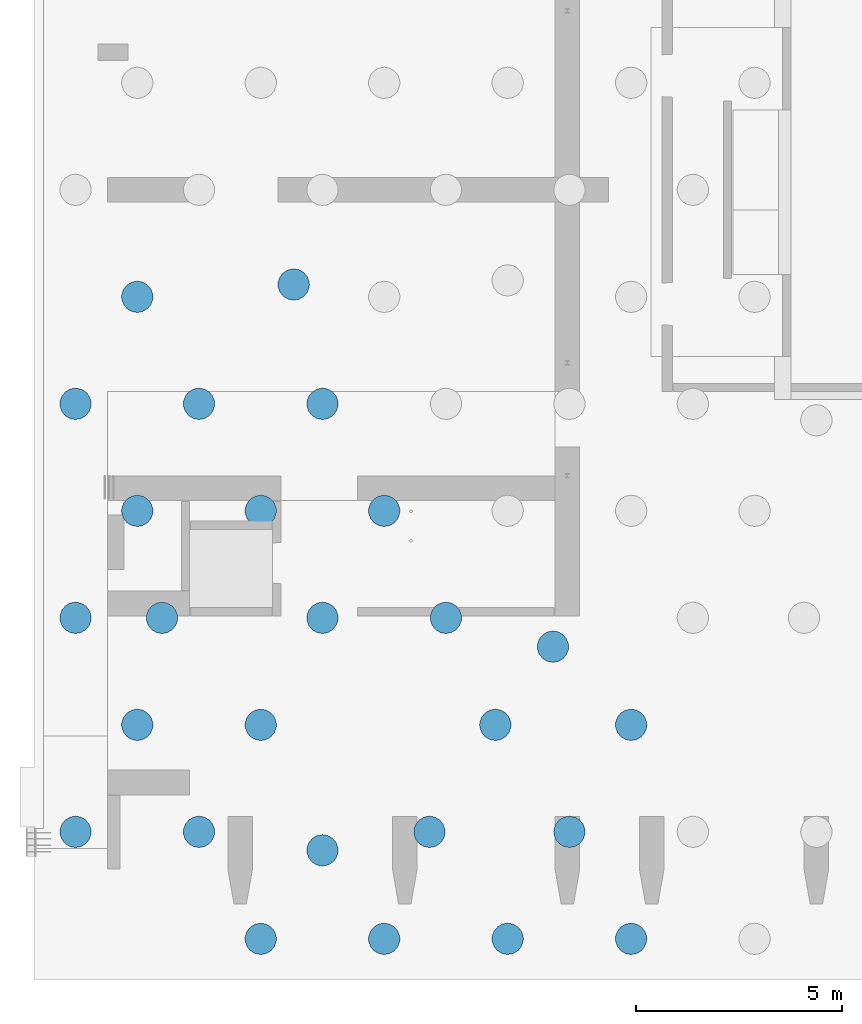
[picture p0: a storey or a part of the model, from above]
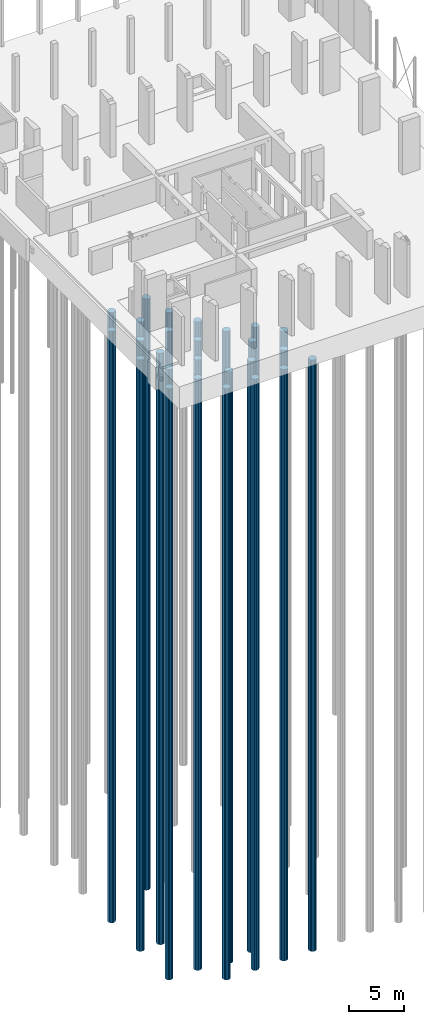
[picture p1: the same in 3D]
Properties of the parts of a building model (IFC2X3), part 1 of 21

# File
Description: ViewDefinition [CoordinationView_V2.0]
Time: 2021-03-30T19:09:52
Written by: The EXPRESS Data Manager Version 5.02.0100.07 : 28 Aug 2013
Made in: 20190510_1515(x64) - Exporter 18.3.3.18 - Alternate UI 18.3.3.18
Comment: STEP Physical File produced by: The EXPRESS Data Manager Version 5.02.0100.07 : 28 Aug 2013 * Module: EDMstepFileFactory/EDMstandAlone * Creation date: Tue Mar 30 19:09:52 2021 * Host: NL5CD93789YK * Database: C:\Users\Kees-D\AppData\Local\Temp\{8EC94533-717D-41E1-8668-EB877A94D281}\ifc * Database version: 5507 * Database creation date: Tue Mar 30 19:07:52 2021 * Schema: IFC2X3 * Model: DataRepository.ifc * Model creation date: Tue Mar 30 19:07:52 2021 * Header model: DataRepository.ifc_HeaderModel * Header model creation date: Tue Mar 30 19:07:52 2021 * EDMuser: sdai-user * EDMgroup: sdai-group * License ID and type: 5605 : Permanent license. Expiry date: * EDMstepFileFactory options: 020000

# IfcProject
LongName: De Zalmhaven Rotterdam; Phase: voorlopig

# IfcSite, Default
RefLatitude: 52, 3, 52, 759094; RefLongitude: 5, 11, 35, 688629; RefElevation: 0 mm

# IfcBuilding, niet gebruiken
LongName: niet gebruiken
Pset_BuildingCommon - NumberOfStoreys: 64

# IfcBuildingStorey (64)
In: niet gebruiken
Name | LongName | Elevation (mm)
00 begane grond | 00 begane grond | 0
00a eerste tussenverdieping | 00a eerste tussenverdieping | 3000
01 eerste verdieping | 01 eerste verdieping | 6000
02 tweede verdieping | 02 tweede verdieping | 9000
03 derde verdieping | 03 derde verdieping | 12000
04 vierde verdieping | 04 vierde verdieping | 15000
05 vijfde verdieping | 05 vijfde verdieping | 18000
06 zesde verdieping | 06 zesde verdieping | 21060
07 zevende verdieping | 07 zevende verdieping | 24120
08 achtste verdieping | 08 achtste verdieping | 27180
09 negende verdieping | 09 negende verdieping | 30240
10 tiende verdieping | 10 tiende verdieping | 33300
11 elfde verdieping | 11 elfde verdieping | 36360
12 twaalfde verdieping | 12 twaalfde verdieping | 39420
13 dertiende verdieping | 13 dertiende verdieping | 42480
14 veertiende verdieping | 14 veertiende verdieping | 45540
15 vijftiende verdieping | 15 vijftiende verdieping | 48600
16 zestiende verdieping | 16 zestiende verdieping | 51660
17 zeventiende verdieping | 17 zeventiende verdieping | 54720
18 achttiende verdieping | 18 achttiende verdieping | 57780
19 negentiende verdieping | 19 negentiende verdieping | 60840
20 twintigste verdieping | 20 twintigste verdieping | 63900
21 eenentwintigste verdieping | 21 eenentwintigste verdieping | 66960
22 tweeëntwintigste verdieping | 22 tweeëntwintigste verdieping | 70020
23 drieëntwintigste verdieping | 23 drieëntwintigste verdieping | 73080
24 vierentwintigste verdieping | 24 vierentwintigste verdieping | 76140
25 vijfentwintigste verdieping | 25 vijfentwintigste verdieping | 79200
26 zesentwintigste verdieping | 26 zesentwintigste verdieping | 82260
27 zevenentwintigste verdieping | 27 zevenentwintigste verdieping | 85320
28 achtentwintigste verdieping | 28 achtentwintigste verdieping | 88380
29 negenentwintigste verdieping | 29 negenentwintigste verdieping | 91440
30 dertigste verdieping | 30 dertigste verdieping | 94500
31 eenendertigste verdieping | 31 eenendertigste verdieping | 97560
32 tweeëndertigste verdieping | 32 tweeëndertigste verdieping | 100620
33 drieëndertigste verdieping | 33 drieëndertigste verdieping | 103680
34 vierendertigste verdieping | 34 vierendertigste verdieping | 106740
35 vijfendertigste verdieping | 35 vijfendertigste verdieping | 109800
36 zesendertigste verdieping | 36 zesendertigste verdieping | 112860
37 zevenendertigste verdieping | 37 zevenendertigste verdieping | 115920
38 achtendertigste verdieping | 38 achtendertigste verdieping | 118980
39 negenendertigste verdieping | 39 negenendertigste verdieping | 122040
40 veertigste verdieping | 40 veertigste verdieping | 125100
41 eenenveertigste verdieping | 41 eenenveertigste verdieping | 128160
42 tweeënveertigste verdieping | 42 tweeënveertigste verdieping | 131220
43 drieënveertigste verdieping | 43 drieënveertigste verdieping | 134280
44 vierenveertigste verdieping | 44 vierenveertigste verdieping | 137340
45 vijfenveertigste verdieping | 45 vijfenveertigste verdieping | 140400
46 zesenveertigste verdieping | 46 zesenveertigste verdieping | 143460
47 zevenenveertigste verdieping | 47 zevenenveertigste verdieping | 146520
48 achtenveertigste verdieping | 48 achtenveertigste verdieping | 149580
49 negenenveertigste verdieping | 49 negenenveertigste verdieping | 152640
50 vijftigste verdieping | 50 vijftigste verdieping | 155700
51 eenenvijftigste verdieping | 51 eenenvijftigste verdieping | 158760
52 tweeënvijftigste verdieping | 52 tweeënvijftigste verdieping | 161820
53 drieënvijftigste verdieping | 53 drieënvijftigste verdieping | 165060
54 vierenvijftigste verdieping | 54 vierenvijftigste verdieping | 168300
55 vijfenvijftigste verdieping | 55 vijfenvijftigste verdieping | 171740
56 zesenvijftigste verdieping | 56 zesenvijftigste verdieping | 175180
57 zevenenvijftigste verdieping | 57 zevenenvijftigste verdieping | 178840
58 achtenvijftigste verdieping | 58 achtenvijftigste verdieping | 183150
59 negenenvijftigste verdieping | 59 negenenvijftigste verdieping | 187640
60 zestigste verdieping | 60 zestigste verdieping | 191440
61 eenenzestigste verdieping | 61 eenenzestigste verdieping | 197055
62 tweeënzestigste verdieping | 62 tweeënzestigste verdieping | 202670

# IfcBeam: 300x370, NLRS_28.11_SF_WPB_prefabbeton balk recht_gen:300x370:4941858
In: 05 vijfde verdieping
Type - ElementType: 300x370; PredefinedType: BEAM; Classification: 28.11 hoofddraagconstructies - kolommen en liggers, kolom-/liggerconstructies (Uniformat); Material: NLRS_f2_beton prefab
Pset_BeamCommon - IsExternal: yes; LoadBearing: yes; Slope: 0 deg; Reference: 300x370; Span: 950 mm

# IfcBeam: 500x500 (2)
In: 00a eerste tussenverdieping
Type - ElementType: 500x500; PredefinedType: BEAM; Classification: 28.11 hoofddraagconstructies - kolommen en liggers, kolom-/liggerconstructies (Uniformat); Material: NLRS_f2_beton ihwg
Pset_BeamCommon - IsExternal: yes; LoadBearing: yes; Reference: 500x500; Slope: 0 deg
Name (NLRS_28.11_SF_WPB_betonbalk ihwg recht_gen:500x500:...) | Span (mm)
4226276 | 6950
4226539 | 7550

# IfcBeam: 500x600 (9)
Type - ElementType: 500x600; PredefinedType: BEAM; Classification: 28.11 hoofddraagconstructies - kolommen en liggers, kolom-/liggerconstructies (Uniformat); Material: NLRS_f2_beton ihwg
Pset_BeamCommon - IsExternal: yes; LoadBearing: yes; Slope: 0 deg; Reference: 500x600
Name (NLRS_28.11_SF_WPB_betonbalk ihwg recht_gen:500x600:...) | In | Span (mm)
4386469 | 01 eerste verdieping | 27400
4386866 | 01 eerste verdieping | 29950
4389192 | 01 eerste verdieping | 24000
4392467 | 01 eerste verdieping | 14500
4417707 | 02 tweede verdieping | 30236
4417842 | 02 tweede verdieping | 30500
4418229 | 02 tweede verdieping | 14500
4448747 | 03 derde verdieping | 30486
4448751 | 03 derde verdieping | 14500

# IfcBeam: NLRS_28.11_SF_WPB_betonbalk ihwg recht_gen:600x420, NLRS_28.11_SF_WPB_betonbalk ihwg recht_gen:600x420:9468926
In: 01 eerste verdieping
Type - PredefinedType: BEAM
Classification: 28.11 hoofddraagconstructies - kolommen en liggers, kolom-/liggerconstructies (Uniformat); Material: NLRS_f2_beton ihwg
Pset_BeamCommon - IsExternal: yes; LoadBearing: yes; Slope: 0 deg; Reference: 600x420; Span: 3750 mm

# IfcBeam: NLRS_28.11_SF_WPB_betonbalk ihwg recht_gen:600x750 (2)
In: 01 eerste verdieping
Type - PredefinedType: BEAM
Classification: 28.11 hoofddraagconstructies - kolommen en liggers, kolom-/liggerconstructies (Uniformat); Material: NLRS_f2_beton ihwg
Pset_BeamCommon - IsExternal: yes; LoadBearing: yes; Slope: 0 deg; Reference: 600x750
Name (NLRS_28.11_SF_WPB_betonbalk ihwg recht_gen:600x750:...) | Span (mm)
4388665 | 8166
6301186 | 4880

# IfcBeam: NLRS_28.11_SF_WPB_oplegnok ihwg beton_gen:200x347.5, NLRS_28.11_SF_WPB_oplegnok ihwg beton_gen:200x347.5:6400414
In: 01 eerste verdieping
Type - PredefinedType: BEAM
Classification: 28.11 hoofddraagconstructies - kolommen en liggers, kolom-/liggerconstructies (Uniformat); Material: NLRS_f2_beton ihwg
Pset_BeamCommon - IsExternal: yes; LoadBearing: yes; Slope: 0 deg; Reference: 200x347.5; Span: 400 mm

# IfcBeam: NLRS_28.11_SF_WPB_oplegnok ihwg beton_gen:250x310 (2)
Type - PredefinedType: BEAM
Classification: 28.11 hoofddraagconstructies - kolommen en liggers, kolom-/liggerconstructies (Uniformat); Material: NLRS_f2_beton ihwg
Pset_BeamCommon - IsExternal: yes; LoadBearing: yes; Slope: 0 deg; Reference: 250x310; Span: 400 mm
Name (NLRS_28.11_SF_WPB_oplegnok ihwg beton_gen:250x310:...) | In
6006708 | 01 eerste verdieping
7215375 | 02 tweede verdieping

# IfcBeam: NLRS_28.11_SF_WPB_oplegnok ihwg beton_gen:350x600, NLRS_28.11_SF_WPB_oplegnok ihwg beton_gen:350x600:7215432
In: 02 tweede verdieping
Type - PredefinedType: BEAM
Classification: 28.11 hoofddraagconstructies - kolommen en liggers, kolom-/liggerconstructies (Uniformat); Material: NLRS_f2_beton ihwg
Pset_BeamCommon - IsExternal: yes; LoadBearing: yes; Slope: 0 deg; Reference: 350x600; Span: 400 mm

# IfcBeam: NLRS_28.11_SF_WPB_oplegnok prefabbeton_gen:200x250 slope (5)
Type - PredefinedType: BEAM
Classification: 28.11 hoofddraagconstructies - kolommen en liggers, kolom-/liggerconstructies (Uniformat); Material: NLRS_f2_beton prefab
Pset_BeamCommon - IsExternal: yes; LoadBearing: yes; Slope: 0 deg; Reference: 200x250 slope
Name (NLRS_28.11_SF_WPB_oplegnok prefabbeton_gen:200x250 slope:...) | In | Span (mm)
6399559 | 01 eerste verdieping | 1860
6400008 | 02 tweede verdieping | 1860
6400059 | 01 eerste verdieping | 2010
6400132 | 02 tweede verdieping | 2010
10888795 | 03 derde verdieping | 1860

# IfcBeam: NLRS_28.11_SF_WPB_oplegnok prefabbeton_gen:300x310 met afschuining 7,6gr (3)
Type - PredefinedType: BEAM
Classification: 28.11 hoofddraagconstructies - kolommen en liggers, kolom-/liggerconstructies (Uniformat); Material: NLRS_f2_beton prefab
Pset_BeamCommon - LoadBearing: yes; IsExternal: no; Slope: 0 deg; Reference: 300x310 met afschuining 7,6gr
Name (NLRS_28.11_SF_WPB_oplegnok prefabbeton_gen:300x310 met afschuining 7,6gr:...) | In | Span (mm)
7300567 | 01 eerste verdieping | 700
7301827 | 02 tweede verdieping | 590
7302072 | 03 derde verdieping | 300

# IfcBeam: NLRS_28.11_SF_WPB_oplegnok prefabbeton_gen:300x480 met afschuining 9gr, NLRS_28.11_SF_WPB_oplegnok prefabbeton_gen:300x480 met afschuining 9gr:7300622
In: 01 eerste verdieping
Type - PredefinedType: BEAM
Classification: 28.11 hoofddraagconstructies - kolommen en liggers, kolom-/liggerconstructies (Uniformat); Material: NLRS_f2_beton prefab
Pset_BeamCommon - LoadBearing: yes; IsExternal: no; Slope: 0 deg; Reference: 300x480 met afschuining 9gr; Span: 575 mm

# IfcBeam: NLRS_28.11_SF_WPB_stalen handje 7 lang 375_gen:NLRS_28.11_SF_WPB_stalen handje 7_gen (760)
Type - PredefinedType: BEAM
Material: NLRS_h2_staal
Pset_BeamCommon - LoadBearing: yes; IsExternal: no; Slope: 0 deg; Reference: NLRS_28.11_SF_WPB_stalen handje 7_gen
Name (NLRS_28.11_SF_WPB_stalen handje 7 lang 375_gen:NLRS_28.11_SF_WPB_stalen handje 7_gen:...) | In | Span (mm) | Group
13999907 | 52 tweeënvijftigste verdieping | 375 | Model Group:NLRS_28.11_SF_handjes balkon 1-2_52e verd_gen:13768620
13999953 | 52 tweeënvijftigste verdieping | 375 | Model Group:NLRS_28.11_SF_handjes balkon 1-2_52e verd_gen:13768620
14005422 | 52 tweeënvijftigste verdieping | 500 | Model Group:NLRS_28.11_SF_handjes balkon 1-2_52e verd_gen:13768620
14005482 | 52 tweeënvijftigste verdieping | 500 | Model Group:NLRS_28.11_SF_handjes balkon 1-2_52e verd_gen:13768620
14005974 | 52 tweeënvijftigste verdieping | 375 | Model Group:NLRS_28.11_SF_handjes balkon 3-4_52e verd_gen:13769752
14005976 | 52 tweeënvijftigste verdieping | 375 | Model Group:NLRS_28.11_SF_handjes balkon 3-4_52e verd_gen:13769752
14005978 | 52 tweeënvijftigste verdieping | 500 | Model Group:NLRS_28.11_SF_handjes balkon 3-4_52e verd_gen:13769752
14005980 | 52 tweeënvijftigste verdieping | 500 | Model Group:NLRS_28.11_SF_handjes balkon 3-4_52e verd_gen:13769752
14006319 | 52 tweeënvijftigste verdieping | 375 | Model Group:NLRS_28.11_SF_handjes balkon 3-4_52e verd_gen:13770119
14006321 | 52 tweeënvijftigste verdieping | 375 | Model Group:NLRS_28.11_SF_handjes balkon 3-4_52e verd_gen:13770119
14006323 | 52 tweeënvijftigste verdieping | 500 | Model Group:NLRS_28.11_SF_handjes balkon 3-4_52e verd_gen:13770119
14006325 | 52 tweeënvijftigste verdieping | 500 | Model Group:NLRS_28.11_SF_handjes balkon 3-4_52e verd_gen:13770119
14006685 | 53 drieënvijftigste verdieping | 500 | Model Group:NLRS_28.11_SF_handjes balkon 1-2_53e verd_gen:13907235
14006687 | 53 drieënvijftigste verdieping | 500 | Model Group:NLRS_28.11_SF_handjes balkon 1-2_53e verd_gen:13907235
14006797 | 53 drieënvijftigste verdieping | 500 | Model Group:NLRS_28.11_SF_handjes balkon 1-2_53e verd_gen:13907244
14006799 | 53 drieënvijftigste verdieping | 500 | Model Group:NLRS_28.11_SF_handjes balkon 1-2_53e verd_gen:13907244
14006859 | 53 drieënvijftigste verdieping | 500 | Model Group:NLRS_28.11_SF_handjes balkon 3-4_53e verd_gen:13907254
14006861 | 53 drieënvijftigste verdieping | 500 | Model Group:NLRS_28.11_SF_handjes balkon 3-4_53e verd_gen:13907254
14007250 | 52 tweeënvijftigste verdieping | 375 | Model Group:NLRS_28.11_SF_handjes balkon 1-2_52e verd_gen:13769974
14007252 | 52 tweeënvijftigste verdieping | 375 | Model Group:NLRS_28.11_SF_handjes balkon 1-2_52e verd_gen:13769974
14007254 | 52 tweeënvijftigste verdieping | 500 | Model Group:NLRS_28.11_SF_handjes balkon 1-2_52e verd_gen:13769974
14007256 | 52 tweeënvijftigste verdieping | 500 | Model Group:NLRS_28.11_SF_handjes balkon 1-2_52e verd_gen:13769974
14008008 | 53 drieënvijftigste verdieping | 500 | Model Group:NLRS_28.11_SF_handjes balkon 3-4_53e verd_gen:13907245
14008010 | 53 drieënvijftigste verdieping | 500 | Model Group:NLRS_28.11_SF_handjes balkon 3-4_53e verd_gen:13907245
14026828 | 20 twintigste verdieping | 500 | Model Group:NLRS_28.11_SF_handjes balkon 3-4_gen:10620918
14026830 | 20 twintigste verdieping | 500 | Model Group:NLRS_28.11_SF_handjes balkon 3-4_gen:10620918
14026832 | 20 twintigste verdieping | 375 | Model Group:NLRS_28.11_SF_handjes balkon 1-2_gen:10620925
14026834 | 20 twintigste verdieping | 375 | Model Group:NLRS_28.11_SF_handjes balkon 1-2_gen:10620925
14026836 | 20 twintigste verdieping | 500 | Model Group:NLRS_28.11_SF_handjes balkon 1-2_gen:10620925
14026838 | 20 twintigste verdieping | 500 | Model Group:NLRS_28.11_SF_handjes balkon 1-2_gen:10620925
14035047 | 16 zestiende verdieping | 500 | Model Group:NLRS_28.11_SF_handjes balkon 3-4_gen:9036916
14035049 | 16 zestiende verdieping | 500 | Model Group:NLRS_28.11_SF_handjes balkon 3-4_gen:9036916
14035052 | 16 zestiende verdieping | 500 | Model Group:NLRS_28.11_SF_handjes balkon 3-4_gen:9036917
14035054 | 16 zestiende verdieping | 500 | Model Group:NLRS_28.11_SF_handjes balkon 3-4_gen:9036917
14035057 | 15 vijftiende verdieping | 500 | Model Group:NLRS_28.11_SF_handjes balkon 3-4_gen:9050834
14035059 | 15 vijftiende verdieping | 500 | Model Group:NLRS_28.11_SF_handjes balkon 3-4_gen:9050834
14035062 | 15 vijftiende verdieping | 500 | Model Group:NLRS_28.11_SF_handjes balkon 3-4_gen:9050835
14035064 | 15 vijftiende verdieping | 500 | Model Group:NLRS_28.11_SF_handjes balkon 3-4_gen:9050835
14035067 | 17 zeventiende verdieping | 500 | Model Group:NLRS_28.11_SF_handjes balkon 3-4_gen:9051130
14035069 | 17 zeventiende verdieping | 500 | Model Group:NLRS_28.11_SF_handjes balkon 3-4_gen:9051130
14035072 | 17 zeventiende verdieping | 500 | Model Group:NLRS_28.11_SF_handjes balkon 3-4_gen:9051131
14035074 | 17 zeventiende verdieping | 500 | Model Group:NLRS_28.11_SF_handjes balkon 3-4_gen:9051131
14035077 | 18 achttiende verdieping | 500 | Model Group:NLRS_28.11_SF_handjes balkon 3-4_gen:9131781
14035079 | 18 achttiende verdieping | 500 | Model Group:NLRS_28.11_SF_handjes balkon 3-4_gen:9131781
14035082 | 18 achttiende verdieping | 500 | Model Group:NLRS_28.11_SF_handjes balkon 3-4_gen:9131782
14035084 | 18 achttiende verdieping | 500 | Model Group:NLRS_28.11_SF_handjes balkon 3-4_gen:9131782
14035087 | 10 tiende verdieping | 500 | Model Group:NLRS_28.11_SF_handjes balkon 3-4_gen:10618299
14035089 | 10 tiende verdieping | 500 | Model Group:NLRS_28.11_SF_handjes balkon 3-4_gen:10618299
14035092 | 10 tiende verdieping | 500 | Model Group:NLRS_28.11_SF_handjes balkon 3-4_gen:10618300
14035094 | 10 tiende verdieping | 500 | Model Group:NLRS_28.11_SF_handjes balkon 3-4_gen:10618300
14035097 | 12 twaalfde verdieping | 500 | Model Group:NLRS_28.11_SF_handjes balkon 3-4_gen:10620653
14035099 | 12 twaalfde verdieping | 500 | Model Group:NLRS_28.11_SF_handjes balkon 3-4_gen:10620653
14035102 | 12 twaalfde verdieping | 500 | Model Group:NLRS_28.11_SF_handjes balkon 3-4_gen:10620654
14035104 | 12 twaalfde verdieping | 500 | Model Group:NLRS_28.11_SF_handjes balkon 3-4_gen:10620654
14035107 | 14 veertiende verdieping | 500 | Model Group:NLRS_28.11_SF_handjes balkon 3-4_gen:10620785
14035109 | 14 veertiende verdieping | 500 | Model Group:NLRS_28.11_SF_handjes balkon 3-4_gen:10620785
14035112 | 14 veertiende verdieping | 500 | Model Group:NLRS_28.11_SF_handjes balkon 3-4_gen:10620786
14035114 | 14 veertiende verdieping | 500 | Model Group:NLRS_28.11_SF_handjes balkon 3-4_gen:10620786
14035117 | 20 twintigste verdieping | 500 | Model Group:NLRS_28.11_SF_handjes balkon 3-4_gen:10620917
14035119 | 20 twintigste verdieping | 500 | Model Group:NLRS_28.11_SF_handjes balkon 3-4_gen:10620917
14035122 | 11 elfde verdieping | 500 | Model Group:NLRS_28.11_SF_handjes balkon 3-4_gen:10622917
14035124 | 11 elfde verdieping | 500 | Model Group:NLRS_28.11_SF_handjes balkon 3-4_gen:10622917
14035127 | 11 elfde verdieping | 500 | Model Group:NLRS_28.11_SF_handjes balkon 3-4_gen:10622918
14035129 | 11 elfde verdieping | 500 | Model Group:NLRS_28.11_SF_handjes balkon 3-4_gen:10622918
14035132 | 13 dertiende verdieping | 500 | Model Group:NLRS_28.11_SF_handjes balkon 3-4_gen:10625084
14035134 | 13 dertiende verdieping | 500 | Model Group:NLRS_28.11_SF_handjes balkon 3-4_gen:10625084
14035137 | 13 dertiende verdieping | 500 | Model Group:NLRS_28.11_SF_handjes balkon 3-4_gen:10625085
14035139 | 13 dertiende verdieping | 500 | Model Group:NLRS_28.11_SF_handjes balkon 3-4_gen:10625085
14035142 | 19 negentiende verdieping | 500 | Model Group:NLRS_28.11_SF_handjes balkon 3-4_gen:10625216
14035144 | 19 negentiende verdieping | 500 | Model Group:NLRS_28.11_SF_handjes balkon 3-4_gen:10625216
14035147 | 19 negentiende verdieping | 500 | Model Group:NLRS_28.11_SF_handjes balkon 3-4_gen:10625217
14035149 | 19 negentiende verdieping | 500 | Model Group:NLRS_28.11_SF_handjes balkon 3-4_gen:10625217
14035839 | 16 zestiende verdieping | 375 | Model Group:NLRS_28.11_SF_handjes balkon 1-2_gen:9036911
14035841 | 16 zestiende verdieping | 375 | Model Group:NLRS_28.11_SF_handjes balkon 1-2_gen:9036911
14035843 | 16 zestiende verdieping | 500 | Model Group:NLRS_28.11_SF_handjes balkon 1-2_gen:9036911
14035845 | 16 zestiende verdieping | 500 | Model Group:NLRS_28.11_SF_handjes balkon 1-2_gen:9036911
14035848 | 16 zestiende verdieping | 375 | Model Group:NLRS_28.11_SF_handjes balkon 1-2_gen:9036924
14035850 | 16 zestiende verdieping | 375 | Model Group:NLRS_28.11_SF_handjes balkon 1-2_gen:9036924
14035852 | 16 zestiende verdieping | 500 | Model Group:NLRS_28.11_SF_handjes balkon 1-2_gen:9036924
14035854 | 16 zestiende verdieping | 500 | Model Group:NLRS_28.11_SF_handjes balkon 1-2_gen:9036924
14035857 | 15 vijftiende verdieping | 375 | Model Group:NLRS_28.11_SF_handjes balkon 1-2_gen:9050829
14035859 | 15 vijftiende verdieping | 375 | Model Group:NLRS_28.11_SF_handjes balkon 1-2_gen:9050829
14035861 | 15 vijftiende verdieping | 500 | Model Group:NLRS_28.11_SF_handjes balkon 1-2_gen:9050829
14035863 | 15 vijftiende verdieping | 500 | Model Group:NLRS_28.11_SF_handjes balkon 1-2_gen:9050829
14035866 | 15 vijftiende verdieping | 375 | Model Group:NLRS_28.11_SF_handjes balkon 1-2_gen:9050842
14035868 | 15 vijftiende verdieping | 375 | Model Group:NLRS_28.11_SF_handjes balkon 1-2_gen:9050842
14035870 | 15 vijftiende verdieping | 500 | Model Group:NLRS_28.11_SF_handjes balkon 1-2_gen:9050842
14035872 | 15 vijftiende verdieping | 500 | Model Group:NLRS_28.11_SF_handjes balkon 1-2_gen:9050842
14035875 | 17 zeventiende verdieping | 375 | Model Group:NLRS_28.11_SF_handjes balkon 1-2_gen:9051125
14035877 | 17 zeventiende verdieping | 375 | Model Group:NLRS_28.11_SF_handjes balkon 1-2_gen:9051125
14035879 | 17 zeventiende verdieping | 500 | Model Group:NLRS_28.11_SF_handjes balkon 1-2_gen:9051125
14035881 | 17 zeventiende verdieping | 500 | Model Group:NLRS_28.11_SF_handjes balkon 1-2_gen:9051125
14035884 | 17 zeventiende verdieping | 375 | Model Group:NLRS_28.11_SF_handjes balkon 1-2_gen:9051138
14035886 | 17 zeventiende verdieping | 375 | Model Group:NLRS_28.11_SF_handjes balkon 1-2_gen:9051138
14035888 | 17 zeventiende verdieping | 500 | Model Group:NLRS_28.11_SF_handjes balkon 1-2_gen:9051138
14035890 | 17 zeventiende verdieping | 500 | Model Group:NLRS_28.11_SF_handjes balkon 1-2_gen:9051138
14035893 | 18 achttiende verdieping | 375 | Model Group:NLRS_28.11_SF_handjes balkon 1-2_gen:9131776
14035895 | 18 achttiende verdieping | 375 | Model Group:NLRS_28.11_SF_handjes balkon 1-2_gen:9131776
14035897 | 18 achttiende verdieping | 500 | Model Group:NLRS_28.11_SF_handjes balkon 1-2_gen:9131776
14035899 | 18 achttiende verdieping | 500 | Model Group:NLRS_28.11_SF_handjes balkon 1-2_gen:9131776
14035902 | 18 achttiende verdieping | 375 | Model Group:NLRS_28.11_SF_handjes balkon 1-2_gen:9131789
14035904 | 18 achttiende verdieping | 375 | Model Group:NLRS_28.11_SF_handjes balkon 1-2_gen:9131789
14035906 | 18 achttiende verdieping | 500 | Model Group:NLRS_28.11_SF_handjes balkon 1-2_gen:9131789
14035908 | 18 achttiende verdieping | 500 | Model Group:NLRS_28.11_SF_handjes balkon 1-2_gen:9131789
14035911 | 10 tiende verdieping | 375 | Model Group:NLRS_28.11_SF_handjes balkon 1-2_gen:10618294
14035913 | 10 tiende verdieping | 375 | Model Group:NLRS_28.11_SF_handjes balkon 1-2_gen:10618294
14035915 | 10 tiende verdieping | 500 | Model Group:NLRS_28.11_SF_handjes balkon 1-2_gen:10618294
14035917 | 10 tiende verdieping | 500 | Model Group:NLRS_28.11_SF_handjes balkon 1-2_gen:10618294
14035920 | 10 tiende verdieping | 375 | Model Group:NLRS_28.11_SF_handjes balkon 1-2_gen:10618307
14035922 | 10 tiende verdieping | 375 | Model Group:NLRS_28.11_SF_handjes balkon 1-2_gen:10618307
14035924 | 10 tiende verdieping | 500 | Model Group:NLRS_28.11_SF_handjes balkon 1-2_gen:10618307
14035926 | 10 tiende verdieping | 500 | Model Group:NLRS_28.11_SF_handjes balkon 1-2_gen:10618307
14035929 | 12 twaalfde verdieping | 375 | Model Group:NLRS_28.11_SF_handjes balkon 1-2_gen:10620648
14035931 | 12 twaalfde verdieping | 375 | Model Group:NLRS_28.11_SF_handjes balkon 1-2_gen:10620648
14035933 | 12 twaalfde verdieping | 500 | Model Group:NLRS_28.11_SF_handjes balkon 1-2_gen:10620648
14035935 | 12 twaalfde verdieping | 500 | Model Group:NLRS_28.11_SF_handjes balkon 1-2_gen:10620648
14035938 | 12 twaalfde verdieping | 375 | Model Group:NLRS_28.11_SF_handjes balkon 1-2_gen:10620661
14035940 | 12 twaalfde verdieping | 375 | Model Group:NLRS_28.11_SF_handjes balkon 1-2_gen:10620661
14035942 | 12 twaalfde verdieping | 500 | Model Group:NLRS_28.11_SF_handjes balkon 1-2_gen:10620661
14035944 | 12 twaalfde verdieping | 500 | Model Group:NLRS_28.11_SF_handjes balkon 1-2_gen:10620661
14035947 | 14 veertiende verdieping | 375 | Model Group:NLRS_28.11_SF_handjes balkon 1-2_gen:10620780
14035949 | 14 veertiende verdieping | 375 | Model Group:NLRS_28.11_SF_handjes balkon 1-2_gen:10620780
14035951 | 14 veertiende verdieping | 500 | Model Group:NLRS_28.11_SF_handjes balkon 1-2_gen:10620780
14035953 | 14 veertiende verdieping | 500 | Model Group:NLRS_28.11_SF_handjes balkon 1-2_gen:10620780
14035956 | 14 veertiende verdieping | 375 | Model Group:NLRS_28.11_SF_handjes balkon 1-2_gen:10620793
14035958 | 14 veertiende verdieping | 375 | Model Group:NLRS_28.11_SF_handjes balkon 1-2_gen:10620793
14035960 | 14 veertiende verdieping | 500 | Model Group:NLRS_28.11_SF_handjes balkon 1-2_gen:10620793
14035962 | 14 veertiende verdieping | 500 | Model Group:NLRS_28.11_SF_handjes balkon 1-2_gen:10620793
14035965 | 20 twintigste verdieping | 375 | Model Group:NLRS_28.11_SF_handjes balkon 1-2_gen:10620912
14035967 | 20 twintigste verdieping | 375 | Model Group:NLRS_28.11_SF_handjes balkon 1-2_gen:10620912
14035969 | 20 twintigste verdieping | 500 | Model Group:NLRS_28.11_SF_handjes balkon 1-2_gen:10620912
14035971 | 20 twintigste verdieping | 500 | Model Group:NLRS_28.11_SF_handjes balkon 1-2_gen:10620912
14035974 | 11 elfde verdieping | 375 | Model Group:NLRS_28.11_SF_handjes balkon 1-2_gen:10622912
14035976 | 11 elfde verdieping | 375 | Model Group:NLRS_28.11_SF_handjes balkon 1-2_gen:10622912
14035978 | 11 elfde verdieping | 500 | Model Group:NLRS_28.11_SF_handjes balkon 1-2_gen:10622912
14035980 | 11 elfde verdieping | 500 | Model Group:NLRS_28.11_SF_handjes balkon 1-2_gen:10622912
14035983 | 11 elfde verdieping | 375 | Model Group:NLRS_28.11_SF_handjes balkon 1-2_gen:10622925
14035985 | 11 elfde verdieping | 375 | Model Group:NLRS_28.11_SF_handjes balkon 1-2_gen:10622925
14035987 | 11 elfde verdieping | 500 | Model Group:NLRS_28.11_SF_handjes balkon 1-2_gen:10622925
14035989 | 11 elfde verdieping | 500 | Model Group:NLRS_28.11_SF_handjes balkon 1-2_gen:10622925
14035992 | 13 dertiende verdieping | 375 | Model Group:NLRS_28.11_SF_handjes balkon 1-2_gen:10625079
14035994 | 13 dertiende verdieping | 375 | Model Group:NLRS_28.11_SF_handjes balkon 1-2_gen:10625079
14035996 | 13 dertiende verdieping | 500 | Model Group:NLRS_28.11_SF_handjes balkon 1-2_gen:10625079
14035998 | 13 dertiende verdieping | 500 | Model Group:NLRS_28.11_SF_handjes balkon 1-2_gen:10625079
14036001 | 13 dertiende verdieping | 375 | Model Group:NLRS_28.11_SF_handjes balkon 1-2_gen:10625092
14036003 | 13 dertiende verdieping | 375 | Model Group:NLRS_28.11_SF_handjes balkon 1-2_gen:10625092
14036005 | 13 dertiende verdieping | 500 | Model Group:NLRS_28.11_SF_handjes balkon 1-2_gen:10625092
14036007 | 13 dertiende verdieping | 500 | Model Group:NLRS_28.11_SF_handjes balkon 1-2_gen:10625092
14036010 | 19 negentiende verdieping | 375 | Model Group:NLRS_28.11_SF_handjes balkon 1-2_gen:10625211
14036012 | 19 negentiende verdieping | 375 | Model Group:NLRS_28.11_SF_handjes balkon 1-2_gen:10625211
14036014 | 19 negentiende verdieping | 500 | Model Group:NLRS_28.11_SF_handjes balkon 1-2_gen:10625211
14036016 | 19 negentiende verdieping | 500 | Model Group:NLRS_28.11_SF_handjes balkon 1-2_gen:10625211
14036019 | 19 negentiende verdieping | 375 | Model Group:NLRS_28.11_SF_handjes balkon 1-2_gen:10625224
14036021 | 19 negentiende verdieping | 375 | Model Group:NLRS_28.11_SF_handjes balkon 1-2_gen:10625224
14036023 | 19 negentiende verdieping | 500 | Model Group:NLRS_28.11_SF_handjes balkon 1-2_gen:10625224
14036025 | 19 negentiende verdieping | 500 | Model Group:NLRS_28.11_SF_handjes balkon 1-2_gen:10625224
14036861 | 21 eenentwintigste verdieping | 375 | Model Group:NLRS_28.11_SF_handjes balkon 1-2_gen:14026841
14036863 | 21 eenentwintigste verdieping | 375 | Model Group:NLRS_28.11_SF_handjes balkon 1-2_gen:14026841
14036865 | 21 eenentwintigste verdieping | 500 | Model Group:NLRS_28.11_SF_handjes balkon 1-2_gen:14026841
14036867 | 21 eenentwintigste verdieping | 500 | Model Group:NLRS_28.11_SF_handjes balkon 1-2_gen:14026841
14036974 | 21 eenentwintigste verdieping | 500 | Model Group:NLRS_28.11_SF_handjes balkon 3-4_gen:14026850
14036976 | 21 eenentwintigste verdieping | 500 | Model Group:NLRS_28.11_SF_handjes balkon 3-4_gen:14026850
14037035 | 21 eenentwintigste verdieping | 375 | Model Group:NLRS_28.11_SF_handjes balkon 1-2_gen:14026859
14037037 | 21 eenentwintigste verdieping | 375 | Model Group:NLRS_28.11_SF_handjes balkon 1-2_gen:14026859
14037039 | 21 eenentwintigste verdieping | 500 | Model Group:NLRS_28.11_SF_handjes balkon 1-2_gen:14026859
14037041 | 21 eenentwintigste verdieping | 500 | Model Group:NLRS_28.11_SF_handjes balkon 1-2_gen:14026859
14037100 | 21 eenentwintigste verdieping | 500 | Model Group:NLRS_28.11_SF_handjes balkon 3-4_gen:14026868
14037102 | 21 eenentwintigste verdieping | 500 | Model Group:NLRS_28.11_SF_handjes balkon 3-4_gen:14026868
14037300 | 40 veertigste verdieping | 500 | Model Group:NLRS_28.11_SF_handjes balkon 3-4_gen:14018324
14037302 | 40 veertigste verdieping | 500 | Model Group:NLRS_28.11_SF_handjes balkon 3-4_gen:14018324
14037317 | 40 veertigste verdieping | 500 | Model Group:NLRS_28.11_SF_handjes balkon 3-4_gen:14018342
14037319 | 40 veertigste verdieping | 500 | Model Group:NLRS_28.11_SF_handjes balkon 3-4_gen:14018342
14037415 | 40 veertigste verdieping | 375 | Model Group:NLRS_28.11_SF_handjes balkon 1-2_gen:14018315
14037417 | 40 veertigste verdieping | 375 | Model Group:NLRS_28.11_SF_handjes balkon 1-2_gen:14018315
14037419 | 40 veertigste verdieping | 500 | Model Group:NLRS_28.11_SF_handjes balkon 1-2_gen:14018315
14037421 | 40 veertigste verdieping | 500 | Model Group:NLRS_28.11_SF_handjes balkon 1-2_gen:14018315
14037432 | 40 veertigste verdieping | 375 | Model Group:NLRS_28.11_SF_handjes balkon 1-2_gen:14018333
14037434 | 40 veertigste verdieping | 375 | Model Group:NLRS_28.11_SF_handjes balkon 1-2_gen:14018333
14037436 | 40 veertigste verdieping | 500 | Model Group:NLRS_28.11_SF_handjes balkon 1-2_gen:14018333
14037438 | 40 veertigste verdieping | 500 | Model Group:NLRS_28.11_SF_handjes balkon 1-2_gen:14018333
14038905 | 22 tweeëntwintigste verdieping | 500 | Model Group:NLRS_28.11_SF_handjes balkon 3-4_gen:14020834
14038907 | 22 tweeëntwintigste verdieping | 500 | Model Group:NLRS_28.11_SF_handjes balkon 3-4_gen:14020834
14038921 | 22 tweeëntwintigste verdieping | 500 | Model Group:NLRS_28.11_SF_handjes balkon 3-4_gen:14020852
14038923 | 22 tweeëntwintigste verdieping | 500 | Model Group:NLRS_28.11_SF_handjes balkon 3-4_gen:14020852
14038933 | 22 tweeëntwintigste verdieping | 375 | Model Group:NLRS_28.11_SF_handjes balkon 1-2_gen:14020825
14038935 | 22 tweeëntwintigste verdieping | 375 | Model Group:NLRS_28.11_SF_handjes balkon 1-2_gen:14020825
14038937 | 22 tweeëntwintigste verdieping | 500 | Model Group:NLRS_28.11_SF_handjes balkon 1-2_gen:14020825
14038939 | 22 tweeëntwintigste verdieping | 500 | Model Group:NLRS_28.11_SF_handjes balkon 1-2_gen:14020825
14038949 | 22 tweeëntwintigste verdieping | 375 | Model Group:NLRS_28.11_SF_handjes balkon 1-2_gen:14020843
14038951 | 22 tweeëntwintigste verdieping | 375 | Model Group:NLRS_28.11_SF_handjes balkon 1-2_gen:14020843
14038953 | 22 tweeëntwintigste verdieping | 500 | Model Group:NLRS_28.11_SF_handjes balkon 1-2_gen:14020843
14038955 | 22 tweeëntwintigste verdieping | 500 | Model Group:NLRS_28.11_SF_handjes balkon 1-2_gen:14020843
14038970 | 24 vierentwintigste verdieping | 500 | Model Group:NLRS_28.11_SF_handjes balkon 3-4_gen:14020903
14038972 | 24 vierentwintigste verdieping | 500 | Model Group:NLRS_28.11_SF_handjes balkon 3-4_gen:14020903
14038986 | 24 vierentwintigste verdieping | 500 | Model Group:NLRS_28.11_SF_handjes balkon 3-4_gen:14020921
14038988 | 24 vierentwintigste verdieping | 500 | Model Group:NLRS_28.11_SF_handjes balkon 3-4_gen:14020921
14038998 | 24 vierentwintigste verdieping | 375 | Model Group:NLRS_28.11_SF_handjes balkon 1-2_gen:14020894
14039000 | 24 vierentwintigste verdieping | 375 | Model Group:NLRS_28.11_SF_handjes balkon 1-2_gen:14020894
14039002 | 24 vierentwintigste verdieping | 500 | Model Group:NLRS_28.11_SF_handjes balkon 1-2_gen:14020894
14039004 | 24 vierentwintigste verdieping | 500 | Model Group:NLRS_28.11_SF_handjes balkon 1-2_gen:14020894
14039014 | 24 vierentwintigste verdieping | 375 | Model Group:NLRS_28.11_SF_handjes balkon 1-2_gen:14020912
14039016 | 24 vierentwintigste verdieping | 375 | Model Group:NLRS_28.11_SF_handjes balkon 1-2_gen:14020912
14039018 | 24 vierentwintigste verdieping | 500 | Model Group:NLRS_28.11_SF_handjes balkon 1-2_gen:14020912
14039020 | 24 vierentwintigste verdieping | 500 | Model Group:NLRS_28.11_SF_handjes balkon 1-2_gen:14020912
14039035 | 25 vijfentwintigste verdieping | 500 | Model Group:NLRS_28.11_SF_handjes balkon 3-4_gen:14020972
14039037 | 25 vijfentwintigste verdieping | 500 | Model Group:NLRS_28.11_SF_handjes balkon 3-4_gen:14020972
14039051 | 25 vijfentwintigste verdieping | 500 | Model Group:NLRS_28.11_SF_handjes balkon 3-4_gen:14020990
14039053 | 25 vijfentwintigste verdieping | 500 | Model Group:NLRS_28.11_SF_handjes balkon 3-4_gen:14020990
14039063 | 25 vijfentwintigste verdieping | 375 | Model Group:NLRS_28.11_SF_handjes balkon 1-2_gen:14020963
14039065 | 25 vijfentwintigste verdieping | 375 | Model Group:NLRS_28.11_SF_handjes balkon 1-2_gen:14020963
14039067 | 25 vijfentwintigste verdieping | 500 | Model Group:NLRS_28.11_SF_handjes balkon 1-2_gen:14020963
14039069 | 25 vijfentwintigste verdieping | 500 | Model Group:NLRS_28.11_SF_handjes balkon 1-2_gen:14020963
14039079 | 25 vijfentwintigste verdieping | 375 | Model Group:NLRS_28.11_SF_handjes balkon 1-2_gen:14020981
14039081 | 25 vijfentwintigste verdieping | 375 | Model Group:NLRS_28.11_SF_handjes balkon 1-2_gen:14020981
14039083 | 25 vijfentwintigste verdieping | 500 | Model Group:NLRS_28.11_SF_handjes balkon 1-2_gen:14020981
14039085 | 25 vijfentwintigste verdieping | 500 | Model Group:NLRS_28.11_SF_handjes balkon 1-2_gen:14020981
14039100 | 26 zesentwintigste verdieping | 500 | Model Group:NLRS_28.11_SF_handjes balkon 3-4_gen:14021041
14039102 | 26 zesentwintigste verdieping | 500 | Model Group:NLRS_28.11_SF_handjes balkon 3-4_gen:14021041
14039116 | 26 zesentwintigste verdieping | 500 | Model Group:NLRS_28.11_SF_handjes balkon 3-4_gen:14021059
14039118 | 26 zesentwintigste verdieping | 500 | Model Group:NLRS_28.11_SF_handjes balkon 3-4_gen:14021059
14039128 | 26 zesentwintigste verdieping | 375 | Model Group:NLRS_28.11_SF_handjes balkon 1-2_gen:14021032
14039130 | 26 zesentwintigste verdieping | 375 | Model Group:NLRS_28.11_SF_handjes balkon 1-2_gen:14021032
14039132 | 26 zesentwintigste verdieping | 500 | Model Group:NLRS_28.11_SF_handjes balkon 1-2_gen:14021032
14039134 | 26 zesentwintigste verdieping | 500 | Model Group:NLRS_28.11_SF_handjes balkon 1-2_gen:14021032
14039144 | 26 zesentwintigste verdieping | 375 | Model Group:NLRS_28.11_SF_handjes balkon 1-2_gen:14021050
14039146 | 26 zesentwintigste verdieping | 375 | Model Group:NLRS_28.11_SF_handjes balkon 1-2_gen:14021050
14039148 | 26 zesentwintigste verdieping | 500 | Model Group:NLRS_28.11_SF_handjes balkon 1-2_gen:14021050
14039150 | 26 zesentwintigste verdieping | 500 | Model Group:NLRS_28.11_SF_handjes balkon 1-2_gen:14021050
14039165 | 30 dertigste verdieping | 500 | Model Group:NLRS_28.11_SF_handjes balkon 3-4_gen:14021110
14039167 | 30 dertigste verdieping | 500 | Model Group:NLRS_28.11_SF_handjes balkon 3-4_gen:14021110
14039181 | 30 dertigste verdieping | 500 | Model Group:NLRS_28.11_SF_handjes balkon 3-4_gen:14021128
14039183 | 30 dertigste verdieping | 500 | Model Group:NLRS_28.11_SF_handjes balkon 3-4_gen:14021128
14039193 | 30 dertigste verdieping | 375 | Model Group:NLRS_28.11_SF_handjes balkon 1-2_gen:14021101
14039195 | 30 dertigste verdieping | 375 | Model Group:NLRS_28.11_SF_handjes balkon 1-2_gen:14021101
14039197 | 30 dertigste verdieping | 500 | Model Group:NLRS_28.11_SF_handjes balkon 1-2_gen:14021101
14039199 | 30 dertigste verdieping | 500 | Model Group:NLRS_28.11_SF_handjes balkon 1-2_gen:14021101
14039209 | 30 dertigste verdieping | 375 | Model Group:NLRS_28.11_SF_handjes balkon 1-2_gen:14021119
14039211 | 30 dertigste verdieping | 375 | Model Group:NLRS_28.11_SF_handjes balkon 1-2_gen:14021119
14039213 | 30 dertigste verdieping | 500 | Model Group:NLRS_28.11_SF_handjes balkon 1-2_gen:14021119
14039215 | 30 dertigste verdieping | 500 | Model Group:NLRS_28.11_SF_handjes balkon 1-2_gen:14021119
14039230 | 23 drieëntwintigste verdieping | 500 | Model Group:NLRS_28.11_SF_handjes balkon 3-4_gen:14021179
14039232 | 23 drieëntwintigste verdieping | 500 | Model Group:NLRS_28.11_SF_handjes balkon 3-4_gen:14021179
14039246 | 23 drieëntwintigste verdieping | 500 | Model Group:NLRS_28.11_SF_handjes balkon 3-4_gen:14021197
14039248 | 23 drieëntwintigste verdieping | 500 | Model Group:NLRS_28.11_SF_handjes balkon 3-4_gen:14021197
14039258 | 23 drieëntwintigste verdieping | 375 | Model Group:NLRS_28.11_SF_handjes balkon 1-2_gen:14021170
14039260 | 23 drieëntwintigste verdieping | 375 | Model Group:NLRS_28.11_SF_handjes balkon 1-2_gen:14021170
14039262 | 23 drieëntwintigste verdieping | 500 | Model Group:NLRS_28.11_SF_handjes balkon 1-2_gen:14021170
14039264 | 23 drieëntwintigste verdieping | 500 | Model Group:NLRS_28.11_SF_handjes balkon 1-2_gen:14021170
14039274 | 23 drieëntwintigste verdieping | 375 | Model Group:NLRS_28.11_SF_handjes balkon 1-2_gen:14021188
14039276 | 23 drieëntwintigste verdieping | 375 | Model Group:NLRS_28.11_SF_handjes balkon 1-2_gen:14021188
14039278 | 23 drieëntwintigste verdieping | 500 | Model Group:NLRS_28.11_SF_handjes balkon 1-2_gen:14021188
14039280 | 23 drieëntwintigste verdieping | 500 | Model Group:NLRS_28.11_SF_handjes balkon 1-2_gen:14021188
14039295 | 28 achtentwintigste verdieping | 500 | Model Group:NLRS_28.11_SF_handjes balkon 3-4_gen:14021248
14039297 | 28 achtentwintigste verdieping | 500 | Model Group:NLRS_28.11_SF_handjes balkon 3-4_gen:14021248
14039311 | 28 achtentwintigste verdieping | 500 | Model Group:NLRS_28.11_SF_handjes balkon 3-4_gen:14021266
14039313 | 28 achtentwintigste verdieping | 500 | Model Group:NLRS_28.11_SF_handjes balkon 3-4_gen:14021266
14039323 | 28 achtentwintigste verdieping | 375 | Model Group:NLRS_28.11_SF_handjes balkon 1-2_gen:14021239
14039325 | 28 achtentwintigste verdieping | 375 | Model Group:NLRS_28.11_SF_handjes balkon 1-2_gen:14021239
14039327 | 28 achtentwintigste verdieping | 500 | Model Group:NLRS_28.11_SF_handjes balkon 1-2_gen:14021239
14039329 | 28 achtentwintigste verdieping | 500 | Model Group:NLRS_28.11_SF_handjes balkon 1-2_gen:14021239
14039339 | 28 achtentwintigste verdieping | 375 | Model Group:NLRS_28.11_SF_handjes balkon 1-2_gen:14021257
14039341 | 28 achtentwintigste verdieping | 375 | Model Group:NLRS_28.11_SF_handjes balkon 1-2_gen:14021257
14039343 | 28 achtentwintigste verdieping | 500 | Model Group:NLRS_28.11_SF_handjes balkon 1-2_gen:14021257
14039345 | 28 achtentwintigste verdieping | 500 | Model Group:NLRS_28.11_SF_handjes balkon 1-2_gen:14021257
14039360 | 29 negenentwintigste verdieping | 500 | Model Group:NLRS_28.11_SF_handjes balkon 3-4_gen:14021317
14039362 | 29 negenentwintigste verdieping | 500 | Model Group:NLRS_28.11_SF_handjes balkon 3-4_gen:14021317
14039376 | 29 negenentwintigste verdieping | 500 | Model Group:NLRS_28.11_SF_handjes balkon 3-4_gen:14021335
14039378 | 29 negenentwintigste verdieping | 500 | Model Group:NLRS_28.11_SF_handjes balkon 3-4_gen:14021335
14039388 | 29 negenentwintigste verdieping | 375 | Model Group:NLRS_28.11_SF_handjes balkon 1-2_gen:14021308
14039390 | 29 negenentwintigste verdieping | 375 | Model Group:NLRS_28.11_SF_handjes balkon 1-2_gen:14021308
14039392 | 29 negenentwintigste verdieping | 500 | Model Group:NLRS_28.11_SF_handjes balkon 1-2_gen:14021308
14039394 | 29 negenentwintigste verdieping | 500 | Model Group:NLRS_28.11_SF_handjes balkon 1-2_gen:14021308
14039404 | 29 negenentwintigste verdieping | 375 | Model Group:NLRS_28.11_SF_handjes balkon 1-2_gen:14021326
14039406 | 29 negenentwintigste verdieping | 375 | Model Group:NLRS_28.11_SF_handjes balkon 1-2_gen:14021326
14039408 | 29 negenentwintigste verdieping | 500 | Model Group:NLRS_28.11_SF_handjes balkon 1-2_gen:14021326
14039410 | 29 negenentwintigste verdieping | 500 | Model Group:NLRS_28.11_SF_handjes balkon 1-2_gen:14021326
14039425 | 33 drieëndertigste verdieping | 500 | Model Group:NLRS_28.11_SF_handjes balkon 3-4_gen:14021386
14039427 | 33 drieëndertigste verdieping | 500 | Model Group:NLRS_28.11_SF_handjes balkon 3-4_gen:14021386
14039441 | 33 drieëndertigste verdieping | 500 | Model Group:NLRS_28.11_SF_handjes balkon 3-4_gen:14021404
14039443 | 33 drieëndertigste verdieping | 500 | Model Group:NLRS_28.11_SF_handjes balkon 3-4_gen:14021404
14039453 | 33 drieëndertigste verdieping | 375 | Model Group:NLRS_28.11_SF_handjes balkon 1-2_gen:14021377
14039455 | 33 drieëndertigste verdieping | 375 | Model Group:NLRS_28.11_SF_handjes balkon 1-2_gen:14021377
14039457 | 33 drieëndertigste verdieping | 500 | Model Group:NLRS_28.11_SF_handjes balkon 1-2_gen:14021377
14039459 | 33 drieëndertigste verdieping | 500 | Model Group:NLRS_28.11_SF_handjes balkon 1-2_gen:14021377
14039469 | 33 drieëndertigste verdieping | 375 | Model Group:NLRS_28.11_SF_handjes balkon 1-2_gen:14021395
14039471 | 33 drieëndertigste verdieping | 375 | Model Group:NLRS_28.11_SF_handjes balkon 1-2_gen:14021395
14039473 | 33 drieëndertigste verdieping | 500 | Model Group:NLRS_28.11_SF_handjes balkon 1-2_gen:14021395
14039475 | 33 drieëndertigste verdieping | 500 | Model Group:NLRS_28.11_SF_handjes balkon 1-2_gen:14021395
14039490 | 31 eenendertigste verdieping | 500 | Model Group:NLRS_28.11_SF_handjes balkon 3-4_gen:14021455
14039492 | 31 eenendertigste verdieping | 500 | Model Group:NLRS_28.11_SF_handjes balkon 3-4_gen:14021455
14039506 | 31 eenendertigste verdieping | 500 | Model Group:NLRS_28.11_SF_handjes balkon 3-4_gen:14021473
14039508 | 31 eenendertigste verdieping | 500 | Model Group:NLRS_28.11_SF_handjes balkon 3-4_gen:14021473
14039518 | 31 eenendertigste verdieping | 375 | Model Group:NLRS_28.11_SF_handjes balkon 1-2_gen:14021446
14039520 | 31 eenendertigste verdieping | 375 | Model Group:NLRS_28.11_SF_handjes balkon 1-2_gen:14021446
14039522 | 31 eenendertigste verdieping | 500 | Model Group:NLRS_28.11_SF_handjes balkon 1-2_gen:14021446
14039524 | 31 eenendertigste verdieping | 500 | Model Group:NLRS_28.11_SF_handjes balkon 1-2_gen:14021446
14039534 | 31 eenendertigste verdieping | 375 | Model Group:NLRS_28.11_SF_handjes balkon 1-2_gen:14021464
14039536 | 31 eenendertigste verdieping | 375 | Model Group:NLRS_28.11_SF_handjes balkon 1-2_gen:14021464
14039538 | 31 eenendertigste verdieping | 500 | Model Group:NLRS_28.11_SF_handjes balkon 1-2_gen:14021464
14039540 | 31 eenendertigste verdieping | 500 | Model Group:NLRS_28.11_SF_handjes balkon 1-2_gen:14021464
14039555 | 32 tweeëndertigste verdieping | 500 | Model Group:NLRS_28.11_SF_handjes balkon 3-4_gen:14021524
14039557 | 32 tweeëndertigste verdieping | 500 | Model Group:NLRS_28.11_SF_handjes balkon 3-4_gen:14021524
14039571 | 32 tweeëndertigste verdieping | 500 | Model Group:NLRS_28.11_SF_handjes balkon 3-4_gen:14021542
14039573 | 32 tweeëndertigste verdieping | 500 | Model Group:NLRS_28.11_SF_handjes balkon 3-4_gen:14021542
14039583 | 32 tweeëndertigste verdieping | 375 | Model Group:NLRS_28.11_SF_handjes balkon 1-2_gen:14021515
14039585 | 32 tweeëndertigste verdieping | 375 | Model Group:NLRS_28.11_SF_handjes balkon 1-2_gen:14021515
14039587 | 32 tweeëndertigste verdieping | 500 | Model Group:NLRS_28.11_SF_handjes balkon 1-2_gen:14021515
14039589 | 32 tweeëndertigste verdieping | 500 | Model Group:NLRS_28.11_SF_handjes balkon 1-2_gen:14021515
14039599 | 32 tweeëndertigste verdieping | 375 | Model Group:NLRS_28.11_SF_handjes balkon 1-2_gen:14021533
14039601 | 32 tweeëndertigste verdieping | 375 | Model Group:NLRS_28.11_SF_handjes balkon 1-2_gen:14021533
14039603 | 32 tweeëndertigste verdieping | 500 | Model Group:NLRS_28.11_SF_handjes balkon 1-2_gen:14021533
14039605 | 32 tweeëndertigste verdieping | 500 | Model Group:NLRS_28.11_SF_handjes balkon 1-2_gen:14021533
14039620 | 34 vierendertigste verdieping | 500 | Model Group:NLRS_28.11_SF_handjes balkon 3-4_gen:14021593
14039622 | 34 vierendertigste verdieping | 500 | Model Group:NLRS_28.11_SF_handjes balkon 3-4_gen:14021593
14039636 | 34 vierendertigste verdieping | 500 | Model Group:NLRS_28.11_SF_handjes balkon 3-4_gen:14021611
14039638 | 34 vierendertigste verdieping | 500 | Model Group:NLRS_28.11_SF_handjes balkon 3-4_gen:14021611
14039648 | 34 vierendertigste verdieping | 375 | Model Group:NLRS_28.11_SF_handjes balkon 1-2_gen:14021584
14039650 | 34 vierendertigste verdieping | 375 | Model Group:NLRS_28.11_SF_handjes balkon 1-2_gen:14021584
14039652 | 34 vierendertigste verdieping | 500 | Model Group:NLRS_28.11_SF_handjes balkon 1-2_gen:14021584
14039654 | 34 vierendertigste verdieping | 500 | Model Group:NLRS_28.11_SF_handjes balkon 1-2_gen:14021584
14039664 | 34 vierendertigste verdieping | 375 | Model Group:NLRS_28.11_SF_handjes balkon 1-2_gen:14021602
14039666 | 34 vierendertigste verdieping | 375 | Model Group:NLRS_28.11_SF_handjes balkon 1-2_gen:14021602
14039668 | 34 vierendertigste verdieping | 500 | Model Group:NLRS_28.11_SF_handjes balkon 1-2_gen:14021602
14039670 | 34 vierendertigste verdieping | 500 | Model Group:NLRS_28.11_SF_handjes balkon 1-2_gen:14021602
14039685 | 35 vijfendertigste verdieping | 500 | Model Group:NLRS_28.11_SF_handjes balkon 3-4_gen:14021662
14039687 | 35 vijfendertigste verdieping | 500 | Model Group:NLRS_28.11_SF_handjes balkon 3-4_gen:14021662
14039701 | 35 vijfendertigste verdieping | 500 | Model Group:NLRS_28.11_SF_handjes balkon 3-4_gen:14021680
14039703 | 35 vijfendertigste verdieping | 500 | Model Group:NLRS_28.11_SF_handjes balkon 3-4_gen:14021680
14039713 | 35 vijfendertigste verdieping | 375 | Model Group:NLRS_28.11_SF_handjes balkon 1-2_gen:14021653
14039715 | 35 vijfendertigste verdieping | 375 | Model Group:NLRS_28.11_SF_handjes balkon 1-2_gen:14021653
14039717 | 35 vijfendertigste verdieping | 500 | Model Group:NLRS_28.11_SF_handjes balkon 1-2_gen:14021653
14039719 | 35 vijfendertigste verdieping | 500 | Model Group:NLRS_28.11_SF_handjes balkon 1-2_gen:14021653
14039729 | 35 vijfendertigste verdieping | 375 | Model Group:NLRS_28.11_SF_handjes balkon 1-2_gen:14021671
14039731 | 35 vijfendertigste verdieping | 375 | Model Group:NLRS_28.11_SF_handjes balkon 1-2_gen:14021671
14039733 | 35 vijfendertigste verdieping | 500 | Model Group:NLRS_28.11_SF_handjes balkon 1-2_gen:14021671
14039735 | 35 vijfendertigste verdieping | 500 | Model Group:NLRS_28.11_SF_handjes balkon 1-2_gen:14021671
14039750 | 27 zevenentwintigste verdieping | 500 | Model Group:NLRS_28.11_SF_handjes balkon 3-4_gen:14021731
14039752 | 27 zevenentwintigste verdieping | 500 | Model Group:NLRS_28.11_SF_handjes balkon 3-4_gen:14021731
14039766 | 27 zevenentwintigste verdieping | 500 | Model Group:NLRS_28.11_SF_handjes balkon 3-4_gen:14021749
14039768 | 27 zevenentwintigste verdieping | 500 | Model Group:NLRS_28.11_SF_handjes balkon 3-4_gen:14021749
14039778 | 27 zevenentwintigste verdieping | 375 | Model Group:NLRS_28.11_SF_handjes balkon 1-2_gen:14021722
14039780 | 27 zevenentwintigste verdieping | 375 | Model Group:NLRS_28.11_SF_handjes balkon 1-2_gen:14021722
14039782 | 27 zevenentwintigste verdieping | 500 | Model Group:NLRS_28.11_SF_handjes balkon 1-2_gen:14021722
14039784 | 27 zevenentwintigste verdieping | 500 | Model Group:NLRS_28.11_SF_handjes balkon 1-2_gen:14021722
14039794 | 27 zevenentwintigste verdieping | 375 | Model Group:NLRS_28.11_SF_handjes balkon 1-2_gen:14021740
14039796 | 27 zevenentwintigste verdieping | 375 | Model Group:NLRS_28.11_SF_handjes balkon 1-2_gen:14021740
14039798 | 27 zevenentwintigste verdieping | 500 | Model Group:NLRS_28.11_SF_handjes balkon 1-2_gen:14021740
14039800 | 27 zevenentwintigste verdieping | 500 | Model Group:NLRS_28.11_SF_handjes balkon 1-2_gen:14021740
14039815 | 38 achtendertigste verdieping | 500 | Model Group:NLRS_28.11_SF_handjes balkon 3-4_gen:14021800
14039817 | 38 achtendertigste verdieping | 500 | Model Group:NLRS_28.11_SF_handjes balkon 3-4_gen:14021800
14039831 | 38 achtendertigste verdieping | 500 | Model Group:NLRS_28.11_SF_handjes balkon 3-4_gen:14021818
14039833 | 38 achtendertigste verdieping | 500 | Model Group:NLRS_28.11_SF_handjes balkon 3-4_gen:14021818
14039843 | 38 achtendertigste verdieping | 375 | Model Group:NLRS_28.11_SF_handjes balkon 1-2_gen:14021791
14039845 | 38 achtendertigste verdieping | 375 | Model Group:NLRS_28.11_SF_handjes balkon 1-2_gen:14021791
14039847 | 38 achtendertigste verdieping | 500 | Model Group:NLRS_28.11_SF_handjes balkon 1-2_gen:14021791
14039849 | 38 achtendertigste verdieping | 500 | Model Group:NLRS_28.11_SF_handjes balkon 1-2_gen:14021791
14039859 | 38 achtendertigste verdieping | 375 | Model Group:NLRS_28.11_SF_handjes balkon 1-2_gen:14021809
14039861 | 38 achtendertigste verdieping | 375 | Model Group:NLRS_28.11_SF_handjes balkon 1-2_gen:14021809
14039863 | 38 achtendertigste verdieping | 500 | Model Group:NLRS_28.11_SF_handjes balkon 1-2_gen:14021809
14039865 | 38 achtendertigste verdieping | 500 | Model Group:NLRS_28.11_SF_handjes balkon 1-2_gen:14021809
14039880 | 39 negenendertigste verdieping | 500 | Model Group:NLRS_28.11_SF_handjes balkon 3-4_gen:14021869
14039882 | 39 negenendertigste verdieping | 500 | Model Group:NLRS_28.11_SF_handjes balkon 3-4_gen:14021869
14039896 | 39 negenendertigste verdieping | 500 | Model Group:NLRS_28.11_SF_handjes balkon 3-4_gen:14021887
14039898 | 39 negenendertigste verdieping | 500 | Model Group:NLRS_28.11_SF_handjes balkon 3-4_gen:14021887
14039908 | 39 negenendertigste verdieping | 375 | Model Group:NLRS_28.11_SF_handjes balkon 1-2_gen:14021860
14039910 | 39 negenendertigste verdieping | 375 | Model Group:NLRS_28.11_SF_handjes balkon 1-2_gen:14021860
14039912 | 39 negenendertigste verdieping | 500 | Model Group:NLRS_28.11_SF_handjes balkon 1-2_gen:14021860
14039914 | 39 negenendertigste verdieping | 500 | Model Group:NLRS_28.11_SF_handjes balkon 1-2_gen:14021860
14039924 | 39 negenendertigste verdieping | 375 | Model Group:NLRS_28.11_SF_handjes balkon 1-2_gen:14021878
14039926 | 39 negenendertigste verdieping | 375 | Model Group:NLRS_28.11_SF_handjes balkon 1-2_gen:14021878
14039928 | 39 negenendertigste verdieping | 500 | Model Group:NLRS_28.11_SF_handjes balkon 1-2_gen:14021878
14039930 | 39 negenendertigste verdieping | 500 | Model Group:NLRS_28.11_SF_handjes balkon 1-2_gen:14021878
14039945 | 36 zesendertigste verdieping | 500 | Model Group:NLRS_28.11_SF_handjes balkon 3-4_gen:14021938
14039947 | 36 zesendertigste verdieping | 500 | Model Group:NLRS_28.11_SF_handjes balkon 3-4_gen:14021938
14039961 | 36 zesendertigste verdieping | 500 | Model Group:NLRS_28.11_SF_handjes balkon 3-4_gen:14021956
14039963 | 36 zesendertigste verdieping | 500 | Model Group:NLRS_28.11_SF_handjes balkon 3-4_gen:14021956
14039973 | 36 zesendertigste verdieping | 375 | Model Group:NLRS_28.11_SF_handjes balkon 1-2_gen:14021929
14039975 | 36 zesendertigste verdieping | 375 | Model Group:NLRS_28.11_SF_handjes balkon 1-2_gen:14021929
14039977 | 36 zesendertigste verdieping | 500 | Model Group:NLRS_28.11_SF_handjes balkon 1-2_gen:14021929
14039979 | 36 zesendertigste verdieping | 500 | Model Group:NLRS_28.11_SF_handjes balkon 1-2_gen:14021929
14039989 | 36 zesendertigste verdieping | 375 | Model Group:NLRS_28.11_SF_handjes balkon 1-2_gen:14021947
14039991 | 36 zesendertigste verdieping | 375 | Model Group:NLRS_28.11_SF_handjes balkon 1-2_gen:14021947
14039993 | 36 zesendertigste verdieping | 500 | Model Group:NLRS_28.11_SF_handjes balkon 1-2_gen:14021947
14039995 | 36 zesendertigste verdieping | 500 | Model Group:NLRS_28.11_SF_handjes balkon 1-2_gen:14021947
14040010 | 37 zevenendertigste verdieping | 500 | Model Group:NLRS_28.11_SF_handjes balkon 3-4_gen:14022007
14040012 | 37 zevenendertigste verdieping | 500 | Model Group:NLRS_28.11_SF_handjes balkon 3-4_gen:14022007
14040026 | 37 zevenendertigste verdieping | 500 | Model Group:NLRS_28.11_SF_handjes balkon 3-4_gen:14022025
14040028 | 37 zevenendertigste verdieping | 500 | Model Group:NLRS_28.11_SF_handjes balkon 3-4_gen:14022025
14040038 | 37 zevenendertigste verdieping | 375 | Model Group:NLRS_28.11_SF_handjes balkon 1-2_gen:14021998
14040040 | 37 zevenendertigste verdieping | 375 | Model Group:NLRS_28.11_SF_handjes balkon 1-2_gen:14021998
14040042 | 37 zevenendertigste verdieping | 500 | Model Group:NLRS_28.11_SF_handjes balkon 1-2_gen:14021998
14040044 | 37 zevenendertigste verdieping | 500 | Model Group:NLRS_28.11_SF_handjes balkon 1-2_gen:14021998
14040054 | 37 zevenendertigste verdieping | 375 | Model Group:NLRS_28.11_SF_handjes balkon 1-2_gen:14022016
14040056 | 37 zevenendertigste verdieping | 375 | Model Group:NLRS_28.11_SF_handjes balkon 1-2_gen:14022016
14040058 | 37 zevenendertigste verdieping | 500 | Model Group:NLRS_28.11_SF_handjes balkon 1-2_gen:14022016
14040060 | 37 zevenendertigste verdieping | 500 | Model Group:NLRS_28.11_SF_handjes balkon 1-2_gen:14022016
14042932 | 41 eenenveertigste verdieping | 500 | Model Group:NLRS_28.11_SF_handjes balkon 3-4_gen:14018046
14042934 | 41 eenenveertigste verdieping | 500 | Model Group:NLRS_28.11_SF_handjes balkon 3-4_gen:14018046
14043005 | 41 eenenveertigste verdieping | 375 | Model Group:NLRS_28.11_SF_handjes balkon 1-2_gen:14018019
14043007 | 41 eenenveertigste verdieping | 375 | Model Group:NLRS_28.11_SF_handjes balkon 1-2_gen:14018019
14043009 | 41 eenenveertigste verdieping | 500 | Model Group:NLRS_28.11_SF_handjes balkon 1-2_gen:14018019
14043011 | 41 eenenveertigste verdieping | 500 | Model Group:NLRS_28.11_SF_handjes balkon 1-2_gen:14018019
14043072 | 41 eenenveertigste verdieping | 500 | Model Group:NLRS_28.11_SF_handjes balkon 3-4_gen:14018028
14043074 | 41 eenenveertigste verdieping | 500 | Model Group:NLRS_28.11_SF_handjes balkon 3-4_gen:14018028
14043131 | 41 eenenveertigste verdieping | 375 | Model Group:NLRS_28.11_SF_handjes balkon 1-2_gen:14018037
14043133 | 41 eenenveertigste verdieping | 375 | Model Group:NLRS_28.11_SF_handjes balkon 1-2_gen:14018037
14043135 | 41 eenenveertigste verdieping | 500 | Model Group:NLRS_28.11_SF_handjes balkon 1-2_gen:14018037
14043137 | 41 eenenveertigste verdieping | 500 | Model Group:NLRS_28.11_SF_handjes balkon 1-2_gen:14018037
14043249 | 51 eenenvijftigste verdieping | 500 | Model Group:NLRS_28.11_SF_handjes balkon 3-4_gen:14013044
14043251 | 51 eenenvijftigste verdieping | 500 | Model Group:NLRS_28.11_SF_handjes balkon 3-4_gen:14013044
14043266 | 51 eenenvijftigste verdieping | 500 | Model Group:NLRS_28.11_SF_handjes balkon 3-4_gen:14013062
14043268 | 51 eenenvijftigste verdieping | 500 | Model Group:NLRS_28.11_SF_handjes balkon 3-4_gen:14013062
14043412 | 51 eenenvijftigste verdieping | 375 | Model Group:NLRS_28.11_SF_handjes balkon 1-2_gen:14013035
14043414 | 51 eenenvijftigste verdieping | 375 | Model Group:NLRS_28.11_SF_handjes balkon 1-2_gen:14013035
14043416 | 51 eenenvijftigste verdieping | 500 | Model Group:NLRS_28.11_SF_handjes balkon 1-2_gen:14013035
14043418 | 51 eenenvijftigste verdieping | 500 | Model Group:NLRS_28.11_SF_handjes balkon 1-2_gen:14013035
14043429 | 51 eenenvijftigste verdieping | 375 | Model Group:NLRS_28.11_SF_handjes balkon 1-2_gen:14013053
14043431 | 51 eenenvijftigste verdieping | 375 | Model Group:NLRS_28.11_SF_handjes balkon 1-2_gen:14013053
14043433 | 51 eenenvijftigste verdieping | 500 | Model Group:NLRS_28.11_SF_handjes balkon 1-2_gen:14013053
14043435 | 51 eenenvijftigste verdieping | 500 | Model Group:NLRS_28.11_SF_handjes balkon 1-2_gen:14013053
14044712 | 42 tweeënveertigste verdieping | 500 | Model Group:NLRS_28.11_SF_handjes balkon 3-4_gen:14014629
14044714 | 42 tweeënveertigste verdieping | 500 | Model Group:NLRS_28.11_SF_handjes balkon 3-4_gen:14014629
14044728 | 42 tweeënveertigste verdieping | 500 | Model Group:NLRS_28.11_SF_handjes balkon 3-4_gen:14014647
14044730 | 42 tweeënveertigste verdieping | 500 | Model Group:NLRS_28.11_SF_handjes balkon 3-4_gen:14014647
14044740 | 42 tweeënveertigste verdieping | 375 | Model Group:NLRS_28.11_SF_handjes balkon 1-2_gen:14014620
14044742 | 42 tweeënveertigste verdieping | 375 | Model Group:NLRS_28.11_SF_handjes balkon 1-2_gen:14014620
14044744 | 42 tweeënveertigste verdieping | 500 | Model Group:NLRS_28.11_SF_handjes balkon 1-2_gen:14014620
14044746 | 42 tweeënveertigste verdieping | 500 | Model Group:NLRS_28.11_SF_handjes balkon 1-2_gen:14014620
14044756 | 42 tweeënveertigste verdieping | 375 | Model Group:NLRS_28.11_SF_handjes balkon 1-2_gen:14014638
14044758 | 42 tweeënveertigste verdieping | 375 | Model Group:NLRS_28.11_SF_handjes balkon 1-2_gen:14014638
14044760 | 42 tweeënveertigste verdieping | 500 | Model Group:NLRS_28.11_SF_handjes balkon 1-2_gen:14014638
14044762 | 42 tweeënveertigste verdieping | 500 | Model Group:NLRS_28.11_SF_handjes balkon 1-2_gen:14014638
14044842 | 47 zevenenveertigste verdieping | 500 | Model Group:NLRS_28.11_SF_handjes balkon 3-4_gen:14014801
14044844 | 47 zevenenveertigste verdieping | 500 | Model Group:NLRS_28.11_SF_handjes balkon 3-4_gen:14014801
14044858 | 47 zevenenveertigste verdieping | 500 | Model Group:NLRS_28.11_SF_handjes balkon 3-4_gen:14014819
14044860 | 47 zevenenveertigste verdieping | 500 | Model Group:NLRS_28.11_SF_handjes balkon 3-4_gen:14014819
14044870 | 47 zevenenveertigste verdieping | 375 | Model Group:NLRS_28.11_SF_handjes balkon 1-2_gen:14014792
14044872 | 47 zevenenveertigste verdieping | 375 | Model Group:NLRS_28.11_SF_handjes balkon 1-2_gen:14014792
14044874 | 47 zevenenveertigste verdieping | 500 | Model Group:NLRS_28.11_SF_handjes balkon 1-2_gen:14014792
14044876 | 47 zevenenveertigste verdieping | 500 | Model Group:NLRS_28.11_SF_handjes balkon 1-2_gen:14014792
14044886 | 47 zevenenveertigste verdieping | 375 | Model Group:NLRS_28.11_SF_handjes balkon 1-2_gen:14014810
14044888 | 47 zevenenveertigste verdieping | 375 | Model Group:NLRS_28.11_SF_handjes balkon 1-2_gen:14014810
14044890 | 47 zevenenveertigste verdieping | 500 | Model Group:NLRS_28.11_SF_handjes balkon 1-2_gen:14014810
14044892 | 47 zevenenveertigste verdieping | 500 | Model Group:NLRS_28.11_SF_handjes balkon 1-2_gen:14014810
14044907 | 50 vijftigste verdieping | 500 | Model Group:NLRS_28.11_SF_handjes balkon 3-4_gen:14014887
14044909 | 50 vijftigste verdieping | 500 | Model Group:NLRS_28.11_SF_handjes balkon 3-4_gen:14014887
14044923 | 50 vijftigste verdieping | 500 | Model Group:NLRS_28.11_SF_handjes balkon 3-4_gen:14014905
14044925 | 50 vijftigste verdieping | 500 | Model Group:NLRS_28.11_SF_handjes balkon 3-4_gen:14014905
14044935 | 50 vijftigste verdieping | 375 | Model Group:NLRS_28.11_SF_handjes balkon 1-2_gen:14014878
14044937 | 50 vijftigste verdieping | 375 | Model Group:NLRS_28.11_SF_handjes balkon 1-2_gen:14014878
14044939 | 50 vijftigste verdieping | 500 | Model Group:NLRS_28.11_SF_handjes balkon 1-2_gen:14014878
14044941 | 50 vijftigste verdieping | 500 | Model Group:NLRS_28.11_SF_handjes balkon 1-2_gen:14014878
14044951 | 50 vijftigste verdieping | 375 | Model Group:NLRS_28.11_SF_handjes balkon 1-2_gen:14014896
14044953 | 50 vijftigste verdieping | 375 | Model Group:NLRS_28.11_SF_handjes balkon 1-2_gen:14014896
14044955 | 50 vijftigste verdieping | 500 | Model Group:NLRS_28.11_SF_handjes balkon 1-2_gen:14014896
14044957 | 50 vijftigste verdieping | 500 | Model Group:NLRS_28.11_SF_handjes balkon 1-2_gen:14014896
14044972 | 43 drieënveertigste verdieping | 500 | Model Group:NLRS_28.11_SF_handjes balkon 3-4_gen:14014973
14044974 | 43 drieënveertigste verdieping | 500 | Model Group:NLRS_28.11_SF_handjes balkon 3-4_gen:14014973
14044988 | 43 drieënveertigste verdieping | 500 | Model Group:NLRS_28.11_SF_handjes balkon 3-4_gen:14014991
14044990 | 43 drieënveertigste verdieping | 500 | Model Group:NLRS_28.11_SF_handjes balkon 3-4_gen:14014991
14045000 | 43 drieënveertigste verdieping | 375 | Model Group:NLRS_28.11_SF_handjes balkon 1-2_gen:14014964
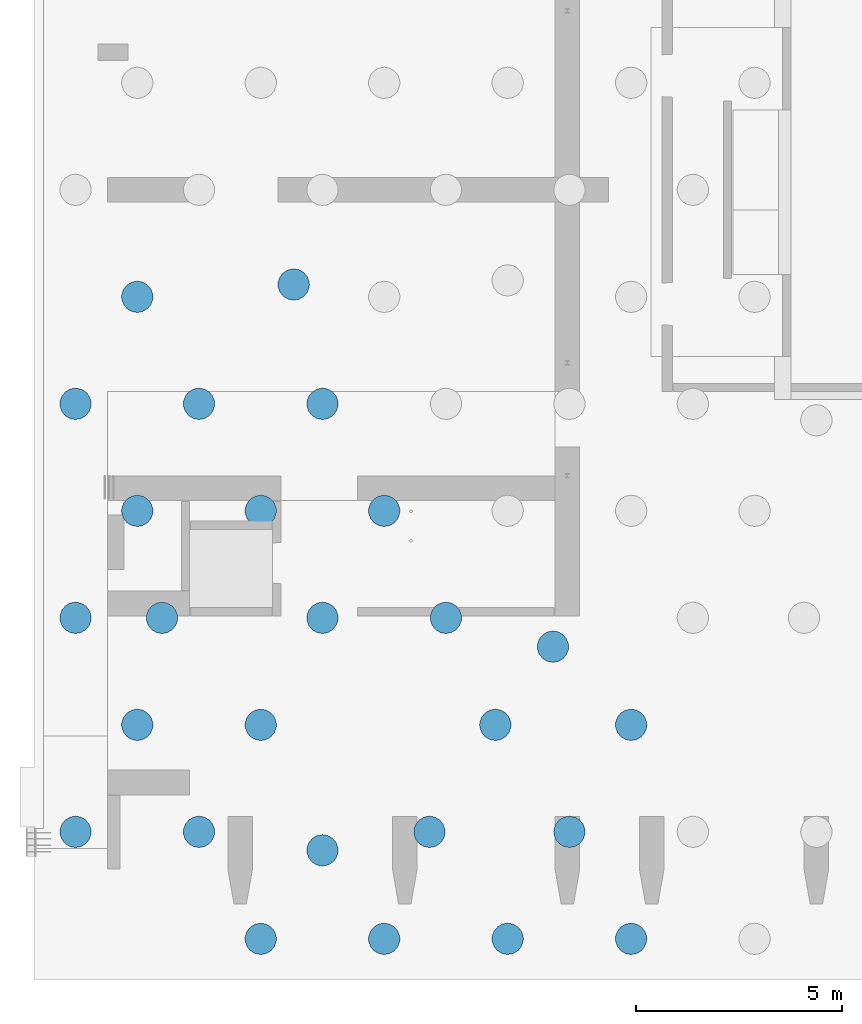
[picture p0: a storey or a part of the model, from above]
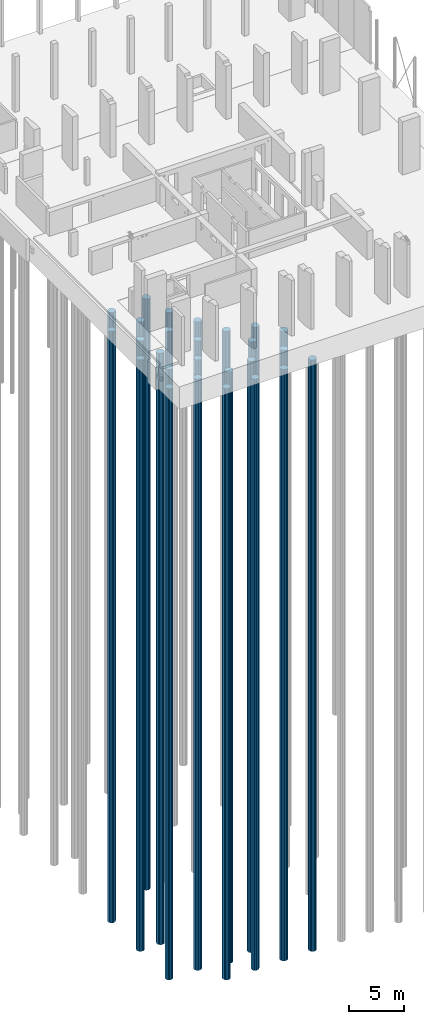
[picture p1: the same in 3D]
Properties of the parts of a building model (IFC2X3), part 2 of 21

# IfcBeam: NLRS_28.11_SF_WPB_stalen handje 7 lang 375_gen:NLRS_28.11_SF_WPB_stalen handje 7_gen (760)
Name (NLRS_28.11_SF_WPB_stalen handje 7 lang 375_gen:NLRS_28.11_SF_WPB_stalen handje 7_gen:...) | In | Span (mm) | Group
14045002 | 43 drieënveertigste verdieping | 375 | Model Group:NLRS_28.11_SF_handjes balkon 1-2_gen:14014964
14045004 | 43 drieënveertigste verdieping | 500 | Model Group:NLRS_28.11_SF_handjes balkon 1-2_gen:14014964
14045006 | 43 drieënveertigste verdieping | 500 | Model Group:NLRS_28.11_SF_handjes balkon 1-2_gen:14014964
14045016 | 43 drieënveertigste verdieping | 375 | Model Group:NLRS_28.11_SF_handjes balkon 1-2_gen:14014982
14045018 | 43 drieënveertigste verdieping | 375 | Model Group:NLRS_28.11_SF_handjes balkon 1-2_gen:14014982
14045020 | 43 drieënveertigste verdieping | 500 | Model Group:NLRS_28.11_SF_handjes balkon 1-2_gen:14014982
14045022 | 43 drieënveertigste verdieping | 500 | Model Group:NLRS_28.11_SF_handjes balkon 1-2_gen:14014982
14045037 | 44 vierenveertigste verdieping | 500 | Model Group:NLRS_28.11_SF_handjes balkon 3-4_gen:14015059
14045039 | 44 vierenveertigste verdieping | 500 | Model Group:NLRS_28.11_SF_handjes balkon 3-4_gen:14015059
14045053 | 44 vierenveertigste verdieping | 500 | Model Group:NLRS_28.11_SF_handjes balkon 3-4_gen:14015077
14045055 | 44 vierenveertigste verdieping | 500 | Model Group:NLRS_28.11_SF_handjes balkon 3-4_gen:14015077
14045065 | 44 vierenveertigste verdieping | 375 | Model Group:NLRS_28.11_SF_handjes balkon 1-2_gen:14015050
14045067 | 44 vierenveertigste verdieping | 375 | Model Group:NLRS_28.11_SF_handjes balkon 1-2_gen:14015050
14045069 | 44 vierenveertigste verdieping | 500 | Model Group:NLRS_28.11_SF_handjes balkon 1-2_gen:14015050
14045071 | 44 vierenveertigste verdieping | 500 | Model Group:NLRS_28.11_SF_handjes balkon 1-2_gen:14015050
14045081 | 44 vierenveertigste verdieping | 375 | Model Group:NLRS_28.11_SF_handjes balkon 1-2_gen:14015068
14045083 | 44 vierenveertigste verdieping | 375 | Model Group:NLRS_28.11_SF_handjes balkon 1-2_gen:14015068
14045085 | 44 vierenveertigste verdieping | 500 | Model Group:NLRS_28.11_SF_handjes balkon 1-2_gen:14015068
14045087 | 44 vierenveertigste verdieping | 500 | Model Group:NLRS_28.11_SF_handjes balkon 1-2_gen:14015068
14045102 | 45 vijfenveertigste verdieping | 500 | Model Group:NLRS_28.11_SF_handjes balkon 3-4_gen:14015145
14045104 | 45 vijfenveertigste verdieping | 500 | Model Group:NLRS_28.11_SF_handjes balkon 3-4_gen:14015145
14045118 | 45 vijfenveertigste verdieping | 500 | Model Group:NLRS_28.11_SF_handjes balkon 3-4_gen:14015163
14045120 | 45 vijfenveertigste verdieping | 500 | Model Group:NLRS_28.11_SF_handjes balkon 3-4_gen:14015163
14045130 | 45 vijfenveertigste verdieping | 375 | Model Group:NLRS_28.11_SF_handjes balkon 1-2_gen:14015136
14045132 | 45 vijfenveertigste verdieping | 375 | Model Group:NLRS_28.11_SF_handjes balkon 1-2_gen:14015136
14045134 | 45 vijfenveertigste verdieping | 500 | Model Group:NLRS_28.11_SF_handjes balkon 1-2_gen:14015136
14045136 | 45 vijfenveertigste verdieping | 500 | Model Group:NLRS_28.11_SF_handjes balkon 1-2_gen:14015136
14045146 | 45 vijfenveertigste verdieping | 375 | Model Group:NLRS_28.11_SF_handjes balkon 1-2_gen:14015154
14045148 | 45 vijfenveertigste verdieping | 375 | Model Group:NLRS_28.11_SF_handjes balkon 1-2_gen:14015154
14045150 | 45 vijfenveertigste verdieping | 500 | Model Group:NLRS_28.11_SF_handjes balkon 1-2_gen:14015154
14045152 | 45 vijfenveertigste verdieping | 500 | Model Group:NLRS_28.11_SF_handjes balkon 1-2_gen:14015154
14045167 | 46 zesenveertigste verdieping | 500 | Model Group:NLRS_28.11_SF_handjes balkon 3-4_gen:14015231
14045169 | 46 zesenveertigste verdieping | 500 | Model Group:NLRS_28.11_SF_handjes balkon 3-4_gen:14015231
14045183 | 46 zesenveertigste verdieping | 500 | Model Group:NLRS_28.11_SF_handjes balkon 3-4_gen:14015249
14045185 | 46 zesenveertigste verdieping | 500 | Model Group:NLRS_28.11_SF_handjes balkon 3-4_gen:14015249
14045195 | 46 zesenveertigste verdieping | 375 | Model Group:NLRS_28.11_SF_handjes balkon 1-2_gen:14015222
14045197 | 46 zesenveertigste verdieping | 375 | Model Group:NLRS_28.11_SF_handjes balkon 1-2_gen:14015222
14045199 | 46 zesenveertigste verdieping | 500 | Model Group:NLRS_28.11_SF_handjes balkon 1-2_gen:14015222
14045201 | 46 zesenveertigste verdieping | 500 | Model Group:NLRS_28.11_SF_handjes balkon 1-2_gen:14015222
14045211 | 46 zesenveertigste verdieping | 375 | Model Group:NLRS_28.11_SF_handjes balkon 1-2_gen:14015240
14045213 | 46 zesenveertigste verdieping | 375 | Model Group:NLRS_28.11_SF_handjes balkon 1-2_gen:14015240
14045215 | 46 zesenveertigste verdieping | 500 | Model Group:NLRS_28.11_SF_handjes balkon 1-2_gen:14015240
14045217 | 46 zesenveertigste verdieping | 500 | Model Group:NLRS_28.11_SF_handjes balkon 1-2_gen:14015240
14045232 | 49 negenenveertigste verdieping | 500 | Model Group:NLRS_28.11_SF_handjes balkon 3-4_gen:14015317
14045234 | 49 negenenveertigste verdieping | 500 | Model Group:NLRS_28.11_SF_handjes balkon 3-4_gen:14015317
14045248 | 49 negenenveertigste verdieping | 500 | Model Group:NLRS_28.11_SF_handjes balkon 3-4_gen:14015335
14045250 | 49 negenenveertigste verdieping | 500 | Model Group:NLRS_28.11_SF_handjes balkon 3-4_gen:14015335
14045260 | 49 negenenveertigste verdieping | 375 | Model Group:NLRS_28.11_SF_handjes balkon 1-2_gen:14015308
14045262 | 49 negenenveertigste verdieping | 375 | Model Group:NLRS_28.11_SF_handjes balkon 1-2_gen:14015308
14045264 | 49 negenenveertigste verdieping | 500 | Model Group:NLRS_28.11_SF_handjes balkon 1-2_gen:14015308
14045266 | 49 negenenveertigste verdieping | 500 | Model Group:NLRS_28.11_SF_handjes balkon 1-2_gen:14015308
14045276 | 49 negenenveertigste verdieping | 375 | Model Group:NLRS_28.11_SF_handjes balkon 1-2_gen:14015326
14045278 | 49 negenenveertigste verdieping | 375 | Model Group:NLRS_28.11_SF_handjes balkon 1-2_gen:14015326
14045280 | 49 negenenveertigste verdieping | 500 | Model Group:NLRS_28.11_SF_handjes balkon 1-2_gen:14015326
14045282 | 49 negenenveertigste verdieping | 500 | Model Group:NLRS_28.11_SF_handjes balkon 1-2_gen:14015326
14045297 | 48 achtenveertigste verdieping | 500 | Model Group:NLRS_28.11_SF_handjes balkon 3-4_gen:14015403
14045299 | 48 achtenveertigste verdieping | 500 | Model Group:NLRS_28.11_SF_handjes balkon 3-4_gen:14015403
14045313 | 48 achtenveertigste verdieping | 500 | Model Group:NLRS_28.11_SF_handjes balkon 3-4_gen:14015421
14045315 | 48 achtenveertigste verdieping | 500 | Model Group:NLRS_28.11_SF_handjes balkon 3-4_gen:14015421
14045325 | 48 achtenveertigste verdieping | 375 | Model Group:NLRS_28.11_SF_handjes balkon 1-2_gen:14015394
14045327 | 48 achtenveertigste verdieping | 375 | Model Group:NLRS_28.11_SF_handjes balkon 1-2_gen:14015394
14045329 | 48 achtenveertigste verdieping | 500 | Model Group:NLRS_28.11_SF_handjes balkon 1-2_gen:14015394
14045331 | 48 achtenveertigste verdieping | 500 | Model Group:NLRS_28.11_SF_handjes balkon 1-2_gen:14015394
14045341 | 48 achtenveertigste verdieping | 375 | Model Group:NLRS_28.11_SF_handjes balkon 1-2_gen:14015412
14045343 | 48 achtenveertigste verdieping | 375 | Model Group:NLRS_28.11_SF_handjes balkon 1-2_gen:14015412
14045345 | 48 achtenveertigste verdieping | 500 | Model Group:NLRS_28.11_SF_handjes balkon 1-2_gen:14015412
14045347 | 48 achtenveertigste verdieping | 500 | Model Group:NLRS_28.11_SF_handjes balkon 1-2_gen:14015412
14048338 | 09 negende verdieping | 500 | Model Group:NLRS_28.11_SF_handjes balkon 3-4_verd 5 tm 9_gen:10637383
14048340 | 09 negende verdieping | 500 | Model Group:NLRS_28.11_SF_handjes balkon 3-4_verd 5 tm 9_gen:10637383
14048643 | 06 zesde verdieping | 500 | Model Group:NLRS_28.11_SF_handjes balkon 3-4_verd 5 tm 9_gen:10634983
14048645 | 06 zesde verdieping | 500 | Model Group:NLRS_28.11_SF_handjes balkon 3-4_verd 5 tm 9_gen:10634983
14048652 | 06 zesde verdieping | 500 | Model Group:NLRS_28.11_SF_handjes balkon 3-4_verd 5 tm 9_gen:10634984
14048654 | 06 zesde verdieping | 500 | Model Group:NLRS_28.11_SF_handjes balkon 3-4_verd 5 tm 9_gen:10634984
14048661 | 07 zevende verdieping | 500 | Model Group:NLRS_28.11_SF_handjes balkon 3-4_verd 5 tm 9_gen:10635968
14048663 | 07 zevende verdieping | 500 | Model Group:NLRS_28.11_SF_handjes balkon 3-4_verd 5 tm 9_gen:10635968
14048670 | 07 zevende verdieping | 500 | Model Group:NLRS_28.11_SF_handjes balkon 3-4_verd 5 tm 9_gen:10635969
14048672 | 07 zevende verdieping | 500 | Model Group:NLRS_28.11_SF_handjes balkon 3-4_verd 5 tm 9_gen:10635969
14048679 | 08 achtste verdieping | 500 | Model Group:NLRS_28.11_SF_handjes balkon 3-4_verd 5 tm 9_gen:10636845
14048681 | 08 achtste verdieping | 500 | Model Group:NLRS_28.11_SF_handjes balkon 3-4_verd 5 tm 9_gen:10636845
14048688 | 08 achtste verdieping | 500 | Model Group:NLRS_28.11_SF_handjes balkon 3-4_verd 5 tm 9_gen:10636846
14048690 | 08 achtste verdieping | 500 | Model Group:NLRS_28.11_SF_handjes balkon 3-4_verd 5 tm 9_gen:10636846
14048697 | 09 negende verdieping | 500 | Model Group:NLRS_28.11_SF_handjes balkon 3-4_verd 5 tm 9_gen:10637382
14048699 | 09 negende verdieping | 500 | Model Group:NLRS_28.11_SF_handjes balkon 3-4_verd 5 tm 9_gen:10637382
14048854 | 09 negende verdieping | 375 | Model Group:NLRS_28.11_SF_handjes balkon 1-2_verd 6 tm 9_gen:10637377
14048856 | 09 negende verdieping | 375 | Model Group:NLRS_28.11_SF_handjes balkon 1-2_verd 6 tm 9_gen:10637377
14048858 | 09 negende verdieping | 500 | Model Group:NLRS_28.11_SF_handjes balkon 1-2_verd 6 tm 9_gen:10637377
14048860 | 09 negende verdieping | 500 | Model Group:NLRS_28.11_SF_handjes balkon 1-2_verd 6 tm 9_gen:10637377
14060521 | 06 zesde verdieping | 375 | Model Group:NLRS_28.11_SF_handjes balkon 1-2_verd 6 tm 9_gen:10634978
14060523 | 06 zesde verdieping | 375 | Model Group:NLRS_28.11_SF_handjes balkon 1-2_verd 6 tm 9_gen:10634978
14060525 | 06 zesde verdieping | 500 | Model Group:NLRS_28.11_SF_handjes balkon 1-2_verd 6 tm 9_gen:10634978
14060527 | 06 zesde verdieping | 500 | Model Group:NLRS_28.11_SF_handjes balkon 1-2_verd 6 tm 9_gen:10634978
14060530 | 06 zesde verdieping | 375 | Model Group:NLRS_28.11_SF_handjes balkon 1-2_verd 6 tm 9_gen:10634991
14060532 | 06 zesde verdieping | 375 | Model Group:NLRS_28.11_SF_handjes balkon 1-2_verd 6 tm 9_gen:10634991
14060534 | 06 zesde verdieping | 500 | Model Group:NLRS_28.11_SF_handjes balkon 1-2_verd 6 tm 9_gen:10634991
14060536 | 06 zesde verdieping | 500 | Model Group:NLRS_28.11_SF_handjes balkon 1-2_verd 6 tm 9_gen:10634991
14060539 | 07 zevende verdieping | 375 | Model Group:NLRS_28.11_SF_handjes balkon 1-2_verd 6 tm 9_gen:10635963
14060541 | 07 zevende verdieping | 375 | Model Group:NLRS_28.11_SF_handjes balkon 1-2_verd 6 tm 9_gen:10635963
14060543 | 07 zevende verdieping | 500 | Model Group:NLRS_28.11_SF_handjes balkon 1-2_verd 6 tm 9_gen:10635963
14060545 | 07 zevende verdieping | 500 | Model Group:NLRS_28.11_SF_handjes balkon 1-2_verd 6 tm 9_gen:10635963
14060548 | 07 zevende verdieping | 375 | Model Group:NLRS_28.11_SF_handjes balkon 1-2_verd 6 tm 9_gen:10635976
14060550 | 07 zevende verdieping | 375 | Model Group:NLRS_28.11_SF_handjes balkon 1-2_verd 6 tm 9_gen:10635976
14060552 | 07 zevende verdieping | 500 | Model Group:NLRS_28.11_SF_handjes balkon 1-2_verd 6 tm 9_gen:10635976
14060554 | 07 zevende verdieping | 500 | Model Group:NLRS_28.11_SF_handjes balkon 1-2_verd 6 tm 9_gen:10635976
14060557 | 08 achtste verdieping | 375 | Model Group:NLRS_28.11_SF_handjes balkon 1-2_verd 6 tm 9_gen:10636840
14060559 | 08 achtste verdieping | 375 | Model Group:NLRS_28.11_SF_handjes balkon 1-2_verd 6 tm 9_gen:10636840
14060561 | 08 achtste verdieping | 500 | Model Group:NLRS_28.11_SF_handjes balkon 1-2_verd 6 tm 9_gen:10636840
14060563 | 08 achtste verdieping | 500 | Model Group:NLRS_28.11_SF_handjes balkon 1-2_verd 6 tm 9_gen:10636840
14060566 | 08 achtste verdieping | 375 | Model Group:NLRS_28.11_SF_handjes balkon 1-2_verd 6 tm 9_gen:10636853
14060568 | 08 achtste verdieping | 375 | Model Group:NLRS_28.11_SF_handjes balkon 1-2_verd 6 tm 9_gen:10636853
14060570 | 08 achtste verdieping | 500 | Model Group:NLRS_28.11_SF_handjes balkon 1-2_verd 6 tm 9_gen:10636853
14060572 | 08 achtste verdieping | 500 | Model Group:NLRS_28.11_SF_handjes balkon 1-2_verd 6 tm 9_gen:10636853
14060575 | 09 negende verdieping | 375 | Model Group:NLRS_28.11_SF_handjes balkon 1-2_verd 6 tm 9_gen:10637390
14060577 | 09 negende verdieping | 375 | Model Group:NLRS_28.11_SF_handjes balkon 1-2_verd 6 tm 9_gen:10637390
14060579 | 09 negende verdieping | 500 | Model Group:NLRS_28.11_SF_handjes balkon 1-2_verd 6 tm 9_gen:10637390
14060581 | 09 negende verdieping | 500 | Model Group:NLRS_28.11_SF_handjes balkon 1-2_verd 6 tm 9_gen:10637390
14060981 | 51 eenenvijftigste verdieping | 375 | Model Group:NLRS_28.11_SF_handjes balkon 3-4_gen:14013062
14060983 | 51 eenenvijftigste verdieping | 375 | Model Group:NLRS_28.11_SF_handjes balkon 3-4_gen:14013062
14061475 | 16 zestiende verdieping | 375 | Model Group:NLRS_28.11_SF_handjes balkon 3-4_gen:9036916
14061477 | 16 zestiende verdieping | 375 | Model Group:NLRS_28.11_SF_handjes balkon 3-4_gen:9036916
14061480 | 16 zestiende verdieping | 375 | Model Group:NLRS_28.11_SF_handjes balkon 3-4_gen:9036917
14061482 | 16 zestiende verdieping | 375 | Model Group:NLRS_28.11_SF_handjes balkon 3-4_gen:9036917
14061485 | 15 vijftiende verdieping | 375 | Model Group:NLRS_28.11_SF_handjes balkon 3-4_gen:9050834
14061487 | 15 vijftiende verdieping | 375 | Model Group:NLRS_28.11_SF_handjes balkon 3-4_gen:9050834
14061490 | 15 vijftiende verdieping | 375 | Model Group:NLRS_28.11_SF_handjes balkon 3-4_gen:9050835
14061492 | 15 vijftiende verdieping | 375 | Model Group:NLRS_28.11_SF_handjes balkon 3-4_gen:9050835
14061495 | 17 zeventiende verdieping | 375 | Model Group:NLRS_28.11_SF_handjes balkon 3-4_gen:9051130
14061497 | 17 zeventiende verdieping | 375 | Model Group:NLRS_28.11_SF_handjes balkon 3-4_gen:9051130
14061500 | 17 zeventiende verdieping | 375 | Model Group:NLRS_28.11_SF_handjes balkon 3-4_gen:9051131
14061502 | 17 zeventiende verdieping | 375 | Model Group:NLRS_28.11_SF_handjes balkon 3-4_gen:9051131
14061505 | 18 achttiende verdieping | 375 | Model Group:NLRS_28.11_SF_handjes balkon 3-4_gen:9131781
14061507 | 18 achttiende verdieping | 375 | Model Group:NLRS_28.11_SF_handjes balkon 3-4_gen:9131781
14061510 | 18 achttiende verdieping | 375 | Model Group:NLRS_28.11_SF_handjes balkon 3-4_gen:9131782
14061512 | 18 achttiende verdieping | 375 | Model Group:NLRS_28.11_SF_handjes balkon 3-4_gen:9131782
14061515 | 10 tiende verdieping | 375 | Model Group:NLRS_28.11_SF_handjes balkon 3-4_gen:10618299
14061517 | 10 tiende verdieping | 375 | Model Group:NLRS_28.11_SF_handjes balkon 3-4_gen:10618299
14061520 | 10 tiende verdieping | 375 | Model Group:NLRS_28.11_SF_handjes balkon 3-4_gen:10618300
14061522 | 10 tiende verdieping | 375 | Model Group:NLRS_28.11_SF_handjes balkon 3-4_gen:10618300
14061525 | 12 twaalfde verdieping | 375 | Model Group:NLRS_28.11_SF_handjes balkon 3-4_gen:10620653
14061527 | 12 twaalfde verdieping | 375 | Model Group:NLRS_28.11_SF_handjes balkon 3-4_gen:10620653
14061530 | 12 twaalfde verdieping | 375 | Model Group:NLRS_28.11_SF_handjes balkon 3-4_gen:10620654
14061532 | 12 twaalfde verdieping | 375 | Model Group:NLRS_28.11_SF_handjes balkon 3-4_gen:10620654
14061535 | 14 veertiende verdieping | 375 | Model Group:NLRS_28.11_SF_handjes balkon 3-4_gen:10620785
14061537 | 14 veertiende verdieping | 375 | Model Group:NLRS_28.11_SF_handjes balkon 3-4_gen:10620785
14061540 | 14 veertiende verdieping | 375 | Model Group:NLRS_28.11_SF_handjes balkon 3-4_gen:10620786
14061542 | 14 veertiende verdieping | 375 | Model Group:NLRS_28.11_SF_handjes balkon 3-4_gen:10620786
14061545 | 20 twintigste verdieping | 375 | Model Group:NLRS_28.11_SF_handjes balkon 3-4_gen:10620917
14061547 | 20 twintigste verdieping | 375 | Model Group:NLRS_28.11_SF_handjes balkon 3-4_gen:10620917
14061550 | 20 twintigste verdieping | 375 | Model Group:NLRS_28.11_SF_handjes balkon 3-4_gen:10620918
14061552 | 20 twintigste verdieping | 375 | Model Group:NLRS_28.11_SF_handjes balkon 3-4_gen:10620918
14061555 | 11 elfde verdieping | 375 | Model Group:NLRS_28.11_SF_handjes balkon 3-4_gen:10622917
14061557 | 11 elfde verdieping | 375 | Model Group:NLRS_28.11_SF_handjes balkon 3-4_gen:10622917
14061560 | 11 elfde verdieping | 375 | Model Group:NLRS_28.11_SF_handjes balkon 3-4_gen:10622918
14061562 | 11 elfde verdieping | 375 | Model Group:NLRS_28.11_SF_handjes balkon 3-4_gen:10622918
14061565 | 13 dertiende verdieping | 375 | Model Group:NLRS_28.11_SF_handjes balkon 3-4_gen:10625084
14061567 | 13 dertiende verdieping | 375 | Model Group:NLRS_28.11_SF_handjes balkon 3-4_gen:10625084
14061570 | 13 dertiende verdieping | 375 | Model Group:NLRS_28.11_SF_handjes balkon 3-4_gen:10625085
14061572 | 13 dertiende verdieping | 375 | Model Group:NLRS_28.11_SF_handjes balkon 3-4_gen:10625085
14061575 | 19 negentiende verdieping | 375 | Model Group:NLRS_28.11_SF_handjes balkon 3-4_gen:10625216
14061577 | 19 negentiende verdieping | 375 | Model Group:NLRS_28.11_SF_handjes balkon 3-4_gen:10625216
14061580 | 19 negentiende verdieping | 375 | Model Group:NLRS_28.11_SF_handjes balkon 3-4_gen:10625217
14061582 | 19 negentiende verdieping | 375 | Model Group:NLRS_28.11_SF_handjes balkon 3-4_gen:10625217
14061585 | 51 eenenvijftigste verdieping | 375 | Model Group:NLRS_28.11_SF_handjes balkon 3-4_gen:14013044
14061587 | 51 eenenvijftigste verdieping | 375 | Model Group:NLRS_28.11_SF_handjes balkon 3-4_gen:14013044
14061590 | 42 tweeënveertigste verdieping | 375 | Model Group:NLRS_28.11_SF_handjes balkon 3-4_gen:14014629
14061592 | 42 tweeënveertigste verdieping | 375 | Model Group:NLRS_28.11_SF_handjes balkon 3-4_gen:14014629
14061595 | 42 tweeënveertigste verdieping | 375 | Model Group:NLRS_28.11_SF_handjes balkon 3-4_gen:14014647
14061597 | 42 tweeënveertigste verdieping | 375 | Model Group:NLRS_28.11_SF_handjes balkon 3-4_gen:14014647
14061610 | 47 zevenenveertigste verdieping | 375 | Model Group:NLRS_28.11_SF_handjes balkon 3-4_gen:14014801
14061612 | 47 zevenenveertigste verdieping | 375 | Model Group:NLRS_28.11_SF_handjes balkon 3-4_gen:14014801
14061615 | 47 zevenenveertigste verdieping | 375 | Model Group:NLRS_28.11_SF_handjes balkon 3-4_gen:14014819
14061617 | 47 zevenenveertigste verdieping | 375 | Model Group:NLRS_28.11_SF_handjes balkon 3-4_gen:14014819
14061620 | 50 vijftigste verdieping | 375 | Model Group:NLRS_28.11_SF_handjes balkon 3-4_gen:14014887
14061622 | 50 vijftigste verdieping | 375 | Model Group:NLRS_28.11_SF_handjes balkon 3-4_gen:14014887
14061625 | 50 vijftigste verdieping | 375 | Model Group:NLRS_28.11_SF_handjes balkon 3-4_gen:14014905
14061627 | 50 vijftigste verdieping | 375 | Model Group:NLRS_28.11_SF_handjes balkon 3-4_gen:14014905
14061630 | 43 drieënveertigste verdieping | 375 | Model Group:NLRS_28.11_SF_handjes balkon 3-4_gen:14014973
14061632 | 43 drieënveertigste verdieping | 375 | Model Group:NLRS_28.11_SF_handjes balkon 3-4_gen:14014973
14061635 | 43 drieënveertigste verdieping | 375 | Model Group:NLRS_28.11_SF_handjes balkon 3-4_gen:14014991
14061637 | 43 drieënveertigste verdieping | 375 | Model Group:NLRS_28.11_SF_handjes balkon 3-4_gen:14014991
14061640 | 44 vierenveertigste verdieping | 375 | Model Group:NLRS_28.11_SF_handjes balkon 3-4_gen:14015059
14061642 | 44 vierenveertigste verdieping | 375 | Model Group:NLRS_28.11_SF_handjes balkon 3-4_gen:14015059
14061645 | 44 vierenveertigste verdieping | 375 | Model Group:NLRS_28.11_SF_handjes balkon 3-4_gen:14015077
14061647 | 44 vierenveertigste verdieping | 375 | Model Group:NLRS_28.11_SF_handjes balkon 3-4_gen:14015077
14061650 | 45 vijfenveertigste verdieping | 375 | Model Group:NLRS_28.11_SF_handjes balkon 3-4_gen:14015145
14061652 | 45 vijfenveertigste verdieping | 375 | Model Group:NLRS_28.11_SF_handjes balkon 3-4_gen:14015145
14061655 | 45 vijfenveertigste verdieping | 375 | Model Group:NLRS_28.11_SF_handjes balkon 3-4_gen:14015163
14061657 | 45 vijfenveertigste verdieping | 375 | Model Group:NLRS_28.11_SF_handjes balkon 3-4_gen:14015163
14061660 | 46 zesenveertigste verdieping | 375 | Model Group:NLRS_28.11_SF_handjes balkon 3-4_gen:14015231
14061662 | 46 zesenveertigste verdieping | 375 | Model Group:NLRS_28.11_SF_handjes balkon 3-4_gen:14015231
14061665 | 46 zesenveertigste verdieping | 375 | Model Group:NLRS_28.11_SF_handjes balkon 3-4_gen:14015249
14061667 | 46 zesenveertigste verdieping | 375 | Model Group:NLRS_28.11_SF_handjes balkon 3-4_gen:14015249
14061670 | 49 negenenveertigste verdieping | 375 | Model Group:NLRS_28.11_SF_handjes balkon 3-4_gen:14015317
14061672 | 49 negenenveertigste verdieping | 375 | Model Group:NLRS_28.11_SF_handjes balkon 3-4_gen:14015317
14061675 | 49 negenenveertigste verdieping | 375 | Model Group:NLRS_28.11_SF_handjes balkon 3-4_gen:14015335
14061677 | 49 negenenveertigste verdieping | 375 | Model Group:NLRS_28.11_SF_handjes balkon 3-4_gen:14015335
14061680 | 48 achtenveertigste verdieping | 375 | Model Group:NLRS_28.11_SF_handjes balkon 3-4_gen:14015403
14061682 | 48 achtenveertigste verdieping | 375 | Model Group:NLRS_28.11_SF_handjes balkon 3-4_gen:14015403
14061685 | 48 achtenveertigste verdieping | 375 | Model Group:NLRS_28.11_SF_handjes balkon 3-4_gen:14015421
14061687 | 48 achtenveertigste verdieping | 375 | Model Group:NLRS_28.11_SF_handjes balkon 3-4_gen:14015421
14061690 | 41 eenenveertigste verdieping | 375 | Model Group:NLRS_28.11_SF_handjes balkon 3-4_gen:14018028
14061692 | 41 eenenveertigste verdieping | 375 | Model Group:NLRS_28.11_SF_handjes balkon 3-4_gen:14018028
14061695 | 41 eenenveertigste verdieping | 375 | Model Group:NLRS_28.11_SF_handjes balkon 3-4_gen:14018046
14061697 | 41 eenenveertigste verdieping | 375 | Model Group:NLRS_28.11_SF_handjes balkon 3-4_gen:14018046
14061700 | 40 veertigste verdieping | 375 | Model Group:NLRS_28.11_SF_handjes balkon 3-4_gen:14018324
14061702 | 40 veertigste verdieping | 375 | Model Group:NLRS_28.11_SF_handjes balkon 3-4_gen:14018324
14061705 | 40 veertigste verdieping | 375 | Model Group:NLRS_28.11_SF_handjes balkon 3-4_gen:14018342
14061707 | 40 veertigste verdieping | 375 | Model Group:NLRS_28.11_SF_handjes balkon 3-4_gen:14018342
14061720 | 22 tweeëntwintigste verdieping | 375 | Model Group:NLRS_28.11_SF_handjes balkon 3-4_gen:14020834
14061722 | 22 tweeëntwintigste verdieping | 375 | Model Group:NLRS_28.11_SF_handjes balkon 3-4_gen:14020834
14061725 | 22 tweeëntwintigste verdieping | 375 | Model Group:NLRS_28.11_SF_handjes balkon 3-4_gen:14020852
14061727 | 22 tweeëntwintigste verdieping | 375 | Model Group:NLRS_28.11_SF_handjes balkon 3-4_gen:14020852
14061730 | 24 vierentwintigste verdieping | 375 | Model Group:NLRS_28.11_SF_handjes balkon 3-4_gen:14020903
14061732 | 24 vierentwintigste verdieping | 375 | Model Group:NLRS_28.11_SF_handjes balkon 3-4_gen:14020903
14061735 | 24 vierentwintigste verdieping | 375 | Model Group:NLRS_28.11_SF_handjes balkon 3-4_gen:14020921
14061737 | 24 vierentwintigste verdieping | 375 | Model Group:NLRS_28.11_SF_handjes balkon 3-4_gen:14020921
14061740 | 25 vijfentwintigste verdieping | 375 | Model Group:NLRS_28.11_SF_handjes balkon 3-4_gen:14020972
14061742 | 25 vijfentwintigste verdieping | 375 | Model Group:NLRS_28.11_SF_handjes balkon 3-4_gen:14020972
14061745 | 25 vijfentwintigste verdieping | 375 | Model Group:NLRS_28.11_SF_handjes balkon 3-4_gen:14020990
14061747 | 25 vijfentwintigste verdieping | 375 | Model Group:NLRS_28.11_SF_handjes balkon 3-4_gen:14020990
14061750 | 26 zesentwintigste verdieping | 375 | Model Group:NLRS_28.11_SF_handjes balkon 3-4_gen:14021041
14061752 | 26 zesentwintigste verdieping | 375 | Model Group:NLRS_28.11_SF_handjes balkon 3-4_gen:14021041
14061755 | 26 zesentwintigste verdieping | 375 | Model Group:NLRS_28.11_SF_handjes balkon 3-4_gen:14021059
14061757 | 26 zesentwintigste verdieping | 375 | Model Group:NLRS_28.11_SF_handjes balkon 3-4_gen:14021059
14061760 | 30 dertigste verdieping | 375 | Model Group:NLRS_28.11_SF_handjes balkon 3-4_gen:14021110
14061762 | 30 dertigste verdieping | 375 | Model Group:NLRS_28.11_SF_handjes balkon 3-4_gen:14021110
14061765 | 30 dertigste verdieping | 375 | Model Group:NLRS_28.11_SF_handjes balkon 3-4_gen:14021128
14061767 | 30 dertigste verdieping | 375 | Model Group:NLRS_28.11_SF_handjes balkon 3-4_gen:14021128
14061770 | 23 drieëntwintigste verdieping | 375 | Model Group:NLRS_28.11_SF_handjes balkon 3-4_gen:14021179
14061772 | 23 drieëntwintigste verdieping | 375 | Model Group:NLRS_28.11_SF_handjes balkon 3-4_gen:14021179
14061775 | 23 drieëntwintigste verdieping | 375 | Model Group:NLRS_28.11_SF_handjes balkon 3-4_gen:14021197
14061777 | 23 drieëntwintigste verdieping | 375 | Model Group:NLRS_28.11_SF_handjes balkon 3-4_gen:14021197
14061780 | 28 achtentwintigste verdieping | 375 | Model Group:NLRS_28.11_SF_handjes balkon 3-4_gen:14021248
14061782 | 28 achtentwintigste verdieping | 375 | Model Group:NLRS_28.11_SF_handjes balkon 3-4_gen:14021248
14061785 | 28 achtentwintigste verdieping | 375 | Model Group:NLRS_28.11_SF_handjes balkon 3-4_gen:14021266
14061787 | 28 achtentwintigste verdieping | 375 | Model Group:NLRS_28.11_SF_handjes balkon 3-4_gen:14021266
14061790 | 29 negenentwintigste verdieping | 375 | Model Group:NLRS_28.11_SF_handjes balkon 3-4_gen:14021317
14061792 | 29 negenentwintigste verdieping | 375 | Model Group:NLRS_28.11_SF_handjes balkon 3-4_gen:14021317
14061795 | 29 negenentwintigste verdieping | 375 | Model Group:NLRS_28.11_SF_handjes balkon 3-4_gen:14021335
14061797 | 29 negenentwintigste verdieping | 375 | Model Group:NLRS_28.11_SF_handjes balkon 3-4_gen:14021335
14061800 | 33 drieëndertigste verdieping | 375 | Model Group:NLRS_28.11_SF_handjes balkon 3-4_gen:14021386
14061802 | 33 drieëndertigste verdieping | 375 | Model Group:NLRS_28.11_SF_handjes balkon 3-4_gen:14021386
14061805 | 33 drieëndertigste verdieping | 375 | Model Group:NLRS_28.11_SF_handjes balkon 3-4_gen:14021404
14061807 | 33 drieëndertigste verdieping | 375 | Model Group:NLRS_28.11_SF_handjes balkon 3-4_gen:14021404
14061810 | 31 eenendertigste verdieping | 375 | Model Group:NLRS_28.11_SF_handjes balkon 3-4_gen:14021455
14061812 | 31 eenendertigste verdieping | 375 | Model Group:NLRS_28.11_SF_handjes balkon 3-4_gen:14021455
14061815 | 31 eenendertigste verdieping | 375 | Model Group:NLRS_28.11_SF_handjes balkon 3-4_gen:14021473
14061817 | 31 eenendertigste verdieping | 375 | Model Group:NLRS_28.11_SF_handjes balkon 3-4_gen:14021473
14061820 | 32 tweeëndertigste verdieping | 375 | Model Group:NLRS_28.11_SF_handjes balkon 3-4_gen:14021524
14061822 | 32 tweeëndertigste verdieping | 375 | Model Group:NLRS_28.11_SF_handjes balkon 3-4_gen:14021524
14061825 | 32 tweeëndertigste verdieping | 375 | Model Group:NLRS_28.11_SF_handjes balkon 3-4_gen:14021542
14061827 | 32 tweeëndertigste verdieping | 375 | Model Group:NLRS_28.11_SF_handjes balkon 3-4_gen:14021542
14061830 | 34 vierendertigste verdieping | 375 | Model Group:NLRS_28.11_SF_handjes balkon 3-4_gen:14021593
14061832 | 34 vierendertigste verdieping | 375 | Model Group:NLRS_28.11_SF_handjes balkon 3-4_gen:14021593
14061835 | 34 vierendertigste verdieping | 375 | Model Group:NLRS_28.11_SF_handjes balkon 3-4_gen:14021611
14061837 | 34 vierendertigste verdieping | 375 | Model Group:NLRS_28.11_SF_handjes balkon 3-4_gen:14021611
14061840 | 35 vijfendertigste verdieping | 375 | Model Group:NLRS_28.11_SF_handjes balkon 3-4_gen:14021662
14061842 | 35 vijfendertigste verdieping | 375 | Model Group:NLRS_28.11_SF_handjes balkon 3-4_gen:14021662
14061845 | 35 vijfendertigste verdieping | 375 | Model Group:NLRS_28.11_SF_handjes balkon 3-4_gen:14021680
14061847 | 35 vijfendertigste verdieping | 375 | Model Group:NLRS_28.11_SF_handjes balkon 3-4_gen:14021680
14061850 | 27 zevenentwintigste verdieping | 375 | Model Group:NLRS_28.11_SF_handjes balkon 3-4_gen:14021731
14061852 | 27 zevenentwintigste verdieping | 375 | Model Group:NLRS_28.11_SF_handjes balkon 3-4_gen:14021731
14061855 | 27 zevenentwintigste verdieping | 375 | Model Group:NLRS_28.11_SF_handjes balkon 3-4_gen:14021749
14061857 | 27 zevenentwintigste verdieping | 375 | Model Group:NLRS_28.11_SF_handjes balkon 3-4_gen:14021749
14061860 | 38 achtendertigste verdieping | 375 | Model Group:NLRS_28.11_SF_handjes balkon 3-4_gen:14021800
14061862 | 38 achtendertigste verdieping | 375 | Model Group:NLRS_28.11_SF_handjes balkon 3-4_gen:14021800
14061865 | 38 achtendertigste verdieping | 375 | Model Group:NLRS_28.11_SF_handjes balkon 3-4_gen:14021818
14061867 | 38 achtendertigste verdieping | 375 | Model Group:NLRS_28.11_SF_handjes balkon 3-4_gen:14021818
14061870 | 39 negenendertigste verdieping | 375 | Model Group:NLRS_28.11_SF_handjes balkon 3-4_gen:14021869
14061872 | 39 negenendertigste verdieping | 375 | Model Group:NLRS_28.11_SF_handjes balkon 3-4_gen:14021869
14061875 | 39 negenendertigste verdieping | 375 | Model Group:NLRS_28.11_SF_handjes balkon 3-4_gen:14021887
14061877 | 39 negenendertigste verdieping | 375 | Model Group:NLRS_28.11_SF_handjes balkon 3-4_gen:14021887
14061880 | 36 zesendertigste verdieping | 375 | Model Group:NLRS_28.11_SF_handjes balkon 3-4_gen:14021938
14061882 | 36 zesendertigste verdieping | 375 | Model Group:NLRS_28.11_SF_handjes balkon 3-4_gen:14021938
14061885 | 36 zesendertigste verdieping | 375 | Model Group:NLRS_28.11_SF_handjes balkon 3-4_gen:14021956
14061887 | 36 zesendertigste verdieping | 375 | Model Group:NLRS_28.11_SF_handjes balkon 3-4_gen:14021956
14061890 | 37 zevenendertigste verdieping | 375 | Model Group:NLRS_28.11_SF_handjes balkon 3-4_gen:14022007
14061892 | 37 zevenendertigste verdieping | 375 | Model Group:NLRS_28.11_SF_handjes balkon 3-4_gen:14022007
14061895 | 37 zevenendertigste verdieping | 375 | Model Group:NLRS_28.11_SF_handjes balkon 3-4_gen:14022025
14061897 | 37 zevenendertigste verdieping | 375 | Model Group:NLRS_28.11_SF_handjes balkon 3-4_gen:14022025
14061900 | 21 eenentwintigste verdieping | 375 | Model Group:NLRS_28.11_SF_handjes balkon 3-4_gen:14026850
14061902 | 21 eenentwintigste verdieping | 375 | Model Group:NLRS_28.11_SF_handjes balkon 3-4_gen:14026850
14061905 | 21 eenentwintigste verdieping | 375 | Model Group:NLRS_28.11_SF_handjes balkon 3-4_gen:14026868
14061907 | 21 eenentwintigste verdieping | 375 | Model Group:NLRS_28.11_SF_handjes balkon 3-4_gen:14026868
14062743 | 09 negende verdieping | 375 | Model Group:NLRS_28.11_SF_handjes balkon 3-4_verd 5 tm 9_gen:10637383
14062745 | 09 negende verdieping | 375 | Model Group:NLRS_28.11_SF_handjes balkon 3-4_verd 5 tm 9_gen:10637383
14062820 | 06 zesde verdieping | 375 | Model Group:NLRS_28.11_SF_handjes balkon 3-4_verd 5 tm 9_gen:10634983
14062822 | 06 zesde verdieping | 375 | Model Group:NLRS_28.11_SF_handjes balkon 3-4_verd 5 tm 9_gen:10634983
14062825 | 06 zesde verdieping | 375 | Model Group:NLRS_28.11_SF_handjes balkon 3-4_verd 5 tm 9_gen:10634984
14062827 | 06 zesde verdieping | 375 | Model Group:NLRS_28.11_SF_handjes balkon 3-4_verd 5 tm 9_gen:10634984
14062830 | 07 zevende verdieping | 375 | Model Group:NLRS_28.11_SF_handjes balkon 3-4_verd 5 tm 9_gen:10635968
14062832 | 07 zevende verdieping | 375 | Model Group:NLRS_28.11_SF_handjes balkon 3-4_verd 5 tm 9_gen:10635968
14062835 | 07 zevende verdieping | 375 | Model Group:NLRS_28.11_SF_handjes balkon 3-4_verd 5 tm 9_gen:10635969
14062837 | 07 zevende verdieping | 375 | Model Group:NLRS_28.11_SF_handjes balkon 3-4_verd 5 tm 9_gen:10635969
14062840 | 08 achtste verdieping | 375 | Model Group:NLRS_28.11_SF_handjes balkon 3-4_verd 5 tm 9_gen:10636845
14062842 | 08 achtste verdieping | 375 | Model Group:NLRS_28.11_SF_handjes balkon 3-4_verd 5 tm 9_gen:10636845
14062845 | 08 achtste verdieping | 375 | Model Group:NLRS_28.11_SF_handjes balkon 3-4_verd 5 tm 9_gen:10636846
14062847 | 08 achtste verdieping | 375 | Model Group:NLRS_28.11_SF_handjes balkon 3-4_verd 5 tm 9_gen:10636846
14062850 | 09 negende verdieping | 375 | Model Group:NLRS_28.11_SF_handjes balkon 3-4_verd 5 tm 9_gen:10637382
14062852 | 09 negende verdieping | 375 | Model Group:NLRS_28.11_SF_handjes balkon 3-4_verd 5 tm 9_gen:10637382

# IfcBeam: NLRS_28.11_SF_WPB_stalen ligger HEA_gen:ligger HEA 120 (68)
Type - PredefinedType: BEAM
Classification: 28.11 hoofddraagconstructies - kolommen en liggers, kolom-/liggerconstructies (Uniformat); Material: NLRS_h2_staal
Pset_BeamCommon - LoadBearing: yes; Slope: 0 deg; Reference: ligger HEA 120
Name (NLRS_28.11_SF_WPB_stalen ligger HEA_gen:ligger HEA 120:...) | In | IsExternal | Span (mm)
4255729 | 00a eerste tussenverdieping | no | 2450
4255738 | 00a eerste tussenverdieping | no | 3150
4255744 | 00a eerste tussenverdieping | no | 3150
10671207 | 01 eerste verdieping | no | 1850
12204515 | 59 negenenvijftigste verdieping | yes | 3305
12204523 | 59 negenenvijftigste verdieping | yes | 3305
12204529 | 59 negenenvijftigste verdieping | yes | 2655
12204531 | 59 negenenvijftigste verdieping | yes | 2655
13509854 | 59 negenenvijftigste verdieping | no | 3305
13510062 | 59 negenenvijftigste verdieping | no | 3330
13510140 | 59 negenenvijftigste verdieping | no | 3330
13510841 | 59 negenenvijftigste verdieping | no | 3305
13510927 | 59 negenenvijftigste verdieping | no | 3330
13511072 | 59 negenenvijftigste verdieping | no | 3330
13511669 | 59 negenenvijftigste verdieping | no | 2780
13511714 | 59 negenenvijftigste verdieping | no | 2780
13511756 | 59 negenenvijftigste verdieping | no | 2655
13512229 | 59 negenenvijftigste verdieping | no | 2655
13512393 | 59 negenenvijftigste verdieping | no | 2780
13512637 | 59 negenenvijftigste verdieping | no | 2780
13513905 | 61 eenenzestigste verdieping | yes | 3305
13513907 | 61 eenenzestigste verdieping | yes | 3305
13513909 | 61 eenenzestigste verdieping | yes | 2655
13513911 | 61 eenenzestigste verdieping | yes | 2655
13513913 | 61 eenenzestigste verdieping | no | 3305
13513915 | 61 eenenzestigste verdieping | no | 3330
13513917 | 61 eenenzestigste verdieping | no | 3330
13513919 | 61 eenenzestigste verdieping | no | 3305
13513921 | 61 eenenzestigste verdieping | no | 3330
13513923 | 61 eenenzestigste verdieping | no | 3330
13513925 | 61 eenenzestigste verdieping | no | 2780
13513927 | 61 eenenzestigste verdieping | no | 2780
13513929 | 61 eenenzestigste verdieping | no | 2655
13513931 | 61 eenenzestigste verdieping | no | 2655
13513933 | 61 eenenzestigste verdieping | no | 2780
13513935 | 61 eenenzestigste verdieping | no | 2780
13724489 | 60 zestigste verdieping | yes | 2655
13724491 | 60 zestigste verdieping | no | 2780
13724493 | 60 zestigste verdieping | no | 2780
13724495 | 60 zestigste verdieping | no | 2655
13724950 | 61 eenenzestigste verdieping | yes | 2655
13724952 | 61 eenenzestigste verdieping | no | 2780
13724954 | 61 eenenzestigste verdieping | no | 2780
13724956 | 61 eenenzestigste verdieping | no | 2655
13725619 | 60 zestigste verdieping | yes | 2655
13725621 | 60 zestigste verdieping | no | 2655
13725623 | 60 zestigste verdieping | no | 2780
13725625 | 60 zestigste verdieping | no | 2780
13725662 | 61 eenenzestigste verdieping | yes | 2655
13725664 | 61 eenenzestigste verdieping | no | 2655
13725666 | 61 eenenzestigste verdieping | no | 2780
13725668 | 61 eenenzestigste verdieping | no | 2780
13726772 | 60 zestigste verdieping | yes | 3305
13726774 | 60 zestigste verdieping | no | 3305
13726776 | 60 zestigste verdieping | no | 3330
13726778 | 60 zestigste verdieping | no | 3330
13726806 | 61 eenenzestigste verdieping | yes | 3305
13726808 | 61 eenenzestigste verdieping | no | 3305
13726810 | 61 eenenzestigste verdieping | no | 3330
13726812 | 61 eenenzestigste verdieping | no | 3330
13727463 | 60 zestigste verdieping | yes | 3305
13727465 | 60 zestigste verdieping | no | 3305
13727467 | 60 zestigste verdieping | no | 3330
13727469 | 60 zestigste verdieping | no | 3330
13727500 | 61 eenenzestigste verdieping | yes | 3305
13727502 | 61 eenenzestigste verdieping | no | 3305
13727504 | 61 eenenzestigste verdieping | no | 3330
13727506 | 61 eenenzestigste verdieping | no | 3330

# IfcBeam: NLRS_28.11_SF_WPB_stalen ligger HEA_gen:ligger HEA 140 (142)
Type - PredefinedType: BEAM
Classification: 28.11 hoofddraagconstructies - kolommen en liggers, kolom-/liggerconstructies (Uniformat); Material: NLRS_h2_staal
Pset_BeamCommon - LoadBearing: yes; Slope: 0 deg; Reference: ligger HEA 140
Name (NLRS_28.11_SF_WPB_stalen ligger HEA_gen:ligger HEA 140:...) | In | IsExternal | Span (mm)
5305859 | 60 zestigste verdieping | yes | 3265
10299076 | 60 zestigste verdieping | no | 3250
10299123 | 60 zestigste verdieping | no | 3250
10299310 | 61 eenenzestigste verdieping | yes | 3295
10299320 | 61 eenenzestigste verdieping | no | 3295
10299322 | 61 eenenzestigste verdieping | no | 3250
10299324 | 61 eenenzestigste verdieping | no | 3250
10384449 | 60 zestigste verdieping | yes | 3295
10667970 | 60 zestigste verdieping | yes | 4250
10667972 | 60 zestigste verdieping | yes | 4250
10668045 | 60 zestigste verdieping | no | 3780
10668262 | 60 zestigste verdieping | no | 3850
11834179 | 05 vijfde verdieping | yes | 1590
11834747 | 05 vijfde verdieping | yes | 1590
11834804 | 05 vijfde verdieping | yes | 1090
11837994 | 05 vijfde verdieping | yes | 1610
11840496 | 05 vijfde verdieping | yes | 1610
11840549 | 05 vijfde verdieping | yes | 1610 | Group: Model Group:BS_Gevel H.7:12243648
11840602 | 05 vijfde verdieping | yes | 1610
12209405 | 05 vijfde verdieping | yes | 1590
12209409 | 05 vijfde verdieping | yes | 1590
12209915 | 05 vijfde verdieping | yes | 1590
12209919 | 05 vijfde verdieping | yes | 1590
12210036 | 05 vijfde verdieping | yes | 1590
12210040 | 05 vijfde verdieping | yes | 1590
12210137 | 05 vijfde verdieping | yes | 1590
12210141 | 05 vijfde verdieping | yes | 1590
12213675 | 05 vijfde verdieping | yes | 1590
12216146 | 05 vijfde verdieping | yes | 1090
12216422 | 05 vijfde verdieping | yes | 1620
12228999 | 05 vijfde verdieping | yes | 1610
12229370 | 05 vijfde verdieping | yes | 1610
12239088 | 05 vijfde verdieping | yes | 1610
12239619 | 05 vijfde verdieping | yes | 1610
12240141 | 05 vijfde verdieping | yes | 1610
12240698 | 05 vijfde verdieping | yes | 1620
12243706 | 05 vijfde verdieping | yes | 1610 | Group: Model Group:BS_Gevel H.1 3400:12244471
12244541 | 05 vijfde verdieping | yes | 1610 | Group: Model Group:BS_Gevel H.1 3400:12244545
12244634 | 05 vijfde verdieping | yes | 1610 | Group: Model Group:BS_Gevel H.1 3400:12244638
12244729 | 05 vijfde verdieping | yes | 1610 | Group: Model Group:BS_Gevel H.1 3400:12244733
12244847 | 05 vijfde verdieping | yes | 1610 | Group: Model Group:BS_Gevel H.1 3350:12245213
12245290 | 05 vijfde verdieping | yes | 1610 | Group: Model Group:BS_Gevel H.1 3350-a:13572764
12245393 | 05 vijfde verdieping | yes | 1610
12249211 | 05 vijfde verdieping | yes | 1280
12249525 | 05 vijfde verdieping | yes | 1620
12249794 | 05 vijfde verdieping | yes | 1610
12392741 | 05 vijfde verdieping | yes | 300
12392937 | 05 vijfde verdieping | yes | 300
12393096 | 05 vijfde verdieping | yes | 300
12393226 | 05 vijfde verdieping | yes | 300
12393239 | 05 vijfde verdieping | yes | 300
12393385 | 05 vijfde verdieping | yes | 300
12393516 | 05 vijfde verdieping | yes | 300
12393639 | 05 vijfde verdieping | yes | 300
12393768 | 05 vijfde verdieping | yes | 300
12393781 | 05 vijfde verdieping | yes | 300
12463266 | 60 zestigste verdieping | yes | 3295
12463271 | 60 zestigste verdieping | yes | 1370
12463281 | 60 zestigste verdieping | yes | 3250
12463283 | 60 zestigste verdieping | yes | 1370
12463348 | 60 zestigste verdieping | yes | 3295
12463352 | 60 zestigste verdieping | yes | 1740
12463364 | 60 zestigste verdieping | yes | 2780
12463394 | 60 zestigste verdieping | yes | 3250
12463398 | 60 zestigste verdieping | yes | 1370
12463426 | 60 zestigste verdieping | yes | 3295
12463428 | 60 zestigste verdieping | yes | 1590
12463444 | 60 zestigste verdieping | yes | 2780
12463446 | 60 zestigste verdieping | yes | 3265
12463487 | 60 zestigste verdieping | yes | 3295
12463489 | 60 zestigste verdieping | yes | 1675
12463491 | 60 zestigste verdieping | yes | 1350
12463501 | 60 zestigste verdieping | yes | 3300
12463503 | 60 zestigste verdieping | yes | 1370
12463505 | 60 zestigste verdieping | yes | 3250
12463507 | 60 zestigste verdieping | yes | 695
12463509 | 60 zestigste verdieping | yes | 3250
12464493 | 61 eenenzestigste verdieping | yes | 3295
12464495 | 61 eenenzestigste verdieping | yes | 1675
12464497 | 61 eenenzestigste verdieping | yes | 3295
12464499 | 61 eenenzestigste verdieping | yes | 1675
12464759 | 61 eenenzestigste verdieping | yes | 3250
12464816 | 61 eenenzestigste verdieping | yes | 1500
12464855 | 61 eenenzestigste verdieping | yes | 1550
12464897 | 61 eenenzestigste verdieping | yes | 1550
12465389 | 61 eenenzestigste verdieping | yes | 3250
12466203 | 61 eenenzestigste verdieping | yes | 3295
12466347 | 61 eenenzestigste verdieping | yes | 3295
12466608 | 61 eenenzestigste verdieping | yes | 1550
12466610 | 61 eenenzestigste verdieping | yes | 1550
12466612 | 61 eenenzestigste verdieping | yes | 3295.03
12466614 | 61 eenenzestigste verdieping | yes | 3295.03
12466702 | 61 eenenzestigste verdieping | yes | 3250
12466704 | 61 eenenzestigste verdieping | yes | 1500
12466706 | 61 eenenzestigste verdieping | yes | 3250
13388074 | 60 zestigste verdieping | yes | 1420
13389001 | 60 zestigste verdieping | yes | 1420
13438186 | 61 eenenzestigste verdieping | yes | 3250
13438195 | 61 eenenzestigste verdieping | yes | 640
13438202 | 61 eenenzestigste verdieping | yes | 640
13438209 | 61 eenenzestigste verdieping | yes | 640
13438267 | 60 zestigste verdieping | yes | 1740
13438418 | 60 zestigste verdieping | yes | 980
13438921 | 60 zestigste verdieping | yes | 830
13439003 | 60 zestigste verdieping | yes | 745
13439327 | 60 zestigste verdieping | yes | 855
13439727 | 60 zestigste verdieping | yes | 830
13439894 | 60 zestigste verdieping | yes | 1735
13440170 | 60 zestigste verdieping | yes | 850
13440434 | 60 zestigste verdieping | yes | 850
13440506 | 60 zestigste verdieping | yes | 560
13440714 | 60 zestigste verdieping | yes | 580
13441214 | 62 tweeënzestigste verdieping | yes | 1300
13441417 | 62 tweeënzestigste verdieping | yes | 760
13441815 | 62 tweeënzestigste verdieping | yes | 760
13515879 | 62 tweeënzestigste verdieping | yes | 1300
13516322 | 61 eenenzestigste verdieping | yes | 3250
13516398 | 61 eenenzestigste verdieping | yes | 1000
13516770 | 61 eenenzestigste verdieping | yes | 3250
13517085 | 61 eenenzestigste verdieping | yes | 1220
13517447 | 60 zestigste verdieping | no | 3250
13517523 | 60 zestigste verdieping | yes | 900
13517799 | 60 zestigste verdieping | yes | 3250
13517877 | 60 zestigste verdieping | yes | 1000
13673240 | 05 vijfde verdieping | yes | 700
13673593 | 05 vijfde verdieping | yes | 700
13677672 | 05 vijfde verdieping | yes | 1090
13713388 | 05 vijfde verdieping | yes | 300
13785763 | 62 tweeënzestigste verdieping | yes | 1540
13785887 | 62 tweeënzestigste verdieping | yes | 1540
13788296 | 62 tweeënzestigste verdieping | yes | 1300
13789461 | 62 tweeënzestigste verdieping | yes | 800
13789525 | 62 tweeënzestigste verdieping | yes | 800
13789967 | 62 tweeënzestigste verdieping | yes | 1300
13790220 | 61 eenenzestigste verdieping | yes | 650
13790222 | 61 eenenzestigste verdieping | yes | 650
13794379 | 61 eenenzestigste verdieping | yes | 3250
13794548 | 61 eenenzestigste verdieping | yes | 1000
13794623 | 61 eenenzestigste verdieping | yes | 1000
14218685 | 60 zestigste verdieping | yes | 1135
14218717 | 60 zestigste verdieping | yes | 1135
14218867 | 60 zestigste verdieping | yes | 750

# IfcBeam: NLRS_28.11_SF_WPB_stalen ligger HEA_gen:ligger HEA 160 (9)
Type - PredefinedType: BEAM
Classification: 28.11 hoofddraagconstructies - kolommen en liggers, kolom-/liggerconstructies (Uniformat); Material: NLRS_h2_staal
Pset_BeamCommon - LoadBearing: yes; Slope: 0 deg; Reference: ligger HEA 160
Name (NLRS_28.11_SF_WPB_stalen ligger HEA_gen:ligger HEA 160:...) | In | IsExternal | Span (mm)
9108268 | 01 eerste verdieping | no | 700.3
10665999 | 55 vijfenvijftigste verdieping | yes | 4150
10666006 | 55 vijfenvijftigste verdieping | yes | 4150
12468768 | 62 tweeënzestigste verdieping | yes | 2675
13245334 | 62 tweeënzestigste verdieping | yes | 2675
13440937 | 62 tweeënzestigste verdieping | yes | 2450
13441076 | 62 tweeënzestigste verdieping | yes | 2450
13789218 | 62 tweeënzestigste verdieping | yes | 2140
13789351 | 62 tweeënzestigste verdieping | yes | 2140

# IfcBeam: NLRS_28.11_SF_WPB_stalen ligger HEA_gen:ligger HEA 180 (9)
In: 58 achtenvijftigste verdieping
Type - PredefinedType: BEAM
Classification: 28.11 hoofddraagconstructies - kolommen en liggers, kolom-/liggerconstructies (Uniformat); Material: NLRS_h2_staal
Pset_BeamCommon - LoadBearing: yes; Slope: 0 deg; Reference: ligger HEA 180
Name (NLRS_28.11_SF_WPB_stalen ligger HEA_gen:ligger HEA 180:...) | IsExternal | Span (mm)
10274365 | yes | 5300
10274372 | yes | 5040
10274378 | yes | 5160
10274466 | yes | 3250
10294173 | yes | 3250
10330738 | yes | 4920
14189998 | no | 3250
14190252 | no | 490
14190464 | no | 490

# IfcBeam: NLRS_28.11_SF_WPB_stalen ligger HEA_gen:ligger HEA 200 (16)
Type - PredefinedType: BEAM
Classification: 28.11 hoofddraagconstructies - kolommen en liggers, kolom-/liggerconstructies (Uniformat); Material: NLRS_h2_staal
Pset_BeamCommon - LoadBearing: yes; Slope: 0 deg; Reference: ligger HEA 200
Name (NLRS_28.11_SF_WPB_stalen ligger HEA_gen:ligger HEA 200:...) | In | IsExternal | Span (mm)
4891460 | 03 derde verdieping | yes | 3650
4913730 | 05 vijfde verdieping | yes | 7025
11926700 | 59 negenenvijftigste verdieping | yes | 27390
11926994 | 59 negenenvijftigste verdieping | yes | 26260
11927514 | 59 negenenvijftigste verdieping | yes | 26260
11927593 | 59 negenenvijftigste verdieping | yes | 27390
12468766 | 62 tweeënzestigste verdieping | yes | 2450
13245189 | 62 tweeënzestigste verdieping | yes | 2450
14411291 | 58 achtenvijftigste verdieping | no | 3991.63
14412692 | 58 achtenvijftigste verdieping | no | 3904.24
14413237 | 58 achtenvijftigste verdieping | no | 3991.63
14413476 | 58 achtenvijftigste verdieping | no | 3904.24
14414310 | 58 achtenvijftigste verdieping | no | 3904.24
14414586 | 58 achtenvijftigste verdieping | no | 3991.63
14415109 | 58 achtenvijftigste verdieping | no | 3991.63
14415244 | 58 achtenvijftigste verdieping | no | 3904.24

# IfcBeam: NLRS_28.11_SF_WPB_stalen ligger HEA_gen:ligger HEA 220 (24)
Type - PredefinedType: BEAM
Classification: 28.11 hoofddraagconstructies - kolommen en liggers, kolom-/liggerconstructies (Uniformat); Material: NLRS_h2_staal
Pset_BeamCommon - LoadBearing: yes; Slope: 0 deg; Reference: ligger HEA 220
Name (NLRS_28.11_SF_WPB_stalen ligger HEA_gen:ligger HEA 220:...) | In | IsExternal | Span (mm)
5305561 | 62 tweeënzestigste verdieping | yes | 11520
5305567 | 62 tweeënzestigste verdieping | yes | 11520
5305833 | 62 tweeënzestigste verdieping | yes | 14370
5305839 | 62 tweeënzestigste verdieping | yes | 14370
10294134 | 58 achtenvijftigste verdieping | no | 3250
10294146 | 58 achtenvijftigste verdieping | yes | 3250
10294183 | 58 achtenvijftigste verdieping | yes | 3250
10294214 | 58 achtenvijftigste verdieping | no | 3250
11993374 | 58 achtenvijftigste verdieping | no | 1625
11993481 | 58 achtenvijftigste verdieping | no | 1405
11993787 | 58 achtenvijftigste verdieping | no | 1735
11994826 | 58 achtenvijftigste verdieping | no | 1625
11994828 | 58 achtenvijftigste verdieping | no | 1405
11994830 | 58 achtenvijftigste verdieping | no | 1735
13638486 | 58 achtenvijftigste verdieping | no | 3700
13638622 | 58 achtenvijftigste verdieping | no | 3250
13638823 | 58 achtenvijftigste verdieping | no | 3566.66
13638825 | 58 achtenvijftigste verdieping | no | 3250
13638828 | 58 achtenvijftigste verdieping | no | 3566.66
13638830 | 58 achtenvijftigste verdieping | no | 3250
13638833 | 58 achtenvijftigste verdieping | no | 3700
13809153 | 58 achtenvijftigste verdieping | no | 3633.33
13818791 | 58 achtenvijftigste verdieping | yes | 3250
13821426 | 58 achtenvijftigste verdieping | no | 3633.33

# IfcBeam: NLRS_28.11_SF_WPB_stalen ligger HEA_gen:ligger HEA 240 (2)
In: 01 eerste verdieping
Type - PredefinedType: BEAM
Classification: 28.11 hoofddraagconstructies - kolommen en liggers, kolom-/liggerconstructies (Uniformat); Material: NLRS_h2_staal
Pset_BeamCommon - LoadBearing: yes; IsExternal: no; Slope: 0 deg; Reference: ligger HEA 240
Name (NLRS_28.11_SF_WPB_stalen ligger HEA_gen:ligger HEA 240:...) | Span (mm)
5162249 | 33240
5163250 | 5880

# IfcBeam: NLRS_28.11_SF_WPB_stalen ligger HEA_gen:ligger HEA 300 (50)
Type - PredefinedType: BEAM
Classification: 28.11 hoofddraagconstructies - kolommen en liggers, kolom-/liggerconstructies (Uniformat); Material: NLRS_h2_staal
Pset_BeamCommon - IsExternal: yes; LoadBearing: yes; Slope: 0 deg; Reference: ligger HEA 300
Name (NLRS_28.11_SF_WPB_stalen ligger HEA_gen:ligger HEA 300:...) | In | Span (mm)
5306155 | 58 achtenvijftigste verdieping | 5964
5306159 | 58 achtenvijftigste verdieping | 5964
5306165 | 58 achtenvijftigste verdieping | 5964
5306167 | 58 achtenvijftigste verdieping | 6764
5306171 | 58 achtenvijftigste verdieping | 6789
5306179 | 58 achtenvijftigste verdieping | 14500
5310114 | 58 achtenvijftigste verdieping | 12100
10269890 | 58 achtenvijftigste verdieping | 6830
10269892 | 58 achtenvijftigste verdieping | 6789
10274303 | 58 achtenvijftigste verdieping | 5939
10274306 | 58 achtenvijftigste verdieping | 12100
10274311 | 58 achtenvijftigste verdieping | 5964
10274317 | 58 achtenvijftigste verdieping | 5964
10274323 | 58 achtenvijftigste verdieping | 5964
10274329 | 58 achtenvijftigste verdieping | 5964
10274343 | 58 achtenvijftigste verdieping | 6789
10274353 | 58 achtenvijftigste verdieping | 6789
12031143 | 59 negenenvijftigste verdieping | 18870
12031703 | 59 negenenvijftigste verdieping | 5026.55
12031719 | 59 negenenvijftigste verdieping | 1884.96
12031735 | 59 negenenvijftigste verdieping | 17266.7
12031752 | 59 negenenvijftigste verdieping | 17266.7
12031770 | 59 negenenvijftigste verdieping | 18870
12031786 | 59 negenenvijftigste verdieping | 5026.55
12031803 | 59 negenenvijftigste verdieping | 1884.96
12031818 | 59 negenenvijftigste verdieping | 18870
12031833 | 59 negenenvijftigste verdieping | 18870
12031849 | 59 negenenvijftigste verdieping | 1884.96
12031865 | 59 negenenvijftigste verdieping | 5026.55
12031881 | 59 negenenvijftigste verdieping | 17266.7
12031898 | 59 negenenvijftigste verdieping | 17266.7
12031914 | 59 negenenvijftigste verdieping | 5026.55
12031930 | 59 negenenvijftigste verdieping | 1884.96
13802151 | 59 negenenvijftigste verdieping | 2900
13841542 | 59 negenenvijftigste verdieping | 3633
13841602 | 59 negenenvijftigste verdieping | 3235
13843740 | 59 negenenvijftigste verdieping | 2900
13843744 | 59 negenenvijftigste verdieping | 3633
13843998 | 59 negenenvijftigste verdieping | 3235
13844589 | 59 negenenvijftigste verdieping | 3235
13844687 | 59 negenenvijftigste verdieping | 2900
13844692 | 59 negenenvijftigste verdieping | 3633
13844913 | 59 negenenvijftigste verdieping | 2900
13844917 | 59 negenenvijftigste verdieping | 3633
13844949 | 59 negenenvijftigste verdieping | 3235
13852145 | 59 negenenvijftigste verdieping | 420
13852272 | 59 negenenvijftigste verdieping | 420
13852410 | 59 negenenvijftigste verdieping | 420
13852534 | 59 negenenvijftigste verdieping | 420
14271043 | 58 achtenvijftigste verdieping | 14500

# IfcBeam: NLRS_28.11_SF_WPB_stalen ligger HEA_gen:ligger HEA 320 (12)
Type - PredefinedType: BEAM
Classification: 28.11 hoofddraagconstructies - kolommen en liggers, kolom-/liggerconstructies (Uniformat); Material: NLRS_h2_staal
Pset_BeamCommon - LoadBearing: yes; IsExternal: no; Slope: 0 deg; Reference: ligger HEA 320; Span: 3265 mm
Name (NLRS_28.11_SF_WPB_stalen ligger HEA_gen:ligger HEA 320:...) | In
13250020 | 62 tweeënzestigste verdieping
13250132 | 62 tweeënzestigste verdieping
13250225 | 62 tweeënzestigste verdieping
13250227 | 62 tweeënzestigste verdieping
13250343 | 60 zestigste verdieping
13250345 | 60 zestigste verdieping
13250347 | 60 zestigste verdieping
13250349 | 60 zestigste verdieping
13250356 | 61 eenenzestigste verdieping
13250358 | 61 eenenzestigste verdieping
13250360 | 61 eenenzestigste verdieping
13250362 | 61 eenenzestigste verdieping

# IfcBeam: NLRS_28.11_SF_WPB_stalen ligger HEA_gen:ligger HEA 400 (40)
Type - PredefinedType: BEAM
Classification: 28.11 hoofddraagconstructies - kolommen en liggers, kolom-/liggerconstructies (Uniformat); Material: NLRS_h2_staal
Pset_BeamCommon - LoadBearing: yes; Slope: 0 deg; Reference: ligger HEA 400
Name (NLRS_28.11_SF_WPB_stalen ligger HEA_gen:ligger HEA 400:...) | In | IsExternal | Span (mm)
5309221 | 59 negenenvijftigste verdieping | yes | 6555
5309225 | 59 negenenvijftigste verdieping | yes | 6555
5309233 | 59 negenenvijftigste verdieping | yes | 7380
5309235 | 59 negenenvijftigste verdieping | yes | 7380
5309237 | 59 negenenvijftigste verdieping | yes | 7380
5309241 | 59 negenenvijftigste verdieping | yes | 6530
5309245 | 59 negenenvijftigste verdieping | yes | 6555
5309247 | 59 negenenvijftigste verdieping | yes | 7355
5309249 | 59 negenenvijftigste verdieping | yes | 7380
5309251 | 59 negenenvijftigste verdieping | yes | 7355
5309831 | 59 negenenvijftigste verdieping | yes | 6555
5309837 | 59 negenenvijftigste verdieping | yes | 6555
5309841 | 59 negenenvijftigste verdieping | yes | 7380
5309849 | 59 negenenvijftigste verdieping | yes | 7380
5309855 | 59 negenenvijftigste verdieping | yes | 6555
5309861 | 59 negenenvijftigste verdieping | yes | 6555
5309865 | 59 negenenvijftigste verdieping | yes | 7380
5309875 | 59 negenenvijftigste verdieping | yes | 7355
10294312 | 59 negenenvijftigste verdieping | yes | 3385
10294334 | 59 negenenvijftigste verdieping | yes | 7330
10294343 | 59 negenenvijftigste verdieping | no | 3120
10299410 | 62 tweeënzestigste verdieping | yes | 3295
10299418 | 62 tweeënzestigste verdieping | yes | 3295
10299420 | 62 tweeënzestigste verdieping | no | 3295
10299422 | 62 tweeënzestigste verdieping | no | 2450
10299424 | 62 tweeënzestigste verdieping | no | 2450
10299426 | 62 tweeënzestigste verdieping | no | 2450
10299428 | 62 tweeënzestigste verdieping | no | 2450
10299430 | 62 tweeënzestigste verdieping | no | 3295
12467968 | 62 tweeënzestigste verdieping | no | 1300
12467970 | 62 tweeënzestigste verdieping | no | 1300
13843913 | 59 negenenvijftigste verdieping | yes | 3385
13843915 | 59 negenenvijftigste verdieping | yes | 7330
13843917 | 59 negenenvijftigste verdieping | no | 3120
13844587 | 59 negenenvijftigste verdieping | yes | 3385
13844680 | 59 negenenvijftigste verdieping | yes | 7330
13844682 | 59 negenenvijftigste verdieping | no | 3120
13844943 | 59 negenenvijftigste verdieping | yes | 3385
13844945 | 59 negenenvijftigste verdieping | yes | 7330
13844947 | 59 negenenvijftigste verdieping | no | 3120

# IfcBeam: NLRS_28.11_SF_WPB_stalen ligger HEA_gen:ligger HEA 500 (10)
Type - PredefinedType: BEAM
Classification: 28.11 hoofddraagconstructies - kolommen en liggers, kolom-/liggerconstructies (Uniformat); Material: NLRS_h2_staal
Pset_BeamCommon - IsExternal: yes; LoadBearing: yes; Slope: 0 deg; Reference: ligger HEA 500
Name (NLRS_28.11_SF_WPB_stalen ligger HEA_gen:ligger HEA 500:...) | In | Span (mm)
5305897 | 60 zestigste verdieping | 11530
10298564 | 60 zestigste verdieping | 11530
10298581 | 60 zestigste verdieping | 11530
10299312 | 61 eenenzestigste verdieping | 11530
10299314 | 61 eenenzestigste verdieping | 11530
10299316 | 61 eenenzestigste verdieping | 11530
10299412 | 62 tweeënzestigste verdieping | 11590
10299414 | 62 tweeënzestigste verdieping | 11530
10299416 | 62 tweeënzestigste verdieping | 11530
12467205 | 62 tweeënzestigste verdieping | 11590

# IfcBeam: NLRS_28.11_SF_WPB_stalen ligger HEB_gen:ligger HEB 160 (50)
Type - PredefinedType: BEAM
Classification: 28.11 hoofddraagconstructies - kolommen en liggers, kolom-/liggerconstructies (Uniformat); Material: NLRS_h2_staal
Pset_BeamCommon - IsExternal: yes; LoadBearing: yes; Slope: 0 deg; Reference: ligger HEB 160
Name (NLRS_28.11_SF_WPB_stalen ligger HEB_gen:ligger HEB 160:...) | In | Span (mm)
5305547 | 60 zestigste verdieping | 2865.5
5305549 | 60 zestigste verdieping | 2865.5
5305819 | 60 zestigste verdieping | 3540.5
12894853 | 60 zestigste verdieping | 2990.5
12894866 | 60 zestigste verdieping | 2990.5
12894881 | 60 zestigste verdieping | 2865.5
12895179 | 61 eenenzestigste verdieping | 2865.5
12895181 | 61 eenenzestigste verdieping | 2990.5
12895183 | 61 eenenzestigste verdieping | 2990.5
12895185 | 61 eenenzestigste verdieping | 2865.5
12895188 | 62 tweeënzestigste verdieping | 2865.5
12895194 | 62 tweeënzestigste verdieping | 2865.5
12897640 | 60 zestigste verdieping | 2990.5
12897659 | 60 zestigste verdieping | 2990.5
12897676 | 60 zestigste verdieping | 2865.5
12898044 | 61 eenenzestigste verdieping | 2865.5
12898046 | 61 eenenzestigste verdieping | 2990.5
12898048 | 61 eenenzestigste verdieping | 2990.5
12898050 | 61 eenenzestigste verdieping | 2865.5
12898053 | 62 tweeënzestigste verdieping | 2865.5
12898059 | 62 tweeënzestigste verdieping | 2865.5
12898819 | 60 zestigste verdieping | 3410.25
12898836 | 60 zestigste verdieping | 3540.5
12898853 | 60 zestigste verdieping | 3410.25
12899232 | 60 zestigste verdieping | 3540.5
12899234 | 60 zestigste verdieping | 3410.25
12899236 | 60 zestigste verdieping | 3540.5
12899238 | 60 zestigste verdieping | 3410.25
12899278 | 61 eenenzestigste verdieping | 3540.5
12899280 | 61 eenenzestigste verdieping | 3410.25
12899282 | 61 eenenzestigste verdieping | 3540.5
12899284 | 61 eenenzestigste verdieping | 3410.25
12899289 | 62 tweeënzestigste verdieping | 3410.25
12899293 | 62 tweeënzestigste verdieping | 3410.25
12899345 | 00 begane grond | 3540.5
12899347 | 00 begane grond | 3410.25
12899349 | 00 begane grond | 3540.5
12899351 | 00 begane grond | 3410.25
12899354 | 61 eenenzestigste verdieping | 3540.5
12899356 | 61 eenenzestigste verdieping | 3410.25
12899358 | 61 eenenzestigste verdieping | 3540.5
12899360 | 61 eenenzestigste verdieping | 3410.25
12899365 | 62 tweeënzestigste verdieping | 3410.25
12899369 | 62 tweeënzestigste verdieping | 3410.25
13167428 | 03 derde verdieping | 465 | Group: Model Group:oplegschoen atriumkap:13180237
13180305 | 03 derde verdieping | 465 | Group: Model Group:oplegschoen atriumkap:13180346
13180741 | 03 derde verdieping | 465 | Group: Model Group:oplegschoen atriumkap:13180777
13180841 | 03 derde verdieping | 465 | Group: Model Group:oplegschoen atriumkap:13180877
13180943 | 03 derde verdieping | 465 | Group: Model Group:oplegschoen atriumkap:13180979
13181045 | 03 derde verdieping | 465 | Group: Model Group:oplegschoen atriumkap:13181081

# IfcBeam: NLRS_28.11_SF_WPB_stalen ligger HEB_gen:ligger HEB 300 (20)
Type - PredefinedType: BEAM
Classification: 28.11 hoofddraagconstructies - kolommen en liggers, kolom-/liggerconstructies (Uniformat); Material: NLRS_h2_staal
Pset_BeamCommon - IsExternal: yes; LoadBearing: yes; Slope: 0 deg; Reference: ligger HEB 300
Name (NLRS_28.11_SF_WPB_stalen ligger HEB_gen:ligger HEB 300:...) | In | Span (mm)
5306169 | 58 achtenvijftigste verdieping | 6764
10274298 | 58 achtenvijftigste verdieping | 6789
10274341 | 58 achtenvijftigste verdieping | 6789
10274355 | 58 achtenvijftigste verdieping | 6789
12026989 | 54 vierenvijftigste verdieping | 6025
12027882 | 54 vierenvijftigste verdieping | 3504
12028149 | 54 vierenvijftigste verdieping | 831
12028383 | 54 vierenvijftigste verdieping | 5896
12028824 | 54 vierenvijftigste verdieping | 6990
12028826 | 54 vierenvijftigste verdieping | 2804
12028828 | 54 vierenvijftigste verdieping | 831
12028830 | 54 vierenvijftigste verdieping | 5396
12501050 | 54 vierenvijftigste verdieping | 6025
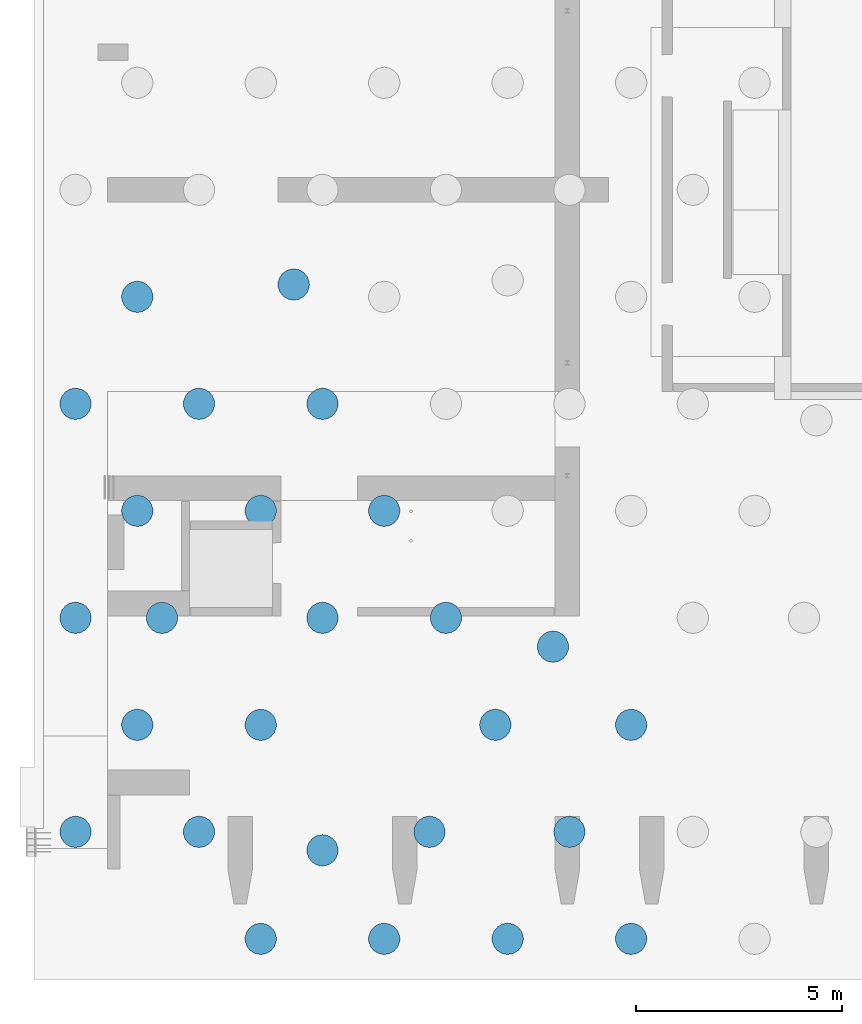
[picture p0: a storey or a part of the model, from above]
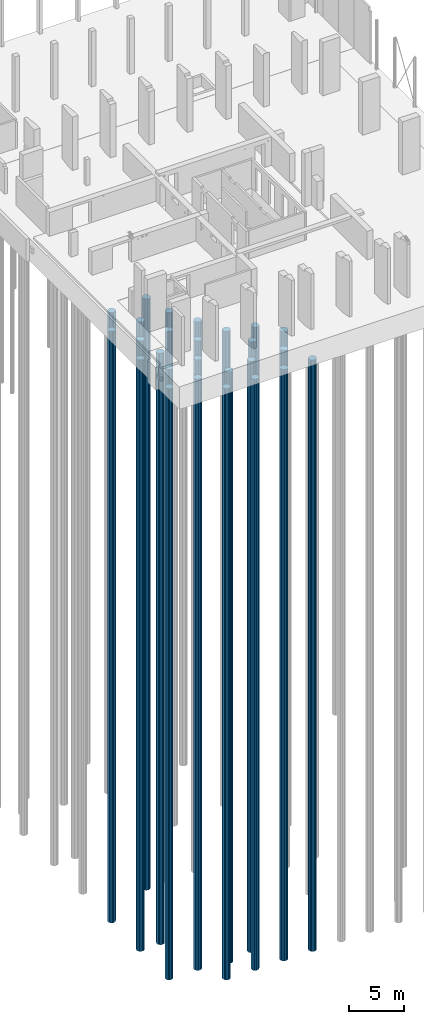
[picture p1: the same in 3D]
Properties of the parts of a building model (IFC2X3), part 3 of 21

# IfcBeam: NLRS_28.11_SF_WPB_stalen ligger HEB_gen:ligger HEB 300 (20)
Name (NLRS_28.11_SF_WPB_stalen ligger HEB_gen:ligger HEB 300:...) | In | Span (mm)
12501052 | 54 vierenvijftigste verdieping | 3504
12501054 | 54 vierenvijftigste verdieping | 831
12501056 | 54 vierenvijftigste verdieping | 5885
12501110 | 54 vierenvijftigste verdieping | 7025
12501112 | 54 vierenvijftigste verdieping | 2804
12501114 | 54 vierenvijftigste verdieping | 831
12501116 | 54 vierenvijftigste verdieping | 5396

# IfcBeam: NLRS_28.11_SF_WPB_stalen ligger HEB_gen:ligger HEB 500 (4)
In: 56 zesenvijftigste verdieping
Type - PredefinedType: BEAM
Classification: 28.11 hoofddraagconstructies - kolommen en liggers, kolom-/liggerconstructies (Uniformat); Material: NLRS_h2_staal
Pset_BeamCommon - LoadBearing: yes; IsExternal: no; Slope: 0 deg; Reference: ligger HEB 500; Span: 3300 mm
Name (NLRS_28.11_SF_WPB_stalen ligger HEB_gen:ligger HEB 500:...)
13336720
13341558
13341660
13341721

# IfcBeam: NLRS_28.11_SF_WPB_stalen ligger IPE_gen:ligger IPE 240 (5)
Type - PredefinedType: BEAM
Classification: 28.11 hoofddraagconstructies - kolommen en liggers, kolom-/liggerconstructies (Uniformat); Material: NLRS_h2_staal
Pset_BeamCommon - LoadBearing: yes; IsExternal: no; Slope: 0 deg; Reference: ligger IPE 240
Name (NLRS_28.11_SF_WPB_stalen ligger IPE_gen:ligger IPE 240:...) | In | Span (mm)
13341855 | 56 zesenvijftigste verdieping | 1380
13342312 | 56 zesenvijftigste verdieping | 1380
13342420 | 56 zesenvijftigste verdieping | 1380
13342422 | 56 zesenvijftigste verdieping | 1380
13544499 | 01 eerste verdieping | 831

# IfcBeam: NLRS_28.11_SF_WPB_stalen ligger IPE_gen:ligger IPE 330 (8)
In: 62 tweeënzestigste verdieping
Type - PredefinedType: BEAM
Classification: 28.11 hoofddraagconstructies - kolommen en liggers, kolom-/liggerconstructies (Uniformat); Material: NLRS_h2_staal
Pset_BeamCommon - IsExternal: yes; LoadBearing: yes; Slope: 0 deg; Reference: ligger IPE 330
Name (NLRS_28.11_SF_WPB_stalen ligger IPE_gen:ligger IPE 330:...) | Span (mm)
12895190 | 2990.5
12895192 | 2990.5
12898055 | 2990.5
12898057 | 2990.5
12899287 | 3540.5
12899291 | 3540.5
12899363 | 3540.5
12899367 | 3540.5

# IfcBeam: NLRS_28.11_SF_WPB_stalen ligger IPE_gen:ligger IPE 400 (10)
Type - PredefinedType: BEAM
Classification: 28.11 hoofddraagconstructies - kolommen en liggers, kolom-/liggerconstructies (Uniformat); Material: NLRS_h2_staal
Pset_BeamCommon - IsExternal: yes; LoadBearing: yes; Reference: ligger IPE 400
Name (NLRS_28.11_SF_WPB_stalen ligger IPE_gen:ligger IPE 400:...) | In | Span (mm) | Slope (deg) | Group
13126475 | 57 zevenenvijftigste verdieping | 7893 | 1.99878
13126745 | 57 zevenenvijftigste verdieping | 7893 | 1.99878
13501445 | 01 eerste verdieping | 909 | 0 | Model Group:Luifel_IPE400:12780779
13501688 | 01 eerste verdieping | 909 | 0 | Model Group:Luifel_IPE400:12780584
13502493 | 01 eerste verdieping | 634 | 0 | Model Group:Luifel_HEB300:12767605
13502781 | 01 eerste verdieping | 634 | 0 | Model Group:Luifel_HEB300:12766569
13502837 | 01 eerste verdieping | 634 | 0 | Model Group:Luifel_HEB300:12767154
13502865 | 01 eerste verdieping | 634 | 0 | Model Group:Luifel_HEB300:12767335
13502893 | 01 eerste verdieping | 634 | 0 | Model Group:Luifel_HEB300:12767433
13502921 | 01 eerste verdieping | 634 | 0 | Model Group:Luifel_HEB300:12767518

# IfcBeam: NLRS_28.11_SF_WPB_stalen ligger UNP_gen:ligger UNP 140 (9)
Type - PredefinedType: BEAM
Classification: 28.11 hoofddraagconstructies - kolommen en liggers, kolom-/liggerconstructies (Uniformat); Material: NLRS_h2_staal
Pset_BeamCommon - IsExternal: yes; LoadBearing: yes; Slope: 0 deg; Reference: ligger UNP 140
Name (NLRS_28.11_SF_WPB_stalen ligger UNP_gen:ligger UNP 140:...) | In | Span (mm)
13441216 | 62 tweeënzestigste verdieping | 1300
13441962 | 62 tweeënzestigste verdieping | 760
13788577 | 62 tweeënzestigste verdieping | 1300
13788800 | 62 tweeënzestigste verdieping | 760
13792634 | 61 eenenzestigste verdieping | 750
13850484 | 62 tweeënzestigste verdieping | 1000
13889206 | 60 zestigste verdieping | 900
13946678 | 61 eenenzestigste verdieping | 1250
14415471 | 59 negenenvijftigste verdieping | 2099.85

# IfcBeam: NLRS_28.11_SF_WPB_stalen ligger UNP_gen:ligger UNP 160, NLRS_28.11_SF_WPB_stalen ligger UNP_gen:ligger UNP 160:12958709
In: 60 zestigste verdieping
Type - PredefinedType: BEAM
Classification: 28.11 hoofddraagconstructies - kolommen en liggers, kolom-/liggerconstructies (Uniformat); Material: NLRS_h2_staal
Pset_BeamCommon - IsExternal: yes; LoadBearing: yes; Slope: 0 deg; Reference: ligger UNP 160; Span: 1070 mm

# IfcBeam: NLRS_28.11_SF_WPB_stalen ligger UNP_gen:ligger UNP 180 (11)
Type - PredefinedType: BEAM
Classification: 28.11 hoofddraagconstructies - kolommen en liggers, kolom-/liggerconstructies (Uniformat); Material: NLRS_h2_staal
Pset_BeamCommon - LoadBearing: yes; IsExternal: no; Slope: 0 deg; Reference: ligger UNP 180
Name (NLRS_28.11_SF_WPB_stalen ligger UNP_gen:ligger UNP 180:...) | In | Span (mm)
13587880 | 03 derde verdieping | 1100
13588574 | 05 vijfde verdieping | 1100
13610214 | 03 derde verdieping | 1100
13610218 | 05 vijfde verdieping | 1100
13610348 | 03 derde verdieping | 1150
13610352 | 05 vijfde verdieping | 1150
13610695 | 03 derde verdieping | 1100
13610699 | 05 vijfde verdieping | 1100
13610994 | 03 derde verdieping | 531
13610998 | 05 vijfde verdieping | 531
13622421 | 05 vijfde verdieping | 2690

# IfcBeam: NLRS_28.11_SF_WPB_stalen ligger UNP_gen:ligger UNP 200 (6)
In: 58 achtenvijftigste verdieping
Type - PredefinedType: BEAM
Classification: 28.11 hoofddraagconstructies - kolommen en liggers, kolom-/liggerconstructies (Uniformat); Material: NLRS_h2_staal
Pset_BeamCommon - LoadBearing: yes; IsExternal: no; Slope: 0 deg; Reference: ligger UNP 200
Name (NLRS_28.11_SF_WPB_stalen ligger UNP_gen:ligger UNP 200:...) | Span (mm)
11993954 | 1713.89
11994739 | 1685.61
11994778 | 1685.61
11994832 | 1713.89
11994834 | 1685.61
11994836 | 1685.61

# IfcBeam: NLRS_28.11_SF_WPB_stalen ligger UNP_gen:ligger UNP 300 (29)
In: 05 vijfde verdieping
Type - PredefinedType: BEAM
Classification: 28.11 hoofddraagconstructies - kolommen en liggers, kolom-/liggerconstructies (Uniformat); Material: NLRS_h2_staal
Pset_BeamCommon - IsExternal: yes; LoadBearing: yes; Slope: 0 deg; Reference: ligger UNP 300
Name (NLRS_28.11_SF_WPB_stalen ligger UNP_gen:ligger UNP 300:...) | Span (mm)
11836327 | 3620
11840484 | 3720
11840537 | 3673.03 | Group: Model Group:BS_Gevel H.7:12243648
11840590 | 3720
12206464 | 7200
12208308 | 5400
12208615 | 7200
12209411 | 7200
12209921 | 7200
12210042 | 7200
12210143 | 10173
12216148 | 10150
12216426 | 4723
12228987 | 3675
12229127 | 3175
12239076 | 3673.03
12239607 | 3620
12240123 | 3185
12240375 | 2900
12243694 | 3673.03 | Group: Model Group:BS_Gevel H.1 3400:12244471
12244529 | 3673.03 | Group: Model Group:BS_Gevel H.1 3400:12244545
12244622 | 3673.03 | Group: Model Group:BS_Gevel H.1 3400:12244638
12244717 | 3673.03 | Group: Model Group:BS_Gevel H.1 3400:12244733
12244835 | 3620 | Group: Model Group:BS_Gevel H.1 3350:12245213
12245278 | 3620 | Group: Model Group:BS_Gevel H.1 3350-a:13572764
12245381 | 1715 | Group: Model Group:BS_Gevel H.1 1450:12245699
12245744 | 1715 | Group: Model Group:BS_Gevel H.1 1450:12245756
12245991 | 3187.89
12247315 | 3180

# IfcBeam: NLRS_28.11_SF_WPB_stalen ligger UNP_gen:ligger UNP 350 (4)
In: 59 negenenvijftigste verdieping
Type - PredefinedType: BEAM
Classification: 28.11 hoofddraagconstructies - kolommen en liggers, kolom-/liggerconstructies (Uniformat); Material: NLRS_h2_staal
Pset_BeamCommon - IsExternal: yes; LoadBearing: yes; Slope: 0 deg; Reference: ligger UNP 350
Name (NLRS_28.11_SF_WPB_stalen ligger UNP_gen:ligger UNP 350:...) | Span (mm)
11925269 | 26780
11925847 | 26780
11926025 | 26230
11926207 | 26230

# IfcBeam: NLRS_28.11_SF_WPB_stalen ligger Z-profiel_gen_BSc:ligger Z-profiel 200/15x355/15x150/15 (14)
Type - PredefinedType: BEAM
Classification: 28.11 hoofddraagconstructies - kolommen en liggers, kolom-/liggerconstructies (Uniformat); Material: NLRS_h2_staal
Pset_BeamCommon - LoadBearing: yes; Slope: 0 deg; Reference: ligger Z-profiel 200/15x355/15x150/15
Name (NLRS_28.11_SF_WPB_stalen ligger Z-profiel_gen_BSc:ligger Z-profiel 200/15x355/15x150/15:...) | In | IsExternal | Span (mm)
4926740 | 00a eerste tussenverdieping | yes | 970
4926885 | 01 eerste verdieping | yes | 3010
4929678 | 01 eerste verdieping | yes | 3580
4929680 | 01 eerste verdieping | yes | 3280
4929836 | 02 tweede verdieping | yes | 3010
4929838 | 02 tweede verdieping | yes | 3580
4929840 | 02 tweede verdieping | yes | 3580
4929842 | 02 tweede verdieping | yes | 2880
4929889 | 03 derde verdieping | yes | 3660
4929891 | 03 derde verdieping | yes | 2880
4930633 | 03 derde verdieping | yes | 3010
4930635 | 03 derde verdieping | yes | 3660
10446785 | 00a eerste tussenverdieping | no | 3000
12280791 | 01 eerste verdieping | yes | 3580

# IfcBeam: NLRS_28.11_SF_WPB_stalen ligger hoekprofiel gelijkzijdig_gen:ligger gelijzijdig hoekprofiel LEQU_100x100x10 (195)
Type - PredefinedType: BEAM
Classification: 28.11 hoofddraagconstructies - kolommen en liggers, kolom-/liggerconstructies (Uniformat); Material: NLRS_h2_staal
Pset_BeamCommon - LoadBearing: yes; Slope: 0 deg; Reference: ligger gelijzijdig hoekprofiel LEQU_100x100x10
Name (NLRS_28.11_SF_WPB_stalen ligger hoekprofiel gelijkzijdig_gen:ligger gelijzijdig hoekprofiel LEQU_100x100x10:...) | In | IsExternal | Span (mm)
11836412 | 05 vijfde verdieping | yes | 1555
11837312 | 05 vijfde verdieping | yes | 240
11837529 | 05 vijfde verdieping | yes | 1230
11837951 | 05 vijfde verdieping | yes | 240
11837953 | 05 vijfde verdieping | yes | 1235
11840486 | 05 vijfde verdieping | yes | 1605
11840488 | 05 vijfde verdieping | yes | 240
11840490 | 05 vijfde verdieping | yes | 1235
11840492 | 05 vijfde verdieping | yes | 240
11840494 | 05 vijfde verdieping | yes | 1235
11840539 | 05 vijfde verdieping | yes | 1580 | Group: Model Group:BS_Gevel H.7:12243648
11840541 | 05 vijfde verdieping | yes | 240 | Group: Model Group:BS_Gevel H.7:12243648
11840543 | 05 vijfde verdieping | yes | 1230 | Group: Model Group:BS_Gevel H.7:12243648
11840545 | 05 vijfde verdieping | yes | 240 | Group: Model Group:BS_Gevel H.7:12243648
11840547 | 05 vijfde verdieping | yes | 1235 | Group: Model Group:BS_Gevel H.7:12243648
11840592 | 05 vijfde verdieping | yes | 1605
11840594 | 05 vijfde verdieping | yes | 240
11840596 | 05 vijfde verdieping | yes | 1235
11840598 | 05 vijfde verdieping | yes | 240
11840600 | 05 vijfde verdieping | yes | 1230
12217246 | 05 vijfde verdieping | yes | 3265
12217726 | 05 vijfde verdieping | yes | 3254.75
12218389 | 05 vijfde verdieping | yes | 1660
12219375 | 05 vijfde verdieping | yes | 1618
12219507 | 05 vijfde verdieping | yes | 1431
12219697 | 05 vijfde verdieping | yes | 3305
12219820 | 05 vijfde verdieping | yes | 3305
12219919 | 05 vijfde verdieping | yes | 2200
12220063 | 05 vijfde verdieping | yes | 1875
12220065 | 05 vijfde verdieping | yes | 2250
12220324 | 05 vijfde verdieping | yes | 2160
12220326 | 05 vijfde verdieping | yes | 2070
12220328 | 05 vijfde verdieping | yes | 2149.75
12220331 | 05 vijfde verdieping | yes | 2150
12220333 | 05 vijfde verdieping | yes | 2070
12220335 | 05 vijfde verdieping | yes | 2150
12220338 | 05 vijfde verdieping | yes | 2160
12220340 | 05 vijfde verdieping | yes | 2070
12220342 | 05 vijfde verdieping | yes | 2099.75
12220345 | 05 vijfde verdieping | yes | 2110
12220347 | 05 vijfde verdieping | yes | 2070
12220349 | 05 vijfde verdieping | yes | 2100
12220450 | 05 vijfde verdieping | yes | 2689.54
12221516 | 05 vijfde verdieping | yes | 1209.04
12221952 | 05 vijfde verdieping | yes | 1044.04
12222031 | 05 vijfde verdieping | yes | 1089.04
12222033 | 05 vijfde verdieping | yes | 1209.04
12222400 | 05 vijfde verdieping | yes | 1099.85
12222795 | 05 vijfde verdieping | yes | 1099.85
12222873 | 05 vijfde verdieping | yes | 1220
12222933 | 05 vijfde verdieping | yes | 1099.85
12223002 | 05 vijfde verdieping | yes | 1220
12223004 | 05 vijfde verdieping | yes | 1220
12223021 | 05 vijfde verdieping | yes | 1220
12223023 | 05 vijfde verdieping | yes | 1220
12223106 | 05 vijfde verdieping | yes | 800
12223562 | 05 vijfde verdieping | yes | 1089.04
12223564 | 05 vijfde verdieping | yes | 1099.85
12223566 | 05 vijfde verdieping | yes | 1089.04
12223574 | 05 vijfde verdieping | yes | 1089.04
12227239 | 05 vijfde verdieping | yes | 1099.85
12227284 | 05 vijfde verdieping | yes | 1089.04
12227347 | 05 vijfde verdieping | yes | 1089.04
12227387 | 05 vijfde verdieping | yes | 1089.04
12227474 | 05 vijfde verdieping | yes | 1099.85
12227476 | 05 vijfde verdieping | yes | 1099.85
12228989 | 05 vijfde verdieping | yes | 1580
12228991 | 05 vijfde verdieping | yes | 240
12228993 | 05 vijfde verdieping | yes | 1230
12228995 | 05 vijfde verdieping | yes | 240
12228997 | 05 vijfde verdieping | yes | 1230
12229069 | 05 vijfde verdieping | yes | 240
12229071 | 05 vijfde verdieping | yes | 1230
12232666 | 05 vijfde verdieping | yes | 1580
12232817 | 05 vijfde verdieping | yes | 1210
12234417 | 05 vijfde verdieping | yes | 1555
12235859 | 05 vijfde verdieping | yes | 1605
12237337 | 05 vijfde verdieping | yes | 1580 | Group: Model Group:BS_Gevel H.7:12243648
12238180 | 05 vijfde verdieping | yes | 1605
12239078 | 05 vijfde verdieping | yes | 1580
12239080 | 05 vijfde verdieping | yes | 240
12239082 | 05 vijfde verdieping | yes | 1230
12239084 | 05 vijfde verdieping | yes | 240
12239086 | 05 vijfde verdieping | yes | 1235
12239090 | 05 vijfde verdieping | yes | 1580
12239609 | 05 vijfde verdieping | yes | 1555
12239611 | 05 vijfde verdieping | yes | 240
12239613 | 05 vijfde verdieping | yes | 1230
12239615 | 05 vijfde verdieping | yes | 240
12239617 | 05 vijfde verdieping | yes | 1235
12239621 | 05 vijfde verdieping | yes | 1555
12240125 | 05 vijfde verdieping | yes | 240
12240127 | 05 vijfde verdieping | yes | 1230
12240885 | 05 vijfde verdieping | yes | 1245
12241169 | 05 vijfde verdieping | yes | 799.754
12243696 | 05 vijfde verdieping | yes | 1580 | Group: Model Group:BS_Gevel H.1 3400:12244471
12243698 | 05 vijfde verdieping | yes | 516 | Group: Model Group:BS_Gevel H.1 3400:12244471
12243700 | 05 vijfde verdieping | yes | 740 | Group: Model Group:BS_Gevel H.1 3400:12244471
12243702 | 05 vijfde verdieping | yes | 516 | Group: Model Group:BS_Gevel H.1 3400:12244471
12243704 | 05 vijfde verdieping | yes | 732.812 | Group: Model Group:BS_Gevel H.1 3400:12244471
12243708 | 05 vijfde verdieping | yes | 1580 | Group: Model Group:BS_Gevel H.1 3400:12244471
12244531 | 05 vijfde verdieping | yes | 1580 | Group: Model Group:BS_Gevel H.1 3400:12244545
12244533 | 05 vijfde verdieping | yes | 516 | Group: Model Group:BS_Gevel H.1 3400:12244545
12244535 | 05 vijfde verdieping | yes | 740 | Group: Model Group:BS_Gevel H.1 3400:12244545
12244537 | 05 vijfde verdieping | yes | 516 | Group: Model Group:BS_Gevel H.1 3400:12244545
12244539 | 05 vijfde verdieping | yes | 732.812 | Group: Model Group:BS_Gevel H.1 3400:12244545
12244543 | 05 vijfde verdieping | yes | 1580 | Group: Model Group:BS_Gevel H.1 3400:12244545
12244624 | 05 vijfde verdieping | yes | 1580 | Group: Model Group:BS_Gevel H.1 3400:12244638
12244626 | 05 vijfde verdieping | yes | 516 | Group: Model Group:BS_Gevel H.1 3400:12244638
12244628 | 05 vijfde verdieping | yes | 740 | Group: Model Group:BS_Gevel H.1 3400:12244638
12244630 | 05 vijfde verdieping | yes | 516 | Group: Model Group:BS_Gevel H.1 3400:12244638
12244632 | 05 vijfde verdieping | yes | 732.812 | Group: Model Group:BS_Gevel H.1 3400:12244638
12244636 | 05 vijfde verdieping | yes | 1580 | Group: Model Group:BS_Gevel H.1 3400:12244638
12244719 | 05 vijfde verdieping | yes | 1580 | Group: Model Group:BS_Gevel H.1 3400:12244733
12244721 | 05 vijfde verdieping | yes | 516 | Group: Model Group:BS_Gevel H.1 3400:12244733
12244723 | 05 vijfde verdieping | yes | 740 | Group: Model Group:BS_Gevel H.1 3400:12244733
12244725 | 05 vijfde verdieping | yes | 516 | Group: Model Group:BS_Gevel H.1 3400:12244733
12244727 | 05 vijfde verdieping | yes | 732.812 | Group: Model Group:BS_Gevel H.1 3400:12244733
12244731 | 05 vijfde verdieping | yes | 1580 | Group: Model Group:BS_Gevel H.1 3400:12244733
12244837 | 05 vijfde verdieping | yes | 1549.96 | Group: Model Group:BS_Gevel H.1 3350:12245213
12244839 | 05 vijfde verdieping | yes | 516 | Group: Model Group:BS_Gevel H.1 3350:12245213
12244841 | 05 vijfde verdieping | yes | 720 | Group: Model Group:BS_Gevel H.1 3350:12245213
12244843 | 05 vijfde verdieping | yes | 516 | Group: Model Group:BS_Gevel H.1 3350:12245213
12244845 | 05 vijfde verdieping | yes | 732.812 | Group: Model Group:BS_Gevel H.1 3350:12245213
12244849 | 05 vijfde verdieping | yes | 1600.05 | Group: Model Group:BS_Gevel H.1 3350:12245213
12245280 | 05 vijfde verdieping | yes | 1592.33 | Group: Model Group:BS_Gevel H.1 3350-a:13572764
12245282 | 05 vijfde verdieping | yes | 516 | Group: Model Group:BS_Gevel H.1 3350-a:13572764
12245284 | 05 vijfde verdieping | yes | 720 | Group: Model Group:BS_Gevel H.1 3350-a:13572764
12245286 | 05 vijfde verdieping | yes | 516 | Group: Model Group:BS_Gevel H.1 3350-a:13572764
12245288 | 05 vijfde verdieping | yes | 732.812 | Group: Model Group:BS_Gevel H.1 3350-a:13572764
12245292 | 05 vijfde verdieping | yes | 1557.67 | Group: Model Group:BS_Gevel H.1 3350-a:13572764
12245385 | 05 vijfde verdieping | yes | 516 | Group: Model Group:BS_Gevel H.1 1450:12245699
12245387 | 05 vijfde verdieping | yes | 740 | Group: Model Group:BS_Gevel H.1 1450:12245699
12245389 | 05 vijfde verdieping | yes | 516 | Group: Model Group:BS_Gevel H.1 1450:12245699
12245391 | 05 vijfde verdieping | yes | 732.812 | Group: Model Group:BS_Gevel H.1 1450:12245699
12245395 | 05 vijfde verdieping | yes | 1230 | Group: Model Group:BS_Gevel H.1 1450:12245699
12245746 | 05 vijfde verdieping | yes | 516 | Group: Model Group:BS_Gevel H.1 1450:12245756
12245748 | 05 vijfde verdieping | yes | 740 | Group: Model Group:BS_Gevel H.1 1450:12245756
12245750 | 05 vijfde verdieping | yes | 516 | Group: Model Group:BS_Gevel H.1 1450:12245756
12245752 | 05 vijfde verdieping | yes | 732.812 | Group: Model Group:BS_Gevel H.1 1450:12245756
12245754 | 05 vijfde verdieping | yes | 1230 | Group: Model Group:BS_Gevel H.1 1450:12245756
12245993 | 05 vijfde verdieping | yes | 516
12245995 | 05 vijfde verdieping | yes | 740
12245997 | 05 vijfde verdieping | yes | 516
12245999 | 05 vijfde verdieping | yes | 732.812
12246546 | 05 vijfde verdieping | yes | 1030
12247065 | 05 vijfde verdieping | yes | 1260
12247243 | 05 vijfde verdieping | yes | 1600
12271193 | 03 derde verdieping | yes | 1235
12271195 | 03 derde verdieping | yes | 1235
12271207 | 03 derde verdieping | yes | 1235
12271213 | 03 derde verdieping | yes | 1235
12271219 | 03 derde verdieping | yes | 1235
12271225 | 03 derde verdieping | yes | 1235
12271231 | 03 derde verdieping | yes | 1235
12271237 | 03 derde verdieping | yes | 1235
12271243 | 03 derde verdieping | yes | 1235
12271249 | 03 derde verdieping | yes | 1235
12930328 | 59 negenenvijftigste verdieping | yes | 3250
12931235 | 59 negenenvijftigste verdieping | yes | 3250
12931261 | 59 negenenvijftigste verdieping | yes | 3250
12931279 | 59 negenenvijftigste verdieping | yes | 3250
12931338 | 59 negenenvijftigste verdieping | yes | 3566.67
12931341 | 59 negenenvijftigste verdieping | yes | 3633.33
12931344 | 59 negenenvijftigste verdieping | yes | 3700
12931400 | 59 negenenvijftigste verdieping | yes | 3250
12931403 | 59 negenenvijftigste verdieping | yes | 3250
12931406 | 59 negenenvijftigste verdieping | yes | 3250
12931409 | 59 negenenvijftigste verdieping | yes | 3250
12931958 | 59 negenenvijftigste verdieping | yes | 3566.67
12931961 | 59 negenenvijftigste verdieping | yes | 3633.33
12931964 | 59 negenenvijftigste verdieping | yes | 3700
12932322 | 58 achtenvijftigste verdieping | yes | 3250
12932325 | 58 achtenvijftigste verdieping | yes | 3250
12932328 | 58 achtenvijftigste verdieping | yes | 1625
12932331 | 58 achtenvijftigste verdieping | yes | 3250
12932334 | 58 achtenvijftigste verdieping | yes | 3566.67
12932337 | 58 achtenvijftigste verdieping | yes | 3633.33
12932340 | 58 achtenvijftigste verdieping | yes | 3700
12932343 | 58 achtenvijftigste verdieping | yes | 3250
12932346 | 58 achtenvijftigste verdieping | yes | 3250
12932349 | 58 achtenvijftigste verdieping | yes | 1445
12932352 | 58 achtenvijftigste verdieping | yes | 3250
12932355 | 58 achtenvijftigste verdieping | yes | 3566.67
12932358 | 58 achtenvijftigste verdieping | yes | 3633.33
12932361 | 58 achtenvijftigste verdieping | yes | 3700
12932666 | 58 achtenvijftigste verdieping | yes | 1425
12932828 | 58 achtenvijftigste verdieping | yes | 1625
13514420 | 59 negenenvijftigste verdieping | yes | 7295
13514428 | 59 negenenvijftigste verdieping | no | 6005.8
13514434 | 59 negenenvijftigste verdieping | no | 14370
13514444 | 59 negenenvijftigste verdieping | no | 11970
13514446 | 59 negenenvijftigste verdieping | no | 11970
13613970 | 01 eerste verdieping | no | 150
13614918 | 01 eerste verdieping | no | 150

# IfcBeam: NLRS_28.11_SF_WPB_stalen ligger hoekprofiel gelijkzijdig_gen:ligger gelijzijdig hoekprofiel LEQU_120x120x12_! (68)
Type - PredefinedType: BEAM
Classification: 28.11 hoofddraagconstructies - kolommen en liggers, kolom-/liggerconstructies (Uniformat); Material: NLRS_h2_staal
Pset_BeamCommon - LoadBearing: yes; Slope: 0 deg; Reference: ligger gelijzijdig hoekprofiel LEQU_120x120x12_!
Name (NLRS_28.11_SF_WPB_stalen ligger hoekprofiel gelijkzijdig_gen:ligger gelijzijdig hoekprofiel LEQU_120x120x12_!:...) | In | IsExternal | Span (mm) | Group
13544880 | 03 derde verdieping | no | 300 | Model Group:Koppeling-1:13567508
13567649 | 03 derde verdieping | no | 300 | Model Group:Koppeling-1:13567654
13571106 | 03 derde verdieping | no | 300 | Model Group:Koppeling-1:13571111
13571197 | 03 derde verdieping | no | 300 | Model Group:Koppeling-1:13571202
13571765 | 03 derde verdieping | no | 300 | Model Group:Koppeling-1:13571770
13571771 | 03 derde verdieping | no | 300 | Model Group:Koppeling-1:13571776
13571831 | 03 derde verdieping | no | 300 | Model Group:Koppeling-1:13571836
13571837 | 03 derde verdieping | no | 300 | Model Group:Koppeling-1:13571842
13571897 | 03 derde verdieping | no | 300 | Model Group:Koppeling-1:13571902
13571903 | 03 derde verdieping | no | 300 | Model Group:Koppeling-1:13571908
13572113 | 03 derde verdieping | no | 300 | Model Group:Koppeling-1:13572118
13572260 | 03 derde verdieping | no | 300 | Model Group:Koppeling-1:13572265
13572855 | 03 derde verdieping | no | 300 | Model Group:Koppeling-1:13572860
13572925 | 03 derde verdieping | no | 300 | Model Group:Koppeling-1:13572930
13573357 | 03 derde verdieping | no | 300 | Model Group:Koppeling-1:13573362
13573363 | 03 derde verdieping | no | 300 | Model Group:Koppeling-1:13573368
13573482 | 04 vierde verdieping | no | 300 | Model Group:Koppeling-1:13573487
13573564 | 04 vierde verdieping | no | 300 | Model Group:Koppeling-1:13573569
13574242 | 03 derde verdieping | no | 300 | Model Group:Koppeling-1:13574247
13574424 | 03 derde verdieping | no | 300 | Model Group:Koppeling-1:13574429
13577467 | 03 derde verdieping | no | 300 | Model Group:Koppeling-1:13577472
13577732 | 03 derde verdieping | no | 300 | Model Group:Koppeling-1:13577737
13578663 | 03 derde verdieping | no | 300 | Model Group:Koppeling-1:13578668
13578669 | 03 derde verdieping | no | 300 | Model Group:Koppeling-1:13578674
13578878 | 03 derde verdieping | no | 300 | Model Group:Koppeling-1:13578883
13578966 | 03 derde verdieping | no | 300 | Model Group:Koppeling-1:13578971
13580909 | 03 derde verdieping | no | 300 | Model Group:Koppeling-1:13580914
13581047 | 03 derde verdieping | no | 300 | Model Group:Koppeling-1:13581052
13581117 | 03 derde verdieping | no | 300 | Model Group:Koppeling-1:13581122
13581185 | 03 derde verdieping | no | 300 | Model Group:Koppeling-1:13581190
13581272 | 03 derde verdieping | no | 300 | Model Group:Koppeling-1:13581277
13581278 | 03 derde verdieping | no | 300 | Model Group:Koppeling-1:13581283
13581381 | 03 derde verdieping | no | 300 | Model Group:Koppeling-1:13581386
13581447 | 03 derde verdieping | no | 300 | Model Group:Koppeling-1:13581452
13581517 | 03 derde verdieping | no | 300 | Model Group:Koppeling-1:13581522
13581585 | 03 derde verdieping | no | 300 | Model Group:Koppeling-1:13581590
13581657 | 03 derde verdieping | no | 300 | Model Group:Koppeling-1:13581662
13581723 | 03 derde verdieping | no | 300 | Model Group:Koppeling-1:13581728
13581793 | 03 derde verdieping | no | 300 | Model Group:Koppeling-1:13581798
13581863 | 03 derde verdieping | no | 300 | Model Group:Koppeling-1:13581868
13581933 | 03 derde verdieping | no | 300 | Model Group:Koppeling-1:13581938
13581999 | 03 derde verdieping | no | 300 | Model Group:Koppeling-1:13582004
13582067 | 03 derde verdieping | no | 300 | Model Group:Koppeling-1:13582072
13582135 | 03 derde verdieping | no | 300 | Model Group:Koppeling-1:13582140
13582203 | 03 derde verdieping | no | 300 | Model Group:Koppeling-1:13582208
13582271 | 03 derde verdieping | no | 300 | Model Group:Koppeling-1:13582276
13582339 | 03 derde verdieping | no | 300 | Model Group:Koppeling-1:13582344
13582409 | 03 derde verdieping | no | 300 | Model Group:Koppeling-1:13582414
13582479 | 03 derde verdieping | no | 300 | Model Group:Koppeling-1:13582484
13582547 | 03 derde verdieping | no | 300 | Model Group:Koppeling-1:13582552
13582617 | 03 derde verdieping | no | 300 | Model Group:Koppeling-1:13582622
13582685 | 03 derde verdieping | no | 300 | Model Group:Koppeling-1:13582690
13582753 | 03 derde verdieping | no | 300 | Model Group:Koppeling-1:13582758
13589920 | 05 vijfde verdieping | no | 460 | Model Group:Koppeling-3:13592218
13593876 | 05 vijfde verdieping | no | 460 | Model Group:Koppeling-3:13593881
13593930 | 05 vijfde verdieping | no | 460 | Model Group:Koppeling-3:13593935
13593976 | 05 vijfde verdieping | no | 460 | Model Group:Koppeling-3:13593981
13594046 | 05 vijfde verdieping | no | 460 | Model Group:Koppeling-3:13594051
13594092 | 05 vijfde verdieping | no | 460 | Model Group:Koppeling-3:13594097
13594182 | 05 vijfde verdieping | no | 460 | Model Group:Koppeling-3:13594187
13594228 | 05 vijfde verdieping | no | 460 | Model Group:Koppeling-3:13594233
13594541 | 04 vierde verdieping | no | 460 | Model Group:Koppeling-3a:13594638
13611775 | 03 derde verdieping | no | 300 | Model Group:Koppeling-1:13611780
13611781 | 03 derde verdieping | no | 300 | Model Group:Koppeling-1:13611786
13611787 | 03 derde verdieping | no | 300 | Model Group:Koppeling-1:13611792
13611793 | 03 derde verdieping | no | 300 | Model Group:Koppeling-1:13611798
13611898 | 05 vijfde verdieping | no | 460 | Model Group:Koppeling-3a:13611903
13714607 | 05 vijfde verdieping | yes | 350

# IfcBeam: NLRS_28.11_SF_WPB_stalen ligger hoekprofiel gelijkzijdig_gen:ligger gelijzijdig hoekprofiel LEQU_150x150x12 (5)
In: 56 zesenvijftigste verdieping
Type - PredefinedType: BEAM
Classification: 28.11 hoofddraagconstructies - kolommen en liggers, kolom-/liggerconstructies (Uniformat); Material: NLRS_h2_staal
Pset_BeamCommon - LoadBearing: yes; IsExternal: no; Slope: 0 deg; Reference: ligger gelijzijdig hoekprofiel LEQU_150x150x12
Name (NLRS_28.11_SF_WPB_stalen ligger hoekprofiel gelijkzijdig_gen:ligger gelijzijdig hoekprofiel LEQU_150x150x12:...) | Span (mm)
14199888 | 2700
14202764 | 1665
14202953 | 1665
14203243 | 2700
14209224 | 4170

# IfcBeam: NLRS_28.11_SF_WPB_stalen ligger hoekprofiel gelijkzijdig_gen:ligger gelijzijdig hoekprofiel LEQU_150x150x15 (18)
Type - PredefinedType: BEAM
Classification: 28.11 hoofddraagconstructies - kolommen en liggers, kolom-/liggerconstructies (Uniformat); Material: NLRS_h2_staal
Pset_BeamCommon - IsExternal: yes; LoadBearing: yes; Slope: 0 deg; Reference: ligger gelijzijdig hoekprofiel LEQU_150x150x15
Name (NLRS_28.11_SF_WPB_stalen ligger hoekprofiel gelijkzijdig_gen:ligger gelijzijdig hoekprofiel LEQU_150x150x15:...) | In | Span (mm)
4918418 | 01 eerste verdieping | 2989.9
4918669 | 02 tweede verdieping | 2980
4919934 | 03 derde verdieping | 2989.9
4920713 | 02 tweede verdieping | 2010
4921638 | 01 eerste verdieping | 4330
5998775 | 05 vijfde verdieping | 2770
6002591 | 03 derde verdieping | 1680
6003170 | 03 derde verdieping | 1155
6400254 | 01 eerste verdieping | 2010
6401116 | 01 eerste verdieping | 1310
6402233 | 01 eerste verdieping | 1310
6402429 | 02 tweede verdieping | 4310
6402431 | 02 tweede verdieping | 1310
6402433 | 02 tweede verdieping | 1310
9290674 | 00a eerste tussenverdieping | 4330
9290676 | 00a eerste tussenverdieping | 1310
9290678 | 00a eerste tussenverdieping | 1310
14102448 | 05 vijfde verdieping | 2770

# IfcBeam: NLRS_28.11_SF_WPB_stalen ligger hoekprofiel gelijkzijdig_gen:ligger gelijzijdig hoekprofiel LEQU_180x180x18, NLRS_28.11_SF_WPB_stalen ligger hoekprofiel gelijkzijdig_gen:ligger gelijzijdig hoekprofiel LEQU_180x180x18:9773730
In: 01 eerste verdieping
Type - PredefinedType: BEAM
Classification: 28.11 hoofddraagconstructies - kolommen en liggers, kolom-/liggerconstructies (Uniformat); Material: NLRS_h2_staal
Pset_BeamCommon - IsExternal: yes; LoadBearing: yes; Slope: 0 deg; Reference: ligger gelijzijdig hoekprofiel LEQU_180x180x18; Span: 2980 mm

# IfcBeam: NLRS_28.11_SF_WPB_stalen ligger hoekprofiel gelijkzijdig_gen:ligger gelijzijdig hoekprofiel LEQU_200x200x20, NLRS_28.11_SF_WPB_stalen ligger hoekprofiel gelijkzijdig_gen:ligger gelijzijdig hoekprofiel LEQU_200x200x20:12351640
In: 01 eerste verdieping
Type - PredefinedType: BEAM
Classification: 28.11 hoofddraagconstructies - kolommen en liggers, kolom-/liggerconstructies (Uniformat); Material: NLRS_h2_staal
Pset_BeamCommon - IsExternal: yes; LoadBearing: yes; Slope: 0 deg; Reference: ligger gelijzijdig hoekprofiel LEQU_200x200x20; Span: 2260 mm

# IfcBeam: NLRS_28.11_SF_WPB_stalen ligger hoekprofiel gelijkzijdig_gen:ligger gelijzijdig hoekprofiel LEQU_50x50x5 (3)
In: 03 derde verdieping
Type - PredefinedType: BEAM
Classification: 28.11 hoofddraagconstructies - kolommen en liggers, kolom-/liggerconstructies (Uniformat); Material: NLRS_h2_staal
Pset_BeamCommon - LoadBearing: yes; Slope: 0 deg; Reference: ligger gelijzijdig hoekprofiel LEQU_50x50x5
Name (NLRS_28.11_SF_WPB_stalen ligger hoekprofiel gelijkzijdig_gen:ligger gelijzijdig hoekprofiel LEQU_50x50x5:...) | IsExternal | Span (mm)
11828636 | yes | 3660
11828789 | yes | 4270
11829192 | no | 3680

# IfcBeam: NLRS_28.11_SF_WPB_stalen ligger hoekprofiel ongelijkzijdig_gen:ligger ongelijzijdig hoekprofiel LUEQ_150x100x10 (6)
Type - PredefinedType: BEAM
Classification: 28.11 hoofddraagconstructies - kolommen en liggers, kolom-/liggerconstructies (Uniformat); Material: NLRS_h2_staal
Pset_BeamCommon - LoadBearing: yes; IsExternal: no; Slope: 0 deg; Reference: ligger ongelijzijdig hoekprofiel LUEQ_150x100x10; Span: 300 mm
Name (NLRS_28.11_SF_WPB_stalen ligger hoekprofiel ongelijkzijdig_gen:ligger ongelijzijdig hoekprofiel LUEQ_150x100x10:...) | In | Group
13620371 | 02 tweede verdieping | Model Group:Koppeling-4 onder:13620370
13620760 | 02 tweede verdieping | Model Group:Koppeling-4 onder:13620759
13620829 | 02 tweede verdieping | Model Group:Koppeling-4 onder:13620828
13620983 | 03 derde verdieping | Model Group:Koppeling-4 onder:13620982
13620989 | 03 derde verdieping | Model Group:Koppeling-4 onder:13620988
13620995 | 03 derde verdieping | Model Group:Koppeling-4 onder:13620994

# IfcBeam: NLRS_28.11_SF_WPB_stalen ligger hoekprofiel ongelijkzijdig_gen:ligger ongelijzijdig hoekprofiel LUEQ_200x100x10 (6)
Type - PredefinedType: BEAM
Classification: 28.11 hoofddraagconstructies - kolommen en liggers, kolom-/liggerconstructies (Uniformat); Material: NLRS_h2_staal
Pset_BeamCommon - LoadBearing: yes; IsExternal: no; Slope: 0 deg; Reference: ligger ongelijzijdig hoekprofiel LUEQ_200x100x10; Span: 300 mm
Name (NLRS_28.11_SF_WPB_stalen ligger hoekprofiel ongelijkzijdig_gen:ligger ongelijzijdig hoekprofiel LUEQ_200x100x10:...) | In | Group
13616678 | 02 tweede verdieping | Model Group:Koppeling-4:13616571
13620219 | 02 tweede verdieping | Model Group:Koppeling-4:13620218
13620286 | 02 tweede verdieping | Model Group:Koppeling-4:13620285
13621120 | 01 eerste verdieping | Model Group:Koppeling-4:13621119
13621126 | 01 eerste verdieping | Model Group:Koppeling-4:13621125
13621132 | 01 eerste verdieping | Model Group:Koppeling-4:13621131

# IfcBeam: NLRS_28.11_SF_WPB_stalen ligger rond massief_gen:Willemsanker ø24 (2)
In: 04 vierde verdieping
Type - PredefinedType: BEAM
Classification: 28.11 hoofddraagconstructies - kolommen en liggers, kolom-/liggerconstructies (Uniformat); Material: NLRS_h2_staal
Pset_BeamCommon - IsExternal: yes; LoadBearing: yes; Reference: Willemsanker ø24; Span: 7361.91 mm; Slope: 24.0147 deg
Name (NLRS_28.11_SF_WPB_stalen ligger rond massief_gen:Willemsanker ø24:...)
4922679
4923786

# IfcBeam: NLRS_28.11_SF_WPB_stalen schoen 1_gen (32)
Type - ElementType: NLRS_28.11_SF_WPB_stalen schoen 1_gen; PredefinedType: BEAM; Material: NLRS_h2_staal
Pset_BeamCommon - LoadBearing: yes; IsExternal: no; Slope: 0 deg; Reference: NLRS_28.11_SF_WPB_stalen schoen 1_gen; Span: 235 mm
Name (NLRS_28.11_SF_WPB_stalen schoen 1_gen:NLRS_28.11_SF_WPB_stalen schoen 1_gen:...) | In | Group
13546857 | 07 zevende verdieping | Model Group:NLRS_28.11_SF_handjes balkon 3-4_verd 5 tm 9_gen:10635968
13548004 | 06 zesde verdieping | Model Group:NLRS_28.11_SF_handjes balkon 3-4_verd 5 tm 9_gen:10634983
13548008 | 06 zesde verdieping | Model Group:NLRS_28.11_SF_handjes balkon 3-4_verd 5 tm 9_gen:10634984
13548012 | 07 zevende verdieping | Model Group:NLRS_28.11_SF_handjes balkon 3-4_verd 5 tm 9_gen:10635969
13548016 | 08 achtste verdieping | Model Group:NLRS_28.11_SF_handjes balkon 3-4_verd 5 tm 9_gen:10636845
13548020 | 08 achtste verdieping | Model Group:NLRS_28.11_SF_handjes balkon 3-4_verd 5 tm 9_gen:10636846
13548024 | 09 negende verdieping | Model Group:NLRS_28.11_SF_handjes balkon 3-4_verd 5 tm 9_gen:10637382
13548028 | 09 negende verdieping | Model Group:NLRS_28.11_SF_handjes balkon 3-4_verd 5 tm 9_gen:10637383
13551891 | 07 zevende verdieping | Model Group:NLRS_28.11_SF_handjes balkon 3-4_verd 5 tm 9_gen:10635968
13553434 | 06 zesde verdieping | Model Group:NLRS_28.11_SF_handjes balkon 3-4_verd 5 tm 9_gen:10634983
13553441 | 06 zesde verdieping | Model Group:NLRS_28.11_SF_handjes balkon 3-4_verd 5 tm 9_gen:10634984
13553448 | 07 zevende verdieping | Model Group:NLRS_28.11_SF_handjes balkon 3-4_verd 5 tm 9_gen:10635969
13553455 | 08 achtste verdieping | Model Group:NLRS_28.11_SF_handjes balkon 3-4_verd 5 tm 9_gen:10636845
13553462 | 08 achtste verdieping | Model Group:NLRS_28.11_SF_handjes balkon 3-4_verd 5 tm 9_gen:10636846
13553469 | 09 negende verdieping | Model Group:NLRS_28.11_SF_handjes balkon 3-4_verd 5 tm 9_gen:10637382
13553476 | 09 negende verdieping | Model Group:NLRS_28.11_SF_handjes balkon 3-4_verd 5 tm 9_gen:10637383
13559176 | 07 zevende verdieping | Model Group:NLRS_28.11_SF_handjes balkon 1-2_verd 6 tm 9_gen:10635963
13559178 | 07 zevende verdieping | Model Group:NLRS_28.11_SF_handjes balkon 1-2_verd 6 tm 9_gen:10635963
13561168 | 06 zesde verdieping | Model Group:NLRS_28.11_SF_handjes balkon 1-2_verd 6 tm 9_gen:10634978
13561170 | 06 zesde verdieping | Model Group:NLRS_28.11_SF_handjes balkon 1-2_verd 6 tm 9_gen:10634978
13561177 | 06 zesde verdieping | Model Group:NLRS_28.11_SF_handjes balkon 1-2_verd 6 tm 9_gen:10634991
13561179 | 06 zesde verdieping | Model Group:NLRS_28.11_SF_handjes balkon 1-2_verd 6 tm 9_gen:10634991
13561186 | 07 zevende verdieping | Model Group:NLRS_28.11_SF_handjes balkon 1-2_verd 6 tm 9_gen:10635976
13561188 | 07 zevende verdieping | Model Group:NLRS_28.11_SF_handjes balkon 1-2_verd 6 tm 9_gen:10635976
13561195 | 08 achtste verdieping | Model Group:NLRS_28.11_SF_handjes balkon 1-2_verd 6 tm 9_gen:10636840
13561197 | 08 achtste verdieping | Model Group:NLRS_28.11_SF_handjes balkon 1-2_verd 6 tm 9_gen:10636840
13561204 | 08 achtste verdieping | Model Group:NLRS_28.11_SF_handjes balkon 1-2_verd 6 tm 9_gen:10636853
13561206 | 08 achtste verdieping | Model Group:NLRS_28.11_SF_handjes balkon 1-2_verd 6 tm 9_gen:10636853
13561213 | 09 negende verdieping | Model Group:NLRS_28.11_SF_handjes balkon 1-2_verd 6 tm 9_gen:10637377
13561215 | 09 negende verdieping | Model Group:NLRS_28.11_SF_handjes balkon 1-2_verd 6 tm 9_gen:10637377
13561222 | 09 negende verdieping | Model Group:NLRS_28.11_SF_handjes balkon 1-2_verd 6 tm 9_gen:10637390
13561224 | 09 negende verdieping | Model Group:NLRS_28.11_SF_handjes balkon 1-2_verd 6 tm 9_gen:10637390

# IfcBeam: NLRS_28.11_SF_WPB_stalen schoen 2_gen (32)
Type - ElementType: NLRS_28.11_SF_WPB_stalen schoen 2_gen; PredefinedType: BEAM; Material: NLRS_h2_staal
Pset_BeamCommon - LoadBearing: yes; IsExternal: no; Slope: 0 deg; Reference: NLRS_28.11_SF_WPB_stalen schoen 2_gen; Span: 235 mm
Name (NLRS_28.11_SF_WPB_stalen schoen 2_gen:NLRS_28.11_SF_WPB_stalen schoen 2_gen:...) | In | Group
13552025 | 07 zevende verdieping | Model Group:NLRS_28.11_SF_handjes balkon 3-4_verd 5 tm 9_gen:10635968
13552086 | 07 zevende verdieping | Model Group:NLRS_28.11_SF_handjes balkon 3-4_verd 5 tm 9_gen:10635968
13553436 | 06 zesde verdieping | Model Group:NLRS_28.11_SF_handjes balkon 3-4_verd 5 tm 9_gen:10634983
13553438 | 06 zesde verdieping | Model Group:NLRS_28.11_SF_handjes balkon 3-4_verd 5 tm 9_gen:10634983
13553443 | 06 zesde verdieping | Model Group:NLRS_28.11_SF_handjes balkon 3-4_verd 5 tm 9_gen:10634984
13553445 | 06 zesde verdieping | Model Group:NLRS_28.11_SF_handjes balkon 3-4_verd 5 tm 9_gen:10634984
13553450 | 07 zevende verdieping | Model Group:NLRS_28.11_SF_handjes balkon 3-4_verd 5 tm 9_gen:10635969
13553452 | 07 zevende verdieping | Model Group:NLRS_28.11_SF_handjes balkon 3-4_verd 5 tm 9_gen:10635969
13553457 | 08 achtste verdieping | Model Group:NLRS_28.11_SF_handjes balkon 3-4_verd 5 tm 9_gen:10636845
13553459 | 08 achtste verdieping | Model Group:NLRS_28.11_SF_handjes balkon 3-4_verd 5 tm 9_gen:10636845
13553464 | 08 achtste verdieping | Model Group:NLRS_28.11_SF_handjes balkon 3-4_verd 5 tm 9_gen:10636846
13553466 | 08 achtste verdieping | Model Group:NLRS_28.11_SF_handjes balkon 3-4_verd 5 tm 9_gen:10636846
13553471 | 09 negende verdieping | Model Group:NLRS_28.11_SF_handjes balkon 3-4_verd 5 tm 9_gen:10637382
13553473 | 09 negende verdieping | Model Group:NLRS_28.11_SF_handjes balkon 3-4_verd 5 tm 9_gen:10637382
13553478 | 09 negende verdieping | Model Group:NLRS_28.11_SF_handjes balkon 3-4_verd 5 tm 9_gen:10637383
13553480 | 09 negende verdieping | Model Group:NLRS_28.11_SF_handjes balkon 3-4_verd 5 tm 9_gen:10637383
13559180 | 07 zevende verdieping | Model Group:NLRS_28.11_SF_handjes balkon 1-2_verd 6 tm 9_gen:10635963
13559182 | 07 zevende verdieping | Model Group:NLRS_28.11_SF_handjes balkon 1-2_verd 6 tm 9_gen:10635963
13561172 | 06 zesde verdieping | Model Group:NLRS_28.11_SF_handjes balkon 1-2_verd 6 tm 9_gen:10634978
13561174 | 06 zesde verdieping | Model Group:NLRS_28.11_SF_handjes balkon 1-2_verd 6 tm 9_gen:10634978
13561181 | 06 zesde verdieping | Model Group:NLRS_28.11_SF_handjes balkon 1-2_verd 6 tm 9_gen:10634991
13561183 | 06 zesde verdieping | Model Group:NLRS_28.11_SF_handjes balkon 1-2_verd 6 tm 9_gen:10634991
13561190 | 07 zevende verdieping | Model Group:NLRS_28.11_SF_handjes balkon 1-2_verd 6 tm 9_gen:10635976
13561192 | 07 zevende verdieping | Model Group:NLRS_28.11_SF_handjes balkon 1-2_verd 6 tm 9_gen:10635976
13561199 | 08 achtste verdieping | Model Group:NLRS_28.11_SF_handjes balkon 1-2_verd 6 tm 9_gen:10636840
13561201 | 08 achtste verdieping | Model Group:NLRS_28.11_SF_handjes balkon 1-2_verd 6 tm 9_gen:10636840
13561208 | 08 achtste verdieping | Model Group:NLRS_28.11_SF_handjes balkon 1-2_verd 6 tm 9_gen:10636853
13561210 | 08 achtste verdieping | Model Group:NLRS_28.11_SF_handjes balkon 1-2_verd 6 tm 9_gen:10636853
13561217 | 09 negende verdieping | Model Group:NLRS_28.11_SF_handjes balkon 1-2_verd 6 tm 9_gen:10637377
13561219 | 09 negende verdieping | Model Group:NLRS_28.11_SF_handjes balkon 1-2_verd 6 tm 9_gen:10637377
13561226 | 09 negende verdieping | Model Group:NLRS_28.11_SF_handjes balkon 1-2_verd 6 tm 9_gen:10637390
13561228 | 09 negende verdieping | Model Group:NLRS_28.11_SF_handjes balkon 1-2_verd 6 tm 9_gen:10637390

# IfcBeam: NLRS_28.11_SF_WPB_stalen schoen 3_gen (346)
Type - ElementType: NLRS_28.11_SF_WPB_stalen schoen 3_gen; PredefinedType: BEAM; Material: NLRS_h2_staal
Pset_BeamCommon - LoadBearing: yes; IsExternal: no; Slope: 0 deg; Reference: NLRS_28.11_SF_WPB_stalen schoen 3_gen; Span: 210 mm
Name (NLRS_28.11_SF_WPB_stalen schoen 3_gen:NLRS_28.11_SF_WPB_stalen schoen 3_gen:...) | In | Group
13553044 | 16 zestiende verdieping | Model Group:NLRS_28.11_SF_handjes balkon 3-4_gen:9036916
13553046 | 16 zestiende verdieping | Model Group:NLRS_28.11_SF_handjes balkon 3-4_gen:9036916
13553051 | 16 zestiende verdieping | Model Group:NLRS_28.11_SF_handjes balkon 3-4_gen:9036917
13553053 | 16 zestiende verdieping | Model Group:NLRS_28.11_SF_handjes balkon 3-4_gen:9036917
13553058 | 15 vijftiende verdieping | Model Group:NLRS_28.11_SF_handjes balkon 3-4_gen:9050834
13553060 | 15 vijftiende verdieping | Model Group:NLRS_28.11_SF_handjes balkon 3-4_gen:9050834
13553065 | 15 vijftiende verdieping | Model Group:NLRS_28.11_SF_handjes balkon 3-4_gen:9050835
13553067 | 15 vijftiende verdieping | Model Group:NLRS_28.11_SF_handjes balkon 3-4_gen:9050835
13553072 | 17 zeventiende verdieping | Model Group:NLRS_28.11_SF_handjes balkon 3-4_gen:9051130
13553074 | 17 zeventiende verdieping | Model Group:NLRS_28.11_SF_handjes balkon 3-4_gen:9051130
13553079 | 17 zeventiende verdieping | Model Group:NLRS_28.11_SF_handjes balkon 3-4_gen:9051131
13553081 | 17 zeventiende verdieping | Model Group:NLRS_28.11_SF_handjes balkon 3-4_gen:9051131
13553086 | 18 achttiende verdieping | Model Group:NLRS_28.11_SF_handjes balkon 3-4_gen:9131781
13553088 | 18 achttiende verdieping | Model Group:NLRS_28.11_SF_handjes balkon 3-4_gen:9131781
13553093 | 18 achttiende verdieping | Model Group:NLRS_28.11_SF_handjes balkon 3-4_gen:9131782
13553095 | 18 achttiende verdieping | Model Group:NLRS_28.11_SF_handjes balkon 3-4_gen:9131782
13553338 | 10 tiende verdieping | Model Group:NLRS_28.11_SF_handjes balkon 3-4_gen:10618299
13553340 | 10 tiende verdieping | Model Group:NLRS_28.11_SF_handjes balkon 3-4_gen:10618299
13553345 | 10 tiende verdieping | Model Group:NLRS_28.11_SF_handjes balkon 3-4_gen:10618300
13553347 | 10 tiende verdieping | Model Group:NLRS_28.11_SF_handjes balkon 3-4_gen:10618300
13553352 | 12 twaalfde verdieping | Model Group:NLRS_28.11_SF_handjes balkon 3-4_gen:10620653
13553354 | 12 twaalfde verdieping | Model Group:NLRS_28.11_SF_handjes balkon 3-4_gen:10620653
13553359 | 12 twaalfde verdieping | Model Group:NLRS_28.11_SF_handjes balkon 3-4_gen:10620654
13553361 | 12 twaalfde verdieping | Model Group:NLRS_28.11_SF_handjes balkon 3-4_gen:10620654
13553366 | 14 veertiende verdieping | Model Group:NLRS_28.11_SF_handjes balkon 3-4_gen:10620785
13553368 | 14 veertiende verdieping | Model Group:NLRS_28.11_SF_handjes balkon 3-4_gen:10620785
13553373 | 14 veertiende verdieping | Model Group:NLRS_28.11_SF_handjes balkon 3-4_gen:10620786
13553375 | 14 veertiende verdieping | Model Group:NLRS_28.11_SF_handjes balkon 3-4_gen:10620786
13553380 | 20 twintigste verdieping | Model Group:NLRS_28.11_SF_handjes balkon 3-4_gen:10620917
13553382 | 20 twintigste verdieping | Model Group:NLRS_28.11_SF_handjes balkon 3-4_gen:10620917
13553387 | 20 twintigste verdieping | Model Group:NLRS_28.11_SF_handjes balkon 3-4_gen:10620918
13553389 | 20 twintigste verdieping | Model Group:NLRS_28.11_SF_handjes balkon 3-4_gen:10620918
13553394 | 11 elfde verdieping | Model Group:NLRS_28.11_SF_handjes balkon 3-4_gen:10622917
13553396 | 11 elfde verdieping | Model Group:NLRS_28.11_SF_handjes balkon 3-4_gen:10622917
13553401 | 11 elfde verdieping | Model Group:NLRS_28.11_SF_handjes balkon 3-4_gen:10622918
13553403 | 11 elfde verdieping | Model Group:NLRS_28.11_SF_handjes balkon 3-4_gen:10622918
13553408 | 13 dertiende verdieping | Model Group:NLRS_28.11_SF_handjes balkon 3-4_gen:10625084
13553410 | 13 dertiende verdieping | Model Group:NLRS_28.11_SF_handjes balkon 3-4_gen:10625084
13553415 | 13 dertiende verdieping | Model Group:NLRS_28.11_SF_handjes balkon 3-4_gen:10625085
13553417 | 13 dertiende verdieping | Model Group:NLRS_28.11_SF_handjes balkon 3-4_gen:10625085
13553422 | 19 negentiende verdieping | Model Group:NLRS_28.11_SF_handjes balkon 3-4_gen:10625216
13553424 | 19 negentiende verdieping | Model Group:NLRS_28.11_SF_handjes balkon 3-4_gen:10625216
13553429 | 19 negentiende verdieping | Model Group:NLRS_28.11_SF_handjes balkon 3-4_gen:10625217
13553431 | 19 negentiende verdieping | Model Group:NLRS_28.11_SF_handjes balkon 3-4_gen:10625217
13560668 | 16 zestiende verdieping | Model Group:NLRS_28.11_SF_handjes balkon 1-2_gen:9036911
13560670 | 16 zestiende verdieping | Model Group:NLRS_28.11_SF_handjes balkon 1-2_gen:9036911
13560677 | 16 zestiende verdieping | Model Group:NLRS_28.11_SF_handjes balkon 1-2_gen:9036924
13560679 | 16 zestiende verdieping | Model Group:NLRS_28.11_SF_handjes balkon 1-2_gen:9036924
13560686 | 15 vijftiende verdieping | Model Group:NLRS_28.11_SF_handjes balkon 1-2_gen:9050829
13560688 | 15 vijftiende verdieping | Model Group:NLRS_28.11_SF_handjes balkon 1-2_gen:9050829
13560695 | 15 vijftiende verdieping | Model Group:NLRS_28.11_SF_handjes balkon 1-2_gen:9050842
13560697 | 15 vijftiende verdieping | Model Group:NLRS_28.11_SF_handjes balkon 1-2_gen:9050842
13560704 | 17 zeventiende verdieping | Model Group:NLRS_28.11_SF_handjes balkon 1-2_gen:9051125
13560706 | 17 zeventiende verdieping | Model Group:NLRS_28.11_SF_handjes balkon 1-2_gen:9051125
13560713 | 17 zeventiende verdieping | Model Group:NLRS_28.11_SF_handjes balkon 1-2_gen:9051138
13560715 | 17 zeventiende verdieping | Model Group:NLRS_28.11_SF_handjes balkon 1-2_gen:9051138
13560722 | 18 achttiende verdieping | Model Group:NLRS_28.11_SF_handjes balkon 1-2_gen:9131776
13560724 | 18 achttiende verdieping | Model Group:NLRS_28.11_SF_handjes balkon 1-2_gen:9131776
13560731 | 18 achttiende verdieping | Model Group:NLRS_28.11_SF_handjes balkon 1-2_gen:9131789
13560733 | 18 achttiende verdieping | Model Group:NLRS_28.11_SF_handjes balkon 1-2_gen:9131789
13561046 | 10 tiende verdieping | Model Group:NLRS_28.11_SF_handjes balkon 1-2_gen:10618294
13561048 | 10 tiende verdieping | Model Group:NLRS_28.11_SF_handjes balkon 1-2_gen:10618294
13561055 | 10 tiende verdieping | Model Group:NLRS_28.11_SF_handjes balkon 1-2_gen:10618307
13561057 | 10 tiende verdieping | Model Group:NLRS_28.11_SF_handjes balkon 1-2_gen:10618307
13561064 | 12 twaalfde verdieping | Model Group:NLRS_28.11_SF_handjes balkon 1-2_gen:10620648
13561066 | 12 twaalfde verdieping | Model Group:NLRS_28.11_SF_handjes balkon 1-2_gen:10620648
13561073 | 12 twaalfde verdieping | Model Group:NLRS_28.11_SF_handjes balkon 1-2_gen:10620661
13561075 | 12 twaalfde verdieping | Model Group:NLRS_28.11_SF_handjes balkon 1-2_gen:10620661
13561082 | 14 veertiende verdieping | Model Group:NLRS_28.11_SF_handjes balkon 1-2_gen:10620780
13561084 | 14 veertiende verdieping | Model Group:NLRS_28.11_SF_handjes balkon 1-2_gen:10620780
13561091 | 14 veertiende verdieping | Model Group:NLRS_28.11_SF_handjes balkon 1-2_gen:10620793
13561093 | 14 veertiende verdieping | Model Group:NLRS_28.11_SF_handjes balkon 1-2_gen:10620793
13561100 | 20 twintigste verdieping | Model Group:NLRS_28.11_SF_handjes balkon 1-2_gen:10620912
13561102 | 20 twintigste verdieping | Model Group:NLRS_28.11_SF_handjes balkon 1-2_gen:10620912
13561109 | 20 twintigste verdieping | Model Group:NLRS_28.11_SF_handjes balkon 1-2_gen:10620925
13561111 | 20 twintigste verdieping | Model Group:NLRS_28.11_SF_handjes balkon 1-2_gen:10620925
13561118 | 11 elfde verdieping | Model Group:NLRS_28.11_SF_handjes balkon 1-2_gen:10622912
13561120 | 11 elfde verdieping | Model Group:NLRS_28.11_SF_handjes balkon 1-2_gen:10622912
13561127 | 11 elfde verdieping | Model Group:NLRS_28.11_SF_handjes balkon 1-2_gen:10622925
13561129 | 11 elfde verdieping | Model Group:NLRS_28.11_SF_handjes balkon 1-2_gen:10622925
13561136 | 13 dertiende verdieping | Model Group:NLRS_28.11_SF_handjes balkon 1-2_gen:10625079
13561138 | 13 dertiende verdieping | Model Group:NLRS_28.11_SF_handjes balkon 1-2_gen:10625079
13561145 | 13 dertiende verdieping | Model Group:NLRS_28.11_SF_handjes balkon 1-2_gen:10625092
13561147 | 13 dertiende verdieping | Model Group:NLRS_28.11_SF_handjes balkon 1-2_gen:10625092
13561154 | 19 negentiende verdieping | Model Group:NLRS_28.11_SF_handjes balkon 1-2_gen:10625211
13561156 | 19 negentiende verdieping | Model Group:NLRS_28.11_SF_handjes balkon 1-2_gen:10625211
13561163 | 19 negentiende verdieping | Model Group:NLRS_28.11_SF_handjes balkon 1-2_gen:10625224
13561165 | 19 negentiende verdieping | Model Group:NLRS_28.11_SF_handjes balkon 1-2_gen:10625224
13768629 | 52 tweeënvijftigste verdieping | Model Group:NLRS_28.11_SF_handjes balkon 1-2_52e verd_gen:13768620
13769761 | 52 tweeënvijftigste verdieping | Model Group:NLRS_28.11_SF_handjes balkon 3-4_52e verd_gen:13769752
13769763 | 52 tweeënvijftigste verdieping | Model Group:NLRS_28.11_SF_handjes balkon 3-4_52e verd_gen:13769752
13769983 | 52 tweeënvijftigste verdieping | Model Group:NLRS_28.11_SF_handjes balkon 1-2_52e verd_gen:13769974
13770128 | 52 tweeënvijftigste verdieping | Model Group:NLRS_28.11_SF_handjes balkon 3-4_52e verd_gen:13770119
13770130 | 52 tweeënvijftigste verdieping | Model Group:NLRS_28.11_SF_handjes balkon 3-4_52e verd_gen:13770119
13963815 | 53 drieënvijftigste verdieping | Model Group:NLRS_28.11_SF_handjes balkon 1-2_53e verd_gen:13907235
13963971 | 53 drieënvijftigste verdieping | Model Group:NLRS_28.11_SF_handjes balkon 1-2_53e verd_gen:13907244
13964402 | 53 drieënvijftigste verdieping | Model Group:NLRS_28.11_SF_handjes balkon 3-4_53e verd_gen:13907254
13964482 | 53 drieënvijftigste verdieping | Model Group:NLRS_28.11_SF_handjes balkon 3-4_53e verd_gen:13907245
14036857 | 21 eenentwintigste verdieping | Model Group:NLRS_28.11_SF_handjes balkon 1-2_gen:14026841
14036859 | 21 eenentwintigste verdieping | Model Group:NLRS_28.11_SF_handjes balkon 1-2_gen:14026841
14036970 | 21 eenentwintigste verdieping | Model Group:NLRS_28.11_SF_handjes balkon 3-4_gen:14026850
14036972 | 21 eenentwintigste verdieping | Model Group:NLRS_28.11_SF_handjes balkon 3-4_gen:14026850
14037031 | 21 eenentwintigste verdieping | Model Group:NLRS_28.11_SF_handjes balkon 1-2_gen:14026859
14037033 | 21 eenentwintigste verdieping | Model Group:NLRS_28.11_SF_handjes balkon 1-2_gen:14026859
14037096 | 21 eenentwintigste verdieping | Model Group:NLRS_28.11_SF_handjes balkon 3-4_gen:14026868
14037098 | 21 eenentwintigste verdieping | Model Group:NLRS_28.11_SF_handjes balkon 3-4_gen:14026868
14037296 | 40 veertigste verdieping | Model Group:NLRS_28.11_SF_handjes balkon 3-4_gen:14018324
14037298 | 40 veertigste verdieping | Model Group:NLRS_28.11_SF_handjes balkon 3-4_gen:14018324
14037313 | 40 veertigste verdieping | Model Group:NLRS_28.11_SF_handjes balkon 3-4_gen:14018342
14037315 | 40 veertigste verdieping | Model Group:NLRS_28.11_SF_handjes balkon 3-4_gen:14018342
14037411 | 40 veertigste verdieping | Model Group:NLRS_28.11_SF_handjes balkon 1-2_gen:14018315
14037413 | 40 veertigste verdieping | Model Group:NLRS_28.11_SF_handjes balkon 1-2_gen:14018315
14037428 | 40 veertigste verdieping | Model Group:NLRS_28.11_SF_handjes balkon 1-2_gen:14018333
14037430 | 40 veertigste verdieping | Model Group:NLRS_28.11_SF_handjes balkon 1-2_gen:14018333
14038901 | 22 tweeëntwintigste verdieping | Model Group:NLRS_28.11_SF_handjes balkon 3-4_gen:14020834
14038903 | 22 tweeëntwintigste verdieping | Model Group:NLRS_28.11_SF_handjes balkon 3-4_gen:14020834
14038917 | 22 tweeëntwintigste verdieping | Model Group:NLRS_28.11_SF_handjes balkon 3-4_gen:14020852
14038919 | 22 tweeëntwintigste verdieping | Model Group:NLRS_28.11_SF_handjes balkon 3-4_gen:14020852
14038929 | 22 tweeëntwintigste verdieping | Model Group:NLRS_28.11_SF_handjes balkon 1-2_gen:14020825
14038931 | 22 tweeëntwintigste verdieping | Model Group:NLRS_28.11_SF_handjes balkon 1-2_gen:14020825
14038945 | 22 tweeëntwintigste verdieping | Model Group:NLRS_28.11_SF_handjes balkon 1-2_gen:14020843
14038947 | 22 tweeëntwintigste verdieping | Model Group:NLRS_28.11_SF_handjes balkon 1-2_gen:14020843
14038966 | 24 vierentwintigste verdieping | Model Group:NLRS_28.11_SF_handjes balkon 3-4_gen:14020903
14038968 | 24 vierentwintigste verdieping | Model Group:NLRS_28.11_SF_handjes balkon 3-4_gen:14020903
14038982 | 24 vierentwintigste verdieping | Model Group:NLRS_28.11_SF_handjes balkon 3-4_gen:14020921
14038984 | 24 vierentwintigste verdieping | Model Group:NLRS_28.11_SF_handjes balkon 3-4_gen:14020921
14038994 | 24 vierentwintigste verdieping | Model Group:NLRS_28.11_SF_handjes balkon 1-2_gen:14020894
14038996 | 24 vierentwintigste verdieping | Model Group:NLRS_28.11_SF_handjes balkon 1-2_gen:14020894
14039010 | 24 vierentwintigste verdieping | Model Group:NLRS_28.11_SF_handjes balkon 1-2_gen:14020912
14039012 | 24 vierentwintigste verdieping | Model Group:NLRS_28.11_SF_handjes balkon 1-2_gen:14020912
14039031 | 25 vijfentwintigste verdieping | Model Group:NLRS_28.11_SF_handjes balkon 3-4_gen:14020972
14039033 | 25 vijfentwintigste verdieping | Model Group:NLRS_28.11_SF_handjes balkon 3-4_gen:14020972
14039047 | 25 vijfentwintigste verdieping | Model Group:NLRS_28.11_SF_handjes balkon 3-4_gen:14020990
14039049 | 25 vijfentwintigste verdieping | Model Group:NLRS_28.11_SF_handjes balkon 3-4_gen:14020990
14039059 | 25 vijfentwintigste verdieping | Model Group:NLRS_28.11_SF_handjes balkon 1-2_gen:14020963
14039061 | 25 vijfentwintigste verdieping | Model Group:NLRS_28.11_SF_handjes balkon 1-2_gen:14020963
14039075 | 25 vijfentwintigste verdieping | Model Group:NLRS_28.11_SF_handjes balkon 1-2_gen:14020981
14039077 | 25 vijfentwintigste verdieping | Model Group:NLRS_28.11_SF_handjes balkon 1-2_gen:14020981
14039096 | 26 zesentwintigste verdieping | Model Group:NLRS_28.11_SF_handjes balkon 3-4_gen:14021041
14039098 | 26 zesentwintigste verdieping | Model Group:NLRS_28.11_SF_handjes balkon 3-4_gen:14021041
14039112 | 26 zesentwintigste verdieping | Model Group:NLRS_28.11_SF_handjes balkon 3-4_gen:14021059
14039114 | 26 zesentwintigste verdieping | Model Group:NLRS_28.11_SF_handjes balkon 3-4_gen:14021059
14039124 | 26 zesentwintigste verdieping | Model Group:NLRS_28.11_SF_handjes balkon 1-2_gen:14021032
14039126 | 26 zesentwintigste verdieping | Model Group:NLRS_28.11_SF_handjes balkon 1-2_gen:14021032
14039140 | 26 zesentwintigste verdieping | Model Group:NLRS_28.11_SF_handjes balkon 1-2_gen:14021050
14039142 | 26 zesentwintigste verdieping | Model Group:NLRS_28.11_SF_handjes balkon 1-2_gen:14021050
14039161 | 30 dertigste verdieping | Model Group:NLRS_28.11_SF_handjes balkon 3-4_gen:14021110
14039163 | 30 dertigste verdieping | Model Group:NLRS_28.11_SF_handjes balkon 3-4_gen:14021110
14039177 | 30 dertigste verdieping | Model Group:NLRS_28.11_SF_handjes balkon 3-4_gen:14021128
14039179 | 30 dertigste verdieping | Model Group:NLRS_28.11_SF_handjes balkon 3-4_gen:14021128
14039189 | 30 dertigste verdieping | Model Group:NLRS_28.11_SF_handjes balkon 1-2_gen:14021101
14039191 | 30 dertigste verdieping | Model Group:NLRS_28.11_SF_handjes balkon 1-2_gen:14021101
14039205 | 30 dertigste verdieping | Model Group:NLRS_28.11_SF_handjes balkon 1-2_gen:14021119
14039207 | 30 dertigste verdieping | Model Group:NLRS_28.11_SF_handjes balkon 1-2_gen:14021119
14039226 | 23 drieëntwintigste verdieping | Model Group:NLRS_28.11_SF_handjes balkon 3-4_gen:14021179
14039228 | 23 drieëntwintigste verdieping | Model Group:NLRS_28.11_SF_handjes balkon 3-4_gen:14021179
14039242 | 23 drieëntwintigste verdieping | Model Group:NLRS_28.11_SF_handjes balkon 3-4_gen:14021197
14039244 | 23 drieëntwintigste verdieping | Model Group:NLRS_28.11_SF_handjes balkon 3-4_gen:14021197
14039254 | 23 drieëntwintigste verdieping | Model Group:NLRS_28.11_SF_handjes balkon 1-2_gen:14021170
14039256 | 23 drieëntwintigste verdieping | Model Group:NLRS_28.11_SF_handjes balkon 1-2_gen:14021170
14039270 | 23 drieëntwintigste verdieping | Model Group:NLRS_28.11_SF_handjes balkon 1-2_gen:14021188
14039272 | 23 drieëntwintigste verdieping | Model Group:NLRS_28.11_SF_handjes balkon 1-2_gen:14021188
14039291 | 28 achtentwintigste verdieping | Model Group:NLRS_28.11_SF_handjes balkon 3-4_gen:14021248
14039293 | 28 achtentwintigste verdieping | Model Group:NLRS_28.11_SF_handjes balkon 3-4_gen:14021248
14039307 | 28 achtentwintigste verdieping | Model Group:NLRS_28.11_SF_handjes balkon 3-4_gen:14021266
14039309 | 28 achtentwintigste verdieping | Model Group:NLRS_28.11_SF_handjes balkon 3-4_gen:14021266
14039319 | 28 achtentwintigste verdieping | Model Group:NLRS_28.11_SF_handjes balkon 1-2_gen:14021239
14039321 | 28 achtentwintigste verdieping | Model Group:NLRS_28.11_SF_handjes balkon 1-2_gen:14021239
14039335 | 28 achtentwintigste verdieping | Model Group:NLRS_28.11_SF_handjes balkon 1-2_gen:14021257
14039337 | 28 achtentwintigste verdieping | Model Group:NLRS_28.11_SF_handjes balkon 1-2_gen:14021257
14039356 | 29 negenentwintigste verdieping | Model Group:NLRS_28.11_SF_handjes balkon 3-4_gen:14021317
14039358 | 29 negenentwintigste verdieping | Model Group:NLRS_28.11_SF_handjes balkon 3-4_gen:14021317
14039372 | 29 negenentwintigste verdieping | Model Group:NLRS_28.11_SF_handjes balkon 3-4_gen:14021335
14039374 | 29 negenentwintigste verdieping | Model Group:NLRS_28.11_SF_handjes balkon 3-4_gen:14021335
14039384 | 29 negenentwintigste verdieping | Model Group:NLRS_28.11_SF_handjes balkon 1-2_gen:14021308
14039386 | 29 negenentwintigste verdieping | Model Group:NLRS_28.11_SF_handjes balkon 1-2_gen:14021308
14039400 | 29 negenentwintigste verdieping | Model Group:NLRS_28.11_SF_handjes balkon 1-2_gen:14021326
14039402 | 29 negenentwintigste verdieping | Model Group:NLRS_28.11_SF_handjes balkon 1-2_gen:14021326
14039421 | 33 drieëndertigste verdieping | Model Group:NLRS_28.11_SF_handjes balkon 3-4_gen:14021386
14039423 | 33 drieëndertigste verdieping | Model Group:NLRS_28.11_SF_handjes balkon 3-4_gen:14021386
14039437 | 33 drieëndertigste verdieping | Model Group:NLRS_28.11_SF_handjes balkon 3-4_gen:14021404
14039439 | 33 drieëndertigste verdieping | Model Group:NLRS_28.11_SF_handjes balkon 3-4_gen:14021404
14039449 | 33 drieëndertigste verdieping | Model Group:NLRS_28.11_SF_handjes balkon 1-2_gen:14021377
14039451 | 33 drieëndertigste verdieping | Model Group:NLRS_28.11_SF_handjes balkon 1-2_gen:14021377
14039465 | 33 drieëndertigste verdieping | Model Group:NLRS_28.11_SF_handjes balkon 1-2_gen:14021395
14039467 | 33 drieëndertigste verdieping | Model Group:NLRS_28.11_SF_handjes balkon 1-2_gen:14021395
14039486 | 31 eenendertigste verdieping | Model Group:NLRS_28.11_SF_handjes balkon 3-4_gen:14021455
14039488 | 31 eenendertigste verdieping | Model Group:NLRS_28.11_SF_handjes balkon 3-4_gen:14021455
14039502 | 31 eenendertigste verdieping | Model Group:NLRS_28.11_SF_handjes balkon 3-4_gen:14021473
14039504 | 31 eenendertigste verdieping | Model Group:NLRS_28.11_SF_handjes balkon 3-4_gen:14021473
14039514 | 31 eenendertigste verdieping | Model Group:NLRS_28.11_SF_handjes balkon 1-2_gen:14021446
14039516 | 31 eenendertigste verdieping | Model Group:NLRS_28.11_SF_handjes balkon 1-2_gen:14021446
14039530 | 31 eenendertigste verdieping | Model Group:NLRS_28.11_SF_handjes balkon 1-2_gen:14021464
14039532 | 31 eenendertigste verdieping | Model Group:NLRS_28.11_SF_handjes balkon 1-2_gen:14021464
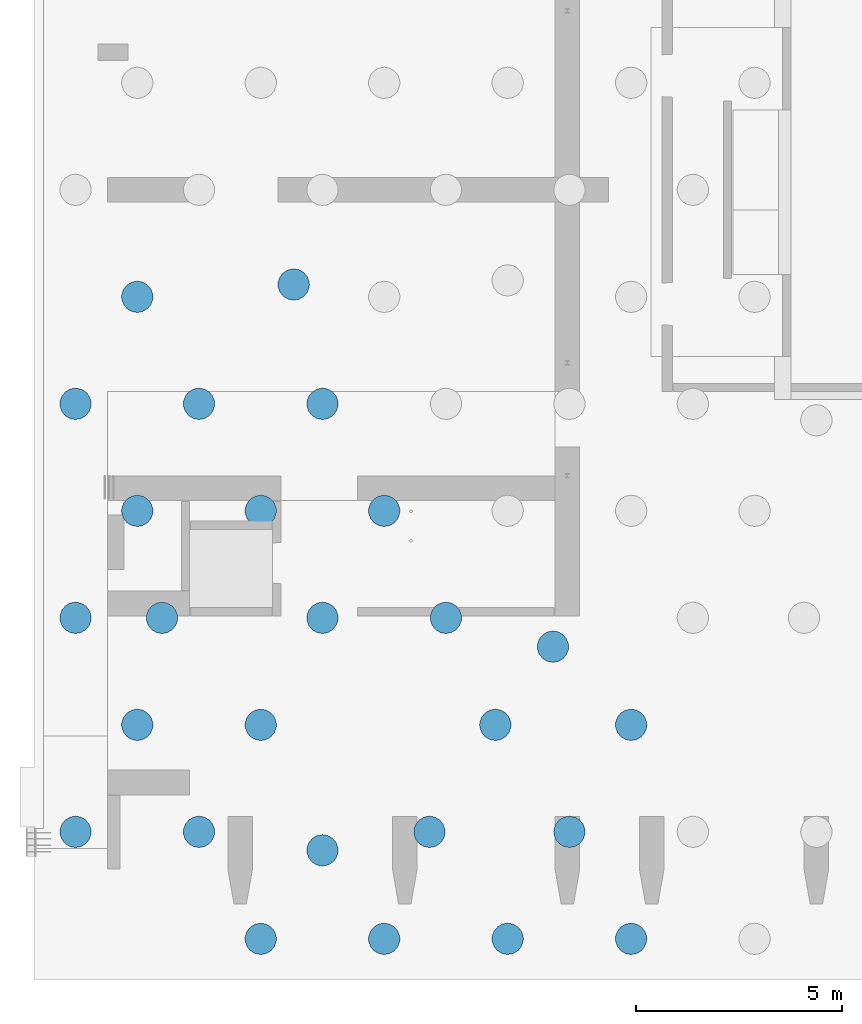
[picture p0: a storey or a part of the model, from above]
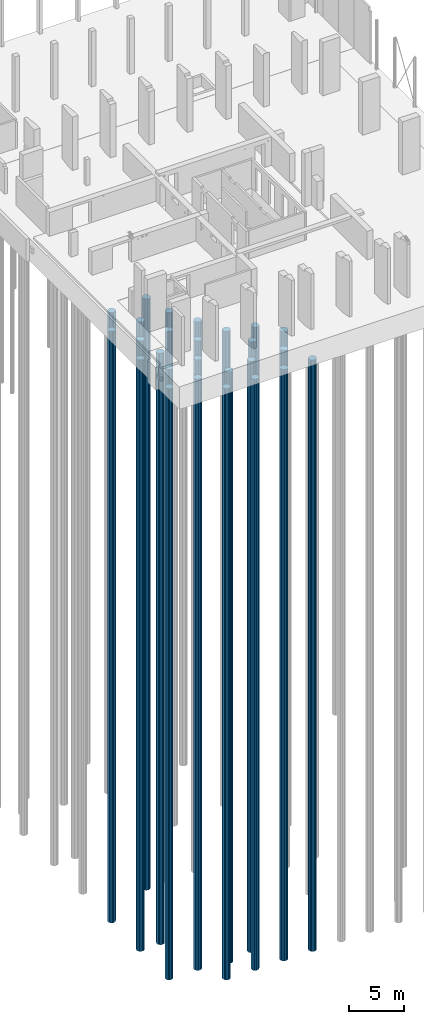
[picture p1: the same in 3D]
Properties of the parts of a building model (IFC2X3), part 4 of 21

# IfcBeam: NLRS_28.11_SF_WPB_stalen schoen 3_gen (346)
Name (NLRS_28.11_SF_WPB_stalen schoen 3_gen:NLRS_28.11_SF_WPB_stalen schoen 3_gen:...) | In | Group
14039551 | 32 tweeëndertigste verdieping | Model Group:NLRS_28.11_SF_handjes balkon 3-4_gen:14021524
14039553 | 32 tweeëndertigste verdieping | Model Group:NLRS_28.11_SF_handjes balkon 3-4_gen:14021524
14039567 | 32 tweeëndertigste verdieping | Model Group:NLRS_28.11_SF_handjes balkon 3-4_gen:14021542
14039569 | 32 tweeëndertigste verdieping | Model Group:NLRS_28.11_SF_handjes balkon 3-4_gen:14021542
14039579 | 32 tweeëndertigste verdieping | Model Group:NLRS_28.11_SF_handjes balkon 1-2_gen:14021515
14039581 | 32 tweeëndertigste verdieping | Model Group:NLRS_28.11_SF_handjes balkon 1-2_gen:14021515
14039595 | 32 tweeëndertigste verdieping | Model Group:NLRS_28.11_SF_handjes balkon 1-2_gen:14021533
14039597 | 32 tweeëndertigste verdieping | Model Group:NLRS_28.11_SF_handjes balkon 1-2_gen:14021533
14039616 | 34 vierendertigste verdieping | Model Group:NLRS_28.11_SF_handjes balkon 3-4_gen:14021593
14039618 | 34 vierendertigste verdieping | Model Group:NLRS_28.11_SF_handjes balkon 3-4_gen:14021593
14039632 | 34 vierendertigste verdieping | Model Group:NLRS_28.11_SF_handjes balkon 3-4_gen:14021611
14039634 | 34 vierendertigste verdieping | Model Group:NLRS_28.11_SF_handjes balkon 3-4_gen:14021611
14039644 | 34 vierendertigste verdieping | Model Group:NLRS_28.11_SF_handjes balkon 1-2_gen:14021584
14039646 | 34 vierendertigste verdieping | Model Group:NLRS_28.11_SF_handjes balkon 1-2_gen:14021584
14039660 | 34 vierendertigste verdieping | Model Group:NLRS_28.11_SF_handjes balkon 1-2_gen:14021602
14039662 | 34 vierendertigste verdieping | Model Group:NLRS_28.11_SF_handjes balkon 1-2_gen:14021602
14039681 | 35 vijfendertigste verdieping | Model Group:NLRS_28.11_SF_handjes balkon 3-4_gen:14021662
14039683 | 35 vijfendertigste verdieping | Model Group:NLRS_28.11_SF_handjes balkon 3-4_gen:14021662
14039697 | 35 vijfendertigste verdieping | Model Group:NLRS_28.11_SF_handjes balkon 3-4_gen:14021680
14039699 | 35 vijfendertigste verdieping | Model Group:NLRS_28.11_SF_handjes balkon 3-4_gen:14021680
14039709 | 35 vijfendertigste verdieping | Model Group:NLRS_28.11_SF_handjes balkon 1-2_gen:14021653
14039711 | 35 vijfendertigste verdieping | Model Group:NLRS_28.11_SF_handjes balkon 1-2_gen:14021653
14039725 | 35 vijfendertigste verdieping | Model Group:NLRS_28.11_SF_handjes balkon 1-2_gen:14021671
14039727 | 35 vijfendertigste verdieping | Model Group:NLRS_28.11_SF_handjes balkon 1-2_gen:14021671
14039746 | 27 zevenentwintigste verdieping | Model Group:NLRS_28.11_SF_handjes balkon 3-4_gen:14021731
14039748 | 27 zevenentwintigste verdieping | Model Group:NLRS_28.11_SF_handjes balkon 3-4_gen:14021731
14039762 | 27 zevenentwintigste verdieping | Model Group:NLRS_28.11_SF_handjes balkon 3-4_gen:14021749
14039764 | 27 zevenentwintigste verdieping | Model Group:NLRS_28.11_SF_handjes balkon 3-4_gen:14021749
14039774 | 27 zevenentwintigste verdieping | Model Group:NLRS_28.11_SF_handjes balkon 1-2_gen:14021722
14039776 | 27 zevenentwintigste verdieping | Model Group:NLRS_28.11_SF_handjes balkon 1-2_gen:14021722
14039790 | 27 zevenentwintigste verdieping | Model Group:NLRS_28.11_SF_handjes balkon 1-2_gen:14021740
14039792 | 27 zevenentwintigste verdieping | Model Group:NLRS_28.11_SF_handjes balkon 1-2_gen:14021740
14039811 | 38 achtendertigste verdieping | Model Group:NLRS_28.11_SF_handjes balkon 3-4_gen:14021800
14039813 | 38 achtendertigste verdieping | Model Group:NLRS_28.11_SF_handjes balkon 3-4_gen:14021800
14039827 | 38 achtendertigste verdieping | Model Group:NLRS_28.11_SF_handjes balkon 3-4_gen:14021818
14039829 | 38 achtendertigste verdieping | Model Group:NLRS_28.11_SF_handjes balkon 3-4_gen:14021818
14039839 | 38 achtendertigste verdieping | Model Group:NLRS_28.11_SF_handjes balkon 1-2_gen:14021791
14039841 | 38 achtendertigste verdieping | Model Group:NLRS_28.11_SF_handjes balkon 1-2_gen:14021791
14039855 | 38 achtendertigste verdieping | Model Group:NLRS_28.11_SF_handjes balkon 1-2_gen:14021809
14039857 | 38 achtendertigste verdieping | Model Group:NLRS_28.11_SF_handjes balkon 1-2_gen:14021809
14039876 | 39 negenendertigste verdieping | Model Group:NLRS_28.11_SF_handjes balkon 3-4_gen:14021869
14039878 | 39 negenendertigste verdieping | Model Group:NLRS_28.11_SF_handjes balkon 3-4_gen:14021869
14039892 | 39 negenendertigste verdieping | Model Group:NLRS_28.11_SF_handjes balkon 3-4_gen:14021887
14039894 | 39 negenendertigste verdieping | Model Group:NLRS_28.11_SF_handjes balkon 3-4_gen:14021887
14039904 | 39 negenendertigste verdieping | Model Group:NLRS_28.11_SF_handjes balkon 1-2_gen:14021860
14039906 | 39 negenendertigste verdieping | Model Group:NLRS_28.11_SF_handjes balkon 1-2_gen:14021860
14039920 | 39 negenendertigste verdieping | Model Group:NLRS_28.11_SF_handjes balkon 1-2_gen:14021878
14039922 | 39 negenendertigste verdieping | Model Group:NLRS_28.11_SF_handjes balkon 1-2_gen:14021878
14039941 | 36 zesendertigste verdieping | Model Group:NLRS_28.11_SF_handjes balkon 3-4_gen:14021938
14039943 | 36 zesendertigste verdieping | Model Group:NLRS_28.11_SF_handjes balkon 3-4_gen:14021938
14039957 | 36 zesendertigste verdieping | Model Group:NLRS_28.11_SF_handjes balkon 3-4_gen:14021956
14039959 | 36 zesendertigste verdieping | Model Group:NLRS_28.11_SF_handjes balkon 3-4_gen:14021956
14039969 | 36 zesendertigste verdieping | Model Group:NLRS_28.11_SF_handjes balkon 1-2_gen:14021929
14039971 | 36 zesendertigste verdieping | Model Group:NLRS_28.11_SF_handjes balkon 1-2_gen:14021929
14039985 | 36 zesendertigste verdieping | Model Group:NLRS_28.11_SF_handjes balkon 1-2_gen:14021947
14039987 | 36 zesendertigste verdieping | Model Group:NLRS_28.11_SF_handjes balkon 1-2_gen:14021947
14040006 | 37 zevenendertigste verdieping | Model Group:NLRS_28.11_SF_handjes balkon 3-4_gen:14022007
14040008 | 37 zevenendertigste verdieping | Model Group:NLRS_28.11_SF_handjes balkon 3-4_gen:14022007
14040022 | 37 zevenendertigste verdieping | Model Group:NLRS_28.11_SF_handjes balkon 3-4_gen:14022025
14040024 | 37 zevenendertigste verdieping | Model Group:NLRS_28.11_SF_handjes balkon 3-4_gen:14022025
14040034 | 37 zevenendertigste verdieping | Model Group:NLRS_28.11_SF_handjes balkon 1-2_gen:14021998
14040036 | 37 zevenendertigste verdieping | Model Group:NLRS_28.11_SF_handjes balkon 1-2_gen:14021998
14040050 | 37 zevenendertigste verdieping | Model Group:NLRS_28.11_SF_handjes balkon 1-2_gen:14022016
14040052 | 37 zevenendertigste verdieping | Model Group:NLRS_28.11_SF_handjes balkon 1-2_gen:14022016
14042928 | 41 eenenveertigste verdieping | Model Group:NLRS_28.11_SF_handjes balkon 3-4_gen:14018046
14042930 | 41 eenenveertigste verdieping | Model Group:NLRS_28.11_SF_handjes balkon 3-4_gen:14018046
14043001 | 41 eenenveertigste verdieping | Model Group:NLRS_28.11_SF_handjes balkon 1-2_gen:14018019
14043003 | 41 eenenveertigste verdieping | Model Group:NLRS_28.11_SF_handjes balkon 1-2_gen:14018019
14043068 | 41 eenenveertigste verdieping | Model Group:NLRS_28.11_SF_handjes balkon 3-4_gen:14018028
14043070 | 41 eenenveertigste verdieping | Model Group:NLRS_28.11_SF_handjes balkon 3-4_gen:14018028
14043127 | 41 eenenveertigste verdieping | Model Group:NLRS_28.11_SF_handjes balkon 1-2_gen:14018037
14043129 | 41 eenenveertigste verdieping | Model Group:NLRS_28.11_SF_handjes balkon 1-2_gen:14018037
14043245 | 51 eenenvijftigste verdieping | Model Group:NLRS_28.11_SF_handjes balkon 3-4_gen:14013044
14043247 | 51 eenenvijftigste verdieping | Model Group:NLRS_28.11_SF_handjes balkon 3-4_gen:14013044
14043262 | 51 eenenvijftigste verdieping | Model Group:NLRS_28.11_SF_handjes balkon 3-4_gen:14013062
14043264 | 51 eenenvijftigste verdieping | Model Group:NLRS_28.11_SF_handjes balkon 3-4_gen:14013062
14043408 | 51 eenenvijftigste verdieping | Model Group:NLRS_28.11_SF_handjes balkon 1-2_gen:14013035
14043410 | 51 eenenvijftigste verdieping | Model Group:NLRS_28.11_SF_handjes balkon 1-2_gen:14013035
14043425 | 51 eenenvijftigste verdieping | Model Group:NLRS_28.11_SF_handjes balkon 1-2_gen:14013053
14043427 | 51 eenenvijftigste verdieping | Model Group:NLRS_28.11_SF_handjes balkon 1-2_gen:14013053
14044708 | 42 tweeënveertigste verdieping | Model Group:NLRS_28.11_SF_handjes balkon 3-4_gen:14014629
14044710 | 42 tweeënveertigste verdieping | Model Group:NLRS_28.11_SF_handjes balkon 3-4_gen:14014629
14044724 | 42 tweeënveertigste verdieping | Model Group:NLRS_28.11_SF_handjes balkon 3-4_gen:14014647
14044726 | 42 tweeënveertigste verdieping | Model Group:NLRS_28.11_SF_handjes balkon 3-4_gen:14014647
14044736 | 42 tweeënveertigste verdieping | Model Group:NLRS_28.11_SF_handjes balkon 1-2_gen:14014620
14044738 | 42 tweeënveertigste verdieping | Model Group:NLRS_28.11_SF_handjes balkon 1-2_gen:14014620
14044752 | 42 tweeënveertigste verdieping | Model Group:NLRS_28.11_SF_handjes balkon 1-2_gen:14014638
14044754 | 42 tweeënveertigste verdieping | Model Group:NLRS_28.11_SF_handjes balkon 1-2_gen:14014638
14044838 | 47 zevenenveertigste verdieping | Model Group:NLRS_28.11_SF_handjes balkon 3-4_gen:14014801
14044840 | 47 zevenenveertigste verdieping | Model Group:NLRS_28.11_SF_handjes balkon 3-4_gen:14014801
14044854 | 47 zevenenveertigste verdieping | Model Group:NLRS_28.11_SF_handjes balkon 3-4_gen:14014819
14044856 | 47 zevenenveertigste verdieping | Model Group:NLRS_28.11_SF_handjes balkon 3-4_gen:14014819
14044866 | 47 zevenenveertigste verdieping | Model Group:NLRS_28.11_SF_handjes balkon 1-2_gen:14014792
14044868 | 47 zevenenveertigste verdieping | Model Group:NLRS_28.11_SF_handjes balkon 1-2_gen:14014792
14044882 | 47 zevenenveertigste verdieping | Model Group:NLRS_28.11_SF_handjes balkon 1-2_gen:14014810
14044884 | 47 zevenenveertigste verdieping | Model Group:NLRS_28.11_SF_handjes balkon 1-2_gen:14014810
14044903 | 50 vijftigste verdieping | Model Group:NLRS_28.11_SF_handjes balkon 3-4_gen:14014887
14044905 | 50 vijftigste verdieping | Model Group:NLRS_28.11_SF_handjes balkon 3-4_gen:14014887
14044919 | 50 vijftigste verdieping | Model Group:NLRS_28.11_SF_handjes balkon 3-4_gen:14014905
14044921 | 50 vijftigste verdieping | Model Group:NLRS_28.11_SF_handjes balkon 3-4_gen:14014905
14044931 | 50 vijftigste verdieping | Model Group:NLRS_28.11_SF_handjes balkon 1-2_gen:14014878
14044933 | 50 vijftigste verdieping | Model Group:NLRS_28.11_SF_handjes balkon 1-2_gen:14014878
14044947 | 50 vijftigste verdieping | Model Group:NLRS_28.11_SF_handjes balkon 1-2_gen:14014896
14044949 | 50 vijftigste verdieping | Model Group:NLRS_28.11_SF_handjes balkon 1-2_gen:14014896
14044968 | 43 drieënveertigste verdieping | Model Group:NLRS_28.11_SF_handjes balkon 3-4_gen:14014973
14044970 | 43 drieënveertigste verdieping | Model Group:NLRS_28.11_SF_handjes balkon 3-4_gen:14014973
14044984 | 43 drieënveertigste verdieping | Model Group:NLRS_28.11_SF_handjes balkon 3-4_gen:14014991
14044986 | 43 drieënveertigste verdieping | Model Group:NLRS_28.11_SF_handjes balkon 3-4_gen:14014991
14044996 | 43 drieënveertigste verdieping | Model Group:NLRS_28.11_SF_handjes balkon 1-2_gen:14014964
14044998 | 43 drieënveertigste verdieping | Model Group:NLRS_28.11_SF_handjes balkon 1-2_gen:14014964
14045012 | 43 drieënveertigste verdieping | Model Group:NLRS_28.11_SF_handjes balkon 1-2_gen:14014982
14045014 | 43 drieënveertigste verdieping | Model Group:NLRS_28.11_SF_handjes balkon 1-2_gen:14014982
14045033 | 44 vierenveertigste verdieping | Model Group:NLRS_28.11_SF_handjes balkon 3-4_gen:14015059
14045035 | 44 vierenveertigste verdieping | Model Group:NLRS_28.11_SF_handjes balkon 3-4_gen:14015059
14045049 | 44 vierenveertigste verdieping | Model Group:NLRS_28.11_SF_handjes balkon 3-4_gen:14015077
14045051 | 44 vierenveertigste verdieping | Model Group:NLRS_28.11_SF_handjes balkon 3-4_gen:14015077
14045061 | 44 vierenveertigste verdieping | Model Group:NLRS_28.11_SF_handjes balkon 1-2_gen:14015050
14045063 | 44 vierenveertigste verdieping | Model Group:NLRS_28.11_SF_handjes balkon 1-2_gen:14015050
14045077 | 44 vierenveertigste verdieping | Model Group:NLRS_28.11_SF_handjes balkon 1-2_gen:14015068
14045079 | 44 vierenveertigste verdieping | Model Group:NLRS_28.11_SF_handjes balkon 1-2_gen:14015068
14045098 | 45 vijfenveertigste verdieping | Model Group:NLRS_28.11_SF_handjes balkon 3-4_gen:14015145
14045100 | 45 vijfenveertigste verdieping | Model Group:NLRS_28.11_SF_handjes balkon 3-4_gen:14015145
14045114 | 45 vijfenveertigste verdieping | Model Group:NLRS_28.11_SF_handjes balkon 3-4_gen:14015163
14045116 | 45 vijfenveertigste verdieping | Model Group:NLRS_28.11_SF_handjes balkon 3-4_gen:14015163
14045126 | 45 vijfenveertigste verdieping | Model Group:NLRS_28.11_SF_handjes balkon 1-2_gen:14015136
14045128 | 45 vijfenveertigste verdieping | Model Group:NLRS_28.11_SF_handjes balkon 1-2_gen:14015136
14045142 | 45 vijfenveertigste verdieping | Model Group:NLRS_28.11_SF_handjes balkon 1-2_gen:14015154
14045144 | 45 vijfenveertigste verdieping | Model Group:NLRS_28.11_SF_handjes balkon 1-2_gen:14015154
14045163 | 46 zesenveertigste verdieping | Model Group:NLRS_28.11_SF_handjes balkon 3-4_gen:14015231
14045165 | 46 zesenveertigste verdieping | Model Group:NLRS_28.11_SF_handjes balkon 3-4_gen:14015231
14045179 | 46 zesenveertigste verdieping | Model Group:NLRS_28.11_SF_handjes balkon 3-4_gen:14015249
14045181 | 46 zesenveertigste verdieping | Model Group:NLRS_28.11_SF_handjes balkon 3-4_gen:14015249
14045191 | 46 zesenveertigste verdieping | Model Group:NLRS_28.11_SF_handjes balkon 1-2_gen:14015222
14045193 | 46 zesenveertigste verdieping | Model Group:NLRS_28.11_SF_handjes balkon 1-2_gen:14015222
14045207 | 46 zesenveertigste verdieping | Model Group:NLRS_28.11_SF_handjes balkon 1-2_gen:14015240
14045209 | 46 zesenveertigste verdieping | Model Group:NLRS_28.11_SF_handjes balkon 1-2_gen:14015240
14045228 | 49 negenenveertigste verdieping | Model Group:NLRS_28.11_SF_handjes balkon 3-4_gen:14015317
14045230 | 49 negenenveertigste verdieping | Model Group:NLRS_28.11_SF_handjes balkon 3-4_gen:14015317
14045244 | 49 negenenveertigste verdieping | Model Group:NLRS_28.11_SF_handjes balkon 3-4_gen:14015335
14045246 | 49 negenenveertigste verdieping | Model Group:NLRS_28.11_SF_handjes balkon 3-4_gen:14015335
14045256 | 49 negenenveertigste verdieping | Model Group:NLRS_28.11_SF_handjes balkon 1-2_gen:14015308
14045258 | 49 negenenveertigste verdieping | Model Group:NLRS_28.11_SF_handjes balkon 1-2_gen:14015308
14045272 | 49 negenenveertigste verdieping | Model Group:NLRS_28.11_SF_handjes balkon 1-2_gen:14015326
14045274 | 49 negenenveertigste verdieping | Model Group:NLRS_28.11_SF_handjes balkon 1-2_gen:14015326
14045293 | 48 achtenveertigste verdieping | Model Group:NLRS_28.11_SF_handjes balkon 3-4_gen:14015403
14045295 | 48 achtenveertigste verdieping | Model Group:NLRS_28.11_SF_handjes balkon 3-4_gen:14015403
14045309 | 48 achtenveertigste verdieping | Model Group:NLRS_28.11_SF_handjes balkon 3-4_gen:14015421
14045311 | 48 achtenveertigste verdieping | Model Group:NLRS_28.11_SF_handjes balkon 3-4_gen:14015421
14045321 | 48 achtenveertigste verdieping | Model Group:NLRS_28.11_SF_handjes balkon 1-2_gen:14015394
14045323 | 48 achtenveertigste verdieping | Model Group:NLRS_28.11_SF_handjes balkon 1-2_gen:14015394
14045337 | 48 achtenveertigste verdieping | Model Group:NLRS_28.11_SF_handjes balkon 1-2_gen:14015412
14045339 | 48 achtenveertigste verdieping | Model Group:NLRS_28.11_SF_handjes balkon 1-2_gen:14015412

# IfcBeam: NLRS_28.11_SF_WPB_stalen schoen 4_gen (346)
Type - ElementType: NLRS_28.11_SF_WPB_stalen schoen 4_gen; PredefinedType: BEAM; Material: NLRS_h2_staal
Pset_BeamCommon - LoadBearing: yes; IsExternal: no; Slope: 0 deg; Reference: NLRS_28.11_SF_WPB_stalen schoen 4_gen; Span: 210 mm
Name (NLRS_28.11_SF_WPB_stalen schoen 4_gen:NLRS_28.11_SF_WPB_stalen schoen 4_gen:...) | In | Group
13547780 | 16 zestiende verdieping | Model Group:NLRS_28.11_SF_handjes balkon 3-4_gen:9036916
13547784 | 16 zestiende verdieping | Model Group:NLRS_28.11_SF_handjes balkon 3-4_gen:9036917
13547788 | 15 vijftiende verdieping | Model Group:NLRS_28.11_SF_handjes balkon 3-4_gen:9050834
13547792 | 15 vijftiende verdieping | Model Group:NLRS_28.11_SF_handjes balkon 3-4_gen:9050835
13547796 | 17 zeventiende verdieping | Model Group:NLRS_28.11_SF_handjes balkon 3-4_gen:9051130
13547800 | 17 zeventiende verdieping | Model Group:NLRS_28.11_SF_handjes balkon 3-4_gen:9051131
13547804 | 18 achttiende verdieping | Model Group:NLRS_28.11_SF_handjes balkon 3-4_gen:9131781
13547808 | 18 achttiende verdieping | Model Group:NLRS_28.11_SF_handjes balkon 3-4_gen:9131782
13547948 | 10 tiende verdieping | Model Group:NLRS_28.11_SF_handjes balkon 3-4_gen:10618299
13547952 | 10 tiende verdieping | Model Group:NLRS_28.11_SF_handjes balkon 3-4_gen:10618300
13547956 | 12 twaalfde verdieping | Model Group:NLRS_28.11_SF_handjes balkon 3-4_gen:10620653
13547960 | 12 twaalfde verdieping | Model Group:NLRS_28.11_SF_handjes balkon 3-4_gen:10620654
13547964 | 14 veertiende verdieping | Model Group:NLRS_28.11_SF_handjes balkon 3-4_gen:10620785
13547968 | 14 veertiende verdieping | Model Group:NLRS_28.11_SF_handjes balkon 3-4_gen:10620786
13547972 | 20 twintigste verdieping | Model Group:NLRS_28.11_SF_handjes balkon 3-4_gen:10620917
13547976 | 20 twintigste verdieping | Model Group:NLRS_28.11_SF_handjes balkon 3-4_gen:10620918
13547980 | 11 elfde verdieping | Model Group:NLRS_28.11_SF_handjes balkon 3-4_gen:10622917
13547984 | 11 elfde verdieping | Model Group:NLRS_28.11_SF_handjes balkon 3-4_gen:10622918
13547988 | 13 dertiende verdieping | Model Group:NLRS_28.11_SF_handjes balkon 3-4_gen:10625084
13547992 | 13 dertiende verdieping | Model Group:NLRS_28.11_SF_handjes balkon 3-4_gen:10625085
13547996 | 19 negentiende verdieping | Model Group:NLRS_28.11_SF_handjes balkon 3-4_gen:10625216
13548000 | 19 negentiende verdieping | Model Group:NLRS_28.11_SF_handjes balkon 3-4_gen:10625217
13553042 | 16 zestiende verdieping | Model Group:NLRS_28.11_SF_handjes balkon 3-4_gen:9036916
13553049 | 16 zestiende verdieping | Model Group:NLRS_28.11_SF_handjes balkon 3-4_gen:9036917
13553056 | 15 vijftiende verdieping | Model Group:NLRS_28.11_SF_handjes balkon 3-4_gen:9050834
13553063 | 15 vijftiende verdieping | Model Group:NLRS_28.11_SF_handjes balkon 3-4_gen:9050835
13553070 | 17 zeventiende verdieping | Model Group:NLRS_28.11_SF_handjes balkon 3-4_gen:9051130
13553077 | 17 zeventiende verdieping | Model Group:NLRS_28.11_SF_handjes balkon 3-4_gen:9051131
13553084 | 18 achttiende verdieping | Model Group:NLRS_28.11_SF_handjes balkon 3-4_gen:9131781
13553091 | 18 achttiende verdieping | Model Group:NLRS_28.11_SF_handjes balkon 3-4_gen:9131782
13553336 | 10 tiende verdieping | Model Group:NLRS_28.11_SF_handjes balkon 3-4_gen:10618299
13553343 | 10 tiende verdieping | Model Group:NLRS_28.11_SF_handjes balkon 3-4_gen:10618300
13553350 | 12 twaalfde verdieping | Model Group:NLRS_28.11_SF_handjes balkon 3-4_gen:10620653
13553357 | 12 twaalfde verdieping | Model Group:NLRS_28.11_SF_handjes balkon 3-4_gen:10620654
13553364 | 14 veertiende verdieping | Model Group:NLRS_28.11_SF_handjes balkon 3-4_gen:10620785
13553371 | 14 veertiende verdieping | Model Group:NLRS_28.11_SF_handjes balkon 3-4_gen:10620786
13553378 | 20 twintigste verdieping | Model Group:NLRS_28.11_SF_handjes balkon 3-4_gen:10620917
13553385 | 20 twintigste verdieping | Model Group:NLRS_28.11_SF_handjes balkon 3-4_gen:10620918
13553392 | 11 elfde verdieping | Model Group:NLRS_28.11_SF_handjes balkon 3-4_gen:10622917
13553399 | 11 elfde verdieping | Model Group:NLRS_28.11_SF_handjes balkon 3-4_gen:10622918
13553406 | 13 dertiende verdieping | Model Group:NLRS_28.11_SF_handjes balkon 3-4_gen:10625084
13553413 | 13 dertiende verdieping | Model Group:NLRS_28.11_SF_handjes balkon 3-4_gen:10625085
13553420 | 19 negentiende verdieping | Model Group:NLRS_28.11_SF_handjes balkon 3-4_gen:10625216
13553427 | 19 negentiende verdieping | Model Group:NLRS_28.11_SF_handjes balkon 3-4_gen:10625217
13560664 | 16 zestiende verdieping | Model Group:NLRS_28.11_SF_handjes balkon 1-2_gen:9036911
13560666 | 16 zestiende verdieping | Model Group:NLRS_28.11_SF_handjes balkon 1-2_gen:9036911
13560673 | 16 zestiende verdieping | Model Group:NLRS_28.11_SF_handjes balkon 1-2_gen:9036924
13560675 | 16 zestiende verdieping | Model Group:NLRS_28.11_SF_handjes balkon 1-2_gen:9036924
13560682 | 15 vijftiende verdieping | Model Group:NLRS_28.11_SF_handjes balkon 1-2_gen:9050829
13560684 | 15 vijftiende verdieping | Model Group:NLRS_28.11_SF_handjes balkon 1-2_gen:9050829
13560691 | 15 vijftiende verdieping | Model Group:NLRS_28.11_SF_handjes balkon 1-2_gen:9050842
13560693 | 15 vijftiende verdieping | Model Group:NLRS_28.11_SF_handjes balkon 1-2_gen:9050842
13560700 | 17 zeventiende verdieping | Model Group:NLRS_28.11_SF_handjes balkon 1-2_gen:9051125
13560702 | 17 zeventiende verdieping | Model Group:NLRS_28.11_SF_handjes balkon 1-2_gen:9051125
13560709 | 17 zeventiende verdieping | Model Group:NLRS_28.11_SF_handjes balkon 1-2_gen:9051138
13560711 | 17 zeventiende verdieping | Model Group:NLRS_28.11_SF_handjes balkon 1-2_gen:9051138
13560718 | 18 achttiende verdieping | Model Group:NLRS_28.11_SF_handjes balkon 1-2_gen:9131776
13560720 | 18 achttiende verdieping | Model Group:NLRS_28.11_SF_handjes balkon 1-2_gen:9131776
13560727 | 18 achttiende verdieping | Model Group:NLRS_28.11_SF_handjes balkon 1-2_gen:9131789
13560729 | 18 achttiende verdieping | Model Group:NLRS_28.11_SF_handjes balkon 1-2_gen:9131789
13561042 | 10 tiende verdieping | Model Group:NLRS_28.11_SF_handjes balkon 1-2_gen:10618294
13561044 | 10 tiende verdieping | Model Group:NLRS_28.11_SF_handjes balkon 1-2_gen:10618294
13561051 | 10 tiende verdieping | Model Group:NLRS_28.11_SF_handjes balkon 1-2_gen:10618307
13561053 | 10 tiende verdieping | Model Group:NLRS_28.11_SF_handjes balkon 1-2_gen:10618307
13561060 | 12 twaalfde verdieping | Model Group:NLRS_28.11_SF_handjes balkon 1-2_gen:10620648
13561062 | 12 twaalfde verdieping | Model Group:NLRS_28.11_SF_handjes balkon 1-2_gen:10620648
13561069 | 12 twaalfde verdieping | Model Group:NLRS_28.11_SF_handjes balkon 1-2_gen:10620661
13561071 | 12 twaalfde verdieping | Model Group:NLRS_28.11_SF_handjes balkon 1-2_gen:10620661
13561078 | 14 veertiende verdieping | Model Group:NLRS_28.11_SF_handjes balkon 1-2_gen:10620780
13561080 | 14 veertiende verdieping | Model Group:NLRS_28.11_SF_handjes balkon 1-2_gen:10620780
13561087 | 14 veertiende verdieping | Model Group:NLRS_28.11_SF_handjes balkon 1-2_gen:10620793
13561089 | 14 veertiende verdieping | Model Group:NLRS_28.11_SF_handjes balkon 1-2_gen:10620793
13561096 | 20 twintigste verdieping | Model Group:NLRS_28.11_SF_handjes balkon 1-2_gen:10620912
13561098 | 20 twintigste verdieping | Model Group:NLRS_28.11_SF_handjes balkon 1-2_gen:10620912
13561105 | 20 twintigste verdieping | Model Group:NLRS_28.11_SF_handjes balkon 1-2_gen:10620925
13561107 | 20 twintigste verdieping | Model Group:NLRS_28.11_SF_handjes balkon 1-2_gen:10620925
13561114 | 11 elfde verdieping | Model Group:NLRS_28.11_SF_handjes balkon 1-2_gen:10622912
13561116 | 11 elfde verdieping | Model Group:NLRS_28.11_SF_handjes balkon 1-2_gen:10622912
13561123 | 11 elfde verdieping | Model Group:NLRS_28.11_SF_handjes balkon 1-2_gen:10622925
13561125 | 11 elfde verdieping | Model Group:NLRS_28.11_SF_handjes balkon 1-2_gen:10622925
13561132 | 13 dertiende verdieping | Model Group:NLRS_28.11_SF_handjes balkon 1-2_gen:10625079
13561134 | 13 dertiende verdieping | Model Group:NLRS_28.11_SF_handjes balkon 1-2_gen:10625079
13561141 | 13 dertiende verdieping | Model Group:NLRS_28.11_SF_handjes balkon 1-2_gen:10625092
13561143 | 13 dertiende verdieping | Model Group:NLRS_28.11_SF_handjes balkon 1-2_gen:10625092
13561150 | 19 negentiende verdieping | Model Group:NLRS_28.11_SF_handjes balkon 1-2_gen:10625211
13561152 | 19 negentiende verdieping | Model Group:NLRS_28.11_SF_handjes balkon 1-2_gen:10625211
13561159 | 19 negentiende verdieping | Model Group:NLRS_28.11_SF_handjes balkon 1-2_gen:10625224
13561161 | 19 negentiende verdieping | Model Group:NLRS_28.11_SF_handjes balkon 1-2_gen:10625224
13768625 | 52 tweeënvijftigste verdieping | Model Group:NLRS_28.11_SF_handjes balkon 1-2_52e verd_gen:13768620
13769757 | 52 tweeënvijftigste verdieping | Model Group:NLRS_28.11_SF_handjes balkon 3-4_52e verd_gen:13769752
13769759 | 52 tweeënvijftigste verdieping | Model Group:NLRS_28.11_SF_handjes balkon 3-4_52e verd_gen:13769752
13769979 | 52 tweeënvijftigste verdieping | Model Group:NLRS_28.11_SF_handjes balkon 1-2_52e verd_gen:13769974
13770124 | 52 tweeënvijftigste verdieping | Model Group:NLRS_28.11_SF_handjes balkon 3-4_52e verd_gen:13770119
13770126 | 52 tweeënvijftigste verdieping | Model Group:NLRS_28.11_SF_handjes balkon 3-4_52e verd_gen:13770119
13963813 | 53 drieënvijftigste verdieping | Model Group:NLRS_28.11_SF_handjes balkon 1-2_53e verd_gen:13907235
13963969 | 53 drieënvijftigste verdieping | Model Group:NLRS_28.11_SF_handjes balkon 1-2_53e verd_gen:13907244
13964400 | 53 drieënvijftigste verdieping | Model Group:NLRS_28.11_SF_handjes balkon 3-4_53e verd_gen:13907254
13964480 | 53 drieënvijftigste verdieping | Model Group:NLRS_28.11_SF_handjes balkon 3-4_53e verd_gen:13907245
14036853 | 21 eenentwintigste verdieping | Model Group:NLRS_28.11_SF_handjes balkon 1-2_gen:14026841
14036855 | 21 eenentwintigste verdieping | Model Group:NLRS_28.11_SF_handjes balkon 1-2_gen:14026841
14036966 | 21 eenentwintigste verdieping | Model Group:NLRS_28.11_SF_handjes balkon 3-4_gen:14026850
14036968 | 21 eenentwintigste verdieping | Model Group:NLRS_28.11_SF_handjes balkon 3-4_gen:14026850
14037027 | 21 eenentwintigste verdieping | Model Group:NLRS_28.11_SF_handjes balkon 1-2_gen:14026859
14037029 | 21 eenentwintigste verdieping | Model Group:NLRS_28.11_SF_handjes balkon 1-2_gen:14026859
14037092 | 21 eenentwintigste verdieping | Model Group:NLRS_28.11_SF_handjes balkon 3-4_gen:14026868
14037094 | 21 eenentwintigste verdieping | Model Group:NLRS_28.11_SF_handjes balkon 3-4_gen:14026868
14037292 | 40 veertigste verdieping | Model Group:NLRS_28.11_SF_handjes balkon 3-4_gen:14018324
14037294 | 40 veertigste verdieping | Model Group:NLRS_28.11_SF_handjes balkon 3-4_gen:14018324
14037309 | 40 veertigste verdieping | Model Group:NLRS_28.11_SF_handjes balkon 3-4_gen:14018342
14037311 | 40 veertigste verdieping | Model Group:NLRS_28.11_SF_handjes balkon 3-4_gen:14018342
14037407 | 40 veertigste verdieping | Model Group:NLRS_28.11_SF_handjes balkon 1-2_gen:14018315
14037409 | 40 veertigste verdieping | Model Group:NLRS_28.11_SF_handjes balkon 1-2_gen:14018315
14037424 | 40 veertigste verdieping | Model Group:NLRS_28.11_SF_handjes balkon 1-2_gen:14018333
14037426 | 40 veertigste verdieping | Model Group:NLRS_28.11_SF_handjes balkon 1-2_gen:14018333
14038897 | 22 tweeëntwintigste verdieping | Model Group:NLRS_28.11_SF_handjes balkon 3-4_gen:14020834
14038899 | 22 tweeëntwintigste verdieping | Model Group:NLRS_28.11_SF_handjes balkon 3-4_gen:14020834
14038913 | 22 tweeëntwintigste verdieping | Model Group:NLRS_28.11_SF_handjes balkon 3-4_gen:14020852
14038915 | 22 tweeëntwintigste verdieping | Model Group:NLRS_28.11_SF_handjes balkon 3-4_gen:14020852
14038925 | 22 tweeëntwintigste verdieping | Model Group:NLRS_28.11_SF_handjes balkon 1-2_gen:14020825
14038927 | 22 tweeëntwintigste verdieping | Model Group:NLRS_28.11_SF_handjes balkon 1-2_gen:14020825
14038941 | 22 tweeëntwintigste verdieping | Model Group:NLRS_28.11_SF_handjes balkon 1-2_gen:14020843
14038943 | 22 tweeëntwintigste verdieping | Model Group:NLRS_28.11_SF_handjes balkon 1-2_gen:14020843
14038962 | 24 vierentwintigste verdieping | Model Group:NLRS_28.11_SF_handjes balkon 3-4_gen:14020903
14038964 | 24 vierentwintigste verdieping | Model Group:NLRS_28.11_SF_handjes balkon 3-4_gen:14020903
14038978 | 24 vierentwintigste verdieping | Model Group:NLRS_28.11_SF_handjes balkon 3-4_gen:14020921
14038980 | 24 vierentwintigste verdieping | Model Group:NLRS_28.11_SF_handjes balkon 3-4_gen:14020921
14038990 | 24 vierentwintigste verdieping | Model Group:NLRS_28.11_SF_handjes balkon 1-2_gen:14020894
14038992 | 24 vierentwintigste verdieping | Model Group:NLRS_28.11_SF_handjes balkon 1-2_gen:14020894
14039006 | 24 vierentwintigste verdieping | Model Group:NLRS_28.11_SF_handjes balkon 1-2_gen:14020912
14039008 | 24 vierentwintigste verdieping | Model Group:NLRS_28.11_SF_handjes balkon 1-2_gen:14020912
14039027 | 25 vijfentwintigste verdieping | Model Group:NLRS_28.11_SF_handjes balkon 3-4_gen:14020972
14039029 | 25 vijfentwintigste verdieping | Model Group:NLRS_28.11_SF_handjes balkon 3-4_gen:14020972
14039043 | 25 vijfentwintigste verdieping | Model Group:NLRS_28.11_SF_handjes balkon 3-4_gen:14020990
14039045 | 25 vijfentwintigste verdieping | Model Group:NLRS_28.11_SF_handjes balkon 3-4_gen:14020990
14039055 | 25 vijfentwintigste verdieping | Model Group:NLRS_28.11_SF_handjes balkon 1-2_gen:14020963
14039057 | 25 vijfentwintigste verdieping | Model Group:NLRS_28.11_SF_handjes balkon 1-2_gen:14020963
14039071 | 25 vijfentwintigste verdieping | Model Group:NLRS_28.11_SF_handjes balkon 1-2_gen:14020981
14039073 | 25 vijfentwintigste verdieping | Model Group:NLRS_28.11_SF_handjes balkon 1-2_gen:14020981
14039092 | 26 zesentwintigste verdieping | Model Group:NLRS_28.11_SF_handjes balkon 3-4_gen:14021041
14039094 | 26 zesentwintigste verdieping | Model Group:NLRS_28.11_SF_handjes balkon 3-4_gen:14021041
14039108 | 26 zesentwintigste verdieping | Model Group:NLRS_28.11_SF_handjes balkon 3-4_gen:14021059
14039110 | 26 zesentwintigste verdieping | Model Group:NLRS_28.11_SF_handjes balkon 3-4_gen:14021059
14039120 | 26 zesentwintigste verdieping | Model Group:NLRS_28.11_SF_handjes balkon 1-2_gen:14021032
14039122 | 26 zesentwintigste verdieping | Model Group:NLRS_28.11_SF_handjes balkon 1-2_gen:14021032
14039136 | 26 zesentwintigste verdieping | Model Group:NLRS_28.11_SF_handjes balkon 1-2_gen:14021050
14039138 | 26 zesentwintigste verdieping | Model Group:NLRS_28.11_SF_handjes balkon 1-2_gen:14021050
14039157 | 30 dertigste verdieping | Model Group:NLRS_28.11_SF_handjes balkon 3-4_gen:14021110
14039159 | 30 dertigste verdieping | Model Group:NLRS_28.11_SF_handjes balkon 3-4_gen:14021110
14039173 | 30 dertigste verdieping | Model Group:NLRS_28.11_SF_handjes balkon 3-4_gen:14021128
14039175 | 30 dertigste verdieping | Model Group:NLRS_28.11_SF_handjes balkon 3-4_gen:14021128
14039185 | 30 dertigste verdieping | Model Group:NLRS_28.11_SF_handjes balkon 1-2_gen:14021101
14039187 | 30 dertigste verdieping | Model Group:NLRS_28.11_SF_handjes balkon 1-2_gen:14021101
14039201 | 30 dertigste verdieping | Model Group:NLRS_28.11_SF_handjes balkon 1-2_gen:14021119
14039203 | 30 dertigste verdieping | Model Group:NLRS_28.11_SF_handjes balkon 1-2_gen:14021119
14039222 | 23 drieëntwintigste verdieping | Model Group:NLRS_28.11_SF_handjes balkon 3-4_gen:14021179
14039224 | 23 drieëntwintigste verdieping | Model Group:NLRS_28.11_SF_handjes balkon 3-4_gen:14021179
14039238 | 23 drieëntwintigste verdieping | Model Group:NLRS_28.11_SF_handjes balkon 3-4_gen:14021197
14039240 | 23 drieëntwintigste verdieping | Model Group:NLRS_28.11_SF_handjes balkon 3-4_gen:14021197
14039250 | 23 drieëntwintigste verdieping | Model Group:NLRS_28.11_SF_handjes balkon 1-2_gen:14021170
14039252 | 23 drieëntwintigste verdieping | Model Group:NLRS_28.11_SF_handjes balkon 1-2_gen:14021170
14039266 | 23 drieëntwintigste verdieping | Model Group:NLRS_28.11_SF_handjes balkon 1-2_gen:14021188
14039268 | 23 drieëntwintigste verdieping | Model Group:NLRS_28.11_SF_handjes balkon 1-2_gen:14021188
14039287 | 28 achtentwintigste verdieping | Model Group:NLRS_28.11_SF_handjes balkon 3-4_gen:14021248
14039289 | 28 achtentwintigste verdieping | Model Group:NLRS_28.11_SF_handjes balkon 3-4_gen:14021248
14039303 | 28 achtentwintigste verdieping | Model Group:NLRS_28.11_SF_handjes balkon 3-4_gen:14021266
14039305 | 28 achtentwintigste verdieping | Model Group:NLRS_28.11_SF_handjes balkon 3-4_gen:14021266
14039315 | 28 achtentwintigste verdieping | Model Group:NLRS_28.11_SF_handjes balkon 1-2_gen:14021239
14039317 | 28 achtentwintigste verdieping | Model Group:NLRS_28.11_SF_handjes balkon 1-2_gen:14021239
14039331 | 28 achtentwintigste verdieping | Model Group:NLRS_28.11_SF_handjes balkon 1-2_gen:14021257
14039333 | 28 achtentwintigste verdieping | Model Group:NLRS_28.11_SF_handjes balkon 1-2_gen:14021257
14039352 | 29 negenentwintigste verdieping | Model Group:NLRS_28.11_SF_handjes balkon 3-4_gen:14021317
14039354 | 29 negenentwintigste verdieping | Model Group:NLRS_28.11_SF_handjes balkon 3-4_gen:14021317
14039368 | 29 negenentwintigste verdieping | Model Group:NLRS_28.11_SF_handjes balkon 3-4_gen:14021335
14039370 | 29 negenentwintigste verdieping | Model Group:NLRS_28.11_SF_handjes balkon 3-4_gen:14021335
14039380 | 29 negenentwintigste verdieping | Model Group:NLRS_28.11_SF_handjes balkon 1-2_gen:14021308
14039382 | 29 negenentwintigste verdieping | Model Group:NLRS_28.11_SF_handjes balkon 1-2_gen:14021308
14039396 | 29 negenentwintigste verdieping | Model Group:NLRS_28.11_SF_handjes balkon 1-2_gen:14021326
14039398 | 29 negenentwintigste verdieping | Model Group:NLRS_28.11_SF_handjes balkon 1-2_gen:14021326
14039417 | 33 drieëndertigste verdieping | Model Group:NLRS_28.11_SF_handjes balkon 3-4_gen:14021386
14039419 | 33 drieëndertigste verdieping | Model Group:NLRS_28.11_SF_handjes balkon 3-4_gen:14021386
14039433 | 33 drieëndertigste verdieping | Model Group:NLRS_28.11_SF_handjes balkon 3-4_gen:14021404
14039435 | 33 drieëndertigste verdieping | Model Group:NLRS_28.11_SF_handjes balkon 3-4_gen:14021404
14039445 | 33 drieëndertigste verdieping | Model Group:NLRS_28.11_SF_handjes balkon 1-2_gen:14021377
14039447 | 33 drieëndertigste verdieping | Model Group:NLRS_28.11_SF_handjes balkon 1-2_gen:14021377
14039461 | 33 drieëndertigste verdieping | Model Group:NLRS_28.11_SF_handjes balkon 1-2_gen:14021395
14039463 | 33 drieëndertigste verdieping | Model Group:NLRS_28.11_SF_handjes balkon 1-2_gen:14021395
14039482 | 31 eenendertigste verdieping | Model Group:NLRS_28.11_SF_handjes balkon 3-4_gen:14021455
14039484 | 31 eenendertigste verdieping | Model Group:NLRS_28.11_SF_handjes balkon 3-4_gen:14021455
14039498 | 31 eenendertigste verdieping | Model Group:NLRS_28.11_SF_handjes balkon 3-4_gen:14021473
14039500 | 31 eenendertigste verdieping | Model Group:NLRS_28.11_SF_handjes balkon 3-4_gen:14021473
14039510 | 31 eenendertigste verdieping | Model Group:NLRS_28.11_SF_handjes balkon 1-2_gen:14021446
14039512 | 31 eenendertigste verdieping | Model Group:NLRS_28.11_SF_handjes balkon 1-2_gen:14021446
14039526 | 31 eenendertigste verdieping | Model Group:NLRS_28.11_SF_handjes balkon 1-2_gen:14021464
14039528 | 31 eenendertigste verdieping | Model Group:NLRS_28.11_SF_handjes balkon 1-2_gen:14021464
14039547 | 32 tweeëndertigste verdieping | Model Group:NLRS_28.11_SF_handjes balkon 3-4_gen:14021524
14039549 | 32 tweeëndertigste verdieping | Model Group:NLRS_28.11_SF_handjes balkon 3-4_gen:14021524
14039563 | 32 tweeëndertigste verdieping | Model Group:NLRS_28.11_SF_handjes balkon 3-4_gen:14021542
14039565 | 32 tweeëndertigste verdieping | Model Group:NLRS_28.11_SF_handjes balkon 3-4_gen:14021542
14039575 | 32 tweeëndertigste verdieping | Model Group:NLRS_28.11_SF_handjes balkon 1-2_gen:14021515
14039577 | 32 tweeëndertigste verdieping | Model Group:NLRS_28.11_SF_handjes balkon 1-2_gen:14021515
14039591 | 32 tweeëndertigste verdieping | Model Group:NLRS_28.11_SF_handjes balkon 1-2_gen:14021533
14039593 | 32 tweeëndertigste verdieping | Model Group:NLRS_28.11_SF_handjes balkon 1-2_gen:14021533
14039612 | 34 vierendertigste verdieping | Model Group:NLRS_28.11_SF_handjes balkon 3-4_gen:14021593
14039614 | 34 vierendertigste verdieping | Model Group:NLRS_28.11_SF_handjes balkon 3-4_gen:14021593
14039628 | 34 vierendertigste verdieping | Model Group:NLRS_28.11_SF_handjes balkon 3-4_gen:14021611
14039630 | 34 vierendertigste verdieping | Model Group:NLRS_28.11_SF_handjes balkon 3-4_gen:14021611
14039640 | 34 vierendertigste verdieping | Model Group:NLRS_28.11_SF_handjes balkon 1-2_gen:14021584
14039642 | 34 vierendertigste verdieping | Model Group:NLRS_28.11_SF_handjes balkon 1-2_gen:14021584
14039656 | 34 vierendertigste verdieping | Model Group:NLRS_28.11_SF_handjes balkon 1-2_gen:14021602
14039658 | 34 vierendertigste verdieping | Model Group:NLRS_28.11_SF_handjes balkon 1-2_gen:14021602
14039677 | 35 vijfendertigste verdieping | Model Group:NLRS_28.11_SF_handjes balkon 3-4_gen:14021662
14039679 | 35 vijfendertigste verdieping | Model Group:NLRS_28.11_SF_handjes balkon 3-4_gen:14021662
14039693 | 35 vijfendertigste verdieping | Model Group:NLRS_28.11_SF_handjes balkon 3-4_gen:14021680
14039695 | 35 vijfendertigste verdieping | Model Group:NLRS_28.11_SF_handjes balkon 3-4_gen:14021680
14039705 | 35 vijfendertigste verdieping | Model Group:NLRS_28.11_SF_handjes balkon 1-2_gen:14021653
14039707 | 35 vijfendertigste verdieping | Model Group:NLRS_28.11_SF_handjes balkon 1-2_gen:14021653
14039721 | 35 vijfendertigste verdieping | Model Group:NLRS_28.11_SF_handjes balkon 1-2_gen:14021671
14039723 | 35 vijfendertigste verdieping | Model Group:NLRS_28.11_SF_handjes balkon 1-2_gen:14021671
14039742 | 27 zevenentwintigste verdieping | Model Group:NLRS_28.11_SF_handjes balkon 3-4_gen:14021731
14039744 | 27 zevenentwintigste verdieping | Model Group:NLRS_28.11_SF_handjes balkon 3-4_gen:14021731
14039758 | 27 zevenentwintigste verdieping | Model Group:NLRS_28.11_SF_handjes balkon 3-4_gen:14021749
14039760 | 27 zevenentwintigste verdieping | Model Group:NLRS_28.11_SF_handjes balkon 3-4_gen:14021749
14039770 | 27 zevenentwintigste verdieping | Model Group:NLRS_28.11_SF_handjes balkon 1-2_gen:14021722
14039772 | 27 zevenentwintigste verdieping | Model Group:NLRS_28.11_SF_handjes balkon 1-2_gen:14021722
14039786 | 27 zevenentwintigste verdieping | Model Group:NLRS_28.11_SF_handjes balkon 1-2_gen:14021740
14039788 | 27 zevenentwintigste verdieping | Model Group:NLRS_28.11_SF_handjes balkon 1-2_gen:14021740
14039807 | 38 achtendertigste verdieping | Model Group:NLRS_28.11_SF_handjes balkon 3-4_gen:14021800
14039809 | 38 achtendertigste verdieping | Model Group:NLRS_28.11_SF_handjes balkon 3-4_gen:14021800
14039823 | 38 achtendertigste verdieping | Model Group:NLRS_28.11_SF_handjes balkon 3-4_gen:14021818
14039825 | 38 achtendertigste verdieping | Model Group:NLRS_28.11_SF_handjes balkon 3-4_gen:14021818
14039835 | 38 achtendertigste verdieping | Model Group:NLRS_28.11_SF_handjes balkon 1-2_gen:14021791
14039837 | 38 achtendertigste verdieping | Model Group:NLRS_28.11_SF_handjes balkon 1-2_gen:14021791
14039851 | 38 achtendertigste verdieping | Model Group:NLRS_28.11_SF_handjes balkon 1-2_gen:14021809
14039853 | 38 achtendertigste verdieping | Model Group:NLRS_28.11_SF_handjes balkon 1-2_gen:14021809
14039872 | 39 negenendertigste verdieping | Model Group:NLRS_28.11_SF_handjes balkon 3-4_gen:14021869
14039874 | 39 negenendertigste verdieping | Model Group:NLRS_28.11_SF_handjes balkon 3-4_gen:14021869
14039888 | 39 negenendertigste verdieping | Model Group:NLRS_28.11_SF_handjes balkon 3-4_gen:14021887
14039890 | 39 negenendertigste verdieping | Model Group:NLRS_28.11_SF_handjes balkon 3-4_gen:14021887
14039900 | 39 negenendertigste verdieping | Model Group:NLRS_28.11_SF_handjes balkon 1-2_gen:14021860
14039902 | 39 negenendertigste verdieping | Model Group:NLRS_28.11_SF_handjes balkon 1-2_gen:14021860
14039916 | 39 negenendertigste verdieping | Model Group:NLRS_28.11_SF_handjes balkon 1-2_gen:14021878
14039918 | 39 negenendertigste verdieping | Model Group:NLRS_28.11_SF_handjes balkon 1-2_gen:14021878
14039937 | 36 zesendertigste verdieping | Model Group:NLRS_28.11_SF_handjes balkon 3-4_gen:14021938
14039939 | 36 zesendertigste verdieping | Model Group:NLRS_28.11_SF_handjes balkon 3-4_gen:14021938
14039953 | 36 zesendertigste verdieping | Model Group:NLRS_28.11_SF_handjes balkon 3-4_gen:14021956
14039955 | 36 zesendertigste verdieping | Model Group:NLRS_28.11_SF_handjes balkon 3-4_gen:14021956
14039965 | 36 zesendertigste verdieping | Model Group:NLRS_28.11_SF_handjes balkon 1-2_gen:14021929
14039967 | 36 zesendertigste verdieping | Model Group:NLRS_28.11_SF_handjes balkon 1-2_gen:14021929
14039981 | 36 zesendertigste verdieping | Model Group:NLRS_28.11_SF_handjes balkon 1-2_gen:14021947
14039983 | 36 zesendertigste verdieping | Model Group:NLRS_28.11_SF_handjes balkon 1-2_gen:14021947
14040002 | 37 zevenendertigste verdieping | Model Group:NLRS_28.11_SF_handjes balkon 3-4_gen:14022007
14040004 | 37 zevenendertigste verdieping | Model Group:NLRS_28.11_SF_handjes balkon 3-4_gen:14022007
14040018 | 37 zevenendertigste verdieping | Model Group:NLRS_28.11_SF_handjes balkon 3-4_gen:14022025
14040020 | 37 zevenendertigste verdieping | Model Group:NLRS_28.11_SF_handjes balkon 3-4_gen:14022025
14040030 | 37 zevenendertigste verdieping | Model Group:NLRS_28.11_SF_handjes balkon 1-2_gen:14021998
14040032 | 37 zevenendertigste verdieping | Model Group:NLRS_28.11_SF_handjes balkon 1-2_gen:14021998
14040046 | 37 zevenendertigste verdieping | Model Group:NLRS_28.11_SF_handjes balkon 1-2_gen:14022016
14040048 | 37 zevenendertigste verdieping | Model Group:NLRS_28.11_SF_handjes balkon 1-2_gen:14022016
14042924 | 41 eenenveertigste verdieping | Model Group:NLRS_28.11_SF_handjes balkon 3-4_gen:14018046
14042926 | 41 eenenveertigste verdieping | Model Group:NLRS_28.11_SF_handjes balkon 3-4_gen:14018046
14042997 | 41 eenenveertigste verdieping | Model Group:NLRS_28.11_SF_handjes balkon 1-2_gen:14018019
14042999 | 41 eenenveertigste verdieping | Model Group:NLRS_28.11_SF_handjes balkon 1-2_gen:14018019
14043064 | 41 eenenveertigste verdieping | Model Group:NLRS_28.11_SF_handjes balkon 3-4_gen:14018028
14043066 | 41 eenenveertigste verdieping | Model Group:NLRS_28.11_SF_handjes balkon 3-4_gen:14018028
14043123 | 41 eenenveertigste verdieping | Model Group:NLRS_28.11_SF_handjes balkon 1-2_gen:14018037
14043125 | 41 eenenveertigste verdieping | Model Group:NLRS_28.11_SF_handjes balkon 1-2_gen:14018037
14043241 | 51 eenenvijftigste verdieping | Model Group:NLRS_28.11_SF_handjes balkon 3-4_gen:14013044
14043243 | 51 eenenvijftigste verdieping | Model Group:NLRS_28.11_SF_handjes balkon 3-4_gen:14013044
14043258 | 51 eenenvijftigste verdieping | Model Group:NLRS_28.11_SF_handjes balkon 3-4_gen:14013062
14043260 | 51 eenenvijftigste verdieping | Model Group:NLRS_28.11_SF_handjes balkon 3-4_gen:14013062
14043404 | 51 eenenvijftigste verdieping | Model Group:NLRS_28.11_SF_handjes balkon 1-2_gen:14013035
14043406 | 51 eenenvijftigste verdieping | Model Group:NLRS_28.11_SF_handjes balkon 1-2_gen:14013035
14043421 | 51 eenenvijftigste verdieping | Model Group:NLRS_28.11_SF_handjes balkon 1-2_gen:14013053
14043423 | 51 eenenvijftigste verdieping | Model Group:NLRS_28.11_SF_handjes balkon 1-2_gen:14013053
14044704 | 42 tweeënveertigste verdieping | Model Group:NLRS_28.11_SF_handjes balkon 3-4_gen:14014629
14044706 | 42 tweeënveertigste verdieping | Model Group:NLRS_28.11_SF_handjes balkon 3-4_gen:14014629
14044720 | 42 tweeënveertigste verdieping | Model Group:NLRS_28.11_SF_handjes balkon 3-4_gen:14014647
14044722 | 42 tweeënveertigste verdieping | Model Group:NLRS_28.11_SF_handjes balkon 3-4_gen:14014647
14044732 | 42 tweeënveertigste verdieping | Model Group:NLRS_28.11_SF_handjes balkon 1-2_gen:14014620
14044734 | 42 tweeënveertigste verdieping | Model Group:NLRS_28.11_SF_handjes balkon 1-2_gen:14014620
14044748 | 42 tweeënveertigste verdieping | Model Group:NLRS_28.11_SF_handjes balkon 1-2_gen:14014638
14044750 | 42 tweeënveertigste verdieping | Model Group:NLRS_28.11_SF_handjes balkon 1-2_gen:14014638
14044834 | 47 zevenenveertigste verdieping | Model Group:NLRS_28.11_SF_handjes balkon 3-4_gen:14014801
14044836 | 47 zevenenveertigste verdieping | Model Group:NLRS_28.11_SF_handjes balkon 3-4_gen:14014801
14044850 | 47 zevenenveertigste verdieping | Model Group:NLRS_28.11_SF_handjes balkon 3-4_gen:14014819
14044852 | 47 zevenenveertigste verdieping | Model Group:NLRS_28.11_SF_handjes balkon 3-4_gen:14014819
14044862 | 47 zevenenveertigste verdieping | Model Group:NLRS_28.11_SF_handjes balkon 1-2_gen:14014792
14044864 | 47 zevenenveertigste verdieping | Model Group:NLRS_28.11_SF_handjes balkon 1-2_gen:14014792
14044878 | 47 zevenenveertigste verdieping | Model Group:NLRS_28.11_SF_handjes balkon 1-2_gen:14014810
14044880 | 47 zevenenveertigste verdieping | Model Group:NLRS_28.11_SF_handjes balkon 1-2_gen:14014810
14044899 | 50 vijftigste verdieping | Model Group:NLRS_28.11_SF_handjes balkon 3-4_gen:14014887
14044901 | 50 vijftigste verdieping | Model Group:NLRS_28.11_SF_handjes balkon 3-4_gen:14014887
14044915 | 50 vijftigste verdieping | Model Group:NLRS_28.11_SF_handjes balkon 3-4_gen:14014905
14044917 | 50 vijftigste verdieping | Model Group:NLRS_28.11_SF_handjes balkon 3-4_gen:14014905
14044927 | 50 vijftigste verdieping | Model Group:NLRS_28.11_SF_handjes balkon 1-2_gen:14014878
14044929 | 50 vijftigste verdieping | Model Group:NLRS_28.11_SF_handjes balkon 1-2_gen:14014878
14044943 | 50 vijftigste verdieping | Model Group:NLRS_28.11_SF_handjes balkon 1-2_gen:14014896
14044945 | 50 vijftigste verdieping | Model Group:NLRS_28.11_SF_handjes balkon 1-2_gen:14014896
14044964 | 43 drieënveertigste verdieping | Model Group:NLRS_28.11_SF_handjes balkon 3-4_gen:14014973
14044966 | 43 drieënveertigste verdieping | Model Group:NLRS_28.11_SF_handjes balkon 3-4_gen:14014973
14044980 | 43 drieënveertigste verdieping | Model Group:NLRS_28.11_SF_handjes balkon 3-4_gen:14014991
14044982 | 43 drieënveertigste verdieping | Model Group:NLRS_28.11_SF_handjes balkon 3-4_gen:14014991
14044992 | 43 drieënveertigste verdieping | Model Group:NLRS_28.11_SF_handjes balkon 1-2_gen:14014964
14044994 | 43 drieënveertigste verdieping | Model Group:NLRS_28.11_SF_handjes balkon 1-2_gen:14014964
14045008 | 43 drieënveertigste verdieping | Model Group:NLRS_28.11_SF_handjes balkon 1-2_gen:14014982
14045010 | 43 drieënveertigste verdieping | Model Group:NLRS_28.11_SF_handjes balkon 1-2_gen:14014982
14045029 | 44 vierenveertigste verdieping | Model Group:NLRS_28.11_SF_handjes balkon 3-4_gen:14015059
14045031 | 44 vierenveertigste verdieping | Model Group:NLRS_28.11_SF_handjes balkon 3-4_gen:14015059
14045045 | 44 vierenveertigste verdieping | Model Group:NLRS_28.11_SF_handjes balkon 3-4_gen:14015077
14045047 | 44 vierenveertigste verdieping | Model Group:NLRS_28.11_SF_handjes balkon 3-4_gen:14015077
14045057 | 44 vierenveertigste verdieping | Model Group:NLRS_28.11_SF_handjes balkon 1-2_gen:14015050
14045059 | 44 vierenveertigste verdieping | Model Group:NLRS_28.11_SF_handjes balkon 1-2_gen:14015050
14045073 | 44 vierenveertigste verdieping | Model Group:NLRS_28.11_SF_handjes balkon 1-2_gen:14015068
14045075 | 44 vierenveertigste verdieping | Model Group:NLRS_28.11_SF_handjes balkon 1-2_gen:14015068
14045094 | 45 vijfenveertigste verdieping | Model Group:NLRS_28.11_SF_handjes balkon 3-4_gen:14015145
14045096 | 45 vijfenveertigste verdieping | Model Group:NLRS_28.11_SF_handjes balkon 3-4_gen:14015145
14045110 | 45 vijfenveertigste verdieping | Model Group:NLRS_28.11_SF_handjes balkon 3-4_gen:14015163
14045112 | 45 vijfenveertigste verdieping | Model Group:NLRS_28.11_SF_handjes balkon 3-4_gen:14015163
14045122 | 45 vijfenveertigste verdieping | Model Group:NLRS_28.11_SF_handjes balkon 1-2_gen:14015136
14045124 | 45 vijfenveertigste verdieping | Model Group:NLRS_28.11_SF_handjes balkon 1-2_gen:14015136
14045138 | 45 vijfenveertigste verdieping | Model Group:NLRS_28.11_SF_handjes balkon 1-2_gen:14015154
14045140 | 45 vijfenveertigste verdieping | Model Group:NLRS_28.11_SF_handjes balkon 1-2_gen:14015154
14045159 | 46 zesenveertigste verdieping | Model Group:NLRS_28.11_SF_handjes balkon 3-4_gen:14015231
14045161 | 46 zesenveertigste verdieping | Model Group:NLRS_28.11_SF_handjes balkon 3-4_gen:14015231
14045175 | 46 zesenveertigste verdieping | Model Group:NLRS_28.11_SF_handjes balkon 3-4_gen:14015249
14045177 | 46 zesenveertigste verdieping | Model Group:NLRS_28.11_SF_handjes balkon 3-4_gen:14015249
14045187 | 46 zesenveertigste verdieping | Model Group:NLRS_28.11_SF_handjes balkon 1-2_gen:14015222
14045189 | 46 zesenveertigste verdieping | Model Group:NLRS_28.11_SF_handjes balkon 1-2_gen:14015222
14045203 | 46 zesenveertigste verdieping | Model Group:NLRS_28.11_SF_handjes balkon 1-2_gen:14015240
14045205 | 46 zesenveertigste verdieping | Model Group:NLRS_28.11_SF_handjes balkon 1-2_gen:14015240
14045224 | 49 negenenveertigste verdieping | Model Group:NLRS_28.11_SF_handjes balkon 3-4_gen:14015317
14045226 | 49 negenenveertigste verdieping | Model Group:NLRS_28.11_SF_handjes balkon 3-4_gen:14015317
14045240 | 49 negenenveertigste verdieping | Model Group:NLRS_28.11_SF_handjes balkon 3-4_gen:14015335
14045242 | 49 negenenveertigste verdieping | Model Group:NLRS_28.11_SF_handjes balkon 3-4_gen:14015335
14045252 | 49 negenenveertigste verdieping | Model Group:NLRS_28.11_SF_handjes balkon 1-2_gen:14015308
14045254 | 49 negenenveertigste verdieping | Model Group:NLRS_28.11_SF_handjes balkon 1-2_gen:14015308
14045268 | 49 negenenveertigste verdieping | Model Group:NLRS_28.11_SF_handjes balkon 1-2_gen:14015326
14045270 | 49 negenenveertigste verdieping | Model Group:NLRS_28.11_SF_handjes balkon 1-2_gen:14015326
14045289 | 48 achtenveertigste verdieping | Model Group:NLRS_28.11_SF_handjes balkon 3-4_gen:14015403
14045291 | 48 achtenveertigste verdieping | Model Group:NLRS_28.11_SF_handjes balkon 3-4_gen:14015403
14045305 | 48 achtenveertigste verdieping | Model Group:NLRS_28.11_SF_handjes balkon 3-4_gen:14015421
14045307 | 48 achtenveertigste verdieping | Model Group:NLRS_28.11_SF_handjes balkon 3-4_gen:14015421
14045317 | 48 achtenveertigste verdieping | Model Group:NLRS_28.11_SF_handjes balkon 1-2_gen:14015394
14045319 | 48 achtenveertigste verdieping | Model Group:NLRS_28.11_SF_handjes balkon 1-2_gen:14015394
14045333 | 48 achtenveertigste verdieping | Model Group:NLRS_28.11_SF_handjes balkon 1-2_gen:14015412
14045335 | 48 achtenveertigste verdieping | Model Group:NLRS_28.11_SF_handjes balkon 1-2_gen:14015412

# IfcBeam: NLRS_28.11_SF_WPB_stalen schoen 7_gen (4)
In: 52 tweeënvijftigste verdieping
Type - ElementType: NLRS_28.11_SF_WPB_stalen schoen 7_gen; PredefinedType: BEAM; Material: NLRS_h2_staal
Pset_BeamCommon - LoadBearing: yes; IsExternal: no; Slope: 0 deg; Reference: NLRS_28.11_SF_WPB_stalen schoen 7_gen; Span: 210 mm
Name (NLRS_28.11_SF_WPB_stalen schoen 7_gen:NLRS_28.11_SF_WPB_stalen schoen 7_gen:...) | Group
14129306 | Model Group:NLRS_28.11_SF_handjes balkon 1-2_52e verd_gen:13769974
14134391 | Model Group:NLRS_28.11_SF_handjes balkon 1-2_52e verd_gen:13768620
14134451 | Model Group:NLRS_28.11_SF_handjes balkon 1-2_52e verd_gen:13769974
14134571 | Model Group:NLRS_28.11_SF_handjes balkon 1-2_52e verd_gen:13768620

# IfcBeam: ligger HEB 400 (8)
In: 03 derde verdieping
Type - ElementType: ligger HEB 400; PredefinedType: BEAM; Classification: 28.11 hoofddraagconstructies - kolommen en liggers, kolom-/liggerconstructies (Uniformat); Material: NLRS_h2_staal
Pset_BeamCommon - IsExternal: yes; LoadBearing: yes; Slope: 0 deg; Reference: ligger HEB 400; Span: 10100 mm
Name (NLRS_28.11_SF_WPB_stalen ligger HEB met stripstaal_gen:ligger HEB 400:...)
4890990
4891275
4891304
4891333
4891364
4891400
4891433
4891527

# IfcBeam: ligger SFB190 HE200A+300x10 (2)
In: 05 vijfde verdieping
Type - ElementType: ligger SFB190 HE200A+300x10; PredefinedType: BEAM; Classification: 28.11 hoofddraagconstructies - kolommen en liggers, kolom-/liggerconstructies (Uniformat); Material: NLRS_h2_staal
Pset_BeamCommon - IsExternal: yes; LoadBearing: yes; Slope: 0 deg; Reference: ligger SFB190 HE200A+300x10; Span: 28300 mm
Name (NLRS_28.11_SF_WPB_stalen ligger SFB_gen_BSc:ligger SFB190 HE200A+300x10:...)
4892080
4897607

# IfcBeam: ligger SFB250 HE260A+355x12 (2)
Type - ElementType: ligger SFB250 HE260A+355x12; PredefinedType: BEAM; Classification: 28.11 hoofddraagconstructies - kolommen en liggers, kolom-/liggerconstructies (Uniformat); Material: NLRS_h2_staal
Pset_BeamCommon - IsExternal: yes; LoadBearing: yes; Slope: 0 deg; Reference: ligger SFB250 HE260A+355x12
Name (NLRS_28.11_SF_WPB_stalen ligger SFB_gen_BSc:ligger SFB250 HE260A+355x12:...) | In | Span (mm)
4914293 | 02 tweede verdieping | 33500
4914914 | 01 eerste verdieping | 33330

# IfcBeam: ligger SFB250 HE260A+450x12 (3)
In: 03 derde verdieping
Type - ElementType: ligger SFB250 HE260A+450x12; PredefinedType: BEAM; Classification: 28.11 hoofddraagconstructies - kolommen en liggers, kolom-/liggerconstructies (Uniformat); Material: NLRS_h2_staal
Pset_BeamCommon - IsExternal: yes; LoadBearing: yes; Slope: 0 deg; Reference: ligger SFB250 HE260A+450x12
Name (NLRS_28.11_SF_WPB_stalen ligger SFB_gen:ligger SFB250 HE260A+450x12:...) | Span (mm)
4917490 | 3660
11828710 | 4270
12705829 | 3680

# IfcBeam: ligger SFB260 HE260B+355x12 (3)
Type - ElementType: ligger SFB260 HE260B+355x12; PredefinedType: BEAM; Classification: 28.11 hoofddraagconstructies - kolommen en liggers, kolom-/liggerconstructies (Uniformat); Material: NLRS_h2_staal
Pset_BeamCommon - IsExternal: yes; LoadBearing: yes; Slope: 0 deg; Reference: ligger SFB260 HE260B+355x12
Name (NLRS_28.11_SF_WPB_stalen ligger SFB_gen_BSc:ligger SFB260 HE260B+355x12:...) | In | Span (mm)
7304951 | 01 eerste verdieping | 4155
7305023 | 02 tweede verdieping | 4555
7305029 | 03 derde verdieping | 4555

# IfcBeam: ligger SFB260 HE260B+375x12 (2)
Type - ElementType: ligger SFB260 HE260B+375x12; PredefinedType: BEAM; Classification: 28.11 hoofddraagconstructies - kolommen en liggers, kolom-/liggerconstructies (Uniformat); Material: NLRS_h2_staal
Pset_BeamCommon - IsExternal: yes; LoadBearing: yes; Slope: 0 deg; Reference: ligger SFB260 HE260B+375x12; Span: 19980 mm
Name (NLRS_28.11_SF_WPB_stalen ligger SFB_gen_BSc:ligger SFB260 HE260B+375x12:...) | In
4914994 | 02 tweede verdieping
4914996 | 01 eerste verdieping

# IfcBeam: ligger SFB260 HE260B+450x12 (4)
Type - ElementType: ligger SFB260 HE260B+450x12; PredefinedType: BEAM; Classification: 28.11 hoofddraagconstructies - kolommen en liggers, kolom-/liggerconstructies (Uniformat); Material: NLRS_h2_staal
Pset_BeamCommon - IsExternal: yes; LoadBearing: yes; Slope: 0 deg; Reference: ligger SFB260 HE260B+450x12
Name (NLRS_28.11_SF_WPB_stalen ligger SFB_gen_BSc:ligger SFB260 HE260B+450x12:...) | In | Span (mm)
6254938 | 02 tweede verdieping | 7470
6255364 | 01 eerste verdieping | 7490
6259232 | 02 tweede verdieping | 8410
6259882 | 01 eerste verdieping | 8410

# IfcBeam: ligger stripstaal RECT_100x10 gedraaid (68)
Type - ElementType: ligger stripstaal RECT_100x10 gedraaid; PredefinedType: BEAM; Classification: 28.11 hoofddraagconstructies - kolommen en liggers, kolom-/liggerconstructies (Uniformat); Material: NLRS_h2_staal
Pset_BeamCommon - LoadBearing: yes; Slope: 0 deg; Reference: ligger stripstaal RECT_100x10 gedraaid
Name (NLRS_28.11_SF_WPB_stalen ligger stripstaal_gen:ligger stripstaal RECT_100x10 gedraaid:...) | In | IsExternal | Span (mm)
10516941 | 61 eenenzestigste verdieping | yes | 6480
10516947 | 61 eenenzestigste verdieping | yes | 6420
10516951 | 61 eenenzestigste verdieping | yes | 6500
10516957 | 62 tweeënzestigste verdieping | yes | 3620
10516963 | 62 tweeënzestigste verdieping | yes | 3640
10516969 | 62 tweeënzestigste verdieping | yes | 4100
10516973 | 62 tweeënzestigste verdieping | yes | 3980
10517013 | 61 eenenzestigste verdieping | yes | 6060
10517017 | 61 eenenzestigste verdieping | yes | 6100
10517023 | 61 eenenzestigste verdieping | yes | 5940
10517027 | 61 eenenzestigste verdieping | yes | 6215
10517033 | 62 tweeënzestigste verdieping | yes | 3040
10517039 | 62 tweeënzestigste verdieping | yes | 3260
10517045 | 62 tweeënzestigste verdieping | yes | 2800
10517081 | 61 eenenzestigste verdieping | yes | 6470
10517087 | 61 eenenzestigste verdieping | yes | 6320
10517093 | 61 eenenzestigste verdieping | yes | 6400
10517097 | 61 eenenzestigste verdieping | yes | 6600
10517109 | 62 tweeënzestigste verdieping | yes | 4000
10517113 | 62 tweeënzestigste verdieping | yes | 3705
10517119 | 62 tweeënzestigste verdieping | yes | 4120
10517123 | 62 tweeënzestigste verdieping | yes | 3875.13
10517196 | 61 eenenzestigste verdieping | yes | 6131.37
10517210 | 61 eenenzestigste verdieping | yes | 6220
10517226 | 61 eenenzestigste verdieping | yes | 6180
10517240 | 61 eenenzestigste verdieping | yes | 6155
10517254 | 62 tweeënzestigste verdieping | yes | 3136.23
10517268 | 62 tweeënzestigste verdieping | yes | 2800
10517284 | 62 tweeënzestigste verdieping | yes | 3580
10517298 | 62 tweeënzestigste verdieping | yes | 3060
10517823 | 62 tweeënzestigste verdieping | yes | 3445.18
12907349 | 61 eenenzestigste verdieping | yes | 6680
13589238 | 04 vierde verdieping | no | 100 | Group: Model Group:Koppeling-3:13592218
13591827 | 04 vierde verdieping | no | 100 | Group: Model Group:Koppeling-3:13592218
13593873 | 05 vijfde verdieping | no | 100 | Group: Model Group:Koppeling-3:13593881
13593878 | 05 vijfde verdieping | no | 100 | Group: Model Group:Koppeling-3:13593881
13593927 | 05 vijfde verdieping | no | 100 | Group: Model Group:Koppeling-3:13593935
13593932 | 05 vijfde verdieping | no | 100 | Group: Model Group:Koppeling-3:13593935
13593973 | 05 vijfde verdieping | no | 100 | Group: Model Group:Koppeling-3:13593981
13593978 | 05 vijfde verdieping | no | 100 | Group: Model Group:Koppeling-3:13593981
13594043 | 05 vijfde verdieping | no | 100 | Group: Model Group:Koppeling-3:13594051
13594048 | 05 vijfde verdieping | no | 100 | Group: Model Group:Koppeling-3:13594051
13594089 | 05 vijfde verdieping | no | 100 | Group: Model Group:Koppeling-3:13594097
13594094 | 05 vijfde verdieping | no | 100 | Group: Model Group:Koppeling-3:13594097
13594179 | 05 vijfde verdieping | no | 100 | Group: Model Group:Koppeling-3:13594187
13594184 | 05 vijfde verdieping | no | 100 | Group: Model Group:Koppeling-3:13594187
13594225 | 05 vijfde verdieping | no | 100 | Group: Model Group:Koppeling-3:13594233
13594230 | 05 vijfde verdieping | no | 100 | Group: Model Group:Koppeling-3:13594233
13594538 | 04 vierde verdieping | no | 100 | Group: Model Group:Koppeling-3a:13594638
13594543 | 04 vierde verdieping | no | 100 | Group: Model Group:Koppeling-3a:13594638
13611895 | 05 vijfde verdieping | no | 100 | Group: Model Group:Koppeling-3a:13611903
13611900 | 05 vijfde verdieping | no | 100 | Group: Model Group:Koppeling-3a:13611903
13616680 | 02 tweede verdieping | no | 100 | Group: Model Group:Koppeling-4:13616571
13620221 | 02 tweede verdieping | no | 100 | Group: Model Group:Koppeling-4:13620218
13620288 | 02 tweede verdieping | no | 100 | Group: Model Group:Koppeling-4:13620285
13620373 | 02 tweede verdieping | no | 100 | Group: Model Group:Koppeling-4 onder:13620370
13620762 | 02 tweede verdieping | no | 100 | Group: Model Group:Koppeling-4 onder:13620759
13620831 | 02 tweede verdieping | no | 100 | Group: Model Group:Koppeling-4 onder:13620828
13620985 | 03 derde verdieping | no | 100 | Group: Model Group:Koppeling-4 onder:13620982
13620991 | 03 derde verdieping | no | 100 | Group: Model Group:Koppeling-4 onder:13620988
13620997 | 03 derde verdieping | no | 100 | Group: Model Group:Koppeling-4 onder:13620994
13621122 | 01 eerste verdieping | no | 100 | Group: Model Group:Koppeling-4:13621119
13621128 | 01 eerste verdieping | no | 100 | Group: Model Group:Koppeling-4:13621125
13621134 | 01 eerste verdieping | no | 100 | Group: Model Group:Koppeling-4:13621131
13732469 | 00 begane grond | no | 6912.44
13732471 | 00 begane grond | no | 6912.44
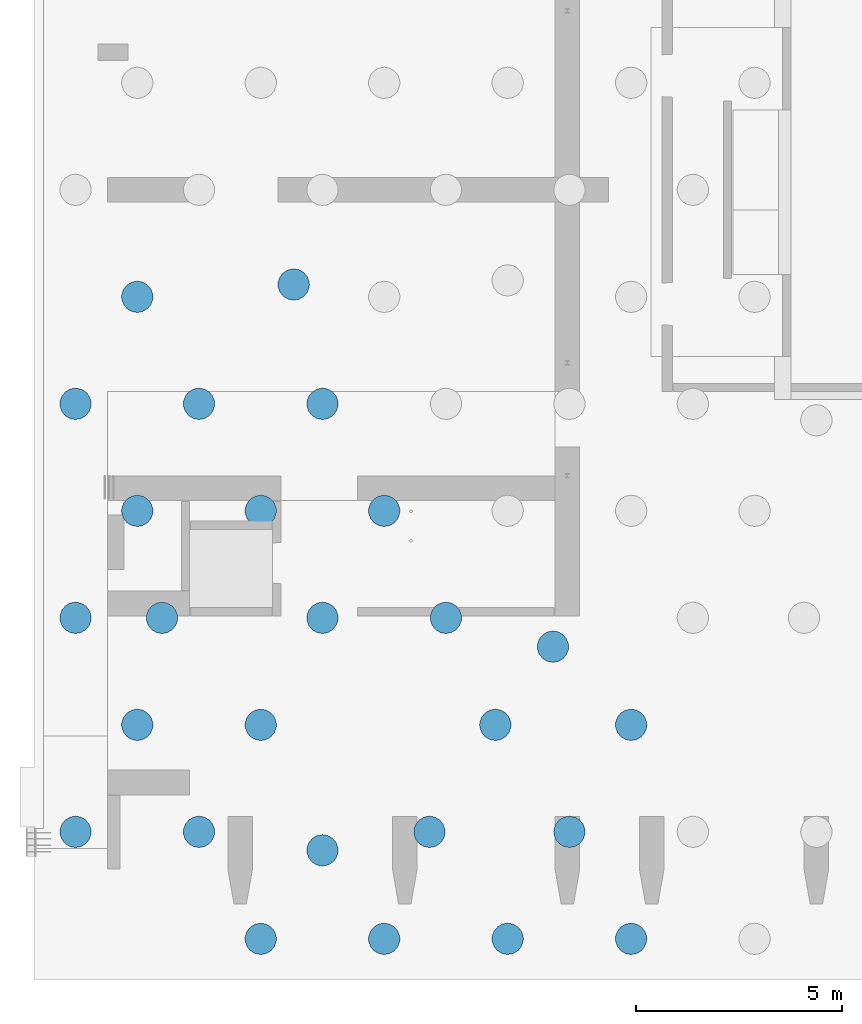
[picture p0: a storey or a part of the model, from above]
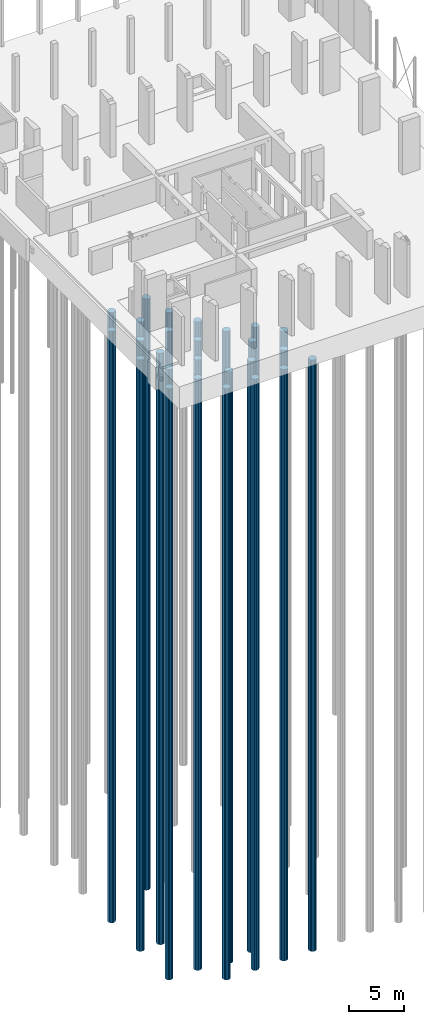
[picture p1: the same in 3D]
Properties of the parts of a building model (IFC2X3), part 5 of 21

# IfcBeam: ligger stripstaal RECT_100x10 gedraaid (68)
Name (NLRS_28.11_SF_WPB_stalen ligger stripstaal_gen:ligger stripstaal RECT_100x10 gedraaid:...) | In | IsExternal | Span (mm)
13732517 | 00 begane grond | no | 6912.44
13732519 | 00 begane grond | no | 6912.44

# IfcBeam: ligger stripstaal RECT_100x15 (6)
In: 03 derde verdieping
Type - ElementType: ligger stripstaal RECT_100x15; PredefinedType: BEAM; Classification: 28.11 hoofddraagconstructies - kolommen en liggers, kolom-/liggerconstructies (Uniformat); Material: NLRS_h2_staal
Pset_BeamCommon - IsExternal: yes; LoadBearing: yes; Slope: 0 deg; Reference: ligger stripstaal RECT_100x15; Span: 200 mm
Name (NLRS_28.11_SF_WPB_stalen ligger stripstaal_gen:ligger stripstaal RECT_100x15:...) | Group
13172974 | Model Group:oplegschoen atriumkap:13180237
13180311 | Model Group:oplegschoen atriumkap:13180346
13180747 | Model Group:oplegschoen atriumkap:13180777
13180847 | Model Group:oplegschoen atriumkap:13180877
13180949 | Model Group:oplegschoen atriumkap:13180979
13181051 | Model Group:oplegschoen atriumkap:13181081

# IfcBeam: ligger stripstaal RECT_148x10, NLRS_28.11_SF_WPB_stalen ligger stripstaal_gen:ligger stripstaal RECT_148x10:14151280
In: 59 negenenvijftigste verdieping
Type - ElementType: ligger stripstaal RECT_148x10; PredefinedType: BEAM; Classification: 28.11 hoofddraagconstructies - kolommen en liggers, kolom-/liggerconstructies (Uniformat); Material: NLRS_h2_staal
Pset_BeamCommon - IsExternal: yes; LoadBearing: yes; Slope: 0 deg; Reference: ligger stripstaal RECT_148x10; Span: 140 mm

# IfcBeam: ligger stripstaal RECT_150x15 gedraaid (48)
Type - ElementType: ligger stripstaal RECT_150x15 gedraaid; PredefinedType: BEAM; Classification: 28.11 hoofddraagconstructies - kolommen en liggers, kolom-/liggerconstructies (Uniformat); Material: NLRS_h2_staal
Pset_BeamCommon - IsExternal: yes; LoadBearing: yes; Slope: 0 deg; Reference: ligger stripstaal RECT_150x15 gedraaid
Name (NLRS_28.11_SF_WPB_stalen ligger stripstaal_gen:ligger stripstaal RECT_150x15 gedraaid:...) | In | Span (mm)
10516899 | 59 negenenvijftigste verdieping | 4940
10516905 | 59 negenenvijftigste verdieping | 4960
10516915 | 60 zestigste verdieping | 6535
10516921 | 60 zestigste verdieping | 6480
10516927 | 60 zestigste verdieping | 6480
10516931 | 60 zestigste verdieping | 6415
10516981 | 59 negenenvijftigste verdieping | 4577.95
10516987 | 59 negenenvijftigste verdieping | 6135
10516997 | 60 zestigste verdieping | 6120
10517003 | 60 zestigste verdieping | 6240
10517009 | 60 zestigste verdieping | 6225
10517053 | 59 negenenvijftigste verdieping | 4840
10517061 | 59 negenenvijftigste verdieping | 4900
10517069 | 60 zestigste verdieping | 6420
10517075 | 60 zestigste verdieping | 6360
10517101 | 60 zestigste verdieping | 6455
10517105 | 60 zestigste verdieping | 6440
10517133 | 59 negenenvijftigste verdieping | 4599.83
10517139 | 59 negenenvijftigste verdieping | 4660
10517143 | 59 negenenvijftigste verdieping | 4433.83
10517147 | 60 zestigste verdieping | 6060
10517151 | 60 zestigste verdieping | 6219.95
10517168 | 60 zestigste verdieping | 6260
10517182 | 60 zestigste verdieping | 6260
10517719 | 60 zestigste verdieping | 6060
12907311 | 61 eenenzestigste verdieping | 6060
12907313 | 61 eenenzestigste verdieping | 5980
12907315 | 61 eenenzestigste verdieping | 5940
12907317 | 61 eenenzestigste verdieping | 6215
12907351 | 61 eenenzestigste verdieping | 6480
12907353 | 61 eenenzestigste verdieping | 6420
12907355 | 61 eenenzestigste verdieping | 6500
12907389 | 61 eenenzestigste verdieping | 6131.37
12907391 | 61 eenenzestigste verdieping | 6120
12907393 | 61 eenenzestigste verdieping | 6180
12907395 | 61 eenenzestigste verdieping | 6155
12907425 | 61 eenenzestigste verdieping | 6320
12907427 | 61 eenenzestigste verdieping | 6400
12907429 | 61 eenenzestigste verdieping | 6600
12908422 | 61 eenenzestigste verdieping | 6600
12908650 | 61 eenenzestigste verdieping | 6480
12955384 | 59 negenenvijftigste verdieping | 4555
12955883 | 59 negenenvijftigste verdieping | 4427.57
12955945 | 59 negenenvijftigste verdieping | 4440
12956221 | 59 negenenvijftigste verdieping | 4835
12956283 | 59 negenenvijftigste verdieping | 4950
12956357 | 59 negenenvijftigste verdieping | 4900
12956420 | 59 negenenvijftigste verdieping | 4955

# IfcBeam: ligger stripstaal RECT_160x10 (6)
In: 03 derde verdieping
Type - ElementType: ligger stripstaal RECT_160x10; PredefinedType: BEAM; Classification: 28.11 hoofddraagconstructies - kolommen en liggers, kolom-/liggerconstructies (Uniformat); Material: NLRS_h2_staal
Pset_BeamCommon - IsExternal: yes; LoadBearing: yes; Slope: 0 deg; Reference: ligger stripstaal RECT_160x10; Span: 345 mm
Name (NLRS_28.11_SF_WPB_stalen ligger stripstaal_gen:ligger stripstaal RECT_160x10:...) | Group
13167925 | Model Group:oplegschoen atriumkap:13180237
13180307 | Model Group:oplegschoen atriumkap:13180346
13180743 | Model Group:oplegschoen atriumkap:13180777
13180843 | Model Group:oplegschoen atriumkap:13180877
13180945 | Model Group:oplegschoen atriumkap:13180979
13181047 | Model Group:oplegschoen atriumkap:13181081

# IfcBeam: ligger stripstaal RECT_1900x50, NLRS_28.11_SF_WPB_stalen ligger stripstaal_gen:ligger stripstaal RECT_1900x50:14222274
In: 62 tweeënzestigste verdieping
Type - ElementType: ligger stripstaal RECT_1900x50; PredefinedType: BEAM; Classification: 28.11 hoofddraagconstructies - kolommen en liggers, kolom-/liggerconstructies (Uniformat); Material: NLRS_h2_staal
Pset_BeamCommon - LoadBearing: yes; IsExternal: no; Slope: 0 deg; Reference: ligger stripstaal RECT_1900x50; Span: 1900 mm

# IfcBeam: ligger stripstaal RECT_200x20 (2)
In: 03 derde verdieping
Type - ElementType: ligger stripstaal RECT_200x20; PredefinedType: BEAM; Classification: 28.11 hoofddraagconstructies - kolommen en liggers, kolom-/liggerconstructies (Uniformat); Material: NLRS_h2_staal
Pset_BeamCommon - IsExternal: yes; LoadBearing: yes; Slope: 0 deg; Reference: ligger stripstaal RECT_200x20; Span: 200 mm
Name (NLRS_28.11_SF_WPB_stalen ligger stripstaal_gen:ligger stripstaal RECT_200x20:...)
12478710
12708475

# IfcBeam: ligger stripstaal RECT_200x25 (8)
In: 01 eerste verdieping
Type - ElementType: ligger stripstaal RECT_200x25; PredefinedType: BEAM; Classification: 28.11 hoofddraagconstructies - kolommen en liggers, kolom-/liggerconstructies (Uniformat); Material: NLRS_h2_staal
Pset_BeamCommon - IsExternal: yes; LoadBearing: yes; Slope: 0 deg; Reference: ligger stripstaal RECT_200x25; Span: 300 mm
Name (NLRS_28.11_SF_WPB_stalen ligger stripstaal_gen:ligger stripstaal RECT_200x25:...) | Group
12766185 | Model Group:Luifel_HEB300:12766569
12767152 | Model Group:Luifel_HEB300:12767154
12767333 | Model Group:Luifel_HEB300:12767335
12767431 | Model Group:Luifel_HEB300:12767433
12767516 | Model Group:Luifel_HEB300:12767518
12767603 | Model Group:Luifel_HEB300:12767605
12767896 | Model Group:Luifel_IPE400:12780584
12780725 | Model Group:Luifel_IPE400:12780779

# IfcBeam: ligger stripstaal RECT_208x15 (12)
In: 59 negenenvijftigste verdieping
Type - ElementType: ligger stripstaal RECT_208x15; PredefinedType: BEAM; Classification: 28.11 hoofddraagconstructies - kolommen en liggers, kolom-/liggerconstructies (Uniformat); Material: NLRS_h2_staal
Pset_BeamCommon - IsExternal: yes; LoadBearing: yes; Slope: 0 deg; Reference: ligger stripstaal RECT_208x15; Span: 550 mm
Name (NLRS_28.11_SF_WPB_stalen ligger stripstaal_gen:ligger stripstaal RECT_208x15:...) | Group
12971808 | Model Group:ankers kolom 59e:12934709
12976503 | Model Group:ankers kolom 59e:12934476
12976509 | Model Group:ankers kolom 59e:12934537
12976512 | Model Group:ankers kolom 59e:12934558
12976515 | Model Group:ankers kolom 59e:12934587
12976518 | Model Group:ankers kolom 59e:12934610
12976521 | Model Group:ankers kolom 59e:12934635
12976524 | Model Group:ankers kolom 59e:12934656
12976527 | Model Group:ankers kolom 59e:12934728
12976530 | Model Group:ankers kolom 59e:12934747
12976533 | Model Group:ankers kolom 59e:12934762
12976536 | Model Group:ankers kolom 59e:12934781

# IfcBeam: ligger stripstaal RECT_250x15 (4)
Type - ElementType: ligger stripstaal RECT_250x15; PredefinedType: BEAM; Classification: 28.11 hoofddraagconstructies - kolommen en liggers, kolom-/liggerconstructies (Uniformat); Material: NLRS_h2_staal
Pset_BeamCommon - IsExternal: yes; LoadBearing: yes; Slope: 0 deg; Reference: ligger stripstaal RECT_250x15; Span: 100 mm
Name (NLRS_28.11_SF_WPB_stalen ligger stripstaal_gen:ligger stripstaal RECT_250x15:...) | In
13865776 | 58 achtenvijftigste verdieping
13867795 | 58 achtenvijftigste verdieping
13878616 | 59 negenenvijftigste verdieping
13878618 | 59 negenenvijftigste verdieping

# IfcBeam: ligger stripstaal RECT_262x15 (6)
In: 01 eerste verdieping
Type - ElementType: ligger stripstaal RECT_262x15; PredefinedType: BEAM; Classification: 28.11 hoofddraagconstructies - kolommen en liggers, kolom-/liggerconstructies (Uniformat); Material: NLRS_h2_staal
Pset_BeamCommon - IsExternal: yes; LoadBearing: yes; Slope: 0 deg; Reference: ligger stripstaal RECT_262x15; Span: 300 mm
Name (NLRS_28.11_SF_WPB_stalen ligger stripstaal_gen:ligger stripstaal RECT_262x15:...) | Group
13502501 | Model Group:Luifel_HEB300:12767605
13502789 | Model Group:Luifel_HEB300:12766569
13502845 | Model Group:Luifel_HEB300:12767154
13502873 | Model Group:Luifel_HEB300:12767335
13502901 | Model Group:Luifel_HEB300:12767433
13502929 | Model Group:Luifel_HEB300:12767518

# IfcBeam: ligger stripstaal RECT_290x10, NLRS_28.11_SF_WPB_stalen ligger stripstaal_gen:ligger stripstaal RECT_290x10:6002107
In: 03 derde verdieping
Type - ElementType: ligger stripstaal RECT_290x10; PredefinedType: BEAM; Classification: 28.11 hoofddraagconstructies - kolommen en liggers, kolom-/liggerconstructies (Uniformat); Material: NLRS_h2_staal
Pset_BeamCommon - IsExternal: yes; LoadBearing: yes; Slope: 0 deg; Reference: ligger stripstaal RECT_290x10; Span: 3650 mm

# IfcBeam: ligger stripstaal RECT_300x15 (8)
Type - ElementType: ligger stripstaal RECT_300x15; PredefinedType: BEAM; Classification: 28.11 hoofddraagconstructies - kolommen en liggers, kolom-/liggerconstructies (Uniformat); Material: NLRS_h2_staal
Pset_BeamCommon - IsExternal: yes; LoadBearing: yes; Slope: 0 deg; Reference: ligger stripstaal RECT_300x15
Name (NLRS_28.11_SF_WPB_stalen ligger stripstaal_gen:ligger stripstaal RECT_300x15:...) | In | Span (mm) | Group
13502499 | 01 eerste verdieping | 300 | Model Group:Luifel_HEB300:12767605
13502787 | 01 eerste verdieping | 300 | Model Group:Luifel_HEB300:12766569
13502843 | 01 eerste verdieping | 300 | Model Group:Luifel_HEB300:12767154
13502871 | 01 eerste verdieping | 300 | Model Group:Luifel_HEB300:12767335
13502899 | 01 eerste verdieping | 300 | Model Group:Luifel_HEB300:12767433
13502927 | 01 eerste verdieping | 300 | Model Group:Luifel_HEB300:12767518
13871962 | 58 achtenvijftigste verdieping | 100
13883229 | 59 negenenvijftigste verdieping | 100

# IfcBeam: ligger stripstaal RECT_320x15 (4)
In: 59 negenenvijftigste verdieping
Type - ElementType: ligger stripstaal RECT_320x15; PredefinedType: BEAM; Classification: 28.11 hoofddraagconstructies - kolommen en liggers, kolom-/liggerconstructies (Uniformat); Material: NLRS_h2_staal
Pset_BeamCommon - IsExternal: yes; LoadBearing: yes; Slope: 0 deg; Reference: ligger stripstaal RECT_320x15; Span: 220 mm
Name (NLRS_28.11_SF_WPB_stalen ligger stripstaal_gen:ligger stripstaal RECT_320x15:...) | Group
12969399 | Model Group:ankers kolom hoek 59e:12934297
12976701 | Model Group:ankers kolom hoek 59e:12934352
12976704 | Model Group:ankers kolom hoek 59e:12934364
12976707 | Model Group:ankers kolom hoek 59e:12934387

# IfcBeam: ligger stripstaal RECT_70x5 (5)
Type - ElementType: ligger stripstaal RECT_70x5; PredefinedType: BEAM; Classification: 28.11 hoofddraagconstructies - kolommen en liggers, kolom-/liggerconstructies (Uniformat); Material: NLRS_h2_staal
Pset_BeamCommon - IsExternal: yes; LoadBearing: yes; Slope: 0 deg; Reference: ligger stripstaal RECT_70x5
Name (NLRS_28.11_SF_WPB_stalen ligger stripstaal_gen:ligger stripstaal RECT_70x5:...) | In | Span (mm)
9337937 | 02 tweede verdieping | 20500
9338177 | 01 eerste verdieping | 20500
10003858 | 01 eerste verdieping | 3955
10004100 | 02 tweede verdieping | 4355
10004166 | 03 derde verdieping | 4355

# IfcBeam: ligger stripstaal RECT_80x12 gedraaid_! (57)
Type - ElementType: ligger stripstaal RECT_80x12 gedraaid_!; PredefinedType: BEAM; Classification: 28.11 hoofddraagconstructies - kolommen en liggers, kolom-/liggerconstructies (Uniformat); Material: NLRS_h2_staal
Pset_BeamCommon - LoadBearing: yes; IsExternal: no; Slope: 0 deg; Reference: ligger stripstaal RECT_80x12 gedraaid_!; Span: 180 mm
Name (NLRS_28.11_SF_WPB_stalen ligger stripstaal_gen:ligger stripstaal RECT_80x12 gedraaid_!:...) | In | Group
13545453 | 03 derde verdieping | Model Group:Koppeling-1:13567508
13567651 | 03 derde verdieping | Model Group:Koppeling-1:13567654
13571108 | 03 derde verdieping | Model Group:Koppeling-1:13571111
13571199 | 03 derde verdieping | Model Group:Koppeling-1:13571202
13571767 | 03 derde verdieping | Model Group:Koppeling-1:13571770
13571773 | 03 derde verdieping | Model Group:Koppeling-1:13571776
13571833 | 03 derde verdieping | Model Group:Koppeling-1:13571836
13571839 | 03 derde verdieping | Model Group:Koppeling-1:13571842
13571899 | 03 derde verdieping | Model Group:Koppeling-1:13571902
13571905 | 03 derde verdieping | Model Group:Koppeling-1:13571908
13572115 | 03 derde verdieping | Model Group:Koppeling-1:13572118
13572262 | 03 derde verdieping | Model Group:Koppeling-1:13572265
13572857 | 03 derde verdieping | Model Group:Koppeling-1:13572860
13572927 | 03 derde verdieping | Model Group:Koppeling-1:13572930
13573359 | 03 derde verdieping | Model Group:Koppeling-1:13573362
13573365 | 03 derde verdieping | Model Group:Koppeling-1:13573368
13573484 | 04 vierde verdieping | Model Group:Koppeling-1:13573487
13573566 | 04 vierde verdieping | Model Group:Koppeling-1:13573569
13574244 | 03 derde verdieping | Model Group:Koppeling-1:13574247
13574426 | 03 derde verdieping | Model Group:Koppeling-1:13574429
13577469 | 03 derde verdieping | Model Group:Koppeling-1:13577472
13577734 | 03 derde verdieping | Model Group:Koppeling-1:13577737
13578665 | 03 derde verdieping | Model Group:Koppeling-1:13578668
13578671 | 03 derde verdieping | Model Group:Koppeling-1:13578674
13578880 | 03 derde verdieping | Model Group:Koppeling-1:13578883
13578968 | 03 derde verdieping | Model Group:Koppeling-1:13578971
13580911 | 03 derde verdieping | Model Group:Koppeling-1:13580914
13581049 | 03 derde verdieping | Model Group:Koppeling-1:13581052
13581119 | 03 derde verdieping | Model Group:Koppeling-1:13581122
13581187 | 03 derde verdieping | Model Group:Koppeling-1:13581190
13581274 | 03 derde verdieping | Model Group:Koppeling-1:13581277
13581280 | 03 derde verdieping | Model Group:Koppeling-1:13581283
13581383 | 03 derde verdieping | Model Group:Koppeling-1:13581386
13581449 | 03 derde verdieping | Model Group:Koppeling-1:13581452
13581519 | 03 derde verdieping | Model Group:Koppeling-1:13581522
13581587 | 03 derde verdieping | Model Group:Koppeling-1:13581590
13581659 | 03 derde verdieping | Model Group:Koppeling-1:13581662
13581725 | 03 derde verdieping | Model Group:Koppeling-1:13581728
13581795 | 03 derde verdieping | Model Group:Koppeling-1:13581798
13581865 | 03 derde verdieping | Model Group:Koppeling-1:13581868
13581935 | 03 derde verdieping | Model Group:Koppeling-1:13581938
13582001 | 03 derde verdieping | Model Group:Koppeling-1:13582004
13582069 | 03 derde verdieping | Model Group:Koppeling-1:13582072
13582137 | 03 derde verdieping | Model Group:Koppeling-1:13582140
13582205 | 03 derde verdieping | Model Group:Koppeling-1:13582208
13582273 | 03 derde verdieping | Model Group:Koppeling-1:13582276
13582341 | 03 derde verdieping | Model Group:Koppeling-1:13582344
13582411 | 03 derde verdieping | Model Group:Koppeling-1:13582414
13582481 | 03 derde verdieping | Model Group:Koppeling-1:13582484
13582549 | 03 derde verdieping | Model Group:Koppeling-1:13582552
13582619 | 03 derde verdieping | Model Group:Koppeling-1:13582622
13582687 | 03 derde verdieping | Model Group:Koppeling-1:13582690
13582755 | 03 derde verdieping | Model Group:Koppeling-1:13582758
13611777 | 03 derde verdieping | Model Group:Koppeling-1:13611780
13611783 | 03 derde verdieping | Model Group:Koppeling-1:13611786
13611789 | 03 derde verdieping | Model Group:Koppeling-1:13611792
13611795 | 03 derde verdieping | Model Group:Koppeling-1:13611798

# IfcBeam: ligger stripstaal RECT_80x20 gedraaid (2)
In: 57 zevenenvijftigste verdieping
Type - ElementType: ligger stripstaal RECT_80x20 gedraaid; PredefinedType: BEAM; Classification: 28.11 hoofddraagconstructies - kolommen en liggers, kolom-/liggerconstructies (Uniformat); Material: NLRS_h2_staal
Pset_BeamCommon - LoadBearing: yes; IsExternal: no; Slope: 0 deg; Reference: ligger stripstaal RECT_80x20 gedraaid; Span: 1000 mm
Name (NLRS_28.11_SF_WPB_stalen ligger stripstaal_gen:ligger stripstaal RECT_80x20 gedraaid:...)
14241375
14242835

# IfcBeam: ligger stripstaal RECT_80x5 (2)
Type - ElementType: ligger stripstaal RECT_80x5; PredefinedType: BEAM; Classification: 28.11 hoofddraagconstructies - kolommen en liggers, kolom-/liggerconstructies (Uniformat); Material: NLRS_h2_staal
Pset_BeamCommon - IsExternal: yes; LoadBearing: yes; Slope: 0 deg; Reference: ligger stripstaal RECT_80x5; Span: 33330 mm
Name (NLRS_28.11_SF_WPB_stalen ligger stripstaal_gen:ligger stripstaal RECT_80x5:...) | In
9338118 | 02 tweede verdieping
9338179 | 01 eerste verdieping

# IfcBeam: ligger stripstaal RECT_85x5 (3)
In: 05 vijfde verdieping
Type - ElementType: ligger stripstaal RECT_85x5; PredefinedType: BEAM; Classification: 28.11 hoofddraagconstructies - kolommen en liggers, kolom-/liggerconstructies (Uniformat); Material: NLRS_h2_staal
Pset_BeamCommon - IsExternal: yes; LoadBearing: yes; Slope: 0 deg; Reference: ligger stripstaal RECT_85x5
Name (NLRS_28.11_SF_WPB_stalen ligger stripstaal_gen:ligger stripstaal RECT_85x5:...) | Span (mm)
9338265 | 28520
9338320 | 20350
9353442 | 7020

# IfcBuildingElementProxy (80)
Name | In | Group
2 x  | 06 zesde verdieping | Model Group:NLRS_21.21_WA_wand 004a d=400_gen:4690709
2 x  | 07 zevende verdieping | Model Group:NLRS_21.21_WA_wand 004b d=400_gen:4689125
2 x  | 08 achtste verdieping | Model Group:NLRS_21.21_WA_wand 004aa d=400_gen:4714827
20 x  | 05 vijfde verdieping
 | 07 zevende verdieping | Model Group:NLRS_21.21_WA_wand 003 d=400_gen:4689135
 | 07 zevende verdieping | Model Group:NLRS_21.21_WA_wand 003 d=400_gen:4689139
 | 06 zesde verdieping | Model Group:NLRS_21.21_WA_wand 003 d=400_gen:4690713
 | 06 zesde verdieping | Model Group:NLRS_21.21_WA_wand 003 d=400_gen:4690714
 | 08 achtste verdieping | Model Group:NLRS_21.21_WA_wand 003 d=400_gen:4714831
 | 08 achtste verdieping | Model Group:NLRS_21.21_WA_wand 003 d=400_gen:4714832
 | 07 zevende verdieping | Model Group:NLRS_21.21_WA_wand 001 d=400_gen:4689134
 | 07 zevende verdieping | Model Group:NLRS_21.21_WA_wand 001 d=400_gen:4689143
 | 06 zesde verdieping | Model Group:NLRS_21.21_WA_wand 001 d=400_gen:4690712
 | 06 zesde verdieping | Model Group:NLRS_21.21_WA_wand 001 d=400_gen:4690718
 | 08 achtste verdieping | Model Group:NLRS_21.21_WA_wand 001 d=400_gen:4714830
 | 08 achtste verdieping | Model Group:NLRS_21.21_WA_wand 001 d=400_gen:4714836
2 x  | 07 zevende verdieping | Model Group:NLRS_21.21_WA_wand 002b d=400_gen:4689133
2 x  | 06 zesde verdieping | Model Group:NLRS_21.21_WA_wand 002a d=400_gen:4690711
2 x  | 08 achtste verdieping | Model Group:NLRS_21.21_WA_wand 002a d=400_gen:4714829
2 x  | 08 achtste verdieping | Model Group:NLRS_28.21_WA_3D element 002 d=400_gen:4714990
2 x  | 07 zevende verdieping | Model Group:NLRS_28.21_WA_3D element 002 d=400_gen:4689313
2 x  | 07 zevende verdieping | Model Group:NLRS_28.21_WA_3D element 002 d=400_gen:4689329
2 x  | 06 zesde verdieping | Model Group:NLRS_28.21_WA_3D element 002 d=400_gen:4690876
2 x  | 06 zesde verdieping | Model Group:NLRS_28.21_WA_3D element 002 d=400_gen:4690892
2 x  | 08 achtste verdieping | Model Group:NLRS_28.21_WA_3D element 002 d=400_gen:4715006
2 x  | 08 achtste verdieping | Model Group:NLRS_28.21_WA_3D element 001 d=400_gen:4715022
2 x  | 07 zevende verdieping | Model Group:NLRS_28.21_WA_3D element 001 d=400_gen:4689303
2 x  | 07 zevende verdieping | Model Group:NLRS_28.21_WA_3D element 001 d=400_gen:4689345
2 x  | 06 zesde verdieping | Model Group:NLRS_28.21_WA_3D element 001 d=400_gen:4690866
2 x  | 06 zesde verdieping | Model Group:NLRS_28.21_WA_3D element 001 d=400_gen:4690908
2 x  | 08 achtste verdieping | Model Group:NLRS_28.21_WA_3D element 001 d=400_gen:4714980
2 x  | 06 zesde verdieping | Model Group:NLRS_21.21_WA_wand 002a d=400_gen:4690710
2 x  | 08 achtste verdieping | Model Group:NLRS_21.21_WA_wand 002a d=400_gen:4714828
2 x  | 07 zevende verdieping | Model Group:NLRS_21.21_WA_wand 002b d=400_gen:4689126
2 x  | 06 zesde verdieping | Model Group:NLRS_21.21_WA_wand 004a d=400_gen:4690705
2 x  | 07 zevende verdieping | Model Group:NLRS_21.21_WA_wand 004b d=400_gen:4689113
2 x  | 08 achtste verdieping | Model Group:NLRS_21.21_WA_wand 004a d=400_gen:4714823

# IfcBuildingElementProxy: 240 12/150 (5)
In: 00 begane grond
Type - Classification: 28 Hoofddraagconstructies (Uniformat); Material: ISR_Staal_ S355, ISR_Algemeen
Pset_BuildingElementProxyCommon - Reference: 240 12/150
Pset_ManufacturerTypeInformation - Manufacturer: Hakron
Name (NLRS_28.00_SF_FB_Stekkenbak_Comax_QD_gen_BSc:240 12/150:...)
7162562
7162564
7162578
7790094
9331751

# IfcBuildingElementProxy: 3350x360x350 (2)
In: 00a eerste tussenverdieping
Type - Classification: 28.11 hoofddraagconstructies - kolommen en liggers, kolom-/liggerconstructies (Uniformat); Material: NLRS_h2_staal
Pset_BuildingElementProxyCommon - Reference: 3350x360x350
Name (NLRS_28.11_SF_UN_stalen latei mezzanine_gen_BSc:3350x360x350:...)
9429945
9437855

# IfcBuildingElementProxy: 3350x360x360 (2)
In: 01 eerste verdieping
Type - Classification: 28.11 hoofddraagconstructies - kolommen en liggers, kolom-/liggerconstructies (Uniformat)
Pset_BuildingElementProxyCommon - Reference: 3350x360x360
Name (NLRS_28.11_SF_UN_stalen latei 1e_gen_BSc:3350x360x360:...)
9886826
9889174

# IfcBuildingElementProxy: Comax QD KO 190 12 150 (8)
In: 00 begane grond
Type - Classification: 28 Hoofddraagconstructies (Uniformat); Material: ISR_Algemeen, ISR_Staal_ S355
Pset_BuildingElementProxyCommon - Reference: Comax QD KO 190 12 150
Pset_ManufacturerTypeInformation - Manufacturer: Hakron Nunspeet B.V.
Name (NLRS_28.00_SF_FB_Stekkenbak_Comax_QD KO_gen:Comax QD KO 190 12 150:...)
7568911
7859261
7859264
7958318
7958320
7984222
8024344
8044815

# IfcBuildingElementProxy: Comax QD KO 240 12 150 (27)
In: 00 begane grond
Type - Classification: 28 Hoofddraagconstructies (Uniformat); Material: ISR_Algemeen, ISR_Staal_ S355
Pset_BuildingElementProxyCommon - Reference: Comax QD KO 240 12 150
Pset_ManufacturerTypeInformation - Manufacturer: Hakron Nunspeet B.V.
Name (NLRS_28.00_SF_FB_Stekkenbak_Comax_QD KO_gen:Comax QD KO 240 12 150:...)
7979004
7982169
7982178
7982320
7982322
7982324
7984332
7984437
7984439
7984474
7984481
8046168
8046209
8046211
8046248
8046255
8046261
8046267
8046609
8046780
8046900
8046948
8046950
8046959
8047018
8047020
8047059

# IfcBuildingElementProxy: M24x200 (18)
Type - Material: NLRS_h2_staal
Classification: 28.11 hoofddraagconstructies - kolommen en liggers, kolom-/liggerconstructies (Uniformat)
Pset_BuildingElementProxyCommon - Reference: M24x200
Name (NLRS_28.10_SF_WPB_DEMU 1985 boutanker_gen:M24x200:...) | In
13238675 | 58 achtenvijftigste verdieping
13238677 | 57 zevenenvijftigste verdieping
13238682 | 58 achtenvijftigste verdieping
13238685 | 57 zevenenvijftigste verdieping
13873248 | 57 zevenenvijftigste verdieping
13873376 | 57 zevenenvijftigste verdieping
13873477 | 57 zevenenvijftigste verdieping
13873478 | 57 zevenenvijftigste verdieping
13878602 | 59 negenenvijftigste verdieping
13878604 | 58 achtenvijftigste verdieping
13878605 | 59 negenenvijftigste verdieping
13878607 | 58 achtenvijftigste verdieping
13879262 | 58 achtenvijftigste verdieping
13879371 | 58 achtenvijftigste verdieping
13883241 | 58 achtenvijftigste verdieping
13883242 | 58 achtenvijftigste verdieping
13883244 | 58 achtenvijftigste verdieping
13883245 | 58 achtenvijftigste verdieping

# IfcBuildingElementProxy: NLRS_28.11_SF_helix spriraal kroon_gen, NLRS_28.11_SF_helix spriraal kroon_gen:NLRS_28.11_SF_helix spriraal kroon_gen:13012298
In: 62 tweeënzestigste verdieping
Type - Classification: 28.11 hoofddraagconstructies - kolommen en liggers, kolom-/liggerconstructies (Uniformat); Material: NLRS_h2_staal
Pset_BuildingElementProxyCommon - Reference: NLRS_28.11_SF_helix spriraal kroon_gen

# IfcBuildingElementProxy: links, NLRS_28.11_SF_stalen ligger samengesteld 1e f_gen:links:12733634
In: 01 eerste verdieping
Type - Classification: 28.11 hoofddraagconstructies - kolommen en liggers, kolom-/liggerconstructies (Uniformat); Material: Default
Pset_BuildingElementProxyCommon - Reference: links

# IfcBuildingElementProxy: met oplegging (27)
In: 01 eerste verdieping
Type - Classification: 28.11 hoofddraagconstructies - kolommen en liggers, kolom-/liggerconstructies (Uniformat); Material: Default
Pset_BuildingElementProxyCommon - Reference: met oplegging
Name (NLRS_28.11_SF_stalen ligger samengesteld 1e r_gen:met oplegging:...)
13030938
13052526
13052616
13052673
13052676
13052679
13052682
13052719
13052755
13052758
13052761
13052764
13053002
13053049
13053052
13053055
13053058
13053061
13053064
13053067
13053070
13053073
13053076
13053079
13053082
13053108
13053482

# IfcBuildingElementProxy: met void (9)
In: 01 eerste verdieping
Type - Classification: 28.11 hoofddraagconstructies - kolommen en liggers, kolom-/liggerconstructies (Uniformat); Material: Default
Pset_BuildingElementProxyCommon - Reference: met void
Name (NLRS_28.11_SF_stalen ligger samengesteld 1e f_gen:met void:...)
12709842
12720892
12720900
12720908
12720916
12720922
12720928
12720934
12720940

# IfcBuildingElementProxy: rechts, NLRS_28.11_SF_stalen ligger samengesteld 1e f_gen:rechts:12733764
In: 01 eerste verdieping
Type - Classification: 28.11 hoofddraagconstructies - kolommen en liggers, kolom-/liggerconstructies (Uniformat); Material: Default
Pset_BuildingElementProxyCommon - Reference: rechts

# IfcBuildingElementProxy: type1 (5)
Type - Classification: 28.11 hoofddraagconstructies - kolommen en liggers, kolom-/liggerconstructies (Uniformat); Material: NLRS_h2_staal, Default
Pset_BuildingElementProxyCommon - Reference: type1
Name | In
NLRS_28.11_SF_stalen ligger samengesteld ligger_gen:type1:12785030 | 01 eerste verdieping
NLRS_28.11_SF_stalen ligger samengesteld 3e hoofd_gen:type1:13072436 | 03 derde verdieping
NLRS_28.11_SF_stalen ligger samengesteld 3e hoofd_gen:type1:13079939 | 03 derde verdieping
NLRS_28.11_SF_stalen ligger samengesteld 3e hoofd_gen:type1:13079950 | 03 derde verdieping
NLRS_28.11_SF_stalen ligger samengesteld 3e hoofd_gen:type1:13079963 | 03 derde verdieping

# IfcBuildingElementProxy: type1 (30)
In: 03 derde verdieping
Type - Material: NLRS_h2_staal
Classification: 28.11 hoofddraagconstructies - kolommen en liggers, kolom-/liggerconstructies (Uniformat)
Pset_BuildingElementProxyCommon - Reference: type1
Name (NLRS_28.11_SF_stalen ligger samengesteld 3e tussen_gen:type1:...)
13102006
13118715
13118815
13118892
13118929
13119037
13119038
13119039
13119040
13119041
13119049
13119050
13119051
13119052
13119053
13119065
13119066
13119067
13119068
13119069
13119077
13119078
13119079
13119080
13119081
13119093
13119094
13119095
13119096
13119097

# IfcBuildingElementProxy: zonder void (6)
In: 01 eerste verdieping
Type - Classification: 28.11 hoofddraagconstructies - kolommen en liggers, kolom-/liggerconstructies (Uniformat); Material: Default
Pset_BuildingElementProxyCommon - Reference: zonder void
Name (NLRS_28.11_SF_stalen ligger samengesteld 1e f_gen:zonder void:...)
12727661
12733443
12733610
12733620
12733628
12733689

# IfcBuildingElementProxy: Ø12/M16x415 (4)
In: 04 vierde verdieping
Type - Classification: 28 Hoofddraagconstructies (Uniformat)
Pset_BuildingElementProxyCommon - Reference: Ø12/M16x415
Pset_ManufacturerTypeInformation - Manufacturer: HALFEN b.v.
Name (GM_Stekanker_DEMU_4010 GV:Ø12/M16x415:...)
13918267
13920441
13938575
13938609

# IfcBuildingElementProxy: Ø16/M20x560 (103)
Type - Classification: 28 Hoofddraagconstructies (Uniformat)
Pset_BuildingElementProxyCommon - Reference: Ø16/M20x560
Pset_ManufacturerTypeInformation - Manufacturer: HALFEN b.v.
Name (GM_Stekanker_DEMU_4010 GV:Ø16/M20x560:...) | In | Group
10214379 | 00 begane grond
10214380 | 00 begane grond
10214381 | 00 begane grond
10214382 | 00 begane grond
10214383 | 00 begane grond
10214384 | 00 begane grond
10214385 | 00 begane grond
12934406 | 58 achtenvijftigste verdieping | Model Group:ankers kolom 59e:12934476
12934407 | 58 achtenvijftigste verdieping | Model Group:ankers kolom 59e:12934476
12934408 | 58 achtenvijftigste verdieping | Model Group:ankers kolom 59e:12934476
12934409 | 58 achtenvijftigste verdieping | Model Group:ankers kolom 59e:12934476
12934529 | 58 achtenvijftigste verdieping | Model Group:ankers kolom 59e:12934537
12934530 | 58 achtenvijftigste verdieping | Model Group:ankers kolom 59e:12934537
12934531 | 58 achtenvijftigste verdieping | Model Group:ankers kolom 59e:12934537
12934532 | 58 achtenvijftigste verdieping | Model Group:ankers kolom 59e:12934537
12934554 | 58 achtenvijftigste verdieping | Model Group:ankers kolom 59e:12934558
12934555 | 58 achtenvijftigste verdieping | Model Group:ankers kolom 59e:12934558
12934556 | 58 achtenvijftigste verdieping | Model Group:ankers kolom 59e:12934558
12934557 | 58 achtenvijftigste verdieping | Model Group:ankers kolom 59e:12934558
12934583 | 58 achtenvijftigste verdieping | Model Group:ankers kolom 59e:12934587
12934584 | 58 achtenvijftigste verdieping | Model Group:ankers kolom 59e:12934587
12934585 | 58 achtenvijftigste verdieping | Model Group:ankers kolom 59e:12934587
12934586 | 58 achtenvijftigste verdieping | Model Group:ankers kolom 59e:12934587
12934606 | 58 achtenvijftigste verdieping | Model Group:ankers kolom 59e:12934610
12934607 | 58 achtenvijftigste verdieping | Model Group:ankers kolom 59e:12934610
12934608 | 58 achtenvijftigste verdieping | Model Group:ankers kolom 59e:12934610
12934609 | 58 achtenvijftigste verdieping | Model Group:ankers kolom 59e:12934610
12934631 | 58 achtenvijftigste verdieping | Model Group:ankers kolom 59e:12934635
12934632 | 58 achtenvijftigste verdieping | Model Group:ankers kolom 59e:12934635
12934633 | 58 achtenvijftigste verdieping | Model Group:ankers kolom 59e:12934635
12934634 | 58 achtenvijftigste verdieping | Model Group:ankers kolom 59e:12934635
12934652 | 58 achtenvijftigste verdieping | Model Group:ankers kolom 59e:12934656
12934653 | 58 achtenvijftigste verdieping | Model Group:ankers kolom 59e:12934656
12934654 | 58 achtenvijftigste verdieping | Model Group:ankers kolom 59e:12934656
12934655 | 58 achtenvijftigste verdieping | Model Group:ankers kolom 59e:12934656
12934705 | 58 achtenvijftigste verdieping | Model Group:ankers kolom 59e:12934709
12934706 | 58 achtenvijftigste verdieping | Model Group:ankers kolom 59e:12934709
12934707 | 58 achtenvijftigste verdieping | Model Group:ankers kolom 59e:12934709
12934708 | 58 achtenvijftigste verdieping | Model Group:ankers kolom 59e:12934709
12934724 | 58 achtenvijftigste verdieping | Model Group:ankers kolom 59e:12934728
12934725 | 58 achtenvijftigste verdieping | Model Group:ankers kolom 59e:12934728
12934726 | 58 achtenvijftigste verdieping | Model Group:ankers kolom 59e:12934728
12934727 | 58 achtenvijftigste verdieping | Model Group:ankers kolom 59e:12934728
12934743 | 58 achtenvijftigste verdieping | Model Group:ankers kolom 59e:12934747
12934744 | 58 achtenvijftigste verdieping | Model Group:ankers kolom 59e:12934747
12934745 | 58 achtenvijftigste verdieping | Model Group:ankers kolom 59e:12934747
12934746 | 58 achtenvijftigste verdieping | Model Group:ankers kolom 59e:12934747
12934758 | 58 achtenvijftigste verdieping | Model Group:ankers kolom 59e:12934762
12934759 | 58 achtenvijftigste verdieping | Model Group:ankers kolom 59e:12934762
12934760 | 58 achtenvijftigste verdieping | Model Group:ankers kolom 59e:12934762
12934761 | 58 achtenvijftigste verdieping | Model Group:ankers kolom 59e:12934762
12934777 | 58 achtenvijftigste verdieping | Model Group:ankers kolom 59e:12934781
12934778 | 58 achtenvijftigste verdieping | Model Group:ankers kolom 59e:12934781
12934779 | 58 achtenvijftigste verdieping | Model Group:ankers kolom 59e:12934781
12934780 | 58 achtenvijftigste verdieping | Model Group:ankers kolom 59e:12934781
12971922 | 58 achtenvijftigste verdieping | Model Group:ankers kolom 59e:12934728
12971923 | 58 achtenvijftigste verdieping | Model Group:ankers kolom 59e:12934728
12971957 | 58 achtenvijftigste verdieping | Model Group:ankers kolom 59e:12934728
12971958 | 58 achtenvijftigste verdieping | Model Group:ankers kolom 59e:12934728
12972107 | 58 achtenvijftigste verdieping | Model Group:ankers kolom 59e:12934476
12972108 | 58 achtenvijftigste verdieping | Model Group:ankers kolom 59e:12934476
12972109 | 58 achtenvijftigste verdieping | Model Group:ankers kolom 59e:12934476
12972110 | 58 achtenvijftigste verdieping | Model Group:ankers kolom 59e:12934476
12972123 | 58 achtenvijftigste verdieping | Model Group:ankers kolom 59e:12934537
12972124 | 58 achtenvijftigste verdieping | Model Group:ankers kolom 59e:12934537
12972125 | 58 achtenvijftigste verdieping | Model Group:ankers kolom 59e:12934537
12972126 | 58 achtenvijftigste verdieping | Model Group:ankers kolom 59e:12934537
12972131 | 58 achtenvijftigste verdieping | Model Group:ankers kolom 59e:12934558
12972132 | 58 achtenvijftigste verdieping | Model Group:ankers kolom 59e:12934558
12972133 | 58 achtenvijftigste verdieping | Model Group:ankers kolom 59e:12934558
12972134 | 58 achtenvijftigste verdieping | Model Group:ankers kolom 59e:12934558
12972139 | 58 achtenvijftigste verdieping | Model Group:ankers kolom 59e:12934587
12972140 | 58 achtenvijftigste verdieping | Model Group:ankers kolom 59e:12934587
12972141 | 58 achtenvijftigste verdieping | Model Group:ankers kolom 59e:12934587
12972142 | 58 achtenvijftigste verdieping | Model Group:ankers kolom 59e:12934587
12972147 | 58 achtenvijftigste verdieping | Model Group:ankers kolom 59e:12934610
12972148 | 58 achtenvijftigste verdieping | Model Group:ankers kolom 59e:12934610
12972149 | 58 achtenvijftigste verdieping | Model Group:ankers kolom 59e:12934610
12972150 | 58 achtenvijftigste verdieping | Model Group:ankers kolom 59e:12934610
12972155 | 58 achtenvijftigste verdieping | Model Group:ankers kolom 59e:12934635
12972156 | 58 achtenvijftigste verdieping | Model Group:ankers kolom 59e:12934635
12972157 | 58 achtenvijftigste verdieping | Model Group:ankers kolom 59e:12934635
12972158 | 58 achtenvijftigste verdieping | Model Group:ankers kolom 59e:12934635
12972163 | 58 achtenvijftigste verdieping | Model Group:ankers kolom 59e:12934656
12972164 | 58 achtenvijftigste verdieping | Model Group:ankers kolom 59e:12934656
12972165 | 58 achtenvijftigste verdieping | Model Group:ankers kolom 59e:12934656
12972166 | 58 achtenvijftigste verdieping | Model Group:ankers kolom 59e:12934656
12972171 | 58 achtenvijftigste verdieping | Model Group:ankers kolom 59e:12934709
12972172 | 58 achtenvijftigste verdieping | Model Group:ankers kolom 59e:12934709
12972173 | 58 achtenvijftigste verdieping | Model Group:ankers kolom 59e:12934709
12972174 | 58 achtenvijftigste verdieping | Model Group:ankers kolom 59e:12934709
12972179 | 58 achtenvijftigste verdieping | Model Group:ankers kolom 59e:12934747
12972180 | 58 achtenvijftigste verdieping | Model Group:ankers kolom 59e:12934747
12972181 | 58 achtenvijftigste verdieping | Model Group:ankers kolom 59e:12934747
12972182 | 58 achtenvijftigste verdieping | Model Group:ankers kolom 59e:12934747
12972187 | 58 achtenvijftigste verdieping | Model Group:ankers kolom 59e:12934762
12972188 | 58 achtenvijftigste verdieping | Model Group:ankers kolom 59e:12934762
12972189 | 58 achtenvijftigste verdieping | Model Group:ankers kolom 59e:12934762
12972190 | 58 achtenvijftigste verdieping | Model Group:ankers kolom 59e:12934762
12972195 | 58 achtenvijftigste verdieping | Model Group:ankers kolom 59e:12934781
12972196 | 58 achtenvijftigste verdieping | Model Group:ankers kolom 59e:12934781
12972197 | 58 achtenvijftigste verdieping | Model Group:ankers kolom 59e:12934781
12972198 | 58 achtenvijftigste verdieping | Model Group:ankers kolom 59e:12934781

# IfcBuildingElementProxy: Ø20/M24x1005 (4)
In: 04 vierde verdieping
Pset_BuildingElementProxyCommon - Reference: Ø20/M24x1005
Pset_ManufacturerTypeInformation - Manufacturer: HALFEN b.v.
Name (GM_Stekanker_DEMU_4010 GV:Ø20/M24x1005:...)
13923417
13924230
13924381
13924506

# IfcBuildingElementProxy: Ø20/M24x705 (31)
Classification: 28 Hoofddraagconstructies (Uniformat)
Pset_BuildingElementProxyCommon - Reference: Ø20/M24x705
Pset_ManufacturerTypeInformation - Manufacturer: HALFEN b.v.
Name (GM_Stekanker_DEMU_4010 GV:Ø20/M24x705:...) | In | Group
10333265 | 00 begane grond | Model Group:luifel ankers kolom as H1:10333272
10333267 | 00 begane grond | Model Group:luifel ankers kolom as H1:10333272
10333269 | 00 begane grond | Model Group:luifel ankers kolom as H1:10333272
10333295 | 01 eerste verdieping | Model Group:luifel ankers kolom as H1:10333300
10333297 | 01 eerste verdieping | Model Group:luifel ankers kolom as H1:10333300
10333299 | 00a eerste tussenverdieping | Model Group:luifel ankers kolom as H1:10333300
10333308 | 01 eerste verdieping | Model Group:luifel ankers kolom as H1:10333313
10333310 | 01 eerste verdieping | Model Group:luifel ankers kolom as H1:10333313
10333312 | 00a eerste tussenverdieping | Model Group:luifel ankers kolom as H1:10333313
10333321 | 01 eerste verdieping | Model Group:luifel ankers kolom as H1:10333326
10333323 | 01 eerste verdieping | Model Group:luifel ankers kolom as H1:10333326
10333325 | 00a eerste tussenverdieping | Model Group:luifel ankers kolom as H1:10333326
10333334 | 01 eerste verdieping | Model Group:luifel ankers kolom as H1:10333339
10333336 | 01 eerste verdieping | Model Group:luifel ankers kolom as H1:10333339
10333338 | 00a eerste tussenverdieping | Model Group:luifel ankers kolom as H1:10333339
10333347 | 01 eerste verdieping | Model Group:luifel ankers kolom as H1:10333352
10333349 | 01 eerste verdieping | Model Group:luifel ankers kolom as H1:10333352
10333351 | 00a eerste tussenverdieping | Model Group:luifel ankers kolom as H1:10333352
10333360 | 01 eerste verdieping | Model Group:luifel ankers kolom as H1:10333365
10333362 | 01 eerste verdieping | Model Group:luifel ankers kolom as H1:10333365
10333364 | 00a eerste tussenverdieping | Model Group:luifel ankers kolom as H1:10333365
10340613 | 01 eerste verdieping | Model Group:luifel ankers kolom as H1:10340618
10340615 | 01 eerste verdieping | Model Group:luifel ankers kolom as H1:10340618
10340617 | 00a eerste tussenverdieping | Model Group:luifel ankers kolom as H1:10340618
10340626 | 01 eerste verdieping | Model Group:luifel ankers kolom as H1:10340631
10340628 | 01 eerste verdieping | Model Group:luifel ankers kolom as H1:10340631
10340630 | 00a eerste tussenverdieping | Model Group:luifel ankers kolom as H1:10340631
10340642 | 00 begane grond | Model Group:luifel ankers 1.22:10340645
10340644 | 00 begane grond | Model Group:luifel ankers 1.22:10340645
10340662 | 00a eerste tussenverdieping | Model Group:luifel ankers 1.22:10340665
10340664 | 00a eerste tussenverdieping | Model Group:luifel ankers 1.22:10340665

# IfcBuildingElementProxy: Ø20/M24x705 (47)
Type - Classification: 28 Hoofddraagconstructies (Uniformat)
Pset_BuildingElementProxyCommon - Reference: Ø20/M24x705
Pset_ManufacturerTypeInformation - Manufacturer: HALFEN b.v.
Name (GM_Stekanker_DEMU_4010 GV:Ø20/M24x705:...) | In | Group
10333263 | 00 begane grond | Model Group:luifel ankers kolom as H1:10333272
10333266 | 00 begane grond | Model Group:luifel ankers kolom as H1:10333272
10333268 | 00 begane grond | Model Group:luifel ankers kolom as H1:10333272
10333294 | 01 eerste verdieping | Model Group:luifel ankers kolom as H1:10333300
10333296 | 01 eerste verdieping | Model Group:luifel ankers kolom as H1:10333300
10333298 | 00a eerste tussenverdieping | Model Group:luifel ankers kolom as H1:10333300
10333307 | 01 eerste verdieping | Model Group:luifel ankers kolom as H1:10333313
10333309 | 01 eerste verdieping | Model Group:luifel ankers kolom as H1:10333313
10333311 | 00a eerste tussenverdieping | Model Group:luifel ankers kolom as H1:10333313
10333320 | 01 eerste verdieping | Model Group:luifel ankers kolom as H1:10333326
10333322 | 01 eerste verdieping | Model Group:luifel ankers kolom as H1:10333326
10333324 | 00a eerste tussenverdieping | Model Group:luifel ankers kolom as H1:10333326
10333333 | 01 eerste verdieping | Model Group:luifel ankers kolom as H1:10333339
10333335 | 01 eerste verdieping | Model Group:luifel ankers kolom as H1:10333339
10333337 | 00a eerste tussenverdieping | Model Group:luifel ankers kolom as H1:10333339
10333346 | 01 eerste verdieping | Model Group:luifel ankers kolom as H1:10333352
10333348 | 01 eerste verdieping | Model Group:luifel ankers kolom as H1:10333352
10333350 | 00a eerste tussenverdieping | Model Group:luifel ankers kolom as H1:10333352
10333359 | 01 eerste verdieping | Model Group:luifel ankers kolom as H1:10333365
10333361 | 01 eerste verdieping | Model Group:luifel ankers kolom as H1:10333365
10333363 | 00a eerste tussenverdieping | Model Group:luifel ankers kolom as H1:10333365
10340612 | 01 eerste verdieping | Model Group:luifel ankers kolom as H1:10340618
10340614 | 01 eerste verdieping | Model Group:luifel ankers kolom as H1:10340618
10340616 | 00a eerste tussenverdieping | Model Group:luifel ankers kolom as H1:10340618
10340625 | 01 eerste verdieping | Model Group:luifel ankers kolom as H1:10340631
10340627 | 01 eerste verdieping | Model Group:luifel ankers kolom as H1:10340631
10340629 | 00a eerste tussenverdieping | Model Group:luifel ankers kolom as H1:10340631
10340638 | 00 begane grond | Model Group:luifel ankers 1.22:10340645
10340643 | 00 begane grond | Model Group:luifel ankers 1.22:10340645
10340661 | 00a eerste tussenverdieping | Model Group:luifel ankers 1.22:10340665
10340663 | 00a eerste tussenverdieping | Model Group:luifel ankers 1.22:10340665
12933711 | 58 achtenvijftigste verdieping | Model Group:ankers kolom hoek 59e:12934297
12933915 | 58 achtenvijftigste verdieping | Model Group:ankers kolom hoek 59e:12934297
12933942 | 58 achtenvijftigste verdieping | Model Group:ankers kolom hoek 59e:12934297
12933944 | 58 achtenvijftigste verdieping | Model Group:ankers kolom hoek 59e:12934297
12934347 | 58 achtenvijftigste verdieping | Model Group:ankers kolom hoek 59e:12934352
12934349 | 58 achtenvijftigste verdieping | Model Group:ankers kolom hoek 59e:12934352
12934350 | 58 achtenvijftigste verdieping | Model Group:ankers kolom hoek 59e:12934352
12934351 | 58 achtenvijftigste verdieping | Model Group:ankers kolom hoek 59e:12934352
12934360 | 58 achtenvijftigste verdieping | Model Group:ankers kolom hoek 59e:12934364
12934361 | 58 achtenvijftigste verdieping | Model Group:ankers kolom hoek 59e:12934364
12934362 | 58 achtenvijftigste verdieping | Model Group:ankers kolom hoek 59e:12934364
12934363 | 58 achtenvijftigste verdieping | Model Group:ankers kolom hoek 59e:12934364
12934383 | 58 achtenvijftigste verdieping | Model Group:ankers kolom hoek 59e:12934387
12934384 | 58 achtenvijftigste verdieping | Model Group:ankers kolom hoek 59e:12934387
12934385 | 58 achtenvijftigste verdieping | Model Group:ankers kolom hoek 59e:12934387
12934386 | 58 achtenvijftigste verdieping | Model Group:ankers kolom hoek 59e:12934387

# IfcBuildingElementProxy: Ø25/M30x1055 (gebogen), GM_Stekanker_DEMU_4010 GV:Ø25/M30x1055 (gebogen):10412649
In: 00 begane grond
Type - Classification: 28 Hoofddraagconstructies (Uniformat)
Pset_BuildingElementProxyCommon - Reference: Ø25/M30x1055 (gebogen)
Pset_ManufacturerTypeInformation - Manufacturer: HALFEN b.v.

# IfcColumn: 300x1780, NLRS_28.11_SCO_TLB_prefabbeton kolom vierkant_gen:300x1780:4123558
In: 00 begane grond
Type - ElementType: 300x1780; PredefinedType: COLUMN; Classification: 28.11 hoofddraagconstructies - kolommen en liggers, kolom-/liggerconstructies (Uniformat); Material: NLRS_f2_beton prefab
Pset_ColumnCommon - LoadBearing: yes; IsExternal: no; Reference: 300x1780

# IfcColumn: 300x550 (11)
Type - ElementType: 300x550; PredefinedType: COLUMN; Classification: 28.11 hoofddraagconstructies - kolommen en liggers, kolom-/liggerconstructies (Uniformat); Material: NLRS_f2_beton prefab
Pset_ColumnCommon - LoadBearing: yes; IsExternal: no; Reference: 300x550
Name (NLRS_28.11_SCO_TLB_prefabbeton kolom vierkant_gen:300x550:...) | In
4162817 | 00 begane grond
4163083 | 00 begane grond
4163104 | 00 begane grond
4163117 | 00 begane grond
4163132 | 00 begane grond
4163147 | 00 begane grond
4163162 | 00 begane grond
4163177 | 00 begane grond
4163190 | 00 begane grond
4163205 | 00 begane grond
4384357 | 01 eerste verdieping

# IfcColumn: 300x880 (48)
Type - ElementType: 300x880; PredefinedType: COLUMN; Classification: 28.11 hoofddraagconstructies - kolommen en liggers, kolom-/liggerconstructies (Uniformat); Material: NLRS_f2_beton ihwg
Pset_ColumnCommon - LoadBearing: yes; IsExternal: no; Reference: 300x880
Name (NLRS_28.11_SCO_TLB_beton kolom ihwg_gen:300x880:...) | In | Group
4783681 | 41 eenenveertigste verdieping | Model Group:NLRS_01.00_verdieping type M_gen:4783248
4783683 | 41 eenenveertigste verdieping | Model Group:NLRS_01.00_verdieping type M_gen:4783248
4783685 | 41 eenenveertigste verdieping | Model Group:NLRS_01.00_verdieping type M_gen:4783248
4783687 | 41 eenenveertigste verdieping | Model Group:NLRS_01.00_verdieping type M_gen:4783248
4803200 | 42 tweeënveertigste verdieping | Model Group:NLRS_01.00_verdieping type N_gen:9026295
4803202 | 42 tweeënveertigste verdieping | Model Group:NLRS_01.00_verdieping type N_gen:9026295
4803204 | 42 tweeënveertigste verdieping | Model Group:NLRS_01.00_verdieping type N_gen:9026295
4803206 | 42 tweeënveertigste verdieping | Model Group:NLRS_01.00_verdieping type N_gen:9026295
4979934 | 51 eenenvijftigste verdieping | Model Group:NLRS_01.00_verdieping type R_gen:4806332
4979936 | 51 eenenvijftigste verdieping | Model Group:NLRS_01.00_verdieping type R_gen:4806332
4979938 | 51 eenenvijftigste verdieping | Model Group:NLRS_01.00_verdieping type R_gen:4806332
4979940 | 51 eenenvijftigste verdieping | Model Group:NLRS_01.00_verdieping type R_gen:4806332
4981706 | 52 tweeënvijftigste verdieping
4981708 | 52 tweeënvijftigste verdieping
4981710 | 52 tweeënvijftigste verdieping
4981712 | 52 tweeënvijftigste verdieping
9028056 | 47 zevenenveertigste verdieping | Model Group:NLRS_01.00_verdieping type O_gen:4790454
9028058 | 47 zevenenveertigste verdieping | Model Group:NLRS_01.00_verdieping type O_gen:4790454
9028060 | 47 zevenenveertigste verdieping | Model Group:NLRS_01.00_verdieping type O_gen:4790454
9028062 | 47 zevenenveertigste verdieping | Model Group:NLRS_01.00_verdieping type O_gen:4790454
9028932 | 50 vijftigste verdieping | Model Group:NLRS_01.00_verdieping type P_gen:4791750
9028934 | 50 vijftigste verdieping | Model Group:NLRS_01.00_verdieping type P_gen:4791750
9028936 | 50 vijftigste verdieping | Model Group:NLRS_01.00_verdieping type P_gen:4791750
9028938 | 50 vijftigste verdieping | Model Group:NLRS_01.00_verdieping type P_gen:4791750
9148111 | 43 drieënveertigste verdieping | Model Group:NLRS_01.00_verdieping type N_gen:4788726
9148113 | 43 drieënveertigste verdieping | Model Group:NLRS_01.00_verdieping type N_gen:4788726
9148115 | 43 drieënveertigste verdieping | Model Group:NLRS_01.00_verdieping type N_gen:4788726
9148117 | 43 drieënveertigste verdieping | Model Group:NLRS_01.00_verdieping type N_gen:4788726
9148403 | 44 vierenveertigste verdieping | Model Group:NLRS_01.00_verdieping type N_44e verdieping_gen:4789158
9148405 | 44 vierenveertigste verdieping | Model Group:NLRS_01.00_verdieping type N_44e verdieping_gen:4789158
9148407 | 44 vierenveertigste verdieping | Model Group:NLRS_01.00_verdieping type N_44e verdieping_gen:4789158
9148409 | 44 vierenveertigste verdieping | Model Group:NLRS_01.00_verdieping type N_44e verdieping_gen:4789158
9148695 | 45 vijfenveertigste verdieping | Model Group:NLRS_01.00_verdieping type N_gen:4789590
9148697 | 45 vijfenveertigste verdieping | Model Group:NLRS_01.00_verdieping type N_gen:4789590
9148699 | 45 vijfenveertigste verdieping | Model Group:NLRS_01.00_verdieping type N_gen:4789590
9148701 | 45 vijfenveertigste verdieping | Model Group:NLRS_01.00_verdieping type N_gen:4789590
9148987 | 46 zesenveertigste verdieping | Model Group:NLRS_01.00_verdieping type N_gen:4790022
9148989 | 46 zesenveertigste verdieping | Model Group:NLRS_01.00_verdieping type N_gen:4790022
9148991 | 46 zesenveertigste verdieping | Model Group:NLRS_01.00_verdieping type N_gen:4790022
9148993 | 46 zesenveertigste verdieping | Model Group:NLRS_01.00_verdieping type N_gen:4790022
9149279 | 49 negenenveertigste verdieping | Model Group:NLRS_01.00_verdieping type N_gen:4791318
9149281 | 49 negenenveertigste verdieping | Model Group:NLRS_01.00_verdieping type N_gen:4791318
9149283 | 49 negenenveertigste verdieping | Model Group:NLRS_01.00_verdieping type N_gen:4791318
9149285 | 49 negenenveertigste verdieping | Model Group:NLRS_01.00_verdieping type N_gen:4791318
9152801 | 48 achtenveertigste verdieping | Model Group:NLRS_01.00_verdieping type O_gen:4790886
9152803 | 48 achtenveertigste verdieping | Model Group:NLRS_01.00_verdieping type O_gen:4790886
9152805 | 48 achtenveertigste verdieping | Model Group:NLRS_01.00_verdieping type O_gen:4790886
9152807 | 48 achtenveertigste verdieping | Model Group:NLRS_01.00_verdieping type O_gen:4790886

# IfcColumn: 400x400 (4)
Type - ElementType: 400x400; PredefinedType: COLUMN; Classification: 28.11 hoofddraagconstructies - kolommen en liggers, kolom-/liggerconstructies (Uniformat); Material: NLRS_f2_beton ihwg
Pset_ColumnCommon - LoadBearing: yes; IsExternal: no; Reference: 400x400
Name (NLRS_28.11_SCO_TLB_beton kolom ihwg_gen:400x400:...) | In
4385307 | 01 eerste verdieping
6484586 | 00a eerste tussenverdieping
6484884 | 02 tweede verdieping
6485384 | 00 begane grond

# IfcColumn: 400x730, NLRS_28.11_SCO_TLB_beton kolom ihwg_gen:400x730:4129817
In: 00 begane grond
Type - ElementType: 400x730; PredefinedType: COLUMN; Classification: 28.11 hoofddraagconstructies - kolommen en liggers, kolom-/liggerconstructies (Uniformat); Material: NLRS_f2_beton ihwg
Pset_ColumnCommon - LoadBearing: yes; IsExternal: no; Reference: 400x730

# IfcColumn: 400x880 (80)
Type - ElementType: 400x880; PredefinedType: COLUMN; Classification: 28.11 hoofddraagconstructies - kolommen en liggers, kolom-/liggerconstructies (Uniformat); Material: NLRS_f2_beton ihwg
Pset_ColumnCommon - LoadBearing: yes; IsExternal: no; Reference: 400x880
Name (NLRS_28.11_SCO_TLB_beton kolom ihwg_gen:400x880:...) | In | Group
4694956 | 21 eenentwintigste verdieping | Model Group:NLRS_01.00_verdieping type F1_gen:4694955
4694958 | 21 eenentwintigste verdieping | Model Group:NLRS_01.00_verdieping type F1_gen:4694955
4694960 | 21 eenentwintigste verdieping | Model Group:NLRS_01.00_verdieping type F1_gen:4694955
4694962 | 21 eenentwintigste verdieping | Model Group:NLRS_01.00_verdieping type F1_gen:4694955
8986115 | 22 tweeëntwintigste verdieping | Model Group:NLRS_01.00_verdieping type G_gen:8994214
8986117 | 22 tweeëntwintigste verdieping | Model Group:NLRS_01.00_verdieping type G_gen:8994214
8986119 | 22 tweeëntwintigste verdieping | Model Group:NLRS_01.00_verdieping type G_gen:8994214
8986121 | 22 tweeëntwintigste verdieping | Model Group:NLRS_01.00_verdieping type G_gen:8994214
8995879 | 24 vierentwintigste verdieping | Model Group:NLRS_01.00_verdieping type H_gen:4746600
8995881 | 24 vierentwintigste verdieping | Model Group:NLRS_01.00_verdieping type H_gen:4746600
8995883 | 24 vierentwintigste verdieping | Model Group:NLRS_01.00_verdieping type H_gen:4746600
8995885 | 24 vierentwintigste verdieping | Model Group:NLRS_01.00_verdieping type H_gen:4746600
8996171 | 25 vijfentwintigste verdieping | Model Group:NLRS_01.00_verdieping type J_gen:4747032
8996173 | 25 vijfentwintigste verdieping | Model Group:NLRS_01.00_verdieping type J_gen:4747032
8996175 | 25 vijfentwintigste verdieping | Model Group:NLRS_01.00_verdieping type J_gen:4747032
8996177 | 25 vijfentwintigste verdieping | Model Group:NLRS_01.00_verdieping type J_gen:4747032
8996463 | 26 zesentwintigste verdieping | Model Group:NLRS_01.00_verdieping type K_gen:4747464
8996465 | 26 zesentwintigste verdieping | Model Group:NLRS_01.00_verdieping type K_gen:4747464
8996467 | 26 zesentwintigste verdieping | Model Group:NLRS_01.00_verdieping type K_gen:4747464
8996469 | 26 zesentwintigste verdieping | Model Group:NLRS_01.00_verdieping type K_gen:4747464
8997631 | 30 dertigste verdieping | Model Group:NLRS_01.00_verdieping (type L)_gen:4749192
8997633 | 30 dertigste verdieping | Model Group:NLRS_01.00_verdieping (type L)_gen:4749192
8997635 | 30 dertigste verdieping | Model Group:NLRS_01.00_verdieping (type L)_gen:4749192
8997637 | 30 dertigste verdieping | Model Group:NLRS_01.00_verdieping (type L)_gen:4749192
9134774 | 23 drieëntwintigste verdieping | Model Group:NLRS_01.00_verdieping type F2_gen:4779563
9134776 | 23 drieëntwintigste verdieping | Model Group:NLRS_01.00_verdieping type F2_gen:4779563
9134778 | 23 drieëntwintigste verdieping | Model Group:NLRS_01.00_verdieping type F2_gen:4779563
9134780 | 23 drieëntwintigste verdieping | Model Group:NLRS_01.00_verdieping type F2_gen:4779563
9135067 | 28 achtentwintigste verdieping | Model Group:NLRS_01.00_verdieping type F1_gen:4748328
9135069 | 28 achtentwintigste verdieping | Model Group:NLRS_01.00_verdieping type F1_gen:4748328
9135071 | 28 achtentwintigste verdieping | Model Group:NLRS_01.00_verdieping type F1_gen:4748328
9135073 | 28 achtentwintigste verdieping | Model Group:NLRS_01.00_verdieping type F1_gen:4748328
9135360 | 29 negenentwintigste verdieping | Model Group:NLRS_01.00_verdieping type F1_gen:4748760
9135362 | 29 negenentwintigste verdieping | Model Group:NLRS_01.00_verdieping type F1_gen:4748760
9135364 | 29 negenentwintigste verdieping | Model Group:NLRS_01.00_verdieping type F1_gen:4748760
9135366 | 29 negenentwintigste verdieping | Model Group:NLRS_01.00_verdieping type F1_gen:4748760
9135653 | 33 drieëndertigste verdieping | Model Group:NLRS_01.00_verdieping type F1_gen:4750488
9135655 | 33 drieëndertigste verdieping | Model Group:NLRS_01.00_verdieping type F1_gen:4750488
9135657 | 33 drieëndertigste verdieping | Model Group:NLRS_01.00_verdieping type F1_gen:4750488
9135659 | 33 drieëndertigste verdieping | Model Group:NLRS_01.00_verdieping type F1_gen:4750488
9138640 | 31 eenendertigste verdieping | Model Group:NLRS_01.00_verdieping type G_gen:4749624
9138642 | 31 eenendertigste verdieping | Model Group:NLRS_01.00_verdieping type G_gen:4749624
9138644 | 31 eenendertigste verdieping | Model Group:NLRS_01.00_verdieping type G_gen:4749624
9138646 | 31 eenendertigste verdieping | Model Group:NLRS_01.00_verdieping type G_gen:4749624
9138930 | 32 tweeëndertigste verdieping | Model Group:NLRS_01.00_verdieping type G_gen:4750056
9138932 | 32 tweeëndertigste verdieping | Model Group:NLRS_01.00_verdieping type G_gen:4750056
9138934 | 32 tweeëndertigste verdieping | Model Group:NLRS_01.00_verdieping type G_gen:4750056
9138936 | 32 tweeëndertigste verdieping | Model Group:NLRS_01.00_verdieping type G_gen:4750056
9140519 | 34 vierendertigste verdieping | Model Group:NLRS_01.00_verdieping type H_gen:4750920
9140521 | 34 vierendertigste verdieping | Model Group:NLRS_01.00_verdieping type H_gen:4750920
9140523 | 34 vierendertigste verdieping | Model Group:NLRS_01.00_verdieping type H_gen:4750920
9140525 | 34 vierendertigste verdieping | Model Group:NLRS_01.00_verdieping type H_gen:4750920
9141459 | 35 vijfendertigste verdieping | Model Group:NLRS_01.00_verdieping type J_gen:4751352
9141461 | 35 vijfendertigste verdieping | Model Group:NLRS_01.00_verdieping type J_gen:4751352
9141463 | 35 vijfendertigste verdieping | Model Group:NLRS_01.00_verdieping type J_gen:4751352
9141465 | 35 vijfendertigste verdieping | Model Group:NLRS_01.00_verdieping type J_gen:4751352
9142406 | 27 zevenentwintigste verdieping | Model Group:NLRS_01.00_verdieping type K_gen:4747896
9142408 | 27 zevenentwintigste verdieping | Model Group:NLRS_01.00_verdieping type K_gen:4747896
9142410 | 27 zevenentwintigste verdieping | Model Group:NLRS_01.00_verdieping type K_gen:4747896
9142412 | 27 zevenentwintigste verdieping | Model Group:NLRS_01.00_verdieping type K_gen:4747896
9142696 | 38 achtendertigste verdieping | Model Group:NLRS_01.00_verdieping type K_gen:4752648
9142698 | 38 achtendertigste verdieping | Model Group:NLRS_01.00_verdieping type K_gen:4752648
9142700 | 38 achtendertigste verdieping | Model Group:NLRS_01.00_verdieping type K_gen:4752648
9142702 | 38 achtendertigste verdieping | Model Group:NLRS_01.00_verdieping type K_gen:4752648
9142986 | 39 negenendertigste verdieping | Model Group:NLRS_01.00_verdieping type K_gen:4753080
9142988 | 39 negenendertigste verdieping | Model Group:NLRS_01.00_verdieping type K_gen:4753080
9142990 | 39 negenendertigste verdieping | Model Group:NLRS_01.00_verdieping type K_gen:4753080
9142992 | 39 negenendertigste verdieping | Model Group:NLRS_01.00_verdieping type K_gen:4753080
9145228 | 36 zesendertigste verdieping | Model Group:NLRS_01.00_verdieping type K_gen:4751784
9145230 | 36 zesendertigste verdieping | Model Group:NLRS_01.00_verdieping type K_gen:4751784
9145232 | 36 zesendertigste verdieping | Model Group:NLRS_01.00_verdieping type K_gen:4751784
9145234 | 36 zesendertigste verdieping | Model Group:NLRS_01.00_verdieping type K_gen:4751784
9145518 | 37 zevenendertigste verdieping | Model Group:NLRS_01.00_verdieping type K_gen:4752216
9145520 | 37 zevenendertigste verdieping | Model Group:NLRS_01.00_verdieping type K_gen:4752216
9145522 | 37 zevenendertigste verdieping | Model Group:NLRS_01.00_verdieping type K_gen:4752216
9145524 | 37 zevenendertigste verdieping | Model Group:NLRS_01.00_verdieping type K_gen:4752216
9147107 | 40 veertigste verdieping | Model Group:NLRS_01.00_verdieping (type L)_gen:4753512
9147109 | 40 veertigste verdieping | Model Group:NLRS_01.00_verdieping (type L)_gen:4753512
9147111 | 40 veertigste verdieping | Model Group:NLRS_01.00_verdieping (type L)_gen:4753512
9147113 | 40 veertigste verdieping | Model Group:NLRS_01.00_verdieping (type L)_gen:4753512

# IfcColumn: 500x500 (24)
Type - ElementType: 500x500; PredefinedType: COLUMN; Classification: 28.11 hoofddraagconstructies - kolommen en liggers, kolom-/liggerconstructies (Uniformat); Material: NLRS_f2_beton prefab
Pset_ColumnCommon - LoadBearing: yes; IsExternal: no; Reference: 500x500
Name (NLRS_28.11_SCO_TLB_prefabbeton kolom vierkant_gen:500x500:...) | In
4161029 | 00 begane grond
4161039 | 00 begane grond
4161045 | 00 begane grond
4161051 | 00 begane grond
4161057 | 00 begane grond
4161063 | 00 begane grond
4161069 | 00 begane grond
4161075 | 00 begane grond
4888869 | 01 eerste verdieping
4888871 | 01 eerste verdieping
4888873 | 01 eerste verdieping
4888875 | 01 eerste verdieping
4888877 | 01 eerste verdieping
4888879 | 01 eerste verdieping
4888881 | 01 eerste verdieping
4888883 | 01 eerste verdieping
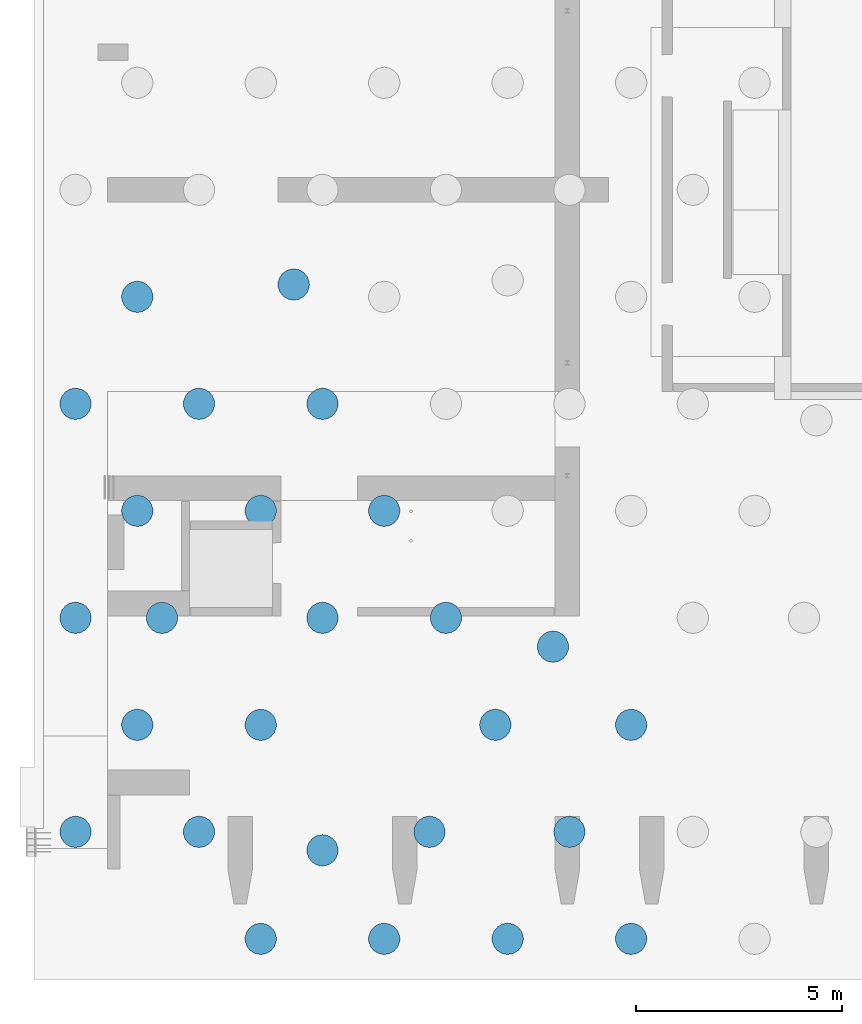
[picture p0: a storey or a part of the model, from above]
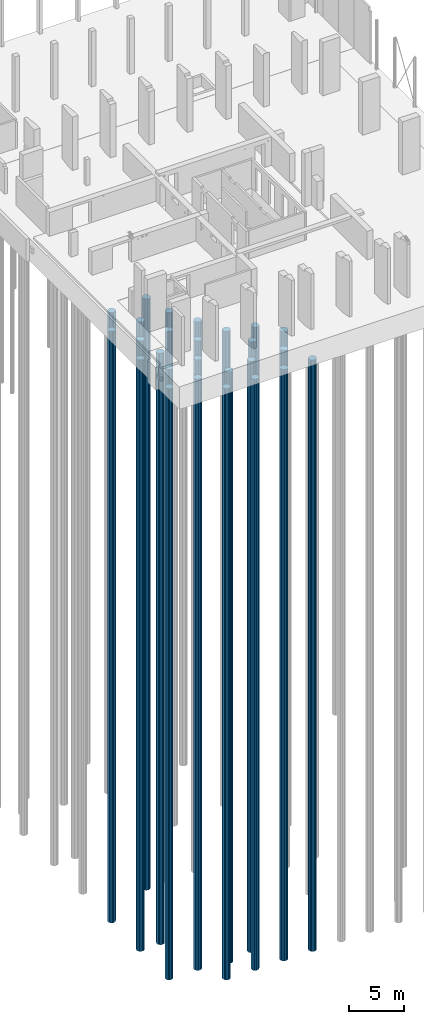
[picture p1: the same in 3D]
Properties of the parts of a building model (IFC2X3), part 6 of 21

# IfcColumn: 500x500 (24)
Name (NLRS_28.11_SCO_TLB_prefabbeton kolom vierkant_gen:500x500:...) | In
4888957 | 02 tweede verdieping
4888959 | 02 tweede verdieping
4888961 | 02 tweede verdieping
4888963 | 02 tweede verdieping
4888965 | 02 tweede verdieping
4888967 | 02 tweede verdieping
4888969 | 02 tweede verdieping
4921677 | 02 tweede verdieping

# IfcColumn: 500x880 (64)
Type - ElementType: 500x880; PredefinedType: COLUMN; Classification: 28.11 hoofddraagconstructies - kolommen en liggers, kolom-/liggerconstructies (Uniformat); Material: NLRS_f2_beton ihwg
Pset_ColumnCommon - LoadBearing: yes; IsExternal: no; Reference: 500x880
Name (NLRS_28.11_SCO_TLB_beton kolom ihwg_gen:500x880:...) | In | Group
4690646 | 06 zesde verdieping | Model Group:NLRS_01.00_verdieping type B1_gen:4644030
4690648 | 06 zesde verdieping | Model Group:NLRS_01.00_verdieping type B1_gen:4644030
4690650 | 06 zesde verdieping | Model Group:NLRS_01.00_verdieping type B1_gen:4644030
4690652 | 06 zesde verdieping | Model Group:NLRS_01.00_verdieping type B1_gen:4644030
4822169 | 05 vijfde verdieping
4822171 | 05 vijfde verdieping
4822173 | 05 vijfde verdieping
4822175 | 05 vijfde verdieping
5667254 | 09 negende verdieping | Model Group:NLRS_01.00_verdieping type C2_gen:4703193
5667256 | 09 negende verdieping | Model Group:NLRS_01.00_verdieping type C2_gen:4703193
5667258 | 09 negende verdieping | Model Group:NLRS_01.00_verdieping type C2_gen:4703193
5667260 | 09 negende verdieping | Model Group:NLRS_01.00_verdieping type C2_gen:4703193
9036727 | 16 zestiende verdieping | Model Group:NLRS_01.00_verdieping type E_gen:4739081
9036729 | 16 zestiende verdieping | Model Group:NLRS_01.00_verdieping type E_gen:4739081
9036731 | 16 zestiende verdieping | Model Group:NLRS_01.00_verdieping type E_gen:4739081
9036733 | 16 zestiende verdieping | Model Group:NLRS_01.00_verdieping type E_gen:4739081
9050647 | 15 vijftiende verdieping | Model Group:NLRS_01.00_verdieping type D_gen:4731036
9050649 | 15 vijftiende verdieping | Model Group:NLRS_01.00_verdieping type D_gen:4731036
9050651 | 15 vijftiende verdieping | Model Group:NLRS_01.00_verdieping type D_gen:4731036
9050653 | 15 vijftiende verdieping | Model Group:NLRS_01.00_verdieping type D_gen:4731036
9050943 | 17 zeventiende verdieping | Model Group:NLRS_01.00_verdieping type D_gen:4731494
9050945 | 17 zeventiende verdieping | Model Group:NLRS_01.00_verdieping type D_gen:4731494
9050947 | 17 zeventiende verdieping | Model Group:NLRS_01.00_verdieping type D_gen:4731494
9050949 | 17 zeventiende verdieping | Model Group:NLRS_01.00_verdieping type D_gen:4731494
9090915 | 07 zevende verdieping | Model Group:NLRS_01.00_verdieping type C1_gen:4689025
9090917 | 07 zevende verdieping | Model Group:NLRS_01.00_verdieping type C1_gen:4689025
9090919 | 07 zevende verdieping | Model Group:NLRS_01.00_verdieping type C1_gen:4689025
9090921 | 07 zevende verdieping | Model Group:NLRS_01.00_verdieping type C1_gen:4689025
9125796 | 10 tiende verdieping | Model Group:NLRS_01.00_verdieping type B2_gen:9035827
9125798 | 10 tiende verdieping | Model Group:NLRS_01.00_verdieping type B2_gen:9035827
9125800 | 10 tiende verdieping | Model Group:NLRS_01.00_verdieping type B2_gen:9035827
9125802 | 10 tiende verdieping | Model Group:NLRS_01.00_verdieping type B2_gen:9035827
9126103 | 12 twaalfde verdieping | Model Group:NLRS_01.00_verdieping type B2_gen:4738165
9126105 | 12 twaalfde verdieping | Model Group:NLRS_01.00_verdieping type B2_gen:4738165
9126107 | 12 twaalfde verdieping | Model Group:NLRS_01.00_verdieping type B2_gen:4738165
9126109 | 12 twaalfde verdieping | Model Group:NLRS_01.00_verdieping type B2_gen:4738165
9126410 | 14 veertiende verdieping | Model Group:NLRS_01.00_verdieping type B2_gen:4738623
9126412 | 14 veertiende verdieping | Model Group:NLRS_01.00_verdieping type B2_gen:4738623
9126414 | 14 veertiende verdieping | Model Group:NLRS_01.00_verdieping type B2_gen:4738623
9126416 | 14 veertiende verdieping | Model Group:NLRS_01.00_verdieping type B2_gen:4738623
9128882 | 11 elfde verdieping | Model Group:NLRS_01.00_verdieping type C2_gen:9049706
9128884 | 11 elfde verdieping | Model Group:NLRS_01.00_verdieping type C2_gen:9049706
9128886 | 11 elfde verdieping | Model Group:NLRS_01.00_verdieping type C2_gen:9049706
9128888 | 11 elfde verdieping | Model Group:NLRS_01.00_verdieping type C2_gen:9049706
9129185 | 13 dertiende verdieping | Model Group:NLRS_01.00_verdieping type C2_gen:4730578
9129187 | 13 dertiende verdieping | Model Group:NLRS_01.00_verdieping type C2_gen:4730578
9129189 | 13 dertiende verdieping | Model Group:NLRS_01.00_verdieping type C2_gen:4730578
9129191 | 13 dertiende verdieping | Model Group:NLRS_01.00_verdieping type C2_gen:4730578
9131598 | 18 achttiende verdieping | Model Group:NLRS_01.00_verdieping type E_gen:4739539
9131600 | 18 achttiende verdieping | Model Group:NLRS_01.00_verdieping type E_gen:4739539
9131602 | 18 achttiende verdieping | Model Group:NLRS_01.00_verdieping type E_gen:4739539
9131604 | 18 achttiende verdieping | Model Group:NLRS_01.00_verdieping type E_gen:4739539
9132663 | 19 negentiende verdieping | Model Group:NLRS_01.00_verdieping type C2_gen:4731952
9132665 | 19 negentiende verdieping | Model Group:NLRS_01.00_verdieping type C2_gen:4731952
9132667 | 19 negentiende verdieping | Model Group:NLRS_01.00_verdieping type C2_gen:4731952
9132669 | 19 negentiende verdieping | Model Group:NLRS_01.00_verdieping type C2_gen:4731952
9133780 | 20 twintigste verdieping | Model Group:NLRS_01.00_verdieping type B2_gen:4739997
9133782 | 20 twintigste verdieping | Model Group:NLRS_01.00_verdieping type B2_gen:4739997
9133784 | 20 twintigste verdieping | Model Group:NLRS_01.00_verdieping type B2_gen:4739997
9133786 | 20 twintigste verdieping | Model Group:NLRS_01.00_verdieping type B2_gen:4739997
10782733 | 08 achtste verdieping | Model Group:NLRS_01.00_verdieping type B1_gen:4714770
10782735 | 08 achtste verdieping | Model Group:NLRS_01.00_verdieping type B1_gen:4714770
10782737 | 08 achtste verdieping | Model Group:NLRS_01.00_verdieping type B1_gen:4714770
10782739 | 08 achtste verdieping | Model Group:NLRS_01.00_verdieping type B1_gen:4714770

# IfcColumn: 600/300x2120/1270 (45)
Type - ElementType: 600/300x2120/1270; PredefinedType: COLUMN; Classification: 28.11 hoofddraagconstructies - kolommen en liggers, kolom-/liggerconstructies (Uniformat); Material: NLRS_f2_beton ihwg
Pset_ColumnCommon - LoadBearing: yes; IsExternal: no; Reference: 600/300x2120/1270
Name (NLRS_28.11_SCO_TLB_beton kolom ihwg V vorm_gen:600/300x2120/1270:...) | In
4122588 | 00 begane grond
4123113 | 00 begane grond
4123130 | 00 begane grond
4123147 | 00 begane grond
4123164 | 00 begane grond
4123181 | 00 begane grond
4123198 | 00 begane grond
4123215 | 00 begane grond
4123232 | 00 begane grond
4385271 | 01 eerste verdieping
4385273 | 01 eerste verdieping
4385275 | 01 eerste verdieping
4385277 | 01 eerste verdieping
4385279 | 01 eerste verdieping
4385281 | 01 eerste verdieping
4385283 | 01 eerste verdieping
4385285 | 01 eerste verdieping
4385287 | 01 eerste verdieping
4830460 | 04 vierde verdieping
4830462 | 04 vierde verdieping
4830464 | 04 vierde verdieping
4830466 | 04 vierde verdieping
4830468 | 04 vierde verdieping
4830470 | 04 vierde verdieping
4830472 | 04 vierde verdieping
4830474 | 04 vierde verdieping
4830476 | 04 vierde verdieping
4831152 | 02 tweede verdieping
4831154 | 02 tweede verdieping
4831156 | 02 tweede verdieping
4831158 | 02 tweede verdieping
4831160 | 02 tweede verdieping
4831162 | 02 tweede verdieping
4831164 | 02 tweede verdieping
4831166 | 02 tweede verdieping
4831168 | 02 tweede verdieping
4831334 | 03 derde verdieping
4831336 | 03 derde verdieping
4831338 | 03 derde verdieping
4831340 | 03 derde verdieping
4831342 | 03 derde verdieping
4831344 | 03 derde verdieping
4831346 | 03 derde verdieping
4831348 | 03 derde verdieping
4831350 | 03 derde verdieping

# IfcColumn: 600/300x2120/770 (40)
Type - ElementType: 600/300x2120/770; PredefinedType: COLUMN; Classification: 28.11 hoofddraagconstructies - kolommen en liggers, kolom-/liggerconstructies (Uniformat); Material: NLRS_f2_beton ihwg
Pset_ColumnCommon - LoadBearing: yes; IsExternal: no; Reference: 600/300x2120/770
Name (NLRS_28.11_SCO_TLB_beton kolom ihwg V vorm_gen:600/300x2120/770:...) | In
4123249 | 00 begane grond
4123406 | 00 begane grond
4123423 | 00 begane grond
4123442 | 00 begane grond
4123459 | 00 begane grond
4123474 | 00 begane grond
4123491 | 00 begane grond
4123508 | 00 begane grond
4385289 | 01 eerste verdieping | Pset_ColumnCommon - Slope: 0 deg
4385291 | 01 eerste verdieping
4385293 | 01 eerste verdieping
4385295 | 01 eerste verdieping
4385297 | 01 eerste verdieping
4385299 | 01 eerste verdieping
4385301 | 01 eerste verdieping
4385303 | 01 eerste verdieping
4420769 | 02 tweede verdieping
4420771 | 02 tweede verdieping
4420773 | 02 tweede verdieping
4420775 | 02 tweede verdieping
4420777 | 02 tweede verdieping
4420779 | 02 tweede verdieping
4420781 | 02 tweede verdieping
4420783 | 02 tweede verdieping | Pset_ColumnCommon - Slope: 0 deg
4830356 | 04 vierde verdieping
4830358 | 04 vierde verdieping
4830360 | 04 vierde verdieping
4830362 | 04 vierde verdieping
4830364 | 04 vierde verdieping
4830366 | 04 vierde verdieping
4830368 | 04 vierde verdieping
4830370 | 04 vierde verdieping
4830478 | 03 derde verdieping
4830480 | 03 derde verdieping
4830482 | 03 derde verdieping
4830484 | 03 derde verdieping
4830486 | 03 derde verdieping
4830488 | 03 derde verdieping
4830490 | 03 derde verdieping
4830492 | 03 derde verdieping

# IfcColumn: 600x1320 (14)
Type - ElementType: 600x1320; PredefinedType: COLUMN; Classification: 28.11 hoofddraagconstructies - kolommen en liggers, kolom-/liggerconstructies (Uniformat); Material: NLRS_f2_beton ihwg
Pset_ColumnCommon - LoadBearing: yes; IsExternal: no; Reference: 600x1320
Name (NLRS_28.11_SCO_TLB_beton kolom ihwg_gen:600x1320:...) | In
4943608 | 03 derde verdieping
4943610 | 03 derde verdieping
4943612 | 03 derde verdieping
4943614 | 03 derde verdieping
4943616 | 03 derde verdieping
4943810 | 03 derde verdieping
4943837 | 03 derde verdieping
4943960 | 04 vierde verdieping
4943962 | 04 vierde verdieping
4943964 | 04 vierde verdieping
4943966 | 04 vierde verdieping
4943968 | 04 vierde verdieping
4943976 | 04 vierde verdieping
4943978 | 04 vierde verdieping

# IfcColumn: 600x1820 (9)
Type - ElementType: 600x1820; PredefinedType: COLUMN; Classification: 28.11 hoofddraagconstructies - kolommen en liggers, kolom-/liggerconstructies (Uniformat); Material: NLRS_f2_beton ihwg
Pset_ColumnCommon - LoadBearing: yes; IsExternal: no; Reference: 600x1820
Name (NLRS_28.11_SCO_TLB_beton kolom ihwg_gen:600x1820:...) | In
4121268 | 00 begane grond
4121555 | 00 begane grond
4385259 | 01 eerste verdieping
4385267 | 01 eerste verdieping
4420743 | 02 tweede verdieping
4420745 | 02 tweede verdieping
4420747 | 02 tweede verdieping
4420749 | 02 tweede verdieping
4420751 | 02 tweede verdieping

# IfcColumn: 600x1950 (2)
Type - ElementType: 600x1950; PredefinedType: COLUMN; Classification: 28.11 hoofddraagconstructies - kolommen en liggers, kolom-/liggerconstructies (Uniformat); Material: NLRS_f2_beton ihwg
Pset_ColumnCommon - LoadBearing: yes; IsExternal: no; Reference: 600x1950
Name (NLRS_28.11_SCO_TLB_beton kolom ihwg_gen:600x1950:...) | In
4385269 | 01 eerste verdieping
4447228 | 02 tweede verdieping

# IfcColumn: 600x1990 (5)
Type - ElementType: 600x1990; PredefinedType: COLUMN; Classification: 28.11 hoofddraagconstructies - kolommen en liggers, kolom-/liggerconstructies (Uniformat); Material: NLRS_f2_beton ihwg
Pset_ColumnCommon - LoadBearing: yes; IsExternal: no; Reference: 600x1990
Name (NLRS_28.11_SCO_TLB_beton kolom ihwg_gen:600x1990:...) | In
4120662 | 00 begane grond
4124904 | 00 begane grond
4385257 | 01 eerste verdieping
4385305 | 01 eerste verdieping
4420785 | 02 tweede verdieping

# IfcColumn: 600x2120, NLRS_28.11_SCO_TLB_beton kolom ihwg_gen:600x2120:4121611
In: 00 begane grond
Type - ElementType: 600x2120; PredefinedType: COLUMN; Classification: 28.11 hoofddraagconstructies - kolommen en liggers, kolom-/liggerconstructies (Uniformat); Material: NLRS_f2_beton ihwg
Pset_ColumnCommon - LoadBearing: yes; IsExternal: no; Reference: 600x2120

# IfcColumn: 600x820 (8)
Type - ElementType: 600x820; PredefinedType: COLUMN; Classification: 28.11 hoofddraagconstructies - kolommen en liggers, kolom-/liggerconstructies (Uniformat); Material: NLRS_f2_beton ihwg
Pset_ColumnCommon - LoadBearing: yes; IsExternal: no; Reference: 600x820
Name (NLRS_28.11_SCO_TLB_beton kolom ihwg_gen:600x820:...) | In
4943606 | 03 derde verdieping
4943618 | 03 derde verdieping
4943620 | 03 derde verdieping
4943622 | 03 derde verdieping
4943958 | 04 vierde verdieping
4943970 | 04 vierde verdieping
4943972 | 04 vierde verdieping
4943974 | 04 vierde verdieping

# IfcColumn: 700x1820 (6)
Type - ElementType: 700x1820; PredefinedType: COLUMN; Classification: 28.11 hoofddraagconstructies - kolommen en liggers, kolom-/liggerconstructies (Uniformat); Material: NLRS_f2_beton ihwg
Pset_ColumnCommon - LoadBearing: yes; IsExternal: no; Reference: 700x1820
Name (NLRS_28.11_SCO_TLB_beton kolom ihwg_gen:700x1820:...) | In
4121361 | 00 begane grond
4121439 | 00 begane grond
4121484 | 00 begane grond
4385261 | 01 eerste verdieping
4385263 | 01 eerste verdieping
4385265 | 01 eerste verdieping

# IfcColumn: kolom HEA 100 (8)
Type - ElementType: kolom HEA 100; PredefinedType: COLUMN; Classification: 28.11 hoofddraagconstructies - kolommen en liggers, kolom-/liggerconstructies (Uniformat); Material: NLRS_h2_staal
Pset_ColumnCommon - LoadBearing: yes; IsExternal: no; Reference: kolom HEA 100
Name (NLRS_28.11_SCO_TLB_stalen kolom HEA_gen:kolom HEA 100:...) | In
9647257 | 00 begane grond
9648023 | 00 begane grond
9648052 | 00 begane grond
9648055 | 00 begane grond
9886783 | 00a eerste tussenverdieping
9886786 | 00a eerste tussenverdieping
9889140 | 00a eerste tussenverdieping
9889143 | 00a eerste tussenverdieping

# IfcColumn: kolom HEA 140 (4)
Type - ElementType: kolom HEA 140; PredefinedType: COLUMN; Classification: 28.11 hoofddraagconstructies - kolommen en liggers, kolom-/liggerconstructies (Uniformat); Material: NLRS_h2_staal
Pset_ColumnCommon - LoadBearing: yes; IsExternal: no; Reference: kolom HEA 140
Name (NLRS_28.11_SCO_TLB_stalen kolom HEA_gen:kolom HEA 140:...) | In
12216424 | 03 derde verdieping
12229978 | 03 derde verdieping
12241337 | 03 derde verdieping
12281369 | 04 vierde verdieping

# IfcColumn: kolom HEA 160, NLRS_28.11_SCO_TLB_stalen kolom HEA_gen:kolom HEA 160:12085855
In: 00 begane grond
Type - ElementType: kolom HEA 160; PredefinedType: COLUMN; Classification: 28.11 hoofddraagconstructies - kolommen en liggers, kolom-/liggerconstructies (Uniformat); Material: NLRS_h2_staal
Pset_ColumnCommon - LoadBearing: yes; IsExternal: no; Reference: kolom HEA 160

# IfcColumn: kolom HEA 240 (12)
In: 00 begane grond
Type - ElementType: kolom HEA 240; PredefinedType: COLUMN; Classification: 28.11 hoofddraagconstructies - kolommen en liggers, kolom-/liggerconstructies (Uniformat); Material: NLRS_h2_staal
Pset_ColumnCommon - LoadBearing: yes; IsExternal: no; Reference: kolom HEA 240
Name (NLRS_28.11_SCO_TLB_stalen kolom HEA_gen:kolom HEA 240:...)
5162046
5162607
5162636
5162651
5162666
5162681
5162750
5162765
6415139
8687585
12313521
13016192

# IfcColumn: kolom HEB 140 (6)
In: 03 derde verdieping
Type - ElementType: kolom HEB 140; PredefinedType: COLUMN; Classification: 28.11 hoofddraagconstructies - kolommen en liggers, kolom-/liggerconstructies (Uniformat); Material: NLRS_h2_staal
Pset_ColumnCommon - LoadBearing: yes; IsExternal: no; Reference: kolom HEB 140
Name (NLRS_28.11_SCO_TLB_stalen kolom HEB_gen:kolom HEB 140:...)
9182608
13119459
13119477
13119499
13126859
13129555

# IfcColumn: kolom HEB 220 (64)
Type - ElementType: kolom HEB 220; PredefinedType: COLUMN; Classification: 28.11 hoofddraagconstructies - kolommen en liggers, kolom-/liggerconstructies (Uniformat); Material: NLRS_h2_staal
Pset_ColumnCommon - LoadBearing: yes; IsExternal: no; Reference: kolom HEB 220
Name (NLRS_28.11_SCO_TLB_stalen kolom HEB_gen:kolom HEB 220:...) | In
5306045 | 59 negenenvijftigste verdieping
5306047 | 59 negenenvijftigste verdieping
5306049 | 59 negenenvijftigste verdieping
5306051 | 59 negenenvijftigste verdieping
5306055 | 59 negenenvijftigste verdieping
5306057 | 59 negenenvijftigste verdieping
5306059 | 59 negenenvijftigste verdieping
5313462 | 59 negenenvijftigste verdieping
5313513 | 59 negenenvijftigste verdieping
5313629 | 59 negenenvijftigste verdieping
5313631 | 59 negenenvijftigste verdieping
5313633 | 59 negenenvijftigste verdieping
10268383 | 59 negenenvijftigste verdieping
10268389 | 59 negenenvijftigste verdieping
10268395 | 59 negenenvijftigste verdieping
10268397 | 59 negenenvijftigste verdieping
12803819 | 60 zestigste verdieping
12803821 | 60 zestigste verdieping
12803823 | 60 zestigste verdieping
12803825 | 60 zestigste verdieping
12803827 | 60 zestigste verdieping
12803829 | 60 zestigste verdieping
12803831 | 60 zestigste verdieping
12803833 | 60 zestigste verdieping
12803835 | 60 zestigste verdieping
12803837 | 60 zestigste verdieping
12803839 | 60 zestigste verdieping
12803841 | 60 zestigste verdieping
12803843 | 60 zestigste verdieping
12803845 | 60 zestigste verdieping
12803847 | 60 zestigste verdieping
12803849 | 60 zestigste verdieping
12806043 | 61 eenenzestigste verdieping
12806045 | 61 eenenzestigste verdieping
12806047 | 61 eenenzestigste verdieping
12806049 | 61 eenenzestigste verdieping
12806051 | 61 eenenzestigste verdieping
12806053 | 61 eenenzestigste verdieping
12806055 | 61 eenenzestigste verdieping
12806057 | 61 eenenzestigste verdieping
12806059 | 61 eenenzestigste verdieping
12806061 | 61 eenenzestigste verdieping
12806063 | 61 eenenzestigste verdieping
12806065 | 61 eenenzestigste verdieping
12806067 | 61 eenenzestigste verdieping
12806069 | 61 eenenzestigste verdieping
12806071 | 61 eenenzestigste verdieping
12806073 | 61 eenenzestigste verdieping
12965355 | 62 tweeënzestigste verdieping
12965357 | 62 tweeënzestigste verdieping
12965359 | 62 tweeënzestigste verdieping
12965361 | 62 tweeënzestigste verdieping
12965363 | 62 tweeënzestigste verdieping
12965365 | 62 tweeënzestigste verdieping
12965367 | 62 tweeënzestigste verdieping
12965369 | 62 tweeënzestigste verdieping
12965371 | 62 tweeënzestigste verdieping
12965373 | 62 tweeënzestigste verdieping
12965375 | 62 tweeënzestigste verdieping
12965377 | 62 tweeënzestigste verdieping
12965379 | 62 tweeënzestigste verdieping
12965381 | 62 tweeënzestigste verdieping
12965383 | 62 tweeënzestigste verdieping
12965385 | 62 tweeënzestigste verdieping

# IfcColumn: kolom HEB 300 (6)
In: 01 eerste verdieping
Type - ElementType: kolom HEB 300; PredefinedType: COLUMN; Classification: 28.11 hoofddraagconstructies - kolommen en liggers, kolom-/liggerconstructies (Uniformat); Material: NLRS_h2_staal
Pset_ColumnCommon - LoadBearing: yes; IsExternal: no; Reference: kolom HEB 300
Name (NLRS_28.11_SCO_TLB_stalen kolom HEB_gen:kolom HEB 300:...) | Group
13502491 | Model Group:Luifel_HEB300:12767605
13502779 | Model Group:Luifel_HEB300:12766569
13502835 | Model Group:Luifel_HEB300:12767154
13502863 | Model Group:Luifel_HEB300:12767335
13502891 | Model Group:Luifel_HEB300:12767433
13502919 | Model Group:Luifel_HEB300:12767518

# IfcColumn: kolom IPE 240 (4)
Type - ElementType: kolom IPE 240; PredefinedType: COLUMN; Classification: 28.11 hoofddraagconstructies - kolommen en liggers, kolom-/liggerconstructies (Uniformat); Material: NLRS_h2_staal
Pset_ColumnCommon - LoadBearing: yes; IsExternal: no; Reference: kolom IPE 240
Name (NLRS_28.11_SCO_TLB_stalen kolom IPE_gen:kolom IPE 240:...) | In
12216144 | 04 vierde verdieping
13482223 | 04 vierde verdieping
13543857 | 00 begane grond
13544126 | 00 begane grond

# IfcColumn: kolom UNP 160, NLRS_28.11_SCO_TLB_stalen kolom UNP_gen:kolom UNP 160:12959364
In: 59 negenenvijftigste verdieping
Type - ElementType: kolom UNP 160; PredefinedType: COLUMN; Classification: 28.11 hoofddraagconstructies - kolommen en liggers, kolom-/liggerconstructies (Uniformat); Material: NLRS_h2_staal
Pset_ColumnCommon - LoadBearing: yes; IsExternal: no; Reference: kolom UNP 160

# IfcColumn: kolom UNP 180 (7)
In: 03 derde verdieping
Type - ElementType: kolom UNP 180; PredefinedType: COLUMN; Classification: 28.11 hoofddraagconstructies - kolommen en liggers, kolom-/liggerconstructies (Uniformat); Material: NLRS_h2_staal
Pset_ColumnCommon - LoadBearing: yes; IsExternal: no; Reference: kolom UNP 180
Name (NLRS_28.11_SCO_TLB_stalen kolom UNP_gen:kolom UNP 180:...)
13585919
13585921
13610155
13610157
13610693
13610992
13611185

# IfcColumn: kolom buisprofiel rechthoekig RHSH_200x100x10 (44)
Type - ElementType: kolom buisprofiel rechthoekig RHSH_200x100x10; PredefinedType: COLUMN; Classification: 28.11 hoofddraagconstructies - kolommen en liggers, kolom-/liggerconstructies (Uniformat); Material: NLRS_h2_staal
Pset_ColumnCommon - LoadBearing: yes; IsExternal: no; Slope: 0 deg; Reference: kolom buisprofiel rechthoekig RHSH_200x100x10
Name (NLRS_28.11_SCO_TLB_stalen kolom buisprofiel rechthoekig_gen:kolom buisprofiel rechthoekig RHSH_200x100x10:...) | In
12026105 | 53 drieënvijftigste verdieping
12026333 | 53 drieënvijftigste verdieping
12026522 | 53 drieënvijftigste verdieping
12026633 | 53 drieënvijftigste verdieping
12028806 | 53 drieënvijftigste verdieping
12028812 | 53 drieënvijftigste verdieping
12028816 | 53 drieënvijftigste verdieping
12028818 | 53 drieënvijftigste verdieping
12501040 | 53 drieënvijftigste verdieping
12501042 | 53 drieënvijftigste verdieping
12501044 | 53 drieënvijftigste verdieping
12501046 | 53 drieënvijftigste verdieping
12501102 | 53 drieënvijftigste verdieping
12501104 | 53 drieënvijftigste verdieping
12501106 | 53 drieënvijftigste verdieping
12501108 | 53 drieënvijftigste verdieping
12862813 | 53 drieënvijftigste verdieping
12862873 | 53 drieënvijftigste verdieping
12862993 | 53 drieënvijftigste verdieping
12863063 | 53 drieënvijftigste verdieping
12960303 | 54 vierenvijftigste verdieping
12960305 | 54 vierenvijftigste verdieping
12960307 | 54 vierenvijftigste verdieping
12960309 | 54 vierenvijftigste verdieping
12960313 | 54 vierenvijftigste verdieping
12960315 | 54 vierenvijftigste verdieping
12960317 | 54 vierenvijftigste verdieping
12960319 | 54 vierenvijftigste verdieping
12960321 | 54 vierenvijftigste verdieping
12960323 | 54 vierenvijftigste verdieping
12960325 | 54 vierenvijftigste verdieping
12960327 | 54 vierenvijftigste verdieping
12960331 | 54 vierenvijftigste verdieping
12960333 | 54 vierenvijftigste verdieping
12960335 | 54 vierenvijftigste verdieping
12960337 | 54 vierenvijftigste verdieping
12960339 | 54 vierenvijftigste verdieping
12960341 | 54 vierenvijftigste verdieping
12960343 | 54 vierenvijftigste verdieping
12960345 | 54 vierenvijftigste verdieping
13852949 | 53 drieënvijftigste verdieping
13852951 | 54 vierenvijftigste verdieping
13853045 | 53 drieënvijftigste verdieping
13853047 | 54 vierenvijftigste verdieping

# IfcColumn: kolom buisprofiel rechthoekig RHSH_250x150x16 (138)
Type - ElementType: kolom buisprofiel rechthoekig RHSH_250x150x16; PredefinedType: COLUMN; Classification: 28.11 hoofddraagconstructies - kolommen en liggers, kolom-/liggerconstructies (Uniformat); Material: NLRS_h2_staal
Pset_ColumnCommon - LoadBearing: yes; IsExternal: no; Slope: 0 deg; Reference: kolom buisprofiel rechthoekig RHSH_250x150x16
Name (NLRS_28.11_SCO_TLB_stalen kolom buisprofiel rechthoekig_gen:kolom buisprofiel rechthoekig RHSH_250x150x16:...) | In
5305908 | 57 zevenenvijftigste verdieping
5305910 | 57 zevenenvijftigste verdieping
5305912 | 57 zevenenvijftigste verdieping
5305914 | 57 zevenenvijftigste verdieping
5305916 | 57 zevenenvijftigste verdieping
5305918 | 57 zevenenvijftigste verdieping
5305920 | 57 zevenenvijftigste verdieping
5305922 | 57 zevenenvijftigste verdieping
5305924 | 57 zevenenvijftigste verdieping
5305926 | 57 zevenenvijftigste verdieping
10268417 | 57 zevenenvijftigste verdieping
10268426 | 57 zevenenvijftigste verdieping
10268432 | 57 zevenenvijftigste verdieping
10268438 | 57 zevenenvijftigste verdieping
10268456 | 57 zevenenvijftigste verdieping
10268676 | 57 zevenenvijftigste verdieping
11892037 | 57 zevenenvijftigste verdieping
11892056 | 57 zevenenvijftigste verdieping
11892071 | 57 zevenenvijftigste verdieping
11892614 | 57 zevenenvijftigste verdieping
11892629 | 57 zevenenvijftigste verdieping
11892654 | 57 zevenenvijftigste verdieping
11892669 | 57 zevenenvijftigste verdieping
11892684 | 57 zevenenvijftigste verdieping
11892699 | 57 zevenenvijftigste verdieping
11892996 | 57 zevenenvijftigste verdieping
11893015 | 57 zevenenvijftigste verdieping
11893034 | 57 zevenenvijftigste verdieping
11893051 | 57 zevenenvijftigste verdieping
11893066 | 57 zevenenvijftigste verdieping
11893085 | 57 zevenenvijftigste verdieping
11893102 | 57 zevenenvijftigste verdieping
11893119 | 57 zevenenvijftigste verdieping
11893136 | 57 zevenenvijftigste verdieping
11893153 | 57 zevenenvijftigste verdieping
11893170 | 57 zevenenvijftigste verdieping
11893681 | 57 zevenenvijftigste verdieping
11893698 | 57 zevenenvijftigste verdieping
11893715 | 57 zevenenvijftigste verdieping
11893732 | 57 zevenenvijftigste verdieping
11893747 | 57 zevenenvijftigste verdieping
11893764 | 57 zevenenvijftigste verdieping
11893781 | 57 zevenenvijftigste verdieping
11893798 | 57 zevenenvijftigste verdieping
11893813 | 57 zevenenvijftigste verdieping
11893828 | 57 zevenenvijftigste verdieping
11893845 | 57 zevenenvijftigste verdieping
11894025 | 57 zevenenvijftigste verdieping
11894042 | 57 zevenenvijftigste verdieping
11894061 | 57 zevenenvijftigste verdieping
11894082 | 57 zevenenvijftigste verdieping
11894099 | 57 zevenenvijftigste verdieping
11894118 | 57 zevenenvijftigste verdieping
11894137 | 57 zevenenvijftigste verdieping
11894158 | 57 zevenenvijftigste verdieping
11894179 | 57 zevenenvijftigste verdieping
11925079 | 59 negenenvijftigste verdieping
12032012 | 59 negenenvijftigste verdieping
12032030 | 59 negenenvijftigste verdieping
12032046 | 59 negenenvijftigste verdieping
12032064 | 59 negenenvijftigste verdieping
12032080 | 59 negenenvijftigste verdieping
12032110 | 59 negenenvijftigste verdieping
12032130 | 59 negenenvijftigste verdieping
12032217 | 59 negenenvijftigste verdieping
12032235 | 59 negenenvijftigste verdieping
12032249 | 59 negenenvijftigste verdieping
12032263 | 59 negenenvijftigste verdieping
12032277 | 59 negenenvijftigste verdieping
12032295 | 59 negenenvijftigste verdieping
12032309 | 59 negenenvijftigste verdieping
12032403 | 59 negenenvijftigste verdieping
12032421 | 59 negenenvijftigste verdieping
12032441 | 59 negenenvijftigste verdieping
12032461 | 59 negenenvijftigste verdieping
12032495 | 59 negenenvijftigste verdieping
12032515 | 59 negenenvijftigste verdieping
12032609 | 59 negenenvijftigste verdieping
12032629 | 59 negenenvijftigste verdieping
12032643 | 59 negenenvijftigste verdieping
12032659 | 59 negenenvijftigste verdieping
12032677 | 59 negenenvijftigste verdieping
13737712 | 58 achtenvijftigste verdieping
13738962 | 58 achtenvijftigste verdieping
13739163 | 58 achtenvijftigste verdieping
13739321 | 58 achtenvijftigste verdieping
13739433 | 58 achtenvijftigste verdieping
13739977 | 58 achtenvijftigste verdieping
13740830 | 58 achtenvijftigste verdieping
13741670 | 58 achtenvijftigste verdieping
13741683 | 58 achtenvijftigste verdieping
13741979 | 58 achtenvijftigste verdieping
13742029 | 58 achtenvijftigste verdieping
13742250 | 58 achtenvijftigste verdieping
13742261 | 58 achtenvijftigste verdieping
13742943 | 58 achtenvijftigste verdieping
13743024 | 58 achtenvijftigste verdieping
13743223 | 58 achtenvijftigste verdieping
13743317 | 58 achtenvijftigste verdieping
13743631 | 58 achtenvijftigste verdieping
13743921 | 58 achtenvijftigste verdieping
13744082 | 58 achtenvijftigste verdieping
13744318 | 58 achtenvijftigste verdieping
13744377 | 58 achtenvijftigste verdieping
13744481 | 58 achtenvijftigste verdieping
13744657 | 58 achtenvijftigste verdieping
13744782 | 58 achtenvijftigste verdieping
13744865 | 58 achtenvijftigste verdieping
13744966 | 58 achtenvijftigste verdieping
13745046 | 58 achtenvijftigste verdieping
13745482 | 58 achtenvijftigste verdieping
13745499 | 58 achtenvijftigste verdieping
13745547 | 58 achtenvijftigste verdieping
13745596 | 58 achtenvijftigste verdieping
13745823 | 58 achtenvijftigste verdieping
13745838 | 58 achtenvijftigste verdieping
13745849 | 58 achtenvijftigste verdieping
13745867 | 58 achtenvijftigste verdieping
13745878 | 58 achtenvijftigste verdieping
13745905 | 58 achtenvijftigste verdieping
13745916 | 58 achtenvijftigste verdieping
13746000 | 58 achtenvijftigste verdieping
13746023 | 58 achtenvijftigste verdieping
13746034 | 58 achtenvijftigste verdieping
13746060 | 58 achtenvijftigste verdieping
13746534 | 58 achtenvijftigste verdieping
13746551 | 58 achtenvijftigste verdieping
13746566 | 58 achtenvijftigste verdieping
13746587 | 58 achtenvijftigste verdieping
13746718 | 58 achtenvijftigste verdieping
13746729 | 58 achtenvijftigste verdieping
13746740 | 58 achtenvijftigste verdieping
13746755 | 58 achtenvijftigste verdieping
13746769 | 58 achtenvijftigste verdieping
13746900 | 58 achtenvijftigste verdieping
13746911 | 58 achtenvijftigste verdieping
13746922 | 58 achtenvijftigste verdieping
13746936 | 58 achtenvijftigste verdieping

# IfcColumn: kolom buisprofiel rond CHS_1016x8, NLRS_28.11_SCO_TLB_stalen kolom buisprofiel rond kroon_gen:kolom buisprofiel rond CHS_1016x8:5312566
In: 62 tweeënzestigste verdieping
Type - ElementType: kolom buisprofiel rond CHS_1016x8; PredefinedType: COLUMN; Classification: 28.11 hoofddraagconstructies - kolommen en liggers, kolom-/liggerconstructies (Uniformat); Material: NLRS_h2_staal
Pset_ColumnCommon - LoadBearing: yes; IsExternal: no; Slope: 0 deg; Reference: kolom buisprofiel rond CHS_1016x8

# IfcColumn: kolom buisprofiel rond CHS_168.3x8 (14)
In: 03 derde verdieping
Type - ElementType: kolom buisprofiel rond CHS_168.3x8; PredefinedType: COLUMN; Classification: 28.11 hoofddraagconstructies - kolommen en liggers, kolom-/liggerconstructies (Uniformat); Material: NLRS_h2_staal
Pset_ColumnCommon - LoadBearing: yes; IsExternal: no; Reference: kolom buisprofiel rond CHS_168.3x8
Name (NLRS_28.11_SCO_TLB_stalen kolom buisprofiel rond_gen:kolom buisprofiel rond CHS_168.3x8:...) | Group
4921750 | Model Group:Array Group 2:4922479 | Pset_ColumnCommon - Slope: 0 deg
4922424 | Model Group:Array Group 2:4922479 | Pset_ColumnCommon - Slope: 0 deg
4922483 | Model Group:Array Group 2:4922487
4922485 | Model Group:Array Group 2:4922487
4922499 | Model Group:Array Group 2:4922503
4922501 | Model Group:Array Group 2:4922503
4922506 | Model Group:Array Group 2:4922510
4922508 | Model Group:Array Group 2:4922510
4922513 | Model Group:Array Group 2:4922517
4922515 | Model Group:Array Group 2:4922517
4922520 | Model Group:Array Group 2:4922524
4922522 | Model Group:Array Group 2:4922524
4922527
4922529

# IfcColumn: kolom buisprofiel warmgevormd vierkant SHSH_200x200x10 (64)
In: 59 negenenvijftigste verdieping
Type - ElementType: kolom buisprofiel warmgevormd vierkant SHSH_200x200x10; PredefinedType: COLUMN; Classification: 28.11 hoofddraagconstructies - kolommen en liggers, kolom-/liggerconstructies (Uniformat); Material: NLRS_h2_staal
Pset_ColumnCommon - LoadBearing: yes; IsExternal: no; Slope: 0 deg; Reference: kolom buisprofiel warmgevormd vierkant SHSH_200x200x10
Name (NLRS_28.11_SCO_TLB_stalen kolom buisprofiel warmgevormd vierkant_gen:kolom buisprofiel warmgevormd vierkant SHSH_200x200x10:...)
12032915
12033063
12033110
12033112
12033136
12033138
12033164
12033166
12033192
12033194
12033249
12033251
12033253
12033255
12033257
12033259
12033261
12033263
12033265
12033267
12035043
12035077
12035125
12035127
12035174
12035176
12035208
12035210
12035244
12035270
12035272
12035413
12035435
12035453
12035471
12035489
12035507
12035529
12035547
12035569
12035587
12035644
12035646
12035672
12035674
12035702
12035704
12035761
12035779
12035797
12212741
12212747
13848426
13848955
13848957
13849035
13849037
13849286
13849352
13849354
13849396
13849607
13849609
13849649

# IfcColumn: kolom buisprofiel warmgevormd vierkant SHSH_250x250x16 (8)
Type - ElementType: kolom buisprofiel warmgevormd vierkant SHSH_250x250x16; PredefinedType: COLUMN; Classification: 28.11 hoofddraagconstructies - kolommen en liggers, kolom-/liggerconstructies (Uniformat); Material: NLRS_h2_staal
Pset_ColumnCommon - LoadBearing: yes; IsExternal: no; Slope: 0 deg; Reference: kolom buisprofiel warmgevormd vierkant SHSH_250x250x16
Name (NLRS_28.11_SCO_TLB_stalen kolom buisprofiel warmgevormd vierkant_gen:kolom buisprofiel warmgevormd vierkant SHSH_250x250x16:...) | In
11915042 | 57 zevenenvijftigste verdieping
11915201 | 57 zevenenvijftigste verdieping
11915502 | 57 zevenenvijftigste verdieping
11915504 | 57 zevenenvijftigste verdieping
13738296 | 58 achtenvijftigste verdieping
13740086 | 58 achtenvijftigste verdieping
13745070 | 58 achtenvijftigste verdieping
13745469 | 58 achtenvijftigste verdieping

# IfcColumn: kolom stripstaal RECT_100x10 (16)
Type - ElementType: kolom stripstaal RECT_100x10; PredefinedType: COLUMN; Classification: 28.11 hoofddraagconstructies - kolommen en liggers, kolom-/liggerconstructies (Uniformat); Material: NLRS_h2_staal
Pset_ColumnCommon - LoadBearing: yes; IsExternal: no; Reference: kolom stripstaal RECT_100x10
Name (NLRS_28.11_SCO_TLB_stalen kolom stripstaal_gen:kolom stripstaal RECT_100x10:...) | In
13178286 | 03 derde verdieping | Group: Model Group:oplegschoen atriumkap:13180237
13180327 | 03 derde verdieping | Group: Model Group:oplegschoen atriumkap:13180346
13180758 | 03 derde verdieping | Group: Model Group:oplegschoen atriumkap:13180777
13180858 | 03 derde verdieping | Group: Model Group:oplegschoen atriumkap:13180877
13180960 | 03 derde verdieping | Group: Model Group:oplegschoen atriumkap:13180979
13181062 | 03 derde verdieping | Group: Model Group:oplegschoen atriumkap:13181081
13868467 | 58 achtenvijftigste verdieping
13868585 | 58 achtenvijftigste verdieping
13869110 | 58 achtenvijftigste verdieping
13869650 | 58 achtenvijftigste verdieping
13871980 | 58 achtenvijftigste verdieping
13878620 | 59 negenenvijftigste verdieping
13878622 | 59 negenenvijftigste verdieping
13878638 | 59 negenenvijftigste verdieping
13878654 | 59 negenenvijftigste verdieping
13883231 | 59 negenenvijftigste verdieping

# IfcColumn: kolom stripstaal RECT_160x10 (6)
In: 03 derde verdieping
Type - ElementType: kolom stripstaal RECT_160x10; PredefinedType: COLUMN; Classification: 28.11 hoofddraagconstructies - kolommen en liggers, kolom-/liggerconstructies (Uniformat); Material: NLRS_h2_staal
Pset_ColumnCommon - LoadBearing: yes; IsExternal: no; Reference: kolom stripstaal RECT_160x10
Name (NLRS_28.11_SCO_TLB_stalen kolom stripstaal_gen:kolom stripstaal RECT_160x10:...) | Group
13168071 | Model Group:oplegschoen atriumkap:13180237
13180309 | Model Group:oplegschoen atriumkap:13180346
13180745 | Model Group:oplegschoen atriumkap:13180777
13180845 | Model Group:oplegschoen atriumkap:13180877
13180947 | Model Group:oplegschoen atriumkap:13180979
13181049 | Model Group:oplegschoen atriumkap:13181081

# IfcColumn: kolom stripstaal RECT_170x10 (2)
In: 01 eerste verdieping
Type - ElementType: kolom stripstaal RECT_170x10; PredefinedType: COLUMN; Classification: 28.11 hoofddraagconstructies - kolommen en liggers, kolom-/liggerconstructies (Uniformat); Material: NLRS_h2_staal
Pset_ColumnCommon - LoadBearing: yes; IsExternal: no; Reference: kolom stripstaal RECT_170x10
Name (NLRS_28.11_SCO_TLB_stalen kolom stripstaal_gen:kolom stripstaal RECT_170x10:...) | Group
13501471 | Model Group:Luifel_IPE400:12780779
13501714 | Model Group:Luifel_IPE400:12780584

# IfcColumn: kolom stripstaal RECT_200x10 (2)
In: 03 derde verdieping
Type - ElementType: kolom stripstaal RECT_200x10; PredefinedType: COLUMN; Classification: 28.11 hoofddraagconstructies - kolommen en liggers, kolom-/liggerconstructies (Uniformat); Material: NLRS_h2_staal
Pset_ColumnCommon - LoadBearing: yes; IsExternal: no; Reference: kolom stripstaal RECT_200x10
Name (NLRS_28.11_SCO_TLB_stalen kolom stripstaal_gen:kolom stripstaal RECT_200x10:...)
12479492
12708479

# IfcColumn: kolom stripstaal RECT_200x20 (8)
In: 03 derde verdieping
Type - ElementType: kolom stripstaal RECT_200x20; PredefinedType: COLUMN; Classification: 28.11 hoofddraagconstructies - kolommen en liggers, kolom-/liggerconstructies (Uniformat); Material: NLRS_h2_staal
Pset_ColumnCommon - LoadBearing: yes; IsExternal: no; Reference: kolom stripstaal RECT_200x20
Name (NLRS_28.11_SCO_TLB_stalen kolom stripstaal_gen:kolom stripstaal RECT_200x20:...) | Group
12479172
12708477
13175609 | Model Group:oplegschoen atriumkap:13180237
13180313 | Model Group:oplegschoen atriumkap:13180346
13180749 | Model Group:oplegschoen atriumkap:13180777
13180849 | Model Group:oplegschoen atriumkap:13180877
13180951 | Model Group:oplegschoen atriumkap:13180979
13181053 | Model Group:oplegschoen atriumkap:13181081

# IfcColumn: kolom stripstaal RECT_200x25 (9)
In: 01 eerste verdieping
Type - ElementType: kolom stripstaal RECT_200x25; PredefinedType: COLUMN; Classification: 28.11 hoofddraagconstructies - kolommen en liggers, kolom-/liggerconstructies (Uniformat); Material: NLRS_h2_staal
Pset_ColumnCommon - LoadBearing: yes; IsExternal: no; Reference: kolom stripstaal RECT_200x25
Name (NLRS_28.11_SCO_TLB_stalen kolom stripstaal_gen:kolom stripstaal RECT_200x25:...) | Group
12723014 | Model Group:luifel kopplaat+schot:13003949
13004038 | Model Group:luifel kopplaat+schot:13004068
13004171 | Model Group:luifel kopplaat+schot:13004201
13004221 | Model Group:luifel kopplaat+schot:13004251
13004271 | Model Group:luifel kopplaat+schot:13004301
13004321 | Model Group:luifel kopplaat+schot:13004351
13004371 | Model Group:luifel kopplaat+schot:13004401
13004423 | Model Group:luifel kopplaat+schot:13004453
13004473 | Model Group:luifel kopplaat+schot:13004503

# IfcColumn: kolom stripstaal RECT_240x10, NLRS_28.11_SCO_TLB_stalen kolom stripstaal_gen:kolom stripstaal RECT_240x10:12352148
In: 01 eerste verdieping
Type - ElementType: kolom stripstaal RECT_240x10; PredefinedType: COLUMN; Classification: 28.11 hoofddraagconstructies - kolommen en liggers, kolom-/liggerconstructies (Uniformat); Material: NLRS_h2_staal
Pset_ColumnCommon - LoadBearing: yes; IsExternal: no; Reference: kolom stripstaal RECT_240x10

# IfcColumn: kolom stripstaal RECT_250x15 (6)
Type - ElementType: kolom stripstaal RECT_250x15; PredefinedType: COLUMN; Classification: 28.11 hoofddraagconstructies - kolommen en liggers, kolom-/liggerconstructies (Uniformat); Material: NLRS_h2_staal
Pset_ColumnCommon - LoadBearing: yes; IsExternal: no; Reference: kolom stripstaal RECT_250x15
Name (NLRS_28.11_SCO_TLB_stalen kolom stripstaal_gen:kolom stripstaal RECT_250x15:...) | In
13223285 | 58 achtenvijftigste verdieping
13223487 | 58 achtenvijftigste verdieping
13867556 | 58 achtenvijftigste verdieping
13878597 | 59 negenenvijftigste verdieping
13878599 | 59 negenenvijftigste verdieping
13878794 | 59 negenenvijftigste verdieping

# IfcColumn: kolom stripstaal RECT_250x5 (8)
Type - ElementType: kolom stripstaal RECT_250x5; PredefinedType: COLUMN; Classification: 28.11 hoofddraagconstructies - kolommen en liggers, kolom-/liggerconstructies (Uniformat); Material: NLRS_h2_staal
Pset_ColumnCommon - LoadBearing: yes; IsExternal: no; Reference: kolom stripstaal RECT_250x5
Name (NLRS_28.11_SCO_TLB_stalen kolom stripstaal_gen:kolom stripstaal RECT_250x5:...) | In
13240113 | 58 achtenvijftigste verdieping
13240206 | 58 achtenvijftigste verdieping
13240273 | 58 achtenvijftigste verdieping
13240338 | 58 achtenvijftigste verdieping
13878608 | 59 negenenvijftigste verdieping
13878610 | 59 negenenvijftigste verdieping
13878612 | 59 negenenvijftigste verdieping
13878614 | 59 negenenvijftigste verdieping

# IfcColumn: kolom stripstaal RECT_300x15 (6)
Type - ElementType: kolom stripstaal RECT_300x15; PredefinedType: COLUMN; Classification: 28.11 hoofddraagconstructies - kolommen en liggers, kolom-/liggerconstructies (Uniformat); Material: NLRS_h2_staal
Pset_ColumnCommon - LoadBearing: yes; IsExternal: no; Reference: kolom stripstaal RECT_300x15
Name (NLRS_28.11_SCO_TLB_stalen kolom stripstaal_gen:kolom stripstaal RECT_300x15:...) | In
13867438 | 58 achtenvijftigste verdieping
13871943 | 58 achtenvijftigste verdieping
13871960 | 58 achtenvijftigste verdieping
13878792 | 59 negenenvijftigste verdieping
13883221 | 59 negenenvijftigste verdieping
13883227 | 59 negenenvijftigste verdieping

# IfcColumn: kolom stripstaal RECT_300x25 (3)
Type - ElementType: kolom stripstaal RECT_300x25; PredefinedType: COLUMN; Classification: 28.11 hoofddraagconstructies - kolommen en liggers, kolom-/liggerconstructies (Uniformat); Material: NLRS_h2_staal
Pset_ColumnCommon - LoadBearing: yes; IsExternal: no; Reference: kolom stripstaal RECT_300x25
Name (NLRS_28.11_SCO_TLB_stalen kolom stripstaal_gen:kolom stripstaal RECT_300x25:...) | In | Group
13501453 | 01 eerste verdieping | Model Group:Luifel_IPE400:12780779
13501696 | 01 eerste verdieping | Model Group:Luifel_IPE400:12780584
13923518 | 54 vierenvijftigste verdieping

# IfcColumn: kolom stripstaal RECT_300x30 (16)
In: 01 eerste verdieping
Type - ElementType: kolom stripstaal RECT_300x30; PredefinedType: COLUMN; Classification: 28.11 hoofddraagconstructies - kolommen en liggers, kolom-/liggerconstructies (Uniformat); Material: NLRS_h2_staal
Pset_ColumnCommon - LoadBearing: yes; IsExternal: no; Reference: kolom stripstaal RECT_300x30
Name (NLRS_28.11_SCO_TLB_stalen kolom stripstaal_gen:kolom stripstaal RECT_300x30:...) | Group
13501447 | Model Group:Luifel_IPE400:12780779
13501449 | Model Group:Luifel_IPE400:12780779
13501690 | Model Group:Luifel_IPE400:12780584
13501692 | Model Group:Luifel_IPE400:12780584
13502495 | Model Group:Luifel_HEB300:12767605
13502497 | Model Group:Luifel_HEB300:12767605
13502783 | Model Group:Luifel_HEB300:12766569
13502785 | Model Group:Luifel_HEB300:12766569
13502839 | Model Group:Luifel_HEB300:12767154
13502841 | Model Group:Luifel_HEB300:12767154
13502867 | Model Group:Luifel_HEB300:12767335
13502869 | Model Group:Luifel_HEB300:12767335
13502895 | Model Group:Luifel_HEB300:12767433
13502897 | Model Group:Luifel_HEB300:12767433
13502923 | Model Group:Luifel_HEB300:12767518
13502925 | Model Group:Luifel_HEB300:12767518

# IfcColumn: kolom stripstaal RECT_300x5 (4)
Type - ElementType: kolom stripstaal RECT_300x5; PredefinedType: COLUMN; Classification: 28.11 hoofddraagconstructies - kolommen en liggers, kolom-/liggerconstructies (Uniformat); Material: NLRS_h2_staal
Pset_ColumnCommon - LoadBearing: yes; IsExternal: no; Reference: kolom stripstaal RECT_300x5
Name (NLRS_28.11_SCO_TLB_stalen kolom stripstaal_gen:kolom stripstaal RECT_300x5:...) | In
13871945 | 58 achtenvijftigste verdieping
13871947 | 58 achtenvijftigste verdieping
13883223 | 59 negenenvijftigste verdieping
13883225 | 59 negenenvijftigste verdieping

# IfcColumn: kolom stripstaal RECT_80x10 (8)
In: 01 eerste verdieping
Type - ElementType: kolom stripstaal RECT_80x10; PredefinedType: COLUMN; Classification: 28.11 hoofddraagconstructies - kolommen en liggers, kolom-/liggerconstructies (Uniformat); Material: NLRS_h2_staal
Pset_ColumnCommon - LoadBearing: yes; IsExternal: no; Reference: kolom stripstaal RECT_80x10
Name (NLRS_28.11_SCO_TLB_stalen kolom stripstaal_gen:kolom stripstaal RECT_80x10:...) | Group
13501451 | Model Group:Luifel_IPE400:12780779
13501694 | Model Group:Luifel_IPE400:12780584
13502503 | Model Group:Luifel_HEB300:12767605
13502791 | Model Group:Luifel_HEB300:12766569
13502847 | Model Group:Luifel_HEB300:12767154
13502875 | Model Group:Luifel_HEB300:12767335
13502903 | Model Group:Luifel_HEB300:12767433
13502931 | Model Group:Luifel_HEB300:12767518

# IfcColumn: kolom stripstaal RECT_80x12 (38)
In: 04 vierde verdieping
Type - ElementType: kolom stripstaal RECT_80x12; PredefinedType: COLUMN; Classification: 28.11 hoofddraagconstructies - kolommen en liggers, kolom-/liggerconstructies (Uniformat); Material: NLRS_h2_staal
Pset_ColumnCommon - LoadBearing: yes; IsExternal: no; Reference: kolom stripstaal RECT_80x12
Name (NLRS_28.11_SCO_TLB_stalen kolom stripstaal_gen:kolom stripstaal RECT_80x12:...) | Group
13569513 | Model Group:Koppeling-2:13570695
13570914 | Model Group:Koppeling-2:13570917
13571235 | Model Group:Koppeling-2:13571238
13571290 | Model Group:Koppeling-2:13571293
13571779 | Model Group:Koppeling-2:13571782
13571785 | Model Group:Koppeling-2:13571788
13571845 | Model Group:Koppeling-2:13571848
13571851 | Model Group:Koppeling-2:13571854
13571911 | Model Group:Koppeling-2:13571914
13571917 | Model Group:Koppeling-2:13571920
13572300 | Model Group:Koppeling-2:13572303
13572334 | Model Group:Koppeling-2:13572337
13572641 | Model Group:Koppeling-2:13572644
13572647 | Model Group:Koppeling-2:13572650
13572964 | Model Group:Koppeling-2:13572967
13573371 | Model Group:Koppeling-2:13573374
13573377 | Model Group:Koppeling-2:13573380
13573916 | Model Group:Wand-W06:13525900
13574044 | Model Group:Koppeling-2:13574047
13575089 | Model Group:Koppeling-2a:13575092
13575189 | Model Group:Koppeling-2a:13575192
13583094 | Model Group:Koppeling-2:13583097
13583299 | Model Group:Koppeling-2:13583302
13583390 | Model Group:Koppeling-2:13583393
13583424 | Model Group:Koppeling-2:13583427
13583449 | Model Group:Koppeling-2:13583452
13583474 | Model Group:Koppeling-2:13583477
13583499 | Model Group:Koppeling-2:13583502
13583534 | Model Group:Koppeling-2:13583537
13583559 | Model Group:Koppeling-2:13583562
13583584 | Model Group:Koppeling-2:13583587
13583657 | Model Group:Koppeling-2b:13584197
13584221 | Model Group:Koppeling-2b:13584224
13611801 | Model Group:Koppeling-2b:13611804
13611807 | Model Group:Koppeling-2b:13611810
13715537
13715781
13716400

# IfcColumn: kolom stripstaal RECT_90x10 (2)
In: 01 eerste verdieping
Type - ElementType: kolom stripstaal RECT_90x10; PredefinedType: COLUMN; Classification: 28.11 hoofddraagconstructies - kolommen en liggers, kolom-/liggerconstructies (Uniformat); Material: NLRS_h2_staal
Pset_ColumnCommon - LoadBearing: yes; IsExternal: no; Reference: kolom stripstaal RECT_90x10
Name (NLRS_28.11_SCO_TLB_stalen kolom stripstaal_gen:kolom stripstaal RECT_90x10:...) | Group
13501455 | Model Group:Luifel_IPE400:12780779
13501698 | Model Group:Luifel_IPE400:12780584

# IfcColumn: kolomgelijzijdig hoekprofiel LEQU_120x120x12_! (35)
In: 04 vierde verdieping
Type - ElementType: kolomgelijzijdig hoekprofiel LEQU_120x120x12_!; PredefinedType: COLUMN; Classification: 28.11 hoofddraagconstructies - kolommen en liggers, kolom-/liggerconstructies (Uniformat); Material: NLRS_h2_staal
Pset_ColumnCommon - LoadBearing: yes; IsExternal: no; Reference: kolomgelijzijdig hoekprofiel LEQU_120x120x12_!
Name (NLRS_28.11_SCO_TLB_stalen kolom hoekprofiel gelijkzijdig_gen:kolomgelijzijdig hoekprofiel LEQU_120x120x12_!:...) | Group
13568341 | Model Group:Koppeling-2:13570695
13570912 | Model Group:Koppeling-2:13570917
13571233 | Model Group:Koppeling-2:13571238
13571288 | Model Group:Koppeling-2:13571293
13571777 | Model Group:Koppeling-2:13571782
13571783 | Model Group:Koppeling-2:13571788
13571843 | Model Group:Koppeling-2:13571848
13571849 | Model Group:Koppeling-2:13571854
13571909 | Model Group:Koppeling-2:13571914
13571915 | Model Group:Koppeling-2:13571920
13572298 | Model Group:Koppeling-2:13572303
13572332 | Model Group:Koppeling-2:13572337
13572639 | Model Group:Koppeling-2:13572644
13572645 | Model Group:Koppeling-2:13572650
13572962 | Model Group:Koppeling-2:13572967
13573369 | Model Group:Koppeling-2:13573374
13573375 | Model Group:Koppeling-2:13573380
13573914 | Model Group:Wand-W06:13525900
13574042 | Model Group:Koppeling-2:13574047
13575087 | Model Group:Koppeling-2a:13575092
13575187 | Model Group:Koppeling-2a:13575192
13583092 | Model Group:Koppeling-2:13583097
13583297 | Model Group:Koppeling-2:13583302
13583388 | Model Group:Koppeling-2:13583393
13583422 | Model Group:Koppeling-2:13583427
13583447 | Model Group:Koppeling-2:13583452
13583472 | Model Group:Koppeling-2:13583477
13583497 | Model Group:Koppeling-2:13583502
13583532 | Model Group:Koppeling-2:13583537
13583557 | Model Group:Koppeling-2:13583562
13583582 | Model Group:Koppeling-2:13583587
13583655 | Model Group:Koppeling-2b:13584197
13584219 | Model Group:Koppeling-2b:13584224
13611799 | Model Group:Koppeling-2b:13611804
13611805 | Model Group:Koppeling-2b:13611810

# IfcColumn: kolomgelijzijdig hoekprofiel LEQU_150x150x15 (8)
Type - ElementType: kolomgelijzijdig hoekprofiel LEQU_150x150x15; PredefinedType: COLUMN; Classification: 28.11 hoofddraagconstructies - kolommen en liggers, kolom-/liggerconstructies (Uniformat); Material: NLRS_h2_staal
Pset_ColumnCommon - LoadBearing: yes; IsExternal: no; Reference: kolomgelijzijdig hoekprofiel LEQU_150x150x15
Name (NLRS_28.11_SCO_TLB_stalen kolom hoekprofiel gelijkzijdig_gen:kolomgelijzijdig hoekprofiel LEQU_150x150x15:...) | In
10990182 | 01 eerste verdieping
10990184 | 01 eerste verdieping
10990194 | 01 eerste verdieping
10990196 | 01 eerste verdieping
10990206 | 01 eerste verdieping
10990208 | 01 eerste verdieping
10990218 | 00a eerste tussenverdieping
10990236 | 00a eerste tussenverdieping

# IfcColumn: ø360 (84)
Type - ElementType: ø360; PredefinedType: COLUMN; Classification: 28.11 hoofddraagconstructies - kolommen en liggers, kolom-/liggerconstructies (Uniformat); Material: NLRS_f2_beton prefab
Pset_ColumnCommon - LoadBearing: yes; IsExternal: no; Reference: ø360
Name (NLRS_28.11_SCO_TLB_prefabbeton kolom rond_gen:ø360:...) | In
11879016 | 53 drieënvijftigste verdieping
11879036 | 53 drieënvijftigste verdieping
11879042 | 53 drieënvijftigste verdieping
11879046 | 53 drieënvijftigste verdieping
11879050 | 53 drieënvijftigste verdieping
11879054 | 53 drieënvijftigste verdieping
11879058 | 53 drieënvijftigste verdieping
11879066 | 53 drieënvijftigste verdieping
11879070 | 53 drieënvijftigste verdieping
11879078 | 53 drieënvijftigste verdieping
11879088 | 53 drieënvijftigste verdieping
11879092 | 53 drieënvijftigste verdieping
11879096 | 53 drieënvijftigste verdieping
11879117 | 53 drieënvijftigste verdieping
11879133 | 53 drieënvijftigste verdieping
11879135 | 53 drieënvijftigste verdieping
11879180 | 54 vierenvijftigste verdieping
11879182 | 54 vierenvijftigste verdieping
11879184 | 54 vierenvijftigste verdieping
11879186 | 54 vierenvijftigste verdieping
11879188 | 54 vierenvijftigste verdieping
11879192 | 54 vierenvijftigste verdieping
11879194 | 54 vierenvijftigste verdieping
11879198 | 54 vierenvijftigste verdieping
11879202 | 54 vierenvijftigste verdieping
11879212 | 54 vierenvijftigste verdieping
11879216 | 54 vierenvijftigste verdieping
11879224 | 54 vierenvijftigste verdieping
11879367 | 55 vijfenvijftigste verdieping
11879369 | 55 vijfenvijftigste verdieping
11879371 | 55 vijfenvijftigste verdieping
11879373 | 55 vijfenvijftigste verdieping
11879376 | 56 zesenvijftigste verdieping
11879378 | 56 zesenvijftigste verdieping
11879380 | 56 zesenvijftigste verdieping
11879382 | 56 zesenvijftigste verdieping
11880112 | 56 zesenvijftigste verdieping
11880141 | 55 vijfenvijftigste verdieping
11880202 | 56 zesenvijftigste verdieping
11880204 | 55 vijfenvijftigste verdieping
11880247 | 56 zesenvijftigste verdieping
11880249 | 55 vijfenvijftigste verdieping
11880251 | 56 zesenvijftigste verdieping
11880253 | 55 vijfenvijftigste verdieping
11880326 | 55 vijfenvijftigste verdieping
11880328 | 55 vijfenvijftigste verdieping
11880333 | 56 zesenvijftigste verdieping
11880335 | 56 zesenvijftigste verdieping
11880528 | 56 zesenvijftigste verdieping
11880548 | 55 vijfenvijftigste verdieping
11880638 | 55 vijfenvijftigste verdieping
11880640 | 55 vijfenvijftigste verdieping
11880642 | 55 vijfenvijftigste verdieping
11880644 | 55 vijfenvijftigste verdieping
11880649 | 56 zesenvijftigste verdieping
11880651 | 56 zesenvijftigste verdieping
11880653 | 56 zesenvijftigste verdieping
11880655 | 56 zesenvijftigste verdieping
11880740 | 55 vijfenvijftigste verdieping
11880745 | 56 zesenvijftigste verdieping
11880843 | 55 vijfenvijftigste verdieping
11880845 | 55 vijfenvijftigste verdieping
11880847 | 55 vijfenvijftigste verdieping
11880849 | 55 vijfenvijftigste verdieping
11880854 | 56 zesenvijftigste verdieping
11880856 | 56 zesenvijftigste verdieping
11880858 | 56 zesenvijftigste verdieping
11880860 | 56 zesenvijftigste verdieping
11880984 | 55 vijfenvijftigste verdieping
11880986 | 55 vijfenvijftigste verdieping
11880991 | 56 zesenvijftigste verdieping
11880993 | 56 zesenvijftigste verdieping
11881158 | 55 vijfenvijftigste verdieping
11881160 | 55 vijfenvijftigste verdieping
11881162 | 55 vijfenvijftigste verdieping
11881164 | 55 vijfenvijftigste verdieping
11881169 | 56 zesenvijftigste verdieping
11881171 | 56 zesenvijftigste verdieping
11881173 | 56 zesenvijftigste verdieping
11881175 | 56 zesenvijftigste verdieping
11881290 | 55 vijfenvijftigste verdieping
11881295 | 56 zesenvijftigste verdieping
11881414 | 55 vijfenvijftigste verdieping
11881420 | 56 zesenvijftigste verdieping

# IfcColumn: ø400 (28)
Type - ElementType: ø400; PredefinedType: COLUMN; Classification: 28.11 hoofddraagconstructies - kolommen en liggers, kolom-/liggerconstructies (Uniformat); Material: NLRS_f2_beton prefab
Pset_ColumnCommon - LoadBearing: yes; IsExternal: no; Reference: ø400
Name (NLRS_28.11_SCO_TLB_prefabbeton kolom rond_gen:ø400:...) | In
11878997 | 53 drieënvijftigste verdieping
11879018 | 53 drieënvijftigste verdieping
11879022 | 53 drieënvijftigste verdieping
11879026 | 53 drieënvijftigste verdieping
11879038 | 53 drieënvijftigste verdieping
11879062 | 53 drieënvijftigste verdieping
11879074 | 53 drieënvijftigste verdieping
11879082 | 53 drieënvijftigste verdieping
11879106 | 53 drieënvijftigste verdieping
11879113 | 53 drieënvijftigste verdieping
11879121 | 53 drieënvijftigste verdieping
11879139 | 53 drieënvijftigste verdieping
11879143 | 52 tweeënvijftigste verdieping
11879147 | 52 tweeënvijftigste verdieping
11879151 | 52 tweeënvijftigste verdieping
11879168 | 54 vierenvijftigste verdieping
11879170 | 54 vierenvijftigste verdieping
11879172 | 54 vierenvijftigste verdieping
11879178 | 54 vierenvijftigste verdieping
11879190 | 54 vierenvijftigste verdieping
11879196 | 54 vierenvijftigste verdieping
11879200 | 54 vierenvijftigste verdieping
11879210 | 54 vierenvijftigste verdieping
11879214 | 54 vierenvijftigste verdieping
11879218 | 54 vierenvijftigste verdieping
11879226 | 54 vierenvijftigste verdieping
12841330 | 54 vierenvijftigste verdieping
13279785 | 52 tweeënvijftigste verdieping

# IfcColumn: ø450 (4)
In: 53 drieënvijftigste verdieping
Type - ElementType: ø450; PredefinedType: COLUMN; Classification: 28.11 hoofddraagconstructies - kolommen en liggers, kolom-/liggerconstructies (Uniformat); Material: NLRS_f2_beton prefab
Pset_ColumnCommon - LoadBearing: yes; IsExternal: no; Reference: ø450
Name (NLRS_28.11_SCO_TLB_prefabbeton kolom rond_gen:ø450:...)
11879012
11879032
11879098
11879127

# IfcFooting: NLRS_16.12_SF_WPB_funderingsbalk ihwg recht_gen:350x600, NLRS_16.12_SF_WPB_funderingsbalk ihwg recht_gen:350x600:4210434
In: 00 begane grond
PredefinedType: FOOTING_BEAM; Classification: 16.12 funderingsconstructies - voeten en balken, fundatie balken (Uniformat); Material: NLRS_f2_beton ihwg

# IfcFooting: NLRS_16.12_SF_WPB_funderingsbalk ihwg recht_gen:500x600 (4)
In: 00 begane grond
PredefinedType: FOOTING_BEAM; Classification: 16.12 funderingsconstructies - voeten en balken, fundatie balken (Uniformat); Material: NLRS_f2_beton ihwg
Name (NLRS_16.12_SF_WPB_funderingsbalk ihwg recht_gen:500x600:...)
4210294
4210724
4211573
4211586

# IfcFooting: NLRS_16.12_SF_WPB_funderingsbalk ihwg recht_gen:500x750, NLRS_16.12_SF_WPB_funderingsbalk ihwg recht_gen:500x750:6025850
In: 00 begane grond
PredefinedType: FOOTING_BEAM; Classification: 16.12 funderingsconstructies - voeten en balken, fundatie balken (Uniformat); Material: NLRS_f2_beton ihwg

# IfcFooting: NLRS_16.12_SF_WPB_funderingsbalk ihwg recht_gen:550x600, NLRS_16.12_SF_WPB_funderingsbalk ihwg recht_gen:550x600:4210296
In: 00 begane grond
PredefinedType: FOOTING_BEAM; Classification: 16.12 funderingsconstructies - voeten en balken, fundatie balken (Uniformat); Material: NLRS_f2_beton ihwg

# IfcFooting: NLRS_16.12_SF_WPB_funderingsbalk ihwg recht_gen:550x750, NLRS_16.12_SF_WPB_funderingsbalk ihwg recht_gen:550x750:4211305
In: 00 begane grond
PredefinedType: FOOTING_BEAM; Classification: 16.12 funderingsconstructies - voeten en balken, fundatie balken (Uniformat); Material: NLRS_f2_beton ihwg

# IfcFooting: NLRS_16.12_SF_WPB_funderingsbalk ihwg recht_gen:600x600 (7)
In: 00 begane grond
PredefinedType: FOOTING_BEAM; Classification: 16.12 funderingsconstructies - voeten en balken, fundatie balken (Uniformat); Material: NLRS_f2_beton ihwg
Name (NLRS_16.12_SF_WPB_funderingsbalk ihwg recht_gen:600x600:...)
4208688
4209029
4209103
4209717
4209876
5979018
5979825

# IfcFooting: NLRS_16.12_SF_WPB_funderingsbalk ihwg recht_gen:850x600, NLRS_16.12_SF_WPB_funderingsbalk ihwg recht_gen:850x600:4209333
In: 00 begane grond
PredefinedType: FOOTING_BEAM; Classification: 16.12 funderingsconstructies - voeten en balken, fundatie balken (Uniformat); Material: NLRS_f2_beton ihwg

# IfcFooting: NLRS_16.12_SF_WPB_funderingsbalk ihwg recht_gen:900x600, NLRS_16.12_SF_WPB_funderingsbalk ihwg recht_gen:900x600:4210029
In: 00 begane grond
PredefinedType: FOOTING_BEAM; Classification: 16.12 funderingsconstructies - voeten en balken, fundatie balken (Uniformat); Material: NLRS_f2_beton ihwg

# IfcFooting: NLRS_16.12_SF_WPB_funderingsbalk ihwg recht_gen:950x600, NLRS_16.12_SF_WPB_funderingsbalk ihwg recht_gen:950x600:6268322
In: 00 begane grond
PredefinedType: FOOTING_BEAM; Classification: 16.12 funderingsconstructies - voeten en balken, fundatie balken (Uniformat); Material: NLRS_f2_beton ihwg

# IfcFooting: NLRS_16.12_SF_WPB_funderingsbalk ihwg recht_gen:975x600, NLRS_16.12_SF_WPB_funderingsbalk ihwg recht_gen:975x600:4210947
In: 00 begane grond
PredefinedType: FOOTING_BEAM; Classification: 16.12 funderingsconstructies - voeten en balken, fundatie balken (Uniformat); Material: NLRS_f2_beton ihwg

# IfcGroup: Model Group:Koppeling-1 (57)
Name (Model Group:Koppeling-1:...)
13567508 | Group: Model Group:Wand-W07:13522560
13567654 | Group: Model Group:Wand-W07:13522560
13571111
13571202
13571770 | Group: Model Group:Wand-W07:13522837
13571776 | Group: Model Group:Wand-W07:13522837
13571836 | Group: Model Group:Wand-W07:13522989
13571842 | Group: Model Group:Wand-W07:13522989
13571902 | Group: Model Group:Wand-W07:13523121
13571908 | Group: Model Group:Wand-W07:13523121
13572118 | Group: Model Group:Wand-W09:13524131
13572265 | Group: Model Group:Wand-W09:13524131
13572860
13572930
13573362 | Group: Model Group:Wand-W09:13524646
13573368 | Group: Model Group:Wand-W09:13524646
13573487 | Group: Model Group:Wand-W06:13525900
13573569 | Group: Model Group:Wand-W06:13525900
13574247 | Group: Model Group:Wand-W05A:13538256
13574429 | Group: Model Group:Wand-W05:13537097
13577472
13577737
13578668
13578674
13578883
13578971
13580914
13581052
13581122
13581190
13581277
13581283
13581386
13581452
13581522
13581590
13581662
13581728
13581798
13581868
13581938
13582004
13582072
13582140
13582208
13582276
13582344
13582414
13582484
13582552
13582622
13582690
13582758
13611780
13611786
13611792
13611798

# IfcGroup: Model Group:Koppeling-2 (28)
Name (Model Group:Koppeling-2:...) | Group
13570695 | Model Group:Wand-W07:13522560
13570917 | Model Group:Wand-W07:13522560
13571238 | Model Group:Wand-W08:13523638
13571293 | Model Group:Wand-W08:13523638
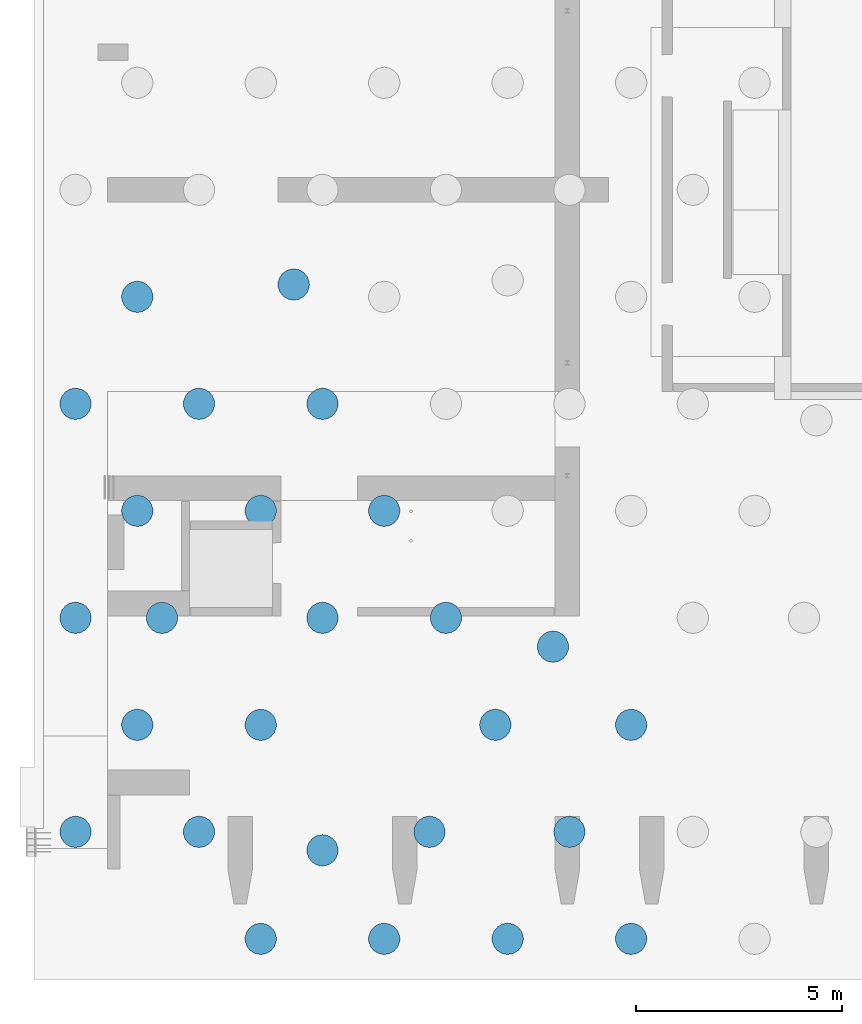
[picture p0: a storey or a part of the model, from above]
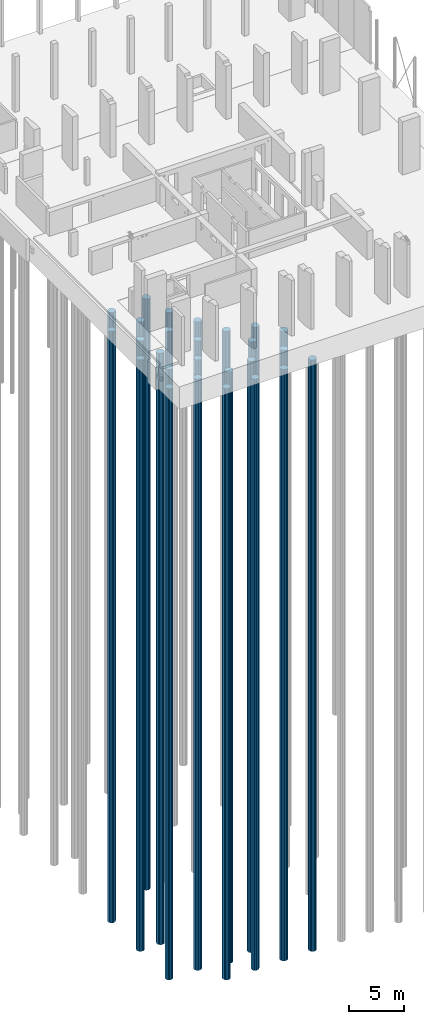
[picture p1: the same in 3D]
Properties of the parts of a building model (IFC2X3), part 7 of 21

# IfcGroup: Model Group:Koppeling-2 (28)
Name (Model Group:Koppeling-2:...) | Group
13571782 | Model Group:Wand-W07:13522837
13571788 | Model Group:Wand-W07:13522837
13571848 | Model Group:Wand-W07:13522989
13571854 | Model Group:Wand-W07:13522989
13571914 | Model Group:Wand-W07:13523121
13571920 | Model Group:Wand-W07:13523121
13572303 | Model Group:Wand-W09:13524131
13572337 | Model Group:Wand-W09:13524131
13572644 | Model Group:Wand-W08:13525078
13572650 | Model Group:Wand-W08:13525078
13572967
13573374 | Model Group:Wand-W09:13524646
13573380 | Model Group:Wand-W09:13524646
13574047 | Model Group:Wand-W06:13525900
13583097
13583302
13583393
13583427
13583452
13583477
13583502
13583537
13583562
13583587

# IfcGroup: Model Group:Koppeling-2a (2)
Name (Model Group:Koppeling-2a:...) | Group
13575092 | Model Group:Wand-W05A:13538256
13575192 | Model Group:Wand-W05:13537097

# IfcGroup: Model Group:NLRS_28.11_SF_handjes balkon 1-2_gen (84)
Name (Model Group:NLRS_28.11_SF_handjes balkon 1-2_gen:...) | Group
9036911 | Model Group:NLRS_23.21_vloer voor wanden d=300/500_gen:9036938
9036924 | Model Group:NLRS_23.21_vloer voor wanden d=300/500_gen:9036938
9050829 | Model Group:NLRS_23.21_vloer voor wanden d=300/500_gen:9050856
9050842 | Model Group:NLRS_23.21_vloer voor wanden d=300/500_gen:9050856
9051125 | Model Group:NLRS_23.21_vloer voor wanden d=300/500_gen:9051152
9051138 | Model Group:NLRS_23.21_vloer voor wanden d=300/500_gen:9051152
9131776 | Model Group:NLRS_23.21_vloer voor wanden d=300/500_gen:9131803
9131789 | Model Group:NLRS_23.21_vloer voor wanden d=300/500_gen:9131803
10618294 | Model Group:NLRS_23.21_vloer voor wanden d=300/500_gen:9125907
10618307 | Model Group:NLRS_23.21_vloer voor wanden d=300/500_gen:9125907
10620648 | Model Group:NLRS_23.21_vloer voor wanden d=300/500_gen:9126214
10620661 | Model Group:NLRS_23.21_vloer voor wanden d=300/500_gen:9126214
10620780 | Model Group:NLRS_23.21_vloer voor wanden d=300/500_gen:9126521
10620793 | Model Group:NLRS_23.21_vloer voor wanden d=300/500_gen:9126521
10620912 | Model Group:NLRS_23.21_vloer voor wanden d=300/500_gen:9133891
10620925 | Model Group:NLRS_23.21_vloer voor wanden d=300/500_gen:9133891
10622912 | Model Group:NLRS_23.21_vloer voor wanden d=300/500_gen:9128989
10622925 | Model Group:NLRS_23.21_vloer voor wanden d=300/500_gen:9128989
10625079 | Model Group:NLRS_23.21_vloer voor wanden d=300/500_gen:9129292
10625092 | Model Group:NLRS_23.21_vloer voor wanden d=300/500_gen:9129292
10625211 | Model Group:NLRS_23.21_vloer voor wanden d=300/500_gen:9132770
10625224 | Model Group:NLRS_23.21_vloer voor wanden d=300/500_gen:9132770
14013035 | Model Group:NLRS_23.21_vloer voor wanden d=300/300_gen:5792671
14013053 | Model Group:NLRS_23.21_vloer voor wanden d=300/300_gen:5792671
14014620 | Model Group:NLRS_23.21_vloer voor wanden d=300/300_gen:5889137
14014638 | Model Group:NLRS_23.21_vloer voor wanden d=300/300_gen:5889137
14014792 | Model Group:NLRS_23.21_vloer voor wanden d=300/300_gen:9028234
14014810 | Model Group:NLRS_23.21_vloer voor wanden d=300/300_gen:9028234
14014878 | Model Group:NLRS_23.21_vloer voor wanden d=300/300_gen:9029110
14014896 | Model Group:NLRS_23.21_vloer voor wanden d=300/300_gen:9029110
14014964 | Model Group:NLRS_23.21_vloer voor wanden d=300/300_gen:9148289
14014982 | Model Group:NLRS_23.21_vloer voor wanden d=300/300_gen:9148289
14015050 | Model Group:NLRS_23.21_vloer voor wanden d=300/300_gen:9148581
14015068 | Model Group:NLRS_23.21_vloer voor wanden d=300/300_gen:9148581
14015136 | Model Group:NLRS_23.21_vloer voor wanden d=300/300_gen:9148873
14015154 | Model Group:NLRS_23.21_vloer voor wanden d=300/300_gen:9148873
14015222 | Model Group:NLRS_23.21_vloer voor wanden d=300/300_gen:9149165
14015240 | Model Group:NLRS_23.21_vloer voor wanden d=300/300_gen:9149165
14015308 | Model Group:NLRS_23.21_vloer voor wanden d=300/300_gen:9149457
14015326 | Model Group:NLRS_23.21_vloer voor wanden d=300/300_gen:9149457
14015394 | Model Group:NLRS_23.21_vloer voor wanden d=300/300_gen:9152979
14015412 | Model Group:NLRS_23.21_vloer voor wanden d=300/300_gen:9152979
14018019
14018037
14018315 | Model Group:NLRS_23.21_vloer voor wanden d=300/400_gen:9147164
14018333 | Model Group:NLRS_23.21_vloer voor wanden d=300/400_gen:9147164
14020825 | Model Group:NLRS_23.21_vloer voor wanden d=300/400_gen:8986172
14020843 | Model Group:NLRS_23.21_vloer voor wanden d=300/400_gen:8986172
14020894 | Model Group:NLRS_23.21_vloer voor wanden d=300/400_gen:8995936
14020912 | Model Group:NLRS_23.21_vloer voor wanden d=300/400_gen:8995936
14020963 | Model Group:NLRS_23.21_vloer voor wanden d=300/400_gen:8996228
14020981 | Model Group:NLRS_23.21_vloer voor wanden d=300/400_gen:8996228
14021032 | Model Group:NLRS_23.21_vloer voor wanden d=300/400_gen:8996520
14021050 | Model Group:NLRS_23.21_vloer voor wanden d=300/400_gen:8996520
14021101 | Model Group:NLRS_23.21_vloer voor wanden d=300/400_gen:8997688
14021119 | Model Group:NLRS_23.21_vloer voor wanden d=300/400_gen:8997688
14021170 | Model Group:NLRS_23.21_vloer voor wanden d=300/400_gen:9134981
14021188 | Model Group:NLRS_23.21_vloer voor wanden d=300/400_gen:9134981
14021239 | Model Group:NLRS_23.21_vloer voor wanden d=300/400_gen:9135274
14021257 | Model Group:NLRS_23.21_vloer voor wanden d=300/400_gen:9135274
14021308 | Model Group:NLRS_23.21_vloer voor wanden d=300/400_gen:9135567
14021326 | Model Group:NLRS_23.21_vloer voor wanden d=300/400_gen:9135567
14021377 | Model Group:NLRS_23.21_vloer voor wanden d=300/400_gen:9135860
14021395 | Model Group:NLRS_23.21_vloer voor wanden d=300/400_gen:9135860
14021446 | Model Group:NLRS_23.21_vloer voor wanden d=300/400_gen:9138697
14021464 | Model Group:NLRS_23.21_vloer voor wanden d=300/400_gen:9138697
14021515 | Model Group:NLRS_23.21_vloer voor wanden d=300/400_gen:9138987
14021533 | Model Group:NLRS_23.21_vloer voor wanden d=300/400_gen:9138987
14021584 | Model Group:NLRS_23.21_vloer voor wanden d=300/400_gen:9140576
14021602 | Model Group:NLRS_23.21_vloer voor wanden d=300/400_gen:9140576
14021653 | Model Group:NLRS_23.21_vloer voor wanden d=300/400_gen:9141516
14021671 | Model Group:NLRS_23.21_vloer voor wanden d=300/400_gen:9141516
14021722 | Model Group:NLRS_23.21_vloer voor wanden d=300/400_gen:9142463
14021740 | Model Group:NLRS_23.21_vloer voor wanden d=300/400_gen:9142463
14021791 | Model Group:NLRS_23.21_vloer voor wanden d=300/400_gen:9142753
14021809 | Model Group:NLRS_23.21_vloer voor wanden d=300/400_gen:9142753
14021860 | Model Group:NLRS_23.21_vloer voor wanden d=300/400_gen:9143043
14021878 | Model Group:NLRS_23.21_vloer voor wanden d=300/400_gen:9143043
14021929 | Model Group:NLRS_23.21_vloer voor wanden d=300/400_gen:9145285
14021947 | Model Group:NLRS_23.21_vloer voor wanden d=300/400_gen:9145285
14021998 | Model Group:NLRS_23.21_vloer voor wanden d=300/400_gen:9145575
14022016 | Model Group:NLRS_23.21_vloer voor wanden d=300/400_gen:9145575
14026841
14026859

# IfcGroup: Model Group:NLRS_28.11_SF_handjes balkon 1-2_verd 6 tm 9_gen (8)
Name (Model Group:NLRS_28.11_SF_handjes balkon 1-2_verd 6 tm 9_gen:...) | Group
10634978 | Model Group:NLRS_23.21_vloer voor wanden d=400/500_gen:5786112
10634991 | Model Group:NLRS_23.21_vloer voor wanden d=400/500_gen:5786112
10635963 | Model Group:NLRS_23.21_vloer voor wanden d=400/500_gen:9091022
10635976 | Model Group:NLRS_23.21_vloer voor wanden d=400/500_gen:9091022
10636840 | Model Group:NLRS_23.21_vloer voor wanden d=400/500_gen:9124885
10636853 | Model Group:NLRS_23.21_vloer voor wanden d=400/500_gen:9124885
10637377 | Model Group:NLRS_23.21_vloer voor wanden d=400/500_gen:5771384
10637390 | Model Group:NLRS_23.21_vloer voor wanden d=400/500_gen:5771384

# IfcGroup: Model Group:NLRS_28.11_SF_handjes balkon 3-4_gen (84)
Name (Model Group:NLRS_28.11_SF_handjes balkon 3-4_gen:...) | Group
9036916 | Model Group:NLRS_23.21_vloer voor wanden d=300/500_gen:9036938
9036917 | Model Group:NLRS_23.21_vloer voor wanden d=300/500_gen:9036938
9050834 | Model Group:NLRS_23.21_vloer voor wanden d=300/500_gen:9050856
9050835 | Model Group:NLRS_23.21_vloer voor wanden d=300/500_gen:9050856
9051130 | Model Group:NLRS_23.21_vloer voor wanden d=300/500_gen:9051152
9051131 | Model Group:NLRS_23.21_vloer voor wanden d=300/500_gen:9051152
9131781 | Model Group:NLRS_23.21_vloer voor wanden d=300/500_gen:9131803
9131782 | Model Group:NLRS_23.21_vloer voor wanden d=300/500_gen:9131803
10618299 | Model Group:NLRS_23.21_vloer voor wanden d=300/500_gen:9125907
10618300 | Model Group:NLRS_23.21_vloer voor wanden d=300/500_gen:9125907
10620653 | Model Group:NLRS_23.21_vloer voor wanden d=300/500_gen:9126214
10620654 | Model Group:NLRS_23.21_vloer voor wanden d=300/500_gen:9126214
10620785 | Model Group:NLRS_23.21_vloer voor wanden d=300/500_gen:9126521
10620786 | Model Group:NLRS_23.21_vloer voor wanden d=300/500_gen:9126521
10620917 | Model Group:NLRS_23.21_vloer voor wanden d=300/500_gen:9133891
10620918 | Model Group:NLRS_23.21_vloer voor wanden d=300/500_gen:9133891
10622917 | Model Group:NLRS_23.21_vloer voor wanden d=300/500_gen:9128989
10622918 | Model Group:NLRS_23.21_vloer voor wanden d=300/500_gen:9128989
10625084 | Model Group:NLRS_23.21_vloer voor wanden d=300/500_gen:9129292
10625085 | Model Group:NLRS_23.21_vloer voor wanden d=300/500_gen:9129292
10625216 | Model Group:NLRS_23.21_vloer voor wanden d=300/500_gen:9132770
10625217 | Model Group:NLRS_23.21_vloer voor wanden d=300/500_gen:9132770
14013044 | Model Group:NLRS_23.21_vloer voor wanden d=300/300_gen:5792671
14013062 | Model Group:NLRS_23.21_vloer voor wanden d=300/300_gen:5792671
14014629 | Model Group:NLRS_23.21_vloer voor wanden d=300/300_gen:5889137
14014647 | Model Group:NLRS_23.21_vloer voor wanden d=300/300_gen:5889137
14014801 | Model Group:NLRS_23.21_vloer voor wanden d=300/300_gen:9028234
14014819 | Model Group:NLRS_23.21_vloer voor wanden d=300/300_gen:9028234
14014887 | Model Group:NLRS_23.21_vloer voor wanden d=300/300_gen:9029110
14014905 | Model Group:NLRS_23.21_vloer voor wanden d=300/300_gen:9029110
14014973 | Model Group:NLRS_23.21_vloer voor wanden d=300/300_gen:9148289
14014991 | Model Group:NLRS_23.21_vloer voor wanden d=300/300_gen:9148289
14015059 | Model Group:NLRS_23.21_vloer voor wanden d=300/300_gen:9148581
14015077 | Model Group:NLRS_23.21_vloer voor wanden d=300/300_gen:9148581
14015145 | Model Group:NLRS_23.21_vloer voor wanden d=300/300_gen:9148873
14015163 | Model Group:NLRS_23.21_vloer voor wanden d=300/300_gen:9148873
14015231 | Model Group:NLRS_23.21_vloer voor wanden d=300/300_gen:9149165
14015249 | Model Group:NLRS_23.21_vloer voor wanden d=300/300_gen:9149165
14015317 | Model Group:NLRS_23.21_vloer voor wanden d=300/300_gen:9149457
14015335 | Model Group:NLRS_23.21_vloer voor wanden d=300/300_gen:9149457
14015403 | Model Group:NLRS_23.21_vloer voor wanden d=300/300_gen:9152979
14015421 | Model Group:NLRS_23.21_vloer voor wanden d=300/300_gen:9152979
14018028
14018046
14018324 | Model Group:NLRS_23.21_vloer voor wanden d=300/400_gen:9147164
14018342 | Model Group:NLRS_23.21_vloer voor wanden d=300/400_gen:9147164
14020834 | Model Group:NLRS_23.21_vloer voor wanden d=300/400_gen:8986172
14020852 | Model Group:NLRS_23.21_vloer voor wanden d=300/400_gen:8986172
14020903 | Model Group:NLRS_23.21_vloer voor wanden d=300/400_gen:8995936
14020921 | Model Group:NLRS_23.21_vloer voor wanden d=300/400_gen:8995936
14020972 | Model Group:NLRS_23.21_vloer voor wanden d=300/400_gen:8996228
14020990 | Model Group:NLRS_23.21_vloer voor wanden d=300/400_gen:8996228
14021041 | Model Group:NLRS_23.21_vloer voor wanden d=300/400_gen:8996520
14021059 | Model Group:NLRS_23.21_vloer voor wanden d=300/400_gen:8996520
14021110 | Model Group:NLRS_23.21_vloer voor wanden d=300/400_gen:8997688
14021128 | Model Group:NLRS_23.21_vloer voor wanden d=300/400_gen:8997688
14021179 | Model Group:NLRS_23.21_vloer voor wanden d=300/400_gen:9134981
14021197 | Model Group:NLRS_23.21_vloer voor wanden d=300/400_gen:9134981
14021248 | Model Group:NLRS_23.21_vloer voor wanden d=300/400_gen:9135274
14021266 | Model Group:NLRS_23.21_vloer voor wanden d=300/400_gen:9135274
14021317 | Model Group:NLRS_23.21_vloer voor wanden d=300/400_gen:9135567
14021335 | Model Group:NLRS_23.21_vloer voor wanden d=300/400_gen:9135567
14021386 | Model Group:NLRS_23.21_vloer voor wanden d=300/400_gen:9135860
14021404 | Model Group:NLRS_23.21_vloer voor wanden d=300/400_gen:9135860
14021455 | Model Group:NLRS_23.21_vloer voor wanden d=300/400_gen:9138697
14021473 | Model Group:NLRS_23.21_vloer voor wanden d=300/400_gen:9138697
14021524 | Model Group:NLRS_23.21_vloer voor wanden d=300/400_gen:9138987
14021542 | Model Group:NLRS_23.21_vloer voor wanden d=300/400_gen:9138987
14021593 | Model Group:NLRS_23.21_vloer voor wanden d=300/400_gen:9140576
14021611 | Model Group:NLRS_23.21_vloer voor wanden d=300/400_gen:9140576
14021662 | Model Group:NLRS_23.21_vloer voor wanden d=300/400_gen:9141516
14021680 | Model Group:NLRS_23.21_vloer voor wanden d=300/400_gen:9141516
14021731 | Model Group:NLRS_23.21_vloer voor wanden d=300/400_gen:9142463
14021749 | Model Group:NLRS_23.21_vloer voor wanden d=300/400_gen:9142463
14021800 | Model Group:NLRS_23.21_vloer voor wanden d=300/400_gen:9142753
14021818 | Model Group:NLRS_23.21_vloer voor wanden d=300/400_gen:9142753
14021869 | Model Group:NLRS_23.21_vloer voor wanden d=300/400_gen:9143043
14021887 | Model Group:NLRS_23.21_vloer voor wanden d=300/400_gen:9143043
14021938 | Model Group:NLRS_23.21_vloer voor wanden d=300/400_gen:9145285
14021956 | Model Group:NLRS_23.21_vloer voor wanden d=300/400_gen:9145285
14022007 | Model Group:NLRS_23.21_vloer voor wanden d=300/400_gen:9145575
14022025 | Model Group:NLRS_23.21_vloer voor wanden d=300/400_gen:9145575
14026850
14026868

# IfcGroup: Model Group:NLRS_28.11_SF_handjes balkon 3-4_verd 5 tm 9_gen (8)
Name (Model Group:NLRS_28.11_SF_handjes balkon 3-4_verd 5 tm 9_gen:...) | Group
10634983 | Model Group:NLRS_23.21_vloer voor wanden d=400/500_gen:5786112
10634984 | Model Group:NLRS_23.21_vloer voor wanden d=400/500_gen:5786112
10635968 | Model Group:NLRS_23.21_vloer voor wanden d=400/500_gen:9091022
10635969 | Model Group:NLRS_23.21_vloer voor wanden d=400/500_gen:9091022
10636845 | Model Group:NLRS_23.21_vloer voor wanden d=400/500_gen:9124885
10636846 | Model Group:NLRS_23.21_vloer voor wanden d=400/500_gen:9124885
10637382 | Model Group:NLRS_23.21_vloer voor wanden d=400/500_gen:5771384
10637383 | Model Group:NLRS_23.21_vloer voor wanden d=400/500_gen:5771384

# IfcOpeningElement: Opening (5659)
Name | In | Classification | Group
42 x  | 00 begane grond
Floor:NLRS_13.22_FL_beton ihwg d=2500_gen:4112696:2 | 00 begane grond | 13.22 vloeren op grondslag - constructief, vloeren als gebouwonderdeel (Uniformat)
Floor:NLRS_13.22_FL_beton ihwg d=2500_gen:4112696:3 | 00 begane grond | 13.22 vloeren op grondslag - constructief, vloeren als gebouwonderdeel (Uniformat)
Basic Wall:NLRS_21.21_WA_beton prefab d=200_gen:1307922 | 00 begane grond | 21.21 buitenwanden - constructief, massieve wanden (Uniformat)
Basic Wall:NLRS_22.21_WA_beton ihwg d=600_gen:4125508:1 | 00 begane grond | 22.21 binnenwanden - constructief, massieve wanden (Uniformat)
Basic Wall:NLRS_22.21_WA_beton ihwg d=600_gen:4125508 | 00 begane grond | 22.21 binnenwanden - constructief, massieve wanden (Uniformat)
3 x Basic Wall:NLRS_22.21_WA_beton ihwg d=600_gen:4125598 | 00 begane grond | 22.21 binnenwanden - constructief, massieve wanden (Uniformat)
4 x Basic Wall:NLRS_22.21_WA_beton ihwg d=600_gen:4126048 | 00 begane grond | 22.21 binnenwanden - constructief, massieve wanden (Uniformat)
Basic Wall:NLRS_22.21_WA_beton ihwg d=600_gen:4126336:1 | 00 begane grond | 22.21 binnenwanden - constructief, massieve wanden (Uniformat)
Basic Wall:NLRS_22.21_WA_beton ihwg d=600_gen:4126336:2 | 00 begane grond | 22.21 binnenwanden - constructief, massieve wanden (Uniformat)
7 x Basic Wall:NLRS_22.21_WA_beton ihwg d=600_gen:4126336 | 00 begane grond | 22.21 binnenwanden - constructief, massieve wanden (Uniformat)
Basic Wall:NLRS_22.21_WA_beton ihwg d=600_gen:4126969:1 | 00 begane grond | 22.21 binnenwanden - constructief, massieve wanden (Uniformat)
14 x Basic Wall:NLRS_22.21_WA_beton ihwg d=600_gen:4126969 | 00 begane grond | 22.21 binnenwanden - constructief, massieve wanden (Uniformat)
Basic Wall:NLRS_22.21_WA_beton ihwg d=600_gen:4127256:1 | 00 begane grond | 22.21 binnenwanden - constructief, massieve wanden (Uniformat)
3 x Basic Wall:NLRS_22.21_WA_beton ihwg d=600_gen:4127256 | 00 begane grond | 22.21 binnenwanden - constructief, massieve wanden (Uniformat)
Basic Wall:NLRS_22.21_WA_beton prefab d=200_gen:4160900 | 00 begane grond | 22.21 binnenwanden - constructief, massieve wanden (Uniformat)
2 x Basic Wall:NLRS_22.21_WA_beton prefab d=200_gen:4161081 | 00 begane grond | 22.21 binnenwanden - constructief, massieve wanden (Uniformat)
2 x Basic Wall:NLRS_22.21_WA_beton prefab d=200_gen:4161091 | 00 begane grond | 22.21 binnenwanden - constructief, massieve wanden (Uniformat)
2 x Basic Wall:NLRS_22.21_WA_beton prefab d=200_gen:4161119 | 00 begane grond | 22.21 binnenwanden - constructief, massieve wanden (Uniformat)
Basic Wall:NLRS_22.21_WA_beton prefab d=200_gen:1312531 | 00 begane grond | 22.21 binnenwanden - constructief, massieve wanden (Uniformat)
2 x Basic Wall:NLRS_22.21_WA_beton prefab d=200_gen:4161187 | 00 begane grond | 22.21 binnenwanden - constructief, massieve wanden (Uniformat)
4 x Basic Wall:NLRS_22.21_WA_beton prefab d=200_gen:4161354 | 00 begane grond | 22.21 binnenwanden - constructief, massieve wanden (Uniformat)
3 x Basic Wall:NLRS_22.21_WA_beton prefab d=200_gen:4161469 | 00 begane grond | 22.21 binnenwanden - constructief, massieve wanden (Uniformat)
2 x Basic Wall:NLRS_22.21_WA_beton prefab d=200_gen:4161552 | 00 begane grond | 22.21 binnenwanden - constructief, massieve wanden (Uniformat)
3 x Basic Wall:NLRS_22.21_WA_beton prefab d=200_gen:4161724 | 00 begane grond | 22.21 binnenwanden - constructief, massieve wanden (Uniformat)
Floor:NLRS_13.22_FL_beton ihwg d=350_gen:4223542:2 | 00 begane grond | 13.22 vloeren op grondslag - constructief, vloeren als gebouwonderdeel (Uniformat)
Floor:NLRS_13.22_FL_beton ihwg d=350_gen:4223542:3 | 00 begane grond | 13.22 vloeren op grondslag - constructief, vloeren als gebouwonderdeel (Uniformat)
42 x  | 00a eerste tussenverdieping
Basic Wall:NLRS_22.21_WA_beton prefab d=300_gen:4313127 | 00a eerste tussenverdieping | 22.21 binnenwanden - constructief, massieve wanden (Uniformat)
Basic Wall:NLRS_22.21_WA_beton prefab d=200_gen:4313131 | 00a eerste tussenverdieping | 22.21 binnenwanden - constructief, massieve wanden (Uniformat)
2 x Basic Wall:NLRS_22.21_WA_beton prefab d=200_gen:4313133 | 00a eerste tussenverdieping | 22.21 binnenwanden - constructief, massieve wanden (Uniformat)
3 x Basic Wall:NLRS_22.21_WA_beton prefab d=200_gen:4313135 | 00a eerste tussenverdieping | 22.21 binnenwanden - constructief, massieve wanden (Uniformat)
Basic Wall:NLRS_22.21_WA_beton ihwg d=600_gen:4319481:1 | 00a eerste tussenverdieping | 22.21 binnenwanden - constructief, massieve wanden (Uniformat)
Basic Wall:NLRS_22.21_WA_beton ihwg d=600_gen:4319481:2 | 00a eerste tussenverdieping | 22.21 binnenwanden - constructief, massieve wanden (Uniformat)
Basic Wall:NLRS_22.21_WA_beton ihwg d=600_gen:4319481 | 00a eerste tussenverdieping | 22.21 binnenwanden - constructief, massieve wanden (Uniformat)
4 x Basic Wall:NLRS_22.21_WA_beton ihwg d=600_gen:4319483 | 00a eerste tussenverdieping | 22.21 binnenwanden - constructief, massieve wanden (Uniformat)
3 x Basic Wall:NLRS_22.21_WA_beton ihwg d=600_gen:4125598 | 00a eerste tussenverdieping | 22.21 binnenwanden - constructief, massieve wanden (Uniformat)
Basic Wall:NLRS_22.21_WA_beton ihwg d=600_gen:4319485:1 | 00a eerste tussenverdieping | 22.21 binnenwanden - constructief, massieve wanden (Uniformat)
Basic Wall:NLRS_22.21_WA_beton ihwg d=600_gen:4319485:2 | 00a eerste tussenverdieping | 22.21 binnenwanden - constructief, massieve wanden (Uniformat)
12 x Basic Wall:NLRS_22.21_WA_beton ihwg d=600_gen:4319485 | 00a eerste tussenverdieping | 22.21 binnenwanden - constructief, massieve wanden (Uniformat)
Basic Wall:NLRS_22.21_WA_beton ihwg d=600_gen:4319489:1 | 00a eerste tussenverdieping | 22.21 binnenwanden - constructief, massieve wanden (Uniformat)
32 x Basic Wall:NLRS_22.21_WA_beton ihwg d=600_gen:4319489 | 00a eerste tussenverdieping | 22.21 binnenwanden - constructief, massieve wanden (Uniformat)
Basic Wall:NLRS_22.21_WA_beton ihwg d=600_gen:4319491:1 | 00a eerste tussenverdieping | 22.21 binnenwanden - constructief, massieve wanden (Uniformat)
7 x Basic Wall:NLRS_22.21_WA_beton ihwg d=600_gen:4319491 | 00a eerste tussenverdieping | 22.21 binnenwanden - constructief, massieve wanden (Uniformat)
Floor:NLRS_23.21_FL_druklaag d=70_gen:4333976:2 | 01 eerste verdieping | 23.21 vloeren - constructief, vrijdragende vloeren (Uniformat)
Basic Wall:NLRS_22.21_WA_beton ihwg d=600_gen:4391827:1 | 01 eerste verdieping | 22.21 binnenwanden - constructief, massieve wanden (Uniformat)
Basic Wall:NLRS_22.21_WA_beton ihwg d=600_gen:4391827:2 | 01 eerste verdieping | 22.21 binnenwanden - constructief, massieve wanden (Uniformat)
3 x Basic Wall:NLRS_22.21_WA_beton ihwg d=600_gen:4391827 | 01 eerste verdieping | 22.21 binnenwanden - constructief, massieve wanden (Uniformat)
2 x Basic Wall:NLRS_22.21_WA_beton ihwg d=600_gen:4391829 | 01 eerste verdieping | 22.21 binnenwanden - constructief, massieve wanden (Uniformat)
3 x Basic Wall:NLRS_22.21_WA_beton ihwg d=600_gen:4125598 | 01 eerste verdieping | 22.21 binnenwanden - constructief, massieve wanden (Uniformat)
Basic Wall:NLRS_22.21_WA_beton ihwg d=600_gen:4391831:1 | 01 eerste verdieping | 22.21 binnenwanden - constructief, massieve wanden (Uniformat)
Basic Wall:NLRS_22.21_WA_beton ihwg d=600_gen:4391831:2 | 01 eerste verdieping | 22.21 binnenwanden - constructief, massieve wanden (Uniformat)
4 x Basic Wall:NLRS_22.21_WA_beton ihwg d=600_gen:4391831 | 01 eerste verdieping | 22.21 binnenwanden - constructief, massieve wanden (Uniformat)
Basic Wall:NLRS_22.21_WA_beton ihwg d=600_gen:4391835:1 | 01 eerste verdieping | 22.21 binnenwanden - constructief, massieve wanden (Uniformat)
15 x Basic Wall:NLRS_22.21_WA_beton ihwg d=600_gen:4391835 | 01 eerste verdieping | 22.21 binnenwanden - constructief, massieve wanden (Uniformat)
Basic Wall:NLRS_22.21_WA_beton ihwg d=600_gen:4391837:1 | 01 eerste verdieping | 22.21 binnenwanden - constructief, massieve wanden (Uniformat)
8 x Basic Wall:NLRS_22.21_WA_beton ihwg d=600_gen:4391837 | 01 eerste verdieping | 22.21 binnenwanden - constructief, massieve wanden (Uniformat)
Basic Wall:NLRS_22.21_WA_beton prefab d=200_gen:4391841 | 01 eerste verdieping | 22.21 binnenwanden - constructief, massieve wanden (Uniformat)
Basic Wall:NLRS_22.21_WA_beton ihwg d=600_gen:4420791:1 | 02 tweede verdieping | 22.21 binnenwanden - constructief, massieve wanden (Uniformat)
Basic Wall:NLRS_22.21_WA_beton ihwg d=600_gen:4420791:2 | 02 tweede verdieping | 22.21 binnenwanden - constructief, massieve wanden (Uniformat)
3 x Basic Wall:NLRS_22.21_WA_beton ihwg d=600_gen:4420791 | 02 tweede verdieping | 22.21 binnenwanden - constructief, massieve wanden (Uniformat)
2 x Basic Wall:NLRS_22.21_WA_beton ihwg d=600_gen:4420793 | 02 tweede verdieping | 22.21 binnenwanden - constructief, massieve wanden (Uniformat)
Basic Wall:NLRS_22.21_WA_beton ihwg d=600_gen:4420795:1 | 02 tweede verdieping | 22.21 binnenwanden - constructief, massieve wanden (Uniformat)
Basic Wall:NLRS_22.21_WA_beton ihwg d=600_gen:4420795:2 | 02 tweede verdieping | 22.21 binnenwanden - constructief, massieve wanden (Uniformat)
7 x Basic Wall:NLRS_22.21_WA_beton ihwg d=600_gen:4420795 | 02 tweede verdieping | 22.21 binnenwanden - constructief, massieve wanden (Uniformat)
Basic Wall:NLRS_22.21_WA_beton ihwg d=600_gen:4420799:1 | 02 tweede verdieping | 22.21 binnenwanden - constructief, massieve wanden (Uniformat)
14 x Basic Wall:NLRS_22.21_WA_beton ihwg d=600_gen:4420799 | 02 tweede verdieping | 22.21 binnenwanden - constructief, massieve wanden (Uniformat)
Basic Wall:NLRS_22.21_WA_beton ihwg d=600_gen:4420801:1 | 02 tweede verdieping | 22.21 binnenwanden - constructief, massieve wanden (Uniformat)
8 x Basic Wall:NLRS_22.21_WA_beton ihwg d=600_gen:4420801 | 02 tweede verdieping | 22.21 binnenwanden - constructief, massieve wanden (Uniformat)
Basic Wall:NLRS_22.21_WA_beton prefab d=200_gen:4420805 | 02 tweede verdieping | 22.21 binnenwanden - constructief, massieve wanden (Uniformat)
Basic Wall:NLRS_21.21_WA_beton prefab d=200_gen:1307922 | 01 eerste verdieping | 21.21 buitenwanden - constructief, massieve wanden (Uniformat)
Basic Wall:NLRS_21.21_WA_beton prefab d=400/420_gen:4689026 | 07 zevende verdieping | 21.21 buitenwanden - constructief, massieve wanden (Uniformat) | Model Group:NLRS_28.21_WA_3D element 002 d=400_gen:4689313
Basic Wall:NLRS_21.21_WA_beton prefab d=400/420_gen:4689064 | 07 zevende verdieping | 21.21 buitenwanden - constructief, massieve wanden (Uniformat) | Model Group:NLRS_28.21_WA_3D element 002 d=400_gen:4689313
Basic Wall:NLRS_21.21_WA_beton prefab d=400/420_gen:4689066 | 07 zevende verdieping | 21.21 buitenwanden - constructief, massieve wanden (Uniformat) | Model Group:NLRS_21.21_WA_wand 003 d=400_gen:4689135
Basic Wall:NLRS_21.21_WA_beton prefab d=400/420_gen:4689070 | 07 zevende verdieping | 21.21 buitenwanden - constructief, massieve wanden (Uniformat) | Model Group:NLRS_28.21_WA_3D element 001 d=400_gen:4689303
Basic Wall:NLRS_21.21_WA_beton prefab d=400/420_gen:4689114 | 07 zevende verdieping | 21.21 buitenwanden - constructief, massieve wanden (Uniformat) | Model Group:NLRS_28.21_WA_3D element 001 d=400_gen:4689303
Basic Wall:NLRS_21.21_WA_beton prefab d=400/420_gen:4689136 | 07 zevende verdieping | 21.21 buitenwanden - constructief, massieve wanden (Uniformat) | Model Group:NLRS_21.21_WA_wand 003 d=400_gen:4689139
2 x Basic Wall:NLRS_21.21_WA_beton prefab d=400/420_gen:4689155 | 07 zevende verdieping | 21.21 buitenwanden - constructief, massieve wanden (Uniformat) | Model Group:NLRS_21.21_WA_wand 002b d=400_gen:4689133
2 x Basic Wall:NLRS_21.21_WA_beton prefab d=400/420_gen:5362948 | 07 zevende verdieping | 21.21 buitenwanden - constructief, massieve wanden (Uniformat) | Model Group:NLRS_21.21_WA_wand 002b d=400_gen:4689133
2 x Basic Wall:NLRS_21.21_WA_beton prefab d=400/420_gen:4689181 | 07 zevende verdieping | 21.21 buitenwanden - constructief, massieve wanden (Uniformat) | Model Group:NLRS_21.21_WA_wand 004b d=400_gen:4689125
2 x Basic Wall:NLRS_21.21_WA_beton prefab d=400/420_gen:5362948 | 07 zevende verdieping | 21.21 buitenwanden - constructief, massieve wanden (Uniformat) | Model Group:NLRS_21.21_WA_wand 004b d=400_gen:4689125
Basic Wall:NLRS_21.21_WA_beton prefab d=400/420_gen:4689314 | 07 zevende verdieping | 21.21 buitenwanden - constructief, massieve wanden (Uniformat) | Model Group:NLRS_28.21_WA_3D element 002 d=400_gen:4689329
Basic Wall:NLRS_21.21_WA_beton prefab d=400/420_gen:4689316 | 07 zevende verdieping | 21.21 buitenwanden - constructief, massieve wanden (Uniformat) | Model Group:NLRS_28.21_WA_3D element 002 d=400_gen:4689329
Basic Wall:NLRS_21.21_WA_beton prefab d=400/420_gen:4689330 | 07 zevende verdieping | 21.21 buitenwanden - constructief, massieve wanden (Uniformat) | Model Group:NLRS_28.21_WA_3D element 001 d=400_gen:4689345
Basic Wall:NLRS_21.21_WA_beton prefab d=400/420_gen:4689333 | 07 zevende verdieping | 21.21 buitenwanden - constructief, massieve wanden (Uniformat) | Model Group:NLRS_28.21_WA_3D element 001 d=400_gen:4689345
Basic Wall:NLRS_21.21_WA_beton prefab d=400/420_gen:4690644 | 06 zesde verdieping | 21.21 buitenwanden - constructief, massieve wanden (Uniformat) | Model Group:NLRS_28.21_WA_3D element 002 d=400_gen:4690876
2 x Basic Wall:NLRS_22.21_WA_beton prefab d=500_gen:4690654 | 06 zesde verdieping | 22.21 binnenwanden - constructief, massieve wanden (Uniformat) | Model Group:NLRS_01.00_verdieping type B1_gen:4644030
2 x Basic Wall:NLRS_22.21_WA_beton prefab d=500_gen:4690660 | 06 zesde verdieping | 22.21 binnenwanden - constructief, massieve wanden (Uniformat) | Model Group:NLRS_01.00_verdieping type B1_gen:4644030
Basic Wall:NLRS_22.21_WA_beton prefab d=300_gen:4690662 | 06 zesde verdieping | 22.21 binnenwanden - constructief, massieve wanden (Uniformat) | Model Group:NLRS_01.00_verdieping type B1_gen:4644030
2 x Basic Wall:NLRS_22.21_WA_beton prefab d=300_gen:4472952 | 06 zesde verdieping | 22.21 binnenwanden - constructief, massieve wanden (Uniformat) | Model Group:NLRS_01.00_verdieping type B1_gen:4644030
4 x Basic Wall:NLRS_22.21_WA_beton prefab d=200_gen:4690664 | 06 zesde verdieping | 22.21 binnenwanden - constructief, massieve wanden (Uniformat) | Model Group:NLRS_22.21_WA_kern 06--51_gen:4690937
4 x Basic Wall:NLRS_22.21_WA_beton prefab d=200_gen:4690666 | 06 zesde verdieping | 22.21 binnenwanden - constructief, massieve wanden (Uniformat) | Model Group:NLRS_22.21_WA_kern 06--51_gen:4690937
4 x Basic Wall:NLRS_22.21_WA_beton prefab d=200_gen:4690668 | 06 zesde verdieping | 22.21 binnenwanden - constructief, massieve wanden (Uniformat) | Model Group:NLRS_22.21_WA_kern 06--51_gen:4690937
Basic Wall:NLRS_21.21_WA_beton prefab d=400/420_gen:4690676 | 06 zesde verdieping | 21.21 buitenwanden - constructief, massieve wanden (Uniformat) | Model Group:NLRS_28.21_WA_3D element 002 d=400_gen:4690876
Basic Wall:NLRS_21.21_WA_beton prefab d=400/420_gen:4690680 | 06 zesde verdieping | 21.21 buitenwanden - constructief, massieve wanden (Uniformat) | Model Group:NLRS_28.21_WA_3D element 001 d=400_gen:4690866
Basic Wall:NLRS_21.21_WA_beton prefab d=400/420_gen:4690706 | 06 zesde verdieping | 21.21 buitenwanden - constructief, massieve wanden (Uniformat) | Model Group:NLRS_28.21_WA_3D element 001 d=400_gen:4690866
Basic Wall:NLRS_21.21_WA_beton prefab d=400/420_gen:4690715 | 06 zesde verdieping | 21.21 buitenwanden - constructief, massieve wanden (Uniformat) | Model Group:NLRS_21.21_WA_wand 001 d=400_gen:4690718
Basic Wall:NLRS_21.21_WA_beton prefab d=400/420_gen:4690877 | 06 zesde verdieping | 21.21 buitenwanden - constructief, massieve wanden (Uniformat) | Model Group:NLRS_28.21_WA_3D element 002 d=400_gen:4690892
Basic Wall:NLRS_21.21_WA_beton prefab d=400/420_gen:4690879 | 06 zesde verdieping | 21.21 buitenwanden - constructief, massieve wanden (Uniformat) | Model Group:NLRS_28.21_WA_3D element 002 d=400_gen:4690892
Basic Wall:NLRS_21.21_WA_beton prefab d=400/420_gen:4690893 | 06 zesde verdieping | 21.21 buitenwanden - constructief, massieve wanden (Uniformat) | Model Group:NLRS_28.21_WA_3D element 001 d=400_gen:4690908
Basic Wall:NLRS_21.21_WA_beton prefab d=400/420_gen:4690896 | 06 zesde verdieping | 21.21 buitenwanden - constructief, massieve wanden (Uniformat) | Model Group:NLRS_28.21_WA_3D element 001 d=400_gen:4690908
Basic Wall:NLRS_22.21_WA_beton prefab d=500_gen:4690990 | 06 zesde verdieping | 22.21 binnenwanden - constructief, massieve wanden (Uniformat) | Model Group:NLRS_01.00_verdieping type B1_gen:4644030
Basic Wall:NLRS_22.21_WA_beton prefab d=300_gen:4691004 | 06 zesde verdieping | 22.21 binnenwanden - constructief, massieve wanden (Uniformat) | Model Group:NLRS_01.00_verdieping type B1_gen:4644030
Basic Wall:NLRS_22.21_WA_beton prefab d=500_gen:4691008 | 06 zesde verdieping | 22.21 binnenwanden - constructief, massieve wanden (Uniformat) | Model Group:NLRS_01.00_verdieping type B1_gen:4644030
Basic Wall:NLRS_22.21_WA_beton prefab d=500_gen:4692339 | 06 zesde verdieping | 22.21 binnenwanden - constructief, massieve wanden (Uniformat) | Model Group:NLRS_01.00_verdieping type B1_gen:4644030
2 x Basic Wall:NLRS_22.21_WA_beton prefab d=500_gen:4472769 | 06 zesde verdieping | 22.21 binnenwanden - constructief, massieve wanden (Uniformat) | Model Group:NLRS_01.00_verdieping type B1_gen:4644030
Basic Wall:NLRS_22.21_WA_beton prefab d=500_gen:4692374 | 06 zesde verdieping | 22.21 binnenwanden - constructief, massieve wanden (Uniformat) | Model Group:NLRS_01.00_verdieping type B1_gen:4644030
4 x Basic Wall:NLRS_21.21_WA_beton prefab d=400/420_gen:4692547 | 06 zesde verdieping | 21.21 buitenwanden - constructief, massieve wanden (Uniformat) | Model Group:NLRS_21.21_WA_wand 004a d=400_gen:4690709
2 x Basic Wall:NLRS_21.21_WA_beton prefab d=400/420_gen:5362948 | 06 zesde verdieping | 21.21 buitenwanden - constructief, massieve wanden (Uniformat) | Model Group:NLRS_21.21_WA_wand 004a d=400_gen:4690709
Basic Wall:NLRS_21.21_WA_beton prefab d=400/420_gen:4693018 | 06 zesde verdieping | 21.21 buitenwanden - constructief, massieve wanden (Uniformat) | Model Group:NLRS_21.21_WA_wand 003 d=400_gen:4690714
4 x Basic Wall:NLRS_21.21_WA_beton prefab d=400/420_gen:4693057 | 06 zesde verdieping | 21.21 buitenwanden - constructief, massieve wanden (Uniformat) | Model Group:NLRS_21.21_WA_wand 002a d=400_gen:4690711
2 x Basic Wall:NLRS_21.21_WA_beton prefab d=400/420_gen:5362948 | 06 zesde verdieping | 21.21 buitenwanden - constructief, massieve wanden (Uniformat) | Model Group:NLRS_21.21_WA_wand 002a d=400_gen:4690711
Basic Wall:NLRS_21.21_WA_beton prefab d=400/420_gen:4693192 | 06 zesde verdieping | 21.21 buitenwanden - constructief, massieve wanden (Uniformat) | Model Group:NLRS_21.21_WA_wand 003 d=400_gen:4690713
Basic Wall:NLRS_21.21_WA_beton prefab d=400/420_gen:4693297 | 06 zesde verdieping | 21.21 buitenwanden - constructief, massieve wanden (Uniformat) | Model Group:NLRS_21.21_WA_wand 001 d=400_gen:4690712
Basic Wall:NLRS_22.21_WA_beton prefab d=500_gen:4693337 | 06 zesde verdieping | 22.21 binnenwanden - constructief, massieve wanden (Uniformat) | Model Group:NLRS_01.00_verdieping type B1_gen:4644030
Basic Wall:NLRS_22.21_WA_beton prefab d=500_gen:4693342 | 06 zesde verdieping | 22.21 binnenwanden - constructief, massieve wanden (Uniformat) | Model Group:NLRS_01.00_verdieping type B1_gen:4644030
Basic Wall:NLRS_22.21_WA_beton prefab d=500_gen:4693394 | 06 zesde verdieping | 22.21 binnenwanden - constructief, massieve wanden (Uniformat) | Model Group:NLRS_01.00_verdieping type B1_gen:4644030
Basic Wall:NLRS_22.21_WA_beton prefab d=500_gen:4693399 | 06 zesde verdieping | 22.21 binnenwanden - constructief, massieve wanden (Uniformat) | Model Group:NLRS_01.00_verdieping type B1_gen:4644030
Basic Wall:NLRS_22.21_WA_beton prefab d=500_gen:4693451 | 06 zesde verdieping | 22.21 binnenwanden - constructief, massieve wanden (Uniformat) | Model Group:NLRS_01.00_verdieping type B1_gen:4644030
Basic Wall:NLRS_22.21_WA_beton prefab d=500_gen:4693456 | 06 zesde verdieping | 22.21 binnenwanden - constructief, massieve wanden (Uniformat) | Model Group:NLRS_01.00_verdieping type B1_gen:4644030
Basic Wall:NLRS_21.21_WA_beton prefab d=400/420_gen:4693504 | 07 zevende verdieping | 21.21 buitenwanden - constructief, massieve wanden (Uniformat) | Model Group:NLRS_21.21_WA_wand 001 d=400_gen:4689143
Basic Wall:NLRS_21.21_WA_beton prefab d=400/420_gen:4693534 | 07 zevende verdieping | 21.21 buitenwanden - constructief, massieve wanden (Uniformat) | Model Group:NLRS_21.21_WA_wand 001 d=400_gen:4689134
Basic Wall:NLRS_22.21_WA_beton prefab d=400_gen:4694966 | 21 eenentwintigste verdieping | 22.21 binnenwanden - constructief, massieve wanden (Uniformat) | Model Group:NLRS_01.00_verdieping type F1_gen:4694955
Basic Wall:NLRS_22.21_WA_beton prefab d=400_gen:4694968 | 21 eenentwintigste verdieping | 22.21 binnenwanden - constructief, massieve wanden (Uniformat) | Model Group:NLRS_01.00_verdieping type F1_gen:4694955
2 x Basic Wall:NLRS_22.21_WA_beton prefab d=400_gen:4694970 | 21 eenentwintigste verdieping | 22.21 binnenwanden - constructief, massieve wanden (Uniformat) | Model Group:NLRS_01.00_verdieping type F1_gen:4694955
Basic Wall:NLRS_21.21_WA_beton prefab d=300/320_gen:4694984 | 21 eenentwintigste verdieping | 21.21 buitenwanden - constructief, massieve wanden (Uniformat) | Model Group:NLRS_21.21_WA_wand 003 d=300_gen:4695035
Basic Wall:NLRS_21.21_WA_beton prefab d=300/320_gen:4694986 | 21 eenentwintigste verdieping | 21.21 buitenwanden - constructief, massieve wanden (Uniformat) | Model Group:NLRS_21.21_WA_wand 001 d=300_gen:4695034
Basic Wall:NLRS_21.21_WA_beton prefab d=300/320_gen:4695036 | 21 eenentwintigste verdieping | 21.21 buitenwanden - constructief, massieve wanden (Uniformat) | Model Group:NLRS_21.21_WA_wand 003 d=300_gen:4695039
Basic Wall:NLRS_21.21_WA_beton prefab d=300/320_gen:4695040 | 21 eenentwintigste verdieping | 21.21 buitenwanden - constructief, massieve wanden (Uniformat) | Model Group:NLRS_21.21_WA_wand 001 d=300_gen:4695043
3 x Basic Wall:NLRS_21.21_WA_beton prefab d=300/320_gen:4695055 | 21 eenentwintigste verdieping | 21.21 buitenwanden - constructief, massieve wanden (Uniformat) | Model Group:NLRS_21.21_WA_wand 002 d=300_gen:4695033
2 x Basic Wall:NLRS_21.21_WA_beton prefab d=300/320_gen:5365657 | 21 eenentwintigste verdieping | 21.21 buitenwanden - constructief, massieve wanden (Uniformat) | Model Group:NLRS_21.21_WA_wand 002 d=300_gen:4695033
3 x Basic Wall:NLRS_21.21_WA_beton prefab d=300/320_gen:4695057 | 21 eenentwintigste verdieping | 21.21 buitenwanden - constructief, massieve wanden (Uniformat) | Model Group:NLRS_21.21_WA_wand 002 d=300_gen:4695026
2 x Basic Wall:NLRS_21.21_WA_beton prefab d=300/320_gen:5365657 | 21 eenentwintigste verdieping | 21.21 buitenwanden - constructief, massieve wanden (Uniformat) | Model Group:NLRS_21.21_WA_wand 002 d=300_gen:4695026
3 x Basic Wall:NLRS_21.21_WA_beton prefab d=300/320_gen:4695081 | 21 eenentwintigste verdieping | 21.21 buitenwanden - constructief, massieve wanden (Uniformat) | Model Group:NLRS_21.21_WA_wand 004 d=300_gen:4695025
2 x Basic Wall:NLRS_21.21_WA_beton prefab d=300/320_gen:5365657 | 21 eenentwintigste verdieping | 21.21 buitenwanden - constructief, massieve wanden (Uniformat) | Model Group:NLRS_21.21_WA_wand 004 d=300_gen:4695025
3 x Basic Wall:NLRS_21.21_WA_beton prefab d=300/320_gen:4695083 | 21 eenentwintigste verdieping | 21.21 buitenwanden - constructief, massieve wanden (Uniformat) | Model Group:NLRS_21.21_WA_wand 004 d=300_gen:4695016
2 x Basic Wall:NLRS_21.21_WA_beton prefab d=300/320_gen:5365657 | 21 eenentwintigste verdieping | 21.21 buitenwanden - constructief, massieve wanden (Uniformat) | Model Group:NLRS_21.21_WA_wand 004 d=300_gen:4695016
Basic Wall:NLRS_21.21_WA_beton prefab d=300/320_gen:4695192 | 21 eenentwintigste verdieping | 21.21 buitenwanden - constructief, massieve wanden (Uniformat) | Model Group:NLRS_28.21_WA_3D element 002 d=300_gen:4695207
Basic Wall:NLRS_21.21_WA_beton prefab d=300/320_gen:4695194 | 21 eenentwintigste verdieping | 21.21 buitenwanden - constructief, massieve wanden (Uniformat) | Model Group:NLRS_28.21_WA_3D element 002 d=300_gen:4695207
Basic Wall:NLRS_22.21_WA_beton prefab d=300_gen:4695261 | 21 eenentwintigste verdieping | 22.21 binnenwanden - constructief, massieve wanden (Uniformat) | Model Group:NLRS_01.00_verdieping type F1_gen:4694955
2 x Basic Wall:NLRS_22.21_WA_beton prefab d=300_gen:4472952 | 21 eenentwintigste verdieping | 22.21 binnenwanden - constructief, massieve wanden (Uniformat) | Model Group:NLRS_01.00_verdieping type F1_gen:4694955
Basic Wall:NLRS_22.21_WA_beton prefab d=400_gen:4695265 | 21 eenentwintigste verdieping | 22.21 binnenwanden - constructief, massieve wanden (Uniformat) | Model Group:NLRS_01.00_verdieping type F1_gen:4694955
Basic Wall:NLRS_22.21_WA_beton prefab d=400_gen:4695270 | 21 eenentwintigste verdieping | 22.21 binnenwanden - constructief, massieve wanden (Uniformat) | Model Group:NLRS_01.00_verdieping type F1_gen:4694955
Basic Wall:NLRS_21.21_WA_beton prefab d=300/320_gen:4695291 | 21 eenentwintigste verdieping | 21.21 buitenwanden - constructief, massieve wanden (Uniformat) | Model Group:NLRS_28.21_WA_3D element 002 d=300_gen:4695191
Basic Wall:NLRS_21.21_WA_beton prefab d=300/320_gen:4695293 | 21 eenentwintigste verdieping | 21.21 buitenwanden - constructief, massieve wanden (Uniformat) | Model Group:NLRS_28.21_WA_3D element 002 d=300_gen:4695191
Basic Wall:NLRS_22.21_WA_beton prefab d=300_gen:4695320 | 21 eenentwintigste verdieping | 22.21 binnenwanden - constructief, massieve wanden (Uniformat) | Model Group:NLRS_01.00_verdieping type F1_gen:4694955
Basic Wall:NLRS_22.21_WA_beton prefab d=400_gen:4695323 | 21 eenentwintigste verdieping | 22.21 binnenwanden - constructief, massieve wanden (Uniformat) | Model Group:NLRS_01.00_verdieping type F1_gen:4694955
Basic Wall:NLRS_22.21_WA_beton prefab d=400_gen:4695326 | 21 eenentwintigste verdieping | 22.21 binnenwanden - constructief, massieve wanden (Uniformat) | Model Group:NLRS_01.00_verdieping type F1_gen:4694955
Basic Wall:NLRS_22.21_WA_beton prefab d=400_gen:4695329 | 21 eenentwintigste verdieping | 22.21 binnenwanden - constructief, massieve wanden (Uniformat) | Model Group:NLRS_01.00_verdieping type F1_gen:4694955
Basic Wall:NLRS_22.21_WA_beton prefab d=400_gen:4695332 | 21 eenentwintigste verdieping | 22.21 binnenwanden - constructief, massieve wanden (Uniformat) | Model Group:NLRS_01.00_verdieping type F1_gen:4694955
Basic Wall:NLRS_21.21_WA_beton prefab d=300/320_gen:4695335 | 21 eenentwintigste verdieping | 21.21 buitenwanden - constructief, massieve wanden (Uniformat) | Model Group:NLRS_28.21_WA_3D element 001 d=300_gen:4695190
Basic Wall:NLRS_21.21_WA_beton prefab d=300/320_gen:4695338 | 21 eenentwintigste verdieping | 21.21 buitenwanden - constructief, massieve wanden (Uniformat) | Model Group:NLRS_28.21_WA_3D element 001 d=300_gen:4695190
Basic Wall:NLRS_21.21_WA_beton prefab d=300/320_gen:4695364 | 21 eenentwintigste verdieping | 21.21 buitenwanden - constructief, massieve wanden (Uniformat) | Model Group:NLRS_28.21_WA_3D element 001 d=300_gen:4695208
Basic Wall:NLRS_21.21_WA_beton prefab d=300/320_gen:4695367 | 21 eenentwintigste verdieping | 21.21 buitenwanden - constructief, massieve wanden (Uniformat) | Model Group:NLRS_28.21_WA_3D element 001 d=300_gen:4695208
2 x Basic Wall:NLRS_22.21_WA_beton prefab d=400_gen:4695394 | 21 eenentwintigste verdieping | 22.21 binnenwanden - constructief, massieve wanden (Uniformat) | Model Group:NLRS_01.00_verdieping type F1_gen:4694955
2 x Basic Wall:NLRS_22.21_WA_beton prefab d=400_gen:4699555 | 21 eenentwintigste verdieping | 22.21 binnenwanden - constructief, massieve wanden (Uniformat) | Model Group:NLRS_01.00_verdieping type F1_gen:4694955
2 x Basic Wall:NLRS_22.21_WA_beton prefab d=400_gen:4698002 | 21 eenentwintigste verdieping | 22.21 binnenwanden - constructief, massieve wanden (Uniformat) | Model Group:NLRS_01.00_verdieping type F1_gen:4694955
2 x Basic Wall:NLRS_22.21_WA_beton prefab d=400_gen:4698093 | 21 eenentwintigste verdieping | 22.21 binnenwanden - constructief, massieve wanden (Uniformat) | Model Group:NLRS_01.00_verdieping type F1_gen:4694955
Basic Wall:NLRS_21.21_WA_beton prefab d=400/420_gen:4714771 | 08 achtste verdieping | 21.21 buitenwanden - constructief, massieve wanden (Uniformat) | Model Group:NLRS_28.21_WA_3D element 002 d=400_gen:4714990
Basic Wall:NLRS_21.21_WA_beton prefab d=400/420_gen:4714801 | 08 achtste verdieping | 21.21 buitenwanden - constructief, massieve wanden (Uniformat) | Model Group:NLRS_28.21_WA_3D element 002 d=400_gen:4714990
Basic Wall:NLRS_21.21_WA_beton prefab d=400/420_gen:4714803 | 08 achtste verdieping | 21.21 buitenwanden - constructief, massieve wanden (Uniformat) | Model Group:NLRS_28.21_WA_3D element 001 d=400_gen:4714980
Basic Wall:NLRS_21.21_WA_beton prefab d=400/420_gen:4714824 | 08 achtste verdieping | 21.21 buitenwanden - constructief, massieve wanden (Uniformat) | Model Group:NLRS_28.21_WA_3D element 001 d=400_gen:4714980
Basic Wall:NLRS_21.21_WA_beton prefab d=400/420_gen:4714833 | 08 achtste verdieping | 21.21 buitenwanden - constructief, massieve wanden (Uniformat) | Model Group:NLRS_21.21_WA_wand 001 d=400_gen:4714836
Basic Wall:NLRS_21.21_WA_beton prefab d=400/420_gen:4714991 | 08 achtste verdieping | 21.21 buitenwanden - constructief, massieve wanden (Uniformat) | Model Group:NLRS_28.21_WA_3D element 002 d=400_gen:4715006
Basic Wall:NLRS_21.21_WA_beton prefab d=400/420_gen:4714993 | 08 achtste verdieping | 21.21 buitenwanden - constructief, massieve wanden (Uniformat) | Model Group:NLRS_28.21_WA_3D element 002 d=400_gen:4715006
Basic Wall:NLRS_21.21_WA_beton prefab d=400/420_gen:4715007 | 08 achtste verdieping | 21.21 buitenwanden - constructief, massieve wanden (Uniformat) | Model Group:NLRS_28.21_WA_3D element 001 d=400_gen:4715022
Basic Wall:NLRS_21.21_WA_beton prefab d=400/420_gen:4715010 | 08 achtste verdieping | 21.21 buitenwanden - constructief, massieve wanden (Uniformat) | Model Group:NLRS_28.21_WA_3D element 001 d=400_gen:4715022
4 x Basic Wall:NLRS_21.21_WA_beton prefab d=400/420_gen:4715168 | 08 achtste verdieping | 21.21 buitenwanden - constructief, massieve wanden (Uniformat) | Model Group:NLRS_21.21_WA_wand 004aa d=400_gen:4714827
2 x Basic Wall:NLRS_21.21_WA_beton prefab d=400/420_gen:5362948 | 08 achtste verdieping | 21.21 buitenwanden - constructief, massieve wanden (Uniformat) | Model Group:NLRS_21.21_WA_wand 004aa d=400_gen:4714827
Basic Wall:NLRS_21.21_WA_beton prefab d=400/420_gen:4715170 | 08 achtste verdieping | 21.21 buitenwanden - constructief, massieve wanden (Uniformat) | Model Group:NLRS_21.21_WA_wand 003 d=400_gen:4714832
4 x Basic Wall:NLRS_21.21_WA_beton prefab d=400/420_gen:4715179 | 08 achtste verdieping | 21.21 buitenwanden - constructief, massieve wanden (Uniformat) | Model Group:NLRS_21.21_WA_wand 002a d=400_gen:4714829
2 x Basic Wall:NLRS_21.21_WA_beton prefab d=400/420_gen:5362948 | 08 achtste verdieping | 21.21 buitenwanden - constructief, massieve wanden (Uniformat) | Model Group:NLRS_21.21_WA_wand 002a d=400_gen:4714829
Basic Wall:NLRS_21.21_WA_beton prefab d=400/420_gen:4715181 | 08 achtste verdieping | 21.21 buitenwanden - constructief, massieve wanden (Uniformat) | Model Group:NLRS_21.21_WA_wand 003 d=400_gen:4714831
Basic Wall:NLRS_21.21_WA_beton prefab d=400/420_gen:4715192 | 08 achtste verdieping | 21.21 buitenwanden - constructief, massieve wanden (Uniformat) | Model Group:NLRS_21.21_WA_wand 001 d=400_gen:4714830
Basic Wall:NLRS_22.21_WA_beton prefab d=500_gen:4720988 | 06 zesde verdieping | 22.21 binnenwanden - constructief, massieve wanden (Uniformat) | Model Group:NLRS_01.00_verdieping type B1_gen:4644030
Basic Wall:NLRS_22.21_WA_beton prefab d=500_gen:4720992 | 06 zesde verdieping | 22.21 binnenwanden - constructief, massieve wanden (Uniformat) | Model Group:NLRS_01.00_verdieping type B1_gen:4644030
Basic Wall:NLRS_21.21_WA_beton prefab d=300/320_gen:4730607 | 13 dertiende verdieping | 21.21 buitenwanden - constructief, massieve wanden (Uniformat) | Model Group:NLRS_21.21_WA_wand 003 d=300_gen:4730658
Basic Wall:NLRS_21.21_WA_beton prefab d=300/320_gen:4730609 | 13 dertiende verdieping | 21.21 buitenwanden - constructief, massieve wanden (Uniformat) | Model Group:NLRS_21.21_WA_wand 001 d=300_gen:4730657
Basic Wall:NLRS_21.21_WA_beton prefab d=300/320_gen:4730659 | 13 dertiende verdieping | 21.21 buitenwanden - constructief, massieve wanden (Uniformat) | Model Group:NLRS_21.21_WA_wand 003 d=300_gen:4730662
Basic Wall:NLRS_21.21_WA_beton prefab d=300/320_gen:4730663 | 13 dertiende verdieping | 21.21 buitenwanden - constructief, massieve wanden (Uniformat) | Model Group:NLRS_21.21_WA_wand 001 d=300_gen:4730666
Basic Wall:NLRS_21.21_WA_beton prefab d=300/320_gen:4730815 | 13 dertiende verdieping | 21.21 buitenwanden - constructief, massieve wanden (Uniformat) | Model Group:NLRS_28.21_WA_3D element 002 d=300_gen:4730830
Basic Wall:NLRS_21.21_WA_beton prefab d=300/320_gen:4730817 | 13 dertiende verdieping | 21.21 buitenwanden - constructief, massieve wanden (Uniformat) | Model Group:NLRS_28.21_WA_3D element 002 d=300_gen:4730830
Basic Wall:NLRS_21.21_WA_beton prefab d=300/320_gen:4730914 | 13 dertiende verdieping | 21.21 buitenwanden - constructief, massieve wanden (Uniformat) | Model Group:NLRS_28.21_WA_3D element 002 d=300_gen:4730814
Basic Wall:NLRS_21.21_WA_beton prefab d=300/320_gen:4730916 | 13 dertiende verdieping | 21.21 buitenwanden - constructief, massieve wanden (Uniformat) | Model Group:NLRS_28.21_WA_3D element 002 d=300_gen:4730814
Basic Wall:NLRS_21.21_WA_beton prefab d=300/320_gen:4730958 | 13 dertiende verdieping | 21.21 buitenwanden - constructief, massieve wanden (Uniformat) | Model Group:NLRS_28.21_WA_3D element 001 d=300_gen:4730813
Basic Wall:NLRS_21.21_WA_beton prefab d=300/320_gen:4730961 | 13 dertiende verdieping | 21.21 buitenwanden - constructief, massieve wanden (Uniformat) | Model Group:NLRS_28.21_WA_3D element 001 d=300_gen:4730813
Basic Wall:NLRS_21.21_WA_beton prefab d=300/320_gen:4730987 | 13 dertiende verdieping | 21.21 buitenwanden - constructief, massieve wanden (Uniformat) | Model Group:NLRS_28.21_WA_3D element 001 d=300_gen:4730831
Basic Wall:NLRS_21.21_WA_beton prefab d=300/320_gen:4730990 | 13 dertiende verdieping | 21.21 buitenwanden - constructief, massieve wanden (Uniformat) | Model Group:NLRS_28.21_WA_3D element 001 d=300_gen:4730831
Basic Wall:NLRS_21.21_WA_beton prefab d=300/320_gen:4731065 | 15 vijftiende verdieping | 21.21 buitenwanden - constructief, massieve wanden (Uniformat) | Model Group:NLRS_21.21_WA_wand 003 d=300_gen:4731116
Basic Wall:NLRS_21.21_WA_beton prefab d=300/320_gen:4731067 | 15 vijftiende verdieping | 21.21 buitenwanden - constructief, massieve wanden (Uniformat) | Model Group:NLRS_21.21_WA_wand 001 d=300_gen:4731115
Basic Wall:NLRS_21.21_WA_beton prefab d=300/320_gen:4731117 | 15 vijftiende verdieping | 21.21 buitenwanden - constructief, massieve wanden (Uniformat) | Model Group:NLRS_21.21_WA_wand 003 d=300_gen:4731120
Basic Wall:NLRS_21.21_WA_beton prefab d=300/320_gen:4731121 | 15 vijftiende verdieping | 21.21 buitenwanden - constructief, massieve wanden (Uniformat) | Model Group:NLRS_21.21_WA_wand 001 d=300_gen:4731124
3 x Basic Wall:NLRS_21.21_WA_beton prefab d=300/320_gen:4731136 | 15 vijftiende verdieping | 21.21 buitenwanden - constructief, massieve wanden (Uniformat) | Model Group:NLRS_21.21_WA_wand 002 d=300_gen:4731114
2 x Basic Wall:NLRS_21.21_WA_beton prefab d=300/320_gen:5365657 | 15 vijftiende verdieping | 21.21 buitenwanden - constructief, massieve wanden (Uniformat) | Model Group:NLRS_21.21_WA_wand 002 d=300_gen:4731114
3 x Basic Wall:NLRS_21.21_WA_beton prefab d=300/320_gen:4731162 | 15 vijftiende verdieping | 21.21 buitenwanden - constructief, massieve wanden (Uniformat) | Model Group:NLRS_21.21_WA_wand 004 d=300_gen:4731106
2 x Basic Wall:NLRS_21.21_WA_beton prefab d=300/320_gen:5365657 | 15 vijftiende verdieping | 21.21 buitenwanden - constructief, massieve wanden (Uniformat) | Model Group:NLRS_21.21_WA_wand 004 d=300_gen:4731106
3 x Basic Wall:NLRS_21.21_WA_beton prefab d=300/320_gen:4731164 | 15 vijftiende verdieping | 21.21 buitenwanden - constructief, massieve wanden (Uniformat) | Model Group:NLRS_21.21_WA_wand 004 d=300_gen:4731097
2 x Basic Wall:NLRS_21.21_WA_beton prefab d=300/320_gen:5365657 | 15 vijftiende verdieping | 21.21 buitenwanden - constructief, massieve wanden (Uniformat) | Model Group:NLRS_21.21_WA_wand 004 d=300_gen:4731097
Basic Wall:NLRS_21.21_WA_beton prefab d=300/320_gen:4731273 | 15 vijftiende verdieping | 21.21 buitenwanden - constructief, massieve wanden (Uniformat) | Model Group:NLRS_28.21_WA_3D element 002 d=300_gen:4731288
Basic Wall:NLRS_21.21_WA_beton prefab d=300/320_gen:4731275 | 15 vijftiende verdieping | 21.21 buitenwanden - constructief, massieve wanden (Uniformat) | Model Group:NLRS_28.21_WA_3D element 002 d=300_gen:4731288
Basic Wall:NLRS_21.21_WA_beton prefab d=300/320_gen:4731372 | 15 vijftiende verdieping | 21.21 buitenwanden - constructief, massieve wanden (Uniformat) | Model Group:NLRS_28.21_WA_3D element 002 d=300_gen:4731272
Basic Wall:NLRS_21.21_WA_beton prefab d=300/320_gen:4731374 | 15 vijftiende verdieping | 21.21 buitenwanden - constructief, massieve wanden (Uniformat) | Model Group:NLRS_28.21_WA_3D element 002 d=300_gen:4731272
Basic Wall:NLRS_21.21_WA_beton prefab d=300/320_gen:4731416 | 15 vijftiende verdieping | 21.21 buitenwanden - constructief, massieve wanden (Uniformat) | Model Group:NLRS_28.21_WA_3D element 001 d=300_gen:4731271
Basic Wall:NLRS_21.21_WA_beton prefab d=300/320_gen:4731419 | 15 vijftiende verdieping | 21.21 buitenwanden - constructief, massieve wanden (Uniformat) | Model Group:NLRS_28.21_WA_3D element 001 d=300_gen:4731271
Basic Wall:NLRS_21.21_WA_beton prefab d=300/320_gen:4731445 | 15 vijftiende verdieping | 21.21 buitenwanden - constructief, massieve wanden (Uniformat) | Model Group:NLRS_28.21_WA_3D element 001 d=300_gen:4731289
Basic Wall:NLRS_21.21_WA_beton prefab d=300/320_gen:4731448 | 15 vijftiende verdieping | 21.21 buitenwanden - constructief, massieve wanden (Uniformat) | Model Group:NLRS_28.21_WA_3D element 001 d=300_gen:4731289
Basic Wall:NLRS_21.21_WA_beton prefab d=300/320_gen:4731523 | 17 zeventiende verdieping | 21.21 buitenwanden - constructief, massieve wanden (Uniformat) | Model Group:NLRS_21.21_WA_wand 003 d=300_gen:4731574
Basic Wall:NLRS_21.21_WA_beton prefab d=300/320_gen:4731525 | 17 zeventiende verdieping | 21.21 buitenwanden - constructief, massieve wanden (Uniformat) | Model Group:NLRS_21.21_WA_wand 001 d=300_gen:4731573
Basic Wall:NLRS_21.21_WA_beton prefab d=300/320_gen:4731575 | 17 zeventiende verdieping | 21.21 buitenwanden - constructief, massieve wanden (Uniformat) | Model Group:NLRS_21.21_WA_wand 003 d=300_gen:4731578
Basic Wall:NLRS_21.21_WA_beton prefab d=300/320_gen:4731579 | 17 zeventiende verdieping | 21.21 buitenwanden - constructief, massieve wanden (Uniformat) | Model Group:NLRS_21.21_WA_wand 001 d=300_gen:4731582
3 x Basic Wall:NLRS_21.21_WA_beton prefab d=300/320_gen:4731594 | 17 zeventiende verdieping | 21.21 buitenwanden - constructief, massieve wanden (Uniformat) | Model Group:NLRS_21.21_WA_wand 002 d=300_gen:4731572
2 x Basic Wall:NLRS_21.21_WA_beton prefab d=300/320_gen:5365657 | 17 zeventiende verdieping | 21.21 buitenwanden - constructief, massieve wanden (Uniformat) | Model Group:NLRS_21.21_WA_wand 002 d=300_gen:4731572
3 x Basic Wall:NLRS_21.21_WA_beton prefab d=300/320_gen:4731620 | 17 zeventiende verdieping | 21.21 buitenwanden - constructief, massieve wanden (Uniformat) | Model Group:NLRS_21.21_WA_wand 004 d=300_gen:4731564
2 x Basic Wall:NLRS_21.21_WA_beton prefab d=300/320_gen:5365657 | 17 zeventiende verdieping | 21.21 buitenwanden - constructief, massieve wanden (Uniformat) | Model Group:NLRS_21.21_WA_wand 004 d=300_gen:4731564
3 x Basic Wall:NLRS_21.21_WA_beton prefab d=300/320_gen:4731622 | 17 zeventiende verdieping | 21.21 buitenwanden - constructief, massieve wanden (Uniformat) | Model Group:NLRS_21.21_WA_wand 004 d=300_gen:4731555
2 x Basic Wall:NLRS_21.21_WA_beton prefab d=300/320_gen:5365657 | 17 zeventiende verdieping | 21.21 buitenwanden - constructief, massieve wanden (Uniformat) | Model Group:NLRS_21.21_WA_wand 004 d=300_gen:4731555
Basic Wall:NLRS_21.21_WA_beton prefab d=300/320_gen:4731731 | 17 zeventiende verdieping | 21.21 buitenwanden - constructief, massieve wanden (Uniformat) | Model Group:NLRS_28.21_WA_3D element 002 d=300_gen:4731746
Basic Wall:NLRS_21.21_WA_beton prefab d=300/320_gen:4731733 | 17 zeventiende verdieping | 21.21 buitenwanden - constructief, massieve wanden (Uniformat) | Model Group:NLRS_28.21_WA_3D element 002 d=300_gen:4731746
Basic Wall:NLRS_21.21_WA_beton prefab d=300/320_gen:4731830 | 17 zeventiende verdieping | 21.21 buitenwanden - constructief, massieve wanden (Uniformat) | Model Group:NLRS_28.21_WA_3D element 002 d=300_gen:4731730
Basic Wall:NLRS_21.21_WA_beton prefab d=300/320_gen:4731832 | 17 zeventiende verdieping | 21.21 buitenwanden - constructief, massieve wanden (Uniformat) | Model Group:NLRS_28.21_WA_3D element 002 d=300_gen:4731730
Basic Wall:NLRS_21.21_WA_beton prefab d=300/320_gen:4731874 | 17 zeventiende verdieping | 21.21 buitenwanden - constructief, massieve wanden (Uniformat) | Model Group:NLRS_28.21_WA_3D element 001 d=300_gen:4731729
Basic Wall:NLRS_21.21_WA_beton prefab d=300/320_gen:4731877 | 17 zeventiende verdieping | 21.21 buitenwanden - constructief, massieve wanden (Uniformat) | Model Group:NLRS_28.21_WA_3D element 001 d=300_gen:4731729
Basic Wall:NLRS_21.21_WA_beton prefab d=300/320_gen:4731903 | 17 zeventiende verdieping | 21.21 buitenwanden - constructief, massieve wanden (Uniformat) | Model Group:NLRS_28.21_WA_3D element 001 d=300_gen:4731747
Basic Wall:NLRS_21.21_WA_beton prefab d=300/320_gen:4731906 | 17 zeventiende verdieping | 21.21 buitenwanden - constructief, massieve wanden (Uniformat) | Model Group:NLRS_28.21_WA_3D element 001 d=300_gen:4731747
Basic Wall:NLRS_21.21_WA_beton prefab d=300/320_gen:4731981 | 19 negentiende verdieping | 21.21 buitenwanden - constructief, massieve wanden (Uniformat) | Model Group:NLRS_21.21_WA_wand 003 d=300_gen:4732032
Basic Wall:NLRS_21.21_WA_beton prefab d=300/320_gen:4731983 | 19 negentiende verdieping | 21.21 buitenwanden - constructief, massieve wanden (Uniformat) | Model Group:NLRS_21.21_WA_wand 001 d=300_gen:4732031
Basic Wall:NLRS_21.21_WA_beton prefab d=300/320_gen:4732033 | 19 negentiende verdieping | 21.21 buitenwanden - constructief, massieve wanden (Uniformat) | Model Group:NLRS_21.21_WA_wand 003 d=300_gen:4732036
Basic Wall:NLRS_21.21_WA_beton prefab d=300/320_gen:4732037 | 19 negentiende verdieping | 21.21 buitenwanden - constructief, massieve wanden (Uniformat) | Model Group:NLRS_21.21_WA_wand 001 d=300_gen:4732040
3 x Basic Wall:NLRS_21.21_WA_beton prefab d=300/320_gen:4732052 | 19 negentiende verdieping | 21.21 buitenwanden - constructief, massieve wanden (Uniformat) | Model Group:NLRS_21.21_WA_wand 002 d=300_gen:4732030
2 x Basic Wall:NLRS_21.21_WA_beton prefab d=300/320_gen:5365657 | 19 negentiende verdieping | 21.21 buitenwanden - constructief, massieve wanden (Uniformat) | Model Group:NLRS_21.21_WA_wand 002 d=300_gen:4732030
3 x Basic Wall:NLRS_21.21_WA_beton prefab d=300/320_gen:4732078 | 19 negentiende verdieping | 21.21 buitenwanden - constructief, massieve wanden (Uniformat) | Model Group:NLRS_21.21_WA_wand 004 d=300_gen:4732022
2 x Basic Wall:NLRS_21.21_WA_beton prefab d=300/320_gen:5365657 | 19 negentiende verdieping | 21.21 buitenwanden - constructief, massieve wanden (Uniformat) | Model Group:NLRS_21.21_WA_wand 004 d=300_gen:4732022
3 x Basic Wall:NLRS_21.21_WA_beton prefab d=300/320_gen:4732080 | 19 negentiende verdieping | 21.21 buitenwanden - constructief, massieve wanden (Uniformat) | Model Group:NLRS_21.21_WA_wand 004 d=300_gen:4732013
2 x Basic Wall:NLRS_21.21_WA_beton prefab d=300/320_gen:5365657 | 19 negentiende verdieping | 21.21 buitenwanden - constructief, massieve wanden (Uniformat) | Model Group:NLRS_21.21_WA_wand 004 d=300_gen:4732013
Basic Wall:NLRS_21.21_WA_beton prefab d=300/320_gen:4732189 | 19 negentiende verdieping | 21.21 buitenwanden - constructief, massieve wanden (Uniformat) | Model Group:NLRS_28.21_WA_3D element 002 d=300_gen:4732204
Basic Wall:NLRS_21.21_WA_beton prefab d=300/320_gen:4732191 | 19 negentiende verdieping | 21.21 buitenwanden - constructief, massieve wanden (Uniformat) | Model Group:NLRS_28.21_WA_3D element 002 d=300_gen:4732204
Basic Wall:NLRS_21.21_WA_beton prefab d=300/320_gen:4732288 | 19 negentiende verdieping | 21.21 buitenwanden - constructief, massieve wanden (Uniformat) | Model Group:NLRS_28.21_WA_3D element 002 d=300_gen:4732188
Basic Wall:NLRS_21.21_WA_beton prefab d=300/320_gen:4732290 | 19 negentiende verdieping | 21.21 buitenwanden - constructief, massieve wanden (Uniformat) | Model Group:NLRS_28.21_WA_3D element 002 d=300_gen:4732188
Basic Wall:NLRS_21.21_WA_beton prefab d=300/320_gen:4732332 | 19 negentiende verdieping | 21.21 buitenwanden - constructief, massieve wanden (Uniformat) | Model Group:NLRS_28.21_WA_3D element 001 d=300_gen:4732187
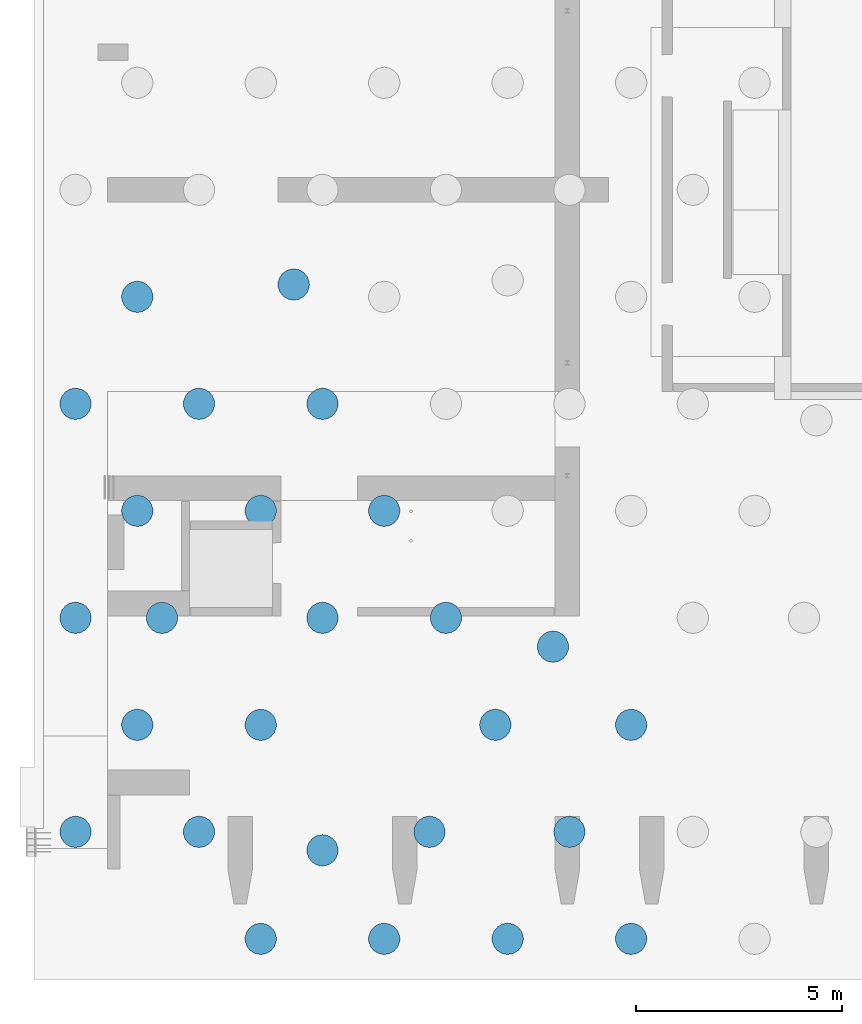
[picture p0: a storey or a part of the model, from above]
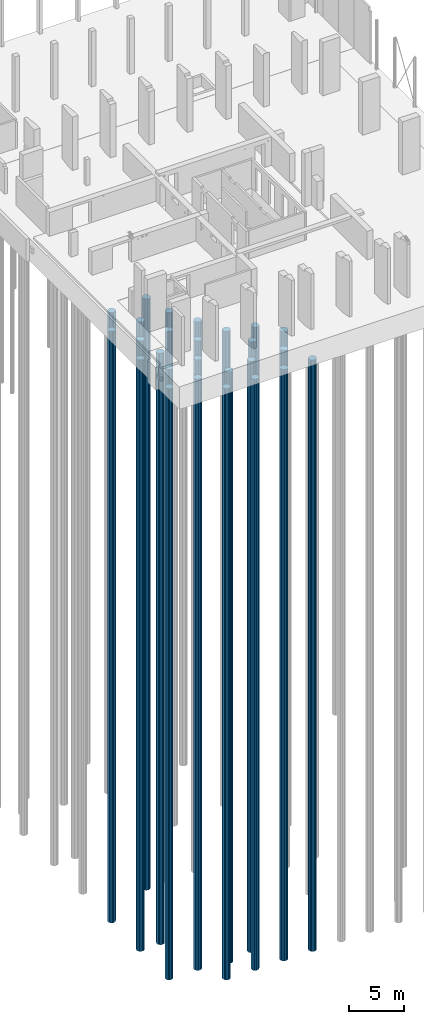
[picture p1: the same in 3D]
Properties of the parts of a building model (IFC2X3), part 8 of 21

# IfcOpeningElement: Opening (5659)
Name | In | Classification | Group
Basic Wall:NLRS_21.21_WA_beton prefab d=300/320_gen:4732335 | 19 negentiende verdieping | 21.21 buitenwanden - constructief, massieve wanden (Uniformat) | Model Group:NLRS_28.21_WA_3D element 001 d=300_gen:4732187
Basic Wall:NLRS_21.21_WA_beton prefab d=300/320_gen:4732361 | 19 negentiende verdieping | 21.21 buitenwanden - constructief, massieve wanden (Uniformat) | Model Group:NLRS_28.21_WA_3D element 001 d=300_gen:4732205
Basic Wall:NLRS_21.21_WA_beton prefab d=300/320_gen:4732364 | 19 negentiende verdieping | 21.21 buitenwanden - constructief, massieve wanden (Uniformat) | Model Group:NLRS_28.21_WA_3D element 001 d=300_gen:4732205
Basic Wall:NLRS_21.21_WA_beton prefab d=300/320_gen:4738194 | 12 twaalfde verdieping | 21.21 buitenwanden - constructief, massieve wanden (Uniformat) | Model Group:NLRS_21.21_WA_wand 003 d=300_gen:4738245
Basic Wall:NLRS_21.21_WA_beton prefab d=300/320_gen:4738196 | 12 twaalfde verdieping | 21.21 buitenwanden - constructief, massieve wanden (Uniformat) | Model Group:NLRS_21.21_WA_wand 001 d=300_gen:4738244
Basic Wall:NLRS_21.21_WA_beton prefab d=300/320_gen:4738246 | 12 twaalfde verdieping | 21.21 buitenwanden - constructief, massieve wanden (Uniformat) | Model Group:NLRS_21.21_WA_wand 003 d=300_gen:4738249
Basic Wall:NLRS_21.21_WA_beton prefab d=300/320_gen:4738250 | 12 twaalfde verdieping | 21.21 buitenwanden - constructief, massieve wanden (Uniformat) | Model Group:NLRS_21.21_WA_wand 001 d=300_gen:4738253
Basic Wall:NLRS_21.21_WA_beton prefab d=300/320_gen:4738402 | 12 twaalfde verdieping | 21.21 buitenwanden - constructief, massieve wanden (Uniformat) | Model Group:NLRS_28.21_WA_3D element 002 d=300_gen:4738417
Basic Wall:NLRS_21.21_WA_beton prefab d=300/320_gen:4738404 | 12 twaalfde verdieping | 21.21 buitenwanden - constructief, massieve wanden (Uniformat) | Model Group:NLRS_28.21_WA_3D element 002 d=300_gen:4738417
Basic Wall:NLRS_21.21_WA_beton prefab d=300/320_gen:4738501 | 12 twaalfde verdieping | 21.21 buitenwanden - constructief, massieve wanden (Uniformat) | Model Group:NLRS_28.21_WA_3D element 002 d=300_gen:4738401
Basic Wall:NLRS_21.21_WA_beton prefab d=300/320_gen:4738503 | 12 twaalfde verdieping | 21.21 buitenwanden - constructief, massieve wanden (Uniformat) | Model Group:NLRS_28.21_WA_3D element 002 d=300_gen:4738401
Basic Wall:NLRS_21.21_WA_beton prefab d=300/320_gen:4738545 | 12 twaalfde verdieping | 21.21 buitenwanden - constructief, massieve wanden (Uniformat) | Model Group:NLRS_28.21_WA_3D element 001 d=300_gen:4738400
Basic Wall:NLRS_21.21_WA_beton prefab d=300/320_gen:4738548 | 12 twaalfde verdieping | 21.21 buitenwanden - constructief, massieve wanden (Uniformat) | Model Group:NLRS_28.21_WA_3D element 001 d=300_gen:4738400
Basic Wall:NLRS_21.21_WA_beton prefab d=300/320_gen:4738574 | 12 twaalfde verdieping | 21.21 buitenwanden - constructief, massieve wanden (Uniformat) | Model Group:NLRS_28.21_WA_3D element 001 d=300_gen:4738418
Basic Wall:NLRS_21.21_WA_beton prefab d=300/320_gen:4738577 | 12 twaalfde verdieping | 21.21 buitenwanden - constructief, massieve wanden (Uniformat) | Model Group:NLRS_28.21_WA_3D element 001 d=300_gen:4738418
Basic Wall:NLRS_21.21_WA_beton prefab d=300/320_gen:4738652 | 14 veertiende verdieping | 21.21 buitenwanden - constructief, massieve wanden (Uniformat) | Model Group:NLRS_21.21_WA_wand 003 d=300_gen:4738703
Basic Wall:NLRS_21.21_WA_beton prefab d=300/320_gen:4738654 | 14 veertiende verdieping | 21.21 buitenwanden - constructief, massieve wanden (Uniformat) | Model Group:NLRS_21.21_WA_wand 001 d=300_gen:4738702
Basic Wall:NLRS_21.21_WA_beton prefab d=300/320_gen:4738704 | 14 veertiende verdieping | 21.21 buitenwanden - constructief, massieve wanden (Uniformat) | Model Group:NLRS_21.21_WA_wand 003 d=300_gen:4738707
Basic Wall:NLRS_21.21_WA_beton prefab d=300/320_gen:4738708 | 14 veertiende verdieping | 21.21 buitenwanden - constructief, massieve wanden (Uniformat) | Model Group:NLRS_21.21_WA_wand 001 d=300_gen:4738711
Basic Wall:NLRS_21.21_WA_beton prefab d=300/320_gen:4738860 | 14 veertiende verdieping | 21.21 buitenwanden - constructief, massieve wanden (Uniformat) | Model Group:NLRS_28.21_WA_3D element 002 d=300_gen:4738875
Basic Wall:NLRS_21.21_WA_beton prefab d=300/320_gen:4738862 | 14 veertiende verdieping | 21.21 buitenwanden - constructief, massieve wanden (Uniformat) | Model Group:NLRS_28.21_WA_3D element 002 d=300_gen:4738875
Basic Wall:NLRS_21.21_WA_beton prefab d=300/320_gen:4738959 | 14 veertiende verdieping | 21.21 buitenwanden - constructief, massieve wanden (Uniformat) | Model Group:NLRS_28.21_WA_3D element 002 d=300_gen:4738859
Basic Wall:NLRS_21.21_WA_beton prefab d=300/320_gen:4738961 | 14 veertiende verdieping | 21.21 buitenwanden - constructief, massieve wanden (Uniformat) | Model Group:NLRS_28.21_WA_3D element 002 d=300_gen:4738859
Basic Wall:NLRS_21.21_WA_beton prefab d=300/320_gen:4739003 | 14 veertiende verdieping | 21.21 buitenwanden - constructief, massieve wanden (Uniformat) | Model Group:NLRS_28.21_WA_3D element 001 d=300_gen:4738858
Basic Wall:NLRS_21.21_WA_beton prefab d=300/320_gen:4739006 | 14 veertiende verdieping | 21.21 buitenwanden - constructief, massieve wanden (Uniformat) | Model Group:NLRS_28.21_WA_3D element 001 d=300_gen:4738858
Basic Wall:NLRS_21.21_WA_beton prefab d=300/320_gen:4739032 | 14 veertiende verdieping | 21.21 buitenwanden - constructief, massieve wanden (Uniformat) | Model Group:NLRS_28.21_WA_3D element 001 d=300_gen:4738876
Basic Wall:NLRS_21.21_WA_beton prefab d=300/320_gen:4739035 | 14 veertiende verdieping | 21.21 buitenwanden - constructief, massieve wanden (Uniformat) | Model Group:NLRS_28.21_WA_3D element 001 d=300_gen:4738876
Basic Wall:NLRS_21.21_WA_beton prefab d=300/320_gen:4739110 | 16 zestiende verdieping | 21.21 buitenwanden - constructief, massieve wanden (Uniformat) | Model Group:NLRS_21.21_WA_wand 003 d=300_gen:4739161
Basic Wall:NLRS_21.21_WA_beton prefab d=300/320_gen:4739112 | 16 zestiende verdieping | 21.21 buitenwanden - constructief, massieve wanden (Uniformat) | Model Group:NLRS_21.21_WA_wand 001 d=300_gen:4739160
Basic Wall:NLRS_21.21_WA_beton prefab d=300/320_gen:4739162 | 16 zestiende verdieping | 21.21 buitenwanden - constructief, massieve wanden (Uniformat) | Model Group:NLRS_21.21_WA_wand 003 d=300_gen:4739165
Basic Wall:NLRS_21.21_WA_beton prefab d=300/320_gen:4739166 | 16 zestiende verdieping | 21.21 buitenwanden - constructief, massieve wanden (Uniformat) | Model Group:NLRS_21.21_WA_wand 001 d=300_gen:4739169
3 x Basic Wall:NLRS_21.21_WA_beton prefab d=300/320_gen:4739181 | 16 zestiende verdieping | 21.21 buitenwanden - constructief, massieve wanden (Uniformat) | Model Group:NLRS_21.21_WA_wand 002 d=300_gen:4739159
2 x Basic Wall:NLRS_21.21_WA_beton prefab d=300/320_gen:5365657 | 16 zestiende verdieping | 21.21 buitenwanden - constructief, massieve wanden (Uniformat) | Model Group:NLRS_21.21_WA_wand 002 d=300_gen:4739159
3 x Basic Wall:NLRS_21.21_WA_beton prefab d=300/320_gen:4739183 | 16 zestiende verdieping | 21.21 buitenwanden - constructief, massieve wanden (Uniformat) | Model Group:NLRS_21.21_WA_wand 002 d=300_gen:4739152
2 x Basic Wall:NLRS_21.21_WA_beton prefab d=300/320_gen:5365657 | 16 zestiende verdieping | 21.21 buitenwanden - constructief, massieve wanden (Uniformat) | Model Group:NLRS_21.21_WA_wand 002 d=300_gen:4739152
3 x Basic Wall:NLRS_21.21_WA_beton prefab d=300/320_gen:4739207 | 16 zestiende verdieping | 21.21 buitenwanden - constructief, massieve wanden (Uniformat) | Model Group:NLRS_21.21_WA_wand 004 d=300_gen:4739151
2 x Basic Wall:NLRS_21.21_WA_beton prefab d=300/320_gen:5365657 | 16 zestiende verdieping | 21.21 buitenwanden - constructief, massieve wanden (Uniformat) | Model Group:NLRS_21.21_WA_wand 004 d=300_gen:4739151
3 x Basic Wall:NLRS_21.21_WA_beton prefab d=300/320_gen:4739209 | 16 zestiende verdieping | 21.21 buitenwanden - constructief, massieve wanden (Uniformat) | Model Group:NLRS_21.21_WA_wand 004 d=300_gen:4739142
2 x Basic Wall:NLRS_21.21_WA_beton prefab d=300/320_gen:5365657 | 16 zestiende verdieping | 21.21 buitenwanden - constructief, massieve wanden (Uniformat) | Model Group:NLRS_21.21_WA_wand 004 d=300_gen:4739142
Basic Wall:NLRS_21.21_WA_beton prefab d=300/320_gen:4739318 | 16 zestiende verdieping | 21.21 buitenwanden - constructief, massieve wanden (Uniformat) | Model Group:NLRS_28.21_WA_3D element 002 d=300_gen:4739333
Basic Wall:NLRS_21.21_WA_beton prefab d=300/320_gen:4739320 | 16 zestiende verdieping | 21.21 buitenwanden - constructief, massieve wanden (Uniformat) | Model Group:NLRS_28.21_WA_3D element 002 d=300_gen:4739333
Basic Wall:NLRS_21.21_WA_beton prefab d=300/320_gen:4739417 | 16 zestiende verdieping | 21.21 buitenwanden - constructief, massieve wanden (Uniformat) | Model Group:NLRS_28.21_WA_3D element 002 d=300_gen:4739317
Basic Wall:NLRS_21.21_WA_beton prefab d=300/320_gen:4739419 | 16 zestiende verdieping | 21.21 buitenwanden - constructief, massieve wanden (Uniformat) | Model Group:NLRS_28.21_WA_3D element 002 d=300_gen:4739317
Basic Wall:NLRS_21.21_WA_beton prefab d=300/320_gen:4739461 | 16 zestiende verdieping | 21.21 buitenwanden - constructief, massieve wanden (Uniformat) | Model Group:NLRS_28.21_WA_3D element 001 d=300_gen:4739316
Basic Wall:NLRS_21.21_WA_beton prefab d=300/320_gen:4739464 | 16 zestiende verdieping | 21.21 buitenwanden - constructief, massieve wanden (Uniformat) | Model Group:NLRS_28.21_WA_3D element 001 d=300_gen:4739316
Basic Wall:NLRS_21.21_WA_beton prefab d=300/320_gen:4739490 | 16 zestiende verdieping | 21.21 buitenwanden - constructief, massieve wanden (Uniformat) | Model Group:NLRS_28.21_WA_3D element 001 d=300_gen:4739334
Basic Wall:NLRS_21.21_WA_beton prefab d=300/320_gen:4739493 | 16 zestiende verdieping | 21.21 buitenwanden - constructief, massieve wanden (Uniformat) | Model Group:NLRS_28.21_WA_3D element 001 d=300_gen:4739334
Basic Wall:NLRS_21.21_WA_beton prefab d=300/320_gen:4739568 | 18 achttiende verdieping | 21.21 buitenwanden - constructief, massieve wanden (Uniformat) | Model Group:NLRS_21.21_WA_wand 003 d=300_gen:4739619
Basic Wall:NLRS_21.21_WA_beton prefab d=300/320_gen:4739570 | 18 achttiende verdieping | 21.21 buitenwanden - constructief, massieve wanden (Uniformat) | Model Group:NLRS_21.21_WA_wand 001 d=300_gen:4739618
Basic Wall:NLRS_21.21_WA_beton prefab d=300/320_gen:4739620 | 18 achttiende verdieping | 21.21 buitenwanden - constructief, massieve wanden (Uniformat) | Model Group:NLRS_21.21_WA_wand 003 d=300_gen:4739623
Basic Wall:NLRS_21.21_WA_beton prefab d=300/320_gen:4739624 | 18 achttiende verdieping | 21.21 buitenwanden - constructief, massieve wanden (Uniformat) | Model Group:NLRS_21.21_WA_wand 001 d=300_gen:4739627
3 x Basic Wall:NLRS_21.21_WA_beton prefab d=300/320_gen:4739639 | 18 achttiende verdieping | 21.21 buitenwanden - constructief, massieve wanden (Uniformat) | Model Group:NLRS_21.21_WA_wand 002 d=300_gen:4739617
2 x Basic Wall:NLRS_21.21_WA_beton prefab d=300/320_gen:5365657 | 18 achttiende verdieping | 21.21 buitenwanden - constructief, massieve wanden (Uniformat) | Model Group:NLRS_21.21_WA_wand 002 d=300_gen:4739617
3 x Basic Wall:NLRS_21.21_WA_beton prefab d=300/320_gen:4739641 | 18 achttiende verdieping | 21.21 buitenwanden - constructief, massieve wanden (Uniformat) | Model Group:NLRS_21.21_WA_wand 002 d=300_gen:4739610
2 x Basic Wall:NLRS_21.21_WA_beton prefab d=300/320_gen:5365657 | 18 achttiende verdieping | 21.21 buitenwanden - constructief, massieve wanden (Uniformat) | Model Group:NLRS_21.21_WA_wand 002 d=300_gen:4739610
3 x Basic Wall:NLRS_21.21_WA_beton prefab d=300/320_gen:4739665 | 18 achttiende verdieping | 21.21 buitenwanden - constructief, massieve wanden (Uniformat) | Model Group:NLRS_21.21_WA_wand 004 d=300_gen:4739609
2 x Basic Wall:NLRS_21.21_WA_beton prefab d=300/320_gen:5365657 | 18 achttiende verdieping | 21.21 buitenwanden - constructief, massieve wanden (Uniformat) | Model Group:NLRS_21.21_WA_wand 004 d=300_gen:4739609
3 x Basic Wall:NLRS_21.21_WA_beton prefab d=300/320_gen:4739667 | 18 achttiende verdieping | 21.21 buitenwanden - constructief, massieve wanden (Uniformat) | Model Group:NLRS_21.21_WA_wand 004 d=300_gen:4739600
2 x Basic Wall:NLRS_21.21_WA_beton prefab d=300/320_gen:5365657 | 18 achttiende verdieping | 21.21 buitenwanden - constructief, massieve wanden (Uniformat) | Model Group:NLRS_21.21_WA_wand 004 d=300_gen:4739600
Basic Wall:NLRS_21.21_WA_beton prefab d=300/320_gen:4739776 | 18 achttiende verdieping | 21.21 buitenwanden - constructief, massieve wanden (Uniformat) | Model Group:NLRS_28.21_WA_3D element 002 d=300_gen:4739791
Basic Wall:NLRS_21.21_WA_beton prefab d=300/320_gen:4739778 | 18 achttiende verdieping | 21.21 buitenwanden - constructief, massieve wanden (Uniformat) | Model Group:NLRS_28.21_WA_3D element 002 d=300_gen:4739791
Basic Wall:NLRS_21.21_WA_beton prefab d=300/320_gen:4739875 | 18 achttiende verdieping | 21.21 buitenwanden - constructief, massieve wanden (Uniformat) | Model Group:NLRS_28.21_WA_3D element 002 d=300_gen:4739775
Basic Wall:NLRS_21.21_WA_beton prefab d=300/320_gen:4739877 | 18 achttiende verdieping | 21.21 buitenwanden - constructief, massieve wanden (Uniformat) | Model Group:NLRS_28.21_WA_3D element 002 d=300_gen:4739775
Basic Wall:NLRS_21.21_WA_beton prefab d=300/320_gen:4739919 | 18 achttiende verdieping | 21.21 buitenwanden - constructief, massieve wanden (Uniformat) | Model Group:NLRS_28.21_WA_3D element 001 d=300_gen:4739774
Basic Wall:NLRS_21.21_WA_beton prefab d=300/320_gen:4739922 | 18 achttiende verdieping | 21.21 buitenwanden - constructief, massieve wanden (Uniformat) | Model Group:NLRS_28.21_WA_3D element 001 d=300_gen:4739774
Basic Wall:NLRS_21.21_WA_beton prefab d=300/320_gen:4739948 | 18 achttiende verdieping | 21.21 buitenwanden - constructief, massieve wanden (Uniformat) | Model Group:NLRS_28.21_WA_3D element 001 d=300_gen:4739792
Basic Wall:NLRS_21.21_WA_beton prefab d=300/320_gen:4739951 | 18 achttiende verdieping | 21.21 buitenwanden - constructief, massieve wanden (Uniformat) | Model Group:NLRS_28.21_WA_3D element 001 d=300_gen:4739792
Basic Wall:NLRS_21.21_WA_beton prefab d=300/320_gen:4740026 | 20 twintigste verdieping | 21.21 buitenwanden - constructief, massieve wanden (Uniformat) | Model Group:NLRS_21.21_WA_wand 003 d=300_gen:4740077
Basic Wall:NLRS_21.21_WA_beton prefab d=300/320_gen:4740028 | 20 twintigste verdieping | 21.21 buitenwanden - constructief, massieve wanden (Uniformat) | Model Group:NLRS_21.21_WA_wand 001 d=300_gen:4740076
Basic Wall:NLRS_21.21_WA_beton prefab d=300/320_gen:4740078 | 20 twintigste verdieping | 21.21 buitenwanden - constructief, massieve wanden (Uniformat) | Model Group:NLRS_21.21_WA_wand 003 d=300_gen:4740081
Basic Wall:NLRS_21.21_WA_beton prefab d=300/320_gen:4740082 | 20 twintigste verdieping | 21.21 buitenwanden - constructief, massieve wanden (Uniformat) | Model Group:NLRS_21.21_WA_wand 001 d=300_gen:4740085
3 x Basic Wall:NLRS_21.21_WA_beton prefab d=300/320_gen:4740097 | 20 twintigste verdieping | 21.21 buitenwanden - constructief, massieve wanden (Uniformat) | Model Group:NLRS_21.21_WA_wand 002 d=300_gen:4740075
2 x Basic Wall:NLRS_21.21_WA_beton prefab d=300/320_gen:5365657 | 20 twintigste verdieping | 21.21 buitenwanden - constructief, massieve wanden (Uniformat) | Model Group:NLRS_21.21_WA_wand 002 d=300_gen:4740075
3 x Basic Wall:NLRS_21.21_WA_beton prefab d=300/320_gen:4740099 | 20 twintigste verdieping | 21.21 buitenwanden - constructief, massieve wanden (Uniformat) | Model Group:NLRS_21.21_WA_wand 002 d=300_gen:4740068
2 x Basic Wall:NLRS_21.21_WA_beton prefab d=300/320_gen:5365657 | 20 twintigste verdieping | 21.21 buitenwanden - constructief, massieve wanden (Uniformat) | Model Group:NLRS_21.21_WA_wand 002 d=300_gen:4740068
3 x Basic Wall:NLRS_21.21_WA_beton prefab d=300/320_gen:4740123 | 20 twintigste verdieping | 21.21 buitenwanden - constructief, massieve wanden (Uniformat) | Model Group:NLRS_21.21_WA_wand 004 d=300_gen:4740067
2 x Basic Wall:NLRS_21.21_WA_beton prefab d=300/320_gen:5365657 | 20 twintigste verdieping | 21.21 buitenwanden - constructief, massieve wanden (Uniformat) | Model Group:NLRS_21.21_WA_wand 004 d=300_gen:4740067
3 x Basic Wall:NLRS_21.21_WA_beton prefab d=300/320_gen:4740125 | 20 twintigste verdieping | 21.21 buitenwanden - constructief, massieve wanden (Uniformat) | Model Group:NLRS_21.21_WA_wand 004 d=300_gen:4740058
2 x Basic Wall:NLRS_21.21_WA_beton prefab d=300/320_gen:5365657 | 20 twintigste verdieping | 21.21 buitenwanden - constructief, massieve wanden (Uniformat) | Model Group:NLRS_21.21_WA_wand 004 d=300_gen:4740058
Basic Wall:NLRS_21.21_WA_beton prefab d=300/320_gen:4740234 | 20 twintigste verdieping | 21.21 buitenwanden - constructief, massieve wanden (Uniformat) | Model Group:NLRS_28.21_WA_3D element 002 d=300_gen:4740249
Basic Wall:NLRS_21.21_WA_beton prefab d=300/320_gen:4740236 | 20 twintigste verdieping | 21.21 buitenwanden - constructief, massieve wanden (Uniformat) | Model Group:NLRS_28.21_WA_3D element 002 d=300_gen:4740249
Basic Wall:NLRS_21.21_WA_beton prefab d=300/320_gen:4740333 | 20 twintigste verdieping | 21.21 buitenwanden - constructief, massieve wanden (Uniformat) | Model Group:NLRS_28.21_WA_3D element 002 d=300_gen:4740233
Basic Wall:NLRS_21.21_WA_beton prefab d=300/320_gen:4740335 | 20 twintigste verdieping | 21.21 buitenwanden - constructief, massieve wanden (Uniformat) | Model Group:NLRS_28.21_WA_3D element 002 d=300_gen:4740233
Basic Wall:NLRS_21.21_WA_beton prefab d=300/320_gen:4740377 | 20 twintigste verdieping | 21.21 buitenwanden - constructief, massieve wanden (Uniformat) | Model Group:NLRS_28.21_WA_3D element 001 d=300_gen:4740232
Basic Wall:NLRS_21.21_WA_beton prefab d=300/320_gen:4740380 | 20 twintigste verdieping | 21.21 buitenwanden - constructief, massieve wanden (Uniformat) | Model Group:NLRS_28.21_WA_3D element 001 d=300_gen:4740232
Basic Wall:NLRS_21.21_WA_beton prefab d=300/320_gen:4740406 | 20 twintigste verdieping | 21.21 buitenwanden - constructief, massieve wanden (Uniformat) | Model Group:NLRS_28.21_WA_3D element 001 d=300_gen:4740250
Basic Wall:NLRS_21.21_WA_beton prefab d=300/320_gen:4740409 | 20 twintigste verdieping | 21.21 buitenwanden - constructief, massieve wanden (Uniformat) | Model Group:NLRS_28.21_WA_3D element 001 d=300_gen:4740250
Basic Wall:NLRS_21.21_WA_beton prefab d=300/320_gen:4746627 | 24 vierentwintigste verdieping | 21.21 buitenwanden - constructief, massieve wanden (Uniformat) | Model Group:NLRS_21.21_WA_wand 003 d=300_gen:4746676
Basic Wall:NLRS_21.21_WA_beton prefab d=300/320_gen:4746629 | 24 vierentwintigste verdieping | 21.21 buitenwanden - constructief, massieve wanden (Uniformat) | Model Group:NLRS_21.21_WA_wand 001 d=300_gen:4746675
Basic Wall:NLRS_21.21_WA_beton prefab d=300/320_gen:4746677 | 24 vierentwintigste verdieping | 21.21 buitenwanden - constructief, massieve wanden (Uniformat) | Model Group:NLRS_21.21_WA_wand 003 d=300_gen:4746680
Basic Wall:NLRS_21.21_WA_beton prefab d=300/320_gen:4746681 | 24 vierentwintigste verdieping | 21.21 buitenwanden - constructief, massieve wanden (Uniformat) | Model Group:NLRS_21.21_WA_wand 001 d=300_gen:4746684
3 x Basic Wall:NLRS_21.21_WA_beton prefab d=300/320_gen:4746696 | 24 vierentwintigste verdieping | 21.21 buitenwanden - constructief, massieve wanden (Uniformat) | Model Group:NLRS_21.21_WA_wand 002 d=300_gen:4746674
2 x Basic Wall:NLRS_21.21_WA_beton prefab d=300/320_gen:5365657 | 24 vierentwintigste verdieping | 21.21 buitenwanden - constructief, massieve wanden (Uniformat) | Model Group:NLRS_21.21_WA_wand 002 d=300_gen:4746674
3 x Basic Wall:NLRS_21.21_WA_beton prefab d=300/320_gen:4746698 | 24 vierentwintigste verdieping | 21.21 buitenwanden - constructief, massieve wanden (Uniformat) | Model Group:NLRS_21.21_WA_wand 002 d=300_gen:4746667
2 x Basic Wall:NLRS_21.21_WA_beton prefab d=300/320_gen:5365657 | 24 vierentwintigste verdieping | 21.21 buitenwanden - constructief, massieve wanden (Uniformat) | Model Group:NLRS_21.21_WA_wand 002 d=300_gen:4746667
3 x Basic Wall:NLRS_21.21_WA_beton prefab d=300/320_gen:4746722 | 24 vierentwintigste verdieping | 21.21 buitenwanden - constructief, massieve wanden (Uniformat) | Model Group:NLRS_21.21_WA_wand 004 d=300_gen:4746666
2 x Basic Wall:NLRS_21.21_WA_beton prefab d=300/320_gen:5365657 | 24 vierentwintigste verdieping | 21.21 buitenwanden - constructief, massieve wanden (Uniformat) | Model Group:NLRS_21.21_WA_wand 004 d=300_gen:4746666
3 x Basic Wall:NLRS_21.21_WA_beton prefab d=300/320_gen:4746724 | 24 vierentwintigste verdieping | 21.21 buitenwanden - constructief, massieve wanden (Uniformat) | Model Group:NLRS_21.21_WA_wand 004 d=300_gen:4746657
2 x Basic Wall:NLRS_21.21_WA_beton prefab d=300/320_gen:5365657 | 24 vierentwintigste verdieping | 21.21 buitenwanden - constructief, massieve wanden (Uniformat) | Model Group:NLRS_21.21_WA_wand 004 d=300_gen:4746657
Basic Wall:NLRS_21.21_WA_beton prefab d=300/320_gen:4746831 | 24 vierentwintigste verdieping | 21.21 buitenwanden - constructief, massieve wanden (Uniformat) | Model Group:NLRS_28.21_WA_3D element 002 d=300_gen:4746846
Basic Wall:NLRS_21.21_WA_beton prefab d=300/320_gen:4746833 | 24 vierentwintigste verdieping | 21.21 buitenwanden - constructief, massieve wanden (Uniformat) | Model Group:NLRS_28.21_WA_3D element 002 d=300_gen:4746846
Basic Wall:NLRS_21.21_WA_beton prefab d=300/320_gen:4746912 | 24 vierentwintigste verdieping | 21.21 buitenwanden - constructief, massieve wanden (Uniformat) | Model Group:NLRS_28.21_WA_3D element 002 d=300_gen:4746830
Basic Wall:NLRS_21.21_WA_beton prefab d=300/320_gen:4746914 | 24 vierentwintigste verdieping | 21.21 buitenwanden - constructief, massieve wanden (Uniformat) | Model Group:NLRS_28.21_WA_3D element 002 d=300_gen:4746830
Basic Wall:NLRS_21.21_WA_beton prefab d=300/320_gen:4746956 | 24 vierentwintigste verdieping | 21.21 buitenwanden - constructief, massieve wanden (Uniformat) | Model Group:NLRS_28.21_WA_3D element 001 d=300_gen:4746829
Basic Wall:NLRS_21.21_WA_beton prefab d=300/320_gen:4746959 | 24 vierentwintigste verdieping | 21.21 buitenwanden - constructief, massieve wanden (Uniformat) | Model Group:NLRS_28.21_WA_3D element 001 d=300_gen:4746829
Basic Wall:NLRS_21.21_WA_beton prefab d=300/320_gen:4746985 | 24 vierentwintigste verdieping | 21.21 buitenwanden - constructief, massieve wanden (Uniformat) | Model Group:NLRS_28.21_WA_3D element 001 d=300_gen:4746847
Basic Wall:NLRS_21.21_WA_beton prefab d=300/320_gen:4746988 | 24 vierentwintigste verdieping | 21.21 buitenwanden - constructief, massieve wanden (Uniformat) | Model Group:NLRS_28.21_WA_3D element 001 d=300_gen:4746847
Basic Wall:NLRS_21.21_WA_beton prefab d=300/320_gen:4747059 | 25 vijfentwintigste verdieping | 21.21 buitenwanden - constructief, massieve wanden (Uniformat) | Model Group:NLRS_21.21_WA_wand 003 d=300_gen:4747108
Basic Wall:NLRS_21.21_WA_beton prefab d=300/320_gen:4747061 | 25 vijfentwintigste verdieping | 21.21 buitenwanden - constructief, massieve wanden (Uniformat) | Model Group:NLRS_21.21_WA_wand 001 d=300_gen:4747107
Basic Wall:NLRS_21.21_WA_beton prefab d=300/320_gen:4747109 | 25 vijfentwintigste verdieping | 21.21 buitenwanden - constructief, massieve wanden (Uniformat) | Model Group:NLRS_21.21_WA_wand 003 d=300_gen:4747112
Basic Wall:NLRS_21.21_WA_beton prefab d=300/320_gen:4747113 | 25 vijfentwintigste verdieping | 21.21 buitenwanden - constructief, massieve wanden (Uniformat) | Model Group:NLRS_21.21_WA_wand 001 d=300_gen:4747116
3 x Basic Wall:NLRS_21.21_WA_beton prefab d=300/320_gen:4747128 | 25 vijfentwintigste verdieping | 21.21 buitenwanden - constructief, massieve wanden (Uniformat) | Model Group:NLRS_21.21_WA_wand 002 d=300_gen:4747106
2 x Basic Wall:NLRS_21.21_WA_beton prefab d=300/320_gen:5365657 | 25 vijfentwintigste verdieping | 21.21 buitenwanden - constructief, massieve wanden (Uniformat) | Model Group:NLRS_21.21_WA_wand 002 d=300_gen:4747106
3 x Basic Wall:NLRS_21.21_WA_beton prefab d=300/320_gen:4747130 | 25 vijfentwintigste verdieping | 21.21 buitenwanden - constructief, massieve wanden (Uniformat) | Model Group:NLRS_21.21_WA_wand 002 d=300_gen:4747099
2 x Basic Wall:NLRS_21.21_WA_beton prefab d=300/320_gen:5365657 | 25 vijfentwintigste verdieping | 21.21 buitenwanden - constructief, massieve wanden (Uniformat) | Model Group:NLRS_21.21_WA_wand 002 d=300_gen:4747099
3 x Basic Wall:NLRS_21.21_WA_beton prefab d=300/320_gen:4747154 | 25 vijfentwintigste verdieping | 21.21 buitenwanden - constructief, massieve wanden (Uniformat) | Model Group:NLRS_21.21_WA_wand 004 d=300_gen:4747098
2 x Basic Wall:NLRS_21.21_WA_beton prefab d=300/320_gen:5365657 | 25 vijfentwintigste verdieping | 21.21 buitenwanden - constructief, massieve wanden (Uniformat) | Model Group:NLRS_21.21_WA_wand 004 d=300_gen:4747098
3 x Basic Wall:NLRS_21.21_WA_beton prefab d=300/320_gen:4747156 | 25 vijfentwintigste verdieping | 21.21 buitenwanden - constructief, massieve wanden (Uniformat) | Model Group:NLRS_21.21_WA_wand 004 d=300_gen:4747089
2 x Basic Wall:NLRS_21.21_WA_beton prefab d=300/320_gen:5365657 | 25 vijfentwintigste verdieping | 21.21 buitenwanden - constructief, massieve wanden (Uniformat) | Model Group:NLRS_21.21_WA_wand 004 d=300_gen:4747089
Basic Wall:NLRS_21.21_WA_beton prefab d=300/320_gen:4747263 | 25 vijfentwintigste verdieping | 21.21 buitenwanden - constructief, massieve wanden (Uniformat) | Model Group:NLRS_28.21_WA_3D element 002 d=300_gen:4747278
Basic Wall:NLRS_21.21_WA_beton prefab d=300/320_gen:4747265 | 25 vijfentwintigste verdieping | 21.21 buitenwanden - constructief, massieve wanden (Uniformat) | Model Group:NLRS_28.21_WA_3D element 002 d=300_gen:4747278
Basic Wall:NLRS_21.21_WA_beton prefab d=300/320_gen:4747344 | 25 vijfentwintigste verdieping | 21.21 buitenwanden - constructief, massieve wanden (Uniformat) | Model Group:NLRS_28.21_WA_3D element 002 d=300_gen:4747262
Basic Wall:NLRS_21.21_WA_beton prefab d=300/320_gen:4747346 | 25 vijfentwintigste verdieping | 21.21 buitenwanden - constructief, massieve wanden (Uniformat) | Model Group:NLRS_28.21_WA_3D element 002 d=300_gen:4747262
Basic Wall:NLRS_21.21_WA_beton prefab d=300/320_gen:4747388 | 25 vijfentwintigste verdieping | 21.21 buitenwanden - constructief, massieve wanden (Uniformat) | Model Group:NLRS_28.21_WA_3D element 001 d=300_gen:4747261
Basic Wall:NLRS_21.21_WA_beton prefab d=300/320_gen:4747391 | 25 vijfentwintigste verdieping | 21.21 buitenwanden - constructief, massieve wanden (Uniformat) | Model Group:NLRS_28.21_WA_3D element 001 d=300_gen:4747261
Basic Wall:NLRS_21.21_WA_beton prefab d=300/320_gen:4747417 | 25 vijfentwintigste verdieping | 21.21 buitenwanden - constructief, massieve wanden (Uniformat) | Model Group:NLRS_28.21_WA_3D element 001 d=300_gen:4747279
Basic Wall:NLRS_21.21_WA_beton prefab d=300/320_gen:4747420 | 25 vijfentwintigste verdieping | 21.21 buitenwanden - constructief, massieve wanden (Uniformat) | Model Group:NLRS_28.21_WA_3D element 001 d=300_gen:4747279
Basic Wall:NLRS_21.21_WA_beton prefab d=300/320_gen:4747491 | 26 zesentwintigste verdieping | 21.21 buitenwanden - constructief, massieve wanden (Uniformat) | Model Group:NLRS_21.21_WA_wand 003 d=300_gen:4747540
Basic Wall:NLRS_21.21_WA_beton prefab d=300/320_gen:4747493 | 26 zesentwintigste verdieping | 21.21 buitenwanden - constructief, massieve wanden (Uniformat) | Model Group:NLRS_21.21_WA_wand 001 d=300_gen:4747539
Basic Wall:NLRS_21.21_WA_beton prefab d=300/320_gen:4747541 | 26 zesentwintigste verdieping | 21.21 buitenwanden - constructief, massieve wanden (Uniformat) | Model Group:NLRS_21.21_WA_wand 003 d=300_gen:4747544
Basic Wall:NLRS_21.21_WA_beton prefab d=300/320_gen:4747545 | 26 zesentwintigste verdieping | 21.21 buitenwanden - constructief, massieve wanden (Uniformat) | Model Group:NLRS_21.21_WA_wand 001 d=300_gen:4747548
3 x Basic Wall:NLRS_21.21_WA_beton prefab d=300/320_gen:4747560 | 26 zesentwintigste verdieping | 21.21 buitenwanden - constructief, massieve wanden (Uniformat) | Model Group:NLRS_21.21_WA_wand 002 d=300_gen:4747538
2 x Basic Wall:NLRS_21.21_WA_beton prefab d=300/320_gen:5365657 | 26 zesentwintigste verdieping | 21.21 buitenwanden - constructief, massieve wanden (Uniformat) | Model Group:NLRS_21.21_WA_wand 002 d=300_gen:4747538
3 x Basic Wall:NLRS_21.21_WA_beton prefab d=300/320_gen:4747562 | 26 zesentwintigste verdieping | 21.21 buitenwanden - constructief, massieve wanden (Uniformat) | Model Group:NLRS_21.21_WA_wand 002 d=300_gen:4747531
2 x Basic Wall:NLRS_21.21_WA_beton prefab d=300/320_gen:5365657 | 26 zesentwintigste verdieping | 21.21 buitenwanden - constructief, massieve wanden (Uniformat) | Model Group:NLRS_21.21_WA_wand 002 d=300_gen:4747531
3 x Basic Wall:NLRS_21.21_WA_beton prefab d=300/320_gen:4747586 | 26 zesentwintigste verdieping | 21.21 buitenwanden - constructief, massieve wanden (Uniformat) | Model Group:NLRS_21.21_WA_wand 004 d=300_gen:4747530
2 x Basic Wall:NLRS_21.21_WA_beton prefab d=300/320_gen:5365657 | 26 zesentwintigste verdieping | 21.21 buitenwanden - constructief, massieve wanden (Uniformat) | Model Group:NLRS_21.21_WA_wand 004 d=300_gen:4747530
3 x Basic Wall:NLRS_21.21_WA_beton prefab d=300/320_gen:4747588 | 26 zesentwintigste verdieping | 21.21 buitenwanden - constructief, massieve wanden (Uniformat) | Model Group:NLRS_21.21_WA_wand 004 d=300_gen:4747521
2 x Basic Wall:NLRS_21.21_WA_beton prefab d=300/320_gen:5365657 | 26 zesentwintigste verdieping | 21.21 buitenwanden - constructief, massieve wanden (Uniformat) | Model Group:NLRS_21.21_WA_wand 004 d=300_gen:4747521
Basic Wall:NLRS_21.21_WA_beton prefab d=300/320_gen:4747695 | 26 zesentwintigste verdieping | 21.21 buitenwanden - constructief, massieve wanden (Uniformat) | Model Group:NLRS_28.21_WA_3D element 002 d=300_gen:4747710
Basic Wall:NLRS_21.21_WA_beton prefab d=300/320_gen:4747697 | 26 zesentwintigste verdieping | 21.21 buitenwanden - constructief, massieve wanden (Uniformat) | Model Group:NLRS_28.21_WA_3D element 002 d=300_gen:4747710
Basic Wall:NLRS_21.21_WA_beton prefab d=300/320_gen:4747776 | 26 zesentwintigste verdieping | 21.21 buitenwanden - constructief, massieve wanden (Uniformat) | Model Group:NLRS_28.21_WA_3D element 002 d=300_gen:4747694
Basic Wall:NLRS_21.21_WA_beton prefab d=300/320_gen:4747778 | 26 zesentwintigste verdieping | 21.21 buitenwanden - constructief, massieve wanden (Uniformat) | Model Group:NLRS_28.21_WA_3D element 002 d=300_gen:4747694
Basic Wall:NLRS_21.21_WA_beton prefab d=300/320_gen:4747820 | 26 zesentwintigste verdieping | 21.21 buitenwanden - constructief, massieve wanden (Uniformat) | Model Group:NLRS_28.21_WA_3D element 001 d=300_gen:4747693
Basic Wall:NLRS_21.21_WA_beton prefab d=300/320_gen:4747823 | 26 zesentwintigste verdieping | 21.21 buitenwanden - constructief, massieve wanden (Uniformat) | Model Group:NLRS_28.21_WA_3D element 001 d=300_gen:4747693
Basic Wall:NLRS_21.21_WA_beton prefab d=300/320_gen:4747849 | 26 zesentwintigste verdieping | 21.21 buitenwanden - constructief, massieve wanden (Uniformat) | Model Group:NLRS_28.21_WA_3D element 001 d=300_gen:4747711
Basic Wall:NLRS_21.21_WA_beton prefab d=300/320_gen:4747852 | 26 zesentwintigste verdieping | 21.21 buitenwanden - constructief, massieve wanden (Uniformat) | Model Group:NLRS_28.21_WA_3D element 001 d=300_gen:4747711
Basic Wall:NLRS_21.21_WA_beton prefab d=300/320_gen:4747923 | 27 zevenentwintigste verdieping | 21.21 buitenwanden - constructief, massieve wanden (Uniformat) | Model Group:NLRS_21.21_WA_wand 003 d=300_gen:4747972
Basic Wall:NLRS_21.21_WA_beton prefab d=300/320_gen:4747925 | 27 zevenentwintigste verdieping | 21.21 buitenwanden - constructief, massieve wanden (Uniformat) | Model Group:NLRS_21.21_WA_wand 001 d=300_gen:4747971
Basic Wall:NLRS_21.21_WA_beton prefab d=300/320_gen:4747973 | 27 zevenentwintigste verdieping | 21.21 buitenwanden - constructief, massieve wanden (Uniformat) | Model Group:NLRS_21.21_WA_wand 003 d=300_gen:4747976
Basic Wall:NLRS_21.21_WA_beton prefab d=300/320_gen:4747977 | 27 zevenentwintigste verdieping | 21.21 buitenwanden - constructief, massieve wanden (Uniformat) | Model Group:NLRS_21.21_WA_wand 001 d=300_gen:4747980
3 x Basic Wall:NLRS_21.21_WA_beton prefab d=300/320_gen:4747992 | 27 zevenentwintigste verdieping | 21.21 buitenwanden - constructief, massieve wanden (Uniformat) | Model Group:NLRS_21.21_WA_wand 002 d=300_gen:4747970
2 x Basic Wall:NLRS_21.21_WA_beton prefab d=300/320_gen:5365657 | 27 zevenentwintigste verdieping | 21.21 buitenwanden - constructief, massieve wanden (Uniformat) | Model Group:NLRS_21.21_WA_wand 002 d=300_gen:4747970
3 x Basic Wall:NLRS_21.21_WA_beton prefab d=300/320_gen:4747994 | 27 zevenentwintigste verdieping | 21.21 buitenwanden - constructief, massieve wanden (Uniformat) | Model Group:NLRS_21.21_WA_wand 002 d=300_gen:4747963
2 x Basic Wall:NLRS_21.21_WA_beton prefab d=300/320_gen:5365657 | 27 zevenentwintigste verdieping | 21.21 buitenwanden - constructief, massieve wanden (Uniformat) | Model Group:NLRS_21.21_WA_wand 002 d=300_gen:4747963
3 x Basic Wall:NLRS_21.21_WA_beton prefab d=300/320_gen:4748018 | 27 zevenentwintigste verdieping | 21.21 buitenwanden - constructief, massieve wanden (Uniformat) | Model Group:NLRS_21.21_WA_wand 004 d=300_gen:4747962
2 x Basic Wall:NLRS_21.21_WA_beton prefab d=300/320_gen:5365657 | 27 zevenentwintigste verdieping | 21.21 buitenwanden - constructief, massieve wanden (Uniformat) | Model Group:NLRS_21.21_WA_wand 004 d=300_gen:4747962
3 x Basic Wall:NLRS_21.21_WA_beton prefab d=300/320_gen:4748020 | 27 zevenentwintigste verdieping | 21.21 buitenwanden - constructief, massieve wanden (Uniformat) | Model Group:NLRS_21.21_WA_wand 004 d=300_gen:4747953
2 x Basic Wall:NLRS_21.21_WA_beton prefab d=300/320_gen:5365657 | 27 zevenentwintigste verdieping | 21.21 buitenwanden - constructief, massieve wanden (Uniformat) | Model Group:NLRS_21.21_WA_wand 004 d=300_gen:4747953
Basic Wall:NLRS_21.21_WA_beton prefab d=300/320_gen:4748127 | 27 zevenentwintigste verdieping | 21.21 buitenwanden - constructief, massieve wanden (Uniformat) | Model Group:NLRS_28.21_WA_3D element 002 d=300_gen:4748142
Basic Wall:NLRS_21.21_WA_beton prefab d=300/320_gen:4748129 | 27 zevenentwintigste verdieping | 21.21 buitenwanden - constructief, massieve wanden (Uniformat) | Model Group:NLRS_28.21_WA_3D element 002 d=300_gen:4748142
Basic Wall:NLRS_21.21_WA_beton prefab d=300/320_gen:4748208 | 27 zevenentwintigste verdieping | 21.21 buitenwanden - constructief, massieve wanden (Uniformat) | Model Group:NLRS_28.21_WA_3D element 002 d=300_gen:4748126
Basic Wall:NLRS_21.21_WA_beton prefab d=300/320_gen:4748210 | 27 zevenentwintigste verdieping | 21.21 buitenwanden - constructief, massieve wanden (Uniformat) | Model Group:NLRS_28.21_WA_3D element 002 d=300_gen:4748126
Basic Wall:NLRS_21.21_WA_beton prefab d=300/320_gen:4748252 | 27 zevenentwintigste verdieping | 21.21 buitenwanden - constructief, massieve wanden (Uniformat) | Model Group:NLRS_28.21_WA_3D element 001 d=300_gen:4748125
Basic Wall:NLRS_21.21_WA_beton prefab d=300/320_gen:4748255 | 27 zevenentwintigste verdieping | 21.21 buitenwanden - constructief, massieve wanden (Uniformat) | Model Group:NLRS_28.21_WA_3D element 001 d=300_gen:4748125
Basic Wall:NLRS_21.21_WA_beton prefab d=300/320_gen:4748281 | 27 zevenentwintigste verdieping | 21.21 buitenwanden - constructief, massieve wanden (Uniformat) | Model Group:NLRS_28.21_WA_3D element 001 d=300_gen:4748143
Basic Wall:NLRS_21.21_WA_beton prefab d=300/320_gen:4748284 | 27 zevenentwintigste verdieping | 21.21 buitenwanden - constructief, massieve wanden (Uniformat) | Model Group:NLRS_28.21_WA_3D element 001 d=300_gen:4748143
Basic Wall:NLRS_21.21_WA_beton prefab d=300/320_gen:4748355 | 28 achtentwintigste verdieping | 21.21 buitenwanden - constructief, massieve wanden (Uniformat) | Model Group:NLRS_21.21_WA_wand 003 d=300_gen:4748404
Basic Wall:NLRS_21.21_WA_beton prefab d=300/320_gen:4748357 | 28 achtentwintigste verdieping | 21.21 buitenwanden - constructief, massieve wanden (Uniformat) | Model Group:NLRS_21.21_WA_wand 001 d=300_gen:4748403
Basic Wall:NLRS_21.21_WA_beton prefab d=300/320_gen:4748405 | 28 achtentwintigste verdieping | 21.21 buitenwanden - constructief, massieve wanden (Uniformat) | Model Group:NLRS_21.21_WA_wand 003 d=300_gen:4748408
Basic Wall:NLRS_21.21_WA_beton prefab d=300/320_gen:4748409 | 28 achtentwintigste verdieping | 21.21 buitenwanden - constructief, massieve wanden (Uniformat) | Model Group:NLRS_21.21_WA_wand 001 d=300_gen:4748412
3 x Basic Wall:NLRS_21.21_WA_beton prefab d=300/320_gen:4748424 | 28 achtentwintigste verdieping | 21.21 buitenwanden - constructief, massieve wanden (Uniformat) | Model Group:NLRS_21.21_WA_wand 002 d=300_gen:4748402
2 x Basic Wall:NLRS_21.21_WA_beton prefab d=300/320_gen:5365657 | 28 achtentwintigste verdieping | 21.21 buitenwanden - constructief, massieve wanden (Uniformat) | Model Group:NLRS_21.21_WA_wand 002 d=300_gen:4748402
3 x Basic Wall:NLRS_21.21_WA_beton prefab d=300/320_gen:4748426 | 28 achtentwintigste verdieping | 21.21 buitenwanden - constructief, massieve wanden (Uniformat) | Model Group:NLRS_21.21_WA_wand 002 d=300_gen:4748395
2 x Basic Wall:NLRS_21.21_WA_beton prefab d=300/320_gen:5365657 | 28 achtentwintigste verdieping | 21.21 buitenwanden - constructief, massieve wanden (Uniformat) | Model Group:NLRS_21.21_WA_wand 002 d=300_gen:4748395
3 x Basic Wall:NLRS_21.21_WA_beton prefab d=300/320_gen:4748450 | 28 achtentwintigste verdieping | 21.21 buitenwanden - constructief, massieve wanden (Uniformat) | Model Group:NLRS_21.21_WA_wand 004 d=300_gen:4748394
2 x Basic Wall:NLRS_21.21_WA_beton prefab d=300/320_gen:5365657 | 28 achtentwintigste verdieping | 21.21 buitenwanden - constructief, massieve wanden (Uniformat) | Model Group:NLRS_21.21_WA_wand 004 d=300_gen:4748394
3 x Basic Wall:NLRS_21.21_WA_beton prefab d=300/320_gen:4748452 | 28 achtentwintigste verdieping | 21.21 buitenwanden - constructief, massieve wanden (Uniformat) | Model Group:NLRS_21.21_WA_wand 004 d=300_gen:4748385
2 x Basic Wall:NLRS_21.21_WA_beton prefab d=300/320_gen:5365657 | 28 achtentwintigste verdieping | 21.21 buitenwanden - constructief, massieve wanden (Uniformat) | Model Group:NLRS_21.21_WA_wand 004 d=300_gen:4748385
Basic Wall:NLRS_21.21_WA_beton prefab d=300/320_gen:4748559 | 28 achtentwintigste verdieping | 21.21 buitenwanden - constructief, massieve wanden (Uniformat) | Model Group:NLRS_28.21_WA_3D element 002 d=300_gen:4748574
Basic Wall:NLRS_21.21_WA_beton prefab d=300/320_gen:4748561 | 28 achtentwintigste verdieping | 21.21 buitenwanden - constructief, massieve wanden (Uniformat) | Model Group:NLRS_28.21_WA_3D element 002 d=300_gen:4748574
Basic Wall:NLRS_21.21_WA_beton prefab d=300/320_gen:4748640 | 28 achtentwintigste verdieping | 21.21 buitenwanden - constructief, massieve wanden (Uniformat) | Model Group:NLRS_28.21_WA_3D element 002 d=300_gen:4748558
Basic Wall:NLRS_21.21_WA_beton prefab d=300/320_gen:4748642 | 28 achtentwintigste verdieping | 21.21 buitenwanden - constructief, massieve wanden (Uniformat) | Model Group:NLRS_28.21_WA_3D element 002 d=300_gen:4748558
Basic Wall:NLRS_21.21_WA_beton prefab d=300/320_gen:4748684 | 28 achtentwintigste verdieping | 21.21 buitenwanden - constructief, massieve wanden (Uniformat) | Model Group:NLRS_28.21_WA_3D element 001 d=300_gen:4748557
Basic Wall:NLRS_21.21_WA_beton prefab d=300/320_gen:4748687 | 28 achtentwintigste verdieping | 21.21 buitenwanden - constructief, massieve wanden (Uniformat) | Model Group:NLRS_28.21_WA_3D element 001 d=300_gen:4748557
Basic Wall:NLRS_21.21_WA_beton prefab d=300/320_gen:4748713 | 28 achtentwintigste verdieping | 21.21 buitenwanden - constructief, massieve wanden (Uniformat) | Model Group:NLRS_28.21_WA_3D element 001 d=300_gen:4748575
Basic Wall:NLRS_21.21_WA_beton prefab d=300/320_gen:4748716 | 28 achtentwintigste verdieping | 21.21 buitenwanden - constructief, massieve wanden (Uniformat) | Model Group:NLRS_28.21_WA_3D element 001 d=300_gen:4748575
Basic Wall:NLRS_21.21_WA_beton prefab d=300/320_gen:4748787 | 29 negenentwintigste verdieping | 21.21 buitenwanden - constructief, massieve wanden (Uniformat) | Model Group:NLRS_21.21_WA_wand 003 d=300_gen:4748836
Basic Wall:NLRS_21.21_WA_beton prefab d=300/320_gen:4748789 | 29 negenentwintigste verdieping | 21.21 buitenwanden - constructief, massieve wanden (Uniformat) | Model Group:NLRS_21.21_WA_wand 001 d=300_gen:4748835
Basic Wall:NLRS_21.21_WA_beton prefab d=300/320_gen:4748837 | 29 negenentwintigste verdieping | 21.21 buitenwanden - constructief, massieve wanden (Uniformat) | Model Group:NLRS_21.21_WA_wand 003 d=300_gen:4748840
Basic Wall:NLRS_21.21_WA_beton prefab d=300/320_gen:4748841 | 29 negenentwintigste verdieping | 21.21 buitenwanden - constructief, massieve wanden (Uniformat) | Model Group:NLRS_21.21_WA_wand 001 d=300_gen:4748844
3 x Basic Wall:NLRS_21.21_WA_beton prefab d=300/320_gen:4748856 | 29 negenentwintigste verdieping | 21.21 buitenwanden - constructief, massieve wanden (Uniformat) | Model Group:NLRS_21.21_WA_wand 002 d=300_gen:4748834
2 x Basic Wall:NLRS_21.21_WA_beton prefab d=300/320_gen:5365657 | 29 negenentwintigste verdieping | 21.21 buitenwanden - constructief, massieve wanden (Uniformat) | Model Group:NLRS_21.21_WA_wand 002 d=300_gen:4748834
3 x Basic Wall:NLRS_21.21_WA_beton prefab d=300/320_gen:4748858 | 29 negenentwintigste verdieping | 21.21 buitenwanden - constructief, massieve wanden (Uniformat) | Model Group:NLRS_21.21_WA_wand 002 d=300_gen:4748827
2 x Basic Wall:NLRS_21.21_WA_beton prefab d=300/320_gen:5365657 | 29 negenentwintigste verdieping | 21.21 buitenwanden - constructief, massieve wanden (Uniformat) | Model Group:NLRS_21.21_WA_wand 002 d=300_gen:4748827
3 x Basic Wall:NLRS_21.21_WA_beton prefab d=300/320_gen:4748882 | 29 negenentwintigste verdieping | 21.21 buitenwanden - constructief, massieve wanden (Uniformat) | Model Group:NLRS_21.21_WA_wand 004 d=300_gen:4748826
2 x Basic Wall:NLRS_21.21_WA_beton prefab d=300/320_gen:5365657 | 29 negenentwintigste verdieping | 21.21 buitenwanden - constructief, massieve wanden (Uniformat) | Model Group:NLRS_21.21_WA_wand 004 d=300_gen:4748826
3 x Basic Wall:NLRS_21.21_WA_beton prefab d=300/320_gen:4748884 | 29 negenentwintigste verdieping | 21.21 buitenwanden - constructief, massieve wanden (Uniformat) | Model Group:NLRS_21.21_WA_wand 004 d=300_gen:4748817
2 x Basic Wall:NLRS_21.21_WA_beton prefab d=300/320_gen:5365657 | 29 negenentwintigste verdieping | 21.21 buitenwanden - constructief, massieve wanden (Uniformat) | Model Group:NLRS_21.21_WA_wand 004 d=300_gen:4748817
Basic Wall:NLRS_21.21_WA_beton prefab d=300/320_gen:4748991 | 29 negenentwintigste verdieping | 21.21 buitenwanden - constructief, massieve wanden (Uniformat) | Model Group:NLRS_28.21_WA_3D element 002 d=300_gen:4749006
Basic Wall:NLRS_21.21_WA_beton prefab d=300/320_gen:4748993 | 29 negenentwintigste verdieping | 21.21 buitenwanden - constructief, massieve wanden (Uniformat) | Model Group:NLRS_28.21_WA_3D element 002 d=300_gen:4749006
Basic Wall:NLRS_21.21_WA_beton prefab d=300/320_gen:4749072 | 29 negenentwintigste verdieping | 21.21 buitenwanden - constructief, massieve wanden (Uniformat) | Model Group:NLRS_28.21_WA_3D element 002 d=300_gen:4748990
Basic Wall:NLRS_21.21_WA_beton prefab d=300/320_gen:4749074 | 29 negenentwintigste verdieping | 21.21 buitenwanden - constructief, massieve wanden (Uniformat) | Model Group:NLRS_28.21_WA_3D element 002 d=300_gen:4748990
Basic Wall:NLRS_21.21_WA_beton prefab d=300/320_gen:4749116 | 29 negenentwintigste verdieping | 21.21 buitenwanden - constructief, massieve wanden (Uniformat) | Model Group:NLRS_28.21_WA_3D element 001 d=300_gen:4748989
Basic Wall:NLRS_21.21_WA_beton prefab d=300/320_gen:4749119 | 29 negenentwintigste verdieping | 21.21 buitenwanden - constructief, massieve wanden (Uniformat) | Model Group:NLRS_28.21_WA_3D element 001 d=300_gen:4748989
Basic Wall:NLRS_21.21_WA_beton prefab d=300/320_gen:4749145 | 29 negenentwintigste verdieping | 21.21 buitenwanden - constructief, massieve wanden (Uniformat) | Model Group:NLRS_28.21_WA_3D element 001 d=300_gen:4749007
Basic Wall:NLRS_21.21_WA_beton prefab d=300/320_gen:4749148 | 29 negenentwintigste verdieping | 21.21 buitenwanden - constructief, massieve wanden (Uniformat) | Model Group:NLRS_28.21_WA_3D element 001 d=300_gen:4749007
Basic Wall:NLRS_21.21_WA_beton prefab d=300/320_gen:4749219 | 30 dertigste verdieping | 21.21 buitenwanden - constructief, massieve wanden (Uniformat) | Model Group:NLRS_21.21_WA_wand 003 d=300_gen:4749268
Basic Wall:NLRS_21.21_WA_beton prefab d=300/320_gen:4749221 | 30 dertigste verdieping | 21.21 buitenwanden - constructief, massieve wanden (Uniformat) | Model Group:NLRS_21.21_WA_wand 001 d=300_gen:4749267
Basic Wall:NLRS_21.21_WA_beton prefab d=300/320_gen:4749269 | 30 dertigste verdieping | 21.21 buitenwanden - constructief, massieve wanden (Uniformat) | Model Group:NLRS_21.21_WA_wand 003 d=300_gen:4749272
Basic Wall:NLRS_21.21_WA_beton prefab d=300/320_gen:4749273 | 30 dertigste verdieping | 21.21 buitenwanden - constructief, massieve wanden (Uniformat) | Model Group:NLRS_21.21_WA_wand 001 d=300_gen:4749276
3 x Basic Wall:NLRS_21.21_WA_beton prefab d=300/320_gen:4749288 | 30 dertigste verdieping | 21.21 buitenwanden - constructief, massieve wanden (Uniformat) | Model Group:NLRS_21.21_WA_wand 002 d=300_gen:4749266
2 x Basic Wall:NLRS_21.21_WA_beton prefab d=300/320_gen:5365657 | 30 dertigste verdieping | 21.21 buitenwanden - constructief, massieve wanden (Uniformat) | Model Group:NLRS_21.21_WA_wand 002 d=300_gen:4749266
3 x Basic Wall:NLRS_21.21_WA_beton prefab d=300/320_gen:4749290 | 30 dertigste verdieping | 21.21 buitenwanden - constructief, massieve wanden (Uniformat) | Model Group:NLRS_21.21_WA_wand 002 d=300_gen:4749259
2 x Basic Wall:NLRS_21.21_WA_beton prefab d=300/320_gen:5365657 | 30 dertigste verdieping | 21.21 buitenwanden - constructief, massieve wanden (Uniformat) | Model Group:NLRS_21.21_WA_wand 002 d=300_gen:4749259
3 x Basic Wall:NLRS_21.21_WA_beton prefab d=300/320_gen:4749314 | 30 dertigste verdieping | 21.21 buitenwanden - constructief, massieve wanden (Uniformat) | Model Group:NLRS_21.21_WA_wand 004 d=300_gen:4749258
2 x Basic Wall:NLRS_21.21_WA_beton prefab d=300/320_gen:5365657 | 30 dertigste verdieping | 21.21 buitenwanden - constructief, massieve wanden (Uniformat) | Model Group:NLRS_21.21_WA_wand 004 d=300_gen:4749258
3 x Basic Wall:NLRS_21.21_WA_beton prefab d=300/320_gen:4749316 | 30 dertigste verdieping | 21.21 buitenwanden - constructief, massieve wanden (Uniformat) | Model Group:NLRS_21.21_WA_wand 004 d=300_gen:4749249
2 x Basic Wall:NLRS_21.21_WA_beton prefab d=300/320_gen:5365657 | 30 dertigste verdieping | 21.21 buitenwanden - constructief, massieve wanden (Uniformat) | Model Group:NLRS_21.21_WA_wand 004 d=300_gen:4749249
Basic Wall:NLRS_21.21_WA_beton prefab d=300/320_gen:4749423 | 30 dertigste verdieping | 21.21 buitenwanden - constructief, massieve wanden (Uniformat) | Model Group:NLRS_28.21_WA_3D element 002 d=300_gen:4749438
Basic Wall:NLRS_21.21_WA_beton prefab d=300/320_gen:4749425 | 30 dertigste verdieping | 21.21 buitenwanden - constructief, massieve wanden (Uniformat) | Model Group:NLRS_28.21_WA_3D element 002 d=300_gen:4749438
Basic Wall:NLRS_21.21_WA_beton prefab d=300/320_gen:4749504 | 30 dertigste verdieping | 21.21 buitenwanden - constructief, massieve wanden (Uniformat) | Model Group:NLRS_28.21_WA_3D element 002 d=300_gen:4749422
Basic Wall:NLRS_21.21_WA_beton prefab d=300/320_gen:4749506 | 30 dertigste verdieping | 21.21 buitenwanden - constructief, massieve wanden (Uniformat) | Model Group:NLRS_28.21_WA_3D element 002 d=300_gen:4749422
Basic Wall:NLRS_21.21_WA_beton prefab d=300/320_gen:4749548 | 30 dertigste verdieping | 21.21 buitenwanden - constructief, massieve wanden (Uniformat) | Model Group:NLRS_28.21_WA_3D element 001 d=300_gen:4749421
Basic Wall:NLRS_21.21_WA_beton prefab d=300/320_gen:4749551 | 30 dertigste verdieping | 21.21 buitenwanden - constructief, massieve wanden (Uniformat) | Model Group:NLRS_28.21_WA_3D element 001 d=300_gen:4749421
Basic Wall:NLRS_21.21_WA_beton prefab d=300/320_gen:4749577 | 30 dertigste verdieping | 21.21 buitenwanden - constructief, massieve wanden (Uniformat) | Model Group:NLRS_28.21_WA_3D element 001 d=300_gen:4749439
Basic Wall:NLRS_21.21_WA_beton prefab d=300/320_gen:4749580 | 30 dertigste verdieping | 21.21 buitenwanden - constructief, massieve wanden (Uniformat) | Model Group:NLRS_28.21_WA_3D element 001 d=300_gen:4749439
Basic Wall:NLRS_21.21_WA_beton prefab d=300/320_gen:4749651 | 31 eenendertigste verdieping | 21.21 buitenwanden - constructief, massieve wanden (Uniformat) | Model Group:NLRS_21.21_WA_wand 003 d=300_gen:4749700
Basic Wall:NLRS_21.21_WA_beton prefab d=300/320_gen:4749653 | 31 eenendertigste verdieping | 21.21 buitenwanden - constructief, massieve wanden (Uniformat) | Model Group:NLRS_21.21_WA_wand 001 d=300_gen:4749699
Basic Wall:NLRS_21.21_WA_beton prefab d=300/320_gen:4749701 | 31 eenendertigste verdieping | 21.21 buitenwanden - constructief, massieve wanden (Uniformat) | Model Group:NLRS_21.21_WA_wand 003 d=300_gen:4749704
Basic Wall:NLRS_21.21_WA_beton prefab d=300/320_gen:4749705 | 31 eenendertigste verdieping | 21.21 buitenwanden - constructief, massieve wanden (Uniformat) | Model Group:NLRS_21.21_WA_wand 001 d=300_gen:4749708
3 x Basic Wall:NLRS_21.21_WA_beton prefab d=300/320_gen:4749720 | 31 eenendertigste verdieping | 21.21 buitenwanden - constructief, massieve wanden (Uniformat) | Model Group:NLRS_21.21_WA_wand 002 d=300_gen:4749698
2 x Basic Wall:NLRS_21.21_WA_beton prefab d=300/320_gen:5365657 | 31 eenendertigste verdieping | 21.21 buitenwanden - constructief, massieve wanden (Uniformat) | Model Group:NLRS_21.21_WA_wand 002 d=300_gen:4749698
3 x Basic Wall:NLRS_21.21_WA_beton prefab d=300/320_gen:4749722 | 31 eenendertigste verdieping | 21.21 buitenwanden - constructief, massieve wanden (Uniformat) | Model Group:NLRS_21.21_WA_wand 002 d=300_gen:4749691
2 x Basic Wall:NLRS_21.21_WA_beton prefab d=300/320_gen:5365657 | 31 eenendertigste verdieping | 21.21 buitenwanden - constructief, massieve wanden (Uniformat) | Model Group:NLRS_21.21_WA_wand 002 d=300_gen:4749691
3 x Basic Wall:NLRS_21.21_WA_beton prefab d=300/320_gen:4749746 | 31 eenendertigste verdieping | 21.21 buitenwanden - constructief, massieve wanden (Uniformat) | Model Group:NLRS_21.21_WA_wand 004 d=300_gen:4749690
2 x Basic Wall:NLRS_21.21_WA_beton prefab d=300/320_gen:5365657 | 31 eenendertigste verdieping | 21.21 buitenwanden - constructief, massieve wanden (Uniformat) | Model Group:NLRS_21.21_WA_wand 004 d=300_gen:4749690
3 x Basic Wall:NLRS_21.21_WA_beton prefab d=300/320_gen:4749748 | 31 eenendertigste verdieping | 21.21 buitenwanden - constructief, massieve wanden (Uniformat) | Model Group:NLRS_21.21_WA_wand 004 d=300_gen:4749681
2 x Basic Wall:NLRS_21.21_WA_beton prefab d=300/320_gen:5365657 | 31 eenendertigste verdieping | 21.21 buitenwanden - constructief, massieve wanden (Uniformat) | Model Group:NLRS_21.21_WA_wand 004 d=300_gen:4749681
Basic Wall:NLRS_21.21_WA_beton prefab d=300/320_gen:4749855 | 31 eenendertigste verdieping | 21.21 buitenwanden - constructief, massieve wanden (Uniformat) | Model Group:NLRS_28.21_WA_3D element 002 d=300_gen:4749870
Basic Wall:NLRS_21.21_WA_beton prefab d=300/320_gen:4749857 | 31 eenendertigste verdieping | 21.21 buitenwanden - constructief, massieve wanden (Uniformat) | Model Group:NLRS_28.21_WA_3D element 002 d=300_gen:4749870
Basic Wall:NLRS_21.21_WA_beton prefab d=300/320_gen:4749936 | 31 eenendertigste verdieping | 21.21 buitenwanden - constructief, massieve wanden (Uniformat) | Model Group:NLRS_28.21_WA_3D element 002 d=300_gen:4749854
Basic Wall:NLRS_21.21_WA_beton prefab d=300/320_gen:4749938 | 31 eenendertigste verdieping | 21.21 buitenwanden - constructief, massieve wanden (Uniformat) | Model Group:NLRS_28.21_WA_3D element 002 d=300_gen:4749854
Basic Wall:NLRS_21.21_WA_beton prefab d=300/320_gen:4749980 | 31 eenendertigste verdieping | 21.21 buitenwanden - constructief, massieve wanden (Uniformat) | Model Group:NLRS_28.21_WA_3D element 001 d=300_gen:4749853
Basic Wall:NLRS_21.21_WA_beton prefab d=300/320_gen:4749983 | 31 eenendertigste verdieping | 21.21 buitenwanden - constructief, massieve wanden (Uniformat) | Model Group:NLRS_28.21_WA_3D element 001 d=300_gen:4749853
Basic Wall:NLRS_21.21_WA_beton prefab d=300/320_gen:4750009 | 31 eenendertigste verdieping | 21.21 buitenwanden - constructief, massieve wanden (Uniformat) | Model Group:NLRS_28.21_WA_3D element 001 d=300_gen:4749871
Basic Wall:NLRS_21.21_WA_beton prefab d=300/320_gen:4750012 | 31 eenendertigste verdieping | 21.21 buitenwanden - constructief, massieve wanden (Uniformat) | Model Group:NLRS_28.21_WA_3D element 001 d=300_gen:4749871
Basic Wall:NLRS_21.21_WA_beton prefab d=300/320_gen:4750083 | 32 tweeëndertigste verdieping | 21.21 buitenwanden - constructief, massieve wanden (Uniformat) | Model Group:NLRS_21.21_WA_wand 003 d=300_gen:4750132
Basic Wall:NLRS_21.21_WA_beton prefab d=300/320_gen:4750085 | 32 tweeëndertigste verdieping | 21.21 buitenwanden - constructief, massieve wanden (Uniformat) | Model Group:NLRS_21.21_WA_wand 001 d=300_gen:4750131
Basic Wall:NLRS_21.21_WA_beton prefab d=300/320_gen:4750133 | 32 tweeëndertigste verdieping | 21.21 buitenwanden - constructief, massieve wanden (Uniformat) | Model Group:NLRS_21.21_WA_wand 003 d=300_gen:4750136
Basic Wall:NLRS_21.21_WA_beton prefab d=300/320_gen:4750137 | 32 tweeëndertigste verdieping | 21.21 buitenwanden - constructief, massieve wanden (Uniformat) | Model Group:NLRS_21.21_WA_wand 001 d=300_gen:4750140
3 x Basic Wall:NLRS_21.21_WA_beton prefab d=300/320_gen:4750152 | 32 tweeëndertigste verdieping | 21.21 buitenwanden - constructief, massieve wanden (Uniformat) | Model Group:NLRS_21.21_WA_wand 002 d=300_gen:4750130
2 x Basic Wall:NLRS_21.21_WA_beton prefab d=300/320_gen:5365657 | 32 tweeëndertigste verdieping | 21.21 buitenwanden - constructief, massieve wanden (Uniformat) | Model Group:NLRS_21.21_WA_wand 002 d=300_gen:4750130
3 x Basic Wall:NLRS_21.21_WA_beton prefab d=300/320_gen:4750154 | 32 tweeëndertigste verdieping | 21.21 buitenwanden - constructief, massieve wanden (Uniformat) | Model Group:NLRS_21.21_WA_wand 002 d=300_gen:4750123
2 x Basic Wall:NLRS_21.21_WA_beton prefab d=300/320_gen:5365657 | 32 tweeëndertigste verdieping | 21.21 buitenwanden - constructief, massieve wanden (Uniformat) | Model Group:NLRS_21.21_WA_wand 002 d=300_gen:4750123
3 x Basic Wall:NLRS_21.21_WA_beton prefab d=300/320_gen:4750178 | 32 tweeëndertigste verdieping | 21.21 buitenwanden - constructief, massieve wanden (Uniformat) | Model Group:NLRS_21.21_WA_wand 004 d=300_gen:4750122
2 x Basic Wall:NLRS_21.21_WA_beton prefab d=300/320_gen:5365657 | 32 tweeëndertigste verdieping | 21.21 buitenwanden - constructief, massieve wanden (Uniformat) | Model Group:NLRS_21.21_WA_wand 004 d=300_gen:4750122
3 x Basic Wall:NLRS_21.21_WA_beton prefab d=300/320_gen:4750180 | 32 tweeëndertigste verdieping | 21.21 buitenwanden - constructief, massieve wanden (Uniformat) | Model Group:NLRS_21.21_WA_wand 004 d=300_gen:4750113
2 x Basic Wall:NLRS_21.21_WA_beton prefab d=300/320_gen:5365657 | 32 tweeëndertigste verdieping | 21.21 buitenwanden - constructief, massieve wanden (Uniformat) | Model Group:NLRS_21.21_WA_wand 004 d=300_gen:4750113
Basic Wall:NLRS_21.21_WA_beton prefab d=300/320_gen:4750287 | 32 tweeëndertigste verdieping | 21.21 buitenwanden - constructief, massieve wanden (Uniformat) | Model Group:NLRS_28.21_WA_3D element 002 d=300_gen:4750302
Basic Wall:NLRS_21.21_WA_beton prefab d=300/320_gen:4750289 | 32 tweeëndertigste verdieping | 21.21 buitenwanden - constructief, massieve wanden (Uniformat) | Model Group:NLRS_28.21_WA_3D element 002 d=300_gen:4750302
Basic Wall:NLRS_21.21_WA_beton prefab d=300/320_gen:4750368 | 32 tweeëndertigste verdieping | 21.21 buitenwanden - constructief, massieve wanden (Uniformat) | Model Group:NLRS_28.21_WA_3D element 002 d=300_gen:4750286
Basic Wall:NLRS_21.21_WA_beton prefab d=300/320_gen:4750370 | 32 tweeëndertigste verdieping | 21.21 buitenwanden - constructief, massieve wanden (Uniformat) | Model Group:NLRS_28.21_WA_3D element 002 d=300_gen:4750286
Basic Wall:NLRS_21.21_WA_beton prefab d=300/320_gen:4750412 | 32 tweeëndertigste verdieping | 21.21 buitenwanden - constructief, massieve wanden (Uniformat) | Model Group:NLRS_28.21_WA_3D element 001 d=300_gen:4750285
Basic Wall:NLRS_21.21_WA_beton prefab d=300/320_gen:4750415 | 32 tweeëndertigste verdieping | 21.21 buitenwanden - constructief, massieve wanden (Uniformat) | Model Group:NLRS_28.21_WA_3D element 001 d=300_gen:4750285
Basic Wall:NLRS_21.21_WA_beton prefab d=300/320_gen:4750441 | 32 tweeëndertigste verdieping | 21.21 buitenwanden - constructief, massieve wanden (Uniformat) | Model Group:NLRS_28.21_WA_3D element 001 d=300_gen:4750303
Basic Wall:NLRS_21.21_WA_beton prefab d=300/320_gen:4750444 | 32 tweeëndertigste verdieping | 21.21 buitenwanden - constructief, massieve wanden (Uniformat) | Model Group:NLRS_28.21_WA_3D element 001 d=300_gen:4750303
Basic Wall:NLRS_21.21_WA_beton prefab d=300/320_gen:4750515 | 33 drieëndertigste verdieping | 21.21 buitenwanden - constructief, massieve wanden (Uniformat) | Model Group:NLRS_21.21_WA_wand 003 d=300_gen:4750564
Basic Wall:NLRS_21.21_WA_beton prefab d=300/320_gen:4750517 | 33 drieëndertigste verdieping | 21.21 buitenwanden - constructief, massieve wanden (Uniformat) | Model Group:NLRS_21.21_WA_wand 001 d=300_gen:4750563
Basic Wall:NLRS_21.21_WA_beton prefab d=300/320_gen:4750565 | 33 drieëndertigste verdieping | 21.21 buitenwanden - constructief, massieve wanden (Uniformat) | Model Group:NLRS_21.21_WA_wand 003 d=300_gen:4750568
Basic Wall:NLRS_21.21_WA_beton prefab d=300/320_gen:4750569 | 33 drieëndertigste verdieping | 21.21 buitenwanden - constructief, massieve wanden (Uniformat) | Model Group:NLRS_21.21_WA_wand 001 d=300_gen:4750572
3 x Basic Wall:NLRS_21.21_WA_beton prefab d=300/320_gen:4750584 | 33 drieëndertigste verdieping | 21.21 buitenwanden - constructief, massieve wanden (Uniformat) | Model Group:NLRS_21.21_WA_wand 002 d=300_gen:4750562
2 x Basic Wall:NLRS_21.21_WA_beton prefab d=300/320_gen:5365657 | 33 drieëndertigste verdieping | 21.21 buitenwanden - constructief, massieve wanden (Uniformat) | Model Group:NLRS_21.21_WA_wand 002 d=300_gen:4750562
3 x Basic Wall:NLRS_21.21_WA_beton prefab d=300/320_gen:4750586 | 33 drieëndertigste verdieping | 21.21 buitenwanden - constructief, massieve wanden (Uniformat) | Model Group:NLRS_21.21_WA_wand 002 d=300_gen:4750555
2 x Basic Wall:NLRS_21.21_WA_beton prefab d=300/320_gen:5365657 | 33 drieëndertigste verdieping | 21.21 buitenwanden - constructief, massieve wanden (Uniformat) | Model Group:NLRS_21.21_WA_wand 002 d=300_gen:4750555
3 x Basic Wall:NLRS_21.21_WA_beton prefab d=300/320_gen:4750610 | 33 drieëndertigste verdieping | 21.21 buitenwanden - constructief, massieve wanden (Uniformat) | Model Group:NLRS_21.21_WA_wand 004 d=300_gen:4750554
2 x Basic Wall:NLRS_21.21_WA_beton prefab d=300/320_gen:5365657 | 33 drieëndertigste verdieping | 21.21 buitenwanden - constructief, massieve wanden (Uniformat) | Model Group:NLRS_21.21_WA_wand 004 d=300_gen:4750554
3 x Basic Wall:NLRS_21.21_WA_beton prefab d=300/320_gen:4750612 | 33 drieëndertigste verdieping | 21.21 buitenwanden - constructief, massieve wanden (Uniformat) | Model Group:NLRS_21.21_WA_wand 004 d=300_gen:4750545
2 x Basic Wall:NLRS_21.21_WA_beton prefab d=300/320_gen:5365657 | 33 drieëndertigste verdieping | 21.21 buitenwanden - constructief, massieve wanden (Uniformat) | Model Group:NLRS_21.21_WA_wand 004 d=300_gen:4750545
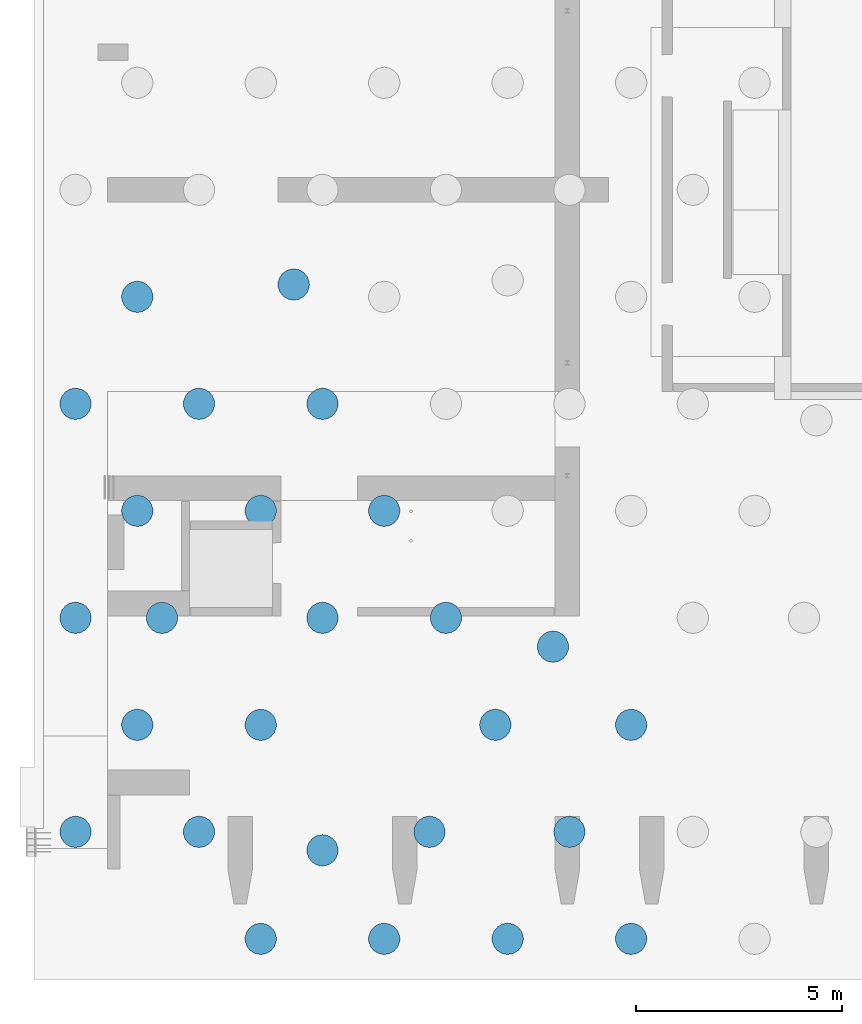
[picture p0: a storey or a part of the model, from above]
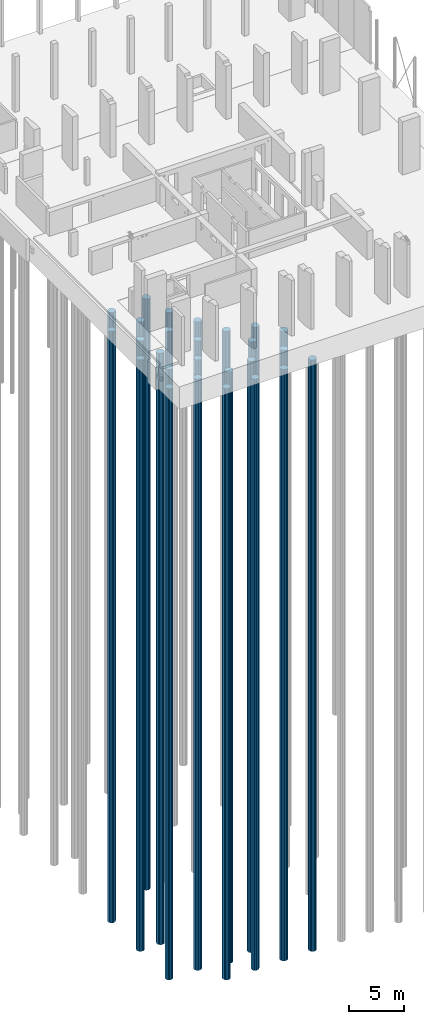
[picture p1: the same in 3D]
Properties of the parts of a building model (IFC2X3), part 9 of 21

# IfcOpeningElement: Opening (5659)
Name | In | Classification | Group
Basic Wall:NLRS_21.21_WA_beton prefab d=300/320_gen:4750719 | 33 drieëndertigste verdieping | 21.21 buitenwanden - constructief, massieve wanden (Uniformat) | Model Group:NLRS_28.21_WA_3D element 002 d=300_gen:4750734
Basic Wall:NLRS_21.21_WA_beton prefab d=300/320_gen:4750721 | 33 drieëndertigste verdieping | 21.21 buitenwanden - constructief, massieve wanden (Uniformat) | Model Group:NLRS_28.21_WA_3D element 002 d=300_gen:4750734
Basic Wall:NLRS_21.21_WA_beton prefab d=300/320_gen:4750800 | 33 drieëndertigste verdieping | 21.21 buitenwanden - constructief, massieve wanden (Uniformat) | Model Group:NLRS_28.21_WA_3D element 002 d=300_gen:4750718
Basic Wall:NLRS_21.21_WA_beton prefab d=300/320_gen:4750802 | 33 drieëndertigste verdieping | 21.21 buitenwanden - constructief, massieve wanden (Uniformat) | Model Group:NLRS_28.21_WA_3D element 002 d=300_gen:4750718
Basic Wall:NLRS_21.21_WA_beton prefab d=300/320_gen:4750844 | 33 drieëndertigste verdieping | 21.21 buitenwanden - constructief, massieve wanden (Uniformat) | Model Group:NLRS_28.21_WA_3D element 001 d=300_gen:4750717
Basic Wall:NLRS_21.21_WA_beton prefab d=300/320_gen:4750847 | 33 drieëndertigste verdieping | 21.21 buitenwanden - constructief, massieve wanden (Uniformat) | Model Group:NLRS_28.21_WA_3D element 001 d=300_gen:4750717
Basic Wall:NLRS_21.21_WA_beton prefab d=300/320_gen:4750873 | 33 drieëndertigste verdieping | 21.21 buitenwanden - constructief, massieve wanden (Uniformat) | Model Group:NLRS_28.21_WA_3D element 001 d=300_gen:4750735
Basic Wall:NLRS_21.21_WA_beton prefab d=300/320_gen:4750876 | 33 drieëndertigste verdieping | 21.21 buitenwanden - constructief, massieve wanden (Uniformat) | Model Group:NLRS_28.21_WA_3D element 001 d=300_gen:4750735
Basic Wall:NLRS_21.21_WA_beton prefab d=300/320_gen:4750947 | 34 vierendertigste verdieping | 21.21 buitenwanden - constructief, massieve wanden (Uniformat) | Model Group:NLRS_21.21_WA_wand 003 d=300_gen:4750996
Basic Wall:NLRS_21.21_WA_beton prefab d=300/320_gen:4750949 | 34 vierendertigste verdieping | 21.21 buitenwanden - constructief, massieve wanden (Uniformat) | Model Group:NLRS_21.21_WA_wand 001 d=300_gen:4750995
Basic Wall:NLRS_21.21_WA_beton prefab d=300/320_gen:4750997 | 34 vierendertigste verdieping | 21.21 buitenwanden - constructief, massieve wanden (Uniformat) | Model Group:NLRS_21.21_WA_wand 003 d=300_gen:4751000
Basic Wall:NLRS_21.21_WA_beton prefab d=300/320_gen:4751001 | 34 vierendertigste verdieping | 21.21 buitenwanden - constructief, massieve wanden (Uniformat) | Model Group:NLRS_21.21_WA_wand 001 d=300_gen:4751004
3 x Basic Wall:NLRS_21.21_WA_beton prefab d=300/320_gen:4751016 | 34 vierendertigste verdieping | 21.21 buitenwanden - constructief, massieve wanden (Uniformat) | Model Group:NLRS_21.21_WA_wand 002 d=300_gen:4750994
2 x Basic Wall:NLRS_21.21_WA_beton prefab d=300/320_gen:5365657 | 34 vierendertigste verdieping | 21.21 buitenwanden - constructief, massieve wanden (Uniformat) | Model Group:NLRS_21.21_WA_wand 002 d=300_gen:4750994
3 x Basic Wall:NLRS_21.21_WA_beton prefab d=300/320_gen:4751018 | 34 vierendertigste verdieping | 21.21 buitenwanden - constructief, massieve wanden (Uniformat) | Model Group:NLRS_21.21_WA_wand 002 d=300_gen:4750987
2 x Basic Wall:NLRS_21.21_WA_beton prefab d=300/320_gen:5365657 | 34 vierendertigste verdieping | 21.21 buitenwanden - constructief, massieve wanden (Uniformat) | Model Group:NLRS_21.21_WA_wand 002 d=300_gen:4750987
3 x Basic Wall:NLRS_21.21_WA_beton prefab d=300/320_gen:4751042 | 34 vierendertigste verdieping | 21.21 buitenwanden - constructief, massieve wanden (Uniformat) | Model Group:NLRS_21.21_WA_wand 004 d=300_gen:4750986
2 x Basic Wall:NLRS_21.21_WA_beton prefab d=300/320_gen:5365657 | 34 vierendertigste verdieping | 21.21 buitenwanden - constructief, massieve wanden (Uniformat) | Model Group:NLRS_21.21_WA_wand 004 d=300_gen:4750986
3 x Basic Wall:NLRS_21.21_WA_beton prefab d=300/320_gen:4751044 | 34 vierendertigste verdieping | 21.21 buitenwanden - constructief, massieve wanden (Uniformat) | Model Group:NLRS_21.21_WA_wand 004 d=300_gen:4750977
2 x Basic Wall:NLRS_21.21_WA_beton prefab d=300/320_gen:5365657 | 34 vierendertigste verdieping | 21.21 buitenwanden - constructief, massieve wanden (Uniformat) | Model Group:NLRS_21.21_WA_wand 004 d=300_gen:4750977
Basic Wall:NLRS_21.21_WA_beton prefab d=300/320_gen:4751151 | 34 vierendertigste verdieping | 21.21 buitenwanden - constructief, massieve wanden (Uniformat) | Model Group:NLRS_28.21_WA_3D element 002 d=300_gen:4751166
Basic Wall:NLRS_21.21_WA_beton prefab d=300/320_gen:4751153 | 34 vierendertigste verdieping | 21.21 buitenwanden - constructief, massieve wanden (Uniformat) | Model Group:NLRS_28.21_WA_3D element 002 d=300_gen:4751166
Basic Wall:NLRS_21.21_WA_beton prefab d=300/320_gen:4751232 | 34 vierendertigste verdieping | 21.21 buitenwanden - constructief, massieve wanden (Uniformat) | Model Group:NLRS_28.21_WA_3D element 002 d=300_gen:4751150
Basic Wall:NLRS_21.21_WA_beton prefab d=300/320_gen:4751234 | 34 vierendertigste verdieping | 21.21 buitenwanden - constructief, massieve wanden (Uniformat) | Model Group:NLRS_28.21_WA_3D element 002 d=300_gen:4751150
Basic Wall:NLRS_21.21_WA_beton prefab d=300/320_gen:4751276 | 34 vierendertigste verdieping | 21.21 buitenwanden - constructief, massieve wanden (Uniformat) | Model Group:NLRS_28.21_WA_3D element 001 d=300_gen:4751149
Basic Wall:NLRS_21.21_WA_beton prefab d=300/320_gen:4751279 | 34 vierendertigste verdieping | 21.21 buitenwanden - constructief, massieve wanden (Uniformat) | Model Group:NLRS_28.21_WA_3D element 001 d=300_gen:4751149
Basic Wall:NLRS_21.21_WA_beton prefab d=300/320_gen:4751305 | 34 vierendertigste verdieping | 21.21 buitenwanden - constructief, massieve wanden (Uniformat) | Model Group:NLRS_28.21_WA_3D element 001 d=300_gen:4751167
Basic Wall:NLRS_21.21_WA_beton prefab d=300/320_gen:4751308 | 34 vierendertigste verdieping | 21.21 buitenwanden - constructief, massieve wanden (Uniformat) | Model Group:NLRS_28.21_WA_3D element 001 d=300_gen:4751167
Basic Wall:NLRS_21.21_WA_beton prefab d=300/320_gen:4751379 | 35 vijfendertigste verdieping | 21.21 buitenwanden - constructief, massieve wanden (Uniformat) | Model Group:NLRS_21.21_WA_wand 003 d=300_gen:4751428
Basic Wall:NLRS_21.21_WA_beton prefab d=300/320_gen:4751381 | 35 vijfendertigste verdieping | 21.21 buitenwanden - constructief, massieve wanden (Uniformat) | Model Group:NLRS_21.21_WA_wand 001 d=300_gen:4751427
Basic Wall:NLRS_21.21_WA_beton prefab d=300/320_gen:4751429 | 35 vijfendertigste verdieping | 21.21 buitenwanden - constructief, massieve wanden (Uniformat) | Model Group:NLRS_21.21_WA_wand 003 d=300_gen:4751432
Basic Wall:NLRS_21.21_WA_beton prefab d=300/320_gen:4751433 | 35 vijfendertigste verdieping | 21.21 buitenwanden - constructief, massieve wanden (Uniformat) | Model Group:NLRS_21.21_WA_wand 001 d=300_gen:4751436
3 x Basic Wall:NLRS_21.21_WA_beton prefab d=300/320_gen:4751448 | 35 vijfendertigste verdieping | 21.21 buitenwanden - constructief, massieve wanden (Uniformat) | Model Group:NLRS_21.21_WA_wand 002 d=300_gen:4751426
2 x Basic Wall:NLRS_21.21_WA_beton prefab d=300/320_gen:5365657 | 35 vijfendertigste verdieping | 21.21 buitenwanden - constructief, massieve wanden (Uniformat) | Model Group:NLRS_21.21_WA_wand 002 d=300_gen:4751426
3 x Basic Wall:NLRS_21.21_WA_beton prefab d=300/320_gen:4751450 | 35 vijfendertigste verdieping | 21.21 buitenwanden - constructief, massieve wanden (Uniformat) | Model Group:NLRS_21.21_WA_wand 002 d=300_gen:4751419
2 x Basic Wall:NLRS_21.21_WA_beton prefab d=300/320_gen:5365657 | 35 vijfendertigste verdieping | 21.21 buitenwanden - constructief, massieve wanden (Uniformat) | Model Group:NLRS_21.21_WA_wand 002 d=300_gen:4751419
3 x Basic Wall:NLRS_21.21_WA_beton prefab d=300/320_gen:4751474 | 35 vijfendertigste verdieping | 21.21 buitenwanden - constructief, massieve wanden (Uniformat) | Model Group:NLRS_21.21_WA_wand 004 d=300_gen:4751418
2 x Basic Wall:NLRS_21.21_WA_beton prefab d=300/320_gen:5365657 | 35 vijfendertigste verdieping | 21.21 buitenwanden - constructief, massieve wanden (Uniformat) | Model Group:NLRS_21.21_WA_wand 004 d=300_gen:4751418
3 x Basic Wall:NLRS_21.21_WA_beton prefab d=300/320_gen:4751476 | 35 vijfendertigste verdieping | 21.21 buitenwanden - constructief, massieve wanden (Uniformat) | Model Group:NLRS_21.21_WA_wand 004 d=300_gen:4751409
2 x Basic Wall:NLRS_21.21_WA_beton prefab d=300/320_gen:5365657 | 35 vijfendertigste verdieping | 21.21 buitenwanden - constructief, massieve wanden (Uniformat) | Model Group:NLRS_21.21_WA_wand 004 d=300_gen:4751409
Basic Wall:NLRS_21.21_WA_beton prefab d=300/320_gen:4751583 | 35 vijfendertigste verdieping | 21.21 buitenwanden - constructief, massieve wanden (Uniformat) | Model Group:NLRS_28.21_WA_3D element 002 d=300_gen:4751598
Basic Wall:NLRS_21.21_WA_beton prefab d=300/320_gen:4751585 | 35 vijfendertigste verdieping | 21.21 buitenwanden - constructief, massieve wanden (Uniformat) | Model Group:NLRS_28.21_WA_3D element 002 d=300_gen:4751598
Basic Wall:NLRS_21.21_WA_beton prefab d=300/320_gen:4751664 | 35 vijfendertigste verdieping | 21.21 buitenwanden - constructief, massieve wanden (Uniformat) | Model Group:NLRS_28.21_WA_3D element 002 d=300_gen:4751582
Basic Wall:NLRS_21.21_WA_beton prefab d=300/320_gen:4751666 | 35 vijfendertigste verdieping | 21.21 buitenwanden - constructief, massieve wanden (Uniformat) | Model Group:NLRS_28.21_WA_3D element 002 d=300_gen:4751582
Basic Wall:NLRS_21.21_WA_beton prefab d=300/320_gen:4751708 | 35 vijfendertigste verdieping | 21.21 buitenwanden - constructief, massieve wanden (Uniformat) | Model Group:NLRS_28.21_WA_3D element 001 d=300_gen:4751581
Basic Wall:NLRS_21.21_WA_beton prefab d=300/320_gen:4751711 | 35 vijfendertigste verdieping | 21.21 buitenwanden - constructief, massieve wanden (Uniformat) | Model Group:NLRS_28.21_WA_3D element 001 d=300_gen:4751581
Basic Wall:NLRS_21.21_WA_beton prefab d=300/320_gen:4751737 | 35 vijfendertigste verdieping | 21.21 buitenwanden - constructief, massieve wanden (Uniformat) | Model Group:NLRS_28.21_WA_3D element 001 d=300_gen:4751599
Basic Wall:NLRS_21.21_WA_beton prefab d=300/320_gen:4751740 | 35 vijfendertigste verdieping | 21.21 buitenwanden - constructief, massieve wanden (Uniformat) | Model Group:NLRS_28.21_WA_3D element 001 d=300_gen:4751599
Basic Wall:NLRS_21.21_WA_beton prefab d=300/320_gen:4751811 | 36 zesendertigste verdieping | 21.21 buitenwanden - constructief, massieve wanden (Uniformat) | Model Group:NLRS_21.21_WA_wand 003 d=300_gen:4751860
Basic Wall:NLRS_21.21_WA_beton prefab d=300/320_gen:4751813 | 36 zesendertigste verdieping | 21.21 buitenwanden - constructief, massieve wanden (Uniformat) | Model Group:NLRS_21.21_WA_wand 001 d=300_gen:4751859
Basic Wall:NLRS_21.21_WA_beton prefab d=300/320_gen:4751861 | 36 zesendertigste verdieping | 21.21 buitenwanden - constructief, massieve wanden (Uniformat) | Model Group:NLRS_21.21_WA_wand 003 d=300_gen:4751864
Basic Wall:NLRS_21.21_WA_beton prefab d=300/320_gen:4751865 | 36 zesendertigste verdieping | 21.21 buitenwanden - constructief, massieve wanden (Uniformat) | Model Group:NLRS_21.21_WA_wand 001 d=300_gen:4751868
3 x Basic Wall:NLRS_21.21_WA_beton prefab d=300/320_gen:4751880 | 36 zesendertigste verdieping | 21.21 buitenwanden - constructief, massieve wanden (Uniformat) | Model Group:NLRS_21.21_WA_wand 002 d=300_gen:4751858
2 x Basic Wall:NLRS_21.21_WA_beton prefab d=300/320_gen:5365657 | 36 zesendertigste verdieping | 21.21 buitenwanden - constructief, massieve wanden (Uniformat) | Model Group:NLRS_21.21_WA_wand 002 d=300_gen:4751858
3 x Basic Wall:NLRS_21.21_WA_beton prefab d=300/320_gen:4751882 | 36 zesendertigste verdieping | 21.21 buitenwanden - constructief, massieve wanden (Uniformat) | Model Group:NLRS_21.21_WA_wand 002 d=300_gen:4751851
2 x Basic Wall:NLRS_21.21_WA_beton prefab d=300/320_gen:5365657 | 36 zesendertigste verdieping | 21.21 buitenwanden - constructief, massieve wanden (Uniformat) | Model Group:NLRS_21.21_WA_wand 002 d=300_gen:4751851
3 x Basic Wall:NLRS_21.21_WA_beton prefab d=300/320_gen:4751906 | 36 zesendertigste verdieping | 21.21 buitenwanden - constructief, massieve wanden (Uniformat) | Model Group:NLRS_21.21_WA_wand 004 d=300_gen:4751850
2 x Basic Wall:NLRS_21.21_WA_beton prefab d=300/320_gen:5365657 | 36 zesendertigste verdieping | 21.21 buitenwanden - constructief, massieve wanden (Uniformat) | Model Group:NLRS_21.21_WA_wand 004 d=300_gen:4751850
3 x Basic Wall:NLRS_21.21_WA_beton prefab d=300/320_gen:4751908 | 36 zesendertigste verdieping | 21.21 buitenwanden - constructief, massieve wanden (Uniformat) | Model Group:NLRS_21.21_WA_wand 004 d=300_gen:4751841
2 x Basic Wall:NLRS_21.21_WA_beton prefab d=300/320_gen:5365657 | 36 zesendertigste verdieping | 21.21 buitenwanden - constructief, massieve wanden (Uniformat) | Model Group:NLRS_21.21_WA_wand 004 d=300_gen:4751841
Basic Wall:NLRS_21.21_WA_beton prefab d=300/320_gen:4752015 | 36 zesendertigste verdieping | 21.21 buitenwanden - constructief, massieve wanden (Uniformat) | Model Group:NLRS_28.21_WA_3D element 002 d=300_gen:4752030
Basic Wall:NLRS_21.21_WA_beton prefab d=300/320_gen:4752017 | 36 zesendertigste verdieping | 21.21 buitenwanden - constructief, massieve wanden (Uniformat) | Model Group:NLRS_28.21_WA_3D element 002 d=300_gen:4752030
Basic Wall:NLRS_21.21_WA_beton prefab d=300/320_gen:4752096 | 36 zesendertigste verdieping | 21.21 buitenwanden - constructief, massieve wanden (Uniformat) | Model Group:NLRS_28.21_WA_3D element 002 d=300_gen:4752014
Basic Wall:NLRS_21.21_WA_beton prefab d=300/320_gen:4752098 | 36 zesendertigste verdieping | 21.21 buitenwanden - constructief, massieve wanden (Uniformat) | Model Group:NLRS_28.21_WA_3D element 002 d=300_gen:4752014
Basic Wall:NLRS_21.21_WA_beton prefab d=300/320_gen:4752140 | 36 zesendertigste verdieping | 21.21 buitenwanden - constructief, massieve wanden (Uniformat) | Model Group:NLRS_28.21_WA_3D element 001 d=300_gen:4752013
Basic Wall:NLRS_21.21_WA_beton prefab d=300/320_gen:4752143 | 36 zesendertigste verdieping | 21.21 buitenwanden - constructief, massieve wanden (Uniformat) | Model Group:NLRS_28.21_WA_3D element 001 d=300_gen:4752013
Basic Wall:NLRS_21.21_WA_beton prefab d=300/320_gen:4752169 | 36 zesendertigste verdieping | 21.21 buitenwanden - constructief, massieve wanden (Uniformat) | Model Group:NLRS_28.21_WA_3D element 001 d=300_gen:4752031
Basic Wall:NLRS_21.21_WA_beton prefab d=300/320_gen:4752172 | 36 zesendertigste verdieping | 21.21 buitenwanden - constructief, massieve wanden (Uniformat) | Model Group:NLRS_28.21_WA_3D element 001 d=300_gen:4752031
Basic Wall:NLRS_21.21_WA_beton prefab d=300/320_gen:4752243 | 37 zevenendertigste verdieping | 21.21 buitenwanden - constructief, massieve wanden (Uniformat) | Model Group:NLRS_21.21_WA_wand 003 d=300_gen:4752292
Basic Wall:NLRS_21.21_WA_beton prefab d=300/320_gen:4752245 | 37 zevenendertigste verdieping | 21.21 buitenwanden - constructief, massieve wanden (Uniformat) | Model Group:NLRS_21.21_WA_wand 001 d=300_gen:4752291
Basic Wall:NLRS_21.21_WA_beton prefab d=300/320_gen:4752293 | 37 zevenendertigste verdieping | 21.21 buitenwanden - constructief, massieve wanden (Uniformat) | Model Group:NLRS_21.21_WA_wand 003 d=300_gen:4752296
Basic Wall:NLRS_21.21_WA_beton prefab d=300/320_gen:4752297 | 37 zevenendertigste verdieping | 21.21 buitenwanden - constructief, massieve wanden (Uniformat) | Model Group:NLRS_21.21_WA_wand 001 d=300_gen:4752300
3 x Basic Wall:NLRS_21.21_WA_beton prefab d=300/320_gen:4752312 | 37 zevenendertigste verdieping | 21.21 buitenwanden - constructief, massieve wanden (Uniformat) | Model Group:NLRS_21.21_WA_wand 002 d=300_gen:4752290
2 x Basic Wall:NLRS_21.21_WA_beton prefab d=300/320_gen:5365657 | 37 zevenendertigste verdieping | 21.21 buitenwanden - constructief, massieve wanden (Uniformat) | Model Group:NLRS_21.21_WA_wand 002 d=300_gen:4752290
3 x Basic Wall:NLRS_21.21_WA_beton prefab d=300/320_gen:4752314 | 37 zevenendertigste verdieping | 21.21 buitenwanden - constructief, massieve wanden (Uniformat) | Model Group:NLRS_21.21_WA_wand 002 d=300_gen:4752283
2 x Basic Wall:NLRS_21.21_WA_beton prefab d=300/320_gen:5365657 | 37 zevenendertigste verdieping | 21.21 buitenwanden - constructief, massieve wanden (Uniformat) | Model Group:NLRS_21.21_WA_wand 002 d=300_gen:4752283
3 x Basic Wall:NLRS_21.21_WA_beton prefab d=300/320_gen:4752338 | 37 zevenendertigste verdieping | 21.21 buitenwanden - constructief, massieve wanden (Uniformat) | Model Group:NLRS_21.21_WA_wand 004 d=300_gen:4752282
2 x Basic Wall:NLRS_21.21_WA_beton prefab d=300/320_gen:5365657 | 37 zevenendertigste verdieping | 21.21 buitenwanden - constructief, massieve wanden (Uniformat) | Model Group:NLRS_21.21_WA_wand 004 d=300_gen:4752282
3 x Basic Wall:NLRS_21.21_WA_beton prefab d=300/320_gen:4752340 | 37 zevenendertigste verdieping | 21.21 buitenwanden - constructief, massieve wanden (Uniformat) | Model Group:NLRS_21.21_WA_wand 004 d=300_gen:4752273
2 x Basic Wall:NLRS_21.21_WA_beton prefab d=300/320_gen:5365657 | 37 zevenendertigste verdieping | 21.21 buitenwanden - constructief, massieve wanden (Uniformat) | Model Group:NLRS_21.21_WA_wand 004 d=300_gen:4752273
Basic Wall:NLRS_21.21_WA_beton prefab d=300/320_gen:4752447 | 37 zevenendertigste verdieping | 21.21 buitenwanden - constructief, massieve wanden (Uniformat) | Model Group:NLRS_28.21_WA_3D element 002 d=300_gen:4752462
Basic Wall:NLRS_21.21_WA_beton prefab d=300/320_gen:4752449 | 37 zevenendertigste verdieping | 21.21 buitenwanden - constructief, massieve wanden (Uniformat) | Model Group:NLRS_28.21_WA_3D element 002 d=300_gen:4752462
Basic Wall:NLRS_21.21_WA_beton prefab d=300/320_gen:4752528 | 37 zevenendertigste verdieping | 21.21 buitenwanden - constructief, massieve wanden (Uniformat) | Model Group:NLRS_28.21_WA_3D element 002 d=300_gen:4752446
Basic Wall:NLRS_21.21_WA_beton prefab d=300/320_gen:4752530 | 37 zevenendertigste verdieping | 21.21 buitenwanden - constructief, massieve wanden (Uniformat) | Model Group:NLRS_28.21_WA_3D element 002 d=300_gen:4752446
Basic Wall:NLRS_21.21_WA_beton prefab d=300/320_gen:4752572 | 37 zevenendertigste verdieping | 21.21 buitenwanden - constructief, massieve wanden (Uniformat) | Model Group:NLRS_28.21_WA_3D element 001 d=300_gen:4752445
Basic Wall:NLRS_21.21_WA_beton prefab d=300/320_gen:4752575 | 37 zevenendertigste verdieping | 21.21 buitenwanden - constructief, massieve wanden (Uniformat) | Model Group:NLRS_28.21_WA_3D element 001 d=300_gen:4752445
Basic Wall:NLRS_21.21_WA_beton prefab d=300/320_gen:4752601 | 37 zevenendertigste verdieping | 21.21 buitenwanden - constructief, massieve wanden (Uniformat) | Model Group:NLRS_28.21_WA_3D element 001 d=300_gen:4752463
Basic Wall:NLRS_21.21_WA_beton prefab d=300/320_gen:4752604 | 37 zevenendertigste verdieping | 21.21 buitenwanden - constructief, massieve wanden (Uniformat) | Model Group:NLRS_28.21_WA_3D element 001 d=300_gen:4752463
Basic Wall:NLRS_21.21_WA_beton prefab d=300/320_gen:4752675 | 38 achtendertigste verdieping | 21.21 buitenwanden - constructief, massieve wanden (Uniformat) | Model Group:NLRS_21.21_WA_wand 003 d=300_gen:4752724
Basic Wall:NLRS_21.21_WA_beton prefab d=300/320_gen:4752677 | 38 achtendertigste verdieping | 21.21 buitenwanden - constructief, massieve wanden (Uniformat) | Model Group:NLRS_21.21_WA_wand 001 d=300_gen:4752723
Basic Wall:NLRS_21.21_WA_beton prefab d=300/320_gen:4752725 | 38 achtendertigste verdieping | 21.21 buitenwanden - constructief, massieve wanden (Uniformat) | Model Group:NLRS_21.21_WA_wand 003 d=300_gen:4752728
Basic Wall:NLRS_21.21_WA_beton prefab d=300/320_gen:4752729 | 38 achtendertigste verdieping | 21.21 buitenwanden - constructief, massieve wanden (Uniformat) | Model Group:NLRS_21.21_WA_wand 001 d=300_gen:4752732
3 x Basic Wall:NLRS_21.21_WA_beton prefab d=300/320_gen:4752744 | 38 achtendertigste verdieping | 21.21 buitenwanden - constructief, massieve wanden (Uniformat) | Model Group:NLRS_21.21_WA_wand 002 d=300_gen:4752722
2 x Basic Wall:NLRS_21.21_WA_beton prefab d=300/320_gen:5365657 | 38 achtendertigste verdieping | 21.21 buitenwanden - constructief, massieve wanden (Uniformat) | Model Group:NLRS_21.21_WA_wand 002 d=300_gen:4752722
3 x Basic Wall:NLRS_21.21_WA_beton prefab d=300/320_gen:4752746 | 38 achtendertigste verdieping | 21.21 buitenwanden - constructief, massieve wanden (Uniformat) | Model Group:NLRS_21.21_WA_wand 002 d=300_gen:4752715
2 x Basic Wall:NLRS_21.21_WA_beton prefab d=300/320_gen:5365657 | 38 achtendertigste verdieping | 21.21 buitenwanden - constructief, massieve wanden (Uniformat) | Model Group:NLRS_21.21_WA_wand 002 d=300_gen:4752715
3 x Basic Wall:NLRS_21.21_WA_beton prefab d=300/320_gen:4752770 | 38 achtendertigste verdieping | 21.21 buitenwanden - constructief, massieve wanden (Uniformat) | Model Group:NLRS_21.21_WA_wand 004 d=300_gen:4752714
2 x Basic Wall:NLRS_21.21_WA_beton prefab d=300/320_gen:5365657 | 38 achtendertigste verdieping | 21.21 buitenwanden - constructief, massieve wanden (Uniformat) | Model Group:NLRS_21.21_WA_wand 004 d=300_gen:4752714
3 x Basic Wall:NLRS_21.21_WA_beton prefab d=300/320_gen:4752772 | 38 achtendertigste verdieping | 21.21 buitenwanden - constructief, massieve wanden (Uniformat) | Model Group:NLRS_21.21_WA_wand 004 d=300_gen:4752705
2 x Basic Wall:NLRS_21.21_WA_beton prefab d=300/320_gen:5365657 | 38 achtendertigste verdieping | 21.21 buitenwanden - constructief, massieve wanden (Uniformat) | Model Group:NLRS_21.21_WA_wand 004 d=300_gen:4752705
Basic Wall:NLRS_21.21_WA_beton prefab d=300/320_gen:4752879 | 38 achtendertigste verdieping | 21.21 buitenwanden - constructief, massieve wanden (Uniformat) | Model Group:NLRS_28.21_WA_3D element 002 d=300_gen:4752894
Basic Wall:NLRS_21.21_WA_beton prefab d=300/320_gen:4752881 | 38 achtendertigste verdieping | 21.21 buitenwanden - constructief, massieve wanden (Uniformat) | Model Group:NLRS_28.21_WA_3D element 002 d=300_gen:4752894
Basic Wall:NLRS_21.21_WA_beton prefab d=300/320_gen:4752960 | 38 achtendertigste verdieping | 21.21 buitenwanden - constructief, massieve wanden (Uniformat) | Model Group:NLRS_28.21_WA_3D element 002 d=300_gen:4752878
Basic Wall:NLRS_21.21_WA_beton prefab d=300/320_gen:4752962 | 38 achtendertigste verdieping | 21.21 buitenwanden - constructief, massieve wanden (Uniformat) | Model Group:NLRS_28.21_WA_3D element 002 d=300_gen:4752878
Basic Wall:NLRS_21.21_WA_beton prefab d=300/320_gen:4753004 | 38 achtendertigste verdieping | 21.21 buitenwanden - constructief, massieve wanden (Uniformat) | Model Group:NLRS_28.21_WA_3D element 001 d=300_gen:4752877
Basic Wall:NLRS_21.21_WA_beton prefab d=300/320_gen:4753007 | 38 achtendertigste verdieping | 21.21 buitenwanden - constructief, massieve wanden (Uniformat) | Model Group:NLRS_28.21_WA_3D element 001 d=300_gen:4752877
Basic Wall:NLRS_21.21_WA_beton prefab d=300/320_gen:4753033 | 38 achtendertigste verdieping | 21.21 buitenwanden - constructief, massieve wanden (Uniformat) | Model Group:NLRS_28.21_WA_3D element 001 d=300_gen:4752895
Basic Wall:NLRS_21.21_WA_beton prefab d=300/320_gen:4753036 | 38 achtendertigste verdieping | 21.21 buitenwanden - constructief, massieve wanden (Uniformat) | Model Group:NLRS_28.21_WA_3D element 001 d=300_gen:4752895
Basic Wall:NLRS_21.21_WA_beton prefab d=300/320_gen:4753107 | 39 negenendertigste verdieping | 21.21 buitenwanden - constructief, massieve wanden (Uniformat) | Model Group:NLRS_21.21_WA_wand 003 d=300_gen:4753156
Basic Wall:NLRS_21.21_WA_beton prefab d=300/320_gen:4753109 | 39 negenendertigste verdieping | 21.21 buitenwanden - constructief, massieve wanden (Uniformat) | Model Group:NLRS_21.21_WA_wand 001 d=300_gen:4753155
Basic Wall:NLRS_21.21_WA_beton prefab d=300/320_gen:4753157 | 39 negenendertigste verdieping | 21.21 buitenwanden - constructief, massieve wanden (Uniformat) | Model Group:NLRS_21.21_WA_wand 003 d=300_gen:4753160
Basic Wall:NLRS_21.21_WA_beton prefab d=300/320_gen:4753161 | 39 negenendertigste verdieping | 21.21 buitenwanden - constructief, massieve wanden (Uniformat) | Model Group:NLRS_21.21_WA_wand 001 d=300_gen:4753164
3 x Basic Wall:NLRS_21.21_WA_beton prefab d=300/320_gen:4753176 | 39 negenendertigste verdieping | 21.21 buitenwanden - constructief, massieve wanden (Uniformat) | Model Group:NLRS_21.21_WA_wand 002 d=300_gen:4753154
2 x Basic Wall:NLRS_21.21_WA_beton prefab d=300/320_gen:5365657 | 39 negenendertigste verdieping | 21.21 buitenwanden - constructief, massieve wanden (Uniformat) | Model Group:NLRS_21.21_WA_wand 002 d=300_gen:4753154
3 x Basic Wall:NLRS_21.21_WA_beton prefab d=300/320_gen:4753178 | 39 negenendertigste verdieping | 21.21 buitenwanden - constructief, massieve wanden (Uniformat) | Model Group:NLRS_21.21_WA_wand 002 d=300_gen:4753147
2 x Basic Wall:NLRS_21.21_WA_beton prefab d=300/320_gen:5365657 | 39 negenendertigste verdieping | 21.21 buitenwanden - constructief, massieve wanden (Uniformat) | Model Group:NLRS_21.21_WA_wand 002 d=300_gen:4753147
3 x Basic Wall:NLRS_21.21_WA_beton prefab d=300/320_gen:4753202 | 39 negenendertigste verdieping | 21.21 buitenwanden - constructief, massieve wanden (Uniformat) | Model Group:NLRS_21.21_WA_wand 004 d=300_gen:4753146
2 x Basic Wall:NLRS_21.21_WA_beton prefab d=300/320_gen:5365657 | 39 negenendertigste verdieping | 21.21 buitenwanden - constructief, massieve wanden (Uniformat) | Model Group:NLRS_21.21_WA_wand 004 d=300_gen:4753146
3 x Basic Wall:NLRS_21.21_WA_beton prefab d=300/320_gen:4753204 | 39 negenendertigste verdieping | 21.21 buitenwanden - constructief, massieve wanden (Uniformat) | Model Group:NLRS_21.21_WA_wand 004 d=300_gen:4753137
2 x Basic Wall:NLRS_21.21_WA_beton prefab d=300/320_gen:5365657 | 39 negenendertigste verdieping | 21.21 buitenwanden - constructief, massieve wanden (Uniformat) | Model Group:NLRS_21.21_WA_wand 004 d=300_gen:4753137
Basic Wall:NLRS_21.21_WA_beton prefab d=300/320_gen:4753311 | 39 negenendertigste verdieping | 21.21 buitenwanden - constructief, massieve wanden (Uniformat) | Model Group:NLRS_28.21_WA_3D element 002 d=300_gen:4753326
Basic Wall:NLRS_21.21_WA_beton prefab d=300/320_gen:4753313 | 39 negenendertigste verdieping | 21.21 buitenwanden - constructief, massieve wanden (Uniformat) | Model Group:NLRS_28.21_WA_3D element 002 d=300_gen:4753326
Basic Wall:NLRS_21.21_WA_beton prefab d=300/320_gen:4753392 | 39 negenendertigste verdieping | 21.21 buitenwanden - constructief, massieve wanden (Uniformat) | Model Group:NLRS_28.21_WA_3D element 002 d=300_gen:4753310
Basic Wall:NLRS_21.21_WA_beton prefab d=300/320_gen:4753394 | 39 negenendertigste verdieping | 21.21 buitenwanden - constructief, massieve wanden (Uniformat) | Model Group:NLRS_28.21_WA_3D element 002 d=300_gen:4753310
Basic Wall:NLRS_21.21_WA_beton prefab d=300/320_gen:4753436 | 39 negenendertigste verdieping | 21.21 buitenwanden - constructief, massieve wanden (Uniformat) | Model Group:NLRS_28.21_WA_3D element 001 d=300_gen:4753309
Basic Wall:NLRS_21.21_WA_beton prefab d=300/320_gen:4753439 | 39 negenendertigste verdieping | 21.21 buitenwanden - constructief, massieve wanden (Uniformat) | Model Group:NLRS_28.21_WA_3D element 001 d=300_gen:4753309
Basic Wall:NLRS_21.21_WA_beton prefab d=300/320_gen:4753465 | 39 negenendertigste verdieping | 21.21 buitenwanden - constructief, massieve wanden (Uniformat) | Model Group:NLRS_28.21_WA_3D element 001 d=300_gen:4753327
Basic Wall:NLRS_21.21_WA_beton prefab d=300/320_gen:4753468 | 39 negenendertigste verdieping | 21.21 buitenwanden - constructief, massieve wanden (Uniformat) | Model Group:NLRS_28.21_WA_3D element 001 d=300_gen:4753327
Basic Wall:NLRS_21.21_WA_beton prefab d=300/320_gen:4753539 | 40 veertigste verdieping | 21.21 buitenwanden - constructief, massieve wanden (Uniformat) | Model Group:NLRS_21.21_WA_wand 003 d=300_gen:4753588
Basic Wall:NLRS_21.21_WA_beton prefab d=300/320_gen:4753541 | 40 veertigste verdieping | 21.21 buitenwanden - constructief, massieve wanden (Uniformat) | Model Group:NLRS_21.21_WA_wand 001 d=300_gen:4753587
Basic Wall:NLRS_21.21_WA_beton prefab d=300/320_gen:4753589 | 40 veertigste verdieping | 21.21 buitenwanden - constructief, massieve wanden (Uniformat) | Model Group:NLRS_21.21_WA_wand 003 d=300_gen:4753592
Basic Wall:NLRS_21.21_WA_beton prefab d=300/320_gen:4753593 | 40 veertigste verdieping | 21.21 buitenwanden - constructief, massieve wanden (Uniformat) | Model Group:NLRS_21.21_WA_wand 001 d=300_gen:4753596
3 x Basic Wall:NLRS_21.21_WA_beton prefab d=300/320_gen:4753608 | 40 veertigste verdieping | 21.21 buitenwanden - constructief, massieve wanden (Uniformat) | Model Group:NLRS_21.21_WA_wand 002 d=300_gen:4753586
2 x Basic Wall:NLRS_21.21_WA_beton prefab d=300/320_gen:5365657 | 40 veertigste verdieping | 21.21 buitenwanden - constructief, massieve wanden (Uniformat) | Model Group:NLRS_21.21_WA_wand 002 d=300_gen:4753586
3 x Basic Wall:NLRS_21.21_WA_beton prefab d=300/320_gen:4753610 | 40 veertigste verdieping | 21.21 buitenwanden - constructief, massieve wanden (Uniformat) | Model Group:NLRS_21.21_WA_wand 002 d=300_gen:4753579
2 x Basic Wall:NLRS_21.21_WA_beton prefab d=300/320_gen:5365657 | 40 veertigste verdieping | 21.21 buitenwanden - constructief, massieve wanden (Uniformat) | Model Group:NLRS_21.21_WA_wand 002 d=300_gen:4753579
3 x Basic Wall:NLRS_21.21_WA_beton prefab d=300/320_gen:4753634 | 40 veertigste verdieping | 21.21 buitenwanden - constructief, massieve wanden (Uniformat) | Model Group:NLRS_21.21_WA_wand 004 d=300_gen:4753578
2 x Basic Wall:NLRS_21.21_WA_beton prefab d=300/320_gen:5365657 | 40 veertigste verdieping | 21.21 buitenwanden - constructief, massieve wanden (Uniformat) | Model Group:NLRS_21.21_WA_wand 004 d=300_gen:4753578
3 x Basic Wall:NLRS_21.21_WA_beton prefab d=300/320_gen:4753636 | 40 veertigste verdieping | 21.21 buitenwanden - constructief, massieve wanden (Uniformat) | Model Group:NLRS_21.21_WA_wand 004 d=300_gen:4753569
2 x Basic Wall:NLRS_21.21_WA_beton prefab d=300/320_gen:5365657 | 40 veertigste verdieping | 21.21 buitenwanden - constructief, massieve wanden (Uniformat) | Model Group:NLRS_21.21_WA_wand 004 d=300_gen:4753569
Basic Wall:NLRS_21.21_WA_beton prefab d=300/320_gen:4753743 | 40 veertigste verdieping | 21.21 buitenwanden - constructief, massieve wanden (Uniformat) | Model Group:NLRS_28.21_WA_3D element 002 d=300_gen:4753758
Basic Wall:NLRS_21.21_WA_beton prefab d=300/320_gen:4753745 | 40 veertigste verdieping | 21.21 buitenwanden - constructief, massieve wanden (Uniformat) | Model Group:NLRS_28.21_WA_3D element 002 d=300_gen:4753758
Basic Wall:NLRS_21.21_WA_beton prefab d=300/320_gen:4753824 | 40 veertigste verdieping | 21.21 buitenwanden - constructief, massieve wanden (Uniformat) | Model Group:NLRS_28.21_WA_3D element 002 d=300_gen:4753742
Basic Wall:NLRS_21.21_WA_beton prefab d=300/320_gen:4753826 | 40 veertigste verdieping | 21.21 buitenwanden - constructief, massieve wanden (Uniformat) | Model Group:NLRS_28.21_WA_3D element 002 d=300_gen:4753742
Basic Wall:NLRS_21.21_WA_beton prefab d=300/320_gen:4753868 | 40 veertigste verdieping | 21.21 buitenwanden - constructief, massieve wanden (Uniformat) | Model Group:NLRS_28.21_WA_3D element 001 d=300_gen:4753741
Basic Wall:NLRS_21.21_WA_beton prefab d=300/320_gen:4753871 | 40 veertigste verdieping | 21.21 buitenwanden - constructief, massieve wanden (Uniformat) | Model Group:NLRS_28.21_WA_3D element 001 d=300_gen:4753741
Basic Wall:NLRS_21.21_WA_beton prefab d=300/320_gen:4753897 | 40 veertigste verdieping | 21.21 buitenwanden - constructief, massieve wanden (Uniformat) | Model Group:NLRS_28.21_WA_3D element 001 d=300_gen:4753759
Basic Wall:NLRS_21.21_WA_beton prefab d=300/320_gen:4753900 | 40 veertigste verdieping | 21.21 buitenwanden - constructief, massieve wanden (Uniformat) | Model Group:NLRS_28.21_WA_3D element 001 d=300_gen:4753759
Basic Wall:NLRS_21.21_WA_beton prefab d=300/320_gen:4778007 | 22 tweeëntwintigste verdieping | 21.21 buitenwanden - constructief, massieve wanden (Uniformat) | Model Group:NLRS_21.21_WA_wand 003 d=300_gen:4778056
Basic Wall:NLRS_21.21_WA_beton prefab d=300/320_gen:4778009 | 22 tweeëntwintigste verdieping | 21.21 buitenwanden - constructief, massieve wanden (Uniformat) | Model Group:NLRS_21.21_WA_wand 001 d=300_gen:4778055
Basic Wall:NLRS_21.21_WA_beton prefab d=300/320_gen:4778057 | 22 tweeëntwintigste verdieping | 21.21 buitenwanden - constructief, massieve wanden (Uniformat) | Model Group:NLRS_21.21_WA_wand 003 d=300_gen:4778060
Basic Wall:NLRS_21.21_WA_beton prefab d=300/320_gen:4778061 | 22 tweeëntwintigste verdieping | 21.21 buitenwanden - constructief, massieve wanden (Uniformat) | Model Group:NLRS_21.21_WA_wand 001 d=300_gen:4778064
3 x Basic Wall:NLRS_21.21_WA_beton prefab d=300/320_gen:4778076 | 22 tweeëntwintigste verdieping | 21.21 buitenwanden - constructief, massieve wanden (Uniformat) | Model Group:NLRS_21.21_WA_wand 002 d=300_gen:4778054
2 x Basic Wall:NLRS_21.21_WA_beton prefab d=300/320_gen:5365657 | 22 tweeëntwintigste verdieping | 21.21 buitenwanden - constructief, massieve wanden (Uniformat) | Model Group:NLRS_21.21_WA_wand 002 d=300_gen:4778054
3 x Basic Wall:NLRS_21.21_WA_beton prefab d=300/320_gen:4778078 | 22 tweeëntwintigste verdieping | 21.21 buitenwanden - constructief, massieve wanden (Uniformat) | Model Group:NLRS_21.21_WA_wand 002 d=300_gen:4778047
2 x Basic Wall:NLRS_21.21_WA_beton prefab d=300/320_gen:5365657 | 22 tweeëntwintigste verdieping | 21.21 buitenwanden - constructief, massieve wanden (Uniformat) | Model Group:NLRS_21.21_WA_wand 002 d=300_gen:4778047
3 x Basic Wall:NLRS_21.21_WA_beton prefab d=300/320_gen:4778102 | 22 tweeëntwintigste verdieping | 21.21 buitenwanden - constructief, massieve wanden (Uniformat) | Model Group:NLRS_21.21_WA_wand 004 d=300_gen:4778046
2 x Basic Wall:NLRS_21.21_WA_beton prefab d=300/320_gen:5365657 | 22 tweeëntwintigste verdieping | 21.21 buitenwanden - constructief, massieve wanden (Uniformat) | Model Group:NLRS_21.21_WA_wand 004 d=300_gen:4778046
3 x Basic Wall:NLRS_21.21_WA_beton prefab d=300/320_gen:4778104 | 22 tweeëntwintigste verdieping | 21.21 buitenwanden - constructief, massieve wanden (Uniformat) | Model Group:NLRS_21.21_WA_wand 004 d=300_gen:4778037
2 x Basic Wall:NLRS_21.21_WA_beton prefab d=300/320_gen:5365657 | 22 tweeëntwintigste verdieping | 21.21 buitenwanden - constructief, massieve wanden (Uniformat) | Model Group:NLRS_21.21_WA_wand 004 d=300_gen:4778037
Basic Wall:NLRS_21.21_WA_beton prefab d=300/320_gen:4778211 | 22 tweeëntwintigste verdieping | 21.21 buitenwanden - constructief, massieve wanden (Uniformat) | Model Group:NLRS_28.21_WA_3D element 002 d=300_gen:4778226
Basic Wall:NLRS_21.21_WA_beton prefab d=300/320_gen:4778213 | 22 tweeëntwintigste verdieping | 21.21 buitenwanden - constructief, massieve wanden (Uniformat) | Model Group:NLRS_28.21_WA_3D element 002 d=300_gen:4778226
Basic Wall:NLRS_21.21_WA_beton prefab d=300/320_gen:4778292 | 22 tweeëntwintigste verdieping | 21.21 buitenwanden - constructief, massieve wanden (Uniformat) | Model Group:NLRS_28.21_WA_3D element 002 d=300_gen:4778210
Basic Wall:NLRS_21.21_WA_beton prefab d=300/320_gen:4778294 | 22 tweeëntwintigste verdieping | 21.21 buitenwanden - constructief, massieve wanden (Uniformat) | Model Group:NLRS_28.21_WA_3D element 002 d=300_gen:4778210
Basic Wall:NLRS_21.21_WA_beton prefab d=300/320_gen:4778336 | 22 tweeëntwintigste verdieping | 21.21 buitenwanden - constructief, massieve wanden (Uniformat) | Model Group:NLRS_28.21_WA_3D element 001 d=300_gen:4778209
Basic Wall:NLRS_21.21_WA_beton prefab d=300/320_gen:4778339 | 22 tweeëntwintigste verdieping | 21.21 buitenwanden - constructief, massieve wanden (Uniformat) | Model Group:NLRS_28.21_WA_3D element 001 d=300_gen:4778209
Basic Wall:NLRS_21.21_WA_beton prefab d=300/320_gen:4778365 | 22 tweeëntwintigste verdieping | 21.21 buitenwanden - constructief, massieve wanden (Uniformat) | Model Group:NLRS_28.21_WA_3D element 001 d=300_gen:4778227
Basic Wall:NLRS_21.21_WA_beton prefab d=300/320_gen:4778368 | 22 tweeëntwintigste verdieping | 21.21 buitenwanden - constructief, massieve wanden (Uniformat) | Model Group:NLRS_28.21_WA_3D element 001 d=300_gen:4778227
Basic Wall:NLRS_21.21_WA_beton prefab d=300/320_gen:4779590 | 23 drieëntwintigste verdieping | 21.21 buitenwanden - constructief, massieve wanden (Uniformat) | Model Group:NLRS_21.21_WA_wand 003 d=300_gen:4779639
Basic Wall:NLRS_21.21_WA_beton prefab d=300/320_gen:4779592 | 23 drieëntwintigste verdieping | 21.21 buitenwanden - constructief, massieve wanden (Uniformat) | Model Group:NLRS_21.21_WA_wand 001 d=300_gen:4779638
Basic Wall:NLRS_21.21_WA_beton prefab d=300/320_gen:4779640 | 23 drieëntwintigste verdieping | 21.21 buitenwanden - constructief, massieve wanden (Uniformat) | Model Group:NLRS_21.21_WA_wand 003 d=300_gen:4779643
Basic Wall:NLRS_21.21_WA_beton prefab d=300/320_gen:4779644 | 23 drieëntwintigste verdieping | 21.21 buitenwanden - constructief, massieve wanden (Uniformat) | Model Group:NLRS_21.21_WA_wand 001 d=300_gen:4779647
3 x Basic Wall:NLRS_21.21_WA_beton prefab d=300/320_gen:4779659 | 23 drieëntwintigste verdieping | 21.21 buitenwanden - constructief, massieve wanden (Uniformat) | Model Group:NLRS_21.21_WA_wand 002 d=300_gen:4779637
2 x Basic Wall:NLRS_21.21_WA_beton prefab d=300/320_gen:5365657 | 23 drieëntwintigste verdieping | 21.21 buitenwanden - constructief, massieve wanden (Uniformat) | Model Group:NLRS_21.21_WA_wand 002 d=300_gen:4779637
3 x Basic Wall:NLRS_21.21_WA_beton prefab d=300/320_gen:4779661 | 23 drieëntwintigste verdieping | 21.21 buitenwanden - constructief, massieve wanden (Uniformat) | Model Group:NLRS_21.21_WA_wand 002 d=300_gen:4779630
2 x Basic Wall:NLRS_21.21_WA_beton prefab d=300/320_gen:5365657 | 23 drieëntwintigste verdieping | 21.21 buitenwanden - constructief, massieve wanden (Uniformat) | Model Group:NLRS_21.21_WA_wand 002 d=300_gen:4779630
3 x Basic Wall:NLRS_21.21_WA_beton prefab d=300/320_gen:4779685 | 23 drieëntwintigste verdieping | 21.21 buitenwanden - constructief, massieve wanden (Uniformat) | Model Group:NLRS_21.21_WA_wand 004 d=300_gen:4779629
2 x Basic Wall:NLRS_21.21_WA_beton prefab d=300/320_gen:5365657 | 23 drieëntwintigste verdieping | 21.21 buitenwanden - constructief, massieve wanden (Uniformat) | Model Group:NLRS_21.21_WA_wand 004 d=300_gen:4779629
3 x Basic Wall:NLRS_21.21_WA_beton prefab d=300/320_gen:4779687 | 23 drieëntwintigste verdieping | 21.21 buitenwanden - constructief, massieve wanden (Uniformat) | Model Group:NLRS_21.21_WA_wand 004 d=300_gen:4779620
2 x Basic Wall:NLRS_21.21_WA_beton prefab d=300/320_gen:5365657 | 23 drieëntwintigste verdieping | 21.21 buitenwanden - constructief, massieve wanden (Uniformat) | Model Group:NLRS_21.21_WA_wand 004 d=300_gen:4779620
Basic Wall:NLRS_21.21_WA_beton prefab d=300/320_gen:4779794 | 23 drieëntwintigste verdieping | 21.21 buitenwanden - constructief, massieve wanden (Uniformat) | Model Group:NLRS_28.21_WA_3D element 002 d=300_gen:4779809
Basic Wall:NLRS_21.21_WA_beton prefab d=300/320_gen:4779796 | 23 drieëntwintigste verdieping | 21.21 buitenwanden - constructief, massieve wanden (Uniformat) | Model Group:NLRS_28.21_WA_3D element 002 d=300_gen:4779809
Basic Wall:NLRS_21.21_WA_beton prefab d=300/320_gen:4779875 | 23 drieëntwintigste verdieping | 21.21 buitenwanden - constructief, massieve wanden (Uniformat) | Model Group:NLRS_28.21_WA_3D element 002 d=300_gen:4779793
Basic Wall:NLRS_21.21_WA_beton prefab d=300/320_gen:4779877 | 23 drieëntwintigste verdieping | 21.21 buitenwanden - constructief, massieve wanden (Uniformat) | Model Group:NLRS_28.21_WA_3D element 002 d=300_gen:4779793
Basic Wall:NLRS_21.21_WA_beton prefab d=300/320_gen:4779919 | 23 drieëntwintigste verdieping | 21.21 buitenwanden - constructief, massieve wanden (Uniformat) | Model Group:NLRS_28.21_WA_3D element 001 d=300_gen:4779792
Basic Wall:NLRS_21.21_WA_beton prefab d=300/320_gen:4779922 | 23 drieëntwintigste verdieping | 21.21 buitenwanden - constructief, massieve wanden (Uniformat) | Model Group:NLRS_28.21_WA_3D element 001 d=300_gen:4779792
Basic Wall:NLRS_21.21_WA_beton prefab d=300/320_gen:4779948 | 23 drieëntwintigste verdieping | 21.21 buitenwanden - constructief, massieve wanden (Uniformat) | Model Group:NLRS_28.21_WA_3D element 001 d=300_gen:4779810
Basic Wall:NLRS_21.21_WA_beton prefab d=300/320_gen:4779951 | 23 drieëntwintigste verdieping | 21.21 buitenwanden - constructief, massieve wanden (Uniformat) | Model Group:NLRS_28.21_WA_3D element 001 d=300_gen:4779810
Basic Wall:NLRS_22.21_WA_beton prefab d=300_gen:4783689 | 41 eenenveertigste verdieping | 22.21 binnenwanden - constructief, massieve wanden (Uniformat) | Model Group:NLRS_01.00_verdieping type M_gen:4783248
Basic Wall:NLRS_22.21_WA_beton prefab d=300_gen:4783691 | 41 eenenveertigste verdieping | 22.21 binnenwanden - constructief, massieve wanden (Uniformat) | Model Group:NLRS_01.00_verdieping type M_gen:4783248
2 x Basic Wall:NLRS_22.21_WA_beton prefab d=300_gen:4783693 | 41 eenenveertigste verdieping | 22.21 binnenwanden - constructief, massieve wanden (Uniformat) | Model Group:NLRS_01.00_verdieping type M_gen:4783248
Basic Wall:NLRS_21.21_WA_beton prefab d=300/320_gen:4783707 | 41 eenenveertigste verdieping | 21.21 buitenwanden - constructief, massieve wanden (Uniformat) | Model Group:NLRS_21.21_WA_wand 003 d=300_gen:4783756
Basic Wall:NLRS_21.21_WA_beton prefab d=300/320_gen:4783709 | 41 eenenveertigste verdieping | 21.21 buitenwanden - constructief, massieve wanden (Uniformat) | Model Group:NLRS_21.21_WA_wand 001 d=300_gen:4783755
Basic Wall:NLRS_21.21_WA_beton prefab d=300/320_gen:4783757 | 41 eenenveertigste verdieping | 21.21 buitenwanden - constructief, massieve wanden (Uniformat) | Model Group:NLRS_21.21_WA_wand 003 d=300_gen:4783760
Basic Wall:NLRS_21.21_WA_beton prefab d=300/320_gen:4783761 | 41 eenenveertigste verdieping | 21.21 buitenwanden - constructief, massieve wanden (Uniformat) | Model Group:NLRS_21.21_WA_wand 001 d=300_gen:4783764
3 x Basic Wall:NLRS_21.21_WA_beton prefab d=300/320_gen:4783776 | 41 eenenveertigste verdieping | 21.21 buitenwanden - constructief, massieve wanden (Uniformat) | Model Group:NLRS_21.21_WA_wand 002 d=300_gen:4783754
2 x Basic Wall:NLRS_21.21_WA_beton prefab d=300/320_gen:5365657 | 41 eenenveertigste verdieping | 21.21 buitenwanden - constructief, massieve wanden (Uniformat) | Model Group:NLRS_21.21_WA_wand 002 d=300_gen:4783754
3 x Basic Wall:NLRS_21.21_WA_beton prefab d=300/320_gen:4783778 | 41 eenenveertigste verdieping | 21.21 buitenwanden - constructief, massieve wanden (Uniformat) | Model Group:NLRS_21.21_WA_wand 002 d=300_gen:4783747
2 x Basic Wall:NLRS_21.21_WA_beton prefab d=300/320_gen:5365657 | 41 eenenveertigste verdieping | 21.21 buitenwanden - constructief, massieve wanden (Uniformat) | Model Group:NLRS_21.21_WA_wand 002 d=300_gen:4783747
3 x Basic Wall:NLRS_21.21_WA_beton prefab d=300/320_gen:4783802 | 41 eenenveertigste verdieping | 21.21 buitenwanden - constructief, massieve wanden (Uniformat) | Model Group:NLRS_21.21_WA_wand 004 d=300_gen:4783746
2 x Basic Wall:NLRS_21.21_WA_beton prefab d=300/320_gen:5365657 | 41 eenenveertigste verdieping | 21.21 buitenwanden - constructief, massieve wanden (Uniformat) | Model Group:NLRS_21.21_WA_wand 004 d=300_gen:4783746
3 x Basic Wall:NLRS_21.21_WA_beton prefab d=300/320_gen:4783804 | 41 eenenveertigste verdieping | 21.21 buitenwanden - constructief, massieve wanden (Uniformat) | Model Group:NLRS_21.21_WA_wand 004 d=300_gen:4783737
2 x Basic Wall:NLRS_21.21_WA_beton prefab d=300/320_gen:5365657 | 41 eenenveertigste verdieping | 21.21 buitenwanden - constructief, massieve wanden (Uniformat) | Model Group:NLRS_21.21_WA_wand 004 d=300_gen:4783737
Basic Wall:NLRS_21.21_WA_beton prefab d=300/320_gen:4783911 | 41 eenenveertigste verdieping | 21.21 buitenwanden - constructief, massieve wanden (Uniformat) | Model Group:NLRS_28.21_WA_3D element 002 d=300_gen:4783926
Basic Wall:NLRS_21.21_WA_beton prefab d=300/320_gen:4783913 | 41 eenenveertigste verdieping | 21.21 buitenwanden - constructief, massieve wanden (Uniformat) | Model Group:NLRS_28.21_WA_3D element 002 d=300_gen:4783926
Basic Wall:NLRS_22.21_WA_beton prefab d=300_gen:4783973 | 41 eenenveertigste verdieping | 22.21 binnenwanden - constructief, massieve wanden (Uniformat) | Model Group:NLRS_01.00_verdieping type M_gen:4783248
4 x Basic Wall:NLRS_22.21_WA_beton prefab d=300_gen:4472952 | 41 eenenveertigste verdieping | 22.21 binnenwanden - constructief, massieve wanden (Uniformat) | Model Group:NLRS_01.00_verdieping type M_gen:4783248
Basic Wall:NLRS_22.21_WA_beton prefab d=300_gen:4783977 | 41 eenenveertigste verdieping | 22.21 binnenwanden - constructief, massieve wanden (Uniformat) | Model Group:NLRS_01.00_verdieping type M_gen:4783248
Basic Wall:NLRS_22.21_WA_beton prefab d=300_gen:4783981 | 41 eenenveertigste verdieping | 22.21 binnenwanden - constructief, massieve wanden (Uniformat) | Model Group:NLRS_01.00_verdieping type M_gen:4783248
Basic Wall:NLRS_21.21_WA_beton prefab d=300/320_gen:4783992 | 41 eenenveertigste verdieping | 21.21 buitenwanden - constructief, massieve wanden (Uniformat) | Model Group:NLRS_28.21_WA_3D element 002 d=300_gen:4783910
Basic Wall:NLRS_21.21_WA_beton prefab d=300/320_gen:4783994 | 41 eenenveertigste verdieping | 21.21 buitenwanden - constructief, massieve wanden (Uniformat) | Model Group:NLRS_28.21_WA_3D element 002 d=300_gen:4783910
Basic Wall:NLRS_22.21_WA_beton prefab d=300_gen:4784021 | 41 eenenveertigste verdieping | 22.21 binnenwanden - constructief, massieve wanden (Uniformat) | Model Group:NLRS_01.00_verdieping type M_gen:4783248
Basic Wall:NLRS_22.21_WA_beton prefab d=300_gen:4784024 | 41 eenenveertigste verdieping | 22.21 binnenwanden - constructief, massieve wanden (Uniformat) | Model Group:NLRS_01.00_verdieping type M_gen:4783248
Basic Wall:NLRS_22.21_WA_beton prefab d=300_gen:4784027 | 41 eenenveertigste verdieping | 22.21 binnenwanden - constructief, massieve wanden (Uniformat) | Model Group:NLRS_01.00_verdieping type M_gen:4783248
Basic Wall:NLRS_22.21_WA_beton prefab d=300_gen:4784030 | 41 eenenveertigste verdieping | 22.21 binnenwanden - constructief, massieve wanden (Uniformat) | Model Group:NLRS_01.00_verdieping type M_gen:4783248
Basic Wall:NLRS_22.21_WA_beton prefab d=300_gen:4784033 | 41 eenenveertigste verdieping | 22.21 binnenwanden - constructief, massieve wanden (Uniformat) | Model Group:NLRS_01.00_verdieping type M_gen:4783248
Basic Wall:NLRS_21.21_WA_beton prefab d=300/320_gen:4784036 | 41 eenenveertigste verdieping | 21.21 buitenwanden - constructief, massieve wanden (Uniformat) | Model Group:NLRS_28.21_WA_3D element 001 d=300_gen:4783909
Basic Wall:NLRS_21.21_WA_beton prefab d=300/320_gen:4784039 | 41 eenenveertigste verdieping | 21.21 buitenwanden - constructief, massieve wanden (Uniformat) | Model Group:NLRS_28.21_WA_3D element 001 d=300_gen:4783909
Basic Wall:NLRS_21.21_WA_beton prefab d=300/320_gen:4784065 | 41 eenenveertigste verdieping | 21.21 buitenwanden - constructief, massieve wanden (Uniformat) | Model Group:NLRS_28.21_WA_3D element 001 d=300_gen:4783927
Basic Wall:NLRS_21.21_WA_beton prefab d=300/320_gen:4784068 | 41 eenenveertigste verdieping | 21.21 buitenwanden - constructief, massieve wanden (Uniformat) | Model Group:NLRS_28.21_WA_3D element 001 d=300_gen:4783927
2 x Basic Wall:NLRS_22.21_WA_beton prefab d=300_gen:4784095 | 41 eenenveertigste verdieping | 22.21 binnenwanden - constructief, massieve wanden (Uniformat) | Model Group:NLRS_01.00_verdieping type M_gen:4783248
2 x Basic Wall:NLRS_22.21_WA_beton prefab d=300_gen:4784098 | 41 eenenveertigste verdieping | 22.21 binnenwanden - constructief, massieve wanden (Uniformat) | Model Group:NLRS_01.00_verdieping type M_gen:4783248
2 x Basic Wall:NLRS_22.21_WA_beton prefab d=300_gen:4784100 | 41 eenenveertigste verdieping | 22.21 binnenwanden - constructief, massieve wanden (Uniformat) | Model Group:NLRS_01.00_verdieping type M_gen:4783248
Basic Wall:NLRS_21.21_WA_beton prefab d=300/320_gen:4788753 | 43 drieënveertigste verdieping | 21.21 buitenwanden - constructief, massieve wanden (Uniformat) | Model Group:NLRS_21.21_WA_wand 003 d=300_gen:4788802
Basic Wall:NLRS_21.21_WA_beton prefab d=300/320_gen:4788755 | 43 drieënveertigste verdieping | 21.21 buitenwanden - constructief, massieve wanden (Uniformat) | Model Group:NLRS_21.21_WA_wand 001 d=300_gen:4788801
Basic Wall:NLRS_21.21_WA_beton prefab d=300/320_gen:4788803 | 43 drieënveertigste verdieping | 21.21 buitenwanden - constructief, massieve wanden (Uniformat) | Model Group:NLRS_21.21_WA_wand 003 d=300_gen:4788806
Basic Wall:NLRS_21.21_WA_beton prefab d=300/320_gen:4788807 | 43 drieënveertigste verdieping | 21.21 buitenwanden - constructief, massieve wanden (Uniformat) | Model Group:NLRS_21.21_WA_wand 001 d=300_gen:4788810
3 x Basic Wall:NLRS_21.21_WA_beton prefab d=300/320_gen:4788822 | 43 drieënveertigste verdieping | 21.21 buitenwanden - constructief, massieve wanden (Uniformat) | Model Group:NLRS_21.21_WA_wand 002 d=300_gen:4788800
2 x Basic Wall:NLRS_21.21_WA_beton prefab d=300/320_gen:5365657 | 43 drieënveertigste verdieping | 21.21 buitenwanden - constructief, massieve wanden (Uniformat) | Model Group:NLRS_21.21_WA_wand 002 d=300_gen:4788800
3 x Basic Wall:NLRS_21.21_WA_beton prefab d=300/320_gen:4788824 | 43 drieënveertigste verdieping | 21.21 buitenwanden - constructief, massieve wanden (Uniformat) | Model Group:NLRS_21.21_WA_wand 002 d=300_gen:4788793
2 x Basic Wall:NLRS_21.21_WA_beton prefab d=300/320_gen:5365657 | 43 drieënveertigste verdieping | 21.21 buitenwanden - constructief, massieve wanden (Uniformat) | Model Group:NLRS_21.21_WA_wand 002 d=300_gen:4788793
3 x Basic Wall:NLRS_21.21_WA_beton prefab d=300/320_gen:4788848 | 43 drieënveertigste verdieping | 21.21 buitenwanden - constructief, massieve wanden (Uniformat) | Model Group:NLRS_21.21_WA_wand 004 d=300_gen:4788792
2 x Basic Wall:NLRS_21.21_WA_beton prefab d=300/320_gen:5365657 | 43 drieënveertigste verdieping | 21.21 buitenwanden - constructief, massieve wanden (Uniformat) | Model Group:NLRS_21.21_WA_wand 004 d=300_gen:4788792
3 x Basic Wall:NLRS_21.21_WA_beton prefab d=300/320_gen:4788850 | 43 drieënveertigste verdieping | 21.21 buitenwanden - constructief, massieve wanden (Uniformat) | Model Group:NLRS_21.21_WA_wand 004 d=300_gen:4788783
2 x Basic Wall:NLRS_21.21_WA_beton prefab d=300/320_gen:5365657 | 43 drieënveertigste verdieping | 21.21 buitenwanden - constructief, massieve wanden (Uniformat) | Model Group:NLRS_21.21_WA_wand 004 d=300_gen:4788783
Basic Wall:NLRS_21.21_WA_beton prefab d=300/320_gen:4788957 | 43 drieënveertigste verdieping | 21.21 buitenwanden - constructief, massieve wanden (Uniformat) | Model Group:NLRS_28.21_WA_3D element 002 d=300_gen:4788972
Basic Wall:NLRS_21.21_WA_beton prefab d=300/320_gen:4788959 | 43 drieënveertigste verdieping | 21.21 buitenwanden - constructief, massieve wanden (Uniformat) | Model Group:NLRS_28.21_WA_3D element 002 d=300_gen:4788972
Basic Wall:NLRS_21.21_WA_beton prefab d=300/320_gen:4789038 | 43 drieënveertigste verdieping | 21.21 buitenwanden - constructief, massieve wanden (Uniformat) | Model Group:NLRS_28.21_WA_3D element 002 d=300_gen:4788956
Basic Wall:NLRS_21.21_WA_beton prefab d=300/320_gen:4789040 | 43 drieënveertigste verdieping | 21.21 buitenwanden - constructief, massieve wanden (Uniformat) | Model Group:NLRS_28.21_WA_3D element 002 d=300_gen:4788956
Basic Wall:NLRS_21.21_WA_beton prefab d=300/320_gen:4789082 | 43 drieënveertigste verdieping | 21.21 buitenwanden - constructief, massieve wanden (Uniformat) | Model Group:NLRS_28.21_WA_3D element 001 d=300_gen:4788955
Basic Wall:NLRS_21.21_WA_beton prefab d=300/320_gen:4789085 | 43 drieënveertigste verdieping | 21.21 buitenwanden - constructief, massieve wanden (Uniformat) | Model Group:NLRS_28.21_WA_3D element 001 d=300_gen:4788955
Basic Wall:NLRS_21.21_WA_beton prefab d=300/320_gen:4789111 | 43 drieënveertigste verdieping | 21.21 buitenwanden - constructief, massieve wanden (Uniformat) | Model Group:NLRS_28.21_WA_3D element 001 d=300_gen:4788973
Basic Wall:NLRS_21.21_WA_beton prefab d=300/320_gen:4789114 | 43 drieënveertigste verdieping | 21.21 buitenwanden - constructief, massieve wanden (Uniformat) | Model Group:NLRS_28.21_WA_3D element 001 d=300_gen:4788973
Basic Wall:NLRS_21.21_WA_beton prefab d=300/320_gen:4789185 | 44 vierenveertigste verdieping | 21.21 buitenwanden - constructief, massieve wanden (Uniformat) | Model Group:NLRS_21.21_WA_wand 003 d=300_gen:4789234
Basic Wall:NLRS_21.21_WA_beton prefab d=300/320_gen:4789187 | 44 vierenveertigste verdieping | 21.21 buitenwanden - constructief, massieve wanden (Uniformat) | Model Group:NLRS_21.21_WA_wand 001 d=300_gen:4789233
Basic Wall:NLRS_21.21_WA_beton prefab d=300/320_gen:4789235 | 44 vierenveertigste verdieping | 21.21 buitenwanden - constructief, massieve wanden (Uniformat) | Model Group:NLRS_21.21_WA_wand 003 d=300_gen:4789238
Basic Wall:NLRS_21.21_WA_beton prefab d=300/320_gen:4789239 | 44 vierenveertigste verdieping | 21.21 buitenwanden - constructief, massieve wanden (Uniformat) | Model Group:NLRS_21.21_WA_wand 001 d=300_gen:4789242
3 x Basic Wall:NLRS_21.21_WA_beton prefab d=300/320_gen:4789254 | 44 vierenveertigste verdieping | 21.21 buitenwanden - constructief, massieve wanden (Uniformat) | Model Group:NLRS_21.21_WA_wand 002 d=300_gen:4789232
2 x Basic Wall:NLRS_21.21_WA_beton prefab d=300/320_gen:5365657 | 44 vierenveertigste verdieping | 21.21 buitenwanden - constructief, massieve wanden (Uniformat) | Model Group:NLRS_21.21_WA_wand 002 d=300_gen:4789232
3 x Basic Wall:NLRS_21.21_WA_beton prefab d=300/320_gen:4789256 | 44 vierenveertigste verdieping | 21.21 buitenwanden - constructief, massieve wanden (Uniformat) | Model Group:NLRS_21.21_WA_wand 002 d=300_gen:4789225
2 x Basic Wall:NLRS_21.21_WA_beton prefab d=300/320_gen:5365657 | 44 vierenveertigste verdieping | 21.21 buitenwanden - constructief, massieve wanden (Uniformat) | Model Group:NLRS_21.21_WA_wand 002 d=300_gen:4789225
3 x Basic Wall:NLRS_21.21_WA_beton prefab d=300/320_gen:4789280 | 44 vierenveertigste verdieping | 21.21 buitenwanden - constructief, massieve wanden (Uniformat) | Model Group:NLRS_21.21_WA_wand 004 d=300_gen:4789224
2 x Basic Wall:NLRS_21.21_WA_beton prefab d=300/320_gen:5365657 | 44 vierenveertigste verdieping | 21.21 buitenwanden - constructief, massieve wanden (Uniformat) | Model Group:NLRS_21.21_WA_wand 004 d=300_gen:4789224
3 x Basic Wall:NLRS_21.21_WA_beton prefab d=300/320_gen:4789282 | 44 vierenveertigste verdieping | 21.21 buitenwanden - constructief, massieve wanden (Uniformat) | Model Group:NLRS_21.21_WA_wand 004 d=300_gen:4789215
2 x Basic Wall:NLRS_21.21_WA_beton prefab d=300/320_gen:5365657 | 44 vierenveertigste verdieping | 21.21 buitenwanden - constructief, massieve wanden (Uniformat) | Model Group:NLRS_21.21_WA_wand 004 d=300_gen:4789215
Basic Wall:NLRS_21.21_WA_beton prefab d=300/320_gen:4789389 | 44 vierenveertigste verdieping | 21.21 buitenwanden - constructief, massieve wanden (Uniformat) | Model Group:NLRS_28.21_WA_3D element 002 d=300_gen:4789404
Basic Wall:NLRS_21.21_WA_beton prefab d=300/320_gen:4789391 | 44 vierenveertigste verdieping | 21.21 buitenwanden - constructief, massieve wanden (Uniformat) | Model Group:NLRS_28.21_WA_3D element 002 d=300_gen:4789404
Basic Wall:NLRS_21.21_WA_beton prefab d=300/320_gen:4789470 | 44 vierenveertigste verdieping | 21.21 buitenwanden - constructief, massieve wanden (Uniformat) | Model Group:NLRS_28.21_WA_3D element 002 d=300_gen:4789388
Basic Wall:NLRS_21.21_WA_beton prefab d=300/320_gen:4789472 | 44 vierenveertigste verdieping | 21.21 buitenwanden - constructief, massieve wanden (Uniformat) | Model Group:NLRS_28.21_WA_3D element 002 d=300_gen:4789388
Basic Wall:NLRS_21.21_WA_beton prefab d=300/320_gen:4789514 | 44 vierenveertigste verdieping | 21.21 buitenwanden - constructief, massieve wanden (Uniformat) | Model Group:NLRS_28.21_WA_3D element 001 d=300_gen:4789387
Basic Wall:NLRS_21.21_WA_beton prefab d=300/320_gen:4789517 | 44 vierenveertigste verdieping | 21.21 buitenwanden - constructief, massieve wanden (Uniformat) | Model Group:NLRS_28.21_WA_3D element 001 d=300_gen:4789387
Basic Wall:NLRS_21.21_WA_beton prefab d=300/320_gen:4789543 | 44 vierenveertigste verdieping | 21.21 buitenwanden - constructief, massieve wanden (Uniformat) | Model Group:NLRS_28.21_WA_3D element 001 d=300_gen:4789405
Basic Wall:NLRS_21.21_WA_beton prefab d=300/320_gen:4789546 | 44 vierenveertigste verdieping | 21.21 buitenwanden - constructief, massieve wanden (Uniformat) | Model Group:NLRS_28.21_WA_3D element 001 d=300_gen:4789405
Basic Wall:NLRS_21.21_WA_beton prefab d=300/320_gen:4789617 | 45 vijfenveertigste verdieping | 21.21 buitenwanden - constructief, massieve wanden (Uniformat) | Model Group:NLRS_21.21_WA_wand 003 d=300_gen:4789666
Basic Wall:NLRS_21.21_WA_beton prefab d=300/320_gen:4789619 | 45 vijfenveertigste verdieping | 21.21 buitenwanden - constructief, massieve wanden (Uniformat) | Model Group:NLRS_21.21_WA_wand 001 d=300_gen:4789665
Basic Wall:NLRS_21.21_WA_beton prefab d=300/320_gen:4789667 | 45 vijfenveertigste verdieping | 21.21 buitenwanden - constructief, massieve wanden (Uniformat) | Model Group:NLRS_21.21_WA_wand 003 d=300_gen:4789670
Basic Wall:NLRS_21.21_WA_beton prefab d=300/320_gen:4789671 | 45 vijfenveertigste verdieping | 21.21 buitenwanden - constructief, massieve wanden (Uniformat) | Model Group:NLRS_21.21_WA_wand 001 d=300_gen:4789674
3 x Basic Wall:NLRS_21.21_WA_beton prefab d=300/320_gen:4789686 | 45 vijfenveertigste verdieping | 21.21 buitenwanden - constructief, massieve wanden (Uniformat) | Model Group:NLRS_21.21_WA_wand 002 d=300_gen:4789664
2 x Basic Wall:NLRS_21.21_WA_beton prefab d=300/320_gen:5365657 | 45 vijfenveertigste verdieping | 21.21 buitenwanden - constructief, massieve wanden (Uniformat) | Model Group:NLRS_21.21_WA_wand 002 d=300_gen:4789664
3 x Basic Wall:NLRS_21.21_WA_beton prefab d=300/320_gen:4789688 | 45 vijfenveertigste verdieping | 21.21 buitenwanden - constructief, massieve wanden (Uniformat) | Model Group:NLRS_21.21_WA_wand 002 d=300_gen:4789657
2 x Basic Wall:NLRS_21.21_WA_beton prefab d=300/320_gen:5365657 | 45 vijfenveertigste verdieping | 21.21 buitenwanden - constructief, massieve wanden (Uniformat) | Model Group:NLRS_21.21_WA_wand 002 d=300_gen:4789657
3 x Basic Wall:NLRS_21.21_WA_beton prefab d=300/320_gen:4789712 | 45 vijfenveertigste verdieping | 21.21 buitenwanden - constructief, massieve wanden (Uniformat) | Model Group:NLRS_21.21_WA_wand 004 d=300_gen:4789656
2 x Basic Wall:NLRS_21.21_WA_beton prefab d=300/320_gen:5365657 | 45 vijfenveertigste verdieping | 21.21 buitenwanden - constructief, massieve wanden (Uniformat) | Model Group:NLRS_21.21_WA_wand 004 d=300_gen:4789656
3 x Basic Wall:NLRS_21.21_WA_beton prefab d=300/320_gen:4789714 | 45 vijfenveertigste verdieping | 21.21 buitenwanden - constructief, massieve wanden (Uniformat) | Model Group:NLRS_21.21_WA_wand 004 d=300_gen:4789647
2 x Basic Wall:NLRS_21.21_WA_beton prefab d=300/320_gen:5365657 | 45 vijfenveertigste verdieping | 21.21 buitenwanden - constructief, massieve wanden (Uniformat) | Model Group:NLRS_21.21_WA_wand 004 d=300_gen:4789647
Basic Wall:NLRS_21.21_WA_beton prefab d=300/320_gen:4789821 | 45 vijfenveertigste verdieping | 21.21 buitenwanden - constructief, massieve wanden (Uniformat) | Model Group:NLRS_28.21_WA_3D element 002 d=300_gen:4789836
Basic Wall:NLRS_21.21_WA_beton prefab d=300/320_gen:4789823 | 45 vijfenveertigste verdieping | 21.21 buitenwanden - constructief, massieve wanden (Uniformat) | Model Group:NLRS_28.21_WA_3D element 002 d=300_gen:4789836
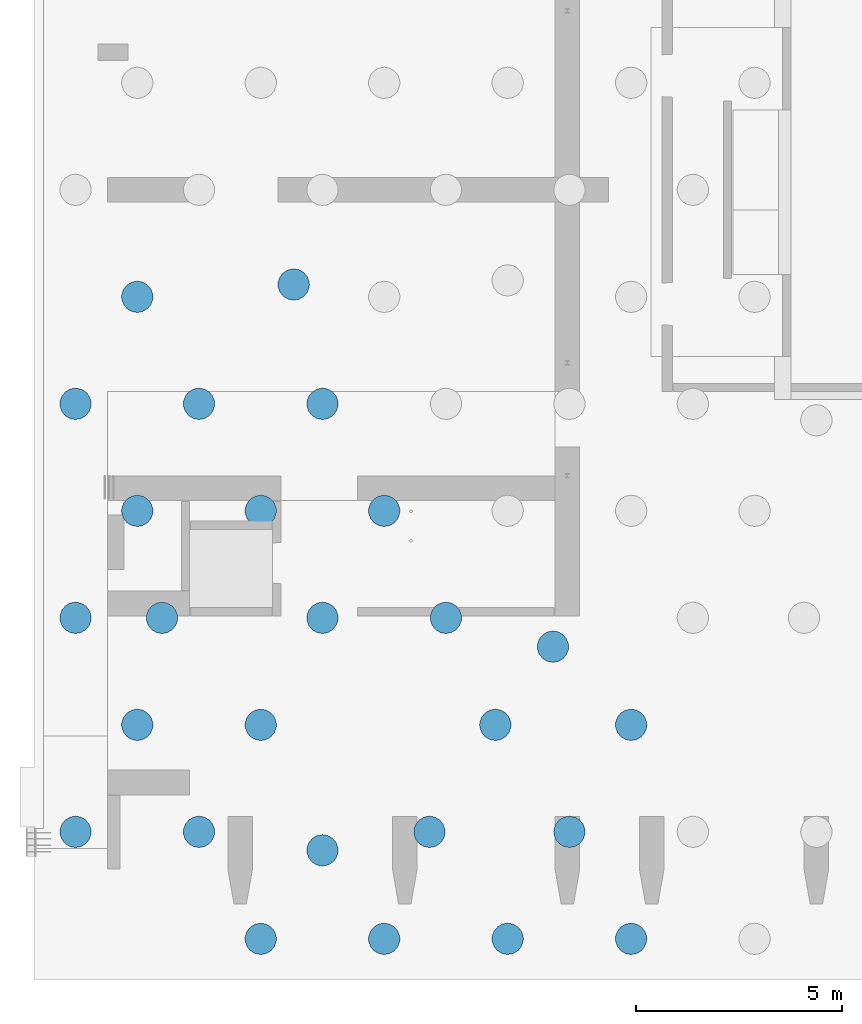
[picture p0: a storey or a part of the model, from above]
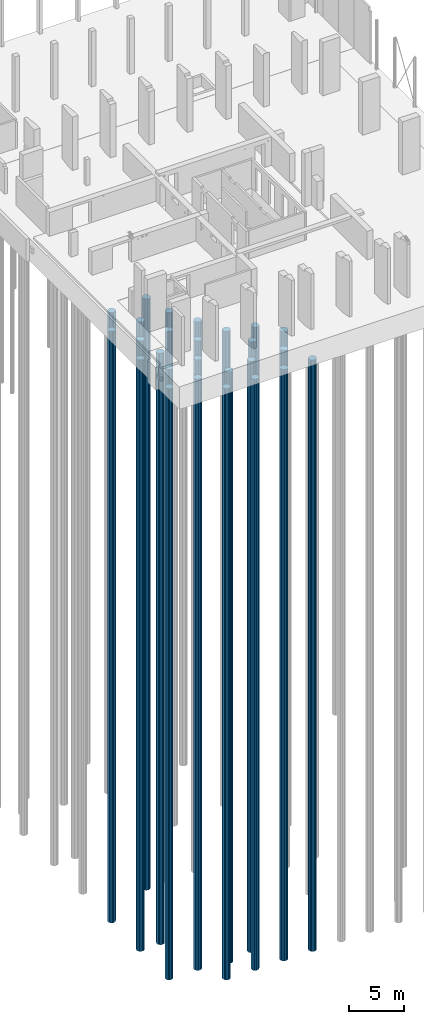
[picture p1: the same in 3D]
Properties of the parts of a building model (IFC2X3), part 10 of 21

# IfcOpeningElement: Opening (5659)
Name | In | Classification | Group
Basic Wall:NLRS_21.21_WA_beton prefab d=300/320_gen:4789902 | 45 vijfenveertigste verdieping | 21.21 buitenwanden - constructief, massieve wanden (Uniformat) | Model Group:NLRS_28.21_WA_3D element 002 d=300_gen:4789820
Basic Wall:NLRS_21.21_WA_beton prefab d=300/320_gen:4789904 | 45 vijfenveertigste verdieping | 21.21 buitenwanden - constructief, massieve wanden (Uniformat) | Model Group:NLRS_28.21_WA_3D element 002 d=300_gen:4789820
Basic Wall:NLRS_21.21_WA_beton prefab d=300/320_gen:4789946 | 45 vijfenveertigste verdieping | 21.21 buitenwanden - constructief, massieve wanden (Uniformat) | Model Group:NLRS_28.21_WA_3D element 001 d=300_gen:4789819
Basic Wall:NLRS_21.21_WA_beton prefab d=300/320_gen:4789949 | 45 vijfenveertigste verdieping | 21.21 buitenwanden - constructief, massieve wanden (Uniformat) | Model Group:NLRS_28.21_WA_3D element 001 d=300_gen:4789819
Basic Wall:NLRS_21.21_WA_beton prefab d=300/320_gen:4789975 | 45 vijfenveertigste verdieping | 21.21 buitenwanden - constructief, massieve wanden (Uniformat) | Model Group:NLRS_28.21_WA_3D element 001 d=300_gen:4789837
Basic Wall:NLRS_21.21_WA_beton prefab d=300/320_gen:4789978 | 45 vijfenveertigste verdieping | 21.21 buitenwanden - constructief, massieve wanden (Uniformat) | Model Group:NLRS_28.21_WA_3D element 001 d=300_gen:4789837
Basic Wall:NLRS_21.21_WA_beton prefab d=300/320_gen:4790049 | 46 zesenveertigste verdieping | 21.21 buitenwanden - constructief, massieve wanden (Uniformat) | Model Group:NLRS_21.21_WA_wand 003 d=300_gen:4790098
Basic Wall:NLRS_21.21_WA_beton prefab d=300/320_gen:4790051 | 46 zesenveertigste verdieping | 21.21 buitenwanden - constructief, massieve wanden (Uniformat) | Model Group:NLRS_21.21_WA_wand 001 d=300_gen:4790097
Basic Wall:NLRS_21.21_WA_beton prefab d=300/320_gen:4790099 | 46 zesenveertigste verdieping | 21.21 buitenwanden - constructief, massieve wanden (Uniformat) | Model Group:NLRS_21.21_WA_wand 003 d=300_gen:4790102
Basic Wall:NLRS_21.21_WA_beton prefab d=300/320_gen:4790103 | 46 zesenveertigste verdieping | 21.21 buitenwanden - constructief, massieve wanden (Uniformat) | Model Group:NLRS_21.21_WA_wand 001 d=300_gen:4790106
3 x Basic Wall:NLRS_21.21_WA_beton prefab d=300/320_gen:4790118 | 46 zesenveertigste verdieping | 21.21 buitenwanden - constructief, massieve wanden (Uniformat) | Model Group:NLRS_21.21_WA_wand 002 d=300_gen:4790096
2 x Basic Wall:NLRS_21.21_WA_beton prefab d=300/320_gen:5365657 | 46 zesenveertigste verdieping | 21.21 buitenwanden - constructief, massieve wanden (Uniformat) | Model Group:NLRS_21.21_WA_wand 002 d=300_gen:4790096
3 x Basic Wall:NLRS_21.21_WA_beton prefab d=300/320_gen:4790120 | 46 zesenveertigste verdieping | 21.21 buitenwanden - constructief, massieve wanden (Uniformat) | Model Group:NLRS_21.21_WA_wand 002 d=300_gen:4790089
2 x Basic Wall:NLRS_21.21_WA_beton prefab d=300/320_gen:5365657 | 46 zesenveertigste verdieping | 21.21 buitenwanden - constructief, massieve wanden (Uniformat) | Model Group:NLRS_21.21_WA_wand 002 d=300_gen:4790089
3 x Basic Wall:NLRS_21.21_WA_beton prefab d=300/320_gen:4790144 | 46 zesenveertigste verdieping | 21.21 buitenwanden - constructief, massieve wanden (Uniformat) | Model Group:NLRS_21.21_WA_wand 004 d=300_gen:4790088
2 x Basic Wall:NLRS_21.21_WA_beton prefab d=300/320_gen:5365657 | 46 zesenveertigste verdieping | 21.21 buitenwanden - constructief, massieve wanden (Uniformat) | Model Group:NLRS_21.21_WA_wand 004 d=300_gen:4790088
3 x Basic Wall:NLRS_21.21_WA_beton prefab d=300/320_gen:4790146 | 46 zesenveertigste verdieping | 21.21 buitenwanden - constructief, massieve wanden (Uniformat) | Model Group:NLRS_21.21_WA_wand 004 d=300_gen:4790079
2 x Basic Wall:NLRS_21.21_WA_beton prefab d=300/320_gen:5365657 | 46 zesenveertigste verdieping | 21.21 buitenwanden - constructief, massieve wanden (Uniformat) | Model Group:NLRS_21.21_WA_wand 004 d=300_gen:4790079
Basic Wall:NLRS_21.21_WA_beton prefab d=300/320_gen:4790253 | 46 zesenveertigste verdieping | 21.21 buitenwanden - constructief, massieve wanden (Uniformat) | Model Group:NLRS_28.21_WA_3D element 002 d=300_gen:4790268
Basic Wall:NLRS_21.21_WA_beton prefab d=300/320_gen:4790255 | 46 zesenveertigste verdieping | 21.21 buitenwanden - constructief, massieve wanden (Uniformat) | Model Group:NLRS_28.21_WA_3D element 002 d=300_gen:4790268
Basic Wall:NLRS_21.21_WA_beton prefab d=300/320_gen:4790334 | 46 zesenveertigste verdieping | 21.21 buitenwanden - constructief, massieve wanden (Uniformat) | Model Group:NLRS_28.21_WA_3D element 002 d=300_gen:4790252
Basic Wall:NLRS_21.21_WA_beton prefab d=300/320_gen:4790336 | 46 zesenveertigste verdieping | 21.21 buitenwanden - constructief, massieve wanden (Uniformat) | Model Group:NLRS_28.21_WA_3D element 002 d=300_gen:4790252
Basic Wall:NLRS_21.21_WA_beton prefab d=300/320_gen:4790378 | 46 zesenveertigste verdieping | 21.21 buitenwanden - constructief, massieve wanden (Uniformat) | Model Group:NLRS_28.21_WA_3D element 001 d=300_gen:4790251
Basic Wall:NLRS_21.21_WA_beton prefab d=300/320_gen:4790381 | 46 zesenveertigste verdieping | 21.21 buitenwanden - constructief, massieve wanden (Uniformat) | Model Group:NLRS_28.21_WA_3D element 001 d=300_gen:4790251
Basic Wall:NLRS_21.21_WA_beton prefab d=300/320_gen:4790407 | 46 zesenveertigste verdieping | 21.21 buitenwanden - constructief, massieve wanden (Uniformat) | Model Group:NLRS_28.21_WA_3D element 001 d=300_gen:4790269
Basic Wall:NLRS_21.21_WA_beton prefab d=300/320_gen:4790410 | 46 zesenveertigste verdieping | 21.21 buitenwanden - constructief, massieve wanden (Uniformat) | Model Group:NLRS_28.21_WA_3D element 001 d=300_gen:4790269
Basic Wall:NLRS_21.21_WA_beton prefab d=300/320_gen:4790481 | 47 zevenenveertigste verdieping | 21.21 buitenwanden - constructief, massieve wanden (Uniformat) | Model Group:NLRS_21.21_WA_wand 003 d=300_gen:4790530
Basic Wall:NLRS_21.21_WA_beton prefab d=300/320_gen:4790483 | 47 zevenenveertigste verdieping | 21.21 buitenwanden - constructief, massieve wanden (Uniformat) | Model Group:NLRS_21.21_WA_wand 001 d=300_gen:4790529
Basic Wall:NLRS_21.21_WA_beton prefab d=300/320_gen:4790531 | 47 zevenenveertigste verdieping | 21.21 buitenwanden - constructief, massieve wanden (Uniformat) | Model Group:NLRS_21.21_WA_wand 003 d=300_gen:4790534
Basic Wall:NLRS_21.21_WA_beton prefab d=300/320_gen:4790535 | 47 zevenenveertigste verdieping | 21.21 buitenwanden - constructief, massieve wanden (Uniformat) | Model Group:NLRS_21.21_WA_wand 001 d=300_gen:4790538
3 x Basic Wall:NLRS_21.21_WA_beton prefab d=300/320_gen:4790550 | 47 zevenenveertigste verdieping | 21.21 buitenwanden - constructief, massieve wanden (Uniformat) | Model Group:NLRS_21.21_WA_wand 002 d=300_gen:4790528
2 x Basic Wall:NLRS_21.21_WA_beton prefab d=300/320_gen:5365657 | 47 zevenenveertigste verdieping | 21.21 buitenwanden - constructief, massieve wanden (Uniformat) | Model Group:NLRS_21.21_WA_wand 002 d=300_gen:4790528
3 x Basic Wall:NLRS_21.21_WA_beton prefab d=300/320_gen:4790552 | 47 zevenenveertigste verdieping | 21.21 buitenwanden - constructief, massieve wanden (Uniformat) | Model Group:NLRS_21.21_WA_wand 002 d=300_gen:4790521
2 x Basic Wall:NLRS_21.21_WA_beton prefab d=300/320_gen:5365657 | 47 zevenenveertigste verdieping | 21.21 buitenwanden - constructief, massieve wanden (Uniformat) | Model Group:NLRS_21.21_WA_wand 002 d=300_gen:4790521
3 x Basic Wall:NLRS_21.21_WA_beton prefab d=300/320_gen:4790576 | 47 zevenenveertigste verdieping | 21.21 buitenwanden - constructief, massieve wanden (Uniformat) | Model Group:NLRS_21.21_WA_wand 004 d=300_gen:4790520
2 x Basic Wall:NLRS_21.21_WA_beton prefab d=300/320_gen:5365657 | 47 zevenenveertigste verdieping | 21.21 buitenwanden - constructief, massieve wanden (Uniformat) | Model Group:NLRS_21.21_WA_wand 004 d=300_gen:4790520
3 x Basic Wall:NLRS_21.21_WA_beton prefab d=300/320_gen:4790578 | 47 zevenenveertigste verdieping | 21.21 buitenwanden - constructief, massieve wanden (Uniformat) | Model Group:NLRS_21.21_WA_wand 004 d=300_gen:4790511
2 x Basic Wall:NLRS_21.21_WA_beton prefab d=300/320_gen:5365657 | 47 zevenenveertigste verdieping | 21.21 buitenwanden - constructief, massieve wanden (Uniformat) | Model Group:NLRS_21.21_WA_wand 004 d=300_gen:4790511
Basic Wall:NLRS_21.21_WA_beton prefab d=300/320_gen:4790685 | 47 zevenenveertigste verdieping | 21.21 buitenwanden - constructief, massieve wanden (Uniformat) | Model Group:NLRS_28.21_WA_3D element 002 d=300_gen:4790700
Basic Wall:NLRS_21.21_WA_beton prefab d=300/320_gen:4790687 | 47 zevenenveertigste verdieping | 21.21 buitenwanden - constructief, massieve wanden (Uniformat) | Model Group:NLRS_28.21_WA_3D element 002 d=300_gen:4790700
Basic Wall:NLRS_21.21_WA_beton prefab d=300/320_gen:4790766 | 47 zevenenveertigste verdieping | 21.21 buitenwanden - constructief, massieve wanden (Uniformat) | Model Group:NLRS_28.21_WA_3D element 002 d=300_gen:4790684
Basic Wall:NLRS_21.21_WA_beton prefab d=300/320_gen:4790768 | 47 zevenenveertigste verdieping | 21.21 buitenwanden - constructief, massieve wanden (Uniformat) | Model Group:NLRS_28.21_WA_3D element 002 d=300_gen:4790684
Basic Wall:NLRS_21.21_WA_beton prefab d=300/320_gen:4790810 | 47 zevenenveertigste verdieping | 21.21 buitenwanden - constructief, massieve wanden (Uniformat) | Model Group:NLRS_28.21_WA_3D element 001 d=300_gen:4790683
Basic Wall:NLRS_21.21_WA_beton prefab d=300/320_gen:4790813 | 47 zevenenveertigste verdieping | 21.21 buitenwanden - constructief, massieve wanden (Uniformat) | Model Group:NLRS_28.21_WA_3D element 001 d=300_gen:4790683
Basic Wall:NLRS_21.21_WA_beton prefab d=300/320_gen:4790839 | 47 zevenenveertigste verdieping | 21.21 buitenwanden - constructief, massieve wanden (Uniformat) | Model Group:NLRS_28.21_WA_3D element 001 d=300_gen:4790701
Basic Wall:NLRS_21.21_WA_beton prefab d=300/320_gen:4790842 | 47 zevenenveertigste verdieping | 21.21 buitenwanden - constructief, massieve wanden (Uniformat) | Model Group:NLRS_28.21_WA_3D element 001 d=300_gen:4790701
Basic Wall:NLRS_21.21_WA_beton prefab d=300/320_gen:4790913 | 48 achtenveertigste verdieping | 21.21 buitenwanden - constructief, massieve wanden (Uniformat) | Model Group:NLRS_21.21_WA_wand 003 d=300_gen:4790962
Basic Wall:NLRS_21.21_WA_beton prefab d=300/320_gen:4790915 | 48 achtenveertigste verdieping | 21.21 buitenwanden - constructief, massieve wanden (Uniformat) | Model Group:NLRS_21.21_WA_wand 001 d=300_gen:4790961
Basic Wall:NLRS_21.21_WA_beton prefab d=300/320_gen:4790963 | 48 achtenveertigste verdieping | 21.21 buitenwanden - constructief, massieve wanden (Uniformat) | Model Group:NLRS_21.21_WA_wand 003 d=300_gen:4790966
Basic Wall:NLRS_21.21_WA_beton prefab d=300/320_gen:4790967 | 48 achtenveertigste verdieping | 21.21 buitenwanden - constructief, massieve wanden (Uniformat) | Model Group:NLRS_21.21_WA_wand 001 d=300_gen:4790970
3 x Basic Wall:NLRS_21.21_WA_beton prefab d=300/320_gen:4790982 | 48 achtenveertigste verdieping | 21.21 buitenwanden - constructief, massieve wanden (Uniformat) | Model Group:NLRS_21.21_WA_wand 002 d=300_gen:4790960
2 x Basic Wall:NLRS_21.21_WA_beton prefab d=300/320_gen:5365657 | 48 achtenveertigste verdieping | 21.21 buitenwanden - constructief, massieve wanden (Uniformat) | Model Group:NLRS_21.21_WA_wand 002 d=300_gen:4790960
3 x Basic Wall:NLRS_21.21_WA_beton prefab d=300/320_gen:4790984 | 48 achtenveertigste verdieping | 21.21 buitenwanden - constructief, massieve wanden (Uniformat) | Model Group:NLRS_21.21_WA_wand 002 d=300_gen:4790953
2 x Basic Wall:NLRS_21.21_WA_beton prefab d=300/320_gen:5365657 | 48 achtenveertigste verdieping | 21.21 buitenwanden - constructief, massieve wanden (Uniformat) | Model Group:NLRS_21.21_WA_wand 002 d=300_gen:4790953
3 x Basic Wall:NLRS_21.21_WA_beton prefab d=300/320_gen:4791008 | 48 achtenveertigste verdieping | 21.21 buitenwanden - constructief, massieve wanden (Uniformat) | Model Group:NLRS_21.21_WA_wand 004 d=300_gen:4790952
2 x Basic Wall:NLRS_21.21_WA_beton prefab d=300/320_gen:5365657 | 48 achtenveertigste verdieping | 21.21 buitenwanden - constructief, massieve wanden (Uniformat) | Model Group:NLRS_21.21_WA_wand 004 d=300_gen:4790952
3 x Basic Wall:NLRS_21.21_WA_beton prefab d=300/320_gen:4791010 | 48 achtenveertigste verdieping | 21.21 buitenwanden - constructief, massieve wanden (Uniformat) | Model Group:NLRS_21.21_WA_wand 004 d=300_gen:4790943
2 x Basic Wall:NLRS_21.21_WA_beton prefab d=300/320_gen:5365657 | 48 achtenveertigste verdieping | 21.21 buitenwanden - constructief, massieve wanden (Uniformat) | Model Group:NLRS_21.21_WA_wand 004 d=300_gen:4790943
Basic Wall:NLRS_21.21_WA_beton prefab d=300/320_gen:4791117 | 48 achtenveertigste verdieping | 21.21 buitenwanden - constructief, massieve wanden (Uniformat) | Model Group:NLRS_28.21_WA_3D element 002 d=300_gen:4791132
Basic Wall:NLRS_21.21_WA_beton prefab d=300/320_gen:4791119 | 48 achtenveertigste verdieping | 21.21 buitenwanden - constructief, massieve wanden (Uniformat) | Model Group:NLRS_28.21_WA_3D element 002 d=300_gen:4791132
Basic Wall:NLRS_21.21_WA_beton prefab d=300/320_gen:4791198 | 48 achtenveertigste verdieping | 21.21 buitenwanden - constructief, massieve wanden (Uniformat) | Model Group:NLRS_28.21_WA_3D element 002 d=300_gen:4791116
Basic Wall:NLRS_21.21_WA_beton prefab d=300/320_gen:4791200 | 48 achtenveertigste verdieping | 21.21 buitenwanden - constructief, massieve wanden (Uniformat) | Model Group:NLRS_28.21_WA_3D element 002 d=300_gen:4791116
Basic Wall:NLRS_21.21_WA_beton prefab d=300/320_gen:4791242 | 48 achtenveertigste verdieping | 21.21 buitenwanden - constructief, massieve wanden (Uniformat) | Model Group:NLRS_28.21_WA_3D element 001 d=300_gen:4791115
Basic Wall:NLRS_21.21_WA_beton prefab d=300/320_gen:4791245 | 48 achtenveertigste verdieping | 21.21 buitenwanden - constructief, massieve wanden (Uniformat) | Model Group:NLRS_28.21_WA_3D element 001 d=300_gen:4791115
Basic Wall:NLRS_21.21_WA_beton prefab d=300/320_gen:4791271 | 48 achtenveertigste verdieping | 21.21 buitenwanden - constructief, massieve wanden (Uniformat) | Model Group:NLRS_28.21_WA_3D element 001 d=300_gen:4791133
Basic Wall:NLRS_21.21_WA_beton prefab d=300/320_gen:4791274 | 48 achtenveertigste verdieping | 21.21 buitenwanden - constructief, massieve wanden (Uniformat) | Model Group:NLRS_28.21_WA_3D element 001 d=300_gen:4791133
Basic Wall:NLRS_21.21_WA_beton prefab d=300/320_gen:4791345 | 49 negenenveertigste verdieping | 21.21 buitenwanden - constructief, massieve wanden (Uniformat) | Model Group:NLRS_21.21_WA_wand 003 d=300_gen:4791394
Basic Wall:NLRS_21.21_WA_beton prefab d=300/320_gen:4791347 | 49 negenenveertigste verdieping | 21.21 buitenwanden - constructief, massieve wanden (Uniformat) | Model Group:NLRS_21.21_WA_wand 001 d=300_gen:4791393
Basic Wall:NLRS_21.21_WA_beton prefab d=300/320_gen:4791395 | 49 negenenveertigste verdieping | 21.21 buitenwanden - constructief, massieve wanden (Uniformat) | Model Group:NLRS_21.21_WA_wand 003 d=300_gen:4791398
Basic Wall:NLRS_21.21_WA_beton prefab d=300/320_gen:4791399 | 49 negenenveertigste verdieping | 21.21 buitenwanden - constructief, massieve wanden (Uniformat) | Model Group:NLRS_21.21_WA_wand 001 d=300_gen:4791402
3 x Basic Wall:NLRS_21.21_WA_beton prefab d=300/320_gen:4791414 | 49 negenenveertigste verdieping | 21.21 buitenwanden - constructief, massieve wanden (Uniformat) | Model Group:NLRS_21.21_WA_wand 002 d=300_gen:4791392
2 x Basic Wall:NLRS_21.21_WA_beton prefab d=300/320_gen:5365657 | 49 negenenveertigste verdieping | 21.21 buitenwanden - constructief, massieve wanden (Uniformat) | Model Group:NLRS_21.21_WA_wand 002 d=300_gen:4791392
3 x Basic Wall:NLRS_21.21_WA_beton prefab d=300/320_gen:4791416 | 49 negenenveertigste verdieping | 21.21 buitenwanden - constructief, massieve wanden (Uniformat) | Model Group:NLRS_21.21_WA_wand 002 d=300_gen:4791385
2 x Basic Wall:NLRS_21.21_WA_beton prefab d=300/320_gen:5365657 | 49 negenenveertigste verdieping | 21.21 buitenwanden - constructief, massieve wanden (Uniformat) | Model Group:NLRS_21.21_WA_wand 002 d=300_gen:4791385
3 x Basic Wall:NLRS_21.21_WA_beton prefab d=300/320_gen:4791440 | 49 negenenveertigste verdieping | 21.21 buitenwanden - constructief, massieve wanden (Uniformat) | Model Group:NLRS_21.21_WA_wand 004 d=300_gen:4791384
2 x Basic Wall:NLRS_21.21_WA_beton prefab d=300/320_gen:5365657 | 49 negenenveertigste verdieping | 21.21 buitenwanden - constructief, massieve wanden (Uniformat) | Model Group:NLRS_21.21_WA_wand 004 d=300_gen:4791384
3 x Basic Wall:NLRS_21.21_WA_beton prefab d=300/320_gen:4791442 | 49 negenenveertigste verdieping | 21.21 buitenwanden - constructief, massieve wanden (Uniformat) | Model Group:NLRS_21.21_WA_wand 004 d=300_gen:4791375
2 x Basic Wall:NLRS_21.21_WA_beton prefab d=300/320_gen:5365657 | 49 negenenveertigste verdieping | 21.21 buitenwanden - constructief, massieve wanden (Uniformat) | Model Group:NLRS_21.21_WA_wand 004 d=300_gen:4791375
Basic Wall:NLRS_21.21_WA_beton prefab d=300/320_gen:4791549 | 49 negenenveertigste verdieping | 21.21 buitenwanden - constructief, massieve wanden (Uniformat) | Model Group:NLRS_28.21_WA_3D element 002 d=300_gen:4791564
Basic Wall:NLRS_21.21_WA_beton prefab d=300/320_gen:4791551 | 49 negenenveertigste verdieping | 21.21 buitenwanden - constructief, massieve wanden (Uniformat) | Model Group:NLRS_28.21_WA_3D element 002 d=300_gen:4791564
Basic Wall:NLRS_21.21_WA_beton prefab d=300/320_gen:4791630 | 49 negenenveertigste verdieping | 21.21 buitenwanden - constructief, massieve wanden (Uniformat) | Model Group:NLRS_28.21_WA_3D element 002 d=300_gen:4791548
Basic Wall:NLRS_21.21_WA_beton prefab d=300/320_gen:4791632 | 49 negenenveertigste verdieping | 21.21 buitenwanden - constructief, massieve wanden (Uniformat) | Model Group:NLRS_28.21_WA_3D element 002 d=300_gen:4791548
Basic Wall:NLRS_21.21_WA_beton prefab d=300/320_gen:4791674 | 49 negenenveertigste verdieping | 21.21 buitenwanden - constructief, massieve wanden (Uniformat) | Model Group:NLRS_28.21_WA_3D element 001 d=300_gen:4791547
Basic Wall:NLRS_21.21_WA_beton prefab d=300/320_gen:4791677 | 49 negenenveertigste verdieping | 21.21 buitenwanden - constructief, massieve wanden (Uniformat) | Model Group:NLRS_28.21_WA_3D element 001 d=300_gen:4791547
Basic Wall:NLRS_21.21_WA_beton prefab d=300/320_gen:4791703 | 49 negenenveertigste verdieping | 21.21 buitenwanden - constructief, massieve wanden (Uniformat) | Model Group:NLRS_28.21_WA_3D element 001 d=300_gen:4791565
Basic Wall:NLRS_21.21_WA_beton prefab d=300/320_gen:4791706 | 49 negenenveertigste verdieping | 21.21 buitenwanden - constructief, massieve wanden (Uniformat) | Model Group:NLRS_28.21_WA_3D element 001 d=300_gen:4791565
Basic Wall:NLRS_21.21_WA_beton prefab d=300/320_gen:4791777 | 50 vijftigste verdieping | 21.21 buitenwanden - constructief, massieve wanden (Uniformat) | Model Group:NLRS_21.21_WA_wand 003 d=300_gen:4791826
Basic Wall:NLRS_21.21_WA_beton prefab d=300/320_gen:4791779 | 50 vijftigste verdieping | 21.21 buitenwanden - constructief, massieve wanden (Uniformat) | Model Group:NLRS_21.21_WA_wand 001 d=300_gen:4791825
Basic Wall:NLRS_21.21_WA_beton prefab d=300/320_gen:4791827 | 50 vijftigste verdieping | 21.21 buitenwanden - constructief, massieve wanden (Uniformat) | Model Group:NLRS_21.21_WA_wand 003 d=300_gen:4791830
Basic Wall:NLRS_21.21_WA_beton prefab d=300/320_gen:4791831 | 50 vijftigste verdieping | 21.21 buitenwanden - constructief, massieve wanden (Uniformat) | Model Group:NLRS_21.21_WA_wand 001 d=300_gen:4791834
3 x Basic Wall:NLRS_21.21_WA_beton prefab d=300/320_gen:4791846 | 50 vijftigste verdieping | 21.21 buitenwanden - constructief, massieve wanden (Uniformat) | Model Group:NLRS_21.21_WA_wand 002 d=300_gen:4791824
2 x Basic Wall:NLRS_21.21_WA_beton prefab d=300/320_gen:5365657 | 50 vijftigste verdieping | 21.21 buitenwanden - constructief, massieve wanden (Uniformat) | Model Group:NLRS_21.21_WA_wand 002 d=300_gen:4791824
3 x Basic Wall:NLRS_21.21_WA_beton prefab d=300/320_gen:4791848 | 50 vijftigste verdieping | 21.21 buitenwanden - constructief, massieve wanden (Uniformat) | Model Group:NLRS_21.21_WA_wand 002 d=300_gen:4791817
2 x Basic Wall:NLRS_21.21_WA_beton prefab d=300/320_gen:5365657 | 50 vijftigste verdieping | 21.21 buitenwanden - constructief, massieve wanden (Uniformat) | Model Group:NLRS_21.21_WA_wand 002 d=300_gen:4791817
3 x Basic Wall:NLRS_21.21_WA_beton prefab d=300/320_gen:4791872 | 50 vijftigste verdieping | 21.21 buitenwanden - constructief, massieve wanden (Uniformat) | Model Group:NLRS_21.21_WA_wand 004 d=300_gen:4791816
2 x Basic Wall:NLRS_21.21_WA_beton prefab d=300/320_gen:5365657 | 50 vijftigste verdieping | 21.21 buitenwanden - constructief, massieve wanden (Uniformat) | Model Group:NLRS_21.21_WA_wand 004 d=300_gen:4791816
3 x Basic Wall:NLRS_21.21_WA_beton prefab d=300/320_gen:4791874 | 50 vijftigste verdieping | 21.21 buitenwanden - constructief, massieve wanden (Uniformat) | Model Group:NLRS_21.21_WA_wand 004 d=300_gen:4791807
2 x Basic Wall:NLRS_21.21_WA_beton prefab d=300/320_gen:5365657 | 50 vijftigste verdieping | 21.21 buitenwanden - constructief, massieve wanden (Uniformat) | Model Group:NLRS_21.21_WA_wand 004 d=300_gen:4791807
Basic Wall:NLRS_21.21_WA_beton prefab d=300/320_gen:4791981 | 50 vijftigste verdieping | 21.21 buitenwanden - constructief, massieve wanden (Uniformat) | Model Group:NLRS_28.21_WA_3D element 002 d=300_gen:4791996
Basic Wall:NLRS_21.21_WA_beton prefab d=300/320_gen:4791983 | 50 vijftigste verdieping | 21.21 buitenwanden - constructief, massieve wanden (Uniformat) | Model Group:NLRS_28.21_WA_3D element 002 d=300_gen:4791996
Basic Wall:NLRS_21.21_WA_beton prefab d=300/320_gen:4792062 | 50 vijftigste verdieping | 21.21 buitenwanden - constructief, massieve wanden (Uniformat) | Model Group:NLRS_28.21_WA_3D element 002 d=300_gen:4791980
Basic Wall:NLRS_21.21_WA_beton prefab d=300/320_gen:4792064 | 50 vijftigste verdieping | 21.21 buitenwanden - constructief, massieve wanden (Uniformat) | Model Group:NLRS_28.21_WA_3D element 002 d=300_gen:4791980
Basic Wall:NLRS_21.21_WA_beton prefab d=300/320_gen:4792106 | 50 vijftigste verdieping | 21.21 buitenwanden - constructief, massieve wanden (Uniformat) | Model Group:NLRS_28.21_WA_3D element 001 d=300_gen:4791979
Basic Wall:NLRS_21.21_WA_beton prefab d=300/320_gen:4792109 | 50 vijftigste verdieping | 21.21 buitenwanden - constructief, massieve wanden (Uniformat) | Model Group:NLRS_28.21_WA_3D element 001 d=300_gen:4791979
Basic Wall:NLRS_21.21_WA_beton prefab d=300/320_gen:4792135 | 50 vijftigste verdieping | 21.21 buitenwanden - constructief, massieve wanden (Uniformat) | Model Group:NLRS_28.21_WA_3D element 001 d=300_gen:4791997
Basic Wall:NLRS_21.21_WA_beton prefab d=300/320_gen:4792138 | 50 vijftigste verdieping | 21.21 buitenwanden - constructief, massieve wanden (Uniformat) | Model Group:NLRS_28.21_WA_3D element 001 d=300_gen:4791997
Basic Wall:NLRS_22.21_WA_beton prefab d=300_gen:4803208 | 42 tweeënveertigste verdieping | 22.21 binnenwanden - constructief, massieve wanden (Uniformat) | Model Group:NLRS_01.00_verdieping type N_gen:9026295
Basic Wall:NLRS_22.21_WA_beton prefab d=300_gen:4803210 | 42 tweeënveertigste verdieping | 22.21 binnenwanden - constructief, massieve wanden (Uniformat) | Model Group:NLRS_01.00_verdieping type N_gen:9026295
2 x Basic Wall:NLRS_22.21_WA_beton prefab d=300_gen:4803212 | 42 tweeënveertigste verdieping | 22.21 binnenwanden - constructief, massieve wanden (Uniformat) | Model Group:NLRS_01.00_verdieping type N_gen:9026295
Basic Wall:NLRS_21.21_WA_beton prefab d=300/320_gen:4803226 | 42 tweeënveertigste verdieping | 21.21 buitenwanden - constructief, massieve wanden (Uniformat) | Model Group:NLRS_21.21_WA_wand 003 d=300_gen:4803275
Basic Wall:NLRS_21.21_WA_beton prefab d=300/320_gen:4803228 | 42 tweeënveertigste verdieping | 21.21 buitenwanden - constructief, massieve wanden (Uniformat) | Model Group:NLRS_21.21_WA_wand 001 d=300_gen:4803274
Basic Wall:NLRS_21.21_WA_beton prefab d=300/320_gen:4803276 | 42 tweeënveertigste verdieping | 21.21 buitenwanden - constructief, massieve wanden (Uniformat) | Model Group:NLRS_21.21_WA_wand 003 d=300_gen:4803279
Basic Wall:NLRS_21.21_WA_beton prefab d=300/320_gen:4803280 | 42 tweeënveertigste verdieping | 21.21 buitenwanden - constructief, massieve wanden (Uniformat) | Model Group:NLRS_21.21_WA_wand 001 d=300_gen:4803283
3 x Basic Wall:NLRS_21.21_WA_beton prefab d=300/320_gen:4803295 | 42 tweeënveertigste verdieping | 21.21 buitenwanden - constructief, massieve wanden (Uniformat) | Model Group:NLRS_21.21_WA_wand 002 d=300_gen:4803273
2 x Basic Wall:NLRS_21.21_WA_beton prefab d=300/320_gen:5365657 | 42 tweeënveertigste verdieping | 21.21 buitenwanden - constructief, massieve wanden (Uniformat) | Model Group:NLRS_21.21_WA_wand 002 d=300_gen:4803273
3 x Basic Wall:NLRS_21.21_WA_beton prefab d=300/320_gen:4803297 | 42 tweeënveertigste verdieping | 21.21 buitenwanden - constructief, massieve wanden (Uniformat) | Model Group:NLRS_21.21_WA_wand 002 d=300_gen:4803266
2 x Basic Wall:NLRS_21.21_WA_beton prefab d=300/320_gen:5365657 | 42 tweeënveertigste verdieping | 21.21 buitenwanden - constructief, massieve wanden (Uniformat) | Model Group:NLRS_21.21_WA_wand 002 d=300_gen:4803266
3 x Basic Wall:NLRS_21.21_WA_beton prefab d=300/320_gen:4803321 | 42 tweeënveertigste verdieping | 21.21 buitenwanden - constructief, massieve wanden (Uniformat) | Model Group:NLRS_21.21_WA_wand 004 d=300_gen:4803265
2 x Basic Wall:NLRS_21.21_WA_beton prefab d=300/320_gen:5365657 | 42 tweeënveertigste verdieping | 21.21 buitenwanden - constructief, massieve wanden (Uniformat) | Model Group:NLRS_21.21_WA_wand 004 d=300_gen:4803265
3 x Basic Wall:NLRS_21.21_WA_beton prefab d=300/320_gen:4803323 | 42 tweeënveertigste verdieping | 21.21 buitenwanden - constructief, massieve wanden (Uniformat) | Model Group:NLRS_21.21_WA_wand 004 d=300_gen:4803256
2 x Basic Wall:NLRS_21.21_WA_beton prefab d=300/320_gen:5365657 | 42 tweeënveertigste verdieping | 21.21 buitenwanden - constructief, massieve wanden (Uniformat) | Model Group:NLRS_21.21_WA_wand 004 d=300_gen:4803256
Basic Wall:NLRS_21.21_WA_beton prefab d=300/320_gen:4803430 | 42 tweeënveertigste verdieping | 21.21 buitenwanden - constructief, massieve wanden (Uniformat) | Model Group:NLRS_28.21_WA_3D element 002 d=300_gen:4803445
Basic Wall:NLRS_21.21_WA_beton prefab d=300/320_gen:4803432 | 42 tweeënveertigste verdieping | 21.21 buitenwanden - constructief, massieve wanden (Uniformat) | Model Group:NLRS_28.21_WA_3D element 002 d=300_gen:4803445
Basic Wall:NLRS_22.21_WA_beton prefab d=300_gen:4803492 | 42 tweeënveertigste verdieping | 22.21 binnenwanden - constructief, massieve wanden (Uniformat) | Model Group:NLRS_01.00_verdieping type N_gen:9026295
4 x Basic Wall:NLRS_22.21_WA_beton prefab d=300_gen:4472952 | 42 tweeënveertigste verdieping | 22.21 binnenwanden - constructief, massieve wanden (Uniformat) | Model Group:NLRS_01.00_verdieping type N_gen:9026295
Basic Wall:NLRS_22.21_WA_beton prefab d=300_gen:4803496 | 42 tweeënveertigste verdieping | 22.21 binnenwanden - constructief, massieve wanden (Uniformat) | Model Group:NLRS_01.00_verdieping type N_gen:9026295
Basic Wall:NLRS_22.21_WA_beton prefab d=300_gen:4803500 | 42 tweeënveertigste verdieping | 22.21 binnenwanden - constructief, massieve wanden (Uniformat) | Model Group:NLRS_01.00_verdieping type N_gen:9026295
Basic Wall:NLRS_21.21_WA_beton prefab d=300/320_gen:4803511 | 42 tweeënveertigste verdieping | 21.21 buitenwanden - constructief, massieve wanden (Uniformat) | Model Group:NLRS_28.21_WA_3D element 002 d=300_gen:4803429
Basic Wall:NLRS_21.21_WA_beton prefab d=300/320_gen:4803513 | 42 tweeënveertigste verdieping | 21.21 buitenwanden - constructief, massieve wanden (Uniformat) | Model Group:NLRS_28.21_WA_3D element 002 d=300_gen:4803429
Basic Wall:NLRS_22.21_WA_beton prefab d=300_gen:4803540 | 42 tweeënveertigste verdieping | 22.21 binnenwanden - constructief, massieve wanden (Uniformat) | Model Group:NLRS_01.00_verdieping type N_gen:9026295
Basic Wall:NLRS_22.21_WA_beton prefab d=300_gen:4803543 | 42 tweeënveertigste verdieping | 22.21 binnenwanden - constructief, massieve wanden (Uniformat) | Model Group:NLRS_01.00_verdieping type N_gen:9026295
Basic Wall:NLRS_22.21_WA_beton prefab d=300_gen:4803546 | 42 tweeënveertigste verdieping | 22.21 binnenwanden - constructief, massieve wanden (Uniformat) | Model Group:NLRS_01.00_verdieping type N_gen:9026295
Basic Wall:NLRS_22.21_WA_beton prefab d=300_gen:4803549 | 42 tweeënveertigste verdieping | 22.21 binnenwanden - constructief, massieve wanden (Uniformat) | Model Group:NLRS_01.00_verdieping type N_gen:9026295
Basic Wall:NLRS_22.21_WA_beton prefab d=300_gen:4803552 | 42 tweeënveertigste verdieping | 22.21 binnenwanden - constructief, massieve wanden (Uniformat) | Model Group:NLRS_01.00_verdieping type N_gen:9026295
Basic Wall:NLRS_21.21_WA_beton prefab d=300/320_gen:4803555 | 42 tweeënveertigste verdieping | 21.21 buitenwanden - constructief, massieve wanden (Uniformat) | Model Group:NLRS_28.21_WA_3D element 001 d=300_gen:4803428
Basic Wall:NLRS_21.21_WA_beton prefab d=300/320_gen:4803558 | 42 tweeënveertigste verdieping | 21.21 buitenwanden - constructief, massieve wanden (Uniformat) | Model Group:NLRS_28.21_WA_3D element 001 d=300_gen:4803428
Basic Wall:NLRS_21.21_WA_beton prefab d=300/320_gen:4803584 | 42 tweeënveertigste verdieping | 21.21 buitenwanden - constructief, massieve wanden (Uniformat) | Model Group:NLRS_28.21_WA_3D element 001 d=300_gen:4803446
Basic Wall:NLRS_21.21_WA_beton prefab d=300/320_gen:4803587 | 42 tweeënveertigste verdieping | 21.21 buitenwanden - constructief, massieve wanden (Uniformat) | Model Group:NLRS_28.21_WA_3D element 001 d=300_gen:4803446
2 x Basic Wall:NLRS_22.21_WA_beton prefab d=300_gen:4803614 | 42 tweeënveertigste verdieping | 22.21 binnenwanden - constructief, massieve wanden (Uniformat) | Model Group:NLRS_01.00_verdieping type N_gen:9026295
2 x Basic Wall:NLRS_22.21_WA_beton prefab d=300_gen:4803617 | 42 tweeënveertigste verdieping | 22.21 binnenwanden - constructief, massieve wanden (Uniformat) | Model Group:NLRS_01.00_verdieping type N_gen:9026295
2 x Basic Wall:NLRS_22.21_WA_beton prefab d=300_gen:4803619 | 42 tweeënveertigste verdieping | 22.21 binnenwanden - constructief, massieve wanden (Uniformat) | Model Group:NLRS_01.00_verdieping type N_gen:9026295
2 x Basic Wall:NLRS_22.21_WA_beton prefab d=500_gen:4822177 | 05 vijfde verdieping | 22.21 binnenwanden - constructief, massieve wanden (Uniformat)
2 x Basic Wall:NLRS_22.21_WA_beton prefab d=500_gen:4822187 | 05 vijfde verdieping | 22.21 binnenwanden - constructief, massieve wanden (Uniformat)
4 x Basic Wall:NLRS_22.21_WA_beton prefab d=200_gen:4822189 | 05 vijfde verdieping | 22.21 binnenwanden - constructief, massieve wanden (Uniformat) | Model Group:NLRS_22.21_WA_kern 05_gen:8891248
4 x Basic Wall:NLRS_22.21_WA_beton prefab d=200_gen:4822191 | 05 vijfde verdieping | 22.21 binnenwanden - constructief, massieve wanden (Uniformat) | Model Group:NLRS_22.21_WA_kern 05_gen:8891248
4 x Basic Wall:NLRS_22.21_WA_beton prefab d=200_gen:4822193 | 05 vijfde verdieping | 22.21 binnenwanden - constructief, massieve wanden (Uniformat) | Model Group:NLRS_22.21_WA_kern 05_gen:8891248
3 x Basic Wall:NLRS_22.21_WA_beton ihwg d=600_gen:4832684 | 03 derde verdieping | 22.21 binnenwanden - constructief, massieve wanden (Uniformat)
4 x Basic Wall:NLRS_22.21_WA_beton prefab d=250_gen:4832686 | 03 derde verdieping | 22.21 binnenwanden - constructief, massieve wanden (Uniformat) | Model Group:NLRS_22.21_WA_kern 01--04_gen:4832721
4 x Basic Wall:NLRS_22.21_WA_beton prefab d=200_gen:4832688 | 03 derde verdieping | 22.21 binnenwanden - constructief, massieve wanden (Uniformat) | Model Group:NLRS_22.21_WA_kern 01--04_gen:4832721
4 x Basic Wall:NLRS_22.21_WA_beton prefab d=200_gen:4832690 | 03 derde verdieping | 22.21 binnenwanden - constructief, massieve wanden (Uniformat) | Model Group:NLRS_22.21_WA_kern 01--04_gen:4832721
Basic Wall:NLRS_22.21_WA_beton ihwg d=600_gen:4832722:1 | 03 derde verdieping | 22.21 binnenwanden - constructief, massieve wanden (Uniformat)
Basic Wall:NLRS_22.21_WA_beton ihwg d=600_gen:4832722:2 | 03 derde verdieping | 22.21 binnenwanden - constructief, massieve wanden (Uniformat)
8 x Basic Wall:NLRS_22.21_WA_beton ihwg d=600_gen:4832722 | 03 derde verdieping | 22.21 binnenwanden - constructief, massieve wanden (Uniformat)
4 x Basic Wall:NLRS_21.21_WA_beton ihwg d=500_gen:4832741 | 03 derde verdieping | 21.21 buitenwanden - constructief, massieve wanden (Uniformat)
Basic Wall:NLRS_21.21_WA_beton ihwg d=1000_gen:4832743 | 03 derde verdieping | 21.21 buitenwanden - constructief, massieve wanden (Uniformat)
4 x Basic Wall:NLRS_21.21_WA_beton ihwg d=500_gen:4832745 | 03 derde verdieping | 21.21 buitenwanden - constructief, massieve wanden (Uniformat)
4 x Basic Wall:NLRS_21.21_WA_beton ihwg d=500_gen:4832747 | 03 derde verdieping | 21.21 buitenwanden - constructief, massieve wanden (Uniformat)
Basic Wall:NLRS_22.21_WA_beton ihwg d=600_gen:4832749:1 | 03 derde verdieping | 22.21 binnenwanden - constructief, massieve wanden (Uniformat)
13 x Basic Wall:NLRS_22.21_WA_beton ihwg d=600_gen:4832749 | 03 derde verdieping | 22.21 binnenwanden - constructief, massieve wanden (Uniformat)
Basic Wall:NLRS_22.21_WA_beton ihwg d=600_gen:4832755:1 | 03 derde verdieping | 22.21 binnenwanden - constructief, massieve wanden (Uniformat)
12 x Basic Wall:NLRS_22.21_WA_beton ihwg d=600_gen:4832755 | 03 derde verdieping | 22.21 binnenwanden - constructief, massieve wanden (Uniformat)
Basic Wall:NLRS_22.21_WA_beton ihwg d=600_gen:4832764:1 | 03 derde verdieping | 22.21 binnenwanden - constructief, massieve wanden (Uniformat)
Basic Wall:NLRS_22.21_WA_beton ihwg d=600_gen:4832764:2 | 03 derde verdieping | 22.21 binnenwanden - constructief, massieve wanden (Uniformat)
8 x Basic Wall:NLRS_22.21_WA_beton ihwg d=600_gen:4832764 | 03 derde verdieping | 22.21 binnenwanden - constructief, massieve wanden (Uniformat)
Floor:NLRS_23.21_FL_vloer=230_gen:4860048:2 | 06 zesde verdieping | 23.21 vloeren - constructief, vrijdragende vloeren (Uniformat) | Model Group:NLRS_22.21_WA_kern 06--51_gen:4690937
Basic Wall:NLRS_22.21_WA_beton ihwg d=600_gen:4866030 | 01 eerste verdieping | 22.21 binnenwanden - constructief, massieve wanden (Uniformat)
4 x Basic Wall:NLRS_22.21_WA_beton prefab d=250_gen:4869698 | 02 tweede verdieping | 22.21 binnenwanden - constructief, massieve wanden (Uniformat) | Model Group:NLRS_22.21_WA_kern 01--04_gen:4869716
4 x Basic Wall:NLRS_22.21_WA_beton prefab d=200_gen:4869700 | 02 tweede verdieping | 22.21 binnenwanden - constructief, massieve wanden (Uniformat) | Model Group:NLRS_22.21_WA_kern 01--04_gen:4869716
4 x Basic Wall:NLRS_22.21_WA_beton prefab d=200_gen:4869702 | 02 tweede verdieping | 22.21 binnenwanden - constructief, massieve wanden (Uniformat) | Model Group:NLRS_22.21_WA_kern 01--04_gen:4869716
4 x Basic Wall:NLRS_22.21_WA_beton prefab d=250_gen:4870136 | 01 eerste verdieping | 22.21 binnenwanden - constructief, massieve wanden (Uniformat)
4 x Basic Wall:NLRS_22.21_WA_beton prefab d=200_gen:4870138 | 01 eerste verdieping | 22.21 binnenwanden - constructief, massieve wanden (Uniformat)
4 x Basic Wall:NLRS_22.21_WA_beton prefab d=200_gen:4870140 | 01 eerste verdieping | 22.21 binnenwanden - constructief, massieve wanden (Uniformat)
261 x  | 01 eerste verdieping
Floor:NLRS_23.21_FL_beton breedplaat d=70/240_gen:4870157:2 | 01 eerste verdieping | 23.21 vloeren - constructief, vrijdragende vloeren (Uniformat)
4 x Basic Wall:NLRS_22.21_WA_beton prefab d=200_gen:4870840 | 00a eerste tussenverdieping | 22.21 binnenwanden - constructief, massieve wanden (Uniformat)
Basic Wall:NLRS_22.21_WA_beton prefab d=200_gen:4872357 | 03 derde verdieping | 22.21 binnenwanden - constructief, massieve wanden (Uniformat)
2 x Basic Wall:NLRS_22.21_WA_beton prefab d=200_gen:4872409 | 04 vierde verdieping | 22.21 binnenwanden - constructief, massieve wanden (Uniformat)
2 x Basic Wall:NLRS_22.21_WA_beton prefab d=200_gen:4872411 | 04 vierde verdieping | 22.21 binnenwanden - constructief, massieve wanden (Uniformat)
4 x Basic Wall:NLRS_22.21_WA_beton prefab d=250_gen:4876000 | 00 begane grond | 22.21 binnenwanden - constructief, massieve wanden (Uniformat) | Model Group:NLRS_22.21_WA_kern 00_gen:4876018
4 x Basic Wall:NLRS_22.21_WA_beton prefab d=200_gen:4876002 | 00 begane grond | 22.21 binnenwanden - constructief, massieve wanden (Uniformat) | Model Group:NLRS_22.21_WA_kern 00_gen:4876018
2 x Basic Wall:NLRS_22.21_WA_beton prefab d=200_gen:4876004 | 00 begane grond | 22.21 binnenwanden - constructief, massieve wanden (Uniformat) | Model Group:NLRS_22.21_WA_kern 00_gen:4876018
4 x Basic Wall:NLRS_22.21_WA_beton prefab d=200_gen:4876883 | 01 eerste verdieping | 22.21 binnenwanden - constructief, massieve wanden (Uniformat)
Basic Wall:NLRS_22.21_WA_beton prefab d=200_gen:4876885 | 01 eerste verdieping | 22.21 binnenwanden - constructief, massieve wanden (Uniformat)
2 x Basic Wall:NLRS_22.21_WA_beton prefab d=200_gen:4876887 | 01 eerste verdieping | 22.21 binnenwanden - constructief, massieve wanden (Uniformat)
3 x Basic Wall:NLRS_22.21_WA_beton prefab d=200_gen:4876891 | 01 eerste verdieping | 22.21 binnenwanden - constructief, massieve wanden (Uniformat)
3 x Basic Wall:NLRS_22.21_WA_beton prefab d=200_gen:4876893 | 01 eerste verdieping | 22.21 binnenwanden - constructief, massieve wanden (Uniformat)
Floor:NLRS_23.21_FL_druklaag d=70_gen:4877166:2 | 02 tweede verdieping | 23.21 vloeren - constructief, vrijdragende vloeren (Uniformat)
3 x Basic Wall:NLRS_22.21_WA_beton prefab d=200_gen:4880098 | 01 eerste verdieping | 22.21 binnenwanden - constructief, massieve wanden (Uniformat)
3 x Basic Wall:NLRS_22.21_WA_beton prefab d=200_gen:4881099 | 02 tweede verdieping | 22.21 binnenwanden - constructief, massieve wanden (Uniformat)
4 x Basic Wall:NLRS_21.21_WA_beton prefab d=200_gen:4881279 | 03 derde verdieping | 21.21 buitenwanden - constructief, massieve wanden (Uniformat)
3 x Basic Wall:NLRS_22.21_WA_beton prefab d=200_gen:4882470 | 02 tweede verdieping | 22.21 binnenwanden - constructief, massieve wanden (Uniformat)
2 x Basic Wall:NLRS_22.21_WA_beton prefab d=200_gen:1312531 | 02 tweede verdieping | 22.21 binnenwanden - constructief, massieve wanden (Uniformat)
Basic Wall:NLRS_22.21_WA_beton prefab d=200_gen:4882472 | 02 tweede verdieping | 22.21 binnenwanden - constructief, massieve wanden (Uniformat)
Basic Wall:NLRS_22.21_WA_beton prefab d=200_gen:4882857 | 02 tweede verdieping | 22.21 binnenwanden - constructief, massieve wanden (Uniformat)
2 x Basic Wall:NLRS_21.21_WA_beton prefab d=200_gen:4882996 | 03 derde verdieping | 21.21 buitenwanden - constructief, massieve wanden (Uniformat)
3 x Basic Wall:NLRS_21.21_WA_beton prefab d=200_gen:4882998 | 03 derde verdieping | 21.21 buitenwanden - constructief, massieve wanden (Uniformat)
2 x Basic Wall:NLRS_22.21_WA_beton prefab d=200_gen:4885540 | 02 tweede verdieping | 22.21 binnenwanden - constructief, massieve wanden (Uniformat)
2 x Basic Wall:NLRS_22.21_WA_beton prefab d=200_gen:4885725 | 02 tweede verdieping | 22.21 binnenwanden - constructief, massieve wanden (Uniformat)
Basic Wall:NLRS_21.21_WA_beton prefab d=200_gen:4888130 | 03 derde verdieping | 21.21 buitenwanden - constructief, massieve wanden (Uniformat)
Basic Wall:NLRS_21.21_WA_beton prefab d=200_gen:1307922 | 03 derde verdieping | 21.21 buitenwanden - constructief, massieve wanden (Uniformat)
Basic Wall:NLRS_21.21_WA_beton prefab d=200_gen:1307922 | 02 tweede verdieping | 21.21 buitenwanden - constructief, massieve wanden (Uniformat)
4 x Basic Wall:NLRS_22.21_WA_beton prefab d=250_gen:4941772 | 04 vierde verdieping | 22.21 binnenwanden - constructief, massieve wanden (Uniformat) | Model Group:NLRS_22.21_WA_kern 01--04_gen:4941798
4 x Basic Wall:NLRS_22.21_WA_beton prefab d=200_gen:4941774 | 04 vierde verdieping | 22.21 binnenwanden - constructief, massieve wanden (Uniformat) | Model Group:NLRS_22.21_WA_kern 01--04_gen:4941798
4 x Basic Wall:NLRS_22.21_WA_beton prefab d=200_gen:4941776 | 04 vierde verdieping | 22.21 binnenwanden - constructief, massieve wanden (Uniformat) | Model Group:NLRS_22.21_WA_kern 01--04_gen:4941798
2 x Basic Wall:NLRS_22.21_WA_beton ihwg d=600_gen:4941804 | 04 vierde verdieping | 22.21 binnenwanden - constructief, massieve wanden (Uniformat)
Basic Wall:NLRS_22.21_WA_beton ihwg d=600_gen:4941807:1 | 04 vierde verdieping | 22.21 binnenwanden - constructief, massieve wanden (Uniformat)
Basic Wall:NLRS_22.21_WA_beton ihwg d=600_gen:4941807:2 | 04 vierde verdieping | 22.21 binnenwanden - constructief, massieve wanden (Uniformat)
7 x Basic Wall:NLRS_22.21_WA_beton ihwg d=600_gen:4941807 | 04 vierde verdieping | 22.21 binnenwanden - constructief, massieve wanden (Uniformat)
Basic Wall:NLRS_22.21_WA_beton ihwg d=600_gen:4941812 | 04 vierde verdieping | 22.21 binnenwanden - constructief, massieve wanden (Uniformat)
Basic Wall:NLRS_22.21_WA_beton ihwg d=600_gen:4941832:1 | 04 vierde verdieping | 22.21 binnenwanden - constructief, massieve wanden (Uniformat)
16 x Basic Wall:NLRS_22.21_WA_beton ihwg d=600_gen:4941832 | 04 vierde verdieping | 22.21 binnenwanden - constructief, massieve wanden (Uniformat)
Basic Wall:NLRS_22.21_WA_beton ihwg d=600_gen:4941838:1 | 04 vierde verdieping | 22.21 binnenwanden - constructief, massieve wanden (Uniformat)
16 x Basic Wall:NLRS_22.21_WA_beton ihwg d=600_gen:4941838 | 04 vierde verdieping | 22.21 binnenwanden - constructief, massieve wanden (Uniformat)
Basic Wall:NLRS_22.21_WA_beton ihwg d=600_gen:4941847:1 | 04 vierde verdieping | 22.21 binnenwanden - constructief, massieve wanden (Uniformat)
Basic Wall:NLRS_22.21_WA_beton ihwg d=600_gen:4941847:2 | 04 vierde verdieping | 22.21 binnenwanden - constructief, massieve wanden (Uniformat)
7 x Basic Wall:NLRS_22.21_WA_beton ihwg d=600_gen:4941847 | 04 vierde verdieping | 22.21 binnenwanden - constructief, massieve wanden (Uniformat)
4 x Basic Wall:NLRS_22.21_WA_beton prefab d=200_gen:4971860 | 53 drieënvijftigste verdieping | 22.21 binnenwanden - constructief, massieve wanden (Uniformat)
4 x Basic Wall:NLRS_22.21_WA_beton prefab d=200_gen:4971862 | 53 drieënvijftigste verdieping | 22.21 binnenwanden - constructief, massieve wanden (Uniformat)
4 x Basic Wall:NLRS_22.21_WA_beton prefab d=200_gen:4971864 | 53 drieënvijftigste verdieping | 22.21 binnenwanden - constructief, massieve wanden (Uniformat)
Basic Wall:NLRS_22.21_WA_beton prefab d=300_gen:4979942 | 51 eenenvijftigste verdieping | 22.21 binnenwanden - constructief, massieve wanden (Uniformat) | Model Group:NLRS_01.00_verdieping type R_gen:4806332
Basic Wall:NLRS_22.21_WA_beton prefab d=300_gen:4979944 | 51 eenenvijftigste verdieping | 22.21 binnenwanden - constructief, massieve wanden (Uniformat) | Model Group:NLRS_01.00_verdieping type R_gen:4806332
2 x Basic Wall:NLRS_22.21_WA_beton prefab d=300_gen:4979946 | 51 eenenvijftigste verdieping | 22.21 binnenwanden - constructief, massieve wanden (Uniformat) | Model Group:NLRS_01.00_verdieping type R_gen:4806332
Basic Wall:NLRS_22.21_WA_beton prefab d=300_gen:4979960 | 51 eenenvijftigste verdieping | 22.21 binnenwanden - constructief, massieve wanden (Uniformat)
Basic Wall:NLRS_22.21_WA_beton prefab d=300_gen:4979962 | 51 eenenvijftigste verdieping | 22.21 binnenwanden - constructief, massieve wanden (Uniformat)
Basic Wall:NLRS_22.21_WA_beton prefab d=300_gen:4980010 | 51 eenenvijftigste verdieping | 22.21 binnenwanden - constructief, massieve wanden (Uniformat)
Basic Wall:NLRS_22.21_WA_beton prefab d=300_gen:4980014 | 51 eenenvijftigste verdieping | 22.21 binnenwanden - constructief, massieve wanden (Uniformat)
3 x Basic Wall:NLRS_21.21_WA_beton prefab d=300/320_gen:4980029 | 51 eenenvijftigste verdieping | 21.21 buitenwanden - constructief, massieve wanden (Uniformat) | Model Group:NLRS_21.21_WA_wand 002 d=300_gen:4980007
2 x Basic Wall:NLRS_21.21_WA_beton prefab d=300/320_gen:5365657 | 51 eenenvijftigste verdieping | 21.21 buitenwanden - constructief, massieve wanden (Uniformat) | Model Group:NLRS_21.21_WA_wand 002 d=300_gen:4980007
3 x Basic Wall:NLRS_21.21_WA_beton prefab d=300/320_gen:4980031 | 51 eenenvijftigste verdieping | 21.21 buitenwanden - constructief, massieve wanden (Uniformat) | Model Group:NLRS_21.21_WA_wand 002 d=300_gen:4980000
2 x Basic Wall:NLRS_21.21_WA_beton prefab d=300/320_gen:5365657 | 51 eenenvijftigste verdieping | 21.21 buitenwanden - constructief, massieve wanden (Uniformat) | Model Group:NLRS_21.21_WA_wand 002 d=300_gen:4980000
3 x Basic Wall:NLRS_21.21_WA_beton prefab d=300/320_gen:4980055 | 51 eenenvijftigste verdieping | 21.21 buitenwanden - constructief, massieve wanden (Uniformat) | Model Group:NLRS_21.21_WA_wand 004 d=300_gen:4979999
2 x Basic Wall:NLRS_21.21_WA_beton prefab d=300/320_gen:5365657 | 51 eenenvijftigste verdieping | 21.21 buitenwanden - constructief, massieve wanden (Uniformat) | Model Group:NLRS_21.21_WA_wand 004 d=300_gen:4979999
3 x Basic Wall:NLRS_21.21_WA_beton prefab d=300/320_gen:4980057 | 51 eenenvijftigste verdieping | 21.21 buitenwanden - constructief, massieve wanden (Uniformat) | Model Group:NLRS_21.21_WA_wand 004 d=300_gen:4979990
2 x Basic Wall:NLRS_21.21_WA_beton prefab d=300/320_gen:5365657 | 51 eenenvijftigste verdieping | 21.21 buitenwanden - constructief, massieve wanden (Uniformat) | Model Group:NLRS_21.21_WA_wand 004 d=300_gen:4979990
Basic Wall:NLRS_21.21_WA_beton prefab d=300/320_gen:4980148 | 51 eenenvijftigste verdieping | 21.21 buitenwanden - constructief, massieve wanden (Uniformat) | Model Group:NLRS_28.21_WA_3D element 002 d=300_gen:4980163
Basic Wall:NLRS_21.21_WA_beton prefab d=300/320_gen:4980150 | 51 eenenvijftigste verdieping | 21.21 buitenwanden - constructief, massieve wanden (Uniformat) | Model Group:NLRS_28.21_WA_3D element 002 d=300_gen:4980163
Basic Wall:NLRS_22.21_WA_beton prefab d=300_gen:4980202 | 51 eenenvijftigste verdieping | 22.21 binnenwanden - constructief, massieve wanden (Uniformat) | Model Group:NLRS_01.00_verdieping type R_gen:4806332
4 x Basic Wall:NLRS_22.21_WA_beton prefab d=300_gen:4472952 | 51 eenenvijftigste verdieping | 22.21 binnenwanden - constructief, massieve wanden (Uniformat) | Model Group:NLRS_01.00_verdieping type R_gen:4806332
Basic Wall:NLRS_22.21_WA_beton prefab d=300_gen:4980206 | 51 eenenvijftigste verdieping | 22.21 binnenwanden - constructief, massieve wanden (Uniformat) | Model Group:NLRS_01.00_verdieping type R_gen:4806332
Basic Wall:NLRS_22.21_WA_beton prefab d=300_gen:4980210 | 51 eenenvijftigste verdieping | 22.21 binnenwanden - constructief, massieve wanden (Uniformat) | Model Group:NLRS_01.00_verdieping type R_gen:4806332
Basic Wall:NLRS_21.21_WA_beton prefab d=300/320_gen:4980221 | 51 eenenvijftigste verdieping | 21.21 buitenwanden - constructief, massieve wanden (Uniformat) | Model Group:NLRS_28.21_WA_3D element 002 d=300_gen:4980147
Basic Wall:NLRS_21.21_WA_beton prefab d=300/320_gen:4980223 | 51 eenenvijftigste verdieping | 21.21 buitenwanden - constructief, massieve wanden (Uniformat) | Model Group:NLRS_28.21_WA_3D element 002 d=300_gen:4980147
Basic Wall:NLRS_22.21_WA_beton prefab d=300_gen:4980250 | 51 eenenvijftigste verdieping | 22.21 binnenwanden - constructief, massieve wanden (Uniformat) | Model Group:NLRS_01.00_verdieping type R_gen:4806332
Basic Wall:NLRS_22.21_WA_beton prefab d=300_gen:4980253 | 51 eenenvijftigste verdieping | 22.21 binnenwanden - constructief, massieve wanden (Uniformat) | Model Group:NLRS_01.00_verdieping type R_gen:4806332
Basic Wall:NLRS_22.21_WA_beton prefab d=300_gen:4980256 | 51 eenenvijftigste verdieping | 22.21 binnenwanden - constructief, massieve wanden (Uniformat) | Model Group:NLRS_01.00_verdieping type R_gen:4806332
Basic Wall:NLRS_22.21_WA_beton prefab d=300_gen:4980259 | 51 eenenvijftigste verdieping | 22.21 binnenwanden - constructief, massieve wanden (Uniformat) | Model Group:NLRS_01.00_verdieping type R_gen:4806332
Basic Wall:NLRS_22.21_WA_beton prefab d=300_gen:4980262 | 51 eenenvijftigste verdieping | 22.21 binnenwanden - constructief, massieve wanden (Uniformat) | Model Group:NLRS_01.00_verdieping type R_gen:4806332
Basic Wall:NLRS_21.21_WA_beton prefab d=300/320_gen:4980265 | 51 eenenvijftigste verdieping | 21.21 buitenwanden - constructief, massieve wanden (Uniformat) | Model Group:NLRS_28.21_WA_3D element 001 d=300_gen:4980146
Basic Wall:NLRS_21.21_WA_beton prefab d=300/320_gen:4980268 | 51 eenenvijftigste verdieping | 21.21 buitenwanden - constructief, massieve wanden (Uniformat) | Model Group:NLRS_28.21_WA_3D element 001 d=300_gen:4980146
Basic Wall:NLRS_21.21_WA_beton prefab d=300/320_gen:4980294 | 51 eenenvijftigste verdieping | 21.21 buitenwanden - constructief, massieve wanden (Uniformat) | Model Group:NLRS_28.21_WA_3D element 001 d=300_gen:4980164
Basic Wall:NLRS_21.21_WA_beton prefab d=300/320_gen:4980297 | 51 eenenvijftigste verdieping | 21.21 buitenwanden - constructief, massieve wanden (Uniformat) | Model Group:NLRS_28.21_WA_3D element 001 d=300_gen:4980164
2 x Basic Wall:NLRS_22.21_WA_beton prefab d=300_gen:4980324 | 51 eenenvijftigste verdieping | 22.21 binnenwanden - constructief, massieve wanden (Uniformat) | Model Group:NLRS_01.00_verdieping type R_gen:4806332
2 x Basic Wall:NLRS_22.21_WA_beton prefab d=300_gen:4980327 | 51 eenenvijftigste verdieping | 22.21 binnenwanden - constructief, massieve wanden (Uniformat) | Model Group:NLRS_01.00_verdieping type R_gen:4806332
2 x Basic Wall:NLRS_22.21_WA_beton prefab d=300_gen:4980329 | 51 eenenvijftigste verdieping | 22.21 binnenwanden - constructief, massieve wanden (Uniformat) | Model Group:NLRS_01.00_verdieping type R_gen:4806332
Basic Wall:NLRS_22.21_WA_beton prefab d=300_gen:4981716 | 52 tweeënvijftigste verdieping | 22.21 binnenwanden - constructief, massieve wanden (Uniformat)
2 x Basic Wall:NLRS_22.21_WA_beton prefab d=300_gen:4981718 | 52 tweeënvijftigste verdieping | 22.21 binnenwanden - constructief, massieve wanden (Uniformat)
4 x Basic Wall:NLRS_22.21_WA_beton prefab d=200_gen:4981720 | 52 tweeënvijftigste verdieping | 22.21 binnenwanden - constructief, massieve wanden (Uniformat)
4 x Basic Wall:NLRS_22.21_WA_beton prefab d=200_gen:4981722 | 52 tweeënvijftigste verdieping | 22.21 binnenwanden - constructief, massieve wanden (Uniformat)
4 x Basic Wall:NLRS_22.21_WA_beton prefab d=200_gen:4981724 | 52 tweeënvijftigste verdieping | 22.21 binnenwanden - constructief, massieve wanden (Uniformat)
3 x Basic Wall:NLRS_21.21_WA_beton prefab d=300/320_gen:4981801 | 52 tweeënvijftigste verdieping | 21.21 buitenwanden - constructief, massieve wanden (Uniformat) | Model Group:NLRS_21.21_WA_wand 002c d=300_gen:4981779
2 x Basic Wall:NLRS_21.21_WA_beton prefab d=300/320_gen:5365657 | 52 tweeënvijftigste verdieping | 21.21 buitenwanden - constructief, massieve wanden (Uniformat) | Model Group:NLRS_21.21_WA_wand 002c d=300_gen:4981779
3 x Basic Wall:NLRS_21.21_WA_beton prefab d=300/320_gen:4981803 | 52 tweeënvijftigste verdieping | 21.21 buitenwanden - constructief, massieve wanden (Uniformat) | Model Group:NLRS_21.21_WA_wand 002c d=300_gen:4981772
2 x Basic Wall:NLRS_21.21_WA_beton prefab d=300/320_gen:5365657 | 52 tweeënvijftigste verdieping | 21.21 buitenwanden - constructief, massieve wanden (Uniformat) | Model Group:NLRS_21.21_WA_wand 002c d=300_gen:4981772
3 x Basic Wall:NLRS_21.21_WA_beton prefab d=300/320_gen:4981827 | 52 tweeënvijftigste verdieping | 21.21 buitenwanden - constructief, massieve wanden (Uniformat) | Model Group:NLRS_21.21_WA_wand 004c d=300_gen:4981771
2 x Basic Wall:NLRS_21.21_WA_beton prefab d=300/320_gen:5365657 | 52 tweeënvijftigste verdieping | 21.21 buitenwanden - constructief, massieve wanden (Uniformat) | Model Group:NLRS_21.21_WA_wand 004c d=300_gen:4981771
3 x Basic Wall:NLRS_21.21_WA_beton prefab d=300/320_gen:4981829 | 52 tweeënvijftigste verdieping | 21.21 buitenwanden - constructief, massieve wanden (Uniformat) | Model Group:NLRS_21.21_WA_wand 004c d=300_gen:4981762
2 x Basic Wall:NLRS_21.21_WA_beton prefab d=300/320_gen:5365657 | 52 tweeënvijftigste verdieping | 21.21 buitenwanden - constructief, massieve wanden (Uniformat) | Model Group:NLRS_21.21_WA_wand 004c d=300_gen:4981762
Basic Wall:NLRS_22.21_WA_beton prefab d=300_gen:4981978 | 52 tweeënvijftigste verdieping | 22.21 binnenwanden - constructief, massieve wanden (Uniformat)
Basic Wall:NLRS_21.21_WA_beton prefab d=300/320_gen:4981993 | 52 tweeënvijftigste verdieping | 21.21 buitenwanden - constructief, massieve wanden (Uniformat) | Model Group:NLRS_28.21_WA_3D element 002a d=300_gen:4981919
Basic Wall:NLRS_21.21_WA_beton prefab d=300/320_gen:4981995 | 52 tweeënvijftigste verdieping | 21.21 buitenwanden - constructief, massieve wanden (Uniformat) | Model Group:NLRS_28.21_WA_3D element 002a d=300_gen:4981919
Basic Wall:NLRS_22.21_WA_beton prefab d=300_gen:4982028 | 52 tweeënvijftigste verdieping | 22.21 binnenwanden - constructief, massieve wanden (Uniformat)
Basic Wall:NLRS_21.21_WA_beton prefab d=300/320_gen:4982037 | 52 tweeënvijftigste verdieping | 21.21 buitenwanden - constructief, massieve wanden (Uniformat) | Model Group:NLRS_28.21_WA_3D element 001a d=300_gen:4981918
Basic Wall:NLRS_21.21_WA_beton prefab d=300/320_gen:4982040 | 52 tweeënvijftigste verdieping | 21.21 buitenwanden - constructief, massieve wanden (Uniformat) | Model Group:NLRS_28.21_WA_3D element 001a d=300_gen:4981918
2 x Basic Wall:NLRS_22.21_WA_beton prefab d=300_gen:4982096 | 52 tweeënvijftigste verdieping | 22.21 binnenwanden - constructief, massieve wanden (Uniformat)
2 x Basic Wall:NLRS_22.21_WA_beton prefab d=300_gen:4472952 | 52 tweeënvijftigste verdieping | 22.21 binnenwanden - constructief, massieve wanden (Uniformat)
2 x Basic Wall:NLRS_22.21_WA_beton prefab d=300_gen:4982099 | 52 tweeënvijftigste verdieping | 22.21 binnenwanden - constructief, massieve wanden (Uniformat)
2 x Basic Wall:NLRS_22.21_WA_beton prefab d=300_gen:4982101 | 52 tweeënvijftigste verdieping | 22.21 binnenwanden - constructief, massieve wanden (Uniformat)
4 x Basic Wall:NLRS_22.21_WA_beton prefab d=200_gen:5001088 | 54 vierenvijftigste verdieping | 22.21 binnenwanden - constructief, massieve wanden (Uniformat)
3 x Basic Wall:NLRS_22.21_WA_beton prefab d=200_gen:5001090 | 54 vierenvijftigste verdieping | 22.21 binnenwanden - constructief, massieve wanden (Uniformat)
4 x Basic Wall:NLRS_22.21_WA_beton prefab d=200_gen:5001092 | 54 vierenvijftigste verdieping | 22.21 binnenwanden - constructief, massieve wanden (Uniformat)
2 x Basic Wall:NLRS_22.21_WA_beton prefab d=200_gen:5003622 | 57 zevenenvijftigste verdieping | 22.21 binnenwanden - constructief, massieve wanden (Uniformat)
3 x Basic Wall:NLRS_22.21_WA_beton prefab d=200_gen:5003624 | 57 zevenenvijftigste verdieping | 22.21 binnenwanden - constructief, massieve wanden (Uniformat)
3 x Basic Wall:NLRS_22.21_WA_beton prefab d=200_gen:5003626 | 57 zevenenvijftigste verdieping | 22.21 binnenwanden - constructief, massieve wanden (Uniformat)
2 x Basic Wall:NLRS_22.21_WA_beton prefab d=200_gen:5003673 | 57 zevenenvijftigste verdieping | 22.21 binnenwanden - constructief, massieve wanden (Uniformat)
Basic Wall:NLRS_22.21_WA_beton prefab d=200_gen:5005558 | 58 achtenvijftigste verdieping | 22.21 binnenwanden - constructief, massieve wanden (Uniformat)
Basic Wall:NLRS_22.21_WA_beton prefab d=200_gen:5005560 | 58 achtenvijftigste verdieping | 22.21 binnenwanden - constructief, massieve wanden (Uniformat)
2 x Basic Wall:NLRS_22.21_WA_beton prefab d=200_gen:5005607 | 58 achtenvijftigste verdieping | 22.21 binnenwanden - constructief, massieve wanden (Uniformat)
4 x Basic Wall:NLRS_22.21_WA_beton prefab d=200_gen:5009598 | 56 zesenvijftigste verdieping | 22.21 binnenwanden - constructief, massieve wanden (Uniformat)
3 x Basic Wall:NLRS_22.21_WA_beton prefab d=200_gen:5009600 | 56 zesenvijftigste verdieping | 22.21 binnenwanden - constructief, massieve wanden (Uniformat)
4 x Basic Wall:NLRS_22.21_WA_beton prefab d=200_gen:5009602 | 56 zesenvijftigste verdieping | 22.21 binnenwanden - constructief, massieve wanden (Uniformat)
2 x Basic Wall:NLRS_22.21_WA_beton prefab d=200_gen:5009649 | 56 zesenvijftigste verdieping | 22.21 binnenwanden - constructief, massieve wanden (Uniformat)
4 x Basic Wall:NLRS_22.21_WA_beton prefab d=200_gen:5009929 | 55 vijfenvijftigste verdieping | 22.21 binnenwanden - constructief, massieve wanden (Uniformat)
3 x Basic Wall:NLRS_22.21_WA_beton prefab d=200_gen:5009931 | 55 vijfenvijftigste verdieping | 22.21 binnenwanden - constructief, massieve wanden (Uniformat)
2 x Basic Wall:NLRS_22.21_WA_beton prefab d=200_gen:1312531 | 55 vijfenvijftigste verdieping | 22.21 binnenwanden - constructief, massieve wanden (Uniformat)
2 x Basic Wall:NLRS_22.21_WA_beton prefab d=200_gen:5009933 | 55 vijfenvijftigste verdieping | 22.21 binnenwanden - constructief, massieve wanden (Uniformat)
Basic Wall:NLRS_22.21_WA_beton prefab d=300_gen:5012149 | 52 tweeënvijftigste verdieping | 22.21 binnenwanden - constructief, massieve wanden (Uniformat)
2 x Basic Wall:NLRS_22.21_WA_beton prefab d=300_gen:5012685 | 53 drieënvijftigste verdieping | 22.21 binnenwanden - constructief, massieve wanden (Uniformat)
2 x Basic Wall:NLRS_22.21_WA_beton prefab d=300_gen:5012725 | 53 drieënvijftigste verdieping | 22.21 binnenwanden - constructief, massieve wanden (Uniformat)
Basic Wall:NLRS_22.21_WA_beton prefab d=300_gen:4472952 | 53 drieënvijftigste verdieping | 22.21 binnenwanden - constructief, massieve wanden (Uniformat)
2 x Basic Wall:NLRS_22.21_WA_beton prefab d=300_gen:5012762 | 53 drieënvijftigste verdieping | 22.21 binnenwanden - constructief, massieve wanden (Uniformat)
2 x Basic Wall:NLRS_22.21_WA_beton prefab d=300_gen:5012803 | 53 drieënvijftigste verdieping | 22.21 binnenwanden - constructief, massieve wanden (Uniformat)
2 x Basic Wall:NLRS_22.21_WA_beton prefab d=250_gen:5013012 | 54 vierenvijftigste verdieping | 22.21 binnenwanden - constructief, massieve wanden (Uniformat)
2 x Basic Wall:NLRS_22.21_WA_beton prefab d=250_gen:5013046 | 54 vierenvijftigste verdieping | 22.21 binnenwanden - constructief, massieve wanden (Uniformat)
2 x Basic Wall:NLRS_22.21_WA_beton prefab d=250_gen:5013077 | 54 vierenvijftigste verdieping | 22.21 binnenwanden - constructief, massieve wanden (Uniformat)
2 x Basic Wall:NLRS_22.21_WA_beton prefab d=250_gen:5013111 | 54 vierenvijftigste verdieping | 22.21 binnenwanden - constructief, massieve wanden (Uniformat)
2 x Basic Wall:NLRS_22.21_WA_beton prefab d=250_gen:5033396 | 55 vijfenvijftigste verdieping | 22.21 binnenwanden - constructief, massieve wanden (Uniformat)
2 x Basic Wall:NLRS_22.21_WA_beton prefab d=250_gen:5033637 | 55 vijfenvijftigste verdieping | 22.21 binnenwanden - constructief, massieve wanden (Uniformat)
2 x Basic Wall:NLRS_22.21_WA_beton prefab d=250_gen:5033694 | 55 vijfenvijftigste verdieping | 22.21 binnenwanden - constructief, massieve wanden (Uniformat)
2 x Basic Wall:NLRS_22.21_WA_beton prefab d=250_gen:5034777 | 56 zesenvijftigste verdieping | 22.21 binnenwanden - constructief, massieve wanden (Uniformat)
2 x Basic Wall:NLRS_22.21_WA_beton prefab d=250_gen:5034832 | 56 zesenvijftigste verdieping | 22.21 binnenwanden - constructief, massieve wanden (Uniformat)
2 x Basic Wall:NLRS_22.21_WA_beton prefab d=250_gen:5034887 | 56 zesenvijftigste verdieping | 22.21 binnenwanden - constructief, massieve wanden (Uniformat)
2 x Basic Wall:NLRS_22.21_WA_beton prefab d=250_gen:5034944 | 56 zesenvijftigste verdieping | 22.21 binnenwanden - constructief, massieve wanden (Uniformat)
Basic Wall:NLRS_21.21_WA_beton prefab d=400/420_gen:5042423 | 05 vijfde verdieping | 21.21 buitenwanden - constructief, massieve wanden (Uniformat)
3 x Basic Wall:NLRS_21.21_WA_beton ihwg d=400/420_gen:5042426 | 05 vijfde verdieping | 21.21 buitenwanden - constructief, massieve wanden (Uniformat)
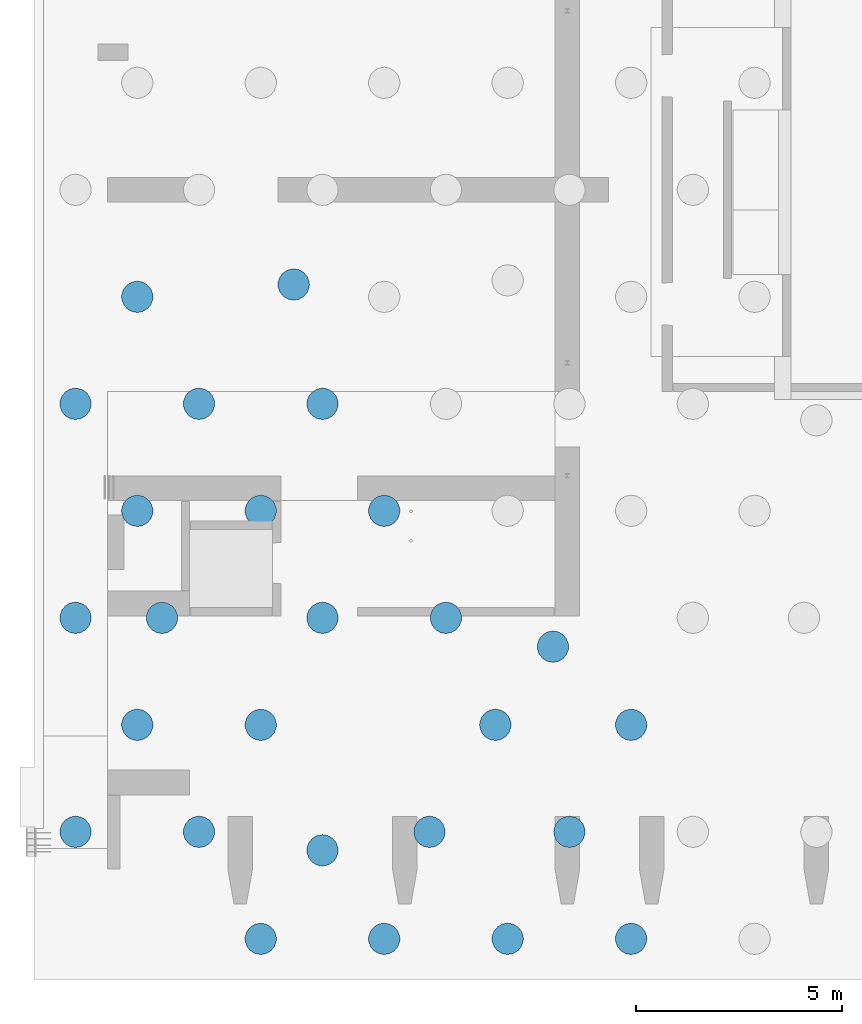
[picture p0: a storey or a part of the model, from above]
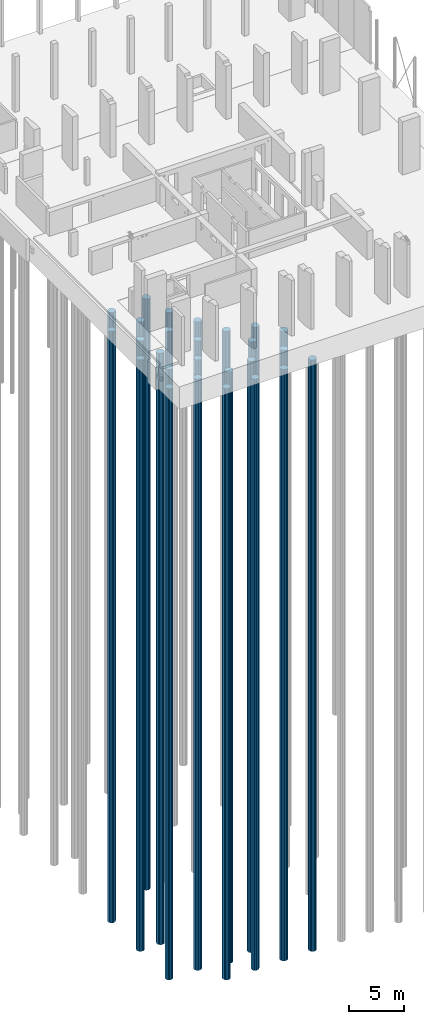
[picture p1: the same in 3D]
Properties of the parts of a building model (IFC2X3), part 11 of 21

# IfcOpeningElement: Opening (5659)
Name | In | Classification | Group
3 x Basic Wall:NLRS_21.21_WA_beton ihwg d=400/420_gen:5042554 | 05 vijfde verdieping | 21.21 buitenwanden - constructief, massieve wanden (Uniformat)
Basic Wall:NLRS_21.21_WA_beton prefab d=400/420_gen:5042556 | 05 vijfde verdieping | 21.21 buitenwanden - constructief, massieve wanden (Uniformat)
3 x Basic Wall:NLRS_21.21_WA_beton ihwg d=400/420_gen:5042653 | 05 vijfde verdieping | 21.21 buitenwanden - constructief, massieve wanden (Uniformat)
Basic Wall:NLRS_21.21_WA_beton prefab d=400/420_gen:5042655 | 05 vijfde verdieping | 21.21 buitenwanden - constructief, massieve wanden (Uniformat)
Basic Wall:NLRS_21.21_WA_beton prefab d=400/420_gen:5042751 | 05 vijfde verdieping | 21.21 buitenwanden - constructief, massieve wanden (Uniformat)
3 x Basic Wall:NLRS_21.21_WA_beton ihwg d=400/420_gen:5042754 | 05 vijfde verdieping | 21.21 buitenwanden - constructief, massieve wanden (Uniformat)
Basic Wall:NLRS_21.21_WA_beton prefab d=300/320_gen:5043322 | 52 tweeënvijftigste verdieping | 21.21 buitenwanden - constructief, massieve wanden (Uniformat) | Model Group:NLRS_28.21_WA_3D element 002a d=300_gen:4981935
Basic Wall:NLRS_21.21_WA_beton prefab d=300/320_gen:5043324 | 52 tweeënvijftigste verdieping | 21.21 buitenwanden - constructief, massieve wanden (Uniformat) | Model Group:NLRS_28.21_WA_3D element 002a d=300_gen:4981935
Basic Wall:NLRS_21.21_WA_beton prefab d=300/320_gen:5044687 | 52 tweeënvijftigste verdieping | 21.21 buitenwanden - constructief, massieve wanden (Uniformat) | Model Group:NLRS_28.21_WA_3D element 001a d=300_gen:4981936
Basic Wall:NLRS_21.21_WA_beton prefab d=300/320_gen:5044690 | 52 tweeënvijftigste verdieping | 21.21 buitenwanden - constructief, massieve wanden (Uniformat) | Model Group:NLRS_28.21_WA_3D element 001a d=300_gen:4981936
15 x  | 60 zestigste verdieping
14 x  | 61 eenenzestigste verdieping
7 x  | 62 tweeënzestigste verdieping
Floor:NLRS_23.21_FL_staalplaatbetonvloer d=200_gen:5046569:2 | 62 tweeënzestigste verdieping | 23.21 vloeren - constructief, vrijdragende vloeren (Uniformat)
Basic Wall:NLRS_22.21_WA_beton prefab d=500_gen:5144302 | 05 vijfde verdieping | 22.21 binnenwanden - constructief, massieve wanden (Uniformat)
Basic Wall:NLRS_22.21_WA_beton prefab d=500_gen:5144344 | 05 vijfde verdieping | 22.21 binnenwanden - constructief, massieve wanden (Uniformat)
2 x Basic Wall:NLRS_22.21_WA_beton prefab d=500_gen:4472769 | 05 vijfde verdieping | 22.21 binnenwanden - constructief, massieve wanden (Uniformat)
Basic Wall:NLRS_22.21_WA_beton prefab d=500_gen:5144554 | 05 vijfde verdieping | 22.21 binnenwanden - constructief, massieve wanden (Uniformat)
Basic Wall:NLRS_22.21_WA_beton prefab d=500_gen:5145697 | 05 vijfde verdieping | 22.21 binnenwanden - constructief, massieve wanden (Uniformat)
3 x Basic Wall:NLRS_21.21_WA_beton prefab d=400/420_gen:5146599 | 05 vijfde verdieping | 21.21 buitenwanden - constructief, massieve wanden (Uniformat)
8 x Basic Wall:NLRS_21.21_WA_beton prefab d=400/420_gen:5362948 | 05 vijfde verdieping | 21.21 buitenwanden - constructief, massieve wanden (Uniformat)
Basic Wall:NLRS_21.21_WA_beton prefab d=400/420_gen:5146667 | 05 vijfde verdieping | 21.21 buitenwanden - constructief, massieve wanden (Uniformat)
2 x Basic Wall:NLRS_21.21_WA_beton prefab d=400/420_gen:5146702 | 05 vijfde verdieping | 21.21 buitenwanden - constructief, massieve wanden (Uniformat)
Basic Wall:NLRS_21.21_WA_beton prefab d=400/420_gen:5146784 | 05 vijfde verdieping | 21.21 buitenwanden - constructief, massieve wanden (Uniformat)
2 x Basic Wall:NLRS_21.21_WA_beton prefab d=400/420_gen:5146907 | 05 vijfde verdieping | 21.21 buitenwanden - constructief, massieve wanden (Uniformat)
Basic Wall:NLRS_21.21_WA_beton prefab d=400/420_gen:5146973 | 05 vijfde verdieping | 21.21 buitenwanden - constructief, massieve wanden (Uniformat)
2 x Basic Wall:NLRS_21.21_WA_beton prefab d=400/420_gen:5147007 | 05 vijfde verdieping | 21.21 buitenwanden - constructief, massieve wanden (Uniformat)
Basic Wall:NLRS_21.21_WA_beton prefab d=400/420_gen:5147274 | 05 vijfde verdieping | 21.21 buitenwanden - constructief, massieve wanden (Uniformat)
Basic Wall:NLRS_22.21_WA_beton prefab d=500_gen:5147434 | 05 vijfde verdieping | 22.21 binnenwanden - constructief, massieve wanden (Uniformat)
Basic Wall:NLRS_22.21_WA_beton prefab d=500_gen:5147461 | 05 vijfde verdieping | 22.21 binnenwanden - constructief, massieve wanden (Uniformat)
Basic Wall:NLRS_22.21_WA_beton prefab d=500_gen:5147488 | 05 vijfde verdieping | 22.21 binnenwanden - constructief, massieve wanden (Uniformat)
Basic Wall:NLRS_22.21_WA_beton prefab d=500_gen:5147515 | 05 vijfde verdieping | 22.21 binnenwanden - constructief, massieve wanden (Uniformat)
Basic Wall:NLRS_22.21_WA_beton prefab d=500_gen:5147541 | 05 vijfde verdieping | 22.21 binnenwanden - constructief, massieve wanden (Uniformat)
Basic Wall:NLRS_22.21_WA_beton prefab d=500_gen:5147569 | 05 vijfde verdieping | 22.21 binnenwanden - constructief, massieve wanden (Uniformat)
Basic Wall:NLRS_22.21_WA_beton prefab d=300_gen:5147596 | 05 vijfde verdieping | 22.21 binnenwanden - constructief, massieve wanden (Uniformat)
2 x Basic Wall:NLRS_22.21_WA_beton prefab d=300_gen:4472952 | 05 vijfde verdieping | 22.21 binnenwanden - constructief, massieve wanden (Uniformat)
Basic Wall:NLRS_22.21_WA_beton prefab d=300_gen:5147623 | 05 vijfde verdieping | 22.21 binnenwanden - constructief, massieve wanden (Uniformat)
Basic Wall:NLRS_22.21_WA_beton prefab d=500_gen:5147650 | 05 vijfde verdieping | 22.21 binnenwanden - constructief, massieve wanden (Uniformat)
Basic Wall:NLRS_22.21_WA_beton prefab d=500_gen:5147677 | 05 vijfde verdieping | 22.21 binnenwanden - constructief, massieve wanden (Uniformat)
75 x  | 05 vijfde verdieping
Basic Wall:NLRS_21.21_WA_beton prefab d=250_gen:5173661 | 00 begane grond | 21.21 buitenwanden - constructief, massieve wanden (Uniformat)
Basic Wall:NLRS_21.21_WA_beton prefab d=250_gen:5173663 | 00 begane grond | 21.21 buitenwanden - constructief, massieve wanden (Uniformat)
Basic Wall:NLRS_21.21_WA_beton prefab d=250_gen:5173794 | 00 begane grond | 21.21 buitenwanden - constructief, massieve wanden (Uniformat)
Basic Wall:NLRS_21.21_WA_beton prefab d=250_gen:5173824 | 00 begane grond | 21.21 buitenwanden - constructief, massieve wanden (Uniformat)
2 x Basic Wall:NLRS_22.21_WA_beton prefab d=200_gen:5270051 | 02 tweede verdieping | 22.21 binnenwanden - constructief, massieve wanden (Uniformat)
6 x Basic Wall:NLRS_21.21_WA_beton prefab d=400/420_gen:5405296 | 05 vijfde verdieping | 21.21 buitenwanden - constructief, massieve wanden (Uniformat)
6 x Basic Wall:NLRS_21.21_WA_beton prefab d=400/420_gen:5405822 | 07 zevende verdieping | 21.21 buitenwanden - constructief, massieve wanden (Uniformat) | Model Group:NLRS_21.21_WA_wand 004b d=400_gen:4689125
4 x Basic Wall:NLRS_21.21_WA_beton prefab d=400/420_gen:5405836 | 06 zesde verdieping | 21.21 buitenwanden - constructief, massieve wanden (Uniformat) | Model Group:NLRS_21.21_WA_wand 004a d=400_gen:4690709
4 x Basic Wall:NLRS_21.21_WA_beton prefab d=400/420_gen:5405850 | 08 achtste verdieping | 21.21 buitenwanden - constructief, massieve wanden (Uniformat) | Model Group:NLRS_21.21_WA_wand 004aa d=400_gen:4714827
6 x Basic Wall:NLRS_21.21_WA_beton prefab d=400/420_gen:5405857 | 05 vijfde verdieping | 21.21 buitenwanden - constructief, massieve wanden (Uniformat)
3 x Basic Wall:NLRS_21.21_WA_beton prefab d=400/420_gen:5409047 | 05 vijfde verdieping | 21.21 buitenwanden - constructief, massieve wanden (Uniformat)
4 x Basic Wall:NLRS_21.21_WA_beton prefab d=400/420_gen:5409478 | 07 zevende verdieping | 21.21 buitenwanden - constructief, massieve wanden (Uniformat) | Model Group:NLRS_21.21_WA_wand 002b d=400_gen:4689133
2 x Basic Wall:NLRS_21.21_WA_beton prefab d=400/420_gen:5409492 | 06 zesde verdieping | 21.21 buitenwanden - constructief, massieve wanden (Uniformat) | Model Group:NLRS_21.21_WA_wand 002a d=400_gen:4690711
2 x Basic Wall:NLRS_21.21_WA_beton prefab d=400/420_gen:5409506 | 08 achtste verdieping | 21.21 buitenwanden - constructief, massieve wanden (Uniformat) | Model Group:NLRS_21.21_WA_wand 002a d=400_gen:4714829
4 x Basic Wall:NLRS_21.21_WA_beton prefab d=400/420_gen:5409513 | 05 vijfde verdieping | 21.21 buitenwanden - constructief, massieve wanden (Uniformat)
5 x Basic Wall:NLRS_21.21_WA_beton prefab d=300/320_gen:5450716 | 21 eenentwintigste verdieping | 21.21 buitenwanden - constructief, massieve wanden (Uniformat) | Model Group:NLRS_21.21_WA_wand 004 d=300_gen:4695016
5 x Basic Wall:NLRS_21.21_WA_beton prefab d=300/320_gen:5450723 | 21 eenentwintigste verdieping | 21.21 buitenwanden - constructief, massieve wanden (Uniformat) | Model Group:NLRS_21.21_WA_wand 004 d=300_gen:4695025
5 x Basic Wall:NLRS_21.21_WA_beton prefab d=300/320_gen:5450800 | 15 vijftiende verdieping | 21.21 buitenwanden - constructief, massieve wanden (Uniformat) | Model Group:NLRS_21.21_WA_wand 004 d=300_gen:4731097
5 x Basic Wall:NLRS_21.21_WA_beton prefab d=300/320_gen:5450807 | 15 vijftiende verdieping | 21.21 buitenwanden - constructief, massieve wanden (Uniformat) | Model Group:NLRS_21.21_WA_wand 004 d=300_gen:4731106
5 x Basic Wall:NLRS_21.21_WA_beton prefab d=300/320_gen:5450814 | 17 zeventiende verdieping | 21.21 buitenwanden - constructief, massieve wanden (Uniformat) | Model Group:NLRS_21.21_WA_wand 004 d=300_gen:4731555
5 x Basic Wall:NLRS_21.21_WA_beton prefab d=300/320_gen:5450821 | 17 zeventiende verdieping | 21.21 buitenwanden - constructief, massieve wanden (Uniformat) | Model Group:NLRS_21.21_WA_wand 004 d=300_gen:4731564
5 x Basic Wall:NLRS_21.21_WA_beton prefab d=300/320_gen:5450828 | 19 negentiende verdieping | 21.21 buitenwanden - constructief, massieve wanden (Uniformat) | Model Group:NLRS_21.21_WA_wand 004 d=300_gen:4732013
5 x Basic Wall:NLRS_21.21_WA_beton prefab d=300/320_gen:5450835 | 19 negentiende verdieping | 21.21 buitenwanden - constructief, massieve wanden (Uniformat) | Model Group:NLRS_21.21_WA_wand 004 d=300_gen:4732022
5 x Basic Wall:NLRS_21.21_WA_beton prefab d=300/320_gen:5450870 | 16 zestiende verdieping | 21.21 buitenwanden - constructief, massieve wanden (Uniformat) | Model Group:NLRS_21.21_WA_wand 004 d=300_gen:4739142
5 x Basic Wall:NLRS_21.21_WA_beton prefab d=300/320_gen:5450877 | 16 zestiende verdieping | 21.21 buitenwanden - constructief, massieve wanden (Uniformat) | Model Group:NLRS_21.21_WA_wand 004 d=300_gen:4739151
5 x Basic Wall:NLRS_21.21_WA_beton prefab d=300/320_gen:5450884 | 18 achttiende verdieping | 21.21 buitenwanden - constructief, massieve wanden (Uniformat) | Model Group:NLRS_21.21_WA_wand 004 d=300_gen:4739600
5 x Basic Wall:NLRS_21.21_WA_beton prefab d=300/320_gen:5450891 | 18 achttiende verdieping | 21.21 buitenwanden - constructief, massieve wanden (Uniformat) | Model Group:NLRS_21.21_WA_wand 004 d=300_gen:4739609
5 x Basic Wall:NLRS_21.21_WA_beton prefab d=300/320_gen:5450898 | 20 twintigste verdieping | 21.21 buitenwanden - constructief, massieve wanden (Uniformat) | Model Group:NLRS_21.21_WA_wand 004 d=300_gen:4740058
5 x Basic Wall:NLRS_21.21_WA_beton prefab d=300/320_gen:5450905 | 20 twintigste verdieping | 21.21 buitenwanden - constructief, massieve wanden (Uniformat) | Model Group:NLRS_21.21_WA_wand 004 d=300_gen:4740067
5 x Basic Wall:NLRS_21.21_WA_beton prefab d=300/320_gen:5450912 | 24 vierentwintigste verdieping | 21.21 buitenwanden - constructief, massieve wanden (Uniformat) | Model Group:NLRS_21.21_WA_wand 004 d=300_gen:4746657
5 x Basic Wall:NLRS_21.21_WA_beton prefab d=300/320_gen:5450919 | 24 vierentwintigste verdieping | 21.21 buitenwanden - constructief, massieve wanden (Uniformat) | Model Group:NLRS_21.21_WA_wand 004 d=300_gen:4746666
5 x Basic Wall:NLRS_21.21_WA_beton prefab d=300/320_gen:5450926 | 25 vijfentwintigste verdieping | 21.21 buitenwanden - constructief, massieve wanden (Uniformat) | Model Group:NLRS_21.21_WA_wand 004 d=300_gen:4747089
5 x Basic Wall:NLRS_21.21_WA_beton prefab d=300/320_gen:5450933 | 25 vijfentwintigste verdieping | 21.21 buitenwanden - constructief, massieve wanden (Uniformat) | Model Group:NLRS_21.21_WA_wand 004 d=300_gen:4747098
5 x Basic Wall:NLRS_21.21_WA_beton prefab d=300/320_gen:5450940 | 26 zesentwintigste verdieping | 21.21 buitenwanden - constructief, massieve wanden (Uniformat) | Model Group:NLRS_21.21_WA_wand 004 d=300_gen:4747521
5 x Basic Wall:NLRS_21.21_WA_beton prefab d=300/320_gen:5450947 | 26 zesentwintigste verdieping | 21.21 buitenwanden - constructief, massieve wanden (Uniformat) | Model Group:NLRS_21.21_WA_wand 004 d=300_gen:4747530
5 x Basic Wall:NLRS_21.21_WA_beton prefab d=300/320_gen:5450954 | 27 zevenentwintigste verdieping | 21.21 buitenwanden - constructief, massieve wanden (Uniformat) | Model Group:NLRS_21.21_WA_wand 004 d=300_gen:4747953
5 x Basic Wall:NLRS_21.21_WA_beton prefab d=300/320_gen:5450961 | 27 zevenentwintigste verdieping | 21.21 buitenwanden - constructief, massieve wanden (Uniformat) | Model Group:NLRS_21.21_WA_wand 004 d=300_gen:4747962
5 x Basic Wall:NLRS_21.21_WA_beton prefab d=300/320_gen:5450968 | 28 achtentwintigste verdieping | 21.21 buitenwanden - constructief, massieve wanden (Uniformat) | Model Group:NLRS_21.21_WA_wand 004 d=300_gen:4748385
5 x Basic Wall:NLRS_21.21_WA_beton prefab d=300/320_gen:5450975 | 28 achtentwintigste verdieping | 21.21 buitenwanden - constructief, massieve wanden (Uniformat) | Model Group:NLRS_21.21_WA_wand 004 d=300_gen:4748394
5 x Basic Wall:NLRS_21.21_WA_beton prefab d=300/320_gen:5450982 | 29 negenentwintigste verdieping | 21.21 buitenwanden - constructief, massieve wanden (Uniformat) | Model Group:NLRS_21.21_WA_wand 004 d=300_gen:4748817
5 x Basic Wall:NLRS_21.21_WA_beton prefab d=300/320_gen:5450989 | 29 negenentwintigste verdieping | 21.21 buitenwanden - constructief, massieve wanden (Uniformat) | Model Group:NLRS_21.21_WA_wand 004 d=300_gen:4748826
5 x Basic Wall:NLRS_21.21_WA_beton prefab d=300/320_gen:5450996 | 30 dertigste verdieping | 21.21 buitenwanden - constructief, massieve wanden (Uniformat) | Model Group:NLRS_21.21_WA_wand 004 d=300_gen:4749249
5 x Basic Wall:NLRS_21.21_WA_beton prefab d=300/320_gen:5451003 | 30 dertigste verdieping | 21.21 buitenwanden - constructief, massieve wanden (Uniformat) | Model Group:NLRS_21.21_WA_wand 004 d=300_gen:4749258
5 x Basic Wall:NLRS_21.21_WA_beton prefab d=300/320_gen:5451010 | 31 eenendertigste verdieping | 21.21 buitenwanden - constructief, massieve wanden (Uniformat) | Model Group:NLRS_21.21_WA_wand 004 d=300_gen:4749681
5 x Basic Wall:NLRS_21.21_WA_beton prefab d=300/320_gen:5451017 | 31 eenendertigste verdieping | 21.21 buitenwanden - constructief, massieve wanden (Uniformat) | Model Group:NLRS_21.21_WA_wand 004 d=300_gen:4749690
5 x Basic Wall:NLRS_21.21_WA_beton prefab d=300/320_gen:5451024 | 32 tweeëndertigste verdieping | 21.21 buitenwanden - constructief, massieve wanden (Uniformat) | Model Group:NLRS_21.21_WA_wand 004 d=300_gen:4750113
5 x Basic Wall:NLRS_21.21_WA_beton prefab d=300/320_gen:5451031 | 32 tweeëndertigste verdieping | 21.21 buitenwanden - constructief, massieve wanden (Uniformat) | Model Group:NLRS_21.21_WA_wand 004 d=300_gen:4750122
5 x Basic Wall:NLRS_21.21_WA_beton prefab d=300/320_gen:5451038 | 33 drieëndertigste verdieping | 21.21 buitenwanden - constructief, massieve wanden (Uniformat) | Model Group:NLRS_21.21_WA_wand 004 d=300_gen:4750545
5 x Basic Wall:NLRS_21.21_WA_beton prefab d=300/320_gen:5451045 | 33 drieëndertigste verdieping | 21.21 buitenwanden - constructief, massieve wanden (Uniformat) | Model Group:NLRS_21.21_WA_wand 004 d=300_gen:4750554
5 x Basic Wall:NLRS_21.21_WA_beton prefab d=300/320_gen:5451052 | 34 vierendertigste verdieping | 21.21 buitenwanden - constructief, massieve wanden (Uniformat) | Model Group:NLRS_21.21_WA_wand 004 d=300_gen:4750977
5 x Basic Wall:NLRS_21.21_WA_beton prefab d=300/320_gen:5451059 | 34 vierendertigste verdieping | 21.21 buitenwanden - constructief, massieve wanden (Uniformat) | Model Group:NLRS_21.21_WA_wand 004 d=300_gen:4750986
5 x Basic Wall:NLRS_21.21_WA_beton prefab d=300/320_gen:5451066 | 35 vijfendertigste verdieping | 21.21 buitenwanden - constructief, massieve wanden (Uniformat) | Model Group:NLRS_21.21_WA_wand 004 d=300_gen:4751409
5 x Basic Wall:NLRS_21.21_WA_beton prefab d=300/320_gen:5451073 | 35 vijfendertigste verdieping | 21.21 buitenwanden - constructief, massieve wanden (Uniformat) | Model Group:NLRS_21.21_WA_wand 004 d=300_gen:4751418
5 x Basic Wall:NLRS_21.21_WA_beton prefab d=300/320_gen:5451080 | 36 zesendertigste verdieping | 21.21 buitenwanden - constructief, massieve wanden (Uniformat) | Model Group:NLRS_21.21_WA_wand 004 d=300_gen:4751841
5 x Basic Wall:NLRS_21.21_WA_beton prefab d=300/320_gen:5451087 | 36 zesendertigste verdieping | 21.21 buitenwanden - constructief, massieve wanden (Uniformat) | Model Group:NLRS_21.21_WA_wand 004 d=300_gen:4751850
5 x Basic Wall:NLRS_21.21_WA_beton prefab d=300/320_gen:5451094 | 37 zevenendertigste verdieping | 21.21 buitenwanden - constructief, massieve wanden (Uniformat) | Model Group:NLRS_21.21_WA_wand 004 d=300_gen:4752273
5 x Basic Wall:NLRS_21.21_WA_beton prefab d=300/320_gen:5451101 | 37 zevenendertigste verdieping | 21.21 buitenwanden - constructief, massieve wanden (Uniformat) | Model Group:NLRS_21.21_WA_wand 004 d=300_gen:4752282
5 x Basic Wall:NLRS_21.21_WA_beton prefab d=300/320_gen:5451108 | 38 achtendertigste verdieping | 21.21 buitenwanden - constructief, massieve wanden (Uniformat) | Model Group:NLRS_21.21_WA_wand 004 d=300_gen:4752705
5 x Basic Wall:NLRS_21.21_WA_beton prefab d=300/320_gen:5451115 | 38 achtendertigste verdieping | 21.21 buitenwanden - constructief, massieve wanden (Uniformat) | Model Group:NLRS_21.21_WA_wand 004 d=300_gen:4752714
5 x Basic Wall:NLRS_21.21_WA_beton prefab d=300/320_gen:5451122 | 39 negenendertigste verdieping | 21.21 buitenwanden - constructief, massieve wanden (Uniformat) | Model Group:NLRS_21.21_WA_wand 004 d=300_gen:4753137
5 x Basic Wall:NLRS_21.21_WA_beton prefab d=300/320_gen:5451129 | 39 negenendertigste verdieping | 21.21 buitenwanden - constructief, massieve wanden (Uniformat) | Model Group:NLRS_21.21_WA_wand 004 d=300_gen:4753146
5 x Basic Wall:NLRS_21.21_WA_beton prefab d=300/320_gen:5451136 | 40 veertigste verdieping | 21.21 buitenwanden - constructief, massieve wanden (Uniformat) | Model Group:NLRS_21.21_WA_wand 004 d=300_gen:4753569
5 x Basic Wall:NLRS_21.21_WA_beton prefab d=300/320_gen:5451143 | 40 veertigste verdieping | 21.21 buitenwanden - constructief, massieve wanden (Uniformat) | Model Group:NLRS_21.21_WA_wand 004 d=300_gen:4753578
5 x Basic Wall:NLRS_21.21_WA_beton prefab d=300/320_gen:5451150 | 22 tweeëntwintigste verdieping | 21.21 buitenwanden - constructief, massieve wanden (Uniformat) | Model Group:NLRS_21.21_WA_wand 004 d=300_gen:4778037
5 x Basic Wall:NLRS_21.21_WA_beton prefab d=300/320_gen:5451157 | 22 tweeëntwintigste verdieping | 21.21 buitenwanden - constructief, massieve wanden (Uniformat) | Model Group:NLRS_21.21_WA_wand 004 d=300_gen:4778046
5 x Basic Wall:NLRS_21.21_WA_beton prefab d=300/320_gen:5451164 | 23 drieëntwintigste verdieping | 21.21 buitenwanden - constructief, massieve wanden (Uniformat) | Model Group:NLRS_21.21_WA_wand 004 d=300_gen:4779620
5 x Basic Wall:NLRS_21.21_WA_beton prefab d=300/320_gen:5451171 | 23 drieëntwintigste verdieping | 21.21 buitenwanden - constructief, massieve wanden (Uniformat) | Model Group:NLRS_21.21_WA_wand 004 d=300_gen:4779629
5 x Basic Wall:NLRS_21.21_WA_beton prefab d=300/320_gen:5451178 | 41 eenenveertigste verdieping | 21.21 buitenwanden - constructief, massieve wanden (Uniformat) | Model Group:NLRS_21.21_WA_wand 004 d=300_gen:4783737
5 x Basic Wall:NLRS_21.21_WA_beton prefab d=300/320_gen:5451185 | 41 eenenveertigste verdieping | 21.21 buitenwanden - constructief, massieve wanden (Uniformat) | Model Group:NLRS_21.21_WA_wand 004 d=300_gen:4783746
5 x Basic Wall:NLRS_21.21_WA_beton prefab d=300/320_gen:5451206 | 43 drieënveertigste verdieping | 21.21 buitenwanden - constructief, massieve wanden (Uniformat) | Model Group:NLRS_21.21_WA_wand 004 d=300_gen:4788783
5 x Basic Wall:NLRS_21.21_WA_beton prefab d=300/320_gen:5451213 | 43 drieënveertigste verdieping | 21.21 buitenwanden - constructief, massieve wanden (Uniformat) | Model Group:NLRS_21.21_WA_wand 004 d=300_gen:4788792
5 x Basic Wall:NLRS_21.21_WA_beton prefab d=300/320_gen:5451220 | 44 vierenveertigste verdieping | 21.21 buitenwanden - constructief, massieve wanden (Uniformat) | Model Group:NLRS_21.21_WA_wand 004 d=300_gen:4789215
5 x Basic Wall:NLRS_21.21_WA_beton prefab d=300/320_gen:5451227 | 44 vierenveertigste verdieping | 21.21 buitenwanden - constructief, massieve wanden (Uniformat) | Model Group:NLRS_21.21_WA_wand 004 d=300_gen:4789224
5 x Basic Wall:NLRS_21.21_WA_beton prefab d=300/320_gen:5451234 | 45 vijfenveertigste verdieping | 21.21 buitenwanden - constructief, massieve wanden (Uniformat) | Model Group:NLRS_21.21_WA_wand 004 d=300_gen:4789647
5 x Basic Wall:NLRS_21.21_WA_beton prefab d=300/320_gen:5451241 | 45 vijfenveertigste verdieping | 21.21 buitenwanden - constructief, massieve wanden (Uniformat) | Model Group:NLRS_21.21_WA_wand 004 d=300_gen:4789656
5 x Basic Wall:NLRS_21.21_WA_beton prefab d=300/320_gen:5451248 | 46 zesenveertigste verdieping | 21.21 buitenwanden - constructief, massieve wanden (Uniformat) | Model Group:NLRS_21.21_WA_wand 004 d=300_gen:4790079
5 x Basic Wall:NLRS_21.21_WA_beton prefab d=300/320_gen:5451255 | 46 zesenveertigste verdieping | 21.21 buitenwanden - constructief, massieve wanden (Uniformat) | Model Group:NLRS_21.21_WA_wand 004 d=300_gen:4790088
5 x Basic Wall:NLRS_21.21_WA_beton prefab d=300/320_gen:5451262 | 47 zevenenveertigste verdieping | 21.21 buitenwanden - constructief, massieve wanden (Uniformat) | Model Group:NLRS_21.21_WA_wand 004 d=300_gen:4790511
5 x Basic Wall:NLRS_21.21_WA_beton prefab d=300/320_gen:5451269 | 47 zevenenveertigste verdieping | 21.21 buitenwanden - constructief, massieve wanden (Uniformat) | Model Group:NLRS_21.21_WA_wand 004 d=300_gen:4790520
5 x Basic Wall:NLRS_21.21_WA_beton prefab d=300/320_gen:5451276 | 48 achtenveertigste verdieping | 21.21 buitenwanden - constructief, massieve wanden (Uniformat) | Model Group:NLRS_21.21_WA_wand 004 d=300_gen:4790943
5 x Basic Wall:NLRS_21.21_WA_beton prefab d=300/320_gen:5451283 | 48 achtenveertigste verdieping | 21.21 buitenwanden - constructief, massieve wanden (Uniformat) | Model Group:NLRS_21.21_WA_wand 004 d=300_gen:4790952
5 x Basic Wall:NLRS_21.21_WA_beton prefab d=300/320_gen:5451290 | 49 negenenveertigste verdieping | 21.21 buitenwanden - constructief, massieve wanden (Uniformat) | Model Group:NLRS_21.21_WA_wand 004 d=300_gen:4791375
5 x Basic Wall:NLRS_21.21_WA_beton prefab d=300/320_gen:5451297 | 49 negenenveertigste verdieping | 21.21 buitenwanden - constructief, massieve wanden (Uniformat) | Model Group:NLRS_21.21_WA_wand 004 d=300_gen:4791384
5 x Basic Wall:NLRS_21.21_WA_beton prefab d=300/320_gen:5451304 | 50 vijftigste verdieping | 21.21 buitenwanden - constructief, massieve wanden (Uniformat) | Model Group:NLRS_21.21_WA_wand 004 d=300_gen:4791807
5 x Basic Wall:NLRS_21.21_WA_beton prefab d=300/320_gen:5451311 | 50 vijftigste verdieping | 21.21 buitenwanden - constructief, massieve wanden (Uniformat) | Model Group:NLRS_21.21_WA_wand 004 d=300_gen:4791816
5 x Basic Wall:NLRS_21.21_WA_beton prefab d=300/320_gen:5451318 | 42 tweeënveertigste verdieping | 21.21 buitenwanden - constructief, massieve wanden (Uniformat) | Model Group:NLRS_21.21_WA_wand 004 d=300_gen:4803256
5 x Basic Wall:NLRS_21.21_WA_beton prefab d=300/320_gen:5451325 | 42 tweeënveertigste verdieping | 21.21 buitenwanden - constructief, massieve wanden (Uniformat) | Model Group:NLRS_21.21_WA_wand 004 d=300_gen:4803265
5 x Basic Wall:NLRS_21.21_WA_beton prefab d=300/320_gen:5451346 | 51 eenenvijftigste verdieping | 21.21 buitenwanden - constructief, massieve wanden (Uniformat) | Model Group:NLRS_21.21_WA_wand 004 d=300_gen:4979990
5 x Basic Wall:NLRS_21.21_WA_beton prefab d=300/320_gen:5451353 | 51 eenenvijftigste verdieping | 21.21 buitenwanden - constructief, massieve wanden (Uniformat) | Model Group:NLRS_21.21_WA_wand 004 d=300_gen:4979999
3 x Basic Wall:NLRS_21.21_WA_beton prefab d=300/320_gen:5482909 | 21 eenentwintigste verdieping | 21.21 buitenwanden - constructief, massieve wanden (Uniformat) | Model Group:NLRS_21.21_WA_wand 002 d=300_gen:4695026
3 x Basic Wall:NLRS_21.21_WA_beton prefab d=300/320_gen:5482915 | 21 eenentwintigste verdieping | 21.21 buitenwanden - constructief, massieve wanden (Uniformat) | Model Group:NLRS_21.21_WA_wand 002 d=300_gen:4695033
3 x Basic Wall:NLRS_21.21_WA_beton prefab d=300/320_gen:5482987 | 15 vijftiende verdieping | 21.21 buitenwanden - constructief, massieve wanden (Uniformat) | Model Group:NLRS_21.21_WA_wand 002 d=300_gen:4731114
3 x Basic Wall:NLRS_21.21_WA_beton prefab d=300/320_gen:5482999 | 17 zeventiende verdieping | 21.21 buitenwanden - constructief, massieve wanden (Uniformat) | Model Group:NLRS_21.21_WA_wand 002 d=300_gen:4731572
3 x Basic Wall:NLRS_21.21_WA_beton prefab d=300/320_gen:5483011 | 19 negentiende verdieping | 21.21 buitenwanden - constructief, massieve wanden (Uniformat) | Model Group:NLRS_21.21_WA_wand 002 d=300_gen:4732030
3 x Basic Wall:NLRS_21.21_WA_beton prefab d=300/320_gen:5483041 | 16 zestiende verdieping | 21.21 buitenwanden - constructief, massieve wanden (Uniformat) | Model Group:NLRS_21.21_WA_wand 002 d=300_gen:4739152
3 x Basic Wall:NLRS_21.21_WA_beton prefab d=300/320_gen:5483047 | 16 zestiende verdieping | 21.21 buitenwanden - constructief, massieve wanden (Uniformat) | Model Group:NLRS_21.21_WA_wand 002 d=300_gen:4739159
3 x Basic Wall:NLRS_21.21_WA_beton prefab d=300/320_gen:5483053 | 18 achttiende verdieping | 21.21 buitenwanden - constructief, massieve wanden (Uniformat) | Model Group:NLRS_21.21_WA_wand 002 d=300_gen:4739610
3 x Basic Wall:NLRS_21.21_WA_beton prefab d=300/320_gen:5483059 | 18 achttiende verdieping | 21.21 buitenwanden - constructief, massieve wanden (Uniformat) | Model Group:NLRS_21.21_WA_wand 002 d=300_gen:4739617
3 x Basic Wall:NLRS_21.21_WA_beton prefab d=300/320_gen:5483065 | 20 twintigste verdieping | 21.21 buitenwanden - constructief, massieve wanden (Uniformat) | Model Group:NLRS_21.21_WA_wand 002 d=300_gen:4740068
3 x Basic Wall:NLRS_21.21_WA_beton prefab d=300/320_gen:5483071 | 20 twintigste verdieping | 21.21 buitenwanden - constructief, massieve wanden (Uniformat) | Model Group:NLRS_21.21_WA_wand 002 d=300_gen:4740075
3 x Basic Wall:NLRS_21.21_WA_beton prefab d=300/320_gen:5483077 | 24 vierentwintigste verdieping | 21.21 buitenwanden - constructief, massieve wanden (Uniformat) | Model Group:NLRS_21.21_WA_wand 002 d=300_gen:4746667
3 x Basic Wall:NLRS_21.21_WA_beton prefab d=300/320_gen:5483083 | 24 vierentwintigste verdieping | 21.21 buitenwanden - constructief, massieve wanden (Uniformat) | Model Group:NLRS_21.21_WA_wand 002 d=300_gen:4746674
3 x Basic Wall:NLRS_21.21_WA_beton prefab d=300/320_gen:5483089 | 25 vijfentwintigste verdieping | 21.21 buitenwanden - constructief, massieve wanden (Uniformat) | Model Group:NLRS_21.21_WA_wand 002 d=300_gen:4747099
3 x Basic Wall:NLRS_21.21_WA_beton prefab d=300/320_gen:5483095 | 25 vijfentwintigste verdieping | 21.21 buitenwanden - constructief, massieve wanden (Uniformat) | Model Group:NLRS_21.21_WA_wand 002 d=300_gen:4747106
3 x Basic Wall:NLRS_21.21_WA_beton prefab d=300/320_gen:5483101 | 26 zesentwintigste verdieping | 21.21 buitenwanden - constructief, massieve wanden (Uniformat) | Model Group:NLRS_21.21_WA_wand 002 d=300_gen:4747531
3 x Basic Wall:NLRS_21.21_WA_beton prefab d=300/320_gen:5483107 | 26 zesentwintigste verdieping | 21.21 buitenwanden - constructief, massieve wanden (Uniformat) | Model Group:NLRS_21.21_WA_wand 002 d=300_gen:4747538
3 x Basic Wall:NLRS_21.21_WA_beton prefab d=300/320_gen:5483113 | 27 zevenentwintigste verdieping | 21.21 buitenwanden - constructief, massieve wanden (Uniformat) | Model Group:NLRS_21.21_WA_wand 002 d=300_gen:4747963
3 x Basic Wall:NLRS_21.21_WA_beton prefab d=300/320_gen:5483119 | 27 zevenentwintigste verdieping | 21.21 buitenwanden - constructief, massieve wanden (Uniformat) | Model Group:NLRS_21.21_WA_wand 002 d=300_gen:4747970
3 x Basic Wall:NLRS_21.21_WA_beton prefab d=300/320_gen:5483125 | 28 achtentwintigste verdieping | 21.21 buitenwanden - constructief, massieve wanden (Uniformat) | Model Group:NLRS_21.21_WA_wand 002 d=300_gen:4748395
3 x Basic Wall:NLRS_21.21_WA_beton prefab d=300/320_gen:5483131 | 28 achtentwintigste verdieping | 21.21 buitenwanden - constructief, massieve wanden (Uniformat) | Model Group:NLRS_21.21_WA_wand 002 d=300_gen:4748402
3 x Basic Wall:NLRS_21.21_WA_beton prefab d=300/320_gen:5483137 | 29 negenentwintigste verdieping | 21.21 buitenwanden - constructief, massieve wanden (Uniformat) | Model Group:NLRS_21.21_WA_wand 002 d=300_gen:4748827
3 x Basic Wall:NLRS_21.21_WA_beton prefab d=300/320_gen:5483143 | 29 negenentwintigste verdieping | 21.21 buitenwanden - constructief, massieve wanden (Uniformat) | Model Group:NLRS_21.21_WA_wand 002 d=300_gen:4748834
3 x Basic Wall:NLRS_21.21_WA_beton prefab d=300/320_gen:5483149 | 30 dertigste verdieping | 21.21 buitenwanden - constructief, massieve wanden (Uniformat) | Model Group:NLRS_21.21_WA_wand 002 d=300_gen:4749259
3 x Basic Wall:NLRS_21.21_WA_beton prefab d=300/320_gen:5483155 | 30 dertigste verdieping | 21.21 buitenwanden - constructief, massieve wanden (Uniformat) | Model Group:NLRS_21.21_WA_wand 002 d=300_gen:4749266
3 x Basic Wall:NLRS_21.21_WA_beton prefab d=300/320_gen:5483161 | 31 eenendertigste verdieping | 21.21 buitenwanden - constructief, massieve wanden (Uniformat) | Model Group:NLRS_21.21_WA_wand 002 d=300_gen:4749691
3 x Basic Wall:NLRS_21.21_WA_beton prefab d=300/320_gen:5483167 | 31 eenendertigste verdieping | 21.21 buitenwanden - constructief, massieve wanden (Uniformat) | Model Group:NLRS_21.21_WA_wand 002 d=300_gen:4749698
3 x Basic Wall:NLRS_21.21_WA_beton prefab d=300/320_gen:5483173 | 32 tweeëndertigste verdieping | 21.21 buitenwanden - constructief, massieve wanden (Uniformat) | Model Group:NLRS_21.21_WA_wand 002 d=300_gen:4750123
3 x Basic Wall:NLRS_21.21_WA_beton prefab d=300/320_gen:5483179 | 32 tweeëndertigste verdieping | 21.21 buitenwanden - constructief, massieve wanden (Uniformat) | Model Group:NLRS_21.21_WA_wand 002 d=300_gen:4750130
3 x Basic Wall:NLRS_21.21_WA_beton prefab d=300/320_gen:5483185 | 33 drieëndertigste verdieping | 21.21 buitenwanden - constructief, massieve wanden (Uniformat) | Model Group:NLRS_21.21_WA_wand 002 d=300_gen:4750555
3 x Basic Wall:NLRS_21.21_WA_beton prefab d=300/320_gen:5483191 | 33 drieëndertigste verdieping | 21.21 buitenwanden - constructief, massieve wanden (Uniformat) | Model Group:NLRS_21.21_WA_wand 002 d=300_gen:4750562
3 x Basic Wall:NLRS_21.21_WA_beton prefab d=300/320_gen:5483197 | 34 vierendertigste verdieping | 21.21 buitenwanden - constructief, massieve wanden (Uniformat) | Model Group:NLRS_21.21_WA_wand 002 d=300_gen:4750987
3 x Basic Wall:NLRS_21.21_WA_beton prefab d=300/320_gen:5483203 | 34 vierendertigste verdieping | 21.21 buitenwanden - constructief, massieve wanden (Uniformat) | Model Group:NLRS_21.21_WA_wand 002 d=300_gen:4750994
3 x Basic Wall:NLRS_21.21_WA_beton prefab d=300/320_gen:5483209 | 35 vijfendertigste verdieping | 21.21 buitenwanden - constructief, massieve wanden (Uniformat) | Model Group:NLRS_21.21_WA_wand 002 d=300_gen:4751419
3 x Basic Wall:NLRS_21.21_WA_beton prefab d=300/320_gen:5483215 | 35 vijfendertigste verdieping | 21.21 buitenwanden - constructief, massieve wanden (Uniformat) | Model Group:NLRS_21.21_WA_wand 002 d=300_gen:4751426
3 x Basic Wall:NLRS_21.21_WA_beton prefab d=300/320_gen:5483221 | 36 zesendertigste verdieping | 21.21 buitenwanden - constructief, massieve wanden (Uniformat) | Model Group:NLRS_21.21_WA_wand 002 d=300_gen:4751851
3 x Basic Wall:NLRS_21.21_WA_beton prefab d=300/320_gen:5483227 | 36 zesendertigste verdieping | 21.21 buitenwanden - constructief, massieve wanden (Uniformat) | Model Group:NLRS_21.21_WA_wand 002 d=300_gen:4751858
3 x Basic Wall:NLRS_21.21_WA_beton prefab d=300/320_gen:5483233 | 37 zevenendertigste verdieping | 21.21 buitenwanden - constructief, massieve wanden (Uniformat) | Model Group:NLRS_21.21_WA_wand 002 d=300_gen:4752283
3 x Basic Wall:NLRS_21.21_WA_beton prefab d=300/320_gen:5483239 | 37 zevenendertigste verdieping | 21.21 buitenwanden - constructief, massieve wanden (Uniformat) | Model Group:NLRS_21.21_WA_wand 002 d=300_gen:4752290
3 x Basic Wall:NLRS_21.21_WA_beton prefab d=300/320_gen:5483245 | 38 achtendertigste verdieping | 21.21 buitenwanden - constructief, massieve wanden (Uniformat) | Model Group:NLRS_21.21_WA_wand 002 d=300_gen:4752715
3 x Basic Wall:NLRS_21.21_WA_beton prefab d=300/320_gen:5483251 | 38 achtendertigste verdieping | 21.21 buitenwanden - constructief, massieve wanden (Uniformat) | Model Group:NLRS_21.21_WA_wand 002 d=300_gen:4752722
3 x Basic Wall:NLRS_21.21_WA_beton prefab d=300/320_gen:5483257 | 39 negenendertigste verdieping | 21.21 buitenwanden - constructief, massieve wanden (Uniformat) | Model Group:NLRS_21.21_WA_wand 002 d=300_gen:4753147
3 x Basic Wall:NLRS_21.21_WA_beton prefab d=300/320_gen:5483263 | 39 negenendertigste verdieping | 21.21 buitenwanden - constructief, massieve wanden (Uniformat) | Model Group:NLRS_21.21_WA_wand 002 d=300_gen:4753154
3 x Basic Wall:NLRS_21.21_WA_beton prefab d=300/320_gen:5483269 | 40 veertigste verdieping | 21.21 buitenwanden - constructief, massieve wanden (Uniformat) | Model Group:NLRS_21.21_WA_wand 002 d=300_gen:4753579
3 x Basic Wall:NLRS_21.21_WA_beton prefab d=300/320_gen:5483275 | 40 veertigste verdieping | 21.21 buitenwanden - constructief, massieve wanden (Uniformat) | Model Group:NLRS_21.21_WA_wand 002 d=300_gen:4753586
3 x Basic Wall:NLRS_21.21_WA_beton prefab d=300/320_gen:5483281 | 22 tweeëntwintigste verdieping | 21.21 buitenwanden - constructief, massieve wanden (Uniformat) | Model Group:NLRS_21.21_WA_wand 002 d=300_gen:4778047
3 x Basic Wall:NLRS_21.21_WA_beton prefab d=300/320_gen:5483287 | 22 tweeëntwintigste verdieping | 21.21 buitenwanden - constructief, massieve wanden (Uniformat) | Model Group:NLRS_21.21_WA_wand 002 d=300_gen:4778054
3 x Basic Wall:NLRS_21.21_WA_beton prefab d=300/320_gen:5483293 | 23 drieëntwintigste verdieping | 21.21 buitenwanden - constructief, massieve wanden (Uniformat) | Model Group:NLRS_21.21_WA_wand 002 d=300_gen:4779630
3 x Basic Wall:NLRS_21.21_WA_beton prefab d=300/320_gen:5483299 | 23 drieëntwintigste verdieping | 21.21 buitenwanden - constructief, massieve wanden (Uniformat) | Model Group:NLRS_21.21_WA_wand 002 d=300_gen:4779637
3 x Basic Wall:NLRS_21.21_WA_beton prefab d=300/320_gen:5483305 | 41 eenenveertigste verdieping | 21.21 buitenwanden - constructief, massieve wanden (Uniformat) | Model Group:NLRS_21.21_WA_wand 002 d=300_gen:4783747
3 x Basic Wall:NLRS_21.21_WA_beton prefab d=300/320_gen:5483311 | 41 eenenveertigste verdieping | 21.21 buitenwanden - constructief, massieve wanden (Uniformat) | Model Group:NLRS_21.21_WA_wand 002 d=300_gen:4783754
3 x Basic Wall:NLRS_21.21_WA_beton prefab d=300/320_gen:5483329 | 43 drieënveertigste verdieping | 21.21 buitenwanden - constructief, massieve wanden (Uniformat) | Model Group:NLRS_21.21_WA_wand 002 d=300_gen:4788793
3 x Basic Wall:NLRS_21.21_WA_beton prefab d=300/320_gen:5483335 | 43 drieënveertigste verdieping | 21.21 buitenwanden - constructief, massieve wanden (Uniformat) | Model Group:NLRS_21.21_WA_wand 002 d=300_gen:4788800
3 x Basic Wall:NLRS_21.21_WA_beton prefab d=300/320_gen:5483341 | 44 vierenveertigste verdieping | 21.21 buitenwanden - constructief, massieve wanden (Uniformat) | Model Group:NLRS_21.21_WA_wand 002 d=300_gen:4789225
3 x Basic Wall:NLRS_21.21_WA_beton prefab d=300/320_gen:5483347 | 44 vierenveertigste verdieping | 21.21 buitenwanden - constructief, massieve wanden (Uniformat) | Model Group:NLRS_21.21_WA_wand 002 d=300_gen:4789232
3 x Basic Wall:NLRS_21.21_WA_beton prefab d=300/320_gen:5483353 | 45 vijfenveertigste verdieping | 21.21 buitenwanden - constructief, massieve wanden (Uniformat) | Model Group:NLRS_21.21_WA_wand 002 d=300_gen:4789657
3 x Basic Wall:NLRS_21.21_WA_beton prefab d=300/320_gen:5483359 | 45 vijfenveertigste verdieping | 21.21 buitenwanden - constructief, massieve wanden (Uniformat) | Model Group:NLRS_21.21_WA_wand 002 d=300_gen:4789664
3 x Basic Wall:NLRS_21.21_WA_beton prefab d=300/320_gen:5483365 | 46 zesenveertigste verdieping | 21.21 buitenwanden - constructief, massieve wanden (Uniformat) | Model Group:NLRS_21.21_WA_wand 002 d=300_gen:4790089
3 x Basic Wall:NLRS_21.21_WA_beton prefab d=300/320_gen:5483371 | 46 zesenveertigste verdieping | 21.21 buitenwanden - constructief, massieve wanden (Uniformat) | Model Group:NLRS_21.21_WA_wand 002 d=300_gen:4790096
3 x Basic Wall:NLRS_21.21_WA_beton prefab d=300/320_gen:5483377 | 47 zevenenveertigste verdieping | 21.21 buitenwanden - constructief, massieve wanden (Uniformat) | Model Group:NLRS_21.21_WA_wand 002 d=300_gen:4790521
3 x Basic Wall:NLRS_21.21_WA_beton prefab d=300/320_gen:5483383 | 47 zevenenveertigste verdieping | 21.21 buitenwanden - constructief, massieve wanden (Uniformat) | Model Group:NLRS_21.21_WA_wand 002 d=300_gen:4790528
3 x Basic Wall:NLRS_21.21_WA_beton prefab d=300/320_gen:5483389 | 48 achtenveertigste verdieping | 21.21 buitenwanden - constructief, massieve wanden (Uniformat) | Model Group:NLRS_21.21_WA_wand 002 d=300_gen:4790953
3 x Basic Wall:NLRS_21.21_WA_beton prefab d=300/320_gen:5483395 | 48 achtenveertigste verdieping | 21.21 buitenwanden - constructief, massieve wanden (Uniformat) | Model Group:NLRS_21.21_WA_wand 002 d=300_gen:4790960
3 x Basic Wall:NLRS_21.21_WA_beton prefab d=300/320_gen:5483401 | 49 negenenveertigste verdieping | 21.21 buitenwanden - constructief, massieve wanden (Uniformat) | Model Group:NLRS_21.21_WA_wand 002 d=300_gen:4791385
3 x Basic Wall:NLRS_21.21_WA_beton prefab d=300/320_gen:5483407 | 49 negenenveertigste verdieping | 21.21 buitenwanden - constructief, massieve wanden (Uniformat) | Model Group:NLRS_21.21_WA_wand 002 d=300_gen:4791392
3 x Basic Wall:NLRS_21.21_WA_beton prefab d=300/320_gen:5483413 | 50 vijftigste verdieping | 21.21 buitenwanden - constructief, massieve wanden (Uniformat) | Model Group:NLRS_21.21_WA_wand 002 d=300_gen:4791817
3 x Basic Wall:NLRS_21.21_WA_beton prefab d=300/320_gen:5483419 | 50 vijftigste verdieping | 21.21 buitenwanden - constructief, massieve wanden (Uniformat) | Model Group:NLRS_21.21_WA_wand 002 d=300_gen:4791824
3 x Basic Wall:NLRS_21.21_WA_beton prefab d=300/320_gen:5483425 | 42 tweeënveertigste verdieping | 21.21 buitenwanden - constructief, massieve wanden (Uniformat) | Model Group:NLRS_21.21_WA_wand 002 d=300_gen:4803266
3 x Basic Wall:NLRS_21.21_WA_beton prefab d=300/320_gen:5483431 | 42 tweeënveertigste verdieping | 21.21 buitenwanden - constructief, massieve wanden (Uniformat) | Model Group:NLRS_21.21_WA_wand 002 d=300_gen:4803273
3 x Basic Wall:NLRS_21.21_WA_beton prefab d=300/320_gen:5483449 | 51 eenenvijftigste verdieping | 21.21 buitenwanden - constructief, massieve wanden (Uniformat) | Model Group:NLRS_21.21_WA_wand 002 d=300_gen:4980000
3 x Basic Wall:NLRS_21.21_WA_beton prefab d=300/320_gen:5483455 | 51 eenenvijftigste verdieping | 21.21 buitenwanden - constructief, massieve wanden (Uniformat) | Model Group:NLRS_21.21_WA_wand 002 d=300_gen:4980007
3 x Basic Wall:NLRS_21.21_WA_beton prefab d=300/320_gen:5509183 | 15 vijftiende verdieping | 21.21 buitenwanden - constructief, massieve wanden (Uniformat) | Model Group:NLRS_21.21_WA_wand 002 d=300_gen:5509182
2 x Basic Wall:NLRS_21.21_WA_beton prefab d=300/320_gen:5365657 | 15 vijftiende verdieping | 21.21 buitenwanden - constructief, massieve wanden (Uniformat) | Model Group:NLRS_21.21_WA_wand 002 d=300_gen:5509182
3 x Basic Wall:NLRS_21.21_WA_beton prefab d=300/320_gen:5509188 | 15 vijftiende verdieping | 21.21 buitenwanden - constructief, massieve wanden (Uniformat) | Model Group:NLRS_21.21_WA_wand 002 d=300_gen:5509182
3 x Basic Wall:NLRS_21.21_WA_beton prefab d=300/320_gen:5509201 | 17 zeventiende verdieping | 21.21 buitenwanden - constructief, massieve wanden (Uniformat) | Model Group:NLRS_21.21_WA_wand 002 d=300_gen:5509200
2 x Basic Wall:NLRS_21.21_WA_beton prefab d=300/320_gen:5365657 | 17 zeventiende verdieping | 21.21 buitenwanden - constructief, massieve wanden (Uniformat) | Model Group:NLRS_21.21_WA_wand 002 d=300_gen:5509200
3 x Basic Wall:NLRS_21.21_WA_beton prefab d=300/320_gen:5509206 | 17 zeventiende verdieping | 21.21 buitenwanden - constructief, massieve wanden (Uniformat) | Model Group:NLRS_21.21_WA_wand 002 d=300_gen:5509200
3 x Basic Wall:NLRS_21.21_WA_beton prefab d=300/320_gen:5509219 | 19 negentiende verdieping | 21.21 buitenwanden - constructief, massieve wanden (Uniformat) | Model Group:NLRS_21.21_WA_wand 002 d=300_gen:5509218
2 x Basic Wall:NLRS_21.21_WA_beton prefab d=300/320_gen:5365657 | 19 negentiende verdieping | 21.21 buitenwanden - constructief, massieve wanden (Uniformat) | Model Group:NLRS_21.21_WA_wand 002 d=300_gen:5509218
3 x Basic Wall:NLRS_21.21_WA_beton prefab d=300/320_gen:5509224 | 19 negentiende verdieping | 21.21 buitenwanden - constructief, massieve wanden (Uniformat) | Model Group:NLRS_21.21_WA_wand 002 d=300_gen:5509218
5 x Basic Wall:NLRS_21.21_WA_beton prefab d=300/320_gen:5528547 | 52 tweeënvijftigste verdieping | 21.21 buitenwanden - constructief, massieve wanden (Uniformat) | Model Group:NLRS_21.21_WA_wand 004c d=300_gen:4981762
5 x Basic Wall:NLRS_21.21_WA_beton prefab d=300/320_gen:5528784 | 52 tweeënvijftigste verdieping | 21.21 buitenwanden - constructief, massieve wanden (Uniformat) | Model Group:NLRS_21.21_WA_wand 004c d=300_gen:4981771
3 x Basic Wall:NLRS_21.21_WA_beton prefab d=300/320_gen:5529195 | 52 tweeënvijftigste verdieping | 21.21 buitenwanden - constructief, massieve wanden (Uniformat) | Model Group:NLRS_21.21_WA_wand 002c d=300_gen:4981772
3 x Basic Wall:NLRS_21.21_WA_beton prefab d=300/320_gen:5529401 | 52 tweeënvijftigste verdieping | 21.21 buitenwanden - constructief, massieve wanden (Uniformat) | Model Group:NLRS_21.21_WA_wand 002c d=300_gen:4981779
2 x Basic Wall:NLRS_22.21_WA_beton prefab d=500_gen:5667262 | 09 negende verdieping | 22.21 binnenwanden - constructief, massieve wanden (Uniformat) | Model Group:NLRS_01.00_verdieping type C2_gen:4703193
Basic Wall:NLRS_22.21_WA_beton prefab d=500_gen:5667264 | 09 negende verdieping | 22.21 binnenwanden - constructief, massieve wanden (Uniformat) | Model Group:NLRS_01.00_verdieping type C2_gen:4703193
Basic Wall:NLRS_22.21_WA_beton prefab d=500_gen:5667266 | 09 negende verdieping | 22.21 binnenwanden - constructief, massieve wanden (Uniformat) | Model Group:NLRS_01.00_verdieping type C2_gen:4703193
2 x Basic Wall:NLRS_22.21_WA_beton prefab d=500_gen:5667268 | 09 negende verdieping | 22.21 binnenwanden - constructief, massieve wanden (Uniformat) | Model Group:NLRS_01.00_verdieping type C2_gen:4703193
Basic Wall:NLRS_21.21_WA_beton prefab d=300/320_gen:5667282 | 09 negende verdieping | 21.21 buitenwanden - constructief, massieve wanden (Uniformat) | Model Group:NLRS_21.21_WA_wand 003 d=300_gen:5667325
Basic Wall:NLRS_21.21_WA_beton prefab d=300/320_gen:5667284 | 09 negende verdieping | 21.21 buitenwanden - constructief, massieve wanden (Uniformat) | Model Group:NLRS_21.21_WA_wand 001 d=300_gen:5667324
Basic Wall:NLRS_21.21_WA_beton prefab d=300/320_gen:5667326 | 09 negende verdieping | 21.21 buitenwanden - constructief, massieve wanden (Uniformat) | Model Group:NLRS_21.21_WA_wand 003 d=300_gen:5667329
Basic Wall:NLRS_21.21_WA_beton prefab d=300/320_gen:5667330 | 09 negende verdieping | 21.21 buitenwanden - constructief, massieve wanden (Uniformat) | Model Group:NLRS_21.21_WA_wand 001 d=300_gen:5667333
2 x Basic Wall:NLRS_21.21_WA_beton prefab d=300/320_gen:5667334 | 09 negende verdieping | 21.21 buitenwanden - constructief, massieve wanden (Uniformat) | Model Group:NLRS_21.21_WA_wand 002b d=300_gen:5667323
2 x Basic Wall:NLRS_21.21_WA_beton prefab d=300/320_gen:5365657 | 09 negende verdieping | 21.21 buitenwanden - constructief, massieve wanden (Uniformat) | Model Group:NLRS_21.21_WA_wand 002b d=300_gen:5667323
2 x Basic Wall:NLRS_21.21_WA_beton prefab d=300/320_gen:5667336 | 09 negende verdieping | 21.21 buitenwanden - constructief, massieve wanden (Uniformat) | Model Group:NLRS_21.21_WA_wand 004b d=300_gen:5667316
2 x Basic Wall:NLRS_21.21_WA_beton prefab d=300/320_gen:5365657 | 09 negende verdieping | 21.21 buitenwanden - constructief, massieve wanden (Uniformat) | Model Group:NLRS_21.21_WA_wand 004b d=300_gen:5667316
Basic Wall:NLRS_21.21_WA_beton prefab d=300/320_gen:5667342 | 09 negende verdieping | 21.21 buitenwanden - constructief, massieve wanden (Uniformat) | Model Group:NLRS_28.21_WA_3D element 002 d=300_gen:5667357
Basic Wall:NLRS_21.21_WA_beton prefab d=300/320_gen:5667344 | 09 negende verdieping | 21.21 buitenwanden - constructief, massieve wanden (Uniformat) | Model Group:NLRS_28.21_WA_3D element 002 d=300_gen:5667357
Basic Wall:NLRS_22.21_WA_beton prefab d=300_gen:5667396 | 09 negende verdieping | 22.21 binnenwanden - constructief, massieve wanden (Uniformat) | Model Group:NLRS_01.00_verdieping type C2_gen:4703193
2 x Basic Wall:NLRS_22.21_WA_beton prefab d=300_gen:4472952 | 09 negende verdieping | 22.21 binnenwanden - constructief, massieve wanden (Uniformat) | Model Group:NLRS_01.00_verdieping type C2_gen:4703193
Basic Wall:NLRS_22.21_WA_beton prefab d=500_gen:5667400 | 09 negende verdieping | 22.21 binnenwanden - constructief, massieve wanden (Uniformat) | Model Group:NLRS_01.00_verdieping type C2_gen:4703193
Basic Wall:NLRS_22.21_WA_beton prefab d=500_gen:5667404 | 09 negende verdieping | 22.21 binnenwanden - constructief, massieve wanden (Uniformat) | Model Group:NLRS_01.00_verdieping type C2_gen:4703193
Basic Wall:NLRS_21.21_WA_beton prefab d=300/320_gen:5667417 | 09 negende verdieping | 21.21 buitenwanden - constructief, massieve wanden (Uniformat) | Model Group:NLRS_28.21_WA_3D element 002 d=300_gen:5667341
Basic Wall:NLRS_21.21_WA_beton prefab d=300/320_gen:5667419 | 09 negende verdieping | 21.21 buitenwanden - constructief, massieve wanden (Uniformat) | Model Group:NLRS_28.21_WA_3D element 002 d=300_gen:5667341
Basic Wall:NLRS_22.21_WA_beton prefab d=300_gen:5667446 | 09 negende verdieping | 22.21 binnenwanden - constructief, massieve wanden (Uniformat) | Model Group:NLRS_01.00_verdieping type C2_gen:4703193
Basic Wall:NLRS_22.21_WA_beton prefab d=500_gen:5667449 | 09 negende verdieping | 22.21 binnenwanden - constructief, massieve wanden (Uniformat) | Model Group:NLRS_01.00_verdieping type C2_gen:4703193
Basic Wall:NLRS_22.21_WA_beton prefab d=500_gen:5667452 | 09 negende verdieping | 22.21 binnenwanden - constructief, massieve wanden (Uniformat) | Model Group:NLRS_01.00_verdieping type C2_gen:4703193
Basic Wall:NLRS_22.21_WA_beton prefab d=500_gen:5667455 | 09 negende verdieping | 22.21 binnenwanden - constructief, massieve wanden (Uniformat) | Model Group:NLRS_01.00_verdieping type C2_gen:4703193
Basic Wall:NLRS_22.21_WA_beton prefab d=500_gen:5667458 | 09 negende verdieping | 22.21 binnenwanden - constructief, massieve wanden (Uniformat) | Model Group:NLRS_01.00_verdieping type C2_gen:4703193
Basic Wall:NLRS_21.21_WA_beton prefab d=300/320_gen:5667461 | 09 negende verdieping | 21.21 buitenwanden - constructief, massieve wanden (Uniformat) | Model Group:NLRS_28.21_WA_3D element 001 d=300_gen:5667340
Basic Wall:NLRS_21.21_WA_beton prefab d=300/320_gen:5667464 | 09 negende verdieping | 21.21 buitenwanden - constructief, massieve wanden (Uniformat) | Model Group:NLRS_28.21_WA_3D element 001 d=300_gen:5667340
Basic Wall:NLRS_21.21_WA_beton prefab d=300/320_gen:5667490 | 09 negende verdieping | 21.21 buitenwanden - constructief, massieve wanden (Uniformat) | Model Group:NLRS_28.21_WA_3D element 001 d=300_gen:5667358
Basic Wall:NLRS_21.21_WA_beton prefab d=300/320_gen:5667493 | 09 negende verdieping | 21.21 buitenwanden - constructief, massieve wanden (Uniformat) | Model Group:NLRS_28.21_WA_3D element 001 d=300_gen:5667358
Basic Wall:NLRS_22.21_WA_beton prefab d=500_gen:5667520 | 09 negende verdieping | 22.21 binnenwanden - constructief, massieve wanden (Uniformat) | Model Group:NLRS_01.00_verdieping type C2_gen:4703193
Basic Wall:NLRS_22.21_WA_beton prefab d=500_gen:5667523 | 09 negende verdieping | 22.21 binnenwanden - constructief, massieve wanden (Uniformat) | Model Group:NLRS_01.00_verdieping type C2_gen:4703193
Basic Wall:NLRS_22.21_WA_beton prefab d=500_gen:5667525 | 09 negende verdieping | 22.21 binnenwanden - constructief, massieve wanden (Uniformat) | Model Group:NLRS_01.00_verdieping type C2_gen:4703193
2 x Basic Wall:NLRS_22.21_WA_beton prefab d=500_gen:4472769 | 09 negende verdieping | 22.21 binnenwanden - constructief, massieve wanden (Uniformat) | Model Group:NLRS_01.00_verdieping type C2_gen:4703193
Basic Wall:NLRS_22.21_WA_beton prefab d=500_gen:5667530 | 09 negende verdieping | 22.21 binnenwanden - constructief, massieve wanden (Uniformat) | Model Group:NLRS_01.00_verdieping type C2_gen:4703193
6 x Basic Wall:NLRS_21.21_WA_beton prefab d=300/320_gen:5667612 | 09 negende verdieping | 21.21 buitenwanden - constructief, massieve wanden (Uniformat) | Model Group:NLRS_21.21_WA_wand 004b d=300_gen:5667316
4 x Basic Wall:NLRS_21.21_WA_beton prefab d=300/320_gen:5667616 | 09 negende verdieping | 21.21 buitenwanden - constructief, massieve wanden (Uniformat) | Model Group:NLRS_21.21_WA_wand 002b d=300_gen:5667323
2 x Basic Wall:NLRS_21.21_WA_beton ihwg d=500_gen:5835593 | 03 derde verdieping | 21.21 buitenwanden - constructief, massieve wanden (Uniformat)
Basic Wall:NLRS_22.21_WA_beton prefab d=200_gen:1312531 | 00a eerste tussenverdieping | 22.21 binnenwanden - constructief, massieve wanden (Uniformat)
Basic Wall:NLRS_22.21_WA_beton prefab d=200_gen:1312531 | 01 eerste verdieping | 22.21 binnenwanden - constructief, massieve wanden (Uniformat)
Floor:NLRS_23.21_FL_vloer d=270_gen:5889094:2 | 42 tweeënveertigste verdieping | 23.21 vloeren - constructief, vrijdragende vloeren (Uniformat) | Model Group:NLRS_23.21_vloer voor wanden d=300/300_gen:5889137
Floor:NLRS_23.21_FL_breedplaat d=100/270_gen:5910169:2 | 41 eenenveertigste verdieping | 23.21 vloeren - constructief, vrijdragende vloeren (Uniformat)
Basic Wall:NLRS_21.21_WA_beton prefab d=200_gen:6278580 | 02 tweede verdieping | 21.21 buitenwanden - constructief, massieve wanden (Uniformat)
Basic Wall:NLRS_21.21_WA_beton prefab d=200_gen:6278588 | 02 tweede verdieping | 21.21 buitenwanden - constructief, massieve wanden (Uniformat)
Basic Wall:NLRS_21.21_WA_beton prefab d=200_gen:6281994 | 02 tweede verdieping | 21.21 buitenwanden - constructief, massieve wanden (Uniformat)
2 x Basic Wall:NLRS_22.21_WA_beton prefab d=200_gen:6355405 | 00 begane grond | 22.21 binnenwanden - constructief, massieve wanden (Uniformat)
Basic Wall:NLRS_21.21_WA_beton prefab d=300/320_gen:6858996 | 10 tiende verdieping | 21.21 buitenwanden - constructief, massieve wanden (Uniformat) | Model Group:NLRS_21.21_WA_wand 003 d=300_gen:6859046
Basic Wall:NLRS_21.21_WA_beton prefab d=300/320_gen:6858998 | 10 tiende verdieping | 21.21 buitenwanden - constructief, massieve wanden (Uniformat) | Model Group:NLRS_21.21_WA_wand 001 d=300_gen:6859045
Basic Wall:NLRS_21.21_WA_beton prefab d=300/320_gen:6859047 | 10 tiende verdieping | 21.21 buitenwanden - constructief, massieve wanden (Uniformat) | Model Group:NLRS_21.21_WA_wand 003 d=300_gen:6859050
Basic Wall:NLRS_21.21_WA_beton prefab d=300/320_gen:6859051 | 10 tiende verdieping | 21.21 buitenwanden - constructief, massieve wanden (Uniformat) | Model Group:NLRS_21.21_WA_wand 001 d=300_gen:6859054
4 x Basic Wall:NLRS_21.21_WA_beton prefab d=300/320_gen:6859055 | 10 tiende verdieping | 21.21 buitenwanden - constructief, massieve wanden (Uniformat) | Model Group:NLRS_21.21_WA_wand 002a d=300_gen:6859044
2 x Basic Wall:NLRS_21.21_WA_beton prefab d=300/320_gen:5365657 | 10 tiende verdieping | 21.21 buitenwanden - constructief, massieve wanden (Uniformat) | Model Group:NLRS_21.21_WA_wand 002a d=300_gen:6859044
4 x Basic Wall:NLRS_21.21_WA_beton prefab d=300/320_gen:6859059 | 10 tiende verdieping | 21.21 buitenwanden - constructief, massieve wanden (Uniformat) | Model Group:NLRS_21.21_WA_wand 004a d=300_gen:6859036
2 x Basic Wall:NLRS_21.21_WA_beton prefab d=300/320_gen:5365657 | 10 tiende verdieping | 21.21 buitenwanden - constructief, massieve wanden (Uniformat) | Model Group:NLRS_21.21_WA_wand 004a d=300_gen:6859036
Basic Wall:NLRS_21.21_WA_beton prefab d=300/320_gen:6859065 | 10 tiende verdieping | 21.21 buitenwanden - constructief, massieve wanden (Uniformat) | Model Group:NLRS_28.21_WA_3D element 002 d=300_gen:6859076
Basic Wall:NLRS_21.21_WA_beton prefab d=300/320_gen:6859067 | 10 tiende verdieping | 21.21 buitenwanden - constructief, massieve wanden (Uniformat) | Model Group:NLRS_28.21_WA_3D element 002 d=300_gen:6859076
Basic Wall:NLRS_21.21_WA_beton prefab d=300/320_gen:6859116 | 10 tiende verdieping | 21.21 buitenwanden - constructief, massieve wanden (Uniformat) | Model Group:NLRS_28.21_WA_3D element 002 d=300_gen:6859064
Basic Wall:NLRS_21.21_WA_beton prefab d=300/320_gen:6859118 | 10 tiende verdieping | 21.21 buitenwanden - constructief, massieve wanden (Uniformat) | Model Group:NLRS_28.21_WA_3D element 002 d=300_gen:6859064
Basic Wall:NLRS_21.21_WA_beton prefab d=300/320_gen:6859154 | 10 tiende verdieping | 21.21 buitenwanden - constructief, massieve wanden (Uniformat) | Model Group:NLRS_28.21_WA_3D element 001 d=300_gen:6859063
Basic Wall:NLRS_21.21_WA_beton prefab d=300/320_gen:6859157 | 10 tiende verdieping | 21.21 buitenwanden - constructief, massieve wanden (Uniformat) | Model Group:NLRS_28.21_WA_3D element 001 d=300_gen:6859063
Basic Wall:NLRS_21.21_WA_beton prefab d=300/320_gen:6859180 | 10 tiende verdieping | 21.21 buitenwanden - constructief, massieve wanden (Uniformat) | Model Group:NLRS_28.21_WA_3D element 001 d=300_gen:6859077
Basic Wall:NLRS_21.21_WA_beton prefab d=300/320_gen:6859183 | 10 tiende verdieping | 21.21 buitenwanden - constructief, massieve wanden (Uniformat) | Model Group:NLRS_28.21_WA_3D element 001 d=300_gen:6859077
4 x Basic Wall:NLRS_21.21_WA_beton prefab d=300/320_gen:6859261 | 10 tiende verdieping | 21.21 buitenwanden - constructief, massieve wanden (Uniformat) | Model Group:NLRS_21.21_WA_wand 004a d=300_gen:6859036
2 x Basic Wall:NLRS_21.21_WA_beton prefab d=300/320_gen:6859268 | 10 tiende verdieping | 21.21 buitenwanden - constructief, massieve wanden (Uniformat) | Model Group:NLRS_21.21_WA_wand 002a d=300_gen:6859044
Basic Wall:NLRS_21.21_WA_beton prefab d=300/320_gen:6861518 | 11 elfde verdieping | 21.21 buitenwanden - constructief, massieve wanden (Uniformat) | Model Group:NLRS_21.21_WA_wand 003 d=300_gen:6861561
Basic Wall:NLRS_21.21_WA_beton prefab d=300/320_gen:6861520 | 11 elfde verdieping | 21.21 buitenwanden - constructief, massieve wanden (Uniformat) | Model Group:NLRS_21.21_WA_wand 001 d=300_gen:6861560
Basic Wall:NLRS_21.21_WA_beton prefab d=300/320_gen:6861562 | 11 elfde verdieping | 21.21 buitenwanden - constructief, massieve wanden (Uniformat) | Model Group:NLRS_21.21_WA_wand 003 d=300_gen:6861565
Basic Wall:NLRS_21.21_WA_beton prefab d=300/320_gen:6861566 | 11 elfde verdieping | 21.21 buitenwanden - constructief, massieve wanden (Uniformat) | Model Group:NLRS_21.21_WA_wand 001 d=300_gen:6861569
Basic Wall:NLRS_21.21_WA_beton prefab d=300/320_gen:6861578 | 11 elfde verdieping | 21.21 buitenwanden - constructief, massieve wanden (Uniformat) | Model Group:NLRS_28.21_WA_3D element 002 d=300_gen:6861589
Basic Wall:NLRS_21.21_WA_beton prefab d=300/320_gen:6861580 | 11 elfde verdieping | 21.21 buitenwanden - constructief, massieve wanden (Uniformat) | Model Group:NLRS_28.21_WA_3D element 002 d=300_gen:6861589
Basic Wall:NLRS_21.21_WA_beton prefab d=300/320_gen:6861629 | 11 elfde verdieping | 21.21 buitenwanden - constructief, massieve wanden (Uniformat) | Model Group:NLRS_28.21_WA_3D element 002 d=300_gen:6861577
Basic Wall:NLRS_21.21_WA_beton prefab d=300/320_gen:6861631 | 11 elfde verdieping | 21.21 buitenwanden - constructief, massieve wanden (Uniformat) | Model Group:NLRS_28.21_WA_3D element 002 d=300_gen:6861577
Basic Wall:NLRS_21.21_WA_beton prefab d=300/320_gen:6861667 | 11 elfde verdieping | 21.21 buitenwanden - constructief, massieve wanden (Uniformat) | Model Group:NLRS_28.21_WA_3D element 001 d=300_gen:6861576
Basic Wall:NLRS_21.21_WA_beton prefab d=300/320_gen:6861670 | 11 elfde verdieping | 21.21 buitenwanden - constructief, massieve wanden (Uniformat) | Model Group:NLRS_28.21_WA_3D element 001 d=300_gen:6861576
Basic Wall:NLRS_21.21_WA_beton prefab d=300/320_gen:6861693 | 11 elfde verdieping | 21.21 buitenwanden - constructief, massieve wanden (Uniformat) | Model Group:NLRS_28.21_WA_3D element 001 d=300_gen:6861590
Basic Wall:NLRS_21.21_WA_beton prefab d=300/320_gen:6861696 | 11 elfde verdieping | 21.21 buitenwanden - constructief, massieve wanden (Uniformat) | Model Group:NLRS_28.21_WA_3D element 001 d=300_gen:6861590
Floor:NLRS_13.22_FL_beton ihwg d=250_gevlinderd en ingestrooid_gen:6968290:2 | 00 begane grond | 13.22 vloeren op grondslag - constructief, vloeren als gebouwonderdeel (Uniformat)
Floor:NLRS_13.22_FL_beton ihwg d=250_gevlinderd en ingestrooid_gen:6968290:3 | 00 begane grond | 13.22 vloeren op grondslag - constructief, vloeren als gebouwonderdeel (Uniformat)
99 x  | 04 vierde verdieping
104 x  | 03 derde verdieping
108 x  | 02 tweede verdieping
Basic Wall:NLRS_22.21_WA_beton ihwg d=600_gen:7297270 | 00 begane grond | 22.21 binnenwanden - constructief, massieve wanden (Uniformat)
2 x Basic Wall:NLRS_22.21_WA_beton ihwg d=600_gen:7298413 | 01 eerste verdieping | 22.21 binnenwanden - constructief, massieve wanden (Uniformat)
Basic Wall:NLRS_22.21_WA_beton ihwg d=600_gen:7298504 | 02 tweede verdieping | 22.21 binnenwanden - constructief, massieve wanden (Uniformat)
3 x Basic Wall:NLRS_22.21_WA_beton ihwg d=600_gen:7298594 | 03 derde verdieping | 22.21 binnenwanden - constructief, massieve wanden (Uniformat)
Basic Wall:NLRS_22.21_WA_beton ihwg d=600_gen:7298797 | 04 vierde verdieping | 22.21 binnenwanden - constructief, massieve wanden (Uniformat)
Basic Wall:NLRS_22.21_WA_beton prefab d=400_gen:4699555 | 02 tweede verdieping | 22.21 binnenwanden - constructief, massieve wanden (Uniformat)
3 x Basic Wall:NLRS_21.21_WA_beton ihwg d=300_gen:7359271 | 00 begane grond | 21.21 buitenwanden - constructief, massieve wanden (Uniformat)
4 x Basic Wall:NLRS_22.21_WA_beton prefab d=200_gen:8873636 | 07 zevende verdieping | 22.21 binnenwanden - constructief, massieve wanden (Uniformat) | Model Group:NLRS_22.21_WA_kern 06--51_gen:4689379
4 x Basic Wall:NLRS_22.21_WA_beton prefab d=200_gen:8873638 | 07 zevende verdieping | 22.21 binnenwanden - constructief, massieve wanden (Uniformat) | Model Group:NLRS_22.21_WA_kern 06--51_gen:4689379
4 x Basic Wall:NLRS_22.21_WA_beton prefab d=200_gen:8873640 | 07 zevende verdieping | 22.21 binnenwanden - constructief, massieve wanden (Uniformat) | Model Group:NLRS_22.21_WA_kern 06--51_gen:4689379
Floor:NLRS_23.21_FL_vloer=230_gen:8873656:2 | 07 zevende verdieping | 23.21 vloeren - constructief, vrijdragende vloeren (Uniformat) | Model Group:NLRS_22.21_WA_kern 06--51_gen:4689379
4 x Basic Wall:NLRS_22.21_WA_beton prefab d=200_gen:8873898 | 08 achtste verdieping | 22.21 binnenwanden - constructief, massieve wanden (Uniformat) | Model Group:NLRS_22.21_WA_kern 06--51_gen:4715051
4 x Basic Wall:NLRS_22.21_WA_beton prefab d=200_gen:8873900 | 08 achtste verdieping | 22.21 binnenwanden - constructief, massieve wanden (Uniformat) | Model Group:NLRS_22.21_WA_kern 06--51_gen:4715051
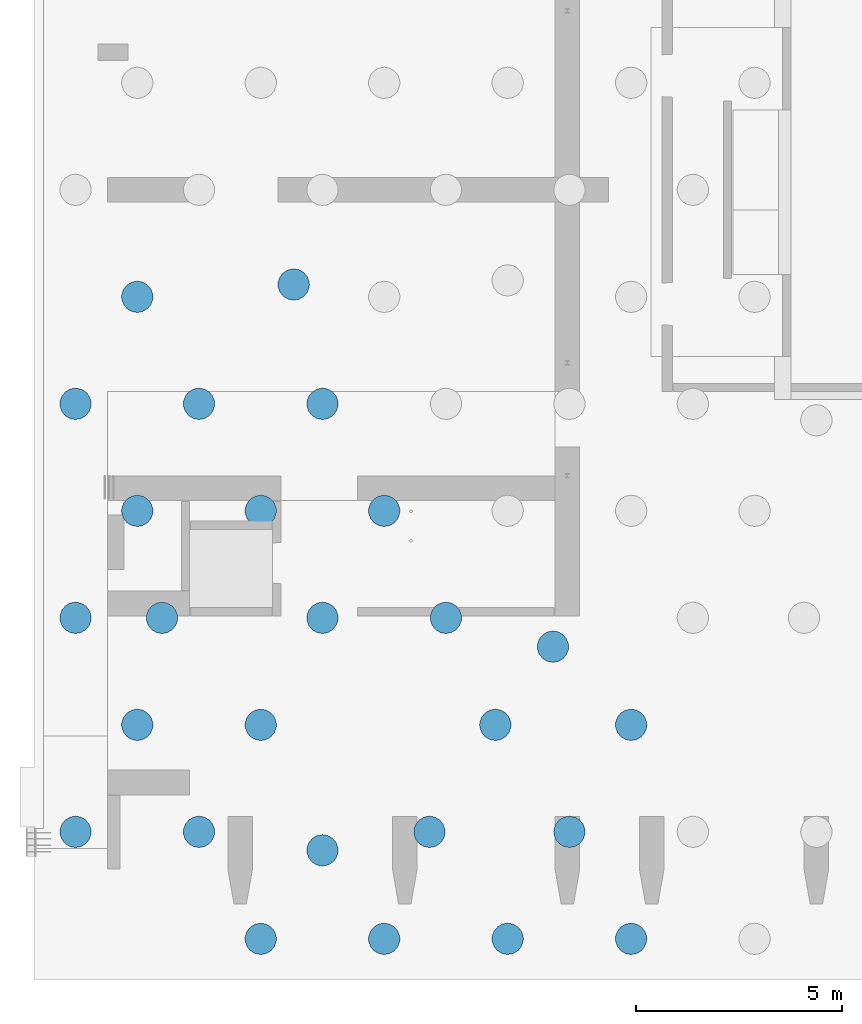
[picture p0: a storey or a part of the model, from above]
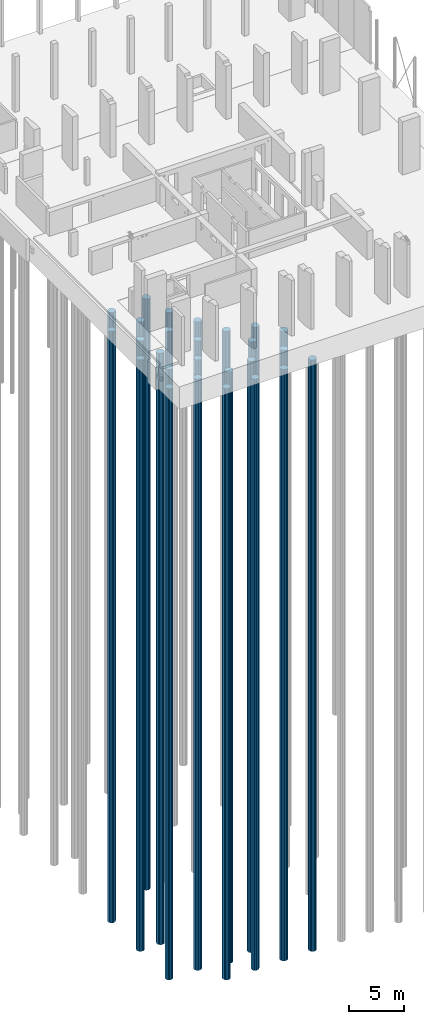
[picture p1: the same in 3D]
Properties of the parts of a building model (IFC2X3), part 12 of 21

# IfcOpeningElement: Opening (5659)
Name | In | Classification | Group
4 x Basic Wall:NLRS_22.21_WA_beton prefab d=200_gen:8873902 | 08 achtste verdieping | 22.21 binnenwanden - constructief, massieve wanden (Uniformat) | Model Group:NLRS_22.21_WA_kern 06--51_gen:4715051
Floor:NLRS_23.21_FL_vloer=230_gen:8873918:2 | 08 achtste verdieping | 23.21 vloeren - constructief, vrijdragende vloeren (Uniformat) | Model Group:NLRS_22.21_WA_kern 06--51_gen:4715051
4 x Basic Wall:NLRS_22.21_WA_beton prefab d=200_gen:8873955 | 12 twaalfde verdieping | 22.21 binnenwanden - constructief, massieve wanden (Uniformat) | Model Group:NLRS_22.21_WA_kern 06--51_gen:4738448
4 x Basic Wall:NLRS_22.21_WA_beton prefab d=200_gen:8873957 | 12 twaalfde verdieping | 22.21 binnenwanden - constructief, massieve wanden (Uniformat) | Model Group:NLRS_22.21_WA_kern 06--51_gen:4738448
4 x Basic Wall:NLRS_22.21_WA_beton prefab d=200_gen:8873959 | 12 twaalfde verdieping | 22.21 binnenwanden - constructief, massieve wanden (Uniformat) | Model Group:NLRS_22.21_WA_kern 06--51_gen:4738448
Floor:NLRS_23.21_FL_vloer=230_gen:8873975:2 | 12 twaalfde verdieping | 23.21 vloeren - constructief, vrijdragende vloeren (Uniformat) | Model Group:NLRS_22.21_WA_kern 06--51_gen:4738448
4 x Basic Wall:NLRS_22.21_WA_beton prefab d=200_gen:8874012 | 09 negende verdieping | 22.21 binnenwanden - constructief, massieve wanden (Uniformat) | Model Group:NLRS_22.21_WA_kern 06--51_gen:5667376
4 x Basic Wall:NLRS_22.21_WA_beton prefab d=200_gen:8874014 | 09 negende verdieping | 22.21 binnenwanden - constructief, massieve wanden (Uniformat) | Model Group:NLRS_22.21_WA_kern 06--51_gen:5667376
4 x Basic Wall:NLRS_22.21_WA_beton prefab d=200_gen:8874016 | 09 negende verdieping | 22.21 binnenwanden - constructief, massieve wanden (Uniformat) | Model Group:NLRS_22.21_WA_kern 06--51_gen:5667376
Floor:NLRS_23.21_FL_vloer=230_gen:8874032:2 | 09 negende verdieping | 23.21 vloeren - constructief, vrijdragende vloeren (Uniformat) | Model Group:NLRS_22.21_WA_kern 06--51_gen:5667376
4 x Basic Wall:NLRS_22.21_WA_beton prefab d=200_gen:8874069 | 10 tiende verdieping | 22.21 binnenwanden - constructief, massieve wanden (Uniformat) | Model Group:NLRS_22.21_WA_kern 06--51_gen:6859079
4 x Basic Wall:NLRS_22.21_WA_beton prefab d=200_gen:8874071 | 10 tiende verdieping | 22.21 binnenwanden - constructief, massieve wanden (Uniformat) | Model Group:NLRS_22.21_WA_kern 06--51_gen:6859079
4 x Basic Wall:NLRS_22.21_WA_beton prefab d=200_gen:8874073 | 10 tiende verdieping | 22.21 binnenwanden - constructief, massieve wanden (Uniformat) | Model Group:NLRS_22.21_WA_kern 06--51_gen:6859079
Floor:NLRS_23.21_FL_vloer=230_gen:8874089:2 | 10 tiende verdieping | 23.21 vloeren - constructief, vrijdragende vloeren (Uniformat) | Model Group:NLRS_22.21_WA_kern 06--51_gen:6859079
4 x Basic Wall:NLRS_22.21_WA_beton prefab d=200_gen:8874126 | 11 elfde verdieping | 22.21 binnenwanden - constructief, massieve wanden (Uniformat) | Model Group:NLRS_22.21_WA_kern 06--51_gen:6861592
4 x Basic Wall:NLRS_22.21_WA_beton prefab d=200_gen:8874128 | 11 elfde verdieping | 22.21 binnenwanden - constructief, massieve wanden (Uniformat) | Model Group:NLRS_22.21_WA_kern 06--51_gen:6861592
4 x Basic Wall:NLRS_22.21_WA_beton prefab d=200_gen:8874130 | 11 elfde verdieping | 22.21 binnenwanden - constructief, massieve wanden (Uniformat) | Model Group:NLRS_22.21_WA_kern 06--51_gen:6861592
Floor:NLRS_23.21_FL_vloer=230_gen:8874146:2 | 11 elfde verdieping | 23.21 vloeren - constructief, vrijdragende vloeren (Uniformat) | Model Group:NLRS_22.21_WA_kern 06--51_gen:6861592
4 x Basic Wall:NLRS_22.21_WA_beton prefab d=200_gen:8875614 | 13 dertiende verdieping | 22.21 binnenwanden - constructief, massieve wanden (Uniformat) | Model Group:NLRS_22.21_WA_kern 06--51_gen:4730861
4 x Basic Wall:NLRS_22.21_WA_beton prefab d=200_gen:8875616 | 13 dertiende verdieping | 22.21 binnenwanden - constructief, massieve wanden (Uniformat) | Model Group:NLRS_22.21_WA_kern 06--51_gen:4730861
4 x Basic Wall:NLRS_22.21_WA_beton prefab d=200_gen:8875618 | 13 dertiende verdieping | 22.21 binnenwanden - constructief, massieve wanden (Uniformat) | Model Group:NLRS_22.21_WA_kern 06--51_gen:4730861
Floor:NLRS_23.21_FL_vloer=230_gen:8875634:2 | 13 dertiende verdieping | 23.21 vloeren - constructief, vrijdragende vloeren (Uniformat) | Model Group:NLRS_22.21_WA_kern 06--51_gen:4730861
4 x Basic Wall:NLRS_22.21_WA_beton prefab d=200_gen:8875671 | 15 vijftiende verdieping | 22.21 binnenwanden - constructief, massieve wanden (Uniformat) | Model Group:NLRS_22.21_WA_kern 06--51_gen:4731319
4 x Basic Wall:NLRS_22.21_WA_beton prefab d=200_gen:8875673 | 15 vijftiende verdieping | 22.21 binnenwanden - constructief, massieve wanden (Uniformat) | Model Group:NLRS_22.21_WA_kern 06--51_gen:4731319
4 x Basic Wall:NLRS_22.21_WA_beton prefab d=200_gen:8875675 | 15 vijftiende verdieping | 22.21 binnenwanden - constructief, massieve wanden (Uniformat) | Model Group:NLRS_22.21_WA_kern 06--51_gen:4731319
Floor:NLRS_23.21_FL_vloer=230_gen:8875691:2 | 15 vijftiende verdieping | 23.21 vloeren - constructief, vrijdragende vloeren (Uniformat) | Model Group:NLRS_22.21_WA_kern 06--51_gen:4731319
4 x Basic Wall:NLRS_22.21_WA_beton prefab d=200_gen:8875728 | 17 zeventiende verdieping | 22.21 binnenwanden - constructief, massieve wanden (Uniformat) | Model Group:NLRS_22.21_WA_kern 06--51_gen:4731777
4 x Basic Wall:NLRS_22.21_WA_beton prefab d=200_gen:8875730 | 17 zeventiende verdieping | 22.21 binnenwanden - constructief, massieve wanden (Uniformat) | Model Group:NLRS_22.21_WA_kern 06--51_gen:4731777
4 x Basic Wall:NLRS_22.21_WA_beton prefab d=200_gen:8875732 | 17 zeventiende verdieping | 22.21 binnenwanden - constructief, massieve wanden (Uniformat) | Model Group:NLRS_22.21_WA_kern 06--51_gen:4731777
Floor:NLRS_23.21_FL_vloer=230_gen:8875748:2 | 17 zeventiende verdieping | 23.21 vloeren - constructief, vrijdragende vloeren (Uniformat) | Model Group:NLRS_22.21_WA_kern 06--51_gen:4731777
4 x Basic Wall:NLRS_22.21_WA_beton prefab d=200_gen:8875785 | 19 negentiende verdieping | 22.21 binnenwanden - constructief, massieve wanden (Uniformat) | Model Group:NLRS_22.21_WA_kern 06--51_gen:4732235
4 x Basic Wall:NLRS_22.21_WA_beton prefab d=200_gen:8875787 | 19 negentiende verdieping | 22.21 binnenwanden - constructief, massieve wanden (Uniformat) | Model Group:NLRS_22.21_WA_kern 06--51_gen:4732235
4 x Basic Wall:NLRS_22.21_WA_beton prefab d=200_gen:8875789 | 19 negentiende verdieping | 22.21 binnenwanden - constructief, massieve wanden (Uniformat) | Model Group:NLRS_22.21_WA_kern 06--51_gen:4732235
Floor:NLRS_23.21_FL_vloer=230_gen:8875805:2 | 19 negentiende verdieping | 23.21 vloeren - constructief, vrijdragende vloeren (Uniformat) | Model Group:NLRS_22.21_WA_kern 06--51_gen:4732235
4 x Basic Wall:NLRS_22.21_WA_beton prefab d=200_gen:8875842 | 14 veertiende verdieping | 22.21 binnenwanden - constructief, massieve wanden (Uniformat) | Model Group:NLRS_22.21_WA_kern 06--51_gen:4738906
4 x Basic Wall:NLRS_22.21_WA_beton prefab d=200_gen:8875844 | 14 veertiende verdieping | 22.21 binnenwanden - constructief, massieve wanden (Uniformat) | Model Group:NLRS_22.21_WA_kern 06--51_gen:4738906
4 x Basic Wall:NLRS_22.21_WA_beton prefab d=200_gen:8875846 | 14 veertiende verdieping | 22.21 binnenwanden - constructief, massieve wanden (Uniformat) | Model Group:NLRS_22.21_WA_kern 06--51_gen:4738906
Floor:NLRS_23.21_FL_vloer=230_gen:8875862:2 | 14 veertiende verdieping | 23.21 vloeren - constructief, vrijdragende vloeren (Uniformat) | Model Group:NLRS_22.21_WA_kern 06--51_gen:4738906
4 x Basic Wall:NLRS_22.21_WA_beton prefab d=200_gen:8875899 | 16 zestiende verdieping | 22.21 binnenwanden - constructief, massieve wanden (Uniformat) | Model Group:NLRS_22.21_WA_kern 06--51_gen:4739364
4 x Basic Wall:NLRS_22.21_WA_beton prefab d=200_gen:8875901 | 16 zestiende verdieping | 22.21 binnenwanden - constructief, massieve wanden (Uniformat) | Model Group:NLRS_22.21_WA_kern 06--51_gen:4739364
4 x Basic Wall:NLRS_22.21_WA_beton prefab d=200_gen:8875903 | 16 zestiende verdieping | 22.21 binnenwanden - constructief, massieve wanden (Uniformat) | Model Group:NLRS_22.21_WA_kern 06--51_gen:4739364
Floor:NLRS_23.21_FL_vloer=230_gen:8875919:2 | 16 zestiende verdieping | 23.21 vloeren - constructief, vrijdragende vloeren (Uniformat) | Model Group:NLRS_22.21_WA_kern 06--51_gen:4739364
4 x Basic Wall:NLRS_22.21_WA_beton prefab d=200_gen:8875956 | 18 achttiende verdieping | 22.21 binnenwanden - constructief, massieve wanden (Uniformat) | Model Group:NLRS_22.21_WA_kern 06--51_gen:4739822
4 x Basic Wall:NLRS_22.21_WA_beton prefab d=200_gen:8875958 | 18 achttiende verdieping | 22.21 binnenwanden - constructief, massieve wanden (Uniformat) | Model Group:NLRS_22.21_WA_kern 06--51_gen:4739822
4 x Basic Wall:NLRS_22.21_WA_beton prefab d=200_gen:8875960 | 18 achttiende verdieping | 22.21 binnenwanden - constructief, massieve wanden (Uniformat) | Model Group:NLRS_22.21_WA_kern 06--51_gen:4739822
Floor:NLRS_23.21_FL_vloer=230_gen:8875976:2 | 18 achttiende verdieping | 23.21 vloeren - constructief, vrijdragende vloeren (Uniformat) | Model Group:NLRS_22.21_WA_kern 06--51_gen:4739822
4 x Basic Wall:NLRS_22.21_WA_beton prefab d=200_gen:8876013 | 20 twintigste verdieping | 22.21 binnenwanden - constructief, massieve wanden (Uniformat) | Model Group:NLRS_22.21_WA_kern 06--51_gen:4740280
4 x Basic Wall:NLRS_22.21_WA_beton prefab d=200_gen:8876015 | 20 twintigste verdieping | 22.21 binnenwanden - constructief, massieve wanden (Uniformat) | Model Group:NLRS_22.21_WA_kern 06--51_gen:4740280
4 x Basic Wall:NLRS_22.21_WA_beton prefab d=200_gen:8876017 | 20 twintigste verdieping | 22.21 binnenwanden - constructief, massieve wanden (Uniformat) | Model Group:NLRS_22.21_WA_kern 06--51_gen:4740280
Floor:NLRS_23.21_FL_vloer=230_gen:8876033:2 | 20 twintigste verdieping | 23.21 vloeren - constructief, vrijdragende vloeren (Uniformat) | Model Group:NLRS_22.21_WA_kern 06--51_gen:4740280
4 x Basic Wall:NLRS_22.21_WA_beton prefab d=200_gen:8879090 | 21 eenentwintigste verdieping | 22.21 binnenwanden - constructief, massieve wanden (Uniformat) | Model Group:NLRS_22.21_WA_kern 06--51_gen:4695238
4 x Basic Wall:NLRS_22.21_WA_beton prefab d=200_gen:8879092 | 21 eenentwintigste verdieping | 22.21 binnenwanden - constructief, massieve wanden (Uniformat) | Model Group:NLRS_22.21_WA_kern 06--51_gen:4695238
4 x Basic Wall:NLRS_22.21_WA_beton prefab d=200_gen:8879094 | 21 eenentwintigste verdieping | 22.21 binnenwanden - constructief, massieve wanden (Uniformat) | Model Group:NLRS_22.21_WA_kern 06--51_gen:4695238
Floor:NLRS_23.21_FL_vloer=230_gen:8879110:2 | 21 eenentwintigste verdieping | 23.21 vloeren - constructief, vrijdragende vloeren (Uniformat) | Model Group:NLRS_22.21_WA_kern 06--51_gen:4695238
4 x Basic Wall:NLRS_22.21_WA_beton prefab d=200_gen:8879147 | 24 vierentwintigste verdieping | 22.21 binnenwanden - constructief, massieve wanden (Uniformat) | Model Group:NLRS_22.21_WA_kern 06--51_gen:4746873
4 x Basic Wall:NLRS_22.21_WA_beton prefab d=200_gen:8879149 | 24 vierentwintigste verdieping | 22.21 binnenwanden - constructief, massieve wanden (Uniformat) | Model Group:NLRS_22.21_WA_kern 06--51_gen:4746873
4 x Basic Wall:NLRS_22.21_WA_beton prefab d=200_gen:8879151 | 24 vierentwintigste verdieping | 22.21 binnenwanden - constructief, massieve wanden (Uniformat) | Model Group:NLRS_22.21_WA_kern 06--51_gen:4746873
Floor:NLRS_23.21_FL_vloer=230_gen:8879167:2 | 24 vierentwintigste verdieping | 23.21 vloeren - constructief, vrijdragende vloeren (Uniformat) | Model Group:NLRS_22.21_WA_kern 06--51_gen:4746873
4 x Basic Wall:NLRS_22.21_WA_beton prefab d=200_gen:8879204 | 25 vijfentwintigste verdieping | 22.21 binnenwanden - constructief, massieve wanden (Uniformat) | Model Group:NLRS_22.21_WA_kern 06--51_gen:4747305
4 x Basic Wall:NLRS_22.21_WA_beton prefab d=200_gen:8879206 | 25 vijfentwintigste verdieping | 22.21 binnenwanden - constructief, massieve wanden (Uniformat) | Model Group:NLRS_22.21_WA_kern 06--51_gen:4747305
4 x Basic Wall:NLRS_22.21_WA_beton prefab d=200_gen:8879208 | 25 vijfentwintigste verdieping | 22.21 binnenwanden - constructief, massieve wanden (Uniformat) | Model Group:NLRS_22.21_WA_kern 06--51_gen:4747305
Floor:NLRS_23.21_FL_vloer=230_gen:8879224:2 | 25 vijfentwintigste verdieping | 23.21 vloeren - constructief, vrijdragende vloeren (Uniformat) | Model Group:NLRS_22.21_WA_kern 06--51_gen:4747305
4 x Basic Wall:NLRS_22.21_WA_beton prefab d=200_gen:8879261 | 26 zesentwintigste verdieping | 22.21 binnenwanden - constructief, massieve wanden (Uniformat) | Model Group:NLRS_22.21_WA_kern 06--51_gen:4747737
4 x Basic Wall:NLRS_22.21_WA_beton prefab d=200_gen:8879263 | 26 zesentwintigste verdieping | 22.21 binnenwanden - constructief, massieve wanden (Uniformat) | Model Group:NLRS_22.21_WA_kern 06--51_gen:4747737
4 x Basic Wall:NLRS_22.21_WA_beton prefab d=200_gen:8879265 | 26 zesentwintigste verdieping | 22.21 binnenwanden - constructief, massieve wanden (Uniformat) | Model Group:NLRS_22.21_WA_kern 06--51_gen:4747737
Floor:NLRS_23.21_FL_vloer=230_gen:8879281:2 | 26 zesentwintigste verdieping | 23.21 vloeren - constructief, vrijdragende vloeren (Uniformat) | Model Group:NLRS_22.21_WA_kern 06--51_gen:4747737
4 x Basic Wall:NLRS_22.21_WA_beton prefab d=200_gen:8879318 | 27 zevenentwintigste verdieping | 22.21 binnenwanden - constructief, massieve wanden (Uniformat) | Model Group:NLRS_22.21_WA_kern 06--51_gen:4748169
4 x Basic Wall:NLRS_22.21_WA_beton prefab d=200_gen:8879320 | 27 zevenentwintigste verdieping | 22.21 binnenwanden - constructief, massieve wanden (Uniformat) | Model Group:NLRS_22.21_WA_kern 06--51_gen:4748169
4 x Basic Wall:NLRS_22.21_WA_beton prefab d=200_gen:8879322 | 27 zevenentwintigste verdieping | 22.21 binnenwanden - constructief, massieve wanden (Uniformat) | Model Group:NLRS_22.21_WA_kern 06--51_gen:4748169
Floor:NLRS_23.21_FL_vloer=230_gen:8879338:2 | 27 zevenentwintigste verdieping | 23.21 vloeren - constructief, vrijdragende vloeren (Uniformat) | Model Group:NLRS_22.21_WA_kern 06--51_gen:4748169
4 x Basic Wall:NLRS_22.21_WA_beton prefab d=200_gen:8879375 | 28 achtentwintigste verdieping | 22.21 binnenwanden - constructief, massieve wanden (Uniformat) | Model Group:NLRS_22.21_WA_kern 06--51_gen:4748601
4 x Basic Wall:NLRS_22.21_WA_beton prefab d=200_gen:8879377 | 28 achtentwintigste verdieping | 22.21 binnenwanden - constructief, massieve wanden (Uniformat) | Model Group:NLRS_22.21_WA_kern 06--51_gen:4748601
4 x Basic Wall:NLRS_22.21_WA_beton prefab d=200_gen:8879379 | 28 achtentwintigste verdieping | 22.21 binnenwanden - constructief, massieve wanden (Uniformat) | Model Group:NLRS_22.21_WA_kern 06--51_gen:4748601
Floor:NLRS_23.21_FL_vloer=230_gen:8879395:2 | 28 achtentwintigste verdieping | 23.21 vloeren - constructief, vrijdragende vloeren (Uniformat) | Model Group:NLRS_22.21_WA_kern 06--51_gen:4748601
4 x Basic Wall:NLRS_22.21_WA_beton prefab d=200_gen:8879432 | 29 negenentwintigste verdieping | 22.21 binnenwanden - constructief, massieve wanden (Uniformat) | Model Group:NLRS_22.21_WA_kern 06--51_gen:4749033
4 x Basic Wall:NLRS_22.21_WA_beton prefab d=200_gen:8879434 | 29 negenentwintigste verdieping | 22.21 binnenwanden - constructief, massieve wanden (Uniformat) | Model Group:NLRS_22.21_WA_kern 06--51_gen:4749033
4 x Basic Wall:NLRS_22.21_WA_beton prefab d=200_gen:8879436 | 29 negenentwintigste verdieping | 22.21 binnenwanden - constructief, massieve wanden (Uniformat) | Model Group:NLRS_22.21_WA_kern 06--51_gen:4749033
Floor:NLRS_23.21_FL_vloer=230_gen:8879452:2 | 29 negenentwintigste verdieping | 23.21 vloeren - constructief, vrijdragende vloeren (Uniformat) | Model Group:NLRS_22.21_WA_kern 06--51_gen:4749033
4 x Basic Wall:NLRS_22.21_WA_beton prefab d=200_gen:8879489 | 30 dertigste verdieping | 22.21 binnenwanden - constructief, massieve wanden (Uniformat) | Model Group:NLRS_22.21_WA_kern 06--51_gen:4749465
4 x Basic Wall:NLRS_22.21_WA_beton prefab d=200_gen:8879491 | 30 dertigste verdieping | 22.21 binnenwanden - constructief, massieve wanden (Uniformat) | Model Group:NLRS_22.21_WA_kern 06--51_gen:4749465
4 x Basic Wall:NLRS_22.21_WA_beton prefab d=200_gen:8879493 | 30 dertigste verdieping | 22.21 binnenwanden - constructief, massieve wanden (Uniformat) | Model Group:NLRS_22.21_WA_kern 06--51_gen:4749465
Floor:NLRS_23.21_FL_vloer=230_gen:8879509:2 | 30 dertigste verdieping | 23.21 vloeren - constructief, vrijdragende vloeren (Uniformat) | Model Group:NLRS_22.21_WA_kern 06--51_gen:4749465
4 x Basic Wall:NLRS_22.21_WA_beton prefab d=200_gen:8879546 | 31 eenendertigste verdieping | 22.21 binnenwanden - constructief, massieve wanden (Uniformat) | Model Group:NLRS_22.21_WA_kern 06--51_gen:4749897
4 x Basic Wall:NLRS_22.21_WA_beton prefab d=200_gen:8879548 | 31 eenendertigste verdieping | 22.21 binnenwanden - constructief, massieve wanden (Uniformat) | Model Group:NLRS_22.21_WA_kern 06--51_gen:4749897
4 x Basic Wall:NLRS_22.21_WA_beton prefab d=200_gen:8879550 | 31 eenendertigste verdieping | 22.21 binnenwanden - constructief, massieve wanden (Uniformat) | Model Group:NLRS_22.21_WA_kern 06--51_gen:4749897
Floor:NLRS_23.21_FL_vloer=230_gen:8879566:2 | 31 eenendertigste verdieping | 23.21 vloeren - constructief, vrijdragende vloeren (Uniformat) | Model Group:NLRS_22.21_WA_kern 06--51_gen:4749897
4 x Basic Wall:NLRS_22.21_WA_beton prefab d=200_gen:8879603 | 32 tweeëndertigste verdieping | 22.21 binnenwanden - constructief, massieve wanden (Uniformat) | Model Group:NLRS_22.21_WA_kern 06--51_gen:4750329
4 x Basic Wall:NLRS_22.21_WA_beton prefab d=200_gen:8879605 | 32 tweeëndertigste verdieping | 22.21 binnenwanden - constructief, massieve wanden (Uniformat) | Model Group:NLRS_22.21_WA_kern 06--51_gen:4750329
4 x Basic Wall:NLRS_22.21_WA_beton prefab d=200_gen:8879607 | 32 tweeëndertigste verdieping | 22.21 binnenwanden - constructief, massieve wanden (Uniformat) | Model Group:NLRS_22.21_WA_kern 06--51_gen:4750329
Floor:NLRS_23.21_FL_vloer=230_gen:8879623:2 | 32 tweeëndertigste verdieping | 23.21 vloeren - constructief, vrijdragende vloeren (Uniformat) | Model Group:NLRS_22.21_WA_kern 06--51_gen:4750329
4 x Basic Wall:NLRS_22.21_WA_beton prefab d=200_gen:8879660 | 33 drieëndertigste verdieping | 22.21 binnenwanden - constructief, massieve wanden (Uniformat) | Model Group:NLRS_22.21_WA_kern 06--51_gen:4750761
4 x Basic Wall:NLRS_22.21_WA_beton prefab d=200_gen:8879662 | 33 drieëndertigste verdieping | 22.21 binnenwanden - constructief, massieve wanden (Uniformat) | Model Group:NLRS_22.21_WA_kern 06--51_gen:4750761
4 x Basic Wall:NLRS_22.21_WA_beton prefab d=200_gen:8879664 | 33 drieëndertigste verdieping | 22.21 binnenwanden - constructief, massieve wanden (Uniformat) | Model Group:NLRS_22.21_WA_kern 06--51_gen:4750761
Floor:NLRS_23.21_FL_vloer=230_gen:8879680:2 | 33 drieëndertigste verdieping | 23.21 vloeren - constructief, vrijdragende vloeren (Uniformat) | Model Group:NLRS_22.21_WA_kern 06--51_gen:4750761
4 x Basic Wall:NLRS_22.21_WA_beton prefab d=200_gen:8879717 | 34 vierendertigste verdieping | 22.21 binnenwanden - constructief, massieve wanden (Uniformat) | Model Group:NLRS_22.21_WA_kern 06--51_gen:4751193
4 x Basic Wall:NLRS_22.21_WA_beton prefab d=200_gen:8879719 | 34 vierendertigste verdieping | 22.21 binnenwanden - constructief, massieve wanden (Uniformat) | Model Group:NLRS_22.21_WA_kern 06--51_gen:4751193
4 x Basic Wall:NLRS_22.21_WA_beton prefab d=200_gen:8879721 | 34 vierendertigste verdieping | 22.21 binnenwanden - constructief, massieve wanden (Uniformat) | Model Group:NLRS_22.21_WA_kern 06--51_gen:4751193
Floor:NLRS_23.21_FL_vloer=230_gen:8879737:2 | 34 vierendertigste verdieping | 23.21 vloeren - constructief, vrijdragende vloeren (Uniformat) | Model Group:NLRS_22.21_WA_kern 06--51_gen:4751193
4 x Basic Wall:NLRS_22.21_WA_beton prefab d=200_gen:8879774 | 35 vijfendertigste verdieping | 22.21 binnenwanden - constructief, massieve wanden (Uniformat) | Model Group:NLRS_22.21_WA_kern 06--51_gen:4751625
4 x Basic Wall:NLRS_22.21_WA_beton prefab d=200_gen:8879776 | 35 vijfendertigste verdieping | 22.21 binnenwanden - constructief, massieve wanden (Uniformat) | Model Group:NLRS_22.21_WA_kern 06--51_gen:4751625
4 x Basic Wall:NLRS_22.21_WA_beton prefab d=200_gen:8879778 | 35 vijfendertigste verdieping | 22.21 binnenwanden - constructief, massieve wanden (Uniformat) | Model Group:NLRS_22.21_WA_kern 06--51_gen:4751625
Floor:NLRS_23.21_FL_vloer=230_gen:8879794:2 | 35 vijfendertigste verdieping | 23.21 vloeren - constructief, vrijdragende vloeren (Uniformat) | Model Group:NLRS_22.21_WA_kern 06--51_gen:4751625
4 x Basic Wall:NLRS_22.21_WA_beton prefab d=200_gen:8879831 | 36 zesendertigste verdieping | 22.21 binnenwanden - constructief, massieve wanden (Uniformat) | Model Group:NLRS_22.21_WA_kern 06--51_gen:4752057
4 x Basic Wall:NLRS_22.21_WA_beton prefab d=200_gen:8879833 | 36 zesendertigste verdieping | 22.21 binnenwanden - constructief, massieve wanden (Uniformat) | Model Group:NLRS_22.21_WA_kern 06--51_gen:4752057
4 x Basic Wall:NLRS_22.21_WA_beton prefab d=200_gen:8879835 | 36 zesendertigste verdieping | 22.21 binnenwanden - constructief, massieve wanden (Uniformat) | Model Group:NLRS_22.21_WA_kern 06--51_gen:4752057
Floor:NLRS_23.21_FL_vloer=230_gen:8879851:2 | 36 zesendertigste verdieping | 23.21 vloeren - constructief, vrijdragende vloeren (Uniformat) | Model Group:NLRS_22.21_WA_kern 06--51_gen:4752057
4 x Basic Wall:NLRS_22.21_WA_beton prefab d=200_gen:8879888 | 37 zevenendertigste verdieping | 22.21 binnenwanden - constructief, massieve wanden (Uniformat) | Model Group:NLRS_22.21_WA_kern 06--51_gen:4752489
4 x Basic Wall:NLRS_22.21_WA_beton prefab d=200_gen:8879890 | 37 zevenendertigste verdieping | 22.21 binnenwanden - constructief, massieve wanden (Uniformat) | Model Group:NLRS_22.21_WA_kern 06--51_gen:4752489
4 x Basic Wall:NLRS_22.21_WA_beton prefab d=200_gen:8879892 | 37 zevenendertigste verdieping | 22.21 binnenwanden - constructief, massieve wanden (Uniformat) | Model Group:NLRS_22.21_WA_kern 06--51_gen:4752489
Floor:NLRS_23.21_FL_vloer=230_gen:8879908:2 | 37 zevenendertigste verdieping | 23.21 vloeren - constructief, vrijdragende vloeren (Uniformat) | Model Group:NLRS_22.21_WA_kern 06--51_gen:4752489
4 x Basic Wall:NLRS_22.21_WA_beton prefab d=200_gen:8879945 | 38 achtendertigste verdieping | 22.21 binnenwanden - constructief, massieve wanden (Uniformat) | Model Group:NLRS_22.21_WA_kern 06--51_gen:4752921
4 x Basic Wall:NLRS_22.21_WA_beton prefab d=200_gen:8879947 | 38 achtendertigste verdieping | 22.21 binnenwanden - constructief, massieve wanden (Uniformat) | Model Group:NLRS_22.21_WA_kern 06--51_gen:4752921
4 x Basic Wall:NLRS_22.21_WA_beton prefab d=200_gen:8879949 | 38 achtendertigste verdieping | 22.21 binnenwanden - constructief, massieve wanden (Uniformat) | Model Group:NLRS_22.21_WA_kern 06--51_gen:4752921
Floor:NLRS_23.21_FL_vloer=230_gen:8879965:2 | 38 achtendertigste verdieping | 23.21 vloeren - constructief, vrijdragende vloeren (Uniformat) | Model Group:NLRS_22.21_WA_kern 06--51_gen:4752921
4 x Basic Wall:NLRS_22.21_WA_beton prefab d=200_gen:8880002 | 39 negenendertigste verdieping | 22.21 binnenwanden - constructief, massieve wanden (Uniformat) | Model Group:NLRS_22.21_WA_kern 06--51_gen:4753353
4 x Basic Wall:NLRS_22.21_WA_beton prefab d=200_gen:8880004 | 39 negenendertigste verdieping | 22.21 binnenwanden - constructief, massieve wanden (Uniformat) | Model Group:NLRS_22.21_WA_kern 06--51_gen:4753353
4 x Basic Wall:NLRS_22.21_WA_beton prefab d=200_gen:8880006 | 39 negenendertigste verdieping | 22.21 binnenwanden - constructief, massieve wanden (Uniformat) | Model Group:NLRS_22.21_WA_kern 06--51_gen:4753353
Floor:NLRS_23.21_FL_vloer=230_gen:8880022:2 | 39 negenendertigste verdieping | 23.21 vloeren - constructief, vrijdragende vloeren (Uniformat) | Model Group:NLRS_22.21_WA_kern 06--51_gen:4753353
4 x Basic Wall:NLRS_22.21_WA_beton prefab d=200_gen:8880059 | 40 veertigste verdieping | 22.21 binnenwanden - constructief, massieve wanden (Uniformat) | Model Group:NLRS_22.21_WA_kern 06--51_gen:4753785
4 x Basic Wall:NLRS_22.21_WA_beton prefab d=200_gen:8880061 | 40 veertigste verdieping | 22.21 binnenwanden - constructief, massieve wanden (Uniformat) | Model Group:NLRS_22.21_WA_kern 06--51_gen:4753785
4 x Basic Wall:NLRS_22.21_WA_beton prefab d=200_gen:8880063 | 40 veertigste verdieping | 22.21 binnenwanden - constructief, massieve wanden (Uniformat) | Model Group:NLRS_22.21_WA_kern 06--51_gen:4753785
Floor:NLRS_23.21_FL_vloer=230_gen:8880079:2 | 40 veertigste verdieping | 23.21 vloeren - constructief, vrijdragende vloeren (Uniformat) | Model Group:NLRS_22.21_WA_kern 06--51_gen:4753785
4 x Basic Wall:NLRS_22.21_WA_beton prefab d=200_gen:8880116 | 22 tweeëntwintigste verdieping | 22.21 binnenwanden - constructief, massieve wanden (Uniformat) | Model Group:NLRS_22.21_WA_kern 06--51_gen:4778253
4 x Basic Wall:NLRS_22.21_WA_beton prefab d=200_gen:8880118 | 22 tweeëntwintigste verdieping | 22.21 binnenwanden - constructief, massieve wanden (Uniformat) | Model Group:NLRS_22.21_WA_kern 06--51_gen:4778253
4 x Basic Wall:NLRS_22.21_WA_beton prefab d=200_gen:8880120 | 22 tweeëntwintigste verdieping | 22.21 binnenwanden - constructief, massieve wanden (Uniformat) | Model Group:NLRS_22.21_WA_kern 06--51_gen:4778253
Floor:NLRS_23.21_FL_vloer=230_gen:8880136:2 | 22 tweeëntwintigste verdieping | 23.21 vloeren - constructief, vrijdragende vloeren (Uniformat) | Model Group:NLRS_22.21_WA_kern 06--51_gen:4778253
4 x Basic Wall:NLRS_22.21_WA_beton prefab d=200_gen:8880173 | 23 drieëntwintigste verdieping | 22.21 binnenwanden - constructief, massieve wanden (Uniformat) | Model Group:NLRS_22.21_WA_kern 06--51_gen:4779836
4 x Basic Wall:NLRS_22.21_WA_beton prefab d=200_gen:8880175 | 23 drieëntwintigste verdieping | 22.21 binnenwanden - constructief, massieve wanden (Uniformat) | Model Group:NLRS_22.21_WA_kern 06--51_gen:4779836
4 x Basic Wall:NLRS_22.21_WA_beton prefab d=200_gen:8880177 | 23 drieëntwintigste verdieping | 22.21 binnenwanden - constructief, massieve wanden (Uniformat) | Model Group:NLRS_22.21_WA_kern 06--51_gen:4779836
Floor:NLRS_23.21_FL_vloer=230_gen:8880193:2 | 23 drieëntwintigste verdieping | 23.21 vloeren - constructief, vrijdragende vloeren (Uniformat) | Model Group:NLRS_22.21_WA_kern 06--51_gen:4779836
4 x Basic Wall:NLRS_22.21_WA_beton prefab d=200_gen:8880230 | 41 eenenveertigste verdieping | 22.21 binnenwanden - constructief, massieve wanden (Uniformat) | Model Group:NLRS_22.21_WA_kern 06--51_gen:4783953
4 x Basic Wall:NLRS_22.21_WA_beton prefab d=200_gen:8880232 | 41 eenenveertigste verdieping | 22.21 binnenwanden - constructief, massieve wanden (Uniformat) | Model Group:NLRS_22.21_WA_kern 06--51_gen:4783953
4 x Basic Wall:NLRS_22.21_WA_beton prefab d=200_gen:8880234 | 41 eenenveertigste verdieping | 22.21 binnenwanden - constructief, massieve wanden (Uniformat) | Model Group:NLRS_22.21_WA_kern 06--51_gen:4783953
Floor:NLRS_23.21_FL_vloer=230_gen:8880250:2 | 41 eenenveertigste verdieping | 23.21 vloeren - constructief, vrijdragende vloeren (Uniformat) | Model Group:NLRS_22.21_WA_kern 06--51_gen:4783953
4 x Basic Wall:NLRS_22.21_WA_beton prefab d=200_gen:8880287 | 43 drieënveertigste verdieping | 22.21 binnenwanden - constructief, massieve wanden (Uniformat) | Model Group:NLRS_22.21_WA_kern 06--51_gen:4788999
4 x Basic Wall:NLRS_22.21_WA_beton prefab d=200_gen:8880289 | 43 drieënveertigste verdieping | 22.21 binnenwanden - constructief, massieve wanden (Uniformat) | Model Group:NLRS_22.21_WA_kern 06--51_gen:4788999
4 x Basic Wall:NLRS_22.21_WA_beton prefab d=200_gen:8880291 | 43 drieënveertigste verdieping | 22.21 binnenwanden - constructief, massieve wanden (Uniformat) | Model Group:NLRS_22.21_WA_kern 06--51_gen:4788999
Floor:NLRS_23.21_FL_vloer=230_gen:8880307:2 | 43 drieënveertigste verdieping | 23.21 vloeren - constructief, vrijdragende vloeren (Uniformat) | Model Group:NLRS_22.21_WA_kern 06--51_gen:4788999
4 x Basic Wall:NLRS_22.21_WA_beton prefab d=200_gen:8880344 | 44 vierenveertigste verdieping | 22.21 binnenwanden - constructief, massieve wanden (Uniformat) | Model Group:NLRS_22.21_WA_kern 06--51_gen:4789431
4 x Basic Wall:NLRS_22.21_WA_beton prefab d=200_gen:8880346 | 44 vierenveertigste verdieping | 22.21 binnenwanden - constructief, massieve wanden (Uniformat) | Model Group:NLRS_22.21_WA_kern 06--51_gen:4789431
4 x Basic Wall:NLRS_22.21_WA_beton prefab d=200_gen:8880348 | 44 vierenveertigste verdieping | 22.21 binnenwanden - constructief, massieve wanden (Uniformat) | Model Group:NLRS_22.21_WA_kern 06--51_gen:4789431
Floor:NLRS_23.21_FL_vloer=230_gen:8880364:2 | 44 vierenveertigste verdieping | 23.21 vloeren - constructief, vrijdragende vloeren (Uniformat) | Model Group:NLRS_22.21_WA_kern 06--51_gen:4789431
4 x Basic Wall:NLRS_22.21_WA_beton prefab d=200_gen:8880401 | 45 vijfenveertigste verdieping | 22.21 binnenwanden - constructief, massieve wanden (Uniformat) | Model Group:NLRS_22.21_WA_kern 06--51_gen:4789863
4 x Basic Wall:NLRS_22.21_WA_beton prefab d=200_gen:8880403 | 45 vijfenveertigste verdieping | 22.21 binnenwanden - constructief, massieve wanden (Uniformat) | Model Group:NLRS_22.21_WA_kern 06--51_gen:4789863
4 x Basic Wall:NLRS_22.21_WA_beton prefab d=200_gen:8880405 | 45 vijfenveertigste verdieping | 22.21 binnenwanden - constructief, massieve wanden (Uniformat) | Model Group:NLRS_22.21_WA_kern 06--51_gen:4789863
Floor:NLRS_23.21_FL_vloer=230_gen:8880421:2 | 45 vijfenveertigste verdieping | 23.21 vloeren - constructief, vrijdragende vloeren (Uniformat) | Model Group:NLRS_22.21_WA_kern 06--51_gen:4789863
4 x Basic Wall:NLRS_22.21_WA_beton prefab d=200_gen:8880458 | 46 zesenveertigste verdieping | 22.21 binnenwanden - constructief, massieve wanden (Uniformat) | Model Group:NLRS_22.21_WA_kern 06--51_gen:4790295
4 x Basic Wall:NLRS_22.21_WA_beton prefab d=200_gen:8880460 | 46 zesenveertigste verdieping | 22.21 binnenwanden - constructief, massieve wanden (Uniformat) | Model Group:NLRS_22.21_WA_kern 06--51_gen:4790295
4 x Basic Wall:NLRS_22.21_WA_beton prefab d=200_gen:8880462 | 46 zesenveertigste verdieping | 22.21 binnenwanden - constructief, massieve wanden (Uniformat) | Model Group:NLRS_22.21_WA_kern 06--51_gen:4790295
Floor:NLRS_23.21_FL_vloer=230_gen:8880478:2 | 46 zesenveertigste verdieping | 23.21 vloeren - constructief, vrijdragende vloeren (Uniformat) | Model Group:NLRS_22.21_WA_kern 06--51_gen:4790295
4 x Basic Wall:NLRS_22.21_WA_beton prefab d=200_gen:8880515 | 47 zevenenveertigste verdieping | 22.21 binnenwanden - constructief, massieve wanden (Uniformat) | Model Group:NLRS_22.21_WA_kern 06--51_gen:4790727
4 x Basic Wall:NLRS_22.21_WA_beton prefab d=200_gen:8880517 | 47 zevenenveertigste verdieping | 22.21 binnenwanden - constructief, massieve wanden (Uniformat) | Model Group:NLRS_22.21_WA_kern 06--51_gen:4790727
4 x Basic Wall:NLRS_22.21_WA_beton prefab d=200_gen:8880519 | 47 zevenenveertigste verdieping | 22.21 binnenwanden - constructief, massieve wanden (Uniformat) | Model Group:NLRS_22.21_WA_kern 06--51_gen:4790727
Floor:NLRS_23.21_FL_vloer=230_gen:8880535:2 | 47 zevenenveertigste verdieping | 23.21 vloeren - constructief, vrijdragende vloeren (Uniformat) | Model Group:NLRS_22.21_WA_kern 06--51_gen:4790727
4 x Basic Wall:NLRS_22.21_WA_beton prefab d=200_gen:8880572 | 48 achtenveertigste verdieping | 22.21 binnenwanden - constructief, massieve wanden (Uniformat) | Model Group:NLRS_22.21_WA_kern 06--51_gen:4791159
4 x Basic Wall:NLRS_22.21_WA_beton prefab d=200_gen:8880574 | 48 achtenveertigste verdieping | 22.21 binnenwanden - constructief, massieve wanden (Uniformat) | Model Group:NLRS_22.21_WA_kern 06--51_gen:4791159
4 x Basic Wall:NLRS_22.21_WA_beton prefab d=200_gen:8880576 | 48 achtenveertigste verdieping | 22.21 binnenwanden - constructief, massieve wanden (Uniformat) | Model Group:NLRS_22.21_WA_kern 06--51_gen:4791159
Floor:NLRS_23.21_FL_vloer=230_gen:8880592:2 | 48 achtenveertigste verdieping | 23.21 vloeren - constructief, vrijdragende vloeren (Uniformat) | Model Group:NLRS_22.21_WA_kern 06--51_gen:4791159
4 x Basic Wall:NLRS_22.21_WA_beton prefab d=200_gen:8880629 | 49 negenenveertigste verdieping | 22.21 binnenwanden - constructief, massieve wanden (Uniformat) | Model Group:NLRS_22.21_WA_kern 06--51_gen:4791591
4 x Basic Wall:NLRS_22.21_WA_beton prefab d=200_gen:8880631 | 49 negenenveertigste verdieping | 22.21 binnenwanden - constructief, massieve wanden (Uniformat) | Model Group:NLRS_22.21_WA_kern 06--51_gen:4791591
4 x Basic Wall:NLRS_22.21_WA_beton prefab d=200_gen:8880633 | 49 negenenveertigste verdieping | 22.21 binnenwanden - constructief, massieve wanden (Uniformat) | Model Group:NLRS_22.21_WA_kern 06--51_gen:4791591
Floor:NLRS_23.21_FL_vloer=230_gen:8880649:2 | 49 negenenveertigste verdieping | 23.21 vloeren - constructief, vrijdragende vloeren (Uniformat) | Model Group:NLRS_22.21_WA_kern 06--51_gen:4791591
4 x Basic Wall:NLRS_22.21_WA_beton prefab d=200_gen:8880686 | 50 vijftigste verdieping | 22.21 binnenwanden - constructief, massieve wanden (Uniformat) | Model Group:NLRS_22.21_WA_kern 06--51_gen:4792023
4 x Basic Wall:NLRS_22.21_WA_beton prefab d=200_gen:8880688 | 50 vijftigste verdieping | 22.21 binnenwanden - constructief, massieve wanden (Uniformat) | Model Group:NLRS_22.21_WA_kern 06--51_gen:4792023
4 x Basic Wall:NLRS_22.21_WA_beton prefab d=200_gen:8880690 | 50 vijftigste verdieping | 22.21 binnenwanden - constructief, massieve wanden (Uniformat) | Model Group:NLRS_22.21_WA_kern 06--51_gen:4792023
4 x Basic Wall:NLRS_22.21_WA_beton prefab d=200_gen:8880743 | 42 tweeënveertigste verdieping | 22.21 binnenwanden - constructief, massieve wanden (Uniformat) | Model Group:NLRS_22.21_WA_kern 06--51_gen:4803472
4 x Basic Wall:NLRS_22.21_WA_beton prefab d=200_gen:8880745 | 42 tweeënveertigste verdieping | 22.21 binnenwanden - constructief, massieve wanden (Uniformat) | Model Group:NLRS_22.21_WA_kern 06--51_gen:4803472
4 x Basic Wall:NLRS_22.21_WA_beton prefab d=200_gen:8880747 | 42 tweeënveertigste verdieping | 22.21 binnenwanden - constructief, massieve wanden (Uniformat) | Model Group:NLRS_22.21_WA_kern 06--51_gen:4803472
Floor:NLRS_23.21_FL_vloer=230_gen:8880763:2 | 42 tweeënveertigste verdieping | 23.21 vloeren - constructief, vrijdragende vloeren (Uniformat) | Model Group:NLRS_22.21_WA_kern 06--51_gen:4803472
4 x Basic Wall:NLRS_22.21_WA_beton prefab d=200_gen:8880800 | 51 eenenvijftigste verdieping | 22.21 binnenwanden - constructief, massieve wanden (Uniformat) | Model Group:NLRS_22.21_WA_kern 06--51_gen:4980182
4 x Basic Wall:NLRS_22.21_WA_beton prefab d=200_gen:8880802 | 51 eenenvijftigste verdieping | 22.21 binnenwanden - constructief, massieve wanden (Uniformat) | Model Group:NLRS_22.21_WA_kern 06--51_gen:4980182
4 x Basic Wall:NLRS_22.21_WA_beton prefab d=200_gen:8880804 | 51 eenenvijftigste verdieping | 22.21 binnenwanden - constructief, massieve wanden (Uniformat) | Model Group:NLRS_22.21_WA_kern 06--51_gen:4980182
Floor:NLRS_23.21_FL_breedplaat d=100/270_gen:8986165:2 | 22 tweeëntwintigste verdieping | 23.21 vloeren - constructief, vrijdragende vloeren (Uniformat) | Model Group:NLRS_23.21_vloer voor wanden d=300/400_gen:8986172
Basic Wall:NLRS_22.21_WA_beton prefab d=400_gen:8986253 | 22 tweeëntwintigste verdieping | 22.21 binnenwanden - constructief, massieve wanden (Uniformat) | Model Group:NLRS_01.00_verdieping type G_gen:8994214
Basic Wall:NLRS_22.21_WA_beton prefab d=400_gen:8986255 | 22 tweeëntwintigste verdieping | 22.21 binnenwanden - constructief, massieve wanden (Uniformat) | Model Group:NLRS_01.00_verdieping type G_gen:8994214
2 x Basic Wall:NLRS_22.21_WA_beton prefab d=400_gen:8986257 | 22 tweeëntwintigste verdieping | 22.21 binnenwanden - constructief, massieve wanden (Uniformat) | Model Group:NLRS_01.00_verdieping type G_gen:8994214
Basic Wall:NLRS_22.21_WA_beton prefab d=300_gen:8986263 | 22 tweeëntwintigste verdieping | 22.21 binnenwanden - constructief, massieve wanden (Uniformat) | Model Group:NLRS_01.00_verdieping type G_gen:8994214
2 x Basic Wall:NLRS_22.21_WA_beton prefab d=300_gen:4472952 | 22 tweeëntwintigste verdieping | 22.21 binnenwanden - constructief, massieve wanden (Uniformat) | Model Group:NLRS_01.00_verdieping type G_gen:8994214
Basic Wall:NLRS_22.21_WA_beton prefab d=400_gen:8986266 | 22 tweeëntwintigste verdieping | 22.21 binnenwanden - constructief, massieve wanden (Uniformat) | Model Group:NLRS_01.00_verdieping type G_gen:8994214
Basic Wall:NLRS_22.21_WA_beton prefab d=400_gen:8986269 | 22 tweeëntwintigste verdieping | 22.21 binnenwanden - constructief, massieve wanden (Uniformat) | Model Group:NLRS_01.00_verdieping type G_gen:8994214
Basic Wall:NLRS_22.21_WA_beton prefab d=300_gen:8986272 | 22 tweeëntwintigste verdieping | 22.21 binnenwanden - constructief, massieve wanden (Uniformat) | Model Group:NLRS_01.00_verdieping type G_gen:8994214
Basic Wall:NLRS_22.21_WA_beton prefab d=400_gen:8986275 | 22 tweeëntwintigste verdieping | 22.21 binnenwanden - constructief, massieve wanden (Uniformat) | Model Group:NLRS_01.00_verdieping type G_gen:8994214
Basic Wall:NLRS_22.21_WA_beton prefab d=400_gen:8986278 | 22 tweeëntwintigste verdieping | 22.21 binnenwanden - constructief, massieve wanden (Uniformat) | Model Group:NLRS_01.00_verdieping type G_gen:8994214
Basic Wall:NLRS_22.21_WA_beton prefab d=400_gen:8986281 | 22 tweeëntwintigste verdieping | 22.21 binnenwanden - constructief, massieve wanden (Uniformat) | Model Group:NLRS_01.00_verdieping type G_gen:8994214
Basic Wall:NLRS_22.21_WA_beton prefab d=400_gen:8986284 | 22 tweeëntwintigste verdieping | 22.21 binnenwanden - constructief, massieve wanden (Uniformat) | Model Group:NLRS_01.00_verdieping type G_gen:8994214
2 x Basic Wall:NLRS_22.21_WA_beton prefab d=400_gen:8986288 | 22 tweeëntwintigste verdieping | 22.21 binnenwanden - constructief, massieve wanden (Uniformat) | Model Group:NLRS_01.00_verdieping type G_gen:8994214
2 x Basic Wall:NLRS_22.21_WA_beton prefab d=400_gen:4699555 | 22 tweeëntwintigste verdieping | 22.21 binnenwanden - constructief, massieve wanden (Uniformat) | Model Group:NLRS_01.00_verdieping type G_gen:8994214
2 x Basic Wall:NLRS_22.21_WA_beton prefab d=400_gen:8986291 | 22 tweeëntwintigste verdieping | 22.21 binnenwanden - constructief, massieve wanden (Uniformat) | Model Group:NLRS_01.00_verdieping type G_gen:8994214
2 x Basic Wall:NLRS_22.21_WA_beton prefab d=400_gen:8986293 | 22 tweeëntwintigste verdieping | 22.21 binnenwanden - constructief, massieve wanden (Uniformat) | Model Group:NLRS_01.00_verdieping type G_gen:8994214
Floor:NLRS_23.21_FL_breedplaat d=100/270_gen:8995929:2 | 24 vierentwintigste verdieping | 23.21 vloeren - constructief, vrijdragende vloeren (Uniformat) | Model Group:NLRS_23.21_vloer voor wanden d=300/400_gen:8995936
Basic Wall:NLRS_22.21_WA_beton prefab d=400_gen:8996017 | 24 vierentwintigste verdieping | 22.21 binnenwanden - constructief, massieve wanden (Uniformat) | Model Group:NLRS_01.00_verdieping type H_gen:4746600
Basic Wall:NLRS_22.21_WA_beton prefab d=400_gen:8996019 | 24 vierentwintigste verdieping | 22.21 binnenwanden - constructief, massieve wanden (Uniformat) | Model Group:NLRS_01.00_verdieping type H_gen:4746600
2 x Basic Wall:NLRS_22.21_WA_beton prefab d=400_gen:8996021 | 24 vierentwintigste verdieping | 22.21 binnenwanden - constructief, massieve wanden (Uniformat) | Model Group:NLRS_01.00_verdieping type H_gen:4746600
Basic Wall:NLRS_22.21_WA_beton prefab d=300_gen:8996027 | 24 vierentwintigste verdieping | 22.21 binnenwanden - constructief, massieve wanden (Uniformat) | Model Group:NLRS_01.00_verdieping type H_gen:4746600
2 x Basic Wall:NLRS_22.21_WA_beton prefab d=300_gen:4472952 | 24 vierentwintigste verdieping | 22.21 binnenwanden - constructief, massieve wanden (Uniformat) | Model Group:NLRS_01.00_verdieping type H_gen:4746600
Basic Wall:NLRS_22.21_WA_beton prefab d=400_gen:8996030 | 24 vierentwintigste verdieping | 22.21 binnenwanden - constructief, massieve wanden (Uniformat) | Model Group:NLRS_01.00_verdieping type H_gen:4746600
Basic Wall:NLRS_22.21_WA_beton prefab d=400_gen:8996033 | 24 vierentwintigste verdieping | 22.21 binnenwanden - constructief, massieve wanden (Uniformat) | Model Group:NLRS_01.00_verdieping type H_gen:4746600
Basic Wall:NLRS_22.21_WA_beton prefab d=300_gen:8996036 | 24 vierentwintigste verdieping | 22.21 binnenwanden - constructief, massieve wanden (Uniformat) | Model Group:NLRS_01.00_verdieping type H_gen:4746600
Basic Wall:NLRS_22.21_WA_beton prefab d=400_gen:8996039 | 24 vierentwintigste verdieping | 22.21 binnenwanden - constructief, massieve wanden (Uniformat) | Model Group:NLRS_01.00_verdieping type H_gen:4746600
Basic Wall:NLRS_22.21_WA_beton prefab d=400_gen:8996042 | 24 vierentwintigste verdieping | 22.21 binnenwanden - constructief, massieve wanden (Uniformat) | Model Group:NLRS_01.00_verdieping type H_gen:4746600
Basic Wall:NLRS_22.21_WA_beton prefab d=400_gen:8996045 | 24 vierentwintigste verdieping | 22.21 binnenwanden - constructief, massieve wanden (Uniformat) | Model Group:NLRS_01.00_verdieping type H_gen:4746600
Basic Wall:NLRS_22.21_WA_beton prefab d=400_gen:8996048 | 24 vierentwintigste verdieping | 22.21 binnenwanden - constructief, massieve wanden (Uniformat) | Model Group:NLRS_01.00_verdieping type H_gen:4746600
2 x Basic Wall:NLRS_22.21_WA_beton prefab d=400_gen:8996052 | 24 vierentwintigste verdieping | 22.21 binnenwanden - constructief, massieve wanden (Uniformat) | Model Group:NLRS_01.00_verdieping type H_gen:4746600
2 x Basic Wall:NLRS_22.21_WA_beton prefab d=400_gen:4699555 | 24 vierentwintigste verdieping | 22.21 binnenwanden - constructief, massieve wanden (Uniformat) | Model Group:NLRS_01.00_verdieping type H_gen:4746600
2 x Basic Wall:NLRS_22.21_WA_beton prefab d=400_gen:8996055 | 24 vierentwintigste verdieping | 22.21 binnenwanden - constructief, massieve wanden (Uniformat) | Model Group:NLRS_01.00_verdieping type H_gen:4746600
2 x Basic Wall:NLRS_22.21_WA_beton prefab d=400_gen:8996057 | 24 vierentwintigste verdieping | 22.21 binnenwanden - constructief, massieve wanden (Uniformat) | Model Group:NLRS_01.00_verdieping type H_gen:4746600
Floor:NLRS_23.21_FL_breedplaat d=100/270_gen:8996221:2 | 25 vijfentwintigste verdieping | 23.21 vloeren - constructief, vrijdragende vloeren (Uniformat) | Model Group:NLRS_23.21_vloer voor wanden d=300/400_gen:8996228
Basic Wall:NLRS_22.21_WA_beton prefab d=400_gen:8996309 | 25 vijfentwintigste verdieping | 22.21 binnenwanden - constructief, massieve wanden (Uniformat) | Model Group:NLRS_01.00_verdieping type J_gen:4747032
Basic Wall:NLRS_22.21_WA_beton prefab d=400_gen:8996311 | 25 vijfentwintigste verdieping | 22.21 binnenwanden - constructief, massieve wanden (Uniformat) | Model Group:NLRS_01.00_verdieping type J_gen:4747032
2 x Basic Wall:NLRS_22.21_WA_beton prefab d=400_gen:8996313 | 25 vijfentwintigste verdieping | 22.21 binnenwanden - constructief, massieve wanden (Uniformat) | Model Group:NLRS_01.00_verdieping type J_gen:4747032
Basic Wall:NLRS_22.21_WA_beton prefab d=300_gen:8996319 | 25 vijfentwintigste verdieping | 22.21 binnenwanden - constructief, massieve wanden (Uniformat) | Model Group:NLRS_01.00_verdieping type J_gen:4747032
2 x Basic Wall:NLRS_22.21_WA_beton prefab d=300_gen:4472952 | 25 vijfentwintigste verdieping | 22.21 binnenwanden - constructief, massieve wanden (Uniformat) | Model Group:NLRS_01.00_verdieping type J_gen:4747032
Basic Wall:NLRS_22.21_WA_beton prefab d=400_gen:8996322 | 25 vijfentwintigste verdieping | 22.21 binnenwanden - constructief, massieve wanden (Uniformat) | Model Group:NLRS_01.00_verdieping type J_gen:4747032
Basic Wall:NLRS_22.21_WA_beton prefab d=400_gen:8996325 | 25 vijfentwintigste verdieping | 22.21 binnenwanden - constructief, massieve wanden (Uniformat) | Model Group:NLRS_01.00_verdieping type J_gen:4747032
Basic Wall:NLRS_22.21_WA_beton prefab d=300_gen:8996328 | 25 vijfentwintigste verdieping | 22.21 binnenwanden - constructief, massieve wanden (Uniformat) | Model Group:NLRS_01.00_verdieping type J_gen:4747032
Basic Wall:NLRS_22.21_WA_beton prefab d=400_gen:8996331 | 25 vijfentwintigste verdieping | 22.21 binnenwanden - constructief, massieve wanden (Uniformat) | Model Group:NLRS_01.00_verdieping type J_gen:4747032
Basic Wall:NLRS_22.21_WA_beton prefab d=400_gen:8996334 | 25 vijfentwintigste verdieping | 22.21 binnenwanden - constructief, massieve wanden (Uniformat) | Model Group:NLRS_01.00_verdieping type J_gen:4747032
Basic Wall:NLRS_22.21_WA_beton prefab d=400_gen:8996337 | 25 vijfentwintigste verdieping | 22.21 binnenwanden - constructief, massieve wanden (Uniformat) | Model Group:NLRS_01.00_verdieping type J_gen:4747032
Basic Wall:NLRS_22.21_WA_beton prefab d=400_gen:8996340 | 25 vijfentwintigste verdieping | 22.21 binnenwanden - constructief, massieve wanden (Uniformat) | Model Group:NLRS_01.00_verdieping type J_gen:4747032
2 x Basic Wall:NLRS_22.21_WA_beton prefab d=400_gen:8996344 | 25 vijfentwintigste verdieping | 22.21 binnenwanden - constructief, massieve wanden (Uniformat) | Model Group:NLRS_01.00_verdieping type J_gen:4747032
2 x Basic Wall:NLRS_22.21_WA_beton prefab d=400_gen:4699555 | 25 vijfentwintigste verdieping | 22.21 binnenwanden - constructief, massieve wanden (Uniformat) | Model Group:NLRS_01.00_verdieping type J_gen:4747032
2 x Basic Wall:NLRS_22.21_WA_beton prefab d=400_gen:8996347 | 25 vijfentwintigste verdieping | 22.21 binnenwanden - constructief, massieve wanden (Uniformat) | Model Group:NLRS_01.00_verdieping type J_gen:4747032
2 x Basic Wall:NLRS_22.21_WA_beton prefab d=400_gen:8996349 | 25 vijfentwintigste verdieping | 22.21 binnenwanden - constructief, massieve wanden (Uniformat) | Model Group:NLRS_01.00_verdieping type J_gen:4747032
Floor:NLRS_23.21_FL_breedplaat d=100/270_gen:8996513:2 | 26 zesentwintigste verdieping | 23.21 vloeren - constructief, vrijdragende vloeren (Uniformat) | Model Group:NLRS_23.21_vloer voor wanden d=300/400_gen:8996520
Basic Wall:NLRS_22.21_WA_beton prefab d=400_gen:8996601 | 26 zesentwintigste verdieping | 22.21 binnenwanden - constructief, massieve wanden (Uniformat) | Model Group:NLRS_01.00_verdieping type K_gen:4747464
Basic Wall:NLRS_22.21_WA_beton prefab d=400_gen:8996603 | 26 zesentwintigste verdieping | 22.21 binnenwanden - constructief, massieve wanden (Uniformat) | Model Group:NLRS_01.00_verdieping type K_gen:4747464
2 x Basic Wall:NLRS_22.21_WA_beton prefab d=400_gen:8996605 | 26 zesentwintigste verdieping | 22.21 binnenwanden - constructief, massieve wanden (Uniformat) | Model Group:NLRS_01.00_verdieping type K_gen:4747464
Basic Wall:NLRS_22.21_WA_beton prefab d=300_gen:8996611 | 26 zesentwintigste verdieping | 22.21 binnenwanden - constructief, massieve wanden (Uniformat) | Model Group:NLRS_01.00_verdieping type K_gen:4747464
2 x Basic Wall:NLRS_22.21_WA_beton prefab d=300_gen:4472952 | 26 zesentwintigste verdieping | 22.21 binnenwanden - constructief, massieve wanden (Uniformat) | Model Group:NLRS_01.00_verdieping type K_gen:4747464
Basic Wall:NLRS_22.21_WA_beton prefab d=400_gen:8996614 | 26 zesentwintigste verdieping | 22.21 binnenwanden - constructief, massieve wanden (Uniformat) | Model Group:NLRS_01.00_verdieping type K_gen:4747464
Basic Wall:NLRS_22.21_WA_beton prefab d=400_gen:8996617 | 26 zesentwintigste verdieping | 22.21 binnenwanden - constructief, massieve wanden (Uniformat) | Model Group:NLRS_01.00_verdieping type K_gen:4747464
Basic Wall:NLRS_22.21_WA_beton prefab d=300_gen:8996620 | 26 zesentwintigste verdieping | 22.21 binnenwanden - constructief, massieve wanden (Uniformat) | Model Group:NLRS_01.00_verdieping type K_gen:4747464
Basic Wall:NLRS_22.21_WA_beton prefab d=400_gen:8996623 | 26 zesentwintigste verdieping | 22.21 binnenwanden - constructief, massieve wanden (Uniformat) | Model Group:NLRS_01.00_verdieping type K_gen:4747464
Basic Wall:NLRS_22.21_WA_beton prefab d=400_gen:8996626 | 26 zesentwintigste verdieping | 22.21 binnenwanden - constructief, massieve wanden (Uniformat) | Model Group:NLRS_01.00_verdieping type K_gen:4747464
Basic Wall:NLRS_22.21_WA_beton prefab d=400_gen:8996629 | 26 zesentwintigste verdieping | 22.21 binnenwanden - constructief, massieve wanden (Uniformat) | Model Group:NLRS_01.00_verdieping type K_gen:4747464
Basic Wall:NLRS_22.21_WA_beton prefab d=400_gen:8996632 | 26 zesentwintigste verdieping | 22.21 binnenwanden - constructief, massieve wanden (Uniformat) | Model Group:NLRS_01.00_verdieping type K_gen:4747464
2 x Basic Wall:NLRS_22.21_WA_beton prefab d=400_gen:8996636 | 26 zesentwintigste verdieping | 22.21 binnenwanden - constructief, massieve wanden (Uniformat) | Model Group:NLRS_01.00_verdieping type K_gen:4747464
2 x Basic Wall:NLRS_22.21_WA_beton prefab d=400_gen:4699555 | 26 zesentwintigste verdieping | 22.21 binnenwanden - constructief, massieve wanden (Uniformat) | Model Group:NLRS_01.00_verdieping type K_gen:4747464
2 x Basic Wall:NLRS_22.21_WA_beton prefab d=400_gen:8996639 | 26 zesentwintigste verdieping | 22.21 binnenwanden - constructief, massieve wanden (Uniformat) | Model Group:NLRS_01.00_verdieping type K_gen:4747464
2 x Basic Wall:NLRS_22.21_WA_beton prefab d=400_gen:8996641 | 26 zesentwintigste verdieping | 22.21 binnenwanden - constructief, massieve wanden (Uniformat) | Model Group:NLRS_01.00_verdieping type K_gen:4747464
Floor:NLRS_23.21_FL_breedplaat d=100/270_gen:8997681:2 | 30 dertigste verdieping | 23.21 vloeren - constructief, vrijdragende vloeren (Uniformat) | Model Group:NLRS_23.21_vloer voor wanden d=300/400_gen:8997688
Basic Wall:NLRS_22.21_WA_beton prefab d=400_gen:8997769 | 30 dertigste verdieping | 22.21 binnenwanden - constructief, massieve wanden (Uniformat) | Model Group:NLRS_01.00_verdieping (type L)_gen:4749192
Basic Wall:NLRS_22.21_WA_beton prefab d=400_gen:8997771 | 30 dertigste verdieping | 22.21 binnenwanden - constructief, massieve wanden (Uniformat) | Model Group:NLRS_01.00_verdieping (type L)_gen:4749192
2 x Basic Wall:NLRS_22.21_WA_beton prefab d=400_gen:8997773 | 30 dertigste verdieping | 22.21 binnenwanden - constructief, massieve wanden (Uniformat) | Model Group:NLRS_01.00_verdieping (type L)_gen:4749192
Basic Wall:NLRS_22.21_WA_beton prefab d=300_gen:8997779 | 30 dertigste verdieping | 22.21 binnenwanden - constructief, massieve wanden (Uniformat) | Model Group:NLRS_01.00_verdieping (type L)_gen:4749192
2 x Basic Wall:NLRS_22.21_WA_beton prefab d=300_gen:4472952 | 30 dertigste verdieping | 22.21 binnenwanden - constructief, massieve wanden (Uniformat) | Model Group:NLRS_01.00_verdieping (type L)_gen:4749192
Basic Wall:NLRS_22.21_WA_beton prefab d=400_gen:8997782 | 30 dertigste verdieping | 22.21 binnenwanden - constructief, massieve wanden (Uniformat) | Model Group:NLRS_01.00_verdieping (type L)_gen:4749192
Basic Wall:NLRS_22.21_WA_beton prefab d=400_gen:8997785 | 30 dertigste verdieping | 22.21 binnenwanden - constructief, massieve wanden (Uniformat) | Model Group:NLRS_01.00_verdieping (type L)_gen:4749192
Basic Wall:NLRS_22.21_WA_beton prefab d=300_gen:8997788 | 30 dertigste verdieping | 22.21 binnenwanden - constructief, massieve wanden (Uniformat) | Model Group:NLRS_01.00_verdieping (type L)_gen:4749192
Basic Wall:NLRS_22.21_WA_beton prefab d=400_gen:8997791 | 30 dertigste verdieping | 22.21 binnenwanden - constructief, massieve wanden (Uniformat) | Model Group:NLRS_01.00_verdieping (type L)_gen:4749192
Basic Wall:NLRS_22.21_WA_beton prefab d=400_gen:8997794 | 30 dertigste verdieping | 22.21 binnenwanden - constructief, massieve wanden (Uniformat) | Model Group:NLRS_01.00_verdieping (type L)_gen:4749192
Basic Wall:NLRS_22.21_WA_beton prefab d=400_gen:8997797 | 30 dertigste verdieping | 22.21 binnenwanden - constructief, massieve wanden (Uniformat) | Model Group:NLRS_01.00_verdieping (type L)_gen:4749192
Basic Wall:NLRS_22.21_WA_beton prefab d=400_gen:8997800 | 30 dertigste verdieping | 22.21 binnenwanden - constructief, massieve wanden (Uniformat) | Model Group:NLRS_01.00_verdieping (type L)_gen:4749192
2 x Basic Wall:NLRS_22.21_WA_beton prefab d=400_gen:8997804 | 30 dertigste verdieping | 22.21 binnenwanden - constructief, massieve wanden (Uniformat) | Model Group:NLRS_01.00_verdieping (type L)_gen:4749192
2 x Basic Wall:NLRS_22.21_WA_beton prefab d=400_gen:4699555 | 30 dertigste verdieping | 22.21 binnenwanden - constructief, massieve wanden (Uniformat) | Model Group:NLRS_01.00_verdieping (type L)_gen:4749192
2 x Basic Wall:NLRS_22.21_WA_beton prefab d=400_gen:8997807 | 30 dertigste verdieping | 22.21 binnenwanden - constructief, massieve wanden (Uniformat) | Model Group:NLRS_01.00_verdieping (type L)_gen:4749192
2 x Basic Wall:NLRS_22.21_WA_beton prefab d=400_gen:8997809 | 30 dertigste verdieping | 22.21 binnenwanden - constructief, massieve wanden (Uniformat) | Model Group:NLRS_01.00_verdieping (type L)_gen:4749192
Basic Wall:NLRS_22.21_WA_beton prefab d=300_gen:9028064 | 47 zevenenveertigste verdieping | 22.21 binnenwanden - constructief, massieve wanden (Uniformat) | Model Group:NLRS_01.00_verdieping type O_gen:4790454
Basic Wall:NLRS_22.21_WA_beton prefab d=300_gen:9028066 | 47 zevenenveertigste verdieping | 22.21 binnenwanden - constructief, massieve wanden (Uniformat) | Model Group:NLRS_01.00_verdieping type O_gen:4790454
2 x Basic Wall:NLRS_22.21_WA_beton prefab d=300_gen:9028068 | 47 zevenenveertigste verdieping | 22.21 binnenwanden - constructief, massieve wanden (Uniformat) | Model Group:NLRS_01.00_verdieping type O_gen:4790454
Basic Wall:NLRS_22.21_WA_beton prefab d=300_gen:9028074 | 47 zevenenveertigste verdieping | 22.21 binnenwanden - constructief, massieve wanden (Uniformat) | Model Group:NLRS_01.00_verdieping type O_gen:4790454
4 x Basic Wall:NLRS_22.21_WA_beton prefab d=300_gen:4472952 | 47 zevenenveertigste verdieping | 22.21 binnenwanden - constructief, massieve wanden (Uniformat) | Model Group:NLRS_01.00_verdieping type O_gen:4790454
Basic Wall:NLRS_22.21_WA_beton prefab d=300_gen:9028077 | 47 zevenenveertigste verdieping | 22.21 binnenwanden - constructief, massieve wanden (Uniformat) | Model Group:NLRS_01.00_verdieping type O_gen:4790454
Basic Wall:NLRS_22.21_WA_beton prefab d=300_gen:9028080 | 47 zevenenveertigste verdieping | 22.21 binnenwanden - constructief, massieve wanden (Uniformat) | Model Group:NLRS_01.00_verdieping type O_gen:4790454
Basic Wall:NLRS_22.21_WA_beton prefab d=300_gen:9028083 | 47 zevenenveertigste verdieping | 22.21 binnenwanden - constructief, massieve wanden (Uniformat) | Model Group:NLRS_01.00_verdieping type O_gen:4790454
Basic Wall:NLRS_22.21_WA_beton prefab d=300_gen:9028086 | 47 zevenenveertigste verdieping | 22.21 binnenwanden - constructief, massieve wanden (Uniformat) | Model Group:NLRS_01.00_verdieping type O_gen:4790454
Basic Wall:NLRS_22.21_WA_beton prefab d=300_gen:9028089 | 47 zevenenveertigste verdieping | 22.21 binnenwanden - constructief, massieve wanden (Uniformat) | Model Group:NLRS_01.00_verdieping type O_gen:4790454
Basic Wall:NLRS_22.21_WA_beton prefab d=300_gen:9028092 | 47 zevenenveertigste verdieping | 22.21 binnenwanden - constructief, massieve wanden (Uniformat) | Model Group:NLRS_01.00_verdieping type O_gen:4790454
Basic Wall:NLRS_22.21_WA_beton prefab d=300_gen:9028095 | 47 zevenenveertigste verdieping | 22.21 binnenwanden - constructief, massieve wanden (Uniformat) | Model Group:NLRS_01.00_verdieping type O_gen:4790454
2 x Basic Wall:NLRS_22.21_WA_beton prefab d=300_gen:9028099 | 47 zevenenveertigste verdieping | 22.21 binnenwanden - constructief, massieve wanden (Uniformat) | Model Group:NLRS_01.00_verdieping type O_gen:4790454
2 x Basic Wall:NLRS_22.21_WA_beton prefab d=300_gen:9028102 | 47 zevenenveertigste verdieping | 22.21 binnenwanden - constructief, massieve wanden (Uniformat) | Model Group:NLRS_01.00_verdieping type O_gen:4790454
2 x Basic Wall:NLRS_22.21_WA_beton prefab d=300_gen:9028104 | 47 zevenenveertigste verdieping | 22.21 binnenwanden - constructief, massieve wanden (Uniformat) | Model Group:NLRS_01.00_verdieping type O_gen:4790454
Floor:NLRS_23.21_FL_vloer d=270_gen:9028227:2 | 47 zevenenveertigste verdieping | 23.21 vloeren - constructief, vrijdragende vloeren (Uniformat) | Model Group:NLRS_23.21_vloer voor wanden d=300/300_gen:9028234
Basic Wall:NLRS_22.21_WA_beton prefab d=300_gen:9028940 | 50 vijftigste verdieping | 22.21 binnenwanden - constructief, massieve wanden (Uniformat) | Model Group:NLRS_01.00_verdieping type P_gen:4791750
Basic Wall:NLRS_22.21_WA_beton prefab d=300_gen:9028942 | 50 vijftigste verdieping | 22.21 binnenwanden - constructief, massieve wanden (Uniformat) | Model Group:NLRS_01.00_verdieping type P_gen:4791750
2 x Basic Wall:NLRS_22.21_WA_beton prefab d=300_gen:9028944 | 50 vijftigste verdieping | 22.21 binnenwanden - constructief, massieve wanden (Uniformat) | Model Group:NLRS_01.00_verdieping type P_gen:4791750
Basic Wall:NLRS_22.21_WA_beton prefab d=300_gen:9028950 | 50 vijftigste verdieping | 22.21 binnenwanden - constructief, massieve wanden (Uniformat) | Model Group:NLRS_01.00_verdieping type P_gen:4791750
4 x Basic Wall:NLRS_22.21_WA_beton prefab d=300_gen:4472952 | 50 vijftigste verdieping | 22.21 binnenwanden - constructief, massieve wanden (Uniformat) | Model Group:NLRS_01.00_verdieping type P_gen:4791750
Basic Wall:NLRS_22.21_WA_beton prefab d=300_gen:9028953 | 50 vijftigste verdieping | 22.21 binnenwanden - constructief, massieve wanden (Uniformat) | Model Group:NLRS_01.00_verdieping type P_gen:4791750
Basic Wall:NLRS_22.21_WA_beton prefab d=300_gen:9028956 | 50 vijftigste verdieping | 22.21 binnenwanden - constructief, massieve wanden (Uniformat) | Model Group:NLRS_01.00_verdieping type P_gen:4791750
Basic Wall:NLRS_22.21_WA_beton prefab d=300_gen:9028959 | 50 vijftigste verdieping | 22.21 binnenwanden - constructief, massieve wanden (Uniformat) | Model Group:NLRS_01.00_verdieping type P_gen:4791750
Basic Wall:NLRS_22.21_WA_beton prefab d=300_gen:9028962 | 50 vijftigste verdieping | 22.21 binnenwanden - constructief, massieve wanden (Uniformat) | Model Group:NLRS_01.00_verdieping type P_gen:4791750
Basic Wall:NLRS_22.21_WA_beton prefab d=300_gen:9028965 | 50 vijftigste verdieping | 22.21 binnenwanden - constructief, massieve wanden (Uniformat) | Model Group:NLRS_01.00_verdieping type P_gen:4791750
Basic Wall:NLRS_22.21_WA_beton prefab d=300_gen:9028968 | 50 vijftigste verdieping | 22.21 binnenwanden - constructief, massieve wanden (Uniformat) | Model Group:NLRS_01.00_verdieping type P_gen:4791750
Basic Wall:NLRS_22.21_WA_beton prefab d=300_gen:9028971 | 50 vijftigste verdieping | 22.21 binnenwanden - constructief, massieve wanden (Uniformat) | Model Group:NLRS_01.00_verdieping type P_gen:4791750
2 x Basic Wall:NLRS_22.21_WA_beton prefab d=300_gen:9028975 | 50 vijftigste verdieping | 22.21 binnenwanden - constructief, massieve wanden (Uniformat) | Model Group:NLRS_01.00_verdieping type P_gen:4791750
2 x Basic Wall:NLRS_22.21_WA_beton prefab d=300_gen:9028978 | 50 vijftigste verdieping | 22.21 binnenwanden - constructief, massieve wanden (Uniformat) | Model Group:NLRS_01.00_verdieping type P_gen:4791750
2 x Basic Wall:NLRS_22.21_WA_beton prefab d=300_gen:9028980 | 50 vijftigste verdieping | 22.21 binnenwanden - constructief, massieve wanden (Uniformat) | Model Group:NLRS_01.00_verdieping type P_gen:4791750
2 x Basic Wall:NLRS_22.21_WA_beton prefab d=500_gen:9036735 | 16 zestiende verdieping | 22.21 binnenwanden - constructief, massieve wanden (Uniformat) | Model Group:NLRS_01.00_verdieping type E_gen:4739081
Basic Wall:NLRS_22.21_WA_beton prefab d=500_gen:9036737 | 16 zestiende verdieping | 22.21 binnenwanden - constructief, massieve wanden (Uniformat) | Model Group:NLRS_01.00_verdieping type E_gen:4739081
Basic Wall:NLRS_22.21_WA_beton prefab d=500_gen:9036739 | 16 zestiende verdieping | 22.21 binnenwanden - constructief, massieve wanden (Uniformat) | Model Group:NLRS_01.00_verdieping type E_gen:4739081
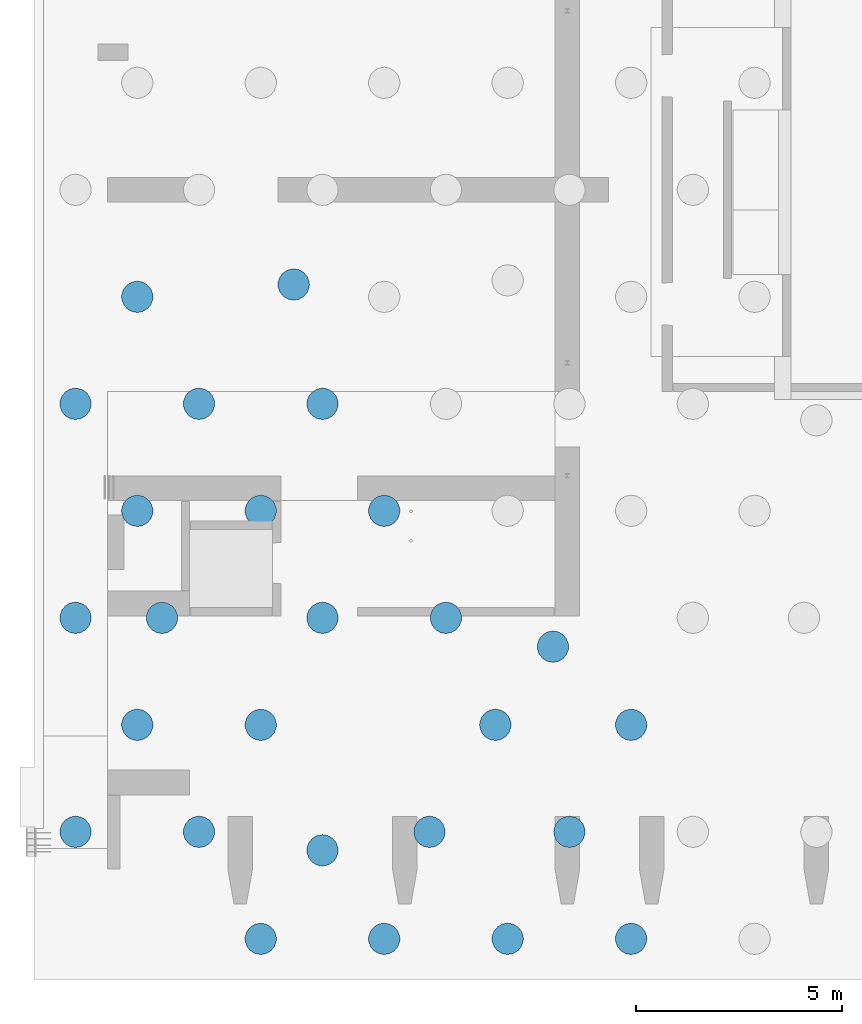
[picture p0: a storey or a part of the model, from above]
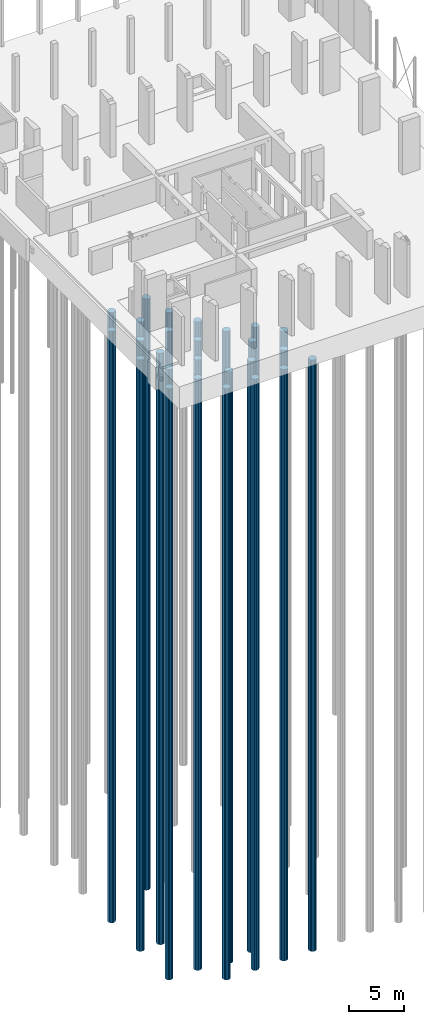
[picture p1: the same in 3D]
Properties of the parts of a building model (IFC2X3), part 13 of 21

# IfcOpeningElement: Opening (5659)
Name | In | Classification | Group
2 x Basic Wall:NLRS_22.21_WA_beton prefab d=500_gen:9036741 | 16 zestiende verdieping | 22.21 binnenwanden - constructief, massieve wanden (Uniformat) | Model Group:NLRS_01.00_verdieping type E_gen:4739081
Basic Wall:NLRS_22.21_WA_beton prefab d=300_gen:9036748 | 16 zestiende verdieping | 22.21 binnenwanden - constructief, massieve wanden (Uniformat) | Model Group:NLRS_01.00_verdieping type E_gen:4739081
2 x Basic Wall:NLRS_22.21_WA_beton prefab d=300_gen:4472952 | 16 zestiende verdieping | 22.21 binnenwanden - constructief, massieve wanden (Uniformat) | Model Group:NLRS_01.00_verdieping type E_gen:4739081
Basic Wall:NLRS_22.21_WA_beton prefab d=500_gen:9036751 | 16 zestiende verdieping | 22.21 binnenwanden - constructief, massieve wanden (Uniformat) | Model Group:NLRS_01.00_verdieping type E_gen:4739081
Basic Wall:NLRS_22.21_WA_beton prefab d=500_gen:9036754 | 16 zestiende verdieping | 22.21 binnenwanden - constructief, massieve wanden (Uniformat) | Model Group:NLRS_01.00_verdieping type E_gen:4739081
Basic Wall:NLRS_22.21_WA_beton prefab d=300_gen:9036757 | 16 zestiende verdieping | 22.21 binnenwanden - constructief, massieve wanden (Uniformat) | Model Group:NLRS_01.00_verdieping type E_gen:4739081
Basic Wall:NLRS_22.21_WA_beton prefab d=500_gen:9036760 | 16 zestiende verdieping | 22.21 binnenwanden - constructief, massieve wanden (Uniformat) | Model Group:NLRS_01.00_verdieping type E_gen:4739081
Basic Wall:NLRS_22.21_WA_beton prefab d=500_gen:9036763 | 16 zestiende verdieping | 22.21 binnenwanden - constructief, massieve wanden (Uniformat) | Model Group:NLRS_01.00_verdieping type E_gen:4739081
Basic Wall:NLRS_22.21_WA_beton prefab d=500_gen:9036766 | 16 zestiende verdieping | 22.21 binnenwanden - constructief, massieve wanden (Uniformat) | Model Group:NLRS_01.00_verdieping type E_gen:4739081
Basic Wall:NLRS_22.21_WA_beton prefab d=500_gen:9036769 | 16 zestiende verdieping | 22.21 binnenwanden - constructief, massieve wanden (Uniformat) | Model Group:NLRS_01.00_verdieping type E_gen:4739081
Basic Wall:NLRS_22.21_WA_beton prefab d=500_gen:9036772 | 16 zestiende verdieping | 22.21 binnenwanden - constructief, massieve wanden (Uniformat) | Model Group:NLRS_01.00_verdieping type E_gen:4739081
Basic Wall:NLRS_22.21_WA_beton prefab d=500_gen:9036775 | 16 zestiende verdieping | 22.21 binnenwanden - constructief, massieve wanden (Uniformat) | Model Group:NLRS_01.00_verdieping type E_gen:4739081
Basic Wall:NLRS_22.21_WA_beton prefab d=500_gen:9036779 | 16 zestiende verdieping | 22.21 binnenwanden - constructief, massieve wanden (Uniformat) | Model Group:NLRS_01.00_verdieping type E_gen:4739081
2 x Basic Wall:NLRS_22.21_WA_beton prefab d=500_gen:4472769 | 16 zestiende verdieping | 22.21 binnenwanden - constructief, massieve wanden (Uniformat) | Model Group:NLRS_01.00_verdieping type E_gen:4739081
Basic Wall:NLRS_22.21_WA_beton prefab d=500_gen:9036782 | 16 zestiende verdieping | 22.21 binnenwanden - constructief, massieve wanden (Uniformat) | Model Group:NLRS_01.00_verdieping type E_gen:4739081
Floor:NLRS_23.21_FL_breedplaat d=100/270_gen:9036931:2 | 16 zestiende verdieping | 23.21 vloeren - constructief, vrijdragende vloeren (Uniformat) | Model Group:NLRS_23.21_vloer voor wanden d=300/500_gen:9036938
2 x Basic Wall:NLRS_22.21_WA_beton prefab d=500_gen:9050655 | 15 vijftiende verdieping | 22.21 binnenwanden - constructief, massieve wanden (Uniformat) | Model Group:NLRS_01.00_verdieping type D_gen:4731036
Basic Wall:NLRS_22.21_WA_beton prefab d=500_gen:9050657 | 15 vijftiende verdieping | 22.21 binnenwanden - constructief, massieve wanden (Uniformat) | Model Group:NLRS_01.00_verdieping type D_gen:4731036
Basic Wall:NLRS_22.21_WA_beton prefab d=500_gen:9050659 | 15 vijftiende verdieping | 22.21 binnenwanden - constructief, massieve wanden (Uniformat) | Model Group:NLRS_01.00_verdieping type D_gen:4731036
2 x Basic Wall:NLRS_22.21_WA_beton prefab d=500_gen:9050661 | 15 vijftiende verdieping | 22.21 binnenwanden - constructief, massieve wanden (Uniformat) | Model Group:NLRS_01.00_verdieping type D_gen:4731036
Basic Wall:NLRS_22.21_WA_beton prefab d=300_gen:9050668 | 15 vijftiende verdieping | 22.21 binnenwanden - constructief, massieve wanden (Uniformat) | Model Group:NLRS_01.00_verdieping type D_gen:4731036
2 x Basic Wall:NLRS_22.21_WA_beton prefab d=300_gen:4472952 | 15 vijftiende verdieping | 22.21 binnenwanden - constructief, massieve wanden (Uniformat) | Model Group:NLRS_01.00_verdieping type D_gen:4731036
Basic Wall:NLRS_22.21_WA_beton prefab d=500_gen:9050671 | 15 vijftiende verdieping | 22.21 binnenwanden - constructief, massieve wanden (Uniformat) | Model Group:NLRS_01.00_verdieping type D_gen:4731036
Basic Wall:NLRS_22.21_WA_beton prefab d=500_gen:9050674 | 15 vijftiende verdieping | 22.21 binnenwanden - constructief, massieve wanden (Uniformat) | Model Group:NLRS_01.00_verdieping type D_gen:4731036
Basic Wall:NLRS_22.21_WA_beton prefab d=300_gen:9050677 | 15 vijftiende verdieping | 22.21 binnenwanden - constructief, massieve wanden (Uniformat) | Model Group:NLRS_01.00_verdieping type D_gen:4731036
Basic Wall:NLRS_22.21_WA_beton prefab d=500_gen:9050680 | 15 vijftiende verdieping | 22.21 binnenwanden - constructief, massieve wanden (Uniformat) | Model Group:NLRS_01.00_verdieping type D_gen:4731036
Basic Wall:NLRS_22.21_WA_beton prefab d=500_gen:9050683 | 15 vijftiende verdieping | 22.21 binnenwanden - constructief, massieve wanden (Uniformat) | Model Group:NLRS_01.00_verdieping type D_gen:4731036
Basic Wall:NLRS_22.21_WA_beton prefab d=500_gen:9050686 | 15 vijftiende verdieping | 22.21 binnenwanden - constructief, massieve wanden (Uniformat) | Model Group:NLRS_01.00_verdieping type D_gen:4731036
Basic Wall:NLRS_22.21_WA_beton prefab d=500_gen:9050689 | 15 vijftiende verdieping | 22.21 binnenwanden - constructief, massieve wanden (Uniformat) | Model Group:NLRS_01.00_verdieping type D_gen:4731036
Basic Wall:NLRS_22.21_WA_beton prefab d=500_gen:9050693 | 15 vijftiende verdieping | 22.21 binnenwanden - constructief, massieve wanden (Uniformat) | Model Group:NLRS_01.00_verdieping type D_gen:4731036
Basic Wall:NLRS_22.21_WA_beton prefab d=500_gen:9050696 | 15 vijftiende verdieping | 22.21 binnenwanden - constructief, massieve wanden (Uniformat) | Model Group:NLRS_01.00_verdieping type D_gen:4731036
Basic Wall:NLRS_22.21_WA_beton prefab d=500_gen:9050698 | 15 vijftiende verdieping | 22.21 binnenwanden - constructief, massieve wanden (Uniformat) | Model Group:NLRS_01.00_verdieping type D_gen:4731036
2 x Basic Wall:NLRS_22.21_WA_beton prefab d=500_gen:4472769 | 15 vijftiende verdieping | 22.21 binnenwanden - constructief, massieve wanden (Uniformat) | Model Group:NLRS_01.00_verdieping type D_gen:4731036
Basic Wall:NLRS_22.21_WA_beton prefab d=500_gen:9050701 | 15 vijftiende verdieping | 22.21 binnenwanden - constructief, massieve wanden (Uniformat) | Model Group:NLRS_01.00_verdieping type D_gen:4731036
Floor:NLRS_23.21_FL_breedplaat d=100/270_gen:9050849:2 | 15 vijftiende verdieping | 23.21 vloeren - constructief, vrijdragende vloeren (Uniformat) | Model Group:NLRS_23.21_vloer voor wanden d=300/500_gen:9050856
2 x Basic Wall:NLRS_22.21_WA_beton prefab d=500_gen:9050951 | 17 zeventiende verdieping | 22.21 binnenwanden - constructief, massieve wanden (Uniformat) | Model Group:NLRS_01.00_verdieping type D_gen:4731494
Basic Wall:NLRS_22.21_WA_beton prefab d=500_gen:9050953 | 17 zeventiende verdieping | 22.21 binnenwanden - constructief, massieve wanden (Uniformat) | Model Group:NLRS_01.00_verdieping type D_gen:4731494
Basic Wall:NLRS_22.21_WA_beton prefab d=500_gen:9050955 | 17 zeventiende verdieping | 22.21 binnenwanden - constructief, massieve wanden (Uniformat) | Model Group:NLRS_01.00_verdieping type D_gen:4731494
2 x Basic Wall:NLRS_22.21_WA_beton prefab d=500_gen:9050957 | 17 zeventiende verdieping | 22.21 binnenwanden - constructief, massieve wanden (Uniformat) | Model Group:NLRS_01.00_verdieping type D_gen:4731494
Basic Wall:NLRS_22.21_WA_beton prefab d=300_gen:9050964 | 17 zeventiende verdieping | 22.21 binnenwanden - constructief, massieve wanden (Uniformat) | Model Group:NLRS_01.00_verdieping type D_gen:4731494
2 x Basic Wall:NLRS_22.21_WA_beton prefab d=300_gen:4472952 | 17 zeventiende verdieping | 22.21 binnenwanden - constructief, massieve wanden (Uniformat) | Model Group:NLRS_01.00_verdieping type D_gen:4731494
Basic Wall:NLRS_22.21_WA_beton prefab d=500_gen:9050967 | 17 zeventiende verdieping | 22.21 binnenwanden - constructief, massieve wanden (Uniformat) | Model Group:NLRS_01.00_verdieping type D_gen:4731494
Basic Wall:NLRS_22.21_WA_beton prefab d=500_gen:9050970 | 17 zeventiende verdieping | 22.21 binnenwanden - constructief, massieve wanden (Uniformat) | Model Group:NLRS_01.00_verdieping type D_gen:4731494
Basic Wall:NLRS_22.21_WA_beton prefab d=300_gen:9050973 | 17 zeventiende verdieping | 22.21 binnenwanden - constructief, massieve wanden (Uniformat) | Model Group:NLRS_01.00_verdieping type D_gen:4731494
Basic Wall:NLRS_22.21_WA_beton prefab d=500_gen:9050976 | 17 zeventiende verdieping | 22.21 binnenwanden - constructief, massieve wanden (Uniformat) | Model Group:NLRS_01.00_verdieping type D_gen:4731494
Basic Wall:NLRS_22.21_WA_beton prefab d=500_gen:9050979 | 17 zeventiende verdieping | 22.21 binnenwanden - constructief, massieve wanden (Uniformat) | Model Group:NLRS_01.00_verdieping type D_gen:4731494
Basic Wall:NLRS_22.21_WA_beton prefab d=500_gen:9050982 | 17 zeventiende verdieping | 22.21 binnenwanden - constructief, massieve wanden (Uniformat) | Model Group:NLRS_01.00_verdieping type D_gen:4731494
Basic Wall:NLRS_22.21_WA_beton prefab d=500_gen:9050985 | 17 zeventiende verdieping | 22.21 binnenwanden - constructief, massieve wanden (Uniformat) | Model Group:NLRS_01.00_verdieping type D_gen:4731494
Basic Wall:NLRS_22.21_WA_beton prefab d=500_gen:9050989 | 17 zeventiende verdieping | 22.21 binnenwanden - constructief, massieve wanden (Uniformat) | Model Group:NLRS_01.00_verdieping type D_gen:4731494
Basic Wall:NLRS_22.21_WA_beton prefab d=500_gen:9050992 | 17 zeventiende verdieping | 22.21 binnenwanden - constructief, massieve wanden (Uniformat) | Model Group:NLRS_01.00_verdieping type D_gen:4731494
Basic Wall:NLRS_22.21_WA_beton prefab d=500_gen:9050994 | 17 zeventiende verdieping | 22.21 binnenwanden - constructief, massieve wanden (Uniformat) | Model Group:NLRS_01.00_verdieping type D_gen:4731494
2 x Basic Wall:NLRS_22.21_WA_beton prefab d=500_gen:4472769 | 17 zeventiende verdieping | 22.21 binnenwanden - constructief, massieve wanden (Uniformat) | Model Group:NLRS_01.00_verdieping type D_gen:4731494
Basic Wall:NLRS_22.21_WA_beton prefab d=500_gen:9050997 | 17 zeventiende verdieping | 22.21 binnenwanden - constructief, massieve wanden (Uniformat) | Model Group:NLRS_01.00_verdieping type D_gen:4731494
Floor:NLRS_23.21_FL_breedplaat d=100/270_gen:9051145:2 | 17 zeventiende verdieping | 23.21 vloeren - constructief, vrijdragende vloeren (Uniformat) | Model Group:NLRS_23.21_vloer voor wanden d=300/500_gen:9051152
2 x Basic Wall:NLRS_22.21_WA_beton prefab d=500_gen:9090923 | 07 zevende verdieping | 22.21 binnenwanden - constructief, massieve wanden (Uniformat) | Model Group:NLRS_01.00_verdieping type C1_gen:4689025
Basic Wall:NLRS_22.21_WA_beton prefab d=500_gen:9090925 | 07 zevende verdieping | 22.21 binnenwanden - constructief, massieve wanden (Uniformat) | Model Group:NLRS_01.00_verdieping type C1_gen:4689025
Basic Wall:NLRS_22.21_WA_beton prefab d=500_gen:9090927 | 07 zevende verdieping | 22.21 binnenwanden - constructief, massieve wanden (Uniformat) | Model Group:NLRS_01.00_verdieping type C1_gen:4689025
2 x Basic Wall:NLRS_22.21_WA_beton prefab d=500_gen:9090929 | 07 zevende verdieping | 22.21 binnenwanden - constructief, massieve wanden (Uniformat) | Model Group:NLRS_01.00_verdieping type C1_gen:4689025
Basic Wall:NLRS_22.21_WA_beton prefab d=300_gen:9090936 | 07 zevende verdieping | 22.21 binnenwanden - constructief, massieve wanden (Uniformat) | Model Group:NLRS_01.00_verdieping type C1_gen:4689025
2 x Basic Wall:NLRS_22.21_WA_beton prefab d=300_gen:4472952 | 07 zevende verdieping | 22.21 binnenwanden - constructief, massieve wanden (Uniformat) | Model Group:NLRS_01.00_verdieping type C1_gen:4689025
Basic Wall:NLRS_22.21_WA_beton prefab d=500_gen:9090939 | 07 zevende verdieping | 22.21 binnenwanden - constructief, massieve wanden (Uniformat) | Model Group:NLRS_01.00_verdieping type C1_gen:4689025
Basic Wall:NLRS_22.21_WA_beton prefab d=500_gen:9090942 | 07 zevende verdieping | 22.21 binnenwanden - constructief, massieve wanden (Uniformat) | Model Group:NLRS_01.00_verdieping type C1_gen:4689025
Basic Wall:NLRS_22.21_WA_beton prefab d=300_gen:9090945 | 07 zevende verdieping | 22.21 binnenwanden - constructief, massieve wanden (Uniformat) | Model Group:NLRS_01.00_verdieping type C1_gen:4689025
Basic Wall:NLRS_22.21_WA_beton prefab d=500_gen:9090948 | 07 zevende verdieping | 22.21 binnenwanden - constructief, massieve wanden (Uniformat) | Model Group:NLRS_01.00_verdieping type C1_gen:4689025
Basic Wall:NLRS_22.21_WA_beton prefab d=500_gen:9090951 | 07 zevende verdieping | 22.21 binnenwanden - constructief, massieve wanden (Uniformat) | Model Group:NLRS_01.00_verdieping type C1_gen:4689025
Basic Wall:NLRS_22.21_WA_beton prefab d=500_gen:9090954 | 07 zevende verdieping | 22.21 binnenwanden - constructief, massieve wanden (Uniformat) | Model Group:NLRS_01.00_verdieping type C1_gen:4689025
Basic Wall:NLRS_22.21_WA_beton prefab d=500_gen:9090957 | 07 zevende verdieping | 22.21 binnenwanden - constructief, massieve wanden (Uniformat) | Model Group:NLRS_01.00_verdieping type C1_gen:4689025
Basic Wall:NLRS_22.21_WA_beton prefab d=500_gen:9090961 | 07 zevende verdieping | 22.21 binnenwanden - constructief, massieve wanden (Uniformat) | Model Group:NLRS_01.00_verdieping type C1_gen:4689025
Basic Wall:NLRS_22.21_WA_beton prefab d=500_gen:9090964 | 07 zevende verdieping | 22.21 binnenwanden - constructief, massieve wanden (Uniformat) | Model Group:NLRS_01.00_verdieping type C1_gen:4689025
Basic Wall:NLRS_22.21_WA_beton prefab d=500_gen:9090966 | 07 zevende verdieping | 22.21 binnenwanden - constructief, massieve wanden (Uniformat) | Model Group:NLRS_01.00_verdieping type C1_gen:4689025
2 x Basic Wall:NLRS_22.21_WA_beton prefab d=500_gen:4472769 | 07 zevende verdieping | 22.21 binnenwanden - constructief, massieve wanden (Uniformat) | Model Group:NLRS_01.00_verdieping type C1_gen:4689025
Basic Wall:NLRS_22.21_WA_beton prefab d=500_gen:9090969 | 07 zevende verdieping | 22.21 binnenwanden - constructief, massieve wanden (Uniformat) | Model Group:NLRS_01.00_verdieping type C1_gen:4689025
2 x Basic Wall:NLRS_22.21_WA_beton prefab d=500_gen:9125804 | 10 tiende verdieping | 22.21 binnenwanden - constructief, massieve wanden (Uniformat) | Model Group:NLRS_01.00_verdieping type B2_gen:9035827
2 x Basic Wall:NLRS_22.21_WA_beton prefab d=500_gen:9125806 | 10 tiende verdieping | 22.21 binnenwanden - constructief, massieve wanden (Uniformat) | Model Group:NLRS_01.00_verdieping type B2_gen:9035827
Basic Wall:NLRS_22.21_WA_beton prefab d=300_gen:9125808 | 10 tiende verdieping | 22.21 binnenwanden - constructief, massieve wanden (Uniformat) | Model Group:NLRS_01.00_verdieping type B2_gen:9035827
2 x Basic Wall:NLRS_22.21_WA_beton prefab d=300_gen:4472952 | 10 tiende verdieping | 22.21 binnenwanden - constructief, massieve wanden (Uniformat) | Model Group:NLRS_01.00_verdieping type B2_gen:9035827
Basic Wall:NLRS_22.21_WA_beton prefab d=300_gen:9125819 | 10 tiende verdieping | 22.21 binnenwanden - constructief, massieve wanden (Uniformat) | Model Group:NLRS_01.00_verdieping type B2_gen:9035827
Basic Wall:NLRS_22.21_WA_beton prefab d=500_gen:9125828 | 10 tiende verdieping | 22.21 binnenwanden - constructief, massieve wanden (Uniformat) | Model Group:NLRS_01.00_verdieping type B2_gen:9035827
2 x Basic Wall:NLRS_22.21_WA_beton prefab d=500_gen:4472769 | 10 tiende verdieping | 22.21 binnenwanden - constructief, massieve wanden (Uniformat) | Model Group:NLRS_01.00_verdieping type B2_gen:9035827
Basic Wall:NLRS_22.21_WA_beton prefab d=500_gen:9125830 | 10 tiende verdieping | 22.21 binnenwanden - constructief, massieve wanden (Uniformat) | Model Group:NLRS_01.00_verdieping type B2_gen:9035827
Basic Wall:NLRS_22.21_WA_beton prefab d=500_gen:9125833 | 10 tiende verdieping | 22.21 binnenwanden - constructief, massieve wanden (Uniformat) | Model Group:NLRS_01.00_verdieping type B2_gen:9035827
Basic Wall:NLRS_22.21_WA_beton prefab d=500_gen:9125836 | 10 tiende verdieping | 22.21 binnenwanden - constructief, massieve wanden (Uniformat) | Model Group:NLRS_01.00_verdieping type B2_gen:9035827
Basic Wall:NLRS_22.21_WA_beton prefab d=500_gen:9125839 | 10 tiende verdieping | 22.21 binnenwanden - constructief, massieve wanden (Uniformat) | Model Group:NLRS_01.00_verdieping type B2_gen:9035827
Basic Wall:NLRS_22.21_WA_beton prefab d=500_gen:9125842 | 10 tiende verdieping | 22.21 binnenwanden - constructief, massieve wanden (Uniformat) | Model Group:NLRS_01.00_verdieping type B2_gen:9035827
Basic Wall:NLRS_22.21_WA_beton prefab d=500_gen:9125852 | 10 tiende verdieping | 22.21 binnenwanden - constructief, massieve wanden (Uniformat) | Model Group:NLRS_01.00_verdieping type B2_gen:9035827
Basic Wall:NLRS_22.21_WA_beton prefab d=500_gen:9125854 | 10 tiende verdieping | 22.21 binnenwanden - constructief, massieve wanden (Uniformat) | Model Group:NLRS_01.00_verdieping type B2_gen:9035827
2 x Basic Wall:NLRS_22.21_WA_beton prefab d=500_gen:9126111 | 12 twaalfde verdieping | 22.21 binnenwanden - constructief, massieve wanden (Uniformat) | Model Group:NLRS_01.00_verdieping type B2_gen:4738165
2 x Basic Wall:NLRS_22.21_WA_beton prefab d=500_gen:9126113 | 12 twaalfde verdieping | 22.21 binnenwanden - constructief, massieve wanden (Uniformat) | Model Group:NLRS_01.00_verdieping type B2_gen:4738165
Basic Wall:NLRS_22.21_WA_beton prefab d=300_gen:9126115 | 12 twaalfde verdieping | 22.21 binnenwanden - constructief, massieve wanden (Uniformat) | Model Group:NLRS_01.00_verdieping type B2_gen:4738165
2 x Basic Wall:NLRS_22.21_WA_beton prefab d=300_gen:4472952 | 12 twaalfde verdieping | 22.21 binnenwanden - constructief, massieve wanden (Uniformat) | Model Group:NLRS_01.00_verdieping type B2_gen:4738165
Basic Wall:NLRS_22.21_WA_beton prefab d=300_gen:9126126 | 12 twaalfde verdieping | 22.21 binnenwanden - constructief, massieve wanden (Uniformat) | Model Group:NLRS_01.00_verdieping type B2_gen:4738165
Basic Wall:NLRS_22.21_WA_beton prefab d=500_gen:9126135 | 12 twaalfde verdieping | 22.21 binnenwanden - constructief, massieve wanden (Uniformat) | Model Group:NLRS_01.00_verdieping type B2_gen:4738165
2 x Basic Wall:NLRS_22.21_WA_beton prefab d=500_gen:4472769 | 12 twaalfde verdieping | 22.21 binnenwanden - constructief, massieve wanden (Uniformat) | Model Group:NLRS_01.00_verdieping type B2_gen:4738165
Basic Wall:NLRS_22.21_WA_beton prefab d=500_gen:9126137 | 12 twaalfde verdieping | 22.21 binnenwanden - constructief, massieve wanden (Uniformat) | Model Group:NLRS_01.00_verdieping type B2_gen:4738165
Basic Wall:NLRS_22.21_WA_beton prefab d=500_gen:9126140 | 12 twaalfde verdieping | 22.21 binnenwanden - constructief, massieve wanden (Uniformat) | Model Group:NLRS_01.00_verdieping type B2_gen:4738165
Basic Wall:NLRS_22.21_WA_beton prefab d=500_gen:9126143 | 12 twaalfde verdieping | 22.21 binnenwanden - constructief, massieve wanden (Uniformat) | Model Group:NLRS_01.00_verdieping type B2_gen:4738165
Basic Wall:NLRS_22.21_WA_beton prefab d=500_gen:9126146 | 12 twaalfde verdieping | 22.21 binnenwanden - constructief, massieve wanden (Uniformat) | Model Group:NLRS_01.00_verdieping type B2_gen:4738165
Basic Wall:NLRS_22.21_WA_beton prefab d=500_gen:9126149 | 12 twaalfde verdieping | 22.21 binnenwanden - constructief, massieve wanden (Uniformat) | Model Group:NLRS_01.00_verdieping type B2_gen:4738165
Basic Wall:NLRS_22.21_WA_beton prefab d=500_gen:9126159 | 12 twaalfde verdieping | 22.21 binnenwanden - constructief, massieve wanden (Uniformat) | Model Group:NLRS_01.00_verdieping type B2_gen:4738165
Basic Wall:NLRS_22.21_WA_beton prefab d=500_gen:9126161 | 12 twaalfde verdieping | 22.21 binnenwanden - constructief, massieve wanden (Uniformat) | Model Group:NLRS_01.00_verdieping type B2_gen:4738165
2 x Basic Wall:NLRS_22.21_WA_beton prefab d=500_gen:9126418 | 14 veertiende verdieping | 22.21 binnenwanden - constructief, massieve wanden (Uniformat) | Model Group:NLRS_01.00_verdieping type B2_gen:4738623
2 x Basic Wall:NLRS_22.21_WA_beton prefab d=500_gen:9126420 | 14 veertiende verdieping | 22.21 binnenwanden - constructief, massieve wanden (Uniformat) | Model Group:NLRS_01.00_verdieping type B2_gen:4738623
Basic Wall:NLRS_22.21_WA_beton prefab d=300_gen:9126422 | 14 veertiende verdieping | 22.21 binnenwanden - constructief, massieve wanden (Uniformat) | Model Group:NLRS_01.00_verdieping type B2_gen:4738623
2 x Basic Wall:NLRS_22.21_WA_beton prefab d=300_gen:4472952 | 14 veertiende verdieping | 22.21 binnenwanden - constructief, massieve wanden (Uniformat) | Model Group:NLRS_01.00_verdieping type B2_gen:4738623
Basic Wall:NLRS_22.21_WA_beton prefab d=300_gen:9126433 | 14 veertiende verdieping | 22.21 binnenwanden - constructief, massieve wanden (Uniformat) | Model Group:NLRS_01.00_verdieping type B2_gen:4738623
Basic Wall:NLRS_22.21_WA_beton prefab d=500_gen:9126442 | 14 veertiende verdieping | 22.21 binnenwanden - constructief, massieve wanden (Uniformat) | Model Group:NLRS_01.00_verdieping type B2_gen:4738623
2 x Basic Wall:NLRS_22.21_WA_beton prefab d=500_gen:4472769 | 14 veertiende verdieping | 22.21 binnenwanden - constructief, massieve wanden (Uniformat) | Model Group:NLRS_01.00_verdieping type B2_gen:4738623
Basic Wall:NLRS_22.21_WA_beton prefab d=500_gen:9126444 | 14 veertiende verdieping | 22.21 binnenwanden - constructief, massieve wanden (Uniformat) | Model Group:NLRS_01.00_verdieping type B2_gen:4738623
Basic Wall:NLRS_22.21_WA_beton prefab d=500_gen:9126447 | 14 veertiende verdieping | 22.21 binnenwanden - constructief, massieve wanden (Uniformat) | Model Group:NLRS_01.00_verdieping type B2_gen:4738623
Basic Wall:NLRS_22.21_WA_beton prefab d=500_gen:9126450 | 14 veertiende verdieping | 22.21 binnenwanden - constructief, massieve wanden (Uniformat) | Model Group:NLRS_01.00_verdieping type B2_gen:4738623
Basic Wall:NLRS_22.21_WA_beton prefab d=500_gen:9126453 | 14 veertiende verdieping | 22.21 binnenwanden - constructief, massieve wanden (Uniformat) | Model Group:NLRS_01.00_verdieping type B2_gen:4738623
Basic Wall:NLRS_22.21_WA_beton prefab d=500_gen:9126456 | 14 veertiende verdieping | 22.21 binnenwanden - constructief, massieve wanden (Uniformat) | Model Group:NLRS_01.00_verdieping type B2_gen:4738623
Basic Wall:NLRS_22.21_WA_beton prefab d=500_gen:9126466 | 14 veertiende verdieping | 22.21 binnenwanden - constructief, massieve wanden (Uniformat) | Model Group:NLRS_01.00_verdieping type B2_gen:4738623
Basic Wall:NLRS_22.21_WA_beton prefab d=500_gen:9126468 | 14 veertiende verdieping | 22.21 binnenwanden - constructief, massieve wanden (Uniformat) | Model Group:NLRS_01.00_verdieping type B2_gen:4738623
2 x Basic Wall:NLRS_22.21_WA_beton prefab d=500_gen:9128890 | 11 elfde verdieping | 22.21 binnenwanden - constructief, massieve wanden (Uniformat) | Model Group:NLRS_01.00_verdieping type C2_gen:9049706
Basic Wall:NLRS_22.21_WA_beton prefab d=500_gen:9128892 | 11 elfde verdieping | 22.21 binnenwanden - constructief, massieve wanden (Uniformat) | Model Group:NLRS_01.00_verdieping type C2_gen:9049706
Basic Wall:NLRS_22.21_WA_beton prefab d=500_gen:9128894 | 11 elfde verdieping | 22.21 binnenwanden - constructief, massieve wanden (Uniformat) | Model Group:NLRS_01.00_verdieping type C2_gen:9049706
2 x Basic Wall:NLRS_22.21_WA_beton prefab d=500_gen:9128896 | 11 elfde verdieping | 22.21 binnenwanden - constructief, massieve wanden (Uniformat) | Model Group:NLRS_01.00_verdieping type C2_gen:9049706
Basic Wall:NLRS_22.21_WA_beton prefab d=300_gen:9128903 | 11 elfde verdieping | 22.21 binnenwanden - constructief, massieve wanden (Uniformat) | Model Group:NLRS_01.00_verdieping type C2_gen:9049706
2 x Basic Wall:NLRS_22.21_WA_beton prefab d=300_gen:4472952 | 11 elfde verdieping | 22.21 binnenwanden - constructief, massieve wanden (Uniformat) | Model Group:NLRS_01.00_verdieping type C2_gen:9049706
Basic Wall:NLRS_22.21_WA_beton prefab d=500_gen:9128906 | 11 elfde verdieping | 22.21 binnenwanden - constructief, massieve wanden (Uniformat) | Model Group:NLRS_01.00_verdieping type C2_gen:9049706
Basic Wall:NLRS_22.21_WA_beton prefab d=500_gen:9128909 | 11 elfde verdieping | 22.21 binnenwanden - constructief, massieve wanden (Uniformat) | Model Group:NLRS_01.00_verdieping type C2_gen:9049706
Basic Wall:NLRS_22.21_WA_beton prefab d=300_gen:9128912 | 11 elfde verdieping | 22.21 binnenwanden - constructief, massieve wanden (Uniformat) | Model Group:NLRS_01.00_verdieping type C2_gen:9049706
Basic Wall:NLRS_22.21_WA_beton prefab d=500_gen:9128915 | 11 elfde verdieping | 22.21 binnenwanden - constructief, massieve wanden (Uniformat) | Model Group:NLRS_01.00_verdieping type C2_gen:9049706
Basic Wall:NLRS_22.21_WA_beton prefab d=500_gen:9128918 | 11 elfde verdieping | 22.21 binnenwanden - constructief, massieve wanden (Uniformat) | Model Group:NLRS_01.00_verdieping type C2_gen:9049706
Basic Wall:NLRS_22.21_WA_beton prefab d=500_gen:9128921 | 11 elfde verdieping | 22.21 binnenwanden - constructief, massieve wanden (Uniformat) | Model Group:NLRS_01.00_verdieping type C2_gen:9049706
Basic Wall:NLRS_22.21_WA_beton prefab d=500_gen:9128924 | 11 elfde verdieping | 22.21 binnenwanden - constructief, massieve wanden (Uniformat) | Model Group:NLRS_01.00_verdieping type C2_gen:9049706
Basic Wall:NLRS_22.21_WA_beton prefab d=500_gen:9128928 | 11 elfde verdieping | 22.21 binnenwanden - constructief, massieve wanden (Uniformat) | Model Group:NLRS_01.00_verdieping type C2_gen:9049706
Basic Wall:NLRS_22.21_WA_beton prefab d=500_gen:9128931 | 11 elfde verdieping | 22.21 binnenwanden - constructief, massieve wanden (Uniformat) | Model Group:NLRS_01.00_verdieping type C2_gen:9049706
Basic Wall:NLRS_22.21_WA_beton prefab d=500_gen:9128933 | 11 elfde verdieping | 22.21 binnenwanden - constructief, massieve wanden (Uniformat) | Model Group:NLRS_01.00_verdieping type C2_gen:9049706
2 x Basic Wall:NLRS_22.21_WA_beton prefab d=500_gen:4472769 | 11 elfde verdieping | 22.21 binnenwanden - constructief, massieve wanden (Uniformat) | Model Group:NLRS_01.00_verdieping type C2_gen:9049706
Basic Wall:NLRS_22.21_WA_beton prefab d=500_gen:9128936 | 11 elfde verdieping | 22.21 binnenwanden - constructief, massieve wanden (Uniformat) | Model Group:NLRS_01.00_verdieping type C2_gen:9049706
2 x Basic Wall:NLRS_22.21_WA_beton prefab d=500_gen:9129193 | 13 dertiende verdieping | 22.21 binnenwanden - constructief, massieve wanden (Uniformat) | Model Group:NLRS_01.00_verdieping type C2_gen:4730578
Basic Wall:NLRS_22.21_WA_beton prefab d=500_gen:9129195 | 13 dertiende verdieping | 22.21 binnenwanden - constructief, massieve wanden (Uniformat) | Model Group:NLRS_01.00_verdieping type C2_gen:4730578
Basic Wall:NLRS_22.21_WA_beton prefab d=500_gen:9129197 | 13 dertiende verdieping | 22.21 binnenwanden - constructief, massieve wanden (Uniformat) | Model Group:NLRS_01.00_verdieping type C2_gen:4730578
2 x Basic Wall:NLRS_22.21_WA_beton prefab d=500_gen:9129199 | 13 dertiende verdieping | 22.21 binnenwanden - constructief, massieve wanden (Uniformat) | Model Group:NLRS_01.00_verdieping type C2_gen:4730578
Basic Wall:NLRS_22.21_WA_beton prefab d=300_gen:9129206 | 13 dertiende verdieping | 22.21 binnenwanden - constructief, massieve wanden (Uniformat) | Model Group:NLRS_01.00_verdieping type C2_gen:4730578
2 x Basic Wall:NLRS_22.21_WA_beton prefab d=300_gen:4472952 | 13 dertiende verdieping | 22.21 binnenwanden - constructief, massieve wanden (Uniformat) | Model Group:NLRS_01.00_verdieping type C2_gen:4730578
Basic Wall:NLRS_22.21_WA_beton prefab d=500_gen:9129209 | 13 dertiende verdieping | 22.21 binnenwanden - constructief, massieve wanden (Uniformat) | Model Group:NLRS_01.00_verdieping type C2_gen:4730578
Basic Wall:NLRS_22.21_WA_beton prefab d=500_gen:9129212 | 13 dertiende verdieping | 22.21 binnenwanden - constructief, massieve wanden (Uniformat) | Model Group:NLRS_01.00_verdieping type C2_gen:4730578
Basic Wall:NLRS_22.21_WA_beton prefab d=300_gen:9129215 | 13 dertiende verdieping | 22.21 binnenwanden - constructief, massieve wanden (Uniformat) | Model Group:NLRS_01.00_verdieping type C2_gen:4730578
Basic Wall:NLRS_22.21_WA_beton prefab d=500_gen:9129218 | 13 dertiende verdieping | 22.21 binnenwanden - constructief, massieve wanden (Uniformat) | Model Group:NLRS_01.00_verdieping type C2_gen:4730578
Basic Wall:NLRS_22.21_WA_beton prefab d=500_gen:9129221 | 13 dertiende verdieping | 22.21 binnenwanden - constructief, massieve wanden (Uniformat) | Model Group:NLRS_01.00_verdieping type C2_gen:4730578
Basic Wall:NLRS_22.21_WA_beton prefab d=500_gen:9129224 | 13 dertiende verdieping | 22.21 binnenwanden - constructief, massieve wanden (Uniformat) | Model Group:NLRS_01.00_verdieping type C2_gen:4730578
Basic Wall:NLRS_22.21_WA_beton prefab d=500_gen:9129227 | 13 dertiende verdieping | 22.21 binnenwanden - constructief, massieve wanden (Uniformat) | Model Group:NLRS_01.00_verdieping type C2_gen:4730578
Basic Wall:NLRS_22.21_WA_beton prefab d=500_gen:9129231 | 13 dertiende verdieping | 22.21 binnenwanden - constructief, massieve wanden (Uniformat) | Model Group:NLRS_01.00_verdieping type C2_gen:4730578
Basic Wall:NLRS_22.21_WA_beton prefab d=500_gen:9129234 | 13 dertiende verdieping | 22.21 binnenwanden - constructief, massieve wanden (Uniformat) | Model Group:NLRS_01.00_verdieping type C2_gen:4730578
Basic Wall:NLRS_22.21_WA_beton prefab d=500_gen:9129236 | 13 dertiende verdieping | 22.21 binnenwanden - constructief, massieve wanden (Uniformat) | Model Group:NLRS_01.00_verdieping type C2_gen:4730578
2 x Basic Wall:NLRS_22.21_WA_beton prefab d=500_gen:4472769 | 13 dertiende verdieping | 22.21 binnenwanden - constructief, massieve wanden (Uniformat) | Model Group:NLRS_01.00_verdieping type C2_gen:4730578
Basic Wall:NLRS_22.21_WA_beton prefab d=500_gen:9129239 | 13 dertiende verdieping | 22.21 binnenwanden - constructief, massieve wanden (Uniformat) | Model Group:NLRS_01.00_verdieping type C2_gen:4730578
2 x Basic Wall:NLRS_22.21_WA_beton prefab d=500_gen:9131606 | 18 achttiende verdieping | 22.21 binnenwanden - constructief, massieve wanden (Uniformat) | Model Group:NLRS_01.00_verdieping type E_gen:4739539
Basic Wall:NLRS_22.21_WA_beton prefab d=500_gen:9131608 | 18 achttiende verdieping | 22.21 binnenwanden - constructief, massieve wanden (Uniformat) | Model Group:NLRS_01.00_verdieping type E_gen:4739539
Basic Wall:NLRS_22.21_WA_beton prefab d=500_gen:9131610 | 18 achttiende verdieping | 22.21 binnenwanden - constructief, massieve wanden (Uniformat) | Model Group:NLRS_01.00_verdieping type E_gen:4739539
2 x Basic Wall:NLRS_22.21_WA_beton prefab d=500_gen:9131612 | 18 achttiende verdieping | 22.21 binnenwanden - constructief, massieve wanden (Uniformat) | Model Group:NLRS_01.00_verdieping type E_gen:4739539
Basic Wall:NLRS_22.21_WA_beton prefab d=300_gen:9131619 | 18 achttiende verdieping | 22.21 binnenwanden - constructief, massieve wanden (Uniformat) | Model Group:NLRS_01.00_verdieping type E_gen:4739539
2 x Basic Wall:NLRS_22.21_WA_beton prefab d=300_gen:4472952 | 18 achttiende verdieping | 22.21 binnenwanden - constructief, massieve wanden (Uniformat) | Model Group:NLRS_01.00_verdieping type E_gen:4739539
Basic Wall:NLRS_22.21_WA_beton prefab d=500_gen:9131622 | 18 achttiende verdieping | 22.21 binnenwanden - constructief, massieve wanden (Uniformat) | Model Group:NLRS_01.00_verdieping type E_gen:4739539
Basic Wall:NLRS_22.21_WA_beton prefab d=500_gen:9131625 | 18 achttiende verdieping | 22.21 binnenwanden - constructief, massieve wanden (Uniformat) | Model Group:NLRS_01.00_verdieping type E_gen:4739539
Basic Wall:NLRS_22.21_WA_beton prefab d=300_gen:9131628 | 18 achttiende verdieping | 22.21 binnenwanden - constructief, massieve wanden (Uniformat) | Model Group:NLRS_01.00_verdieping type E_gen:4739539
Basic Wall:NLRS_22.21_WA_beton prefab d=500_gen:9131631 | 18 achttiende verdieping | 22.21 binnenwanden - constructief, massieve wanden (Uniformat) | Model Group:NLRS_01.00_verdieping type E_gen:4739539
Basic Wall:NLRS_22.21_WA_beton prefab d=500_gen:9131634 | 18 achttiende verdieping | 22.21 binnenwanden - constructief, massieve wanden (Uniformat) | Model Group:NLRS_01.00_verdieping type E_gen:4739539
Basic Wall:NLRS_22.21_WA_beton prefab d=500_gen:9131637 | 18 achttiende verdieping | 22.21 binnenwanden - constructief, massieve wanden (Uniformat) | Model Group:NLRS_01.00_verdieping type E_gen:4739539
Basic Wall:NLRS_22.21_WA_beton prefab d=500_gen:9131640 | 18 achttiende verdieping | 22.21 binnenwanden - constructief, massieve wanden (Uniformat) | Model Group:NLRS_01.00_verdieping type E_gen:4739539
Basic Wall:NLRS_22.21_WA_beton prefab d=500_gen:9131643 | 18 achttiende verdieping | 22.21 binnenwanden - constructief, massieve wanden (Uniformat) | Model Group:NLRS_01.00_verdieping type E_gen:4739539
Basic Wall:NLRS_22.21_WA_beton prefab d=500_gen:9131646 | 18 achttiende verdieping | 22.21 binnenwanden - constructief, massieve wanden (Uniformat) | Model Group:NLRS_01.00_verdieping type E_gen:4739539
Basic Wall:NLRS_22.21_WA_beton prefab d=500_gen:9131650 | 18 achttiende verdieping | 22.21 binnenwanden - constructief, massieve wanden (Uniformat) | Model Group:NLRS_01.00_verdieping type E_gen:4739539
2 x Basic Wall:NLRS_22.21_WA_beton prefab d=500_gen:4472769 | 18 achttiende verdieping | 22.21 binnenwanden - constructief, massieve wanden (Uniformat) | Model Group:NLRS_01.00_verdieping type E_gen:4739539
Basic Wall:NLRS_22.21_WA_beton prefab d=500_gen:9131653 | 18 achttiende verdieping | 22.21 binnenwanden - constructief, massieve wanden (Uniformat) | Model Group:NLRS_01.00_verdieping type E_gen:4739539
Floor:NLRS_23.21_FL_breedplaat d=100/270_gen:9131796:2 | 18 achttiende verdieping | 23.21 vloeren - constructief, vrijdragende vloeren (Uniformat) | Model Group:NLRS_23.21_vloer voor wanden d=300/500_gen:9131803
2 x Basic Wall:NLRS_22.21_WA_beton prefab d=500_gen:9132671 | 19 negentiende verdieping | 22.21 binnenwanden - constructief, massieve wanden (Uniformat) | Model Group:NLRS_01.00_verdieping type C2_gen:4731952
Basic Wall:NLRS_22.21_WA_beton prefab d=500_gen:9132673 | 19 negentiende verdieping | 22.21 binnenwanden - constructief, massieve wanden (Uniformat) | Model Group:NLRS_01.00_verdieping type C2_gen:4731952
Basic Wall:NLRS_22.21_WA_beton prefab d=500_gen:9132675 | 19 negentiende verdieping | 22.21 binnenwanden - constructief, massieve wanden (Uniformat) | Model Group:NLRS_01.00_verdieping type C2_gen:4731952
2 x Basic Wall:NLRS_22.21_WA_beton prefab d=500_gen:9132677 | 19 negentiende verdieping | 22.21 binnenwanden - constructief, massieve wanden (Uniformat) | Model Group:NLRS_01.00_verdieping type C2_gen:4731952
Basic Wall:NLRS_22.21_WA_beton prefab d=300_gen:9132684 | 19 negentiende verdieping | 22.21 binnenwanden - constructief, massieve wanden (Uniformat) | Model Group:NLRS_01.00_verdieping type C2_gen:4731952
2 x Basic Wall:NLRS_22.21_WA_beton prefab d=300_gen:4472952 | 19 negentiende verdieping | 22.21 binnenwanden - constructief, massieve wanden (Uniformat) | Model Group:NLRS_01.00_verdieping type C2_gen:4731952
Basic Wall:NLRS_22.21_WA_beton prefab d=500_gen:9132687 | 19 negentiende verdieping | 22.21 binnenwanden - constructief, massieve wanden (Uniformat) | Model Group:NLRS_01.00_verdieping type C2_gen:4731952
Basic Wall:NLRS_22.21_WA_beton prefab d=500_gen:9132690 | 19 negentiende verdieping | 22.21 binnenwanden - constructief, massieve wanden (Uniformat) | Model Group:NLRS_01.00_verdieping type C2_gen:4731952
Basic Wall:NLRS_22.21_WA_beton prefab d=300_gen:9132693 | 19 negentiende verdieping | 22.21 binnenwanden - constructief, massieve wanden (Uniformat) | Model Group:NLRS_01.00_verdieping type C2_gen:4731952
Basic Wall:NLRS_22.21_WA_beton prefab d=500_gen:9132696 | 19 negentiende verdieping | 22.21 binnenwanden - constructief, massieve wanden (Uniformat) | Model Group:NLRS_01.00_verdieping type C2_gen:4731952
Basic Wall:NLRS_22.21_WA_beton prefab d=500_gen:9132699 | 19 negentiende verdieping | 22.21 binnenwanden - constructief, massieve wanden (Uniformat) | Model Group:NLRS_01.00_verdieping type C2_gen:4731952
Basic Wall:NLRS_22.21_WA_beton prefab d=500_gen:9132702 | 19 negentiende verdieping | 22.21 binnenwanden - constructief, massieve wanden (Uniformat) | Model Group:NLRS_01.00_verdieping type C2_gen:4731952
Basic Wall:NLRS_22.21_WA_beton prefab d=500_gen:9132705 | 19 negentiende verdieping | 22.21 binnenwanden - constructief, massieve wanden (Uniformat) | Model Group:NLRS_01.00_verdieping type C2_gen:4731952
Basic Wall:NLRS_22.21_WA_beton prefab d=500_gen:9132709 | 19 negentiende verdieping | 22.21 binnenwanden - constructief, massieve wanden (Uniformat) | Model Group:NLRS_01.00_verdieping type C2_gen:4731952
Basic Wall:NLRS_22.21_WA_beton prefab d=500_gen:9132712 | 19 negentiende verdieping | 22.21 binnenwanden - constructief, massieve wanden (Uniformat) | Model Group:NLRS_01.00_verdieping type C2_gen:4731952
Basic Wall:NLRS_22.21_WA_beton prefab d=500_gen:9132714 | 19 negentiende verdieping | 22.21 binnenwanden - constructief, massieve wanden (Uniformat) | Model Group:NLRS_01.00_verdieping type C2_gen:4731952
2 x Basic Wall:NLRS_22.21_WA_beton prefab d=500_gen:4472769 | 19 negentiende verdieping | 22.21 binnenwanden - constructief, massieve wanden (Uniformat) | Model Group:NLRS_01.00_verdieping type C2_gen:4731952
Basic Wall:NLRS_22.21_WA_beton prefab d=500_gen:9132717 | 19 negentiende verdieping | 22.21 binnenwanden - constructief, massieve wanden (Uniformat) | Model Group:NLRS_01.00_verdieping type C2_gen:4731952
2 x Basic Wall:NLRS_22.21_WA_beton prefab d=500_gen:9133788 | 20 twintigste verdieping | 22.21 binnenwanden - constructief, massieve wanden (Uniformat) | Model Group:NLRS_01.00_verdieping type B2_gen:4739997
2 x Basic Wall:NLRS_22.21_WA_beton prefab d=500_gen:9133790 | 20 twintigste verdieping | 22.21 binnenwanden - constructief, massieve wanden (Uniformat) | Model Group:NLRS_01.00_verdieping type B2_gen:4739997
Basic Wall:NLRS_22.21_WA_beton prefab d=300_gen:9133792 | 20 twintigste verdieping | 22.21 binnenwanden - constructief, massieve wanden (Uniformat) | Model Group:NLRS_01.00_verdieping type B2_gen:4739997
2 x Basic Wall:NLRS_22.21_WA_beton prefab d=300_gen:4472952 | 20 twintigste verdieping | 22.21 binnenwanden - constructief, massieve wanden (Uniformat) | Model Group:NLRS_01.00_verdieping type B2_gen:4739997
Basic Wall:NLRS_22.21_WA_beton prefab d=500_gen:9133798 | 20 twintigste verdieping | 22.21 binnenwanden - constructief, massieve wanden (Uniformat) | Model Group:NLRS_01.00_verdieping type B2_gen:4739997
Basic Wall:NLRS_22.21_WA_beton prefab d=300_gen:9133803 | 20 twintigste verdieping | 22.21 binnenwanden - constructief, massieve wanden (Uniformat) | Model Group:NLRS_01.00_verdieping type B2_gen:4739997
Basic Wall:NLRS_22.21_WA_beton prefab d=500_gen:9133806 | 20 twintigste verdieping | 22.21 binnenwanden - constructief, massieve wanden (Uniformat) | Model Group:NLRS_01.00_verdieping type B2_gen:4739997
Basic Wall:NLRS_22.21_WA_beton prefab d=500_gen:9133812 | 20 twintigste verdieping | 22.21 binnenwanden - constructief, massieve wanden (Uniformat) | Model Group:NLRS_01.00_verdieping type B2_gen:4739997
2 x Basic Wall:NLRS_22.21_WA_beton prefab d=500_gen:4472769 | 20 twintigste verdieping | 22.21 binnenwanden - constructief, massieve wanden (Uniformat) | Model Group:NLRS_01.00_verdieping type B2_gen:4739997
Basic Wall:NLRS_22.21_WA_beton prefab d=500_gen:9133814 | 20 twintigste verdieping | 22.21 binnenwanden - constructief, massieve wanden (Uniformat) | Model Group:NLRS_01.00_verdieping type B2_gen:4739997
Basic Wall:NLRS_22.21_WA_beton prefab d=500_gen:9133817 | 20 twintigste verdieping | 22.21 binnenwanden - constructief, massieve wanden (Uniformat) | Model Group:NLRS_01.00_verdieping type B2_gen:4739997
Basic Wall:NLRS_22.21_WA_beton prefab d=500_gen:9133820 | 20 twintigste verdieping | 22.21 binnenwanden - constructief, massieve wanden (Uniformat) | Model Group:NLRS_01.00_verdieping type B2_gen:4739997
Basic Wall:NLRS_22.21_WA_beton prefab d=500_gen:9133823 | 20 twintigste verdieping | 22.21 binnenwanden - constructief, massieve wanden (Uniformat) | Model Group:NLRS_01.00_verdieping type B2_gen:4739997
Basic Wall:NLRS_22.21_WA_beton prefab d=500_gen:9133826 | 20 twintigste verdieping | 22.21 binnenwanden - constructief, massieve wanden (Uniformat) | Model Group:NLRS_01.00_verdieping type B2_gen:4739997
Basic Wall:NLRS_22.21_WA_beton prefab d=500_gen:9133829 | 20 twintigste verdieping | 22.21 binnenwanden - constructief, massieve wanden (Uniformat) | Model Group:NLRS_01.00_verdieping type B2_gen:4739997
Basic Wall:NLRS_22.21_WA_beton prefab d=500_gen:9133832 | 20 twintigste verdieping | 22.21 binnenwanden - constructief, massieve wanden (Uniformat) | Model Group:NLRS_01.00_verdieping type B2_gen:4739997
Basic Wall:NLRS_22.21_WA_beton prefab d=500_gen:9133836 | 20 twintigste verdieping | 22.21 binnenwanden - constructief, massieve wanden (Uniformat) | Model Group:NLRS_01.00_verdieping type B2_gen:4739997
Basic Wall:NLRS_22.21_WA_beton prefab d=500_gen:9133838 | 20 twintigste verdieping | 22.21 binnenwanden - constructief, massieve wanden (Uniformat) | Model Group:NLRS_01.00_verdieping type B2_gen:4739997
Basic Wall:NLRS_22.21_WA_beton prefab d=400_gen:9134782 | 23 drieëntwintigste verdieping | 22.21 binnenwanden - constructief, massieve wanden (Uniformat) | Model Group:NLRS_01.00_verdieping type F2_gen:4779563
Basic Wall:NLRS_22.21_WA_beton prefab d=400_gen:9134784 | 23 drieëntwintigste verdieping | 22.21 binnenwanden - constructief, massieve wanden (Uniformat) | Model Group:NLRS_01.00_verdieping type F2_gen:4779563
2 x Basic Wall:NLRS_22.21_WA_beton prefab d=400_gen:9134786 | 23 drieëntwintigste verdieping | 22.21 binnenwanden - constructief, massieve wanden (Uniformat) | Model Group:NLRS_01.00_verdieping type F2_gen:4779563
Basic Wall:NLRS_22.21_WA_beton prefab d=300_gen:9134792 | 23 drieëntwintigste verdieping | 22.21 binnenwanden - constructief, massieve wanden (Uniformat) | Model Group:NLRS_01.00_verdieping type F2_gen:4779563
2 x Basic Wall:NLRS_22.21_WA_beton prefab d=300_gen:4472952 | 23 drieëntwintigste verdieping | 22.21 binnenwanden - constructief, massieve wanden (Uniformat) | Model Group:NLRS_01.00_verdieping type F2_gen:4779563
Basic Wall:NLRS_22.21_WA_beton prefab d=400_gen:9134795 | 23 drieëntwintigste verdieping | 22.21 binnenwanden - constructief, massieve wanden (Uniformat) | Model Group:NLRS_01.00_verdieping type F2_gen:4779563
Basic Wall:NLRS_22.21_WA_beton prefab d=400_gen:9134798 | 23 drieëntwintigste verdieping | 22.21 binnenwanden - constructief, massieve wanden (Uniformat) | Model Group:NLRS_01.00_verdieping type F2_gen:4779563
Basic Wall:NLRS_22.21_WA_beton prefab d=300_gen:9134801 | 23 drieëntwintigste verdieping | 22.21 binnenwanden - constructief, massieve wanden (Uniformat) | Model Group:NLRS_01.00_verdieping type F2_gen:4779563
Basic Wall:NLRS_22.21_WA_beton prefab d=400_gen:9134804 | 23 drieëntwintigste verdieping | 22.21 binnenwanden - constructief, massieve wanden (Uniformat) | Model Group:NLRS_01.00_verdieping type F2_gen:4779563
Basic Wall:NLRS_22.21_WA_beton prefab d=400_gen:9134807 | 23 drieëntwintigste verdieping | 22.21 binnenwanden - constructief, massieve wanden (Uniformat) | Model Group:NLRS_01.00_verdieping type F2_gen:4779563
Basic Wall:NLRS_22.21_WA_beton prefab d=400_gen:9134810 | 23 drieëntwintigste verdieping | 22.21 binnenwanden - constructief, massieve wanden (Uniformat) | Model Group:NLRS_01.00_verdieping type F2_gen:4779563
Basic Wall:NLRS_22.21_WA_beton prefab d=400_gen:9134813 | 23 drieëntwintigste verdieping | 22.21 binnenwanden - constructief, massieve wanden (Uniformat) | Model Group:NLRS_01.00_verdieping type F2_gen:4779563
2 x Basic Wall:NLRS_22.21_WA_beton prefab d=400_gen:9134817 | 23 drieëntwintigste verdieping | 22.21 binnenwanden - constructief, massieve wanden (Uniformat) | Model Group:NLRS_01.00_verdieping type F2_gen:4779563
2 x Basic Wall:NLRS_22.21_WA_beton prefab d=400_gen:4699555 | 23 drieëntwintigste verdieping | 22.21 binnenwanden - constructief, massieve wanden (Uniformat) | Model Group:NLRS_01.00_verdieping type F2_gen:4779563
2 x Basic Wall:NLRS_22.21_WA_beton prefab d=400_gen:9134820 | 23 drieëntwintigste verdieping | 22.21 binnenwanden - constructief, massieve wanden (Uniformat) | Model Group:NLRS_01.00_verdieping type F2_gen:4779563
2 x Basic Wall:NLRS_22.21_WA_beton prefab d=400_gen:9134822 | 23 drieëntwintigste verdieping | 22.21 binnenwanden - constructief, massieve wanden (Uniformat) | Model Group:NLRS_01.00_verdieping type F2_gen:4779563
Basic Wall:NLRS_22.21_WA_beton prefab d=400_gen:9135075 | 28 achtentwintigste verdieping | 22.21 binnenwanden - constructief, massieve wanden (Uniformat) | Model Group:NLRS_01.00_verdieping type F1_gen:4748328
Basic Wall:NLRS_22.21_WA_beton prefab d=400_gen:9135077 | 28 achtentwintigste verdieping | 22.21 binnenwanden - constructief, massieve wanden (Uniformat) | Model Group:NLRS_01.00_verdieping type F1_gen:4748328
2 x Basic Wall:NLRS_22.21_WA_beton prefab d=400_gen:9135079 | 28 achtentwintigste verdieping | 22.21 binnenwanden - constructief, massieve wanden (Uniformat) | Model Group:NLRS_01.00_verdieping type F1_gen:4748328
Basic Wall:NLRS_22.21_WA_beton prefab d=300_gen:9135085 | 28 achtentwintigste verdieping | 22.21 binnenwanden - constructief, massieve wanden (Uniformat) | Model Group:NLRS_01.00_verdieping type F1_gen:4748328
2 x Basic Wall:NLRS_22.21_WA_beton prefab d=300_gen:4472952 | 28 achtentwintigste verdieping | 22.21 binnenwanden - constructief, massieve wanden (Uniformat) | Model Group:NLRS_01.00_verdieping type F1_gen:4748328
Basic Wall:NLRS_22.21_WA_beton prefab d=400_gen:9135088 | 28 achtentwintigste verdieping | 22.21 binnenwanden - constructief, massieve wanden (Uniformat) | Model Group:NLRS_01.00_verdieping type F1_gen:4748328
Basic Wall:NLRS_22.21_WA_beton prefab d=400_gen:9135091 | 28 achtentwintigste verdieping | 22.21 binnenwanden - constructief, massieve wanden (Uniformat) | Model Group:NLRS_01.00_verdieping type F1_gen:4748328
Basic Wall:NLRS_22.21_WA_beton prefab d=300_gen:9135094 | 28 achtentwintigste verdieping | 22.21 binnenwanden - constructief, massieve wanden (Uniformat) | Model Group:NLRS_01.00_verdieping type F1_gen:4748328
Basic Wall:NLRS_22.21_WA_beton prefab d=400_gen:9135097 | 28 achtentwintigste verdieping | 22.21 binnenwanden - constructief, massieve wanden (Uniformat) | Model Group:NLRS_01.00_verdieping type F1_gen:4748328
Basic Wall:NLRS_22.21_WA_beton prefab d=400_gen:9135100 | 28 achtentwintigste verdieping | 22.21 binnenwanden - constructief, massieve wanden (Uniformat) | Model Group:NLRS_01.00_verdieping type F1_gen:4748328
Basic Wall:NLRS_22.21_WA_beton prefab d=400_gen:9135103 | 28 achtentwintigste verdieping | 22.21 binnenwanden - constructief, massieve wanden (Uniformat) | Model Group:NLRS_01.00_verdieping type F1_gen:4748328
Basic Wall:NLRS_22.21_WA_beton prefab d=400_gen:9135106 | 28 achtentwintigste verdieping | 22.21 binnenwanden - constructief, massieve wanden (Uniformat) | Model Group:NLRS_01.00_verdieping type F1_gen:4748328
2 x Basic Wall:NLRS_22.21_WA_beton prefab d=400_gen:9135110 | 28 achtentwintigste verdieping | 22.21 binnenwanden - constructief, massieve wanden (Uniformat) | Model Group:NLRS_01.00_verdieping type F1_gen:4748328
2 x Basic Wall:NLRS_22.21_WA_beton prefab d=400_gen:4699555 | 28 achtentwintigste verdieping | 22.21 binnenwanden - constructief, massieve wanden (Uniformat) | Model Group:NLRS_01.00_verdieping type F1_gen:4748328
2 x Basic Wall:NLRS_22.21_WA_beton prefab d=400_gen:9135113 | 28 achtentwintigste verdieping | 22.21 binnenwanden - constructief, massieve wanden (Uniformat) | Model Group:NLRS_01.00_verdieping type F1_gen:4748328
2 x Basic Wall:NLRS_22.21_WA_beton prefab d=400_gen:9135115 | 28 achtentwintigste verdieping | 22.21 binnenwanden - constructief, massieve wanden (Uniformat) | Model Group:NLRS_01.00_verdieping type F1_gen:4748328
Basic Wall:NLRS_22.21_WA_beton prefab d=400_gen:9135368 | 29 negenentwintigste verdieping | 22.21 binnenwanden - constructief, massieve wanden (Uniformat) | Model Group:NLRS_01.00_verdieping type F1_gen:4748760
Basic Wall:NLRS_22.21_WA_beton prefab d=400_gen:9135370 | 29 negenentwintigste verdieping | 22.21 binnenwanden - constructief, massieve wanden (Uniformat) | Model Group:NLRS_01.00_verdieping type F1_gen:4748760
2 x Basic Wall:NLRS_22.21_WA_beton prefab d=400_gen:9135372 | 29 negenentwintigste verdieping | 22.21 binnenwanden - constructief, massieve wanden (Uniformat) | Model Group:NLRS_01.00_verdieping type F1_gen:4748760
Basic Wall:NLRS_22.21_WA_beton prefab d=300_gen:9135378 | 29 negenentwintigste verdieping | 22.21 binnenwanden - constructief, massieve wanden (Uniformat) | Model Group:NLRS_01.00_verdieping type F1_gen:4748760
2 x Basic Wall:NLRS_22.21_WA_beton prefab d=300_gen:4472952 | 29 negenentwintigste verdieping | 22.21 binnenwanden - constructief, massieve wanden (Uniformat) | Model Group:NLRS_01.00_verdieping type F1_gen:4748760
Basic Wall:NLRS_22.21_WA_beton prefab d=400_gen:9135381 | 29 negenentwintigste verdieping | 22.21 binnenwanden - constructief, massieve wanden (Uniformat) | Model Group:NLRS_01.00_verdieping type F1_gen:4748760
Basic Wall:NLRS_22.21_WA_beton prefab d=400_gen:9135384 | 29 negenentwintigste verdieping | 22.21 binnenwanden - constructief, massieve wanden (Uniformat) | Model Group:NLRS_01.00_verdieping type F1_gen:4748760
Basic Wall:NLRS_22.21_WA_beton prefab d=300_gen:9135387 | 29 negenentwintigste verdieping | 22.21 binnenwanden - constructief, massieve wanden (Uniformat) | Model Group:NLRS_01.00_verdieping type F1_gen:4748760
Basic Wall:NLRS_22.21_WA_beton prefab d=400_gen:9135390 | 29 negenentwintigste verdieping | 22.21 binnenwanden - constructief, massieve wanden (Uniformat) | Model Group:NLRS_01.00_verdieping type F1_gen:4748760
Basic Wall:NLRS_22.21_WA_beton prefab d=400_gen:9135393 | 29 negenentwintigste verdieping | 22.21 binnenwanden - constructief, massieve wanden (Uniformat) | Model Group:NLRS_01.00_verdieping type F1_gen:4748760
Basic Wall:NLRS_22.21_WA_beton prefab d=400_gen:9135396 | 29 negenentwintigste verdieping | 22.21 binnenwanden - constructief, massieve wanden (Uniformat) | Model Group:NLRS_01.00_verdieping type F1_gen:4748760
Basic Wall:NLRS_22.21_WA_beton prefab d=400_gen:9135399 | 29 negenentwintigste verdieping | 22.21 binnenwanden - constructief, massieve wanden (Uniformat) | Model Group:NLRS_01.00_verdieping type F1_gen:4748760
2 x Basic Wall:NLRS_22.21_WA_beton prefab d=400_gen:9135403 | 29 negenentwintigste verdieping | 22.21 binnenwanden - constructief, massieve wanden (Uniformat) | Model Group:NLRS_01.00_verdieping type F1_gen:4748760
2 x Basic Wall:NLRS_22.21_WA_beton prefab d=400_gen:4699555 | 29 negenentwintigste verdieping | 22.21 binnenwanden - constructief, massieve wanden (Uniformat) | Model Group:NLRS_01.00_verdieping type F1_gen:4748760
2 x Basic Wall:NLRS_22.21_WA_beton prefab d=400_gen:9135406 | 29 negenentwintigste verdieping | 22.21 binnenwanden - constructief, massieve wanden (Uniformat) | Model Group:NLRS_01.00_verdieping type F1_gen:4748760
2 x Basic Wall:NLRS_22.21_WA_beton prefab d=400_gen:9135408 | 29 negenentwintigste verdieping | 22.21 binnenwanden - constructief, massieve wanden (Uniformat) | Model Group:NLRS_01.00_verdieping type F1_gen:4748760
Basic Wall:NLRS_22.21_WA_beton prefab d=400_gen:9135661 | 33 drieëndertigste verdieping | 22.21 binnenwanden - constructief, massieve wanden (Uniformat) | Model Group:NLRS_01.00_verdieping type F1_gen:4750488
Basic Wall:NLRS_22.21_WA_beton prefab d=400_gen:9135663 | 33 drieëndertigste verdieping | 22.21 binnenwanden - constructief, massieve wanden (Uniformat) | Model Group:NLRS_01.00_verdieping type F1_gen:4750488
2 x Basic Wall:NLRS_22.21_WA_beton prefab d=400_gen:9135665 | 33 drieëndertigste verdieping | 22.21 binnenwanden - constructief, massieve wanden (Uniformat) | Model Group:NLRS_01.00_verdieping type F1_gen:4750488
Basic Wall:NLRS_22.21_WA_beton prefab d=300_gen:9135671 | 33 drieëndertigste verdieping | 22.21 binnenwanden - constructief, massieve wanden (Uniformat) | Model Group:NLRS_01.00_verdieping type F1_gen:4750488
2 x Basic Wall:NLRS_22.21_WA_beton prefab d=300_gen:4472952 | 33 drieëndertigste verdieping | 22.21 binnenwanden - constructief, massieve wanden (Uniformat) | Model Group:NLRS_01.00_verdieping type F1_gen:4750488
Basic Wall:NLRS_22.21_WA_beton prefab d=400_gen:9135674 | 33 drieëndertigste verdieping | 22.21 binnenwanden - constructief, massieve wanden (Uniformat) | Model Group:NLRS_01.00_verdieping type F1_gen:4750488
Basic Wall:NLRS_22.21_WA_beton prefab d=400_gen:9135677 | 33 drieëndertigste verdieping | 22.21 binnenwanden - constructief, massieve wanden (Uniformat) | Model Group:NLRS_01.00_verdieping type F1_gen:4750488
Basic Wall:NLRS_22.21_WA_beton prefab d=300_gen:9135680 | 33 drieëndertigste verdieping | 22.21 binnenwanden - constructief, massieve wanden (Uniformat) | Model Group:NLRS_01.00_verdieping type F1_gen:4750488
Basic Wall:NLRS_22.21_WA_beton prefab d=400_gen:9135683 | 33 drieëndertigste verdieping | 22.21 binnenwanden - constructief, massieve wanden (Uniformat) | Model Group:NLRS_01.00_verdieping type F1_gen:4750488
Basic Wall:NLRS_22.21_WA_beton prefab d=400_gen:9135686 | 33 drieëndertigste verdieping | 22.21 binnenwanden - constructief, massieve wanden (Uniformat) | Model Group:NLRS_01.00_verdieping type F1_gen:4750488
Basic Wall:NLRS_22.21_WA_beton prefab d=400_gen:9135689 | 33 drieëndertigste verdieping | 22.21 binnenwanden - constructief, massieve wanden (Uniformat) | Model Group:NLRS_01.00_verdieping type F1_gen:4750488
Basic Wall:NLRS_22.21_WA_beton prefab d=400_gen:9135692 | 33 drieëndertigste verdieping | 22.21 binnenwanden - constructief, massieve wanden (Uniformat) | Model Group:NLRS_01.00_verdieping type F1_gen:4750488
2 x Basic Wall:NLRS_22.21_WA_beton prefab d=400_gen:9135696 | 33 drieëndertigste verdieping | 22.21 binnenwanden - constructief, massieve wanden (Uniformat) | Model Group:NLRS_01.00_verdieping type F1_gen:4750488
2 x Basic Wall:NLRS_22.21_WA_beton prefab d=400_gen:4699555 | 33 drieëndertigste verdieping | 22.21 binnenwanden - constructief, massieve wanden (Uniformat) | Model Group:NLRS_01.00_verdieping type F1_gen:4750488
2 x Basic Wall:NLRS_22.21_WA_beton prefab d=400_gen:9135699 | 33 drieëndertigste verdieping | 22.21 binnenwanden - constructief, massieve wanden (Uniformat) | Model Group:NLRS_01.00_verdieping type F1_gen:4750488
2 x Basic Wall:NLRS_22.21_WA_beton prefab d=400_gen:9135701 | 33 drieëndertigste verdieping | 22.21 binnenwanden - constructief, massieve wanden (Uniformat) | Model Group:NLRS_01.00_verdieping type F1_gen:4750488
Floor:NLRS_23.21_FL_breedplaat d=100/270_gen:9138690:2 | 31 eenendertigste verdieping | 23.21 vloeren - constructief, vrijdragende vloeren (Uniformat) | Model Group:NLRS_23.21_vloer voor wanden d=300/400_gen:9138697
Basic Wall:NLRS_22.21_WA_beton prefab d=400_gen:9138778 | 31 eenendertigste verdieping | 22.21 binnenwanden - constructief, massieve wanden (Uniformat) | Model Group:NLRS_01.00_verdieping type G_gen:4749624
Basic Wall:NLRS_22.21_WA_beton prefab d=400_gen:9138780 | 31 eenendertigste verdieping | 22.21 binnenwanden - constructief, massieve wanden (Uniformat) | Model Group:NLRS_01.00_verdieping type G_gen:4749624
2 x Basic Wall:NLRS_22.21_WA_beton prefab d=400_gen:9138782 | 31 eenendertigste verdieping | 22.21 binnenwanden - constructief, massieve wanden (Uniformat) | Model Group:NLRS_01.00_verdieping type G_gen:4749624
Basic Wall:NLRS_22.21_WA_beton prefab d=300_gen:9138788 | 31 eenendertigste verdieping | 22.21 binnenwanden - constructief, massieve wanden (Uniformat) | Model Group:NLRS_01.00_verdieping type G_gen:4749624
2 x Basic Wall:NLRS_22.21_WA_beton prefab d=300_gen:4472952 | 31 eenendertigste verdieping | 22.21 binnenwanden - constructief, massieve wanden (Uniformat) | Model Group:NLRS_01.00_verdieping type G_gen:4749624
Basic Wall:NLRS_22.21_WA_beton prefab d=400_gen:9138791 | 31 eenendertigste verdieping | 22.21 binnenwanden - constructief, massieve wanden (Uniformat) | Model Group:NLRS_01.00_verdieping type G_gen:4749624
Basic Wall:NLRS_22.21_WA_beton prefab d=400_gen:9138794 | 31 eenendertigste verdieping | 22.21 binnenwanden - constructief, massieve wanden (Uniformat) | Model Group:NLRS_01.00_verdieping type G_gen:4749624
Basic Wall:NLRS_22.21_WA_beton prefab d=300_gen:9138797 | 31 eenendertigste verdieping | 22.21 binnenwanden - constructief, massieve wanden (Uniformat) | Model Group:NLRS_01.00_verdieping type G_gen:4749624
Basic Wall:NLRS_22.21_WA_beton prefab d=400_gen:9138800 | 31 eenendertigste verdieping | 22.21 binnenwanden - constructief, massieve wanden (Uniformat) | Model Group:NLRS_01.00_verdieping type G_gen:4749624
Basic Wall:NLRS_22.21_WA_beton prefab d=400_gen:9138803 | 31 eenendertigste verdieping | 22.21 binnenwanden - constructief, massieve wanden (Uniformat) | Model Group:NLRS_01.00_verdieping type G_gen:4749624
Basic Wall:NLRS_22.21_WA_beton prefab d=400_gen:9138806 | 31 eenendertigste verdieping | 22.21 binnenwanden - constructief, massieve wanden (Uniformat) | Model Group:NLRS_01.00_verdieping type G_gen:4749624
Basic Wall:NLRS_22.21_WA_beton prefab d=400_gen:9138809 | 31 eenendertigste verdieping | 22.21 binnenwanden - constructief, massieve wanden (Uniformat) | Model Group:NLRS_01.00_verdieping type G_gen:4749624
2 x Basic Wall:NLRS_22.21_WA_beton prefab d=400_gen:9138813 | 31 eenendertigste verdieping | 22.21 binnenwanden - constructief, massieve wanden (Uniformat) | Model Group:NLRS_01.00_verdieping type G_gen:4749624
2 x Basic Wall:NLRS_22.21_WA_beton prefab d=400_gen:4699555 | 31 eenendertigste verdieping | 22.21 binnenwanden - constructief, massieve wanden (Uniformat) | Model Group:NLRS_01.00_verdieping type G_gen:4749624
2 x Basic Wall:NLRS_22.21_WA_beton prefab d=400_gen:9138816 | 31 eenendertigste verdieping | 22.21 binnenwanden - constructief, massieve wanden (Uniformat) | Model Group:NLRS_01.00_verdieping type G_gen:4749624
2 x Basic Wall:NLRS_22.21_WA_beton prefab d=400_gen:9138818 | 31 eenendertigste verdieping | 22.21 binnenwanden - constructief, massieve wanden (Uniformat) | Model Group:NLRS_01.00_verdieping type G_gen:4749624
Floor:NLRS_23.21_FL_breedplaat d=100/270_gen:9138980:2 | 32 tweeëndertigste verdieping | 23.21 vloeren - constructief, vrijdragende vloeren (Uniformat) | Model Group:NLRS_23.21_vloer voor wanden d=300/400_gen:9138987
Basic Wall:NLRS_22.21_WA_beton prefab d=400_gen:9139068 | 32 tweeëndertigste verdieping | 22.21 binnenwanden - constructief, massieve wanden (Uniformat) | Model Group:NLRS_01.00_verdieping type G_gen:4750056
Basic Wall:NLRS_22.21_WA_beton prefab d=400_gen:9139070 | 32 tweeëndertigste verdieping | 22.21 binnenwanden - constructief, massieve wanden (Uniformat) | Model Group:NLRS_01.00_verdieping type G_gen:4750056
2 x Basic Wall:NLRS_22.21_WA_beton prefab d=400_gen:9139072 | 32 tweeëndertigste verdieping | 22.21 binnenwanden - constructief, massieve wanden (Uniformat) | Model Group:NLRS_01.00_verdieping type G_gen:4750056
Basic Wall:NLRS_22.21_WA_beton prefab d=300_gen:9139078 | 32 tweeëndertigste verdieping | 22.21 binnenwanden - constructief, massieve wanden (Uniformat) | Model Group:NLRS_01.00_verdieping type G_gen:4750056
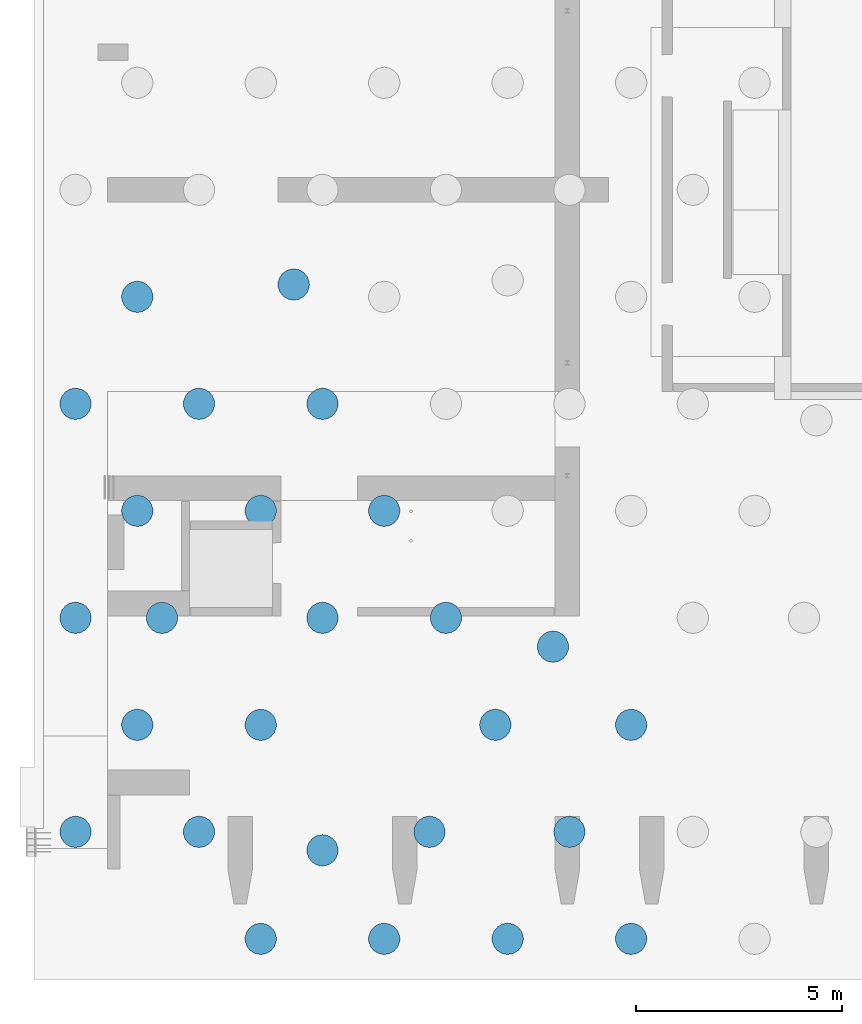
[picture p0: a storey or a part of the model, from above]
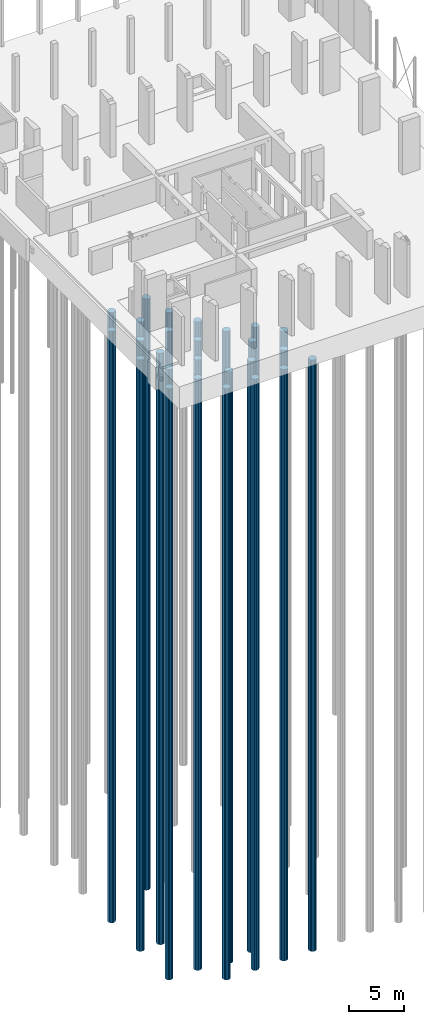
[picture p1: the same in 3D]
Properties of the parts of a building model (IFC2X3), part 14 of 21

# IfcOpeningElement: Opening (5659)
Name | In | Classification | Group
2 x Basic Wall:NLRS_22.21_WA_beton prefab d=300_gen:4472952 | 32 tweeëndertigste verdieping | 22.21 binnenwanden - constructief, massieve wanden (Uniformat) | Model Group:NLRS_01.00_verdieping type G_gen:4750056
Basic Wall:NLRS_22.21_WA_beton prefab d=400_gen:9139081 | 32 tweeëndertigste verdieping | 22.21 binnenwanden - constructief, massieve wanden (Uniformat) | Model Group:NLRS_01.00_verdieping type G_gen:4750056
Basic Wall:NLRS_22.21_WA_beton prefab d=400_gen:9139084 | 32 tweeëndertigste verdieping | 22.21 binnenwanden - constructief, massieve wanden (Uniformat) | Model Group:NLRS_01.00_verdieping type G_gen:4750056
Basic Wall:NLRS_22.21_WA_beton prefab d=300_gen:9139087 | 32 tweeëndertigste verdieping | 22.21 binnenwanden - constructief, massieve wanden (Uniformat) | Model Group:NLRS_01.00_verdieping type G_gen:4750056
Basic Wall:NLRS_22.21_WA_beton prefab d=400_gen:9139090 | 32 tweeëndertigste verdieping | 22.21 binnenwanden - constructief, massieve wanden (Uniformat) | Model Group:NLRS_01.00_verdieping type G_gen:4750056
Basic Wall:NLRS_22.21_WA_beton prefab d=400_gen:9139093 | 32 tweeëndertigste verdieping | 22.21 binnenwanden - constructief, massieve wanden (Uniformat) | Model Group:NLRS_01.00_verdieping type G_gen:4750056
Basic Wall:NLRS_22.21_WA_beton prefab d=400_gen:9139096 | 32 tweeëndertigste verdieping | 22.21 binnenwanden - constructief, massieve wanden (Uniformat) | Model Group:NLRS_01.00_verdieping type G_gen:4750056
Basic Wall:NLRS_22.21_WA_beton prefab d=400_gen:9139099 | 32 tweeëndertigste verdieping | 22.21 binnenwanden - constructief, massieve wanden (Uniformat) | Model Group:NLRS_01.00_verdieping type G_gen:4750056
2 x Basic Wall:NLRS_22.21_WA_beton prefab d=400_gen:9139103 | 32 tweeëndertigste verdieping | 22.21 binnenwanden - constructief, massieve wanden (Uniformat) | Model Group:NLRS_01.00_verdieping type G_gen:4750056
2 x Basic Wall:NLRS_22.21_WA_beton prefab d=400_gen:4699555 | 32 tweeëndertigste verdieping | 22.21 binnenwanden - constructief, massieve wanden (Uniformat) | Model Group:NLRS_01.00_verdieping type G_gen:4750056
2 x Basic Wall:NLRS_22.21_WA_beton prefab d=400_gen:9139106 | 32 tweeëndertigste verdieping | 22.21 binnenwanden - constructief, massieve wanden (Uniformat) | Model Group:NLRS_01.00_verdieping type G_gen:4750056
2 x Basic Wall:NLRS_22.21_WA_beton prefab d=400_gen:9139108 | 32 tweeëndertigste verdieping | 22.21 binnenwanden - constructief, massieve wanden (Uniformat) | Model Group:NLRS_01.00_verdieping type G_gen:4750056
Floor:NLRS_23.21_FL_breedplaat d=100/270_gen:9140569:2 | 34 vierendertigste verdieping | 23.21 vloeren - constructief, vrijdragende vloeren (Uniformat) | Model Group:NLRS_23.21_vloer voor wanden d=300/400_gen:9140576
Basic Wall:NLRS_22.21_WA_beton prefab d=400_gen:9140657 | 34 vierendertigste verdieping | 22.21 binnenwanden - constructief, massieve wanden (Uniformat) | Model Group:NLRS_01.00_verdieping type H_gen:4750920
Basic Wall:NLRS_22.21_WA_beton prefab d=400_gen:9140659 | 34 vierendertigste verdieping | 22.21 binnenwanden - constructief, massieve wanden (Uniformat) | Model Group:NLRS_01.00_verdieping type H_gen:4750920
2 x Basic Wall:NLRS_22.21_WA_beton prefab d=400_gen:9140661 | 34 vierendertigste verdieping | 22.21 binnenwanden - constructief, massieve wanden (Uniformat) | Model Group:NLRS_01.00_verdieping type H_gen:4750920
Basic Wall:NLRS_22.21_WA_beton prefab d=300_gen:9140667 | 34 vierendertigste verdieping | 22.21 binnenwanden - constructief, massieve wanden (Uniformat) | Model Group:NLRS_01.00_verdieping type H_gen:4750920
2 x Basic Wall:NLRS_22.21_WA_beton prefab d=300_gen:4472952 | 34 vierendertigste verdieping | 22.21 binnenwanden - constructief, massieve wanden (Uniformat) | Model Group:NLRS_01.00_verdieping type H_gen:4750920
Basic Wall:NLRS_22.21_WA_beton prefab d=400_gen:9140670 | 34 vierendertigste verdieping | 22.21 binnenwanden - constructief, massieve wanden (Uniformat) | Model Group:NLRS_01.00_verdieping type H_gen:4750920
Basic Wall:NLRS_22.21_WA_beton prefab d=400_gen:9140673 | 34 vierendertigste verdieping | 22.21 binnenwanden - constructief, massieve wanden (Uniformat) | Model Group:NLRS_01.00_verdieping type H_gen:4750920
Basic Wall:NLRS_22.21_WA_beton prefab d=300_gen:9140676 | 34 vierendertigste verdieping | 22.21 binnenwanden - constructief, massieve wanden (Uniformat) | Model Group:NLRS_01.00_verdieping type H_gen:4750920
Basic Wall:NLRS_22.21_WA_beton prefab d=400_gen:9140679 | 34 vierendertigste verdieping | 22.21 binnenwanden - constructief, massieve wanden (Uniformat) | Model Group:NLRS_01.00_verdieping type H_gen:4750920
Basic Wall:NLRS_22.21_WA_beton prefab d=400_gen:9140682 | 34 vierendertigste verdieping | 22.21 binnenwanden - constructief, massieve wanden (Uniformat) | Model Group:NLRS_01.00_verdieping type H_gen:4750920
Basic Wall:NLRS_22.21_WA_beton prefab d=400_gen:9140685 | 34 vierendertigste verdieping | 22.21 binnenwanden - constructief, massieve wanden (Uniformat) | Model Group:NLRS_01.00_verdieping type H_gen:4750920
Basic Wall:NLRS_22.21_WA_beton prefab d=400_gen:9140688 | 34 vierendertigste verdieping | 22.21 binnenwanden - constructief, massieve wanden (Uniformat) | Model Group:NLRS_01.00_verdieping type H_gen:4750920
2 x Basic Wall:NLRS_22.21_WA_beton prefab d=400_gen:9140692 | 34 vierendertigste verdieping | 22.21 binnenwanden - constructief, massieve wanden (Uniformat) | Model Group:NLRS_01.00_verdieping type H_gen:4750920
2 x Basic Wall:NLRS_22.21_WA_beton prefab d=400_gen:4699555 | 34 vierendertigste verdieping | 22.21 binnenwanden - constructief, massieve wanden (Uniformat) | Model Group:NLRS_01.00_verdieping type H_gen:4750920
2 x Basic Wall:NLRS_22.21_WA_beton prefab d=400_gen:9140695 | 34 vierendertigste verdieping | 22.21 binnenwanden - constructief, massieve wanden (Uniformat) | Model Group:NLRS_01.00_verdieping type H_gen:4750920
2 x Basic Wall:NLRS_22.21_WA_beton prefab d=400_gen:9140697 | 34 vierendertigste verdieping | 22.21 binnenwanden - constructief, massieve wanden (Uniformat) | Model Group:NLRS_01.00_verdieping type H_gen:4750920
Floor:NLRS_23.21_FL_breedplaat d=100/270_gen:9141509:2 | 35 vijfendertigste verdieping | 23.21 vloeren - constructief, vrijdragende vloeren (Uniformat) | Model Group:NLRS_23.21_vloer voor wanden d=300/400_gen:9141516
Basic Wall:NLRS_22.21_WA_beton prefab d=400_gen:9141597 | 35 vijfendertigste verdieping | 22.21 binnenwanden - constructief, massieve wanden (Uniformat) | Model Group:NLRS_01.00_verdieping type J_gen:4751352
Basic Wall:NLRS_22.21_WA_beton prefab d=400_gen:9141599 | 35 vijfendertigste verdieping | 22.21 binnenwanden - constructief, massieve wanden (Uniformat) | Model Group:NLRS_01.00_verdieping type J_gen:4751352
2 x Basic Wall:NLRS_22.21_WA_beton prefab d=400_gen:9141601 | 35 vijfendertigste verdieping | 22.21 binnenwanden - constructief, massieve wanden (Uniformat) | Model Group:NLRS_01.00_verdieping type J_gen:4751352
Basic Wall:NLRS_22.21_WA_beton prefab d=300_gen:9141607 | 35 vijfendertigste verdieping | 22.21 binnenwanden - constructief, massieve wanden (Uniformat) | Model Group:NLRS_01.00_verdieping type J_gen:4751352
2 x Basic Wall:NLRS_22.21_WA_beton prefab d=300_gen:4472952 | 35 vijfendertigste verdieping | 22.21 binnenwanden - constructief, massieve wanden (Uniformat) | Model Group:NLRS_01.00_verdieping type J_gen:4751352
Basic Wall:NLRS_22.21_WA_beton prefab d=400_gen:9141610 | 35 vijfendertigste verdieping | 22.21 binnenwanden - constructief, massieve wanden (Uniformat) | Model Group:NLRS_01.00_verdieping type J_gen:4751352
Basic Wall:NLRS_22.21_WA_beton prefab d=400_gen:9141613 | 35 vijfendertigste verdieping | 22.21 binnenwanden - constructief, massieve wanden (Uniformat) | Model Group:NLRS_01.00_verdieping type J_gen:4751352
Basic Wall:NLRS_22.21_WA_beton prefab d=300_gen:9141616 | 35 vijfendertigste verdieping | 22.21 binnenwanden - constructief, massieve wanden (Uniformat) | Model Group:NLRS_01.00_verdieping type J_gen:4751352
Basic Wall:NLRS_22.21_WA_beton prefab d=400_gen:9141619 | 35 vijfendertigste verdieping | 22.21 binnenwanden - constructief, massieve wanden (Uniformat) | Model Group:NLRS_01.00_verdieping type J_gen:4751352
Basic Wall:NLRS_22.21_WA_beton prefab d=400_gen:9141622 | 35 vijfendertigste verdieping | 22.21 binnenwanden - constructief, massieve wanden (Uniformat) | Model Group:NLRS_01.00_verdieping type J_gen:4751352
Basic Wall:NLRS_22.21_WA_beton prefab d=400_gen:9141625 | 35 vijfendertigste verdieping | 22.21 binnenwanden - constructief, massieve wanden (Uniformat) | Model Group:NLRS_01.00_verdieping type J_gen:4751352
Basic Wall:NLRS_22.21_WA_beton prefab d=400_gen:9141628 | 35 vijfendertigste verdieping | 22.21 binnenwanden - constructief, massieve wanden (Uniformat) | Model Group:NLRS_01.00_verdieping type J_gen:4751352
2 x Basic Wall:NLRS_22.21_WA_beton prefab d=400_gen:9141632 | 35 vijfendertigste verdieping | 22.21 binnenwanden - constructief, massieve wanden (Uniformat) | Model Group:NLRS_01.00_verdieping type J_gen:4751352
2 x Basic Wall:NLRS_22.21_WA_beton prefab d=400_gen:4699555 | 35 vijfendertigste verdieping | 22.21 binnenwanden - constructief, massieve wanden (Uniformat) | Model Group:NLRS_01.00_verdieping type J_gen:4751352
2 x Basic Wall:NLRS_22.21_WA_beton prefab d=400_gen:9141635 | 35 vijfendertigste verdieping | 22.21 binnenwanden - constructief, massieve wanden (Uniformat) | Model Group:NLRS_01.00_verdieping type J_gen:4751352
2 x Basic Wall:NLRS_22.21_WA_beton prefab d=400_gen:9141637 | 35 vijfendertigste verdieping | 22.21 binnenwanden - constructief, massieve wanden (Uniformat) | Model Group:NLRS_01.00_verdieping type J_gen:4751352
Floor:NLRS_23.21_FL_breedplaat d=100/270_gen:9142456:2 | 27 zevenentwintigste verdieping | 23.21 vloeren - constructief, vrijdragende vloeren (Uniformat) | Model Group:NLRS_23.21_vloer voor wanden d=300/400_gen:9142463
Basic Wall:NLRS_22.21_WA_beton prefab d=400_gen:9142544 | 27 zevenentwintigste verdieping | 22.21 binnenwanden - constructief, massieve wanden (Uniformat) | Model Group:NLRS_01.00_verdieping type K_gen:4747896
Basic Wall:NLRS_22.21_WA_beton prefab d=400_gen:9142546 | 27 zevenentwintigste verdieping | 22.21 binnenwanden - constructief, massieve wanden (Uniformat) | Model Group:NLRS_01.00_verdieping type K_gen:4747896
2 x Basic Wall:NLRS_22.21_WA_beton prefab d=400_gen:9142548 | 27 zevenentwintigste verdieping | 22.21 binnenwanden - constructief, massieve wanden (Uniformat) | Model Group:NLRS_01.00_verdieping type K_gen:4747896
Basic Wall:NLRS_22.21_WA_beton prefab d=300_gen:9142554 | 27 zevenentwintigste verdieping | 22.21 binnenwanden - constructief, massieve wanden (Uniformat) | Model Group:NLRS_01.00_verdieping type K_gen:4747896
2 x Basic Wall:NLRS_22.21_WA_beton prefab d=300_gen:4472952 | 27 zevenentwintigste verdieping | 22.21 binnenwanden - constructief, massieve wanden (Uniformat) | Model Group:NLRS_01.00_verdieping type K_gen:4747896
Basic Wall:NLRS_22.21_WA_beton prefab d=400_gen:9142557 | 27 zevenentwintigste verdieping | 22.21 binnenwanden - constructief, massieve wanden (Uniformat) | Model Group:NLRS_01.00_verdieping type K_gen:4747896
Basic Wall:NLRS_22.21_WA_beton prefab d=400_gen:9142560 | 27 zevenentwintigste verdieping | 22.21 binnenwanden - constructief, massieve wanden (Uniformat) | Model Group:NLRS_01.00_verdieping type K_gen:4747896
Basic Wall:NLRS_22.21_WA_beton prefab d=300_gen:9142563 | 27 zevenentwintigste verdieping | 22.21 binnenwanden - constructief, massieve wanden (Uniformat) | Model Group:NLRS_01.00_verdieping type K_gen:4747896
Basic Wall:NLRS_22.21_WA_beton prefab d=400_gen:9142566 | 27 zevenentwintigste verdieping | 22.21 binnenwanden - constructief, massieve wanden (Uniformat) | Model Group:NLRS_01.00_verdieping type K_gen:4747896
Basic Wall:NLRS_22.21_WA_beton prefab d=400_gen:9142569 | 27 zevenentwintigste verdieping | 22.21 binnenwanden - constructief, massieve wanden (Uniformat) | Model Group:NLRS_01.00_verdieping type K_gen:4747896
Basic Wall:NLRS_22.21_WA_beton prefab d=400_gen:9142572 | 27 zevenentwintigste verdieping | 22.21 binnenwanden - constructief, massieve wanden (Uniformat) | Model Group:NLRS_01.00_verdieping type K_gen:4747896
Basic Wall:NLRS_22.21_WA_beton prefab d=400_gen:9142575 | 27 zevenentwintigste verdieping | 22.21 binnenwanden - constructief, massieve wanden (Uniformat) | Model Group:NLRS_01.00_verdieping type K_gen:4747896
2 x Basic Wall:NLRS_22.21_WA_beton prefab d=400_gen:9142579 | 27 zevenentwintigste verdieping | 22.21 binnenwanden - constructief, massieve wanden (Uniformat) | Model Group:NLRS_01.00_verdieping type K_gen:4747896
2 x Basic Wall:NLRS_22.21_WA_beton prefab d=400_gen:4699555 | 27 zevenentwintigste verdieping | 22.21 binnenwanden - constructief, massieve wanden (Uniformat) | Model Group:NLRS_01.00_verdieping type K_gen:4747896
2 x Basic Wall:NLRS_22.21_WA_beton prefab d=400_gen:9142582 | 27 zevenentwintigste verdieping | 22.21 binnenwanden - constructief, massieve wanden (Uniformat) | Model Group:NLRS_01.00_verdieping type K_gen:4747896
2 x Basic Wall:NLRS_22.21_WA_beton prefab d=400_gen:9142584 | 27 zevenentwintigste verdieping | 22.21 binnenwanden - constructief, massieve wanden (Uniformat) | Model Group:NLRS_01.00_verdieping type K_gen:4747896
Floor:NLRS_23.21_FL_breedplaat d=100/270_gen:9142746:2 | 38 achtendertigste verdieping | 23.21 vloeren - constructief, vrijdragende vloeren (Uniformat) | Model Group:NLRS_23.21_vloer voor wanden d=300/400_gen:9142753
Basic Wall:NLRS_22.21_WA_beton prefab d=400_gen:9142834 | 38 achtendertigste verdieping | 22.21 binnenwanden - constructief, massieve wanden (Uniformat) | Model Group:NLRS_01.00_verdieping type K_gen:4752648
Basic Wall:NLRS_22.21_WA_beton prefab d=400_gen:9142836 | 38 achtendertigste verdieping | 22.21 binnenwanden - constructief, massieve wanden (Uniformat) | Model Group:NLRS_01.00_verdieping type K_gen:4752648
2 x Basic Wall:NLRS_22.21_WA_beton prefab d=400_gen:9142838 | 38 achtendertigste verdieping | 22.21 binnenwanden - constructief, massieve wanden (Uniformat) | Model Group:NLRS_01.00_verdieping type K_gen:4752648
Basic Wall:NLRS_22.21_WA_beton prefab d=300_gen:9142844 | 38 achtendertigste verdieping | 22.21 binnenwanden - constructief, massieve wanden (Uniformat) | Model Group:NLRS_01.00_verdieping type K_gen:4752648
2 x Basic Wall:NLRS_22.21_WA_beton prefab d=300_gen:4472952 | 38 achtendertigste verdieping | 22.21 binnenwanden - constructief, massieve wanden (Uniformat) | Model Group:NLRS_01.00_verdieping type K_gen:4752648
Basic Wall:NLRS_22.21_WA_beton prefab d=400_gen:9142847 | 38 achtendertigste verdieping | 22.21 binnenwanden - constructief, massieve wanden (Uniformat) | Model Group:NLRS_01.00_verdieping type K_gen:4752648
Basic Wall:NLRS_22.21_WA_beton prefab d=400_gen:9142850 | 38 achtendertigste verdieping | 22.21 binnenwanden - constructief, massieve wanden (Uniformat) | Model Group:NLRS_01.00_verdieping type K_gen:4752648
Basic Wall:NLRS_22.21_WA_beton prefab d=300_gen:9142853 | 38 achtendertigste verdieping | 22.21 binnenwanden - constructief, massieve wanden (Uniformat) | Model Group:NLRS_01.00_verdieping type K_gen:4752648
Basic Wall:NLRS_22.21_WA_beton prefab d=400_gen:9142856 | 38 achtendertigste verdieping | 22.21 binnenwanden - constructief, massieve wanden (Uniformat) | Model Group:NLRS_01.00_verdieping type K_gen:4752648
Basic Wall:NLRS_22.21_WA_beton prefab d=400_gen:9142859 | 38 achtendertigste verdieping | 22.21 binnenwanden - constructief, massieve wanden (Uniformat) | Model Group:NLRS_01.00_verdieping type K_gen:4752648
Basic Wall:NLRS_22.21_WA_beton prefab d=400_gen:9142862 | 38 achtendertigste verdieping | 22.21 binnenwanden - constructief, massieve wanden (Uniformat) | Model Group:NLRS_01.00_verdieping type K_gen:4752648
Basic Wall:NLRS_22.21_WA_beton prefab d=400_gen:9142865 | 38 achtendertigste verdieping | 22.21 binnenwanden - constructief, massieve wanden (Uniformat) | Model Group:NLRS_01.00_verdieping type K_gen:4752648
2 x Basic Wall:NLRS_22.21_WA_beton prefab d=400_gen:9142869 | 38 achtendertigste verdieping | 22.21 binnenwanden - constructief, massieve wanden (Uniformat) | Model Group:NLRS_01.00_verdieping type K_gen:4752648
2 x Basic Wall:NLRS_22.21_WA_beton prefab d=400_gen:4699555 | 38 achtendertigste verdieping | 22.21 binnenwanden - constructief, massieve wanden (Uniformat) | Model Group:NLRS_01.00_verdieping type K_gen:4752648
2 x Basic Wall:NLRS_22.21_WA_beton prefab d=400_gen:9142872 | 38 achtendertigste verdieping | 22.21 binnenwanden - constructief, massieve wanden (Uniformat) | Model Group:NLRS_01.00_verdieping type K_gen:4752648
2 x Basic Wall:NLRS_22.21_WA_beton prefab d=400_gen:9142874 | 38 achtendertigste verdieping | 22.21 binnenwanden - constructief, massieve wanden (Uniformat) | Model Group:NLRS_01.00_verdieping type K_gen:4752648
Floor:NLRS_23.21_FL_breedplaat d=100/270_gen:9143036:2 | 39 negenendertigste verdieping | 23.21 vloeren - constructief, vrijdragende vloeren (Uniformat) | Model Group:NLRS_23.21_vloer voor wanden d=300/400_gen:9143043
Basic Wall:NLRS_22.21_WA_beton prefab d=400_gen:9143124 | 39 negenendertigste verdieping | 22.21 binnenwanden - constructief, massieve wanden (Uniformat) | Model Group:NLRS_01.00_verdieping type K_gen:4753080
Basic Wall:NLRS_22.21_WA_beton prefab d=400_gen:9143126 | 39 negenendertigste verdieping | 22.21 binnenwanden - constructief, massieve wanden (Uniformat) | Model Group:NLRS_01.00_verdieping type K_gen:4753080
2 x Basic Wall:NLRS_22.21_WA_beton prefab d=400_gen:9143128 | 39 negenendertigste verdieping | 22.21 binnenwanden - constructief, massieve wanden (Uniformat) | Model Group:NLRS_01.00_verdieping type K_gen:4753080
Basic Wall:NLRS_22.21_WA_beton prefab d=300_gen:9143134 | 39 negenendertigste verdieping | 22.21 binnenwanden - constructief, massieve wanden (Uniformat) | Model Group:NLRS_01.00_verdieping type K_gen:4753080
2 x Basic Wall:NLRS_22.21_WA_beton prefab d=300_gen:4472952 | 39 negenendertigste verdieping | 22.21 binnenwanden - constructief, massieve wanden (Uniformat) | Model Group:NLRS_01.00_verdieping type K_gen:4753080
Basic Wall:NLRS_22.21_WA_beton prefab d=400_gen:9143137 | 39 negenendertigste verdieping | 22.21 binnenwanden - constructief, massieve wanden (Uniformat) | Model Group:NLRS_01.00_verdieping type K_gen:4753080
Basic Wall:NLRS_22.21_WA_beton prefab d=400_gen:9143140 | 39 negenendertigste verdieping | 22.21 binnenwanden - constructief, massieve wanden (Uniformat) | Model Group:NLRS_01.00_verdieping type K_gen:4753080
Basic Wall:NLRS_22.21_WA_beton prefab d=300_gen:9143143 | 39 negenendertigste verdieping | 22.21 binnenwanden - constructief, massieve wanden (Uniformat) | Model Group:NLRS_01.00_verdieping type K_gen:4753080
Basic Wall:NLRS_22.21_WA_beton prefab d=400_gen:9143146 | 39 negenendertigste verdieping | 22.21 binnenwanden - constructief, massieve wanden (Uniformat) | Model Group:NLRS_01.00_verdieping type K_gen:4753080
Basic Wall:NLRS_22.21_WA_beton prefab d=400_gen:9143149 | 39 negenendertigste verdieping | 22.21 binnenwanden - constructief, massieve wanden (Uniformat) | Model Group:NLRS_01.00_verdieping type K_gen:4753080
Basic Wall:NLRS_22.21_WA_beton prefab d=400_gen:9143152 | 39 negenendertigste verdieping | 22.21 binnenwanden - constructief, massieve wanden (Uniformat) | Model Group:NLRS_01.00_verdieping type K_gen:4753080
Basic Wall:NLRS_22.21_WA_beton prefab d=400_gen:9143155 | 39 negenendertigste verdieping | 22.21 binnenwanden - constructief, massieve wanden (Uniformat) | Model Group:NLRS_01.00_verdieping type K_gen:4753080
2 x Basic Wall:NLRS_22.21_WA_beton prefab d=400_gen:9143159 | 39 negenendertigste verdieping | 22.21 binnenwanden - constructief, massieve wanden (Uniformat) | Model Group:NLRS_01.00_verdieping type K_gen:4753080
2 x Basic Wall:NLRS_22.21_WA_beton prefab d=400_gen:4699555 | 39 negenendertigste verdieping | 22.21 binnenwanden - constructief, massieve wanden (Uniformat) | Model Group:NLRS_01.00_verdieping type K_gen:4753080
2 x Basic Wall:NLRS_22.21_WA_beton prefab d=400_gen:9143162 | 39 negenendertigste verdieping | 22.21 binnenwanden - constructief, massieve wanden (Uniformat) | Model Group:NLRS_01.00_verdieping type K_gen:4753080
2 x Basic Wall:NLRS_22.21_WA_beton prefab d=400_gen:9143164 | 39 negenendertigste verdieping | 22.21 binnenwanden - constructief, massieve wanden (Uniformat) | Model Group:NLRS_01.00_verdieping type K_gen:4753080
Floor:NLRS_23.21_FL_breedplaat d=100/270_gen:9145278:2 | 36 zesendertigste verdieping | 23.21 vloeren - constructief, vrijdragende vloeren (Uniformat) | Model Group:NLRS_23.21_vloer voor wanden d=300/400_gen:9145285
Basic Wall:NLRS_22.21_WA_beton prefab d=400_gen:9145366 | 36 zesendertigste verdieping | 22.21 binnenwanden - constructief, massieve wanden (Uniformat) | Model Group:NLRS_01.00_verdieping type K_gen:4751784
Basic Wall:NLRS_22.21_WA_beton prefab d=400_gen:9145368 | 36 zesendertigste verdieping | 22.21 binnenwanden - constructief, massieve wanden (Uniformat) | Model Group:NLRS_01.00_verdieping type K_gen:4751784
2 x Basic Wall:NLRS_22.21_WA_beton prefab d=400_gen:9145370 | 36 zesendertigste verdieping | 22.21 binnenwanden - constructief, massieve wanden (Uniformat) | Model Group:NLRS_01.00_verdieping type K_gen:4751784
Basic Wall:NLRS_22.21_WA_beton prefab d=300_gen:9145376 | 36 zesendertigste verdieping | 22.21 binnenwanden - constructief, massieve wanden (Uniformat) | Model Group:NLRS_01.00_verdieping type K_gen:4751784
2 x Basic Wall:NLRS_22.21_WA_beton prefab d=300_gen:4472952 | 36 zesendertigste verdieping | 22.21 binnenwanden - constructief, massieve wanden (Uniformat) | Model Group:NLRS_01.00_verdieping type K_gen:4751784
Basic Wall:NLRS_22.21_WA_beton prefab d=400_gen:9145379 | 36 zesendertigste verdieping | 22.21 binnenwanden - constructief, massieve wanden (Uniformat) | Model Group:NLRS_01.00_verdieping type K_gen:4751784
Basic Wall:NLRS_22.21_WA_beton prefab d=400_gen:9145382 | 36 zesendertigste verdieping | 22.21 binnenwanden - constructief, massieve wanden (Uniformat) | Model Group:NLRS_01.00_verdieping type K_gen:4751784
Basic Wall:NLRS_22.21_WA_beton prefab d=300_gen:9145385 | 36 zesendertigste verdieping | 22.21 binnenwanden - constructief, massieve wanden (Uniformat) | Model Group:NLRS_01.00_verdieping type K_gen:4751784
Basic Wall:NLRS_22.21_WA_beton prefab d=400_gen:9145388 | 36 zesendertigste verdieping | 22.21 binnenwanden - constructief, massieve wanden (Uniformat) | Model Group:NLRS_01.00_verdieping type K_gen:4751784
Basic Wall:NLRS_22.21_WA_beton prefab d=400_gen:9145391 | 36 zesendertigste verdieping | 22.21 binnenwanden - constructief, massieve wanden (Uniformat) | Model Group:NLRS_01.00_verdieping type K_gen:4751784
Basic Wall:NLRS_22.21_WA_beton prefab d=400_gen:9145394 | 36 zesendertigste verdieping | 22.21 binnenwanden - constructief, massieve wanden (Uniformat) | Model Group:NLRS_01.00_verdieping type K_gen:4751784
Basic Wall:NLRS_22.21_WA_beton prefab d=400_gen:9145397 | 36 zesendertigste verdieping | 22.21 binnenwanden - constructief, massieve wanden (Uniformat) | Model Group:NLRS_01.00_verdieping type K_gen:4751784
2 x Basic Wall:NLRS_22.21_WA_beton prefab d=400_gen:9145401 | 36 zesendertigste verdieping | 22.21 binnenwanden - constructief, massieve wanden (Uniformat) | Model Group:NLRS_01.00_verdieping type K_gen:4751784
2 x Basic Wall:NLRS_22.21_WA_beton prefab d=400_gen:4699555 | 36 zesendertigste verdieping | 22.21 binnenwanden - constructief, massieve wanden (Uniformat) | Model Group:NLRS_01.00_verdieping type K_gen:4751784
2 x Basic Wall:NLRS_22.21_WA_beton prefab d=400_gen:9145404 | 36 zesendertigste verdieping | 22.21 binnenwanden - constructief, massieve wanden (Uniformat) | Model Group:NLRS_01.00_verdieping type K_gen:4751784
2 x Basic Wall:NLRS_22.21_WA_beton prefab d=400_gen:9145406 | 36 zesendertigste verdieping | 22.21 binnenwanden - constructief, massieve wanden (Uniformat) | Model Group:NLRS_01.00_verdieping type K_gen:4751784
Floor:NLRS_23.21_FL_breedplaat d=100/270_gen:9145568:2 | 37 zevenendertigste verdieping | 23.21 vloeren - constructief, vrijdragende vloeren (Uniformat) | Model Group:NLRS_23.21_vloer voor wanden d=300/400_gen:9145575
Basic Wall:NLRS_22.21_WA_beton prefab d=400_gen:9145656 | 37 zevenendertigste verdieping | 22.21 binnenwanden - constructief, massieve wanden (Uniformat) | Model Group:NLRS_01.00_verdieping type K_gen:4752216
Basic Wall:NLRS_22.21_WA_beton prefab d=400_gen:9145658 | 37 zevenendertigste verdieping | 22.21 binnenwanden - constructief, massieve wanden (Uniformat) | Model Group:NLRS_01.00_verdieping type K_gen:4752216
2 x Basic Wall:NLRS_22.21_WA_beton prefab d=400_gen:9145660 | 37 zevenendertigste verdieping | 22.21 binnenwanden - constructief, massieve wanden (Uniformat) | Model Group:NLRS_01.00_verdieping type K_gen:4752216
Basic Wall:NLRS_22.21_WA_beton prefab d=300_gen:9145666 | 37 zevenendertigste verdieping | 22.21 binnenwanden - constructief, massieve wanden (Uniformat) | Model Group:NLRS_01.00_verdieping type K_gen:4752216
2 x Basic Wall:NLRS_22.21_WA_beton prefab d=300_gen:4472952 | 37 zevenendertigste verdieping | 22.21 binnenwanden - constructief, massieve wanden (Uniformat) | Model Group:NLRS_01.00_verdieping type K_gen:4752216
Basic Wall:NLRS_22.21_WA_beton prefab d=400_gen:9145669 | 37 zevenendertigste verdieping | 22.21 binnenwanden - constructief, massieve wanden (Uniformat) | Model Group:NLRS_01.00_verdieping type K_gen:4752216
Basic Wall:NLRS_22.21_WA_beton prefab d=400_gen:9145672 | 37 zevenendertigste verdieping | 22.21 binnenwanden - constructief, massieve wanden (Uniformat) | Model Group:NLRS_01.00_verdieping type K_gen:4752216
Basic Wall:NLRS_22.21_WA_beton prefab d=300_gen:9145675 | 37 zevenendertigste verdieping | 22.21 binnenwanden - constructief, massieve wanden (Uniformat) | Model Group:NLRS_01.00_verdieping type K_gen:4752216
Basic Wall:NLRS_22.21_WA_beton prefab d=400_gen:9145678 | 37 zevenendertigste verdieping | 22.21 binnenwanden - constructief, massieve wanden (Uniformat) | Model Group:NLRS_01.00_verdieping type K_gen:4752216
Basic Wall:NLRS_22.21_WA_beton prefab d=400_gen:9145681 | 37 zevenendertigste verdieping | 22.21 binnenwanden - constructief, massieve wanden (Uniformat) | Model Group:NLRS_01.00_verdieping type K_gen:4752216
Basic Wall:NLRS_22.21_WA_beton prefab d=400_gen:9145684 | 37 zevenendertigste verdieping | 22.21 binnenwanden - constructief, massieve wanden (Uniformat) | Model Group:NLRS_01.00_verdieping type K_gen:4752216
Basic Wall:NLRS_22.21_WA_beton prefab d=400_gen:9145687 | 37 zevenendertigste verdieping | 22.21 binnenwanden - constructief, massieve wanden (Uniformat) | Model Group:NLRS_01.00_verdieping type K_gen:4752216
2 x Basic Wall:NLRS_22.21_WA_beton prefab d=400_gen:9145691 | 37 zevenendertigste verdieping | 22.21 binnenwanden - constructief, massieve wanden (Uniformat) | Model Group:NLRS_01.00_verdieping type K_gen:4752216
2 x Basic Wall:NLRS_22.21_WA_beton prefab d=400_gen:4699555 | 37 zevenendertigste verdieping | 22.21 binnenwanden - constructief, massieve wanden (Uniformat) | Model Group:NLRS_01.00_verdieping type K_gen:4752216
2 x Basic Wall:NLRS_22.21_WA_beton prefab d=400_gen:9145694 | 37 zevenendertigste verdieping | 22.21 binnenwanden - constructief, massieve wanden (Uniformat) | Model Group:NLRS_01.00_verdieping type K_gen:4752216
2 x Basic Wall:NLRS_22.21_WA_beton prefab d=400_gen:9145696 | 37 zevenendertigste verdieping | 22.21 binnenwanden - constructief, massieve wanden (Uniformat) | Model Group:NLRS_01.00_verdieping type K_gen:4752216
Floor:NLRS_23.21_FL_breedplaat d=100/270_gen:9147157:2 | 40 veertigste verdieping | 23.21 vloeren - constructief, vrijdragende vloeren (Uniformat) | Model Group:NLRS_23.21_vloer voor wanden d=300/400_gen:9147164
Basic Wall:NLRS_22.21_WA_beton prefab d=400_gen:9147245 | 40 veertigste verdieping | 22.21 binnenwanden - constructief, massieve wanden (Uniformat) | Model Group:NLRS_01.00_verdieping (type L)_gen:4753512
Basic Wall:NLRS_22.21_WA_beton prefab d=400_gen:9147247 | 40 veertigste verdieping | 22.21 binnenwanden - constructief, massieve wanden (Uniformat) | Model Group:NLRS_01.00_verdieping (type L)_gen:4753512
2 x Basic Wall:NLRS_22.21_WA_beton prefab d=400_gen:9147249 | 40 veertigste verdieping | 22.21 binnenwanden - constructief, massieve wanden (Uniformat) | Model Group:NLRS_01.00_verdieping (type L)_gen:4753512
Basic Wall:NLRS_22.21_WA_beton prefab d=300_gen:9147255 | 40 veertigste verdieping | 22.21 binnenwanden - constructief, massieve wanden (Uniformat) | Model Group:NLRS_01.00_verdieping (type L)_gen:4753512
2 x Basic Wall:NLRS_22.21_WA_beton prefab d=300_gen:4472952 | 40 veertigste verdieping | 22.21 binnenwanden - constructief, massieve wanden (Uniformat) | Model Group:NLRS_01.00_verdieping (type L)_gen:4753512
Basic Wall:NLRS_22.21_WA_beton prefab d=400_gen:9147258 | 40 veertigste verdieping | 22.21 binnenwanden - constructief, massieve wanden (Uniformat) | Model Group:NLRS_01.00_verdieping (type L)_gen:4753512
Basic Wall:NLRS_22.21_WA_beton prefab d=400_gen:9147261 | 40 veertigste verdieping | 22.21 binnenwanden - constructief, massieve wanden (Uniformat) | Model Group:NLRS_01.00_verdieping (type L)_gen:4753512
Basic Wall:NLRS_22.21_WA_beton prefab d=300_gen:9147264 | 40 veertigste verdieping | 22.21 binnenwanden - constructief, massieve wanden (Uniformat) | Model Group:NLRS_01.00_verdieping (type L)_gen:4753512
Basic Wall:NLRS_22.21_WA_beton prefab d=400_gen:9147267 | 40 veertigste verdieping | 22.21 binnenwanden - constructief, massieve wanden (Uniformat) | Model Group:NLRS_01.00_verdieping (type L)_gen:4753512
Basic Wall:NLRS_22.21_WA_beton prefab d=400_gen:9147270 | 40 veertigste verdieping | 22.21 binnenwanden - constructief, massieve wanden (Uniformat) | Model Group:NLRS_01.00_verdieping (type L)_gen:4753512
Basic Wall:NLRS_22.21_WA_beton prefab d=400_gen:9147273 | 40 veertigste verdieping | 22.21 binnenwanden - constructief, massieve wanden (Uniformat) | Model Group:NLRS_01.00_verdieping (type L)_gen:4753512
Basic Wall:NLRS_22.21_WA_beton prefab d=400_gen:9147276 | 40 veertigste verdieping | 22.21 binnenwanden - constructief, massieve wanden (Uniformat) | Model Group:NLRS_01.00_verdieping (type L)_gen:4753512
2 x Basic Wall:NLRS_22.21_WA_beton prefab d=400_gen:9147280 | 40 veertigste verdieping | 22.21 binnenwanden - constructief, massieve wanden (Uniformat) | Model Group:NLRS_01.00_verdieping (type L)_gen:4753512
2 x Basic Wall:NLRS_22.21_WA_beton prefab d=400_gen:4699555 | 40 veertigste verdieping | 22.21 binnenwanden - constructief, massieve wanden (Uniformat) | Model Group:NLRS_01.00_verdieping (type L)_gen:4753512
2 x Basic Wall:NLRS_22.21_WA_beton prefab d=400_gen:9147283 | 40 veertigste verdieping | 22.21 binnenwanden - constructief, massieve wanden (Uniformat) | Model Group:NLRS_01.00_verdieping (type L)_gen:4753512
2 x Basic Wall:NLRS_22.21_WA_beton prefab d=400_gen:9147285 | 40 veertigste verdieping | 22.21 binnenwanden - constructief, massieve wanden (Uniformat) | Model Group:NLRS_01.00_verdieping (type L)_gen:4753512
Basic Wall:NLRS_22.21_WA_beton prefab d=300_gen:9148119 | 43 drieënveertigste verdieping | 22.21 binnenwanden - constructief, massieve wanden (Uniformat) | Model Group:NLRS_01.00_verdieping type N_gen:4788726
Basic Wall:NLRS_22.21_WA_beton prefab d=300_gen:9148121 | 43 drieënveertigste verdieping | 22.21 binnenwanden - constructief, massieve wanden (Uniformat) | Model Group:NLRS_01.00_verdieping type N_gen:4788726
2 x Basic Wall:NLRS_22.21_WA_beton prefab d=300_gen:9148123 | 43 drieënveertigste verdieping | 22.21 binnenwanden - constructief, massieve wanden (Uniformat) | Model Group:NLRS_01.00_verdieping type N_gen:4788726
Basic Wall:NLRS_22.21_WA_beton prefab d=300_gen:9148129 | 43 drieënveertigste verdieping | 22.21 binnenwanden - constructief, massieve wanden (Uniformat) | Model Group:NLRS_01.00_verdieping type N_gen:4788726
4 x Basic Wall:NLRS_22.21_WA_beton prefab d=300_gen:4472952 | 43 drieënveertigste verdieping | 22.21 binnenwanden - constructief, massieve wanden (Uniformat) | Model Group:NLRS_01.00_verdieping type N_gen:4788726
Basic Wall:NLRS_22.21_WA_beton prefab d=300_gen:9148132 | 43 drieënveertigste verdieping | 22.21 binnenwanden - constructief, massieve wanden (Uniformat) | Model Group:NLRS_01.00_verdieping type N_gen:4788726
Basic Wall:NLRS_22.21_WA_beton prefab d=300_gen:9148135 | 43 drieënveertigste verdieping | 22.21 binnenwanden - constructief, massieve wanden (Uniformat) | Model Group:NLRS_01.00_verdieping type N_gen:4788726
Basic Wall:NLRS_22.21_WA_beton prefab d=300_gen:9148138 | 43 drieënveertigste verdieping | 22.21 binnenwanden - constructief, massieve wanden (Uniformat) | Model Group:NLRS_01.00_verdieping type N_gen:4788726
Basic Wall:NLRS_22.21_WA_beton prefab d=300_gen:9148141 | 43 drieënveertigste verdieping | 22.21 binnenwanden - constructief, massieve wanden (Uniformat) | Model Group:NLRS_01.00_verdieping type N_gen:4788726
Basic Wall:NLRS_22.21_WA_beton prefab d=300_gen:9148144 | 43 drieënveertigste verdieping | 22.21 binnenwanden - constructief, massieve wanden (Uniformat) | Model Group:NLRS_01.00_verdieping type N_gen:4788726
Basic Wall:NLRS_22.21_WA_beton prefab d=300_gen:9148147 | 43 drieënveertigste verdieping | 22.21 binnenwanden - constructief, massieve wanden (Uniformat) | Model Group:NLRS_01.00_verdieping type N_gen:4788726
Basic Wall:NLRS_22.21_WA_beton prefab d=300_gen:9148150 | 43 drieënveertigste verdieping | 22.21 binnenwanden - constructief, massieve wanden (Uniformat) | Model Group:NLRS_01.00_verdieping type N_gen:4788726
2 x Basic Wall:NLRS_22.21_WA_beton prefab d=300_gen:9148154 | 43 drieënveertigste verdieping | 22.21 binnenwanden - constructief, massieve wanden (Uniformat) | Model Group:NLRS_01.00_verdieping type N_gen:4788726
2 x Basic Wall:NLRS_22.21_WA_beton prefab d=300_gen:9148157 | 43 drieënveertigste verdieping | 22.21 binnenwanden - constructief, massieve wanden (Uniformat) | Model Group:NLRS_01.00_verdieping type N_gen:4788726
2 x Basic Wall:NLRS_22.21_WA_beton prefab d=300_gen:9148159 | 43 drieënveertigste verdieping | 22.21 binnenwanden - constructief, massieve wanden (Uniformat) | Model Group:NLRS_01.00_verdieping type N_gen:4788726
Floor:NLRS_23.21_FL_vloer d=270_gen:9148282:2 | 43 drieënveertigste verdieping | 23.21 vloeren - constructief, vrijdragende vloeren (Uniformat) | Model Group:NLRS_23.21_vloer voor wanden d=300/300_gen:9148289
Basic Wall:NLRS_22.21_WA_beton prefab d=300_gen:9148411 | 44 vierenveertigste verdieping | 22.21 binnenwanden - constructief, massieve wanden (Uniformat) | Model Group:NLRS_01.00_verdieping type N_44e verdieping_gen:4789158
Basic Wall:NLRS_22.21_WA_beton prefab d=300_gen:9148413 | 44 vierenveertigste verdieping | 22.21 binnenwanden - constructief, massieve wanden (Uniformat) | Model Group:NLRS_01.00_verdieping type N_44e verdieping_gen:4789158
2 x Basic Wall:NLRS_22.21_WA_beton prefab d=300_gen:9148415 | 44 vierenveertigste verdieping | 22.21 binnenwanden - constructief, massieve wanden (Uniformat) | Model Group:NLRS_01.00_verdieping type N_44e verdieping_gen:4789158
Basic Wall:NLRS_22.21_WA_beton prefab d=300_gen:9148421 | 44 vierenveertigste verdieping | 22.21 binnenwanden - constructief, massieve wanden (Uniformat) | Model Group:NLRS_01.00_verdieping type N_44e verdieping_gen:4789158
4 x Basic Wall:NLRS_22.21_WA_beton prefab d=300_gen:4472952 | 44 vierenveertigste verdieping | 22.21 binnenwanden - constructief, massieve wanden (Uniformat) | Model Group:NLRS_01.00_verdieping type N_44e verdieping_gen:4789158
Basic Wall:NLRS_22.21_WA_beton prefab d=300_gen:9148424 | 44 vierenveertigste verdieping | 22.21 binnenwanden - constructief, massieve wanden (Uniformat) | Model Group:NLRS_01.00_verdieping type N_44e verdieping_gen:4789158
Basic Wall:NLRS_22.21_WA_beton prefab d=300_gen:9148427 | 44 vierenveertigste verdieping | 22.21 binnenwanden - constructief, massieve wanden (Uniformat) | Model Group:NLRS_01.00_verdieping type N_44e verdieping_gen:4789158
Basic Wall:NLRS_22.21_WA_beton prefab d=300_gen:9148430 | 44 vierenveertigste verdieping | 22.21 binnenwanden - constructief, massieve wanden (Uniformat) | Model Group:NLRS_01.00_verdieping type N_44e verdieping_gen:4789158
Basic Wall:NLRS_22.21_WA_beton prefab d=300_gen:9148433 | 44 vierenveertigste verdieping | 22.21 binnenwanden - constructief, massieve wanden (Uniformat) | Model Group:NLRS_01.00_verdieping type N_44e verdieping_gen:4789158
Basic Wall:NLRS_22.21_WA_beton prefab d=300_gen:9148436 | 44 vierenveertigste verdieping | 22.21 binnenwanden - constructief, massieve wanden (Uniformat) | Model Group:NLRS_01.00_verdieping type N_44e verdieping_gen:4789158
Basic Wall:NLRS_22.21_WA_beton prefab d=300_gen:9148439 | 44 vierenveertigste verdieping | 22.21 binnenwanden - constructief, massieve wanden (Uniformat) | Model Group:NLRS_01.00_verdieping type N_44e verdieping_gen:4789158
Basic Wall:NLRS_22.21_WA_beton prefab d=300_gen:9148442 | 44 vierenveertigste verdieping | 22.21 binnenwanden - constructief, massieve wanden (Uniformat) | Model Group:NLRS_01.00_verdieping type N_44e verdieping_gen:4789158
2 x Basic Wall:NLRS_22.21_WA_beton prefab d=300_gen:9148446 | 44 vierenveertigste verdieping | 22.21 binnenwanden - constructief, massieve wanden (Uniformat) | Model Group:NLRS_01.00_verdieping type N_44e verdieping_gen:4789158
2 x Basic Wall:NLRS_22.21_WA_beton prefab d=300_gen:9148449 | 44 vierenveertigste verdieping | 22.21 binnenwanden - constructief, massieve wanden (Uniformat) | Model Group:NLRS_01.00_verdieping type N_44e verdieping_gen:4789158
2 x Basic Wall:NLRS_22.21_WA_beton prefab d=300_gen:9148451 | 44 vierenveertigste verdieping | 22.21 binnenwanden - constructief, massieve wanden (Uniformat) | Model Group:NLRS_01.00_verdieping type N_44e verdieping_gen:4789158
Floor:NLRS_23.21_FL_vloer d=270_gen:9148574:2 | 44 vierenveertigste verdieping | 23.21 vloeren - constructief, vrijdragende vloeren (Uniformat) | Model Group:NLRS_23.21_vloer voor wanden d=300/300_gen:9148581
Basic Wall:NLRS_22.21_WA_beton prefab d=300_gen:9148703 | 45 vijfenveertigste verdieping | 22.21 binnenwanden - constructief, massieve wanden (Uniformat) | Model Group:NLRS_01.00_verdieping type N_gen:4789590
Basic Wall:NLRS_22.21_WA_beton prefab d=300_gen:9148705 | 45 vijfenveertigste verdieping | 22.21 binnenwanden - constructief, massieve wanden (Uniformat) | Model Group:NLRS_01.00_verdieping type N_gen:4789590
2 x Basic Wall:NLRS_22.21_WA_beton prefab d=300_gen:9148707 | 45 vijfenveertigste verdieping | 22.21 binnenwanden - constructief, massieve wanden (Uniformat) | Model Group:NLRS_01.00_verdieping type N_gen:4789590
Basic Wall:NLRS_22.21_WA_beton prefab d=300_gen:9148713 | 45 vijfenveertigste verdieping | 22.21 binnenwanden - constructief, massieve wanden (Uniformat) | Model Group:NLRS_01.00_verdieping type N_gen:4789590
4 x Basic Wall:NLRS_22.21_WA_beton prefab d=300_gen:4472952 | 45 vijfenveertigste verdieping | 22.21 binnenwanden - constructief, massieve wanden (Uniformat) | Model Group:NLRS_01.00_verdieping type N_gen:4789590
Basic Wall:NLRS_22.21_WA_beton prefab d=300_gen:9148716 | 45 vijfenveertigste verdieping | 22.21 binnenwanden - constructief, massieve wanden (Uniformat) | Model Group:NLRS_01.00_verdieping type N_gen:4789590
Basic Wall:NLRS_22.21_WA_beton prefab d=300_gen:9148719 | 45 vijfenveertigste verdieping | 22.21 binnenwanden - constructief, massieve wanden (Uniformat) | Model Group:NLRS_01.00_verdieping type N_gen:4789590
Basic Wall:NLRS_22.21_WA_beton prefab d=300_gen:9148722 | 45 vijfenveertigste verdieping | 22.21 binnenwanden - constructief, massieve wanden (Uniformat) | Model Group:NLRS_01.00_verdieping type N_gen:4789590
Basic Wall:NLRS_22.21_WA_beton prefab d=300_gen:9148725 | 45 vijfenveertigste verdieping | 22.21 binnenwanden - constructief, massieve wanden (Uniformat) | Model Group:NLRS_01.00_verdieping type N_gen:4789590
Basic Wall:NLRS_22.21_WA_beton prefab d=300_gen:9148728 | 45 vijfenveertigste verdieping | 22.21 binnenwanden - constructief, massieve wanden (Uniformat) | Model Group:NLRS_01.00_verdieping type N_gen:4789590
Basic Wall:NLRS_22.21_WA_beton prefab d=300_gen:9148731 | 45 vijfenveertigste verdieping | 22.21 binnenwanden - constructief, massieve wanden (Uniformat) | Model Group:NLRS_01.00_verdieping type N_gen:4789590
Basic Wall:NLRS_22.21_WA_beton prefab d=300_gen:9148734 | 45 vijfenveertigste verdieping | 22.21 binnenwanden - constructief, massieve wanden (Uniformat) | Model Group:NLRS_01.00_verdieping type N_gen:4789590
2 x Basic Wall:NLRS_22.21_WA_beton prefab d=300_gen:9148738 | 45 vijfenveertigste verdieping | 22.21 binnenwanden - constructief, massieve wanden (Uniformat) | Model Group:NLRS_01.00_verdieping type N_gen:4789590
2 x Basic Wall:NLRS_22.21_WA_beton prefab d=300_gen:9148741 | 45 vijfenveertigste verdieping | 22.21 binnenwanden - constructief, massieve wanden (Uniformat) | Model Group:NLRS_01.00_verdieping type N_gen:4789590
2 x Basic Wall:NLRS_22.21_WA_beton prefab d=300_gen:9148743 | 45 vijfenveertigste verdieping | 22.21 binnenwanden - constructief, massieve wanden (Uniformat) | Model Group:NLRS_01.00_verdieping type N_gen:4789590
Floor:NLRS_23.21_FL_vloer d=270_gen:9148866:2 | 45 vijfenveertigste verdieping | 23.21 vloeren - constructief, vrijdragende vloeren (Uniformat) | Model Group:NLRS_23.21_vloer voor wanden d=300/300_gen:9148873
Basic Wall:NLRS_22.21_WA_beton prefab d=300_gen:9148995 | 46 zesenveertigste verdieping | 22.21 binnenwanden - constructief, massieve wanden (Uniformat) | Model Group:NLRS_01.00_verdieping type N_gen:4790022
Basic Wall:NLRS_22.21_WA_beton prefab d=300_gen:9148997 | 46 zesenveertigste verdieping | 22.21 binnenwanden - constructief, massieve wanden (Uniformat) | Model Group:NLRS_01.00_verdieping type N_gen:4790022
2 x Basic Wall:NLRS_22.21_WA_beton prefab d=300_gen:9148999 | 46 zesenveertigste verdieping | 22.21 binnenwanden - constructief, massieve wanden (Uniformat) | Model Group:NLRS_01.00_verdieping type N_gen:4790022
Basic Wall:NLRS_22.21_WA_beton prefab d=300_gen:9149005 | 46 zesenveertigste verdieping | 22.21 binnenwanden - constructief, massieve wanden (Uniformat) | Model Group:NLRS_01.00_verdieping type N_gen:4790022
4 x Basic Wall:NLRS_22.21_WA_beton prefab d=300_gen:4472952 | 46 zesenveertigste verdieping | 22.21 binnenwanden - constructief, massieve wanden (Uniformat) | Model Group:NLRS_01.00_verdieping type N_gen:4790022
Basic Wall:NLRS_22.21_WA_beton prefab d=300_gen:9149008 | 46 zesenveertigste verdieping | 22.21 binnenwanden - constructief, massieve wanden (Uniformat) | Model Group:NLRS_01.00_verdieping type N_gen:4790022
Basic Wall:NLRS_22.21_WA_beton prefab d=300_gen:9149011 | 46 zesenveertigste verdieping | 22.21 binnenwanden - constructief, massieve wanden (Uniformat) | Model Group:NLRS_01.00_verdieping type N_gen:4790022
Basic Wall:NLRS_22.21_WA_beton prefab d=300_gen:9149014 | 46 zesenveertigste verdieping | 22.21 binnenwanden - constructief, massieve wanden (Uniformat) | Model Group:NLRS_01.00_verdieping type N_gen:4790022
Basic Wall:NLRS_22.21_WA_beton prefab d=300_gen:9149017 | 46 zesenveertigste verdieping | 22.21 binnenwanden - constructief, massieve wanden (Uniformat) | Model Group:NLRS_01.00_verdieping type N_gen:4790022
Basic Wall:NLRS_22.21_WA_beton prefab d=300_gen:9149020 | 46 zesenveertigste verdieping | 22.21 binnenwanden - constructief, massieve wanden (Uniformat) | Model Group:NLRS_01.00_verdieping type N_gen:4790022
Basic Wall:NLRS_22.21_WA_beton prefab d=300_gen:9149023 | 46 zesenveertigste verdieping | 22.21 binnenwanden - constructief, massieve wanden (Uniformat) | Model Group:NLRS_01.00_verdieping type N_gen:4790022
Basic Wall:NLRS_22.21_WA_beton prefab d=300_gen:9149026 | 46 zesenveertigste verdieping | 22.21 binnenwanden - constructief, massieve wanden (Uniformat) | Model Group:NLRS_01.00_verdieping type N_gen:4790022
2 x Basic Wall:NLRS_22.21_WA_beton prefab d=300_gen:9149030 | 46 zesenveertigste verdieping | 22.21 binnenwanden - constructief, massieve wanden (Uniformat) | Model Group:NLRS_01.00_verdieping type N_gen:4790022
2 x Basic Wall:NLRS_22.21_WA_beton prefab d=300_gen:9149033 | 46 zesenveertigste verdieping | 22.21 binnenwanden - constructief, massieve wanden (Uniformat) | Model Group:NLRS_01.00_verdieping type N_gen:4790022
2 x Basic Wall:NLRS_22.21_WA_beton prefab d=300_gen:9149035 | 46 zesenveertigste verdieping | 22.21 binnenwanden - constructief, massieve wanden (Uniformat) | Model Group:NLRS_01.00_verdieping type N_gen:4790022
Floor:NLRS_23.21_FL_vloer d=270_gen:9149158:2 | 46 zesenveertigste verdieping | 23.21 vloeren - constructief, vrijdragende vloeren (Uniformat) | Model Group:NLRS_23.21_vloer voor wanden d=300/300_gen:9149165
Basic Wall:NLRS_22.21_WA_beton prefab d=300_gen:9149287 | 49 negenenveertigste verdieping | 22.21 binnenwanden - constructief, massieve wanden (Uniformat) | Model Group:NLRS_01.00_verdieping type N_gen:4791318
Basic Wall:NLRS_22.21_WA_beton prefab d=300_gen:9149289 | 49 negenenveertigste verdieping | 22.21 binnenwanden - constructief, massieve wanden (Uniformat) | Model Group:NLRS_01.00_verdieping type N_gen:4791318
2 x Basic Wall:NLRS_22.21_WA_beton prefab d=300_gen:9149291 | 49 negenenveertigste verdieping | 22.21 binnenwanden - constructief, massieve wanden (Uniformat) | Model Group:NLRS_01.00_verdieping type N_gen:4791318
Basic Wall:NLRS_22.21_WA_beton prefab d=300_gen:9149297 | 49 negenenveertigste verdieping | 22.21 binnenwanden - constructief, massieve wanden (Uniformat) | Model Group:NLRS_01.00_verdieping type N_gen:4791318
4 x Basic Wall:NLRS_22.21_WA_beton prefab d=300_gen:4472952 | 49 negenenveertigste verdieping | 22.21 binnenwanden - constructief, massieve wanden (Uniformat) | Model Group:NLRS_01.00_verdieping type N_gen:4791318
Basic Wall:NLRS_22.21_WA_beton prefab d=300_gen:9149300 | 49 negenenveertigste verdieping | 22.21 binnenwanden - constructief, massieve wanden (Uniformat) | Model Group:NLRS_01.00_verdieping type N_gen:4791318
Basic Wall:NLRS_22.21_WA_beton prefab d=300_gen:9149303 | 49 negenenveertigste verdieping | 22.21 binnenwanden - constructief, massieve wanden (Uniformat) | Model Group:NLRS_01.00_verdieping type N_gen:4791318
Basic Wall:NLRS_22.21_WA_beton prefab d=300_gen:9149306 | 49 negenenveertigste verdieping | 22.21 binnenwanden - constructief, massieve wanden (Uniformat) | Model Group:NLRS_01.00_verdieping type N_gen:4791318
Basic Wall:NLRS_22.21_WA_beton prefab d=300_gen:9149309 | 49 negenenveertigste verdieping | 22.21 binnenwanden - constructief, massieve wanden (Uniformat) | Model Group:NLRS_01.00_verdieping type N_gen:4791318
Basic Wall:NLRS_22.21_WA_beton prefab d=300_gen:9149312 | 49 negenenveertigste verdieping | 22.21 binnenwanden - constructief, massieve wanden (Uniformat) | Model Group:NLRS_01.00_verdieping type N_gen:4791318
Basic Wall:NLRS_22.21_WA_beton prefab d=300_gen:9149315 | 49 negenenveertigste verdieping | 22.21 binnenwanden - constructief, massieve wanden (Uniformat) | Model Group:NLRS_01.00_verdieping type N_gen:4791318
Basic Wall:NLRS_22.21_WA_beton prefab d=300_gen:9149318 | 49 negenenveertigste verdieping | 22.21 binnenwanden - constructief, massieve wanden (Uniformat) | Model Group:NLRS_01.00_verdieping type N_gen:4791318
2 x Basic Wall:NLRS_22.21_WA_beton prefab d=300_gen:9149322 | 49 negenenveertigste verdieping | 22.21 binnenwanden - constructief, massieve wanden (Uniformat) | Model Group:NLRS_01.00_verdieping type N_gen:4791318
2 x Basic Wall:NLRS_22.21_WA_beton prefab d=300_gen:9149325 | 49 negenenveertigste verdieping | 22.21 binnenwanden - constructief, massieve wanden (Uniformat) | Model Group:NLRS_01.00_verdieping type N_gen:4791318
2 x Basic Wall:NLRS_22.21_WA_beton prefab d=300_gen:9149327 | 49 negenenveertigste verdieping | 22.21 binnenwanden - constructief, massieve wanden (Uniformat) | Model Group:NLRS_01.00_verdieping type N_gen:4791318
Floor:NLRS_23.21_FL_vloer d=270_gen:9149450:2 | 49 negenenveertigste verdieping | 23.21 vloeren - constructief, vrijdragende vloeren (Uniformat) | Model Group:NLRS_23.21_vloer voor wanden d=300/300_gen:9149457
Basic Wall:NLRS_22.21_WA_beton prefab d=300_gen:9152809 | 48 achtenveertigste verdieping | 22.21 binnenwanden - constructief, massieve wanden (Uniformat) | Model Group:NLRS_01.00_verdieping type O_gen:4790886
Basic Wall:NLRS_22.21_WA_beton prefab d=300_gen:9152811 | 48 achtenveertigste verdieping | 22.21 binnenwanden - constructief, massieve wanden (Uniformat) | Model Group:NLRS_01.00_verdieping type O_gen:4790886
2 x Basic Wall:NLRS_22.21_WA_beton prefab d=300_gen:9152813 | 48 achtenveertigste verdieping | 22.21 binnenwanden - constructief, massieve wanden (Uniformat) | Model Group:NLRS_01.00_verdieping type O_gen:4790886
Basic Wall:NLRS_22.21_WA_beton prefab d=300_gen:9152819 | 48 achtenveertigste verdieping | 22.21 binnenwanden - constructief, massieve wanden (Uniformat) | Model Group:NLRS_01.00_verdieping type O_gen:4790886
4 x Basic Wall:NLRS_22.21_WA_beton prefab d=300_gen:4472952 | 48 achtenveertigste verdieping | 22.21 binnenwanden - constructief, massieve wanden (Uniformat) | Model Group:NLRS_01.00_verdieping type O_gen:4790886
Basic Wall:NLRS_22.21_WA_beton prefab d=300_gen:9152822 | 48 achtenveertigste verdieping | 22.21 binnenwanden - constructief, massieve wanden (Uniformat) | Model Group:NLRS_01.00_verdieping type O_gen:4790886
Basic Wall:NLRS_22.21_WA_beton prefab d=300_gen:9152825 | 48 achtenveertigste verdieping | 22.21 binnenwanden - constructief, massieve wanden (Uniformat) | Model Group:NLRS_01.00_verdieping type O_gen:4790886
Basic Wall:NLRS_22.21_WA_beton prefab d=300_gen:9152828 | 48 achtenveertigste verdieping | 22.21 binnenwanden - constructief, massieve wanden (Uniformat) | Model Group:NLRS_01.00_verdieping type O_gen:4790886
Basic Wall:NLRS_22.21_WA_beton prefab d=300_gen:9152831 | 48 achtenveertigste verdieping | 22.21 binnenwanden - constructief, massieve wanden (Uniformat) | Model Group:NLRS_01.00_verdieping type O_gen:4790886
Basic Wall:NLRS_22.21_WA_beton prefab d=300_gen:9152834 | 48 achtenveertigste verdieping | 22.21 binnenwanden - constructief, massieve wanden (Uniformat) | Model Group:NLRS_01.00_verdieping type O_gen:4790886
Basic Wall:NLRS_22.21_WA_beton prefab d=300_gen:9152837 | 48 achtenveertigste verdieping | 22.21 binnenwanden - constructief, massieve wanden (Uniformat) | Model Group:NLRS_01.00_verdieping type O_gen:4790886
Basic Wall:NLRS_22.21_WA_beton prefab d=300_gen:9152840 | 48 achtenveertigste verdieping | 22.21 binnenwanden - constructief, massieve wanden (Uniformat) | Model Group:NLRS_01.00_verdieping type O_gen:4790886
2 x Basic Wall:NLRS_22.21_WA_beton prefab d=300_gen:9152844 | 48 achtenveertigste verdieping | 22.21 binnenwanden - constructief, massieve wanden (Uniformat) | Model Group:NLRS_01.00_verdieping type O_gen:4790886
2 x Basic Wall:NLRS_22.21_WA_beton prefab d=300_gen:9152847 | 48 achtenveertigste verdieping | 22.21 binnenwanden - constructief, massieve wanden (Uniformat) | Model Group:NLRS_01.00_verdieping type O_gen:4790886
2 x Basic Wall:NLRS_22.21_WA_beton prefab d=300_gen:9152849 | 48 achtenveertigste verdieping | 22.21 binnenwanden - constructief, massieve wanden (Uniformat) | Model Group:NLRS_01.00_verdieping type O_gen:4790886
Floor:NLRS_23.21_FL_vloer d=270_gen:9152972:2 | 48 achtenveertigste verdieping | 23.21 vloeren - constructief, vrijdragende vloeren (Uniformat) | Model Group:NLRS_23.21_vloer voor wanden d=300/300_gen:9152979
2 x Basic Wall:NLRS_22.21_WA_beton prefab d=250_gen:10294645 | 57 zevenenvijftigste verdieping | 22.21 binnenwanden - constructief, massieve wanden (Uniformat)
2 x Basic Wall:NLRS_22.21_WA_beton prefab d=250_gen:10294648 | 57 zevenenvijftigste verdieping | 22.21 binnenwanden - constructief, massieve wanden (Uniformat)
4 x Basic Wall:NLRS_22.21_WA_beton prefab d=250_gen:1312532 | 57 zevenenvijftigste verdieping | 22.21 binnenwanden - constructief, massieve wanden (Uniformat)
2 x Basic Wall:NLRS_22.21_WA_beton prefab d=250_gen:10294653 | 57 zevenenvijftigste verdieping | 22.21 binnenwanden - constructief, massieve wanden (Uniformat)
2 x Basic Wall:NLRS_22.21_WA_beton prefab d=250_gen:10294656 | 57 zevenenvijftigste verdieping | 22.21 binnenwanden - constructief, massieve wanden (Uniformat)
6 x Basic Wall:NLRS_22.21_WA_beton prefab d=250_gen:10294774 | 58 achtenvijftigste verdieping | 22.21 binnenwanden - constructief, massieve wanden (Uniformat)
6 x Basic Wall:NLRS_22.21_WA_beton prefab d=250_gen:10294777 | 58 achtenvijftigste verdieping | 22.21 binnenwanden - constructief, massieve wanden (Uniformat)
6 x Basic Wall:NLRS_22.21_WA_beton prefab d=250_gen:10294782 | 58 achtenvijftigste verdieping | 22.21 binnenwanden - constructief, massieve wanden (Uniformat)
6 x Basic Wall:NLRS_22.21_WA_beton prefab d=250_gen:10294785 | 58 achtenvijftigste verdieping | 22.21 binnenwanden - constructief, massieve wanden (Uniformat)
2 x Basic Wall:NLRS_22.21_WA_beton prefab d=300_gen:4472952 | 00 begane grond | 22.21 binnenwanden - constructief, massieve wanden (Uniformat)
Basic Wall:NLRS_22.21_WA_beton prefab d=300_gen 2:14377447 | 00 begane grond | 22.21 binnenwanden - constructief, massieve wanden (Uniformat)
Basic Wall:NLRS_22.21_WA_beton prefab d=300_gen:4472952 | 01 eerste verdieping | 22.21 binnenwanden - constructief, massieve wanden (Uniformat)
Basic Wall:NLRS_22.21_WA_beton prefab d=300_gen 2:14377447 | 01 eerste verdieping | 22.21 binnenwanden - constructief, massieve wanden (Uniformat)
2 x Basic Wall:NLRS_22.21_WA_beton prefab d=300_gen:4472952 | 02 tweede verdieping | 22.21 binnenwanden - constructief, massieve wanden (Uniformat)
Basic Wall:NLRS_22.21_WA_beton prefab d=300_gen:4472952 | 00a eerste tussenverdieping | 22.21 binnenwanden - constructief, massieve wanden (Uniformat)
Floor:NLRS_23.21_FL_breedplaat d=100/270_gen:10448387:2 | 23 drieëntwintigste verdieping | 23.21 vloeren - constructief, vrijdragende vloeren (Uniformat) | Model Group:NLRS_23.21_vloer voor wanden d=300/400_gen:9134981
Floor:NLRS_23.21_FL_breedplaat d=100/270_gen:10618314:2 | 10 tiende verdieping | 23.21 vloeren - constructief, vrijdragende vloeren (Uniformat) | Model Group:NLRS_23.21_vloer voor wanden d=300/500_gen:9125907
Floor:NLRS_23.21_FL_breedplaat d=100/270_gen:10620668:2 | 12 twaalfde verdieping | 23.21 vloeren - constructief, vrijdragende vloeren (Uniformat) | Model Group:NLRS_23.21_vloer voor wanden d=300/500_gen:9126214
Floor:NLRS_23.21_FL_breedplaat d=100/270_gen:10620800:2 | 14 veertiende verdieping | 23.21 vloeren - constructief, vrijdragende vloeren (Uniformat) | Model Group:NLRS_23.21_vloer voor wanden d=300/500_gen:9126521
Floor:NLRS_23.21_FL_breedplaat d=100/270_gen:10620932:2 | 20 twintigste verdieping | 23.21 vloeren - constructief, vrijdragende vloeren (Uniformat) | Model Group:NLRS_23.21_vloer voor wanden d=300/500_gen:9133891
Floor:NLRS_23.21_FL_breedplaat d=100/270_gen:10622932:2 | 11 elfde verdieping | 23.21 vloeren - constructief, vrijdragende vloeren (Uniformat) | Model Group:NLRS_23.21_vloer voor wanden d=300/500_gen:9128989
Floor:NLRS_23.21_FL_breedplaat d=100/270_gen:10625099:2 | 13 dertiende verdieping | 23.21 vloeren - constructief, vrijdragende vloeren (Uniformat) | Model Group:NLRS_23.21_vloer voor wanden d=300/500_gen:9129292
Floor:NLRS_23.21_FL_breedplaat d=100/270_gen:10625231:2 | 19 negentiende verdieping | 23.21 vloeren - constructief, vrijdragende vloeren (Uniformat) | Model Group:NLRS_23.21_vloer voor wanden d=300/500_gen:9132770
Floor:NLRS_23.21_FL_breedplaat d=100/270_gen:10634998:2 | 06 zesde verdieping | 23.21 vloeren - constructief, vrijdragende vloeren (Uniformat) | Model Group:NLRS_23.21_vloer voor wanden d=400/500_gen:5786112
Floor:NLRS_23.21_FL_breedplaat d=100/270_gen:10635983:2 | 07 zevende verdieping | 23.21 vloeren - constructief, vrijdragende vloeren (Uniformat) | Model Group:NLRS_23.21_vloer voor wanden d=400/500_gen:9091022
Floor:NLRS_23.21_FL_breedplaat d=100/270_gen:10636860:2 | 08 achtste verdieping | 23.21 vloeren - constructief, vrijdragende vloeren (Uniformat) | Model Group:NLRS_23.21_vloer voor wanden d=400/500_gen:9124885
Floor:NLRS_23.21_FL_breedplaat d=100/270_gen:10637397:2 | 09 negende verdieping | 23.21 vloeren - constructief, vrijdragende vloeren (Uniformat) | Model Group:NLRS_23.21_vloer voor wanden d=400/500_gen:5771384
Floor:NLRS_23.21_FL_breedplaat d=100/270_gen:10637945:2 | 28 achtentwintigste verdieping | 23.21 vloeren - constructief, vrijdragende vloeren (Uniformat) | Model Group:NLRS_23.21_vloer voor wanden d=300/400_gen:9135274
Floor:NLRS_23.21_FL_breedplaat d=100/270_gen:10639648:2 | 29 negenentwintigste verdieping | 23.21 vloeren - constructief, vrijdragende vloeren (Uniformat) | Model Group:NLRS_23.21_vloer voor wanden d=300/400_gen:9135567
Floor:NLRS_23.21_FL_breedplaat d=100/270_gen:10639779:2 | 33 drieëndertigste verdieping | 23.21 vloeren - constructief, vrijdragende vloeren (Uniformat) | Model Group:NLRS_23.21_vloer voor wanden d=300/400_gen:9135860
Floor:NLRS_23.21_FL_breedplaat d=100/270_gen:10641076:2 | 21 eenentwintigste verdieping | 23.21 vloeren - constructief, vrijdragende vloeren (Uniformat)
2 x Basic Wall:NLRS_22.21_WA_beton prefab d=500_gen:10782741 | 08 achtste verdieping | 22.21 binnenwanden - constructief, massieve wanden (Uniformat) | Model Group:NLRS_01.00_verdieping type B1_gen:4714770
2 x Basic Wall:NLRS_22.21_WA_beton prefab d=500_gen:10782743 | 08 achtste verdieping | 22.21 binnenwanden - constructief, massieve wanden (Uniformat) | Model Group:NLRS_01.00_verdieping type B1_gen:4714770
Basic Wall:NLRS_22.21_WA_beton prefab d=300_gen:10782745 | 08 achtste verdieping | 22.21 binnenwanden - constructief, massieve wanden (Uniformat) | Model Group:NLRS_01.00_verdieping type B1_gen:4714770
2 x Basic Wall:NLRS_22.21_WA_beton prefab d=300_gen:4472952 | 08 achtste verdieping | 22.21 binnenwanden - constructief, massieve wanden (Uniformat) | Model Group:NLRS_01.00_verdieping type B1_gen:4714770
Basic Wall:NLRS_22.21_WA_beton prefab d=300_gen:10782756 | 08 achtste verdieping | 22.21 binnenwanden - constructief, massieve wanden (Uniformat) | Model Group:NLRS_01.00_verdieping type B1_gen:4714770
Basic Wall:NLRS_22.21_WA_beton prefab d=500_gen:10782765 | 08 achtste verdieping | 22.21 binnenwanden - constructief, massieve wanden (Uniformat) | Model Group:NLRS_01.00_verdieping type B1_gen:4714770
2 x Basic Wall:NLRS_22.21_WA_beton prefab d=500_gen:4472769 | 08 achtste verdieping | 22.21 binnenwanden - constructief, massieve wanden (Uniformat) | Model Group:NLRS_01.00_verdieping type B1_gen:4714770
Basic Wall:NLRS_22.21_WA_beton prefab d=500_gen:10782767 | 08 achtste verdieping | 22.21 binnenwanden - constructief, massieve wanden (Uniformat) | Model Group:NLRS_01.00_verdieping type B1_gen:4714770
Basic Wall:NLRS_22.21_WA_beton prefab d=500_gen:10782770 | 08 achtste verdieping | 22.21 binnenwanden - constructief, massieve wanden (Uniformat) | Model Group:NLRS_01.00_verdieping type B1_gen:4714770
Basic Wall:NLRS_22.21_WA_beton prefab d=500_gen:10782773 | 08 achtste verdieping | 22.21 binnenwanden - constructief, massieve wanden (Uniformat) | Model Group:NLRS_01.00_verdieping type B1_gen:4714770
Basic Wall:NLRS_22.21_WA_beton prefab d=500_gen:10782776 | 08 achtste verdieping | 22.21 binnenwanden - constructief, massieve wanden (Uniformat) | Model Group:NLRS_01.00_verdieping type B1_gen:4714770
Basic Wall:NLRS_22.21_WA_beton prefab d=500_gen:10782779 | 08 achtste verdieping | 22.21 binnenwanden - constructief, massieve wanden (Uniformat) | Model Group:NLRS_01.00_verdieping type B1_gen:4714770
Basic Wall:NLRS_22.21_WA_beton prefab d=500_gen:10782789 | 08 achtste verdieping | 22.21 binnenwanden - constructief, massieve wanden (Uniformat) | Model Group:NLRS_01.00_verdieping type B1_gen:4714770
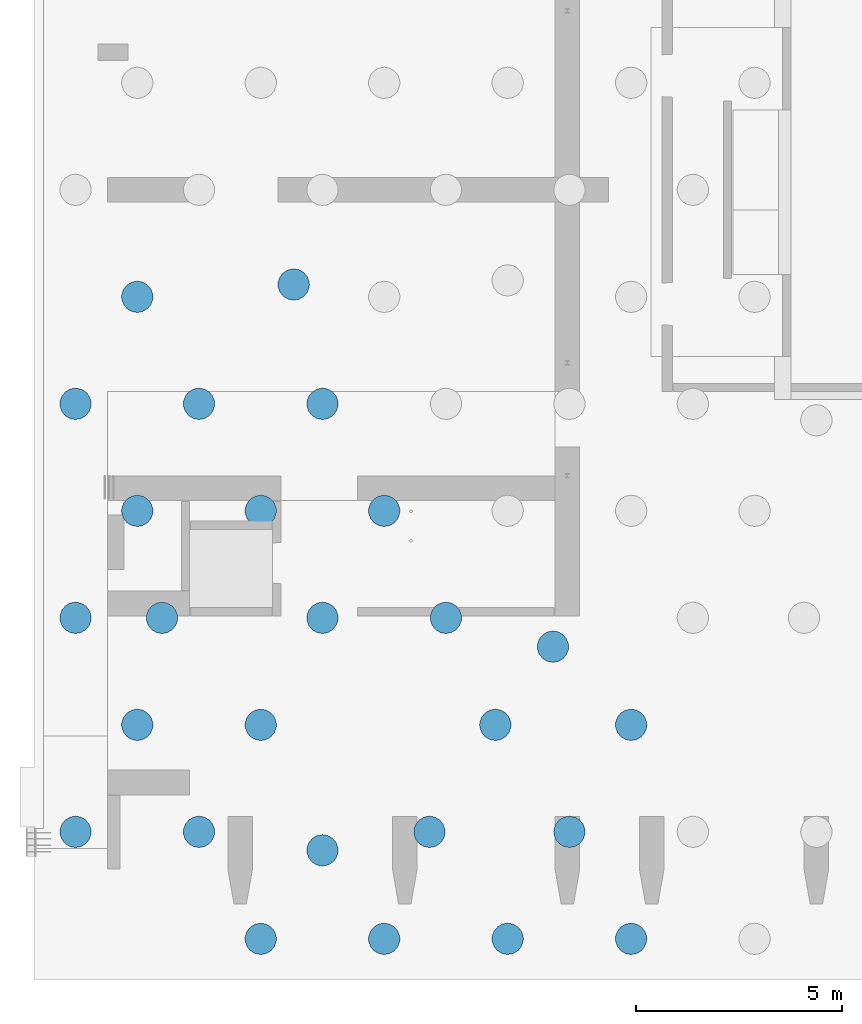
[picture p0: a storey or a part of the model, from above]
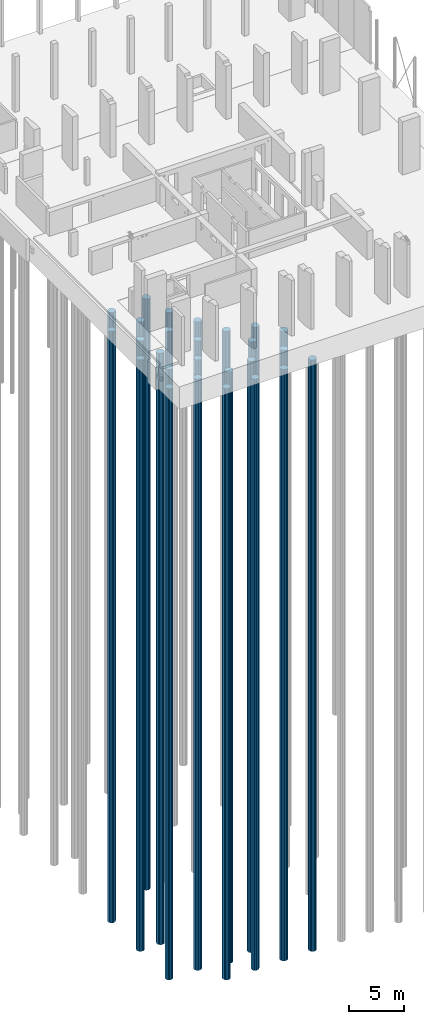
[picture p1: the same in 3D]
Properties of the parts of a building model (IFC2X3), part 15 of 21

# IfcOpeningElement: Opening (5659)
Name | In | Classification | Group
Basic Wall:NLRS_22.21_WA_beton prefab d=500_gen:10782791 | 08 achtste verdieping | 22.21 binnenwanden - constructief, massieve wanden (Uniformat) | Model Group:NLRS_01.00_verdieping type B1_gen:4714770
Basic Wall:NLRS_22.21_WA_beton prefab d=500_gen:10783270 | 10 tiende verdieping | 22.21 binnenwanden - constructief, massieve wanden (Uniformat) | Model Group:NLRS_01.00_verdieping type B2_gen:9035827
Basic Wall:NLRS_22.21_WA_beton prefab d=500_gen:10783273 | 10 tiende verdieping | 22.21 binnenwanden - constructief, massieve wanden (Uniformat) | Model Group:NLRS_01.00_verdieping type B2_gen:9035827
Basic Wall:NLRS_22.21_WA_beton prefab d=500_gen:10783276 | 10 tiende verdieping | 22.21 binnenwanden - constructief, massieve wanden (Uniformat) | Model Group:NLRS_01.00_verdieping type B2_gen:9035827
Basic Wall:NLRS_22.21_WA_beton prefab d=500_gen:10783279 | 10 tiende verdieping | 22.21 binnenwanden - constructief, massieve wanden (Uniformat) | Model Group:NLRS_01.00_verdieping type B2_gen:9035827
Basic Wall:NLRS_22.21_WA_beton prefab d=500_gen:10783286 | 12 twaalfde verdieping | 22.21 binnenwanden - constructief, massieve wanden (Uniformat) | Model Group:NLRS_01.00_verdieping type B2_gen:4738165
Basic Wall:NLRS_22.21_WA_beton prefab d=500_gen:10783289 | 12 twaalfde verdieping | 22.21 binnenwanden - constructief, massieve wanden (Uniformat) | Model Group:NLRS_01.00_verdieping type B2_gen:4738165
Basic Wall:NLRS_22.21_WA_beton prefab d=500_gen:10783292 | 12 twaalfde verdieping | 22.21 binnenwanden - constructief, massieve wanden (Uniformat) | Model Group:NLRS_01.00_verdieping type B2_gen:4738165
Basic Wall:NLRS_22.21_WA_beton prefab d=500_gen:10783295 | 12 twaalfde verdieping | 22.21 binnenwanden - constructief, massieve wanden (Uniformat) | Model Group:NLRS_01.00_verdieping type B2_gen:4738165
Basic Wall:NLRS_22.21_WA_beton prefab d=500_gen:10783302 | 14 veertiende verdieping | 22.21 binnenwanden - constructief, massieve wanden (Uniformat) | Model Group:NLRS_01.00_verdieping type B2_gen:4738623
Basic Wall:NLRS_22.21_WA_beton prefab d=500_gen:10783305 | 14 veertiende verdieping | 22.21 binnenwanden - constructief, massieve wanden (Uniformat) | Model Group:NLRS_01.00_verdieping type B2_gen:4738623
Basic Wall:NLRS_22.21_WA_beton prefab d=500_gen:10783308 | 14 veertiende verdieping | 22.21 binnenwanden - constructief, massieve wanden (Uniformat) | Model Group:NLRS_01.00_verdieping type B2_gen:4738623
Basic Wall:NLRS_22.21_WA_beton prefab d=500_gen:10783311 | 14 veertiende verdieping | 22.21 binnenwanden - constructief, massieve wanden (Uniformat) | Model Group:NLRS_01.00_verdieping type B2_gen:4738623
Basic Wall:NLRS_22.21_WA_beton prefab d=500_gen:10959552 | 08 achtste verdieping | 22.21 binnenwanden - constructief, massieve wanden (Uniformat) | Model Group:NLRS_01.00_verdieping type B1_gen:4714770
Basic Wall:NLRS_22.21_WA_beton prefab d=500_gen:10959555 | 08 achtste verdieping | 22.21 binnenwanden - constructief, massieve wanden (Uniformat) | Model Group:NLRS_01.00_verdieping type B1_gen:4714770
Basic Wall:NLRS_22.21_WA_beton prefab d=500_gen:10959558 | 08 achtste verdieping | 22.21 binnenwanden - constructief, massieve wanden (Uniformat) | Model Group:NLRS_01.00_verdieping type B1_gen:4714770
Basic Wall:NLRS_22.21_WA_beton prefab d=500_gen:10959561 | 08 achtste verdieping | 22.21 binnenwanden - constructief, massieve wanden (Uniformat) | Model Group:NLRS_01.00_verdieping type B1_gen:4714770
Floor:NLRS_13.22_FL_beton ihwg b=450_gen:11892297:2 | 57 zevenenvijftigste verdieping | 13.22 vloeren op grondslag - constructief, vloeren als gebouwonderdeel (Uniformat)
Floor:NLRS_23.21_FL_breedplaat d=80_gen:12073154:2 | 57 zevenenvijftigste verdieping | 23.21 vloeren - constructief, vrijdragende vloeren (Uniformat)
Floor:NLRS_23.21_FL_breedplaat d=80_gen:12075021:2 | 56 zesenvijftigste verdieping | 23.21 vloeren - constructief, vrijdragende vloeren (Uniformat)
Floor:NLRS_23.21_FL_breedplaat d=80_gen:12075661:2 | 55 vijfenvijftigste verdieping | 23.21 vloeren - constructief, vrijdragende vloeren (Uniformat)
Floor:NLRS_23.21_FL_breedplaat d=80_gen:12076062:2 | 54 vierenvijftigste verdieping | 23.21 vloeren - constructief, vrijdragende vloeren (Uniformat)
Floor:NLRS_23.21_FL_breedplaat d=80_gen:12076062:3 | 54 vierenvijftigste verdieping | 23.21 vloeren - constructief, vrijdragende vloeren (Uniformat)
Floor:NLRS_23.21_FL_breedplaat d=60_gen:12571193:2 | 57 zevenenvijftigste verdieping | 23.21 vloeren - constructief, vrijdragende vloeren (Uniformat)
Floor:NLRS_23.21_FL_breedplaat d=60_gen:12571193:3 | 57 zevenenvijftigste verdieping | 23.21 vloeren - constructief, vrijdragende vloeren (Uniformat)
2 x Basic Wall:NLRS_21.21_WA_beton prefab d=300/320_gen:12627767 | 11 elfde verdieping | 21.21 buitenwanden - constructief, massieve wanden (Uniformat) | Model Group:NLRS_21.21_WA_wand 002b d=300_gen:6861559
2 x Basic Wall:NLRS_21.21_WA_beton prefab d=300/320_gen:5365657 | 11 elfde verdieping | 21.21 buitenwanden - constructief, massieve wanden (Uniformat) | Model Group:NLRS_21.21_WA_wand 002b d=300_gen:6861559
4 x Basic Wall:NLRS_21.21_WA_beton prefab d=300/320_gen:12627771 | 11 elfde verdieping | 21.21 buitenwanden - constructief, massieve wanden (Uniformat) | Model Group:NLRS_21.21_WA_wand 002b d=300_gen:6861559
2 x Basic Wall:NLRS_21.21_WA_beton prefab d=300/320_gen:12627935 | 13 dertiende verdieping | 21.21 buitenwanden - constructief, massieve wanden (Uniformat) | Model Group:NLRS_21.21_WA_wand 002b d=300_gen:4730656
2 x Basic Wall:NLRS_21.21_WA_beton prefab d=300/320_gen:5365657 | 13 dertiende verdieping | 21.21 buitenwanden - constructief, massieve wanden (Uniformat) | Model Group:NLRS_21.21_WA_wand 002b d=300_gen:4730656
4 x Basic Wall:NLRS_21.21_WA_beton prefab d=300/320_gen:12627939 | 13 dertiende verdieping | 21.21 buitenwanden - constructief, massieve wanden (Uniformat) | Model Group:NLRS_21.21_WA_wand 002b d=300_gen:4730656
4 x Basic Wall:NLRS_21.21_WA_beton prefab d=300/320_gen:12629263 | 12 twaalfde verdieping | 21.21 buitenwanden - constructief, massieve wanden (Uniformat) | Model Group:NLRS_21.21_WA_wand 002a d=300_gen:4738243
2 x Basic Wall:NLRS_21.21_WA_beton prefab d=300/320_gen:5365657 | 12 twaalfde verdieping | 21.21 buitenwanden - constructief, massieve wanden (Uniformat) | Model Group:NLRS_21.21_WA_wand 002a d=300_gen:4738243
2 x Basic Wall:NLRS_21.21_WA_beton prefab d=300/320_gen:12629267 | 12 twaalfde verdieping | 21.21 buitenwanden - constructief, massieve wanden (Uniformat) | Model Group:NLRS_21.21_WA_wand 002a d=300_gen:4738243
4 x Basic Wall:NLRS_21.21_WA_beton prefab d=300/320_gen:12629619 | 14 veertiende verdieping | 21.21 buitenwanden - constructief, massieve wanden (Uniformat) | Model Group:NLRS_21.21_WA_wand 002a d=300_gen:4738701
2 x Basic Wall:NLRS_21.21_WA_beton prefab d=300/320_gen:5365657 | 14 veertiende verdieping | 21.21 buitenwanden - constructief, massieve wanden (Uniformat) | Model Group:NLRS_21.21_WA_wand 002a d=300_gen:4738701
2 x Basic Wall:NLRS_21.21_WA_beton prefab d=300/320_gen:12629623 | 14 veertiende verdieping | 21.21 buitenwanden - constructief, massieve wanden (Uniformat) | Model Group:NLRS_21.21_WA_wand 002a d=300_gen:4738701
4 x Basic Wall:NLRS_21.21_WA_beton prefab d=400/420_gen:12650838 | 06 zesde verdieping | 21.21 buitenwanden - constructief, massieve wanden (Uniformat) | Model Group:NLRS_21.21_WA_wand 002a d=400_gen:4690710
2 x Basic Wall:NLRS_21.21_WA_beton prefab d=400/420_gen:5362948 | 06 zesde verdieping | 21.21 buitenwanden - constructief, massieve wanden (Uniformat) | Model Group:NLRS_21.21_WA_wand 002a d=400_gen:4690710
2 x Basic Wall:NLRS_21.21_WA_beton prefab d=400/420_gen:12650841 | 06 zesde verdieping | 21.21 buitenwanden - constructief, massieve wanden (Uniformat) | Model Group:NLRS_21.21_WA_wand 002a d=400_gen:4690710
4 x Basic Wall:NLRS_21.21_WA_beton prefab d=400/420_gen:12651692 | 08 achtste verdieping | 21.21 buitenwanden - constructief, massieve wanden (Uniformat) | Model Group:NLRS_21.21_WA_wand 002a d=400_gen:4714828
2 x Basic Wall:NLRS_21.21_WA_beton prefab d=400/420_gen:5362948 | 08 achtste verdieping | 21.21 buitenwanden - constructief, massieve wanden (Uniformat) | Model Group:NLRS_21.21_WA_wand 002a d=400_gen:4714828
2 x Basic Wall:NLRS_21.21_WA_beton prefab d=400/420_gen:12651695 | 08 achtste verdieping | 21.21 buitenwanden - constructief, massieve wanden (Uniformat) | Model Group:NLRS_21.21_WA_wand 002a d=400_gen:4714828
2 x Basic Wall:NLRS_21.21_WA_beton prefab d=400/420_gen:12652004 | 07 zevende verdieping | 21.21 buitenwanden - constructief, massieve wanden (Uniformat) | Model Group:NLRS_21.21_WA_wand 002b d=400_gen:4689126
2 x Basic Wall:NLRS_21.21_WA_beton prefab d=400/420_gen:5362948 | 07 zevende verdieping | 21.21 buitenwanden - constructief, massieve wanden (Uniformat) | Model Group:NLRS_21.21_WA_wand 002b d=400_gen:4689126
4 x Basic Wall:NLRS_21.21_WA_beton prefab d=400/420_gen:12652007 | 07 zevende verdieping | 21.21 buitenwanden - constructief, massieve wanden (Uniformat) | Model Group:NLRS_21.21_WA_wand 002b d=400_gen:4689126
2 x Basic Wall:NLRS_21.21_WA_beton prefab d=300/320_gen:12653266 | 09 negende verdieping | 21.21 buitenwanden - constructief, massieve wanden (Uniformat) | Model Group:NLRS_21.21_WA_wand 002b d=300_gen:5667625
2 x Basic Wall:NLRS_21.21_WA_beton prefab d=300/320_gen:5365657 | 09 negende verdieping | 21.21 buitenwanden - constructief, massieve wanden (Uniformat) | Model Group:NLRS_21.21_WA_wand 002b d=300_gen:5667625
4 x Basic Wall:NLRS_21.21_WA_beton prefab d=300/320_gen:12653270 | 09 negende verdieping | 21.21 buitenwanden - constructief, massieve wanden (Uniformat) | Model Group:NLRS_21.21_WA_wand 002b d=300_gen:5667625
4 x Basic Wall:NLRS_21.21_WA_beton prefab d=300/320_gen:12653638 | 10 tiende verdieping | 21.21 buitenwanden - constructief, massieve wanden (Uniformat) | Model Group:NLRS_21.21_WA_wand 002a d=300_gen:6859037
2 x Basic Wall:NLRS_21.21_WA_beton prefab d=300/320_gen:5365657 | 10 tiende verdieping | 21.21 buitenwanden - constructief, massieve wanden (Uniformat) | Model Group:NLRS_21.21_WA_wand 002a d=300_gen:6859037
2 x Basic Wall:NLRS_21.21_WA_beton prefab d=300/320_gen:12653642 | 10 tiende verdieping | 21.21 buitenwanden - constructief, massieve wanden (Uniformat) | Model Group:NLRS_21.21_WA_wand 002a d=300_gen:6859037
2 x Basic Wall:NLRS_21.21_WA_beton prefab d=300/320_gen:12654041 | 11 elfde verdieping | 21.21 buitenwanden - constructief, massieve wanden (Uniformat) | Model Group:NLRS_21.21_WA_wand 002b d=300_gen:6861785
2 x Basic Wall:NLRS_21.21_WA_beton prefab d=300/320_gen:5365657 | 11 elfde verdieping | 21.21 buitenwanden - constructief, massieve wanden (Uniformat) | Model Group:NLRS_21.21_WA_wand 002b d=300_gen:6861785
4 x Basic Wall:NLRS_21.21_WA_beton prefab d=300/320_gen:12654045 | 11 elfde verdieping | 21.21 buitenwanden - constructief, massieve wanden (Uniformat) | Model Group:NLRS_21.21_WA_wand 002b d=300_gen:6861785
4 x Basic Wall:NLRS_21.21_WA_beton prefab d=300/320_gen:12654318 | 12 twaalfde verdieping | 21.21 buitenwanden - constructief, massieve wanden (Uniformat) | Model Group:NLRS_21.21_WA_wand 002a d=300_gen:4738236
2 x Basic Wall:NLRS_21.21_WA_beton prefab d=300/320_gen:5365657 | 12 twaalfde verdieping | 21.21 buitenwanden - constructief, massieve wanden (Uniformat) | Model Group:NLRS_21.21_WA_wand 002a d=300_gen:4738236
2 x Basic Wall:NLRS_21.21_WA_beton prefab d=300/320_gen:12654322 | 12 twaalfde verdieping | 21.21 buitenwanden - constructief, massieve wanden (Uniformat) | Model Group:NLRS_21.21_WA_wand 002a d=300_gen:4738236
2 x Basic Wall:NLRS_21.21_WA_beton prefab d=300/320_gen:12654692 | 13 dertiende verdieping | 21.21 buitenwanden - constructief, massieve wanden (Uniformat) | Model Group:NLRS_21.21_WA_wand 002b d=300_gen:5509164
2 x Basic Wall:NLRS_21.21_WA_beton prefab d=300/320_gen:5365657 | 13 dertiende verdieping | 21.21 buitenwanden - constructief, massieve wanden (Uniformat) | Model Group:NLRS_21.21_WA_wand 002b d=300_gen:5509164
4 x Basic Wall:NLRS_21.21_WA_beton prefab d=300/320_gen:12654696 | 13 dertiende verdieping | 21.21 buitenwanden - constructief, massieve wanden (Uniformat) | Model Group:NLRS_21.21_WA_wand 002b d=300_gen:5509164
4 x Basic Wall:NLRS_21.21_WA_beton prefab d=300/320_gen:12654959 | 14 veertiende verdieping | 21.21 buitenwanden - constructief, massieve wanden (Uniformat) | Model Group:NLRS_21.21_WA_wand 002a d=300_gen:4738694
2 x Basic Wall:NLRS_21.21_WA_beton prefab d=300/320_gen:5365657 | 14 veertiende verdieping | 21.21 buitenwanden - constructief, massieve wanden (Uniformat) | Model Group:NLRS_21.21_WA_wand 002a d=300_gen:4738694
2 x Basic Wall:NLRS_21.21_WA_beton prefab d=300/320_gen:12654963 | 14 veertiende verdieping | 21.21 buitenwanden - constructief, massieve wanden (Uniformat) | Model Group:NLRS_21.21_WA_wand 002a d=300_gen:4738694
2 x Basic Wall:NLRS_21.21_WA_beton prefab d=300/320_gen:12662838 | 11 elfde verdieping | 21.21 buitenwanden - constructief, massieve wanden (Uniformat) | Model Group:NLRS_21.21_WA_wand 004b d=300_gen:6861552
2 x Basic Wall:NLRS_21.21_WA_beton prefab d=300/320_gen:5365657 | 11 elfde verdieping | 21.21 buitenwanden - constructief, massieve wanden (Uniformat) | Model Group:NLRS_21.21_WA_wand 004b d=300_gen:6861552
6 x Basic Wall:NLRS_21.21_WA_beton prefab d=300/320_gen:12662841 | 11 elfde verdieping | 21.21 buitenwanden - constructief, massieve wanden (Uniformat) | Model Group:NLRS_21.21_WA_wand 004b d=300_gen:6861552
2 x Basic Wall:NLRS_21.21_WA_beton prefab d=300/320_gen:12663022 | 13 dertiende verdieping | 21.21 buitenwanden - constructief, massieve wanden (Uniformat) | Model Group:NLRS_21.21_WA_wand 004b d=300_gen:4730648
2 x Basic Wall:NLRS_21.21_WA_beton prefab d=300/320_gen:5365657 | 13 dertiende verdieping | 21.21 buitenwanden - constructief, massieve wanden (Uniformat) | Model Group:NLRS_21.21_WA_wand 004b d=300_gen:4730648
6 x Basic Wall:NLRS_21.21_WA_beton prefab d=300/320_gen:12663025 | 13 dertiende verdieping | 21.21 buitenwanden - constructief, massieve wanden (Uniformat) | Model Group:NLRS_21.21_WA_wand 004b d=300_gen:4730648
4 x Basic Wall:NLRS_21.21_WA_beton prefab d=300/320_gen:12663427 | 12 twaalfde verdieping | 21.21 buitenwanden - constructief, massieve wanden (Uniformat) | Model Group:NLRS_21.21_WA_wand 004a d=300_gen:4738235
2 x Basic Wall:NLRS_21.21_WA_beton prefab d=300/320_gen:5365657 | 12 twaalfde verdieping | 21.21 buitenwanden - constructief, massieve wanden (Uniformat) | Model Group:NLRS_21.21_WA_wand 004a d=300_gen:4738235
4 x Basic Wall:NLRS_21.21_WA_beton prefab d=300/320_gen:12663430 | 12 twaalfde verdieping | 21.21 buitenwanden - constructief, massieve wanden (Uniformat) | Model Group:NLRS_21.21_WA_wand 004a d=300_gen:4738235
4 x Basic Wall:NLRS_21.21_WA_beton prefab d=300/320_gen:12663832 | 14 veertiende verdieping | 21.21 buitenwanden - constructief, massieve wanden (Uniformat) | Model Group:NLRS_21.21_WA_wand 004a d=300_gen:4738693
2 x Basic Wall:NLRS_21.21_WA_beton prefab d=300/320_gen:5365657 | 14 veertiende verdieping | 21.21 buitenwanden - constructief, massieve wanden (Uniformat) | Model Group:NLRS_21.21_WA_wand 004a d=300_gen:4738693
4 x Basic Wall:NLRS_21.21_WA_beton prefab d=300/320_gen:12663835 | 14 veertiende verdieping | 21.21 buitenwanden - constructief, massieve wanden (Uniformat) | Model Group:NLRS_21.21_WA_wand 004a d=300_gen:4738693
4 x Basic Wall:NLRS_21.21_WA_beton prefab d=400/420_gen:12678114 | 06 zesde verdieping | 21.21 buitenwanden - constructief, massieve wanden (Uniformat) | Model Group:NLRS_21.21_WA_wand 004a d=400_gen:4690705
2 x Basic Wall:NLRS_21.21_WA_beton prefab d=400/420_gen:5362948 | 06 zesde verdieping | 21.21 buitenwanden - constructief, massieve wanden (Uniformat) | Model Group:NLRS_21.21_WA_wand 004a d=400_gen:4690705
4 x Basic Wall:NLRS_21.21_WA_beton prefab d=400/420_gen:12678118 | 06 zesde verdieping | 21.21 buitenwanden - constructief, massieve wanden (Uniformat) | Model Group:NLRS_21.21_WA_wand 004a d=400_gen:4690705
2 x Basic Wall:NLRS_21.21_WA_beton prefab d=400/420_gen:12678392 | 07 zevende verdieping | 21.21 buitenwanden - constructief, massieve wanden (Uniformat) | Model Group:NLRS_21.21_WA_wand 004b d=400_gen:4689113
2 x Basic Wall:NLRS_21.21_WA_beton prefab d=400/420_gen:5362948 | 07 zevende verdieping | 21.21 buitenwanden - constructief, massieve wanden (Uniformat) | Model Group:NLRS_21.21_WA_wand 004b d=400_gen:4689113
6 x Basic Wall:NLRS_21.21_WA_beton prefab d=400/420_gen:12678396 | 07 zevende verdieping | 21.21 buitenwanden - constructief, massieve wanden (Uniformat) | Model Group:NLRS_21.21_WA_wand 004b d=400_gen:4689113
4 x Basic Wall:NLRS_21.21_WA_beton prefab d=400/420_gen:12678866 | 08 achtste verdieping | 21.21 buitenwanden - constructief, massieve wanden (Uniformat) | Model Group:NLRS_21.21_WA_wand 004a d=400_gen:4714823
2 x Basic Wall:NLRS_21.21_WA_beton prefab d=400/420_gen:5362948 | 08 achtste verdieping | 21.21 buitenwanden - constructief, massieve wanden (Uniformat) | Model Group:NLRS_21.21_WA_wand 004a d=400_gen:4714823
4 x Basic Wall:NLRS_21.21_WA_beton prefab d=400/420_gen:12678870 | 08 achtste verdieping | 21.21 buitenwanden - constructief, massieve wanden (Uniformat) | Model Group:NLRS_21.21_WA_wand 004a d=400_gen:4714823
2 x Basic Wall:NLRS_21.21_WA_beton prefab d=300/320_gen:12679383 | 09 negende verdieping | 21.21 buitenwanden - constructief, massieve wanden (Uniformat) | Model Group:NLRS_21.21_WA_wand 004b d=300_gen:5667307
2 x Basic Wall:NLRS_21.21_WA_beton prefab d=300/320_gen:5365657 | 09 negende verdieping | 21.21 buitenwanden - constructief, massieve wanden (Uniformat) | Model Group:NLRS_21.21_WA_wand 004b d=300_gen:5667307
6 x Basic Wall:NLRS_21.21_WA_beton prefab d=300/320_gen:12679386 | 09 negende verdieping | 21.21 buitenwanden - constructief, massieve wanden (Uniformat) | Model Group:NLRS_21.21_WA_wand 004b d=300_gen:5667307
4 x Basic Wall:NLRS_21.21_WA_beton prefab d=300/320_gen:12679929 | 10 tiende verdieping | 21.21 buitenwanden - constructief, massieve wanden (Uniformat) | Model Group:NLRS_21.21_WA_wand 004a d=300_gen:6859027
2 x Basic Wall:NLRS_21.21_WA_beton prefab d=300/320_gen:5365657 | 10 tiende verdieping | 21.21 buitenwanden - constructief, massieve wanden (Uniformat) | Model Group:NLRS_21.21_WA_wand 004a d=300_gen:6859027
4 x Basic Wall:NLRS_21.21_WA_beton prefab d=300/320_gen:12679932 | 10 tiende verdieping | 21.21 buitenwanden - constructief, massieve wanden (Uniformat) | Model Group:NLRS_21.21_WA_wand 004a d=300_gen:6859027
2 x Basic Wall:NLRS_21.21_WA_beton prefab d=300/320_gen:12680455 | 11 elfde verdieping | 21.21 buitenwanden - constructief, massieve wanden (Uniformat) | Model Group:NLRS_21.21_WA_wand 004b d=300_gen:6861543
2 x Basic Wall:NLRS_21.21_WA_beton prefab d=300/320_gen:5365657 | 11 elfde verdieping | 21.21 buitenwanden - constructief, massieve wanden (Uniformat) | Model Group:NLRS_21.21_WA_wand 004b d=300_gen:6861543
6 x Basic Wall:NLRS_21.21_WA_beton prefab d=300/320_gen:12680458 | 11 elfde verdieping | 21.21 buitenwanden - constructief, massieve wanden (Uniformat) | Model Group:NLRS_21.21_WA_wand 004b d=300_gen:6861543
4 x Basic Wall:NLRS_21.21_WA_beton prefab d=300/320_gen:12680787 | 12 twaalfde verdieping | 21.21 buitenwanden - constructief, massieve wanden (Uniformat) | Model Group:NLRS_21.21_WA_wand 004a d=300_gen:4738226
2 x Basic Wall:NLRS_21.21_WA_beton prefab d=300/320_gen:5365657 | 12 twaalfde verdieping | 21.21 buitenwanden - constructief, massieve wanden (Uniformat) | Model Group:NLRS_21.21_WA_wand 004a d=300_gen:4738226
4 x Basic Wall:NLRS_21.21_WA_beton prefab d=300/320_gen:12680790 | 12 twaalfde verdieping | 21.21 buitenwanden - constructief, massieve wanden (Uniformat) | Model Group:NLRS_21.21_WA_wand 004a d=300_gen:4738226
2 x Basic Wall:NLRS_21.21_WA_beton prefab d=300/320_gen:12681070 | 13 dertiende verdieping | 21.21 buitenwanden - constructief, massieve wanden (Uniformat) | Model Group:NLRS_21.21_WA_wand 004b d=300_gen:4730639
2 x Basic Wall:NLRS_21.21_WA_beton prefab d=300/320_gen:5365657 | 13 dertiende verdieping | 21.21 buitenwanden - constructief, massieve wanden (Uniformat) | Model Group:NLRS_21.21_WA_wand 004b d=300_gen:4730639
6 x Basic Wall:NLRS_21.21_WA_beton prefab d=300/320_gen:12681073 | 13 dertiende verdieping | 21.21 buitenwanden - constructief, massieve wanden (Uniformat) | Model Group:NLRS_21.21_WA_wand 004b d=300_gen:4730639
4 x Basic Wall:NLRS_21.21_WA_beton prefab d=300/320_gen:12681485 | 14 veertiende verdieping | 21.21 buitenwanden - constructief, massieve wanden (Uniformat) | Model Group:NLRS_21.21_WA_wand 004a d=300_gen:4738684
2 x Basic Wall:NLRS_21.21_WA_beton prefab d=300/320_gen:5365657 | 14 veertiende verdieping | 21.21 buitenwanden - constructief, massieve wanden (Uniformat) | Model Group:NLRS_21.21_WA_wand 004a d=300_gen:4738684
4 x Basic Wall:NLRS_21.21_WA_beton prefab d=300/320_gen:12681488 | 14 veertiende verdieping | 21.21 buitenwanden - constructief, massieve wanden (Uniformat) | Model Group:NLRS_21.21_WA_wand 004a d=300_gen:4738684
Basic Wall:NLRS_21.21_WA_beton ihwg d=300_gen:12697466 | 52 tweeënvijftigste verdieping | 21.21 buitenwanden - constructief, massieve wanden (Uniformat) | Model Group:NLRS_21.21_WA_wand 002c d=300_gen:4981772
Floor:NLRS_23.21_FL_staalplaatbetonvloer d=200_gen:12839561:2 | 58 achtenvijftigste verdieping | 23.21 vloeren - constructief, vrijdragende vloeren (Uniformat)
Floor:NLRS_23.21_FL_staalplaatbetonvloer d=200_gen:12840166:2 | 58 achtenvijftigste verdieping | 23.21 vloeren - constructief, vrijdragende vloeren (Uniformat)
Basic Wall:NLRS_22.21_WA_beton prefab d=200_gen:12884611 | 02 tweede verdieping | 22.21 binnenwanden - constructief, massieve wanden (Uniformat)
Floor:NLRS_23.21_FL_breedplaat d=60_gen:12976903:2 | 58 achtenvijftigste verdieping | 23.21 vloeren - constructief, vrijdragende vloeren (Uniformat)
Floor:NLRS_23.21_FL_breedplaat d=60_gen:12976903:3 | 58 achtenvijftigste verdieping | 23.21 vloeren - constructief, vrijdragende vloeren (Uniformat)
23 x  | 56 zesenvijftigste verdieping
Floor:NLRS_23.21_FL_breedplaat d=60_gen:12977982:2 | 56 zesenvijftigste verdieping | 23.21 vloeren - constructief, vrijdragende vloeren (Uniformat)
Floor:NLRS_23.21_FL_breedplaat d=60_gen:12977982:3 | 56 zesenvijftigste verdieping | 23.21 vloeren - constructief, vrijdragende vloeren (Uniformat)
23 x  | 59 negenenvijftigste verdieping
Floor:NLRS_23.21_FL_breedplaat d=60_gen:12979430:2 | 59 negenenvijftigste verdieping | 23.21 vloeren - constructief, vrijdragende vloeren (Uniformat)
Floor:NLRS_23.21_FL_breedplaat d=60_gen:12979430:3 | 59 negenenvijftigste verdieping | 23.21 vloeren - constructief, vrijdragende vloeren (Uniformat)
Floor:NLRS_23.21_FL_breedplaat d=60_gen:12980273:2 | 55 vijfenvijftigste verdieping | 23.21 vloeren - constructief, vrijdragende vloeren (Uniformat)
Floor:NLRS_23.21_FL_breedplaat d=60_gen:12980435:2 | 54 vierenvijftigste verdieping | 23.21 vloeren - constructief, vrijdragende vloeren (Uniformat)
Floor:NLRS_23.21_FL_breedplaat d=60_gen:12980523:2 | 53 drieënvijftigste verdieping | 23.21 vloeren - constructief, vrijdragende vloeren (Uniformat)
Floor:NLRS_23.21_FL_breedplaat d=100_gen:12980673:2 | 53 drieënvijftigste verdieping | 23.21 vloeren - constructief, vrijdragende vloeren (Uniformat)
Floor:NLRS_23.21_FL_breedplaat d=60_gen:12981736:2 | 52 tweeënvijftigste verdieping | 23.21 vloeren - constructief, vrijdragende vloeren (Uniformat)
Floor:NLRS_23.21_FL_breedplaat d=60_gen:12984968:2 | 51 eenenvijftigste verdieping | 23.21 vloeren - constructief, vrijdragende vloeren (Uniformat) | Model Group:NLRS_22.21_WA_kern 06--51_gen:4980182
Floor:NLRS_23.21_FL_breedplaat d=60_gen:12986268:2 | 06 zesde verdieping | 23.21 vloeren - constructief, vrijdragende vloeren (Uniformat) | Model Group:NLRS_22.21_WA_kern 06--51_gen:4690937
Floor:NLRS_23.21_FL_breedplaat d=60_gen:12986296:2 | 07 zevende verdieping | 23.21 vloeren - constructief, vrijdragende vloeren (Uniformat) | Model Group:NLRS_22.21_WA_kern 06--51_gen:4689379
Floor:NLRS_23.21_FL_breedplaat d=60_gen:12986310:2 | 08 achtste verdieping | 23.21 vloeren - constructief, vrijdragende vloeren (Uniformat) | Model Group:NLRS_22.21_WA_kern 06--51_gen:4715051
Floor:NLRS_23.21_FL_breedplaat d=60_gen:12986324:2 | 12 twaalfde verdieping | 23.21 vloeren - constructief, vrijdragende vloeren (Uniformat) | Model Group:NLRS_22.21_WA_kern 06--51_gen:4738448
Floor:NLRS_23.21_FL_breedplaat d=60_gen:12986338:2 | 09 negende verdieping | 23.21 vloeren - constructief, vrijdragende vloeren (Uniformat) | Model Group:NLRS_22.21_WA_kern 06--51_gen:5667376
Floor:NLRS_23.21_FL_breedplaat d=60_gen:12986352:2 | 10 tiende verdieping | 23.21 vloeren - constructief, vrijdragende vloeren (Uniformat) | Model Group:NLRS_22.21_WA_kern 06--51_gen:6859079
Floor:NLRS_23.21_FL_breedplaat d=60_gen:12986366:2 | 11 elfde verdieping | 23.21 vloeren - constructief, vrijdragende vloeren (Uniformat) | Model Group:NLRS_22.21_WA_kern 06--51_gen:6861592
Floor:NLRS_23.21_FL_breedplaat d=60_gen:12986380:2 | 13 dertiende verdieping | 23.21 vloeren - constructief, vrijdragende vloeren (Uniformat) | Model Group:NLRS_22.21_WA_kern 06--51_gen:4730861
Floor:NLRS_23.21_FL_breedplaat d=60_gen:12986394:2 | 15 vijftiende verdieping | 23.21 vloeren - constructief, vrijdragende vloeren (Uniformat) | Model Group:NLRS_22.21_WA_kern 06--51_gen:4731319
Floor:NLRS_23.21_FL_breedplaat d=60_gen:12986408:2 | 17 zeventiende verdieping | 23.21 vloeren - constructief, vrijdragende vloeren (Uniformat) | Model Group:NLRS_22.21_WA_kern 06--51_gen:4731777
Floor:NLRS_23.21_FL_breedplaat d=60_gen:12986422:2 | 19 negentiende verdieping | 23.21 vloeren - constructief, vrijdragende vloeren (Uniformat) | Model Group:NLRS_22.21_WA_kern 06--51_gen:4732235
Floor:NLRS_23.21_FL_breedplaat d=60_gen:12986436:2 | 14 veertiende verdieping | 23.21 vloeren - constructief, vrijdragende vloeren (Uniformat) | Model Group:NLRS_22.21_WA_kern 06--51_gen:4738906
Floor:NLRS_23.21_FL_breedplaat d=60_gen:12986450:2 | 16 zestiende verdieping | 23.21 vloeren - constructief, vrijdragende vloeren (Uniformat) | Model Group:NLRS_22.21_WA_kern 06--51_gen:4739364
Floor:NLRS_23.21_FL_breedplaat d=60_gen:12986464:2 | 18 achttiende verdieping | 23.21 vloeren - constructief, vrijdragende vloeren (Uniformat) | Model Group:NLRS_22.21_WA_kern 06--51_gen:4739822
Floor:NLRS_23.21_FL_breedplaat d=60_gen:12986478:2 | 20 twintigste verdieping | 23.21 vloeren - constructief, vrijdragende vloeren (Uniformat) | Model Group:NLRS_22.21_WA_kern 06--51_gen:4740280
Floor:NLRS_23.21_FL_breedplaat d=60_gen:12986492:2 | 21 eenentwintigste verdieping | 23.21 vloeren - constructief, vrijdragende vloeren (Uniformat) | Model Group:NLRS_22.21_WA_kern 06--51_gen:4695238
Floor:NLRS_23.21_FL_breedplaat d=60_gen:12986506:2 | 24 vierentwintigste verdieping | 23.21 vloeren - constructief, vrijdragende vloeren (Uniformat) | Model Group:NLRS_22.21_WA_kern 06--51_gen:4746873
Floor:NLRS_23.21_FL_breedplaat d=60_gen:12986520:2 | 25 vijfentwintigste verdieping | 23.21 vloeren - constructief, vrijdragende vloeren (Uniformat) | Model Group:NLRS_22.21_WA_kern 06--51_gen:4747305
Floor:NLRS_23.21_FL_breedplaat d=60_gen:12986534:2 | 26 zesentwintigste verdieping | 23.21 vloeren - constructief, vrijdragende vloeren (Uniformat) | Model Group:NLRS_22.21_WA_kern 06--51_gen:4747737
Floor:NLRS_23.21_FL_breedplaat d=60_gen:12986548:2 | 27 zevenentwintigste verdieping | 23.21 vloeren - constructief, vrijdragende vloeren (Uniformat) | Model Group:NLRS_22.21_WA_kern 06--51_gen:4748169
Floor:NLRS_23.21_FL_breedplaat d=60_gen:12986562:2 | 28 achtentwintigste verdieping | 23.21 vloeren - constructief, vrijdragende vloeren (Uniformat) | Model Group:NLRS_22.21_WA_kern 06--51_gen:4748601
Floor:NLRS_23.21_FL_breedplaat d=60_gen:12986576:2 | 29 negenentwintigste verdieping | 23.21 vloeren - constructief, vrijdragende vloeren (Uniformat) | Model Group:NLRS_22.21_WA_kern 06--51_gen:4749033
Floor:NLRS_23.21_FL_breedplaat d=60_gen:12986590:2 | 30 dertigste verdieping | 23.21 vloeren - constructief, vrijdragende vloeren (Uniformat) | Model Group:NLRS_22.21_WA_kern 06--51_gen:4749465
Floor:NLRS_23.21_FL_breedplaat d=60_gen:12986604:2 | 31 eenendertigste verdieping | 23.21 vloeren - constructief, vrijdragende vloeren (Uniformat) | Model Group:NLRS_22.21_WA_kern 06--51_gen:4749897
Floor:NLRS_23.21_FL_breedplaat d=60_gen:12986618:2 | 32 tweeëndertigste verdieping | 23.21 vloeren - constructief, vrijdragende vloeren (Uniformat) | Model Group:NLRS_22.21_WA_kern 06--51_gen:4750329
Floor:NLRS_23.21_FL_breedplaat d=60_gen:12986632:2 | 33 drieëndertigste verdieping | 23.21 vloeren - constructief, vrijdragende vloeren (Uniformat) | Model Group:NLRS_22.21_WA_kern 06--51_gen:4750761
Floor:NLRS_23.21_FL_breedplaat d=60_gen:12986646:2 | 34 vierendertigste verdieping | 23.21 vloeren - constructief, vrijdragende vloeren (Uniformat) | Model Group:NLRS_22.21_WA_kern 06--51_gen:4751193
Floor:NLRS_23.21_FL_breedplaat d=60_gen:12986660:2 | 35 vijfendertigste verdieping | 23.21 vloeren - constructief, vrijdragende vloeren (Uniformat) | Model Group:NLRS_22.21_WA_kern 06--51_gen:4751625
Floor:NLRS_23.21_FL_breedplaat d=60_gen:12986674:2 | 36 zesendertigste verdieping | 23.21 vloeren - constructief, vrijdragende vloeren (Uniformat) | Model Group:NLRS_22.21_WA_kern 06--51_gen:4752057
Floor:NLRS_23.21_FL_breedplaat d=60_gen:12986688:2 | 37 zevenendertigste verdieping | 23.21 vloeren - constructief, vrijdragende vloeren (Uniformat) | Model Group:NLRS_22.21_WA_kern 06--51_gen:4752489
Floor:NLRS_23.21_FL_breedplaat d=60_gen:12986702:2 | 38 achtendertigste verdieping | 23.21 vloeren - constructief, vrijdragende vloeren (Uniformat) | Model Group:NLRS_22.21_WA_kern 06--51_gen:4752921
Floor:NLRS_23.21_FL_breedplaat d=60_gen:12986716:2 | 39 negenendertigste verdieping | 23.21 vloeren - constructief, vrijdragende vloeren (Uniformat) | Model Group:NLRS_22.21_WA_kern 06--51_gen:4753353
Floor:NLRS_23.21_FL_breedplaat d=60_gen:12986730:2 | 40 veertigste verdieping | 23.21 vloeren - constructief, vrijdragende vloeren (Uniformat) | Model Group:NLRS_22.21_WA_kern 06--51_gen:4753785
Floor:NLRS_23.21_FL_breedplaat d=60_gen:12986744:2 | 22 tweeëntwintigste verdieping | 23.21 vloeren - constructief, vrijdragende vloeren (Uniformat) | Model Group:NLRS_22.21_WA_kern 06--51_gen:4778253
Floor:NLRS_23.21_FL_breedplaat d=60_gen:12986758:2 | 23 drieëntwintigste verdieping | 23.21 vloeren - constructief, vrijdragende vloeren (Uniformat) | Model Group:NLRS_22.21_WA_kern 06--51_gen:4779836
Floor:NLRS_23.21_FL_breedplaat d=60_gen:12986772:2 | 41 eenenveertigste verdieping | 23.21 vloeren - constructief, vrijdragende vloeren (Uniformat) | Model Group:NLRS_22.21_WA_kern 06--51_gen:4783953
Floor:NLRS_23.21_FL_breedplaat d=60_gen:12986786:2 | 43 drieënveertigste verdieping | 23.21 vloeren - constructief, vrijdragende vloeren (Uniformat) | Model Group:NLRS_22.21_WA_kern 06--51_gen:4788999
Floor:NLRS_23.21_FL_breedplaat d=60_gen:12986800:2 | 44 vierenveertigste verdieping | 23.21 vloeren - constructief, vrijdragende vloeren (Uniformat) | Model Group:NLRS_22.21_WA_kern 06--51_gen:4789431
Floor:NLRS_23.21_FL_breedplaat d=60_gen:12986814:2 | 45 vijfenveertigste verdieping | 23.21 vloeren - constructief, vrijdragende vloeren (Uniformat) | Model Group:NLRS_22.21_WA_kern 06--51_gen:4789863
Floor:NLRS_23.21_FL_breedplaat d=60_gen:12986828:2 | 46 zesenveertigste verdieping | 23.21 vloeren - constructief, vrijdragende vloeren (Uniformat) | Model Group:NLRS_22.21_WA_kern 06--51_gen:4790295
Floor:NLRS_23.21_FL_breedplaat d=60_gen:12986842:2 | 47 zevenenveertigste verdieping | 23.21 vloeren - constructief, vrijdragende vloeren (Uniformat) | Model Group:NLRS_22.21_WA_kern 06--51_gen:4790727
Floor:NLRS_23.21_FL_breedplaat d=60_gen:12986856:2 | 48 achtenveertigste verdieping | 23.21 vloeren - constructief, vrijdragende vloeren (Uniformat) | Model Group:NLRS_22.21_WA_kern 06--51_gen:4791159
Floor:NLRS_23.21_FL_breedplaat d=60_gen:12986870:2 | 49 negenenveertigste verdieping | 23.21 vloeren - constructief, vrijdragende vloeren (Uniformat) | Model Group:NLRS_22.21_WA_kern 06--51_gen:4791591
Floor:NLRS_23.21_FL_breedplaat d=60_gen:12986884:2 | 50 vijftigste verdieping | 23.21 vloeren - constructief, vrijdragende vloeren (Uniformat) | Model Group:NLRS_22.21_WA_kern 06--51_gen:4792023
Floor:NLRS_23.21_FL_breedplaat d=60_gen:12986898:2 | 42 tweeënveertigste verdieping | 23.21 vloeren - constructief, vrijdragende vloeren (Uniformat) | Model Group:NLRS_22.21_WA_kern 06--51_gen:4803472
5 x Basic Wall:NLRS_21.21_WA_beton prefab d=120_gen:13519128 | 03 derde verdieping | 21.21 buitenwanden - constructief, massieve wanden (Uniformat) | Model Group:Wand-W07:13522560
5 x Basic Wall:NLRS_21.21_WA_beton prefab d=120_gen:13522830 | 03 derde verdieping | 21.21 buitenwanden - constructief, massieve wanden (Uniformat) | Model Group:Wand-W07:13522837
5 x Basic Wall:NLRS_21.21_WA_beton prefab d=120_gen:13522982 | 03 derde verdieping | 21.21 buitenwanden - constructief, massieve wanden (Uniformat) | Model Group:Wand-W07:13522989
5 x Basic Wall:NLRS_21.21_WA_beton prefab d=120_gen:13523114 | 03 derde verdieping | 21.21 buitenwanden - constructief, massieve wanden (Uniformat) | Model Group:Wand-W07:13523121
5 x Basic Wall:NLRS_21.21_WA_beton prefab d=120_gen:13523271 | 03 derde verdieping | 21.21 buitenwanden - constructief, massieve wanden (Uniformat) | Model Group:Wand-W08:13523638
4 x Basic Wall:NLRS_21.21_WA_beton prefab d=120_gen:13524057 | 03 derde verdieping | 21.21 buitenwanden - constructief, massieve wanden (Uniformat) | Model Group:Wand-W09:13524131
4 x Basic Wall:NLRS_21.21_WA_beton prefab d=120_gen:13524640 | 03 derde verdieping | 21.21 buitenwanden - constructief, massieve wanden (Uniformat) | Model Group:Wand-W09:13524646
5 x Basic Wall:NLRS_21.21_WA_beton prefab d=120_gen:13525071 | 03 derde verdieping | 21.21 buitenwanden - constructief, massieve wanden (Uniformat) | Model Group:Wand-W08:13525078
5 x Basic Wall:NLRS_21.21_WA_beton prefab d=120_gen:13525239 | 03 derde verdieping | 21.21 buitenwanden - constructief, massieve wanden (Uniformat) | Model Group:Wand-W10:13525310
5 x Basic Wall:NLRS_21.21_WA_beton prefab d=120_gen:13525810 | 03 derde verdieping | 21.21 buitenwanden - constructief, massieve wanden (Uniformat) | Model Group:Wand-W06:13525900
4 x Basic Wall:NLRS_21.21_WA_beton prefab d=120_gen:13526728 | 03 derde verdieping | 21.21 buitenwanden - constructief, massieve wanden (Uniformat) | Model Group:Wand-W02:13526804
4 x Basic Wall:NLRS_21.21_WA_beton prefab d=120_gen:13528166 | 03 derde verdieping | 21.21 buitenwanden - constructief, massieve wanden (Uniformat) | Model Group:Wand-W02:13528171
4 x Basic Wall:NLRS_21.21_WA_beton prefab d=120_gen:13532310 | 03 derde verdieping | 21.21 buitenwanden - constructief, massieve wanden (Uniformat) | Model Group:Wand-W12:13532636
4 x Basic Wall:NLRS_21.21_WA_beton prefab d=120_gen:13533034 | 03 derde verdieping | 21.21 buitenwanden - constructief, massieve wanden (Uniformat) | Model Group:Wand-W12:13533040
4 x Basic Wall:NLRS_21.21_WA_beton prefab d=120_gen:13533263 | 03 derde verdieping | 21.21 buitenwanden - constructief, massieve wanden (Uniformat) | Model Group:Wand-W13:13533316
4 x Basic Wall:NLRS_21.21_WA_beton prefab d=120_gen:13534294 | 03 derde verdieping | 21.21 buitenwanden - constructief, massieve wanden (Uniformat) | Model Group:Wand-W13:13534299
4 x Basic Wall:NLRS_21.21_WA_beton prefab d=120_gen:13534542 | 03 derde verdieping | 21.21 buitenwanden - constructief, massieve wanden (Uniformat) | Model Group:Wand-W13A:13534595
4 x Basic Wall:NLRS_21.21_WA_beton prefab d=120_gen:13534927 | 03 derde verdieping | 21.21 buitenwanden - constructief, massieve wanden (Uniformat) | Model Group:Wand-W13A:13534933
4 x Basic Wall:NLRS_21.21_WA_beton prefab d=120_gen:13535213 | 03 derde verdieping | 21.21 buitenwanden - constructief, massieve wanden (Uniformat) | Model Group:Wand-W13:13535218
4 x Basic Wall:NLRS_21.21_WA_beton prefab d=120_gen:13535225 | 03 derde verdieping | 21.21 buitenwanden - constructief, massieve wanden (Uniformat) | Model Group:Wand-W13A:13535231
4 x Basic Wall:NLRS_21.21_WA_beton prefab d=120_gen:13535235 | 03 derde verdieping | 21.21 buitenwanden - constructief, massieve wanden (Uniformat) | Model Group:Wand-W13A:13535241
4 x Basic Wall:NLRS_21.21_WA_beton prefab d=120_gen:13535589 | 03 derde verdieping | 21.21 buitenwanden - constructief, massieve wanden (Uniformat) | Model Group:Wand-W12:13535595
4 x Basic Wall:NLRS_21.21_WA_beton prefab d=120_gen:13535596 | 03 derde verdieping | 21.21 buitenwanden - constructief, massieve wanden (Uniformat) | Model Group:Wand-W12:13535602
4 x Basic Wall:NLRS_21.21_WA_beton prefab d=120_gen:13535608 | 03 derde verdieping | 21.21 buitenwanden - constructief, massieve wanden (Uniformat) | Model Group:Wand-W13:13535613
4 x Basic Wall:NLRS_21.21_WA_beton prefab d=120_gen:13535821 | 03 derde verdieping | 21.21 buitenwanden - constructief, massieve wanden (Uniformat) | Model Group:Wand-W11:13535873
4 x Basic Wall:NLRS_21.21_WA_beton prefab d=120_gen:13536533 | 03 derde verdieping | 21.21 buitenwanden - constructief, massieve wanden (Uniformat) | Model Group:Wand-W04:13536604
2 x Basic Wall:NLRS_21.21_WA_beton prefab d=120_gen:13536971 | 03 derde verdieping | 21.21 buitenwanden - constructief, massieve wanden (Uniformat) | Model Group:Wand-W05:13537097
2 x Basic Wall:NLRS_21.21_WA_beton prefab d=120_gen:13538081 | 03 derde verdieping | 21.21 buitenwanden - constructief, massieve wanden (Uniformat) | Model Group:Wand-W05A:13538256
Basic Wall:NLRS_21.21_WA_beton prefab d=120_gen:13538623 | 01 eerste verdieping | 21.21 buitenwanden - constructief, massieve wanden (Uniformat)
2 x Basic Wall:NLRS_21.21_WA_beton prefab d=120_gen:13541579 | 02 tweede verdieping | 21.21 buitenwanden - constructief, massieve wanden (Uniformat)
2 x Basic Wall:NLRS_21.21_WA_beton prefab d=120_gen:13542162 | 01 eerste verdieping | 21.21 buitenwanden - constructief, massieve wanden (Uniformat)
Basic Wall:NLRS_21.21_WA_beton prefab d=120_gen:13543208 | 02 tweede verdieping | 21.21 buitenwanden - constructief, massieve wanden (Uniformat)
Basic Wall:NLRS_21.21_WA_beton prefab d=120_gen:13543503 | 00 begane grond | 21.21 buitenwanden - constructief, massieve wanden (Uniformat)
4 x Basic Wall:NLRS_21.21_WA_beton prefab d=120_gen:13612003 | 03 derde verdieping | 21.21 buitenwanden - constructief, massieve wanden (Uniformat) | Model Group:Wand-W02:13612008
4 x Basic Wall:NLRS_21.21_WA_beton prefab d=120_gen:13612010 | 03 derde verdieping | 21.21 buitenwanden - constructief, massieve wanden (Uniformat) | Model Group:Wand-W02:13612015
2 x Basic Wall:NLRS_21.21_WA_beton prefab d=200_gen:14102016 | 05 vijfde verdieping | 21.21 buitenwanden - constructief, massieve wanden (Uniformat)
Floor:NLRS_23.21_FL_beton ihwg d=150_gen:14222862:2 | 62 tweeënzestigste verdieping | 23.21 vloeren - constructief, vrijdragende vloeren (Uniformat)
3 x  | 57 zevenenvijftigste verdieping
2 x Basic Wall:NLRS_22.21_WA_beton prefab d=250_gen:14269845 | 55 vijfenvijftigste verdieping | 22.21 binnenwanden - constructief, massieve wanden (Uniformat)
Floor:NLRS_13.22_FL_beton ihwg d=180_gen:14295784:2 | 62 tweeënzestigste verdieping | 13.22 vloeren op grondslag - constructief, vloeren als gebouwonderdeel (Uniformat)

# IfcOpeningElement: Recess (253)
Name (Basic Wall:...) | In | Classification | Group
4 x NLRS_22.21_WA_beton prefab d=200_gen:4690668 | 06 zesde verdieping | 22.21 binnenwanden - constructief, massieve wanden (Uniformat) | Model Group:NLRS_22.21_WA_kern 06--51_gen:4690937
4 x NLRS_22.21_WA_beton prefab d=200_gen:4822193 | 05 vijfde verdieping | 22.21 binnenwanden - constructief, massieve wanden (Uniformat) | Model Group:NLRS_22.21_WA_kern 05_gen:8891248
4 x NLRS_22.21_WA_beton prefab d=200_gen:4832690 | 03 derde verdieping | 22.21 binnenwanden - constructief, massieve wanden (Uniformat) | Model Group:NLRS_22.21_WA_kern 01--04_gen:4832721
NLRS_21.21_WA_beton ihwg d=1000_gen:4832743 | 03 derde verdieping | 21.21 buitenwanden - constructief, massieve wanden (Uniformat)
4 x NLRS_22.21_WA_beton prefab d=200_gen:4869702 | 02 tweede verdieping | 22.21 binnenwanden - constructief, massieve wanden (Uniformat) | Model Group:NLRS_22.21_WA_kern 01--04_gen:4869716
4 x NLRS_22.21_WA_beton prefab d=200_gen:4941776 | 04 vierde verdieping | 22.21 binnenwanden - constructief, massieve wanden (Uniformat) | Model Group:NLRS_22.21_WA_kern 01--04_gen:4941798
2 x NLRS_21.21_WA_beton ihwg d=1000_gen:4941826 | 04 vierde verdieping | 21.21 buitenwanden - constructief, massieve wanden (Uniformat)
4 x NLRS_22.21_WA_beton prefab d=200_gen:4971864 | 53 drieënvijftigste verdieping | 22.21 binnenwanden - constructief, massieve wanden (Uniformat)
4 x NLRS_22.21_WA_beton prefab d=200_gen:4981724 | 52 tweeënvijftigste verdieping | 22.21 binnenwanden - constructief, massieve wanden (Uniformat)
NLRS_21.21_WA_beton prefab d=300/320_gen:4981801 | 52 tweeënvijftigste verdieping | 21.21 buitenwanden - constructief, massieve wanden (Uniformat) | Model Group:NLRS_21.21_WA_wand 002c d=300_gen:4981779
NLRS_21.21_WA_beton prefab d=300/320_gen:4981803 | 52 tweeënvijftigste verdieping | 21.21 buitenwanden - constructief, massieve wanden (Uniformat) | Model Group:NLRS_21.21_WA_wand 002c d=300_gen:4981772
NLRS_21.21_WA_beton prefab d=300/320_gen:4981827 | 52 tweeënvijftigste verdieping | 21.21 buitenwanden - constructief, massieve wanden (Uniformat) | Model Group:NLRS_21.21_WA_wand 004c d=300_gen:4981771
NLRS_21.21_WA_beton prefab d=300/320_gen:4981829 | 52 tweeënvijftigste verdieping | 21.21 buitenwanden - constructief, massieve wanden (Uniformat) | Model Group:NLRS_21.21_WA_wand 004c d=300_gen:4981762
NLRS_21.21_WA_beton prefab d=300/320_gen:4981993 | 52 tweeënvijftigste verdieping | 21.21 buitenwanden - constructief, massieve wanden (Uniformat) | Model Group:NLRS_28.21_WA_3D element 002a d=300_gen:4981919
NLRS_21.21_WA_beton prefab d=300/320_gen:4981995 | 52 tweeënvijftigste verdieping | 21.21 buitenwanden - constructief, massieve wanden (Uniformat) | Model Group:NLRS_28.21_WA_3D element 002a d=300_gen:4981919
NLRS_21.21_WA_beton prefab d=300/320_gen:4982037 | 52 tweeënvijftigste verdieping | 21.21 buitenwanden - constructief, massieve wanden (Uniformat) | Model Group:NLRS_28.21_WA_3D element 001a d=300_gen:4981918
NLRS_21.21_WA_beton prefab d=300/320_gen:4982040 | 52 tweeënvijftigste verdieping | 21.21 buitenwanden - constructief, massieve wanden (Uniformat) | Model Group:NLRS_28.21_WA_3D element 001a d=300_gen:4981918
4 x NLRS_22.21_WA_beton prefab d=200_gen:5001092 | 54 vierenvijftigste verdieping | 22.21 binnenwanden - constructief, massieve wanden (Uniformat)
4 x NLRS_22.21_WA_beton prefab d=200_gen:5003626 | 57 zevenenvijftigste verdieping | 22.21 binnenwanden - constructief, massieve wanden (Uniformat)
6 x NLRS_22.21_WA_beton prefab d=200_gen:5009602 | 56 zesenvijftigste verdieping | 22.21 binnenwanden - constructief, massieve wanden (Uniformat)
NLRS_22.21_WA_beton prefab d=200_gen:5009649 | 56 zesenvijftigste verdieping | 22.21 binnenwanden - constructief, massieve wanden (Uniformat)
4 x NLRS_22.21_WA_beton prefab d=200_gen:5009933 | 55 vijfenvijftigste verdieping | 22.21 binnenwanden - constructief, massieve wanden (Uniformat)
NLRS_21.21_WA_beton prefab d=300/320_gen:5043322 | 52 tweeënvijftigste verdieping | 21.21 buitenwanden - constructief, massieve wanden (Uniformat) | Model Group:NLRS_28.21_WA_3D element 002a d=300_gen:4981935
NLRS_21.21_WA_beton prefab d=300/320_gen:5043324 | 52 tweeënvijftigste verdieping | 21.21 buitenwanden - constructief, massieve wanden (Uniformat) | Model Group:NLRS_28.21_WA_3D element 002a d=300_gen:4981935
NLRS_21.21_WA_beton prefab d=300/320_gen:5044687 | 52 tweeënvijftigste verdieping | 21.21 buitenwanden - constructief, massieve wanden (Uniformat) | Model Group:NLRS_28.21_WA_3D element 001a d=300_gen:4981936
NLRS_21.21_WA_beton prefab d=300/320_gen:5044690 | 52 tweeënvijftigste verdieping | 21.21 buitenwanden - constructief, massieve wanden (Uniformat) | Model Group:NLRS_28.21_WA_3D element 001a d=300_gen:4981936
NLRS_21.21_WA_beton prefab d=300/320_gen:5528547 | 52 tweeënvijftigste verdieping | 21.21 buitenwanden - constructief, massieve wanden (Uniformat) | Model Group:NLRS_21.21_WA_wand 004c d=300_gen:4981762
NLRS_21.21_WA_beton prefab d=300/320_gen:5528784 | 52 tweeënvijftigste verdieping | 21.21 buitenwanden - constructief, massieve wanden (Uniformat) | Model Group:NLRS_21.21_WA_wand 004c d=300_gen:4981771
NLRS_21.21_WA_beton prefab d=300/320_gen:5529195 | 52 tweeënvijftigste verdieping | 21.21 buitenwanden - constructief, massieve wanden (Uniformat) | Model Group:NLRS_21.21_WA_wand 002c d=300_gen:4981772
NLRS_21.21_WA_beton prefab d=300/320_gen:5529401 | 52 tweeënvijftigste verdieping | 21.21 buitenwanden - constructief, massieve wanden (Uniformat) | Model Group:NLRS_21.21_WA_wand 002c d=300_gen:4981779
4 x NLRS_22.21_WA_beton prefab d=200_gen:8873640 | 07 zevende verdieping | 22.21 binnenwanden - constructief, massieve wanden (Uniformat) | Model Group:NLRS_22.21_WA_kern 06--51_gen:4689379
4 x NLRS_22.21_WA_beton prefab d=200_gen:8873902 | 08 achtste verdieping | 22.21 binnenwanden - constructief, massieve wanden (Uniformat) | Model Group:NLRS_22.21_WA_kern 06--51_gen:4715051
4 x NLRS_22.21_WA_beton prefab d=200_gen:8873959 | 12 twaalfde verdieping | 22.21 binnenwanden - constructief, massieve wanden (Uniformat) | Model Group:NLRS_22.21_WA_kern 06--51_gen:4738448
4 x NLRS_22.21_WA_beton prefab d=200_gen:8874016 | 09 negende verdieping | 22.21 binnenwanden - constructief, massieve wanden (Uniformat) | Model Group:NLRS_22.21_WA_kern 06--51_gen:5667376
4 x NLRS_22.21_WA_beton prefab d=200_gen:8874073 | 10 tiende verdieping | 22.21 binnenwanden - constructief, massieve wanden (Uniformat) | Model Group:NLRS_22.21_WA_kern 06--51_gen:6859079
4 x NLRS_22.21_WA_beton prefab d=200_gen:8874130 | 11 elfde verdieping | 22.21 binnenwanden - constructief, massieve wanden (Uniformat) | Model Group:NLRS_22.21_WA_kern 06--51_gen:6861592
4 x NLRS_22.21_WA_beton prefab d=200_gen:8875618 | 13 dertiende verdieping | 22.21 binnenwanden - constructief, massieve wanden (Uniformat) | Model Group:NLRS_22.21_WA_kern 06--51_gen:4730861
4 x NLRS_22.21_WA_beton prefab d=200_gen:8875675 | 15 vijftiende verdieping | 22.21 binnenwanden - constructief, massieve wanden (Uniformat) | Model Group:NLRS_22.21_WA_kern 06--51_gen:4731319
4 x NLRS_22.21_WA_beton prefab d=200_gen:8875732 | 17 zeventiende verdieping | 22.21 binnenwanden - constructief, massieve wanden (Uniformat) | Model Group:NLRS_22.21_WA_kern 06--51_gen:4731777
4 x NLRS_22.21_WA_beton prefab d=200_gen:8875789 | 19 negentiende verdieping | 22.21 binnenwanden - constructief, massieve wanden (Uniformat) | Model Group:NLRS_22.21_WA_kern 06--51_gen:4732235
4 x NLRS_22.21_WA_beton prefab d=200_gen:8875846 | 14 veertiende verdieping | 22.21 binnenwanden - constructief, massieve wanden (Uniformat) | Model Group:NLRS_22.21_WA_kern 06--51_gen:4738906
4 x NLRS_22.21_WA_beton prefab d=200_gen:8875903 | 16 zestiende verdieping | 22.21 binnenwanden - constructief, massieve wanden (Uniformat) | Model Group:NLRS_22.21_WA_kern 06--51_gen:4739364
4 x NLRS_22.21_WA_beton prefab d=200_gen:8875960 | 18 achttiende verdieping | 22.21 binnenwanden - constructief, massieve wanden (Uniformat) | Model Group:NLRS_22.21_WA_kern 06--51_gen:4739822
4 x NLRS_22.21_WA_beton prefab d=200_gen:8876017 | 20 twintigste verdieping | 22.21 binnenwanden - constructief, massieve wanden (Uniformat) | Model Group:NLRS_22.21_WA_kern 06--51_gen:4740280
4 x NLRS_22.21_WA_beton prefab d=200_gen:8879094 | 21 eenentwintigste verdieping | 22.21 binnenwanden - constructief, massieve wanden (Uniformat) | Model Group:NLRS_22.21_WA_kern 06--51_gen:4695238
4 x NLRS_22.21_WA_beton prefab d=200_gen:8879151 | 24 vierentwintigste verdieping | 22.21 binnenwanden - constructief, massieve wanden (Uniformat) | Model Group:NLRS_22.21_WA_kern 06--51_gen:4746873
4 x NLRS_22.21_WA_beton prefab d=200_gen:8879208 | 25 vijfentwintigste verdieping | 22.21 binnenwanden - constructief, massieve wanden (Uniformat) | Model Group:NLRS_22.21_WA_kern 06--51_gen:4747305
4 x NLRS_22.21_WA_beton prefab d=200_gen:8879265 | 26 zesentwintigste verdieping | 22.21 binnenwanden - constructief, massieve wanden (Uniformat) | Model Group:NLRS_22.21_WA_kern 06--51_gen:4747737
4 x NLRS_22.21_WA_beton prefab d=200_gen:8879322 | 27 zevenentwintigste verdieping | 22.21 binnenwanden - constructief, massieve wanden (Uniformat) | Model Group:NLRS_22.21_WA_kern 06--51_gen:4748169
4 x NLRS_22.21_WA_beton prefab d=200_gen:8879379 | 28 achtentwintigste verdieping | 22.21 binnenwanden - constructief, massieve wanden (Uniformat) | Model Group:NLRS_22.21_WA_kern 06--51_gen:4748601
4 x NLRS_22.21_WA_beton prefab d=200_gen:8879436 | 29 negenentwintigste verdieping | 22.21 binnenwanden - constructief, massieve wanden (Uniformat) | Model Group:NLRS_22.21_WA_kern 06--51_gen:4749033
4 x NLRS_22.21_WA_beton prefab d=200_gen:8879493 | 30 dertigste verdieping | 22.21 binnenwanden - constructief, massieve wanden (Uniformat) | Model Group:NLRS_22.21_WA_kern 06--51_gen:4749465
4 x NLRS_22.21_WA_beton prefab d=200_gen:8879550 | 31 eenendertigste verdieping | 22.21 binnenwanden - constructief, massieve wanden (Uniformat) | Model Group:NLRS_22.21_WA_kern 06--51_gen:4749897
4 x NLRS_22.21_WA_beton prefab d=200_gen:8879607 | 32 tweeëndertigste verdieping | 22.21 binnenwanden - constructief, massieve wanden (Uniformat) | Model Group:NLRS_22.21_WA_kern 06--51_gen:4750329
4 x NLRS_22.21_WA_beton prefab d=200_gen:8879664 | 33 drieëndertigste verdieping | 22.21 binnenwanden - constructief, massieve wanden (Uniformat) | Model Group:NLRS_22.21_WA_kern 06--51_gen:4750761
4 x NLRS_22.21_WA_beton prefab d=200_gen:8879721 | 34 vierendertigste verdieping | 22.21 binnenwanden - constructief, massieve wanden (Uniformat) | Model Group:NLRS_22.21_WA_kern 06--51_gen:4751193
4 x NLRS_22.21_WA_beton prefab d=200_gen:8879778 | 35 vijfendertigste verdieping | 22.21 binnenwanden - constructief, massieve wanden (Uniformat) | Model Group:NLRS_22.21_WA_kern 06--51_gen:4751625
4 x NLRS_22.21_WA_beton prefab d=200_gen:8879835 | 36 zesendertigste verdieping | 22.21 binnenwanden - constructief, massieve wanden (Uniformat) | Model Group:NLRS_22.21_WA_kern 06--51_gen:4752057
4 x NLRS_22.21_WA_beton prefab d=200_gen:8879892 | 37 zevenendertigste verdieping | 22.21 binnenwanden - constructief, massieve wanden (Uniformat) | Model Group:NLRS_22.21_WA_kern 06--51_gen:4752489
4 x NLRS_22.21_WA_beton prefab d=200_gen:8879949 | 38 achtendertigste verdieping | 22.21 binnenwanden - constructief, massieve wanden (Uniformat) | Model Group:NLRS_22.21_WA_kern 06--51_gen:4752921
4 x NLRS_22.21_WA_beton prefab d=200_gen:8880006 | 39 negenendertigste verdieping | 22.21 binnenwanden - constructief, massieve wanden (Uniformat) | Model Group:NLRS_22.21_WA_kern 06--51_gen:4753353
4 x NLRS_22.21_WA_beton prefab d=200_gen:8880063 | 40 veertigste verdieping | 22.21 binnenwanden - constructief, massieve wanden (Uniformat) | Model Group:NLRS_22.21_WA_kern 06--51_gen:4753785
4 x NLRS_22.21_WA_beton prefab d=200_gen:8880120 | 22 tweeëntwintigste verdieping | 22.21 binnenwanden - constructief, massieve wanden (Uniformat) | Model Group:NLRS_22.21_WA_kern 06--51_gen:4778253
4 x NLRS_22.21_WA_beton prefab d=200_gen:8880177 | 23 drieëntwintigste verdieping | 22.21 binnenwanden - constructief, massieve wanden (Uniformat) | Model Group:NLRS_22.21_WA_kern 06--51_gen:4779836
4 x NLRS_22.21_WA_beton prefab d=200_gen:8880234 | 41 eenenveertigste verdieping | 22.21 binnenwanden - constructief, massieve wanden (Uniformat) | Model Group:NLRS_22.21_WA_kern 06--51_gen:4783953
4 x NLRS_22.21_WA_beton prefab d=200_gen:8880291 | 43 drieënveertigste verdieping | 22.21 binnenwanden - constructief, massieve wanden (Uniformat) | Model Group:NLRS_22.21_WA_kern 06--51_gen:4788999
4 x NLRS_22.21_WA_beton prefab d=200_gen:8880348 | 44 vierenveertigste verdieping | 22.21 binnenwanden - constructief, massieve wanden (Uniformat) | Model Group:NLRS_22.21_WA_kern 06--51_gen:4789431
4 x NLRS_22.21_WA_beton prefab d=200_gen:8880405 | 45 vijfenveertigste verdieping | 22.21 binnenwanden - constructief, massieve wanden (Uniformat) | Model Group:NLRS_22.21_WA_kern 06--51_gen:4789863
4 x NLRS_22.21_WA_beton prefab d=200_gen:8880462 | 46 zesenveertigste verdieping | 22.21 binnenwanden - constructief, massieve wanden (Uniformat) | Model Group:NLRS_22.21_WA_kern 06--51_gen:4790295
4 x NLRS_22.21_WA_beton prefab d=200_gen:8880519 | 47 zevenenveertigste verdieping | 22.21 binnenwanden - constructief, massieve wanden (Uniformat) | Model Group:NLRS_22.21_WA_kern 06--51_gen:4790727
4 x NLRS_22.21_WA_beton prefab d=200_gen:8880576 | 48 achtenveertigste verdieping | 22.21 binnenwanden - constructief, massieve wanden (Uniformat) | Model Group:NLRS_22.21_WA_kern 06--51_gen:4791159
4 x NLRS_22.21_WA_beton prefab d=200_gen:8880633 | 49 negenenveertigste verdieping | 22.21 binnenwanden - constructief, massieve wanden (Uniformat) | Model Group:NLRS_22.21_WA_kern 06--51_gen:4791591
4 x NLRS_22.21_WA_beton prefab d=200_gen:8880690 | 50 vijftigste verdieping | 22.21 binnenwanden - constructief, massieve wanden (Uniformat) | Model Group:NLRS_22.21_WA_kern 06--51_gen:4792023
4 x NLRS_22.21_WA_beton prefab d=200_gen:8880747 | 42 tweeënveertigste verdieping | 22.21 binnenwanden - constructief, massieve wanden (Uniformat) | Model Group:NLRS_22.21_WA_kern 06--51_gen:4803472
4 x NLRS_22.21_WA_beton prefab d=200_gen:8880804 | 51 eenenvijftigste verdieping | 22.21 binnenwanden - constructief, massieve wanden (Uniformat) | Model Group:NLRS_22.21_WA_kern 06--51_gen:4980182
NLRS_22.21_WA_beton prefab d=300_gen:10345659 | 02 tweede verdieping | 22.21 binnenwanden - constructief, massieve wanden (Uniformat)
NLRS_22.21_WA_beton prefab d=300_gen:10345871 | 02 tweede verdieping | 22.21 binnenwanden - constructief, massieve wanden (Uniformat)
NLRS_22.21_WA_beton prefab d=300_gen:10357388 | 02 tweede verdieping | 22.21 binnenwanden - constructief, massieve wanden (Uniformat)
NLRS_21.21_WA_beton ihwg d=300_gen:12697309 | 52 tweeënvijftigste verdieping | 21.21 buitenwanden - constructief, massieve wanden (Uniformat) | Model Group:NLRS_21.21_WA_wand 002c d=300_gen:4981779
NLRS_21.21_WA_beton ihwg d=300_gen:12697466 | 52 tweeënvijftigste verdieping | 21.21 buitenwanden - constructief, massieve wanden (Uniformat) | Model Group:NLRS_21.21_WA_wand 002c d=300_gen:4981772
NLRS_21.21_WA_beton ihwg d=300_gen:12704491 | 52 tweeënvijftigste verdieping | 21.21 buitenwanden - constructief, massieve wanden (Uniformat) | Model Group:NLRS_21.21_WA_wand 004c d=300_gen:4981771
NLRS_21.21_WA_beton ihwg d=300_gen:12704527 | 52 tweeënvijftigste verdieping | 21.21 buitenwanden - constructief, massieve wanden (Uniformat) | Model Group:NLRS_21.21_WA_wand 004c d=300_gen:4981762

# IfcPile: NLRS_17.12_SFO_TLB_funderingspaal grondverdringend_gen:Fundex_r410/500 (43)
In: 00 begane grond
Classification: 17.12 paalfunderingen - niet geheid, dragende palen - geschroefd (grondverdringend) (Uniformat); Material: NLRS_f2_beton ihwg
Name (NLRS_17.12_SFO_TLB_funderingspaal grondverdringend_gen:Fundex_r410/500:...)
5175257
5175607
5175616
5175625
5175634
5175643
5175652
5175661
5175861
5175875
5175922
5176004
5176116
5176183
5176434
5176445
5176490
5176636
5176647
5176705
5176707
5176709
5176711
5176713
5176715
5176717
5176719
5176790
5176836
5176881
5176961
5176963
5177026
5177071
5177117
5177128
5242569
5744756
5942511
5942524
6026045
6026275
6310294

# IfcPile: NLRS_17.12_SFO_TLB_funderingspaal grondverdringend_gen:Tubex_r762/950 (163)
In: 00 begane grond
Classification: 17.12 paalfunderingen - niet geheid, dragende palen - geschroefd (grondverdringend) (Uniformat); Material: NLRS_f2_beton ihwg
Name (NLRS_17.12_SFO_TLB_funderingspaal grondverdringend_gen:Tubex_r762/950:...)
4459220
4570660
4570673
4570684
4570695
4570704
4570715
4570728
4570739
4570748
4570759
4570772
4570783
4570794
4570805
4570816
4570829
4570842
4570853
4570866
4570877
4570890
4570901
4570912
4570927
4570942
4570953
4570964
4570975
4570986
4570997
4571006
4571019
4571032
4571043
4571054
4571065
4571078
4571089
4571100
4571111
4571124
4571135
4571148
4571161
4571174
4571185
4571196
4571207
4571218
4571229
4571238
4571251
4571262
4571275
4571286
4571297
4571310
4571319
4571330
4571341
4571352
4571363
4571374
4571385
4571398
4571409
4571420
4571431
4571440
4571455
4571466
4571477
4571488
4571503
4571514
4571525
4571538
4571549
4571560
4571573
4571584
4571595
4571608
4571619
4571630
4571641
4571654
4571665
4571676
4571689
4571698
4571711
4571722
4571737
4571746
4571757
4571768
4571779
4571790
4571801
4571812
4571825
4571836
4571847
4571860
4571871
4571882
4571893
4571906
4571917
4571928
4571941
4571952
4571963
4571974
4571985
4571996
4572005
4572014
4572027
4572038
4572049
4572060
4572073
4572084
4572095
4572108
4572119
4572130
4572141
4572152
4572165
4572176
4572185
4572198
4572209
4572222
4572233
4572244
4572257
4572268
4572279
4572290
4572301
4572312
4572325
4572336
4572347
4572358
4572369
4572382
4572399
4572412
4572423
4572434
4572445
4572458
4572469
4572480
4572491
4572500
4572511

# IfcSlab: Floor:NLRS_13.22_FL_beton ihwg b=450_gen, Floor:NLRS_13.22_FL_beton ihwg b=450_gen:11892297
In: 57 zevenenvijftigste verdieping
PredefinedType: BASESLAB; Classification: 13.22 vloeren op grondslag - constructief, vloeren als gebouwonderdeel (Uniformat); Material: NLRS_f2_beton ihwg 450 mm
Pset_SlabCommon - IsExternal: yes; LoadBearing: yes; Reference: NLRS_13.22_FL_beton ihwg b=450_gen; ThermalTransmittance: 2.32444 kg/K/s3

# IfcSlab: Floor:NLRS_13.22_FL_beton ihwg d=1100_gen, Floor:NLRS_13.22_FL_beton ihwg d=1100_gen:4644582
In: 00 begane grond
PredefinedType: BASESLAB; Classification: 13.22 vloeren op grondslag - constructief, vloeren als gebouwonderdeel (Uniformat); Material: NLRS_f2_beton ihwg 1100 mm
Pset_SlabCommon - IsExternal: yes; LoadBearing: yes; PitchAngle: 0 deg; Reference: NLRS_13.22_FL_beton ihwg d=1100_gen; ThermalTransmittance: 0.950909 kg/K/s3

# IfcSlab: Floor:NLRS_13.22_FL_beton ihwg d=180_gen, Floor:NLRS_13.22_FL_beton ihwg d=180_gen:14295784
In: 62 tweeënzestigste verdieping
PredefinedType: BASESLAB; Classification: 13.22 vloeren op grondslag - constructief, vloeren als gebouwonderdeel (Uniformat); Material: NLRS_f2_beton ihwg 180 mm
Pset_SlabCommon - IsExternal: yes; LoadBearing: yes; Reference: NLRS_13.22_FL_beton ihwg d=180_gen; ThermalTransmittance: 5.81111 kg/K/s3

# IfcSlab: Floor:NLRS_13.22_FL_beton ihwg d=198_gen, Floor:NLRS_13.22_FL_beton ihwg d=198_gen:6110209
In: 00 begane grond
PredefinedType: BASESLAB; Classification: 13.22 vloeren op grondslag - constructief, vloeren als gebouwonderdeel (Uniformat); Material: NLRS_f2_beton ihwg 198 mm
Pset_SlabCommon - IsExternal: yes; LoadBearing: yes; PitchAngle: 0 deg; Reference: NLRS_13.22_FL_beton ihwg d=198_gen; ThermalTransmittance: 5.28283 kg/K/s3

# IfcSlab: Floor:NLRS_13.22_FL_beton ihwg d=200_gen (14)
In: 03 derde verdieping
PredefinedType: BASESLAB; Classification: 13.22 vloeren op grondslag - constructief, vloeren als gebouwonderdeel (Uniformat); Material: NLRS_f2_beton ihwg 200 mm
Pset_SlabCommon - IsExternal: yes; LoadBearing: yes; Reference: NLRS_13.22_FL_beton ihwg d=200_gen; ThermalTransmittance: 5.23 kg/K/s3
Name (Floor:NLRS_13.22_FL_beton ihwg d=200_gen:...)
13435581
13435581:2
13435581:3
13435581:4
13435581:5
13435581:6
13435581:7
13435581:8
13435581:9
13435712
13435712:2
13435712:3
13435712:4
13435712:5

# IfcSlab: Floor:NLRS_13.22_FL_beton ihwg d=220_gevlinderd en ingestrooid_gen, Floor:NLRS_13.22_FL_beton ihwg d=220_gevlinderd en ingestrooid_gen:13468578
In: 00 begane grond
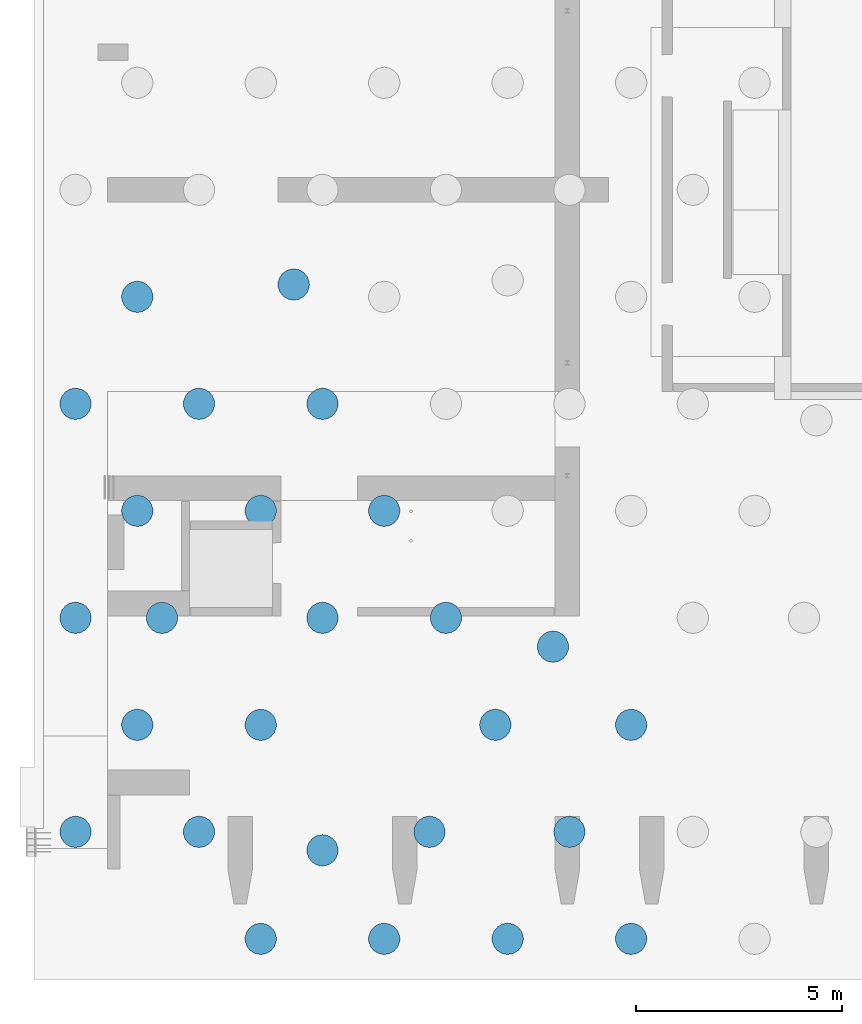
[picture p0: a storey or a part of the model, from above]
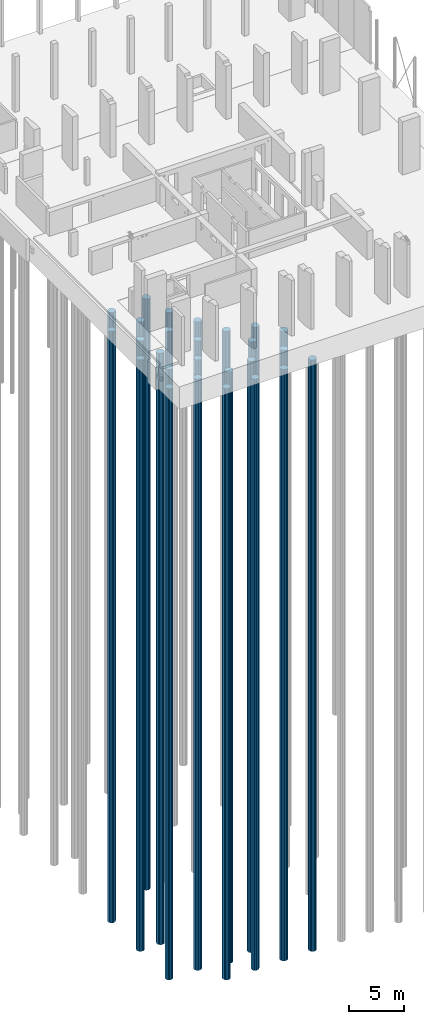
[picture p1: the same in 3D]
Properties of the parts of a building model (IFC2X3), part 16 of 21

# IfcSlab: Floor:NLRS_13.22_FL_beton ihwg d=220_gevlinderd en ingestrooid_gen, Floor:NLRS_13.22_FL_beton ihwg d=220_gevlinderd en ingestrooid_gen:13468578
PredefinedType: BASESLAB; Classification: 13.22 vloeren op grondslag - constructief, vloeren als gebouwonderdeel (Uniformat); Material: NLRS_f2_beton ihwg 220 mm
Pset_SlabCommon - IsExternal: yes; LoadBearing: yes; PitchAngle: 0 deg; Reference: NLRS_13.22_FL_beton ihwg d=220_gevlinderd en ingestrooid_gen; ThermalTransmittance: 4.75455 kg/K/s3

# IfcSlab: Floor:NLRS_13.22_FL_beton ihwg d=2500_gen, Floor:NLRS_13.22_FL_beton ihwg d=2500_gen:4112696
In: 00 begane grond
PredefinedType: BASESLAB; Classification: 13.22 vloeren op grondslag - constructief, vloeren als gebouwonderdeel (Uniformat); Material: NLRS_f2_beton ihwg 2500 mm
Pset_SlabCommon - Reference: NLRS_13.22_FL_beton ihwg d=2500_gen; IsExternal: yes; LoadBearing: yes; ThermalTransmittance: 0.4184 kg/K/s3

# IfcSlab: Floor:NLRS_13.22_FL_beton ihwg d=250_gen, Floor:NLRS_13.22_FL_beton ihwg d=250_gen:4212118
In: 00 begane grond
PredefinedType: BASESLAB; Classification: 13.22 vloeren op grondslag - constructief, vloeren als gebouwonderdeel (Uniformat); Material: NLRS_f2_beton ihwg 250 mm
Pset_SlabCommon - IsExternal: yes; LoadBearing: yes; PitchAngle: 0 deg; Reference: NLRS_13.22_FL_beton ihwg d=250_gen; ThermalTransmittance: 4.184 kg/K/s3

# IfcSlab: Floor:NLRS_13.22_FL_beton ihwg d=250_gevlinderd en ingestrooid_gen (2)
In: 00 begane grond
PredefinedType: BASESLAB; Classification: 13.22 vloeren op grondslag - constructief, vloeren als gebouwonderdeel (Uniformat); Material: NLRS_f2_beton ihwg 250 mm
Pset_SlabCommon - IsExternal: yes; LoadBearing: yes; Reference: NLRS_13.22_FL_beton ihwg d=250_gevlinderd en ingestrooid_gen; ThermalTransmittance: 4.184 kg/K/s3
Name (Floor:NLRS_13.22_FL_beton ihwg d=250_gevlinderd en ingestrooid_gen:...)
6968290
11173349 | Pset_SlabCommon - PitchAngle: 0 deg

# IfcSlab: Floor:NLRS_13.22_FL_beton ihwg d=255_gen (6)
PredefinedType: BASESLAB; Classification: 13.22 vloeren op grondslag - constructief, vloeren als gebouwonderdeel (Uniformat); Material: NLRS_f2_beton ihwg 255 mm
Pset_SlabCommon - IsExternal: yes; LoadBearing: yes; Reference: NLRS_13.22_FL_beton ihwg d=255_gen; ThermalTransmittance: 4.10196 kg/K/s3
Name (Floor:NLRS_13.22_FL_beton ihwg d=255_gen:...) | In
12362049 | 01 eerste verdieping
12362049:2 | 01 eerste verdieping
12364386 | 02 tweede verdieping
12364386:2 | 02 tweede verdieping
13092426 | 03 derde verdieping | Pset_SlabCommon - PitchAngle: 0 deg
13092819 | 03 derde verdieping | Pset_SlabCommon - PitchAngle: 0 deg

# IfcSlab: Floor:NLRS_13.22_FL_beton ihwg d=300_gen (2)
In: 00 begane grond
PredefinedType: BASESLAB; Classification: 13.22 vloeren op grondslag - constructief, vloeren als gebouwonderdeel (Uniformat); Material: NLRS_f2_beton ihwg 300 mm
Pset_SlabCommon - IsExternal: yes; LoadBearing: yes; PitchAngle: 0 deg; Reference: NLRS_13.22_FL_beton ihwg d=300_gen; ThermalTransmittance: 3.48667 kg/K/s3
Name (Floor:NLRS_13.22_FL_beton ihwg d=300_gen:...)
4120625
7802955

# IfcSlab: Floor:NLRS_13.22_FL_beton ihwg d=350_gen, Floor:NLRS_13.22_FL_beton ihwg d=350_gen:4223542
In: 00 begane grond
PredefinedType: ROOF; Classification: 13.22 vloeren op grondslag - constructief, vloeren als gebouwonderdeel (Uniformat); Material: NLRS_f2_beton ihwg 350 mm
Pset_SlabCommon - IsExternal: yes; LoadBearing: yes; Reference: NLRS_13.22_FL_beton ihwg d=350_gen; ThermalTransmittance: 2.98857 kg/K/s3

# IfcSlab: Floor:NLRS_13.22_FL_beton ihwg d=400_gen, Floor:NLRS_13.22_FL_beton ihwg d=400_gen:4114419
In: 00 begane grond
PredefinedType: BASESLAB; Classification: 13.22 vloeren op grondslag - constructief, vloeren als gebouwonderdeel (Uniformat); Material: NLRS_f2_beton ihwg 400 mm
Pset_SlabCommon - IsExternal: yes; LoadBearing: yes; Reference: NLRS_13.22_FL_beton ihwg d=400_gen; ThermalTransmittance: 2.615 kg/K/s3; PitchAngle: 0 deg

# IfcSlab: Floor:NLRS_13.22_FL_beton ihwg d=500_gen, Floor:NLRS_13.22_FL_beton ihwg d=500_gen:4120642
In: 00 begane grond
PredefinedType: BASESLAB; Classification: 13.22 vloeren op grondslag - constructief, vloeren als gebouwonderdeel (Uniformat); Material: NLRS_f2_beton ihwg 500 mm
Pset_SlabCommon - IsExternal: yes; LoadBearing: yes; Reference: NLRS_13.22_FL_beton ihwg d=500_gen; ThermalTransmittance: 2.092 kg/K/s3

# IfcSlab: Floor:NLRS_13.22_FL_beton prefab d=245, Floor:NLRS_13.22_FL_beton prefab d=245:14237365
In: 57 zevenenvijftigste verdieping
PredefinedType: BASESLAB; Classification: 13.22 vloeren op grondslag - constructief, vloeren als gebouwonderdeel (Uniformat); Material: NLRS_f2_beton prefab 245 mm
Pset_SlabCommon - IsExternal: yes; LoadBearing: yes; Reference: NLRS_13.22_FL_beton prefab d=245; ThermalTransmittance: 4.26939 kg/K/s3

# IfcSlab: Floor:NLRS_13.22_FL_beton prefab d=260_gen, Floor:NLRS_13.22_FL_beton prefab d=260_gen:14242827
In: 57 zevenenvijftigste verdieping
PredefinedType: BASESLAB; Classification: 13.22 vloeren op grondslag - constructief, vloeren als gebouwonderdeel (Uniformat); Material: NLRS_f2_beton prefab 260 mm
Pset_SlabCommon - IsExternal: yes; LoadBearing: yes; PitchAngle: 0 deg; Reference: NLRS_13.22_FL_beton prefab d=260_gen; ThermalTransmittance: 4.02308 kg/K/s3

# IfcSlab: Floor:NLRS_13.22_FL_rubber d=20_gen (4)
In: 57 zevenenvijftigste verdieping
PredefinedType: BASESLAB; Classification: 13.22 vloeren op grondslag - constructief, vloeren als gebouwonderdeel (Uniformat); Material: NLRS_n7_isolatie EPS 20 mm
Pset_SlabCommon - IsExternal: yes; LoadBearing: yes; PitchAngle: 0 deg; Reference: NLRS_13.22_FL_rubber d=20_gen; ThermalTransmittance: 1.75 kg/K/s3
Name (Floor:NLRS_13.22_FL_rubber d=20_gen:...)
14241559
14241713
14242541
14242839

# IfcSlab: Floor:NLRS_23.21_FL_beton breedplaat d=70/240_gen (5)
PredefinedType: FLOOR; Classification: 23.21 vloeren - constructief, vrijdragende vloeren (Uniformat)
Pset_SlabCommon - LoadBearing: yes; IsExternal: no; Reference: NLRS_23.21_FL_beton breedplaat d=70/240_gen; ThermalTransmittance: 4.35833 kg/K/s3
Name (Floor:NLRS_23.21_FL_beton breedplaat d=70/240_gen:...) | In | Material | Group
4851986 | 03 derde verdieping | NLRS_f2_beton ihwg | Model Group:NLRS_22.21_WA_kern 01--04_gen:4832721
4861126 | 05 vijfde verdieping | NLRS_f2_beton ihwg | Model Group:NLRS_22.21_WA_kern 05_gen:8891248
4869719 | 02 tweede verdieping | NLRS_f2_beton ihwg | Model Group:NLRS_22.21_WA_kern 01--04_gen:4869716
4870157 | 01 eerste verdieping | NLRS_f2_beton ihwg 240 mm
4941865 | 04 vierde verdieping |  | Model Group:NLRS_22.21_WA_kern 01--04_gen:4941798

# IfcSlab: Floor:NLRS_23.21_FL_beton breedplaat d=70/270_gen (7)
PredefinedType: FLOOR; Classification: 23.21 vloeren - constructief, vrijdragende vloeren (Uniformat)
Pset_SlabCommon - LoadBearing: yes; IsExternal: no; Reference: NLRS_23.21_FL_beton breedplaat d=70/270_gen; ThermalTransmittance: 3.87407 kg/K/s3
Name (Floor:NLRS_23.21_FL_beton breedplaat d=70/270_gen:...) | In | Material
4333664 | 01 eerste verdieping | NLRS_f2_beton ihwg
4416668 | 02 tweede verdieping | NLRS_f2_beton ihwg
4448728 | 03 derde verdieping | NLRS_f2_beton ihwg
4814461 | 04 vierde verdieping | NLRS_f2_beton ihwg
4822271 | 05 vijfde verdieping | NLRS_f2_beton ihwg
12796413 | 03 derde verdieping | NLRS_f2_beton ihwg 270 mm
12796413:2 | 03 derde verdieping | NLRS_f2_beton ihwg 270 mm

# IfcSlab: Floor:NLRS_23.21_FL_beton ihwg d=150_gen, Floor:NLRS_23.21_FL_beton ihwg d=150_gen:14222862
In: 62 tweeënzestigste verdieping
PredefinedType: FLOOR; Classification: 23.21 vloeren - constructief, vrijdragende vloeren (Uniformat); Material: NLRS_f2_beton ihwg 150 mm
Pset_SlabCommon - LoadBearing: yes; IsExternal: no; Reference: NLRS_23.21_FL_beton ihwg d=150_gen; ThermalTransmittance: 6.97333 kg/K/s3

# IfcSlab: Floor:NLRS_23.21_FL_beton ihwg d=170_gen (190)
PredefinedType: FLOOR; Classification: 23.21 vloeren - constructief, vrijdragende vloeren (Uniformat); Material: NLRS_f2_beton ihwg 170 mm
Pset_SlabCommon - LoadBearing: yes; IsExternal: no; PitchAngle: 0 deg; Reference: NLRS_23.21_FL_beton ihwg d=170_gen; ThermalTransmittance: 6.15294 kg/K/s3
Name (Floor:NLRS_23.21_FL_beton ihwg d=170_gen:...) | In | Group
4689382 | 08 achtste verdieping | Model Group:NLRS_28.21_WA_3D element 001 d=400_gen:4689303
4689394 | 08 achtste verdieping | Model Group:NLRS_28.21_WA_3D element 001 d=400_gen:4689345
4689406 | 08 achtste verdieping | Model Group:NLRS_28.21_WA_3D element 002 d=400_gen:4689313
4689417 | 08 achtste verdieping | Model Group:NLRS_28.21_WA_3D element 002 d=400_gen:4689329
4690940 | 07 zevende verdieping | Model Group:NLRS_28.21_WA_3D element 001 d=400_gen:4690866
4690952 | 07 zevende verdieping | Model Group:NLRS_28.21_WA_3D element 001 d=400_gen:4690908
4690964 | 07 zevende verdieping | Model Group:NLRS_28.21_WA_3D element 002 d=400_gen:4690876
4690975 | 07 zevende verdieping | Model Group:NLRS_28.21_WA_3D element 002 d=400_gen:4690892
4695241 | 22 tweeëntwintigste verdieping | Model Group:NLRS_28.21_WA_3D element 002 d=300_gen:4695207
4695309 | 22 tweeëntwintigste verdieping | Model Group:NLRS_28.21_WA_3D element 002 d=300_gen:4695191
4695353 | 22 tweeëntwintigste verdieping | Model Group:NLRS_28.21_WA_3D element 001 d=300_gen:4695190
4695382 | 22 tweeëntwintigste verdieping | Model Group:NLRS_28.21_WA_3D element 001 d=300_gen:4695208
4715054 | 09 negende verdieping | Model Group:NLRS_28.21_WA_3D element 001 d=400_gen:4714980
4715066 | 09 negende verdieping | Model Group:NLRS_28.21_WA_3D element 001 d=400_gen:4715022
4715078 | 09 negende verdieping | Model Group:NLRS_28.21_WA_3D element 002 d=400_gen:4714990
4715089 | 09 negende verdieping | Model Group:NLRS_28.21_WA_3D element 002 d=400_gen:4715006
4730864 | 14 veertiende verdieping | Model Group:NLRS_28.21_WA_3D element 002 d=300_gen:4730830
4730932 | 14 veertiende verdieping | Model Group:NLRS_28.21_WA_3D element 002 d=300_gen:4730814
4730976 | 14 veertiende verdieping | Model Group:NLRS_28.21_WA_3D element 001 d=300_gen:4730813
4731005 | 14 veertiende verdieping | Model Group:NLRS_28.21_WA_3D element 001 d=300_gen:4730831
4731322 | 16 zestiende verdieping | Model Group:NLRS_28.21_WA_3D element 002 d=300_gen:4731288
4731390 | 16 zestiende verdieping | Model Group:NLRS_28.21_WA_3D element 002 d=300_gen:4731272
4731434 | 16 zestiende verdieping | Model Group:NLRS_28.21_WA_3D element 001 d=300_gen:4731271
4731463 | 16 zestiende verdieping | Model Group:NLRS_28.21_WA_3D element 001 d=300_gen:4731289
4731780 | 18 achttiende verdieping | Model Group:NLRS_28.21_WA_3D element 002 d=300_gen:4731746
4731848 | 18 achttiende verdieping | Model Group:NLRS_28.21_WA_3D element 002 d=300_gen:4731730
4731892 | 18 achttiende verdieping | Model Group:NLRS_28.21_WA_3D element 001 d=300_gen:4731729
4731921 | 18 achttiende verdieping | Model Group:NLRS_28.21_WA_3D element 001 d=300_gen:4731747
4732238 | 20 twintigste verdieping | Model Group:NLRS_28.21_WA_3D element 002 d=300_gen:4732204
4732306 | 20 twintigste verdieping | Model Group:NLRS_28.21_WA_3D element 002 d=300_gen:4732188
4732350 | 20 twintigste verdieping | Model Group:NLRS_28.21_WA_3D element 001 d=300_gen:4732187
4732379 | 20 twintigste verdieping | Model Group:NLRS_28.21_WA_3D element 001 d=300_gen:4732205
4738451 | 13 dertiende verdieping | Model Group:NLRS_28.21_WA_3D element 002 d=300_gen:4738417
4738519 | 13 dertiende verdieping | Model Group:NLRS_28.21_WA_3D element 002 d=300_gen:4738401
4738563 | 13 dertiende verdieping | Model Group:NLRS_28.21_WA_3D element 001 d=300_gen:4738400
4738592 | 13 dertiende verdieping | Model Group:NLRS_28.21_WA_3D element 001 d=300_gen:4738418
4738909 | 15 vijftiende verdieping | Model Group:NLRS_28.21_WA_3D element 002 d=300_gen:4738875
4738977 | 15 vijftiende verdieping | Model Group:NLRS_28.21_WA_3D element 002 d=300_gen:4738859
4739021 | 15 vijftiende verdieping | Model Group:NLRS_28.21_WA_3D element 001 d=300_gen:4738858
4739050 | 15 vijftiende verdieping | Model Group:NLRS_28.21_WA_3D element 001 d=300_gen:4738876
4739367 | 17 zeventiende verdieping | Model Group:NLRS_28.21_WA_3D element 002 d=300_gen:4739333
4739435 | 17 zeventiende verdieping | Model Group:NLRS_28.21_WA_3D element 002 d=300_gen:4739317
4739479 | 17 zeventiende verdieping | Model Group:NLRS_28.21_WA_3D element 001 d=300_gen:4739316
4739508 | 17 zeventiende verdieping | Model Group:NLRS_28.21_WA_3D element 001 d=300_gen:4739334
4739825 | 19 negentiende verdieping | Model Group:NLRS_28.21_WA_3D element 002 d=300_gen:4739791
4739893 | 19 negentiende verdieping | Model Group:NLRS_28.21_WA_3D element 002 d=300_gen:4739775
4739937 | 19 negentiende verdieping | Model Group:NLRS_28.21_WA_3D element 001 d=300_gen:4739774
4739966 | 19 negentiende verdieping | Model Group:NLRS_28.21_WA_3D element 001 d=300_gen:4739792
4740283 | 21 eenentwintigste verdieping | Model Group:NLRS_28.21_WA_3D element 002 d=300_gen:4740249
4740351 | 21 eenentwintigste verdieping | Model Group:NLRS_28.21_WA_3D element 002 d=300_gen:4740233
4740395 | 21 eenentwintigste verdieping | Model Group:NLRS_28.21_WA_3D element 001 d=300_gen:4740232
4740424 | 21 eenentwintigste verdieping | Model Group:NLRS_28.21_WA_3D element 001 d=300_gen:4740250
4746876 | 25 vijfentwintigste verdieping | Model Group:NLRS_28.21_WA_3D element 002 d=300_gen:4746846
4746930 | 25 vijfentwintigste verdieping | Model Group:NLRS_28.21_WA_3D element 002 d=300_gen:4746830
4746974 | 25 vijfentwintigste verdieping | Model Group:NLRS_28.21_WA_3D element 001 d=300_gen:4746829
4747003 | 25 vijfentwintigste verdieping | Model Group:NLRS_28.21_WA_3D element 001 d=300_gen:4746847
4747308 | 26 zesentwintigste verdieping | Model Group:NLRS_28.21_WA_3D element 002 d=300_gen:4747278
4747362 | 26 zesentwintigste verdieping | Model Group:NLRS_28.21_WA_3D element 002 d=300_gen:4747262
4747406 | 26 zesentwintigste verdieping | Model Group:NLRS_28.21_WA_3D element 001 d=300_gen:4747261
4747435 | 26 zesentwintigste verdieping | Model Group:NLRS_28.21_WA_3D element 001 d=300_gen:4747279
4747740 | 27 zevenentwintigste verdieping | Model Group:NLRS_28.21_WA_3D element 002 d=300_gen:4747710
4747794 | 27 zevenentwintigste verdieping | Model Group:NLRS_28.21_WA_3D element 002 d=300_gen:4747694
4747838 | 27 zevenentwintigste verdieping | Model Group:NLRS_28.21_WA_3D element 001 d=300_gen:4747693
4747867 | 27 zevenentwintigste verdieping | Model Group:NLRS_28.21_WA_3D element 001 d=300_gen:4747711
4748172 | 28 achtentwintigste verdieping | Model Group:NLRS_28.21_WA_3D element 002 d=300_gen:4748142
4748226 | 28 achtentwintigste verdieping | Model Group:NLRS_28.21_WA_3D element 002 d=300_gen:4748126
4748270 | 28 achtentwintigste verdieping | Model Group:NLRS_28.21_WA_3D element 001 d=300_gen:4748125
4748299 | 28 achtentwintigste verdieping | Model Group:NLRS_28.21_WA_3D element 001 d=300_gen:4748143
4748604 | 29 negenentwintigste verdieping | Model Group:NLRS_28.21_WA_3D element 002 d=300_gen:4748574
4748658 | 29 negenentwintigste verdieping | Model Group:NLRS_28.21_WA_3D element 002 d=300_gen:4748558
4748702 | 29 negenentwintigste verdieping | Model Group:NLRS_28.21_WA_3D element 001 d=300_gen:4748557
4748731 | 29 negenentwintigste verdieping | Model Group:NLRS_28.21_WA_3D element 001 d=300_gen:4748575
4749036 | 30 dertigste verdieping | Model Group:NLRS_28.21_WA_3D element 002 d=300_gen:4749006
4749090 | 30 dertigste verdieping | Model Group:NLRS_28.21_WA_3D element 002 d=300_gen:4748990
4749134 | 30 dertigste verdieping | Model Group:NLRS_28.21_WA_3D element 001 d=300_gen:4748989
4749163 | 30 dertigste verdieping | Model Group:NLRS_28.21_WA_3D element 001 d=300_gen:4749007
4749468 | 31 eenendertigste verdieping | Model Group:NLRS_28.21_WA_3D element 002 d=300_gen:4749438
4749522 | 31 eenendertigste verdieping | Model Group:NLRS_28.21_WA_3D element 002 d=300_gen:4749422
4749566 | 31 eenendertigste verdieping | Model Group:NLRS_28.21_WA_3D element 001 d=300_gen:4749421
4749595 | 31 eenendertigste verdieping | Model Group:NLRS_28.21_WA_3D element 001 d=300_gen:4749439
4749900 | 32 tweeëndertigste verdieping | Model Group:NLRS_28.21_WA_3D element 002 d=300_gen:4749870
4749954 | 32 tweeëndertigste verdieping | Model Group:NLRS_28.21_WA_3D element 002 d=300_gen:4749854
4749998 | 32 tweeëndertigste verdieping | Model Group:NLRS_28.21_WA_3D element 001 d=300_gen:4749853
4750027 | 32 tweeëndertigste verdieping | Model Group:NLRS_28.21_WA_3D element 001 d=300_gen:4749871
4750332 | 33 drieëndertigste verdieping | Model Group:NLRS_28.21_WA_3D element 002 d=300_gen:4750302
4750386 | 33 drieëndertigste verdieping | Model Group:NLRS_28.21_WA_3D element 002 d=300_gen:4750286
4750430 | 33 drieëndertigste verdieping | Model Group:NLRS_28.21_WA_3D element 001 d=300_gen:4750285
4750459 | 33 drieëndertigste verdieping | Model Group:NLRS_28.21_WA_3D element 001 d=300_gen:4750303
4750764 | 34 vierendertigste verdieping | Model Group:NLRS_28.21_WA_3D element 002 d=300_gen:4750734
4750818 | 34 vierendertigste verdieping | Model Group:NLRS_28.21_WA_3D element 002 d=300_gen:4750718
4750862 | 34 vierendertigste verdieping | Model Group:NLRS_28.21_WA_3D element 001 d=300_gen:4750717
4750891 | 34 vierendertigste verdieping | Model Group:NLRS_28.21_WA_3D element 001 d=300_gen:4750735
4751196 | 35 vijfendertigste verdieping | Model Group:NLRS_28.21_WA_3D element 002 d=300_gen:4751166
4751250 | 35 vijfendertigste verdieping | Model Group:NLRS_28.21_WA_3D element 002 d=300_gen:4751150
4751294 | 35 vijfendertigste verdieping | Model Group:NLRS_28.21_WA_3D element 001 d=300_gen:4751149
4751323 | 35 vijfendertigste verdieping | Model Group:NLRS_28.21_WA_3D element 001 d=300_gen:4751167
4751628 | 36 zesendertigste verdieping | Model Group:NLRS_28.21_WA_3D element 002 d=300_gen:4751598
4751682 | 36 zesendertigste verdieping | Model Group:NLRS_28.21_WA_3D element 002 d=300_gen:4751582
4751726 | 36 zesendertigste verdieping | Model Group:NLRS_28.21_WA_3D element 001 d=300_gen:4751581
4751755 | 36 zesendertigste verdieping | Model Group:NLRS_28.21_WA_3D element 001 d=300_gen:4751599
4752060 | 37 zevenendertigste verdieping | Model Group:NLRS_28.21_WA_3D element 002 d=300_gen:4752030
4752114 | 37 zevenendertigste verdieping | Model Group:NLRS_28.21_WA_3D element 002 d=300_gen:4752014
4752158 | 37 zevenendertigste verdieping | Model Group:NLRS_28.21_WA_3D element 001 d=300_gen:4752013
4752187 | 37 zevenendertigste verdieping | Model Group:NLRS_28.21_WA_3D element 001 d=300_gen:4752031
4752492 | 38 achtendertigste verdieping | Model Group:NLRS_28.21_WA_3D element 002 d=300_gen:4752462
4752546 | 38 achtendertigste verdieping | Model Group:NLRS_28.21_WA_3D element 002 d=300_gen:4752446
4752590 | 38 achtendertigste verdieping | Model Group:NLRS_28.21_WA_3D element 001 d=300_gen:4752445
4752619 | 38 achtendertigste verdieping | Model Group:NLRS_28.21_WA_3D element 001 d=300_gen:4752463
4752924 | 39 negenendertigste verdieping | Model Group:NLRS_28.21_WA_3D element 002 d=300_gen:4752894
4752978 | 39 negenendertigste verdieping | Model Group:NLRS_28.21_WA_3D element 002 d=300_gen:4752878
4753022 | 39 negenendertigste verdieping | Model Group:NLRS_28.21_WA_3D element 001 d=300_gen:4752877
4753051 | 39 negenendertigste verdieping | Model Group:NLRS_28.21_WA_3D element 001 d=300_gen:4752895
4753356 | 40 veertigste verdieping | Model Group:NLRS_28.21_WA_3D element 002 d=300_gen:4753326
4753410 | 40 veertigste verdieping | Model Group:NLRS_28.21_WA_3D element 002 d=300_gen:4753310
4753454 | 40 veertigste verdieping | Model Group:NLRS_28.21_WA_3D element 001 d=300_gen:4753309
4753483 | 40 veertigste verdieping | Model Group:NLRS_28.21_WA_3D element 001 d=300_gen:4753327
4753788 | 41 eenenveertigste verdieping | Model Group:NLRS_28.21_WA_3D element 002 d=300_gen:4753758
4753842 | 41 eenenveertigste verdieping | Model Group:NLRS_28.21_WA_3D element 002 d=300_gen:4753742
4753886 | 41 eenenveertigste verdieping | Model Group:NLRS_28.21_WA_3D element 001 d=300_gen:4753741
4753915 | 41 eenenveertigste verdieping | Model Group:NLRS_28.21_WA_3D element 001 d=300_gen:4753759
4778256 | 23 drieëntwintigste verdieping | Model Group:NLRS_28.21_WA_3D element 002 d=300_gen:4778226
4778310 | 23 drieëntwintigste verdieping | Model Group:NLRS_28.21_WA_3D element 002 d=300_gen:4778210
4778354 | 23 drieëntwintigste verdieping | Model Group:NLRS_28.21_WA_3D element 001 d=300_gen:4778209
4778383 | 23 drieëntwintigste verdieping | Model Group:NLRS_28.21_WA_3D element 001 d=300_gen:4778227
4779839 | 24 vierentwintigste verdieping | Model Group:NLRS_28.21_WA_3D element 002 d=300_gen:4779809
4779893 | 24 vierentwintigste verdieping | Model Group:NLRS_28.21_WA_3D element 002 d=300_gen:4779793
4779937 | 24 vierentwintigste verdieping | Model Group:NLRS_28.21_WA_3D element 001 d=300_gen:4779792
4779966 | 24 vierentwintigste verdieping | Model Group:NLRS_28.21_WA_3D element 001 d=300_gen:4779810
4783956 | 42 tweeënveertigste verdieping | Model Group:NLRS_28.21_WA_3D element 002 d=300_gen:4783926
4784010 | 42 tweeënveertigste verdieping | Model Group:NLRS_28.21_WA_3D element 002 d=300_gen:4783910
4784054 | 42 tweeënveertigste verdieping | Model Group:NLRS_28.21_WA_3D element 001 d=300_gen:4783909
4784083 | 42 tweeënveertigste verdieping | Model Group:NLRS_28.21_WA_3D element 001 d=300_gen:4783927
4789002 | 44 vierenveertigste verdieping | Model Group:NLRS_28.21_WA_3D element 002 d=300_gen:4788972
4789056 | 44 vierenveertigste verdieping | Model Group:NLRS_28.21_WA_3D element 002 d=300_gen:4788956
4789100 | 44 vierenveertigste verdieping | Model Group:NLRS_28.21_WA_3D element 001 d=300_gen:4788955
4789129 | 44 vierenveertigste verdieping | Model Group:NLRS_28.21_WA_3D element 001 d=300_gen:4788973
4789434 | 45 vijfenveertigste verdieping | Model Group:NLRS_28.21_WA_3D element 002 d=300_gen:4789404
4789488 | 45 vijfenveertigste verdieping | Model Group:NLRS_28.21_WA_3D element 002 d=300_gen:4789388
4789532 | 45 vijfenveertigste verdieping | Model Group:NLRS_28.21_WA_3D element 001 d=300_gen:4789387
4789561 | 45 vijfenveertigste verdieping | Model Group:NLRS_28.21_WA_3D element 001 d=300_gen:4789405
4789866 | 46 zesenveertigste verdieping | Model Group:NLRS_28.21_WA_3D element 002 d=300_gen:4789836
4789920 | 46 zesenveertigste verdieping | Model Group:NLRS_28.21_WA_3D element 002 d=300_gen:4789820
4789964 | 46 zesenveertigste verdieping | Model Group:NLRS_28.21_WA_3D element 001 d=300_gen:4789819
4789993 | 46 zesenveertigste verdieping | Model Group:NLRS_28.21_WA_3D element 001 d=300_gen:4789837
4790298 | 47 zevenenveertigste verdieping | Model Group:NLRS_28.21_WA_3D element 002 d=300_gen:4790268
4790352 | 47 zevenenveertigste verdieping | Model Group:NLRS_28.21_WA_3D element 002 d=300_gen:4790252
4790396 | 47 zevenenveertigste verdieping | Model Group:NLRS_28.21_WA_3D element 001 d=300_gen:4790251
4790425 | 47 zevenenveertigste verdieping | Model Group:NLRS_28.21_WA_3D element 001 d=300_gen:4790269
4790730 | 48 achtenveertigste verdieping | Model Group:NLRS_28.21_WA_3D element 002 d=300_gen:4790700
4790784 | 48 achtenveertigste verdieping | Model Group:NLRS_28.21_WA_3D element 002 d=300_gen:4790684
4790828 | 48 achtenveertigste verdieping | Model Group:NLRS_28.21_WA_3D element 001 d=300_gen:4790683
4790857 | 48 achtenveertigste verdieping | Model Group:NLRS_28.21_WA_3D element 001 d=300_gen:4790701
4791162 | 49 negenenveertigste verdieping | Model Group:NLRS_28.21_WA_3D element 002 d=300_gen:4791132
4791216 | 49 negenenveertigste verdieping | Model Group:NLRS_28.21_WA_3D element 002 d=300_gen:4791116
4791260 | 49 negenenveertigste verdieping | Model Group:NLRS_28.21_WA_3D element 001 d=300_gen:4791115
4791289 | 49 negenenveertigste verdieping | Model Group:NLRS_28.21_WA_3D element 001 d=300_gen:4791133
4791594 | 50 vijftigste verdieping | Model Group:NLRS_28.21_WA_3D element 002 d=300_gen:4791564
4791648 | 50 vijftigste verdieping | Model Group:NLRS_28.21_WA_3D element 002 d=300_gen:4791548
4791692 | 50 vijftigste verdieping | Model Group:NLRS_28.21_WA_3D element 001 d=300_gen:4791547
4791721 | 50 vijftigste verdieping | Model Group:NLRS_28.21_WA_3D element 001 d=300_gen:4791565
4792026 | 51 eenenvijftigste verdieping | Model Group:NLRS_28.21_WA_3D element 002 d=300_gen:4791996
4792080 | 51 eenenvijftigste verdieping | Model Group:NLRS_28.21_WA_3D element 002 d=300_gen:4791980
4792124 | 51 eenenvijftigste verdieping | Model Group:NLRS_28.21_WA_3D element 001 d=300_gen:4791979
4792153 | 51 eenenvijftigste verdieping | Model Group:NLRS_28.21_WA_3D element 001 d=300_gen:4791997
4803475 | 43 drieënveertigste verdieping | Model Group:NLRS_28.21_WA_3D element 002 d=300_gen:4803445
4803529 | 43 drieënveertigste verdieping | Model Group:NLRS_28.21_WA_3D element 002 d=300_gen:4803429
4803573 | 43 drieënveertigste verdieping | Model Group:NLRS_28.21_WA_3D element 001 d=300_gen:4803428
4803602 | 43 drieënveertigste verdieping | Model Group:NLRS_28.21_WA_3D element 001 d=300_gen:4803446
4980185 | 52 tweeënvijftigste verdieping | Model Group:NLRS_28.21_WA_3D element 002 d=300_gen:4980163
4980239 | 52 tweeënvijftigste verdieping | Model Group:NLRS_28.21_WA_3D element 002 d=300_gen:4980147
4980283 | 52 tweeënvijftigste verdieping | Model Group:NLRS_28.21_WA_3D element 001 d=300_gen:4980146
4980312 | 52 tweeënvijftigste verdieping | Model Group:NLRS_28.21_WA_3D element 001 d=300_gen:4980164
4982011 | 53 drieënvijftigste verdieping | Model Group:NLRS_28.21_WA_3D element 002a d=300_gen:4981919
5042442 | 06 zesde verdieping
5042572 | 06 zesde verdieping
5043340 | 53 drieënvijftigste verdieping | Model Group:NLRS_28.21_WA_3D element 002a d=300_gen:4981935
5667379 | 10 tiende verdieping | Model Group:NLRS_28.21_WA_3D element 002 d=300_gen:5667357
5667435 | 10 tiende verdieping | Model Group:NLRS_28.21_WA_3D element 002 d=300_gen:5667341
5667479 | 10 tiende verdieping | Model Group:NLRS_28.21_WA_3D element 001 d=300_gen:5667340
5667508 | 10 tiende verdieping | Model Group:NLRS_28.21_WA_3D element 001 d=300_gen:5667358
6801396 | 06 zesde verdieping
6801867 | 06 zesde verdieping
6859082 | 11 elfde verdieping | Model Group:NLRS_28.21_WA_3D element 002 d=300_gen:6859076
6859130 | 11 elfde verdieping | Model Group:NLRS_28.21_WA_3D element 002 d=300_gen:6859064
6859170 | 11 elfde verdieping | Model Group:NLRS_28.21_WA_3D element 001 d=300_gen:6859063
6859196 | 11 elfde verdieping | Model Group:NLRS_28.21_WA_3D element 001 d=300_gen:6859077
6861595 | 12 twaalfde verdieping | Model Group:NLRS_28.21_WA_3D element 002 d=300_gen:6861589
6861643 | 12 twaalfde verdieping | Model Group:NLRS_28.21_WA_3D element 002 d=300_gen:6861577
6861683 | 12 twaalfde verdieping | Model Group:NLRS_28.21_WA_3D element 001 d=300_gen:6861576
6861709 | 12 twaalfde verdieping | Model Group:NLRS_28.21_WA_3D element 001 d=300_gen:6861590

# IfcSlab: Floor:NLRS_23.21_FL_beton ihwg d=190_gen (2)
In: 53 drieënvijftigste verdieping
PredefinedType: FLOOR; Classification: 23.21 vloeren - constructief, vrijdragende vloeren (Uniformat); Material: NLRS_f2_beton ihwg 190 mm
Pset_SlabCommon - LoadBearing: yes; IsExternal: no; PitchAngle: 0 deg; Reference: NLRS_23.21_FL_beton ihwg d=190_gen; ThermalTransmittance: 5.50526 kg/K/s3
Name (Floor:NLRS_23.21_FL_beton ihwg d=190_gen:...) | Group
4982055 | Model Group:NLRS_28.21_WA_3D element 001a d=300_gen:4981918
5044705 | Model Group:NLRS_28.21_WA_3D element 001a d=300_gen:4981936

# IfcSlab: Floor:NLRS_23.21_FL_beton ihwg d=220_gen (12)
PredefinedType: FLOOR; Classification: 23.21 vloeren - constructief, vrijdragende vloeren (Uniformat); Material: NLRS_f2_beton ihwg 220 mm
Pset_SlabCommon - LoadBearing: yes; IsExternal: no; Reference: NLRS_23.21_FL_beton ihwg d=220_gen; ThermalTransmittance: 4.75455 kg/K/s3
Name (Floor:NLRS_23.21_FL_beton ihwg d=220_gen:...) | In
6220627 | 05 vijfde verdieping
6220627:2 | 05 vijfde verdieping
6220627:3 | 05 vijfde verdieping
6220627:4 | 05 vijfde verdieping
6220627:5 | 05 vijfde verdieping
6220627:6 | 05 vijfde verdieping
6220627:7 | 05 vijfde verdieping
6220627:8 | 05 vijfde verdieping
13768148 | 52 tweeënvijftigste verdieping
13769227 | 52 tweeënvijftigste verdieping
13769329 | 52 tweeënvijftigste verdieping
13769490 | 52 tweeënvijftigste verdieping

# IfcSlab: Floor:NLRS_23.21_FL_beton ihwg d=240_gen (3)
In: 00a eerste tussenverdieping
PredefinedType: FLOOR; Classification: 23.21 vloeren - constructief, vrijdragende vloeren (Uniformat); Material: NLRS_f2_beton ihwg 240 mm
Pset_SlabCommon - LoadBearing: yes; IsExternal: no; Reference: NLRS_23.21_FL_beton ihwg d=240_gen; ThermalTransmittance: 4.35833 kg/K/s3
Name (Floor:NLRS_23.21_FL_beton ihwg d=240_gen:...)
4870857
4870857:2
4870857:3

# IfcSlab: Floor:NLRS_23.21_FL_beton ihwg d=255_gen (4)
PredefinedType: FLOOR; Classification: 23.21 vloeren - constructief, vrijdragende vloeren (Uniformat); Material: NLRS_f2_beton ihwg 255 mm
Pset_SlabCommon - LoadBearing: yes; IsExternal: no; Reference: NLRS_23.21_FL_beton ihwg d=255_gen; ThermalTransmittance: 4.10196 kg/K/s3
Name (Floor:NLRS_23.21_FL_beton ihwg d=255_gen:...) | In
14402413 | 01 eerste verdieping
14402413:2 | 01 eerste verdieping
14402775 | 02 tweede verdieping
14402775:2 | 02 tweede verdieping

# IfcSlab: Floor:NLRS_23.21_FL_beton ihwg d=270_gen, Floor:NLRS_23.21_FL_beton ihwg d=270_gen:4225975
In: 00a eerste tussenverdieping
PredefinedType: FLOOR; Classification: 23.21 vloeren - constructief, vrijdragende vloeren (Uniformat); Material: NLRS_f2_beton ihwg 270 mm
Pset_SlabCommon - LoadBearing: yes; IsExternal: no; Reference: NLRS_23.21_FL_beton ihwg d=270_gen; ThermalTransmittance: 3.87407 kg/K/s3

# IfcSlab: Floor:NLRS_23.21_FL_beton ihwg d=300_gen (2)
PredefinedType: FLOOR; Classification: 23.21 vloeren - constructief, vrijdragende vloeren (Uniformat); Material: NLRS_f2_beton ihwg 300 mm
Pset_SlabCommon - LoadBearing: yes; IsExternal: no; PitchAngle: 0 deg; Reference: NLRS_23.21_FL_beton ihwg d=300_gen; ThermalTransmittance: 3.48667 kg/K/s3
Name (Floor:NLRS_23.21_FL_beton ihwg d=300_gen:...) | In
4446636 | 02 tweede verdieping
4885026 | 03 derde verdieping

# IfcSlab: Floor:NLRS_23.21_FL_beton ihwg d=600_gen (3)
PredefinedType: FLOOR; Classification: 23.21 vloeren - constructief, vrijdragende vloeren (Uniformat); Material: NLRS_f2_beton ihwg 600 mm
Pset_SlabCommon - LoadBearing: yes; IsExternal: no; PitchAngle: 0 deg; Reference: NLRS_23.21_FL_beton ihwg d=600_gen; ThermalTransmittance: 1.74333 kg/K/s3
Name (Floor:NLRS_23.21_FL_beton ihwg d=600_gen:...) | In
4447265 | 02 tweede verdieping
4881468 | 03 derde verdieping
6306663 | 01 eerste verdieping

# IfcSlab: Floor:NLRS_23.21_FL_beton ihwg d=700_gen (2)
In: 01 eerste verdieping
PredefinedType: FLOOR; Classification: 23.21 vloeren - constructief, vrijdragende vloeren (Uniformat); Material: NLRS_f2_beton ihwg 700 mm
Pset_SlabCommon - LoadBearing: yes; IsExternal: no; PitchAngle: 0 deg; Reference: NLRS_23.21_FL_beton ihwg d=700_gen; ThermalTransmittance: 1.49429 kg/K/s3
Name (Floor:NLRS_23.21_FL_beton ihwg d=700_gen:...)
4383530
4383846

# IfcSlab: Floor:NLRS_23.21_FL_beton prefab d=150_gen (5)
In: 03 derde verdieping
PredefinedType: FLOOR; Classification: 23.21 vloeren - constructief, vrijdragende vloeren (Uniformat); Material: NLRS_f2_beton prefab 150 mm
Pset_SlabCommon - LoadBearing: yes; IsExternal: no; PitchAngle: 0 deg; Reference: NLRS_23.21_FL_beton prefab d=150_gen; ThermalTransmittance: 6.97333 kg/K/s3
Name (Floor:NLRS_23.21_FL_beton prefab d=150_gen:...)
12271312
12271916
12271962
12272010
12272058

# IfcSlab: Floor:NLRS_23.21_FL_beton prefab d=200_gen, Floor:NLRS_23.21_FL_beton prefab d=200_gen:5997758
In: 05 vijfde verdieping
PredefinedType: FLOOR; Classification: 23.21 vloeren - constructief, vrijdragende vloeren (Uniformat); Material: NLRS_f2_beton prefab 200 mm
Pset_SlabCommon - LoadBearing: yes; IsExternal: no; PitchAngle: 0 deg; Reference: NLRS_23.21_FL_beton prefab d=200_gen; ThermalTransmittance: 5.23 kg/K/s3

# IfcSlab: Floor:NLRS_23.21_FL_beton prefab d=250_gen, Floor:NLRS_23.21_FL_beton prefab d=250_gen:5173878
In: 00 begane grond
PredefinedType: FLOOR; Classification: 23.21 vloeren - constructief, vrijdragende vloeren (Uniformat); Material: NLRS_f2_beton prefab 250 mm
Pset_SlabCommon - LoadBearing: yes; IsExternal: no; PitchAngle: 0 deg; Reference: NLRS_23.21_FL_beton prefab d=250_gen; ThermalTransmittance: 4.184 kg/K/s3

# IfcSlab: Floor:NLRS_23.21_FL_breedplaat d=100/270_gen (36)
PredefinedType: FLOOR; Classification: 23.21 vloeren - constructief, vrijdragende vloeren (Uniformat); Material: NLRS_f2_beton ihwg 170 mm, NLRS_f2_beton prefab 100 mm
Pset_SlabCommon - LoadBearing: yes; IsExternal: no; Reference: NLRS_23.21_FL_breedplaat d=100/270_gen; ThermalTransmittance: 3.87407 kg/K/s3
Name (Floor:NLRS_23.21_FL_breedplaat d=100/270_gen:...) | In | Group
5910169 | 41 eenenveertigste verdieping
8986165 | 22 tweeëntwintigste verdieping | Model Group:NLRS_23.21_vloer voor wanden d=300/400_gen:8986172
8995929 | 24 vierentwintigste verdieping | Model Group:NLRS_23.21_vloer voor wanden d=300/400_gen:8995936
8996221 | 25 vijfentwintigste verdieping | Model Group:NLRS_23.21_vloer voor wanden d=300/400_gen:8996228
8996513 | 26 zesentwintigste verdieping | Model Group:NLRS_23.21_vloer voor wanden d=300/400_gen:8996520
8997681 | 30 dertigste verdieping | Model Group:NLRS_23.21_vloer voor wanden d=300/400_gen:8997688
9036931 | 16 zestiende verdieping | Model Group:NLRS_23.21_vloer voor wanden d=300/500_gen:9036938
9050849 | 15 vijftiende verdieping | Model Group:NLRS_23.21_vloer voor wanden d=300/500_gen:9050856
9051145 | 17 zeventiende verdieping | Model Group:NLRS_23.21_vloer voor wanden d=300/500_gen:9051152
9131796 | 18 achttiende verdieping | Model Group:NLRS_23.21_vloer voor wanden d=300/500_gen:9131803
9138690 | 31 eenendertigste verdieping | Model Group:NLRS_23.21_vloer voor wanden d=300/400_gen:9138697
9138980 | 32 tweeëndertigste verdieping | Model Group:NLRS_23.21_vloer voor wanden d=300/400_gen:9138987
9140569 | 34 vierendertigste verdieping | Model Group:NLRS_23.21_vloer voor wanden d=300/400_gen:9140576
9141509 | 35 vijfendertigste verdieping | Model Group:NLRS_23.21_vloer voor wanden d=300/400_gen:9141516
9142456 | 27 zevenentwintigste verdieping | Model Group:NLRS_23.21_vloer voor wanden d=300/400_gen:9142463
9142746 | 38 achtendertigste verdieping | Model Group:NLRS_23.21_vloer voor wanden d=300/400_gen:9142753
9143036 | 39 negenendertigste verdieping | Model Group:NLRS_23.21_vloer voor wanden d=300/400_gen:9143043
9145278 | 36 zesendertigste verdieping | Model Group:NLRS_23.21_vloer voor wanden d=300/400_gen:9145285
9145568 | 37 zevenendertigste verdieping | Model Group:NLRS_23.21_vloer voor wanden d=300/400_gen:9145575
9147157 | 40 veertigste verdieping | Model Group:NLRS_23.21_vloer voor wanden d=300/400_gen:9147164
10448387 | 23 drieëntwintigste verdieping | Model Group:NLRS_23.21_vloer voor wanden d=300/400_gen:9134981
10618314 | 10 tiende verdieping | Model Group:NLRS_23.21_vloer voor wanden d=300/500_gen:9125907
10620668 | 12 twaalfde verdieping | Model Group:NLRS_23.21_vloer voor wanden d=300/500_gen:9126214
10620800 | 14 veertiende verdieping | Model Group:NLRS_23.21_vloer voor wanden d=300/500_gen:9126521
10620932 | 20 twintigste verdieping | Model Group:NLRS_23.21_vloer voor wanden d=300/500_gen:9133891
10622932 | 11 elfde verdieping | Model Group:NLRS_23.21_vloer voor wanden d=300/500_gen:9128989
10625099 | 13 dertiende verdieping | Model Group:NLRS_23.21_vloer voor wanden d=300/500_gen:9129292
10625231 | 19 negentiende verdieping | Model Group:NLRS_23.21_vloer voor wanden d=300/500_gen:9132770
10634998 | 06 zesde verdieping | Model Group:NLRS_23.21_vloer voor wanden d=400/500_gen:5786112
10635983 | 07 zevende verdieping | Model Group:NLRS_23.21_vloer voor wanden d=400/500_gen:9091022
10636860 | 08 achtste verdieping | Model Group:NLRS_23.21_vloer voor wanden d=400/500_gen:9124885
10637397 | 09 negende verdieping | Model Group:NLRS_23.21_vloer voor wanden d=400/500_gen:5771384
10637945 | 28 achtentwintigste verdieping | Model Group:NLRS_23.21_vloer voor wanden d=300/400_gen:9135274
10639648 | 29 negenentwintigste verdieping | Model Group:NLRS_23.21_vloer voor wanden d=300/400_gen:9135567
10639779 | 33 drieëndertigste verdieping | Model Group:NLRS_23.21_vloer voor wanden d=300/400_gen:9135860
10641076 | 21 eenentwintigste verdieping

# IfcSlab: Floor:NLRS_23.21_FL_breedplaat d=100_gen (9)
PredefinedType: FLOOR; Classification: 23.21 vloeren - constructief, vrijdragende vloeren (Uniformat); Material: NLRS_f2_beton prefab 100 mm
Pset_SlabCommon - LoadBearing: yes; IsExternal: no; Reference: NLRS_23.21_FL_breedplaat d=100_gen; ThermalTransmittance: 10.46 kg/K/s3
Name (Floor:NLRS_23.21_FL_breedplaat d=100_gen:...) | In
12980673 | 53 drieënvijftigste verdieping
13158433 | 52 tweeënvijftigste verdieping
13158433:2 | 52 tweeënvijftigste verdieping
13158433:3 | 52 tweeënvijftigste verdieping
13158433:4 | 52 tweeënvijftigste verdieping
13159211 | 51 eenenvijftigste verdieping
13159211:2 | 51 eenenvijftigste verdieping
13159211:3 | 51 eenenvijftigste verdieping
13159211:4 | 51 eenenvijftigste verdieping

# IfcSlab: Floor:NLRS_23.21_FL_breedplaat d=60_gen (55)
PredefinedType: FLOOR; Classification: 23.21 vloeren - constructief, vrijdragende vloeren (Uniformat); Material: NLRS_f2_beton prefab 60 mm
Pset_SlabCommon - LoadBearing: yes; IsExternal: no; Reference: NLRS_23.21_FL_breedplaat d=60_gen; ThermalTransmittance: 17.4333 kg/K/s3
Name (Floor:NLRS_23.21_FL_breedplaat d=60_gen:...) | In | Group
12571193 | 57 zevenenvijftigste verdieping
12976903 | 58 achtenvijftigste verdieping
12976903:2 | 58 achtenvijftigste verdieping
12977982 | 56 zesenvijftigste verdieping
12979430 | 59 negenenvijftigste verdieping
12980273 | 55 vijfenvijftigste verdieping
12980435 | 54 vierenvijftigste verdieping
12980523 | 53 drieënvijftigste verdieping
12981736 | 52 tweeënvijftigste verdieping
12984968 | 51 eenenvijftigste verdieping | Model Group:NLRS_22.21_WA_kern 06--51_gen:4980182
12986268 | 06 zesde verdieping | Model Group:NLRS_22.21_WA_kern 06--51_gen:4690937
12986296 | 07 zevende verdieping | Model Group:NLRS_22.21_WA_kern 06--51_gen:4689379
12986310 | 08 achtste verdieping | Model Group:NLRS_22.21_WA_kern 06--51_gen:4715051
12986324 | 12 twaalfde verdieping | Model Group:NLRS_22.21_WA_kern 06--51_gen:4738448
12986338 | 09 negende verdieping | Model Group:NLRS_22.21_WA_kern 06--51_gen:5667376
12986352 | 10 tiende verdieping | Model Group:NLRS_22.21_WA_kern 06--51_gen:6859079
12986366 | 11 elfde verdieping | Model Group:NLRS_22.21_WA_kern 06--51_gen:6861592
12986380 | 13 dertiende verdieping | Model Group:NLRS_22.21_WA_kern 06--51_gen:4730861
12986394 | 15 vijftiende verdieping | Model Group:NLRS_22.21_WA_kern 06--51_gen:4731319
12986408 | 17 zeventiende verdieping | Model Group:NLRS_22.21_WA_kern 06--51_gen:4731777
12986422 | 19 negentiende verdieping | Model Group:NLRS_22.21_WA_kern 06--51_gen:4732235
12986436 | 14 veertiende verdieping | Model Group:NLRS_22.21_WA_kern 06--51_gen:4738906
12986450 | 16 zestiende verdieping | Model Group:NLRS_22.21_WA_kern 06--51_gen:4739364
12986464 | 18 achttiende verdieping | Model Group:NLRS_22.21_WA_kern 06--51_gen:4739822
12986478 | 20 twintigste verdieping | Model Group:NLRS_22.21_WA_kern 06--51_gen:4740280
12986492 | 21 eenentwintigste verdieping | Model Group:NLRS_22.21_WA_kern 06--51_gen:4695238
12986506 | 24 vierentwintigste verdieping | Model Group:NLRS_22.21_WA_kern 06--51_gen:4746873
12986520 | 25 vijfentwintigste verdieping | Model Group:NLRS_22.21_WA_kern 06--51_gen:4747305
12986534 | 26 zesentwintigste verdieping | Model Group:NLRS_22.21_WA_kern 06--51_gen:4747737
12986548 | 27 zevenentwintigste verdieping | Model Group:NLRS_22.21_WA_kern 06--51_gen:4748169
12986562 | 28 achtentwintigste verdieping | Model Group:NLRS_22.21_WA_kern 06--51_gen:4748601
12986576 | 29 negenentwintigste verdieping | Model Group:NLRS_22.21_WA_kern 06--51_gen:4749033
12986590 | 30 dertigste verdieping | Model Group:NLRS_22.21_WA_kern 06--51_gen:4749465
12986604 | 31 eenendertigste verdieping | Model Group:NLRS_22.21_WA_kern 06--51_gen:4749897
12986618 | 32 tweeëndertigste verdieping | Model Group:NLRS_22.21_WA_kern 06--51_gen:4750329
12986632 | 33 drieëndertigste verdieping | Model Group:NLRS_22.21_WA_kern 06--51_gen:4750761
12986646 | 34 vierendertigste verdieping | Model Group:NLRS_22.21_WA_kern 06--51_gen:4751193
12986660 | 35 vijfendertigste verdieping | Model Group:NLRS_22.21_WA_kern 06--51_gen:4751625
12986674 | 36 zesendertigste verdieping | Model Group:NLRS_22.21_WA_kern 06--51_gen:4752057
12986688 | 37 zevenendertigste verdieping | Model Group:NLRS_22.21_WA_kern 06--51_gen:4752489
12986702 | 38 achtendertigste verdieping | Model Group:NLRS_22.21_WA_kern 06--51_gen:4752921
12986716 | 39 negenendertigste verdieping | Model Group:NLRS_22.21_WA_kern 06--51_gen:4753353
12986730 | 40 veertigste verdieping | Model Group:NLRS_22.21_WA_kern 06--51_gen:4753785
12986744 | 22 tweeëntwintigste verdieping | Model Group:NLRS_22.21_WA_kern 06--51_gen:4778253
12986758 | 23 drieëntwintigste verdieping | Model Group:NLRS_22.21_WA_kern 06--51_gen:4779836
12986772 | 41 eenenveertigste verdieping | Model Group:NLRS_22.21_WA_kern 06--51_gen:4783953
12986786 | 43 drieënveertigste verdieping | Model Group:NLRS_22.21_WA_kern 06--51_gen:4788999
12986800 | 44 vierenveertigste verdieping | Model Group:NLRS_22.21_WA_kern 06--51_gen:4789431
12986814 | 45 vijfenveertigste verdieping | Model Group:NLRS_22.21_WA_kern 06--51_gen:4789863
12986828 | 46 zesenveertigste verdieping | Model Group:NLRS_22.21_WA_kern 06--51_gen:4790295
12986842 | 47 zevenenveertigste verdieping | Model Group:NLRS_22.21_WA_kern 06--51_gen:4790727
12986856 | 48 achtenveertigste verdieping | Model Group:NLRS_22.21_WA_kern 06--51_gen:4791159
12986870 | 49 negenenveertigste verdieping | Model Group:NLRS_22.21_WA_kern 06--51_gen:4791591
12986884 | 50 vijftigste verdieping | Model Group:NLRS_22.21_WA_kern 06--51_gen:4792023
12986898 | 42 tweeënveertigste verdieping | Model Group:NLRS_22.21_WA_kern 06--51_gen:4803472

# IfcSlab: Floor:NLRS_23.21_FL_breedplaat d=70_gen (91)
PredefinedType: FLOOR; Classification: 23.21 vloeren - constructief, vrijdragende vloeren (Uniformat); Material: NLRS_f2_beton prefab 70 mm
Pset_SlabCommon - LoadBearing: yes; IsExternal: no; Reference: NLRS_23.21_FL_breedplaat d=70_gen; ThermalTransmittance: 14.9429 kg/K/s3
Name (Floor:NLRS_23.21_FL_breedplaat d=70_gen:...) | In
6990815 | 04 vierde verdieping
6990815:2 | 04 vierde verdieping
6990815:3 | 04 vierde verdieping
7140953 | 04 vierde verdieping
7140953:2 | 04 vierde verdieping
7140953:3 | 04 vierde verdieping
7140953:4 | 04 vierde verdieping
7141663 | 04 vierde verdieping
7141663:2 | 04 vierde verdieping
7141663:3 | 04 vierde verdieping
7141663:4 | 04 vierde verdieping
7142285 | 04 vierde verdieping
7142285:2 | 04 vierde verdieping
7142285:3 | 04 vierde verdieping
7155041 | 03 derde verdieping
7155041:2 | 03 derde verdieping
7155041:3 | 03 derde verdieping
7155058 | 03 derde verdieping
7155058:2 | 03 derde verdieping
7155058:3 | 03 derde verdieping
7155058:4 | 03 derde verdieping
7155086 | 03 derde verdieping
7155086:2 | 03 derde verdieping
7155086:3 | 03 derde verdieping
7155086:4 | 03 derde verdieping
7155107 | 03 derde verdieping
7155107:2 | 03 derde verdieping
7155107:3 | 03 derde verdieping
7155904 | 02 tweede verdieping
7155904:2 | 02 tweede verdieping
7155904:3 | 02 tweede verdieping
7155921 | 02 tweede verdieping
7155921:2 | 02 tweede verdieping
7155921:3 | 02 tweede verdieping
7155921:4 | 02 tweede verdieping
7155948 | 02 tweede verdieping
7155948:2 | 02 tweede verdieping
7155948:3 | 02 tweede verdieping
7155948:4 | 02 tweede verdieping
7155969 | 02 tweede verdieping
7155969:2 | 02 tweede verdieping
7155969:3 | 02 tweede verdieping
7216427 | 01 eerste verdieping
7216427:2 | 01 eerste verdieping
7216427:3 | 01 eerste verdieping
7216444 | 01 eerste verdieping
7216444:2 | 01 eerste verdieping
7216444:3 | 01 eerste verdieping
7216444:4 | 01 eerste verdieping
7216444:5 | 01 eerste verdieping
7216471 | 01 eerste verdieping
7216471:2 | 01 eerste verdieping
7216471:3 | 01 eerste verdieping
7216471:4 | 01 eerste verdieping
7216492 | 01 eerste verdieping
7216492:2 | 01 eerste verdieping
7216492:3 | 01 eerste verdieping
7216689 | 05 vijfde verdieping
7216689:2 | 05 vijfde verdieping
7216689:3 | 05 vijfde verdieping
7216706 | 05 vijfde verdieping
7216706:2 | 05 vijfde verdieping
7216706:3 | 05 vijfde verdieping
7216706:4 | 05 vijfde verdieping
7216734 | 05 vijfde verdieping
7216734:2 | 05 vijfde verdieping
7216734:3 | 05 vijfde verdieping
7216734:4 | 05 vijfde verdieping
7216755 | 05 vijfde verdieping
7216755:2 | 05 vijfde verdieping
7216755:3 | 05 vijfde verdieping
7253379 | 04 vierde verdieping
7253379:2 | 04 vierde verdieping
7253379:3 | 04 vierde verdieping
7253379:4 | 04 vierde verdieping
7256653 | 05 vijfde verdieping | Group: Model Group:NLRS_22.21_WA_kern 05_gen:8891248
7256653:2 | 05 vijfde verdieping | Group: Model Group:NLRS_22.21_WA_kern 05_gen:8891248
7256653:3 | 05 vijfde verdieping | Group: Model Group:NLRS_22.21_WA_kern 05_gen:8891248
7256653:4 | 05 vijfde verdieping | Group: Model Group:NLRS_22.21_WA_kern 05_gen:8891248
7256792 | 03 derde verdieping
7256792:2 | 03 derde verdieping
7256792:3 | 03 derde verdieping
7256792:4 | 03 derde verdieping
7256910 | 02 tweede verdieping
7256910:2 | 02 tweede verdieping
7256910:3 | 02 tweede verdieping
7256910:4 | 02 tweede verdieping
7257018 | 01 eerste verdieping
7257018:2 | 01 eerste verdieping
7257018:3 | 01 eerste verdieping
7257018:4 | 01 eerste verdieping

# IfcSlab: Floor:NLRS_23.21_FL_breedplaat d=80_gen (4)
PredefinedType: FLOOR; Classification: 23.21 vloeren - constructief, vrijdragende vloeren (Uniformat); Material: NLRS_f2_beton prefab 80 mm
Pset_SlabCommon - LoadBearing: yes; IsExternal: no; Reference: NLRS_23.21_FL_breedplaat d=80_gen; ThermalTransmittance: 13.075 kg/K/s3
Name (Floor:NLRS_23.21_FL_breedplaat d=80_gen:...) | In
12073154 | 57 zevenenvijftigste verdieping
12075021 | 56 zesenvijftigste verdieping
12075661 | 55 vijfenvijftigste verdieping
12076062 | 54 vierenvijftigste verdieping

# IfcSlab: Floor:NLRS_23.21_FL_druklaag d=70_gen (13)
PredefinedType: FLOOR; Classification: 23.21 vloeren - constructief, vrijdragende vloeren (Uniformat); Material: NLRS_f2_beton ihwg 70 mm
Pset_SlabCommon - LoadBearing: yes; IsExternal: no; Reference: NLRS_23.21_FL_druklaag d=70_gen; ThermalTransmittance: 14.9429 kg/K/s3
Name (Floor:NLRS_23.21_FL_druklaag d=70_gen:...) | In
4333976 | 01 eerste verdieping
4333976:2 | 01 eerste verdieping
4877166 | 02 tweede verdieping
4877166:2 | 02 tweede verdieping
4877254 | 03 derde verdieping | Pset_SlabCommon - PitchAngle: 0 deg
5164630 | 05 vijfde verdieping
6398407 | 01 eerste verdieping | Pset_SlabCommon - PitchAngle: 0 deg
6398425 | 02 tweede verdieping | Pset_SlabCommon - PitchAngle: 0 deg
9290641 | 00a eerste tussenverdieping
9290641:2 | 00a eerste tussenverdieping
11829595 | 02 tweede verdieping
11829595:2 | 02 tweede verdieping
11829595:3 | 02 tweede verdieping

# IfcSlab: Floor:NLRS_23.21_FL_druklaag d=80_gen (2)
In: 01 eerste verdieping
PredefinedType: FLOOR; Classification: 23.21 vloeren - constructief, vrijdragende vloeren (Uniformat); Material: NLRS_f2_beton ihwg 80 mm
Pset_SlabCommon - LoadBearing: yes; IsExternal: no; Reference: NLRS_23.21_FL_druklaag d=80_gen; ThermalTransmittance: 13.075 kg/K/s3
Name (Floor:NLRS_23.21_FL_druklaag d=80_gen:...)
11830037
11830037:2

# IfcSlab: Floor:NLRS_23.21_FL_druklaag d=85_gen, Floor:NLRS_23.21_FL_druklaag d=85_gen:6396083
In: 05 vijfde verdieping
PredefinedType: FLOOR; Classification: 23.21 vloeren - constructief, vrijdragende vloeren (Uniformat); Material: NLRS_f2_beton ihwg 85 mm
Pset_SlabCommon - LoadBearing: yes; IsExternal: no; PitchAngle: 0 deg; Reference: NLRS_23.21_FL_druklaag d=85_gen; ThermalTransmittance: 12.3059 kg/K/s3

# IfcSlab: Floor:NLRS_23.21_FL_kanaalplaat d=200_gen (10)
PredefinedType: FLOOR; Classification: 23.21 vloeren - constructief, vrijdragende vloeren (Uniformat); Material: NLRS_f2_beton prefab 200 mm
Pset_SlabCommon - LoadBearing: yes; IsExternal: no; Reference: NLRS_23.21_FL_kanaalplaat d=200_gen; ThermalTransmittance: 5.23 kg/K/s3
Name (Floor:NLRS_23.21_FL_kanaalplaat d=200_gen:...) | In
4877233 | 03 derde verdieping
4877233:2 | 03 derde verdieping
4877233:3 | 03 derde verdieping
4877233:4 | 03 derde verdieping
4877233:5 | 03 derde verdieping
4877233:6 | 03 derde verdieping
4877233:7 | 03 derde verdieping
4877233:8 | 03 derde verdieping
4877233:9 | 03 derde verdieping
5164785 | 05 vijfde verdieping

# IfcSlab: Floor:NLRS_23.21_FL_kanaalplaat d=255_gen (14)
PredefinedType: FLOOR; Classification: 23.21 vloeren - constructief, vrijdragende vloeren (Uniformat); Material: NLRS_f2_beton prefab 255 mm
Pset_SlabCommon - LoadBearing: yes; IsExternal: no; Reference: NLRS_23.21_FL_kanaalplaat d=255_gen; ThermalTransmittance: 4.10196 kg/K/s3
Name (Floor:NLRS_23.21_FL_kanaalplaat d=255_gen:...) | In
4246017 | 00a eerste tussenverdieping
4246017:2 | 00a eerste tussenverdieping
4333697 | 01 eerste verdieping
4333697:2 | 01 eerste verdieping
4333697:3 | 01 eerste verdieping
4333697:4 | 01 eerste verdieping
4877145 | 02 tweede verdieping
4877145:2 | 02 tweede verdieping
4877145:3 | 02 tweede verdieping
4877145:4 | 02 tweede verdieping
4886959 | 03 derde verdieping | Pset_SlabCommon - PitchAngle: 0 deg
4887183 | 03 derde verdieping | Pset_SlabCommon - PitchAngle: 0 deg
6397883 | 01 eerste verdieping | Pset_SlabCommon - PitchAngle: 0 deg
6398221 | 02 tweede verdieping | Pset_SlabCommon - PitchAngle: 0 deg

# IfcSlab: Floor:NLRS_23.21_FL_prefab plaat d=230_gen (2)
PredefinedType: FLOOR; Classification: 23.21 vloeren - constructief, vrijdragende vloeren (Uniformat); Material: NLRS_f2_beton prefab 230 mm
Pset_SlabCommon - LoadBearing: yes; IsExternal: no; Reference: NLRS_23.21_FL_prefab plaat d=230_gen; ThermalTransmittance: 4.54783 kg/K/s3
Name (Floor:NLRS_23.21_FL_prefab plaat d=230_gen:...) | In
13305863 | 59 negenenvijftigste verdieping
13311816 | 56 zesenvijftigste verdieping

# IfcSlab: Floor:NLRS_23.21_FL_staalplaatbetonvloer d=200_gen (15)
PredefinedType: FLOOR; Classification: 23.21 vloeren - constructief, vrijdragende vloeren (Uniformat); Material: NLRS_f2_beton ihwg 200 mm
Pset_SlabCommon - LoadBearing: yes; IsExternal: no; Reference: NLRS_23.21_FL_staalplaatbetonvloer d=200_gen; ThermalTransmittance: 5.23 kg/K/s3
Name (Floor:NLRS_23.21_FL_staalplaatbetonvloer d=200_gen:...) | In | PitchAngle (deg)
4993446 | 58 achtenvijftigste verdieping | 0
5046351 | 60 zestigste verdieping
5046551 | 61 eenenzestigste verdieping
5046569 | 62 tweeënzestigste verdieping
5306016 | 59 negenenvijftigste verdieping | 0
12837561 | 59 negenenvijftigste verdieping | 0
12837702 | 59 negenenvijftigste verdieping | 0
12837827 | 59 negenenvijftigste verdieping | 0
12839425 | 58 achtenvijftigste verdieping | 0
12839561 | 58 achtenvijftigste verdieping
12839962 | 58 achtenvijftigste verdieping | 0
12840166 | 58 achtenvijftigste verdieping
12840474 | 58 achtenvijftigste verdieping | 0
12840548 | 58 achtenvijftigste verdieping | 0
12840674 | 58 achtenvijftigste verdieping | 0

# IfcSlab: Floor:NLRS_23.21_FL_vloer d=270_gen (12)
PredefinedType: FLOOR; Classification: 23.21 vloeren - constructief, vrijdragende vloeren (Uniformat)
Pset_SlabCommon - LoadBearing: yes; IsExternal: no; Reference: NLRS_23.21_FL_vloer d=270_gen; ThermalTransmittance: 3.87407 kg/K/s3
Name (Floor:NLRS_23.21_FL_vloer d=270_gen:...) | In | Material | Group
4999044 | 53 drieënvijftigste verdieping | NLRS_f2_beton ihwg
5795486 | 52 tweeënvijftigste verdieping | NLRS_f2_beton ihwg
5889094 | 42 tweeënveertigste verdieping | NLRS_f2_beton ihwg 270 mm | Model Group:NLRS_23.21_vloer voor wanden d=300/300_gen:5889137
5914300 | 51 eenenvijftigste verdieping |  | Model Group:NLRS_23.21_vloer voor wanden d=300/300_gen:5792671
9028227 | 47 zevenenveertigste verdieping | NLRS_f2_beton ihwg 270 mm | Model Group:NLRS_23.21_vloer voor wanden d=300/300_gen:9028234
9029103 | 50 vijftigste verdieping |  | Model Group:NLRS_23.21_vloer voor wanden d=300/300_gen:9029110
9148282 | 43 drieënveertigste verdieping | NLRS_f2_beton ihwg 270 mm | Model Group:NLRS_23.21_vloer voor wanden d=300/300_gen:9148289
9148574 | 44 vierenveertigste verdieping | NLRS_f2_beton ihwg 270 mm | Model Group:NLRS_23.21_vloer voor wanden d=300/300_gen:9148581
9148866 | 45 vijfenveertigste verdieping | NLRS_f2_beton ihwg 270 mm | Model Group:NLRS_23.21_vloer voor wanden d=300/300_gen:9148873
9149158 | 46 zesenveertigste verdieping | NLRS_f2_beton ihwg 270 mm | Model Group:NLRS_23.21_vloer voor wanden d=300/300_gen:9149165
9149450 | 49 negenenveertigste verdieping | NLRS_f2_beton ihwg 270 mm | Model Group:NLRS_23.21_vloer voor wanden d=300/300_gen:9149457
9152972 | 48 achtenveertigste verdieping | NLRS_f2_beton ihwg 270 mm | Model Group:NLRS_23.21_vloer voor wanden d=300/300_gen:9152979

# IfcSlab: Floor:NLRS_23.21_FL_vloer d=300_gen (2)
PredefinedType: FLOOR; Classification: 23.21 vloeren - constructief, vrijdragende vloeren (Uniformat); Material: NLRS_f2_beton ihwg 300 mm
Pset_SlabCommon - LoadBearing: yes; IsExternal: no; PitchAngle: 0 deg; Reference: NLRS_23.21_FL_vloer d=300_gen; ThermalTransmittance: 3.48667 kg/K/s3
Name (Floor:NLRS_23.21_FL_vloer d=300_gen:...) | In
11890110 | 55 vijfenvijftigste verdieping
11890353 | 56 zesenvijftigste verdieping

# IfcSlab: Floor:NLRS_23.21_FL_vloer d=350_gen (4)
PredefinedType: FLOOR; Classification: 23.21 vloeren - constructief, vrijdragende vloeren (Uniformat); Material: NLRS_f2_beton ihwg
Pset_SlabCommon - LoadBearing: yes; IsExternal: no; Reference: NLRS_23.21_FL_vloer d=350_gen; ThermalTransmittance: 2.98857 kg/K/s3
Name (Floor:NLRS_23.21_FL_vloer d=350_gen:...) | In
4988941 | 54 vierenvijftigste verdieping
10197194 | 55 vijfenvijftigste verdieping
10200906 | 56 zesenvijftigste verdieping
10268466 | 57 zevenenvijftigste verdieping

# IfcSlab: Floor:NLRS_23.21_FL_vloer=230 later gestort_gen (2)
PredefinedType: FLOOR; Classification: 23.21 vloeren - constructief, vrijdragende vloeren (Uniformat); Material: NLRS_f2_beton ihwg 230 mm
Pset_SlabCommon - LoadBearing: yes; IsExternal: no; PitchAngle: 0 deg; Reference: NLRS_23.21_FL_vloer=230 later gestort_gen; ThermalTransmittance: 4.54783 kg/K/s3
Name (Floor:NLRS_23.21_FL_vloer=230 later gestort_gen:...) | In
14155681 | 56 zesenvijftigste verdieping
14270218 | 57 zevenenvijftigste verdieping

# IfcSlab: Floor:NLRS_23.21_FL_vloer=230_gen (54)
PredefinedType: FLOOR; Classification: 23.21 vloeren - constructief, vrijdragende vloeren (Uniformat)
Pset_SlabCommon - LoadBearing: yes; IsExternal: no; Reference: NLRS_23.21_FL_vloer=230_gen; ThermalTransmittance: 4.54783 kg/K/s3
Name (Floor:NLRS_23.21_FL_vloer=230_gen:...) | In | Material | Group
4860048 | 06 zesde verdieping | NLRS_f2_beton ihwg 230 mm | Model Group:NLRS_22.21_WA_kern 06--51_gen:4690937
4972250 | 53 drieënvijftigste verdieping
4982110 | 52 tweeënvijftigste verdieping
5001109 | 54 vierenvijftigste verdieping
5003640 | 57 zevenenvijftigste verdieping
5005574 | 58 achtenvijftigste verdieping
5009616 | 56 zesenvijftigste verdieping
5009947 | 55 vijfenvijftigste verdieping
5310472 | 59 negenenvijftigste verdieping
8873656 | 07 zevende verdieping | NLRS_f2_beton ihwg 230 mm | Model Group:NLRS_22.21_WA_kern 06--51_gen:4689379
8873918 | 08 achtste verdieping | NLRS_f2_beton ihwg 230 mm | Model Group:NLRS_22.21_WA_kern 06--51_gen:4715051
8873975 | 12 twaalfde verdieping | NLRS_f2_beton ihwg 230 mm | Model Group:NLRS_22.21_WA_kern 06--51_gen:4738448
8874032 | 09 negende verdieping | NLRS_f2_beton ihwg 230 mm | Model Group:NLRS_22.21_WA_kern 06--51_gen:5667376
8874089 | 10 tiende verdieping | NLRS_f2_beton ihwg 230 mm | Model Group:NLRS_22.21_WA_kern 06--51_gen:6859079
8874146 | 11 elfde verdieping | NLRS_f2_beton ihwg 230 mm | Model Group:NLRS_22.21_WA_kern 06--51_gen:6861592
8875634 | 13 dertiende verdieping | NLRS_f2_beton ihwg 230 mm | Model Group:NLRS_22.21_WA_kern 06--51_gen:4730861
8875691 | 15 vijftiende verdieping | NLRS_f2_beton ihwg 230 mm | Model Group:NLRS_22.21_WA_kern 06--51_gen:4731319
8875748 | 17 zeventiende verdieping | NLRS_f2_beton ihwg 230 mm | Model Group:NLRS_22.21_WA_kern 06--51_gen:4731777
8875805 | 19 negentiende verdieping | NLRS_f2_beton ihwg 230 mm | Model Group:NLRS_22.21_WA_kern 06--51_gen:4732235
8875862 | 14 veertiende verdieping | NLRS_f2_beton ihwg 230 mm | Model Group:NLRS_22.21_WA_kern 06--51_gen:4738906
8875919 | 16 zestiende verdieping | NLRS_f2_beton ihwg 230 mm | Model Group:NLRS_22.21_WA_kern 06--51_gen:4739364
8875976 | 18 achttiende verdieping | NLRS_f2_beton ihwg 230 mm | Model Group:NLRS_22.21_WA_kern 06--51_gen:4739822
8876033 | 20 twintigste verdieping | NLRS_f2_beton ihwg 230 mm | Model Group:NLRS_22.21_WA_kern 06--51_gen:4740280
8879110 | 21 eenentwintigste verdieping | NLRS_f2_beton ihwg 230 mm | Model Group:NLRS_22.21_WA_kern 06--51_gen:4695238
8879167 | 24 vierentwintigste verdieping | NLRS_f2_beton ihwg 230 mm | Model Group:NLRS_22.21_WA_kern 06--51_gen:4746873
8879224 | 25 vijfentwintigste verdieping | NLRS_f2_beton ihwg 230 mm | Model Group:NLRS_22.21_WA_kern 06--51_gen:4747305
8879281 | 26 zesentwintigste verdieping | NLRS_f2_beton ihwg 230 mm | Model Group:NLRS_22.21_WA_kern 06--51_gen:4747737
8879338 | 27 zevenentwintigste verdieping | NLRS_f2_beton ihwg 230 mm | Model Group:NLRS_22.21_WA_kern 06--51_gen:4748169
8879395 | 28 achtentwintigste verdieping | NLRS_f2_beton ihwg 230 mm | Model Group:NLRS_22.21_WA_kern 06--51_gen:4748601
8879452 | 29 negenentwintigste verdieping | NLRS_f2_beton ihwg 230 mm | Model Group:NLRS_22.21_WA_kern 06--51_gen:4749033
8879509 | 30 dertigste verdieping | NLRS_f2_beton ihwg 230 mm | Model Group:NLRS_22.21_WA_kern 06--51_gen:4749465
8879566 | 31 eenendertigste verdieping | NLRS_f2_beton ihwg 230 mm | Model Group:NLRS_22.21_WA_kern 06--51_gen:4749897
8879623 | 32 tweeëndertigste verdieping | NLRS_f2_beton ihwg 230 mm | Model Group:NLRS_22.21_WA_kern 06--51_gen:4750329
8879680 | 33 drieëndertigste verdieping | NLRS_f2_beton ihwg 230 mm | Model Group:NLRS_22.21_WA_kern 06--51_gen:4750761
8879737 | 34 vierendertigste verdieping | NLRS_f2_beton ihwg 230 mm | Model Group:NLRS_22.21_WA_kern 06--51_gen:4751193
8879794 | 35 vijfendertigste verdieping | NLRS_f2_beton ihwg 230 mm | Model Group:NLRS_22.21_WA_kern 06--51_gen:4751625
8879851 | 36 zesendertigste verdieping | NLRS_f2_beton ihwg 230 mm | Model Group:NLRS_22.21_WA_kern 06--51_gen:4752057
8879908 | 37 zevenendertigste verdieping | NLRS_f2_beton ihwg 230 mm | Model Group:NLRS_22.21_WA_kern 06--51_gen:4752489
8879965 | 38 achtendertigste verdieping | NLRS_f2_beton ihwg 230 mm | Model Group:NLRS_22.21_WA_kern 06--51_gen:4752921
8880022 | 39 negenendertigste verdieping | NLRS_f2_beton ihwg 230 mm | Model Group:NLRS_22.21_WA_kern 06--51_gen:4753353
8880079 | 40 veertigste verdieping | NLRS_f2_beton ihwg 230 mm | Model Group:NLRS_22.21_WA_kern 06--51_gen:4753785
8880136 | 22 tweeëntwintigste verdieping | NLRS_f2_beton ihwg 230 mm | Model Group:NLRS_22.21_WA_kern 06--51_gen:4778253
8880193 | 23 drieëntwintigste verdieping | NLRS_f2_beton ihwg 230 mm | Model Group:NLRS_22.21_WA_kern 06--51_gen:4779836
8880250 | 41 eenenveertigste verdieping | NLRS_f2_beton ihwg 230 mm | Model Group:NLRS_22.21_WA_kern 06--51_gen:4783953
8880307 | 43 drieënveertigste verdieping | NLRS_f2_beton ihwg 230 mm | Model Group:NLRS_22.21_WA_kern 06--51_gen:4788999
8880364 | 44 vierenveertigste verdieping | NLRS_f2_beton ihwg 230 mm | Model Group:NLRS_22.21_WA_kern 06--51_gen:4789431
8880421 | 45 vijfenveertigste verdieping | NLRS_f2_beton ihwg 230 mm | Model Group:NLRS_22.21_WA_kern 06--51_gen:4789863
8880478 | 46 zesenveertigste verdieping | NLRS_f2_beton ihwg 230 mm | Model Group:NLRS_22.21_WA_kern 06--51_gen:4790295
8880535 | 47 zevenenveertigste verdieping | NLRS_f2_beton ihwg 230 mm | Model Group:NLRS_22.21_WA_kern 06--51_gen:4790727
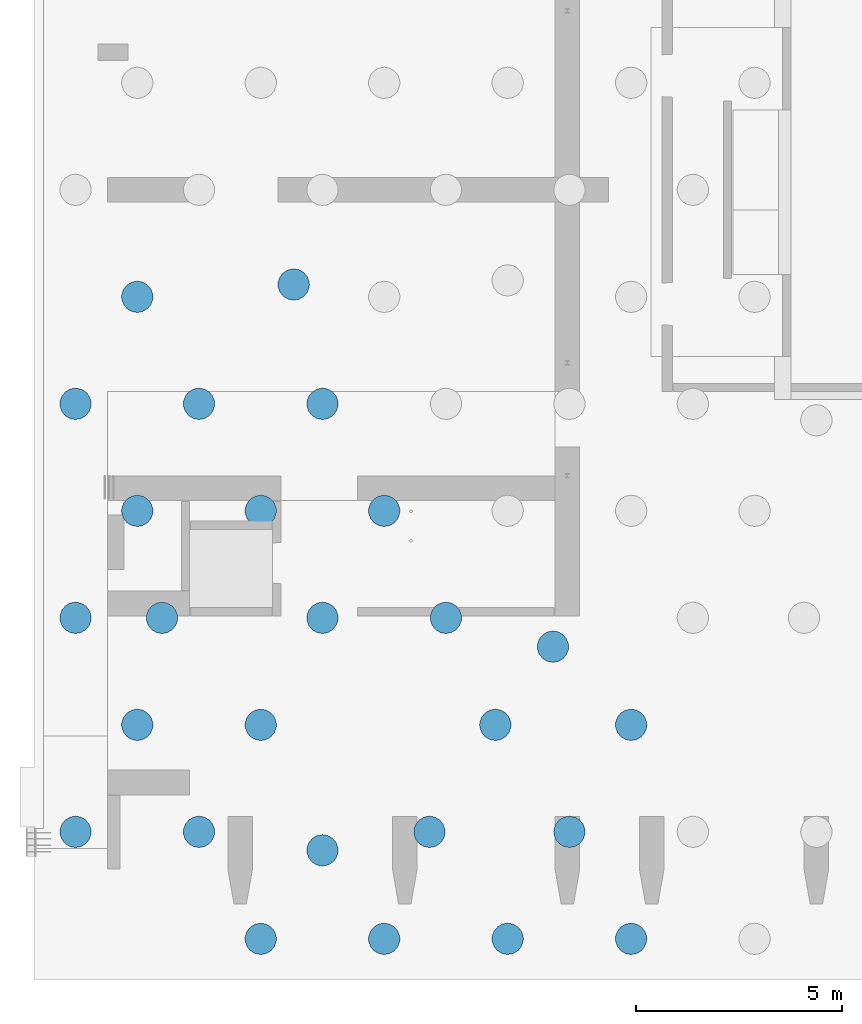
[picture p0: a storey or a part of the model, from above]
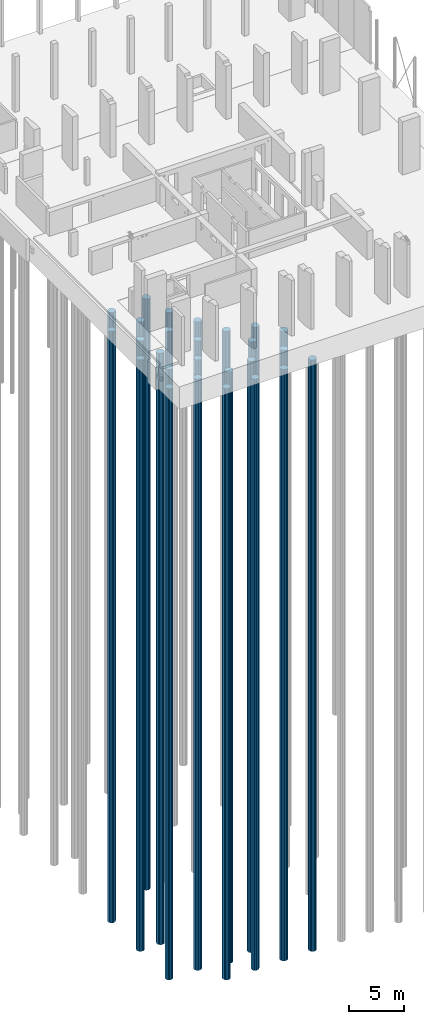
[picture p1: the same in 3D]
Properties of the parts of a building model (IFC2X3), part 17 of 21

# IfcSlab: Floor:NLRS_23.21_FL_vloer=230_gen (54)
Name (Floor:NLRS_23.21_FL_vloer=230_gen:...) | In | Material | Group
8880592 | 48 achtenveertigste verdieping | NLRS_f2_beton ihwg 230 mm | Model Group:NLRS_22.21_WA_kern 06--51_gen:4791159
8880649 | 49 negenenveertigste verdieping | NLRS_f2_beton ihwg 230 mm | Model Group:NLRS_22.21_WA_kern 06--51_gen:4791591
8880706 | 50 vijftigste verdieping |  | Model Group:NLRS_22.21_WA_kern 06--51_gen:4792023
8880763 | 42 tweeënveertigste verdieping | NLRS_f2_beton ihwg 230 mm | Model Group:NLRS_22.21_WA_kern 06--51_gen:4803472
8880820 | 51 eenenvijftigste verdieping |  | Model Group:NLRS_22.21_WA_kern 06--51_gen:4980182

# IfcSlab: Floor:NLRS_23.22_FL_beton prefab d=270 3D element_gen (192)
PredefinedType: LANDING; Classification: 23.22 vloeren - constructief, balkons (Uniformat)
Pset_SlabCommon - LoadBearing: yes; IsExternal: no; Reference: NLRS_23.22_FL_beton prefab d=270 3D element_gen; ThermalTransmittance: 3.87407 kg/K/s3
Name (Floor:NLRS_23.22_FL_beton prefab d=270 3D element_gen:...) | In | Material | PitchAngle (deg) | Group
4689296 | 08 achtste verdieping | NLRS_f2_beton prefab 270 mm | 0 | Model Group:NLRS_28.21_WA_3D element 001 d=400_gen:4689303
4689306 | 08 achtste verdieping | NLRS_f2_beton prefab 270 mm | 0 | Model Group:NLRS_28.21_WA_3D element 002 d=400_gen:4689313
4689322 | 08 achtste verdieping | NLRS_f2_beton prefab 270 mm | 0 | Model Group:NLRS_28.21_WA_3D element 002 d=400_gen:4689329
4689338 | 08 achtste verdieping | NLRS_f2_beton prefab 270 mm | 0 | Model Group:NLRS_28.21_WA_3D element 001 d=400_gen:4689345
4690859 | 07 zevende verdieping | NLRS_f2_beton prefab 270 mm | 0 | Model Group:NLRS_28.21_WA_3D element 001 d=400_gen:4690866
4690869 | 07 zevende verdieping | NLRS_f2_beton prefab 270 mm | 0 | Model Group:NLRS_28.21_WA_3D element 002 d=400_gen:4690876
4690885 | 07 zevende verdieping | NLRS_f2_beton prefab 270 mm | 0 | Model Group:NLRS_28.21_WA_3D element 002 d=400_gen:4690892
4690901 | 07 zevende verdieping | NLRS_f2_beton prefab 270 mm | 0 | Model Group:NLRS_28.21_WA_3D element 001 d=400_gen:4690908
4695200 | 22 tweeëntwintigste verdieping | NLRS_f2_beton prefab 270 mm | 0 | Model Group:NLRS_28.21_WA_3D element 002 d=300_gen:4695207
4695299 | 22 tweeëntwintigste verdieping | NLRS_f2_beton prefab 270 mm | 0 | Model Group:NLRS_28.21_WA_3D element 002 d=300_gen:4695191
4695343 | 22 tweeëntwintigste verdieping | NLRS_f2_beton prefab 270 mm | 0 | Model Group:NLRS_28.21_WA_3D element 001 d=300_gen:4695190
4695372 | 22 tweeëntwintigste verdieping | NLRS_f2_beton prefab 270 mm | 0 | Model Group:NLRS_28.21_WA_3D element 001 d=300_gen:4695208
4714973 | 09 negende verdieping | NLRS_f2_beton prefab 270 mm | 0 | Model Group:NLRS_28.21_WA_3D element 001 d=400_gen:4714980
4714983 | 09 negende verdieping | NLRS_f2_beton prefab 270 mm | 0 | Model Group:NLRS_28.21_WA_3D element 002 d=400_gen:4714990
4714999 | 09 negende verdieping | NLRS_f2_beton prefab 270 mm | 0 | Model Group:NLRS_28.21_WA_3D element 002 d=400_gen:4715006
4715015 | 09 negende verdieping | NLRS_f2_beton prefab 270 mm | 0 | Model Group:NLRS_28.21_WA_3D element 001 d=400_gen:4715022
4730823 | 14 veertiende verdieping | NLRS_f2_beton prefab 270 mm | 0 | Model Group:NLRS_28.21_WA_3D element 002 d=300_gen:4730830
4730922 | 14 veertiende verdieping | NLRS_f2_beton prefab 270 mm | 0 | Model Group:NLRS_28.21_WA_3D element 002 d=300_gen:4730814
4730966 | 14 veertiende verdieping | NLRS_f2_beton prefab 270 mm | 0 | Model Group:NLRS_28.21_WA_3D element 001 d=300_gen:4730813
4730995 | 14 veertiende verdieping | NLRS_f2_beton prefab 270 mm | 0 | Model Group:NLRS_28.21_WA_3D element 001 d=300_gen:4730831
4731281 | 16 zestiende verdieping | NLRS_f2_beton prefab 270 mm | 0 | Model Group:NLRS_28.21_WA_3D element 002 d=300_gen:4731288
4731380 | 16 zestiende verdieping | NLRS_f2_beton prefab 270 mm | 0 | Model Group:NLRS_28.21_WA_3D element 002 d=300_gen:4731272
4731424 | 16 zestiende verdieping | NLRS_f2_beton prefab 270 mm | 0 | Model Group:NLRS_28.21_WA_3D element 001 d=300_gen:4731271
4731453 | 16 zestiende verdieping | NLRS_f2_beton prefab 270 mm | 0 | Model Group:NLRS_28.21_WA_3D element 001 d=300_gen:4731289
4731739 | 18 achttiende verdieping | NLRS_f2_beton prefab 270 mm | 0 | Model Group:NLRS_28.21_WA_3D element 002 d=300_gen:4731746
4731838 | 18 achttiende verdieping | NLRS_f2_beton prefab 270 mm | 0 | Model Group:NLRS_28.21_WA_3D element 002 d=300_gen:4731730
4731882 | 18 achttiende verdieping | NLRS_f2_beton prefab 270 mm | 0 | Model Group:NLRS_28.21_WA_3D element 001 d=300_gen:4731729
4731911 | 18 achttiende verdieping | NLRS_f2_beton prefab 270 mm | 0 | Model Group:NLRS_28.21_WA_3D element 001 d=300_gen:4731747
4732197 | 20 twintigste verdieping | NLRS_f2_beton prefab 270 mm | 0 | Model Group:NLRS_28.21_WA_3D element 002 d=300_gen:4732204
4732296 | 20 twintigste verdieping | NLRS_f2_beton prefab 270 mm | 0 | Model Group:NLRS_28.21_WA_3D element 002 d=300_gen:4732188
4732340 | 20 twintigste verdieping | NLRS_f2_beton prefab 270 mm | 0 | Model Group:NLRS_28.21_WA_3D element 001 d=300_gen:4732187
4732369 | 20 twintigste verdieping | NLRS_f2_beton prefab 270 mm | 0 | Model Group:NLRS_28.21_WA_3D element 001 d=300_gen:4732205
4738410 | 13 dertiende verdieping | NLRS_f2_beton prefab 270 mm | 0 | Model Group:NLRS_28.21_WA_3D element 002 d=300_gen:4738417
4738509 | 13 dertiende verdieping | NLRS_f2_beton prefab 270 mm | 0 | Model Group:NLRS_28.21_WA_3D element 002 d=300_gen:4738401
4738553 | 13 dertiende verdieping | NLRS_f2_beton prefab 270 mm | 0 | Model Group:NLRS_28.21_WA_3D element 001 d=300_gen:4738400
4738582 | 13 dertiende verdieping | NLRS_f2_beton prefab 270 mm | 0 | Model Group:NLRS_28.21_WA_3D element 001 d=300_gen:4738418
4738868 | 15 vijftiende verdieping | NLRS_f2_beton prefab 270 mm | 0 | Model Group:NLRS_28.21_WA_3D element 002 d=300_gen:4738875
4738967 | 15 vijftiende verdieping | NLRS_f2_beton prefab 270 mm | 0 | Model Group:NLRS_28.21_WA_3D element 002 d=300_gen:4738859
4739011 | 15 vijftiende verdieping | NLRS_f2_beton prefab 270 mm | 0 | Model Group:NLRS_28.21_WA_3D element 001 d=300_gen:4738858
4739040 | 15 vijftiende verdieping | NLRS_f2_beton prefab 270 mm | 0 | Model Group:NLRS_28.21_WA_3D element 001 d=300_gen:4738876
4739326 | 17 zeventiende verdieping | NLRS_f2_beton prefab 270 mm | 0 | Model Group:NLRS_28.21_WA_3D element 002 d=300_gen:4739333
4739425 | 17 zeventiende verdieping | NLRS_f2_beton prefab 270 mm | 0 | Model Group:NLRS_28.21_WA_3D element 002 d=300_gen:4739317
4739469 | 17 zeventiende verdieping | NLRS_f2_beton prefab 270 mm | 0 | Model Group:NLRS_28.21_WA_3D element 001 d=300_gen:4739316
4739498 | 17 zeventiende verdieping | NLRS_f2_beton prefab 270 mm | 0 | Model Group:NLRS_28.21_WA_3D element 001 d=300_gen:4739334
4739784 | 19 negentiende verdieping | NLRS_f2_beton prefab 270 mm | 0 | Model Group:NLRS_28.21_WA_3D element 002 d=300_gen:4739791
4739883 | 19 negentiende verdieping | NLRS_f2_beton prefab 270 mm | 0 | Model Group:NLRS_28.21_WA_3D element 002 d=300_gen:4739775
4739927 | 19 negentiende verdieping | NLRS_f2_beton prefab 270 mm | 0 | Model Group:NLRS_28.21_WA_3D element 001 d=300_gen:4739774
4739956 | 19 negentiende verdieping | NLRS_f2_beton prefab 270 mm | 0 | Model Group:NLRS_28.21_WA_3D element 001 d=300_gen:4739792
4740242 | 21 eenentwintigste verdieping | NLRS_f2_beton prefab 270 mm | 0 | Model Group:NLRS_28.21_WA_3D element 002 d=300_gen:4740249
4740341 | 21 eenentwintigste verdieping | NLRS_f2_beton prefab 270 mm | 0 | Model Group:NLRS_28.21_WA_3D element 002 d=300_gen:4740233
4740385 | 21 eenentwintigste verdieping | NLRS_f2_beton prefab 270 mm | 0 | Model Group:NLRS_28.21_WA_3D element 001 d=300_gen:4740232
4740414 | 21 eenentwintigste verdieping | NLRS_f2_beton prefab 270 mm | 0 | Model Group:NLRS_28.21_WA_3D element 001 d=300_gen:4740250
4746839 | 25 vijfentwintigste verdieping | NLRS_f2_beton prefab 270 mm | 0 | Model Group:NLRS_28.21_WA_3D element 002 d=300_gen:4746846
4746920 | 25 vijfentwintigste verdieping | NLRS_f2_beton prefab 270 mm | 0 | Model Group:NLRS_28.21_WA_3D element 002 d=300_gen:4746830
4746964 | 25 vijfentwintigste verdieping | NLRS_f2_beton prefab 270 mm | 0 | Model Group:NLRS_28.21_WA_3D element 001 d=300_gen:4746829
4746993 | 25 vijfentwintigste verdieping | NLRS_f2_beton prefab 270 mm | 0 | Model Group:NLRS_28.21_WA_3D element 001 d=300_gen:4746847
4747271 | 26 zesentwintigste verdieping | NLRS_f2_beton prefab 270 mm | 0 | Model Group:NLRS_28.21_WA_3D element 002 d=300_gen:4747278
4747352 | 26 zesentwintigste verdieping | NLRS_f2_beton prefab 270 mm | 0 | Model Group:NLRS_28.21_WA_3D element 002 d=300_gen:4747262
4747396 | 26 zesentwintigste verdieping | NLRS_f2_beton prefab 270 mm | 0 | Model Group:NLRS_28.21_WA_3D element 001 d=300_gen:4747261
4747425 | 26 zesentwintigste verdieping | NLRS_f2_beton prefab 270 mm | 0 | Model Group:NLRS_28.21_WA_3D element 001 d=300_gen:4747279
4747703 | 27 zevenentwintigste verdieping | NLRS_f2_beton prefab 270 mm | 0 | Model Group:NLRS_28.21_WA_3D element 002 d=300_gen:4747710
4747784 | 27 zevenentwintigste verdieping | NLRS_f2_beton prefab 270 mm | 0 | Model Group:NLRS_28.21_WA_3D element 002 d=300_gen:4747694
4747828 | 27 zevenentwintigste verdieping | NLRS_f2_beton prefab 270 mm | 0 | Model Group:NLRS_28.21_WA_3D element 001 d=300_gen:4747693
4747857 | 27 zevenentwintigste verdieping | NLRS_f2_beton prefab 270 mm | 0 | Model Group:NLRS_28.21_WA_3D element 001 d=300_gen:4747711
4748135 | 28 achtentwintigste verdieping | NLRS_f2_beton prefab 270 mm | 0 | Model Group:NLRS_28.21_WA_3D element 002 d=300_gen:4748142
4748216 | 28 achtentwintigste verdieping | NLRS_f2_beton prefab 270 mm | 0 | Model Group:NLRS_28.21_WA_3D element 002 d=300_gen:4748126
4748260 | 28 achtentwintigste verdieping | NLRS_f2_beton prefab 270 mm | 0 | Model Group:NLRS_28.21_WA_3D element 001 d=300_gen:4748125
4748289 | 28 achtentwintigste verdieping | NLRS_f2_beton prefab 270 mm | 0 | Model Group:NLRS_28.21_WA_3D element 001 d=300_gen:4748143
4748567 | 29 negenentwintigste verdieping | NLRS_f2_beton prefab 270 mm | 0 | Model Group:NLRS_28.21_WA_3D element 002 d=300_gen:4748574
4748648 | 29 negenentwintigste verdieping | NLRS_f2_beton prefab 270 mm | 0 | Model Group:NLRS_28.21_WA_3D element 002 d=300_gen:4748558
4748692 | 29 negenentwintigste verdieping | NLRS_f2_beton prefab 270 mm | 0 | Model Group:NLRS_28.21_WA_3D element 001 d=300_gen:4748557
4748721 | 29 negenentwintigste verdieping | NLRS_f2_beton prefab 270 mm | 0 | Model Group:NLRS_28.21_WA_3D element 001 d=300_gen:4748575
4748999 | 30 dertigste verdieping | NLRS_f2_beton prefab 270 mm | 0 | Model Group:NLRS_28.21_WA_3D element 002 d=300_gen:4749006
4749080 | 30 dertigste verdieping | NLRS_f2_beton prefab 270 mm | 0 | Model Group:NLRS_28.21_WA_3D element 002 d=300_gen:4748990
4749124 | 30 dertigste verdieping | NLRS_f2_beton prefab 270 mm | 0 | Model Group:NLRS_28.21_WA_3D element 001 d=300_gen:4748989
4749153 | 30 dertigste verdieping | NLRS_f2_beton prefab 270 mm | 0 | Model Group:NLRS_28.21_WA_3D element 001 d=300_gen:4749007
4749431 | 31 eenendertigste verdieping | NLRS_f2_beton prefab 270 mm | 0 | Model Group:NLRS_28.21_WA_3D element 002 d=300_gen:4749438
4749512 | 31 eenendertigste verdieping | NLRS_f2_beton prefab 270 mm | 0 | Model Group:NLRS_28.21_WA_3D element 002 d=300_gen:4749422
4749556 | 31 eenendertigste verdieping | NLRS_f2_beton prefab 270 mm | 0 | Model Group:NLRS_28.21_WA_3D element 001 d=300_gen:4749421
4749585 | 31 eenendertigste verdieping | NLRS_f2_beton prefab 270 mm | 0 | Model Group:NLRS_28.21_WA_3D element 001 d=300_gen:4749439
4749863 | 32 tweeëndertigste verdieping | NLRS_f2_beton prefab 270 mm | 0 | Model Group:NLRS_28.21_WA_3D element 002 d=300_gen:4749870
4749944 | 32 tweeëndertigste verdieping | NLRS_f2_beton prefab 270 mm | 0 | Model Group:NLRS_28.21_WA_3D element 002 d=300_gen:4749854
4749988 | 32 tweeëndertigste verdieping | NLRS_f2_beton prefab 270 mm | 0 | Model Group:NLRS_28.21_WA_3D element 001 d=300_gen:4749853
4750017 | 32 tweeëndertigste verdieping | NLRS_f2_beton prefab 270 mm | 0 | Model Group:NLRS_28.21_WA_3D element 001 d=300_gen:4749871
4750295 | 33 drieëndertigste verdieping | NLRS_f2_beton prefab 270 mm | 0 | Model Group:NLRS_28.21_WA_3D element 002 d=300_gen:4750302
4750376 | 33 drieëndertigste verdieping | NLRS_f2_beton prefab 270 mm | 0 | Model Group:NLRS_28.21_WA_3D element 002 d=300_gen:4750286
4750420 | 33 drieëndertigste verdieping | NLRS_f2_beton prefab 270 mm | 0 | Model Group:NLRS_28.21_WA_3D element 001 d=300_gen:4750285
4750449 | 33 drieëndertigste verdieping | NLRS_f2_beton prefab 270 mm | 0 | Model Group:NLRS_28.21_WA_3D element 001 d=300_gen:4750303
4750727 | 34 vierendertigste verdieping | NLRS_f2_beton prefab 270 mm | 0 | Model Group:NLRS_28.21_WA_3D element 002 d=300_gen:4750734
4750808 | 34 vierendertigste verdieping | NLRS_f2_beton prefab 270 mm | 0 | Model Group:NLRS_28.21_WA_3D element 002 d=300_gen:4750718
4750852 | 34 vierendertigste verdieping | NLRS_f2_beton prefab 270 mm | 0 | Model Group:NLRS_28.21_WA_3D element 001 d=300_gen:4750717
4750881 | 34 vierendertigste verdieping | NLRS_f2_beton prefab 270 mm | 0 | Model Group:NLRS_28.21_WA_3D element 001 d=300_gen:4750735
4751159 | 35 vijfendertigste verdieping | NLRS_f2_beton prefab 270 mm | 0 | Model Group:NLRS_28.21_WA_3D element 002 d=300_gen:4751166
4751240 | 35 vijfendertigste verdieping | NLRS_f2_beton prefab 270 mm | 0 | Model Group:NLRS_28.21_WA_3D element 002 d=300_gen:4751150
4751284 | 35 vijfendertigste verdieping | NLRS_f2_beton prefab 270 mm | 0 | Model Group:NLRS_28.21_WA_3D element 001 d=300_gen:4751149
4751313 | 35 vijfendertigste verdieping | NLRS_f2_beton prefab 270 mm | 0 | Model Group:NLRS_28.21_WA_3D element 001 d=300_gen:4751167
4751591 | 36 zesendertigste verdieping | NLRS_f2_beton prefab 270 mm | 0 | Model Group:NLRS_28.21_WA_3D element 002 d=300_gen:4751598
4751672 | 36 zesendertigste verdieping | NLRS_f2_beton prefab 270 mm | 0 | Model Group:NLRS_28.21_WA_3D element 002 d=300_gen:4751582
4751716 | 36 zesendertigste verdieping | NLRS_f2_beton prefab 270 mm | 0 | Model Group:NLRS_28.21_WA_3D element 001 d=300_gen:4751581
4751745 | 36 zesendertigste verdieping | NLRS_f2_beton prefab 270 mm | 0 | Model Group:NLRS_28.21_WA_3D element 001 d=300_gen:4751599
4752023 | 37 zevenendertigste verdieping | NLRS_f2_beton prefab 270 mm | 0 | Model Group:NLRS_28.21_WA_3D element 002 d=300_gen:4752030
4752104 | 37 zevenendertigste verdieping | NLRS_f2_beton prefab 270 mm | 0 | Model Group:NLRS_28.21_WA_3D element 002 d=300_gen:4752014
4752148 | 37 zevenendertigste verdieping | NLRS_f2_beton prefab 270 mm | 0 | Model Group:NLRS_28.21_WA_3D element 001 d=300_gen:4752013
4752177 | 37 zevenendertigste verdieping | NLRS_f2_beton prefab 270 mm | 0 | Model Group:NLRS_28.21_WA_3D element 001 d=300_gen:4752031
4752455 | 38 achtendertigste verdieping | NLRS_f2_beton prefab 270 mm | 0 | Model Group:NLRS_28.21_WA_3D element 002 d=300_gen:4752462
4752536 | 38 achtendertigste verdieping | NLRS_f2_beton prefab 270 mm | 0 | Model Group:NLRS_28.21_WA_3D element 002 d=300_gen:4752446
4752580 | 38 achtendertigste verdieping | NLRS_f2_beton prefab 270 mm | 0 | Model Group:NLRS_28.21_WA_3D element 001 d=300_gen:4752445
4752609 | 38 achtendertigste verdieping | NLRS_f2_beton prefab 270 mm | 0 | Model Group:NLRS_28.21_WA_3D element 001 d=300_gen:4752463
4752887 | 39 negenendertigste verdieping | NLRS_f2_beton prefab 270 mm | 0 | Model Group:NLRS_28.21_WA_3D element 002 d=300_gen:4752894
4752968 | 39 negenendertigste verdieping | NLRS_f2_beton prefab 270 mm | 0 | Model Group:NLRS_28.21_WA_3D element 002 d=300_gen:4752878
4753012 | 39 negenendertigste verdieping | NLRS_f2_beton prefab 270 mm | 0 | Model Group:NLRS_28.21_WA_3D element 001 d=300_gen:4752877
4753041 | 39 negenendertigste verdieping | NLRS_f2_beton prefab 270 mm | 0 | Model Group:NLRS_28.21_WA_3D element 001 d=300_gen:4752895
4753319 | 40 veertigste verdieping | NLRS_f2_beton prefab 270 mm | 0 | Model Group:NLRS_28.21_WA_3D element 002 d=300_gen:4753326
4753400 | 40 veertigste verdieping | NLRS_f2_beton prefab 270 mm | 0 | Model Group:NLRS_28.21_WA_3D element 002 d=300_gen:4753310
4753444 | 40 veertigste verdieping | NLRS_f2_beton prefab 270 mm | 0 | Model Group:NLRS_28.21_WA_3D element 001 d=300_gen:4753309
4753473 | 40 veertigste verdieping | NLRS_f2_beton prefab 270 mm | 0 | Model Group:NLRS_28.21_WA_3D element 001 d=300_gen:4753327
4753751 | 41 eenenveertigste verdieping | NLRS_f2_beton prefab 270 mm | 0 | Model Group:NLRS_28.21_WA_3D element 002 d=300_gen:4753758
4753832 | 41 eenenveertigste verdieping | NLRS_f2_beton prefab 270 mm | 0 | Model Group:NLRS_28.21_WA_3D element 002 d=300_gen:4753742
4753876 | 41 eenenveertigste verdieping | NLRS_f2_beton prefab 270 mm | 0 | Model Group:NLRS_28.21_WA_3D element 001 d=300_gen:4753741
4753905 | 41 eenenveertigste verdieping | NLRS_f2_beton prefab 270 mm | 0 | Model Group:NLRS_28.21_WA_3D element 001 d=300_gen:4753759
4778219 | 23 drieëntwintigste verdieping | NLRS_f2_beton prefab 270 mm | 0 | Model Group:NLRS_28.21_WA_3D element 002 d=300_gen:4778226
4778300 | 23 drieëntwintigste verdieping | NLRS_f2_beton prefab 270 mm | 0 | Model Group:NLRS_28.21_WA_3D element 002 d=300_gen:4778210
4778344 | 23 drieëntwintigste verdieping | NLRS_f2_beton prefab 270 mm | 0 | Model Group:NLRS_28.21_WA_3D element 001 d=300_gen:4778209
4778373 | 23 drieëntwintigste verdieping | NLRS_f2_beton prefab 270 mm | 0 | Model Group:NLRS_28.21_WA_3D element 001 d=300_gen:4778227
4779802 | 24 vierentwintigste verdieping | NLRS_f2_beton prefab 270 mm | 0 | Model Group:NLRS_28.21_WA_3D element 002 d=300_gen:4779809
4779883 | 24 vierentwintigste verdieping | NLRS_f2_beton prefab 270 mm | 0 | Model Group:NLRS_28.21_WA_3D element 002 d=300_gen:4779793
4779927 | 24 vierentwintigste verdieping | NLRS_f2_beton prefab 270 mm | 0 | Model Group:NLRS_28.21_WA_3D element 001 d=300_gen:4779792
4779956 | 24 vierentwintigste verdieping | NLRS_f2_beton prefab 270 mm | 0 | Model Group:NLRS_28.21_WA_3D element 001 d=300_gen:4779810
4783919 | 42 tweeënveertigste verdieping | NLRS_f2_beton prefab 270 mm | 0 | Model Group:NLRS_28.21_WA_3D element 002 d=300_gen:4783926
4784000 | 42 tweeënveertigste verdieping | NLRS_f2_beton prefab 270 mm | 0 | Model Group:NLRS_28.21_WA_3D element 002 d=300_gen:4783910
4784044 | 42 tweeënveertigste verdieping | NLRS_f2_beton prefab 270 mm | 0 | Model Group:NLRS_28.21_WA_3D element 001 d=300_gen:4783909
4784073 | 42 tweeënveertigste verdieping | NLRS_f2_beton prefab 270 mm | 0 | Model Group:NLRS_28.21_WA_3D element 001 d=300_gen:4783927
4788965 | 44 vierenveertigste verdieping | NLRS_f2_beton prefab 270 mm | 0 | Model Group:NLRS_28.21_WA_3D element 002 d=300_gen:4788972
4789046 | 44 vierenveertigste verdieping | NLRS_f2_beton prefab 270 mm | 0 | Model Group:NLRS_28.21_WA_3D element 002 d=300_gen:4788956
4789090 | 44 vierenveertigste verdieping | NLRS_f2_beton prefab 270 mm | 0 | Model Group:NLRS_28.21_WA_3D element 001 d=300_gen:4788955
4789119 | 44 vierenveertigste verdieping | NLRS_f2_beton prefab 270 mm | 0 | Model Group:NLRS_28.21_WA_3D element 001 d=300_gen:4788973
4789397 | 45 vijfenveertigste verdieping | NLRS_f2_beton prefab 270 mm | 0 | Model Group:NLRS_28.21_WA_3D element 002 d=300_gen:4789404
4789478 | 45 vijfenveertigste verdieping | NLRS_f2_beton prefab 270 mm | 0 | Model Group:NLRS_28.21_WA_3D element 002 d=300_gen:4789388
4789522 | 45 vijfenveertigste verdieping | NLRS_f2_beton prefab 270 mm | 0 | Model Group:NLRS_28.21_WA_3D element 001 d=300_gen:4789387
4789551 | 45 vijfenveertigste verdieping | NLRS_f2_beton prefab 270 mm | 0 | Model Group:NLRS_28.21_WA_3D element 001 d=300_gen:4789405
4789829 | 46 zesenveertigste verdieping |  |  | Model Group:NLRS_28.21_WA_3D element 002 d=300_gen:4789836
4789910 | 46 zesenveertigste verdieping | NLRS_f2_beton prefab 270 mm | 0 | Model Group:NLRS_28.21_WA_3D element 002 d=300_gen:4789820
4789954 | 46 zesenveertigste verdieping | NLRS_f2_beton prefab 270 mm | 0 | Model Group:NLRS_28.21_WA_3D element 001 d=300_gen:4789819
4789983 | 46 zesenveertigste verdieping | NLRS_f2_beton prefab 270 mm | 0 | Model Group:NLRS_28.21_WA_3D element 001 d=300_gen:4789837
4790261 | 47 zevenenveertigste verdieping | NLRS_f2_beton prefab 270 mm | 0 | Model Group:NLRS_28.21_WA_3D element 002 d=300_gen:4790268
4790342 | 47 zevenenveertigste verdieping | NLRS_f2_beton prefab 270 mm | 0 | Model Group:NLRS_28.21_WA_3D element 002 d=300_gen:4790252
4790386 | 47 zevenenveertigste verdieping | NLRS_f2_beton prefab 270 mm | 0 | Model Group:NLRS_28.21_WA_3D element 001 d=300_gen:4790251
4790415 | 47 zevenenveertigste verdieping | NLRS_f2_beton prefab 270 mm | 0 | Model Group:NLRS_28.21_WA_3D element 001 d=300_gen:4790269
4790693 | 48 achtenveertigste verdieping | NLRS_f2_beton prefab 270 mm | 0 | Model Group:NLRS_28.21_WA_3D element 002 d=300_gen:4790700
4790774 | 48 achtenveertigste verdieping | NLRS_f2_beton prefab 270 mm | 0 | Model Group:NLRS_28.21_WA_3D element 002 d=300_gen:4790684
4790818 | 48 achtenveertigste verdieping | NLRS_f2_beton prefab 270 mm | 0 | Model Group:NLRS_28.21_WA_3D element 001 d=300_gen:4790683
4790847 | 48 achtenveertigste verdieping | NLRS_f2_beton prefab 270 mm | 0 | Model Group:NLRS_28.21_WA_3D element 001 d=300_gen:4790701
4791125 | 49 negenenveertigste verdieping | NLRS_f2_beton prefab 270 mm | 0 | Model Group:NLRS_28.21_WA_3D element 002 d=300_gen:4791132
4791206 | 49 negenenveertigste verdieping | NLRS_f2_beton prefab 270 mm | 0 | Model Group:NLRS_28.21_WA_3D element 002 d=300_gen:4791116
4791250 | 49 negenenveertigste verdieping | NLRS_f2_beton prefab 270 mm | 0 | Model Group:NLRS_28.21_WA_3D element 001 d=300_gen:4791115
4791279 | 49 negenenveertigste verdieping | NLRS_f2_beton prefab 270 mm | 0 | Model Group:NLRS_28.21_WA_3D element 001 d=300_gen:4791133
4791557 | 50 vijftigste verdieping |  |  | Model Group:NLRS_28.21_WA_3D element 002 d=300_gen:4791564
4791638 | 50 vijftigste verdieping |  |  | Model Group:NLRS_28.21_WA_3D element 002 d=300_gen:4791548
4791682 | 50 vijftigste verdieping |  |  | Model Group:NLRS_28.21_WA_3D element 001 d=300_gen:4791547
4791711 | 50 vijftigste verdieping |  |  | Model Group:NLRS_28.21_WA_3D element 001 d=300_gen:4791565
4791989 | 51 eenenvijftigste verdieping |  |  | Model Group:NLRS_28.21_WA_3D element 002 d=300_gen:4791996
4792070 | 51 eenenvijftigste verdieping |  |  | Model Group:NLRS_28.21_WA_3D element 002 d=300_gen:4791980
4792114 | 51 eenenvijftigste verdieping |  |  | Model Group:NLRS_28.21_WA_3D element 001 d=300_gen:4791979
4792143 | 51 eenenvijftigste verdieping |  |  | Model Group:NLRS_28.21_WA_3D element 001 d=300_gen:4791997
4803438 | 43 drieënveertigste verdieping | NLRS_f2_beton prefab 270 mm | 0 | Model Group:NLRS_28.21_WA_3D element 002 d=300_gen:4803445
4803519 | 43 drieënveertigste verdieping | NLRS_f2_beton prefab 270 mm | 0 | Model Group:NLRS_28.21_WA_3D element 002 d=300_gen:4803429
4803563 | 43 drieënveertigste verdieping | NLRS_f2_beton prefab 270 mm | 0 | Model Group:NLRS_28.21_WA_3D element 001 d=300_gen:4803428
4803592 | 43 drieënveertigste verdieping | NLRS_f2_beton prefab 270 mm | 0 | Model Group:NLRS_28.21_WA_3D element 001 d=300_gen:4803446
4980156 | 52 tweeënvijftigste verdieping |  |  | Model Group:NLRS_28.21_WA_3D element 002 d=300_gen:4980163
4980229 | 52 tweeënvijftigste verdieping |  |  | Model Group:NLRS_28.21_WA_3D element 002 d=300_gen:4980147
4980273 | 52 tweeënvijftigste verdieping |  |  | Model Group:NLRS_28.21_WA_3D element 001 d=300_gen:4980146
4980302 | 52 tweeënvijftigste verdieping |  |  | Model Group:NLRS_28.21_WA_3D element 001 d=300_gen:4980164
4982001 | 53 drieënvijftigste verdieping |  |  | Model Group:NLRS_28.21_WA_3D element 002a d=300_gen:4981919
4982045 | 53 drieënvijftigste verdieping |  |  | Model Group:NLRS_28.21_WA_3D element 001a d=300_gen:4981918
5042431 | 06 zesde verdieping
5042562 | 06 zesde verdieping
5043330 | 53 drieënvijftigste verdieping |  |  | Model Group:NLRS_28.21_WA_3D element 002a d=300_gen:4981935
5044695 | 53 drieënvijftigste verdieping |  |  | Model Group:NLRS_28.21_WA_3D element 001a d=300_gen:4981936
5667350 | 10 tiende verdieping | NLRS_f2_beton prefab 270 mm | 0 | Model Group:NLRS_28.21_WA_3D element 002 d=300_gen:5667357
5667425 | 10 tiende verdieping | NLRS_f2_beton prefab 270 mm | 0 | Model Group:NLRS_28.21_WA_3D element 002 d=300_gen:5667341
5667469 | 10 tiende verdieping | NLRS_f2_beton prefab 270 mm | 0 | Model Group:NLRS_28.21_WA_3D element 001 d=300_gen:5667340
5667498 | 10 tiende verdieping | NLRS_f2_beton prefab 270 mm | 0 | Model Group:NLRS_28.21_WA_3D element 001 d=300_gen:5667358
6801386 | 06 zesde verdieping
6801857 | 06 zesde verdieping
6859073 | 11 elfde verdieping | NLRS_f2_beton prefab 270 mm | 0 | Model Group:NLRS_28.21_WA_3D element 002 d=300_gen:6859076
6859124 | 11 elfde verdieping | NLRS_f2_beton prefab 270 mm | 0 | Model Group:NLRS_28.21_WA_3D element 002 d=300_gen:6859064
6859162 | 11 elfde verdieping | NLRS_f2_beton prefab 270 mm | 0 | Model Group:NLRS_28.21_WA_3D element 001 d=300_gen:6859063
6859188 | 11 elfde verdieping | NLRS_f2_beton prefab 270 mm | 0 | Model Group:NLRS_28.21_WA_3D element 001 d=300_gen:6859077
6861586 | 12 twaalfde verdieping | NLRS_f2_beton prefab 270 mm | 0 | Model Group:NLRS_28.21_WA_3D element 002 d=300_gen:6861589
6861637 | 12 twaalfde verdieping | NLRS_f2_beton prefab 270 mm | 0 | Model Group:NLRS_28.21_WA_3D element 002 d=300_gen:6861577
6861675 | 12 twaalfde verdieping | NLRS_f2_beton prefab 270 mm | 0 | Model Group:NLRS_28.21_WA_3D element 001 d=300_gen:6861576
6861701 | 12 twaalfde verdieping | NLRS_f2_beton prefab 270 mm | 0 | Model Group:NLRS_28.21_WA_3D element 001 d=300_gen:6861590

# IfcSlab: Floor:NLRS_27.21_FL_geprofileerde staalplaat d=110_gen (5)
In: 05 vijfde verdieping
PredefinedType: ROOF; Classification: 27.21 daken - constructief, vlakke daken (Uniformat); Material: NLRS_h2_staal 110 mm
Pset_SlabCommon - IsExternal: yes; LoadBearing: yes; PitchAngle: 0 deg; Reference: NLRS_27.21_FL_geprofileerde staalplaat d=110_gen; ThermalTransmittance: 409.091 kg/K/s3
Name (Floor:NLRS_27.21_FL_geprofileerde staalplaat d=110_gen:...)
12261962
12262000
12262044
12262101
12262139

# IfcSlab: NLRS_16.13_SFO_LB_fundatiepoer_gen:3400x8000x2400, NLRS_16.13_SFO_LB_fundatiepoer_gen:3400x8000x2400:4113463
In: 00 begane grond
PredefinedType: BASESLAB; Classification: 16.13 funderingsconstructies - voeten en balken, fundatie poeren (Uniformat); Material: NLRS_f2_beton ihwg
Pset_SlabCommon - Reference: 3400x8000x2400; IsExternal: no

# IfcWall: Basic Wall:NLRS_16.21_WA_beton ihwg d=350_gen, Basic Wall:NLRS_16.21_WA_beton ihwg d=350_gen:4212288
In: 00 begane grond
Classification: 16.21 funderingsconstructies - keerwanden, grondkerende wanden (Uniformat); Material: NLRS_f2_beton ihwg
Pset_WallCommon - IsExternal: yes; LoadBearing: yes; ExtendToStructure: no; Reference: NLRS_16.21_WA_beton ihwg d=350_gen; ThermalTransmittance: 2.98857 kg/K/s3

# IfcWall: Basic Wall:NLRS_22.21_WA_beton prefab d=300_gen (2)
In: 52 tweeënvijftigste verdieping
Type - PredefinedType: STANDARD; Material: NLRS_f2_beton prefab 300 mm
Classification: 22.21 binnenwanden - constructief, massieve wanden (Uniformat)
Pset_WallCommon - LoadBearing: yes; IsExternal: no; ExtendToStructure: no; Reference: NLRS_22.21_WA_beton prefab d=300_gen; ThermalTransmittance: 3.48667 kg/K/s3
Name (Basic Wall:NLRS_22.21_WA_beton prefab d=300_gen:...)
4981974
4982022

# IfcWall: NLRS_16.12_SF_WPB_ihwg beton ongewapend_gen:350x2500, NLRS_16.12_SF_WPB_ihwg beton ongewapend_gen:350x2500:9412515
In: 00 begane grond
Type - Material: NLRS_f2_beton ihwg (ongewapend)
Classification: 16.12 funderingsconstructies - voeten en balken, fundatie balken (Uniformat)
Pset_WallCommon - IsExternal: yes; LoadBearing: yes; ExtendToStructure: no; Reference: 350x2500

# IfcWall: NLRS_16.12_SF_WPB_oplegnok ihwg beton_gen:200x300 (2)
In: 00 begane grond
Type - Material: NLRS_f2_beton ihwg
Classification: 16.12 funderingsconstructies - voeten en balken, fundatie balken (Uniformat)
Pset_WallCommon - IsExternal: yes; LoadBearing: yes; ExtendToStructure: no; Reference: 200x300
Name (NLRS_16.12_SF_WPB_oplegnok ihwg beton_gen:200x300:...)
5158875
6270043

# IfcWall: NLRS_16.12_SF_WPB_oplegnok ihwg beton_gen:200x500 (4)
In: 00 begane grond
Type - Material: NLRS_f2_beton ihwg
Classification: 16.12 funderingsconstructies - voeten en balken, fundatie balken (Uniformat)
Pset_WallCommon - IsExternal: yes; LoadBearing: yes; ExtendToStructure: no; Reference: 200x500
Name (NLRS_16.12_SF_WPB_oplegnok ihwg beton_gen:200x500:...)
6270001
6270027
6968682
7364619

# IfcWall: NLRS_21.21_SF_WPB_oplegnok prefabbeton_gen:300x200 (2)
Type - Material: NLRS_f2_beton prefab
Classification: 21.21 buitenwanden - constructief, massieve wanden (Uniformat)
Pset_WallCommon - IsExternal: yes; LoadBearing: yes; ExtendToStructure: no; Reference: 300x200
Name (NLRS_21.21_SF_WPB_oplegnok prefabbeton_gen:300x200:...) | In
6654302 | 01 eerste verdieping
6656047 | 02 tweede verdieping

# IfcWall: NLRS_21.21_SF_WPB_oplegnok prefabbeton_gen:325x450 met afschuining 9, NLRS_21.21_SF_WPB_oplegnok prefabbeton_gen:325x450 met afschuining 9:6646518
In: 03 derde verdieping
Type - Material: NLRS_f2_beton prefab
Classification: 21.21 buitenwanden - constructief, massieve wanden (Uniformat)
Pset_WallCommon - IsExternal: yes; LoadBearing: yes; ExtendToStructure: no; Reference: 325x450 met afschuining 9

# IfcWall: NLRS_21.21_SF_WPB_oplegnok prefabbeton_gen:450x200 met afschuining 15gr (5)
Type - Material: NLRS_f2_beton prefab
Classification: 21.21 buitenwanden - constructief, massieve wanden (Uniformat)
Pset_WallCommon - IsExternal: yes; LoadBearing: yes; ExtendToStructure: no; Reference: 450x200 met afschuining 15gr
Name (NLRS_21.21_SF_WPB_oplegnok prefabbeton_gen:450x200 met afschuining 15gr:...) | In
6646516 | 02 tweede verdieping
6646534 | 01 eerste verdieping
11829249 | 03 derde verdieping
14108010 | 05 vijfde verdieping
14109641 | 05 vijfde verdieping

# IfcWall: NLRS_21.21_SF_WPB_oplegnok prefabbeton_gen:450x275 met afschuining 15gr (16)
Type - Material: NLRS_f2_beton prefab
Classification: 21.21 buitenwanden - constructief, massieve wanden (Uniformat)
Pset_WallCommon - IsExternal: yes; LoadBearing: yes; ExtendToStructure: no; Reference: 450x275 met afschuining 15gr
Name (NLRS_21.21_SF_WPB_oplegnok prefabbeton_gen:450x275 met afschuining 15gr:...) | In
6646502 | 02 tweede verdieping
6646504 | 02 tweede verdieping
6646506 | 02 tweede verdieping
6646508 | 02 tweede verdieping
6646510 | 02 tweede verdieping
6646512 | 02 tweede verdieping
6646514 | 02 tweede verdieping
6646520 | 01 eerste verdieping
6646522 | 01 eerste verdieping
6646524 | 01 eerste verdieping
6646526 | 01 eerste verdieping
6646528 | 01 eerste verdieping
6646530 | 01 eerste verdieping
6646532 | 01 eerste verdieping
6646568 | 02 tweede verdieping
6687034 | 01 eerste verdieping

# IfcWall: NLRS_21.21_SF_WPB_oplegnok prefabbeton_gen:450x290 met afschuining 15gr (16)
Type - Material: NLRS_f2_beton prefab
Classification: 21.21 buitenwanden - constructief, massieve wanden (Uniformat)
Pset_WallCommon - IsExternal: yes; LoadBearing: yes; ExtendToStructure: no; Reference: 450x290 met afschuining 15gr
Name (NLRS_21.21_SF_WPB_oplegnok prefabbeton_gen:450x290 met afschuining 15gr:...) | In
6646536 | 01 eerste verdieping
6646538 | 01 eerste verdieping
6646540 | 01 eerste verdieping
6646542 | 01 eerste verdieping
6646544 | 01 eerste verdieping
6646546 | 01 eerste verdieping
6646548 | 01 eerste verdieping
6646550 | 01 eerste verdieping
6646552 | 02 tweede verdieping
6646554 | 02 tweede verdieping
6646556 | 02 tweede verdieping
6646558 | 02 tweede verdieping
6646560 | 02 tweede verdieping
6646562 | 02 tweede verdieping
6646564 | 02 tweede verdieping
6646566 | 02 tweede verdieping

# IfcWall: NLRS_21.21_SF_WPB_oplegnok prefabbeton_gen:450x290 met afschuining 15gr 2 (2)
Type - Material: NLRS_f2_beton prefab
Classification: 21.21 buitenwanden - constructief, massieve wanden (Uniformat)
Pset_WallCommon - IsExternal: yes; LoadBearing: yes; ExtendToStructure: no; Reference: 450x290 met afschuining 15gr 2
Name (NLRS_21.21_SF_WPB_oplegnok prefabbeton_gen:450x290 met afschuining 15gr 2:...) | In
6656191 | 02 tweede verdieping
6656230 | 01 eerste verdieping

# IfcWall: Parametric Wall:NLRS_22.21_WA_beton prefab d=250 1006x2448_gen (21)
Type - Material: NLRS_f2_beton prefab dichtstorten
Classification: 22.21 binnenwanden - constructief, massieve wanden (Uniformat)
Pset_WallCommon - LoadBearing: yes; IsExternal: no; ExtendToStructure: no; Reference: NLRS_22.21_WA_beton prefab d=250 1006x2448_gen
Name (Parametric Wall:NLRS_22.21_WA_beton prefab d=250 1006x2448_gen:...) | In
11847496 | 54 vierenvijftigste verdieping
11847948 | 54 vierenvijftigste verdieping
11847949 | 54 vierenvijftigste verdieping
11848089 | 55 vijfenvijftigste verdieping
11848090 | 55 vijfenvijftigste verdieping
11848091 | 55 vijfenvijftigste verdieping
11848092 | 55 vijfenvijftigste verdieping
11848094 | 56 zesenvijftigste verdieping
11848095 | 56 zesenvijftigste verdieping
11848096 | 56 zesenvijftigste verdieping
11848097 | 56 zesenvijftigste verdieping
11848280 | 55 vijfenvijftigste verdieping
11848313 | 56 zesenvijftigste verdieping
12086613 | 56 zesenvijftigste verdieping
12086697 | 56 zesenvijftigste verdieping
12086750 | 55 vijfenvijftigste verdieping
12571929 | 57 zevenenvijftigste verdieping
12571930 | 57 zevenenvijftigste verdieping
12571961 | 57 zevenenvijftigste verdieping
12573661 | 57 zevenenvijftigste verdieping
14092117 | 54 vierenvijftigste verdieping

# IfcWall: Parametric Wall:NLRS_22.21_WA_beton prefab d=500 1006x2448_gen (60)
Type - Material: NLRS_f2_beton prefab dichtstorten
Classification: 22.21 binnenwanden - constructief, massieve wanden (Uniformat)
Pset_WallCommon - LoadBearing: yes; IsExternal: no; ExtendToStructure: no; Reference: NLRS_22.21_WA_beton prefab d=500 1006x2448_gen
Name (Parametric Wall:NLRS_22.21_WA_beton prefab d=500 1006x2448_gen:...) | In | Group
6337367 | 21 eenentwintigste verdieping | Model Group:NLRS_22.21_WA_Wanden dichtstorten 21-23-28-29-33_gen:5227524
6337516 | 21 eenentwintigste verdieping | Model Group:NLRS_22.21_WA_Wanden dichtstorten 21-23-28-29-33_gen:5227524
6337776 | 23 drieëntwintigste verdieping | Model Group:NLRS_22.21_WA_Wanden dichtstorten 21-23-28-29-33_gen:5229009
6337783 | 23 drieëntwintigste verdieping | Model Group:NLRS_22.21_WA_Wanden dichtstorten 21-23-28-29-33_gen:5229009
6337785 | 28 achtentwintigste verdieping | Model Group:NLRS_22.21_WA_Wanden dichtstorten 21-23-28-29-33_gen:5229097
6337792 | 28 achtentwintigste verdieping | Model Group:NLRS_22.21_WA_Wanden dichtstorten 21-23-28-29-33_gen:5229097
6337794 | 29 negenentwintigste verdieping | Model Group:NLRS_22.21_WA_Wanden dichtstorten 21-23-28-29-33_gen:5229191
6337801 | 29 negenentwintigste verdieping | Model Group:NLRS_22.21_WA_Wanden dichtstorten 21-23-28-29-33_gen:5229191
6337803 | 33 drieëndertigste verdieping | Model Group:NLRS_22.21_WA_Wanden dichtstorten 21-23-28-29-33_gen:5229282
6337810 | 33 drieëndertigste verdieping | Model Group:NLRS_22.21_WA_Wanden dichtstorten 21-23-28-29-33_gen:5229282
6341140 | 24 vierentwintigste verdieping | Model Group:NLRS_22.21_WA_Wanden dichtstorten 24-34_gen:5229726
6341409 | 24 vierentwintigste verdieping | Model Group:NLRS_22.21_WA_Wanden dichtstorten 24-34_gen:5229726
6341488 | 34 vierendertigste verdieping | Model Group:NLRS_22.21_WA_Wanden dichtstorten 24-34_gen:5229679
6341491 | 34 vierendertigste verdieping | Model Group:NLRS_22.21_WA_Wanden dichtstorten 24-34_gen:5229679
6341541 | 26 zesentwintigste verdieping | Model Group:NLRS_22.21_WA_Wanden dichtstorten 26-27-36--39_gen:5230594
6342296 | 27 zevenentwintigste verdieping | Model Group:NLRS_22.21_WA_Wanden dichtstorten 26-27-36--39_gen:5231127
6342304 | 38 achtendertigste verdieping | Model Group:NLRS_22.21_WA_Wanden dichtstorten 26-27-36--39_gen:5231232
6342312 | 39 negenendertigste verdieping | Model Group:NLRS_22.21_WA_Wanden dichtstorten 26-27-36--39_gen:5231250
6342320 | 36 zesendertigste verdieping | Model Group:NLRS_22.21_WA_Wanden dichtstorten 26-27-36--39_gen:5231989
6342328 | 37 zevenendertigste verdieping | Model Group:NLRS_22.21_WA_Wanden dichtstorten 26-27-36--39_gen:5232148
6342379 | 40 veertigste verdieping | Model Group:NLRS_22.21_WA_Wanden dichtstorten 30-40_gen:5231828
6342563 | 40 veertigste verdieping | Model Group:NLRS_22.21_WA_Wanden dichtstorten 30-40_gen:5231828
6342581 | 40 veertigste verdieping | Model Group:NLRS_22.21_WA_Wanden dichtstorten 30-40_gen:5231828
6342636 | 40 veertigste verdieping | Model Group:NLRS_22.21_WA_Wanden dichtstorten 30-40_gen:5231828
6342662 | 30 dertigste verdieping | Model Group:NLRS_22.21_WA_Wanden dichtstorten 30-40_gen:5231521
6342663 | 30 dertigste verdieping | Model Group:NLRS_22.21_WA_Wanden dichtstorten 30-40_gen:5231521
6342664 | 30 dertigste verdieping | Model Group:NLRS_22.21_WA_Wanden dichtstorten 30-40_gen:5231521
6342665 | 30 dertigste verdieping | Model Group:NLRS_22.21_WA_Wanden dichtstorten 30-40_gen:5231521
6342684 | 41 eenenveertigste verdieping | Model Group:NLRS_22.21_WA_Wanden dichtstorten 41_gen:5232392
6342851 | 41 eenenveertigste verdieping | Model Group:NLRS_22.21_WA_Wanden dichtstorten 41_gen:5232392
6343266 | 42 tweeënveertigste verdieping | Model Group:NLRS_22.21_WA_Wanden dichtstorten 42-46-49_gen:5232880
6343286 | 42 tweeënveertigste verdieping | Model Group:NLRS_22.21_WA_Wanden dichtstorten 42-46-49_gen:5232880
6343876 | 43 drieënveertigste verdieping | Model Group:NLRS_22.21_WA_Wanden dichtstorten 42-46-49_gen:5233690
6343877 | 43 drieënveertigste verdieping | Model Group:NLRS_22.21_WA_Wanden dichtstorten 42-46-49_gen:5233690
6343885 | 44 vierenveertigste verdieping | Model Group:NLRS_22.21_WA_Wanden dichtstorten 44_gen:5233804
6343886 | 44 vierenveertigste verdieping | Model Group:NLRS_22.21_WA_Wanden dichtstorten 44_gen:5233804
6343894 | 45 vijfenveertigste verdieping | Model Group:NLRS_22.21_WA_Wanden dichtstorten 42-46-49_gen:5233823
6343895 | 45 vijfenveertigste verdieping | Model Group:NLRS_22.21_WA_Wanden dichtstorten 42-46-49_gen:5233823
6343903 | 46 zesenveertigste verdieping | Model Group:NLRS_22.21_WA_Wanden dichtstorten 42-46-49_gen:5233842
6343904 | 46 zesenveertigste verdieping | Model Group:NLRS_22.21_WA_Wanden dichtstorten 42-46-49_gen:5233842
6343912 | 49 negenenveertigste verdieping | Model Group:NLRS_22.21_WA_Wanden dichtstorten 42-46-49_gen:5233861
6343913 | 49 negenenveertigste verdieping | Model Group:NLRS_22.21_WA_Wanden dichtstorten 42-46-49_gen:5233861
6343944 | 47 zevenenveertigste verdieping | Model Group:NLRS_22.21_WA_Wanden dichtstorten 47-48_gen:5234234
6343984 | 47 zevenenveertigste verdieping | Model Group:NLRS_22.21_WA_Wanden dichtstorten 47-48_gen:5234234
6344010 | 47 zevenenveertigste verdieping | Model Group:NLRS_22.21_WA_Wanden dichtstorten 47-48_gen:5234234
6344502 | 48 achtenveertigste verdieping | Model Group:NLRS_22.21_WA_Wanden dichtstorten 47-48_gen:5234640
6344504 | 48 achtenveertigste verdieping | Model Group:NLRS_22.21_WA_Wanden dichtstorten 47-48_gen:5234640
6344505 | 48 achtenveertigste verdieping | Model Group:NLRS_22.21_WA_Wanden dichtstorten 47-48_gen:5234640
6344551 | 51 eenenvijftigste verdieping | Model Group:NLRS_22.21_WA_Wanden dichtstorten 51_gen:5235593
6344671 | 51 eenenvijftigste verdieping | Model Group:NLRS_22.21_WA_Wanden dichtstorten 51_gen:5235593
6344947 | 52 tweeënvijftigste verdieping | Model Group:NLRS_22.21_WA_Wanden dichtstorten 52_gen:5236115
6345002 | 52 tweeënvijftigste verdieping | Model Group:NLRS_22.21_WA_Wanden dichtstorten 52_gen:5236115
6345380 | 50 vijftigste verdieping | Model Group:NLRS_22.21_WA_Wanden dichtstorten 50_gen:5234960
6345513 | 50 vijftigste verdieping | Model Group:NLRS_22.21_WA_Wanden dichtstorten 50_gen:5234960
6345548 | 50 vijftigste verdieping | Model Group:NLRS_22.21_WA_Wanden dichtstorten 50_gen:5234960
6345578 | 50 vijftigste verdieping | Model Group:NLRS_22.21_WA_Wanden dichtstorten 50_gen:5234960
6346048 | 25 vijfentwintigste verdieping | Model Group:NLRS_22.21_WA_Wanden dichtstorten 25-35_gen:5230273
6346115 | 25 vijfentwintigste verdieping | Model Group:NLRS_22.21_WA_Wanden dichtstorten 25-35_gen:5230273
6346401 | 35 vijfendertigste verdieping | Model Group:NLRS_22.21_WA_Wanden dichtstorten 25-35_gen:5230458
6346403 | 35 vijfendertigste verdieping | Model Group:NLRS_22.21_WA_Wanden dichtstorten 25-35_gen:5230458

# IfcWall: Parametric Wall:NLRS_22.21_WA_beton prefab d=500 1900x2460_gen (6)
In: 05 vijfde verdieping
Type - Material: NLRS_f2_beton prefab dichtstorten
Classification: 22.21 binnenwanden - constructief, massieve wanden (Uniformat); Group: Model Group:NLRS_22.21_WA_Wanden dichtstorten 05_gen:6333979
Pset_WallCommon - LoadBearing: yes; IsExternal: no; ExtendToStructure: no; Reference: NLRS_22.21_WA_beton prefab d=500 1900x2460_gen
Name (Parametric Wall:NLRS_22.21_WA_beton prefab d=500 1900x2460_gen:...)
6332856
6333108
6333202
6333259
6333407
6333921

# IfcWall: Parametric Wall:NLRS_22.21_WA_beton prefab d=500 1900x2470_gen (210)
Type - Material: NLRS_f2_beton prefab dichtstorten
Classification: 22.21 binnenwanden - constructief, massieve wanden (Uniformat)
Pset_WallCommon - LoadBearing: yes; IsExternal: no; ExtendToStructure: no; Reference: NLRS_22.21_WA_beton prefab d=500 1900x2470_gen
Name (Parametric Wall:NLRS_22.21_WA_beton prefab d=500 1900x2470_gen:...) | In | Group
6334136 | 06 zesde verdieping | Model Group:NLRS_22.21_WA_Wanden dichtstorten 06--08_gen:6334142
6334137 | 06 zesde verdieping | Model Group:NLRS_22.21_WA_Wanden dichtstorten 06--08_gen:6334142
6334138 | 06 zesde verdieping | Model Group:NLRS_22.21_WA_Wanden dichtstorten 06--08_gen:6334142
6334139 | 06 zesde verdieping | Model Group:NLRS_22.21_WA_Wanden dichtstorten 06--08_gen:6334142
6334140 | 06 zesde verdieping | Model Group:NLRS_22.21_WA_Wanden dichtstorten 06--08_gen:6334142
6334141 | 06 zesde verdieping | Model Group:NLRS_22.21_WA_Wanden dichtstorten 06--08_gen:6334142
6334237 | 07 zevende verdieping | Model Group:NLRS_22.21_WA_Wanden dichtstorten 06--08_gen:6334243
6334238 | 07 zevende verdieping | Model Group:NLRS_22.21_WA_Wanden dichtstorten 06--08_gen:6334243
6334239 | 07 zevende verdieping | Model Group:NLRS_22.21_WA_Wanden dichtstorten 06--08_gen:6334243
6334240 | 07 zevende verdieping | Model Group:NLRS_22.21_WA_Wanden dichtstorten 06--08_gen:6334243
6334241 | 07 zevende verdieping | Model Group:NLRS_22.21_WA_Wanden dichtstorten 06--08_gen:6334243
6334242 | 07 zevende verdieping | Model Group:NLRS_22.21_WA_Wanden dichtstorten 06--08_gen:6334243
6334347 | 08 achtste verdieping | Model Group:NLRS_22.21_WA_Wanden dichtstorten 06--08_gen:6334353
6334348 | 08 achtste verdieping | Model Group:NLRS_22.21_WA_Wanden dichtstorten 06--08_gen:6334353
6334349 | 08 achtste verdieping | Model Group:NLRS_22.21_WA_Wanden dichtstorten 06--08_gen:6334353
6334350 | 08 achtste verdieping | Model Group:NLRS_22.21_WA_Wanden dichtstorten 06--08_gen:6334353
6334351 | 08 achtste verdieping | Model Group:NLRS_22.21_WA_Wanden dichtstorten 06--08_gen:6334353
6334352 | 08 achtste verdieping | Model Group:NLRS_22.21_WA_Wanden dichtstorten 06--08_gen:6334353
6334569 | 09 negende verdieping | Model Group:NLRS_22.21_WA_Wanden dichtstorten 09--14-19-20_gen:5224866
6334570 | 09 negende verdieping | Model Group:NLRS_22.21_WA_Wanden dichtstorten 09--14-19-20_gen:5224866
6334571 | 09 negende verdieping | Model Group:NLRS_22.21_WA_Wanden dichtstorten 09--14-19-20_gen:5224866
6334572 | 09 negende verdieping | Model Group:NLRS_22.21_WA_Wanden dichtstorten 09--14-19-20_gen:5224866
6334573 | 09 negende verdieping | Model Group:NLRS_22.21_WA_Wanden dichtstorten 09--14-19-20_gen:5224866
6334574 | 09 negende verdieping | Model Group:NLRS_22.21_WA_Wanden dichtstorten 09--14-19-20_gen:5224866
6335117 | 10 tiende verdieping | Model Group:NLRS_22.21_WA_Wanden dichtstorten 09--14-19-20_gen:5225449
6335118 | 10 tiende verdieping | Model Group:NLRS_22.21_WA_Wanden dichtstorten 09--14-19-20_gen:5225449
6335119 | 10 tiende verdieping | Model Group:NLRS_22.21_WA_Wanden dichtstorten 09--14-19-20_gen:5225449
6335120 | 10 tiende verdieping | Model Group:NLRS_22.21_WA_Wanden dichtstorten 09--14-19-20_gen:5225449
6335121 | 10 tiende verdieping | Model Group:NLRS_22.21_WA_Wanden dichtstorten 09--14-19-20_gen:5225449
6335122 | 10 tiende verdieping | Model Group:NLRS_22.21_WA_Wanden dichtstorten 09--14-19-20_gen:5225449
6335171 | 11 elfde verdieping | Model Group:NLRS_22.21_WA_Wanden dichtstorten 09--14-19-20_gen:5225528
6335172 | 11 elfde verdieping | Model Group:NLRS_22.21_WA_Wanden dichtstorten 09--14-19-20_gen:5225528
6335173 | 11 elfde verdieping | Model Group:NLRS_22.21_WA_Wanden dichtstorten 09--14-19-20_gen:5225528
6335174 | 11 elfde verdieping | Model Group:NLRS_22.21_WA_Wanden dichtstorten 09--14-19-20_gen:5225528
6335175 | 11 elfde verdieping | Model Group:NLRS_22.21_WA_Wanden dichtstorten 09--14-19-20_gen:5225528
6335176 | 11 elfde verdieping | Model Group:NLRS_22.21_WA_Wanden dichtstorten 09--14-19-20_gen:5225528
6335225 | 12 twaalfde verdieping | Model Group:NLRS_22.21_WA_Wanden dichtstorten 09--14-19-20_gen:5225607
6335226 | 12 twaalfde verdieping | Model Group:NLRS_22.21_WA_Wanden dichtstorten 09--14-19-20_gen:5225607
6335227 | 12 twaalfde verdieping | Model Group:NLRS_22.21_WA_Wanden dichtstorten 09--14-19-20_gen:5225607
6335228 | 12 twaalfde verdieping | Model Group:NLRS_22.21_WA_Wanden dichtstorten 09--14-19-20_gen:5225607
6335229 | 12 twaalfde verdieping | Model Group:NLRS_22.21_WA_Wanden dichtstorten 09--14-19-20_gen:5225607
6335230 | 12 twaalfde verdieping | Model Group:NLRS_22.21_WA_Wanden dichtstorten 09--14-19-20_gen:5225607
6335279 | 13 dertiende verdieping | Model Group:NLRS_22.21_WA_Wanden dichtstorten 09--14-19-20_gen:5225686
6335280 | 13 dertiende verdieping | Model Group:NLRS_22.21_WA_Wanden dichtstorten 09--14-19-20_gen:5225686
6335281 | 13 dertiende verdieping | Model Group:NLRS_22.21_WA_Wanden dichtstorten 09--14-19-20_gen:5225686
6335282 | 13 dertiende verdieping | Model Group:NLRS_22.21_WA_Wanden dichtstorten 09--14-19-20_gen:5225686
6335283 | 13 dertiende verdieping | Model Group:NLRS_22.21_WA_Wanden dichtstorten 09--14-19-20_gen:5225686
6335284 | 13 dertiende verdieping | Model Group:NLRS_22.21_WA_Wanden dichtstorten 09--14-19-20_gen:5225686
6335333 | 14 veertiende verdieping | Model Group:NLRS_22.21_WA_Wanden dichtstorten 09--14-19-20_gen:5225765
6335334 | 14 veertiende verdieping | Model Group:NLRS_22.21_WA_Wanden dichtstorten 09--14-19-20_gen:5225765
6335335 | 14 veertiende verdieping | Model Group:NLRS_22.21_WA_Wanden dichtstorten 09--14-19-20_gen:5225765
6335336 | 14 veertiende verdieping | Model Group:NLRS_22.21_WA_Wanden dichtstorten 09--14-19-20_gen:5225765
6335337 | 14 veertiende verdieping | Model Group:NLRS_22.21_WA_Wanden dichtstorten 09--14-19-20_gen:5225765
6335338 | 14 veertiende verdieping | Model Group:NLRS_22.21_WA_Wanden dichtstorten 09--14-19-20_gen:5225765
6335387 | 19 negentiende verdieping | Model Group:NLRS_22.21_WA_Wanden dichtstorten 09--14-19-20_gen:5225844
6335388 | 19 negentiende verdieping | Model Group:NLRS_22.21_WA_Wanden dichtstorten 09--14-19-20_gen:5225844
6335389 | 19 negentiende verdieping | Model Group:NLRS_22.21_WA_Wanden dichtstorten 09--14-19-20_gen:5225844
6335390 | 19 negentiende verdieping | Model Group:NLRS_22.21_WA_Wanden dichtstorten 09--14-19-20_gen:5225844
6335391 | 19 negentiende verdieping | Model Group:NLRS_22.21_WA_Wanden dichtstorten 09--14-19-20_gen:5225844
6335392 | 19 negentiende verdieping | Model Group:NLRS_22.21_WA_Wanden dichtstorten 09--14-19-20_gen:5225844
6335441 | 20 twintigste verdieping | Model Group:NLRS_22.21_WA_Wanden dichtstorten 09--14-19-20_gen:5227307
6335442 | 20 twintigste verdieping | Model Group:NLRS_22.21_WA_Wanden dichtstorten 09--14-19-20_gen:5227307
6335443 | 20 twintigste verdieping | Model Group:NLRS_22.21_WA_Wanden dichtstorten 09--14-19-20_gen:5227307
6335444 | 20 twintigste verdieping | Model Group:NLRS_22.21_WA_Wanden dichtstorten 09--14-19-20_gen:5227307
6335445 | 20 twintigste verdieping | Model Group:NLRS_22.21_WA_Wanden dichtstorten 09--14-19-20_gen:5227307
6335446 | 20 twintigste verdieping | Model Group:NLRS_22.21_WA_Wanden dichtstorten 09--14-19-20_gen:5227307
6336259 | 15 vijftiende verdieping
6336340 | 15 vijftiende verdieping
6336401 | 15 vijftiende verdieping
6336476 | 15 vijftiende verdieping
6337054 | 16 zestiende verdieping | Model Group:NLRS_22.21_WA_Wanden dichtstorten 15--18_gen:5226860
6337055 | 16 zestiende verdieping | Model Group:NLRS_22.21_WA_Wanden dichtstorten 15--18_gen:5226860
6337056 | 16 zestiende verdieping | Model Group:NLRS_22.21_WA_Wanden dichtstorten 15--18_gen:5226860
6337057 | 16 zestiende verdieping | Model Group:NLRS_22.21_WA_Wanden dichtstorten 15--18_gen:5226860
6337106 | 17 zeventiende verdieping | Model Group:NLRS_22.21_WA_Wanden dichtstorten 15--18_gen:5226949
6337107 | 17 zeventiende verdieping | Model Group:NLRS_22.21_WA_Wanden dichtstorten 15--18_gen:5226949
6337108 | 17 zeventiende verdieping | Model Group:NLRS_22.21_WA_Wanden dichtstorten 15--18_gen:5226949
6337109 | 17 zeventiende verdieping | Model Group:NLRS_22.21_WA_Wanden dichtstorten 15--18_gen:5226949
6337158 | 18 achttiende verdieping | Model Group:NLRS_22.21_WA_Wanden dichtstorten 15--18_gen:5227030
6337159 | 18 achttiende verdieping | Model Group:NLRS_22.21_WA_Wanden dichtstorten 15--18_gen:5227030
6337160 | 18 achttiende verdieping | Model Group:NLRS_22.21_WA_Wanden dichtstorten 15--18_gen:5227030
6337161 | 18 achttiende verdieping | Model Group:NLRS_22.21_WA_Wanden dichtstorten 15--18_gen:5227030
6337368 | 21 eenentwintigste verdieping | Model Group:NLRS_22.21_WA_Wanden dichtstorten 21-23-28-29-33_gen:5227524
6337369 | 21 eenentwintigste verdieping | Model Group:NLRS_22.21_WA_Wanden dichtstorten 21-23-28-29-33_gen:5227524
6337404 | 21 eenentwintigste verdieping | Model Group:NLRS_22.21_WA_Wanden dichtstorten 21-23-28-29-33_gen:5227524
6337414 | 21 eenentwintigste verdieping | Model Group:NLRS_22.21_WA_Wanden dichtstorten 21-23-28-29-33_gen:5227524
6337420 | 21 eenentwintigste verdieping | Model Group:NLRS_22.21_WA_Wanden dichtstorten 21-23-28-29-33_gen:5227524
6337472 | 21 eenentwintigste verdieping | Model Group:NLRS_22.21_WA_Wanden dichtstorten 21-23-28-29-33_gen:5227524
6337777 | 23 drieëntwintigste verdieping | Model Group:NLRS_22.21_WA_Wanden dichtstorten 21-23-28-29-33_gen:5229009
6337778 | 23 drieëntwintigste verdieping | Model Group:NLRS_22.21_WA_Wanden dichtstorten 21-23-28-29-33_gen:5229009
6337779 | 23 drieëntwintigste verdieping | Model Group:NLRS_22.21_WA_Wanden dichtstorten 21-23-28-29-33_gen:5229009
6337780 | 23 drieëntwintigste verdieping | Model Group:NLRS_22.21_WA_Wanden dichtstorten 21-23-28-29-33_gen:5229009
6337781 | 23 drieëntwintigste verdieping | Model Group:NLRS_22.21_WA_Wanden dichtstorten 21-23-28-29-33_gen:5229009
6337782 | 23 drieëntwintigste verdieping | Model Group:NLRS_22.21_WA_Wanden dichtstorten 21-23-28-29-33_gen:5229009
6337786 | 28 achtentwintigste verdieping | Model Group:NLRS_22.21_WA_Wanden dichtstorten 21-23-28-29-33_gen:5229097
6337787 | 28 achtentwintigste verdieping | Model Group:NLRS_22.21_WA_Wanden dichtstorten 21-23-28-29-33_gen:5229097
6337788 | 28 achtentwintigste verdieping | Model Group:NLRS_22.21_WA_Wanden dichtstorten 21-23-28-29-33_gen:5229097
6337789 | 28 achtentwintigste verdieping | Model Group:NLRS_22.21_WA_Wanden dichtstorten 21-23-28-29-33_gen:5229097
6337790 | 28 achtentwintigste verdieping | Model Group:NLRS_22.21_WA_Wanden dichtstorten 21-23-28-29-33_gen:5229097
6337791 | 28 achtentwintigste verdieping | Model Group:NLRS_22.21_WA_Wanden dichtstorten 21-23-28-29-33_gen:5229097
6337795 | 29 negenentwintigste verdieping | Model Group:NLRS_22.21_WA_Wanden dichtstorten 21-23-28-29-33_gen:5229191
6337796 | 29 negenentwintigste verdieping | Model Group:NLRS_22.21_WA_Wanden dichtstorten 21-23-28-29-33_gen:5229191
6337797 | 29 negenentwintigste verdieping | Model Group:NLRS_22.21_WA_Wanden dichtstorten 21-23-28-29-33_gen:5229191
6337798 | 29 negenentwintigste verdieping | Model Group:NLRS_22.21_WA_Wanden dichtstorten 21-23-28-29-33_gen:5229191
6337799 | 29 negenentwintigste verdieping | Model Group:NLRS_22.21_WA_Wanden dichtstorten 21-23-28-29-33_gen:5229191
6337800 | 29 negenentwintigste verdieping | Model Group:NLRS_22.21_WA_Wanden dichtstorten 21-23-28-29-33_gen:5229191
6337804 | 33 drieëndertigste verdieping | Model Group:NLRS_22.21_WA_Wanden dichtstorten 21-23-28-29-33_gen:5229282
6337805 | 33 drieëndertigste verdieping | Model Group:NLRS_22.21_WA_Wanden dichtstorten 21-23-28-29-33_gen:5229282
6337806 | 33 drieëndertigste verdieping | Model Group:NLRS_22.21_WA_Wanden dichtstorten 21-23-28-29-33_gen:5229282
6337807 | 33 drieëndertigste verdieping | Model Group:NLRS_22.21_WA_Wanden dichtstorten 21-23-28-29-33_gen:5229282
6337808 | 33 drieëndertigste verdieping | Model Group:NLRS_22.21_WA_Wanden dichtstorten 21-23-28-29-33_gen:5229282
6337809 | 33 drieëndertigste verdieping | Model Group:NLRS_22.21_WA_Wanden dichtstorten 21-23-28-29-33_gen:5229282
6340491 | 22 tweeëntwintigste verdieping | Model Group:NLRS_22.21_WA_Wanden dichtstorten 22_gen:5228278
6340596 | 22 tweeëntwintigste verdieping | Model Group:NLRS_22.21_WA_Wanden dichtstorten 22_gen:5228278
6340604 | 22 tweeëntwintigste verdieping | Model Group:NLRS_22.21_WA_Wanden dichtstorten 22_gen:5228278
6340614 | 22 tweeëntwintigste verdieping | Model Group:NLRS_22.21_WA_Wanden dichtstorten 22_gen:5228278
6341101 | 31 eenendertigste verdieping | Model Group:NLRS_22.21_WA_Wanden dichtstorten 22_gen:5228628
6341103 | 31 eenendertigste verdieping | Model Group:NLRS_22.21_WA_Wanden dichtstorten 22_gen:5228628
6341104 | 31 eenendertigste verdieping | Model Group:NLRS_22.21_WA_Wanden dichtstorten 22_gen:5228628
6341105 | 31 eenendertigste verdieping | Model Group:NLRS_22.21_WA_Wanden dichtstorten 22_gen:5228628
6341108 | 32 tweeëndertigste verdieping | Model Group:NLRS_22.21_WA_Wanden dichtstorten 22_gen:5228694
6341110 | 32 tweeëndertigste verdieping | Model Group:NLRS_22.21_WA_Wanden dichtstorten 22_gen:5228694
6341111 | 32 tweeëndertigste verdieping | Model Group:NLRS_22.21_WA_Wanden dichtstorten 22_gen:5228694
6341112 | 32 tweeëndertigste verdieping | Model Group:NLRS_22.21_WA_Wanden dichtstorten 22_gen:5228694
6341141 | 24 vierentwintigste verdieping | Model Group:NLRS_22.21_WA_Wanden dichtstorten 24-34_gen:5229726
6341286 | 24 vierentwintigste verdieping | Model Group:NLRS_22.21_WA_Wanden dichtstorten 24-34_gen:5229726
6341489 | 34 vierendertigste verdieping | Model Group:NLRS_22.21_WA_Wanden dichtstorten 24-34_gen:5229679
6341490 | 34 vierendertigste verdieping | Model Group:NLRS_22.21_WA_Wanden dichtstorten 24-34_gen:5229679
6341542 | 26 zesentwintigste verdieping | Model Group:NLRS_22.21_WA_Wanden dichtstorten 26-27-36--39_gen:5230594
6341739 | 26 zesentwintigste verdieping | Model Group:NLRS_22.21_WA_Wanden dichtstorten 26-27-36--39_gen:5230594
6341761 | 26 zesentwintigste verdieping | Model Group:NLRS_22.21_WA_Wanden dichtstorten 26-27-36--39_gen:5230594
6341795 | 26 zesentwintigste verdieping | Model Group:NLRS_22.21_WA_Wanden dichtstorten 26-27-36--39_gen:5230594
6342297 | 27 zevenentwintigste verdieping | Model Group:NLRS_22.21_WA_Wanden dichtstorten 26-27-36--39_gen:5231127
6342300 | 27 zevenentwintigste verdieping | Model Group:NLRS_22.21_WA_Wanden dichtstorten 26-27-36--39_gen:5231127
6342301 | 27 zevenentwintigste verdieping | Model Group:NLRS_22.21_WA_Wanden dichtstorten 26-27-36--39_gen:5231127
6342302 | 27 zevenentwintigste verdieping | Model Group:NLRS_22.21_WA_Wanden dichtstorten 26-27-36--39_gen:5231127
6342305 | 38 achtendertigste verdieping | Model Group:NLRS_22.21_WA_Wanden dichtstorten 26-27-36--39_gen:5231232
6342308 | 38 achtendertigste verdieping | Model Group:NLRS_22.21_WA_Wanden dichtstorten 26-27-36--39_gen:5231232
6342309 | 38 achtendertigste verdieping | Model Group:NLRS_22.21_WA_Wanden dichtstorten 26-27-36--39_gen:5231232
6342310 | 38 achtendertigste verdieping | Model Group:NLRS_22.21_WA_Wanden dichtstorten 26-27-36--39_gen:5231232
6342313 | 39 negenendertigste verdieping | Model Group:NLRS_22.21_WA_Wanden dichtstorten 26-27-36--39_gen:5231250
6342316 | 39 negenendertigste verdieping | Model Group:NLRS_22.21_WA_Wanden dichtstorten 26-27-36--39_gen:5231250
6342317 | 39 negenendertigste verdieping | Model Group:NLRS_22.21_WA_Wanden dichtstorten 26-27-36--39_gen:5231250
6342318 | 39 negenendertigste verdieping | Model Group:NLRS_22.21_WA_Wanden dichtstorten 26-27-36--39_gen:5231250
6342321 | 36 zesendertigste verdieping | Model Group:NLRS_22.21_WA_Wanden dichtstorten 26-27-36--39_gen:5231989
6342324 | 36 zesendertigste verdieping | Model Group:NLRS_22.21_WA_Wanden dichtstorten 26-27-36--39_gen:5231989
6342325 | 36 zesendertigste verdieping | Model Group:NLRS_22.21_WA_Wanden dichtstorten 26-27-36--39_gen:5231989
6342326 | 36 zesendertigste verdieping | Model Group:NLRS_22.21_WA_Wanden dichtstorten 26-27-36--39_gen:5231989
6342329 | 37 zevenendertigste verdieping | Model Group:NLRS_22.21_WA_Wanden dichtstorten 26-27-36--39_gen:5232148
6342332 | 37 zevenendertigste verdieping | Model Group:NLRS_22.21_WA_Wanden dichtstorten 26-27-36--39_gen:5232148
6342333 | 37 zevenendertigste verdieping | Model Group:NLRS_22.21_WA_Wanden dichtstorten 26-27-36--39_gen:5232148
6342334 | 37 zevenendertigste verdieping | Model Group:NLRS_22.21_WA_Wanden dichtstorten 26-27-36--39_gen:5232148
6342686 | 41 eenenveertigste verdieping | Model Group:NLRS_22.21_WA_Wanden dichtstorten 41_gen:5232392
6342785 | 41 eenenveertigste verdieping | Model Group:NLRS_22.21_WA_Wanden dichtstorten 41_gen:5232392
6342791 | 41 eenenveertigste verdieping | Model Group:NLRS_22.21_WA_Wanden dichtstorten 41_gen:5232392
6342799 | 41 eenenveertigste verdieping | Model Group:NLRS_22.21_WA_Wanden dichtstorten 41_gen:5232392
6343205 | 42 tweeënveertigste verdieping | Model Group:NLRS_22.21_WA_Wanden dichtstorten 42-46-49_gen:5232880
6343206 | 42 tweeënveertigste verdieping | Model Group:NLRS_22.21_WA_Wanden dichtstorten 42-46-49_gen:5232880
6343329 | 42 tweeënveertigste verdieping | Model Group:NLRS_22.21_WA_Wanden dichtstorten 42-46-49_gen:5232880
6343337 | 42 tweeënveertigste verdieping | Model Group:NLRS_22.21_WA_Wanden dichtstorten 42-46-49_gen:5232880
6343345 | 42 tweeënveertigste verdieping | Model Group:NLRS_22.21_WA_Wanden dichtstorten 42-46-49_gen:5232880
6343420 | 42 tweeënveertigste verdieping | Model Group:NLRS_22.21_WA_Wanden dichtstorten 42-46-49_gen:5232880
6343874 | 43 drieënveertigste verdieping | Model Group:NLRS_22.21_WA_Wanden dichtstorten 42-46-49_gen:5233690
6343875 | 43 drieënveertigste verdieping | Model Group:NLRS_22.21_WA_Wanden dichtstorten 42-46-49_gen:5233690
6343878 | 43 drieënveertigste verdieping | Model Group:NLRS_22.21_WA_Wanden dichtstorten 42-46-49_gen:5233690
6343879 | 43 drieënveertigste verdieping | Model Group:NLRS_22.21_WA_Wanden dichtstorten 42-46-49_gen:5233690
6343880 | 43 drieënveertigste verdieping | Model Group:NLRS_22.21_WA_Wanden dichtstorten 42-46-49_gen:5233690
6343881 | 43 drieënveertigste verdieping | Model Group:NLRS_22.21_WA_Wanden dichtstorten 42-46-49_gen:5233690
6343884 | 44 vierenveertigste verdieping | Model Group:NLRS_22.21_WA_Wanden dichtstorten 44_gen:5233804
6343888 | 44 vierenveertigste verdieping | Model Group:NLRS_22.21_WA_Wanden dichtstorten 44_gen:5233804
6343889 | 44 vierenveertigste verdieping | Model Group:NLRS_22.21_WA_Wanden dichtstorten 44_gen:5233804
6343890 | 44 vierenveertigste verdieping | Model Group:NLRS_22.21_WA_Wanden dichtstorten 44_gen:5233804
6343892 | 45 vijfenveertigste verdieping | Model Group:NLRS_22.21_WA_Wanden dichtstorten 42-46-49_gen:5233823
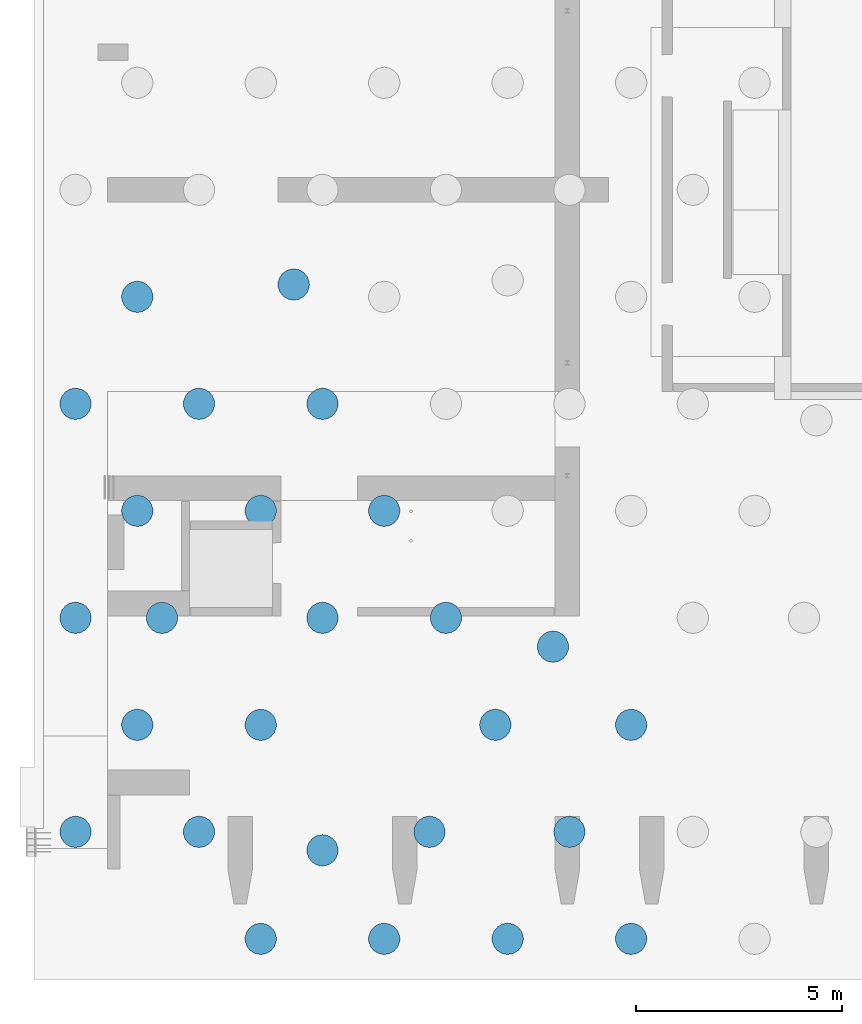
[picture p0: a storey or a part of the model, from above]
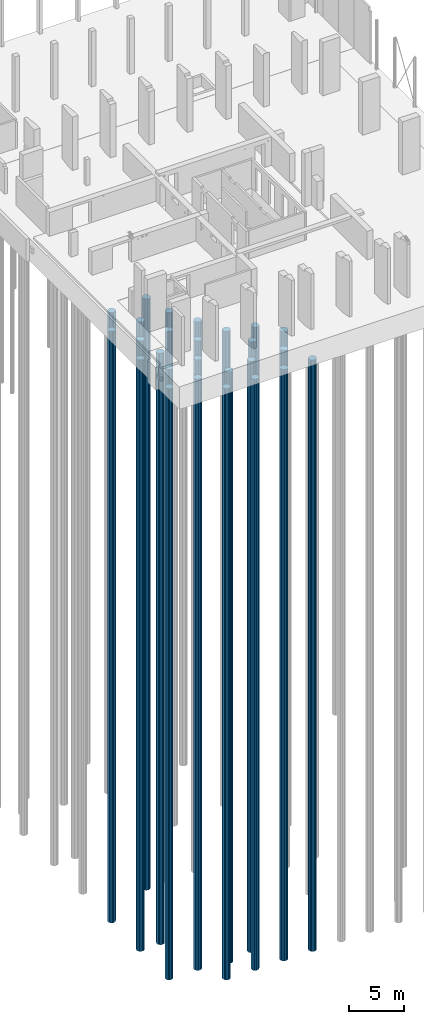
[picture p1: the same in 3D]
Properties of the parts of a building model (IFC2X3), part 18 of 21

# IfcWall: Parametric Wall:NLRS_22.21_WA_beton prefab d=500 1900x2470_gen (210)
Name (Parametric Wall:NLRS_22.21_WA_beton prefab d=500 1900x2470_gen:...) | In | Group
6343893 | 45 vijfenveertigste verdieping | Model Group:NLRS_22.21_WA_Wanden dichtstorten 42-46-49_gen:5233823
6343896 | 45 vijfenveertigste verdieping | Model Group:NLRS_22.21_WA_Wanden dichtstorten 42-46-49_gen:5233823
6343897 | 45 vijfenveertigste verdieping | Model Group:NLRS_22.21_WA_Wanden dichtstorten 42-46-49_gen:5233823
6343898 | 45 vijfenveertigste verdieping | Model Group:NLRS_22.21_WA_Wanden dichtstorten 42-46-49_gen:5233823
6343899 | 45 vijfenveertigste verdieping | Model Group:NLRS_22.21_WA_Wanden dichtstorten 42-46-49_gen:5233823
6343901 | 46 zesenveertigste verdieping | Model Group:NLRS_22.21_WA_Wanden dichtstorten 42-46-49_gen:5233842
6343902 | 46 zesenveertigste verdieping | Model Group:NLRS_22.21_WA_Wanden dichtstorten 42-46-49_gen:5233842
6343905 | 46 zesenveertigste verdieping | Model Group:NLRS_22.21_WA_Wanden dichtstorten 42-46-49_gen:5233842
6343906 | 46 zesenveertigste verdieping | Model Group:NLRS_22.21_WA_Wanden dichtstorten 42-46-49_gen:5233842
6343907 | 46 zesenveertigste verdieping | Model Group:NLRS_22.21_WA_Wanden dichtstorten 42-46-49_gen:5233842
6343908 | 46 zesenveertigste verdieping | Model Group:NLRS_22.21_WA_Wanden dichtstorten 42-46-49_gen:5233842
6343910 | 49 negenenveertigste verdieping | Model Group:NLRS_22.21_WA_Wanden dichtstorten 42-46-49_gen:5233861
6343911 | 49 negenenveertigste verdieping | Model Group:NLRS_22.21_WA_Wanden dichtstorten 42-46-49_gen:5233861
6343914 | 49 negenenveertigste verdieping | Model Group:NLRS_22.21_WA_Wanden dichtstorten 42-46-49_gen:5233861
6343915 | 49 negenenveertigste verdieping | Model Group:NLRS_22.21_WA_Wanden dichtstorten 42-46-49_gen:5233861
6343916 | 49 negenenveertigste verdieping | Model Group:NLRS_22.21_WA_Wanden dichtstorten 42-46-49_gen:5233861
6343917 | 49 negenenveertigste verdieping | Model Group:NLRS_22.21_WA_Wanden dichtstorten 42-46-49_gen:5233861
6343945 | 47 zevenenveertigste verdieping | Model Group:NLRS_22.21_WA_Wanden dichtstorten 47-48_gen:5234234
6344048 | 47 zevenenveertigste verdieping | Model Group:NLRS_22.21_WA_Wanden dichtstorten 47-48_gen:5234234
6344069 | 47 zevenenveertigste verdieping | Model Group:NLRS_22.21_WA_Wanden dichtstorten 47-48_gen:5234234
6344096 | 47 zevenenveertigste verdieping | Model Group:NLRS_22.21_WA_Wanden dichtstorten 47-48_gen:5234234
6344503 | 48 achtenveertigste verdieping | Model Group:NLRS_22.21_WA_Wanden dichtstorten 47-48_gen:5234640
6344506 | 48 achtenveertigste verdieping | Model Group:NLRS_22.21_WA_Wanden dichtstorten 47-48_gen:5234640
6344507 | 48 achtenveertigste verdieping | Model Group:NLRS_22.21_WA_Wanden dichtstorten 47-48_gen:5234640
6344508 | 48 achtenveertigste verdieping | Model Group:NLRS_22.21_WA_Wanden dichtstorten 47-48_gen:5234640
6344553 | 51 eenenvijftigste verdieping | Model Group:NLRS_22.21_WA_Wanden dichtstorten 51_gen:5235593
6344604 | 51 eenenvijftigste verdieping | Model Group:NLRS_22.21_WA_Wanden dichtstorten 51_gen:5235593
6344948 | 52 tweeënvijftigste verdieping | Model Group:NLRS_22.21_WA_Wanden dichtstorten 52_gen:5236115
6345104 | 52 tweeënvijftigste verdieping | Model Group:NLRS_22.21_WA_Wanden dichtstorten 52_gen:5236115
6345381 | 50 vijftigste verdieping | Model Group:NLRS_22.21_WA_Wanden dichtstorten 50_gen:5234960
6345419 | 50 vijftigste verdieping | Model Group:NLRS_22.21_WA_Wanden dichtstorten 50_gen:5234960
6345431 | 50 vijftigste verdieping | Model Group:NLRS_22.21_WA_Wanden dichtstorten 50_gen:5234960
6345441 | 50 vijftigste verdieping | Model Group:NLRS_22.21_WA_Wanden dichtstorten 50_gen:5234960
6346050 | 25 vijfentwintigste verdieping | Model Group:NLRS_22.21_WA_Wanden dichtstorten 25-35_gen:5230273
6346155 | 25 vijfentwintigste verdieping | Model Group:NLRS_22.21_WA_Wanden dichtstorten 25-35_gen:5230273
6346402 | 35 vijfendertigste verdieping | Model Group:NLRS_22.21_WA_Wanden dichtstorten 25-35_gen:5230458
6346404 | 35 vijfendertigste verdieping | Model Group:NLRS_22.21_WA_Wanden dichtstorten 25-35_gen:5230458

# IfcWallStandardCase: Basic Wall:NLRS_16.21_WA_beton ihwg d=250_gen, Basic Wall:NLRS_16.21_WA_beton ihwg d=250_gen:4212743
In: 00 begane grond
Type - PredefinedType: STANDARD; Material: NLRS_f2_beton ihwg 250 mm
Classification: 16.21 funderingsconstructies - keerwanden, grondkerende wanden (Uniformat)
Pset_WallCommon - IsExternal: yes; LoadBearing: yes; ExtendToStructure: no; Reference: NLRS_16.21_WA_beton ihwg d=250_gen; ThermalTransmittance: 4.184 kg/K/s3

# IfcWallStandardCase: Basic Wall:NLRS_16.21_WA_beton ihwg d=300_gen, Basic Wall:NLRS_16.21_WA_beton ihwg d=300_gen:4212621
In: 00 begane grond
Type - PredefinedType: STANDARD; Material: NLRS_f2_beton ihwg 300 mm
Classification: 16.21 funderingsconstructies - keerwanden, grondkerende wanden (Uniformat)
Pset_WallCommon - IsExternal: yes; LoadBearing: yes; ExtendToStructure: no; Reference: NLRS_16.21_WA_beton ihwg d=300_gen; ThermalTransmittance: 3.48667 kg/K/s3

# IfcWallStandardCase: Basic Wall:NLRS_16.21_WA_beton ihwg d=350_gen, Basic Wall:NLRS_16.21_WA_beton ihwg d=350_gen:4212554
In: 00 begane grond
Classification: 16.21 funderingsconstructies - keerwanden, grondkerende wanden (Uniformat); Material: NLRS_f2_beton ihwg 350 mm
Pset_WallCommon - IsExternal: yes; LoadBearing: yes; ExtendToStructure: no; Reference: NLRS_16.21_WA_beton ihwg d=350_gen; ThermalTransmittance: 2.98857 kg/K/s3

# IfcWallStandardCase: Basic Wall:NLRS_16.21_WA_beton ihwg d=400_gen (5)
In: 00 begane grond
Type - PredefinedType: STANDARD; Material: NLRS_f2_beton ihwg 400 mm
Classification: 16.21 funderingsconstructies - keerwanden, grondkerende wanden (Uniformat)
Pset_WallCommon - IsExternal: yes; LoadBearing: yes; Reference: NLRS_16.21_WA_beton ihwg d=400_gen; ExtendToStructure: no; ThermalTransmittance: 2.615 kg/K/s3
Name (Basic Wall:NLRS_16.21_WA_beton ihwg d=400_gen:...)
4115013
4115170
4115313
4115446
4115507

# IfcWallStandardCase: Basic Wall:NLRS_21.10_WA_isokorf d=120_gen (24)
In: 05 vijfde verdieping
Type - PredefinedType: STANDARD; Material: NLRS_a_isolatie 120 mm
Classification: 21.10 buitenwanden - niet constructief, algemeen (verzamelniveau) (Uniformat)
Pset_WallCommon - IsExternal: yes; LoadBearing: yes; ExtendToStructure: no; Reference: NLRS_21.10_WA_isokorf d=120_gen
Name (Basic Wall:NLRS_21.10_WA_isokorf d=120_gen:...)
4945721
4945795
4945829
4945910
4946010
4946085
4946142
4946332
4946376
4946453
4946491
4946694
4946746
4946819
7240004
7240086
12505529
12505539
12506125
12506361
12506723
12506811
12506929
12506999

# IfcWallStandardCase: Basic Wall:NLRS_21.10_WA_isokorf d=80_gen (28)
Type - PredefinedType: STANDARD; Material: NLRS_a_isolatie 80 mm
Classification: 21.10 buitenwanden - niet constructief, algemeen (verzamelniveau) (Uniformat)
Pset_WallCommon - IsExternal: yes; LoadBearing: yes; ExtendToStructure: no; Reference: NLRS_21.10_WA_isokorf d=80_gen
Name (Basic Wall:NLRS_21.10_WA_isokorf d=80_gen:...) | In
11882864 | 53 drieënvijftigste verdieping
11900465 | 53 drieënvijftigste verdieping
12941287 | 53 drieënvijftigste verdieping
12941742 | 53 drieënvijftigste verdieping
12942002 | 55 vijfenvijftigste verdieping
12942004 | 55 vijfenvijftigste verdieping
12942006 | 55 vijfenvijftigste verdieping
12942008 | 55 vijfenvijftigste verdieping
12942011 | 56 zesenvijftigste verdieping
12942013 | 56 zesenvijftigste verdieping
12942015 | 56 zesenvijftigste verdieping
12942017 | 56 zesenvijftigste verdieping
14317204 | 55 vijfenvijftigste verdieping
14317361 | 55 vijfenvijftigste verdieping
14317574 | 55 vijfenvijftigste verdieping
14317661 | 55 vijfenvijftigste verdieping
14318172 | 55 vijfenvijftigste verdieping
14318236 | 55 vijfenvijftigste verdieping
14318466 | 55 vijfenvijftigste verdieping
14318573 | 55 vijfenvijftigste verdieping
14319144 | 56 zesenvijftigste verdieping
14319239 | 56 zesenvijftigste verdieping
14319366 | 56 zesenvijftigste verdieping
14319449 | 56 zesenvijftigste verdieping
14319580 | 56 zesenvijftigste verdieping
14319657 | 56 zesenvijftigste verdieping
14319829 | 56 zesenvijftigste verdieping
14319888 | 56 zesenvijftigste verdieping

# IfcWallStandardCase: Basic Wall:NLRS_21.21_WA_beton ihwg d=1000_gen (2)
Type - PredefinedType: STANDARD; Material: NLRS_f2_beton ihwg 1000 mm
Classification: 21.21 buitenwanden - constructief, massieve wanden (Uniformat)
Pset_WallCommon - IsExternal: yes; LoadBearing: yes; ExtendToStructure: no; Reference: NLRS_21.21_WA_beton ihwg d=1000_gen; ThermalTransmittance: 1.046 kg/K/s3
Name (Basic Wall:NLRS_21.21_WA_beton ihwg d=1000_gen:...) | In
4832743 | 03 derde verdieping
4941826 | 04 vierde verdieping

# IfcWallStandardCase: Basic Wall:NLRS_21.21_WA_beton ihwg d=300_gen (180)
Type - PredefinedType: STANDARD; Material: NLRS_f2_beton ihwg 300 mm
Classification: 21.21 buitenwanden - constructief, massieve wanden (Uniformat)
Pset_WallCommon - IsExternal: yes; LoadBearing: yes; ExtendToStructure: no; Reference: NLRS_21.21_WA_beton ihwg d=300_gen; ThermalTransmittance: 3.48667 kg/K/s3
Name (Basic Wall:NLRS_21.21_WA_beton ihwg d=300_gen:...) | In | Group
4446131 | 02 tweede verdieping
4446409 | 02 tweede verdieping
4446486 | 02 tweede verdieping
7359271 | 00 begane grond
12693147 | 09 negende verdieping | Model Group:NLRS_21.21_WA_wand 002b d=300_gen:5667323
12693295 | 13 dertiende verdieping | Model Group:NLRS_21.21_WA_wand 002b d=300_gen:4730656
12693299 | 13 dertiende verdieping | Model Group:NLRS_21.21_WA_wand 002b d=300_gen:5509164
12693303 | 09 negende verdieping | Model Group:NLRS_21.21_WA_wand 002b d=300_gen:5667625
12693307 | 11 elfde verdieping | Model Group:NLRS_21.21_WA_wand 002b d=300_gen:6861559
12693311 | 11 elfde verdieping | Model Group:NLRS_21.21_WA_wand 002b d=300_gen:6861785
12693646 | 10 tiende verdieping | Model Group:NLRS_21.21_WA_wand 002a d=300_gen:6859044
12693735 | 12 twaalfde verdieping | Model Group:NLRS_21.21_WA_wand 002a d=300_gen:4738236
12693739 | 12 twaalfde verdieping | Model Group:NLRS_21.21_WA_wand 002a d=300_gen:4738243
12693743 | 14 veertiende verdieping | Model Group:NLRS_21.21_WA_wand 002a d=300_gen:4738694
12693747 | 14 veertiende verdieping | Model Group:NLRS_21.21_WA_wand 002a d=300_gen:4738701
12693751 | 10 tiende verdieping | Model Group:NLRS_21.21_WA_wand 002a d=300_gen:6859037
12694057 | 15 vijftiende verdieping | Model Group:NLRS_21.21_WA_wand 002 d=300_gen:4731114
12696484 | 21 eenentwintigste verdieping | Model Group:NLRS_21.21_WA_wand 002 d=300_gen:4695026
12696488 | 21 eenentwintigste verdieping | Model Group:NLRS_21.21_WA_wand 002 d=300_gen:4695033
12696492 | 17 zeventiende verdieping | Model Group:NLRS_21.21_WA_wand 002 d=300_gen:4731572
12696496 | 19 negentiende verdieping | Model Group:NLRS_21.21_WA_wand 002 d=300_gen:4732030
12696500 | 16 zestiende verdieping | Model Group:NLRS_21.21_WA_wand 002 d=300_gen:4739152
12696504 | 16 zestiende verdieping | Model Group:NLRS_21.21_WA_wand 002 d=300_gen:4739159
12696508 | 18 achttiende verdieping | Model Group:NLRS_21.21_WA_wand 002 d=300_gen:4739610
12696512 | 18 achttiende verdieping | Model Group:NLRS_21.21_WA_wand 002 d=300_gen:4739617
12696516 | 20 twintigste verdieping | Model Group:NLRS_21.21_WA_wand 002 d=300_gen:4740068
12696520 | 20 twintigste verdieping | Model Group:NLRS_21.21_WA_wand 002 d=300_gen:4740075
12696524 | 24 vierentwintigste verdieping | Model Group:NLRS_21.21_WA_wand 002 d=300_gen:4746667
12696528 | 24 vierentwintigste verdieping | Model Group:NLRS_21.21_WA_wand 002 d=300_gen:4746674
12696532 | 25 vijfentwintigste verdieping | Model Group:NLRS_21.21_WA_wand 002 d=300_gen:4747099
12696536 | 25 vijfentwintigste verdieping | Model Group:NLRS_21.21_WA_wand 002 d=300_gen:4747106
12696540 | 26 zesentwintigste verdieping | Model Group:NLRS_21.21_WA_wand 002 d=300_gen:4747531
12696544 | 26 zesentwintigste verdieping | Model Group:NLRS_21.21_WA_wand 002 d=300_gen:4747538
12696548 | 27 zevenentwintigste verdieping | Model Group:NLRS_21.21_WA_wand 002 d=300_gen:4747963
12696552 | 27 zevenentwintigste verdieping | Model Group:NLRS_21.21_WA_wand 002 d=300_gen:4747970
12696556 | 28 achtentwintigste verdieping | Model Group:NLRS_21.21_WA_wand 002 d=300_gen:4748395
12696560 | 28 achtentwintigste verdieping | Model Group:NLRS_21.21_WA_wand 002 d=300_gen:4748402
12696564 | 29 negenentwintigste verdieping | Model Group:NLRS_21.21_WA_wand 002 d=300_gen:4748827
12696568 | 29 negenentwintigste verdieping | Model Group:NLRS_21.21_WA_wand 002 d=300_gen:4748834
12696572 | 30 dertigste verdieping | Model Group:NLRS_21.21_WA_wand 002 d=300_gen:4749259
12696576 | 30 dertigste verdieping | Model Group:NLRS_21.21_WA_wand 002 d=300_gen:4749266
12696580 | 31 eenendertigste verdieping | Model Group:NLRS_21.21_WA_wand 002 d=300_gen:4749691
12696584 | 31 eenendertigste verdieping | Model Group:NLRS_21.21_WA_wand 002 d=300_gen:4749698
12696588 | 32 tweeëndertigste verdieping | Model Group:NLRS_21.21_WA_wand 002 d=300_gen:4750123
12696592 | 32 tweeëndertigste verdieping | Model Group:NLRS_21.21_WA_wand 002 d=300_gen:4750130
12696596 | 33 drieëndertigste verdieping | Model Group:NLRS_21.21_WA_wand 002 d=300_gen:4750555
12696600 | 33 drieëndertigste verdieping | Model Group:NLRS_21.21_WA_wand 002 d=300_gen:4750562
12696604 | 34 vierendertigste verdieping | Model Group:NLRS_21.21_WA_wand 002 d=300_gen:4750987
12696608 | 34 vierendertigste verdieping | Model Group:NLRS_21.21_WA_wand 002 d=300_gen:4750994
12696612 | 35 vijfendertigste verdieping | Model Group:NLRS_21.21_WA_wand 002 d=300_gen:4751419
12696616 | 35 vijfendertigste verdieping | Model Group:NLRS_21.21_WA_wand 002 d=300_gen:4751426
12696620 | 36 zesendertigste verdieping | Model Group:NLRS_21.21_WA_wand 002 d=300_gen:4751851
12696624 | 36 zesendertigste verdieping | Model Group:NLRS_21.21_WA_wand 002 d=300_gen:4751858
12696628 | 37 zevenendertigste verdieping | Model Group:NLRS_21.21_WA_wand 002 d=300_gen:4752283
12696632 | 37 zevenendertigste verdieping | Model Group:NLRS_21.21_WA_wand 002 d=300_gen:4752290
12696636 | 38 achtendertigste verdieping | Model Group:NLRS_21.21_WA_wand 002 d=300_gen:4752715
12696640 | 38 achtendertigste verdieping | Model Group:NLRS_21.21_WA_wand 002 d=300_gen:4752722
12696644 | 39 negenendertigste verdieping | Model Group:NLRS_21.21_WA_wand 002 d=300_gen:4753147
12696648 | 39 negenendertigste verdieping | Model Group:NLRS_21.21_WA_wand 002 d=300_gen:4753154
12696652 | 40 veertigste verdieping | Model Group:NLRS_21.21_WA_wand 002 d=300_gen:4753579
12696656 | 40 veertigste verdieping | Model Group:NLRS_21.21_WA_wand 002 d=300_gen:4753586
12696660 | 22 tweeëntwintigste verdieping | Model Group:NLRS_21.21_WA_wand 002 d=300_gen:4778047
12696664 | 22 tweeëntwintigste verdieping | Model Group:NLRS_21.21_WA_wand 002 d=300_gen:4778054
12696668 | 23 drieëntwintigste verdieping | Model Group:NLRS_21.21_WA_wand 002 d=300_gen:4779630
12696672 | 23 drieëntwintigste verdieping | Model Group:NLRS_21.21_WA_wand 002 d=300_gen:4779637
12696676 | 41 eenenveertigste verdieping | Model Group:NLRS_21.21_WA_wand 002 d=300_gen:4783747
12696680 | 41 eenenveertigste verdieping | Model Group:NLRS_21.21_WA_wand 002 d=300_gen:4783754
12696684 | 43 drieënveertigste verdieping | Model Group:NLRS_21.21_WA_wand 002 d=300_gen:4788793
12696688 | 43 drieënveertigste verdieping | Model Group:NLRS_21.21_WA_wand 002 d=300_gen:4788800
12696692 | 44 vierenveertigste verdieping | Model Group:NLRS_21.21_WA_wand 002 d=300_gen:4789225
12696696 | 44 vierenveertigste verdieping | Model Group:NLRS_21.21_WA_wand 002 d=300_gen:4789232
12696700 | 45 vijfenveertigste verdieping | Model Group:NLRS_21.21_WA_wand 002 d=300_gen:4789657
12696704 | 45 vijfenveertigste verdieping | Model Group:NLRS_21.21_WA_wand 002 d=300_gen:4789664
12696708 | 46 zesenveertigste verdieping | Model Group:NLRS_21.21_WA_wand 002 d=300_gen:4790089
12696712 | 46 zesenveertigste verdieping | Model Group:NLRS_21.21_WA_wand 002 d=300_gen:4790096
12696716 | 47 zevenenveertigste verdieping | Model Group:NLRS_21.21_WA_wand 002 d=300_gen:4790521
12696720 | 47 zevenenveertigste verdieping | Model Group:NLRS_21.21_WA_wand 002 d=300_gen:4790528
12696724 | 48 achtenveertigste verdieping | Model Group:NLRS_21.21_WA_wand 002 d=300_gen:4790953
12696728 | 48 achtenveertigste verdieping | Model Group:NLRS_21.21_WA_wand 002 d=300_gen:4790960
12696732 | 49 negenenveertigste verdieping | Model Group:NLRS_21.21_WA_wand 002 d=300_gen:4791385
12696736 | 49 negenenveertigste verdieping | Model Group:NLRS_21.21_WA_wand 002 d=300_gen:4791392
12696740 | 50 vijftigste verdieping | Model Group:NLRS_21.21_WA_wand 002 d=300_gen:4791817
12696744 | 50 vijftigste verdieping | Model Group:NLRS_21.21_WA_wand 002 d=300_gen:4791824
12696748 | 42 tweeënveertigste verdieping | Model Group:NLRS_21.21_WA_wand 002 d=300_gen:4803266
12696752 | 42 tweeënveertigste verdieping | Model Group:NLRS_21.21_WA_wand 002 d=300_gen:4803273
12696756 | 51 eenenvijftigste verdieping | Model Group:NLRS_21.21_WA_wand 002 d=300_gen:4980000
12696760 | 51 eenenvijftigste verdieping | Model Group:NLRS_21.21_WA_wand 002 d=300_gen:4980007
12696764 | 15 vijftiende verdieping | Model Group:NLRS_21.21_WA_wand 002 d=300_gen:5509182
12696768 | 17 zeventiende verdieping | Model Group:NLRS_21.21_WA_wand 002 d=300_gen:5509200
12696772 | 19 negentiende verdieping | Model Group:NLRS_21.21_WA_wand 002 d=300_gen:5509218
12697309 | 52 tweeënvijftigste verdieping | Model Group:NLRS_21.21_WA_wand 002c d=300_gen:4981779
12697466 | 52 tweeënvijftigste verdieping | Model Group:NLRS_21.21_WA_wand 002c d=300_gen:4981772
12701548 | 09 negende verdieping | Model Group:NLRS_21.21_WA_wand 004b d=300_gen:5667316
12701609 | 13 dertiende verdieping | Model Group:NLRS_21.21_WA_wand 004b d=300_gen:4730639
12701613 | 13 dertiende verdieping | Model Group:NLRS_21.21_WA_wand 004b d=300_gen:4730648
12701617 | 09 negende verdieping | Model Group:NLRS_21.21_WA_wand 004b d=300_gen:5667307
12701621 | 11 elfde verdieping | Model Group:NLRS_21.21_WA_wand 004b d=300_gen:6861543
12701625 | 11 elfde verdieping | Model Group:NLRS_21.21_WA_wand 004b d=300_gen:6861552
12702045 | 10 tiende verdieping | Model Group:NLRS_21.21_WA_wand 004a d=300_gen:6859036
12702104 | 12 twaalfde verdieping | Model Group:NLRS_21.21_WA_wand 004a d=300_gen:4738226
12702108 | 12 twaalfde verdieping | Model Group:NLRS_21.21_WA_wand 004a d=300_gen:4738235
12702112 | 14 veertiende verdieping | Model Group:NLRS_21.21_WA_wand 004a d=300_gen:4738684
12702116 | 14 veertiende verdieping | Model Group:NLRS_21.21_WA_wand 004a d=300_gen:4738693
12702120 | 10 tiende verdieping | Model Group:NLRS_21.21_WA_wand 004a d=300_gen:6859027
12702388 | 15 vijftiende verdieping | Model Group:NLRS_21.21_WA_wand 004 d=300_gen:4731106
12703753 | 21 eenentwintigste verdieping | Model Group:NLRS_21.21_WA_wand 004 d=300_gen:4695016
12703757 | 21 eenentwintigste verdieping | Model Group:NLRS_21.21_WA_wand 004 d=300_gen:4695025
12703761 | 15 vijftiende verdieping | Model Group:NLRS_21.21_WA_wand 004 d=300_gen:4731097
12703765 | 17 zeventiende verdieping | Model Group:NLRS_21.21_WA_wand 004 d=300_gen:4731555
12703769 | 17 zeventiende verdieping | Model Group:NLRS_21.21_WA_wand 004 d=300_gen:4731564
12703773 | 19 negentiende verdieping | Model Group:NLRS_21.21_WA_wand 004 d=300_gen:4732013
12703777 | 19 negentiende verdieping | Model Group:NLRS_21.21_WA_wand 004 d=300_gen:4732022
12703781 | 16 zestiende verdieping | Model Group:NLRS_21.21_WA_wand 004 d=300_gen:4739142
12703785 | 16 zestiende verdieping | Model Group:NLRS_21.21_WA_wand 004 d=300_gen:4739151
12703789 | 18 achttiende verdieping | Model Group:NLRS_21.21_WA_wand 004 d=300_gen:4739600
12703793 | 18 achttiende verdieping | Model Group:NLRS_21.21_WA_wand 004 d=300_gen:4739609
12703797 | 20 twintigste verdieping | Model Group:NLRS_21.21_WA_wand 004 d=300_gen:4740058
12703801 | 20 twintigste verdieping | Model Group:NLRS_21.21_WA_wand 004 d=300_gen:4740067
12703805 | 24 vierentwintigste verdieping | Model Group:NLRS_21.21_WA_wand 004 d=300_gen:4746657
12703809 | 24 vierentwintigste verdieping | Model Group:NLRS_21.21_WA_wand 004 d=300_gen:4746666
12703813 | 25 vijfentwintigste verdieping | Model Group:NLRS_21.21_WA_wand 004 d=300_gen:4747089
12703817 | 25 vijfentwintigste verdieping | Model Group:NLRS_21.21_WA_wand 004 d=300_gen:4747098
12703821 | 26 zesentwintigste verdieping | Model Group:NLRS_21.21_WA_wand 004 d=300_gen:4747521
12703825 | 26 zesentwintigste verdieping | Model Group:NLRS_21.21_WA_wand 004 d=300_gen:4747530
12703829 | 27 zevenentwintigste verdieping | Model Group:NLRS_21.21_WA_wand 004 d=300_gen:4747953
12703833 | 27 zevenentwintigste verdieping | Model Group:NLRS_21.21_WA_wand 004 d=300_gen:4747962
12703837 | 28 achtentwintigste verdieping | Model Group:NLRS_21.21_WA_wand 004 d=300_gen:4748385
12703841 | 28 achtentwintigste verdieping | Model Group:NLRS_21.21_WA_wand 004 d=300_gen:4748394
12703845 | 29 negenentwintigste verdieping | Model Group:NLRS_21.21_WA_wand 004 d=300_gen:4748817
12703849 | 29 negenentwintigste verdieping | Model Group:NLRS_21.21_WA_wand 004 d=300_gen:4748826
12703853 | 30 dertigste verdieping | Model Group:NLRS_21.21_WA_wand 004 d=300_gen:4749249
12703857 | 30 dertigste verdieping | Model Group:NLRS_21.21_WA_wand 004 d=300_gen:4749258
12703861 | 31 eenendertigste verdieping | Model Group:NLRS_21.21_WA_wand 004 d=300_gen:4749681
12703865 | 31 eenendertigste verdieping | Model Group:NLRS_21.21_WA_wand 004 d=300_gen:4749690
12703869 | 32 tweeëndertigste verdieping | Model Group:NLRS_21.21_WA_wand 004 d=300_gen:4750113
12703873 | 32 tweeëndertigste verdieping | Model Group:NLRS_21.21_WA_wand 004 d=300_gen:4750122
12703877 | 33 drieëndertigste verdieping | Model Group:NLRS_21.21_WA_wand 004 d=300_gen:4750545
12703881 | 33 drieëndertigste verdieping | Model Group:NLRS_21.21_WA_wand 004 d=300_gen:4750554
12703885 | 34 vierendertigste verdieping | Model Group:NLRS_21.21_WA_wand 004 d=300_gen:4750977
12703889 | 34 vierendertigste verdieping | Model Group:NLRS_21.21_WA_wand 004 d=300_gen:4750986
12703893 | 35 vijfendertigste verdieping | Model Group:NLRS_21.21_WA_wand 004 d=300_gen:4751409
12703897 | 35 vijfendertigste verdieping | Model Group:NLRS_21.21_WA_wand 004 d=300_gen:4751418
12703901 | 36 zesendertigste verdieping | Model Group:NLRS_21.21_WA_wand 004 d=300_gen:4751841
12703905 | 36 zesendertigste verdieping | Model Group:NLRS_21.21_WA_wand 004 d=300_gen:4751850
12703909 | 37 zevenendertigste verdieping | Model Group:NLRS_21.21_WA_wand 004 d=300_gen:4752273
12703913 | 37 zevenendertigste verdieping | Model Group:NLRS_21.21_WA_wand 004 d=300_gen:4752282
12703917 | 38 achtendertigste verdieping | Model Group:NLRS_21.21_WA_wand 004 d=300_gen:4752705
12703921 | 38 achtendertigste verdieping | Model Group:NLRS_21.21_WA_wand 004 d=300_gen:4752714
12703925 | 39 negenendertigste verdieping | Model Group:NLRS_21.21_WA_wand 004 d=300_gen:4753137
12703929 | 39 negenendertigste verdieping | Model Group:NLRS_21.21_WA_wand 004 d=300_gen:4753146
12703933 | 40 veertigste verdieping | Model Group:NLRS_21.21_WA_wand 004 d=300_gen:4753569
12703937 | 40 veertigste verdieping | Model Group:NLRS_21.21_WA_wand 004 d=300_gen:4753578
12703941 | 22 tweeëntwintigste verdieping | Model Group:NLRS_21.21_WA_wand 004 d=300_gen:4778037
12703945 | 22 tweeëntwintigste verdieping | Model Group:NLRS_21.21_WA_wand 004 d=300_gen:4778046
12703949 | 23 drieëntwintigste verdieping | Model Group:NLRS_21.21_WA_wand 004 d=300_gen:4779620
12703953 | 23 drieëntwintigste verdieping | Model Group:NLRS_21.21_WA_wand 004 d=300_gen:4779629
12703957 | 41 eenenveertigste verdieping | Model Group:NLRS_21.21_WA_wand 004 d=300_gen:4783737
12703961 | 41 eenenveertigste verdieping | Model Group:NLRS_21.21_WA_wand 004 d=300_gen:4783746
12703965 | 43 drieënveertigste verdieping | Model Group:NLRS_21.21_WA_wand 004 d=300_gen:4788783
12703969 | 43 drieënveertigste verdieping | Model Group:NLRS_21.21_WA_wand 004 d=300_gen:4788792
12703973 | 44 vierenveertigste verdieping | Model Group:NLRS_21.21_WA_wand 004 d=300_gen:4789215
12703977 | 44 vierenveertigste verdieping | Model Group:NLRS_21.21_WA_wand 004 d=300_gen:4789224
12703981 | 45 vijfenveertigste verdieping | Model Group:NLRS_21.21_WA_wand 004 d=300_gen:4789647
12703985 | 45 vijfenveertigste verdieping | Model Group:NLRS_21.21_WA_wand 004 d=300_gen:4789656
12703989 | 46 zesenveertigste verdieping | Model Group:NLRS_21.21_WA_wand 004 d=300_gen:4790079
12703993 | 46 zesenveertigste verdieping | Model Group:NLRS_21.21_WA_wand 004 d=300_gen:4790088
12703997 | 47 zevenenveertigste verdieping | Model Group:NLRS_21.21_WA_wand 004 d=300_gen:4790511
12704001 | 47 zevenenveertigste verdieping | Model Group:NLRS_21.21_WA_wand 004 d=300_gen:4790520
12704005 | 48 achtenveertigste verdieping | Model Group:NLRS_21.21_WA_wand 004 d=300_gen:4790943
12704009 | 48 achtenveertigste verdieping | Model Group:NLRS_21.21_WA_wand 004 d=300_gen:4790952
12704013 | 49 negenenveertigste verdieping | Model Group:NLRS_21.21_WA_wand 004 d=300_gen:4791375
12704017 | 49 negenenveertigste verdieping | Model Group:NLRS_21.21_WA_wand 004 d=300_gen:4791384
12704021 | 50 vijftigste verdieping | Model Group:NLRS_21.21_WA_wand 004 d=300_gen:4791807
12704025 | 50 vijftigste verdieping | Model Group:NLRS_21.21_WA_wand 004 d=300_gen:4791816
12704029 | 42 tweeënveertigste verdieping | Model Group:NLRS_21.21_WA_wand 004 d=300_gen:4803256
12704033 | 42 tweeënveertigste verdieping | Model Group:NLRS_21.21_WA_wand 004 d=300_gen:4803265
12704037 | 51 eenenvijftigste verdieping | Model Group:NLRS_21.21_WA_wand 004 d=300_gen:4979990
12704041 | 51 eenenvijftigste verdieping | Model Group:NLRS_21.21_WA_wand 004 d=300_gen:4979999
12704491 | 52 tweeënvijftigste verdieping | Model Group:NLRS_21.21_WA_wand 004c d=300_gen:4981771
12704527 | 52 tweeënvijftigste verdieping | Model Group:NLRS_21.21_WA_wand 004c d=300_gen:4981762

# IfcWallStandardCase: Basic Wall:NLRS_21.21_WA_beton ihwg d=400/420_gen (4)
In: 05 vijfde verdieping
Type - PredefinedType: STANDARD; Material: NLRS_f2_beton ihwg 400 mm
Classification: 21.21 buitenwanden - constructief, massieve wanden (Uniformat)
Pset_WallCommon - IsExternal: yes; LoadBearing: yes; ExtendToStructure: no; Reference: NLRS_21.21_WA_beton ihwg d=400/420_gen; ThermalTransmittance: 2.615 kg/K/s3
Name (Basic Wall:NLRS_21.21_WA_beton ihwg d=400/420_gen:...)
5042426
5042554
5042653
5042754

# IfcWallStandardCase: Basic Wall:NLRS_21.21_WA_beton ihwg d=400_gen (16)
Type - PredefinedType: STANDARD; Material: NLRS_f2_beton ihwg 400 mm
Classification: 22.21 binnenwanden - constructief, massieve wanden (Uniformat)
Pset_WallCommon - IsExternal: yes; LoadBearing: yes; ExtendToStructure: no; Reference: NLRS_21.21_WA_beton ihwg d=400_gen; ThermalTransmittance: 2.615 kg/K/s3
Name (Basic Wall:NLRS_21.21_WA_beton ihwg d=400_gen:...) | In | Group
12692521 | 06 zesde verdieping | Model Group:NLRS_21.21_WA_wand 002a d=400_gen:4690711
12692541 | 06 zesde verdieping | Model Group:NLRS_21.21_WA_wand 002a d=400_gen:4690710
12692543 | 08 achtste verdieping | Model Group:NLRS_21.21_WA_wand 002a d=400_gen:4714828
12692545 | 08 achtste verdieping | Model Group:NLRS_21.21_WA_wand 002a d=400_gen:4714829
12692811 | 07 zevende verdieping | Model Group:NLRS_21.21_WA_wand 002b d=400_gen:4689133
12692882 | 07 zevende verdieping | Model Group:NLRS_21.21_WA_wand 002b d=400_gen:4689126
12698664 | 05 vijfde verdieping
12699043 | 05 vijfde verdieping
12700111 | 05 vijfde verdieping
12700464 | 06 zesde verdieping | Model Group:NLRS_21.21_WA_wand 004a d=400_gen:4690709
12700536 | 06 zesde verdieping | Model Group:NLRS_21.21_WA_wand 004a d=400_gen:4690705
12700540 | 08 achtste verdieping | Model Group:NLRS_21.21_WA_wand 004a d=400_gen:4714823
12700843 | 07 zevende verdieping | Model Group:NLRS_21.21_WA_wand 004b d=400_gen:4689125
12700880 | 07 zevende verdieping | Model Group:NLRS_21.21_WA_wand 004b d=400_gen:4689113
12701169 | 08 achtste verdieping | Model Group:NLRS_21.21_WA_wand 004aa d=400_gen:4714827
12704789 | 05 vijfde verdieping

# IfcWallStandardCase: Basic Wall:NLRS_21.21_WA_beton ihwg d=500_gen (8)
Type - PredefinedType: STANDARD; Material: NLRS_f2_beton ihwg 500 mm
Classification: 21.21 buitenwanden - constructief, massieve wanden (Uniformat)
Pset_WallCommon - IsExternal: yes; LoadBearing: yes; ExtendToStructure: no; Reference: NLRS_21.21_WA_beton ihwg d=500_gen; ThermalTransmittance: 2.092 kg/K/s3
Name (Basic Wall:NLRS_21.21_WA_beton ihwg d=500_gen:...) | In
4832741 | 03 derde verdieping
4832745 | 03 derde verdieping
4832747 | 03 derde verdieping
4941824 | 04 vierde verdieping
4941828 | 04 vierde verdieping
4941830 | 04 vierde verdieping
5835593 | 03 derde verdieping
5836004 | 04 vierde verdieping

# IfcWallStandardCase: Basic Wall:NLRS_21.21_WA_beton prefab d=120_gen (35)
Type - PredefinedType: STANDARD; Material: NLRS_f2_beton prefab 120 mm
Classification: 21.21 buitenwanden - constructief, massieve wanden (Uniformat)
Pset_WallCommon - IsExternal: yes; LoadBearing: yes; ExtendToStructure: no; Reference: NLRS_21.21_WA_beton prefab d=120_gen; ThermalTransmittance: 8.71667 kg/K/s3
Name (Basic Wall:NLRS_21.21_WA_beton prefab d=120_gen:...) | In | Group
13519128 | 03 derde verdieping | Model Group:Wand-W07:13522560
13522830 | 03 derde verdieping | Model Group:Wand-W07:13522837
13522982 | 03 derde verdieping | Model Group:Wand-W07:13522989
13523114 | 03 derde verdieping | Model Group:Wand-W07:13523121
13523271 | 03 derde verdieping | Model Group:Wand-W08:13523638
13524057 | 03 derde verdieping | Model Group:Wand-W09:13524131
13524640 | 03 derde verdieping | Model Group:Wand-W09:13524646
13525071 | 03 derde verdieping | Model Group:Wand-W08:13525078
13525239 | 03 derde verdieping | Model Group:Wand-W10:13525310
13525810 | 03 derde verdieping | Model Group:Wand-W06:13525900
13526728 | 03 derde verdieping | Model Group:Wand-W02:13526804
13528166 | 03 derde verdieping | Model Group:Wand-W02:13528171
13532310 | 03 derde verdieping | Model Group:Wand-W12:13532636
13533034 | 03 derde verdieping | Model Group:Wand-W12:13533040
13533263 | 03 derde verdieping | Model Group:Wand-W13:13533316
13534294 | 03 derde verdieping | Model Group:Wand-W13:13534299
13534542 | 03 derde verdieping | Model Group:Wand-W13A:13534595
13534927 | 03 derde verdieping | Model Group:Wand-W13A:13534933
13535213 | 03 derde verdieping | Model Group:Wand-W13:13535218
13535225 | 03 derde verdieping | Model Group:Wand-W13A:13535231
13535235 | 03 derde verdieping | Model Group:Wand-W13A:13535241
13535589 | 03 derde verdieping | Model Group:Wand-W12:13535595
13535596 | 03 derde verdieping | Model Group:Wand-W12:13535602
13535608 | 03 derde verdieping | Model Group:Wand-W13:13535613
13535821 | 03 derde verdieping | Model Group:Wand-W11:13535873
13536533 | 03 derde verdieping | Model Group:Wand-W04:13536604
13536971 | 03 derde verdieping | Model Group:Wand-W05:13537097
13538081 | 03 derde verdieping | Model Group:Wand-W05A:13538256
13538623 | 01 eerste verdieping
13541579 | 02 tweede verdieping
13542162 | 01 eerste verdieping
13543208 | 02 tweede verdieping
13543503 | 00 begane grond
13612003 | 03 derde verdieping | Model Group:Wand-W02:13612008
13612010 | 03 derde verdieping | Model Group:Wand-W02:13612015

# IfcWallStandardCase: Basic Wall:NLRS_21.21_WA_beton prefab d=200_gen (30)
Type - PredefinedType: STANDARD; Material: NLRS_f2_beton prefab 200 mm
Classification: 21.21 buitenwanden - constructief, massieve wanden (Uniformat)
Pset_WallCommon - IsExternal: yes; LoadBearing: yes; ExtendToStructure: no; Reference: NLRS_21.21_WA_beton prefab d=200_gen; ThermalTransmittance: 5.23 kg/K/s3
Name (Basic Wall:NLRS_21.21_WA_beton prefab d=200_gen:...) | In
4124562 | 00 begane grond
4161001 | 00 begane grond
4447384 | 01 eerste verdieping
4881279 | 03 derde verdieping
4881281 | 03 derde verdieping
4882996 | 03 derde verdieping
4882998 | 03 derde verdieping
4883017 | 03 derde verdieping
4887683 | 03 derde verdieping
4887823 | 03 derde verdieping
4888130 | 03 derde verdieping
4888353 | 02 tweede verdieping
6278576 | 02 tweede verdieping
6278580 | 02 tweede verdieping
6278588 | 02 tweede verdieping
6278596 | 02 tweede verdieping
6278602 | 01 eerste verdieping
6278678 | 01 eerste verdieping
6278784 | 01 eerste verdieping
6278943 | 00 begane grond
6279050 | 00 begane grond
6279215 | 00 begane grond
6279308 | 00 begane grond
6279521 | 00 begane grond
6280985 | 01 eerste verdieping
6281451 | 01 eerste verdieping
6281522 | 01 eerste verdieping
6281994 | 02 tweede verdieping
6282123 | 02 tweede verdieping
14102016 | 05 vijfde verdieping

# IfcWallStandardCase: Basic Wall:NLRS_21.21_WA_beton prefab d=250_gen (4)
In: 00 begane grond
Type - PredefinedType: STANDARD; Material: NLRS_f2_beton prefab 250 mm
Classification: 21.21 buitenwanden - constructief, massieve wanden (Uniformat)
Pset_WallCommon - IsExternal: yes; LoadBearing: yes; ExtendToStructure: no; Reference: NLRS_21.21_WA_beton prefab d=250_gen; ThermalTransmittance: 4.184 kg/K/s3
Name (Basic Wall:NLRS_21.21_WA_beton prefab d=250_gen:...)
5173661
5173663
5173794
5173824

# IfcWallStandardCase: Basic Wall:NLRS_21.21_WA_beton prefab d=300/320_gen (872)
Type - PredefinedType: STANDARD; Material: NLRS_f2_beton prefab 300 mm
Classification: 21.21 buitenwanden - constructief, massieve wanden (Uniformat)
Pset_WallCommon - IsExternal: yes; LoadBearing: yes; ExtendToStructure: no; Reference: NLRS_21.21_WA_beton prefab d=300/320_gen; ThermalTransmittance: 3.48667 kg/K/s3
Name (Basic Wall:NLRS_21.21_WA_beton prefab d=300/320_gen:...) | In | Group
4694984 | 21 eenentwintigste verdieping | Model Group:NLRS_21.21_WA_wand 003 d=300_gen:4695035
4694986 | 21 eenentwintigste verdieping | Model Group:NLRS_21.21_WA_wand 001 d=300_gen:4695034
4695036 | 21 eenentwintigste verdieping | Model Group:NLRS_21.21_WA_wand 003 d=300_gen:4695039
4695040 | 21 eenentwintigste verdieping | Model Group:NLRS_21.21_WA_wand 001 d=300_gen:4695043
4695055 | 21 eenentwintigste verdieping | Model Group:NLRS_21.21_WA_wand 002 d=300_gen:4695033
4695057 | 21 eenentwintigste verdieping | Model Group:NLRS_21.21_WA_wand 002 d=300_gen:4695026
4695081 | 21 eenentwintigste verdieping | Model Group:NLRS_21.21_WA_wand 004 d=300_gen:4695025
4695083 | 21 eenentwintigste verdieping | Model Group:NLRS_21.21_WA_wand 004 d=300_gen:4695016
4695192 | 21 eenentwintigste verdieping | Model Group:NLRS_28.21_WA_3D element 002 d=300_gen:4695207
4695194 | 21 eenentwintigste verdieping | Model Group:NLRS_28.21_WA_3D element 002 d=300_gen:4695207
4695291 | 21 eenentwintigste verdieping | Model Group:NLRS_28.21_WA_3D element 002 d=300_gen:4695191
4695293 | 21 eenentwintigste verdieping | Model Group:NLRS_28.21_WA_3D element 002 d=300_gen:4695191
4695335 | 21 eenentwintigste verdieping | Model Group:NLRS_28.21_WA_3D element 001 d=300_gen:4695190
4695338 | 21 eenentwintigste verdieping | Model Group:NLRS_28.21_WA_3D element 001 d=300_gen:4695190
4695364 | 21 eenentwintigste verdieping | Model Group:NLRS_28.21_WA_3D element 001 d=300_gen:4695208
4695367 | 21 eenentwintigste verdieping | Model Group:NLRS_28.21_WA_3D element 001 d=300_gen:4695208
4730607 | 13 dertiende verdieping | Model Group:NLRS_21.21_WA_wand 003 d=300_gen:4730658
4730609 | 13 dertiende verdieping | Model Group:NLRS_21.21_WA_wand 001 d=300_gen:4730657
4730659 | 13 dertiende verdieping | Model Group:NLRS_21.21_WA_wand 003 d=300_gen:4730662
4730663 | 13 dertiende verdieping | Model Group:NLRS_21.21_WA_wand 001 d=300_gen:4730666
4730815 | 13 dertiende verdieping | Model Group:NLRS_28.21_WA_3D element 002 d=300_gen:4730830
4730817 | 13 dertiende verdieping | Model Group:NLRS_28.21_WA_3D element 002 d=300_gen:4730830
4730914 | 13 dertiende verdieping | Model Group:NLRS_28.21_WA_3D element 002 d=300_gen:4730814
4730916 | 13 dertiende verdieping | Model Group:NLRS_28.21_WA_3D element 002 d=300_gen:4730814
4730958 | 13 dertiende verdieping | Model Group:NLRS_28.21_WA_3D element 001 d=300_gen:4730813
4730961 | 13 dertiende verdieping | Model Group:NLRS_28.21_WA_3D element 001 d=300_gen:4730813
4730987 | 13 dertiende verdieping | Model Group:NLRS_28.21_WA_3D element 001 d=300_gen:4730831
4730990 | 13 dertiende verdieping | Model Group:NLRS_28.21_WA_3D element 001 d=300_gen:4730831
4731065 | 15 vijftiende verdieping | Model Group:NLRS_21.21_WA_wand 003 d=300_gen:4731116
4731067 | 15 vijftiende verdieping | Model Group:NLRS_21.21_WA_wand 001 d=300_gen:4731115
4731117 | 15 vijftiende verdieping | Model Group:NLRS_21.21_WA_wand 003 d=300_gen:4731120
4731121 | 15 vijftiende verdieping | Model Group:NLRS_21.21_WA_wand 001 d=300_gen:4731124
4731136 | 15 vijftiende verdieping | Model Group:NLRS_21.21_WA_wand 002 d=300_gen:4731114
4731162 | 15 vijftiende verdieping | Model Group:NLRS_21.21_WA_wand 004 d=300_gen:4731106
4731164 | 15 vijftiende verdieping | Model Group:NLRS_21.21_WA_wand 004 d=300_gen:4731097
4731273 | 15 vijftiende verdieping | Model Group:NLRS_28.21_WA_3D element 002 d=300_gen:4731288
4731275 | 15 vijftiende verdieping | Model Group:NLRS_28.21_WA_3D element 002 d=300_gen:4731288
4731372 | 15 vijftiende verdieping | Model Group:NLRS_28.21_WA_3D element 002 d=300_gen:4731272
4731374 | 15 vijftiende verdieping | Model Group:NLRS_28.21_WA_3D element 002 d=300_gen:4731272
4731416 | 15 vijftiende verdieping | Model Group:NLRS_28.21_WA_3D element 001 d=300_gen:4731271
4731419 | 15 vijftiende verdieping | Model Group:NLRS_28.21_WA_3D element 001 d=300_gen:4731271
4731445 | 15 vijftiende verdieping | Model Group:NLRS_28.21_WA_3D element 001 d=300_gen:4731289
4731448 | 15 vijftiende verdieping | Model Group:NLRS_28.21_WA_3D element 001 d=300_gen:4731289
4731523 | 17 zeventiende verdieping | Model Group:NLRS_21.21_WA_wand 003 d=300_gen:4731574
4731525 | 17 zeventiende verdieping | Model Group:NLRS_21.21_WA_wand 001 d=300_gen:4731573
4731575 | 17 zeventiende verdieping | Model Group:NLRS_21.21_WA_wand 003 d=300_gen:4731578
4731579 | 17 zeventiende verdieping | Model Group:NLRS_21.21_WA_wand 001 d=300_gen:4731582
4731594 | 17 zeventiende verdieping | Model Group:NLRS_21.21_WA_wand 002 d=300_gen:4731572
4731620 | 17 zeventiende verdieping | Model Group:NLRS_21.21_WA_wand 004 d=300_gen:4731564
4731622 | 17 zeventiende verdieping | Model Group:NLRS_21.21_WA_wand 004 d=300_gen:4731555
4731731 | 17 zeventiende verdieping | Model Group:NLRS_28.21_WA_3D element 002 d=300_gen:4731746
4731733 | 17 zeventiende verdieping | Model Group:NLRS_28.21_WA_3D element 002 d=300_gen:4731746
4731830 | 17 zeventiende verdieping | Model Group:NLRS_28.21_WA_3D element 002 d=300_gen:4731730
4731832 | 17 zeventiende verdieping | Model Group:NLRS_28.21_WA_3D element 002 d=300_gen:4731730
4731874 | 17 zeventiende verdieping | Model Group:NLRS_28.21_WA_3D element 001 d=300_gen:4731729
4731877 | 17 zeventiende verdieping | Model Group:NLRS_28.21_WA_3D element 001 d=300_gen:4731729
4731903 | 17 zeventiende verdieping | Model Group:NLRS_28.21_WA_3D element 001 d=300_gen:4731747
4731906 | 17 zeventiende verdieping | Model Group:NLRS_28.21_WA_3D element 001 d=300_gen:4731747
4731981 | 19 negentiende verdieping | Model Group:NLRS_21.21_WA_wand 003 d=300_gen:4732032
4731983 | 19 negentiende verdieping | Model Group:NLRS_21.21_WA_wand 001 d=300_gen:4732031
4732033 | 19 negentiende verdieping | Model Group:NLRS_21.21_WA_wand 003 d=300_gen:4732036
4732037 | 19 negentiende verdieping | Model Group:NLRS_21.21_WA_wand 001 d=300_gen:4732040
4732052 | 19 negentiende verdieping | Model Group:NLRS_21.21_WA_wand 002 d=300_gen:4732030
4732078 | 19 negentiende verdieping | Model Group:NLRS_21.21_WA_wand 004 d=300_gen:4732022
4732080 | 19 negentiende verdieping | Model Group:NLRS_21.21_WA_wand 004 d=300_gen:4732013
4732189 | 19 negentiende verdieping | Model Group:NLRS_28.21_WA_3D element 002 d=300_gen:4732204
4732191 | 19 negentiende verdieping | Model Group:NLRS_28.21_WA_3D element 002 d=300_gen:4732204
4732288 | 19 negentiende verdieping | Model Group:NLRS_28.21_WA_3D element 002 d=300_gen:4732188
4732290 | 19 negentiende verdieping | Model Group:NLRS_28.21_WA_3D element 002 d=300_gen:4732188
4732332 | 19 negentiende verdieping | Model Group:NLRS_28.21_WA_3D element 001 d=300_gen:4732187
4732335 | 19 negentiende verdieping | Model Group:NLRS_28.21_WA_3D element 001 d=300_gen:4732187
4732361 | 19 negentiende verdieping | Model Group:NLRS_28.21_WA_3D element 001 d=300_gen:4732205
4732364 | 19 negentiende verdieping | Model Group:NLRS_28.21_WA_3D element 001 d=300_gen:4732205
4738194 | 12 twaalfde verdieping | Model Group:NLRS_21.21_WA_wand 003 d=300_gen:4738245
4738196 | 12 twaalfde verdieping | Model Group:NLRS_21.21_WA_wand 001 d=300_gen:4738244
4738246 | 12 twaalfde verdieping | Model Group:NLRS_21.21_WA_wand 003 d=300_gen:4738249
4738250 | 12 twaalfde verdieping | Model Group:NLRS_21.21_WA_wand 001 d=300_gen:4738253
4738402 | 12 twaalfde verdieping | Model Group:NLRS_28.21_WA_3D element 002 d=300_gen:4738417
4738404 | 12 twaalfde verdieping | Model Group:NLRS_28.21_WA_3D element 002 d=300_gen:4738417
4738501 | 12 twaalfde verdieping | Model Group:NLRS_28.21_WA_3D element 002 d=300_gen:4738401
4738503 | 12 twaalfde verdieping | Model Group:NLRS_28.21_WA_3D element 002 d=300_gen:4738401
4738545 | 12 twaalfde verdieping | Model Group:NLRS_28.21_WA_3D element 001 d=300_gen:4738400
4738548 | 12 twaalfde verdieping | Model Group:NLRS_28.21_WA_3D element 001 d=300_gen:4738400
4738574 | 12 twaalfde verdieping | Model Group:NLRS_28.21_WA_3D element 001 d=300_gen:4738418
4738577 | 12 twaalfde verdieping | Model Group:NLRS_28.21_WA_3D element 001 d=300_gen:4738418
4738652 | 14 veertiende verdieping | Model Group:NLRS_21.21_WA_wand 003 d=300_gen:4738703
4738654 | 14 veertiende verdieping | Model Group:NLRS_21.21_WA_wand 001 d=300_gen:4738702
4738704 | 14 veertiende verdieping | Model Group:NLRS_21.21_WA_wand 003 d=300_gen:4738707
4738708 | 14 veertiende verdieping | Model Group:NLRS_21.21_WA_wand 001 d=300_gen:4738711
4738860 | 14 veertiende verdieping | Model Group:NLRS_28.21_WA_3D element 002 d=300_gen:4738875
4738862 | 14 veertiende verdieping | Model Group:NLRS_28.21_WA_3D element 002 d=300_gen:4738875
4738959 | 14 veertiende verdieping | Model Group:NLRS_28.21_WA_3D element 002 d=300_gen:4738859
4738961 | 14 veertiende verdieping | Model Group:NLRS_28.21_WA_3D element 002 d=300_gen:4738859
4739003 | 14 veertiende verdieping | Model Group:NLRS_28.21_WA_3D element 001 d=300_gen:4738858
4739006 | 14 veertiende verdieping | Model Group:NLRS_28.21_WA_3D element 001 d=300_gen:4738858
4739032 | 14 veertiende verdieping | Model Group:NLRS_28.21_WA_3D element 001 d=300_gen:4738876
4739035 | 14 veertiende verdieping | Model Group:NLRS_28.21_WA_3D element 001 d=300_gen:4738876
4739110 | 16 zestiende verdieping | Model Group:NLRS_21.21_WA_wand 003 d=300_gen:4739161
4739112 | 16 zestiende verdieping | Model Group:NLRS_21.21_WA_wand 001 d=300_gen:4739160
4739162 | 16 zestiende verdieping | Model Group:NLRS_21.21_WA_wand 003 d=300_gen:4739165
4739166 | 16 zestiende verdieping | Model Group:NLRS_21.21_WA_wand 001 d=300_gen:4739169
4739181 | 16 zestiende verdieping | Model Group:NLRS_21.21_WA_wand 002 d=300_gen:4739159
4739183 | 16 zestiende verdieping | Model Group:NLRS_21.21_WA_wand 002 d=300_gen:4739152
4739207 | 16 zestiende verdieping | Model Group:NLRS_21.21_WA_wand 004 d=300_gen:4739151
4739209 | 16 zestiende verdieping | Model Group:NLRS_21.21_WA_wand 004 d=300_gen:4739142
4739318 | 16 zestiende verdieping | Model Group:NLRS_28.21_WA_3D element 002 d=300_gen:4739333
4739320 | 16 zestiende verdieping | Model Group:NLRS_28.21_WA_3D element 002 d=300_gen:4739333
4739417 | 16 zestiende verdieping | Model Group:NLRS_28.21_WA_3D element 002 d=300_gen:4739317
4739419 | 16 zestiende verdieping | Model Group:NLRS_28.21_WA_3D element 002 d=300_gen:4739317
4739461 | 16 zestiende verdieping | Model Group:NLRS_28.21_WA_3D element 001 d=300_gen:4739316
4739464 | 16 zestiende verdieping | Model Group:NLRS_28.21_WA_3D element 001 d=300_gen:4739316
4739490 | 16 zestiende verdieping | Model Group:NLRS_28.21_WA_3D element 001 d=300_gen:4739334
4739493 | 16 zestiende verdieping | Model Group:NLRS_28.21_WA_3D element 001 d=300_gen:4739334
4739568 | 18 achttiende verdieping | Model Group:NLRS_21.21_WA_wand 003 d=300_gen:4739619
4739570 | 18 achttiende verdieping | Model Group:NLRS_21.21_WA_wand 001 d=300_gen:4739618
4739620 | 18 achttiende verdieping | Model Group:NLRS_21.21_WA_wand 003 d=300_gen:4739623
4739624 | 18 achttiende verdieping | Model Group:NLRS_21.21_WA_wand 001 d=300_gen:4739627
4739639 | 18 achttiende verdieping | Model Group:NLRS_21.21_WA_wand 002 d=300_gen:4739617
4739641 | 18 achttiende verdieping | Model Group:NLRS_21.21_WA_wand 002 d=300_gen:4739610
4739665 | 18 achttiende verdieping | Model Group:NLRS_21.21_WA_wand 004 d=300_gen:4739609
4739667 | 18 achttiende verdieping | Model Group:NLRS_21.21_WA_wand 004 d=300_gen:4739600
4739776 | 18 achttiende verdieping | Model Group:NLRS_28.21_WA_3D element 002 d=300_gen:4739791
4739778 | 18 achttiende verdieping | Model Group:NLRS_28.21_WA_3D element 002 d=300_gen:4739791
4739875 | 18 achttiende verdieping | Model Group:NLRS_28.21_WA_3D element 002 d=300_gen:4739775
4739877 | 18 achttiende verdieping | Model Group:NLRS_28.21_WA_3D element 002 d=300_gen:4739775
4739919 | 18 achttiende verdieping | Model Group:NLRS_28.21_WA_3D element 001 d=300_gen:4739774
4739922 | 18 achttiende verdieping | Model Group:NLRS_28.21_WA_3D element 001 d=300_gen:4739774
4739948 | 18 achttiende verdieping | Model Group:NLRS_28.21_WA_3D element 001 d=300_gen:4739792
4739951 | 18 achttiende verdieping | Model Group:NLRS_28.21_WA_3D element 001 d=300_gen:4739792
4740026 | 20 twintigste verdieping | Model Group:NLRS_21.21_WA_wand 003 d=300_gen:4740077
4740028 | 20 twintigste verdieping | Model Group:NLRS_21.21_WA_wand 001 d=300_gen:4740076
4740078 | 20 twintigste verdieping | Model Group:NLRS_21.21_WA_wand 003 d=300_gen:4740081
4740082 | 20 twintigste verdieping | Model Group:NLRS_21.21_WA_wand 001 d=300_gen:4740085
4740097 | 20 twintigste verdieping | Model Group:NLRS_21.21_WA_wand 002 d=300_gen:4740075
4740099 | 20 twintigste verdieping | Model Group:NLRS_21.21_WA_wand 002 d=300_gen:4740068
4740123 | 20 twintigste verdieping | Model Group:NLRS_21.21_WA_wand 004 d=300_gen:4740067
4740125 | 20 twintigste verdieping | Model Group:NLRS_21.21_WA_wand 004 d=300_gen:4740058
4740234 | 20 twintigste verdieping | Model Group:NLRS_28.21_WA_3D element 002 d=300_gen:4740249
4740236 | 20 twintigste verdieping | Model Group:NLRS_28.21_WA_3D element 002 d=300_gen:4740249
4740333 | 20 twintigste verdieping | Model Group:NLRS_28.21_WA_3D element 002 d=300_gen:4740233
4740335 | 20 twintigste verdieping | Model Group:NLRS_28.21_WA_3D element 002 d=300_gen:4740233
4740377 | 20 twintigste verdieping | Model Group:NLRS_28.21_WA_3D element 001 d=300_gen:4740232
4740380 | 20 twintigste verdieping | Model Group:NLRS_28.21_WA_3D element 001 d=300_gen:4740232
4740406 | 20 twintigste verdieping | Model Group:NLRS_28.21_WA_3D element 001 d=300_gen:4740250
4740409 | 20 twintigste verdieping | Model Group:NLRS_28.21_WA_3D element 001 d=300_gen:4740250
4746627 | 24 vierentwintigste verdieping | Model Group:NLRS_21.21_WA_wand 003 d=300_gen:4746676
4746629 | 24 vierentwintigste verdieping | Model Group:NLRS_21.21_WA_wand 001 d=300_gen:4746675
4746677 | 24 vierentwintigste verdieping | Model Group:NLRS_21.21_WA_wand 003 d=300_gen:4746680
4746681 | 24 vierentwintigste verdieping | Model Group:NLRS_21.21_WA_wand 001 d=300_gen:4746684
4746696 | 24 vierentwintigste verdieping | Model Group:NLRS_21.21_WA_wand 002 d=300_gen:4746674
4746698 | 24 vierentwintigste verdieping | Model Group:NLRS_21.21_WA_wand 002 d=300_gen:4746667
4746722 | 24 vierentwintigste verdieping | Model Group:NLRS_21.21_WA_wand 004 d=300_gen:4746666
4746724 | 24 vierentwintigste verdieping | Model Group:NLRS_21.21_WA_wand 004 d=300_gen:4746657
4746831 | 24 vierentwintigste verdieping | Model Group:NLRS_28.21_WA_3D element 002 d=300_gen:4746846
4746833 | 24 vierentwintigste verdieping | Model Group:NLRS_28.21_WA_3D element 002 d=300_gen:4746846
4746912 | 24 vierentwintigste verdieping | Model Group:NLRS_28.21_WA_3D element 002 d=300_gen:4746830
4746914 | 24 vierentwintigste verdieping | Model Group:NLRS_28.21_WA_3D element 002 d=300_gen:4746830
4746956 | 24 vierentwintigste verdieping | Model Group:NLRS_28.21_WA_3D element 001 d=300_gen:4746829
4746959 | 24 vierentwintigste verdieping | Model Group:NLRS_28.21_WA_3D element 001 d=300_gen:4746829
4746985 | 24 vierentwintigste verdieping | Model Group:NLRS_28.21_WA_3D element 001 d=300_gen:4746847
4746988 | 24 vierentwintigste verdieping | Model Group:NLRS_28.21_WA_3D element 001 d=300_gen:4746847
4747059 | 25 vijfentwintigste verdieping | Model Group:NLRS_21.21_WA_wand 003 d=300_gen:4747108
4747061 | 25 vijfentwintigste verdieping | Model Group:NLRS_21.21_WA_wand 001 d=300_gen:4747107
4747109 | 25 vijfentwintigste verdieping | Model Group:NLRS_21.21_WA_wand 003 d=300_gen:4747112
4747113 | 25 vijfentwintigste verdieping | Model Group:NLRS_21.21_WA_wand 001 d=300_gen:4747116
4747128 | 25 vijfentwintigste verdieping | Model Group:NLRS_21.21_WA_wand 002 d=300_gen:4747106
4747130 | 25 vijfentwintigste verdieping | Model Group:NLRS_21.21_WA_wand 002 d=300_gen:4747099
4747154 | 25 vijfentwintigste verdieping | Model Group:NLRS_21.21_WA_wand 004 d=300_gen:4747098
4747156 | 25 vijfentwintigste verdieping | Model Group:NLRS_21.21_WA_wand 004 d=300_gen:4747089
4747263 | 25 vijfentwintigste verdieping | Model Group:NLRS_28.21_WA_3D element 002 d=300_gen:4747278
4747265 | 25 vijfentwintigste verdieping | Model Group:NLRS_28.21_WA_3D element 002 d=300_gen:4747278
4747344 | 25 vijfentwintigste verdieping | Model Group:NLRS_28.21_WA_3D element 002 d=300_gen:4747262
4747346 | 25 vijfentwintigste verdieping | Model Group:NLRS_28.21_WA_3D element 002 d=300_gen:4747262
4747388 | 25 vijfentwintigste verdieping | Model Group:NLRS_28.21_WA_3D element 001 d=300_gen:4747261
4747391 | 25 vijfentwintigste verdieping | Model Group:NLRS_28.21_WA_3D element 001 d=300_gen:4747261
4747417 | 25 vijfentwintigste verdieping | Model Group:NLRS_28.21_WA_3D element 001 d=300_gen:4747279
4747420 | 25 vijfentwintigste verdieping | Model Group:NLRS_28.21_WA_3D element 001 d=300_gen:4747279
4747491 | 26 zesentwintigste verdieping | Model Group:NLRS_21.21_WA_wand 003 d=300_gen:4747540
4747493 | 26 zesentwintigste verdieping | Model Group:NLRS_21.21_WA_wand 001 d=300_gen:4747539
4747541 | 26 zesentwintigste verdieping | Model Group:NLRS_21.21_WA_wand 003 d=300_gen:4747544
4747545 | 26 zesentwintigste verdieping | Model Group:NLRS_21.21_WA_wand 001 d=300_gen:4747548
4747560 | 26 zesentwintigste verdieping | Model Group:NLRS_21.21_WA_wand 002 d=300_gen:4747538
4747562 | 26 zesentwintigste verdieping | Model Group:NLRS_21.21_WA_wand 002 d=300_gen:4747531
4747586 | 26 zesentwintigste verdieping | Model Group:NLRS_21.21_WA_wand 004 d=300_gen:4747530
4747588 | 26 zesentwintigste verdieping | Model Group:NLRS_21.21_WA_wand 004 d=300_gen:4747521
4747695 | 26 zesentwintigste verdieping | Model Group:NLRS_28.21_WA_3D element 002 d=300_gen:4747710
4747697 | 26 zesentwintigste verdieping | Model Group:NLRS_28.21_WA_3D element 002 d=300_gen:4747710
4747776 | 26 zesentwintigste verdieping | Model Group:NLRS_28.21_WA_3D element 002 d=300_gen:4747694
4747778 | 26 zesentwintigste verdieping | Model Group:NLRS_28.21_WA_3D element 002 d=300_gen:4747694
4747820 | 26 zesentwintigste verdieping | Model Group:NLRS_28.21_WA_3D element 001 d=300_gen:4747693
4747823 | 26 zesentwintigste verdieping | Model Group:NLRS_28.21_WA_3D element 001 d=300_gen:4747693
4747849 | 26 zesentwintigste verdieping | Model Group:NLRS_28.21_WA_3D element 001 d=300_gen:4747711
4747852 | 26 zesentwintigste verdieping | Model Group:NLRS_28.21_WA_3D element 001 d=300_gen:4747711
4747923 | 27 zevenentwintigste verdieping | Model Group:NLRS_21.21_WA_wand 003 d=300_gen:4747972
4747925 | 27 zevenentwintigste verdieping | Model Group:NLRS_21.21_WA_wand 001 d=300_gen:4747971
4747973 | 27 zevenentwintigste verdieping | Model Group:NLRS_21.21_WA_wand 003 d=300_gen:4747976
4747977 | 27 zevenentwintigste verdieping | Model Group:NLRS_21.21_WA_wand 001 d=300_gen:4747980
4747992 | 27 zevenentwintigste verdieping | Model Group:NLRS_21.21_WA_wand 002 d=300_gen:4747970
4747994 | 27 zevenentwintigste verdieping | Model Group:NLRS_21.21_WA_wand 002 d=300_gen:4747963
4748018 | 27 zevenentwintigste verdieping | Model Group:NLRS_21.21_WA_wand 004 d=300_gen:4747962
4748020 | 27 zevenentwintigste verdieping | Model Group:NLRS_21.21_WA_wand 004 d=300_gen:4747953
4748127 | 27 zevenentwintigste verdieping | Model Group:NLRS_28.21_WA_3D element 002 d=300_gen:4748142
4748129 | 27 zevenentwintigste verdieping | Model Group:NLRS_28.21_WA_3D element 002 d=300_gen:4748142
4748208 | 27 zevenentwintigste verdieping | Model Group:NLRS_28.21_WA_3D element 002 d=300_gen:4748126
4748210 | 27 zevenentwintigste verdieping | Model Group:NLRS_28.21_WA_3D element 002 d=300_gen:4748126
4748252 | 27 zevenentwintigste verdieping | Model Group:NLRS_28.21_WA_3D element 001 d=300_gen:4748125
4748255 | 27 zevenentwintigste verdieping | Model Group:NLRS_28.21_WA_3D element 001 d=300_gen:4748125
4748281 | 27 zevenentwintigste verdieping | Model Group:NLRS_28.21_WA_3D element 001 d=300_gen:4748143
4748284 | 27 zevenentwintigste verdieping | Model Group:NLRS_28.21_WA_3D element 001 d=300_gen:4748143
4748355 | 28 achtentwintigste verdieping | Model Group:NLRS_21.21_WA_wand 003 d=300_gen:4748404
4748357 | 28 achtentwintigste verdieping | Model Group:NLRS_21.21_WA_wand 001 d=300_gen:4748403
4748405 | 28 achtentwintigste verdieping | Model Group:NLRS_21.21_WA_wand 003 d=300_gen:4748408
4748409 | 28 achtentwintigste verdieping | Model Group:NLRS_21.21_WA_wand 001 d=300_gen:4748412
4748424 | 28 achtentwintigste verdieping | Model Group:NLRS_21.21_WA_wand 002 d=300_gen:4748402
4748426 | 28 achtentwintigste verdieping | Model Group:NLRS_21.21_WA_wand 002 d=300_gen:4748395
4748450 | 28 achtentwintigste verdieping | Model Group:NLRS_21.21_WA_wand 004 d=300_gen:4748394
4748452 | 28 achtentwintigste verdieping | Model Group:NLRS_21.21_WA_wand 004 d=300_gen:4748385
4748559 | 28 achtentwintigste verdieping | Model Group:NLRS_28.21_WA_3D element 002 d=300_gen:4748574
4748561 | 28 achtentwintigste verdieping | Model Group:NLRS_28.21_WA_3D element 002 d=300_gen:4748574
4748640 | 28 achtentwintigste verdieping | Model Group:NLRS_28.21_WA_3D element 002 d=300_gen:4748558
4748642 | 28 achtentwintigste verdieping | Model Group:NLRS_28.21_WA_3D element 002 d=300_gen:4748558
4748684 | 28 achtentwintigste verdieping | Model Group:NLRS_28.21_WA_3D element 001 d=300_gen:4748557
4748687 | 28 achtentwintigste verdieping | Model Group:NLRS_28.21_WA_3D element 001 d=300_gen:4748557
4748713 | 28 achtentwintigste verdieping | Model Group:NLRS_28.21_WA_3D element 001 d=300_gen:4748575
4748716 | 28 achtentwintigste verdieping | Model Group:NLRS_28.21_WA_3D element 001 d=300_gen:4748575
4748787 | 29 negenentwintigste verdieping | Model Group:NLRS_21.21_WA_wand 003 d=300_gen:4748836
4748789 | 29 negenentwintigste verdieping | Model Group:NLRS_21.21_WA_wand 001 d=300_gen:4748835
4748837 | 29 negenentwintigste verdieping | Model Group:NLRS_21.21_WA_wand 003 d=300_gen:4748840
4748841 | 29 negenentwintigste verdieping | Model Group:NLRS_21.21_WA_wand 001 d=300_gen:4748844
4748856 | 29 negenentwintigste verdieping | Model Group:NLRS_21.21_WA_wand 002 d=300_gen:4748834
4748858 | 29 negenentwintigste verdieping | Model Group:NLRS_21.21_WA_wand 002 d=300_gen:4748827
4748882 | 29 negenentwintigste verdieping | Model Group:NLRS_21.21_WA_wand 004 d=300_gen:4748826
4748884 | 29 negenentwintigste verdieping | Model Group:NLRS_21.21_WA_wand 004 d=300_gen:4748817
4748991 | 29 negenentwintigste verdieping | Model Group:NLRS_28.21_WA_3D element 002 d=300_gen:4749006
4748993 | 29 negenentwintigste verdieping | Model Group:NLRS_28.21_WA_3D element 002 d=300_gen:4749006
4749072 | 29 negenentwintigste verdieping | Model Group:NLRS_28.21_WA_3D element 002 d=300_gen:4748990
4749074 | 29 negenentwintigste verdieping | Model Group:NLRS_28.21_WA_3D element 002 d=300_gen:4748990
4749116 | 29 negenentwintigste verdieping | Model Group:NLRS_28.21_WA_3D element 001 d=300_gen:4748989
4749119 | 29 negenentwintigste verdieping | Model Group:NLRS_28.21_WA_3D element 001 d=300_gen:4748989
4749145 | 29 negenentwintigste verdieping | Model Group:NLRS_28.21_WA_3D element 001 d=300_gen:4749007
4749148 | 29 negenentwintigste verdieping | Model Group:NLRS_28.21_WA_3D element 001 d=300_gen:4749007
4749219 | 30 dertigste verdieping | Model Group:NLRS_21.21_WA_wand 003 d=300_gen:4749268
4749221 | 30 dertigste verdieping | Model Group:NLRS_21.21_WA_wand 001 d=300_gen:4749267
4749269 | 30 dertigste verdieping | Model Group:NLRS_21.21_WA_wand 003 d=300_gen:4749272
4749273 | 30 dertigste verdieping | Model Group:NLRS_21.21_WA_wand 001 d=300_gen:4749276
4749288 | 30 dertigste verdieping | Model Group:NLRS_21.21_WA_wand 002 d=300_gen:4749266
4749290 | 30 dertigste verdieping | Model Group:NLRS_21.21_WA_wand 002 d=300_gen:4749259
4749314 | 30 dertigste verdieping | Model Group:NLRS_21.21_WA_wand 004 d=300_gen:4749258
4749316 | 30 dertigste verdieping | Model Group:NLRS_21.21_WA_wand 004 d=300_gen:4749249
4749423 | 30 dertigste verdieping | Model Group:NLRS_28.21_WA_3D element 002 d=300_gen:4749438
4749425 | 30 dertigste verdieping | Model Group:NLRS_28.21_WA_3D element 002 d=300_gen:4749438
4749504 | 30 dertigste verdieping | Model Group:NLRS_28.21_WA_3D element 002 d=300_gen:4749422
4749506 | 30 dertigste verdieping | Model Group:NLRS_28.21_WA_3D element 002 d=300_gen:4749422
4749548 | 30 dertigste verdieping | Model Group:NLRS_28.21_WA_3D element 001 d=300_gen:4749421
4749551 | 30 dertigste verdieping | Model Group:NLRS_28.21_WA_3D element 001 d=300_gen:4749421
4749577 | 30 dertigste verdieping | Model Group:NLRS_28.21_WA_3D element 001 d=300_gen:4749439
4749580 | 30 dertigste verdieping | Model Group:NLRS_28.21_WA_3D element 001 d=300_gen:4749439
4749651 | 31 eenendertigste verdieping | Model Group:NLRS_21.21_WA_wand 003 d=300_gen:4749700
4749653 | 31 eenendertigste verdieping | Model Group:NLRS_21.21_WA_wand 001 d=300_gen:4749699
4749701 | 31 eenendertigste verdieping | Model Group:NLRS_21.21_WA_wand 003 d=300_gen:4749704
4749705 | 31 eenendertigste verdieping | Model Group:NLRS_21.21_WA_wand 001 d=300_gen:4749708
4749720 | 31 eenendertigste verdieping | Model Group:NLRS_21.21_WA_wand 002 d=300_gen:4749698
4749722 | 31 eenendertigste verdieping | Model Group:NLRS_21.21_WA_wand 002 d=300_gen:4749691
4749746 | 31 eenendertigste verdieping | Model Group:NLRS_21.21_WA_wand 004 d=300_gen:4749690
4749748 | 31 eenendertigste verdieping | Model Group:NLRS_21.21_WA_wand 004 d=300_gen:4749681
4749855 | 31 eenendertigste verdieping | Model Group:NLRS_28.21_WA_3D element 002 d=300_gen:4749870
4749857 | 31 eenendertigste verdieping | Model Group:NLRS_28.21_WA_3D element 002 d=300_gen:4749870
4749936 | 31 eenendertigste verdieping | Model Group:NLRS_28.21_WA_3D element 002 d=300_gen:4749854
4749938 | 31 eenendertigste verdieping | Model Group:NLRS_28.21_WA_3D element 002 d=300_gen:4749854
4749980 | 31 eenendertigste verdieping | Model Group:NLRS_28.21_WA_3D element 001 d=300_gen:4749853
4749983 | 31 eenendertigste verdieping | Model Group:NLRS_28.21_WA_3D element 001 d=300_gen:4749853
4750009 | 31 eenendertigste verdieping | Model Group:NLRS_28.21_WA_3D element 001 d=300_gen:4749871
4750012 | 31 eenendertigste verdieping | Model Group:NLRS_28.21_WA_3D element 001 d=300_gen:4749871
4750083 | 32 tweeëndertigste verdieping | Model Group:NLRS_21.21_WA_wand 003 d=300_gen:4750132
4750085 | 32 tweeëndertigste verdieping | Model Group:NLRS_21.21_WA_wand 001 d=300_gen:4750131
4750133 | 32 tweeëndertigste verdieping | Model Group:NLRS_21.21_WA_wand 003 d=300_gen:4750136
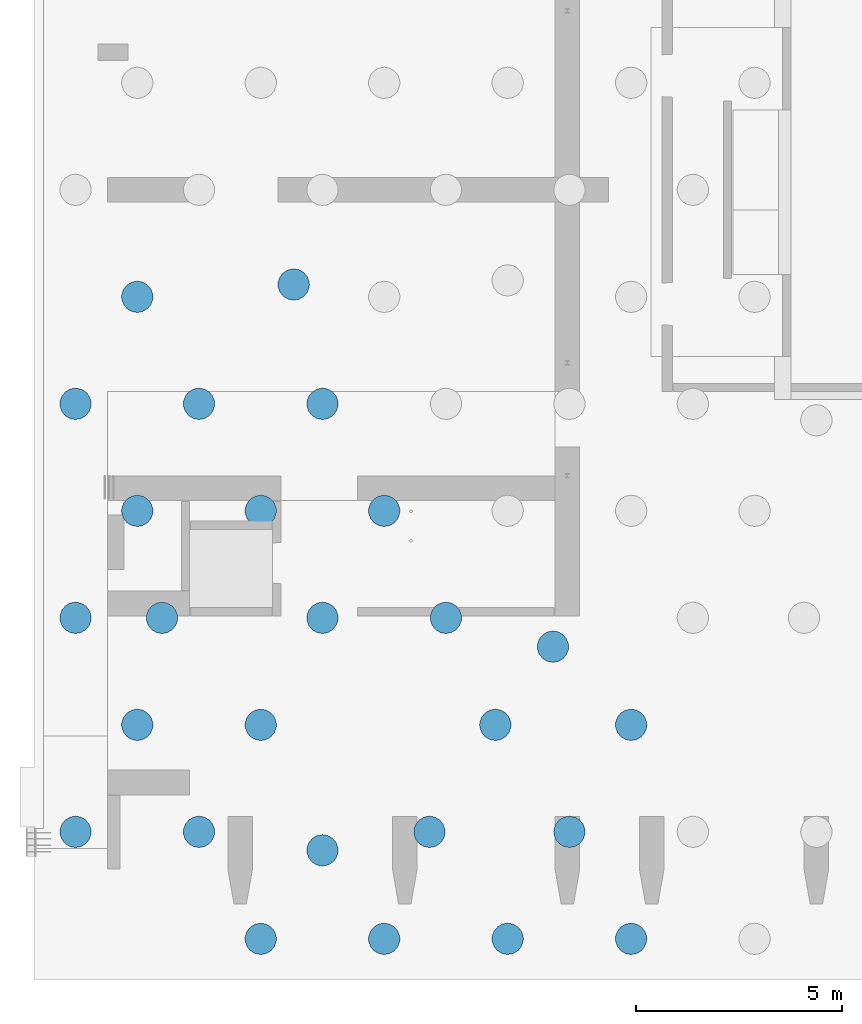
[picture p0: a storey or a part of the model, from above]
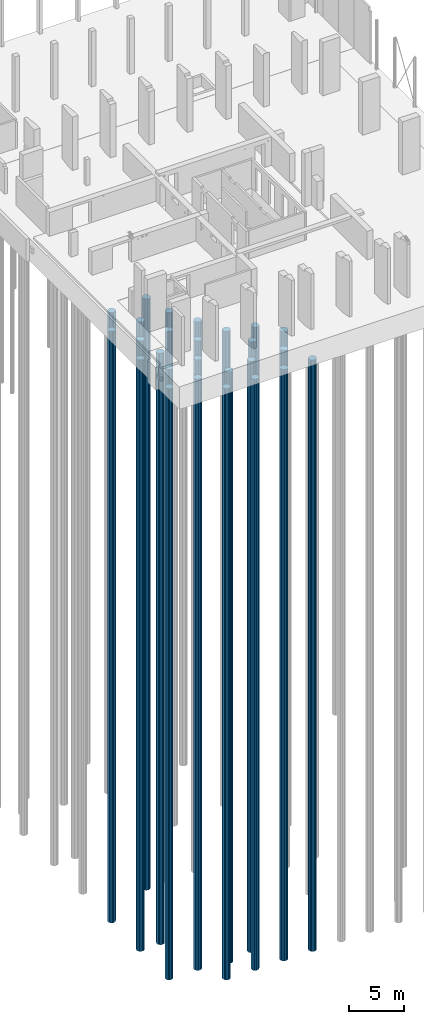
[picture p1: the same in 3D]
Properties of the parts of a building model (IFC2X3), part 19 of 21

# IfcWallStandardCase: Basic Wall:NLRS_21.21_WA_beton prefab d=300/320_gen (872)
Name (Basic Wall:NLRS_21.21_WA_beton prefab d=300/320_gen:...) | In | Group
4750137 | 32 tweeëndertigste verdieping | Model Group:NLRS_21.21_WA_wand 001 d=300_gen:4750140
4750152 | 32 tweeëndertigste verdieping | Model Group:NLRS_21.21_WA_wand 002 d=300_gen:4750130
4750154 | 32 tweeëndertigste verdieping | Model Group:NLRS_21.21_WA_wand 002 d=300_gen:4750123
4750178 | 32 tweeëndertigste verdieping | Model Group:NLRS_21.21_WA_wand 004 d=300_gen:4750122
4750180 | 32 tweeëndertigste verdieping | Model Group:NLRS_21.21_WA_wand 004 d=300_gen:4750113
4750287 | 32 tweeëndertigste verdieping | Model Group:NLRS_28.21_WA_3D element 002 d=300_gen:4750302
4750289 | 32 tweeëndertigste verdieping | Model Group:NLRS_28.21_WA_3D element 002 d=300_gen:4750302
4750368 | 32 tweeëndertigste verdieping | Model Group:NLRS_28.21_WA_3D element 002 d=300_gen:4750286
4750370 | 32 tweeëndertigste verdieping | Model Group:NLRS_28.21_WA_3D element 002 d=300_gen:4750286
4750412 | 32 tweeëndertigste verdieping | Model Group:NLRS_28.21_WA_3D element 001 d=300_gen:4750285
4750415 | 32 tweeëndertigste verdieping | Model Group:NLRS_28.21_WA_3D element 001 d=300_gen:4750285
4750441 | 32 tweeëndertigste verdieping | Model Group:NLRS_28.21_WA_3D element 001 d=300_gen:4750303
4750444 | 32 tweeëndertigste verdieping | Model Group:NLRS_28.21_WA_3D element 001 d=300_gen:4750303
4750515 | 33 drieëndertigste verdieping | Model Group:NLRS_21.21_WA_wand 003 d=300_gen:4750564
4750517 | 33 drieëndertigste verdieping | Model Group:NLRS_21.21_WA_wand 001 d=300_gen:4750563
4750565 | 33 drieëndertigste verdieping | Model Group:NLRS_21.21_WA_wand 003 d=300_gen:4750568
4750569 | 33 drieëndertigste verdieping | Model Group:NLRS_21.21_WA_wand 001 d=300_gen:4750572
4750584 | 33 drieëndertigste verdieping | Model Group:NLRS_21.21_WA_wand 002 d=300_gen:4750562
4750586 | 33 drieëndertigste verdieping | Model Group:NLRS_21.21_WA_wand 002 d=300_gen:4750555
4750610 | 33 drieëndertigste verdieping | Model Group:NLRS_21.21_WA_wand 004 d=300_gen:4750554
4750612 | 33 drieëndertigste verdieping | Model Group:NLRS_21.21_WA_wand 004 d=300_gen:4750545
4750719 | 33 drieëndertigste verdieping | Model Group:NLRS_28.21_WA_3D element 002 d=300_gen:4750734
4750721 | 33 drieëndertigste verdieping | Model Group:NLRS_28.21_WA_3D element 002 d=300_gen:4750734
4750800 | 33 drieëndertigste verdieping | Model Group:NLRS_28.21_WA_3D element 002 d=300_gen:4750718
4750802 | 33 drieëndertigste verdieping | Model Group:NLRS_28.21_WA_3D element 002 d=300_gen:4750718
4750844 | 33 drieëndertigste verdieping | Model Group:NLRS_28.21_WA_3D element 001 d=300_gen:4750717
4750847 | 33 drieëndertigste verdieping | Model Group:NLRS_28.21_WA_3D element 001 d=300_gen:4750717
4750873 | 33 drieëndertigste verdieping | Model Group:NLRS_28.21_WA_3D element 001 d=300_gen:4750735
4750876 | 33 drieëndertigste verdieping | Model Group:NLRS_28.21_WA_3D element 001 d=300_gen:4750735
4750947 | 34 vierendertigste verdieping | Model Group:NLRS_21.21_WA_wand 003 d=300_gen:4750996
4750949 | 34 vierendertigste verdieping | Model Group:NLRS_21.21_WA_wand 001 d=300_gen:4750995
4750997 | 34 vierendertigste verdieping | Model Group:NLRS_21.21_WA_wand 003 d=300_gen:4751000
4751001 | 34 vierendertigste verdieping | Model Group:NLRS_21.21_WA_wand 001 d=300_gen:4751004
4751016 | 34 vierendertigste verdieping | Model Group:NLRS_21.21_WA_wand 002 d=300_gen:4750994
4751018 | 34 vierendertigste verdieping | Model Group:NLRS_21.21_WA_wand 002 d=300_gen:4750987
4751042 | 34 vierendertigste verdieping | Model Group:NLRS_21.21_WA_wand 004 d=300_gen:4750986
4751044 | 34 vierendertigste verdieping | Model Group:NLRS_21.21_WA_wand 004 d=300_gen:4750977
4751151 | 34 vierendertigste verdieping | Model Group:NLRS_28.21_WA_3D element 002 d=300_gen:4751166
4751153 | 34 vierendertigste verdieping | Model Group:NLRS_28.21_WA_3D element 002 d=300_gen:4751166
4751232 | 34 vierendertigste verdieping | Model Group:NLRS_28.21_WA_3D element 002 d=300_gen:4751150
4751234 | 34 vierendertigste verdieping | Model Group:NLRS_28.21_WA_3D element 002 d=300_gen:4751150
4751276 | 34 vierendertigste verdieping | Model Group:NLRS_28.21_WA_3D element 001 d=300_gen:4751149
4751279 | 34 vierendertigste verdieping | Model Group:NLRS_28.21_WA_3D element 001 d=300_gen:4751149
4751305 | 34 vierendertigste verdieping | Model Group:NLRS_28.21_WA_3D element 001 d=300_gen:4751167
4751308 | 34 vierendertigste verdieping | Model Group:NLRS_28.21_WA_3D element 001 d=300_gen:4751167
4751379 | 35 vijfendertigste verdieping | Model Group:NLRS_21.21_WA_wand 003 d=300_gen:4751428
4751381 | 35 vijfendertigste verdieping | Model Group:NLRS_21.21_WA_wand 001 d=300_gen:4751427
4751429 | 35 vijfendertigste verdieping | Model Group:NLRS_21.21_WA_wand 003 d=300_gen:4751432
4751433 | 35 vijfendertigste verdieping | Model Group:NLRS_21.21_WA_wand 001 d=300_gen:4751436
4751448 | 35 vijfendertigste verdieping | Model Group:NLRS_21.21_WA_wand 002 d=300_gen:4751426
4751450 | 35 vijfendertigste verdieping | Model Group:NLRS_21.21_WA_wand 002 d=300_gen:4751419
4751474 | 35 vijfendertigste verdieping | Model Group:NLRS_21.21_WA_wand 004 d=300_gen:4751418
4751476 | 35 vijfendertigste verdieping | Model Group:NLRS_21.21_WA_wand 004 d=300_gen:4751409
4751583 | 35 vijfendertigste verdieping | Model Group:NLRS_28.21_WA_3D element 002 d=300_gen:4751598
4751585 | 35 vijfendertigste verdieping | Model Group:NLRS_28.21_WA_3D element 002 d=300_gen:4751598
4751664 | 35 vijfendertigste verdieping | Model Group:NLRS_28.21_WA_3D element 002 d=300_gen:4751582
4751666 | 35 vijfendertigste verdieping | Model Group:NLRS_28.21_WA_3D element 002 d=300_gen:4751582
4751708 | 35 vijfendertigste verdieping | Model Group:NLRS_28.21_WA_3D element 001 d=300_gen:4751581
4751711 | 35 vijfendertigste verdieping | Model Group:NLRS_28.21_WA_3D element 001 d=300_gen:4751581
4751737 | 35 vijfendertigste verdieping | Model Group:NLRS_28.21_WA_3D element 001 d=300_gen:4751599
4751740 | 35 vijfendertigste verdieping | Model Group:NLRS_28.21_WA_3D element 001 d=300_gen:4751599
4751811 | 36 zesendertigste verdieping | Model Group:NLRS_21.21_WA_wand 003 d=300_gen:4751860
4751813 | 36 zesendertigste verdieping | Model Group:NLRS_21.21_WA_wand 001 d=300_gen:4751859
4751861 | 36 zesendertigste verdieping | Model Group:NLRS_21.21_WA_wand 003 d=300_gen:4751864
4751865 | 36 zesendertigste verdieping | Model Group:NLRS_21.21_WA_wand 001 d=300_gen:4751868
4751880 | 36 zesendertigste verdieping | Model Group:NLRS_21.21_WA_wand 002 d=300_gen:4751858
4751882 | 36 zesendertigste verdieping | Model Group:NLRS_21.21_WA_wand 002 d=300_gen:4751851
4751906 | 36 zesendertigste verdieping | Model Group:NLRS_21.21_WA_wand 004 d=300_gen:4751850
4751908 | 36 zesendertigste verdieping | Model Group:NLRS_21.21_WA_wand 004 d=300_gen:4751841
4752015 | 36 zesendertigste verdieping | Model Group:NLRS_28.21_WA_3D element 002 d=300_gen:4752030
4752017 | 36 zesendertigste verdieping | Model Group:NLRS_28.21_WA_3D element 002 d=300_gen:4752030
4752096 | 36 zesendertigste verdieping | Model Group:NLRS_28.21_WA_3D element 002 d=300_gen:4752014
4752098 | 36 zesendertigste verdieping | Model Group:NLRS_28.21_WA_3D element 002 d=300_gen:4752014
4752140 | 36 zesendertigste verdieping | Model Group:NLRS_28.21_WA_3D element 001 d=300_gen:4752013
4752143 | 36 zesendertigste verdieping | Model Group:NLRS_28.21_WA_3D element 001 d=300_gen:4752013
4752169 | 36 zesendertigste verdieping | Model Group:NLRS_28.21_WA_3D element 001 d=300_gen:4752031
4752172 | 36 zesendertigste verdieping | Model Group:NLRS_28.21_WA_3D element 001 d=300_gen:4752031
4752243 | 37 zevenendertigste verdieping | Model Group:NLRS_21.21_WA_wand 003 d=300_gen:4752292
4752245 | 37 zevenendertigste verdieping | Model Group:NLRS_21.21_WA_wand 001 d=300_gen:4752291
4752293 | 37 zevenendertigste verdieping | Model Group:NLRS_21.21_WA_wand 003 d=300_gen:4752296
4752297 | 37 zevenendertigste verdieping | Model Group:NLRS_21.21_WA_wand 001 d=300_gen:4752300
4752312 | 37 zevenendertigste verdieping | Model Group:NLRS_21.21_WA_wand 002 d=300_gen:4752290
4752314 | 37 zevenendertigste verdieping | Model Group:NLRS_21.21_WA_wand 002 d=300_gen:4752283
4752338 | 37 zevenendertigste verdieping | Model Group:NLRS_21.21_WA_wand 004 d=300_gen:4752282
4752340 | 37 zevenendertigste verdieping | Model Group:NLRS_21.21_WA_wand 004 d=300_gen:4752273
4752447 | 37 zevenendertigste verdieping | Model Group:NLRS_28.21_WA_3D element 002 d=300_gen:4752462
4752449 | 37 zevenendertigste verdieping | Model Group:NLRS_28.21_WA_3D element 002 d=300_gen:4752462
4752528 | 37 zevenendertigste verdieping | Model Group:NLRS_28.21_WA_3D element 002 d=300_gen:4752446
4752530 | 37 zevenendertigste verdieping | Model Group:NLRS_28.21_WA_3D element 002 d=300_gen:4752446
4752572 | 37 zevenendertigste verdieping | Model Group:NLRS_28.21_WA_3D element 001 d=300_gen:4752445
4752575 | 37 zevenendertigste verdieping | Model Group:NLRS_28.21_WA_3D element 001 d=300_gen:4752445
4752601 | 37 zevenendertigste verdieping | Model Group:NLRS_28.21_WA_3D element 001 d=300_gen:4752463
4752604 | 37 zevenendertigste verdieping | Model Group:NLRS_28.21_WA_3D element 001 d=300_gen:4752463
4752675 | 38 achtendertigste verdieping | Model Group:NLRS_21.21_WA_wand 003 d=300_gen:4752724
4752677 | 38 achtendertigste verdieping | Model Group:NLRS_21.21_WA_wand 001 d=300_gen:4752723
4752725 | 38 achtendertigste verdieping | Model Group:NLRS_21.21_WA_wand 003 d=300_gen:4752728
4752729 | 38 achtendertigste verdieping | Model Group:NLRS_21.21_WA_wand 001 d=300_gen:4752732
4752744 | 38 achtendertigste verdieping | Model Group:NLRS_21.21_WA_wand 002 d=300_gen:4752722
4752746 | 38 achtendertigste verdieping | Model Group:NLRS_21.21_WA_wand 002 d=300_gen:4752715
4752770 | 38 achtendertigste verdieping | Model Group:NLRS_21.21_WA_wand 004 d=300_gen:4752714
4752772 | 38 achtendertigste verdieping | Model Group:NLRS_21.21_WA_wand 004 d=300_gen:4752705
4752879 | 38 achtendertigste verdieping | Model Group:NLRS_28.21_WA_3D element 002 d=300_gen:4752894
4752881 | 38 achtendertigste verdieping | Model Group:NLRS_28.21_WA_3D element 002 d=300_gen:4752894
4752960 | 38 achtendertigste verdieping | Model Group:NLRS_28.21_WA_3D element 002 d=300_gen:4752878
4752962 | 38 achtendertigste verdieping | Model Group:NLRS_28.21_WA_3D element 002 d=300_gen:4752878
4753004 | 38 achtendertigste verdieping | Model Group:NLRS_28.21_WA_3D element 001 d=300_gen:4752877
4753007 | 38 achtendertigste verdieping | Model Group:NLRS_28.21_WA_3D element 001 d=300_gen:4752877
4753033 | 38 achtendertigste verdieping | Model Group:NLRS_28.21_WA_3D element 001 d=300_gen:4752895
4753036 | 38 achtendertigste verdieping | Model Group:NLRS_28.21_WA_3D element 001 d=300_gen:4752895
4753107 | 39 negenendertigste verdieping | Model Group:NLRS_21.21_WA_wand 003 d=300_gen:4753156
4753109 | 39 negenendertigste verdieping | Model Group:NLRS_21.21_WA_wand 001 d=300_gen:4753155
4753157 | 39 negenendertigste verdieping | Model Group:NLRS_21.21_WA_wand 003 d=300_gen:4753160
4753161 | 39 negenendertigste verdieping | Model Group:NLRS_21.21_WA_wand 001 d=300_gen:4753164
4753176 | 39 negenendertigste verdieping | Model Group:NLRS_21.21_WA_wand 002 d=300_gen:4753154
4753178 | 39 negenendertigste verdieping | Model Group:NLRS_21.21_WA_wand 002 d=300_gen:4753147
4753202 | 39 negenendertigste verdieping | Model Group:NLRS_21.21_WA_wand 004 d=300_gen:4753146
4753204 | 39 negenendertigste verdieping | Model Group:NLRS_21.21_WA_wand 004 d=300_gen:4753137
4753311 | 39 negenendertigste verdieping | Model Group:NLRS_28.21_WA_3D element 002 d=300_gen:4753326
4753313 | 39 negenendertigste verdieping | Model Group:NLRS_28.21_WA_3D element 002 d=300_gen:4753326
4753392 | 39 negenendertigste verdieping | Model Group:NLRS_28.21_WA_3D element 002 d=300_gen:4753310
4753394 | 39 negenendertigste verdieping | Model Group:NLRS_28.21_WA_3D element 002 d=300_gen:4753310
4753436 | 39 negenendertigste verdieping | Model Group:NLRS_28.21_WA_3D element 001 d=300_gen:4753309
4753439 | 39 negenendertigste verdieping | Model Group:NLRS_28.21_WA_3D element 001 d=300_gen:4753309
4753465 | 39 negenendertigste verdieping | Model Group:NLRS_28.21_WA_3D element 001 d=300_gen:4753327
4753468 | 39 negenendertigste verdieping | Model Group:NLRS_28.21_WA_3D element 001 d=300_gen:4753327
4753539 | 40 veertigste verdieping | Model Group:NLRS_21.21_WA_wand 003 d=300_gen:4753588
4753541 | 40 veertigste verdieping | Model Group:NLRS_21.21_WA_wand 001 d=300_gen:4753587
4753589 | 40 veertigste verdieping | Model Group:NLRS_21.21_WA_wand 003 d=300_gen:4753592
4753593 | 40 veertigste verdieping | Model Group:NLRS_21.21_WA_wand 001 d=300_gen:4753596
4753608 | 40 veertigste verdieping | Model Group:NLRS_21.21_WA_wand 002 d=300_gen:4753586
4753610 | 40 veertigste verdieping | Model Group:NLRS_21.21_WA_wand 002 d=300_gen:4753579
4753634 | 40 veertigste verdieping | Model Group:NLRS_21.21_WA_wand 004 d=300_gen:4753578
4753636 | 40 veertigste verdieping | Model Group:NLRS_21.21_WA_wand 004 d=300_gen:4753569
4753743 | 40 veertigste verdieping | Model Group:NLRS_28.21_WA_3D element 002 d=300_gen:4753758
4753745 | 40 veertigste verdieping | Model Group:NLRS_28.21_WA_3D element 002 d=300_gen:4753758
4753824 | 40 veertigste verdieping | Model Group:NLRS_28.21_WA_3D element 002 d=300_gen:4753742
4753826 | 40 veertigste verdieping | Model Group:NLRS_28.21_WA_3D element 002 d=300_gen:4753742
4753868 | 40 veertigste verdieping | Model Group:NLRS_28.21_WA_3D element 001 d=300_gen:4753741
4753871 | 40 veertigste verdieping | Model Group:NLRS_28.21_WA_3D element 001 d=300_gen:4753741
4753897 | 40 veertigste verdieping | Model Group:NLRS_28.21_WA_3D element 001 d=300_gen:4753759
4753900 | 40 veertigste verdieping | Model Group:NLRS_28.21_WA_3D element 001 d=300_gen:4753759
4778007 | 22 tweeëntwintigste verdieping | Model Group:NLRS_21.21_WA_wand 003 d=300_gen:4778056
4778009 | 22 tweeëntwintigste verdieping | Model Group:NLRS_21.21_WA_wand 001 d=300_gen:4778055
4778057 | 22 tweeëntwintigste verdieping | Model Group:NLRS_21.21_WA_wand 003 d=300_gen:4778060
4778061 | 22 tweeëntwintigste verdieping | Model Group:NLRS_21.21_WA_wand 001 d=300_gen:4778064
4778076 | 22 tweeëntwintigste verdieping | Model Group:NLRS_21.21_WA_wand 002 d=300_gen:4778054
4778078 | 22 tweeëntwintigste verdieping | Model Group:NLRS_21.21_WA_wand 002 d=300_gen:4778047
4778102 | 22 tweeëntwintigste verdieping | Model Group:NLRS_21.21_WA_wand 004 d=300_gen:4778046
4778104 | 22 tweeëntwintigste verdieping | Model Group:NLRS_21.21_WA_wand 004 d=300_gen:4778037
4778211 | 22 tweeëntwintigste verdieping | Model Group:NLRS_28.21_WA_3D element 002 d=300_gen:4778226
4778213 | 22 tweeëntwintigste verdieping | Model Group:NLRS_28.21_WA_3D element 002 d=300_gen:4778226
4778292 | 22 tweeëntwintigste verdieping | Model Group:NLRS_28.21_WA_3D element 002 d=300_gen:4778210
4778294 | 22 tweeëntwintigste verdieping | Model Group:NLRS_28.21_WA_3D element 002 d=300_gen:4778210
4778336 | 22 tweeëntwintigste verdieping | Model Group:NLRS_28.21_WA_3D element 001 d=300_gen:4778209
4778339 | 22 tweeëntwintigste verdieping | Model Group:NLRS_28.21_WA_3D element 001 d=300_gen:4778209
4778365 | 22 tweeëntwintigste verdieping | Model Group:NLRS_28.21_WA_3D element 001 d=300_gen:4778227
4778368 | 22 tweeëntwintigste verdieping | Model Group:NLRS_28.21_WA_3D element 001 d=300_gen:4778227
4779590 | 23 drieëntwintigste verdieping | Model Group:NLRS_21.21_WA_wand 003 d=300_gen:4779639
4779592 | 23 drieëntwintigste verdieping | Model Group:NLRS_21.21_WA_wand 001 d=300_gen:4779638
4779640 | 23 drieëntwintigste verdieping | Model Group:NLRS_21.21_WA_wand 003 d=300_gen:4779643
4779644 | 23 drieëntwintigste verdieping | Model Group:NLRS_21.21_WA_wand 001 d=300_gen:4779647
4779659 | 23 drieëntwintigste verdieping | Model Group:NLRS_21.21_WA_wand 002 d=300_gen:4779637
4779661 | 23 drieëntwintigste verdieping | Model Group:NLRS_21.21_WA_wand 002 d=300_gen:4779630
4779685 | 23 drieëntwintigste verdieping | Model Group:NLRS_21.21_WA_wand 004 d=300_gen:4779629
4779687 | 23 drieëntwintigste verdieping | Model Group:NLRS_21.21_WA_wand 004 d=300_gen:4779620
4779794 | 23 drieëntwintigste verdieping | Model Group:NLRS_28.21_WA_3D element 002 d=300_gen:4779809
4779796 | 23 drieëntwintigste verdieping | Model Group:NLRS_28.21_WA_3D element 002 d=300_gen:4779809
4779875 | 23 drieëntwintigste verdieping | Model Group:NLRS_28.21_WA_3D element 002 d=300_gen:4779793
4779877 | 23 drieëntwintigste verdieping | Model Group:NLRS_28.21_WA_3D element 002 d=300_gen:4779793
4779919 | 23 drieëntwintigste verdieping | Model Group:NLRS_28.21_WA_3D element 001 d=300_gen:4779792
4779922 | 23 drieëntwintigste verdieping | Model Group:NLRS_28.21_WA_3D element 001 d=300_gen:4779792
4779948 | 23 drieëntwintigste verdieping | Model Group:NLRS_28.21_WA_3D element 001 d=300_gen:4779810
4779951 | 23 drieëntwintigste verdieping | Model Group:NLRS_28.21_WA_3D element 001 d=300_gen:4779810
4783707 | 41 eenenveertigste verdieping | Model Group:NLRS_21.21_WA_wand 003 d=300_gen:4783756
4783709 | 41 eenenveertigste verdieping | Model Group:NLRS_21.21_WA_wand 001 d=300_gen:4783755
4783757 | 41 eenenveertigste verdieping | Model Group:NLRS_21.21_WA_wand 003 d=300_gen:4783760
4783761 | 41 eenenveertigste verdieping | Model Group:NLRS_21.21_WA_wand 001 d=300_gen:4783764
4783776 | 41 eenenveertigste verdieping | Model Group:NLRS_21.21_WA_wand 002 d=300_gen:4783754
4783778 | 41 eenenveertigste verdieping | Model Group:NLRS_21.21_WA_wand 002 d=300_gen:4783747
4783802 | 41 eenenveertigste verdieping | Model Group:NLRS_21.21_WA_wand 004 d=300_gen:4783746
4783804 | 41 eenenveertigste verdieping | Model Group:NLRS_21.21_WA_wand 004 d=300_gen:4783737
4783911 | 41 eenenveertigste verdieping | Model Group:NLRS_28.21_WA_3D element 002 d=300_gen:4783926
4783913 | 41 eenenveertigste verdieping | Model Group:NLRS_28.21_WA_3D element 002 d=300_gen:4783926
4783992 | 41 eenenveertigste verdieping | Model Group:NLRS_28.21_WA_3D element 002 d=300_gen:4783910
4783994 | 41 eenenveertigste verdieping | Model Group:NLRS_28.21_WA_3D element 002 d=300_gen:4783910
4784036 | 41 eenenveertigste verdieping | Model Group:NLRS_28.21_WA_3D element 001 d=300_gen:4783909
4784039 | 41 eenenveertigste verdieping | Model Group:NLRS_28.21_WA_3D element 001 d=300_gen:4783909
4784065 | 41 eenenveertigste verdieping | Model Group:NLRS_28.21_WA_3D element 001 d=300_gen:4783927
4784068 | 41 eenenveertigste verdieping | Model Group:NLRS_28.21_WA_3D element 001 d=300_gen:4783927
4788753 | 43 drieënveertigste verdieping | Model Group:NLRS_21.21_WA_wand 003 d=300_gen:4788802
4788755 | 43 drieënveertigste verdieping | Model Group:NLRS_21.21_WA_wand 001 d=300_gen:4788801
4788803 | 43 drieënveertigste verdieping | Model Group:NLRS_21.21_WA_wand 003 d=300_gen:4788806
4788807 | 43 drieënveertigste verdieping | Model Group:NLRS_21.21_WA_wand 001 d=300_gen:4788810
4788822 | 43 drieënveertigste verdieping | Model Group:NLRS_21.21_WA_wand 002 d=300_gen:4788800
4788824 | 43 drieënveertigste verdieping | Model Group:NLRS_21.21_WA_wand 002 d=300_gen:4788793
4788848 | 43 drieënveertigste verdieping | Model Group:NLRS_21.21_WA_wand 004 d=300_gen:4788792
4788850 | 43 drieënveertigste verdieping | Model Group:NLRS_21.21_WA_wand 004 d=300_gen:4788783
4788957 | 43 drieënveertigste verdieping | Model Group:NLRS_28.21_WA_3D element 002 d=300_gen:4788972
4788959 | 43 drieënveertigste verdieping | Model Group:NLRS_28.21_WA_3D element 002 d=300_gen:4788972
4789038 | 43 drieënveertigste verdieping | Model Group:NLRS_28.21_WA_3D element 002 d=300_gen:4788956
4789040 | 43 drieënveertigste verdieping | Model Group:NLRS_28.21_WA_3D element 002 d=300_gen:4788956
4789082 | 43 drieënveertigste verdieping | Model Group:NLRS_28.21_WA_3D element 001 d=300_gen:4788955
4789085 | 43 drieënveertigste verdieping | Model Group:NLRS_28.21_WA_3D element 001 d=300_gen:4788955
4789111 | 43 drieënveertigste verdieping | Model Group:NLRS_28.21_WA_3D element 001 d=300_gen:4788973
4789114 | 43 drieënveertigste verdieping | Model Group:NLRS_28.21_WA_3D element 001 d=300_gen:4788973
4789185 | 44 vierenveertigste verdieping | Model Group:NLRS_21.21_WA_wand 003 d=300_gen:4789234
4789187 | 44 vierenveertigste verdieping | Model Group:NLRS_21.21_WA_wand 001 d=300_gen:4789233
4789235 | 44 vierenveertigste verdieping | Model Group:NLRS_21.21_WA_wand 003 d=300_gen:4789238
4789239 | 44 vierenveertigste verdieping | Model Group:NLRS_21.21_WA_wand 001 d=300_gen:4789242
4789254 | 44 vierenveertigste verdieping | Model Group:NLRS_21.21_WA_wand 002 d=300_gen:4789232
4789256 | 44 vierenveertigste verdieping | Model Group:NLRS_21.21_WA_wand 002 d=300_gen:4789225
4789280 | 44 vierenveertigste verdieping | Model Group:NLRS_21.21_WA_wand 004 d=300_gen:4789224
4789282 | 44 vierenveertigste verdieping | Model Group:NLRS_21.21_WA_wand 004 d=300_gen:4789215
4789389 | 44 vierenveertigste verdieping | Model Group:NLRS_28.21_WA_3D element 002 d=300_gen:4789404
4789391 | 44 vierenveertigste verdieping | Model Group:NLRS_28.21_WA_3D element 002 d=300_gen:4789404
4789470 | 44 vierenveertigste verdieping | Model Group:NLRS_28.21_WA_3D element 002 d=300_gen:4789388
4789472 | 44 vierenveertigste verdieping | Model Group:NLRS_28.21_WA_3D element 002 d=300_gen:4789388
4789514 | 44 vierenveertigste verdieping | Model Group:NLRS_28.21_WA_3D element 001 d=300_gen:4789387
4789517 | 44 vierenveertigste verdieping | Model Group:NLRS_28.21_WA_3D element 001 d=300_gen:4789387
4789543 | 44 vierenveertigste verdieping | Model Group:NLRS_28.21_WA_3D element 001 d=300_gen:4789405
4789546 | 44 vierenveertigste verdieping | Model Group:NLRS_28.21_WA_3D element 001 d=300_gen:4789405
4789617 | 45 vijfenveertigste verdieping | Model Group:NLRS_21.21_WA_wand 003 d=300_gen:4789666
4789619 | 45 vijfenveertigste verdieping | Model Group:NLRS_21.21_WA_wand 001 d=300_gen:4789665
4789667 | 45 vijfenveertigste verdieping | Model Group:NLRS_21.21_WA_wand 003 d=300_gen:4789670
4789671 | 45 vijfenveertigste verdieping | Model Group:NLRS_21.21_WA_wand 001 d=300_gen:4789674
4789686 | 45 vijfenveertigste verdieping | Model Group:NLRS_21.21_WA_wand 002 d=300_gen:4789664
4789688 | 45 vijfenveertigste verdieping | Model Group:NLRS_21.21_WA_wand 002 d=300_gen:4789657
4789712 | 45 vijfenveertigste verdieping | Model Group:NLRS_21.21_WA_wand 004 d=300_gen:4789656
4789714 | 45 vijfenveertigste verdieping | Model Group:NLRS_21.21_WA_wand 004 d=300_gen:4789647
4789821 | 45 vijfenveertigste verdieping | Model Group:NLRS_28.21_WA_3D element 002 d=300_gen:4789836
4789823 | 45 vijfenveertigste verdieping | Model Group:NLRS_28.21_WA_3D element 002 d=300_gen:4789836
4789902 | 45 vijfenveertigste verdieping | Model Group:NLRS_28.21_WA_3D element 002 d=300_gen:4789820
4789904 | 45 vijfenveertigste verdieping | Model Group:NLRS_28.21_WA_3D element 002 d=300_gen:4789820
4789946 | 45 vijfenveertigste verdieping | Model Group:NLRS_28.21_WA_3D element 001 d=300_gen:4789819
4789949 | 45 vijfenveertigste verdieping | Model Group:NLRS_28.21_WA_3D element 001 d=300_gen:4789819
4789975 | 45 vijfenveertigste verdieping | Model Group:NLRS_28.21_WA_3D element 001 d=300_gen:4789837
4789978 | 45 vijfenveertigste verdieping | Model Group:NLRS_28.21_WA_3D element 001 d=300_gen:4789837
4790049 | 46 zesenveertigste verdieping | Model Group:NLRS_21.21_WA_wand 003 d=300_gen:4790098
4790051 | 46 zesenveertigste verdieping | Model Group:NLRS_21.21_WA_wand 001 d=300_gen:4790097
4790099 | 46 zesenveertigste verdieping | Model Group:NLRS_21.21_WA_wand 003 d=300_gen:4790102
4790103 | 46 zesenveertigste verdieping | Model Group:NLRS_21.21_WA_wand 001 d=300_gen:4790106
4790118 | 46 zesenveertigste verdieping | Model Group:NLRS_21.21_WA_wand 002 d=300_gen:4790096
4790120 | 46 zesenveertigste verdieping | Model Group:NLRS_21.21_WA_wand 002 d=300_gen:4790089
4790144 | 46 zesenveertigste verdieping | Model Group:NLRS_21.21_WA_wand 004 d=300_gen:4790088
4790146 | 46 zesenveertigste verdieping | Model Group:NLRS_21.21_WA_wand 004 d=300_gen:4790079
4790253 | 46 zesenveertigste verdieping | Model Group:NLRS_28.21_WA_3D element 002 d=300_gen:4790268
4790255 | 46 zesenveertigste verdieping | Model Group:NLRS_28.21_WA_3D element 002 d=300_gen:4790268
4790334 | 46 zesenveertigste verdieping | Model Group:NLRS_28.21_WA_3D element 002 d=300_gen:4790252
4790336 | 46 zesenveertigste verdieping | Model Group:NLRS_28.21_WA_3D element 002 d=300_gen:4790252
4790378 | 46 zesenveertigste verdieping | Model Group:NLRS_28.21_WA_3D element 001 d=300_gen:4790251
4790381 | 46 zesenveertigste verdieping | Model Group:NLRS_28.21_WA_3D element 001 d=300_gen:4790251
4790407 | 46 zesenveertigste verdieping | Model Group:NLRS_28.21_WA_3D element 001 d=300_gen:4790269
4790410 | 46 zesenveertigste verdieping | Model Group:NLRS_28.21_WA_3D element 001 d=300_gen:4790269
4790481 | 47 zevenenveertigste verdieping | Model Group:NLRS_21.21_WA_wand 003 d=300_gen:4790530
4790483 | 47 zevenenveertigste verdieping | Model Group:NLRS_21.21_WA_wand 001 d=300_gen:4790529
4790531 | 47 zevenenveertigste verdieping | Model Group:NLRS_21.21_WA_wand 003 d=300_gen:4790534
4790535 | 47 zevenenveertigste verdieping | Model Group:NLRS_21.21_WA_wand 001 d=300_gen:4790538
4790550 | 47 zevenenveertigste verdieping | Model Group:NLRS_21.21_WA_wand 002 d=300_gen:4790528
4790552 | 47 zevenenveertigste verdieping | Model Group:NLRS_21.21_WA_wand 002 d=300_gen:4790521
4790576 | 47 zevenenveertigste verdieping | Model Group:NLRS_21.21_WA_wand 004 d=300_gen:4790520
4790578 | 47 zevenenveertigste verdieping | Model Group:NLRS_21.21_WA_wand 004 d=300_gen:4790511
4790685 | 47 zevenenveertigste verdieping | Model Group:NLRS_28.21_WA_3D element 002 d=300_gen:4790700
4790687 | 47 zevenenveertigste verdieping | Model Group:NLRS_28.21_WA_3D element 002 d=300_gen:4790700
4790766 | 47 zevenenveertigste verdieping | Model Group:NLRS_28.21_WA_3D element 002 d=300_gen:4790684
4790768 | 47 zevenenveertigste verdieping | Model Group:NLRS_28.21_WA_3D element 002 d=300_gen:4790684
4790810 | 47 zevenenveertigste verdieping | Model Group:NLRS_28.21_WA_3D element 001 d=300_gen:4790683
4790813 | 47 zevenenveertigste verdieping | Model Group:NLRS_28.21_WA_3D element 001 d=300_gen:4790683
4790839 | 47 zevenenveertigste verdieping | Model Group:NLRS_28.21_WA_3D element 001 d=300_gen:4790701
4790842 | 47 zevenenveertigste verdieping | Model Group:NLRS_28.21_WA_3D element 001 d=300_gen:4790701
4790913 | 48 achtenveertigste verdieping | Model Group:NLRS_21.21_WA_wand 003 d=300_gen:4790962
4790915 | 48 achtenveertigste verdieping | Model Group:NLRS_21.21_WA_wand 001 d=300_gen:4790961
4790963 | 48 achtenveertigste verdieping | Model Group:NLRS_21.21_WA_wand 003 d=300_gen:4790966
4790967 | 48 achtenveertigste verdieping | Model Group:NLRS_21.21_WA_wand 001 d=300_gen:4790970
4790982 | 48 achtenveertigste verdieping | Model Group:NLRS_21.21_WA_wand 002 d=300_gen:4790960
4790984 | 48 achtenveertigste verdieping | Model Group:NLRS_21.21_WA_wand 002 d=300_gen:4790953
4791008 | 48 achtenveertigste verdieping | Model Group:NLRS_21.21_WA_wand 004 d=300_gen:4790952
4791010 | 48 achtenveertigste verdieping | Model Group:NLRS_21.21_WA_wand 004 d=300_gen:4790943
4791117 | 48 achtenveertigste verdieping | Model Group:NLRS_28.21_WA_3D element 002 d=300_gen:4791132
4791119 | 48 achtenveertigste verdieping | Model Group:NLRS_28.21_WA_3D element 002 d=300_gen:4791132
4791198 | 48 achtenveertigste verdieping | Model Group:NLRS_28.21_WA_3D element 002 d=300_gen:4791116
4791200 | 48 achtenveertigste verdieping | Model Group:NLRS_28.21_WA_3D element 002 d=300_gen:4791116
4791242 | 48 achtenveertigste verdieping | Model Group:NLRS_28.21_WA_3D element 001 d=300_gen:4791115
4791245 | 48 achtenveertigste verdieping | Model Group:NLRS_28.21_WA_3D element 001 d=300_gen:4791115
4791271 | 48 achtenveertigste verdieping | Model Group:NLRS_28.21_WA_3D element 001 d=300_gen:4791133
4791274 | 48 achtenveertigste verdieping | Model Group:NLRS_28.21_WA_3D element 001 d=300_gen:4791133
4791345 | 49 negenenveertigste verdieping | Model Group:NLRS_21.21_WA_wand 003 d=300_gen:4791394
4791347 | 49 negenenveertigste verdieping | Model Group:NLRS_21.21_WA_wand 001 d=300_gen:4791393
4791395 | 49 negenenveertigste verdieping | Model Group:NLRS_21.21_WA_wand 003 d=300_gen:4791398
4791399 | 49 negenenveertigste verdieping | Model Group:NLRS_21.21_WA_wand 001 d=300_gen:4791402
4791414 | 49 negenenveertigste verdieping | Model Group:NLRS_21.21_WA_wand 002 d=300_gen:4791392
4791416 | 49 negenenveertigste verdieping | Model Group:NLRS_21.21_WA_wand 002 d=300_gen:4791385
4791440 | 49 negenenveertigste verdieping | Model Group:NLRS_21.21_WA_wand 004 d=300_gen:4791384
4791442 | 49 negenenveertigste verdieping | Model Group:NLRS_21.21_WA_wand 004 d=300_gen:4791375
4791549 | 49 negenenveertigste verdieping | Model Group:NLRS_28.21_WA_3D element 002 d=300_gen:4791564
4791551 | 49 negenenveertigste verdieping | Model Group:NLRS_28.21_WA_3D element 002 d=300_gen:4791564
4791630 | 49 negenenveertigste verdieping | Model Group:NLRS_28.21_WA_3D element 002 d=300_gen:4791548
4791632 | 49 negenenveertigste verdieping | Model Group:NLRS_28.21_WA_3D element 002 d=300_gen:4791548
4791674 | 49 negenenveertigste verdieping | Model Group:NLRS_28.21_WA_3D element 001 d=300_gen:4791547
4791677 | 49 negenenveertigste verdieping | Model Group:NLRS_28.21_WA_3D element 001 d=300_gen:4791547
4791703 | 49 negenenveertigste verdieping | Model Group:NLRS_28.21_WA_3D element 001 d=300_gen:4791565
4791706 | 49 negenenveertigste verdieping | Model Group:NLRS_28.21_WA_3D element 001 d=300_gen:4791565
4791777 | 50 vijftigste verdieping | Model Group:NLRS_21.21_WA_wand 003 d=300_gen:4791826
4791779 | 50 vijftigste verdieping | Model Group:NLRS_21.21_WA_wand 001 d=300_gen:4791825
4791827 | 50 vijftigste verdieping | Model Group:NLRS_21.21_WA_wand 003 d=300_gen:4791830
4791831 | 50 vijftigste verdieping | Model Group:NLRS_21.21_WA_wand 001 d=300_gen:4791834
4791846 | 50 vijftigste verdieping | Model Group:NLRS_21.21_WA_wand 002 d=300_gen:4791824
4791848 | 50 vijftigste verdieping | Model Group:NLRS_21.21_WA_wand 002 d=300_gen:4791817
4791872 | 50 vijftigste verdieping | Model Group:NLRS_21.21_WA_wand 004 d=300_gen:4791816
4791874 | 50 vijftigste verdieping | Model Group:NLRS_21.21_WA_wand 004 d=300_gen:4791807
4791981 | 50 vijftigste verdieping | Model Group:NLRS_28.21_WA_3D element 002 d=300_gen:4791996
4791983 | 50 vijftigste verdieping | Model Group:NLRS_28.21_WA_3D element 002 d=300_gen:4791996
4792062 | 50 vijftigste verdieping | Model Group:NLRS_28.21_WA_3D element 002 d=300_gen:4791980
4792064 | 50 vijftigste verdieping | Model Group:NLRS_28.21_WA_3D element 002 d=300_gen:4791980
4792106 | 50 vijftigste verdieping | Model Group:NLRS_28.21_WA_3D element 001 d=300_gen:4791979
4792109 | 50 vijftigste verdieping | Model Group:NLRS_28.21_WA_3D element 001 d=300_gen:4791979
4792135 | 50 vijftigste verdieping | Model Group:NLRS_28.21_WA_3D element 001 d=300_gen:4791997
4792138 | 50 vijftigste verdieping | Model Group:NLRS_28.21_WA_3D element 001 d=300_gen:4791997
4803226 | 42 tweeënveertigste verdieping | Model Group:NLRS_21.21_WA_wand 003 d=300_gen:4803275
4803228 | 42 tweeënveertigste verdieping | Model Group:NLRS_21.21_WA_wand 001 d=300_gen:4803274
4803276 | 42 tweeënveertigste verdieping | Model Group:NLRS_21.21_WA_wand 003 d=300_gen:4803279
4803280 | 42 tweeënveertigste verdieping | Model Group:NLRS_21.21_WA_wand 001 d=300_gen:4803283
4803295 | 42 tweeënveertigste verdieping | Model Group:NLRS_21.21_WA_wand 002 d=300_gen:4803273
4803297 | 42 tweeënveertigste verdieping | Model Group:NLRS_21.21_WA_wand 002 d=300_gen:4803266
4803321 | 42 tweeënveertigste verdieping | Model Group:NLRS_21.21_WA_wand 004 d=300_gen:4803265
4803323 | 42 tweeënveertigste verdieping | Model Group:NLRS_21.21_WA_wand 004 d=300_gen:4803256
4803430 | 42 tweeënveertigste verdieping | Model Group:NLRS_28.21_WA_3D element 002 d=300_gen:4803445
4803432 | 42 tweeënveertigste verdieping | Model Group:NLRS_28.21_WA_3D element 002 d=300_gen:4803445
4803511 | 42 tweeënveertigste verdieping | Model Group:NLRS_28.21_WA_3D element 002 d=300_gen:4803429
4803513 | 42 tweeënveertigste verdieping | Model Group:NLRS_28.21_WA_3D element 002 d=300_gen:4803429
4803555 | 42 tweeënveertigste verdieping | Model Group:NLRS_28.21_WA_3D element 001 d=300_gen:4803428
4803558 | 42 tweeënveertigste verdieping | Model Group:NLRS_28.21_WA_3D element 001 d=300_gen:4803428
4803584 | 42 tweeënveertigste verdieping | Model Group:NLRS_28.21_WA_3D element 001 d=300_gen:4803446
4803587 | 42 tweeënveertigste verdieping | Model Group:NLRS_28.21_WA_3D element 001 d=300_gen:4803446
4980029 | 51 eenenvijftigste verdieping | Model Group:NLRS_21.21_WA_wand 002 d=300_gen:4980007
4980031 | 51 eenenvijftigste verdieping | Model Group:NLRS_21.21_WA_wand 002 d=300_gen:4980000
4980055 | 51 eenenvijftigste verdieping | Model Group:NLRS_21.21_WA_wand 004 d=300_gen:4979999
4980057 | 51 eenenvijftigste verdieping | Model Group:NLRS_21.21_WA_wand 004 d=300_gen:4979990
4980148 | 51 eenenvijftigste verdieping | Model Group:NLRS_28.21_WA_3D element 002 d=300_gen:4980163
4980150 | 51 eenenvijftigste verdieping | Model Group:NLRS_28.21_WA_3D element 002 d=300_gen:4980163
4980221 | 51 eenenvijftigste verdieping | Model Group:NLRS_28.21_WA_3D element 002 d=300_gen:4980147
4980223 | 51 eenenvijftigste verdieping | Model Group:NLRS_28.21_WA_3D element 002 d=300_gen:4980147
4980265 | 51 eenenvijftigste verdieping | Model Group:NLRS_28.21_WA_3D element 001 d=300_gen:4980146
4980268 | 51 eenenvijftigste verdieping | Model Group:NLRS_28.21_WA_3D element 001 d=300_gen:4980146
4980294 | 51 eenenvijftigste verdieping | Model Group:NLRS_28.21_WA_3D element 001 d=300_gen:4980164
4980297 | 51 eenenvijftigste verdieping | Model Group:NLRS_28.21_WA_3D element 001 d=300_gen:4980164
4981801 | 52 tweeënvijftigste verdieping | Model Group:NLRS_21.21_WA_wand 002c d=300_gen:4981779
4981803 | 52 tweeënvijftigste verdieping | Model Group:NLRS_21.21_WA_wand 002c d=300_gen:4981772
4981827 | 52 tweeënvijftigste verdieping | Model Group:NLRS_21.21_WA_wand 004c d=300_gen:4981771
4981829 | 52 tweeënvijftigste verdieping | Model Group:NLRS_21.21_WA_wand 004c d=300_gen:4981762
4981993 | 52 tweeënvijftigste verdieping | Model Group:NLRS_28.21_WA_3D element 002a d=300_gen:4981919
4981995 | 52 tweeënvijftigste verdieping | Model Group:NLRS_28.21_WA_3D element 002a d=300_gen:4981919
4982037 | 52 tweeënvijftigste verdieping | Model Group:NLRS_28.21_WA_3D element 001a d=300_gen:4981918
4982040 | 52 tweeënvijftigste verdieping | Model Group:NLRS_28.21_WA_3D element 001a d=300_gen:4981918
5043322 | 52 tweeënvijftigste verdieping | Model Group:NLRS_28.21_WA_3D element 002a d=300_gen:4981935
5043324 | 52 tweeënvijftigste verdieping | Model Group:NLRS_28.21_WA_3D element 002a d=300_gen:4981935
5044687 | 52 tweeënvijftigste verdieping | Model Group:NLRS_28.21_WA_3D element 001a d=300_gen:4981936
5044690 | 52 tweeënvijftigste verdieping | Model Group:NLRS_28.21_WA_3D element 001a d=300_gen:4981936
5450716 | 21 eenentwintigste verdieping | Model Group:NLRS_21.21_WA_wand 004 d=300_gen:4695016
5450723 | 21 eenentwintigste verdieping | Model Group:NLRS_21.21_WA_wand 004 d=300_gen:4695025
5450800 | 15 vijftiende verdieping | Model Group:NLRS_21.21_WA_wand 004 d=300_gen:4731097
5450807 | 15 vijftiende verdieping | Model Group:NLRS_21.21_WA_wand 004 d=300_gen:4731106
5450814 | 17 zeventiende verdieping | Model Group:NLRS_21.21_WA_wand 004 d=300_gen:4731555
5450821 | 17 zeventiende verdieping | Model Group:NLRS_21.21_WA_wand 004 d=300_gen:4731564
5450828 | 19 negentiende verdieping | Model Group:NLRS_21.21_WA_wand 004 d=300_gen:4732013
5450835 | 19 negentiende verdieping | Model Group:NLRS_21.21_WA_wand 004 d=300_gen:4732022
5450870 | 16 zestiende verdieping | Model Group:NLRS_21.21_WA_wand 004 d=300_gen:4739142
5450877 | 16 zestiende verdieping | Model Group:NLRS_21.21_WA_wand 004 d=300_gen:4739151
5450884 | 18 achttiende verdieping | Model Group:NLRS_21.21_WA_wand 004 d=300_gen:4739600
5450891 | 18 achttiende verdieping | Model Group:NLRS_21.21_WA_wand 004 d=300_gen:4739609
5450898 | 20 twintigste verdieping | Model Group:NLRS_21.21_WA_wand 004 d=300_gen:4740058
5450905 | 20 twintigste verdieping | Model Group:NLRS_21.21_WA_wand 004 d=300_gen:4740067
5450912 | 24 vierentwintigste verdieping | Model Group:NLRS_21.21_WA_wand 004 d=300_gen:4746657
5450919 | 24 vierentwintigste verdieping | Model Group:NLRS_21.21_WA_wand 004 d=300_gen:4746666
5450926 | 25 vijfentwintigste verdieping | Model Group:NLRS_21.21_WA_wand 004 d=300_gen:4747089
5450933 | 25 vijfentwintigste verdieping | Model Group:NLRS_21.21_WA_wand 004 d=300_gen:4747098
5450940 | 26 zesentwintigste verdieping | Model Group:NLRS_21.21_WA_wand 004 d=300_gen:4747521
5450947 | 26 zesentwintigste verdieping | Model Group:NLRS_21.21_WA_wand 004 d=300_gen:4747530
5450954 | 27 zevenentwintigste verdieping | Model Group:NLRS_21.21_WA_wand 004 d=300_gen:4747953
5450961 | 27 zevenentwintigste verdieping | Model Group:NLRS_21.21_WA_wand 004 d=300_gen:4747962
5450968 | 28 achtentwintigste verdieping | Model Group:NLRS_21.21_WA_wand 004 d=300_gen:4748385
5450975 | 28 achtentwintigste verdieping | Model Group:NLRS_21.21_WA_wand 004 d=300_gen:4748394
5450982 | 29 negenentwintigste verdieping | Model Group:NLRS_21.21_WA_wand 004 d=300_gen:4748817
5450989 | 29 negenentwintigste verdieping | Model Group:NLRS_21.21_WA_wand 004 d=300_gen:4748826
5450996 | 30 dertigste verdieping | Model Group:NLRS_21.21_WA_wand 004 d=300_gen:4749249
5451003 | 30 dertigste verdieping | Model Group:NLRS_21.21_WA_wand 004 d=300_gen:4749258
5451010 | 31 eenendertigste verdieping | Model Group:NLRS_21.21_WA_wand 004 d=300_gen:4749681
5451017 | 31 eenendertigste verdieping | Model Group:NLRS_21.21_WA_wand 004 d=300_gen:4749690
5451024 | 32 tweeëndertigste verdieping | Model Group:NLRS_21.21_WA_wand 004 d=300_gen:4750113
5451031 | 32 tweeëndertigste verdieping | Model Group:NLRS_21.21_WA_wand 004 d=300_gen:4750122
5451038 | 33 drieëndertigste verdieping | Model Group:NLRS_21.21_WA_wand 004 d=300_gen:4750545
5451045 | 33 drieëndertigste verdieping | Model Group:NLRS_21.21_WA_wand 004 d=300_gen:4750554
5451052 | 34 vierendertigste verdieping | Model Group:NLRS_21.21_WA_wand 004 d=300_gen:4750977
5451059 | 34 vierendertigste verdieping | Model Group:NLRS_21.21_WA_wand 004 d=300_gen:4750986
5451066 | 35 vijfendertigste verdieping | Model Group:NLRS_21.21_WA_wand 004 d=300_gen:4751409
5451073 | 35 vijfendertigste verdieping | Model Group:NLRS_21.21_WA_wand 004 d=300_gen:4751418
5451080 | 36 zesendertigste verdieping | Model Group:NLRS_21.21_WA_wand 004 d=300_gen:4751841
5451087 | 36 zesendertigste verdieping | Model Group:NLRS_21.21_WA_wand 004 d=300_gen:4751850
5451094 | 37 zevenendertigste verdieping | Model Group:NLRS_21.21_WA_wand 004 d=300_gen:4752273
5451101 | 37 zevenendertigste verdieping | Model Group:NLRS_21.21_WA_wand 004 d=300_gen:4752282
5451108 | 38 achtendertigste verdieping | Model Group:NLRS_21.21_WA_wand 004 d=300_gen:4752705
5451115 | 38 achtendertigste verdieping | Model Group:NLRS_21.21_WA_wand 004 d=300_gen:4752714
5451122 | 39 negenendertigste verdieping | Model Group:NLRS_21.21_WA_wand 004 d=300_gen:4753137
5451129 | 39 negenendertigste verdieping | Model Group:NLRS_21.21_WA_wand 004 d=300_gen:4753146
5451136 | 40 veertigste verdieping | Model Group:NLRS_21.21_WA_wand 004 d=300_gen:4753569
5451143 | 40 veertigste verdieping | Model Group:NLRS_21.21_WA_wand 004 d=300_gen:4753578
5451150 | 22 tweeëntwintigste verdieping | Model Group:NLRS_21.21_WA_wand 004 d=300_gen:4778037
5451157 | 22 tweeëntwintigste verdieping | Model Group:NLRS_21.21_WA_wand 004 d=300_gen:4778046
5451164 | 23 drieëntwintigste verdieping | Model Group:NLRS_21.21_WA_wand 004 d=300_gen:4779620
5451171 | 23 drieëntwintigste verdieping | Model Group:NLRS_21.21_WA_wand 004 d=300_gen:4779629
5451178 | 41 eenenveertigste verdieping | Model Group:NLRS_21.21_WA_wand 004 d=300_gen:4783737
5451185 | 41 eenenveertigste verdieping | Model Group:NLRS_21.21_WA_wand 004 d=300_gen:4783746
5451206 | 43 drieënveertigste verdieping | Model Group:NLRS_21.21_WA_wand 004 d=300_gen:4788783
5451213 | 43 drieënveertigste verdieping | Model Group:NLRS_21.21_WA_wand 004 d=300_gen:4788792
5451220 | 44 vierenveertigste verdieping | Model Group:NLRS_21.21_WA_wand 004 d=300_gen:4789215
5451227 | 44 vierenveertigste verdieping | Model Group:NLRS_21.21_WA_wand 004 d=300_gen:4789224
5451234 | 45 vijfenveertigste verdieping | Model Group:NLRS_21.21_WA_wand 004 d=300_gen:4789647
5451241 | 45 vijfenveertigste verdieping | Model Group:NLRS_21.21_WA_wand 004 d=300_gen:4789656
5451248 | 46 zesenveertigste verdieping | Model Group:NLRS_21.21_WA_wand 004 d=300_gen:4790079
5451255 | 46 zesenveertigste verdieping | Model Group:NLRS_21.21_WA_wand 004 d=300_gen:4790088
5451262 | 47 zevenenveertigste verdieping | Model Group:NLRS_21.21_WA_wand 004 d=300_gen:4790511
5451269 | 47 zevenenveertigste verdieping | Model Group:NLRS_21.21_WA_wand 004 d=300_gen:4790520
5451276 | 48 achtenveertigste verdieping | Model Group:NLRS_21.21_WA_wand 004 d=300_gen:4790943
5451283 | 48 achtenveertigste verdieping | Model Group:NLRS_21.21_WA_wand 004 d=300_gen:4790952
5451290 | 49 negenenveertigste verdieping | Model Group:NLRS_21.21_WA_wand 004 d=300_gen:4791375
5451297 | 49 negenenveertigste verdieping | Model Group:NLRS_21.21_WA_wand 004 d=300_gen:4791384
5451304 | 50 vijftigste verdieping | Model Group:NLRS_21.21_WA_wand 004 d=300_gen:4791807
5451311 | 50 vijftigste verdieping | Model Group:NLRS_21.21_WA_wand 004 d=300_gen:4791816
5451318 | 42 tweeënveertigste verdieping | Model Group:NLRS_21.21_WA_wand 004 d=300_gen:4803256
5451325 | 42 tweeënveertigste verdieping | Model Group:NLRS_21.21_WA_wand 004 d=300_gen:4803265
5451346 | 51 eenenvijftigste verdieping | Model Group:NLRS_21.21_WA_wand 004 d=300_gen:4979990
5451353 | 51 eenenvijftigste verdieping | Model Group:NLRS_21.21_WA_wand 004 d=300_gen:4979999
5482909 | 21 eenentwintigste verdieping | Model Group:NLRS_21.21_WA_wand 002 d=300_gen:4695026
5482915 | 21 eenentwintigste verdieping | Model Group:NLRS_21.21_WA_wand 002 d=300_gen:4695033
5482987 | 15 vijftiende verdieping | Model Group:NLRS_21.21_WA_wand 002 d=300_gen:4731114
5482999 | 17 zeventiende verdieping | Model Group:NLRS_21.21_WA_wand 002 d=300_gen:4731572
5483011 | 19 negentiende verdieping | Model Group:NLRS_21.21_WA_wand 002 d=300_gen:4732030
5483041 | 16 zestiende verdieping | Model Group:NLRS_21.21_WA_wand 002 d=300_gen:4739152
5483047 | 16 zestiende verdieping | Model Group:NLRS_21.21_WA_wand 002 d=300_gen:4739159
5483053 | 18 achttiende verdieping | Model Group:NLRS_21.21_WA_wand 002 d=300_gen:4739610
5483059 | 18 achttiende verdieping | Model Group:NLRS_21.21_WA_wand 002 d=300_gen:4739617
5483065 | 20 twintigste verdieping | Model Group:NLRS_21.21_WA_wand 002 d=300_gen:4740068
5483071 | 20 twintigste verdieping | Model Group:NLRS_21.21_WA_wand 002 d=300_gen:4740075
5483077 | 24 vierentwintigste verdieping | Model Group:NLRS_21.21_WA_wand 002 d=300_gen:4746667
5483083 | 24 vierentwintigste verdieping | Model Group:NLRS_21.21_WA_wand 002 d=300_gen:4746674
5483089 | 25 vijfentwintigste verdieping | Model Group:NLRS_21.21_WA_wand 002 d=300_gen:4747099
5483095 | 25 vijfentwintigste verdieping | Model Group:NLRS_21.21_WA_wand 002 d=300_gen:4747106
5483101 | 26 zesentwintigste verdieping | Model Group:NLRS_21.21_WA_wand 002 d=300_gen:4747531
5483107 | 26 zesentwintigste verdieping | Model Group:NLRS_21.21_WA_wand 002 d=300_gen:4747538
5483113 | 27 zevenentwintigste verdieping | Model Group:NLRS_21.21_WA_wand 002 d=300_gen:4747963
5483119 | 27 zevenentwintigste verdieping | Model Group:NLRS_21.21_WA_wand 002 d=300_gen:4747970
5483125 | 28 achtentwintigste verdieping | Model Group:NLRS_21.21_WA_wand 002 d=300_gen:4748395
5483131 | 28 achtentwintigste verdieping | Model Group:NLRS_21.21_WA_wand 002 d=300_gen:4748402
5483137 | 29 negenentwintigste verdieping | Model Group:NLRS_21.21_WA_wand 002 d=300_gen:4748827
5483143 | 29 negenentwintigste verdieping | Model Group:NLRS_21.21_WA_wand 002 d=300_gen:4748834
5483149 | 30 dertigste verdieping | Model Group:NLRS_21.21_WA_wand 002 d=300_gen:4749259
5483155 | 30 dertigste verdieping | Model Group:NLRS_21.21_WA_wand 002 d=300_gen:4749266
5483161 | 31 eenendertigste verdieping | Model Group:NLRS_21.21_WA_wand 002 d=300_gen:4749691
5483167 | 31 eenendertigste verdieping | Model Group:NLRS_21.21_WA_wand 002 d=300_gen:4749698
5483173 | 32 tweeëndertigste verdieping | Model Group:NLRS_21.21_WA_wand 002 d=300_gen:4750123
5483179 | 32 tweeëndertigste verdieping | Model Group:NLRS_21.21_WA_wand 002 d=300_gen:4750130
5483185 | 33 drieëndertigste verdieping | Model Group:NLRS_21.21_WA_wand 002 d=300_gen:4750555
5483191 | 33 drieëndertigste verdieping | Model Group:NLRS_21.21_WA_wand 002 d=300_gen:4750562
5483197 | 34 vierendertigste verdieping | Model Group:NLRS_21.21_WA_wand 002 d=300_gen:4750987
5483203 | 34 vierendertigste verdieping | Model Group:NLRS_21.21_WA_wand 002 d=300_gen:4750994
5483209 | 35 vijfendertigste verdieping | Model Group:NLRS_21.21_WA_wand 002 d=300_gen:4751419
5483215 | 35 vijfendertigste verdieping | Model Group:NLRS_21.21_WA_wand 002 d=300_gen:4751426
5483221 | 36 zesendertigste verdieping | Model Group:NLRS_21.21_WA_wand 002 d=300_gen:4751851
5483227 | 36 zesendertigste verdieping | Model Group:NLRS_21.21_WA_wand 002 d=300_gen:4751858
5483233 | 37 zevenendertigste verdieping | Model Group:NLRS_21.21_WA_wand 002 d=300_gen:4752283
5483239 | 37 zevenendertigste verdieping | Model Group:NLRS_21.21_WA_wand 002 d=300_gen:4752290
5483245 | 38 achtendertigste verdieping | Model Group:NLRS_21.21_WA_wand 002 d=300_gen:4752715
5483251 | 38 achtendertigste verdieping | Model Group:NLRS_21.21_WA_wand 002 d=300_gen:4752722
5483257 | 39 negenendertigste verdieping | Model Group:NLRS_21.21_WA_wand 002 d=300_gen:4753147
5483263 | 39 negenendertigste verdieping | Model Group:NLRS_21.21_WA_wand 002 d=300_gen:4753154
5483269 | 40 veertigste verdieping | Model Group:NLRS_21.21_WA_wand 002 d=300_gen:4753579
5483275 | 40 veertigste verdieping | Model Group:NLRS_21.21_WA_wand 002 d=300_gen:4753586
5483281 | 22 tweeëntwintigste verdieping | Model Group:NLRS_21.21_WA_wand 002 d=300_gen:4778047
5483287 | 22 tweeëntwintigste verdieping | Model Group:NLRS_21.21_WA_wand 002 d=300_gen:4778054
5483293 | 23 drieëntwintigste verdieping | Model Group:NLRS_21.21_WA_wand 002 d=300_gen:4779630
5483299 | 23 drieëntwintigste verdieping | Model Group:NLRS_21.21_WA_wand 002 d=300_gen:4779637
5483305 | 41 eenenveertigste verdieping | Model Group:NLRS_21.21_WA_wand 002 d=300_gen:4783747
5483311 | 41 eenenveertigste verdieping | Model Group:NLRS_21.21_WA_wand 002 d=300_gen:4783754
5483329 | 43 drieënveertigste verdieping | Model Group:NLRS_21.21_WA_wand 002 d=300_gen:4788793
5483335 | 43 drieënveertigste verdieping | Model Group:NLRS_21.21_WA_wand 002 d=300_gen:4788800
5483341 | 44 vierenveertigste verdieping | Model Group:NLRS_21.21_WA_wand 002 d=300_gen:4789225
5483347 | 44 vierenveertigste verdieping | Model Group:NLRS_21.21_WA_wand 002 d=300_gen:4789232
5483353 | 45 vijfenveertigste verdieping | Model Group:NLRS_21.21_WA_wand 002 d=300_gen:4789657
5483359 | 45 vijfenveertigste verdieping | Model Group:NLRS_21.21_WA_wand 002 d=300_gen:4789664
5483365 | 46 zesenveertigste verdieping | Model Group:NLRS_21.21_WA_wand 002 d=300_gen:4790089
5483371 | 46 zesenveertigste verdieping | Model Group:NLRS_21.21_WA_wand 002 d=300_gen:4790096
5483377 | 47 zevenenveertigste verdieping | Model Group:NLRS_21.21_WA_wand 002 d=300_gen:4790521
5483383 | 47 zevenenveertigste verdieping | Model Group:NLRS_21.21_WA_wand 002 d=300_gen:4790528
5483389 | 48 achtenveertigste verdieping | Model Group:NLRS_21.21_WA_wand 002 d=300_gen:4790953
5483395 | 48 achtenveertigste verdieping | Model Group:NLRS_21.21_WA_wand 002 d=300_gen:4790960
5483401 | 49 negenenveertigste verdieping | Model Group:NLRS_21.21_WA_wand 002 d=300_gen:4791385
5483407 | 49 negenenveertigste verdieping | Model Group:NLRS_21.21_WA_wand 002 d=300_gen:4791392
5483413 | 50 vijftigste verdieping | Model Group:NLRS_21.21_WA_wand 002 d=300_gen:4791817
5483419 | 50 vijftigste verdieping | Model Group:NLRS_21.21_WA_wand 002 d=300_gen:4791824
5483425 | 42 tweeënveertigste verdieping | Model Group:NLRS_21.21_WA_wand 002 d=300_gen:4803266
5483431 | 42 tweeënveertigste verdieping | Model Group:NLRS_21.21_WA_wand 002 d=300_gen:4803273
5483449 | 51 eenenvijftigste verdieping | Model Group:NLRS_21.21_WA_wand 002 d=300_gen:4980000
5483455 | 51 eenenvijftigste verdieping | Model Group:NLRS_21.21_WA_wand 002 d=300_gen:4980007
5509183 | 15 vijftiende verdieping | Model Group:NLRS_21.21_WA_wand 002 d=300_gen:5509182
5509188 | 15 vijftiende verdieping | Model Group:NLRS_21.21_WA_wand 002 d=300_gen:5509182
5509201 | 17 zeventiende verdieping | Model Group:NLRS_21.21_WA_wand 002 d=300_gen:5509200
5509206 | 17 zeventiende verdieping | Model Group:NLRS_21.21_WA_wand 002 d=300_gen:5509200
5509219 | 19 negentiende verdieping | Model Group:NLRS_21.21_WA_wand 002 d=300_gen:5509218
5509224 | 19 negentiende verdieping | Model Group:NLRS_21.21_WA_wand 002 d=300_gen:5509218
5528547 | 52 tweeënvijftigste verdieping | Model Group:NLRS_21.21_WA_wand 004c d=300_gen:4981762
5528784 | 52 tweeënvijftigste verdieping | Model Group:NLRS_21.21_WA_wand 004c d=300_gen:4981771
5529195 | 52 tweeënvijftigste verdieping | Model Group:NLRS_21.21_WA_wand 002c d=300_gen:4981772
5529401 | 52 tweeënvijftigste verdieping | Model Group:NLRS_21.21_WA_wand 002c d=300_gen:4981779
5667282 | 09 negende verdieping | Model Group:NLRS_21.21_WA_wand 003 d=300_gen:5667325
5667284 | 09 negende verdieping | Model Group:NLRS_21.21_WA_wand 001 d=300_gen:5667324
5667326 | 09 negende verdieping | Model Group:NLRS_21.21_WA_wand 003 d=300_gen:5667329
5667330 | 09 negende verdieping | Model Group:NLRS_21.21_WA_wand 001 d=300_gen:5667333
5667334 | 09 negende verdieping | Model Group:NLRS_21.21_WA_wand 002b d=300_gen:5667323
5667336 | 09 negende verdieping | Model Group:NLRS_21.21_WA_wand 004b d=300_gen:5667316
5667342 | 09 negende verdieping | Model Group:NLRS_28.21_WA_3D element 002 d=300_gen:5667357
5667344 | 09 negende verdieping | Model Group:NLRS_28.21_WA_3D element 002 d=300_gen:5667357
5667417 | 09 negende verdieping | Model Group:NLRS_28.21_WA_3D element 002 d=300_gen:5667341
5667419 | 09 negende verdieping | Model Group:NLRS_28.21_WA_3D element 002 d=300_gen:5667341
5667461 | 09 negende verdieping | Model Group:NLRS_28.21_WA_3D element 001 d=300_gen:5667340
5667464 | 09 negende verdieping | Model Group:NLRS_28.21_WA_3D element 001 d=300_gen:5667340
5667490 | 09 negende verdieping | Model Group:NLRS_28.21_WA_3D element 001 d=300_gen:5667358
5667493 | 09 negende verdieping | Model Group:NLRS_28.21_WA_3D element 001 d=300_gen:5667358
5667612 | 09 negende verdieping | Model Group:NLRS_21.21_WA_wand 004b d=300_gen:5667316
5667616 | 09 negende verdieping | Model Group:NLRS_21.21_WA_wand 002b d=300_gen:5667323
6858996 | 10 tiende verdieping | Model Group:NLRS_21.21_WA_wand 003 d=300_gen:6859046
6858998 | 10 tiende verdieping | Model Group:NLRS_21.21_WA_wand 001 d=300_gen:6859045
6859047 | 10 tiende verdieping | Model Group:NLRS_21.21_WA_wand 003 d=300_gen:6859050
6859051 | 10 tiende verdieping | Model Group:NLRS_21.21_WA_wand 001 d=300_gen:6859054
6859055 | 10 tiende verdieping | Model Group:NLRS_21.21_WA_wand 002a d=300_gen:6859044
6859059 | 10 tiende verdieping | Model Group:NLRS_21.21_WA_wand 004a d=300_gen:6859036
6859065 | 10 tiende verdieping | Model Group:NLRS_28.21_WA_3D element 002 d=300_gen:6859076
6859067 | 10 tiende verdieping | Model Group:NLRS_28.21_WA_3D element 002 d=300_gen:6859076
6859116 | 10 tiende verdieping | Model Group:NLRS_28.21_WA_3D element 002 d=300_gen:6859064
6859118 | 10 tiende verdieping | Model Group:NLRS_28.21_WA_3D element 002 d=300_gen:6859064
6859154 | 10 tiende verdieping | Model Group:NLRS_28.21_WA_3D element 001 d=300_gen:6859063
6859157 | 10 tiende verdieping | Model Group:NLRS_28.21_WA_3D element 001 d=300_gen:6859063
6859180 | 10 tiende verdieping | Model Group:NLRS_28.21_WA_3D element 001 d=300_gen:6859077
6859183 | 10 tiende verdieping | Model Group:NLRS_28.21_WA_3D element 001 d=300_gen:6859077
6859261 | 10 tiende verdieping | Model Group:NLRS_21.21_WA_wand 004a d=300_gen:6859036
6859268 | 10 tiende verdieping | Model Group:NLRS_21.21_WA_wand 002a d=300_gen:6859044
6861518 | 11 elfde verdieping | Model Group:NLRS_21.21_WA_wand 003 d=300_gen:6861561
6861520 | 11 elfde verdieping | Model Group:NLRS_21.21_WA_wand 001 d=300_gen:6861560
6861562 | 11 elfde verdieping | Model Group:NLRS_21.21_WA_wand 003 d=300_gen:6861565
6861566 | 11 elfde verdieping | Model Group:NLRS_21.21_WA_wand 001 d=300_gen:6861569
6861578 | 11 elfde verdieping | Model Group:NLRS_28.21_WA_3D element 002 d=300_gen:6861589
6861580 | 11 elfde verdieping | Model Group:NLRS_28.21_WA_3D element 002 d=300_gen:6861589
6861629 | 11 elfde verdieping | Model Group:NLRS_28.21_WA_3D element 002 d=300_gen:6861577
6861631 | 11 elfde verdieping | Model Group:NLRS_28.21_WA_3D element 002 d=300_gen:6861577
6861667 | 11 elfde verdieping | Model Group:NLRS_28.21_WA_3D element 001 d=300_gen:6861576
6861670 | 11 elfde verdieping | Model Group:NLRS_28.21_WA_3D element 001 d=300_gen:6861576
6861693 | 11 elfde verdieping | Model Group:NLRS_28.21_WA_3D element 001 d=300_gen:6861590
6861696 | 11 elfde verdieping | Model Group:NLRS_28.21_WA_3D element 001 d=300_gen:6861590
12627767 | 11 elfde verdieping | Model Group:NLRS_21.21_WA_wand 002b d=300_gen:6861559
12627771 | 11 elfde verdieping | Model Group:NLRS_21.21_WA_wand 002b d=300_gen:6861559
12627935 | 13 dertiende verdieping | Model Group:NLRS_21.21_WA_wand 002b d=300_gen:4730656
12627939 | 13 dertiende verdieping | Model Group:NLRS_21.21_WA_wand 002b d=300_gen:4730656
12629263 | 12 twaalfde verdieping | Model Group:NLRS_21.21_WA_wand 002a d=300_gen:4738243
12629267 | 12 twaalfde verdieping | Model Group:NLRS_21.21_WA_wand 002a d=300_gen:4738243
12629619 | 14 veertiende verdieping | Model Group:NLRS_21.21_WA_wand 002a d=300_gen:4738701
12629623 | 14 veertiende verdieping | Model Group:NLRS_21.21_WA_wand 002a d=300_gen:4738701
12653266 | 09 negende verdieping | Model Group:NLRS_21.21_WA_wand 002b d=300_gen:5667625
12653270 | 09 negende verdieping | Model Group:NLRS_21.21_WA_wand 002b d=300_gen:5667625
12653638 | 10 tiende verdieping | Model Group:NLRS_21.21_WA_wand 002a d=300_gen:6859037
12653642 | 10 tiende verdieping | Model Group:NLRS_21.21_WA_wand 002a d=300_gen:6859037
12654041 | 11 elfde verdieping | Model Group:NLRS_21.21_WA_wand 002b d=300_gen:6861785
12654045 | 11 elfde verdieping | Model Group:NLRS_21.21_WA_wand 002b d=300_gen:6861785
12654318 | 12 twaalfde verdieping | Model Group:NLRS_21.21_WA_wand 002a d=300_gen:4738236
12654322 | 12 twaalfde verdieping | Model Group:NLRS_21.21_WA_wand 002a d=300_gen:4738236
12654692 | 13 dertiende verdieping | Model Group:NLRS_21.21_WA_wand 002b d=300_gen:5509164
12654696 | 13 dertiende verdieping | Model Group:NLRS_21.21_WA_wand 002b d=300_gen:5509164
12654959 | 14 veertiende verdieping | Model Group:NLRS_21.21_WA_wand 002a d=300_gen:4738694
12654963 | 14 veertiende verdieping | Model Group:NLRS_21.21_WA_wand 002a d=300_gen:4738694
12662838 | 11 elfde verdieping | Model Group:NLRS_21.21_WA_wand 004b d=300_gen:6861552
12662841 | 11 elfde verdieping | Model Group:NLRS_21.21_WA_wand 004b d=300_gen:6861552
12663022 | 13 dertiende verdieping | Model Group:NLRS_21.21_WA_wand 004b d=300_gen:4730648
12663025 | 13 dertiende verdieping | Model Group:NLRS_21.21_WA_wand 004b d=300_gen:4730648
12663427 | 12 twaalfde verdieping | Model Group:NLRS_21.21_WA_wand 004a d=300_gen:4738235
12663430 | 12 twaalfde verdieping | Model Group:NLRS_21.21_WA_wand 004a d=300_gen:4738235
12663832 | 14 veertiende verdieping | Model Group:NLRS_21.21_WA_wand 004a d=300_gen:4738693
12663835 | 14 veertiende verdieping | Model Group:NLRS_21.21_WA_wand 004a d=300_gen:4738693
12679383 | 09 negende verdieping | Model Group:NLRS_21.21_WA_wand 004b d=300_gen:5667307
12679386 | 09 negende verdieping | Model Group:NLRS_21.21_WA_wand 004b d=300_gen:5667307
12679929 | 10 tiende verdieping | Model Group:NLRS_21.21_WA_wand 004a d=300_gen:6859027
12679932 | 10 tiende verdieping | Model Group:NLRS_21.21_WA_wand 004a d=300_gen:6859027
12680455 | 11 elfde verdieping | Model Group:NLRS_21.21_WA_wand 004b d=300_gen:6861543
12680458 | 11 elfde verdieping | Model Group:NLRS_21.21_WA_wand 004b d=300_gen:6861543
12680787 | 12 twaalfde verdieping | Model Group:NLRS_21.21_WA_wand 004a d=300_gen:4738226
12680790 | 12 twaalfde verdieping | Model Group:NLRS_21.21_WA_wand 004a d=300_gen:4738226
12681070 | 13 dertiende verdieping | Model Group:NLRS_21.21_WA_wand 004b d=300_gen:4730639
12681073 | 13 dertiende verdieping | Model Group:NLRS_21.21_WA_wand 004b d=300_gen:4730639
12681485 | 14 veertiende verdieping | Model Group:NLRS_21.21_WA_wand 004a d=300_gen:4738684
12681488 | 14 veertiende verdieping | Model Group:NLRS_21.21_WA_wand 004a d=300_gen:4738684

# IfcWallStandardCase: Basic Wall:NLRS_21.21_WA_beton prefab d=400/420_gen (76)
Type - PredefinedType: STANDARD; Material: NLRS_f2_beton prefab 400 mm
Classification: 21.21 buitenwanden - constructief, massieve wanden (Uniformat)
Pset_WallCommon - IsExternal: yes; LoadBearing: yes; ExtendToStructure: no; Reference: NLRS_21.21_WA_beton prefab d=400/420_gen; ThermalTransmittance: 2.615 kg/K/s3
Name (Basic Wall:NLRS_21.21_WA_beton prefab d=400/420_gen:...) | In | Group
4689026 | 07 zevende verdieping | Model Group:NLRS_28.21_WA_3D element 002 d=400_gen:4689313
4689064 | 07 zevende verdieping | Model Group:NLRS_28.21_WA_3D element 002 d=400_gen:4689313
4689066 | 07 zevende verdieping | Model Group:NLRS_21.21_WA_wand 003 d=400_gen:4689135
4689070 | 07 zevende verdieping | Model Group:NLRS_28.21_WA_3D element 001 d=400_gen:4689303
4689114 | 07 zevende verdieping | Model Group:NLRS_28.21_WA_3D element 001 d=400_gen:4689303
4689136 | 07 zevende verdieping | Model Group:NLRS_21.21_WA_wand 003 d=400_gen:4689139
4689155 | 07 zevende verdieping | Model Group:NLRS_21.21_WA_wand 002b d=400_gen:4689133
4689181 | 07 zevende verdieping | Model Group:NLRS_21.21_WA_wand 004b d=400_gen:4689125
4689314 | 07 zevende verdieping | Model Group:NLRS_28.21_WA_3D element 002 d=400_gen:4689329
4689316 | 07 zevende verdieping | Model Group:NLRS_28.21_WA_3D element 002 d=400_gen:4689329
4689330 | 07 zevende verdieping | Model Group:NLRS_28.21_WA_3D element 001 d=400_gen:4689345
4689333 | 07 zevende verdieping | Model Group:NLRS_28.21_WA_3D element 001 d=400_gen:4689345
4690644 | 06 zesde verdieping | Model Group:NLRS_28.21_WA_3D element 002 d=400_gen:4690876
4690676 | 06 zesde verdieping | Model Group:NLRS_28.21_WA_3D element 002 d=400_gen:4690876
4690680 | 06 zesde verdieping | Model Group:NLRS_28.21_WA_3D element 001 d=400_gen:4690866
4690706 | 06 zesde verdieping | Model Group:NLRS_28.21_WA_3D element 001 d=400_gen:4690866
4690715 | 06 zesde verdieping | Model Group:NLRS_21.21_WA_wand 001 d=400_gen:4690718
4690877 | 06 zesde verdieping | Model Group:NLRS_28.21_WA_3D element 002 d=400_gen:4690892
4690879 | 06 zesde verdieping | Model Group:NLRS_28.21_WA_3D element 002 d=400_gen:4690892
4690893 | 06 zesde verdieping | Model Group:NLRS_28.21_WA_3D element 001 d=400_gen:4690908
4690896 | 06 zesde verdieping | Model Group:NLRS_28.21_WA_3D element 001 d=400_gen:4690908
4692547 | 06 zesde verdieping | Model Group:NLRS_21.21_WA_wand 004a d=400_gen:4690709
4693018 | 06 zesde verdieping | Model Group:NLRS_21.21_WA_wand 003 d=400_gen:4690714
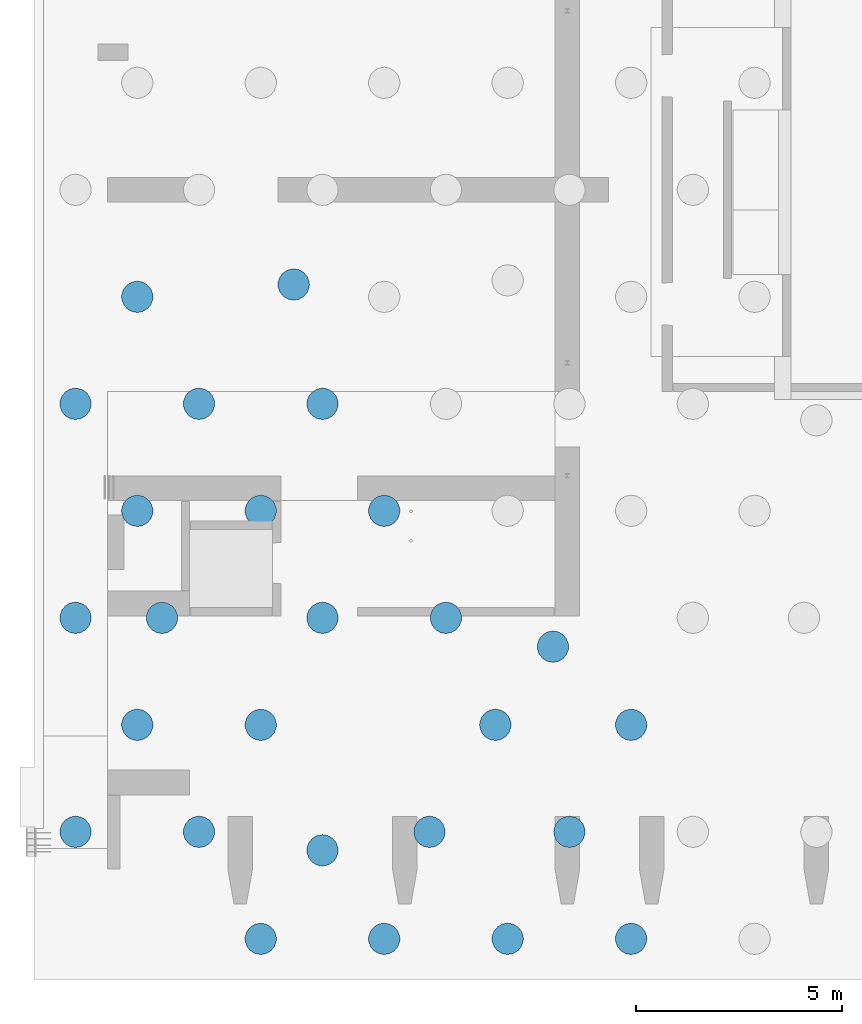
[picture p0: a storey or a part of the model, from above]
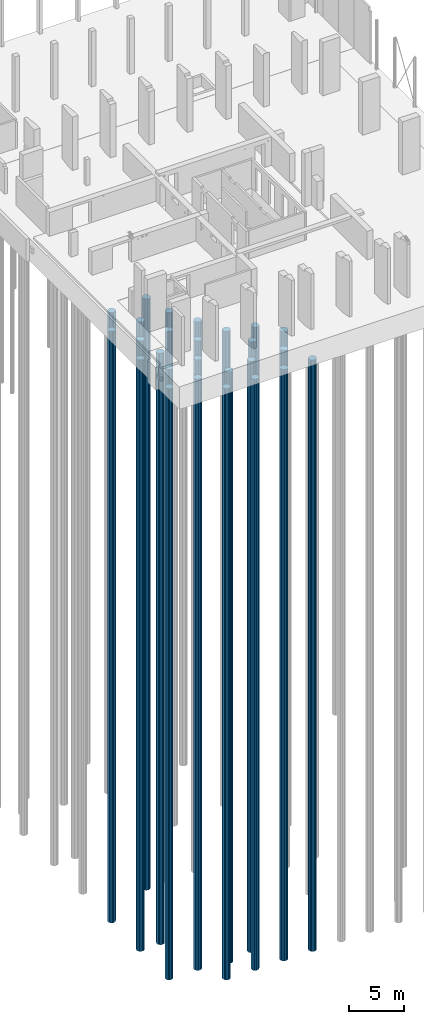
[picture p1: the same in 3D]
Properties of the parts of a building model (IFC2X3), part 20 of 21

# IfcWallStandardCase: Basic Wall:NLRS_21.21_WA_beton prefab d=400/420_gen (76)
Name (Basic Wall:NLRS_21.21_WA_beton prefab d=400/420_gen:...) | In | Group
4693057 | 06 zesde verdieping | Model Group:NLRS_21.21_WA_wand 002a d=400_gen:4690711
4693192 | 06 zesde verdieping | Model Group:NLRS_21.21_WA_wand 003 d=400_gen:4690713
4693297 | 06 zesde verdieping | Model Group:NLRS_21.21_WA_wand 001 d=400_gen:4690712
4693504 | 07 zevende verdieping | Model Group:NLRS_21.21_WA_wand 001 d=400_gen:4689143
4693534 | 07 zevende verdieping | Model Group:NLRS_21.21_WA_wand 001 d=400_gen:4689134
4714771 | 08 achtste verdieping | Model Group:NLRS_28.21_WA_3D element 002 d=400_gen:4714990
4714801 | 08 achtste verdieping | Model Group:NLRS_28.21_WA_3D element 002 d=400_gen:4714990
4714803 | 08 achtste verdieping | Model Group:NLRS_28.21_WA_3D element 001 d=400_gen:4714980
4714824 | 08 achtste verdieping | Model Group:NLRS_28.21_WA_3D element 001 d=400_gen:4714980
4714833 | 08 achtste verdieping | Model Group:NLRS_21.21_WA_wand 001 d=400_gen:4714836
4714991 | 08 achtste verdieping | Model Group:NLRS_28.21_WA_3D element 002 d=400_gen:4715006
4714993 | 08 achtste verdieping | Model Group:NLRS_28.21_WA_3D element 002 d=400_gen:4715006
4715007 | 08 achtste verdieping | Model Group:NLRS_28.21_WA_3D element 001 d=400_gen:4715022
4715010 | 08 achtste verdieping | Model Group:NLRS_28.21_WA_3D element 001 d=400_gen:4715022
4715168 | 08 achtste verdieping | Model Group:NLRS_21.21_WA_wand 004aa d=400_gen:4714827
4715170 | 08 achtste verdieping | Model Group:NLRS_21.21_WA_wand 003 d=400_gen:4714832
4715179 | 08 achtste verdieping | Model Group:NLRS_21.21_WA_wand 002a d=400_gen:4714829
4715181 | 08 achtste verdieping | Model Group:NLRS_21.21_WA_wand 003 d=400_gen:4714831
4715192 | 08 achtste verdieping | Model Group:NLRS_21.21_WA_wand 001 d=400_gen:4714830
5042423 | 05 vijfde verdieping
5042556 | 05 vijfde verdieping
5042655 | 05 vijfde verdieping
5042751 | 05 vijfde verdieping
5146599 | 05 vijfde verdieping
5146667 | 05 vijfde verdieping
5146702 | 05 vijfde verdieping
5146784 | 05 vijfde verdieping
5146907 | 05 vijfde verdieping
5146973 | 05 vijfde verdieping
5147007 | 05 vijfde verdieping
5147274 | 05 vijfde verdieping
5405296 | 05 vijfde verdieping
5405822 | 07 zevende verdieping | Model Group:NLRS_21.21_WA_wand 004b d=400_gen:4689125
5405836 | 06 zesde verdieping | Model Group:NLRS_21.21_WA_wand 004a d=400_gen:4690709
5405850 | 08 achtste verdieping | Model Group:NLRS_21.21_WA_wand 004aa d=400_gen:4714827
5405857 | 05 vijfde verdieping
5409047 | 05 vijfde verdieping
5409478 | 07 zevende verdieping | Model Group:NLRS_21.21_WA_wand 002b d=400_gen:4689133
5409492 | 06 zesde verdieping | Model Group:NLRS_21.21_WA_wand 002a d=400_gen:4690711
5409506 | 08 achtste verdieping | Model Group:NLRS_21.21_WA_wand 002a d=400_gen:4714829
5409513 | 05 vijfde verdieping
12650838 | 06 zesde verdieping | Model Group:NLRS_21.21_WA_wand 002a d=400_gen:4690710
12650841 | 06 zesde verdieping | Model Group:NLRS_21.21_WA_wand 002a d=400_gen:4690710
12651692 | 08 achtste verdieping | Model Group:NLRS_21.21_WA_wand 002a d=400_gen:4714828
12651695 | 08 achtste verdieping | Model Group:NLRS_21.21_WA_wand 002a d=400_gen:4714828
12652004 | 07 zevende verdieping | Model Group:NLRS_21.21_WA_wand 002b d=400_gen:4689126
12652007 | 07 zevende verdieping | Model Group:NLRS_21.21_WA_wand 002b d=400_gen:4689126
12678114 | 06 zesde verdieping | Model Group:NLRS_21.21_WA_wand 004a d=400_gen:4690705
12678118 | 06 zesde verdieping | Model Group:NLRS_21.21_WA_wand 004a d=400_gen:4690705
12678392 | 07 zevende verdieping | Model Group:NLRS_21.21_WA_wand 004b d=400_gen:4689113
12678396 | 07 zevende verdieping | Model Group:NLRS_21.21_WA_wand 004b d=400_gen:4689113
12678866 | 08 achtste verdieping | Model Group:NLRS_21.21_WA_wand 004a d=400_gen:4714823
12678870 | 08 achtste verdieping | Model Group:NLRS_21.21_WA_wand 004a d=400_gen:4714823

# IfcWallStandardCase: Basic Wall:NLRS_22.21_WA_beton ihwg d=600_gen (46)
Type - PredefinedType: STANDARD; Material: NLRS_f2_beton ihwg 600 mm
Classification: 22.21 binnenwanden - constructief, massieve wanden (Uniformat)
Pset_WallCommon - IsExternal: yes; LoadBearing: yes; ExtendToStructure: no; Reference: NLRS_22.21_WA_beton ihwg d=600_gen; ThermalTransmittance: 1.74333 kg/K/s3
Name (Basic Wall:NLRS_22.21_WA_beton ihwg d=600_gen:...) | In
4125508 | 00 begane grond
4126048 | 00 begane grond
4126336 | 00 begane grond
4126697 | 00 begane grond
4126969 | 00 begane grond
4127256 | 00 begane grond
4319481 | 00a eerste tussenverdieping
4319483 | 00a eerste tussenverdieping
4319485 | 00a eerste tussenverdieping
4319489 | 00a eerste tussenverdieping
4319491 | 00a eerste tussenverdieping
4391827 | 01 eerste verdieping
4391829 | 01 eerste verdieping
4391831 | 01 eerste verdieping
4391835 | 01 eerste verdieping
4391837 | 01 eerste verdieping
4420789 | 02 tweede verdieping
4420791 | 02 tweede verdieping
4420793 | 02 tweede verdieping
4420795 | 02 tweede verdieping
4420799 | 02 tweede verdieping
4420801 | 02 tweede verdieping
4832684 | 03 derde verdieping
4832722 | 03 derde verdieping
4832749 | 03 derde verdieping
4832755 | 03 derde verdieping
4832764 | 03 derde verdieping
4865507 | 03 derde verdieping
4866030 | 01 eerste verdieping
4941804 | 04 vierde verdieping
4941807 | 04 vierde verdieping
4941812 | 04 vierde verdieping
4941832 | 04 vierde verdieping
4941838 | 04 vierde verdieping
4941847 | 04 vierde verdieping
7297270 | 00 begane grond
7297276 | 00a eerste tussenverdieping
7297303 | 01 eerste verdieping
7297336 | 02 tweede verdieping
7297342 | 03 derde verdieping
7297350 | 04 vierde verdieping
7298298 | 00 begane grond
7298413 | 01 eerste verdieping
7298504 | 02 tweede verdieping
7298594 | 03 derde verdieping
7298797 | 04 vierde verdieping

# IfcWallStandardCase: Basic Wall:NLRS_22.21_WA_beton prefab d=200_gen (426)
Type - PredefinedType: STANDARD; Material: NLRS_f2_beton prefab 200 mm
Classification: 22.21 binnenwanden - constructief, massieve wanden (Uniformat)
Pset_WallCommon - LoadBearing: yes; IsExternal: no; ExtendToStructure: no; Reference: NLRS_22.21_WA_beton prefab d=200_gen; ThermalTransmittance: 5.23 kg/K/s3
Name (Basic Wall:NLRS_22.21_WA_beton prefab d=200_gen:...) | In | Group
4160890 | 00 begane grond
4160900 | 00 begane grond
4160908 | 00 begane grond
4160920 | 00 begane grond
4161081 | 00 begane grond
4161091 | 00 begane grond
4161119 | 00 begane grond
4161129 | 00 begane grond
4161177 | 00 begane grond
4161187 | 00 begane grond
4161197 | 00 begane grond
4161267 | 00 begane grond
4161354 | 00 begane grond
4161469 | 00 begane grond
4161552 | 00 begane grond
4161724 | 00 begane grond
4313131 | 00a eerste tussenverdieping
4313133 | 00a eerste tussenverdieping
4313135 | 00a eerste tussenverdieping
4313137 | 00a eerste tussenverdieping
4319505 | 00a eerste tussenverdieping
4319507 | 00a eerste tussenverdieping
4319509 | 00a eerste tussenverdieping
4319511 | 00a eerste tussenverdieping
4391839 | 01 eerste verdieping
4391841 | 01 eerste verdieping
4391843 | 01 eerste verdieping
4391845 | 01 eerste verdieping
4420803 | 02 tweede verdieping
4420805 | 02 tweede verdieping
4420807 | 02 tweede verdieping
4420809 | 02 tweede verdieping
4690664 | 06 zesde verdieping | Model Group:NLRS_22.21_WA_kern 06--51_gen:4690937
4690666 | 06 zesde verdieping | Model Group:NLRS_22.21_WA_kern 06--51_gen:4690937
4690668 | 06 zesde verdieping | Model Group:NLRS_22.21_WA_kern 06--51_gen:4690937
4690670 | 06 zesde verdieping | Model Group:NLRS_22.21_WA_kern 06--51_gen:4690937
4690672 | 06 zesde verdieping | Model Group:NLRS_22.21_WA_kern 06--51_gen:4690937
4690674 | 06 zesde verdieping | Model Group:NLRS_22.21_WA_kern 06--51_gen:4690937
4822189 | 05 vijfde verdieping | Model Group:NLRS_22.21_WA_kern 05_gen:8891248
4822191 | 05 vijfde verdieping | Model Group:NLRS_22.21_WA_kern 05_gen:8891248
4822193 | 05 vijfde verdieping | Model Group:NLRS_22.21_WA_kern 05_gen:8891248
4822195 | 05 vijfde verdieping
4822197 | 05 vijfde verdieping | Model Group:NLRS_22.21_WA_kern 05_gen:8891248
4822199 | 05 vijfde verdieping | Model Group:NLRS_22.21_WA_kern 05_gen:8891248
4832688 | 03 derde verdieping | Model Group:NLRS_22.21_WA_kern 01--04_gen:4832721
4832690 | 03 derde verdieping | Model Group:NLRS_22.21_WA_kern 01--04_gen:4832721
4832692 | 03 derde verdieping | Model Group:NLRS_22.21_WA_kern 01--04_gen:4832721
4832694 | 03 derde verdieping | Model Group:NLRS_22.21_WA_kern 01--04_gen:4832721
4832696 | 03 derde verdieping | Model Group:NLRS_22.21_WA_kern 01--04_gen:4832721
4869700 | 02 tweede verdieping | Model Group:NLRS_22.21_WA_kern 01--04_gen:4869716
4869702 | 02 tweede verdieping | Model Group:NLRS_22.21_WA_kern 01--04_gen:4869716
4869704 | 02 tweede verdieping | Model Group:NLRS_22.21_WA_kern 01--04_gen:4869716
4869706 | 02 tweede verdieping | Model Group:NLRS_22.21_WA_kern 01--04_gen:4869716
4869708 | 02 tweede verdieping | Model Group:NLRS_22.21_WA_kern 01--04_gen:4869716
4870138 | 01 eerste verdieping
4870140 | 01 eerste verdieping
4870142 | 01 eerste verdieping
4870144 | 01 eerste verdieping
4870146 | 01 eerste verdieping
4870838 | 00a eerste tussenverdieping
4870840 | 00a eerste tussenverdieping
4870842 | 00a eerste tussenverdieping
4870844 | 00a eerste tussenverdieping
4870846 | 00a eerste tussenverdieping
4872357 | 03 derde verdieping
4872359 | 03 derde verdieping
4872361 | 03 derde verdieping
4872407 | 04 vierde verdieping
4872409 | 04 vierde verdieping
4872411 | 04 vierde verdieping
4876002 | 00 begane grond | Model Group:NLRS_22.21_WA_kern 00_gen:4876018
4876004 | 00 begane grond | Model Group:NLRS_22.21_WA_kern 00_gen:4876018
4876006 | 00 begane grond | Model Group:NLRS_22.21_WA_kern 00_gen:4876018
4876008 | 00 begane grond | Model Group:NLRS_22.21_WA_kern 00_gen:4876018
4876010 | 00 begane grond | Model Group:NLRS_22.21_WA_kern 00_gen:4876018
4876875 | 01 eerste verdieping
4876877 | 01 eerste verdieping
4876879 | 01 eerste verdieping
4876881 | 01 eerste verdieping
4876883 | 01 eerste verdieping
4876885 | 01 eerste verdieping
4876887 | 01 eerste verdieping
4876891 | 01 eerste verdieping
4876893 | 01 eerste verdieping
4876895 | 01 eerste verdieping
4880098 | 01 eerste verdieping
4880100 | 01 eerste verdieping
4881099 | 02 tweede verdieping
4882468 | 02 tweede verdieping
4882470 | 02 tweede verdieping
4882472 | 02 tweede verdieping
4882855 | 02 tweede verdieping
4882857 | 02 tweede verdieping
4882859 | 02 tweede verdieping
4884800 | 02 tweede verdieping
4885540 | 02 tweede verdieping
4885725 | 02 tweede verdieping
4885727 | 02 tweede verdieping
4941774 | 04 vierde verdieping | Model Group:NLRS_22.21_WA_kern 01--04_gen:4941798
4941776 | 04 vierde verdieping | Model Group:NLRS_22.21_WA_kern 01--04_gen:4941798
4941778 | 04 vierde verdieping | Model Group:NLRS_22.21_WA_kern 01--04_gen:4941798
4941780 | 04 vierde verdieping | Model Group:NLRS_22.21_WA_kern 01--04_gen:4941798
4941782 | 04 vierde verdieping | Model Group:NLRS_22.21_WA_kern 01--04_gen:4941798
4971860 | 53 drieënvijftigste verdieping
4971862 | 53 drieënvijftigste verdieping
4971864 | 53 drieënvijftigste verdieping
4971866 | 53 drieënvijftigste verdieping
4971868 | 53 drieënvijftigste verdieping
4971870 | 53 drieënvijftigste verdieping
4981720 | 52 tweeënvijftigste verdieping
4981722 | 52 tweeënvijftigste verdieping
4981724 | 52 tweeënvijftigste verdieping
4981726 | 52 tweeënvijftigste verdieping
4981728 | 52 tweeënvijftigste verdieping
4981730 | 52 tweeënvijftigste verdieping
5001088 | 54 vierenvijftigste verdieping
5001090 | 54 vierenvijftigste verdieping
5001092 | 54 vierenvijftigste verdieping
5001094 | 54 vierenvijftigste verdieping
5001096 | 54 vierenvijftigste verdieping
5001098 | 54 vierenvijftigste verdieping
5003622 | 57 zevenenvijftigste verdieping
5003624 | 57 zevenenvijftigste verdieping
5003626 | 57 zevenenvijftigste verdieping
5003628 | 57 zevenenvijftigste verdieping
5003630 | 57 zevenenvijftigste verdieping
5003632 | 57 zevenenvijftigste verdieping
5003673 | 57 zevenenvijftigste verdieping
5005558 | 58 achtenvijftigste verdieping
5005560 | 58 achtenvijftigste verdieping
5005566 | 58 achtenvijftigste verdieping
5005607 | 58 achtenvijftigste verdieping
5009598 | 56 zesenvijftigste verdieping
5009600 | 56 zesenvijftigste verdieping
5009602 | 56 zesenvijftigste verdieping
5009604 | 56 zesenvijftigste verdieping
5009606 | 56 zesenvijftigste verdieping
5009608 | 56 zesenvijftigste verdieping
5009649 | 56 zesenvijftigste verdieping
5009929 | 55 vijfenvijftigste verdieping
5009931 | 55 vijfenvijftigste verdieping
5009933 | 55 vijfenvijftigste verdieping
5009935 | 55 vijfenvijftigste verdieping
5009937 | 55 vijfenvijftigste verdieping
5009939 | 55 vijfenvijftigste verdieping
5270051 | 02 tweede verdieping
5844833 | 00 begane grond
5844956 | 00a eerste tussenverdieping
5845030 | 01 eerste verdieping
5845096 | 02 tweede verdieping
5845280 | 03 derde verdieping
6355405 | 00 begane grond
8873636 | 07 zevende verdieping | Model Group:NLRS_22.21_WA_kern 06--51_gen:4689379
8873638 | 07 zevende verdieping | Model Group:NLRS_22.21_WA_kern 06--51_gen:4689379
8873640 | 07 zevende verdieping | Model Group:NLRS_22.21_WA_kern 06--51_gen:4689379
8873642 | 07 zevende verdieping | Model Group:NLRS_22.21_WA_kern 06--51_gen:4689379
8873644 | 07 zevende verdieping | Model Group:NLRS_22.21_WA_kern 06--51_gen:4689379
8873646 | 07 zevende verdieping | Model Group:NLRS_22.21_WA_kern 06--51_gen:4689379
8873898 | 08 achtste verdieping | Model Group:NLRS_22.21_WA_kern 06--51_gen:4715051
8873900 | 08 achtste verdieping | Model Group:NLRS_22.21_WA_kern 06--51_gen:4715051
8873902 | 08 achtste verdieping | Model Group:NLRS_22.21_WA_kern 06--51_gen:4715051
8873904 | 08 achtste verdieping | Model Group:NLRS_22.21_WA_kern 06--51_gen:4715051
8873906 | 08 achtste verdieping | Model Group:NLRS_22.21_WA_kern 06--51_gen:4715051
8873908 | 08 achtste verdieping | Model Group:NLRS_22.21_WA_kern 06--51_gen:4715051
8873955 | 12 twaalfde verdieping | Model Group:NLRS_22.21_WA_kern 06--51_gen:4738448
8873957 | 12 twaalfde verdieping | Model Group:NLRS_22.21_WA_kern 06--51_gen:4738448
8873959 | 12 twaalfde verdieping | Model Group:NLRS_22.21_WA_kern 06--51_gen:4738448
8873961 | 12 twaalfde verdieping | Model Group:NLRS_22.21_WA_kern 06--51_gen:4738448
8873963 | 12 twaalfde verdieping | Model Group:NLRS_22.21_WA_kern 06--51_gen:4738448
8873965 | 12 twaalfde verdieping | Model Group:NLRS_22.21_WA_kern 06--51_gen:4738448
8874012 | 09 negende verdieping | Model Group:NLRS_22.21_WA_kern 06--51_gen:5667376
8874014 | 09 negende verdieping | Model Group:NLRS_22.21_WA_kern 06--51_gen:5667376
8874016 | 09 negende verdieping | Model Group:NLRS_22.21_WA_kern 06--51_gen:5667376
8874018 | 09 negende verdieping | Model Group:NLRS_22.21_WA_kern 06--51_gen:5667376
8874020 | 09 negende verdieping | Model Group:NLRS_22.21_WA_kern 06--51_gen:5667376
8874022 | 09 negende verdieping | Model Group:NLRS_22.21_WA_kern 06--51_gen:5667376
8874069 | 10 tiende verdieping | Model Group:NLRS_22.21_WA_kern 06--51_gen:6859079
8874071 | 10 tiende verdieping | Model Group:NLRS_22.21_WA_kern 06--51_gen:6859079
8874073 | 10 tiende verdieping | Model Group:NLRS_22.21_WA_kern 06--51_gen:6859079
8874075 | 10 tiende verdieping | Model Group:NLRS_22.21_WA_kern 06--51_gen:6859079
8874077 | 10 tiende verdieping | Model Group:NLRS_22.21_WA_kern 06--51_gen:6859079
8874079 | 10 tiende verdieping | Model Group:NLRS_22.21_WA_kern 06--51_gen:6859079
8874126 | 11 elfde verdieping | Model Group:NLRS_22.21_WA_kern 06--51_gen:6861592
8874128 | 11 elfde verdieping | Model Group:NLRS_22.21_WA_kern 06--51_gen:6861592
8874130 | 11 elfde verdieping | Model Group:NLRS_22.21_WA_kern 06--51_gen:6861592
8874132 | 11 elfde verdieping | Model Group:NLRS_22.21_WA_kern 06--51_gen:6861592
8874134 | 11 elfde verdieping | Model Group:NLRS_22.21_WA_kern 06--51_gen:6861592
8874136 | 11 elfde verdieping | Model Group:NLRS_22.21_WA_kern 06--51_gen:6861592
8875614 | 13 dertiende verdieping | Model Group:NLRS_22.21_WA_kern 06--51_gen:4730861
8875616 | 13 dertiende verdieping | Model Group:NLRS_22.21_WA_kern 06--51_gen:4730861
8875618 | 13 dertiende verdieping | Model Group:NLRS_22.21_WA_kern 06--51_gen:4730861
8875620 | 13 dertiende verdieping | Model Group:NLRS_22.21_WA_kern 06--51_gen:4730861
8875622 | 13 dertiende verdieping | Model Group:NLRS_22.21_WA_kern 06--51_gen:4730861
8875624 | 13 dertiende verdieping | Model Group:NLRS_22.21_WA_kern 06--51_gen:4730861
8875671 | 15 vijftiende verdieping | Model Group:NLRS_22.21_WA_kern 06--51_gen:4731319
8875673 | 15 vijftiende verdieping | Model Group:NLRS_22.21_WA_kern 06--51_gen:4731319
8875675 | 15 vijftiende verdieping | Model Group:NLRS_22.21_WA_kern 06--51_gen:4731319
8875677 | 15 vijftiende verdieping | Model Group:NLRS_22.21_WA_kern 06--51_gen:4731319
8875679 | 15 vijftiende verdieping | Model Group:NLRS_22.21_WA_kern 06--51_gen:4731319
8875681 | 15 vijftiende verdieping | Model Group:NLRS_22.21_WA_kern 06--51_gen:4731319
8875728 | 17 zeventiende verdieping | Model Group:NLRS_22.21_WA_kern 06--51_gen:4731777
8875730 | 17 zeventiende verdieping | Model Group:NLRS_22.21_WA_kern 06--51_gen:4731777
8875732 | 17 zeventiende verdieping | Model Group:NLRS_22.21_WA_kern 06--51_gen:4731777
8875734 | 17 zeventiende verdieping | Model Group:NLRS_22.21_WA_kern 06--51_gen:4731777
8875736 | 17 zeventiende verdieping | Model Group:NLRS_22.21_WA_kern 06--51_gen:4731777
8875738 | 17 zeventiende verdieping | Model Group:NLRS_22.21_WA_kern 06--51_gen:4731777
8875785 | 19 negentiende verdieping | Model Group:NLRS_22.21_WA_kern 06--51_gen:4732235
8875787 | 19 negentiende verdieping | Model Group:NLRS_22.21_WA_kern 06--51_gen:4732235
8875789 | 19 negentiende verdieping | Model Group:NLRS_22.21_WA_kern 06--51_gen:4732235
8875791 | 19 negentiende verdieping | Model Group:NLRS_22.21_WA_kern 06--51_gen:4732235
8875793 | 19 negentiende verdieping | Model Group:NLRS_22.21_WA_kern 06--51_gen:4732235
8875795 | 19 negentiende verdieping | Model Group:NLRS_22.21_WA_kern 06--51_gen:4732235
8875842 | 14 veertiende verdieping | Model Group:NLRS_22.21_WA_kern 06--51_gen:4738906
8875844 | 14 veertiende verdieping | Model Group:NLRS_22.21_WA_kern 06--51_gen:4738906
8875846 | 14 veertiende verdieping | Model Group:NLRS_22.21_WA_kern 06--51_gen:4738906
8875848 | 14 veertiende verdieping | Model Group:NLRS_22.21_WA_kern 06--51_gen:4738906
8875850 | 14 veertiende verdieping | Model Group:NLRS_22.21_WA_kern 06--51_gen:4738906
8875852 | 14 veertiende verdieping | Model Group:NLRS_22.21_WA_kern 06--51_gen:4738906
8875899 | 16 zestiende verdieping | Model Group:NLRS_22.21_WA_kern 06--51_gen:4739364
8875901 | 16 zestiende verdieping | Model Group:NLRS_22.21_WA_kern 06--51_gen:4739364
8875903 | 16 zestiende verdieping | Model Group:NLRS_22.21_WA_kern 06--51_gen:4739364
8875905 | 16 zestiende verdieping | Model Group:NLRS_22.21_WA_kern 06--51_gen:4739364
8875907 | 16 zestiende verdieping | Model Group:NLRS_22.21_WA_kern 06--51_gen:4739364
8875909 | 16 zestiende verdieping | Model Group:NLRS_22.21_WA_kern 06--51_gen:4739364
8875956 | 18 achttiende verdieping | Model Group:NLRS_22.21_WA_kern 06--51_gen:4739822
8875958 | 18 achttiende verdieping | Model Group:NLRS_22.21_WA_kern 06--51_gen:4739822
8875960 | 18 achttiende verdieping | Model Group:NLRS_22.21_WA_kern 06--51_gen:4739822
8875962 | 18 achttiende verdieping | Model Group:NLRS_22.21_WA_kern 06--51_gen:4739822
8875964 | 18 achttiende verdieping | Model Group:NLRS_22.21_WA_kern 06--51_gen:4739822
8875966 | 18 achttiende verdieping | Model Group:NLRS_22.21_WA_kern 06--51_gen:4739822
8876013 | 20 twintigste verdieping | Model Group:NLRS_22.21_WA_kern 06--51_gen:4740280
8876015 | 20 twintigste verdieping | Model Group:NLRS_22.21_WA_kern 06--51_gen:4740280
8876017 | 20 twintigste verdieping | Model Group:NLRS_22.21_WA_kern 06--51_gen:4740280
8876019 | 20 twintigste verdieping | Model Group:NLRS_22.21_WA_kern 06--51_gen:4740280
8876021 | 20 twintigste verdieping | Model Group:NLRS_22.21_WA_kern 06--51_gen:4740280
8876023 | 20 twintigste verdieping | Model Group:NLRS_22.21_WA_kern 06--51_gen:4740280
8879090 | 21 eenentwintigste verdieping | Model Group:NLRS_22.21_WA_kern 06--51_gen:4695238
8879092 | 21 eenentwintigste verdieping | Model Group:NLRS_22.21_WA_kern 06--51_gen:4695238
8879094 | 21 eenentwintigste verdieping | Model Group:NLRS_22.21_WA_kern 06--51_gen:4695238
8879096 | 21 eenentwintigste verdieping | Model Group:NLRS_22.21_WA_kern 06--51_gen:4695238
8879098 | 21 eenentwintigste verdieping | Model Group:NLRS_22.21_WA_kern 06--51_gen:4695238
8879100 | 21 eenentwintigste verdieping | Model Group:NLRS_22.21_WA_kern 06--51_gen:4695238
8879147 | 24 vierentwintigste verdieping | Model Group:NLRS_22.21_WA_kern 06--51_gen:4746873
8879149 | 24 vierentwintigste verdieping | Model Group:NLRS_22.21_WA_kern 06--51_gen:4746873
8879151 | 24 vierentwintigste verdieping | Model Group:NLRS_22.21_WA_kern 06--51_gen:4746873
8879153 | 24 vierentwintigste verdieping | Model Group:NLRS_22.21_WA_kern 06--51_gen:4746873
8879155 | 24 vierentwintigste verdieping | Model Group:NLRS_22.21_WA_kern 06--51_gen:4746873
8879157 | 24 vierentwintigste verdieping | Model Group:NLRS_22.21_WA_kern 06--51_gen:4746873
8879204 | 25 vijfentwintigste verdieping | Model Group:NLRS_22.21_WA_kern 06--51_gen:4747305
8879206 | 25 vijfentwintigste verdieping | Model Group:NLRS_22.21_WA_kern 06--51_gen:4747305
8879208 | 25 vijfentwintigste verdieping | Model Group:NLRS_22.21_WA_kern 06--51_gen:4747305
8879210 | 25 vijfentwintigste verdieping | Model Group:NLRS_22.21_WA_kern 06--51_gen:4747305
8879212 | 25 vijfentwintigste verdieping | Model Group:NLRS_22.21_WA_kern 06--51_gen:4747305
8879214 | 25 vijfentwintigste verdieping | Model Group:NLRS_22.21_WA_kern 06--51_gen:4747305
8879261 | 26 zesentwintigste verdieping | Model Group:NLRS_22.21_WA_kern 06--51_gen:4747737
8879263 | 26 zesentwintigste verdieping | Model Group:NLRS_22.21_WA_kern 06--51_gen:4747737
8879265 | 26 zesentwintigste verdieping | Model Group:NLRS_22.21_WA_kern 06--51_gen:4747737
8879267 | 26 zesentwintigste verdieping | Model Group:NLRS_22.21_WA_kern 06--51_gen:4747737
8879269 | 26 zesentwintigste verdieping | Model Group:NLRS_22.21_WA_kern 06--51_gen:4747737
8879271 | 26 zesentwintigste verdieping | Model Group:NLRS_22.21_WA_kern 06--51_gen:4747737
8879318 | 27 zevenentwintigste verdieping | Model Group:NLRS_22.21_WA_kern 06--51_gen:4748169
8879320 | 27 zevenentwintigste verdieping | Model Group:NLRS_22.21_WA_kern 06--51_gen:4748169
8879322 | 27 zevenentwintigste verdieping | Model Group:NLRS_22.21_WA_kern 06--51_gen:4748169
8879324 | 27 zevenentwintigste verdieping | Model Group:NLRS_22.21_WA_kern 06--51_gen:4748169
8879326 | 27 zevenentwintigste verdieping | Model Group:NLRS_22.21_WA_kern 06--51_gen:4748169
8879328 | 27 zevenentwintigste verdieping | Model Group:NLRS_22.21_WA_kern 06--51_gen:4748169
8879375 | 28 achtentwintigste verdieping | Model Group:NLRS_22.21_WA_kern 06--51_gen:4748601
8879377 | 28 achtentwintigste verdieping | Model Group:NLRS_22.21_WA_kern 06--51_gen:4748601
8879379 | 28 achtentwintigste verdieping | Model Group:NLRS_22.21_WA_kern 06--51_gen:4748601
8879381 | 28 achtentwintigste verdieping | Model Group:NLRS_22.21_WA_kern 06--51_gen:4748601
8879383 | 28 achtentwintigste verdieping | Model Group:NLRS_22.21_WA_kern 06--51_gen:4748601
8879385 | 28 achtentwintigste verdieping | Model Group:NLRS_22.21_WA_kern 06--51_gen:4748601
8879432 | 29 negenentwintigste verdieping | Model Group:NLRS_22.21_WA_kern 06--51_gen:4749033
8879434 | 29 negenentwintigste verdieping | Model Group:NLRS_22.21_WA_kern 06--51_gen:4749033
8879436 | 29 negenentwintigste verdieping | Model Group:NLRS_22.21_WA_kern 06--51_gen:4749033
8879438 | 29 negenentwintigste verdieping | Model Group:NLRS_22.21_WA_kern 06--51_gen:4749033
8879440 | 29 negenentwintigste verdieping | Model Group:NLRS_22.21_WA_kern 06--51_gen:4749033
8879442 | 29 negenentwintigste verdieping | Model Group:NLRS_22.21_WA_kern 06--51_gen:4749033
8879489 | 30 dertigste verdieping | Model Group:NLRS_22.21_WA_kern 06--51_gen:4749465
8879491 | 30 dertigste verdieping | Model Group:NLRS_22.21_WA_kern 06--51_gen:4749465
8879493 | 30 dertigste verdieping | Model Group:NLRS_22.21_WA_kern 06--51_gen:4749465
8879495 | 30 dertigste verdieping | Model Group:NLRS_22.21_WA_kern 06--51_gen:4749465
8879497 | 30 dertigste verdieping | Model Group:NLRS_22.21_WA_kern 06--51_gen:4749465
8879499 | 30 dertigste verdieping | Model Group:NLRS_22.21_WA_kern 06--51_gen:4749465
8879546 | 31 eenendertigste verdieping | Model Group:NLRS_22.21_WA_kern 06--51_gen:4749897
8879548 | 31 eenendertigste verdieping | Model Group:NLRS_22.21_WA_kern 06--51_gen:4749897
8879550 | 31 eenendertigste verdieping | Model Group:NLRS_22.21_WA_kern 06--51_gen:4749897
8879552 | 31 eenendertigste verdieping | Model Group:NLRS_22.21_WA_kern 06--51_gen:4749897
8879554 | 31 eenendertigste verdieping | Model Group:NLRS_22.21_WA_kern 06--51_gen:4749897
8879556 | 31 eenendertigste verdieping | Model Group:NLRS_22.21_WA_kern 06--51_gen:4749897
8879603 | 32 tweeëndertigste verdieping | Model Group:NLRS_22.21_WA_kern 06--51_gen:4750329
8879605 | 32 tweeëndertigste verdieping | Model Group:NLRS_22.21_WA_kern 06--51_gen:4750329
8879607 | 32 tweeëndertigste verdieping | Model Group:NLRS_22.21_WA_kern 06--51_gen:4750329
8879609 | 32 tweeëndertigste verdieping | Model Group:NLRS_22.21_WA_kern 06--51_gen:4750329
8879611 | 32 tweeëndertigste verdieping | Model Group:NLRS_22.21_WA_kern 06--51_gen:4750329
8879613 | 32 tweeëndertigste verdieping | Model Group:NLRS_22.21_WA_kern 06--51_gen:4750329
8879660 | 33 drieëndertigste verdieping | Model Group:NLRS_22.21_WA_kern 06--51_gen:4750761
8879662 | 33 drieëndertigste verdieping | Model Group:NLRS_22.21_WA_kern 06--51_gen:4750761
8879664 | 33 drieëndertigste verdieping | Model Group:NLRS_22.21_WA_kern 06--51_gen:4750761
8879666 | 33 drieëndertigste verdieping | Model Group:NLRS_22.21_WA_kern 06--51_gen:4750761
8879668 | 33 drieëndertigste verdieping | Model Group:NLRS_22.21_WA_kern 06--51_gen:4750761
8879670 | 33 drieëndertigste verdieping | Model Group:NLRS_22.21_WA_kern 06--51_gen:4750761
8879717 | 34 vierendertigste verdieping | Model Group:NLRS_22.21_WA_kern 06--51_gen:4751193
8879719 | 34 vierendertigste verdieping | Model Group:NLRS_22.21_WA_kern 06--51_gen:4751193
8879721 | 34 vierendertigste verdieping | Model Group:NLRS_22.21_WA_kern 06--51_gen:4751193
8879723 | 34 vierendertigste verdieping | Model Group:NLRS_22.21_WA_kern 06--51_gen:4751193
8879725 | 34 vierendertigste verdieping | Model Group:NLRS_22.21_WA_kern 06--51_gen:4751193
8879727 | 34 vierendertigste verdieping | Model Group:NLRS_22.21_WA_kern 06--51_gen:4751193
8879774 | 35 vijfendertigste verdieping | Model Group:NLRS_22.21_WA_kern 06--51_gen:4751625
8879776 | 35 vijfendertigste verdieping | Model Group:NLRS_22.21_WA_kern 06--51_gen:4751625
8879778 | 35 vijfendertigste verdieping | Model Group:NLRS_22.21_WA_kern 06--51_gen:4751625
8879780 | 35 vijfendertigste verdieping | Model Group:NLRS_22.21_WA_kern 06--51_gen:4751625
8879782 | 35 vijfendertigste verdieping | Model Group:NLRS_22.21_WA_kern 06--51_gen:4751625
8879784 | 35 vijfendertigste verdieping | Model Group:NLRS_22.21_WA_kern 06--51_gen:4751625
8879831 | 36 zesendertigste verdieping | Model Group:NLRS_22.21_WA_kern 06--51_gen:4752057
8879833 | 36 zesendertigste verdieping | Model Group:NLRS_22.21_WA_kern 06--51_gen:4752057
8879835 | 36 zesendertigste verdieping | Model Group:NLRS_22.21_WA_kern 06--51_gen:4752057
8879837 | 36 zesendertigste verdieping | Model Group:NLRS_22.21_WA_kern 06--51_gen:4752057
8879839 | 36 zesendertigste verdieping | Model Group:NLRS_22.21_WA_kern 06--51_gen:4752057
8879841 | 36 zesendertigste verdieping | Model Group:NLRS_22.21_WA_kern 06--51_gen:4752057
8879888 | 37 zevenendertigste verdieping | Model Group:NLRS_22.21_WA_kern 06--51_gen:4752489
8879890 | 37 zevenendertigste verdieping | Model Group:NLRS_22.21_WA_kern 06--51_gen:4752489
8879892 | 37 zevenendertigste verdieping | Model Group:NLRS_22.21_WA_kern 06--51_gen:4752489
8879894 | 37 zevenendertigste verdieping | Model Group:NLRS_22.21_WA_kern 06--51_gen:4752489
8879896 | 37 zevenendertigste verdieping | Model Group:NLRS_22.21_WA_kern 06--51_gen:4752489
8879898 | 37 zevenendertigste verdieping | Model Group:NLRS_22.21_WA_kern 06--51_gen:4752489
8879945 | 38 achtendertigste verdieping | Model Group:NLRS_22.21_WA_kern 06--51_gen:4752921
8879947 | 38 achtendertigste verdieping | Model Group:NLRS_22.21_WA_kern 06--51_gen:4752921
8879949 | 38 achtendertigste verdieping | Model Group:NLRS_22.21_WA_kern 06--51_gen:4752921
8879951 | 38 achtendertigste verdieping | Model Group:NLRS_22.21_WA_kern 06--51_gen:4752921
8879953 | 38 achtendertigste verdieping | Model Group:NLRS_22.21_WA_kern 06--51_gen:4752921
8879955 | 38 achtendertigste verdieping | Model Group:NLRS_22.21_WA_kern 06--51_gen:4752921
8880002 | 39 negenendertigste verdieping | Model Group:NLRS_22.21_WA_kern 06--51_gen:4753353
8880004 | 39 negenendertigste verdieping | Model Group:NLRS_22.21_WA_kern 06--51_gen:4753353
8880006 | 39 negenendertigste verdieping | Model Group:NLRS_22.21_WA_kern 06--51_gen:4753353
8880008 | 39 negenendertigste verdieping | Model Group:NLRS_22.21_WA_kern 06--51_gen:4753353
8880010 | 39 negenendertigste verdieping | Model Group:NLRS_22.21_WA_kern 06--51_gen:4753353
8880012 | 39 negenendertigste verdieping | Model Group:NLRS_22.21_WA_kern 06--51_gen:4753353
8880059 | 40 veertigste verdieping | Model Group:NLRS_22.21_WA_kern 06--51_gen:4753785
8880061 | 40 veertigste verdieping | Model Group:NLRS_22.21_WA_kern 06--51_gen:4753785
8880063 | 40 veertigste verdieping | Model Group:NLRS_22.21_WA_kern 06--51_gen:4753785
8880065 | 40 veertigste verdieping | Model Group:NLRS_22.21_WA_kern 06--51_gen:4753785
8880067 | 40 veertigste verdieping | Model Group:NLRS_22.21_WA_kern 06--51_gen:4753785
8880069 | 40 veertigste verdieping | Model Group:NLRS_22.21_WA_kern 06--51_gen:4753785
8880116 | 22 tweeëntwintigste verdieping | Model Group:NLRS_22.21_WA_kern 06--51_gen:4778253
8880118 | 22 tweeëntwintigste verdieping | Model Group:NLRS_22.21_WA_kern 06--51_gen:4778253
8880120 | 22 tweeëntwintigste verdieping | Model Group:NLRS_22.21_WA_kern 06--51_gen:4778253
8880122 | 22 tweeëntwintigste verdieping | Model Group:NLRS_22.21_WA_kern 06--51_gen:4778253
8880124 | 22 tweeëntwintigste verdieping | Model Group:NLRS_22.21_WA_kern 06--51_gen:4778253
8880126 | 22 tweeëntwintigste verdieping | Model Group:NLRS_22.21_WA_kern 06--51_gen:4778253
8880173 | 23 drieëntwintigste verdieping | Model Group:NLRS_22.21_WA_kern 06--51_gen:4779836
8880175 | 23 drieëntwintigste verdieping | Model Group:NLRS_22.21_WA_kern 06--51_gen:4779836
8880177 | 23 drieëntwintigste verdieping | Model Group:NLRS_22.21_WA_kern 06--51_gen:4779836
8880179 | 23 drieëntwintigste verdieping | Model Group:NLRS_22.21_WA_kern 06--51_gen:4779836
8880181 | 23 drieëntwintigste verdieping | Model Group:NLRS_22.21_WA_kern 06--51_gen:4779836
8880183 | 23 drieëntwintigste verdieping | Model Group:NLRS_22.21_WA_kern 06--51_gen:4779836
8880230 | 41 eenenveertigste verdieping | Model Group:NLRS_22.21_WA_kern 06--51_gen:4783953
8880232 | 41 eenenveertigste verdieping | Model Group:NLRS_22.21_WA_kern 06--51_gen:4783953
8880234 | 41 eenenveertigste verdieping | Model Group:NLRS_22.21_WA_kern 06--51_gen:4783953
8880236 | 41 eenenveertigste verdieping | Model Group:NLRS_22.21_WA_kern 06--51_gen:4783953
8880238 | 41 eenenveertigste verdieping | Model Group:NLRS_22.21_WA_kern 06--51_gen:4783953
8880240 | 41 eenenveertigste verdieping | Model Group:NLRS_22.21_WA_kern 06--51_gen:4783953
8880287 | 43 drieënveertigste verdieping | Model Group:NLRS_22.21_WA_kern 06--51_gen:4788999
8880289 | 43 drieënveertigste verdieping | Model Group:NLRS_22.21_WA_kern 06--51_gen:4788999
8880291 | 43 drieënveertigste verdieping | Model Group:NLRS_22.21_WA_kern 06--51_gen:4788999
8880293 | 43 drieënveertigste verdieping | Model Group:NLRS_22.21_WA_kern 06--51_gen:4788999
8880295 | 43 drieënveertigste verdieping | Model Group:NLRS_22.21_WA_kern 06--51_gen:4788999
8880297 | 43 drieënveertigste verdieping | Model Group:NLRS_22.21_WA_kern 06--51_gen:4788999
8880344 | 44 vierenveertigste verdieping | Model Group:NLRS_22.21_WA_kern 06--51_gen:4789431
8880346 | 44 vierenveertigste verdieping | Model Group:NLRS_22.21_WA_kern 06--51_gen:4789431
8880348 | 44 vierenveertigste verdieping | Model Group:NLRS_22.21_WA_kern 06--51_gen:4789431
8880350 | 44 vierenveertigste verdieping | Model Group:NLRS_22.21_WA_kern 06--51_gen:4789431
8880352 | 44 vierenveertigste verdieping | Model Group:NLRS_22.21_WA_kern 06--51_gen:4789431
8880354 | 44 vierenveertigste verdieping | Model Group:NLRS_22.21_WA_kern 06--51_gen:4789431
8880401 | 45 vijfenveertigste verdieping | Model Group:NLRS_22.21_WA_kern 06--51_gen:4789863
8880403 | 45 vijfenveertigste verdieping | Model Group:NLRS_22.21_WA_kern 06--51_gen:4789863
8880405 | 45 vijfenveertigste verdieping | Model Group:NLRS_22.21_WA_kern 06--51_gen:4789863
8880407 | 45 vijfenveertigste verdieping | Model Group:NLRS_22.21_WA_kern 06--51_gen:4789863
8880409 | 45 vijfenveertigste verdieping | Model Group:NLRS_22.21_WA_kern 06--51_gen:4789863
8880411 | 45 vijfenveertigste verdieping | Model Group:NLRS_22.21_WA_kern 06--51_gen:4789863
8880458 | 46 zesenveertigste verdieping | Model Group:NLRS_22.21_WA_kern 06--51_gen:4790295
8880460 | 46 zesenveertigste verdieping | Model Group:NLRS_22.21_WA_kern 06--51_gen:4790295
8880462 | 46 zesenveertigste verdieping | Model Group:NLRS_22.21_WA_kern 06--51_gen:4790295
8880464 | 46 zesenveertigste verdieping | Model Group:NLRS_22.21_WA_kern 06--51_gen:4790295
8880466 | 46 zesenveertigste verdieping | Model Group:NLRS_22.21_WA_kern 06--51_gen:4790295
8880468 | 46 zesenveertigste verdieping | Model Group:NLRS_22.21_WA_kern 06--51_gen:4790295
8880515 | 47 zevenenveertigste verdieping | Model Group:NLRS_22.21_WA_kern 06--51_gen:4790727
8880517 | 47 zevenenveertigste verdieping | Model Group:NLRS_22.21_WA_kern 06--51_gen:4790727
8880519 | 47 zevenenveertigste verdieping | Model Group:NLRS_22.21_WA_kern 06--51_gen:4790727
8880521 | 47 zevenenveertigste verdieping | Model Group:NLRS_22.21_WA_kern 06--51_gen:4790727
8880523 | 47 zevenenveertigste verdieping | Model Group:NLRS_22.21_WA_kern 06--51_gen:4790727
8880525 | 47 zevenenveertigste verdieping | Model Group:NLRS_22.21_WA_kern 06--51_gen:4790727
8880572 | 48 achtenveertigste verdieping | Model Group:NLRS_22.21_WA_kern 06--51_gen:4791159
8880574 | 48 achtenveertigste verdieping | Model Group:NLRS_22.21_WA_kern 06--51_gen:4791159
8880576 | 48 achtenveertigste verdieping | Model Group:NLRS_22.21_WA_kern 06--51_gen:4791159
8880578 | 48 achtenveertigste verdieping | Model Group:NLRS_22.21_WA_kern 06--51_gen:4791159
8880580 | 48 achtenveertigste verdieping | Model Group:NLRS_22.21_WA_kern 06--51_gen:4791159
8880582 | 48 achtenveertigste verdieping | Model Group:NLRS_22.21_WA_kern 06--51_gen:4791159
8880629 | 49 negenenveertigste verdieping | Model Group:NLRS_22.21_WA_kern 06--51_gen:4791591
8880631 | 49 negenenveertigste verdieping | Model Group:NLRS_22.21_WA_kern 06--51_gen:4791591
8880633 | 49 negenenveertigste verdieping | Model Group:NLRS_22.21_WA_kern 06--51_gen:4791591
8880635 | 49 negenenveertigste verdieping | Model Group:NLRS_22.21_WA_kern 06--51_gen:4791591
8880637 | 49 negenenveertigste verdieping | Model Group:NLRS_22.21_WA_kern 06--51_gen:4791591
8880639 | 49 negenenveertigste verdieping | Model Group:NLRS_22.21_WA_kern 06--51_gen:4791591
8880686 | 50 vijftigste verdieping | Model Group:NLRS_22.21_WA_kern 06--51_gen:4792023
8880688 | 50 vijftigste verdieping | Model Group:NLRS_22.21_WA_kern 06--51_gen:4792023
8880690 | 50 vijftigste verdieping | Model Group:NLRS_22.21_WA_kern 06--51_gen:4792023
8880692 | 50 vijftigste verdieping | Model Group:NLRS_22.21_WA_kern 06--51_gen:4792023
8880694 | 50 vijftigste verdieping | Model Group:NLRS_22.21_WA_kern 06--51_gen:4792023
8880696 | 50 vijftigste verdieping | Model Group:NLRS_22.21_WA_kern 06--51_gen:4792023
8880743 | 42 tweeënveertigste verdieping | Model Group:NLRS_22.21_WA_kern 06--51_gen:4803472
8880745 | 42 tweeënveertigste verdieping | Model Group:NLRS_22.21_WA_kern 06--51_gen:4803472
8880747 | 42 tweeënveertigste verdieping | Model Group:NLRS_22.21_WA_kern 06--51_gen:4803472
8880749 | 42 tweeënveertigste verdieping | Model Group:NLRS_22.21_WA_kern 06--51_gen:4803472
8880751 | 42 tweeënveertigste verdieping | Model Group:NLRS_22.21_WA_kern 06--51_gen:4803472
8880753 | 42 tweeënveertigste verdieping | Model Group:NLRS_22.21_WA_kern 06--51_gen:4803472
8880800 | 51 eenenvijftigste verdieping | Model Group:NLRS_22.21_WA_kern 06--51_gen:4980182
8880802 | 51 eenenvijftigste verdieping | Model Group:NLRS_22.21_WA_kern 06--51_gen:4980182
8880804 | 51 eenenvijftigste verdieping | Model Group:NLRS_22.21_WA_kern 06--51_gen:4980182
8880806 | 51 eenenvijftigste verdieping | Model Group:NLRS_22.21_WA_kern 06--51_gen:4980182
8880808 | 51 eenenvijftigste verdieping | Model Group:NLRS_22.21_WA_kern 06--51_gen:4980182
8880810 | 51 eenenvijftigste verdieping | Model Group:NLRS_22.21_WA_kern 06--51_gen:4980182
11859544 | 52 tweeënvijftigste verdieping
12876952 | 00 begane grond
12883095 | 01 eerste verdieping
12884611 | 02 tweede verdieping

# IfcWallStandardCase: Basic Wall:NLRS_22.21_WA_beton prefab d=250_gen (34)
Type - PredefinedType: STANDARD; Material: NLRS_f2_beton prefab 250 mm
Classification: 22.21 binnenwanden - constructief, massieve wanden (Uniformat)
Pset_WallCommon - LoadBearing: yes; IsExternal: no; ExtendToStructure: no; Reference: NLRS_22.21_WA_beton prefab d=250_gen; ThermalTransmittance: 4.184 kg/K/s3
Name (Basic Wall:NLRS_22.21_WA_beton prefab d=250_gen:...) | In
4832686 | 03 derde verdieping | Group: Model Group:NLRS_22.21_WA_kern 01--04_gen:4832721
4869698 | 02 tweede verdieping | Group: Model Group:NLRS_22.21_WA_kern 01--04_gen:4869716
4870136 | 01 eerste verdieping
4870836 | 00a eerste tussenverdieping
4876000 | 00 begane grond | Group: Model Group:NLRS_22.21_WA_kern 00_gen:4876018
4941772 | 04 vierde verdieping | Group: Model Group:NLRS_22.21_WA_kern 01--04_gen:4941798
5013012 | 54 vierenvijftigste verdieping
5013046 | 54 vierenvijftigste verdieping
5013077 | 54 vierenvijftigste verdieping
5013111 | 54 vierenvijftigste verdieping
5033396 | 55 vijfenvijftigste verdieping
5033637 | 55 vijfenvijftigste verdieping
5033694 | 55 vijfenvijftigste verdieping
5034777 | 56 zesenvijftigste verdieping
5034832 | 56 zesenvijftigste verdieping
5034887 | 56 zesenvijftigste verdieping
5034944 | 56 zesenvijftigste verdieping
10294645 | 57 zevenenvijftigste verdieping
10294648 | 57 zevenenvijftigste verdieping
10294653 | 57 zevenenvijftigste verdieping
10294656 | 57 zevenenvijftigste verdieping
10294774 | 58 achtenvijftigste verdieping
10294777 | 58 achtenvijftigste verdieping
10294782 | 58 achtenvijftigste verdieping
10294785 | 58 achtenvijftigste verdieping
14236395 | 59 negenenvijftigste verdieping
14243197 | 59 negenenvijftigste verdieping
14243484 | 59 negenenvijftigste verdieping
14243843 | 59 negenenvijftigste verdieping
14245033 | 58 achtenvijftigste verdieping
14245036 | 58 achtenvijftigste verdieping
14245039 | 58 achtenvijftigste verdieping
14245042 | 58 achtenvijftigste verdieping
14269845 | 55 vijfenvijftigste verdieping

# IfcWallStandardCase: Basic Wall:NLRS_22.21_WA_beton prefab d=300_gen (286)
Type - PredefinedType: STANDARD; Material: NLRS_f2_beton prefab 300 mm
Classification: 22.21 binnenwanden - constructief, massieve wanden (Uniformat)
Pset_WallCommon - LoadBearing: yes; IsExternal: no; ExtendToStructure: no; Reference: NLRS_22.21_WA_beton prefab d=300_gen; ThermalTransmittance: 3.48667 kg/K/s3
Name (Basic Wall:NLRS_22.21_WA_beton prefab d=300_gen:...) | In | Group
4160959 | 00 begane grond
4160991 | 00 begane grond
4313127 | 00a eerste tussenverdieping
4415441 | 01 eerste verdieping
4446868 | 02 tweede verdieping
4690662 | 06 zesde verdieping | Model Group:NLRS_01.00_verdieping type B1_gen:4644030
4691004 | 06 zesde verdieping | Model Group:NLRS_01.00_verdieping type B1_gen:4644030
4695261 | 21 eenentwintigste verdieping | Model Group:NLRS_01.00_verdieping type F1_gen:4694955
4695320 | 21 eenentwintigste verdieping | Model Group:NLRS_01.00_verdieping type F1_gen:4694955
4783689 | 41 eenenveertigste verdieping | Model Group:NLRS_01.00_verdieping type M_gen:4783248
4783691 | 41 eenenveertigste verdieping | Model Group:NLRS_01.00_verdieping type M_gen:4783248
4783693 | 41 eenenveertigste verdieping | Model Group:NLRS_01.00_verdieping type M_gen:4783248
4783973 | 41 eenenveertigste verdieping | Model Group:NLRS_01.00_verdieping type M_gen:4783248
4783977 | 41 eenenveertigste verdieping | Model Group:NLRS_01.00_verdieping type M_gen:4783248
4783981 | 41 eenenveertigste verdieping | Model Group:NLRS_01.00_verdieping type M_gen:4783248
4784021 | 41 eenenveertigste verdieping | Model Group:NLRS_01.00_verdieping type M_gen:4783248
4784024 | 41 eenenveertigste verdieping | Model Group:NLRS_01.00_verdieping type M_gen:4783248
4784027 | 41 eenenveertigste verdieping | Model Group:NLRS_01.00_verdieping type M_gen:4783248
4784030 | 41 eenenveertigste verdieping | Model Group:NLRS_01.00_verdieping type M_gen:4783248
4784033 | 41 eenenveertigste verdieping | Model Group:NLRS_01.00_verdieping type M_gen:4783248
4784095 | 41 eenenveertigste verdieping | Model Group:NLRS_01.00_verdieping type M_gen:4783248
4784098 | 41 eenenveertigste verdieping | Model Group:NLRS_01.00_verdieping type M_gen:4783248
4784100 | 41 eenenveertigste verdieping | Model Group:NLRS_01.00_verdieping type M_gen:4783248
4803208 | 42 tweeënveertigste verdieping | Model Group:NLRS_01.00_verdieping type N_gen:9026295
4803210 | 42 tweeënveertigste verdieping | Model Group:NLRS_01.00_verdieping type N_gen:9026295
4803212 | 42 tweeënveertigste verdieping | Model Group:NLRS_01.00_verdieping type N_gen:9026295
4803492 | 42 tweeënveertigste verdieping | Model Group:NLRS_01.00_verdieping type N_gen:9026295
4803496 | 42 tweeënveertigste verdieping | Model Group:NLRS_01.00_verdieping type N_gen:9026295
4803500 | 42 tweeënveertigste verdieping | Model Group:NLRS_01.00_verdieping type N_gen:9026295
4803540 | 42 tweeënveertigste verdieping | Model Group:NLRS_01.00_verdieping type N_gen:9026295
4803543 | 42 tweeënveertigste verdieping | Model Group:NLRS_01.00_verdieping type N_gen:9026295
4803546 | 42 tweeënveertigste verdieping | Model Group:NLRS_01.00_verdieping type N_gen:9026295
4803549 | 42 tweeënveertigste verdieping | Model Group:NLRS_01.00_verdieping type N_gen:9026295
4803552 | 42 tweeënveertigste verdieping | Model Group:NLRS_01.00_verdieping type N_gen:9026295
4803614 | 42 tweeënveertigste verdieping | Model Group:NLRS_01.00_verdieping type N_gen:9026295
4803617 | 42 tweeënveertigste verdieping | Model Group:NLRS_01.00_verdieping type N_gen:9026295
4803619 | 42 tweeënveertigste verdieping | Model Group:NLRS_01.00_verdieping type N_gen:9026295
4880947 | 01 eerste verdieping
4979942 | 51 eenenvijftigste verdieping | Model Group:NLRS_01.00_verdieping type R_gen:4806332
4979944 | 51 eenenvijftigste verdieping | Model Group:NLRS_01.00_verdieping type R_gen:4806332
4979946 | 51 eenenvijftigste verdieping | Model Group:NLRS_01.00_verdieping type R_gen:4806332
4979960 | 51 eenenvijftigste verdieping
4979962 | 51 eenenvijftigste verdieping
4980010 | 51 eenenvijftigste verdieping
4980014 | 51 eenenvijftigste verdieping
4980202 | 51 eenenvijftigste verdieping | Model Group:NLRS_01.00_verdieping type R_gen:4806332
4980206 | 51 eenenvijftigste verdieping | Model Group:NLRS_01.00_verdieping type R_gen:4806332
4980210 | 51 eenenvijftigste verdieping | Model Group:NLRS_01.00_verdieping type R_gen:4806332
4980250 | 51 eenenvijftigste verdieping | Model Group:NLRS_01.00_verdieping type R_gen:4806332
4980253 | 51 eenenvijftigste verdieping | Model Group:NLRS_01.00_verdieping type R_gen:4806332
4980256 | 51 eenenvijftigste verdieping | Model Group:NLRS_01.00_verdieping type R_gen:4806332
4980259 | 51 eenenvijftigste verdieping | Model Group:NLRS_01.00_verdieping type R_gen:4806332
4980262 | 51 eenenvijftigste verdieping | Model Group:NLRS_01.00_verdieping type R_gen:4806332
4980324 | 51 eenenvijftigste verdieping | Model Group:NLRS_01.00_verdieping type R_gen:4806332
4980327 | 51 eenenvijftigste verdieping | Model Group:NLRS_01.00_verdieping type R_gen:4806332
4980329 | 51 eenenvijftigste verdieping | Model Group:NLRS_01.00_verdieping type R_gen:4806332
4981714 | 52 tweeënvijftigste verdieping
4981716 | 52 tweeënvijftigste verdieping
4981718 | 52 tweeënvijftigste verdieping
4981978 | 52 tweeënvijftigste verdieping
4981982 | 52 tweeënvijftigste verdieping
4982025 | 52 tweeënvijftigste verdieping
4982028 | 52 tweeënvijftigste verdieping
4982034 | 52 tweeënvijftigste verdieping
4982096 | 52 tweeënvijftigste verdieping
4982099 | 52 tweeënvijftigste verdieping
4982101 | 52 tweeënvijftigste verdieping
4984989 | 51 eenenvijftigste verdieping
4985397 | 51 eenenvijftigste verdieping
4985499 | 51 eenenvijftigste verdieping
4985793 | 51 eenenvijftigste verdieping
4985990 | 52 tweeënvijftigste verdieping
4985992 | 52 tweeënvijftigste verdieping
4985994 | 52 tweeënvijftigste verdieping
4985996 | 52 tweeënvijftigste verdieping
4986182 | 51 eenenvijftigste verdieping
4986301 | 51 eenenvijftigste verdieping
4986403 | 51 eenenvijftigste verdieping
4986460 | 51 eenenvijftigste verdieping
4986554 | 52 tweeënvijftigste verdieping
4986624 | 52 tweeënvijftigste verdieping
4986694 | 52 tweeënvijftigste verdieping
4986754 | 52 tweeënvijftigste verdieping
5012149 | 52 tweeënvijftigste verdieping
5012685 | 53 drieënvijftigste verdieping
5012725 | 53 drieënvijftigste verdieping
5012762 | 53 drieënvijftigste verdieping
5012803 | 53 drieënvijftigste verdieping
5147596 | 05 vijfde verdieping
5147623 | 05 vijfde verdieping
5667396 | 09 negende verdieping | Model Group:NLRS_01.00_verdieping type C2_gen:4703193
5667446 | 09 negende verdieping | Model Group:NLRS_01.00_verdieping type C2_gen:4703193
8986263 | 22 tweeëntwintigste verdieping | Model Group:NLRS_01.00_verdieping type G_gen:8994214
8986272 | 22 tweeëntwintigste verdieping | Model Group:NLRS_01.00_verdieping type G_gen:8994214
8996027 | 24 vierentwintigste verdieping | Model Group:NLRS_01.00_verdieping type H_gen:4746600
8996036 | 24 vierentwintigste verdieping | Model Group:NLRS_01.00_verdieping type H_gen:4746600
8996319 | 25 vijfentwintigste verdieping | Model Group:NLRS_01.00_verdieping type J_gen:4747032
8996328 | 25 vijfentwintigste verdieping | Model Group:NLRS_01.00_verdieping type J_gen:4747032
8996611 | 26 zesentwintigste verdieping | Model Group:NLRS_01.00_verdieping type K_gen:4747464
8996620 | 26 zesentwintigste verdieping | Model Group:NLRS_01.00_verdieping type K_gen:4747464
8997779 | 30 dertigste verdieping | Model Group:NLRS_01.00_verdieping (type L)_gen:4749192
8997788 | 30 dertigste verdieping | Model Group:NLRS_01.00_verdieping (type L)_gen:4749192
9028064 | 47 zevenenveertigste verdieping | Model Group:NLRS_01.00_verdieping type O_gen:4790454
9028066 | 47 zevenenveertigste verdieping | Model Group:NLRS_01.00_verdieping type O_gen:4790454
9028068 | 47 zevenenveertigste verdieping | Model Group:NLRS_01.00_verdieping type O_gen:4790454
9028074 | 47 zevenenveertigste verdieping | Model Group:NLRS_01.00_verdieping type O_gen:4790454
9028077 | 47 zevenenveertigste verdieping | Model Group:NLRS_01.00_verdieping type O_gen:4790454
9028080 | 47 zevenenveertigste verdieping | Model Group:NLRS_01.00_verdieping type O_gen:4790454
9028083 | 47 zevenenveertigste verdieping | Model Group:NLRS_01.00_verdieping type O_gen:4790454
9028086 | 47 zevenenveertigste verdieping | Model Group:NLRS_01.00_verdieping type O_gen:4790454
9028089 | 47 zevenenveertigste verdieping | Model Group:NLRS_01.00_verdieping type O_gen:4790454
9028092 | 47 zevenenveertigste verdieping | Model Group:NLRS_01.00_verdieping type O_gen:4790454
9028095 | 47 zevenenveertigste verdieping | Model Group:NLRS_01.00_verdieping type O_gen:4790454
9028099 | 47 zevenenveertigste verdieping | Model Group:NLRS_01.00_verdieping type O_gen:4790454
9028102 | 47 zevenenveertigste verdieping | Model Group:NLRS_01.00_verdieping type O_gen:4790454
9028104 | 47 zevenenveertigste verdieping | Model Group:NLRS_01.00_verdieping type O_gen:4790454
9028940 | 50 vijftigste verdieping | Model Group:NLRS_01.00_verdieping type P_gen:4791750
9028942 | 50 vijftigste verdieping | Model Group:NLRS_01.00_verdieping type P_gen:4791750
9028944 | 50 vijftigste verdieping | Model Group:NLRS_01.00_verdieping type P_gen:4791750
9028950 | 50 vijftigste verdieping | Model Group:NLRS_01.00_verdieping type P_gen:4791750
9028953 | 50 vijftigste verdieping | Model Group:NLRS_01.00_verdieping type P_gen:4791750
9028956 | 50 vijftigste verdieping | Model Group:NLRS_01.00_verdieping type P_gen:4791750
9028959 | 50 vijftigste verdieping | Model Group:NLRS_01.00_verdieping type P_gen:4791750
9028962 | 50 vijftigste verdieping | Model Group:NLRS_01.00_verdieping type P_gen:4791750
9028965 | 50 vijftigste verdieping | Model Group:NLRS_01.00_verdieping type P_gen:4791750
9028968 | 50 vijftigste verdieping | Model Group:NLRS_01.00_verdieping type P_gen:4791750
9028971 | 50 vijftigste verdieping | Model Group:NLRS_01.00_verdieping type P_gen:4791750
9028975 | 50 vijftigste verdieping | Model Group:NLRS_01.00_verdieping type P_gen:4791750
9028978 | 50 vijftigste verdieping | Model Group:NLRS_01.00_verdieping type P_gen:4791750
9028980 | 50 vijftigste verdieping | Model Group:NLRS_01.00_verdieping type P_gen:4791750
9036748 | 16 zestiende verdieping | Model Group:NLRS_01.00_verdieping type E_gen:4739081
9036757 | 16 zestiende verdieping | Model Group:NLRS_01.00_verdieping type E_gen:4739081
9050668 | 15 vijftiende verdieping | Model Group:NLRS_01.00_verdieping type D_gen:4731036
9050677 | 15 vijftiende verdieping | Model Group:NLRS_01.00_verdieping type D_gen:4731036
9050964 | 17 zeventiende verdieping | Model Group:NLRS_01.00_verdieping type D_gen:4731494
9050973 | 17 zeventiende verdieping | Model Group:NLRS_01.00_verdieping type D_gen:4731494
9090936 | 07 zevende verdieping | Model Group:NLRS_01.00_verdieping type C1_gen:4689025
9090945 | 07 zevende verdieping | Model Group:NLRS_01.00_verdieping type C1_gen:4689025
9125808 | 10 tiende verdieping | Model Group:NLRS_01.00_verdieping type B2_gen:9035827
9125819 | 10 tiende verdieping | Model Group:NLRS_01.00_verdieping type B2_gen:9035827
9126115 | 12 twaalfde verdieping | Model Group:NLRS_01.00_verdieping type B2_gen:4738165
9126126 | 12 twaalfde verdieping | Model Group:NLRS_01.00_verdieping type B2_gen:4738165
9126422 | 14 veertiende verdieping | Model Group:NLRS_01.00_verdieping type B2_gen:4738623
9126433 | 14 veertiende verdieping | Model Group:NLRS_01.00_verdieping type B2_gen:4738623
9128903 | 11 elfde verdieping | Model Group:NLRS_01.00_verdieping type C2_gen:9049706
9128912 | 11 elfde verdieping | Model Group:NLRS_01.00_verdieping type C2_gen:9049706
9129206 | 13 dertiende verdieping | Model Group:NLRS_01.00_verdieping type C2_gen:4730578
9129215 | 13 dertiende verdieping | Model Group:NLRS_01.00_verdieping type C2_gen:4730578
9131619 | 18 achttiende verdieping | Model Group:NLRS_01.00_verdieping type E_gen:4739539
9131628 | 18 achttiende verdieping | Model Group:NLRS_01.00_verdieping type E_gen:4739539
9132684 | 19 negentiende verdieping | Model Group:NLRS_01.00_verdieping type C2_gen:4731952
9132693 | 19 negentiende verdieping | Model Group:NLRS_01.00_verdieping type C2_gen:4731952
9133792 | 20 twintigste verdieping | Model Group:NLRS_01.00_verdieping type B2_gen:4739997
9133803 | 20 twintigste verdieping | Model Group:NLRS_01.00_verdieping type B2_gen:4739997
9134792 | 23 drieëntwintigste verdieping | Model Group:NLRS_01.00_verdieping type F2_gen:4779563
9134801 | 23 drieëntwintigste verdieping | Model Group:NLRS_01.00_verdieping type F2_gen:4779563
9135085 | 28 achtentwintigste verdieping | Model Group:NLRS_01.00_verdieping type F1_gen:4748328
9135094 | 28 achtentwintigste verdieping | Model Group:NLRS_01.00_verdieping type F1_gen:4748328
9135378 | 29 negenentwintigste verdieping | Model Group:NLRS_01.00_verdieping type F1_gen:4748760
9135387 | 29 negenentwintigste verdieping | Model Group:NLRS_01.00_verdieping type F1_gen:4748760
9135671 | 33 drieëndertigste verdieping | Model Group:NLRS_01.00_verdieping type F1_gen:4750488
9135680 | 33 drieëndertigste verdieping | Model Group:NLRS_01.00_verdieping type F1_gen:4750488
9138788 | 31 eenendertigste verdieping | Model Group:NLRS_01.00_verdieping type G_gen:4749624
9138797 | 31 eenendertigste verdieping | Model Group:NLRS_01.00_verdieping type G_gen:4749624
9139078 | 32 tweeëndertigste verdieping | Model Group:NLRS_01.00_verdieping type G_gen:4750056
9139087 | 32 tweeëndertigste verdieping | Model Group:NLRS_01.00_verdieping type G_gen:4750056
9140667 | 34 vierendertigste verdieping | Model Group:NLRS_01.00_verdieping type H_gen:4750920
9140676 | 34 vierendertigste verdieping | Model Group:NLRS_01.00_verdieping type H_gen:4750920
9141607 | 35 vijfendertigste verdieping | Model Group:NLRS_01.00_verdieping type J_gen:4751352
9141616 | 35 vijfendertigste verdieping | Model Group:NLRS_01.00_verdieping type J_gen:4751352
9142554 | 27 zevenentwintigste verdieping | Model Group:NLRS_01.00_verdieping type K_gen:4747896
9142563 | 27 zevenentwintigste verdieping | Model Group:NLRS_01.00_verdieping type K_gen:4747896
9142844 | 38 achtendertigste verdieping | Model Group:NLRS_01.00_verdieping type K_gen:4752648
9142853 | 38 achtendertigste verdieping | Model Group:NLRS_01.00_verdieping type K_gen:4752648
9143134 | 39 negenendertigste verdieping | Model Group:NLRS_01.00_verdieping type K_gen:4753080
9143143 | 39 negenendertigste verdieping | Model Group:NLRS_01.00_verdieping type K_gen:4753080
9145376 | 36 zesendertigste verdieping | Model Group:NLRS_01.00_verdieping type K_gen:4751784
9145385 | 36 zesendertigste verdieping | Model Group:NLRS_01.00_verdieping type K_gen:4751784
9145666 | 37 zevenendertigste verdieping | Model Group:NLRS_01.00_verdieping type K_gen:4752216
9145675 | 37 zevenendertigste verdieping | Model Group:NLRS_01.00_verdieping type K_gen:4752216
9147255 | 40 veertigste verdieping | Model Group:NLRS_01.00_verdieping (type L)_gen:4753512
9147264 | 40 veertigste verdieping | Model Group:NLRS_01.00_verdieping (type L)_gen:4753512
9148119 | 43 drieënveertigste verdieping | Model Group:NLRS_01.00_verdieping type N_gen:4788726
9148121 | 43 drieënveertigste verdieping | Model Group:NLRS_01.00_verdieping type N_gen:4788726
9148123 | 43 drieënveertigste verdieping | Model Group:NLRS_01.00_verdieping type N_gen:4788726
9148129 | 43 drieënveertigste verdieping | Model Group:NLRS_01.00_verdieping type N_gen:4788726
9148132 | 43 drieënveertigste verdieping | Model Group:NLRS_01.00_verdieping type N_gen:4788726
9148135 | 43 drieënveertigste verdieping | Model Group:NLRS_01.00_verdieping type N_gen:4788726
9148138 | 43 drieënveertigste verdieping | Model Group:NLRS_01.00_verdieping type N_gen:4788726
9148141 | 43 drieënveertigste verdieping | Model Group:NLRS_01.00_verdieping type N_gen:4788726
9148144 | 43 drieënveertigste verdieping | Model Group:NLRS_01.00_verdieping type N_gen:4788726
9148147 | 43 drieënveertigste verdieping | Model Group:NLRS_01.00_verdieping type N_gen:4788726
9148150 | 43 drieënveertigste verdieping | Model Group:NLRS_01.00_verdieping type N_gen:4788726
9148154 | 43 drieënveertigste verdieping | Model Group:NLRS_01.00_verdieping type N_gen:4788726
9148157 | 43 drieënveertigste verdieping | Model Group:NLRS_01.00_verdieping type N_gen:4788726
9148159 | 43 drieënveertigste verdieping | Model Group:NLRS_01.00_verdieping type N_gen:4788726
9148411 | 44 vierenveertigste verdieping | Model Group:NLRS_01.00_verdieping type N_44e verdieping_gen:4789158
9148413 | 44 vierenveertigste verdieping | Model Group:NLRS_01.00_verdieping type N_44e verdieping_gen:4789158
9148415 | 44 vierenveertigste verdieping | Model Group:NLRS_01.00_verdieping type N_44e verdieping_gen:4789158
9148421 | 44 vierenveertigste verdieping | Model Group:NLRS_01.00_verdieping type N_44e verdieping_gen:4789158
9148424 | 44 vierenveertigste verdieping | Model Group:NLRS_01.00_verdieping type N_44e verdieping_gen:4789158
9148427 | 44 vierenveertigste verdieping | Model Group:NLRS_01.00_verdieping type N_44e verdieping_gen:4789158
9148430 | 44 vierenveertigste verdieping | Model Group:NLRS_01.00_verdieping type N_44e verdieping_gen:4789158
9148433 | 44 vierenveertigste verdieping | Model Group:NLRS_01.00_verdieping type N_44e verdieping_gen:4789158
9148436 | 44 vierenveertigste verdieping | Model Group:NLRS_01.00_verdieping type N_44e verdieping_gen:4789158
9148439 | 44 vierenveertigste verdieping | Model Group:NLRS_01.00_verdieping type N_44e verdieping_gen:4789158
9148442 | 44 vierenveertigste verdieping | Model Group:NLRS_01.00_verdieping type N_44e verdieping_gen:4789158
9148446 | 44 vierenveertigste verdieping | Model Group:NLRS_01.00_verdieping type N_44e verdieping_gen:4789158
9148449 | 44 vierenveertigste verdieping | Model Group:NLRS_01.00_verdieping type N_44e verdieping_gen:4789158
9148451 | 44 vierenveertigste verdieping | Model Group:NLRS_01.00_verdieping type N_44e verdieping_gen:4789158
9148703 | 45 vijfenveertigste verdieping | Model Group:NLRS_01.00_verdieping type N_gen:4789590
9148705 | 45 vijfenveertigste verdieping | Model Group:NLRS_01.00_verdieping type N_gen:4789590
9148707 | 45 vijfenveertigste verdieping | Model Group:NLRS_01.00_verdieping type N_gen:4789590
9148713 | 45 vijfenveertigste verdieping | Model Group:NLRS_01.00_verdieping type N_gen:4789590
9148716 | 45 vijfenveertigste verdieping | Model Group:NLRS_01.00_verdieping type N_gen:4789590
9148719 | 45 vijfenveertigste verdieping | Model Group:NLRS_01.00_verdieping type N_gen:4789590
9148722 | 45 vijfenveertigste verdieping | Model Group:NLRS_01.00_verdieping type N_gen:4789590
9148725 | 45 vijfenveertigste verdieping | Model Group:NLRS_01.00_verdieping type N_gen:4789590
9148728 | 45 vijfenveertigste verdieping | Model Group:NLRS_01.00_verdieping type N_gen:4789590
9148731 | 45 vijfenveertigste verdieping | Model Group:NLRS_01.00_verdieping type N_gen:4789590
9148734 | 45 vijfenveertigste verdieping | Model Group:NLRS_01.00_verdieping type N_gen:4789590
9148738 | 45 vijfenveertigste verdieping | Model Group:NLRS_01.00_verdieping type N_gen:4789590
9148741 | 45 vijfenveertigste verdieping | Model Group:NLRS_01.00_verdieping type N_gen:4789590
9148743 | 45 vijfenveertigste verdieping | Model Group:NLRS_01.00_verdieping type N_gen:4789590
9148995 | 46 zesenveertigste verdieping | Model Group:NLRS_01.00_verdieping type N_gen:4790022
9148997 | 46 zesenveertigste verdieping | Model Group:NLRS_01.00_verdieping type N_gen:4790022
9148999 | 46 zesenveertigste verdieping | Model Group:NLRS_01.00_verdieping type N_gen:4790022
9149005 | 46 zesenveertigste verdieping | Model Group:NLRS_01.00_verdieping type N_gen:4790022
9149008 | 46 zesenveertigste verdieping | Model Group:NLRS_01.00_verdieping type N_gen:4790022
9149011 | 46 zesenveertigste verdieping | Model Group:NLRS_01.00_verdieping type N_gen:4790022
9149014 | 46 zesenveertigste verdieping | Model Group:NLRS_01.00_verdieping type N_gen:4790022
9149017 | 46 zesenveertigste verdieping | Model Group:NLRS_01.00_verdieping type N_gen:4790022
9149020 | 46 zesenveertigste verdieping | Model Group:NLRS_01.00_verdieping type N_gen:4790022
9149023 | 46 zesenveertigste verdieping | Model Group:NLRS_01.00_verdieping type N_gen:4790022
9149026 | 46 zesenveertigste verdieping | Model Group:NLRS_01.00_verdieping type N_gen:4790022
9149030 | 46 zesenveertigste verdieping | Model Group:NLRS_01.00_verdieping type N_gen:4790022
9149033 | 46 zesenveertigste verdieping | Model Group:NLRS_01.00_verdieping type N_gen:4790022
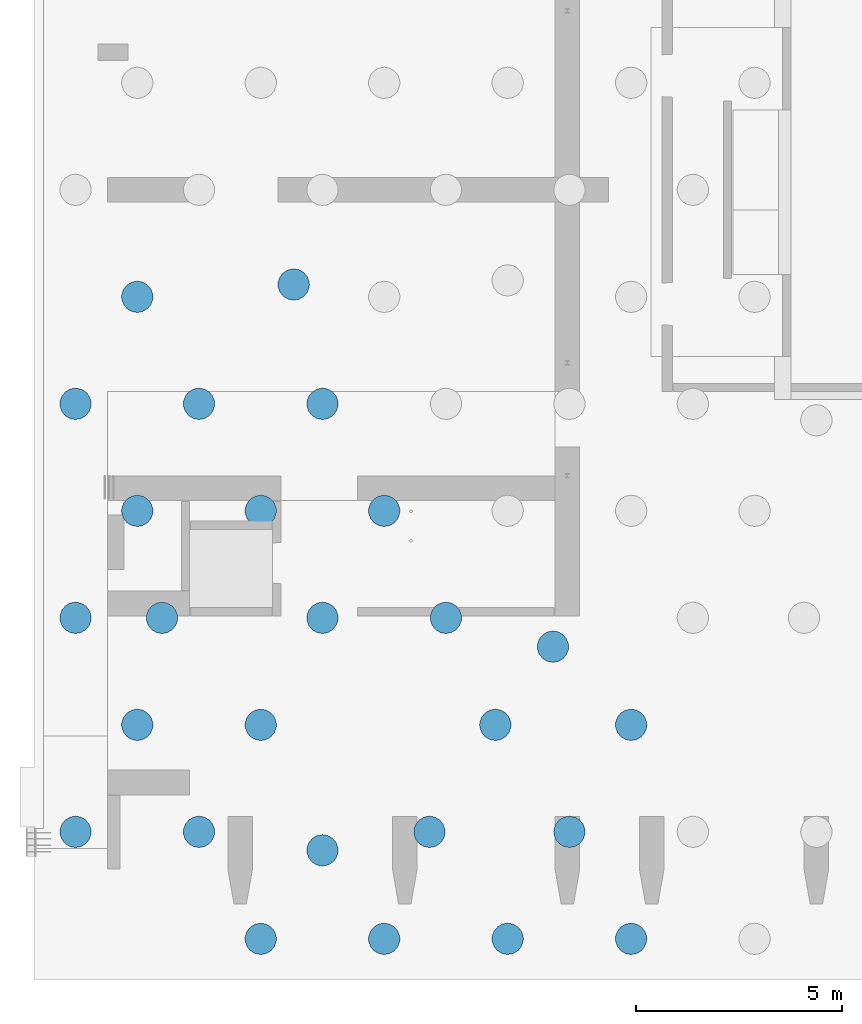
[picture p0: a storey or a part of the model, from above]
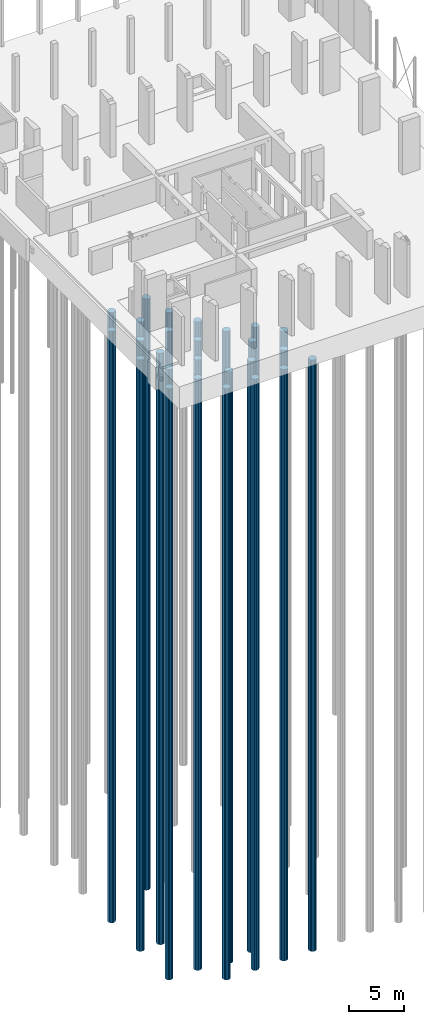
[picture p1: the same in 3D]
Properties of the parts of a building model (IFC2X3), part 21 of 21

# IfcWallStandardCase: Basic Wall:NLRS_22.21_WA_beton prefab d=300_gen (286)
Name (Basic Wall:NLRS_22.21_WA_beton prefab d=300_gen:...) | In | Group
9149035 | 46 zesenveertigste verdieping | Model Group:NLRS_01.00_verdieping type N_gen:4790022
9149287 | 49 negenenveertigste verdieping | Model Group:NLRS_01.00_verdieping type N_gen:4791318
9149289 | 49 negenenveertigste verdieping | Model Group:NLRS_01.00_verdieping type N_gen:4791318
9149291 | 49 negenenveertigste verdieping | Model Group:NLRS_01.00_verdieping type N_gen:4791318
9149297 | 49 negenenveertigste verdieping | Model Group:NLRS_01.00_verdieping type N_gen:4791318
9149300 | 49 negenenveertigste verdieping | Model Group:NLRS_01.00_verdieping type N_gen:4791318
9149303 | 49 negenenveertigste verdieping | Model Group:NLRS_01.00_verdieping type N_gen:4791318
9149306 | 49 negenenveertigste verdieping | Model Group:NLRS_01.00_verdieping type N_gen:4791318
9149309 | 49 negenenveertigste verdieping | Model Group:NLRS_01.00_verdieping type N_gen:4791318
9149312 | 49 negenenveertigste verdieping | Model Group:NLRS_01.00_verdieping type N_gen:4791318
9149315 | 49 negenenveertigste verdieping | Model Group:NLRS_01.00_verdieping type N_gen:4791318
9149318 | 49 negenenveertigste verdieping | Model Group:NLRS_01.00_verdieping type N_gen:4791318
9149322 | 49 negenenveertigste verdieping | Model Group:NLRS_01.00_verdieping type N_gen:4791318
9149325 | 49 negenenveertigste verdieping | Model Group:NLRS_01.00_verdieping type N_gen:4791318
9149327 | 49 negenenveertigste verdieping | Model Group:NLRS_01.00_verdieping type N_gen:4791318
9152809 | 48 achtenveertigste verdieping | Model Group:NLRS_01.00_verdieping type O_gen:4790886
9152811 | 48 achtenveertigste verdieping | Model Group:NLRS_01.00_verdieping type O_gen:4790886
9152813 | 48 achtenveertigste verdieping | Model Group:NLRS_01.00_verdieping type O_gen:4790886
9152819 | 48 achtenveertigste verdieping | Model Group:NLRS_01.00_verdieping type O_gen:4790886
9152822 | 48 achtenveertigste verdieping | Model Group:NLRS_01.00_verdieping type O_gen:4790886
9152825 | 48 achtenveertigste verdieping | Model Group:NLRS_01.00_verdieping type O_gen:4790886
9152828 | 48 achtenveertigste verdieping | Model Group:NLRS_01.00_verdieping type O_gen:4790886
9152831 | 48 achtenveertigste verdieping | Model Group:NLRS_01.00_verdieping type O_gen:4790886
9152834 | 48 achtenveertigste verdieping | Model Group:NLRS_01.00_verdieping type O_gen:4790886
9152837 | 48 achtenveertigste verdieping | Model Group:NLRS_01.00_verdieping type O_gen:4790886
9152840 | 48 achtenveertigste verdieping | Model Group:NLRS_01.00_verdieping type O_gen:4790886
9152844 | 48 achtenveertigste verdieping | Model Group:NLRS_01.00_verdieping type O_gen:4790886
9152847 | 48 achtenveertigste verdieping | Model Group:NLRS_01.00_verdieping type O_gen:4790886
9152849 | 48 achtenveertigste verdieping | Model Group:NLRS_01.00_verdieping type O_gen:4790886
10345384 | 00 begane grond
10345398 | 00 begane grond
10345410 | 00 begane grond
10345434 | 01 eerste verdieping
10345442 | 01 eerste verdieping
10345450 | 01 eerste verdieping
10345659 | 02 tweede verdieping
10345871 | 02 tweede verdieping
10356973 | 00 begane grond
10357213 | 01 eerste verdieping
10357388 | 02 tweede verdieping
10357649 | 00a eerste tussenverdieping
10357869 | 00a eerste tussenverdieping
10358189 | 01 eerste verdieping
10358313 | 02 tweede verdieping
10358527 | 00 begane grond
10412651 | 00 begane grond
10419475 | 01 eerste verdieping
10782745 | 08 achtste verdieping | Model Group:NLRS_01.00_verdieping type B1_gen:4714770
10782756 | 08 achtste verdieping | Model Group:NLRS_01.00_verdieping type B1_gen:4714770

# IfcWallStandardCase: Basic Wall:NLRS_22.21_WA_beton prefab d=300_gen 2 (2)
Type - PredefinedType: STANDARD; Material: NLRS_f2_beton prefab 300 mm
Classification: 22.21 binnenwanden - constructief, massieve wanden (Uniformat)
Pset_WallCommon - LoadBearing: yes; IsExternal: no; ExtendToStructure: no; Reference: NLRS_22.21_WA_beton prefab d=300_gen 2; ThermalTransmittance: 3.48667 kg/K/s3
Name (Basic Wall:NLRS_22.21_WA_beton prefab d=300_gen 2:...) | In
10345422 | 00 begane grond
10345458 | 01 eerste verdieping

# IfcWallStandardCase: Basic Wall:NLRS_22.21_WA_beton prefab d=400_gen (243)
Type - PredefinedType: STANDARD; Material: NLRS_f2_beton prefab 400 mm
Classification: 22.21 binnenwanden - constructief, massieve wanden (Uniformat)
Pset_WallCommon - LoadBearing: yes; IsExternal: no; ExtendToStructure: no; Reference: NLRS_22.21_WA_beton prefab d=400_gen; ThermalTransmittance: 2.615 kg/K/s3
Name (Basic Wall:NLRS_22.21_WA_beton prefab d=400_gen:...) | In | Group
4694966 | 21 eenentwintigste verdieping | Model Group:NLRS_01.00_verdieping type F1_gen:4694955
4694968 | 21 eenentwintigste verdieping | Model Group:NLRS_01.00_verdieping type F1_gen:4694955
4694970 | 21 eenentwintigste verdieping | Model Group:NLRS_01.00_verdieping type F1_gen:4694955
4695265 | 21 eenentwintigste verdieping | Model Group:NLRS_01.00_verdieping type F1_gen:4694955
4695270 | 21 eenentwintigste verdieping | Model Group:NLRS_01.00_verdieping type F1_gen:4694955
4695323 | 21 eenentwintigste verdieping | Model Group:NLRS_01.00_verdieping type F1_gen:4694955
4695326 | 21 eenentwintigste verdieping | Model Group:NLRS_01.00_verdieping type F1_gen:4694955
4695329 | 21 eenentwintigste verdieping | Model Group:NLRS_01.00_verdieping type F1_gen:4694955
4695332 | 21 eenentwintigste verdieping | Model Group:NLRS_01.00_verdieping type F1_gen:4694955
4695394 | 21 eenentwintigste verdieping | Model Group:NLRS_01.00_verdieping type F1_gen:4694955
4698002 | 21 eenentwintigste verdieping | Model Group:NLRS_01.00_verdieping type F1_gen:4694955
4698093 | 21 eenentwintigste verdieping | Model Group:NLRS_01.00_verdieping type F1_gen:4694955
7299476 | 00 begane grond
7301433 | 01 eerste verdieping
7301704 | 02 tweede verdieping
8986253 | 22 tweeëntwintigste verdieping | Model Group:NLRS_01.00_verdieping type G_gen:8994214
8986255 | 22 tweeëntwintigste verdieping | Model Group:NLRS_01.00_verdieping type G_gen:8994214
8986257 | 22 tweeëntwintigste verdieping | Model Group:NLRS_01.00_verdieping type G_gen:8994214
8986266 | 22 tweeëntwintigste verdieping | Model Group:NLRS_01.00_verdieping type G_gen:8994214
8986269 | 22 tweeëntwintigste verdieping | Model Group:NLRS_01.00_verdieping type G_gen:8994214
8986275 | 22 tweeëntwintigste verdieping | Model Group:NLRS_01.00_verdieping type G_gen:8994214
8986278 | 22 tweeëntwintigste verdieping | Model Group:NLRS_01.00_verdieping type G_gen:8994214
8986281 | 22 tweeëntwintigste verdieping | Model Group:NLRS_01.00_verdieping type G_gen:8994214
8986284 | 22 tweeëntwintigste verdieping | Model Group:NLRS_01.00_verdieping type G_gen:8994214
8986288 | 22 tweeëntwintigste verdieping | Model Group:NLRS_01.00_verdieping type G_gen:8994214
8986291 | 22 tweeëntwintigste verdieping | Model Group:NLRS_01.00_verdieping type G_gen:8994214
8986293 | 22 tweeëntwintigste verdieping | Model Group:NLRS_01.00_verdieping type G_gen:8994214
8996017 | 24 vierentwintigste verdieping | Model Group:NLRS_01.00_verdieping type H_gen:4746600
8996019 | 24 vierentwintigste verdieping | Model Group:NLRS_01.00_verdieping type H_gen:4746600
8996021 | 24 vierentwintigste verdieping | Model Group:NLRS_01.00_verdieping type H_gen:4746600
8996030 | 24 vierentwintigste verdieping | Model Group:NLRS_01.00_verdieping type H_gen:4746600
8996033 | 24 vierentwintigste verdieping | Model Group:NLRS_01.00_verdieping type H_gen:4746600
8996039 | 24 vierentwintigste verdieping | Model Group:NLRS_01.00_verdieping type H_gen:4746600
8996042 | 24 vierentwintigste verdieping | Model Group:NLRS_01.00_verdieping type H_gen:4746600
8996045 | 24 vierentwintigste verdieping | Model Group:NLRS_01.00_verdieping type H_gen:4746600
8996048 | 24 vierentwintigste verdieping | Model Group:NLRS_01.00_verdieping type H_gen:4746600
8996052 | 24 vierentwintigste verdieping | Model Group:NLRS_01.00_verdieping type H_gen:4746600
8996055 | 24 vierentwintigste verdieping | Model Group:NLRS_01.00_verdieping type H_gen:4746600
8996057 | 24 vierentwintigste verdieping | Model Group:NLRS_01.00_verdieping type H_gen:4746600
8996309 | 25 vijfentwintigste verdieping | Model Group:NLRS_01.00_verdieping type J_gen:4747032
8996311 | 25 vijfentwintigste verdieping | Model Group:NLRS_01.00_verdieping type J_gen:4747032
8996313 | 25 vijfentwintigste verdieping | Model Group:NLRS_01.00_verdieping type J_gen:4747032
8996322 | 25 vijfentwintigste verdieping | Model Group:NLRS_01.00_verdieping type J_gen:4747032
8996325 | 25 vijfentwintigste verdieping | Model Group:NLRS_01.00_verdieping type J_gen:4747032
8996331 | 25 vijfentwintigste verdieping | Model Group:NLRS_01.00_verdieping type J_gen:4747032
8996334 | 25 vijfentwintigste verdieping | Model Group:NLRS_01.00_verdieping type J_gen:4747032
8996337 | 25 vijfentwintigste verdieping | Model Group:NLRS_01.00_verdieping type J_gen:4747032
8996340 | 25 vijfentwintigste verdieping | Model Group:NLRS_01.00_verdieping type J_gen:4747032
8996344 | 25 vijfentwintigste verdieping | Model Group:NLRS_01.00_verdieping type J_gen:4747032
8996347 | 25 vijfentwintigste verdieping | Model Group:NLRS_01.00_verdieping type J_gen:4747032
8996349 | 25 vijfentwintigste verdieping | Model Group:NLRS_01.00_verdieping type J_gen:4747032
8996601 | 26 zesentwintigste verdieping | Model Group:NLRS_01.00_verdieping type K_gen:4747464
8996603 | 26 zesentwintigste verdieping | Model Group:NLRS_01.00_verdieping type K_gen:4747464
8996605 | 26 zesentwintigste verdieping | Model Group:NLRS_01.00_verdieping type K_gen:4747464
8996614 | 26 zesentwintigste verdieping | Model Group:NLRS_01.00_verdieping type K_gen:4747464
8996617 | 26 zesentwintigste verdieping | Model Group:NLRS_01.00_verdieping type K_gen:4747464
8996623 | 26 zesentwintigste verdieping | Model Group:NLRS_01.00_verdieping type K_gen:4747464
8996626 | 26 zesentwintigste verdieping | Model Group:NLRS_01.00_verdieping type K_gen:4747464
8996629 | 26 zesentwintigste verdieping | Model Group:NLRS_01.00_verdieping type K_gen:4747464
8996632 | 26 zesentwintigste verdieping | Model Group:NLRS_01.00_verdieping type K_gen:4747464
8996636 | 26 zesentwintigste verdieping | Model Group:NLRS_01.00_verdieping type K_gen:4747464
8996639 | 26 zesentwintigste verdieping | Model Group:NLRS_01.00_verdieping type K_gen:4747464
8996641 | 26 zesentwintigste verdieping | Model Group:NLRS_01.00_verdieping type K_gen:4747464
8997769 | 30 dertigste verdieping | Model Group:NLRS_01.00_verdieping (type L)_gen:4749192
8997771 | 30 dertigste verdieping | Model Group:NLRS_01.00_verdieping (type L)_gen:4749192
8997773 | 30 dertigste verdieping | Model Group:NLRS_01.00_verdieping (type L)_gen:4749192
8997782 | 30 dertigste verdieping | Model Group:NLRS_01.00_verdieping (type L)_gen:4749192
8997785 | 30 dertigste verdieping | Model Group:NLRS_01.00_verdieping (type L)_gen:4749192
8997791 | 30 dertigste verdieping | Model Group:NLRS_01.00_verdieping (type L)_gen:4749192
8997794 | 30 dertigste verdieping | Model Group:NLRS_01.00_verdieping (type L)_gen:4749192
8997797 | 30 dertigste verdieping | Model Group:NLRS_01.00_verdieping (type L)_gen:4749192
8997800 | 30 dertigste verdieping | Model Group:NLRS_01.00_verdieping (type L)_gen:4749192
8997804 | 30 dertigste verdieping | Model Group:NLRS_01.00_verdieping (type L)_gen:4749192
8997807 | 30 dertigste verdieping | Model Group:NLRS_01.00_verdieping (type L)_gen:4749192
8997809 | 30 dertigste verdieping | Model Group:NLRS_01.00_verdieping (type L)_gen:4749192
9134782 | 23 drieëntwintigste verdieping | Model Group:NLRS_01.00_verdieping type F2_gen:4779563
9134784 | 23 drieëntwintigste verdieping | Model Group:NLRS_01.00_verdieping type F2_gen:4779563
9134786 | 23 drieëntwintigste verdieping | Model Group:NLRS_01.00_verdieping type F2_gen:4779563
9134795 | 23 drieëntwintigste verdieping | Model Group:NLRS_01.00_verdieping type F2_gen:4779563
9134798 | 23 drieëntwintigste verdieping | Model Group:NLRS_01.00_verdieping type F2_gen:4779563
9134804 | 23 drieëntwintigste verdieping | Model Group:NLRS_01.00_verdieping type F2_gen:4779563
9134807 | 23 drieëntwintigste verdieping | Model Group:NLRS_01.00_verdieping type F2_gen:4779563
9134810 | 23 drieëntwintigste verdieping | Model Group:NLRS_01.00_verdieping type F2_gen:4779563
9134813 | 23 drieëntwintigste verdieping | Model Group:NLRS_01.00_verdieping type F2_gen:4779563
9134817 | 23 drieëntwintigste verdieping | Model Group:NLRS_01.00_verdieping type F2_gen:4779563
9134820 | 23 drieëntwintigste verdieping | Model Group:NLRS_01.00_verdieping type F2_gen:4779563
9134822 | 23 drieëntwintigste verdieping | Model Group:NLRS_01.00_verdieping type F2_gen:4779563
9135075 | 28 achtentwintigste verdieping | Model Group:NLRS_01.00_verdieping type F1_gen:4748328
9135077 | 28 achtentwintigste verdieping | Model Group:NLRS_01.00_verdieping type F1_gen:4748328
9135079 | 28 achtentwintigste verdieping | Model Group:NLRS_01.00_verdieping type F1_gen:4748328
9135088 | 28 achtentwintigste verdieping | Model Group:NLRS_01.00_verdieping type F1_gen:4748328
9135091 | 28 achtentwintigste verdieping | Model Group:NLRS_01.00_verdieping type F1_gen:4748328
9135097 | 28 achtentwintigste verdieping | Model Group:NLRS_01.00_verdieping type F1_gen:4748328
9135100 | 28 achtentwintigste verdieping | Model Group:NLRS_01.00_verdieping type F1_gen:4748328
9135103 | 28 achtentwintigste verdieping | Model Group:NLRS_01.00_verdieping type F1_gen:4748328
9135106 | 28 achtentwintigste verdieping | Model Group:NLRS_01.00_verdieping type F1_gen:4748328
9135110 | 28 achtentwintigste verdieping | Model Group:NLRS_01.00_verdieping type F1_gen:4748328
9135113 | 28 achtentwintigste verdieping | Model Group:NLRS_01.00_verdieping type F1_gen:4748328
9135115 | 28 achtentwintigste verdieping | Model Group:NLRS_01.00_verdieping type F1_gen:4748328
9135368 | 29 negenentwintigste verdieping | Model Group:NLRS_01.00_verdieping type F1_gen:4748760
9135370 | 29 negenentwintigste verdieping | Model Group:NLRS_01.00_verdieping type F1_gen:4748760
9135372 | 29 negenentwintigste verdieping | Model Group:NLRS_01.00_verdieping type F1_gen:4748760
9135381 | 29 negenentwintigste verdieping | Model Group:NLRS_01.00_verdieping type F1_gen:4748760
9135384 | 29 negenentwintigste verdieping | Model Group:NLRS_01.00_verdieping type F1_gen:4748760
9135390 | 29 negenentwintigste verdieping | Model Group:NLRS_01.00_verdieping type F1_gen:4748760
9135393 | 29 negenentwintigste verdieping | Model Group:NLRS_01.00_verdieping type F1_gen:4748760
9135396 | 29 negenentwintigste verdieping | Model Group:NLRS_01.00_verdieping type F1_gen:4748760
9135399 | 29 negenentwintigste verdieping | Model Group:NLRS_01.00_verdieping type F1_gen:4748760
9135403 | 29 negenentwintigste verdieping | Model Group:NLRS_01.00_verdieping type F1_gen:4748760
9135406 | 29 negenentwintigste verdieping | Model Group:NLRS_01.00_verdieping type F1_gen:4748760
9135408 | 29 negenentwintigste verdieping | Model Group:NLRS_01.00_verdieping type F1_gen:4748760
9135661 | 33 drieëndertigste verdieping | Model Group:NLRS_01.00_verdieping type F1_gen:4750488
9135663 | 33 drieëndertigste verdieping | Model Group:NLRS_01.00_verdieping type F1_gen:4750488
9135665 | 33 drieëndertigste verdieping | Model Group:NLRS_01.00_verdieping type F1_gen:4750488
9135674 | 33 drieëndertigste verdieping | Model Group:NLRS_01.00_verdieping type F1_gen:4750488
9135677 | 33 drieëndertigste verdieping | Model Group:NLRS_01.00_verdieping type F1_gen:4750488
9135683 | 33 drieëndertigste verdieping | Model Group:NLRS_01.00_verdieping type F1_gen:4750488
9135686 | 33 drieëndertigste verdieping | Model Group:NLRS_01.00_verdieping type F1_gen:4750488
9135689 | 33 drieëndertigste verdieping | Model Group:NLRS_01.00_verdieping type F1_gen:4750488
9135692 | 33 drieëndertigste verdieping | Model Group:NLRS_01.00_verdieping type F1_gen:4750488
9135696 | 33 drieëndertigste verdieping | Model Group:NLRS_01.00_verdieping type F1_gen:4750488
9135699 | 33 drieëndertigste verdieping | Model Group:NLRS_01.00_verdieping type F1_gen:4750488
9135701 | 33 drieëndertigste verdieping | Model Group:NLRS_01.00_verdieping type F1_gen:4750488
9138778 | 31 eenendertigste verdieping | Model Group:NLRS_01.00_verdieping type G_gen:4749624
9138780 | 31 eenendertigste verdieping | Model Group:NLRS_01.00_verdieping type G_gen:4749624
9138782 | 31 eenendertigste verdieping | Model Group:NLRS_01.00_verdieping type G_gen:4749624
9138791 | 31 eenendertigste verdieping | Model Group:NLRS_01.00_verdieping type G_gen:4749624
9138794 | 31 eenendertigste verdieping | Model Group:NLRS_01.00_verdieping type G_gen:4749624
9138800 | 31 eenendertigste verdieping | Model Group:NLRS_01.00_verdieping type G_gen:4749624
9138803 | 31 eenendertigste verdieping | Model Group:NLRS_01.00_verdieping type G_gen:4749624
9138806 | 31 eenendertigste verdieping | Model Group:NLRS_01.00_verdieping type G_gen:4749624
9138809 | 31 eenendertigste verdieping | Model Group:NLRS_01.00_verdieping type G_gen:4749624
9138813 | 31 eenendertigste verdieping | Model Group:NLRS_01.00_verdieping type G_gen:4749624
9138816 | 31 eenendertigste verdieping | Model Group:NLRS_01.00_verdieping type G_gen:4749624
9138818 | 31 eenendertigste verdieping | Model Group:NLRS_01.00_verdieping type G_gen:4749624
9139068 | 32 tweeëndertigste verdieping | Model Group:NLRS_01.00_verdieping type G_gen:4750056
9139070 | 32 tweeëndertigste verdieping | Model Group:NLRS_01.00_verdieping type G_gen:4750056
9139072 | 32 tweeëndertigste verdieping | Model Group:NLRS_01.00_verdieping type G_gen:4750056
9139081 | 32 tweeëndertigste verdieping | Model Group:NLRS_01.00_verdieping type G_gen:4750056
9139084 | 32 tweeëndertigste verdieping | Model Group:NLRS_01.00_verdieping type G_gen:4750056
9139090 | 32 tweeëndertigste verdieping | Model Group:NLRS_01.00_verdieping type G_gen:4750056
9139093 | 32 tweeëndertigste verdieping | Model Group:NLRS_01.00_verdieping type G_gen:4750056
9139096 | 32 tweeëndertigste verdieping | Model Group:NLRS_01.00_verdieping type G_gen:4750056
9139099 | 32 tweeëndertigste verdieping | Model Group:NLRS_01.00_verdieping type G_gen:4750056
9139103 | 32 tweeëndertigste verdieping | Model Group:NLRS_01.00_verdieping type G_gen:4750056
9139106 | 32 tweeëndertigste verdieping | Model Group:NLRS_01.00_verdieping type G_gen:4750056
9139108 | 32 tweeëndertigste verdieping | Model Group:NLRS_01.00_verdieping type G_gen:4750056
9140657 | 34 vierendertigste verdieping | Model Group:NLRS_01.00_verdieping type H_gen:4750920
9140659 | 34 vierendertigste verdieping | Model Group:NLRS_01.00_verdieping type H_gen:4750920
9140661 | 34 vierendertigste verdieping | Model Group:NLRS_01.00_verdieping type H_gen:4750920
9140670 | 34 vierendertigste verdieping | Model Group:NLRS_01.00_verdieping type H_gen:4750920
9140673 | 34 vierendertigste verdieping | Model Group:NLRS_01.00_verdieping type H_gen:4750920
9140679 | 34 vierendertigste verdieping | Model Group:NLRS_01.00_verdieping type H_gen:4750920
9140682 | 34 vierendertigste verdieping | Model Group:NLRS_01.00_verdieping type H_gen:4750920
9140685 | 34 vierendertigste verdieping | Model Group:NLRS_01.00_verdieping type H_gen:4750920
9140688 | 34 vierendertigste verdieping | Model Group:NLRS_01.00_verdieping type H_gen:4750920
9140692 | 34 vierendertigste verdieping | Model Group:NLRS_01.00_verdieping type H_gen:4750920
9140695 | 34 vierendertigste verdieping | Model Group:NLRS_01.00_verdieping type H_gen:4750920
9140697 | 34 vierendertigste verdieping | Model Group:NLRS_01.00_verdieping type H_gen:4750920
9141597 | 35 vijfendertigste verdieping | Model Group:NLRS_01.00_verdieping type J_gen:4751352
9141599 | 35 vijfendertigste verdieping | Model Group:NLRS_01.00_verdieping type J_gen:4751352
9141601 | 35 vijfendertigste verdieping | Model Group:NLRS_01.00_verdieping type J_gen:4751352
9141610 | 35 vijfendertigste verdieping | Model Group:NLRS_01.00_verdieping type J_gen:4751352
9141613 | 35 vijfendertigste verdieping | Model Group:NLRS_01.00_verdieping type J_gen:4751352
9141619 | 35 vijfendertigste verdieping | Model Group:NLRS_01.00_verdieping type J_gen:4751352
9141622 | 35 vijfendertigste verdieping | Model Group:NLRS_01.00_verdieping type J_gen:4751352
9141625 | 35 vijfendertigste verdieping | Model Group:NLRS_01.00_verdieping type J_gen:4751352
9141628 | 35 vijfendertigste verdieping | Model Group:NLRS_01.00_verdieping type J_gen:4751352
9141632 | 35 vijfendertigste verdieping | Model Group:NLRS_01.00_verdieping type J_gen:4751352
9141635 | 35 vijfendertigste verdieping | Model Group:NLRS_01.00_verdieping type J_gen:4751352
9141637 | 35 vijfendertigste verdieping | Model Group:NLRS_01.00_verdieping type J_gen:4751352
9142544 | 27 zevenentwintigste verdieping | Model Group:NLRS_01.00_verdieping type K_gen:4747896
9142546 | 27 zevenentwintigste verdieping | Model Group:NLRS_01.00_verdieping type K_gen:4747896
9142548 | 27 zevenentwintigste verdieping | Model Group:NLRS_01.00_verdieping type K_gen:4747896
9142557 | 27 zevenentwintigste verdieping | Model Group:NLRS_01.00_verdieping type K_gen:4747896
9142560 | 27 zevenentwintigste verdieping | Model Group:NLRS_01.00_verdieping type K_gen:4747896
9142566 | 27 zevenentwintigste verdieping | Model Group:NLRS_01.00_verdieping type K_gen:4747896
9142569 | 27 zevenentwintigste verdieping | Model Group:NLRS_01.00_verdieping type K_gen:4747896
9142572 | 27 zevenentwintigste verdieping | Model Group:NLRS_01.00_verdieping type K_gen:4747896
9142575 | 27 zevenentwintigste verdieping | Model Group:NLRS_01.00_verdieping type K_gen:4747896
9142579 | 27 zevenentwintigste verdieping | Model Group:NLRS_01.00_verdieping type K_gen:4747896
9142582 | 27 zevenentwintigste verdieping | Model Group:NLRS_01.00_verdieping type K_gen:4747896
9142584 | 27 zevenentwintigste verdieping | Model Group:NLRS_01.00_verdieping type K_gen:4747896
9142834 | 38 achtendertigste verdieping | Model Group:NLRS_01.00_verdieping type K_gen:4752648
9142836 | 38 achtendertigste verdieping | Model Group:NLRS_01.00_verdieping type K_gen:4752648
9142838 | 38 achtendertigste verdieping | Model Group:NLRS_01.00_verdieping type K_gen:4752648
9142847 | 38 achtendertigste verdieping | Model Group:NLRS_01.00_verdieping type K_gen:4752648
9142850 | 38 achtendertigste verdieping | Model Group:NLRS_01.00_verdieping type K_gen:4752648
9142856 | 38 achtendertigste verdieping | Model Group:NLRS_01.00_verdieping type K_gen:4752648
9142859 | 38 achtendertigste verdieping | Model Group:NLRS_01.00_verdieping type K_gen:4752648
9142862 | 38 achtendertigste verdieping | Model Group:NLRS_01.00_verdieping type K_gen:4752648
9142865 | 38 achtendertigste verdieping | Model Group:NLRS_01.00_verdieping type K_gen:4752648
9142869 | 38 achtendertigste verdieping | Model Group:NLRS_01.00_verdieping type K_gen:4752648
9142872 | 38 achtendertigste verdieping | Model Group:NLRS_01.00_verdieping type K_gen:4752648
9142874 | 38 achtendertigste verdieping | Model Group:NLRS_01.00_verdieping type K_gen:4752648
9143124 | 39 negenendertigste verdieping | Model Group:NLRS_01.00_verdieping type K_gen:4753080
9143126 | 39 negenendertigste verdieping | Model Group:NLRS_01.00_verdieping type K_gen:4753080
9143128 | 39 negenendertigste verdieping | Model Group:NLRS_01.00_verdieping type K_gen:4753080
9143137 | 39 negenendertigste verdieping | Model Group:NLRS_01.00_verdieping type K_gen:4753080
9143140 | 39 negenendertigste verdieping | Model Group:NLRS_01.00_verdieping type K_gen:4753080
9143146 | 39 negenendertigste verdieping | Model Group:NLRS_01.00_verdieping type K_gen:4753080
9143149 | 39 negenendertigste verdieping | Model Group:NLRS_01.00_verdieping type K_gen:4753080
9143152 | 39 negenendertigste verdieping | Model Group:NLRS_01.00_verdieping type K_gen:4753080
9143155 | 39 negenendertigste verdieping | Model Group:NLRS_01.00_verdieping type K_gen:4753080
9143159 | 39 negenendertigste verdieping | Model Group:NLRS_01.00_verdieping type K_gen:4753080
9143162 | 39 negenendertigste verdieping | Model Group:NLRS_01.00_verdieping type K_gen:4753080
9143164 | 39 negenendertigste verdieping | Model Group:NLRS_01.00_verdieping type K_gen:4753080
9145366 | 36 zesendertigste verdieping | Model Group:NLRS_01.00_verdieping type K_gen:4751784
9145368 | 36 zesendertigste verdieping | Model Group:NLRS_01.00_verdieping type K_gen:4751784
9145370 | 36 zesendertigste verdieping | Model Group:NLRS_01.00_verdieping type K_gen:4751784
9145379 | 36 zesendertigste verdieping | Model Group:NLRS_01.00_verdieping type K_gen:4751784
9145382 | 36 zesendertigste verdieping | Model Group:NLRS_01.00_verdieping type K_gen:4751784
9145388 | 36 zesendertigste verdieping | Model Group:NLRS_01.00_verdieping type K_gen:4751784
9145391 | 36 zesendertigste verdieping | Model Group:NLRS_01.00_verdieping type K_gen:4751784
9145394 | 36 zesendertigste verdieping | Model Group:NLRS_01.00_verdieping type K_gen:4751784
9145397 | 36 zesendertigste verdieping | Model Group:NLRS_01.00_verdieping type K_gen:4751784
9145401 | 36 zesendertigste verdieping | Model Group:NLRS_01.00_verdieping type K_gen:4751784
9145404 | 36 zesendertigste verdieping | Model Group:NLRS_01.00_verdieping type K_gen:4751784
9145406 | 36 zesendertigste verdieping | Model Group:NLRS_01.00_verdieping type K_gen:4751784
9145656 | 37 zevenendertigste verdieping | Model Group:NLRS_01.00_verdieping type K_gen:4752216
9145658 | 37 zevenendertigste verdieping | Model Group:NLRS_01.00_verdieping type K_gen:4752216
9145660 | 37 zevenendertigste verdieping | Model Group:NLRS_01.00_verdieping type K_gen:4752216
9145669 | 37 zevenendertigste verdieping | Model Group:NLRS_01.00_verdieping type K_gen:4752216
9145672 | 37 zevenendertigste verdieping | Model Group:NLRS_01.00_verdieping type K_gen:4752216
9145678 | 37 zevenendertigste verdieping | Model Group:NLRS_01.00_verdieping type K_gen:4752216
9145681 | 37 zevenendertigste verdieping | Model Group:NLRS_01.00_verdieping type K_gen:4752216
9145684 | 37 zevenendertigste verdieping | Model Group:NLRS_01.00_verdieping type K_gen:4752216
9145687 | 37 zevenendertigste verdieping | Model Group:NLRS_01.00_verdieping type K_gen:4752216
9145691 | 37 zevenendertigste verdieping | Model Group:NLRS_01.00_verdieping type K_gen:4752216
9145694 | 37 zevenendertigste verdieping | Model Group:NLRS_01.00_verdieping type K_gen:4752216
9145696 | 37 zevenendertigste verdieping | Model Group:NLRS_01.00_verdieping type K_gen:4752216
9147245 | 40 veertigste verdieping | Model Group:NLRS_01.00_verdieping (type L)_gen:4753512
9147247 | 40 veertigste verdieping | Model Group:NLRS_01.00_verdieping (type L)_gen:4753512
9147249 | 40 veertigste verdieping | Model Group:NLRS_01.00_verdieping (type L)_gen:4753512
9147258 | 40 veertigste verdieping | Model Group:NLRS_01.00_verdieping (type L)_gen:4753512
9147261 | 40 veertigste verdieping | Model Group:NLRS_01.00_verdieping (type L)_gen:4753512
9147267 | 40 veertigste verdieping | Model Group:NLRS_01.00_verdieping (type L)_gen:4753512
9147270 | 40 veertigste verdieping | Model Group:NLRS_01.00_verdieping (type L)_gen:4753512
9147273 | 40 veertigste verdieping | Model Group:NLRS_01.00_verdieping (type L)_gen:4753512
9147276 | 40 veertigste verdieping | Model Group:NLRS_01.00_verdieping (type L)_gen:4753512
9147280 | 40 veertigste verdieping | Model Group:NLRS_01.00_verdieping (type L)_gen:4753512
9147283 | 40 veertigste verdieping | Model Group:NLRS_01.00_verdieping (type L)_gen:4753512
9147285 | 40 veertigste verdieping | Model Group:NLRS_01.00_verdieping (type L)_gen:4753512

# IfcWallStandardCase: Basic Wall:NLRS_22.21_WA_beton prefab d=500_gen (224)
Type - PredefinedType: STANDARD; Material: NLRS_f2_beton prefab 500 mm
Classification: 22.21 binnenwanden - constructief, massieve wanden (Uniformat)
Pset_WallCommon - LoadBearing: yes; IsExternal: no; ExtendToStructure: no; Reference: NLRS_22.21_WA_beton prefab d=500_gen; ThermalTransmittance: 2.092 kg/K/s3
Name (Basic Wall:NLRS_22.21_WA_beton prefab d=500_gen:...) | In | Group
4690654 | 06 zesde verdieping | Model Group:NLRS_01.00_verdieping type B1_gen:4644030
4690660 | 06 zesde verdieping | Model Group:NLRS_01.00_verdieping type B1_gen:4644030
4690990 | 06 zesde verdieping | Model Group:NLRS_01.00_verdieping type B1_gen:4644030
4691008 | 06 zesde verdieping | Model Group:NLRS_01.00_verdieping type B1_gen:4644030
4692339 | 06 zesde verdieping | Model Group:NLRS_01.00_verdieping type B1_gen:4644030
4692374 | 06 zesde verdieping | Model Group:NLRS_01.00_verdieping type B1_gen:4644030
4693337 | 06 zesde verdieping | Model Group:NLRS_01.00_verdieping type B1_gen:4644030
4693342 | 06 zesde verdieping | Model Group:NLRS_01.00_verdieping type B1_gen:4644030
4693394 | 06 zesde verdieping | Model Group:NLRS_01.00_verdieping type B1_gen:4644030
4693399 | 06 zesde verdieping | Model Group:NLRS_01.00_verdieping type B1_gen:4644030
4693451 | 06 zesde verdieping | Model Group:NLRS_01.00_verdieping type B1_gen:4644030
4693456 | 06 zesde verdieping | Model Group:NLRS_01.00_verdieping type B1_gen:4644030
4720988 | 06 zesde verdieping | Model Group:NLRS_01.00_verdieping type B1_gen:4644030
4720992 | 06 zesde verdieping | Model Group:NLRS_01.00_verdieping type B1_gen:4644030
4822177 | 05 vijfde verdieping
4822187 | 05 vijfde verdieping
5144302 | 05 vijfde verdieping
5144344 | 05 vijfde verdieping
5144554 | 05 vijfde verdieping
5145697 | 05 vijfde verdieping
5147434 | 05 vijfde verdieping
5147461 | 05 vijfde verdieping
5147488 | 05 vijfde verdieping
5147515 | 05 vijfde verdieping
5147541 | 05 vijfde verdieping
5147569 | 05 vijfde verdieping
5147650 | 05 vijfde verdieping
5147677 | 05 vijfde verdieping
5667262 | 09 negende verdieping | Model Group:NLRS_01.00_verdieping type C2_gen:4703193
5667264 | 09 negende verdieping | Model Group:NLRS_01.00_verdieping type C2_gen:4703193
5667266 | 09 negende verdieping | Model Group:NLRS_01.00_verdieping type C2_gen:4703193
5667268 | 09 negende verdieping | Model Group:NLRS_01.00_verdieping type C2_gen:4703193
5667400 | 09 negende verdieping | Model Group:NLRS_01.00_verdieping type C2_gen:4703193
5667404 | 09 negende verdieping | Model Group:NLRS_01.00_verdieping type C2_gen:4703193
5667449 | 09 negende verdieping | Model Group:NLRS_01.00_verdieping type C2_gen:4703193
5667452 | 09 negende verdieping | Model Group:NLRS_01.00_verdieping type C2_gen:4703193
5667455 | 09 negende verdieping | Model Group:NLRS_01.00_verdieping type C2_gen:4703193
5667458 | 09 negende verdieping | Model Group:NLRS_01.00_verdieping type C2_gen:4703193
5667520 | 09 negende verdieping | Model Group:NLRS_01.00_verdieping type C2_gen:4703193
5667523 | 09 negende verdieping | Model Group:NLRS_01.00_verdieping type C2_gen:4703193
5667525 | 09 negende verdieping | Model Group:NLRS_01.00_verdieping type C2_gen:4703193
5667530 | 09 negende verdieping | Model Group:NLRS_01.00_verdieping type C2_gen:4703193
9036735 | 16 zestiende verdieping | Model Group:NLRS_01.00_verdieping type E_gen:4739081
9036737 | 16 zestiende verdieping | Model Group:NLRS_01.00_verdieping type E_gen:4739081
9036739 | 16 zestiende verdieping | Model Group:NLRS_01.00_verdieping type E_gen:4739081
9036741 | 16 zestiende verdieping | Model Group:NLRS_01.00_verdieping type E_gen:4739081
9036751 | 16 zestiende verdieping | Model Group:NLRS_01.00_verdieping type E_gen:4739081
9036754 | 16 zestiende verdieping | Model Group:NLRS_01.00_verdieping type E_gen:4739081
9036760 | 16 zestiende verdieping | Model Group:NLRS_01.00_verdieping type E_gen:4739081
9036763 | 16 zestiende verdieping | Model Group:NLRS_01.00_verdieping type E_gen:4739081
9036766 | 16 zestiende verdieping | Model Group:NLRS_01.00_verdieping type E_gen:4739081
9036769 | 16 zestiende verdieping | Model Group:NLRS_01.00_verdieping type E_gen:4739081
9036772 | 16 zestiende verdieping | Model Group:NLRS_01.00_verdieping type E_gen:4739081
9036775 | 16 zestiende verdieping | Model Group:NLRS_01.00_verdieping type E_gen:4739081
9036779 | 16 zestiende verdieping | Model Group:NLRS_01.00_verdieping type E_gen:4739081
9036782 | 16 zestiende verdieping | Model Group:NLRS_01.00_verdieping type E_gen:4739081
9050655 | 15 vijftiende verdieping | Model Group:NLRS_01.00_verdieping type D_gen:4731036
9050657 | 15 vijftiende verdieping | Model Group:NLRS_01.00_verdieping type D_gen:4731036
9050659 | 15 vijftiende verdieping | Model Group:NLRS_01.00_verdieping type D_gen:4731036
9050661 | 15 vijftiende verdieping | Model Group:NLRS_01.00_verdieping type D_gen:4731036
9050671 | 15 vijftiende verdieping | Model Group:NLRS_01.00_verdieping type D_gen:4731036
9050674 | 15 vijftiende verdieping | Model Group:NLRS_01.00_verdieping type D_gen:4731036
9050680 | 15 vijftiende verdieping | Model Group:NLRS_01.00_verdieping type D_gen:4731036
9050683 | 15 vijftiende verdieping | Model Group:NLRS_01.00_verdieping type D_gen:4731036
9050686 | 15 vijftiende verdieping | Model Group:NLRS_01.00_verdieping type D_gen:4731036
9050689 | 15 vijftiende verdieping | Model Group:NLRS_01.00_verdieping type D_gen:4731036
9050693 | 15 vijftiende verdieping | Model Group:NLRS_01.00_verdieping type D_gen:4731036
9050696 | 15 vijftiende verdieping | Model Group:NLRS_01.00_verdieping type D_gen:4731036
9050698 | 15 vijftiende verdieping | Model Group:NLRS_01.00_verdieping type D_gen:4731036
9050701 | 15 vijftiende verdieping | Model Group:NLRS_01.00_verdieping type D_gen:4731036
9050951 | 17 zeventiende verdieping | Model Group:NLRS_01.00_verdieping type D_gen:4731494
9050953 | 17 zeventiende verdieping | Model Group:NLRS_01.00_verdieping type D_gen:4731494
9050955 | 17 zeventiende verdieping | Model Group:NLRS_01.00_verdieping type D_gen:4731494
9050957 | 17 zeventiende verdieping | Model Group:NLRS_01.00_verdieping type D_gen:4731494
9050967 | 17 zeventiende verdieping | Model Group:NLRS_01.00_verdieping type D_gen:4731494
9050970 | 17 zeventiende verdieping | Model Group:NLRS_01.00_verdieping type D_gen:4731494
9050976 | 17 zeventiende verdieping | Model Group:NLRS_01.00_verdieping type D_gen:4731494
9050979 | 17 zeventiende verdieping | Model Group:NLRS_01.00_verdieping type D_gen:4731494
9050982 | 17 zeventiende verdieping | Model Group:NLRS_01.00_verdieping type D_gen:4731494
9050985 | 17 zeventiende verdieping | Model Group:NLRS_01.00_verdieping type D_gen:4731494
9050989 | 17 zeventiende verdieping | Model Group:NLRS_01.00_verdieping type D_gen:4731494
9050992 | 17 zeventiende verdieping | Model Group:NLRS_01.00_verdieping type D_gen:4731494
9050994 | 17 zeventiende verdieping | Model Group:NLRS_01.00_verdieping type D_gen:4731494
9050997 | 17 zeventiende verdieping | Model Group:NLRS_01.00_verdieping type D_gen:4731494
9090923 | 07 zevende verdieping | Model Group:NLRS_01.00_verdieping type C1_gen:4689025
9090925 | 07 zevende verdieping | Model Group:NLRS_01.00_verdieping type C1_gen:4689025
9090927 | 07 zevende verdieping | Model Group:NLRS_01.00_verdieping type C1_gen:4689025
9090929 | 07 zevende verdieping | Model Group:NLRS_01.00_verdieping type C1_gen:4689025
9090939 | 07 zevende verdieping | Model Group:NLRS_01.00_verdieping type C1_gen:4689025
9090942 | 07 zevende verdieping | Model Group:NLRS_01.00_verdieping type C1_gen:4689025
9090948 | 07 zevende verdieping | Model Group:NLRS_01.00_verdieping type C1_gen:4689025
9090951 | 07 zevende verdieping | Model Group:NLRS_01.00_verdieping type C1_gen:4689025
9090954 | 07 zevende verdieping | Model Group:NLRS_01.00_verdieping type C1_gen:4689025
9090957 | 07 zevende verdieping | Model Group:NLRS_01.00_verdieping type C1_gen:4689025
9090961 | 07 zevende verdieping | Model Group:NLRS_01.00_verdieping type C1_gen:4689025
9090964 | 07 zevende verdieping | Model Group:NLRS_01.00_verdieping type C1_gen:4689025
9090966 | 07 zevende verdieping | Model Group:NLRS_01.00_verdieping type C1_gen:4689025
9090969 | 07 zevende verdieping | Model Group:NLRS_01.00_verdieping type C1_gen:4689025
9125804 | 10 tiende verdieping | Model Group:NLRS_01.00_verdieping type B2_gen:9035827
9125806 | 10 tiende verdieping | Model Group:NLRS_01.00_verdieping type B2_gen:9035827
9125828 | 10 tiende verdieping | Model Group:NLRS_01.00_verdieping type B2_gen:9035827
9125830 | 10 tiende verdieping | Model Group:NLRS_01.00_verdieping type B2_gen:9035827
9125833 | 10 tiende verdieping | Model Group:NLRS_01.00_verdieping type B2_gen:9035827
9125836 | 10 tiende verdieping | Model Group:NLRS_01.00_verdieping type B2_gen:9035827
9125839 | 10 tiende verdieping | Model Group:NLRS_01.00_verdieping type B2_gen:9035827
9125842 | 10 tiende verdieping | Model Group:NLRS_01.00_verdieping type B2_gen:9035827
9125852 | 10 tiende verdieping | Model Group:NLRS_01.00_verdieping type B2_gen:9035827
9125854 | 10 tiende verdieping | Model Group:NLRS_01.00_verdieping type B2_gen:9035827
9126111 | 12 twaalfde verdieping | Model Group:NLRS_01.00_verdieping type B2_gen:4738165
9126113 | 12 twaalfde verdieping | Model Group:NLRS_01.00_verdieping type B2_gen:4738165
9126135 | 12 twaalfde verdieping | Model Group:NLRS_01.00_verdieping type B2_gen:4738165
9126137 | 12 twaalfde verdieping | Model Group:NLRS_01.00_verdieping type B2_gen:4738165
9126140 | 12 twaalfde verdieping | Model Group:NLRS_01.00_verdieping type B2_gen:4738165
9126143 | 12 twaalfde verdieping | Model Group:NLRS_01.00_verdieping type B2_gen:4738165
9126146 | 12 twaalfde verdieping | Model Group:NLRS_01.00_verdieping type B2_gen:4738165
9126149 | 12 twaalfde verdieping | Model Group:NLRS_01.00_verdieping type B2_gen:4738165
9126159 | 12 twaalfde verdieping | Model Group:NLRS_01.00_verdieping type B2_gen:4738165
9126161 | 12 twaalfde verdieping | Model Group:NLRS_01.00_verdieping type B2_gen:4738165
9126418 | 14 veertiende verdieping | Model Group:NLRS_01.00_verdieping type B2_gen:4738623
9126420 | 14 veertiende verdieping | Model Group:NLRS_01.00_verdieping type B2_gen:4738623
9126442 | 14 veertiende verdieping | Model Group:NLRS_01.00_verdieping type B2_gen:4738623
9126444 | 14 veertiende verdieping | Model Group:NLRS_01.00_verdieping type B2_gen:4738623
9126447 | 14 veertiende verdieping | Model Group:NLRS_01.00_verdieping type B2_gen:4738623
9126450 | 14 veertiende verdieping | Model Group:NLRS_01.00_verdieping type B2_gen:4738623
9126453 | 14 veertiende verdieping | Model Group:NLRS_01.00_verdieping type B2_gen:4738623
9126456 | 14 veertiende verdieping | Model Group:NLRS_01.00_verdieping type B2_gen:4738623
9126466 | 14 veertiende verdieping | Model Group:NLRS_01.00_verdieping type B2_gen:4738623
9126468 | 14 veertiende verdieping | Model Group:NLRS_01.00_verdieping type B2_gen:4738623
9128890 | 11 elfde verdieping | Model Group:NLRS_01.00_verdieping type C2_gen:9049706
9128892 | 11 elfde verdieping | Model Group:NLRS_01.00_verdieping type C2_gen:9049706
9128894 | 11 elfde verdieping | Model Group:NLRS_01.00_verdieping type C2_gen:9049706
9128896 | 11 elfde verdieping | Model Group:NLRS_01.00_verdieping type C2_gen:9049706
9128906 | 11 elfde verdieping | Model Group:NLRS_01.00_verdieping type C2_gen:9049706
9128909 | 11 elfde verdieping | Model Group:NLRS_01.00_verdieping type C2_gen:9049706
9128915 | 11 elfde verdieping | Model Group:NLRS_01.00_verdieping type C2_gen:9049706
9128918 | 11 elfde verdieping | Model Group:NLRS_01.00_verdieping type C2_gen:9049706
9128921 | 11 elfde verdieping | Model Group:NLRS_01.00_verdieping type C2_gen:9049706
9128924 | 11 elfde verdieping | Model Group:NLRS_01.00_verdieping type C2_gen:9049706
9128928 | 11 elfde verdieping | Model Group:NLRS_01.00_verdieping type C2_gen:9049706
9128931 | 11 elfde verdieping | Model Group:NLRS_01.00_verdieping type C2_gen:9049706
9128933 | 11 elfde verdieping | Model Group:NLRS_01.00_verdieping type C2_gen:9049706
9128936 | 11 elfde verdieping | Model Group:NLRS_01.00_verdieping type C2_gen:9049706
9129193 | 13 dertiende verdieping | Model Group:NLRS_01.00_verdieping type C2_gen:4730578
9129195 | 13 dertiende verdieping | Model Group:NLRS_01.00_verdieping type C2_gen:4730578
9129197 | 13 dertiende verdieping | Model Group:NLRS_01.00_verdieping type C2_gen:4730578
9129199 | 13 dertiende verdieping | Model Group:NLRS_01.00_verdieping type C2_gen:4730578
9129209 | 13 dertiende verdieping | Model Group:NLRS_01.00_verdieping type C2_gen:4730578
9129212 | 13 dertiende verdieping | Model Group:NLRS_01.00_verdieping type C2_gen:4730578
9129218 | 13 dertiende verdieping | Model Group:NLRS_01.00_verdieping type C2_gen:4730578
9129221 | 13 dertiende verdieping | Model Group:NLRS_01.00_verdieping type C2_gen:4730578
9129224 | 13 dertiende verdieping | Model Group:NLRS_01.00_verdieping type C2_gen:4730578
9129227 | 13 dertiende verdieping | Model Group:NLRS_01.00_verdieping type C2_gen:4730578
9129231 | 13 dertiende verdieping | Model Group:NLRS_01.00_verdieping type C2_gen:4730578
9129234 | 13 dertiende verdieping | Model Group:NLRS_01.00_verdieping type C2_gen:4730578
9129236 | 13 dertiende verdieping | Model Group:NLRS_01.00_verdieping type C2_gen:4730578
9129239 | 13 dertiende verdieping | Model Group:NLRS_01.00_verdieping type C2_gen:4730578
9131606 | 18 achttiende verdieping | Model Group:NLRS_01.00_verdieping type E_gen:4739539
9131608 | 18 achttiende verdieping | Model Group:NLRS_01.00_verdieping type E_gen:4739539
9131610 | 18 achttiende verdieping | Model Group:NLRS_01.00_verdieping type E_gen:4739539
9131612 | 18 achttiende verdieping | Model Group:NLRS_01.00_verdieping type E_gen:4739539
9131622 | 18 achttiende verdieping | Model Group:NLRS_01.00_verdieping type E_gen:4739539
9131625 | 18 achttiende verdieping | Model Group:NLRS_01.00_verdieping type E_gen:4739539
9131631 | 18 achttiende verdieping | Model Group:NLRS_01.00_verdieping type E_gen:4739539
9131634 | 18 achttiende verdieping | Model Group:NLRS_01.00_verdieping type E_gen:4739539
9131637 | 18 achttiende verdieping | Model Group:NLRS_01.00_verdieping type E_gen:4739539
9131640 | 18 achttiende verdieping | Model Group:NLRS_01.00_verdieping type E_gen:4739539
9131643 | 18 achttiende verdieping | Model Group:NLRS_01.00_verdieping type E_gen:4739539
9131646 | 18 achttiende verdieping | Model Group:NLRS_01.00_verdieping type E_gen:4739539
9131650 | 18 achttiende verdieping | Model Group:NLRS_01.00_verdieping type E_gen:4739539
9131653 | 18 achttiende verdieping | Model Group:NLRS_01.00_verdieping type E_gen:4739539
9132671 | 19 negentiende verdieping | Model Group:NLRS_01.00_verdieping type C2_gen:4731952
9132673 | 19 negentiende verdieping | Model Group:NLRS_01.00_verdieping type C2_gen:4731952
9132675 | 19 negentiende verdieping | Model Group:NLRS_01.00_verdieping type C2_gen:4731952
9132677 | 19 negentiende verdieping | Model Group:NLRS_01.00_verdieping type C2_gen:4731952
9132687 | 19 negentiende verdieping | Model Group:NLRS_01.00_verdieping type C2_gen:4731952
9132690 | 19 negentiende verdieping | Model Group:NLRS_01.00_verdieping type C2_gen:4731952
9132696 | 19 negentiende verdieping | Model Group:NLRS_01.00_verdieping type C2_gen:4731952
9132699 | 19 negentiende verdieping | Model Group:NLRS_01.00_verdieping type C2_gen:4731952
9132702 | 19 negentiende verdieping | Model Group:NLRS_01.00_verdieping type C2_gen:4731952
9132705 | 19 negentiende verdieping | Model Group:NLRS_01.00_verdieping type C2_gen:4731952
9132709 | 19 negentiende verdieping | Model Group:NLRS_01.00_verdieping type C2_gen:4731952
9132712 | 19 negentiende verdieping | Model Group:NLRS_01.00_verdieping type C2_gen:4731952
9132714 | 19 negentiende verdieping | Model Group:NLRS_01.00_verdieping type C2_gen:4731952
9132717 | 19 negentiende verdieping | Model Group:NLRS_01.00_verdieping type C2_gen:4731952
9133788 | 20 twintigste verdieping | Model Group:NLRS_01.00_verdieping type B2_gen:4739997
9133790 | 20 twintigste verdieping | Model Group:NLRS_01.00_verdieping type B2_gen:4739997
9133798 | 20 twintigste verdieping | Model Group:NLRS_01.00_verdieping type B2_gen:4739997
9133806 | 20 twintigste verdieping | Model Group:NLRS_01.00_verdieping type B2_gen:4739997
9133812 | 20 twintigste verdieping | Model Group:NLRS_01.00_verdieping type B2_gen:4739997
9133814 | 20 twintigste verdieping | Model Group:NLRS_01.00_verdieping type B2_gen:4739997
9133817 | 20 twintigste verdieping | Model Group:NLRS_01.00_verdieping type B2_gen:4739997
9133820 | 20 twintigste verdieping | Model Group:NLRS_01.00_verdieping type B2_gen:4739997
9133823 | 20 twintigste verdieping | Model Group:NLRS_01.00_verdieping type B2_gen:4739997
9133826 | 20 twintigste verdieping | Model Group:NLRS_01.00_verdieping type B2_gen:4739997
9133829 | 20 twintigste verdieping | Model Group:NLRS_01.00_verdieping type B2_gen:4739997
9133832 | 20 twintigste verdieping | Model Group:NLRS_01.00_verdieping type B2_gen:4739997
9133836 | 20 twintigste verdieping | Model Group:NLRS_01.00_verdieping type B2_gen:4739997
9133838 | 20 twintigste verdieping | Model Group:NLRS_01.00_verdieping type B2_gen:4739997
10782741 | 08 achtste verdieping | Model Group:NLRS_01.00_verdieping type B1_gen:4714770
10782743 | 08 achtste verdieping | Model Group:NLRS_01.00_verdieping type B1_gen:4714770
10782765 | 08 achtste verdieping | Model Group:NLRS_01.00_verdieping type B1_gen:4714770
10782767 | 08 achtste verdieping | Model Group:NLRS_01.00_verdieping type B1_gen:4714770
10782770 | 08 achtste verdieping | Model Group:NLRS_01.00_verdieping type B1_gen:4714770
10782773 | 08 achtste verdieping | Model Group:NLRS_01.00_verdieping type B1_gen:4714770
10782776 | 08 achtste verdieping | Model Group:NLRS_01.00_verdieping type B1_gen:4714770
10782779 | 08 achtste verdieping | Model Group:NLRS_01.00_verdieping type B1_gen:4714770
10782789 | 08 achtste verdieping | Model Group:NLRS_01.00_verdieping type B1_gen:4714770
10782791 | 08 achtste verdieping | Model Group:NLRS_01.00_verdieping type B1_gen:4714770
10783270 | 10 tiende verdieping | Model Group:NLRS_01.00_verdieping type B2_gen:9035827
10783273 | 10 tiende verdieping | Model Group:NLRS_01.00_verdieping type B2_gen:9035827
10783276 | 10 tiende verdieping | Model Group:NLRS_01.00_verdieping type B2_gen:9035827
10783279 | 10 tiende verdieping | Model Group:NLRS_01.00_verdieping type B2_gen:9035827
10783286 | 12 twaalfde verdieping | Model Group:NLRS_01.00_verdieping type B2_gen:4738165
10783289 | 12 twaalfde verdieping | Model Group:NLRS_01.00_verdieping type B2_gen:4738165
10783292 | 12 twaalfde verdieping | Model Group:NLRS_01.00_verdieping type B2_gen:4738165
10783295 | 12 twaalfde verdieping | Model Group:NLRS_01.00_verdieping type B2_gen:4738165
10783302 | 14 veertiende verdieping | Model Group:NLRS_01.00_verdieping type B2_gen:4738623
10783305 | 14 veertiende verdieping | Model Group:NLRS_01.00_verdieping type B2_gen:4738623
10783308 | 14 veertiende verdieping | Model Group:NLRS_01.00_verdieping type B2_gen:4738623
10783311 | 14 veertiende verdieping | Model Group:NLRS_01.00_verdieping type B2_gen:4738623
10959552 | 08 achtste verdieping | Model Group:NLRS_01.00_verdieping type B1_gen:4714770
10959555 | 08 achtste verdieping | Model Group:NLRS_01.00_verdieping type B1_gen:4714770
10959558 | 08 achtste verdieping | Model Group:NLRS_01.00_verdieping type B1_gen:4714770
10959561 | 08 achtste verdieping | Model Group:NLRS_01.00_verdieping type B1_gen:4714770
